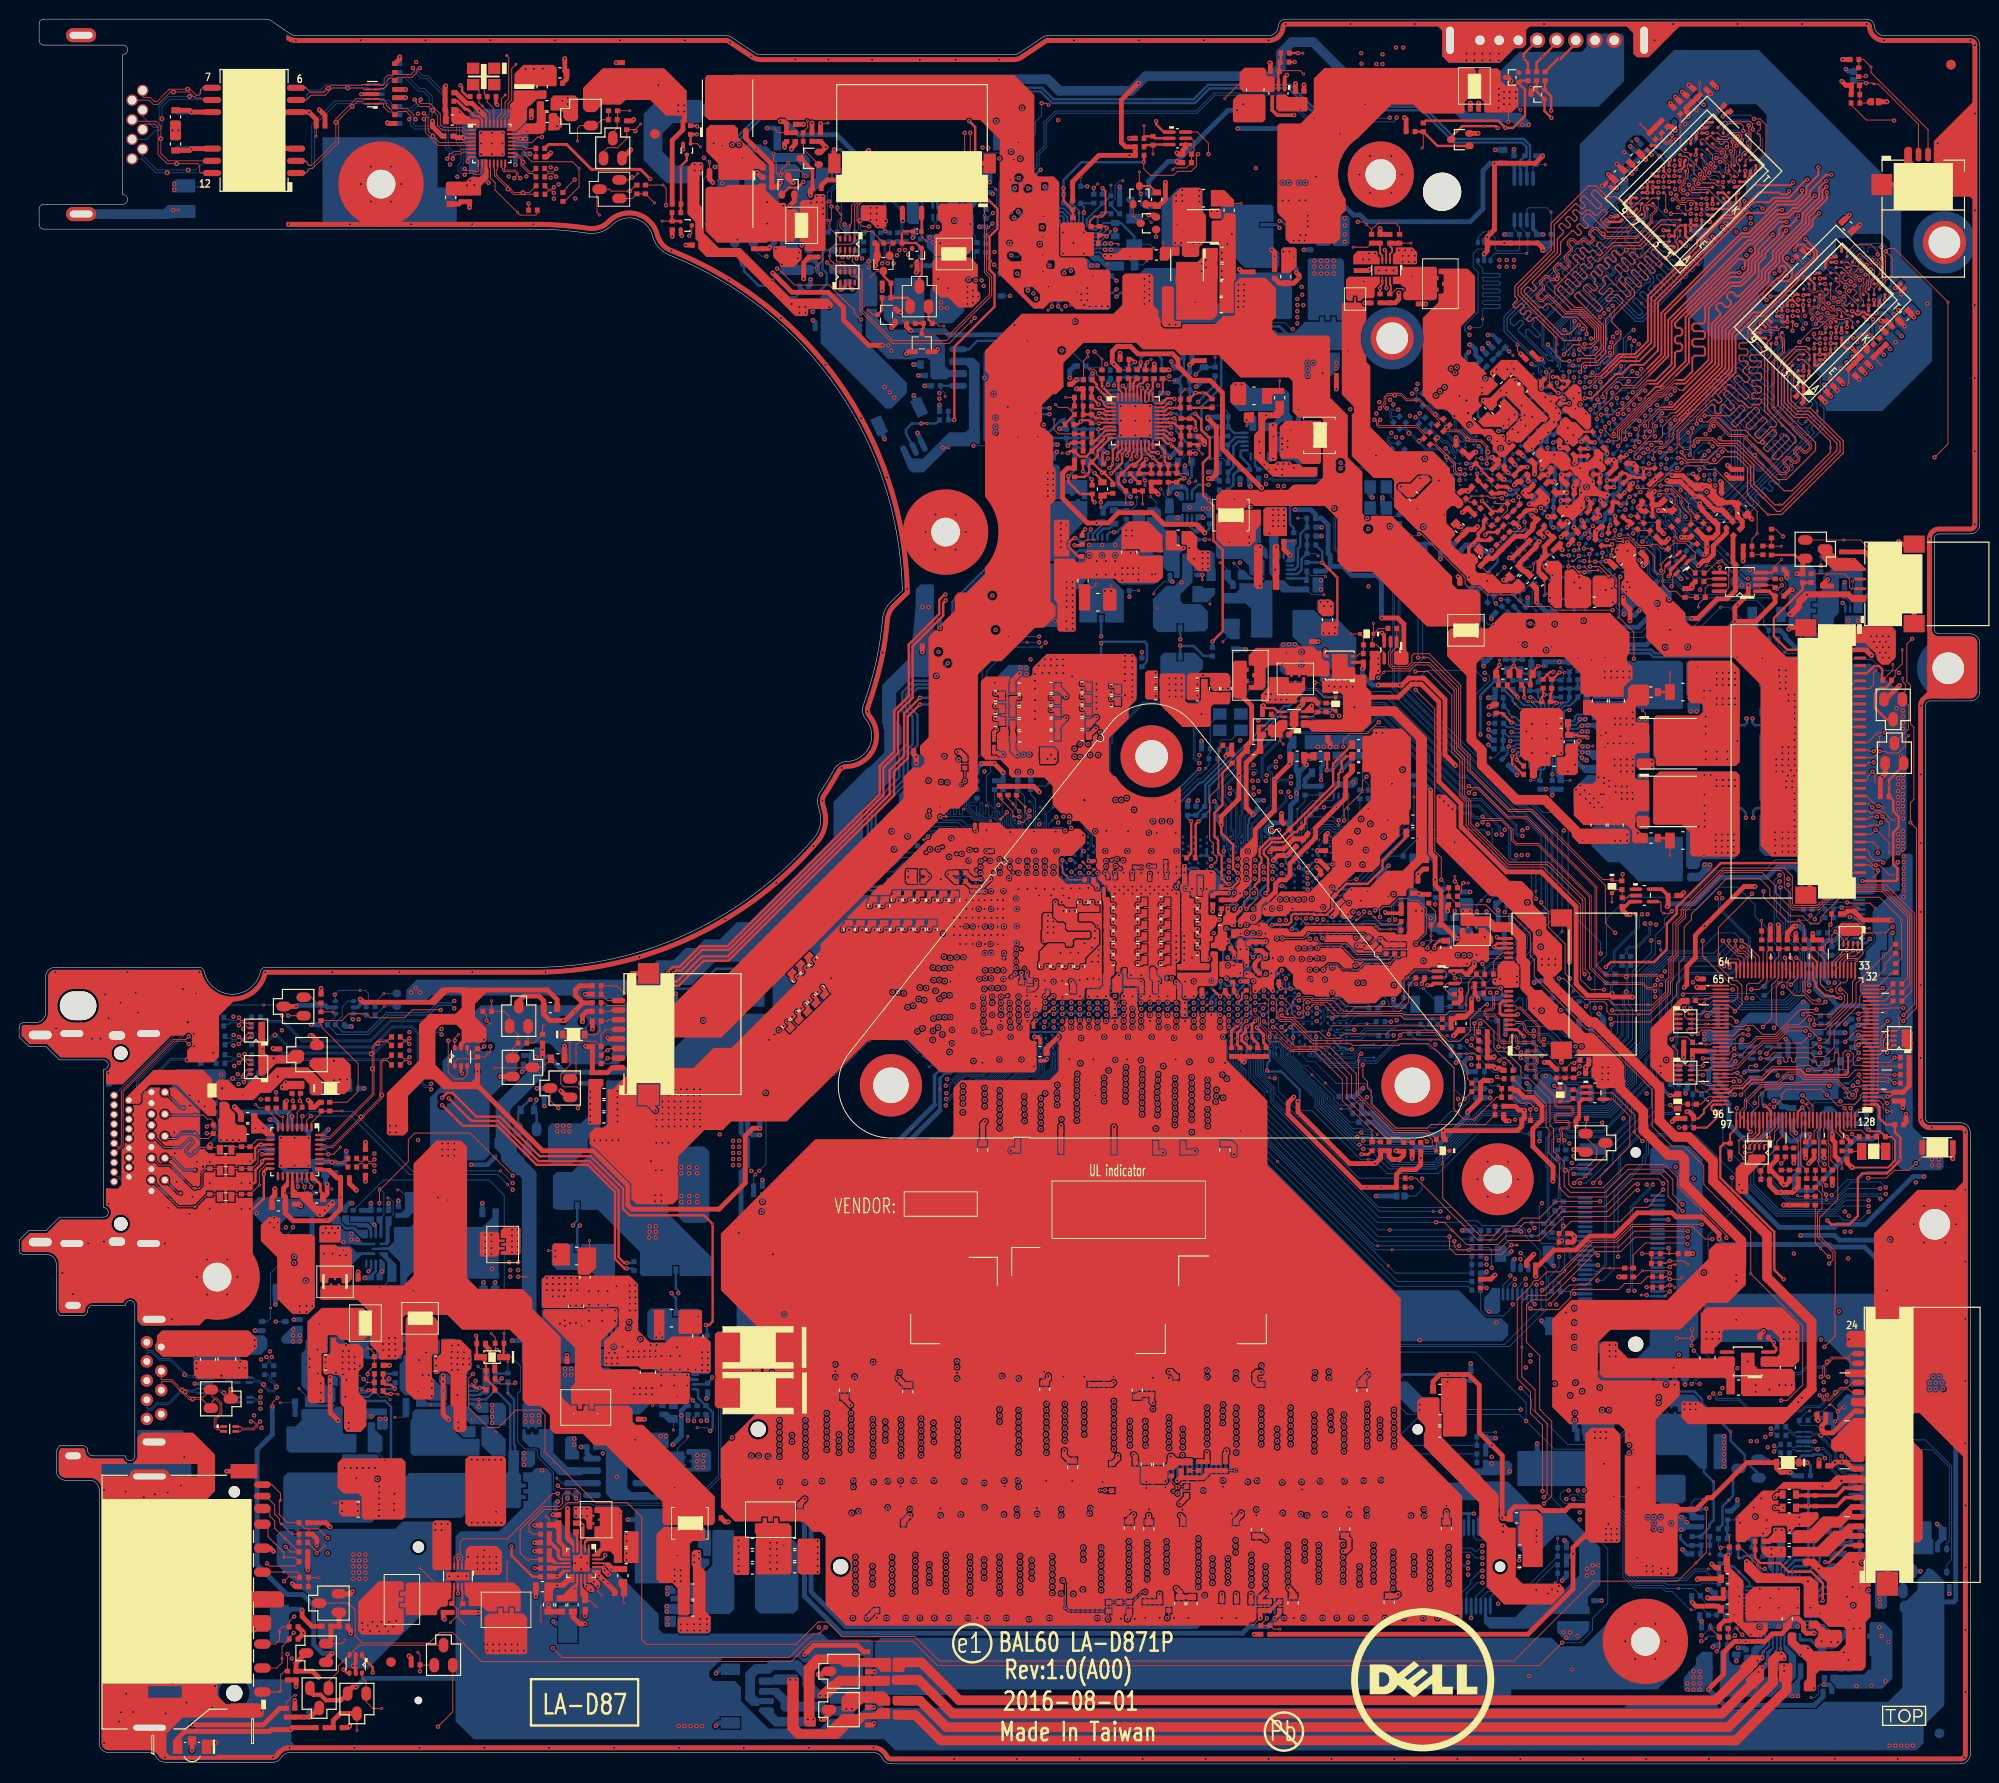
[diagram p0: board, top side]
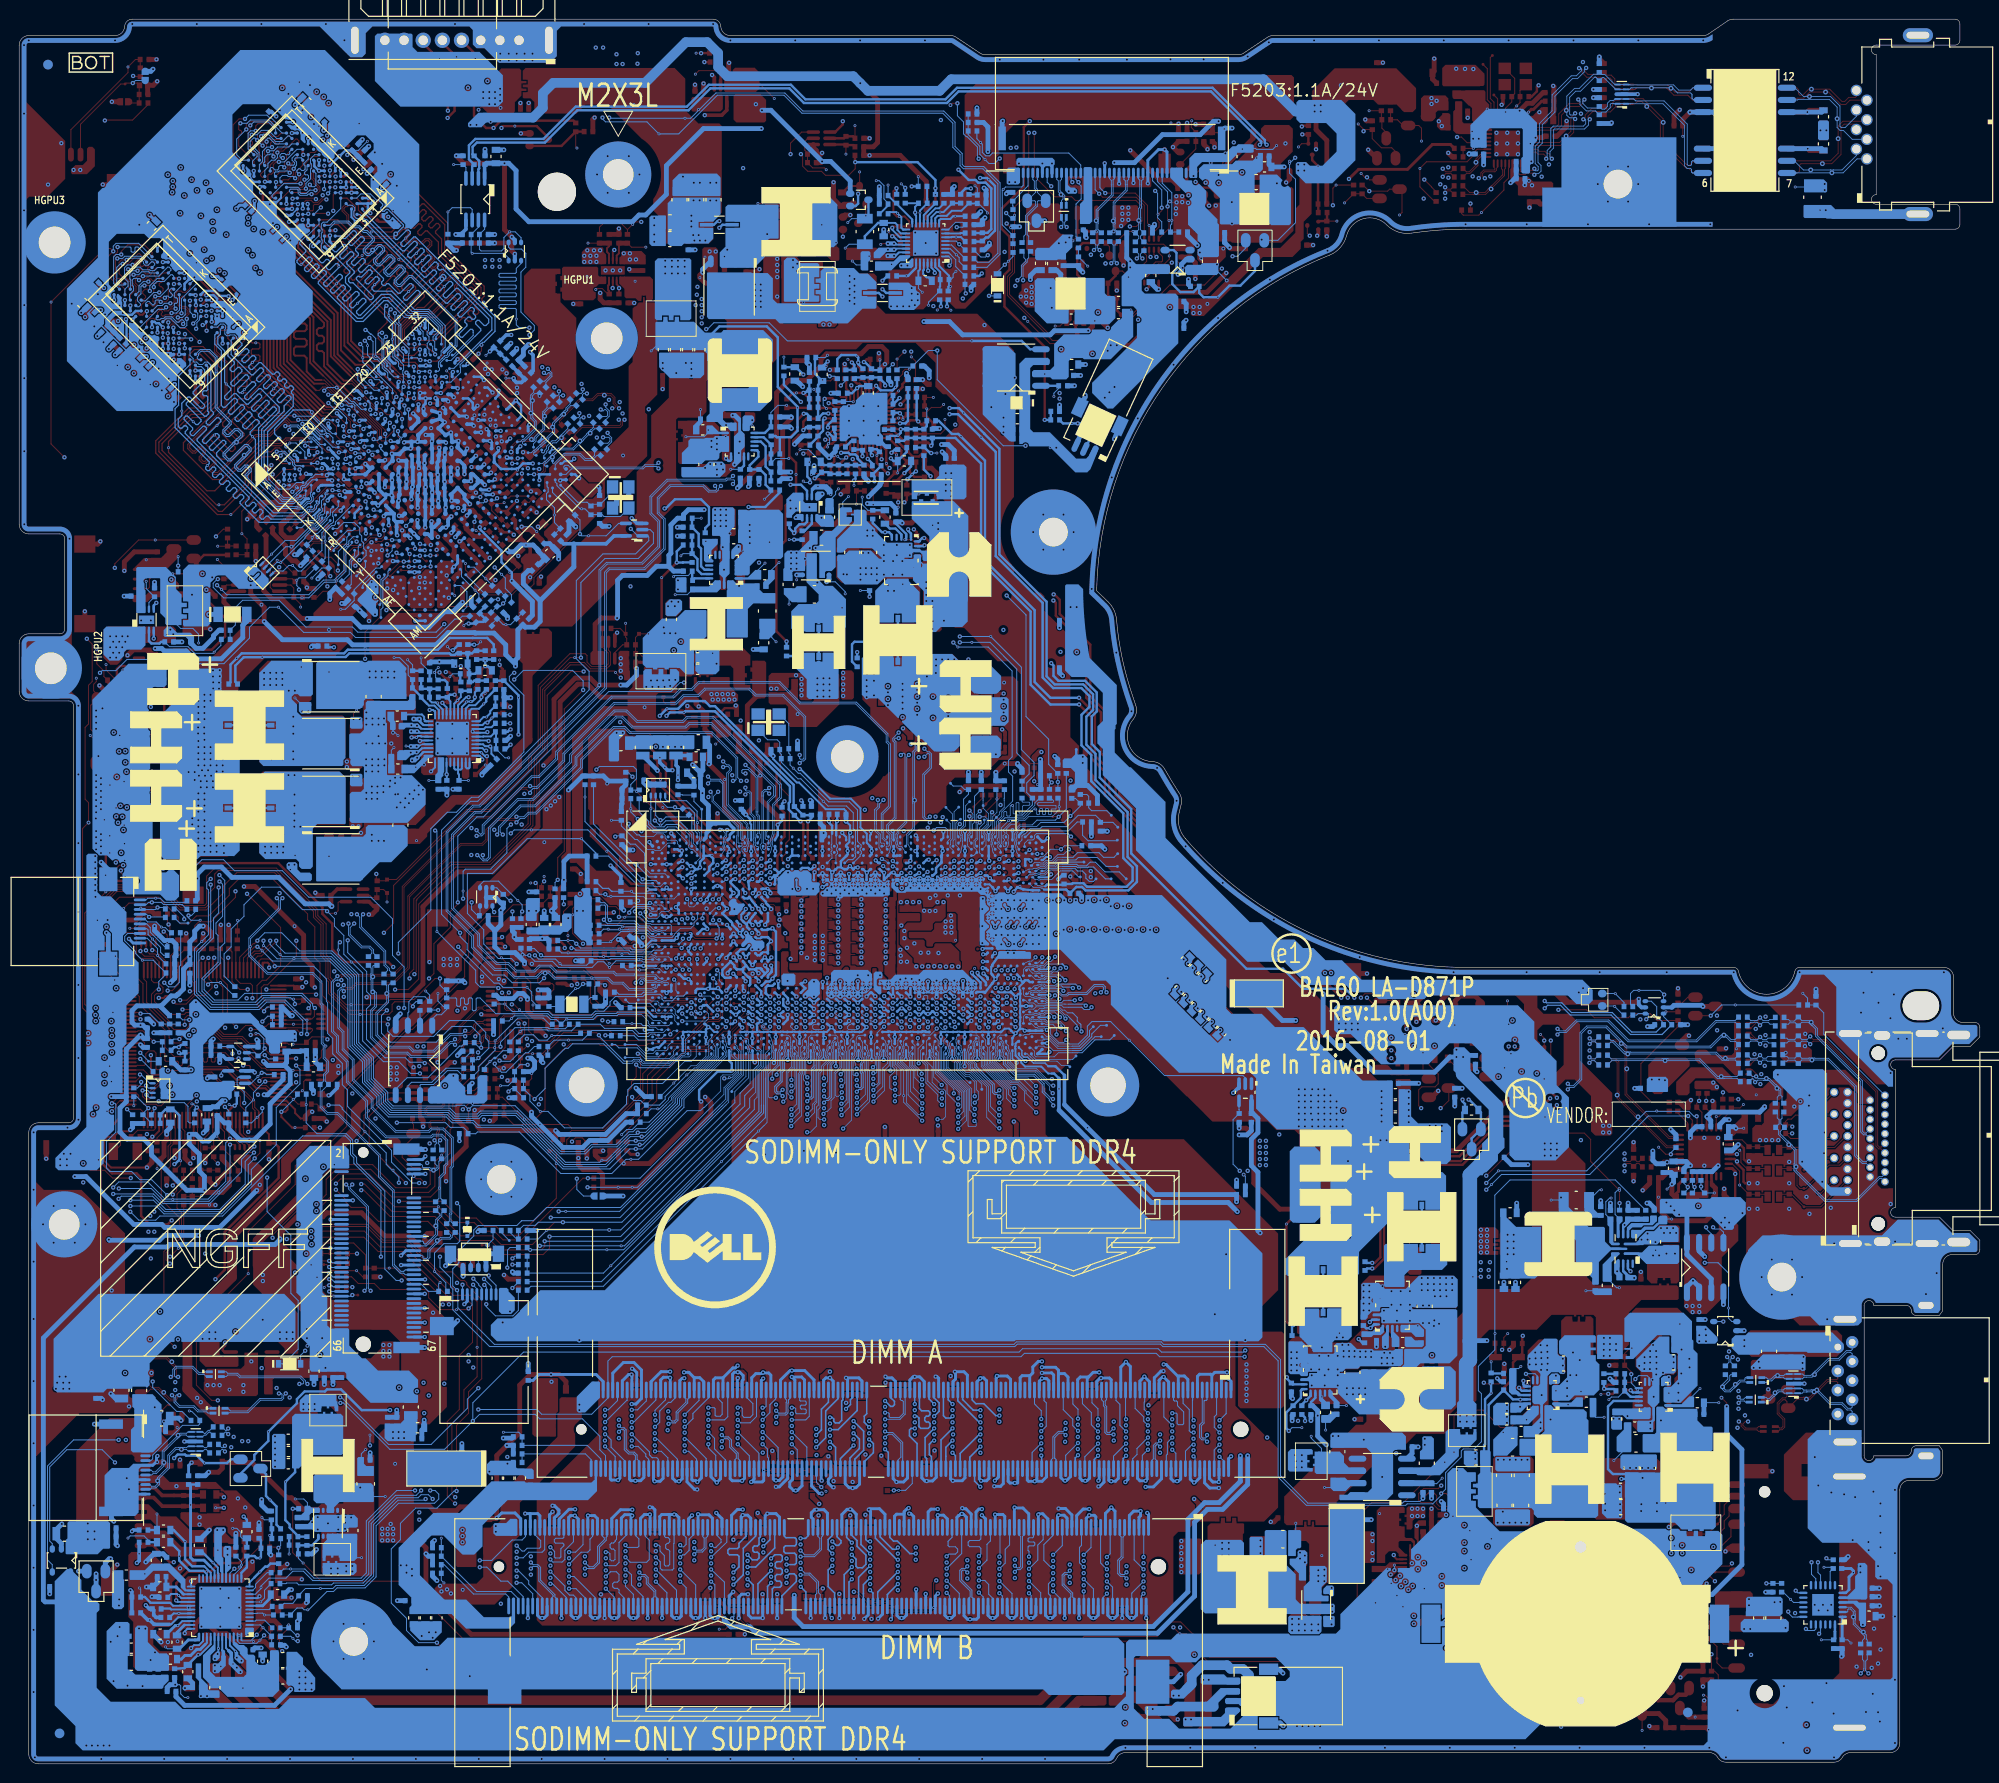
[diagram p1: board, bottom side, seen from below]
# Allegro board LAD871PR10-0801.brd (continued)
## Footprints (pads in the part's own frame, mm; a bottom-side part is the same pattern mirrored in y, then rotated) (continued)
SN74AHC1G08DCKR_SC70-5
  oval 0.381x1.295 smd: 1(0,0.15) 2(0.65,0.15) 3(1.3,0.15) 4(1.3,1.89) 5(0,1.89)
SN74LVC1G06DCKR_SC70-5
  oval 0.381x0.864 smd: 1(0,0) 2(0.65,0) 3(1.3,0) 4(1.3,1.74) 5(0,1.74)
SUYIN_200277GR008M270ZR_8P-T
  round 1.6 hole 0.991: 1(0,0) 2(2,0) 3(4,0) 4(6,0) 5(8,0) 6(10,0) 7(12,0) 8(14,0)
  oval 1.397x3.454 hole 0.787x2.845: 9(17.125,0) 10(-3.125,0)
SW_TST71-N-220-T170-S017_2P
  rect 0.61x1.499 smd: 1(0,0) 2(3.2,0)
SY6288D20AAC_SOT23-5
  oval 0.559x0.787 smd: 1(0,0) 2(0.95,0) 3(1.9,0) 4(1.9,2.4) 5(0,2.4)
SY8033BDBC_DFN10_3X3-S
  oval 0.305x0.559 smd: 1(0,0) 2(0.5,0) 3(1,0) 4(1.5,0) 5(2,0) 6(2,2.7) 7(1.5,2.7) 8(1,2.7) 9(0.5,2.7) 10(0,2.7)
  rect 2.591x1.753 smd: 11(1,1.35)
SY8286BRAC_QFN20_3X3-S
  oval 0.889x0.254 smd: 1(0,0) 2(0,-0.45) 3(0,-0.9) 4(0,-1.35) 5(0,-1.8) 11(3.1,-1.8) 12(3.1,-1.35) 13(3.1,-0.9) 14(3.1,-0.45) 15(3.1,0)
  oval 0.254x0.889 smd: 6(0.65,-2.45) 7(1.1,-2.45) 8(1.55,-2.45) 9(2,-2.45) 10(2.45,-2.45) 16(2.45,0.65) 17(2,0.65) 18(1.55,0.65) 19(1.1,0.65) 20(0.65,0.65)
  rect 0.991x0.991 smd: 21(1.55,-0.9)
SY8286CRAC_QFN20_3X3-S
  oval 0.889x0.254 smd: 1(0,0) 2(0,-0.45) 3(0,-0.9) 4(0,-1.35) 5(0,-1.8) 11(3.1,-1.8) 12(3.1,-1.35) 13(3.1,-0.9) 14(3.1,-0.45) 15(3.1,0)
  oval 0.254x0.889 smd: 6(0.65,-2.45) 7(1.1,-2.45) 8(1.55,-2.45) 9(2,-2.45) 10(2.45,-2.45) 16(2.45,0.65) 17(2,0.65) 18(1.55,0.65) 19(1.1,0.65) 20(0.65,0.65)
  rect 0.991x0.991 smd: 21(1.55,-0.9)
SY8286RAC_QFN20_3X3-S
  oval 0.889x0.254 smd: 1(0,0) 2(0,-0.45) 3(0,-0.9) 4(0,-1.35) 5(0,-1.8) 11(3.1,-1.8) 12(3.1,-1.35) 13(3.1,-0.9) 14(3.1,-0.45) 15(3.1,0)
  oval 0.254x0.889 smd: 6(0.65,-2.45) 7(1.1,-2.45) 8(1.55,-2.45) 9(2,-2.45) 10(2.45,-2.45) 16(2.45,0.65) 17(2,0.65) 18(1.55,0.65) 19(1.1,0.65) 20(0.65,0.65)
  rect 0.991x0.991 smd: 21(1.55,-0.9)
T-SOL_156-1001902605_11P
  round 1.194 hole 1.194 unplated: (-18.375,-2.925)
  round 1.702 hole 1.702 unplated: (2.625,-2.925)
  oval 0.991x1.753 smd: 1(0,0) 2(-2.5,0) 3(-5,0) 4(-7.5,0) 5(-10,0) 6(-12.5,0) 7(-15,0) 8(-16.63,0) 9(2.5,0)
  oval 0.711x1.753 smd: 10(-17.93,0) 11(-19.13,0)
  rect 1.499x2.794 smd: 12(-20.525,-1.925)
  oval 1.194x3.912 hole 0.61x3.404: 13(-19.975,-11.775) 14(6.225,-11.775)
  rect 1.473x2.794 smd: 15(4.425,-1.925)
TPC12
  round 0.305 smd: 1(0,0)
TPS2001C_MSOP8
  oval 0.381x1.575 smd: 1(0,0) 2(0.65,0) 3(1.3,0) 4(1.95,0) 5(1.95,4.33) 6(1.3,4.33) 7(0.65,4.33) 8(0,4.33)
  rect 1.803x1.397 smd: 9(0.975,2.165)
TPS22961DNYR_WSON8
  oval 0.305x0.508 smd: 1(0,0) 2(0.65,0) 3(1.3,0) 4(1.95,0) 5(1.95,2.7)
  oval 1.6x0.508 smd: 6(0.65,2.7)
  rect 2.388x1.6 smd: 7(0.975,1.35)
TPS22965DSGR_SON8_2X2
  oval 0.254x0.787 smd: 1(0,0) 2(0.5,0) 3(1,0) 4(1.5,0) 5(1.5,2.2) 6(1,2.2) 7(0.5,2.2) 8(0,2.2)
  rect 1.6x0.889 smd: 9(0.75,1.1)
TPS22966DPUR_SON14_2X3
  oval 0.203x0.762 smd: 1(0,0) 2(0.4,0) 3(0.8,0) 4(1.2,0) 5(1.6,0) 6(2,0) 7(2.4,0) 8(2.4,2.05) 9(2,2.05) 10(1.6,2.05) 11(1.2,2.05) 12(0.8,2.05) 13(0.4,2.05) 14(0,2.05)
  rect 2.489x0.889 smd: 15(1.2,1.025)
TVNST52302AB0_SOT523-3
  oval 0.508x0.559 smd: 1(0,0) 2(-0.5,-1.4) 3(0.5,-1.4)
TVWDF1004AD0_DFN9
  oval 0.203x0.686 smd: 1(0,0) 2(0.5,0) 4(1.5,0) 5(2,0) 6(2,0.875) 7(1.5,0.875) 8(0.5,0.875) 9(0,0.875)
  oval 0.406x1.549 smd: 3(1,0.437)
W25R128FVSIQ_SO8
  oval 0.635x1.676 smd: 1(0,0) 2(1.27,0) 3(2.54,0) 4(3.81,0) 5(3.81,7.25) 6(2.54,7.25) 7(1.27,7.25) 8(0,7.25)
Y_5YEA25000102IF50Q3_4P
  rect 1.295x1.194 smd: 1(0,0) 2(2.2,0) 3(2.2,1.7) 4(0,1.7)
Y_7V27000011_4P
  rect 1.397x1.194 smd: 1(0,0) 2(2.2,0) 3(2.2,1.7) 4(0,1.7)
Y_X1A000141000200_2P
  rect 0.991x1.803 smd: 1(0,0) 2(2.5,0)
Y_X3G024000DC1H_4P
  rect 1.397x1.194 smd: 1(0,0) 2(2.2,0) 3(2.2,1.7) 4(0,1.7)
ZEN_ZADH-252012MES-4R7M_2P
  rect 0.838x2.007 smd: 1(0,0) 2(1.65,0)

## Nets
0.6V_DDR_VTT_ON: PR202.1 RC124.2 UC14.4
1.2V_VTT_PWRGD: PR209.2 PU200.10 RC392.1
2.5V_VIN: PC802.1 PJP801.2 PU800.3
3V_FB: PC113.1 PR109.2 PR110.1 PU100.13
3V_SN: PC112.1 PR106.2
3V_VIN: PC100.1 PC103.1 PC104.1 PC105.1 PC130.1 PC131.1 PJP105.2 PL102.2 PU100.2 PU100.3 PU100.4 PU100.5
5V_FB: PC127.1 PR115.2 PR118.1 PU102.13
5V_HDD_S0: AFTP5601.1(TP-1) C5605.1 C5606.1 HDD1.1 HDD1.2 HDD1.3 R5601.2
5V_HDMI_CRT_S0_R: AFTP5504.1(TP-1) C5401.1 C5519.1 F5501.1 JCRT.9 JHDMI.18 RE45.2 RE46.2
5V_SN: PC125.1 PR112.2
5V_VIN: PC115.1 PC116.1 PC117.1 PC118.1 PC132.1 PC133.1 PJP106.2 PL103.2 PU102.2 PU102.3 PU102.4 PU102.5
+0.6V_DDR_VTT: CD12.1 CD13.1 CD14.1 CD15.1 CD32.1 CD88.1 CD89.1 CD90.1 JDIMM1.258 JDIMM2.258 PJP203.1
+0.6VSP: PC205.1 PC211.1 PJP203.2 PU200.2 PU200.20
+0.95VSDGPU: J11.2 LV8.1 RC364.1 RV1.2 RV3.2 RV30.2 RV31.1
+0.95VSDGPU_ON: C983.2 R6510.2 U15.3
+0.95VSDGPU_OUT: C6216.1 J11.1 U15.13 U15.14
+1.0V_AMPHYPLL: CC219.1 CC264.1 RC169.2 UC1.K15 UC1.L15
+1.0V_APLL: CC225.1 RC172.2 UC1.V15
+1.0V_APLLEBB: CC218.1 RC310.2 UC1.N18
+1.0V_CLK2: CC220.1 RC170.2 UC1.K19
+1.0V_CLK4: CC226.1 RC173.2 UC1.N20
+1.0V_CLK5: CC221.1 RC52.2 RC171.2 UC1.L19
+1.0V_MPHYGT: CC210.1 CC211.1 CC281.1 RC169.1 RC309.1 RC310.1 RC368.2 UC1.N15 UC1.N16 UC1.N17 UC1.P15 UC1.P16
+1.0V_PRIM: CC203.1 CC205.1 CC206.1 CC216.1 CC273.1 CC1801.1 CE77.1 CZ87.1 PJP302.2 RC170.1 RC171.1 RC172.1 RC173.1 RC352.1 RC368.1 U15.1 U15.2 UC1.A10 UC1.A14 UC1.AB17 UC1.AB19 UC1.AB20 UC1.AF18 UC1.AF19 UC1.AK20 UC1.K17 UC1.L1 UC1.L21 UC1.P18 UC1.T1 UC1.V20 UC1.V21 UC1.Y18 UE1.95 UZ19.1 UZ19.2 UZ19.7 UZ21.1 UZ21.2
+1.0V_SRAM: CC217.1 RC309.2 UC1.AF20 UC1.AF21 UC1.T19 UC1.T20
+1.0V_VCCST: CC195.1 CC202.1 PC602.1 PJP27.1 PR601.1 PR604.1 PR605.1 RC71.2 RC79.1 RC80.1 RC120.2 RC152.1 RC157.1 RC238.2 UC1.A18 UC1.K20 UC1.K21
+1.0V_VCCST_C: CZ78.1 PJP27.2 UZ21.7 UZ21.8
+1.0V_VCCSTG: CC199.1 PJP32.1 RC83.1 RC238.1 RC349.2 RC350.2 RC351.2 UC1.A22 UC1.G20
+1.0V_VCCSTG_C: CZ82.1 PJP15.1 PJP32.2 UZ19.6
+1.0V_XDP: RC115.2 RC352.2 RC353.1
+1.0VS_VCCIO: CC181.1 CC182.1 CC185.1 CC186.1 CC248.1 CC249.1 CC250.1 CC251.1 CC252.1 CC253.1 CZ1701.1 PJP15.2 RC2.1 UC1.AK28 UC1.AK30 UC1.AL30 UC1.AL42 UC1.AM28 UC1.AM30 UC1.AM42
+1.0VS_VCCOPC: CC180.1 CC183.1 CC184.1 CC187.1 CC288.1 CC289.1 CC290.1 CC291.1 CC292.1 PJP1202.2 UC1.AB62 UC1.AE62 UC1.AG62 UC1.P62 UC1.V62
+1.0VS_VCCOPCP: PC1206.1 PC1207.1 PC1208.1 PJP1202.1 PL1201.2 PU1200.12
+1.2V_DDR: CC58.1 CC174.1 CC175.1 CC176.1 CC177.1 CC178.1 CC179.1 CC194.1 CC255.1 CC256.1 CC257.1 CC293.1 CC294.1 CC295.1 CC296.1 CC297.1 CD1.1 CD2.1 CD5.1 CD6.1 CD7.1 CD8.1 CD11.1 CD19.1 CD20.1 CD21.1 CD22.1 CD23.1 CD24.1 CD25.1 CD26.1 CD33.1 CD70.1 CD71.1 CD72.1 CD73.1 CD74.1 CD75.1 CD76.1 CD77.1 CD78.1 CD79.1 CD80.1 CD81.1 CD82.1 CD83.1 CD84.1 CD85.1 CD86.1 CD87.1 JDIMM1.12 JDIMM1.33 JDIMM1.54 JDIMM1.75 JDIMM1.96 JDIMM1.111 JDIMM1.112 JDIMM1.117 JDIMM1.118 JDIMM1.123 JDIMM1.124 JDIMM1.129 JDIMM1.130 JDIMM1.135 JDIMM1.136 JDIMM1.141 JDIMM1.142 JDIMM1.147 JDIMM1.148 JDIMM1.153 JDIMM1.154 JDIMM1.159 JDIMM1.160 JDIMM1.163 JDIMM1.178 JDIMM1.199 JDIMM1.220 JDIMM1.241 JDIMM2.12 JDIMM2.33 JDIMM2.54 JDIMM2.75 JDIMM2.111 JDIMM2.112 JDIMM2.117 JDIMM2.118 JDIMM2.123 JDIMM2.124 JDIMM2.129 JDIMM2.130 JDIMM2.135 JDIMM2.136 JDIMM2.141 JDIMM2.142 JDIMM2.147 JDIMM2.148 JDIMM2.153 JDIMM2.154 JDIMM2.159 JDIMM2.160 JDIMM2.163 JDIMM2.178 JDIMM2.199 JDIMM2.220 JDIMM2.241 PJP200.2 RD7.2 RD8.2 RD35.1 RH206.1 RH207.1 UC1.AL23 UC1.AM40 UC1.AU23 UC1.AU28 UC1.AU35 UC1.AU42 UC1.BB23 UC1.BB32 UC1.BB41 UC1.BB47 UC1.BB51 UC14.5
+1.2VP: PC213.1 PC214.2 PC215.1 PC216.1 PC217.1 PC218.1 PC219.1 PC220.1 PJP200.1 PL200.1 PR207.2 PU200.5 PU200.19
+1.5V_MEM_GFX: CV16.1 CV40.1 CV41.1 CV42.1 CV43.1 CV44.1 CV45.1 CV47.1 CV48.1 CV49.1 CV50.1 CV51.1 CV52.1 CV53.1 CV131.1 CV133.1 CV143.1 CV151.1 CV170.1 CV171.1 CV174.1 CV175.1 CV176.1 CV177.1 CV178.1 CV182.1 CV183.1 CV184.1 CV185.1 CV186.1 CV187.1 CV188.1 CV196.1 CV198.1 CV208.1 CV210.1 CV211.1 CV212.1 CV394.1 CV395.1 CV396.1 CV397.1 CV398.1 CV400.1 CV401.1 CV402.1 PJP1402.2 RV32.1 RV33.1 RV139.1 RV144.1 RV149.1 RV150.1 UV1.H13 UV1.H16 UV1.H19 UV1.J9 UV1.J10 UV1.J23 UV1.J24 UV1.K9 UV1.K10 UV1.K23 UV1.K24 UV1.L11 UV1.L12 UV1.L13 UV1.L20 UV1.L21 UV1.L22 UV17.A1 UV17.A8 UV17.B2 UV17.C1 UV17.C9 UV17.D2 UV17.D9 UV17.E9 UV17.F1 UV17.G7 UV17.H2 UV17.H9 UV17.K2 UV17.K8 UV17.N1 UV17.N9 UV17.R1 UV17.R9 UV18.A1 UV18.A8 UV18.B2 UV18.C1 UV18.C9 UV18.D2 UV18.D9 UV18.E9 UV18.F1 UV18.G7 UV18.H2 UV18.H9 UV18.K2 UV18.K8 UV18.N1 UV18.N9 UV18.R1 UV18.R9 UV19.A1 UV19.A8 UV19.B2 UV19.C1 UV19.C9 UV19.D2 UV19.D9 UV19.E9 UV19.F1 UV19.G7 UV19.H2 UV19.H9 UV19.K2 UV19.K8 UV19.N1 UV19.N9 UV19.R1 UV19.R9 UV20.A1 UV20.A8 UV20.B2 UV20.C1 UV20.C9 UV20.D2 UV20.D9 UV20.E9 UV20.F1 UV20.G7 UV20.H2 UV20.H9 UV20.K2 UV20.K8 UV20.N1 UV20.N9 UV20.R1 UV20.R9
+1.5VGPUP: PC1409.1 PC1411.1 PC1412.1 PC1413.1 PC1414.1 PJP1402.1 PL1401.2 PR1410.2
+1.8V_AVDD: C2715.1 HDA27.40 R6511.2
+1.8V_PRIM: C24.2 CC212.1 CC272.1 PJP502.2 Q6205.1 RC361.1 U15.6 U15.7 UC1.AA1 UC1.AF16 UC1.G61 UC1.H63
+1.8VALWP: PC503.1 PC505.1 PC506.1 PC507.1 PJP502.1 PL501.2 PR503.2
+1.8VGS: CV38.1 CV39.1 CV46.1 CV179.1 J10.2 LV2.1 LV3.1 LV6.1 LV7.1 PR1113.1 RV8.1 RV11.1 RV15.1 RV27.2 RV28.1 RV71.1 RV81.2 RV82.2 RV152.2 UV1.AM30
+1.8VGS_GPU_ON: C987.2 R437.2 U15.5
+1.8VGS_OUT: C26.2 J10.1 U15.8 U15.9
+1VALWP: PC309.1 PC310.1 PC311.1 PC312.1 PC313.1 PJP302.1 PL301.2 PR309.2
+2.5V_MEM: CD3.1 CD4.1 CD9.1 CD10.1 CD27.1 CD28.1 CD30.1 CD31.1 JDIMM1.257 JDIMM1.259 JDIMM2.257 JDIMM2.259 PJP802.2
+2.5VP: PC803.1 PC804.1 PJP802.1 PR801.1 PU800.6
+3.3V_ALW_DSW: CC279.1 CC280.1 RC70.1 RC72.2 RC214.2 RC243.2 RC1102.1 UC1.AD17 UC1.AD18 UC1.AJ17
+3.3V_HDA: CC215.1 RC396.2 UC1.AJ19
+3.3V_LAN_UZ2: CZ50.1 PJP13.1 UZ2.8 UZ2.9
+3.3V_SPI: CC9.1 RC9.1 RC30.1 RC31.1 RC213.2 RC339.1 UC1.AJ16 UC5.8
+3.3V_WLAN: C5803.1 C5804.1 C5806.1 R5809.2 R5810.2 WLAN1.2 WLAN1.4 WLAN1.64 WLAN1.66
+3V_1.8V_CPVDD: C6213.1 C6215.1 HDA27.36 R2705.2
+3V_DVDD: C2701.1 C2716.1 C2717.1 C2719.1 C6214.1 HDA27.1 HDA27.9 R2701.2 R2722.1 R6512.1
+3VALW: C3013.1 C3015.1 CC271.1 CC298.1 CC299.1 CZ34.1 D2502.2 EC9759.1 EC9760.1 PC1205.1 PC1422.1 PJP23.1 PJP102.2 PJP501.1 PJP801.1 PR3.2 PR16.2 PR28.1 PR209.1 PR303.1 PR304.1 PR756.2 PR791.1 PR1405.1 PR1406.1 PU1200.10 PWR1.1 Q3004.3 QC4.2 QC4.5 R2608.1 R2713.2 R3021.1 R5810.1 R6215.1 RC68.2 RC73.2 RC214.1 RE25.1 RE71.1 RE72.1 RE73.1 RE74.1 RE75.1 RE343.2 RE385.2 RE388.2 RE389.2 RE396.1 RE404.1 RE408.2 RE409.2 RPE2.5 RPE2.6 RPE2.7 RPE2.8 RPE3.5 RPE3.6 RPE3.7 RPE3.8 RPE4.1 RPE4.2 RPE4.3 RPE4.4 RPE5.1 RPE5.2 RPE5.3 RPE5.4 RPE6.1 RPE6.2 RPE6.3 RPE6.4 RPE7.1 RPE7.2 RPE7.3 RPE7.4 UC15.5 UC16.5 UC17.5 UZ2.6 UZ2.7 UZ6.5
+3VALW_EC: CE62.1 CE63.2 CE64.2 CE65.1 CE66.1 CE67.1 CE68.1 CE69.1 CE79.1 CE81.1 CE89.1 R2446.1 RE343.1 RE345.1 RE348.2 RE354.1 RE424.2 RE425.2 RE426.2 RE427.2 RE440.2 UE1.5 UE1.19 UE1.22 UE1.43 UE1.65 UE1.82 UE1.103 UE1.115
+3VALW_PCH: CC207.1 CC208.1 CC209.1 CC223.1 CC224.1 CC265.1 PJP23.2 RC12.2 RC14.2 RC15.2 RC17.2 RC19.2 RC20.2 RC23.2 RC25.2 RC74.1 RC183.1 RC186.1 RC187.1 RC213.1 RC239.1 RC246.2 RC288.2 RC365.2 RC369.2 RC384.2 RC387.2 RC396.1 RPC3.5 RPC3.6 RPC3.7 RPC3.8 UC1.AD15 UC1.AG15 UC1.AJ21 UC1.AK15 UC1.AK17 UC1.T16 UC1.V19 UC1.Y15 UC1.Y16
+3VALWP: PC106.1 PC107.1 PC108.1 PC109.1 PC110.1 PJP102.1 PL100.2 PR107.1 PR108.2 PR109.1 PR113.1 PU100.14
+3VGS: CV10.1 J12.2 LV4.1 PR1115.1 QV1.2 QV1.5 RP34.1 RP34.3 RP34.4 RV5.1 RV6.1 RV58.2 RV72.2 RV91.2 RV146.1 RV154.1 RV162.1 RV260.2 UV2.5 UV11.1
+3VGS_GPU_ON: C6211.2 RZ79.2 U5602.3
+3VGS_OUT: C6217.1 J12.1 U5602.7 U5602.8
+3VLP: D2501.2 PC111.1 PU100.16 PU100.17 R2609.1 RE356.2
+3VS: C2601.1 C2602.1 C3203.1 C3205.1 C5204.1 C5520.1 C5522.1 C5801.1 C5802.1 C5805.1 CD16.1 CD17.1 CD34.1 CD35.1 CE85.1 DB1.9 DB1.10 EC9735.1 EC9736.1 JDIMM1.255 JDIMM2.255 PC1422.2 PC1423.1 PC1424.1 PJP13.2 PR612.1 PR1112.1 PR1119.1 PR1206.1 PR1401.1 Q2601.2 Q2601.5 Q5401.1 Q5402.2 Q5402.5 Q6205.2 Q6206.2 Q6501.2 Q6501.5 QC2.2 QC2.5 R2603.1 R2604.1 R2701.1 R5208.1 R5219.2 R5229.1 R5231.1 R5502.2 R5503.1 R5504.1 R5509.2 R5515.2 R5607.1 R5809.1 R6110.1 R6202.1 R6212.1 R6507.1 R6518.1 RC13.1 RC21.1 RC27.2 RC47.1 RC50.1 RC62.2 RC63.2 RC124.1 RC175.2 RC178.2 RC181.1 RC189.1 RC237.2 RC245.1 RC248.2 RC267.1 RC272.1 RC277.1 RC291.1 RC292.1 RC293.1 RC356.1 RC359.1 RC360.1 RC374.1 RC376.1 RC378.1 RC379.1 RC382.2 RC388.2 RD1.1 RD2.1 RD3.1 RD4.1 RD5.1 RD6.1 RE32.1 RE432.1 RE439.2 RE441.2 RN19.1 RN20.1 RZ20.1 RZ21.1 THM26.1 U3201.4 U5201.5 U5502.5 U5502.20 U5504.3 U5504.8 U5602.1 U5602.2 UC7.5 UE6.5
+5V_AVDD: C2710.1 C2711.1 HDA27.26 R2703.1
+5V_KB_BL: C6202.1 EC6208.1 F6201.1 KB_BL1.1
+5V_PVDD: C2706.1 C2707.1 C2708.1 C2709.1 HDA27.41 HDA27.46 R2702.2 R2704.2
+5V_RUN_UZ2: CZ44.1 PJP21.2 UZ2.13 UZ2.14
+5VALW: C3504.1 C3510.1 CZ86.1 EC9732.1 EC9733.1 JWDB1.4 PC661.1 PC669.1 PC677.1 PC685.1 PC801.1 PC1111.1 PD5.3 PD6.3 PJP103.2 PR8.1 PR206.1 PR210.2 PR602.2 PR615.1 PR634.1 PR1114.2 PU603.2 PU604.2 PU605.2 PU606.6 PU800.4 PU1100.26 PU1100.31 Q6101.3 Q6102.3 U15.4 U3504.5 U3505.5 U5602.4 UZ2.1 UZ2.2 UZ2.4 UZ19.3 UZ21.4
+5VALWP: PC120.1 PC121.1 PC122.1 PC123.1 PC124.1 PJP103.1 PL101.2 PR115.1 PR117.2 PU102.14
+5VS: C2605.1 C2611.1 C5601.1 C5604.1 C5609.1 D5401.1 D5501.2 EC9719.1 EC9720.1 F6201.2 FAN261.2 PJP21.1 Q5403.2 Q6201.3 R2702.1 R2703.2 R2704.1 R5230.1 R5413.1 R5601.1 R5603.1 U5601.2 U5601.3
+17.4V_BATT+: PC7.1 PC761.1 PC766.1 PC775.1 PC776.1 PC777.1 PC778.1 PJP3.2 PL3.1 PQ710.3 PR745.2 PR765.4 PR780.2
+17.4V_BATT++: PBATT1.7 PBATT1.8 PC8.1 PJP3.1 PL3.2
+19V_ADPIN: PC1.1 PC2.1 PJP1.2 PJPDC1.5 PJPDC1.6 PL1.1
+19V_VIN: PC3.1 PC4.1 PC742.2 PD704.2 PJP1.1 PL1.2 PQ740.5 PR5.1 PR7.2 PR31.2 PR729.1
+19VB: EC9701.1 EC9702.1 EC9703.1 EC9705.1 EC9706.1 EC9708.1 EC9709.1 EC9710.1 EC9712.1 EC9713.1 EC9714.1 EC9715.1 EC9716.1 EC9717.1 F5201.1 PJP105.1 PJP106.1 PJP206.2 PJP301.1 PJP601.2 PJP602.2 PJP701.1 PJP1101.1 PJP1201.1 PJP1401.1 PL102.1 PL103.1 PL201.1 PL302.1 PL602.2 PL606.2 PL704.1 PL1101.2 PL1202.1 PL1402.1 PQ717.5 PR102.2 PR703.4 R5214.1
+19VB_1.2V: PC201.1 PC206.1 PC208.1 PC212.1 PC230.1 PC231.1 PJP206.1 PL201.2 PQ201.2 PQ201.3 PQ201.4 PQ201.10 PR208.1
+19VB_+1.5VGPU: PC1401.1 PC1402.1 PC1403.1 PC1420.1 PC1421.1 PJP1401.2 PL1402.2 PU1400.2 PU1400.3 PU1400.4 PU1400.5
+19VB_+1VALW: PC301.1 PC302.1 PC303.1 PC320.1 PC321.1 PJP301.2 PL302.2 PU300.2 PU300.3 PU300.4 PU300.5
+19VB_GPU: PC1103.1 PC1104.1 PC1105.1 PC1106.1 PC1107.1 PC1112.1 PC1113.1 PC1114.1 PC1115.1 PC1116.1 PC1190.1 PC1191.1 PC1192.1 PC1193.1 PJP1101.2 PL1101.1 PQ1101.5 PQ1104.5
+VCC_CORE: PC1001.1 PC1002.1 PC1003.1 PC1004.1 PC1005.1 PC1006.1 PC1007.1 PC1008.1 PC1009.1 PC1010.1 PC1011.1 PC1012.1 PC1013.1 PC1030.1 PC1031.1 PC1032.1 PC1033.1 PC1034.1 PC1035.1 PC1036.1 PC1037.1 PC1038.1 PC1039.1 PC1050.1 PC1051.1 PC1052.1 PC1053.1 PC1054.1 PC1061.1 PC1062.1 PC1064.1 PC1065.1 PC1066.1 PC1067.1 PC1068.1 PC1069.1 PC1070.1 PC1071.1 PC1072.1 PC1073.1 PC1074.1 PC1075.1 PC1076.1 PC1077.1 PC1078.1 PC1079.1 PC1080.1 PC1081.1 PC1082.1 PC1083.1 PC1084.1 PC1085.1 PC1086.1 PC1087.1 PC1088.1 PC1089.1 PC1090.1 PC1091.1 PC1092.1 PC1093.1 PC1094.1 PC1095.1 PC1096.1 PC1097.1 PC1098.1 PC1099.1 PC1125.1 PC1126.1 PC1127.1 PC1164.1 PC1170.1 PC1171.1 PC1172.1 PC1173.1 PC1174.1 PL603.1 RC140.1 UC1.A30 UC1.A34 UC1.A39 UC1.A44 UC1.AK33 UC1.AK35 UC1.AK37 UC1.AK38 UC1.AK40 UC1.AL33 UC1.AL37 UC1.AL40 UC1.AM32 UC1.AM33 UC1.AM35 UC1.AM37 UC1.AM38 UC1.G30 UC1.G32 UC1.G33 UC1.G35 UC1.G37 UC1.G38 UC1.G40 UC1.G42 UC1.J30 UC1.J33 UC1.J37 UC1.J40 UC1.K33 UC1.K35 UC1.K37 UC1.K38 UC1.K40 UC1.K42 UC1.K43
+VCC_CORE_G0: T122.1(TP-1) UC1.K32
+VCC_CORE_G1: T123.1(TP-1) UC1.AK32
+VCC_GT: PC1014.1 PC1015.1 PC1016.1 PC1017.1 PC1018.1 PC1019.1 PC1020.1 PC1021.1 PC1022.1 PC1023.1 PC1024.1 PC1025.1 PC1026.1 PC1027.1 PC1028.1 PC1029.1 PC1040.1 PC1041.1 PC1042.1 PC1043.1 PC1044.1 PC1045.1 PC1046.1 PC1047.1 PC1048.1 PC1049.1 PC1055.1 PC1056.1 PC1063.1 PC1101.1 PC1128.1 PC1129.1 PC1130.1 PC1131.1 PC1132.1 PC1133.1 PC1134.1 PC1135.1 PC1136.1 PC1137.1 PC1138.1 PC1154.1 PC1155.1 PC1156.1 PC1158.1 PC1159.1 PC1161.1 PC1162.1 PC1163.1 PC1175.1 PC1176.1 PC1177.1 PC1178.1 PC1179.1 PC1180.1 PC1181.1 PC1182.1 PC1183.1 PC1184.1 PC1221.1 PC1222.1 PC1223.1 PC1224.1 PC1423.2 PL604.1 PL605.1 RC161.1 RC340.1 UC1.A48 UC1.A53 UC1.A58 UC1.A62 UC1.A66 UC1.AA63 UC1.AA64 UC1.AA66 UC1.AA67 UC1.AA69 UC1.AA70 UC1.AA71 UC1.AC64 UC1.AC65 UC1.AC66 UC1.AC67 UC1.AC68 UC1.AC69 UC1.AC70 UC1.AC71 UC1.AK42 UC1.AK43 UC1.AK45 UC1.AK46 UC1.AK48 UC1.AK50 UC1.AK52 UC1.AK53 UC1.AK55 UC1.AK56 UC1.AK58 UC1.AK60 UC1.AK70 UC1.AL43 UC1.AL46 UC1.AL50 UC1.AL53 UC1.AL56 UC1.AL60 UC1.AM48 UC1.AM50 UC1.AM52 UC1.AM53 UC1.AM56 UC1.AM58 UC1.AU58 UC1.AU63 UC1.BB57 UC1.BB66 UC1.J43 UC1.J45 UC1.J46 UC1.J48 UC1.J50 UC1.J52 UC1.J53 UC1.J55 UC1.J56 UC1.J58 UC1.J60 UC1.K48 UC1.K50 UC1.K52 UC1.K53 UC1.K55 UC1.K56 UC1.K58 UC1.K60 UC1.L62 UC1.L63 UC1.L64 UC1.L65 UC1.L66 UC1.L67 UC1.L68 UC1.L69 UC1.L70 UC1.L71 UC1.M62 UC1.N63 UC1.N64 UC1.N66 UC1.N67 UC1.N69 UC1.N70 UC1.N71 UC1.R63 UC1.R64 UC1.R65 UC1.R66 UC1.R67 UC1.R68 UC1.R69 UC1.R70 UC1.R71 UC1.T62 UC1.U65 UC1.U68 UC1.U71 UC1.W63 UC1.W64 UC1.W65 UC1.W66 UC1.W67 UC1.W68 UC1.W69 UC1.W70 UC1.W71 UC1.Y62
+VCC_SA: PC1057.1 PC1058.1 PC1059.1 PC1060.1 PC1139.1 PC1140.1 PC1141.1 PC1142.1 PC1143.1 PC1144.1 PC1145.1 PC1146.1 PC1147.1 PC1148.1 PC1149.1 PC1150.1 PC1151.1 PC1152.1 PC1153.1 PL601.1 RC168.1 UC1.AK23 UC1.AK25 UC1.G23 UC1.G25 UC1.G27 UC1.G28 UC1.J22 UC1.J23 UC1.J27 UC1.K23 UC1.K25 UC1.K27 UC1.K28 UC1.K30
+VDD_CT: CV61.1 CV62.1 CV63.1 LV3.2 UV1.AA20 UV1.AA21 UV1.AB20 UV1.AB21
+VDDR3: CV64.1 CV65.1 CV66.1 CV123.1 LV4.2 UV1.AA17 UV1.AA18 UV1.AB17 UV1.AB18
AVCC33: C5517.1 C5523.2 R5504.2 U5502.24
GND: AFTP6235.1(TP-1) C24.1 C26.1 C343.1 C349.1 C983.1 C987.1 C2503.2 C2601.2 C2602.2 C2603.2 C2604.2 C2605.2 C2608.2 C2609.2 C2611.2 C2701.2 C2704.1 C2706.2 C2707.2 C2708.2 C2709.2 C2716.2 C2717.2 C2718.2 C2719.2 C2723.1 C3001.2 C3002.2 C3003.2 C3004.2 C3005.2 C3007.2 C3008.2 C3009.2 C3010.2 C3011.2 C3012.2 C3013.2 C3017.2 C3018.2 C3019.2 C3021.2 C3022.2 C3023.2 C3024.2 C3025.2 C3106.2 C3201.1 C3202.2 C3203.2 C3204.2 C3205.2 C3206.2 C3301.2 C3302.2 C3303.2 C3504.2 C3507.2 C3508.2 C3510.2 C3512.2 C3513.2 C3515.2 C3517.2 C3518.2 C5201.2 C5202.2 C5204.2 C5205.1 C5206.1 C5207.2 C5208.2 C5214.2 C5224.2 C5225.2 C5226.2 C5401.2 C5501.2 C5502.2 C5503.2 C5504.2 C5506.2 C5507.2 C5509.2 C5510.2 C5511.2 C5512.2 C5513.2 C5514.2 C5516.2 C5517.2 C5518.2 C5519.2 C5520.2 C5521.1 C5522.2 C5523.1 C5524.2 C5601.2 C5604.2 C5605.2 C5606.2 C5609.2 C5610.2 C5801.2 C5802.2 C5803.2 C5804.2 C5805.2 C5806.2 C6201.2 C6202.2 C6209.1 C6211.1 C6213.2 C6214.2 C6215.2 C6216.2 C6217.2 CARD1.3 CARD1.6 CARD1.12 CARD1.13 CARD1.14 CARD1.15 CC4.1 CC5.1 CC8.1 CC9.2 CC10.2 CC21.2 CC22.2 CC23.2 CC24.2 CC25.2 CC26.2 CC27.2 CC58.2 CC174.2 CC175.2 CC176.2 CC177.2 CC178.2 CC179.2 CC180.2 CC181.2 CC182.2 CC183.2 CC184.2 CC185.2 CC186.2 CC187.2 CC194.2 CC195.2 CC199.2 CC202.2 CC203.2 CC204.2 CC205.2 CC206.2 CC207.2 CC208.2 CC209.2 CC210.2 CC211.2 CC212.2 CC213.2 CC214.2 CC215.2 CC216.2 CC217.2 CC218.2 CC219.2 CC220.2 CC221.2 CC223.2 CC224.2 CC225.2 CC226.2 CC248.2 CC249.2 CC250.2 CC251.2 CC252.2 CC253.2 CC255.2 CC256.2 CC257.2 CC264.2 CC265.2 CC266.2 CC270.2 CC271.2 CC272.2 CC273.2 CC279.2 CC280.2 CC281.2 CC288.2 CC289.2 CC290.2 CC291.2 CC292.2 CC293.2 CC294.2 CC295.2 CC296.2 CC297.2 CC298.2 CC299.2 CC1101.2 CC1103.2 CC1801.2 CD1.2 CD2.2 CD3.2 CD4.2 CD5.2 CD6.2 CD7.2 CD8.2 CD9.2 CD10.2 CD11.2 CD12.2 CD13.2 CD14.2 CD15.2 CD16.2 CD17.2 CD18.2 CD19.2 CD20.2 CD21.2 CD22.2 CD23.2 CD24.2 CD25.2 CD26.2 CD27.2 CD28.2 CD29.2 CD30.2 CD31.2 CD32.2 CD33.2 CD34.2 CD35.2 CD69.2 CD70.2 CD71.2 CD72.2 CD73.2 CD74.2 CD75.2 CD76.2 CD77.2 CD78.2 CD79.2 CD80.2 CD81.2 CD82.2 CD83.2 CD84.2 CD85.2 CD86.2 CD87.2 CD88.2 CD89.2 CD90.2 CE8.2 CE12.2 CE62.2 CE63.1 CE64.1 CE65.2 CE66.2 CE67.2 CE68.2 CE69.2 CE71.2 CE72.2 CE73.2 CE74.2 CE75.2 CE76.2 CE77.2 CE78.2 CE79.2 CE82.2 CE84.1 CE85.2 CE86.2 CE89.2 CE91.2 CMOS1.2 CN6301.17 CN6301.20 CN6301.23 CN6301.24 CN6301.25 CN6301.26 CV10.2 CV11.2 CV15.2 CV16.2 CV17.2 CV18.2 CV19.2 CV20.2 CV21.2 CV26.2 CV27.2 CV28.2 CV29.2 CV30.2 CV33.2 CV34.2 CV35.2 CV38.2 CV39.2 CV40.2 CV41.2 CV42.2 CV43.2 CV44.2 CV45.2 CV46.2 CV47.2 CV48.2 CV49.2 CV50.2 CV51.2 CV52.2 CV53.2 CV54.2 CV55.2 CV56.2 CV57.2 CV58.2 CV59.2 CV60.2 CV61.2 CV62.2 CV63.2 CV64.2 CV65.2 CV66.2 CV67.2 CV68.2 CV69.2 CV70.2 CV71.2 CV72.2 CV73.2 CV74.2 CV75.2 CV76.2 CV77.2 CV78.2 CV79.2 CV80.2 CV81.2 CV82.2 CV84.2 CV85.2 CV86.2 CV87.2 CV88.2 CV89.2 CV90.2 CV91.2 CV92.2 CV93.2 CV94.2 CV95.2 CV96.2 CV97.2 CV100.2 CV101.2 CV102.2 CV103.2 CV104.2 CV105.2 CV106.2 CV107.2 CV108.2 CV109.2 CV110.2 CV111.2 CV112.2 CV113.2 CV114.2 CV115.2 CV116.2 CV117.2 CV118.2 CV119.2 CV120.2 CV121.2 CV122.2 CV123.2 CV124.2 CV131.2 CV133.2 CV143.2 CV151.2 CV170.2 CV171.2 CV174.2 CV175.2 CV176.2 CV177.2 CV178.2 CV179.2 CV180.1 CV181.1 CV182.2 CV183.2 CV184.2 CV185.2 CV186.2 CV187.2 CV188.2 CV196.2 CV198.2 CV208.2 CV210.2 CV211.2 CV212.2 CV220.2 CV224.2 CV227.2 CV327.2 CV393.2 CV394.2 CV395.2 CV396.2 CV397.2 CV398.2 CV399.2 CV400.2 CV401.2 CV402.2 CV403.2 CVT90.1 CZ23.2 CZ30.2 CZ31.2 CZ34.2 CZ44.2 CZ45.2 CZ50.2 CZ70.2 CZ78.2 CZ82.2 CZ86.2 CZ87.2 CZ1701.2 CZ1702.2 CZ1703.2 D2601.2 DA6.1 DA13.1 DA14.1 DB1.2 DB1.11 DB1.12 DE8.2 EC2601.2 EC2602.2 EC2701.2 EC2703.2 EC2704.2 EC2705.2 EC2706.2 EC2707.2 EC2708.2 EC2709.2 EC2901.2 EC2902.2 EC2903.2 EC2904.2 EC3101.1 EC3102.1 EC3103.1 EC3104.1 EC3105.1 EC3106.1 EC3107.1 EC3108.1 EC3201.2 EC3301.2 EC3302.2 EC3303.2 EC3304.2 EC3305.2 EC3306.2 EC3307.2 EC5206.2 EC5210.2 EC5801.2 EC5802.2 EC6101.2 EC6102.2 EC6103.2 EC6105.2 EC6207.2 EC6208.2 EC9701.2 EC9702.2 EC9703.2 EC9705.2 EC9706.2 EC9708.2 EC9709.2 EC9710.2 EC9712.2 EC9713.2 EC9714.2 EC9715.2 EC9716.2 EC9717.2 EC9719.2 EC9720.2 EC9732.2 EC9733.2 EC9735.2 EC9736.2 EC9755.2 EC9756.2 EC9758.2 EC9759.2 EC9760.2 ED6101.2 EU3101.3 EU3102.3 EU3403.1 EU5602.3 FAN1.3 FAN1.4 FAN1.5 FAN261.5 FAN261.6 FAN261.7 FAN261.8 G6101.1 G6102.1 H1.1(TP-1) H2.1(TP-1) H3.1(TP-1) H4.1(TP-1) H5.1(TP-1) H6.1(TP-1) H7.1(TP-1) HCPU1.1(TP-1) HCPU2.1(TP-1) HCPU3.1(TP-1) HDA27.49 HDD1.6 HDD1.9 HDD1.12 HDD1.13 HDD1.14 HGPU1.1(TP-1) HGPU2.1(TP-1) HGPU3.1(TP-1) JCRT.5 JCRT.6 JCRT.7 JCRT.8 JCRT.10 JCRT.16 JCRT.17 JCRT.18 JCRT.19 JDEG1.10 JDEG1.11 JDEG1.12 JDIMM1.1 JDIMM1.2 JDIMM1.5 JDIMM1.6 JDIMM1.9 JDIMM1.10 JDIMM1.14 JDIMM1.15 JDIMM1.18 JDIMM1.19 JDIMM1.22 JDIMM1.23 JDIMM1.26 JDIMM1.27 JDIMM1.30 JDIMM1.31 JDIMM1.35 JDIMM1.36 JDIMM1.39 JDIMM1.40 JDIMM1.43 JDIMM1.44 JDIMM1.47 JDIMM1.48 JDIMM1.51 JDIMM1.52 JDIMM1.56 JDIMM1.57 JDIMM1.60 JDIMM1.61 JDIMM1.64 JDIMM1.65 JDIMM1.68 JDIMM1.69 JDIMM1.72 JDIMM1.73 JDIMM1.77 JDIMM1.78 JDIMM1.81 JDIMM1.82 JDIMM1.85 JDIMM1.86 JDIMM1.89 JDIMM1.90 JDIMM1.93 JDIMM1.94 JDIMM1.98 JDIMM1.99 JDIMM1.102 JDIMM1.103 JDIMM1.106 JDIMM1.107 JDIMM1.167 JDIMM1.168 JDIMM1.171 JDIMM1.172 JDIMM1.175 JDIMM1.176 JDIMM1.180 JDIMM1.181 JDIMM1.184 JDIMM1.185 JDIMM1.188 JDIMM1.189 JDIMM1.192 JDIMM1.193 JDIMM1.196 JDIMM1.197 JDIMM1.201 JDIMM1.202 JDIMM1.205 JDIMM1.206 JDIMM1.209 JDIMM1.210 JDIMM1.213 JDIMM1.214 JDIMM1.217 JDIMM1.218 JDIMM1.222 JDIMM1.223 JDIMM1.226 JDIMM1.227 JDIMM1.230 JDIMM1.231 JDIMM1.234 JDIMM1.235 JDIMM1.238 JDIMM1.239 JDIMM1.243 JDIMM1.244 JDIMM1.247 JDIMM1.248 JDIMM1.251 JDIMM1.252 JDIMM1.261 JDIMM1.262 JDIMM2.1 JDIMM2.2 JDIMM2.5 JDIMM2.6 JDIMM2.9 JDIMM2.10 JDIMM2.14 JDIMM2.15 JDIMM2.18 JDIMM2.19 JDIMM2.22 JDIMM2.23 JDIMM2.26 JDIMM2.27 JDIMM2.30 JDIMM2.31 JDIMM2.35 JDIMM2.36 JDIMM2.39 JDIMM2.40 JDIMM2.43 JDIMM2.44 JDIMM2.47 JDIMM2.48 JDIMM2.51 JDIMM2.52 JDIMM2.56 JDIMM2.57 JDIMM2.60 JDIMM2.61 JDIMM2.64 JDIMM2.65 JDIMM2.68 JDIMM2.69 JDIMM2.72 JDIMM2.73 JDIMM2.77 JDIMM2.78 JDIMM2.81 JDIMM2.82 JDIMM2.85 JDIMM2.86 JDIMM2.89 JDIMM2.90 JDIMM2.93 JDIMM2.94 JDIMM2.98 JDIMM2.99 JDIMM2.102 JDIMM2.103 JDIMM2.106 JDIMM2.107 JDIMM2.167 JDIMM2.168 JDIMM2.171 JDIMM2.172 JDIMM2.175 JDIMM2.176 JDIMM2.180 JDIMM2.181 JDIMM2.184 JDIMM2.185 JDIMM2.188 JDIMM2.189 JDIMM2.192 JDIMM2.193 JDIMM2.196 JDIMM2.197 JDIMM2.201 JDIMM2.202 JDIMM2.205 JDIMM2.206 JDIMM2.209 JDIMM2.210 JDIMM2.213 JDIMM2.214 JDIMM2.217 JDIMM2.218 JDIMM2.222 JDIMM2.223 JDIMM2.226 JDIMM2.227 JDIMM2.230 JDIMM2.231 JDIMM2.234 JDIMM2.235 JDIMM2.238 JDIMM2.239 JDIMM2.243 JDIMM2.244 JDIMM2.247 JDIMM2.248 JDIMM2.251 JDIMM2.252 JDIMM2.261 JDIMM2.262 JHDMI.2 JHDMI.5 JHDMI.8 JHDMI.11 JHDMI.17 JHDMI.20 JHDMI.21 JHDMI.22 JHDMI.23 JWDB1.1 JWDB1.5 JWDB1.6 KB1.1 KB1.31 KB1.32 KB_BL1.5 KB_BL1.6 LCD1.9 LCD1.13 LCD1.16 LCD1.19 LCD1.22 LCD1.33 LCD1.35 LCD1.41 LCD1.42 LED1.3 LOM30.33 ODD1.1 ODD1.4 ODD1.7 ODD1.18 ODD1.19 ODD1.20 ODD1.21 ODD1.22 PBATT1.1 PBATT1.2 PBATT1.3 PBATT1.9 PBATT1.10 PC1.2 PC2.2 PC3.2 PC4.2 PC7.2 PC8.2 PC100.2 PC103.2 PC104.2 PC105.2 PC106.2 PC107.2 PC108.2 PC109.2 PC110.2 PC111.2 PC112.2 PC115.2 PC116.2 PC117.2 PC118.2 PC119.2 PC120.2 PC121.2 PC122.2 PC123.2 PC124.2 PC125.2 PC126.2 PC128.2 PC130.2 PC131.2 PC132.2 PC133.2 PC201.2 PC202.2 PC203.2 PC204.1 PC205.2 PC206.2 PC207.2 PC208.2 PC209.2 PC210.2 PC211.2 PC212.2 PC213.2 PC215.2 PC216.2 PC217.2 PC218.2 PC219.2 PC220.2 PC230.2 PC231.2 PC301.2 PC302.2 PC303.2 PC304.2 PC305.2 PC306.2 PC308.2 PC310.2 PC311.2 PC312.2 PC313.2 PC320.2 PC321.2 PC501.2 PC502.2 PC504.2 PC505.2 PC506.2 PC507.2 PC601.2 PC602.2 PC603.2 PC604.2 PC605.1 PC606.2 PC608.2 PC612.2 PC613.1 PC614.1 PC616.1 PC618.1 PC619.1 PC621.1 PC622.2 PC625.1 PC628.2 PC629.1 PC631.2 PC636.1 PC641.2 PC643.2 PC644.2 PC645.2 PC647.1 PC649.2 PC651.1 PC652.2 PC654.1 PC656.2 PC657.2 PC658.2 PC659.2 PC660.2 PC661.2 PC662.2 PC664.2 PC665.2 PC666.2 PC667.2 PC668.2 PC669.2 PC670.2 PC672.2 PC673.2 PC674.2 PC677.2 PC678.2 PC679.2 PC680.2 PC681.2 PC682.2 PC683.2 PC684.2 PC685.2 PC686.2 PC687.2 PC688.2 PC690.2 PC691.2 PC692.2 PC693.2 PC694.2 PC695.1 PC705.2 PC711.1 PC748.2 PC749.1 PC751.1 PC752.1 PC753.1 PC757.1 PC760.2 PC761.2 PC762.2 PC763.2 PC764.2 PC765.2 PC766.2 PC767.2 PC768.1 PC769.1 PC775.2 PC776.2 PC777.2 PC778.2 PC780.2 PC781.2 PC790.2 PC801.2 PC802.2 PC804.2 PC805.2 PC836.2 PC837.2 PC838.2 PC839.2 PC1001.2 PC1002.2 PC1003.2 PC1004.2 PC1005.2 PC1006.2 PC1007.2 PC1008.2 PC1009.2 PC1010.2 PC1011.2 PC1012.2 PC1013.2 PC1014.2 PC1015.2 PC1016.2 PC1017.2 PC1018.2 PC1019.2 PC1020.2 PC1021.2 PC1022.2 PC1023.2 PC1024.2 PC1025.2 PC1026.2 PC1027.2 PC1028.2 PC1029.2 PC1030.2 PC1031.2 PC1032.2 PC1033.2 PC1034.2 PC1035.2 PC1036.2 PC1037.2 PC1038.2 PC1039.2 PC1040.2 PC1041.2 PC1042.2 PC1043.2 PC1044.2 PC1045.2 PC1046.2 PC1047.2 PC1048.2 PC1049.2 PC1050.2 PC1051.2 PC1052.2 PC1053.2 PC1054.2 PC1055.2 PC1056.2 PC1057.2 PC1058.2 PC1059.2 PC1060.2 PC1061.2 PC1062.2 PC1063.2 PC1064.2 PC1065.2 PC1066.2 PC1067.2 PC1068.2 PC1069.2 PC1070.2 PC1071.2 PC1072.2 PC1073.2 PC1074.2 PC1075.2 PC1076.2 PC1077.2 PC1078.2 PC1079.2 PC1080.2 PC1081.2 PC1082.2 PC1083.2 PC1084.2 PC1085.2 PC1086.2 PC1087.2 PC1088.2 PC1089.2 PC1090.2 PC1091.2 PC1092.2 PC1093.2 PC1094.2 PC1095.2 PC1096.2 PC1097.2 PC1098.2 PC1099.2 PC1101.2 PC1103.2 PC1104.2 PC1105.2 PC1106.2 PC1107.2 PC1109.2 PC1110.2 PC1111.2 PC1112.2 PC1113.2 PC1114.2 PC1115.2 PC1116.2 PC1117.1 PC1121.2 PC1124.2 PC1125.2 PC1126.2 PC1127.2 PC1128.2 PC1129.2 PC1130.2 PC1131.2 PC1132.2 PC1133.2 PC1134.2 PC1135.2 PC1136.2 PC1137.2 PC1138.2 PC1139.2 PC1140.2 PC1141.2 PC1142.2 PC1143.2 PC1144.2 PC1145.2 PC1146.2 PC1147.2 PC1148.2 PC1149.2 PC1150.2 PC1151.2 PC1152.2 PC1153.2 PC1154.2 PC1155.2 PC1156.2 PC1158.2 PC1159.2 PC1161.2 PC1162.2 PC1163.2 PC1164.2 PC1170.2 PC1171.2 PC1172.2 PC1173.2 PC1174.2 PC1175.2 PC1176.2 PC1177.2 PC1178.2 PC1179.2 PC1180.2 PC1181.2 PC1182.2 PC1183.2 PC1184.2 PC1190.2 PC1191.2 PC1192.2 PC1193.2 PC1202.2 PC1203.2 PC1204.2 PC1205.2 PC1206.2 PC1207.2 PC1208.2 PC1209.2 PC1210.2 PC1211.2 PC1212.2 PC1221.2 PC1222.2 PC1223.2 PC1224.2 PC1226.2 PC1229.2 PC1231.2 PC1233.2 PC1401.2 PC1402.2 PC1403.2 PC1404.2 PC1405.2 PC1406.2 PC1408.2 PC1411.2 PC1412.2 PC1413.2 PC1414.2 PC1420.2 PC1421.2 PC1424.2 PD2.1 PD3.1 PD4.1 PD5.2 PD6.2 PH601.1 PH603.1 PH1101.1 PJP2.1 PJPDC1.7 PJPDC1.8 PL4.2 PQ1.1 PQ1.4 PQ2.1 PQ2.4 PQ3.3 PQ5.3 PQ201.5 PQ201.6 PQ201.7 PQ601.5 PQ601.6 PQ601.7 PQ708.1 PQ708.2 PQ708.3 PQ711.3 PQ712.3 PQ720.3 PQ721.3 PQ1102.1 PQ1102.2 PQ1102.3 PQ1103.1 PQ1103.2 PQ1103.3 PQ1105.1 PQ1105.2 PQ1105.3 PQ1106.1 PQ1106.2 PQ1106.3 PR2.2 PR9.1 PR10.1 PR29.2 PR32.2 PR33.1 PR103.2 PR110.2 PR118.2 PR122.2 PR204.2 PR302.2 PR305.2 PR310.2 PR502.1 PR505.2 PR608.2 PR611.2 PR613.1 PR629.1 PR631.1 PR637.2 PR647.1 PR651.2 PR653.2 PR654.2 PR662.2 PR680.2 PR681.2 PR727.2 PR731.2 PR732.2 PR738.2 PR751.1 PR752.1 PR753.1 PR755.1 PR779.1 PR802.2 PR1101.1 PR1105.1 PR1106.1 PR1111.1 PR1117.1 PR1120.1 PR1130.2 PR1140.2 PR1202.1 PR1205.2 PR1207.2 PR1404.2 PR1407.2 PR1411.2 PU100.7 PU100.8 PU100.18 PU100.21 PU102.7 PU102.8 PU102.18 PU102.21 PU200.1 PU200.3 PU200.14 PU200.21 PU300.7 PU300.8 PU300.18 PU300.21 PU500.11 PU602.41 PU603.7 PU603.10 PU604.7 PU604.10 PU605.7 PU605.10 PU606.4 PU606.9 PU703.33 PU800.8 PU800.9 PU1100.41 PU1200.2 PU1200.11 PU1400.7 PU1400.8 PU1400.18 PU1400.21 PWR1.4 PWR1.5 PWR1.6 Q1901.3 Q2405.3 Q2505.3 Q3001.3 Q5403.3 Q6202.3 R1902.2 R2504.2 R2605.1 R2611.2 R2706.2 R2717.2 R3015.2 R3023.2 R3032.1 R3203.2 R5201.2 R5202.1 R5209.2 R5218.2 R5410.2 R5412.2 R5413.2 R5418.1 R5501.2 R5505.2 R5508.1 R5510.2 R5512.1 R5513.2 R5514.2 R5516.1 R5604.2 R6207.2 R6209.2 R6301.1 R6302.1 R6305.2 R6517.2 RC1.1 RC3.2 RC4.2 RC5.2 RC6.2 RC7.2 RC35.2 RC43.2 RC44.2 RC48.2 RC65.2 RC75.1 RC88.2 RC89.2 RC90.2 RC91.2 RC96.2 RC109.1 RC110.1 RC112.1 RC113.1 RC114.2 RC141.2 RC163.2 RC166.2 RC182.1 RC220.2 RC268.2 RC312.1 RC341.2 RC347.2 RC348.2 RC358.1 RC366.2 RC375.2 RC377.2 RC380.2 RC381.2 RC383.2 RC390.1 RC393.2 RD28.2 RD29.2 RD30.2 RD38.2 RD39.2 RD40.2 RE355.2 RE357.2 RE358.2 RE367.2 RE380.1 RE397.2 RE398.2 RH209.2 RH210.2 RH211.2 RH212.2 RN5203.1 RN5203.2 RN5203.3 RP34.2 RTC1.2 RV2.1 RV4.2 RV9.2 RV12.2 RV13.2 RV16.2 RV17.1 RV21.1 RV29.1 RV34.2 RV35.2 RV38.2 RV39.1 RV40.1 RV41.1 RV59.1 RV83.2 RV88.1 RV89.1 RV110.2 RV112.2 RV142.2 RV143.2 RV151.1 RV160.2 RV163.2 RV261.2 RV262.2 RV263.2 RV264.2 SPK1.5 SPK1.6 SPR1.1(TP-1) SPR2.1(TP-1) SPR3.1(TP-1) SW1.1 TC3501.2 THM26.5 TPAD1.4 TPAD1.9 TPAD1.10 U15.11 U15.15 U3201.25 U3402.3 U3504.2 U3505.2 U5201.2 U5502.11 U5502.13 U5502.14 U5502.16 U5502.33 U5504.1 U5504.2 U5504.4 U5504.7 U5601.1 U5601.9 U5602.5 U5602.9 UC1.A5 UC1.A67 UC1.A70 UC1.AA2 UC1.AA4 UC1.AA65 UC1.AA68 UC1.AB8 UC1.AB15 UC1.AB16 UC1.AB18 UC1.AB21 UC1.AD8 UC1.AD13 UC1.AD16 UC1.AD19 UC1.AD20 UC1.AD21 UC1.AD62 UC1.AE64 UC1.AE65 UC1.AE66 UC1.AE67 UC1.AE68 UC1.AE69 UC1.AF1 UC1.AF2 UC1.AF4 UC1.AF10 UC1.AF15 UC1.AF17 UC1.AF63 UC1.AG16 UC1.AG17 UC1.AG18 UC1.AG19 UC1.AG20 UC1.AG21 UC1.AG71 UC1.AH6 UC1.AH13 UC1.AH63 UC1.AH64 UC1.AH67 UC1.AJ4 UC1.AJ15 UC1.AJ18 UC1.AJ20 UC1.AK8 UC1.AK11 UC1.AK16 UC1.AK18 UC1.AK21 UC1.AK22 UC1.AK27 UC1.AK63 UC1.AK68 UC1.AK69 UC1.AL2 UC1.AL4 UC1.AL28 UC1.AL32 UC1.AL35 UC1.AL38 UC1.AL45 UC1.AL48 UC1.AL52 UC1.AL55 UC1.AL58 UC1.AL64 UC1.AL65 UC1.AL66 UC1.AM8 UC1.AM13 UC1.AM21 UC1.AM25 UC1.AM27 UC1.AM43 UC1.AM45 UC1.AM46 UC1.AM55 UC1.AM60 UC1.AM61 UC1.AM68 UC1.AM71 UC1.AN20 UC1.AN23 UC1.AN28 UC1.AN30 UC1.AN32 UC1.AN33 UC1.AN35 UC1.AN37 UC1.AN38 UC1.AN40 UC1.AN42 UC1.AN58 UC1.AN63 UC1.AP10 UC1.AP18 UC1.AP20 UC1.AP23 UC1.AP28 UC1.AP32 UC1.AP35 UC1.AP38 UC1.AP42 UC1.AP58 UC1.AP63 UC1.AP68 UC1.AP70 UC1.AR5 UC1.AR8 UC1.AR11 UC1.AR15 UC1.AR16 UC1.AR20 UC1.AR23 UC1.AR28 UC1.AR35 UC1.AR42 UC1.AR43 UC1.AR45 UC1.AR46 UC1.AR48 UC1.AR50 UC1.AR52 UC1.AR53 UC1.AR55 UC1.AR58 UC1.AR63 UC1.AT2 UC1.AT4 UC1.AT20 UC1.AT23 UC1.AT28 UC1.AT35 UC1.AT42 UC1.AT56 UC1.AT58 UC1.AT63 UC1.AT68 UC1.AT71 UC1.AU10 UC1.AU15 UC1.AU20 UC1.AU32 UC1.AU38 UC1.AV1 UC1.AV68 UC1.AV69 UC1.AV70 UC1.AV71 UC1.AW6 UC1.AW8 UC1.AW10 UC1.AW12 UC1.AW14 UC1.AW16 UC1.AW18 UC1.AW21 UC1.AW23 UC1.AW26 UC1.AW28 UC1.AW30 UC1.AW32 UC1.AW34 UC1.AW36 UC1.AW38 UC1.AW41 UC1.AW43 UC1.AW45 UC1.AW47 UC1.AW49 UC1.AW51 UC1.AW53 UC1.AW55 UC1.AW57 UC1.AW60 UC1.AW62 UC1.AW64 UC1.AW66 UC1.AY3 UC1.AY66 UC1.AY71 UC1.B10 UC1.B14 UC1.B18 UC1.B22 UC1.B30 UC1.B34 UC1.B39 UC1.B44 UC1.B48 UC1.B53 UC1.B58 UC1.B62 UC1.B66 UC1.B71 UC1.BA1 UC1.BA2 UC1.BA6 UC1.BA10 UC1.BA14 UC1.BA18 UC1.BA23 UC1.BA28 UC1.BA32 UC1.BA36 UC1.BA41 UC1.BA45 UC1.BA49 UC1.BA53 UC1.BA57 UC1.BA62 UC1.BA66 UC1.BA71 UC1.BB6 UC1.BB18 UC1.BB26 UC1.BB30 UC1.BB34 UC1.BB38 UC1.BB43 UC1.BB55 UC1.BB60 UC1.BB64 UC1.BB67 UC1.BB70 UC1.C1 UC1.C5 UC1.C25 UC1.D6 UC1.D10 UC1.D11 UC1.D14 UC1.D18 UC1.D22 UC1.D25 UC1.D26 UC1.D30 UC1.D34 UC1.D39 UC1.D44 UC1.D45 UC1.D47 UC1.D48 UC1.D53 UC1.D58 UC1.D62 UC1.D66 UC1.D69 UC1.E6 UC1.E11 UC1.E15 UC1.E18 UC1.E21 UC1.E46 UC1.E50 UC1.E53 UC1.E56 UC1.E65 UC1.E71 UC1.F1 UC1.F2 UC1.F4 UC1.F8 UC1.F13 UC1.F22 UC1.F23 UC1.F27 UC1.F28 UC1.F32 UC1.F33 UC1.F35 UC1.F37 UC1.F38 UC1.F40 UC1.F42 UC1.F68 UC1.G5 UC1.G6 UC1.G10 UC1.G22 UC1.G43 UC1.G45 UC1.G48 UC1.G52 UC1.G55 UC1.G58 UC1.G60 UC1.G63 UC1.G66 UC1.H15 UC1.H18 UC1.H71 UC1.J8 UC1.J11 UC1.J13 UC1.J25 UC1.J28 UC1.J32 UC1.J35 UC1.J38 UC1.J42 UC1.K16 UC1.K18 UC1.K22 UC1.K61 UC1.K63 UC1.K64 UC1.K65 UC1.K66 UC1.K67 UC1.K68 UC1.K70 UC1.K71 UC1.L2 UC1.L4 UC1.L8 UC1.L11 UC1.L16 UC1.L17 UC1.L18 UC1.L20 UC1.N6 UC1.N10 UC1.N13 UC1.N19 UC1.N21 UC1.N65 UC1.N68 UC1.P17 UC1.P19 UC1.P20 UC1.P21 UC1.R6 UC1.R13 UC1.T2 UC1.T4 UC1.T15 UC1.T17 UC1.T18 UC1.T21 UC1.U10 UC1.U63 UC1.U64 UC1.U66 UC1.U67 UC1.U69 UC1.U70 UC1.V16 UC1.V17 UC1.V18 UC1.W6 UC1.W9 UC1.W13 UC1.Y17 UC1.Y19 UC1.Y20 UC1.Y21 UC5.4 UC7.3 UC14.3 UC15.3 UC16.3 UC17.3 UE1.17 UE1.51 UE1.64 UE1.84 UE1.100 UE1.124 UE6.3 USB1.4 USB1.7 USB1.10 USB1.11 USB1.12 USB1.13 UV1.A3 UV1.A30 UV1.A32 UV1.AA11 UV1.AA13 UV1.AA16 UV1.AA27 UV1.AB6 UV1.AB10 UV1.AB15 UV1.AB24 UV1.AB32 UV1.AC9 UV1.AC17 UV1.AC24 UV1.AC26 UV1.AC27 UV1.AD6 UV1.AD8 UV1.AD25 UV1.AD32 UV1.AE7 UV1.AE14 UV1.AE27 UV1.AF32 UV1.AG12 UV1.AG27 UV1.AH10 UV1.AH28 UV1.AH32 UV1.AM1 UV1.AM32 UV1.B6 UV1.B8 UV1.B10 UV1.B12 UV1.B14 UV1.B16 UV1.B18 UV1.B20 UV1.B22 UV1.B24 UV1.B26 UV1.C1 UV1.C32 UV1.E28 UV1.F2 UV1.F6 UV1.F8 UV1.F10 UV1.F12 UV1.F14 UV1.F16 UV1.F18 UV1.F20 UV1.F22 UV1.F24 UV1.F26 UV1.G8 UV1.G10 UV1.G27 UV1.G31 UV1.H2 UV1.H6 UV1.H14 UV1.H17 UV1.H20 UV1.J7 UV1.J27 UV1.J31 UV1.K2 UV1.K6 UV1.K11 UV1.K22 UV1.K28 UV1.K32 UV1.L27 UV1.M6 UV1.M12 UV1.M32 UV1.N11 UV1.N13 UV1.N16 UV1.N18 UV1.N21 UV1.N25 UV1.N27 UV1.P6 UV1.P9 UV1.P25 UV1.P32 UV1.R11 UV1.R12 UV1.R15 UV1.R17 UV1.R20 UV1.R27 UV1.T6 UV1.T11 UV1.T13 UV1.T16 UV1.T18 UV1.T21 UV1.T25 UV1.T32 UV1.U9 UV1.U15 UV1.U17 UV1.U20 UV1.U25 UV1.U27 UV1.V11 UV1.V13 UV1.V16 UV1.V18 UV1.V32 UV1.W25 UV1.W26 UV1.W27 UV1.Y10 UV1.Y15 UV1.Y17 UV1.Y20 UV1.Y25 UV1.Y32 UV2.3 UV11.5 UV17.A9 UV17.B1 UV17.B3 UV17.B9 UV17.D1 UV17.D8 UV17.E1 UV17.E2 UV17.E8 UV17.F9 UV17.G1 UV17.G8 UV17.G9 UV17.J2 UV17.J8 UV17.M1 UV17.M9 UV17.P1 UV17.P9 UV17.T1 UV17.T9 UV18.A9 UV18.B1 UV18.B3 UV18.B9 UV18.D1 UV18.D8 UV18.E1 UV18.E2 UV18.E8 UV18.F9 UV18.G1 UV18.G8 UV18.G9 UV18.J2 UV18.J8 UV18.M1 UV18.M9 UV18.P1 UV18.P9 UV18.T1 UV18.T9 UV19.A9 UV19.B1 UV19.B3 UV19.B9 UV19.D1 UV19.D8 UV19.E1 UV19.E2 UV19.E8 UV19.F9 UV19.G1 UV19.G8 UV19.G9 UV19.J2 UV19.J8 UV19.M1 UV19.M9 UV19.P1 UV19.P9 UV19.T1 UV19.T9 UV20.A9 UV20.B1 UV20.B3 UV20.B9 UV20.D1 UV20.D8 UV20.E1 UV20.E2 UV20.E8 UV20.F9 UV20.G1 UV20.G8 UV20.G9 UV20.J2 UV20.J8 UV20.M1 UV20.M9 UV20.P1 UV20.P9 UV20.T1 UV20.T9 UZ2.11 UZ2.15 UZ6.3 UZ19.5 UZ21.5 UZ21.9 WLAN1.1 WLAN1.7 WLAN1.10 WLAN1.18 WLAN1.25 WLAN1.31 WLAN1.37 WLAN1.43 WLAN1.49 WLAN1.55 WLAN1.61 WLAN1.67 WLAN1.68 WLAN1.69 YV1.2 YV1.4
GND_R1: CN6301.16 R6301.2
GND_R2: CN6301.10 R6302.2
GNDA: AFTP6313.1(TP-1) C2702.1 C2705.1 C2710.2 C2711.2 C2712.1 C2713.2 C2715.2 C2901.2 CN6301.1 CN6301.9 EC2703.1 EC2704.1 EC2705.1 EC2706.1 EC2707.1 EC2905.2 EC2906.2 EC2907.2 EC2908.2 HDA27.25 HDA27.38 R2706.1 R2707.2 R2711.1 R2919.2 R2920.2 R6305.1
V3D3_STB: HDA27.20 R2712.1 R2713.1
V18: C3201.2 U3201.24
VCC_EDRAM_SENSE: T4951.1(TP-1) UC1.AC63
VCC_GT_SENSE: PC617.1 PC618.2 PC620.1 PR622.1 RC161.2 UC1.J70
VCCEOPIO_SENSE: T4954.1(TP-1) UC1.AL63
VCCIO_SENSE: T4947.1(TP-1) UC1.AM23
VCCK_12: C5501.1 C5503.1 C5504.1 U5502.19 U5502.25
VCCSA_B+: PC608.1 PC612.1 PJP603.1 PQ601.2 PQ601.3 PQ601.4 PQ601.10
VCCSENSE: PC639.1 PC651.2 PC653.1 PR648.1 RC140.2 UC1.E32
VCCSENSE_VCCGTUS: RC340.2 UC1.AK62
VCCSENSE_VGA: PR1138.2 RV159.2 RV161.1
VCCST_PWRGD: RC78.2 UC1.B65
VCCSTG_EN: DZ1701.1 RZ75.2 RZ1702.1 UC15.4
VCCSTG_EN_R: CZ1702.1 DZ1701.2 RZ1702.2 UZ19.4
VDD10: C3012.1 C3018.1 C3019.1 C3021.1 C3022.1 C3023.1 C3024.1 C3025.1 L3001.2 LOM30.3 LOM30.8 LOM30.22 LOM30.30 R3001.2
VDD_1.2V: PC209.1 PR205.1 PR206.2 PU200.11
VDD_CHG: PC768.2 PR741.1 PR749.2 PR750.2 PR760.1 PR781.1 PU703.19
VDD_DAC_33: C5502.1 C5521.2 C5524.1 R5503.2 U5502.9
VDDIO_VGA: PC1226.1 PR1113.2 PR1115.2 PU1100.6
VDDP_CHG: PC769.2 PR760.2 PU703.20
VDDREG: C3009.1 C3010.1 LOM30.23 R3006.2
VIN_+VCCEOPIO: PC1202.1 PC1203.1 PC1210.1 PC1211.1 PC1212.1 PJP1201.2 PL1202.2 PU1200.1
VSS_EDRAM_SENSE: T4952.1(TP-1) UC1.AE63
VSS_GT_SENSE: PC619.2 PC620.2 PU602.6 RC163.1 UC1.J69
VSSEOPIO_SENSE: T4953.1(TP-1) UC1.AJ62
VSSIO_SENSE: T4948.1(TP-1) UC1.AM22
VSSSENSE: PC653.2 PC654.2 PU602.18 RC141.1 UC1.E33
VSSSENSE_VCCGTUS: RC341.1 UC1.AL61
VSSSENSE_VGA: PR1139.2 RV158.2 RV160.1
3D3V_CAMERA_S0: C5207.1 EC5210.1 LCD1.30 R5229.2
3D3V_CARD_S0: AFTP3310.1(TP-1) C3202.1 C3204.1 C3301.1 C3302.1 C3303.1 CARD1.4 U3201.5
3D3V_LAN_S5: C3003.1 C3004.1 C3005.1 C3007.1 C3008.1 C3017.1 LOM30.11 LOM30.32 Q3004.1 R3006.1
+BIF_VDDC: CV122.1 CV180.2 CV181.2 RV31.2 UV1.R21 UV1.U21
+DP_VDDC: CV30.1 CV33.1 CV34.1 RV30.1 UV1.AD14
+DP_VDDR: CV26.1 CV27.1 CV35.1 RV27.1 UV1.AF14
+FBA_VREF_CA0: CV327.1 RV110.1 RV139.2 UV17.M8 UV18.M8
+FBA_VREF_CA1: CV220.1 RV142.1 RV149.2 UV19.M8 UV20.M8
+FBA_VREF_DQ0: CV399.1 RV112.1 RV144.2 UV17.H1 UV18.H1
+FBA_VREF_DQ1: CV227.1 RV143.1 RV150.2 UV19.H1 UV20.H1
+MPLL_PVDD: CV81.1 CV82.1 CV124.1 LV6.2 UV1.L8
+MVREFDA: CV94.1 RV33.2 RV34.1 UV1.K26
+MVREFSA: CV95.1 RV32.2 RV35.1 UV1.J26
+PCIE_VDDC: CV54.1 CV55.1 CV56.1 CV57.1 CV58.1 CV59.1 CV60.1 CV120.1 CV121.1 RC364.2 UV1.L23 UV1.L24 UV1.L25 UV1.L26 UV1.M22 UV1.N22 UV1.N23 UV1.N24 UV1.R22 UV1.T22 UV1.U22 UV1.V22
+RTC_CELL: C2503.1 CC213.1 CC270.1 D2501.1 D2502.1 R2712.2 RC56.2 RC57.2 RC69.2 RE31.1 RE349.2 RE437.2 UC1.AK19 UC1.BB14
+RTC_CELL_VBAT: CE73.1 RE349.1 UE1.122
+RTC_VCC: AFTP2502.1(TP-1) R2502.2 RTC1.1
+SPLL_PVDD: CV84.1 CV85.1 CV86.1 LV7.2 UV1.H7
+SPLL_VDDC: CV91.1 CV92.1 CV93.1 LV8.2 UV1.H8
+TSVDD: CV19.1 CV20.1 CV21.1 LV2.2 UV1.AD17
+V_DDR_REFA: CD18.1 JDIMM1.164 RH206.2 RH209.1 RH484.2
+V_DDR_REFA_R: CH101.1 RH484.1 UC1.AY67
+V_DDR_REFB: CD29.1 JDIMM2.164 RH207.2 RH210.1 RH485.2
+V_DDR_REFB_R: CH100.1 RH485.1 UC1.BA67
+VGA_CORE: CV67.1 CV68.1 CV69.1 CV70.1 CV71.1 CV72.1 CV73.1 CV74.1 CV75.1 CV76.1 CV77.1 CV78.1 CV79.1 CV80.1 CV87.1 CV88.1 CV89.1 CV90.1 CV100.1 CV101.1 CV102.1 CV103.1 CV104.1 CV105.1 CV106.1 CV107.1 CV108.1 CV109.1 CV110.1 CV111.1 CV112.1 CV113.1 CV114.1 CV115.1 CV116.1 CV117.1 CV118.1 CV119.1 CV403.1 EC9755.1 EC9756.1 PC836.1 PC837.1 PC838.1 PC839.1 PL1102.1 PL1103.1 RV161.2 UV1.AA12 UV1.AA15 UV1.AB11 UV1.AB12 UV1.AB13 UV1.AC11 UV1.AC13 UV1.AC14 UV1.M11 UV1.M13 UV1.M15 UV1.M16 UV1.M17 UV1.M18 UV1.M20 UV1.M21 UV1.N12 UV1.N15 UV1.N17 UV1.N20 UV1.R13 UV1.R16 UV1.R18 UV1.T10 UV1.T12 UV1.T15 UV1.T17 UV1.T20 UV1.U10 UV1.U11 UV1.U13 UV1.U16 UV1.U18 UV1.V15 UV1.V17 UV1.V20 UV1.V21 UV1.W9 UV1.W10 UV1.Y9 UV1.Y13 UV1.Y16 UV1.Y18 UV1.Y21
AC_DIS: PQ712.2 UE1.69
AC_PRESENT: DZ4.2 RC243.1 UC1.AY15
ACAV_IN: CE84.2 DZ4.1 PR12.1 PR731.1 PR741.2 PU703.2 UE1.128
ACIN_CHG: PC711.2 PQ712.1 PR729.2 PR732.1 PU703.1
ACLIM: PR749.1 PR751.2 PU703.16
ADJ_2.5V: PC803.2 PR801.2 PR802.1 PU800.7
ALERT#: R2603.2 THM26.6
ALL_SYS_PWRGD: DZ5.2 RC345.1 RC388.1 RC392.2 RC1106.1 RE438.2 UC17.4
ALL_SYS_PWRGD_R: RC1106.2 RC1107.2 UC16.2
ALWON: PR114.1 UE1.121
AMBER_LED_BAT: EC6102.1 Q6101.1 R6103.2
ASGATE: PR762.2 PU703.30
AUD_HP1_JACK_L: HDA27.32 R2908.1
AUD_HP1_JACK_L1: R2907.2 R2908.2 R2912.2 R2922.2
AUD_HP1_JACK_R: HDA27.33 R2910.1
AUD_HP1_JACK_R1: R2909.2 R2910.2 R2913.2 R2921.2
AUD_PC_BEEP: C2720.2 R6514.2 R6516.2
AUD_PC_BEEP_C: D2701.1 RE33.1
AUD_PC_BEEP_R: HDA27.12 R6514.1
AUD_PORTA_L_R_B: AFTP6306.1(TP-1) CN6301.8 EC2907.1 R2907.1 R2919.1
AUD_PORTA_R_R_B: AFTP6309.1(TP-1) CN6301.7 EC2908.1 R2909.1 R2920.1
AUD_SENSE: R2709.2 R2923.2
AUD_SENSE_A: C2901.1 HDA27.13 R2709.1 R2722.2
AUD_SPK_L+: HDA27.42 R2902.2
AUD_SPK_L+_C: AFTP2902.1(TP-1) DA13.3 EC2902.1 R2902.1 SPK1.3
AUD_SPK_L-: HDA27.43 R2901.2
AUD_SPK_L-_C: AFTP2901.1(TP-1) DA13.2 EC2901.1 R2901.1 SPK1.4
AUD_SPK_R+: HDA27.45 R2904.2
AUD_SPK_R+_C: AFTP2904.1(TP-1) DA14.3 EC2904.1 R2904.1 SPK1.1
AUD_SPK_R-: HDA27.44 R2903.2
AUD_SPK_R-_C: AFTP2903.1(TP-1) DA14.2 EC2903.1 R2903.1 SPK1.2
AUD_VREF: C2705.2 HDA27.28
BA: PD704.3 PQ710.1 PR780.1
BAT1_LED#: QC4.1 RE408.1 UE1.1
BAT2_LED#: QC4.4 RE409.1 UE1.106
BAT_AMBER: LED1.1 R6103.1
BAT_WHITE: LED1.2 R6107.1
BATT_WHITE_LED_R#: Q6102.2 Q6105.1 QC4.3
BEEP: D2701.2 UE1.45
BKLT_CTRL: D5202.1 R5222.1 RN5201.7 RN5203.8
BLON_OUT_C: LCD1.24 RN5201.1 RN5203.7
BLUETOOTH_EN: R5804.1 RC292.2 UC1.AB2
BLUETOOTH_EN_NGFF: R5804.2 WLAN1.46
BOARD_ID: CE70.1 RE345.2 RE347.2 UE1.111
BOARD_ID2: RC374.2 RC375.1 UC1.AB3
BOARD_ID3: RC376.2 RC377.1 UC1.BA7
BP_0: RV82.1 UV1.U1
BP_1: RV81.1 UV1.U3
BST1_VGA: PR1123.1 PU1100.21
BST2_VGA: PR1103.1 PU1100.30
BST_1.2V: PR200.2 PU200.18
BST_1.2V_R: PC200.1 PR200.1
BST_3V: PR100.1 PU100.1
BST_5V: PR111.1 PU102.1
BST_+1.5VGPU: PR1402.1 PU1400.1
BST_+1.5VGPU_R: PC1407.1 PR1402.2
BST_+1VALW: PR306.1 PU300.1
BST_+1VALW_R: PC307.1 PR306.2
BST_+VCCEOPIO: PR1203.1 PU1200.9
BST_R_+VCCEOPIO: PC1201.1 PR1203.2
C0_1.0VS_VCCOPCP: PR1207.1 PU1200.4
C1_1.0VS_VCCOPCP: PR1206.2 PU1200.3
CAM_DETECT: T53.1(TP-1) UC1.P2
CAP_LED: KB1.4 R6201.2
CAP_LED#: Q6206.3 R6202.2 UE1.93
CAP_LED_Q: Q6201.1 R6201.1
CAP_LED_R#: Q6201.2 Q6206.1
CASA0#: UV1.G19 UV17.K3 UV18.K3
CASA1#: UV1.G16 UV19.K3 UV20.K3
CBN: C2703.1 HDA27.35
CBP: C2703.2 HDA27.37
CCLIM: PR750.1 PR752.2 PU703.11
CFG0: RC113.2 T21.1(TP-1) UC1.E68
CFG1: RC112.2 T22.1(TP-1) UC1.B67
CFG2: T23.1(TP-1) UC1.D65
CFG3: RC110.2 RC1104.2 T24.1(TP-1) UC1.D67
CFG4: RC109.2 T25.1(TP-1) UC1.E70
CFG5: T26.1(TP-1) UC1.C68
CFG6: T27.1(TP-1) UC1.D68
CFG7: T28.1(TP-1) UC1.C67
CFG8: T31.1(TP-1) UC1.F71
CFG9: T32.1(TP-1) UC1.G69
CFG10: T33.1(TP-1) UC1.F70
CFG11: T34.1(TP-1) UC1.G68
CFG12: T35.1(TP-1) UC1.H70
CFG13: T36.1(TP-1) UC1.G71
CFG14: T37.1(TP-1) UC1.H69
CFG15: T38.1(TP-1) UC1.G70
CFG16: T30.1(TP-1) UC1.E63
CFG17: T29.1(TP-1) UC1.F63
CFG18: T40.1(TP-1) UC1.E66
CFG19: T39.1(TP-1) UC1.F66
CFG_RCOMP: RC114.1 UC1.E60
CHG_AMBER_LED_R#: Q6101.2 QC4.6
CKEA0: UV1.K20 UV17.K9 UV18.K9
CKEA1: UV1.J17 UV19.K9 UV20.K9
CLK_ITPXDP_N: T4943.1(TP-1) UC1.F43
CLK_ITPXDP_P: T4944.1(TP-1) UC1.E43
CLK_LAN_REQ2#_R: LOM30.12 R3005.2
CLK_PCI_LPC_MEC: CC4.2 R2455.2 RC18.2 UE1.57
CLK_PCI_LPDEBUG: CC5.2 DB1.1 RC22.2
CLK_PCIE_LAN_N2: LOM30.16 UC1.D41
CLK_PCIE_LAN_P2: LOM30.15 UC1.C41
CLK_PCIE_LAN_REQ#: R3005.1 RC50.2 UC1.AT8
CLK_PCIE_WLAN_N1: EC5801.1 UC1.B42 WLAN1.41
CLK_PCIE_WLAN_P1: EC5802.1 UC1.A42 WLAN1.39
CLK_PCIE_WLAN_REQ#: R5803.2 RC47.2 UC1.AT7
CLK_PCIE_WLAN_REQ#_R: R5803.1 WLAN1.45
CLK_PEG_VGA: UC1.D42 UV1.AK30
CLK_PEG_VGA#: UC1.C42 UV1.AK32
CLK_SMB: PBATT1.6 PR18.1
CLK_TP_SIO: CZ31.1 RZ19.2 TPAD1.8 UE1.78
CLKA0: RV43.1 UV1.H26 UV17.J7 UV18.J7
CLKA0#: RV44.1 UV1.H25 UV17.K7 UV18.K7
CLKA0_C: CV393.1 RV43.2 RV44.2
CLKA1: RV66.1 UV1.G9 UV19.J7 UV20.J7
CLKA1#: RV67.1 UV1.H9 UV19.K7 UV20.K7
CLKA1_C: CV224.1 RV66.2 RV67.2
CLKRUN#: RC27.1 UC1.AW11 UE1.63
CLKTESTA: CV98.2 UV1.K8
CLKTESTB: CV99.2 UV1.L7
CMP_STRAP0: RE385.1 UE1.118
CMP_VIN0: RE392.1 RE394.1 UE1.20
CMP_VOUT0: PR116.1 RE392.2 RE404.2 UE1.85
CMSRC: PR763.2 PU703.29
CODEC_BITCLK_R: HDA27.6 R2720.2
CODEC_SDOUT_R: HDA27.5 R2719.2
COMBO-GPI: HDA27.48 TP2702.1(TP-1)
COMP: PC751.2 PR754.2 PU703.10
COMP_IA: PC636.2 PR639.2 PU602.16
COMP_VSA: PC628.1 PR630.1 PU602.24
CORE_SNUB: PC662.1 PR663.2
CORE_SW: PL603.4 PR663.1 PU603.8
CORE_VID0: T4949.1(TP-1) UC1.AN11
CORE_VID1: T4950.1(TP-1) UC1.AN13
CPU_B+: PC606.1 PC656.1 PC657.1 PC658.1 PC659.1 PC660.1 PC680.1 PC686.1 PC691.1 PC694.1 PJP601.1 PJP603.2 PL602.1 PR603.2 PU603.6 PU603.11
CPU_CRT_HPD: RC386.1 UC1.N9
CPU_DP3_AUXN: T1.1(TP-1) UC1.G46
CPU_DP3_AUXP: T2.1(TP-1) UC1.F46
CPU_HDMI_HPD: RC385.1 UC1.L9
CPU_POPIRCOMP: RC88.1 UC1.AT16
CPU_XDP_TCK0: RC35.1 T42.1(TP-1) UC1.A59 UC1.B61
CPVEE: C2704.2 HDA27.34
CRT_B: AFTP5503.1(TP-1) C5518.1 JCRT.3 L5502.2
CRT_DDCCLK_CON: AFTP5506.1(TP-1) C5511.1 JCRT.15 RE46.1 U5502.4
CRT_DDCDATA_CON: AFTP5505.1(TP-1) C5516.1 JCRT.12 RE45.1 U5502.6
CRT_G: AFTP5502.1(TP-1) C5510.1 JCRT.2 L5501.2
CRT_HSYNC_CON: AFTP5508.1(TP-1) C5513.1 JCRT.13 R5511.2
CRT_NC: AFTP5509.1(TP-1) JCRT.11
CRT_PCH_HPD: R5510.1 R5517.1 U5502.1
CRT_R: AFTP5501.1(TP-1) C5514.1 JCRT.1 L5503.2
CRT_VSYNC_CON: AFTP5507.1(TP-1) C5507.1 JCRT.14 R5507.2
CS_1.2V: PR205.2 PU200.13
CSA0#_0: UV1.H22 UV17.L2 UV18.L2
CSA1#_0: UV1.G13 UV19.L2 UV20.L2
CSI2_COMP: RC3.1 UC1.E13
DAT_SMB: PBATT1.5 PR20.1
DAT_TP_SIO: CZ30.1 RZ18.2 TPAD1.7 UE1.79
DBC_EN: R5213.2 UC1.AM5
DBC_EN_R: LCD1.10 R5213.1 R6507.2
DCBAT_CAM: LCD1.3 LCD1.4 R6525.1
DCBATOUT_LCD: C5202.1 C5205.2 F5201.2 LCD1.1 LCD1.2 R5214.2 R6525.2
DDC_CLK_HDMI: JHDMI.15 Q5402.3 RE43.1
DDC_CLK_PH1: D5401.3 RE43.2
DDC_DATA_HDMI: JHDMI.16 Q5402.6 RE44.1
DDC_DATA_PH2: D5401.2 RE44.2
DDR4_DRAMRST#: JDIMM1.108 JDIMM2.108 RD31.1
DDR_A_ACT#: JDIMM1.114 UC1.BA55
DDR_A_ALERT#: JDIMM1.116 UC1.AW50
DDR_A_BG0: JDIMM1.115 UC1.AY55
DDR_A_BG1: JDIMM1.113 UC1.AY54
DDR_A_BS0: JDIMM1.150 UC1.AU52
DDR_A_BS1: JDIMM1.145 UC1.AT48
DDR_A_CAS#: JDIMM1.156 UC1.AU48
DDR_A_CKE0: JDIMM1.109 UC1.BA56
DDR_A_CKE1: JDIMM1.110 UC1.BB56
DDR_A_CKE2: T3.1(TP-1) UC1.AW56
DDR_A_CKE3: T4.1(TP-1) UC1.AY56
DDR_A_CLK0: JDIMM1.137 UC1.AT53
DDR_A_CLK1: JDIMM1.138 UC1.AT55
DDR_A_CLK#0: JDIMM1.139 UC1.AU53
DDR_A_CLK#1: JDIMM1.140 UC1.AU55
DDR_A_CS#0: JDIMM1.149 UC1.AU45
DDR_A_CS#1: JDIMM1.157 UC1.AU43
DDR_A_D0: JDIMM1.4 UC1.AL71
DDR_A_D1: JDIMM1.3 UC1.AL68
DDR_A_D2: JDIMM1.20 UC1.AN68
DDR_A_D3: JDIMM1.21 UC1.AN69
DDR_A_D4: JDIMM1.8 UC1.AL70
DDR_A_D5: JDIMM1.7 UC1.AL69
DDR_A_D6: JDIMM1.16 UC1.AN70
DDR_A_D7: JDIMM1.17 UC1.AN71
DDR_A_D8: JDIMM1.29 UC1.AR70
DDR_A_D9: JDIMM1.25 UC1.AR68
DDR_A_D10: JDIMM1.37 UC1.AU71
DDR_A_D11: JDIMM1.41 UC1.AU68
DDR_A_D12: JDIMM1.24 UC1.AR71
DDR_A_D13: JDIMM1.28 UC1.AR69
DDR_A_D14: JDIMM1.42 UC1.AU70
DDR_A_D15: JDIMM1.38 UC1.AU69
DDR_A_D16: JDIMM1.45 UC1.BB65
DDR_A_D17: JDIMM1.49 UC1.AW65
DDR_A_D18: JDIMM1.63 UC1.AW63
DDR_A_D19: JDIMM1.58 UC1.AY63
DDR_A_D20: JDIMM1.50 UC1.BA65
DDR_A_D21: JDIMM1.46 UC1.AY65
DDR_A_D22: JDIMM1.59 UC1.BA63
DDR_A_D23: JDIMM1.62 UC1.BB63
DDR_A_D24: JDIMM1.67 UC1.BA61
DDR_A_D25: JDIMM1.70 UC1.AW61
DDR_A_D26: JDIMM1.79 UC1.BB59
DDR_A_D27: JDIMM1.84 UC1.AW59
DDR_A_D28: JDIMM1.66 UC1.BB61
DDR_A_D29: JDIMM1.71 UC1.AY61
DDR_A_D30: JDIMM1.83 UC1.BA59
DDR_A_D31: JDIMM1.80 UC1.AY59
DDR_A_D32: JDIMM1.174 UC1.AY39
DDR_A_D33: JDIMM1.170 UC1.AW39
DDR_A_D34: JDIMM1.187 UC1.AY37
DDR_A_D35: JDIMM1.186 UC1.AW37
DDR_A_D36: JDIMM1.169 UC1.BB39
DDR_A_D37: JDIMM1.173 UC1.BA39
DDR_A_D38: JDIMM1.182 UC1.BA37
DDR_A_D39: JDIMM1.183 UC1.BB37
DDR_A_D40: JDIMM1.195 UC1.AY35
DDR_A_D41: JDIMM1.191 UC1.AW35
DDR_A_D42: JDIMM1.207 UC1.AY33
DDR_A_D43: JDIMM1.203 UC1.AW33
DDR_A_D44: JDIMM1.194 UC1.BB35
DDR_A_D45: JDIMM1.190 UC1.BA35
DDR_A_D46: JDIMM1.208 UC1.BA33
DDR_A_D47: JDIMM1.204 UC1.BB33
DDR_A_D48: JDIMM1.211 UC1.AY31
DDR_A_D49: JDIMM1.216 UC1.AW31
DDR_A_D50: JDIMM1.229 UC1.AY29
DDR_A_D51: JDIMM1.228 UC1.AW29
DDR_A_D52: JDIMM1.215 UC1.BB31
DDR_A_D53: JDIMM1.212 UC1.BA31
DDR_A_D54: JDIMM1.224 UC1.BA29
DDR_A_D55: JDIMM1.225 UC1.BB29
DDR_A_D56: JDIMM1.237 UC1.AY27
DDR_A_D57: JDIMM1.233 UC1.AW27
DDR_A_D58: JDIMM1.236 UC1.AY25
DDR_A_D59: JDIMM1.232 UC1.AW25
DDR_A_D60: JDIMM1.245 UC1.BB27
DDR_A_D61: JDIMM1.249 UC1.BA27
DDR_A_D62: JDIMM1.246 UC1.BA25
DDR_A_D63: JDIMM1.250 UC1.BB25
DDR_A_DQS0: JDIMM1.13 UC1.AM69
DDR_A_DQS1: JDIMM1.34 UC1.AT70
DDR_A_DQS2: JDIMM1.55 UC1.AY64
DDR_A_DQS3: JDIMM1.76 UC1.BA60
DDR_A_DQS4: JDIMM1.179 UC1.AY38
DDR_A_DQS5: JDIMM1.200 UC1.BA34
DDR_A_DQS6: JDIMM1.221 UC1.AY30
DDR_A_DQS7: JDIMM1.242 UC1.BA26
DDR_A_DQS#0: JDIMM1.11 UC1.AM70
DDR_A_DQS#1: JDIMM1.32 UC1.AT69
DDR_A_DQS#2: JDIMM1.53 UC1.BA64
DDR_A_DQS#3: JDIMM1.74 UC1.AY60
DDR_A_DQS#4: JDIMM1.177 UC1.BA38
DDR_A_DQS#5: JDIMM1.198 UC1.AY34
DDR_A_DQS#6: JDIMM1.219 UC1.BA30
DDR_A_DQS#7: JDIMM1.240 UC1.AY26
DDR_A_MA0: JDIMM1.144 UC1.AY50
DDR_A_MA1: JDIMM1.133 UC1.BB50
DDR_A_MA2: JDIMM1.132 UC1.AY51
DDR_A_MA3: JDIMM1.131 UC1.BA50
DDR_A_MA4: JDIMM1.128 UC1.BB52
DDR_A_MA5: JDIMM1.126 UC1.BA51
DDR_A_MA6: JDIMM1.127 UC1.BA52
DDR_A_MA7: JDIMM1.122 UC1.AW52
DDR_A_MA8: JDIMM1.125 UC1.AY52
DDR_A_MA9: JDIMM1.121 UC1.BB54
DDR_A_MA10: JDIMM1.146 UC1.AT50
DDR_A_MA11: JDIMM1.120 UC1.BA54
DDR_A_MA12: JDIMM1.119 UC1.AW54
DDR_A_MA13: JDIMM1.158 UC1.AU46
DDR_A_ODT0: JDIMM1.155 UC1.AT45
DDR_A_ODT1: JDIMM1.161 UC1.AT43
DDR_A_PAR: JDIMM1.143 UC1.AT52
DDR_A_RAS#: JDIMM1.152 UC1.AU50
DDR_A_WE#: JDIMM1.151 UC1.AT46
DDR_B_ACT#: JDIMM2.114 UC1.AN53
DDR_B_ALERT#: JDIMM2.116 UC1.AN43
DDR_B_BG0: JDIMM2.115 UC1.AP52
DDR_B_BG1: JDIMM2.113 UC1.AN52
DDR_B_BS0: JDIMM2.150 UC1.BB44
DDR_B_BS1: JDIMM2.145 UC1.BA44
DDR_B_CAS#: JDIMM2.156 UC1.AY43
DDR_B_CKE0: JDIMM2.109 UC1.AN56
DDR_B_CKE1: JDIMM2.110 UC1.AP55
DDR_B_CKE2: T5.1(TP-1) UC1.AN55
DDR_B_CKE3: T6.1(TP-1) UC1.AP53
DDR_B_CLK0: JDIMM2.137 UC1.AP45
DDR_B_CLK1: JDIMM2.138 UC1.AP46
DDR_B_CLK#0: JDIMM2.139 UC1.AN45
DDR_B_CLK#1: JDIMM2.140 UC1.AN46
DDR_B_CS#0: JDIMM2.149 UC1.BB42
DDR_B_CS#1: JDIMM2.157 UC1.AY42
DDR_B_D0: JDIMM2.28 UC1.AF65
DDR_B_D1: JDIMM2.25 UC1.AF64
DDR_B_D2: JDIMM2.42 UC1.AK65
DDR_B_D3: JDIMM2.38 UC1.AK64
DDR_B_D4: JDIMM2.24 UC1.AF66
DDR_B_D5: JDIMM2.29 UC1.AF67
DDR_B_D6: JDIMM2.41 UC1.AK67
DDR_B_D7: JDIMM2.37 UC1.AK66
DDR_B_D8: JDIMM2.8 UC1.AF70
DDR_B_D9: JDIMM2.4 UC1.AF68
DDR_B_D10: JDIMM2.21 UC1.AH71
DDR_B_D11: JDIMM2.20 UC1.AH68
DDR_B_D12: JDIMM2.7 UC1.AF71
DDR_B_D13: JDIMM2.3 UC1.AF69
DDR_B_D14: JDIMM2.16 UC1.AH70
DDR_B_D15: JDIMM2.17 UC1.AH69
DDR_B_D16: JDIMM2.45 UC1.AT66
DDR_B_D17: JDIMM2.49 UC1.AU66
DDR_B_D18: JDIMM2.62 UC1.AP65
DDR_B_D19: JDIMM2.59 UC1.AN65
DDR_B_D20: JDIMM2.50 UC1.AN66
DDR_B_D21: JDIMM2.46 UC1.AP66
DDR_B_D22: JDIMM2.63 UC1.AT65
DDR_B_D23: JDIMM2.58 UC1.AU65
DDR_B_D24: JDIMM2.71 UC1.AT61
DDR_B_D25: JDIMM2.66 UC1.AU61
DDR_B_D26: JDIMM2.79 UC1.AP60
DDR_B_D27: JDIMM2.84 UC1.AN60
DDR_B_D28: JDIMM2.70 UC1.AN61
DDR_B_D29: JDIMM2.67 UC1.AP61
DDR_B_D30: JDIMM2.83 UC1.AT60
DDR_B_D31: JDIMM2.80 UC1.AU60
DDR_B_D32: JDIMM2.169 UC1.AU40
DDR_B_D33: JDIMM2.173 UC1.AT40
DDR_B_D34: JDIMM2.183 UC1.AT37
DDR_B_D35: JDIMM2.187 UC1.AU37
DDR_B_D36: JDIMM2.170 UC1.AR40
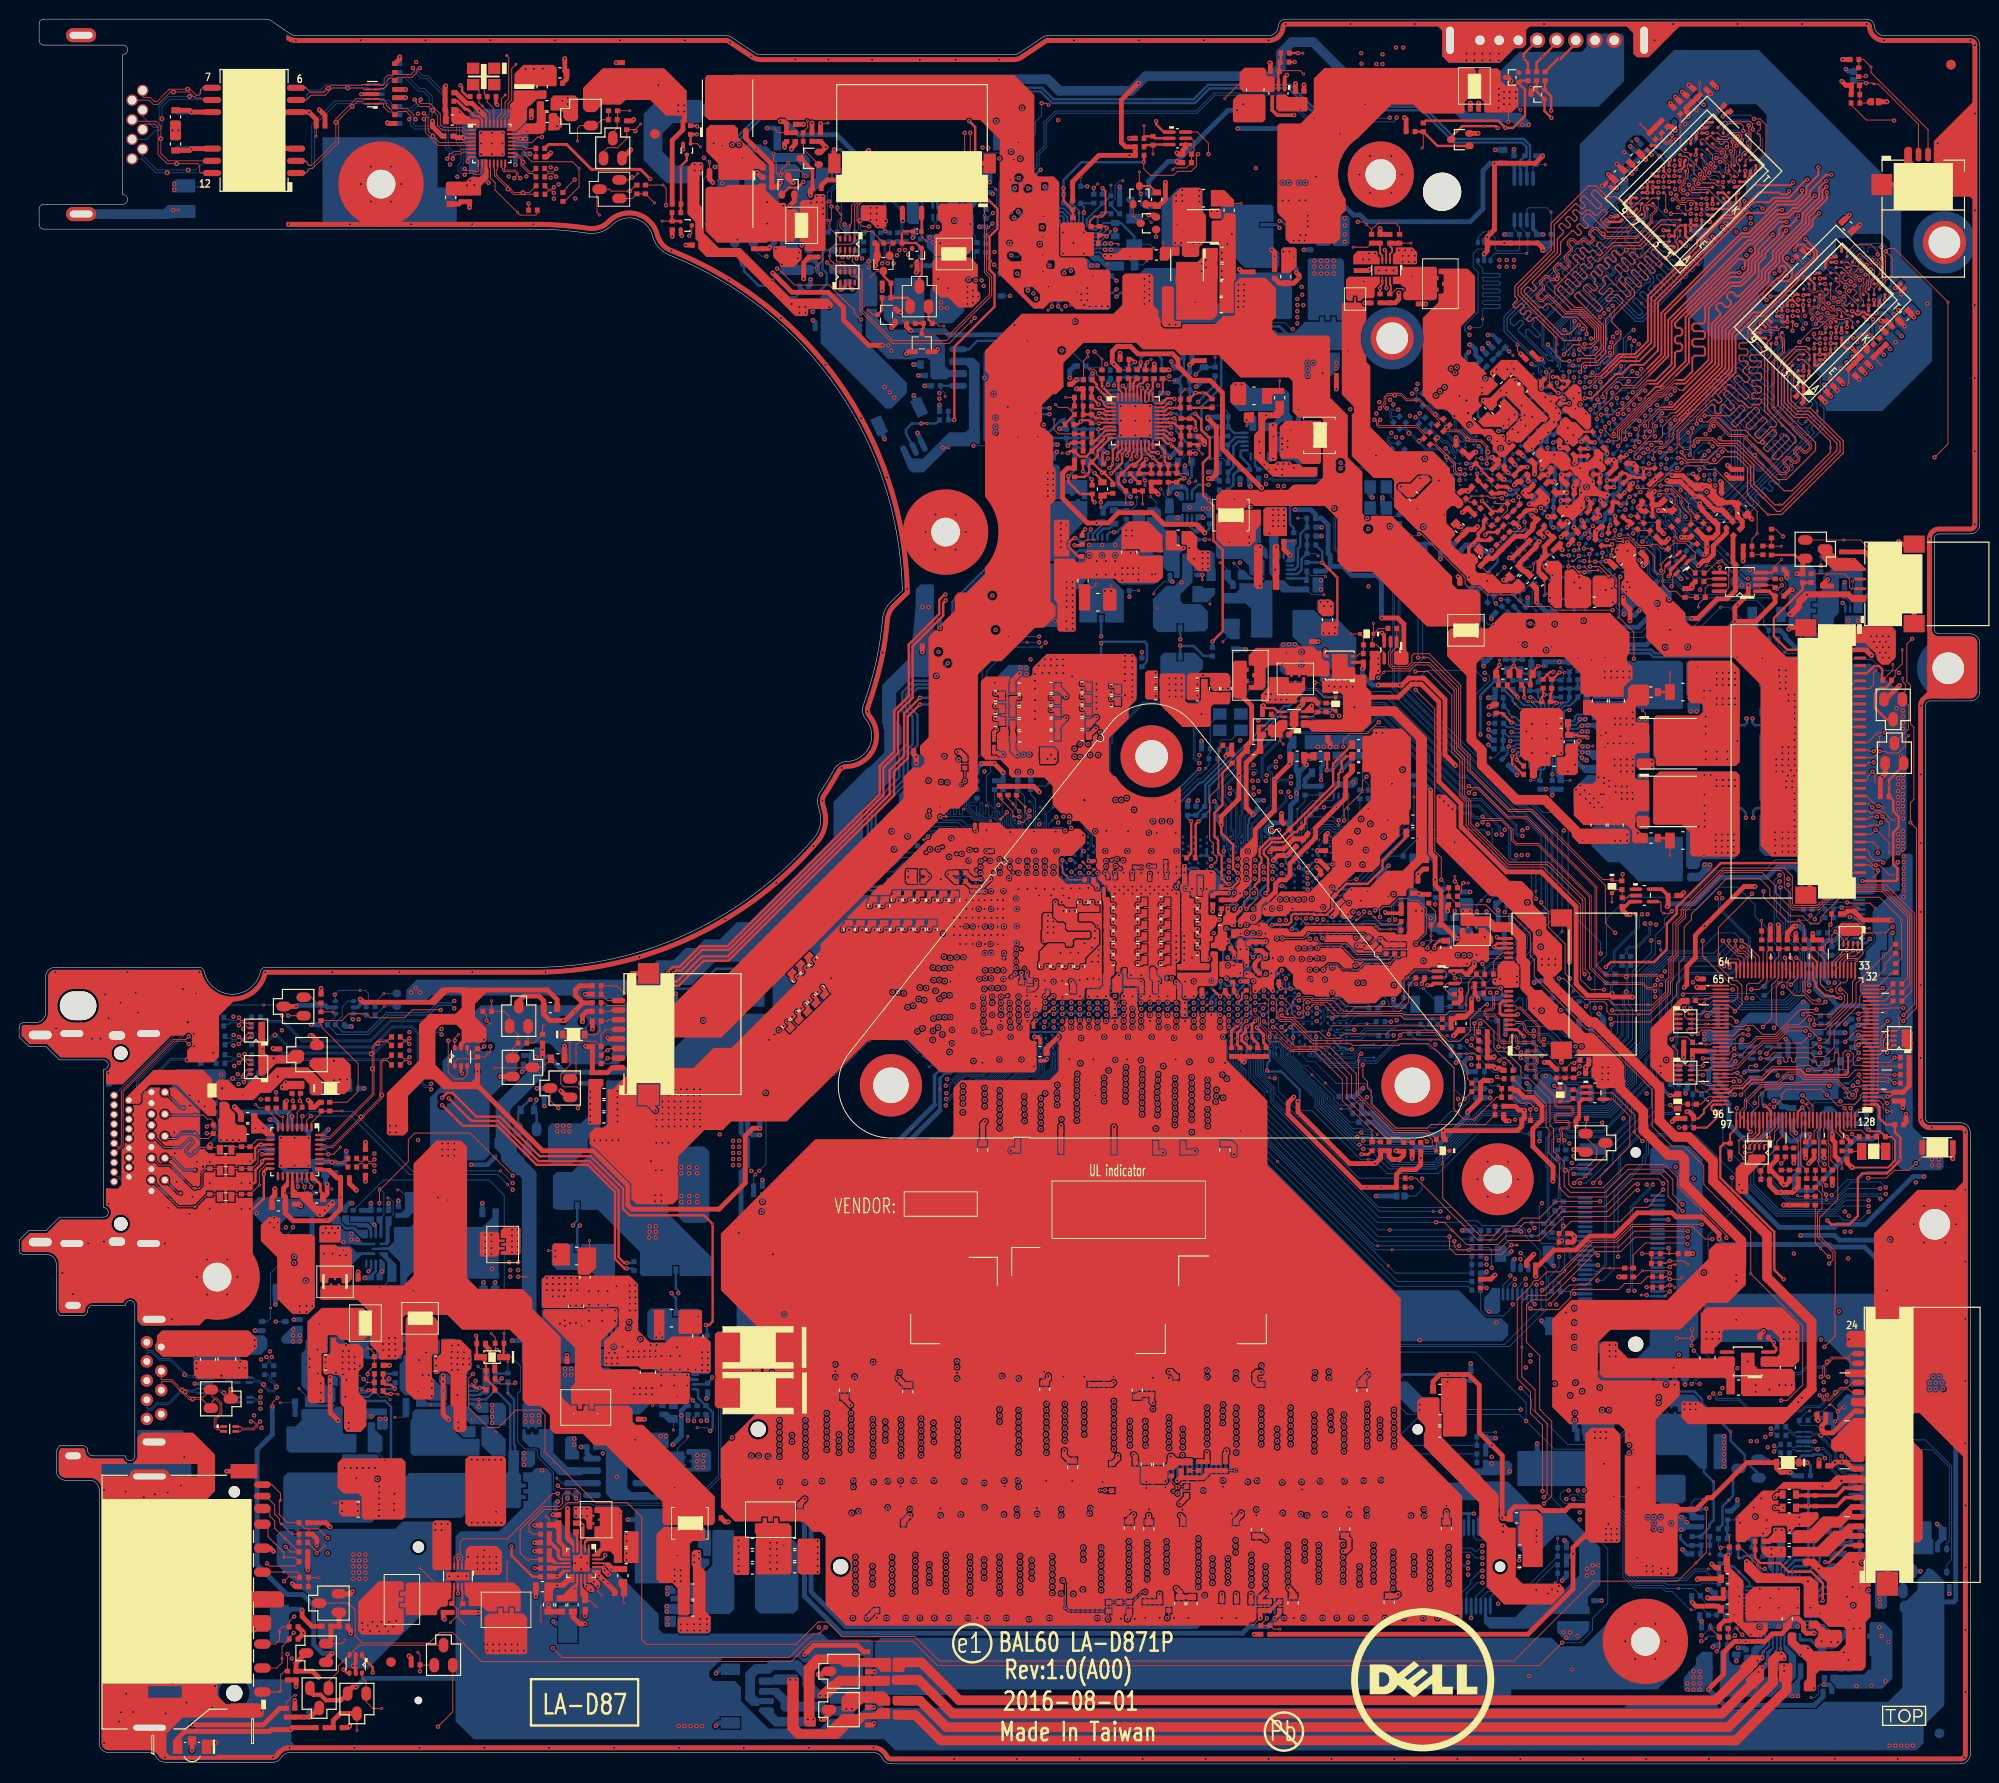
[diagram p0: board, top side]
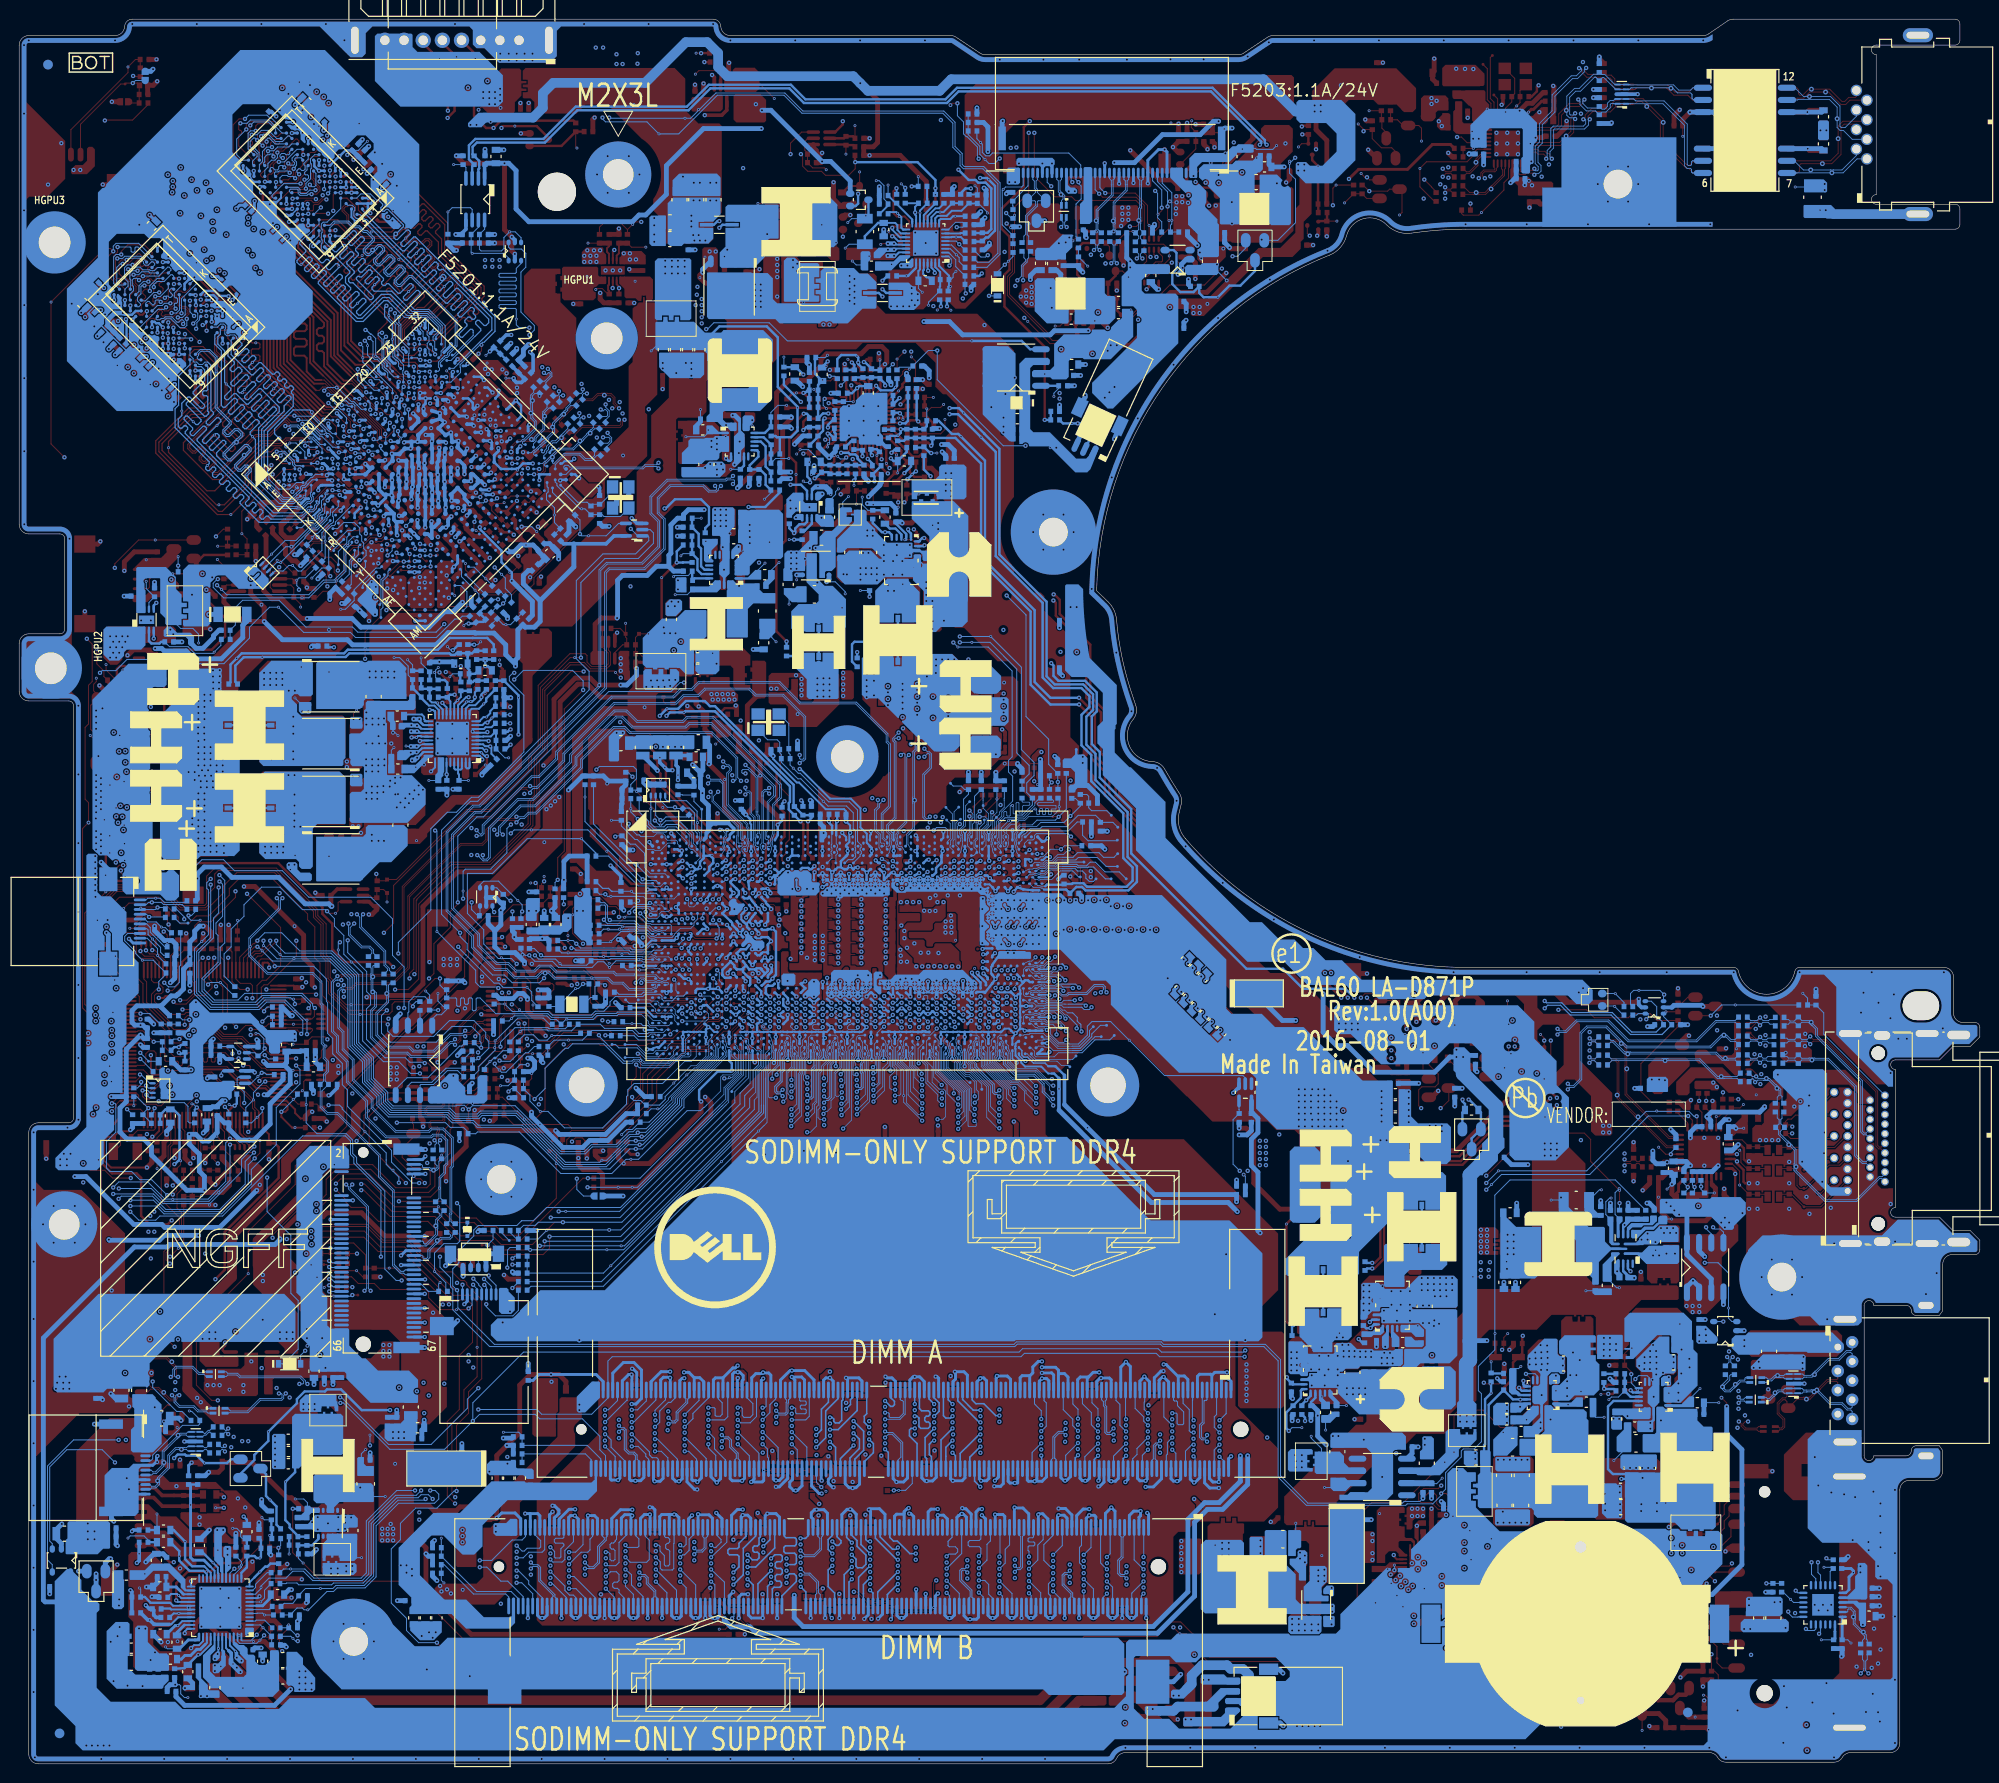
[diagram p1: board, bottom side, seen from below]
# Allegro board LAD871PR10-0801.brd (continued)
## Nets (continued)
DDR_B_D37: JDIMM2.174 UC1.AP40
DDR_B_D38: JDIMM2.186 UC1.AP37
DDR_B_D39: JDIMM2.182 UC1.AR37
DDR_B_D40: JDIMM2.190 UC1.AT33
DDR_B_D41: JDIMM2.194 UC1.AU33
DDR_B_D42: JDIMM2.207 UC1.AU30
DDR_B_D43: JDIMM2.203 UC1.AT30
DDR_B_D44: JDIMM2.191 UC1.AR33
DDR_B_D45: JDIMM2.195 UC1.AP33
DDR_B_D46: JDIMM2.204 UC1.AR30
DDR_B_D47: JDIMM2.208 UC1.AP30
DDR_B_D48: JDIMM2.216 UC1.AU27
DDR_B_D49: JDIMM2.212 UC1.AT27
DDR_B_D50: JDIMM2.225 UC1.AT25
DDR_B_D51: JDIMM2.229 UC1.AU25
DDR_B_D52: JDIMM2.211 UC1.AP27
DDR_B_D53: JDIMM2.215 UC1.AN27
DDR_B_D54: JDIMM2.228 UC1.AN25
DDR_B_D55: JDIMM2.224 UC1.AP25
DDR_B_D56: JDIMM2.232 UC1.AT22
DDR_B_D57: JDIMM2.236 UC1.AU22
DDR_B_D58: JDIMM2.249 UC1.AU21
DDR_B_D59: JDIMM2.245 UC1.AT21
DDR_B_D60: JDIMM2.237 UC1.AN22
DDR_B_D61: JDIMM2.233 UC1.AP22
DDR_B_D62: JDIMM2.250 UC1.AP21
DDR_B_D63: JDIMM2.246 UC1.AN21
DDR_B_DQS0: JDIMM2.34 UC1.AH65
DDR_B_DQS1: JDIMM2.13 UC1.AG70
DDR_B_DQS2: JDIMM2.55 UC1.AR65
DDR_B_DQS3: JDIMM2.76 UC1.AR60
DDR_B_DQS4: JDIMM2.179 UC1.AR38
DDR_B_DQS5: JDIMM2.200 UC1.AR32
DDR_B_DQS6: JDIMM2.221 UC1.AR27
DDR_B_DQS7: JDIMM2.242 UC1.AR21
DDR_B_DQS#0: JDIMM2.32 UC1.AH66
DDR_B_DQS#1: JDIMM2.11 UC1.AG69
DDR_B_DQS#2: JDIMM2.53 UC1.AR66
DDR_B_DQS#3: JDIMM2.74 UC1.AR61
DDR_B_DQS#4: JDIMM2.177 UC1.AT38
DDR_B_DQS#5: JDIMM2.198 UC1.AT32
DDR_B_DQS#6: JDIMM2.219 UC1.AR25
DDR_B_DQS#7: JDIMM2.240 UC1.AR22
DDR_B_MA0: JDIMM2.144 UC1.BA46
DDR_B_MA1: JDIMM2.133 UC1.AY46
DDR_B_MA2: JDIMM2.132 UC1.AY47
DDR_B_MA3: JDIMM2.131 UC1.BB46
DDR_B_MA4: JDIMM2.128 UC1.BA47
DDR_B_MA5: JDIMM2.126 UC1.AY48
DDR_B_MA6: JDIMM2.127 UC1.BA48
DDR_B_MA7: JDIMM2.122 UC1.AP48
DDR_B_MA8: JDIMM2.125 UC1.BB48
DDR_B_MA9: JDIMM2.121 UC1.AP50
DDR_B_MA10: JDIMM2.146 UC1.AW46
DDR_B_MA11: JDIMM2.120 UC1.AN48
DDR_B_MA12: JDIMM2.119 UC1.AN50
DDR_B_MA13: JDIMM2.158 UC1.BA43
DDR_B_ODT0: JDIMM2.155 UC1.BA42
DDR_B_ODT1: JDIMM2.161 UC1.AW42
DDR_B_PAR: JDIMM2.143 UC1.AP43
DDR_B_RAS#: JDIMM2.152 UC1.AW44
DDR_B_WE#: JDIMM2.151 UC1.AY44
DDR_VTT_CNTL: UC1.AW67 UC14.2
DGPU_HOLD_RST#: RC383.1 UC1.P3 UV2.2
DGPU_PWR_EN: PR1116.1 R437.1 R6510.1 RC358.2 RC359.2 RZ79.1 UC1.U1
DGPU_PWROK: PR1122.2 PR1403.1 RC360.2 UC1.C8
DIMM_CHA_SA0: JDIMM1.256 RD1.2 RD28.1
DIMM_CHA_SA1: JDIMM1.260 RD2.2 RD29.1
DIMM_CHA_SA2: JDIMM1.166 RD3.2 RD30.1
DIMM_CHB_SA0: JDIMM2.256 RD4.2 RD38.1
DIMM_CHB_SA1: JDIMM2.260 RD5.2 RD39.1
DIMM_CHB_SA2: JDIMM2.166 RD6.2 RD40.1
DMIC_CLK: C2723.2 LCD1.28 R2716.1 R5207.2
DMIC_CLK_R: HDA27.3 R2716.2
DMIC_DATA: LCD1.29 R2714.1
DMIC_DATA_R: EC2701.1 HDA27.2 R2714.2
DP_CRT_B: C5509.1 L5502.1 R5501.1 U5502.10
DP_CRT_G: C5512.1 L5501.1 R5513.1 U5502.12
DP_CRT_HSYNC_CON: R5511.1 U5502.8
DP_CRT_R: C5506.1 L5503.1 R5514.1 U5502.15
DP_CRT_VSYNC_CON: R5507.1 U5502.7
DQA0_0: UV1.K27 UV17.C2
DQA0_1: UV1.J29 UV17.A2
DQA0_2: UV1.H30 UV17.A3
DQA0_3: UV1.H32 UV17.C3
DQA0_4: UV1.G29 UV17.A7
DQA0_5: UV1.F28 UV17.D7
DQA0_6: UV1.F32 UV17.B8
DQA0_7: UV1.F30 UV17.C8
DQA0_8: UV1.C30 UV18.A7
DQA0_9: UV1.F27 UV18.C8
DQA0_10: UV1.A28 UV18.D7
DQA0_11: UV1.C28 UV18.B8
DQA0_12: UV1.E27 UV18.C3
DQA0_13: UV1.G26 UV18.A2
DQA0_14: UV1.D26 UV18.A3
DQA0_15: UV1.F25 UV18.C2
DQA0_16: UV1.A25 UV18.F8
DQA0_17: UV1.C25 UV18.H7
DQA0_18: UV1.E25 UV18.H8
DQA0_19: UV1.D24 UV18.H3
DQA0_20: UV1.E23 UV18.E3
DQA0_21: UV1.F23 UV18.F7
DQA0_22: UV1.D22 UV18.F2
DQA0_23: UV1.F21 UV18.G2
DQA0_24: UV1.E21 UV17.E3
DQA0_25: UV1.D20 UV17.F7
DQA0_26: UV1.F19 UV17.F2
DQA0_27: UV1.A19 UV17.H7
DQA0_28: UV1.D18 UV17.H3
DQA0_29: UV1.F17 UV17.G2
DQA0_30: UV1.A17 UV17.H8
DQA0_31: UV1.C17 UV17.F8
DQA1_0: UV1.E17 UV20.H8
DQA1_1: UV1.D16 UV20.H7
DQA1_2: UV1.F15 UV20.F2
DQA1_3: UV1.A15 UV20.F8
DQA1_4: UV1.D14 UV20.F7
DQA1_5: UV1.F13 UV20.G2
DQA1_6: UV1.A13 UV20.H3
DQA1_7: UV1.C13 UV20.E3
DQA1_8: UV1.E11 UV20.B8
DQA1_9: UV1.A11 UV20.A7
DQA1_10: UV1.C11 UV20.D7
DQA1_11: UV1.F11 UV20.C8
DQA1_12: UV1.A9 UV20.C3
DQA1_13: UV1.C9 UV20.C2
DQA1_14: UV1.F9 UV20.A2
DQA1_15: UV1.D8 UV20.A3
DQA1_16: UV1.E7 UV19.F2
DQA1_17: UV1.A7 UV19.E3
DQA1_18: UV1.C7 UV19.H3
DQA1_19: UV1.F7 UV19.G2
DQA1_20: UV1.A5 UV19.F7
DQA1_21: UV1.E5 UV19.H8
DQA1_22: UV1.C3 UV19.H7
DQA1_23: UV1.E1 UV19.F8
DQA1_24: UV1.G7 UV19.A2
DQA1_25: UV1.G6 UV19.A3
DQA1_26: UV1.G1 UV19.C2
DQA1_27: UV1.G3 UV19.C3
DQA1_28: UV1.J6 UV19.C8
DQA1_29: UV1.J1 UV19.D7
DQA1_30: UV1.J3 UV19.A7
DQA1_31: UV1.J5 UV19.B8
DQMA_0: UV1.E32 UV17.D3
DQMA_1: UV1.E30 UV18.D3
DQMA_2: UV1.A21 UV18.E7
DQMA_3: UV1.C21 UV17.E7
DQMA_4: UV1.E13 UV20.E7
DQMA_5: UV1.D12 UV20.D3
DQMA_6: UV1.E3 UV19.E7
DQMA_7: UV1.F4 UV19.D3
DRAM_RST: RV36.1 UV17.T2 UV18.T2 UV19.T2 UV20.T2
DRAM_RST_G: CV97.1 RV37.1 RV38.1 UV1.L10
DRAM_RST_R: CV96.1 RV36.2 RV37.2
DRMOS_EN: PC684.1 PR655.2 PU603.12 PU604.12 PU605.12
E51_RX1: TP5802.1(TP-1) WLAN1.38
E51_RX2: TP5803.1(TP-1) WLAN1.50
E51_TX1: R5806.2 WLAN1.36
E51_TX2: R5812.2 R6517.1 TP5804.1(TP-1) WLAN1.30
EC_AGND: C2403.2 CE70.2 CE81.2 CE87.2 CE88.2 R2407.1 RE347.1 RE398.1 UE1.112
EC_MUTE#: R2708.1 RE433.1
EC_MUTE#_R: RE433.2 UE1.119
EC_SPI_CLK: RE413.2 UE1.32
EC_SPI_CS0#: RE410.1 UE1.27
EC_SPI_MISO: RE416.2 UE1.29
EC_SPI_MOSI: RE414.2 UE1.28
EC_WAKE#: RC391.1 UE1.35
EDP_AUX: C5212.2 LCD1.14 R5218.1
EDP_AUX#: C5209.2 LCD1.15 R5219.1
EDP_AUX_DN: C5209.1 UC1.E45
EDP_AUX_DP: C5212.1 UC1.F45
EDP_BKLT_CTRL: D5202.2 R5206.2 R5222.2
EDP_COMP: RC2.2 UC1.E52
EDP_HPD: RC1.2 RN5201.5 RN5203.6 UC1.L10
EDP_HPD_CONN: LCD1.11 RN5201.4
EDP_TX0: C5210.2 LCD1.18
EDP_TX0#: C5203.2 LCD1.17
EDP_TX0_DN: C5203.1 UC1.C47
EDP_TX0_DP: C5210.1 UC1.C46
EDP_TX1: C5213.2 LCD1.21
EDP_TX1#: C5211.2 LCD1.20
EDP_TX1_DN: C5211.1 UC1.D46
EDP_TX1_DP: C5213.1 UC1.C45
EDP_VDD_EN: D5201.2 UC1.U13
EDRAM_OPIO_RCOMP: RC90.1 UC1.H66
EMMC_RCOMP: RC4.1 UC1.AT1
EN_0.6VSP: PC203.1 PR202.2 PU200.7
EN_1.0V_VCCST_ON: CZ1703.1 DZ1703.2 RZ1701.2 UZ21.3
EN_1.2V: PC202.1 PR201.2 PU200.8
EN_1.8VALW: PC502.1 PR501.2 PR502.2 PU500.5
EN_2.5V: PC805.1 PR803.2 PU800.2
EN_3V: PR121.1 PU100.12
EN_5V: PR120.1 PU102.12
EN_+1.5VGPU: PC1404.1 PR1403.2 PR1404.1 PU1400.11
EN_+1VALW: PC304.1 PR301.2 PR302.1 PU300.11
EN_+VCCEOPIO: PC1204.1 PR1204.1 PR1205.1 PU1200.5
ENABLE_VGA: PR1116.2 PU1100.8
ENLDO_3V5V: PR102.1 PR103.1 PU100.11 PU102.11
EOPIO_RCOMP: RC91.1 UC1.H65
FAN1_DAC_1: FAN261.4 UE1.24
FAN1_TACH: CE75.1 EC2602.1 R2606.1 RE441.1 UE1.40
FAN1_TACH_C: FAN1.2 R2606.2
FAN_VCC1: C2603.1 C2604.1 D2601.1 EC2601.1 FAN1.1 FAN261.3
FB_1.2V: PC214.1 PR204.1 PR207.1 PU200.6
FB_1.8VALW: PC503.2 PR504.1 PR505.1 PU500.6
FB_+1.5VGPU: PC1409.2 PR1410.1 PR1411.1 PU1400.14
FB_+1VALW: PC309.2 PR309.1 PR310.1 PU300.14
FB_GND: RV158.1 UV1.AD20
FB_IA: PR645.2 PR648.2 PR650.1 PU602.17
FB_VDDC: RV159.1 UV1.AC20
FB_VDDCI: T222.1(TP-1) UV1.W1
FB_VSA: PR646.1 PR649.1 PR652.1 PU602.25
FBA_ZQ0: RV261.1 UV17.L8
FBA_ZQ1: RV262.1 UV18.L8
FBA_ZQ2: RV263.1 UV19.L8
FBA_ZQ3: RV264.1 UV20.L8
FCCM_GT: PR664.2 PR671.2 PU602.11
FCCM_IA: PR659.2 PU602.21
FCCM_VSA: PR679.2 PU602.29
FON#: FAN261.1 R2605.2
GPIO19_CTF: RV151.2 RV152.1 UV1.M2
GPIO28: RV21.2 UV1.R5
GPP_B23: RC365.1 UC1.AM7
GPP_C5: RC25.1 UC1.W1
GPU_B+: PC664.1 PC665.1 PC666.1 PC667.1 PC668.1 PC672.1 PC673.1 PC674.1 PC679.1 PC681.1 PC682.1 PC683.1 PC687.1 PC688.1 PC690.1 PC692.1 PC693.1 PJP602.1 PL606.1 PU604.6 PU604.11 PU605.6 PU605.11
GPU_PWR_LEVEL: RV260.1 UE1.21 UV1.T9
GPU_THM_INT: RV146.2 UV11.6
GPU_VID1: RV78.2 UV1.P8
GPU_VID3: RV77.2 UV1.N1
GT1N: PL605.2 PR670.1 PR673.1
GT1P: PL605.3 PR674.2 PR675.1
GT2N: PL604.2 PR666.1 PR677.2
GT2P: PL604.3 PR667.2 PR668.1
GT_SNUB1: PC678.1 PR676.2
GT_SNUB2: PC670.1 PR669.2
GT_SW1: PL605.4 PR676.1 PU605.8
GT_SW2: PL604.4 PR669.1 PU604.8
H_CATERR#: RC79.2 UC1.D63
H_CPU_SVIDALRT#: RC153.1 UC1.B63
H_CPUPWRGD: CC1101.1 T9.1(TP-1) UC1.A68
H_DRAMRST#: CD69.1 RD31.2 RD35.2 UC1.AT13
H_PROCHOT#: CE86.1 PC605.2 PQ2.6 PQ3.1 PQ721.1 PR678.1 PR777.1 RC83.2 RC84.1 UE6.4
H_PROCHOT#_R: RC84.2 UC1.C65
H_PROCHOT_EC: RE380.2 UE1.83 UE6.2
H_THERMTRIP#: RC80.2 T4946.1(TP-1) UC1.C63
H_VCCST_PWRGD: RC71.1 RC78.1 UC16.4
HDA_BIT_CLK: RC93.2 UC1.AY22
HDA_CODEC_BITCLK: CC27.1 EC2709.1 R2720.1 RC93.1
HDA_CODEC_RST#: R6515.1 RC95.1
HDA_CODEC_RST#_R: HDA27.11 R6515.2
HDA_CODEC_SDIN0: HDA27.8 R2718.2
HDA_CODEC_SDOUT: EC2708.1 R2719.1 RC94.1
HDA_CODEC_SYNC: HDA27.10 RC92.1
HDA_RST#: RC95.2 UC1.AW22
HDA_SDIN0: R2718.1 UC1.BA21
HDA_SDOUT: RC94.2 RC187.2 RC223.2 UC1.BB22
HDA_SYNC: RC92.2 UC1.BA22
HDD_DEVSLP: R5605.1 UC1.J1
HDD_DEVSLP_R: HDD1.5 R5605.2
HDMI_CLK: C5403.1 UC1.G56
HDMI_CLK#: C5402.1 UC1.F56
HDMI_CLK#_R: C5402.2 R5401.1 RN5403.5
HDMI_CLK#_R_C: JHDMI.12 R5401.2 R5414.1
HDMI_CLK_R: C5403.2 R5402.1 RN5403.6
HDMI_CLK_R_C: JHDMI.10 R5402.2 R5414.2
HDMI_CRT_DET: R5419.1 R5517.2 RC312.2 RC385.2 RC386.2
HDMI_CRT_N0: C5526.1 RE41.2 UC1.E55
HDMI_CRT_N1: C5525.1 RE39.2 UC1.E58
HDMI_CRT_P0: C5529.1 RE42.2 UC1.F55
HDMI_CRT_P1: C5530.1 RE40.2 UC1.F58
HDMI_DATA0: C5405.1 UC1.G53
HDMI_DATA0#: C5404.1 UC1.F53
HDMI_DATA0#_R: C5404.2 R5403.1 RN5403.7
HDMI_DATA0#_R_C: JHDMI.9 R5403.2 R5416.1
HDMI_DATA0_R: C5405.2 R5404.1 RN5403.8
HDMI_DATA0_R_C: JHDMI.7 R5404.2 R5416.2
HDMI_DATA1: C5406.1 RE40.1
HDMI_DATA1#: C5409.1 RE39.1
HDMI_DATA1#_R: C5409.2 R5407.1 RN5402.5
HDMI_DATA1#_R_C: JHDMI.6 R5407.2 R5417.1
HDMI_DATA1_R: C5406.2 R5408.1 RN5402.6
HDMI_DATA1_R_C: JHDMI.4 R5408.2 R5417.2
HDMI_DATA2: C5408.1 RE42.1
HDMI_DATA2#: C5407.1 RE41.1
HDMI_DATA2#_R: C5407.2 R5405.1 RN5402.7
HDMI_DATA2#_R_C: JHDMI.3 R5405.2 R5415.1
HDMI_DATA2_R: C5408.2 R5406.1 RN5402.8
HDMI_DATA2_R_C: JHDMI.1 R5406.2 R5415.2
HDMI_HPD_B: Q5401.2 R5411.2
HDMI_HPD_E: Q5401.3 R5412.1 R5419.2
HDMI_PLL_GND: Q5403.1 R5418.2 RN5402.1 RN5402.2 RN5402.3 RN5402.4 RN5403.1 RN5403.2 RN5403.3 RN5403.4
HOST_DEBUG_TX: JDEG1.8 R5806.1 R5812.1 RE73.2 UE1.81
HPD_HDMI_CON: JHDMI.19 R5410.1 R5411.1
I2C_SCL_TP: Q6501.1 RZ21.2 UC1.U6
I2C_SCL_TP_Q: Q6501.6 R6506.2 TPAD1.3
I2C_SDA_TP: Q6501.4 RZ20.2 UC1.U7
I2C_SDA_TP_Q: Q6501.3 R6508.2 TPAD1.2
I_ADP: PC748.1 PR774.1 RE399.2
I_ADP_R: CE87.1 RE399.1 UE1.110
I_BATT: PC749.2 PR775.1 RE400.2
I_BATT_R_C: CE88.1 RE400.1 RE443.1
I_SYS: PR682.1 PR727.1 PU703.8 RE442.1
ICSP_CLK: RE420.1 UE1.101
ICSP_CLR: RE421.1 UE1.87
ICSP_DAT: RE423.1 UE1.102
ILMT_+1.5VGPU: PR1406.2 PR1407.1 PU1400.13
ILMT_+1VALW: PR304.2 PR305.1 PU300.13
IMON_IA: PC625.2 PR629.2 PU602.14
IMON_VGA: PC1117.2 PR1117.2 PU1100.10
IMON_VSA: PC643.1 PR651.1 PU602.23
IMVP_VR_ON: CC10.1 PR655.1 PR658.1 RC345.2
INT_TP#: Q6204.3 R6203.1 TPAD1.5
INTRUDER#: RC69.1 UC1.AP16
IR_CAM_DETECT#: LCD1.34 RC293.2 UC1.P4
IR_GND: LCD1.25 LCD1.26 R5201.1
ISEN1_GT: PC635.2 PR615.2 PR675.2 PR677.1 PU602.9
ISEN1_VGA: PC1120.2 PR1124.1 PU1100.13
ISEN2_GT: PC638.2 PR634.2 PR668.2 PR670.2 PU602.10
ISEN2_VGA: PC1119.2 PR1104.1 PU1100.12
ISOLATE#: LOM30.20 R3015.1 R6518.2
ISUMN_GT: PC624.2 PC626.2 PC635.1 PC638.1 PC641.1 PH602.2 PR632.1 PR633.2 PR638.1 PR666.2 PR673.2
ISUMN_IA: PC642.2 PC645.1 PC646.2 PH605.2 PL603.2 PR640.2 PR644.2 PR656.2
ISUMN_VSA: PC633.2 PC637.2 PC644.1 PH604.2 PL601.2 PR636.2 PR641.2 PR643.1
ISUMP_GT: PC624.1 PC626.1 PR628.1 PR633.1 PR637.1 PR667.1 PR674.1 PU602.7
ISUMP_IA: PC642.1 PC646.1 PR653.1 PR656.1 PR657.1 PR661.2 PU602.19
ISUMP_VSA: PC633.1 PC637.1 PR624.2 PR642.1 PR643.2 PR654.1 PU602.27
JACK_PLUG: AFTP6307.1(TP-1) CN6301.2 R2923.1
JDREF: HDA27.15 R2707.1
JTAG_CLK: JDEG1.4 RE422.2
JTAG_TCK: RP34.7 UV1.L3
JTAG_TDI: JDEG1.2 RE420.2
JTAG_TDI_GPU: RP34.6 UV1.L5
JTAG_TDO: JDEG1.5 RE423.2
JTAG_TDO_GPU: T86.1(TP-1) UV1.K4
JTAG_TMS: JDEG1.3 RE421.2
JTAG_TMS_GPU: RP34.8 UV1.L1
JTAG_TRSTB: RP34.5 UV1.L6
KB_BL_CTRL#: EC6207.1 KB_BL1.4 Q6202.1
KB_DET#: KB1.30 RC288.1 UC1.BB7
KB_LED_BL_DET: R6206.1 R6207.1 UC1.W8
KB_LED_DET_C: KB_BL1.2 R6206.2
KB_LED_PWM: Q6202.2 UE1.44
KBC_PWRBTN#_C: AFTP6101.1(TP-1) EC6101.1 ED6101.1 G6101.2 G6102.2 PWR1.2 R6102.2
KSI0: KB1.22 RPE2.4 UE1.98
KSI1: KB1.24 RPE2.3 UE1.99
KSI2: KB1.26 RPE2.2 UE1.6
KSI3: KB1.23 RPE2.1 UE1.7
KSI4: KB1.27 RPE3.4 UE1.104
KSI5: KB1.25 RPE3.3 UE1.105
KSI6: KB1.28 RPE3.2 UE1.107
KSI7: KB1.29 RPE3.1 UE1.108
KSO0: KB1.13 RPE4.8 UE1.2
KSO1: KB1.15 RPE4.7 UE1.14
KSO2: KB1.14 RPE4.6 UE1.15
KSO3: KB1.16 RPE4.5 UE1.16
KSO4: KB1.20 RPE5.8 UE1.37
KSO5: KB1.21 RPE5.7 UE1.38
KSO6: KB1.18 RPE5.6 UE1.39
KSO7: KB1.19 RPE5.5 UE1.50
KSO8: KB1.17 RPE7.8 UE1.46
KSO9: KB1.7 RE389.1 UE1.68
KSO10: KB1.5 RPE6.8 UE1.72
KSO11: KB1.6 RPE6.7 UE1.74
KSO12: KB1.12 RPE6.6 UE1.75
KSO13: KB1.9 RPE6.5 UE1.76
KSO14: KB1.8 RPE7.6 UE1.77
KSO15: KB1.10 RPE7.7 UE1.86
KSO16: KB1.11 RPE7.5 UE1.92
L_BKLT_CTRL: R5206.1 UC1.R11
L_BKLT_EN_EC: RC390.2 UC1.R12 UE1.91
LAN_EN: Q3001.2 R3023.1 UE1.3
LAN_ENABLE_R_C: Q3001.1 R3021.2 R3022.1
LAN_MDI0N: EC3102.2 EU3101.2 EU3101.8 LOM30.2 XF3101.5
LAN_MDI0P: EC3101.2 EU3101.1 EU3101.9 LOM30.1 XF3101.6
LAN_MDI1N: EC3104.2 EU3101.5 EU3101.6 LOM30.5 XF3101.1
LAN_MDI1P: EC3103.2 EU3101.4 EU3101.7 LOM30.4 XF3101.2
LAN_MDI2N: EC3106.2 EU3102.2 EU3102.8 LOM30.7 XF3102.2
LAN_MDI2P: EC3105.2 EU3102.1 EU3102.9 LOM30.6 XF3102.1
LAN_MDI3N: EC3108.2 EU3102.5 EU3102.6 LOM30.10 XF3102.6
LAN_MDI3P: EC3107.2 EU3102.4 EU3102.7 LOM30.9 XF3102.5
LAN_TXN_C_PCH_RXN6: C3016.1 LOM30.18
LAN_TXP_C_PCH_RXP6: C3014.1 LOM30.17
LAN_WAKE#: RC70.2 RC391.2 UC1.AM15
LANGND: C3101.2 RJ45.10
LANXIN: C3001.1 LOM30.28 X3001.1
LANXOUT: C3011.1 LOM30.29 X3001.3
LCD_BRIGHTNESS: LCD1.23 RN5201.2
LCD_TST: D5202.3 R6523.1 RN5201.6 UE1.26
LCD_TST_C: LCD1.12 RN5201.3
LCD_VCC_TEST_EN: R6524.1 RE443.2 UE1.114
LCDVDD: R5211.2 U5201.1
LCDVDD_EN: D5201.1 R5202.2 U5201.4
LCDVDD_LCD: C5201.1 C5206.2 LCD1.6 LCD1.7 LCD1.8 R5211.1
LDO1_CAP: C2702.2 HDA27.27 R2711.2
LDO2_CAP: C2712.2 HDA27.39
LDO3_CAP: C2718.1 HDA27.7
LDO_+1.5VGPU: PC1406.1 PU1400.16 PU1400.17
LDO_+1VALW: PC306.1 PU300.16 PU300.17
LDO_EN: R5502.1 R5512.2 U5502.21
LED0: LOM30.27 TP3003.1(TP-1)
LED1: LOM30.26 TP3002.1(TP-1)
LED2: LOM30.25 TP3001.1(TP-1)
LG1_VGA: PQ1105.4 PQ1106.4 PU1100.24
LG2_VGA: PQ1102.4 PQ1103.4 PU1100.27
LG_1.2V: PQ201.8 PU200.15
LGATE_CHG: PQ708.4 PU703.21
LID_CL_SIO#: CE8.1 RE25.2 RE26.2 UE1.41
LID_CLOSE#: D5203.1 R6109.1 RE26.1
LID_CLOSE#_C: EC6105.1 PWR1.3 R6109.2
LINE1-L_C: C2907.2 R2922.1
LINE1-L_R: C2908.2 R2921.1
LINE1_L: C2907.1 HDA27.22
LINE1_R: C2908.1 HDA27.21
LINE1_VREFO_L: HDA27.31 R2912.1
LINE1_VREFO_R: HDA27.30 R2913.1
LOM_TCT: C3106.1 XF3101.3 XF3101.4 XF3102.3 XF3102.4
LP#_+VCCEOPIO: PR1201.1 PU1200.6
LPC_LAD0: DB1.8 UC1.AY13 UE1.59
LPC_LAD1: DB1.7 UC1.BA13 UE1.60
LPC_LAD2: DB1.6 UC1.BB13 UE1.61
LPC_LAD3: DB1.5 UC1.AY12 UE1.62
LPC_LFRAME#: DB1.4 UC1.BA12 UE1.58
LPSS_UART2_CTS#: RC382.1 UC1.AD4
LX1_VGA: PC1118.2 PL1103.4 PQ1104.1 PQ1104.2 PQ1104.3 PQ1105.5 PQ1106.5 PR1125.1 PU1100.23
LX2_VGA: PC1108.2 PL1102.4 PQ1101.1 PQ1101.2 PQ1101.3 PQ1102.5 PQ1103.5 PR1107.1 PU1100.28
LX_1.2V: PC200.2 PL200.2 PQ201.9 PR203.1 PU200.16
LX_1.8VALW: PL501.1 PR506.1 PU500.2 PU500.3
LX_3V: PC102.2 PL100.1 PR106.1 PU100.6 PU100.19 PU100.20
LX_5V: PC114.2 PL101.1 PR112.1 PU102.6 PU102.19 PU102.20
LX_+1.5VGPU: PC1407.2 PL1401.1 PR1408.1 PU1400.6 PU1400.19 PU1400.20
LX_+1VALW: PC307.2 PL301.1 PR307.1 PU300.6 PU300.19 PU300.20
MAA_0: UV1.K17 UV17.N3 UV18.N3 UV19.N3 UV20.N3
MAA_1: UV1.J20 UV17.P7 UV18.P7 UV19.P7 UV20.P7
MAA_2: UV1.H23 UV17.P3 UV18.P3 UV19.P3 UV20.P3
MAA_3: UV1.G23 UV17.N2 UV18.N2 UV19.N2 UV20.N2
MAA_4: UV1.G24 UV17.P8 UV18.P8 UV19.P8 UV20.P8
MAA_5: UV1.H24 UV17.P2 UV18.P2 UV19.P2 UV20.P2
MAA_6: UV1.J19 UV17.R8 UV18.R8 UV19.R8 UV20.R8
MAA_7: UV1.K19 UV17.R2 UV18.R2 UV19.R2 UV20.R2
MAA_8: UV1.J14 UV17.T8 UV18.T8 UV19.T8 UV20.T8
MAA_9: UV1.K14 UV17.R3 UV18.R3 UV19.R3 UV20.R3
MAA_10: UV1.J11 UV17.L7 UV18.L7 UV19.L7 UV20.L7
MAA_11: UV1.J13 UV17.R7 UV18.R7 UV19.R7 UV20.R7
MAA_12: UV1.H11 UV17.N7 UV18.N7 UV19.N7 UV20.N7
MAA_13: UV1.G20 UV17.T3 UV18.T3 UV19.T3 UV20.T3
MAA_14: UV1.G14 UV17.T7 UV18.T7 UV19.T7 UV20.T7
MAA_15: UV1.L17 UV17.M7 UV18.M7 UV19.M7 UV20.M7
MAA_BA_0: UV1.J16 UV17.M2 UV18.M2 UV19.M2 UV20.M2
MAA_BA_1: UV1.L15 UV17.N8 UV18.N8 UV19.N8 UV20.N8
MAA_BA_2: UV1.G11 UV17.M3 UV18.M3 UV19.M3 UV20.M3
MCT: C3101.1 R3101.1 R3102.1 R3103.1 R3104.1
MCT0: R3104.2 XF3102.9
MCT1: R3101.2 XF3102.10
MCT2: R3103.2 XF3101.10
MCT3: R3102.2 XF3101.9
MDO0+: RJ45.1 XF3101.7
MDO0-: RJ45.2 XF3101.8
MDO1+: RJ45.3 XF3101.11
MDO1-: RJ45.6 XF3101.12
MDO2+: RJ45.4 XF3102.12
MDO2-: RJ45.5 XF3102.11
MDO3+: RJ45.7 XF3102.8
MDO3-: RJ45.8 XF3102.7
ME_FWP_EC: RC223.1 RE357.1 UE1.80
ME_SUS_PWR_ACK: RC74.2 UC1.AR13 UE1.42
MEC_XTAL1: C5225.1 RE366.2 Y1.1
MEC_XTAL1_R: RE366.1 UE1.123
MEC_XTAL2: C5226.1 R6520.2 UE1.125 Y1.2
MEM_CALRP0: RV39.2 UV1.K25
MIC2_VREFO: HDA27.29 RE35.1 RE36.1
MIC_CAP: C2713.1 HDA27.19
MODEL_ID: C2403.1 R2407.2 R2446.2 UE1.109
MONO_PC_BEEP_R: HDA27.16 R6516.1
MSCLK: JDEG1.6 RE72.2
MSDATA: JDEG1.7 RE75.2
NCT7718_DXN: C2606.2 C2607.2 Q2603.3 THM26.3
NCT7718_DXP: C2606.1 C2607.1 Q2603.1 Q2603.2 THM26.2
NRB_BIT: RC186.2 UC1.AR7
NTC_IA: PR635.2 PU602.15
OCP_L: PR1112.2 PU1100.4 RV90.2 RV91.1
ODD_PWR_5V: C5610.1 ODD1.10 ODD1.11 ODD1.12 ODD1.13 ODD1.14 ODD1.15 R5603.2 U5601.6 U5601.7 U5601.8
ODTA0: UV1.L18 UV17.K1 UV18.K1
ODTA1: UV1.K16 UV19.K1 UV20.K1
ONE_DIMM#: RC267.2 RC268.1 UC1.M2
PANEL_BKEN_EC: RN5201.8 UE1.117
PANEL_SIZE_ID: R5208.2 R5209.1 R5210.2 UC1.AP13
PANEL_SIZE_ID_CONN: LCD1.27 R5210.1
PBAT_CHG_SMBCLK: PD2.3 PR18.2 PR770.1 RE425.1 UE1.9
PBAT_CHG_SMBDAT: PD2.2 PR20.2 PR769.1 RE424.1 UE1.8
PBAT_PRES#: CE76.1 PC14.1 PC753.2 PD3.2 PR15.2 PR16.1 PR756.1 PR764.1 UE1.97
PCC_GPIO_6: CVT90.2 RV90.1 UV1.T8
PCH_BATLOW#: RC72.1 UC1.AU13
PCH_DPB_AUXN: C5528.1 RC181.2 UC1.G50
PCH_DPB_AUXP: C5527.1 RC182.2 UC1.F50
PCH_DPC_AUXN_U: C5528.2 U5502.27
PCH_DPC_AUXP_U: C5527.2 U5502.26
PCH_DPC_N0_U: C5526.2 U5502.30
PCH_DPC_N1_U: C5525.2 U5502.32
PCH_DPC_P0_U: C5529.2 U5502.29
PCH_DPC_P1_U: C5530.2 U5502.31
PCH_DPWROK: RC216.2 UC1.BB20
PCH_HDMI_CLK: Q5402.4 RC175.1 UC1.L13
PCH_HDMI_DATA: Q5402.1 RC178.1 UC1.L12
PCH_JTAG_TCK1: RC348.1 T43.1(TP-1) UC1.B56
PCH_PCIE_WAKE#: RC395.2 UC1.BB15
PCH_PLTRST#: UC1.AN10 UC7.1 UC7.2
PCH_PLTRST#_EC: CE72.1 DB1.3 R3016.1 R5212.2 R5807.1 RC65.1 UC7.4 UE1.56 UV2.1
PCH_POPIRCOMP: RC89.1 UC1.AU16
PCH_RSMRST#: RE355.1 UE1.88 UZ6.1
PCH_RSMRST#_Q: RC75.2 RC158.1 RC216.1 UC1.AY17 UZ6.4
PCH_RTCRST#: CC25.1 CMOS1.1 Q1901.1 RC57.1 UC1.AM16
PCH_RTCX1: CC23.1 RC54.2 UC1.AM18 YC2.1
PCH_RTCX2: CC26.1 RC54.1 UC1.AM20 YC2.2
PCH_SMB_ALERT#: RC23.1 UC1.R10
PCH_SMBCLK: JDIMM1.253 JDIMM2.253 QC2.1 RN20.2 U5502.2
PCH_SMBDATA: JDIMM1.254 JDIMM2.254 QC2.4 RN19.2 U5502.3
PCH_SPI_CLK_0_R: RC29.2 RC319.2 RC332.2 RE413.1
PCH_SPI_CLK_0_R3: RC332.1 UC5.6
PCH_SPI_CLK_R1: RC319.1 UC1.AV2
PCH_SPI_CS#0_R1: RC37.1 RC339.2 RE410.2 UC1.AU3
PCH_SPI_CS#0_R2: RC37.2 UC5.1
PCH_SPI_D0_0_R: RC318.2 RC333.2 RE414.1
PCH_SPI_D0_0_R3: RC333.1 UC5.5
PCH_SPI_D0_R1: RC318.1 RC355.2 UC1.AV3
PCH_SPI_D1_0_R: RC317.2 RC329.1 RE416.1
PCH_SPI_D1_0_R3: RC329.2 UC5.2
PCH_SPI_D1_R1: RC317.1 UC1.AW3
PCH_SPI_D2_0_R: RC327.2 RC330.1
PCH_SPI_D2_0_R3: RC330.2 UC5.3
PCH_SPI_D2_R1: RC30.2 RC327.1 RC354.2 UC1.AW2
PCH_SPI_D3_0_R: RC320.2 RC331.2
PCH_SPI_D3_0_R3: RC331.1 UC5.7
PCH_SPI_D3_R1: RC31.2 RC320.1 UC1.AU4
PCI_CLK_LPC1: RC18.1 RC22.1 UC1.AY9
PCIE_CALR_RX: RV3.1 UV1.AA22
PCIE_CALR_TX: RV1.1 UV1.Y22
PCIE_PRX_LANTX_N6: C3016.2 UC1.G18
PCIE_PRX_LANTX_P6: C3014.2 UC1.F18
PCIE_PRX_WLANTX_N5: R5808.2 UC1.F16
PCIE_PRX_WLANTX_N5_R: R5808.1 WLAN1.35
PCIE_PRX_WLANTX_P5: R5811.2 UC1.E16
PCIE_PRX_WLANTX_P5_R: R5811.1 WLAN1.33
PCIE_PTX_LANRX_N6: C6206.2 UC1.D20
PCIE_PTX_LANRX_N6_C: C6206.1 LOM30.14
PCIE_PTX_LANRX_P6: C6205.2 UC1.C20
PCIE_PTX_LANRX_P6_C: C6205.1 LOM30.13
PCIE_PTX_WLANRX_N5: CV310.2 WLAN1.29
PCIE_PTX_WLANRX_N5_C: CV310.1 UC1.C19
PCIE_PTX_WLANRX_P5: CV311.2 WLAN1.27
PCIE_PTX_WLANRX_P5_C: CV311.1 UC1.D19
PCIE_RCOMPN: RC45.1 UC1.F5
PCIE_RCOMPP: RC45.2 UC1.E5
PCIE_WAKE#: LOM30.21 RC395.1 RE354.2 UE1.4
PD#: HDA27.47 R2708.2 R6512.2
PECI_EC: DE8.1 RE353.2 UC1.A54
PECI_MEC1404: RE353.1 UE1.94
PEG_CLKREQ#: RC189.2 RV153.1 UC1.AR10
PEG_CLKREQ#_G: RV153.2 UV1.N7
PEG_GTX_C_HRX_N0: CV2.1 UC1.G13
PEG_GTX_C_HRX_N1: CV4.1 UC1.F11
PEG_GTX_C_HRX_N2: CV6.1 UC1.G16
PEG_GTX_C_HRX_N3: CV8.1 UC1.F15
PEG_GTX_C_HRX_P0: CV1.1 UC1.H13
PEG_GTX_C_HRX_P1: CV3.1 UC1.G11
PEG_GTX_C_HRX_P2: CV5.1 UC1.H16
PEG_GTX_C_HRX_P3: CV7.1 UC1.G15
PEG_GTX_HRX_N0: CV2.2 UV1.AG31
PEG_GTX_HRX_N1: CV4.2 UV1.AF28
PEG_GTX_HRX_N2: CV6.2 UV1.AF26
PEG_GTX_HRX_N3: CV8.2 UV1.AD26
PEG_GTX_HRX_P0: CV1.2 UV1.AH30
PEG_GTX_HRX_P1: CV3.2 UV1.AG29
PEG_GTX_HRX_P2: CV5.2 UV1.AF27
PEG_GTX_HRX_P3: CV7.2 UV1.AD27
PEG_HTX_C_GRX_N0: CV306.2 UC1.A17
PEG_HTX_C_GRX_N1: CV305.2 UC1.C16
PEG_HTX_C_GRX_N2: CV309.2 UC1.C17
PEG_HTX_C_GRX_N3: CV304.2 UC1.A19
PEG_HTX_C_GRX_P0: CV312.2 UC1.B17
PEG_HTX_C_GRX_P1: CV308.2 UC1.D16
PEG_HTX_C_GRX_P2: CV307.2 UC1.D17
PEG_HTX_C_GRX_P3: CV313.2 UC1.B19
PEG_HTX_GRX_N0: CV306.1 UV1.AE31
PEG_HTX_GRX_N1: CV305.1 UV1.AD28
PEG_HTX_GRX_N2: CV309.1 UV1.AC31
PEG_HTX_GRX_N3: CV304.1 UV1.AB28
PEG_HTX_GRX_P0: CV312.1 UV1.AF30
PEG_HTX_GRX_P1: CV308.1 UV1.AE29
PEG_HTX_GRX_P2: CV307.1 UV1.AD30
PEG_HTX_GRX_P3: CV313.1 UV1.AC29
PHASE_CHG: PC721.2 PL700.1 PQ704.1 PQ704.2 PQ704.3 PQ708.5 PR766.1 PU703.22
PIRQA#: RC245.2 UC1.BB11
PLL_ANALOG_IN: T221.1(TP-1) UV1.AA1
PLL_ANALOG_OUT: RV83.1 UV1.AA3
PLT_RST#_LAN: LOM30.19 R3016.2
PLT_RST_NGFF#: R5807.2 WLAN1.44
PLT_RST_VGA#: RV4.1 UE1.47 UV1.AL27 UV2.4
PM_LAN_ENABLE_R: C3015.2 Q3004.2 R3022.2
PM_ZVM#: PR1201.2 UC1.AR56
PME#: T115.1(TP-1) UC1.AU11
POK: CC266.1 PR13.1 PR107.2 PR113.2 PR301.1 PR501.1 PU100.9 PU102.9 RC220.1 UZ6.2
POL1_SDA: R5508.2 R5509.1 U5502.22 U5504.5
POL2_SCL: R5515.1 R5516.2 U5502.23 U5504.6
POWER_SW#_MB: R6102.1 RE428.2 SW1.2
POWER_SW_IN#: CE12.1 RE31.2 RE428.1 UE1.127
PROG: PR753.2 PU703.9
PROH: PQ720.2 PR777.2 PR781.2 PU703.5
PS_0: CV29.1 RV8.2 RV9.1 UV1.AC19
PS_1: CV28.1 RV11.2 RV12.1 UV1.AD19
PS_2: CV11.1 RV13.1 RV28.2 UV1.AE17
PS_3: CV15.1 RV15.2 RV16.1 UV1.AE20
PS_ID: PD5.1 PR3.1 PR4.2 UE1.36
PSID: PJPDC1.3 PL2.2
PSID-1: PQ5.2 PR6.1 PR9.2
PSID-2: PQ5.1 PQ6.2 PR8.2 PR11.1
PSID-3: PQ6.3 PR4.1
PTP_DIS#: D3801.1 RE434.1
PTP_DIS#_R: RE434.2 UE1.90
PWM1_GT: PR680.1 PU602.12 PU605.13
PWM2_GT: PR681.1 PU602.13 PU604.13
PWM_IA: PR662.1 PU602.22 PU603.13
PWM_VSA: PU602.30 PU606.3
PWRGD_VGA: PR1119.2 PR1122.1 PU1100.9 PU1100.20
PX_EN: T218.1(TP-1) UV1.AB16
QSA#_0: UV1.H27 UV17.B7
QSA#_1: UV1.A27 UV18.B7
QSA#_2: UV1.C23 UV18.G3
QSA#_3: UV1.C19 UV17.G3
QSA#_4: UV1.C15 UV20.G3
QSA#_5: UV1.E9 UV20.B7
QSA#_6: UV1.C5 UV19.G3
QSA#_7: UV1.H4 UV19.B7
QSA_0: UV1.H28 UV17.C7
QSA_1: UV1.C27 UV18.C7
QSA_2: UV1.A23 UV18.F3
QSA_3: UV1.E19 UV17.F3
QSA_4: UV1.E15 UV20.F3
QSA_5: UV1.D10 UV20.C7
QSA_6: UV1.D6 UV19.F3
QSA_7: UV1.G5 UV19.C7
RASA0#: UV1.G22 UV17.J3 UV18.J3
RASA1#: UV1.G17 UV19.J3 UV20.J3
REGOUT: C3002.1 L3001.1 LOM30.24 R3001.1
RESET_OUT#: CE82.1 RE367.1 UC1.BA20 UE1.73
RING2: HDA27.17 R2906.2 RE35.2
RING2_R: AFTP6305.1(TP-1) CN6301.3 CN6301.4 EC2905.1 R2906.1
RREF: R3203.1 U3201.1
RRX: R5505.1 U5502.28
RSET: LOM30.31 R3032.2
RTC_DET#: Q2505.1 RC384.1 UC1.P1
RTC_PWR: D2501.3 Q2505.2 R2502.1 R2504.1
RTCRST_ON: Q1901.2 R1902.1 UE1.31
RUNPWROK: RE438.1 UE1.48
SA_SNUB: PC622.1 PR627.2
SA_SW: PL601.4 PQ601.9 PR619.2 PR627.1 PU606.8
SATA3_PRX_HDDTX_N0: C5616.1 UC1.F20
SATA3_PRX_HDDTX_P0: C5615.1 UC1.E20
SATA3_PTX_HDDRX_N0: C5603.2 UC1.B21
SATA3_PTX_HDDRX_P0: C5602.2 UC1.A21
SATA_LED#: Q6105.3 R2405.1 RC248.1 UC1.H1
SATA_LED_EN: Q6105.2 R2405.2 R6110.2 UE1.30
SATA_ODD_DA#: R5602.2 RC356.2 UC1.J3
SATA_ODD_DA#_C: ODD1.17 R5602.1
SATA_ODD_PRSNT#: ODD1.8 R5604.1 RC246.1 UC1.H3
SATA_ODD_PWRGT: R5607.2 U5601.4 UC1.W4
SATA_PRX_ODDTX_N1: C5607.2 UC1.G21
SATA_PRX_ODDTX_P1: C5608.2 UC1.F21
SATA_PTX_ODDRX_N1: C5611.2 UC1.D21
SATA_PTX_ODDRX_P1: C5612.2 UC1.C21
SATA_RXN0_R: C5616.2 EU5602.4 EU5602.7 HDD1.8
SATA_RXN2_R: C5607.1 ODD1.5
SATA_RXP0_R: C5615.2 EU5602.5 EU5602.6 HDD1.7
SATA_RXP2_R: C5608.1 ODD1.6
SATA_TXN0_R: C5603.1 EU5602.2 EU5602.8 HDD1.10
SATA_TXN2_R: C5611.1 ODD1.3
SATA_TXP0_R: C5602.1 EU5602.1 EU5602.9 HDD1.11
SATA_TXP2_R: C5612.1 ODD1.2
SD_CD#: R3301.1 U3201.13
SD_CD_R#: AFTP3304.1(TP-1) CARD1.10 EC3305.1 R3301.2
SD_CLK: AFTP3303.1(TP-1) CARD1.5 EC3201.1 R3201.2 R6522.1
SD_CLK_5170: R3201.1 U3201.15
SD_CLK_CONN: EC9758.1 R6522.2
SD_CMD: AFTP3302.1(TP-1) CARD1.2 EC3304.1 U3201.18
SD_D0: AFTP3306.1(TP-1) CARD1.7 EC3306.1 U3201.11
SD_D1: AFTP3307.1(TP-1) CARD1.8 EC3301.1 U3201.10
SD_D2: AFTP3308.1(TP-1) CARD1.9 EC3302.1 U3201.21
SD_D3: AFTP3309.1(TP-1) CARD1.1 EC3303.1 U3201.20
SD_RCOMP: RC96.1 UC1.AB7
SD_WP: AFTP3305.1(TP-1) CARD1.11 EC3307.1 R3202.1
SD_WP_5170: R3202.2 U3201.8
SDREFG: C3206.1 U3201.6
SERIRQ: RC21.2 UC1.AY11 UE1.55
SIO_EXT_SCI#: RC237.1 UC1.J2 UE1.66
SIO_EXT_SMI#: RC239.2 UC1.L6 UE1.10
SIO_EXT_WAKE#: RC387.1 UC1.AD3 UE1.116
SIO_PWRBTN#: RC1102.2 UC1.BA15 UE1.52
SIO_RCIN#: RC13.2 UC1.AW13 UE1.53
SIO_SLP_A#: T4937.1(TP-1) UC1.AN16
SIO_SLP_LAN#: RC68.1 T4938.1(TP-1) UC1.AW15
SIO_SLP_S0#: UC1.AT11 UC15.2
SIO_SLP_S3#: CE74.1 DZ5.1 DZ1702.1 PR1204.2 RC1103.1 RZ75.1 UC1.AP15 UC15.1 UE1.70 UZ2.3 UZ2.5
SIO_SLP_S4#: DZ1703.1 PR201.1 PR803.1 RZ1701.1 UC1.BA16 UE1.67
SIO_SLP_S5#: PQ711.2 UC1.AY16
SIO_SLP_SUS#: RC76.2 RC1107.1 UE1.96
SIO_SLP_SUS#_R: RC76.1 UC1.AN15
SIO_SLP_WLAN#: T4945.1(TP-1) UC1.BB17
SLEEVE: HDA27.18 R2911.2 RE36.2
SLEEVE_R: AFTP6310.1(TP-1) CN6301.5 CN6301.6 EC2906.1 R2911.1
SM_RCOMP0: RC5.1 UC1.AR18
SM_RCOMP1: RC6.1 UC1.AT18
SM_RCOMP2: RC7.1 UC1.AU18
SMBCLK: QC2.6 RC12.1 UC1.R7
SMBDATA: QC2.3 RC14.1 UC1.R8
SML0_SMBCLK: RC19.1 UC1.R9
SML0_SMBDATA: RC20.1 UC1.W2
SML1CLK: Q2601.3 QV1.6 RC15.1 RE427.1 UC1.W3 UE1.12
SML1DATA: Q2601.6 QV1.3 RC17.1 RE426.1 UC1.V3 UE1.11
SNUB_+1.5VGPU: PC1408.1 PR1408.2
SNUB_+1VALW: PC308.1 PR307.2
SOC_XDP_TDI: RC351.1 T45.1(TP-1) UC1.D59 UC1.D60
SOC_XDP_TDO: RC349.1 T41.1(TP-1) UC1.A56 UC1.A61
SOC_XDP_TMS: RC350.1 T44.1(TP-1) UC1.C59 UC1.C60
SOC_XDP_TRST#: T46.1(TP-1) UC1.B59 UC1.C61
SPKR: D2701.3 RC183.2 UC1.AW5
SRTCRST#: CC24.1 RC56.1 UC1.AN18
SUS_STAT#/LPCPD#: RC369.1 UC1.BA11
SUSCLK: R5805.1 R6520.1 RC48.1 UC1.BA17
SUSCLK_R: R5805.2 WLAN1.42
SVI2_SVC: PU1100.3 RV78.1 RV84.1 RV89.2 RV157.2
SVI2_SVC_R: RV157.1 UV1.AJ11
SVI2_SVD: PU1100.5 RV77.1 RV87.1 RV88.2 RV155.2
SVI2_SVD_R: RV155.1 UV1.AK12
SVI2_SVT: PU1100.7 RV156.2
SVI2_SVT_R: RV156.1 UV1.AL11
SW_VCCEOPIO: PC1201.2 PL1201.1 PR1208.1 PU1200.8
SYS_PWROK: UC1.B6 UE1.89
SYS_RESET#: RC291.2 UC1.B5
T_CRIT#: R2604.2 THM26.4
TEST_PG: RV2.2 UV1.N10
TESTEN: RV17.2 RV154.2 UV1.K7
THM_SML1_CLK: C2608.1 Q2601.4 RE432.2 THM26.8
THM_SML1_DATA: C2609.1 Q2601.1 RE32.2 THM26.7
TON_1.2V: PR208.2 PU200.9
TOUCH_SCREEN_PD#: D5203.2 R5205.2 RC277.2 RC394.1
TOUCH_SCREEN_PD#_R: RC394.2 UC1.A7
TOUCHPAD_INTR#: DZ3.1 Q6204.1 RE440.1 UE1.33
TOUCHPAD_INTR#_D: DZ3.2 RC272.2 UC1.BA5
TP_LOCK#: D3801.2 R6505.2 TPAD1.6
TP_ON#_GATE: C6204.2 Q2405.2 Q6203.2 R6519.2
TP_PW_EN#: R6519.1 UE1.49
TP_RESET: C5214.1 LCD1.38 R5212.1
TP_RS: C5208.1 LCD1.39 R5205.1
TP_VDD: C6201.1 Q6203.1 Q6204.2 R6203.2 R6209.1 R6211.2 R6212.2 R6505.1 R6506.1 R6508.1 RZ18.1 RZ19.1 TPAD1.1
TPAN_VDD: F5203.2 LCD1.40 R5232.1
TPAN_VDD_F: F5203.1 R5230.2 R5231.2 R5232.2
UART_2_CRXD_DTXD: JWDB1.2 RC62.1 UC1.AD1
UART_2_CTXD_DRXD: JWDB1.3 RC63.1 UC1.AD2
UG1_VGA: PQ1104.4 PU1100.22
UG2_VGA: PQ1101.4 PU1100.29
UG_1.2V: PQ201.1 PU200.17
UGATE_CHG: PR761.1 PU703.23
USB2_ID: RC366.1 UC1.AG3
USB2_VBUSSENSE: RC393.1 UC1.AG4
USB3_PRX_CTX_N0: TR3403.2 UC1.H8
USB3_PRX_CTX_N0_C: TR3403.1 U3402.1 U3402.9 USB1.5
USB3_PRX_CTX_P0: TR3403.3 UC1.G8
USB3_PRX_CTX_P0_C: TR3403.4 U3402.2 U3402.8 USB1.6
USB3_PTX_CRX_N0: C3403.1 UC1.C13
USB3_PTX_CRX_N0_C: TR3402.1 U3402.4 U3402.7 USB1.8
USB3_PTX_CRX_N0_R: C3403.2 TR3402.2
USB3_PTX_CRX_P0: C3404.1 UC1.D13
USB3_PTX_CRX_P0_C: TR3402.4 U3402.5 U3402.6 USB1.9
USB3_PTX_CRX_P0_R: C3404.2 TR3402.3
USB20_VCCA: AFTP6311.1(TP-1) C3515.1 C3517.1 C3518.1 CN6301.11 CN6301.12 CN6301.13 CN6301.14 CN6301.15 U3505.1
USB30_VCCC: AFTP3401.1(TP-1) C3507.1 C3508.1 C3512.1 C3513.1 TC3501.1 U3504.1 USB1.1
USB_CAMERA_EDP: LCD1.32 TR5209.4
USB_CAMERA_EDP#: LCD1.31 TR5209.1
USB_EN#: RE388.1 U3504.4 U3505.4 UE1.13
USB_OC#0_1: R3501.2 RPC3.3 U3504.3 UC1.A9
USB_OC#2_3: R3501.1 RPC3.2 U3505.3 UC1.C9
USB_OC#4_5: RPC3.1 UC1.D9
USB_OC#6_7: RPC3.4 UC1.B9
USB_PN1: TR3404.2 UC1.AB9
USB_PN1_C: EU3403.2 TR3404.1 USB1.2
USB_PN2: TR3405.3 UC1.AD6
USB_PN2_C: CN6301.22 TR3405.4
USB_PN3: TR3406.2 UC1.AH3
USB_PN3_C: CN6301.18 TR3406.1
USB_PN5: TR5209.2 UC1.AJ1
USB_PN6: R3204.1 UC1.AF6
USB_PN6_R: R3204.2 U3201.2
USB_PN7: R5203.2 UC1.AH1
USB_PN7_TPNL: DA6.2 LCD1.36 R5203.1
USB_PN8: R5801.2 UC1.AF8
USB_PN8_R: R5801.1 WLAN1.5
USB_PP1: TR3404.3 UC1.AB10
USB_PP1_C: EU3403.3 TR3404.4 USB1.3
USB_PP2: TR3405.2 UC1.AD7
USB_PP2_C: CN6301.21 TR3405.1
USB_PP3: TR3406.3 UC1.AJ3
USB_PP3_C: CN6301.19 TR3406.4
USB_PP5: TR5209.3 UC1.AJ2
USB_PP6: R3205.1 UC1.AF7
USB_PP6_R: R3205.2 U3201.3
USB_PP7: R5204.2 UC1.AH2
USB_PP7_TPNL: DA6.3 LCD1.37 R5204.1
USB_PP8: R5802.2 UC1.AF9
USB_PP8_R: R5802.1 WLAN1.3
USBCOMP: RC44.1 UC1.AB6
VCI_IN1: RE437.1 UE1.126
VCIN0_PH: C2612.1 C2613.1 R2608.2 R2609.2 R2610.1 RE394.2
VCREF0: CE91.1 RE396.2 RE397.1 UE1.25
VD_IN1_C: C2612.2 C2613.2 R2610.2 R2611.1
VGA_DMINUS: CV9.2 UV1.T2 UV11.3
VGA_DPLUS: CV9.1 UV1.T4 UV11.2
VGA_SMB_CK3: QV1.1 RV6.2 RV164.2 UV1.U7
VGA_SMB_CK3_R: RV164.1 UV11.8
VGA_SMB_DA3: QV1.4 RV5.2 RV165.2 UV1.U8
VGA_SMB_DA3_R: RV165.1 UV11.7
VIDALERT_N: PR607.1 RC152.2 RC153.2
VIDSCLK: PR606.1 UC1.A63
VIDSOUT: PR609.1 RC157.2 UC1.D64
VL: PC126.1 PU102.15
VR_ALERT#: PR625.2 PU602.36
VR_CAP: C5224.1 T4931.1(TP-1) UE1.18
VR_SCLK: PR618.2 PU602.37
VR_SDA: PR626.2 PU602.35
VRALERT#: RC73.1 UC1.AM11
VRAM_ID1: RC378.2 RC380.1 UC1.AP8
VRAM_ID2: RC379.2 RC381.1 UC1.AW7
VSA_SEN+: PC640.2 PC650.1 PC652.1 PR649.2 RC168.2 UC1.H20
VSA_SEN-: PC649.1 PC650.2 PU602.26 RC166.1 UC1.H21
VSUM+_VGA: PC1230.1 PC1232.1 PR1108.1 PR1126.1 PR1131.1 PR1132.1 PU1100.14
VSUM-_VGA: PC1119.1 PC1120.1 PC1230.2 PC1231.1 PC1232.2 PH1102.2 PR1110.1 PR1128.1 PR1132.2 PR1136.1 PR1137.1
VTTREF_1.2V: PC210.1 PU200.4
WAKEB: RV162.2 RV163.1 UV1.AJ27
WEA0#: UV1.G25 UV17.L3 UV18.L3
WEA1#: UV1.H10 UV19.L3 UV20.L3
WHITE_LED_BAT: EC6103.1 Q6102.1 R6107.2
WLAN_DISABLE#1: D5503.2 WLAN1.48
WLAN_RADIO_DIS#: D5503.1 RE439.1 UC1.B7
XCLK_BIASREF: RC52.1 UC1.E42
XDP_HOOK0: RC158.2 T49.1(TP-1)
XDP_ITP_PMODE: RC115.1 RC353.2 T47.1(TP-1) UC1.E8
XDP_OBS0_R: T4942.1(TP-1) UC1.C55
XDP_OBS1_R: T4941.1(TP-1) UC1.D55
XDP_OBS2_R: T10.1(TP-1) UC1.B54
XDP_OBS3_R: T11.1(TP-1) UC1.C56
XDP_PRDY#: T51.1(TP-1) UC1.D56
XDP_PREQ#: T50.1(TP-1) UC1.D61
XDP_PRSENT_CPU: RC43.1 RC1104.1 T52.1(TP-1)
XDP_PRSENT_PCH: RC347.1 RC1105.1
XDP_SPI_IO2: RC354.1 RC1105.2
XDP_SPI_SI: RC9.2 RC355.1 T48.1(TP-1)
XTAL24_IN: CC21.1 RC46.2 UC1.E37 YC1.3
XTAL24_OUT: CC22.1 RC46.1 UC1.E35 YC1.1
XTALIN: CV17.1 RV20.1 UV1.AM28 YV1.1
XTALOUT: CV18.1 RV20.2 UV1.AK28 YV1.3
N16741477: T212.1(TP-1) UV1.AB8
N16741489: T208.1(TP-1) UV1.AD7
N16741505: T214.1(TP-1) UV1.AB4
N16741517: T206.1(TP-1) UV1.AD9
N16741525: T216.1(TP-1) UV1.Y8
N16741803: RV29.2 UV1.AC22
N16741825: RV59.2 UV1.AB22
N16751828: T209.1(TP-1) UV1.AC8
N16751830: T205.1(TP-1) UV1.AE8
N16751834: T203.1(TP-1) UV1.AE9
N16751836: T201.1(TP-1) UV1.N9
N16751838: T215.1(TP-1) UV1.AB2
N16751842: T211.1(TP-1) UV1.AB9
N16751844: T207.1(TP-1) UV1.AC10
N16751848: T202.1(TP-1) UV1.L9
N16751852: T213.1(TP-1) UV1.AB7
N16751854: T210.1(TP-1) UV1.AC7
N16751856: T204.1(TP-1) UV1.Y11
N16751858: T217.1(TP-1) UV1.Y7
N16813004: RV71.2 RV72.1 RV84.2 RV87.2
N17237617: PC705.1 PC760.1 PC762.1 PC763.1 PC764.1 PC765.1 PC780.1 PC781.1 PJP701.2 PL704.2 PQ704.5
N17242539: RV58.1 UV11.4
N17268429: PQ720.1 PR790.1 PR791.2
N17415515: PJP2.2 PJPDC1.1 PJPDC1.2 PL4.1
N17421985: PC695.2 PR601.2 PR606.2 PR618.1
N17847259: T4935.1(TP-1) UV1.AL9
N17877344: T223.1(TP-1) UV1.R1
N17877347: T224.1(TP-1) UV1.R3
N18941428: PC640.1 PR646.2
N18941436: PC601.1 PR652.2
N18941447: PC632.1 PR636.1 PU602.28
N18941448: PC632.2 PR641.1
N18941457: PH604.1 PR642.2
N18941471: PR604.2 PR607.2 PR625.1
N18941481: PR605.2 PR609.2 PR626.1
N18941485: PR658.2 PU602.40
N18941487: PR612.2 PU602.39
N18941496: PR678.2 PU602.38
N18941497: PC603.1 PR602.1 PU602.34
N18941498: PC604.1 PR603.1 PU602.33
N18941511: PR608.1 PU602.32
N18941513: PR611.1 PU602.31
N18941562: PC630.1 PR640.1 PU602.20
N18941580: PH605.1 PR657.2
N18941616: PC639.2 PR645.1
N18941625: PC647.2 PR650.2
N18941629: PC629.2 PR639.1
N18941656: PC627.1 PR632.2
N18941661: PH602.1 PR628.2
N18941667: PC627.2 PR638.2 PU602.8
N18941711: PC621.2 PR623.1
N18941712: PR621.2 PR622.2 PR623.2 PU602.5
N18941722: PC616.2 PR617.2 PU602.4
N18941723: PC614.2 PR617.1
N18941731: PR610.2 PU602.3
N18941735: PC613.2 PR613.2 PU602.2
N18941759: PC617.2 PR621.1
N18941760: PC631.1 PR630.2
N18941767: PC630.2 PR644.1
N18941770: PC611.2 PU606.2
N18941771: PC611.1 PR619.1
N18941791: PH601.2 PR610.1 PR631.2
N18941811: PH603.2 PR635.1 PR647.2
N18941826: PQ601.8 PU606.5
N18941830: PQ601.1 PU606.1
N18941848: PR679.1 PU606.7
N18941869: PL601.3 PR624.1
N18944084: PL603.3 PR661.1
N18944130: PC671.2 PU605.5
N18944131: PR672.2 PU605.3
N18944132: PC671.1 PR672.1
N18944141: PC655.2 PU603.5
N18944142: PR660.2 PU603.3
N18944143: PC655.1 PR660.1
N18944153: PR659.1 PU603.1
N18944154: PC663.2 PU604.5
N18944155: PR665.2 PU604.3
N18944156: PC663.1 PR665.1
N18944237: PR664.1 PU604.1
N18944256: PR671.1 PU605.1
N18987516: PC128.1 PD102.2 PR114.2 PR120.2 PR121.2 PR122.1
N19901660: CE78.1 R2455.1
N20173493: RE356.1 RE358.1 UE1.120
N20440449: CE71.1 RE348.1 UE1.54
N23700319: PD4.2 PL2.1 PQ6.1 PR6.2
N28424999: T113.1(TP-1) UC1.AW71
N28425002: T114.1(TP-1) UC1.AW70
N28483977: PQ1.2 PR2.1 PR12.2 PR13.2
N28483985: PQ1.3 PR5.2
N28484391: PC16.1 PQ2.3 PR28.2
N28484395: PC16.2 PQ2.2 PR29.1
N28484412: PQ2.5 PR31.1 PR33.2
N28484439: PC14.2 PQ3.2 PR32.1
N28484451: PQ1.5 PQ1.6 PR7.1 PR10.2
N28810503: CZ45.1 UZ2.12
N28810563: CZ23.1 UZ2.10
N28842863: CC204.1 UC1.AL1
N28843886: CC214.1 UC1.BB10
N28856399: T16.1(TP-1) UC1.BA70
N28856402: T17.1(TP-1) UC1.BA68
N28857231: T12.1(TP-1) UC1.BB68
N28857234: T13.1(TP-1) UC1.BB69
N28857237: T14.1(TP-1) UC1.AK13
N28857240: T15.1(TP-1) UC1.AK12
N28861827: RC120.1 UC1.C64
N29708559: T126.1(TP-1) UC1.AY4
N29708561: T127.1(TP-1) UC1.BB3
N29708599: T128.1(TP-1) UC1.AU5
N29708601: T129.1(TP-1) UC1.AT5
N29708639: T130.1(TP-1) UC1.BB5
N32287358: C349.2 U15.10
N32287370: C343.2 U15.12
N32646580: PBATT1.4 PR15.1
N32798407: C6204.1 Q6203.3 R6215.2
N32842463: RC361.2 UC1.U11 UC1.U12
N33124395: PC204.2 PR210.1 PU200.12
N33188643: C2720.1 R2717.1 RE33.2
N33688158: RE442.2 UE1.113
N34661441: JDEG1.9 RE74.2
N34661558: RE422.1 T4932.1(TP-1)
N34661623: JDEG1.1 RE71.2
N36085760: PD6.1 PR11.2
N36752215: CZ70.1 UZ21.6
N37641086: CC1103.1 DZ1702.2 RC1103.2 UC17.2
N38038995: CV98.1 RV40.2
N38038996: CV99.1 RV41.2
N39091501: C6209.2 U5602.6
N39189842: JDIMM1.134 RD7.1
N39190967: JDIMM2.134 RD8.1
N39282118: PC501.1 PJP501.2 PU500.8 PU500.9 PU500.10
N39282176: PC504.1 PR506.2
N39282188: PR503.1 PR504.2
N39302306: CC8.2 RC29.1
N39854666: D5501.1 F5501.2
N39880170: PR1202.2 PU1200.7
N39880453: PC1209.1 PR1208.2
N39995456: Q2405.1 R6211.1
N40185786: PR769.2 PU703.3
N40185790: PR770.2 PU703.4
N40185793: PC744.2 PQ709.3 PQ718.1 PQ718.2 PQ718.3 PQ740.1 PQ740.2 PQ740.3 PR737.1 PR763.1
N40185809: PC750.1 PU703.27
N40185819: PC752.2 PR754.1
N40185844: PR774.2 PU703.6
N40185847: PR775.2 PU703.7
N40185849: PC721.1 PR771.2
N40185857: PC757.2 PR743.1 PU703.18
N40185867: PR755.2 PU703.12
N40185868: PC708.1 PR776.1 PU703.14
N40185870: PC708.2 PR742.1 PU703.15
N40185883: PC747.1 PR740.2 PU703.31
N40185884: PC747.2 PR772.2 PU703.32
N40185886: PC750.2 PU703.28
N40185889: PR773.1 PU703.25
N40185891: PQ704.4 PR761.2
N40185893: PR745.1 PU703.26
N40185897: PR771.1 PU703.24
N40185899: PR757.2 PU703.17
N40185902: PQ718.5 PR703.1
N40185907: PR757.1 PR779.2
N40185909: PC742.1 PC744.1 PQ709.1 PQ718.4 PR762.1 PR778.2
N40185955: PC779.1 PL700.2 PQ717.1 PQ717.2 PQ717.3 PR765.1
N40185980: PR742.2 PR765.2
N40185983: PR765.3 PR776.2
N40185999: PQ709.2 PR737.2 PR738.1
N40186006: PR703.2 PR772.1
N40186007: PR703.3 PR740.1
N40186030: PC767.1 PR766.2
N40186037: PC779.2 PQ717.4 PR773.2
N40186056: PD704.1 PR743.2
N40186061: PR764.2 PU703.13
N40186070: PQ710.2 PQ711.1
N40197821: PC1227.2 PR1136.2 PU1100.15
N40197830: PC1227.1 PR1137.2
N40197832: PC1110.1 PR1114.1 PU1100.25
N40197841: PR1121.2 PU1100.11
N40197842: PC1122.1 PC1124.1 PR1133.1 PR1138.1 PU1100.16
N40197845: PC1229.1 PR1139.1 PU1100.17
N40197867: PC1121.1 PR1125.2
N40197882: PC1118.1 PR1123.2
N40197886: PL1103.3 PR1124.2 PR1126.2
N40197888: PL1103.2 PR1128.2
N40197914: PH1101.2 PR1120.2 PR1121.1
N40197922: PC1123.1 PR1129.2 PR1133.2 PR1134.1 PR1135.1 PU1100.18
N40197925: PC1122.2 PR1129.1
N40197927: PC1233.1 PR1135.2
N40197929: PC1123.2 PC1228.2 PR1130.1 PU1100.19
N40197932: PC1228.1 PR1134.2
N40197958: PH1102.1 PR1131.2
N40197966: PL1102.3 PR1104.2 PR1108.2
N40197968: PC1109.1 PR1107.2
N40197981: PC1108.1 PR1103.2
N40197987: PL1102.2 PR1110.2
N40198014: PU1100.39 PU1100.40
N40198017: PR1140.1 PU1100.36 PU1100.37 PU1100.38
N40198022: PR1101.2 PU1100.1
N40198023: PR1111.2 PU1100.2
N40198028: PR1105.2 PU1100.34
N40198029: PR1106.2 PU1100.32 PU1100.33
N40199716: PR1401.2 PU1400.9
N40199719: PC1405.1 PR1405.2 PU1400.15
N40311410: Q6205.3 R2705.1 R6511.1
N40553728: EC5206.1 R5207.1
N40598435: PC102.1 PR100.2
N40598492: PC119.1 PU102.16 PU102.17
N40598500: PC114.1 PR111.2
N40598503: PC113.2 PR108.1
N40598539: PC127.2 PR117.1
N40598619: PD102.1 PR116.2
N40605947: PC305.1 PR303.2 PU300.15
N40702769: D5201.3 R6523.2 R6524.2
N41321201: PC790.1 PQ721.2 PR790.2
N41455626: PC207.1 PR203.2
N41674880: PQ740.4 PR778.1
N124752685: CH101.2 RH211.1
N124753277: CH100.2 RH212.1
N427285901: PR682.2 PU602.1

Pads without a net: FD1 1; FD2 1; FD3 1; FD4 1; FD5 1; FD6 1; HDA27 4 14 23 24; HDD1 4; JCRT 4; JDIMM1 87 88 91 92 95 97 100 101 104 105 162 165; JDIMM2 87 88 91 92 95 96 97 100 101 104 105 162 165; JHDMI 13 14; KB1 2 3; KB_BL1 3; LCD1 5; ODD1 9 16; PD3 3; PD4 3; PJPDC1 4; PU100 10 15; PU102 10; PU300 9 10 12; PU500 1 4 7; PU603 4 9; PU604 4 9; PU605 4 9; PU800 1 5; PU1100 35; PU1200 13; PU1400 10 12; RJ45 9; RN5203 4 5; U3201 7 9 12 14 16 17 19 22 23; U5201 3; U5502 17 18; U5601 5; UC1 A3 A4 A6 A11 A13 A15 A23 A25 A26 A27 A29 A31 A33 A36 A38 A40 A45 A47 A50 A52 A65 A69 AB1 AB4 AB11 AB12 AB13 AC1 AC2 AC3 AD9 AD10 AD11 AD12 AF11 AF12 AF13 AG1 AG2 AH7 AH8 AH9 AH10 AH11 AH12 AK6 AK7 AK9 AK10 AL25 AL27 AM1 AM2 AM3 AM4 AM10 AN1 AN2 AN3 AN5 AN7 AN8 AP1 AP2 AP3 AP4 AP5 AP7 AP11 AP56 AT10 AT15 AU1 AU2 AU7 AU8 AU56 AW1 AW9 AW17 AW20 AW48 AW68 AW69 AY1 AY2 AY5 AY7 AY8 AY20 AY21 AY68 B2 B3 B11 B13 B15 B23 B25 B26 B27 B29 B31 B33 B36 B38 B40 B45 B47 B50 B52 B69 B70 BA3 BA4 BA8 BA9 BB2 BB4 BB9 C2 C4 C7 C11 C12 C15 C23 C24 C27 C28 C29 C31 C32 C33 C36 C37 C38 C40 C50 C51 C52 C54 C70 C71 D1 D3 D4 D5 D7 D8 D12 D15 D23 D24 D27 D28 D29 D31 D32 D33 D36 D37 D38 D40 D50 D51 D52 D54 D71 E1 E2 E3 E10 E22 E23 E25 E27 E28 E30 E38 E40 E48 E61 F6 F10 F25 F30 F48 F52 F60 F61 F65 G1 G2 G3 G4 G65 H2 H5 H6 H10 H11 J4 J5 J6 J10 J68 J71 K45 K46 L7 M1 M3 M4 N1 N2 N3 N7 N8 N11 N12 U2 U3 U4 U8 U9 V1 V2 W7 W10 W11 W12; UC14 1; UC16 1; UC17 1; UE1 23 34 71; UE6 1; UV1 AA5 AA6 AA29 AA31 AB23 AB25 AB26 AB27 AB30 AC1 AC3 AC5 AC6 AC16 AC23 AC25 AD2 AD4 AD10 AD11 AD13 AD16 AD22 AD23 AD24 AE1 AE3 AE5 AE6 AE10 AE11 AE13 AE16 AE19 AE22 AE23 AE24 AE25 AE26 AF2 AF4 AF6 AF7 AF8 AF9 AF10 AF11 AF13 AF16 AF17 AF19 AF20 AF22 AF23 AF24 AF25 AG1 AG3 AG5 AG6 AG7 AG8 AG9 AG10 AG11 AG13 AG14 AG15 AG16 AG17 AG18 AG19 AG20 AG21 AG22 AG23 AG24 AG25 AG26 AH1 AH3 AH5 AH6 AH8 AH12 AH14 AH16 AH18 AH20 AH22 AH24 AH26 AJ7 AJ9 AJ13 AJ15 AJ17 AJ19 AJ21 AJ23 AJ25 AK1 AK3 AK5 AK6 AK8 AK10 AK14 AK16 AK18 AK20 AK22 AK24 AK26 AL7 AL13 AL15 AL17 AL19 AL21 AL23 AL25 AM3 AM5 AM6 AM8 AM10 AM12 AM14 AM16 AM18 AM20 AM22 AM24 AM26 J8 J22 J25 K13 K30 L16 L29 L31 M4 M27 M28 M30 N3 N5 N6 N8 N26 N29 N31 P2 P4 P7 P10 P23 P24 P26 P27 P28 P30 R6 R29 R31 T7 T23 T24 T26 T27 T28 T30 U5 U6 U12 U23 U24 U26 U29 U31 V2 V4 V6 V12 V27 V28 V30 W3 W5 W6 W7 W8 W23 W24 W29 W31 Y2 Y4 Y6 Y12 Y23 Y24 Y26 Y27 Y28 Y30; UV17 J1 J9 L1 L9; UV18 J1 J9 L1 L9; UV19 J1 J9 L1 L9; UV20 J1 J9 L1 L9; WLAN1 6 8 9 11 12 13 14 15 16 17 19 20 21 22 23 24 26 28 32 34 40 47 51 52 53 54 56 57 58 59 60 62 63 65; X3001 2 4; YC1 2 4

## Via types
v1: diameter 0.305, hole 0.152, TOP to BOTTOM, 761 vias
v2: diameter 0.457, hole 0.203, TOP to BOTTOM, 5811 vias
v3: diameter 0.406, hole 0.203, TOP to BOTTOM, 112 vias
v4: diameter 0.508, hole 0.254, TOP to BOTTOM, 78 vias

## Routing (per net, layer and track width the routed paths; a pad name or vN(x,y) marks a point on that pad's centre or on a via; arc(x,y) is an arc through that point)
0.6V_DDR_VTT_ON: length 70.3
  TOP w0.102: PR202.1 53.56,23.96 v1(53.21,24.32) 53.21,24.96 54.79,26.54 56.51,26.54 57.21,27.24 58.29,27.24 58.54,27.5 58.54,28.19 58.03,28.7 56.51,28.7 v2(56.19,29.02)
  IN1 w0.127: v2(74.35,34.04) 74.35,35.69 74.77,36.11 74.77,54.47 76.26,55.96 76.26,58.29 76.96,58.99 76.96,61.59 v2(77.21,61.85) ; v2(60.89,32.38) 58.79,32.38 58.48,32.07 56.83,32.07 56.19,31.43 v2(56.19,29.02)
  IN2 w0.127: v2(60.89,32.38) 61.84,33.34 67.27,33.34 67.97,34.04 v2(74.35,34.04)
  BOTTOM w0.102: v2(77.21,61.85) 77.91,62.55 77.91,67.18 77.27,67.82 RC124.2 77.27,68.22 77.29,68.24 UC14.4
1.2V_VTT_PWRGD: length 182.9
  TOP w0.102: v2(162.81,72.77) 162.5,72.47 RC392.1
  IN1 w0.127: v2(83.43,14.22) 83.94,13.72 84.64,13.72 84.95,14.03 154.93,14.03 163.06,22.16 163.06,23.88 165.79,26.61 165.79,31.88 167.13,33.21 v2(167.95,33.21)
  IN2 w0.127: v2(56.13,19.56) 56.76,19.56 59.62,16.7 59.62,14.73 62.16,12.19 80.24,12.19 82.28,14.22 v2(83.43,14.22) ; v2(162.81,72.77) 162.81,72.64 164.46,70.99 164.46,69.53 167.76,66.23 167.76,63.44 168.41,62.79 168.41,59.45 171.51,56.35 171.51,46.62 172.82,45.31 172.82,43.96 176.09,40.69 176.09,39.29 175.66,38.86 169.94,38.86 168.27,37.19 168.27,33.53 v2(167.95,33.21)
  BOTTOM w0.102: v2(167.95,33.21) v1(167.95,34.29)
2.5V_VIN:
  vias: v1(55.82,31.46)
3V_FB: length 5.5
  BOTTOM w0.102: v1(38.7,37.99) 38.44,38.25 37.7,38.25 PR109.2
  BOTTOM w0.254: PC113.1 PR110.1 PR109.2 36.44,38.28 PU100.13
3V_SN: length 2.2
  BOTTOM w0.102: PR106.2 37.22,32.61 v1(38.18,31.65)
3V_VIN:
  vias: v1(31.3,45.87) v2(30.28,41.35) v2(30.31,42.24) v2(31.12,43.21) v2(31.15,40.72) v2(31.45,39.67) v2(31.45,38.71) v2(31.45,37.9)
5V_FB: length 0.8
  BOTTOM w0.102: 48.57,41.22 48.11,41.22 v1(47.89,41.45)
5V_HDD_S0: length 3.2
  TOP w0.102: v2(189.73,36.75) 189.73,35.99 v3(189.45,35.71) ; v2(189.73,36.75) 190.16,37.19 v3(190.4,37.19) ; v2(189.73,36.75) 189.73,36.79 189.07,37.45 AFTP5601.1
5V_HDMI_CRT_S0_R: length 6.4
  IN1 w0.762: JCRT.9 13.8,66.62 17.41,66.62 v2(19.36,68.56)
  vias: v2(18.73,69.09) v2(27.44,70.59) v2(27.81,71.06)
5V_SN:
  vias: v1(49.73,34.57)
5V_VIN:
  vias: v1(41.61,38.84) v2(41.74,42.11) v2(42.09,40.54) v2(42.45,42.9) v2(42.73,40.54) v2(43.06,39.9) v2(43.06,39.19) v2(43.06,38.35)
+0.6V_DDR_VTT: length 129.5
  TOP w0.102: v2(164.14,20.7) v3(164.74,20.7)
  IN1 w1.016: 163.44,18.1 155.82,10.48 55.62,10.48 54.1,12 54.1,15.18 52.97,16.31 52.97,18.14 54.72,19.89 54.72,23.16 57.14,25.59
  vias: v2(58.08,26.61) v2(58.1,25.84) v2(58.67,26.61) v2(58.67,25.84) v2(59.24,26.61) v2(59.24,25.84) v2(163.57,20.32) v2(163.57,19.62) v2(164.14,19.94)
+0.6VSP:
  vias: v1(62.63,26.1)
+0.95VSDGPU: length 31
  TOP w0.508: RV30.2 158.3,122.56 v2(158.3,121.16) ; LV8.1 178.8,128.07 178.8,125.33 179.04,125.08 179.04,122.37 178.19,121.51 177.15,121.51 175.1,119.46 v2(174.5,119.46)
  BOTTOM w0.508: v2(174.5,119.46) 169.81,119.46 168.9,118.55 161.79,118.55 160.18,120.17 159.29,120.17 v2(158.3,121.16)
  vias: v2(152.62,143.54) v2(152.6,142.98) v2(154.2,137.94) v2(154.82,138.43) v3(150.26,142.67)
+0.95VSDGPU_ON: length 4.2
  TOP w0.102: R6510.2 v1(145.21,158.61)
  TOP w0.203: U15.3 143.01,157.5 143.22,157.71 143.22,158.08 143,158.31 C983.2
  TOP w0.508: C983.2 R6510.2
+0.95VSDGPU_OUT:
  vias: v1(145.31,155.14)
+1.0V_AMPHYPLL: length 23
  TOP w0.254: v2(130.02,90.82) 130.3,91.1 130.3,94.42 129.84,94.88 129.84,95.3 130.68,96.14 131.95,96.14 132.99,97.19 133.25,97.19 133.73,97.67 CC264.1 134.17,98.06 134.17,98.55 137.65,102.03 v1(137.65,102.68) 137.65,103.28 v2(137.97,103.59) 137.97,104.57 138.49,105.09 RC169.2
  BOTTOM w0.254: UC1.L15 130.34,90.5 130.02,90.82 v2(130.02,90.82) 130.02,90.85 130.34,91.18 UC1.K15
  BOTTOM w0.457: CC219.1 137.97,103.64 v2(137.97,103.59)
+1.0V_APLL: length 20.4
  TOP w0.254: v2(130.7,87.49) 130.74,87.53 132.42,87.53 132.73,87.84 132.73,88.45 132.91,88.64 135.02,88.64 135.11,88.55 136.39,88.55 137.01,89.18 137.01,90.33 CC225.1 138.46,91.78 140.67,91.78 142.23,93.34 142.23,94.17 v1(143.24,95.18) 144.71,96.65 RC172.2
  BOTTOM w0.254: v2(130.7,87.49) 130.64,87.43 UC1.V15
+1.0V_APLLEBB: length 26.2
  TOP w0.127: 127.76,89.46 127.76,89.92 128.4,90.56 128.4,91.07 128.81,91.48 128.92,91.48 129.22,91.19 129.22,90.32 v2(128.06,89.16) 127.76,89.46
  TOP w0.254: 128.92,91.48 128.92,91.66 129.38,92.12 129.38,93.77 129.6,93.98 129.6,94.49 129.41,94.68 129.41,95.42 130.51,96.52 131.58,96.52 CC218.1 132.52,97.51 137.08,102.06 137.08,104.32 v1(137.71,104.95) RC310.2
  BOTTOM w0.254: v2(128.06,89.16) UC1.N18
+1.0V_CLK2: length 22.8
  TOP w0.102: v2(135.82,102.62) v1(135.82,103.12)
  IN1 w0.254: v2(135.82,102.62) 136.36,102.62 136.61,102.36 136.61,98.81 132.32,94.52 132.32,92.61 131.88,92.17 131.6,92.17 130.78,91.34 128.31,91.34 128.01,91.04 v2(128.01,90.81)
  BOTTOM w0.254: UC1.K19 127.74,91.08 v2(128.01,90.81)
  BOTTOM w0.381: v2(135.82,102.62) 135.82,103.95 136.01,104.14 CC220.1 134.75,105.17 RC170.2
+1.0V_CLK4: length 25.5
  TOP w0.254: RC173.2 136.45,103.7 v2(136.39,103.63)
  IN1 w0.254: v2(126.76,89.15) 126.76,89.28 127.36,89.88 129.77,89.88 130.91,91.02 131.87,91.02 132.84,91.99 132.84,94.34 136.65,98.15 136.65,98.31 136.99,98.65 136.99,103.22 136.58,103.63 v2(136.39,103.63)
  BOTTOM w0.254: v2(126.76,89.15) UC1.N20
  BOTTOM w0.381: CC226.1 137.72,104.46 v1(137.19,103.92) 136.9,103.63 v2(136.39,103.63)
+1.0V_CLK5: length 16.2
  TOP w0.508: RC171.2 132.64,104.36 v2(132.58,104.29) v1(130.95,102.66) 130.95,99.44 128.94,97.43 128.94,95.78 ; RC52.2 126.87,90.11 127,90.24 127.38,90.62 v2(127.38,90.79)
  BOTTOM w0.254: UC1.L19 127.41,90.74 127.41,90.76 v2(127.38,90.79)
  BOTTOM w0.508: CC221.1 132.52,106.22 132.52,104.36 v2(132.58,104.29)
+1.0V_MPHYGT: length 2.2
  BOTTOM w0.254: UC1.N17 129.38,89.23 129.38,89.04 UC1.P16 129.94,88.98 v2(129.94,89.14) 129.94,89.32 UC1.N16
  vias: v2(132.84,89.2) v2(141.58,107.53) v2(142.22,107.53) v3(143.21,102.23)
+1.0V_PRIM: length 124.7
  TOP w0.203: CE77.1 175.19,67.31 175.76,67.88 175.76,68.25 176.68,69.17 UE1.95
  TOP w0.508: 140.07,111.25 143.88,111.25 145.24,112.61 146.27,112.61 148.11,110.77 148.11,102.45 150.42,100.14 150.42,97.75 155.15,93.03 158.81,93.03 162.43,89.41 162.43,81.34 163.62,80.15 166.1,80.15 166.27,79.98 168.25,79.98 168.27,79.96 v2(168.3,79.96) ; v2(134.3,104.2) 134.04,104.46 RC171.1 RC173.1 ; CE77.1 174.69,67.55 174.24,68.01 v2(173.98,68.01)
  TOP w1.016: 146.3,99.76 146.3,106.93 143.43,109.8 140.57,109.8 140.52,109.85
  IN1 w0.254: 126.76,90.74 125.57,89.55 125.57,89.04 125.96,88.64 v2(125.96,87.15) ; 126.76,90.74 126.76,90.6 127.08,90.28 128.25,90.28 128.79,90.82 v2(128.79,90.82) ; 126.76,90.74 v2(126.76,90.83)
  IN1 w0.508: 134.41,103.34 134.41,102.01 133.64,101.24 v2(133.26,101.24)
  IN2 w0.508: v2(168.3,79.96) 169.04,79.22 169.04,71.88 170.87,70.06 170.87,69.12 171.98,68.01 v2(173.98,68.01)
  BOTTOM w0.254: v2(128.71,86.64) 128.39,86.31 UC1.Y18 ; UC1.AK20 127.04,81.19 126.63,81.6 126.25,81.6 v2(125.95,81.9) 125.95,81.94 125.6,82.3 125.6,86.78 v2(125.96,87.15) 126.06,87.06 UC1.V21 126.52,86.98 127.01,86.98 UC1.V20 ; UC1.AF18 128.1,83.33 v2(128.03,83.32) 128.03,83.32 UC1.AF19 ; UC1.T1 138.63,88.53 v2(138.66,88.56) ; v2(128.79,90.82) 129.05,91.15 UC1.K17 ; v2(138.99,91.18) UC1.L1 ; v2(128.71,88.26) 128.72,88.31 UC1.P18 ; v2(126.76,90.83) UC1.L21 ; v2(128.06,84.96) 128.06,85.05 UC1.AB19 127.74,85.28 v2(127.41,84.96) UC1.AB20
  BOTTOM w0.381: 130.59,98.15 129.99,97.55
  BOTTOM w0.508: RC352.1 133.22,103.63 RC170.1 ; RC352.1 133.47,101.81 133.26,101.6 v2(133.26,101.24) 133.26,100.57 132.64,99.95 132.64,98.87 ; RC352.1 v2(134.3,104.2) ; 130.59,98.15 132.59,98.15 132.63,98.11
  vias: v2(136.1,113.06) v2(136.63,112.42) v2(136.73,113.04) v2(137.22,112.33) v2(137.36,113) v2(137.85,112.33) v2(137.99,113) v2(138.49,112.33) v2(138.64,112.99) v2(139.12,112.33) v2(139.98,90.02) v2(143.95,157.86) v2(144.33,157.29) v2(144.33,156.65) v2(144.58,157.86) v2(144.96,157.29) v2(144.96,156.65) v2(145.28,157.86) v2(145.6,157.29) v2(145.6,156.65) v3(139.3,110.2)
+1.0V_SRAM: length 24.7
  TOP w0.381: v2(126.76,84.12) 126.76,84.71 CC217.1
  TOP w0.508: 129.34,88.75 129.34,89.6 129.91,90.17 130.26,90.17 131.06,90.97 131.06,91.76 131.5,92.2 132.14,92.2 132.58,92.65 132.58,93.92 135.25,96.58 135.25,97.6 v1(137.41,99.76) 138.39,100.74 138.39,102.83 139.06,103.5 RC309.2
  IN2 w0.381: v2(128.09,86.67) 127.39,87.36 v2(127.39,87.5)
  BOTTOM w0.254: UC1.T19 127.74,87.84 v2(127.39,87.5) 127.39,87.67 127.17,87.89 UC1.T20 ; v2(126.08,84.11) 126.08,84.06 UC1.AF21 126.44,83.8 v2(126.76,84.12) 127.09,83.79 UC1.AF20
+1.0V_VCCST: length 124.9
  TOP w0.457: v2(126.16,90.81) 124.81,90.81 CC202.1
  TOP w0.508: v2(100.39,104.33) v3(101.73,104.33) v2(102.66,103.41) ; RC238.2 129.34,105.73 128.01,104.39 128.01,99.73 v2(128.74,99)
  IN1 w0.254: v2(126.16,90.81) 126.16,90.97 126.95,91.76 129.09,91.76 129.38,92.05 129.38,93.77 129.51,93.89 129.51,95.31 128.74,96.08 v2(128.74,99)
  IN1 w0.508: v2(100.39,104.33) 99.95,104.77 v2(98.02,104.77) ; v2(126.16,90.81) 125.61,90.81 125.15,91.28 125.15,92.21 124.95,92.42 124.95,94.71 123.86,95.8 114.95,95.8 114.1,96.65 114.1,97.45 111.23,100.33 106.49,100.33 105.43,101.38 104.1,101.38 102.62,102.86 102.62,103.37 v2(102.66,103.41) ; v2(114.21,143.76) 114.21,143.49 113.8,143.08 111.94,143.08 111.51,142.64 111.51,139.37 110.75,138.61 107.86,138.61 103.71,134.46 103.71,123.04 100.37,119.7 99.62,119.7 v2(95.91,115.98)
  IN2 w0.508: v2(100.39,104.33) 100.39,105.23 96.51,109.1 96.51,113.85 95.91,114.46 v2(95.91,115.98)
  BOTTOM w0.203: UC1.A18 128.18,97.98 128.29,98.08 128.29,98.27
  BOTTOM w0.254: PR605.1 117.29,144.6 PR604.1 PR601.1 114.87,144.6 PC602.1 114.21,143.94 v2(114.21,143.76) ; UC1.K20 126.99,91.25 126.95,91.28 126.57,91.28 126.53,91.25 UC1.K21 126.16,90.97 v2(126.16,90.81) ; 128.29,98.27 128.29,98.54 v2(128.74,99)
  BOTTOM w0.508: v2(102.66,103.41) RC79.1 RC80.1 ; v2(128.74,99) 128.97,99.23 128.97,99.33 CC195.1 ; RC152.1 99.93,103.78 100.39,104.25 v2(100.39,104.33) ; v2(98.02,104.77) 97.99,104.73 RC71.2 97.99,101.67 RC120.2 RC157.1
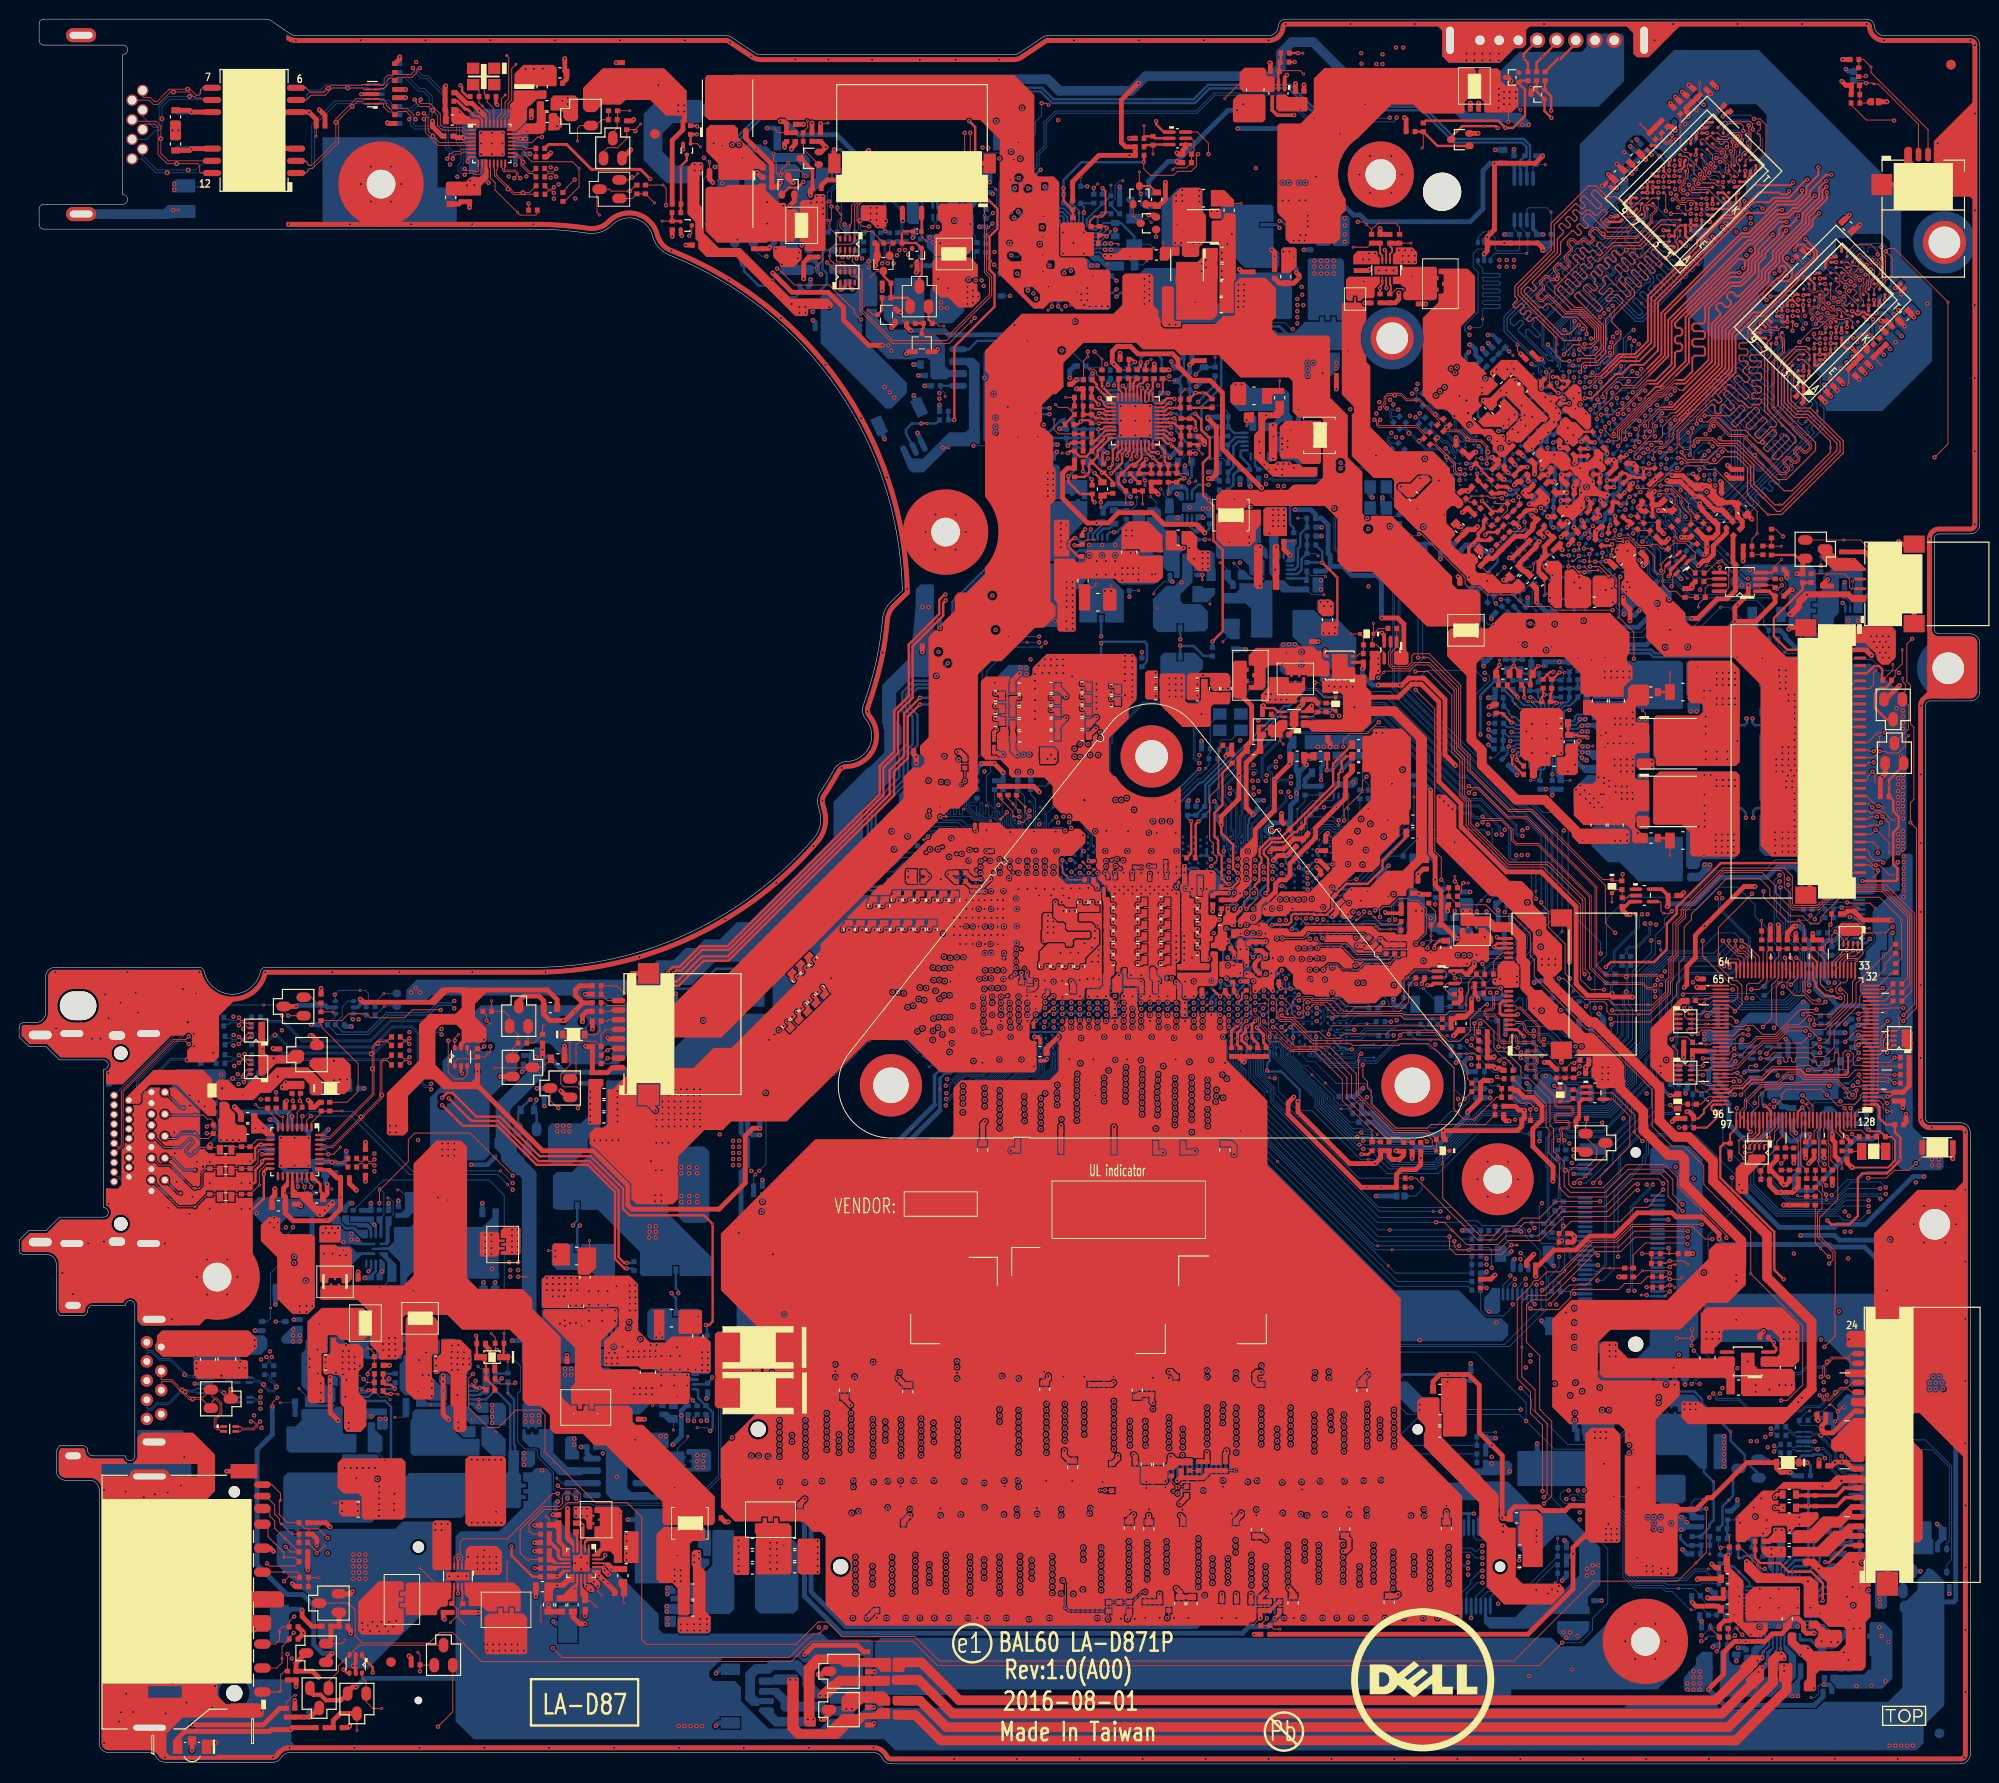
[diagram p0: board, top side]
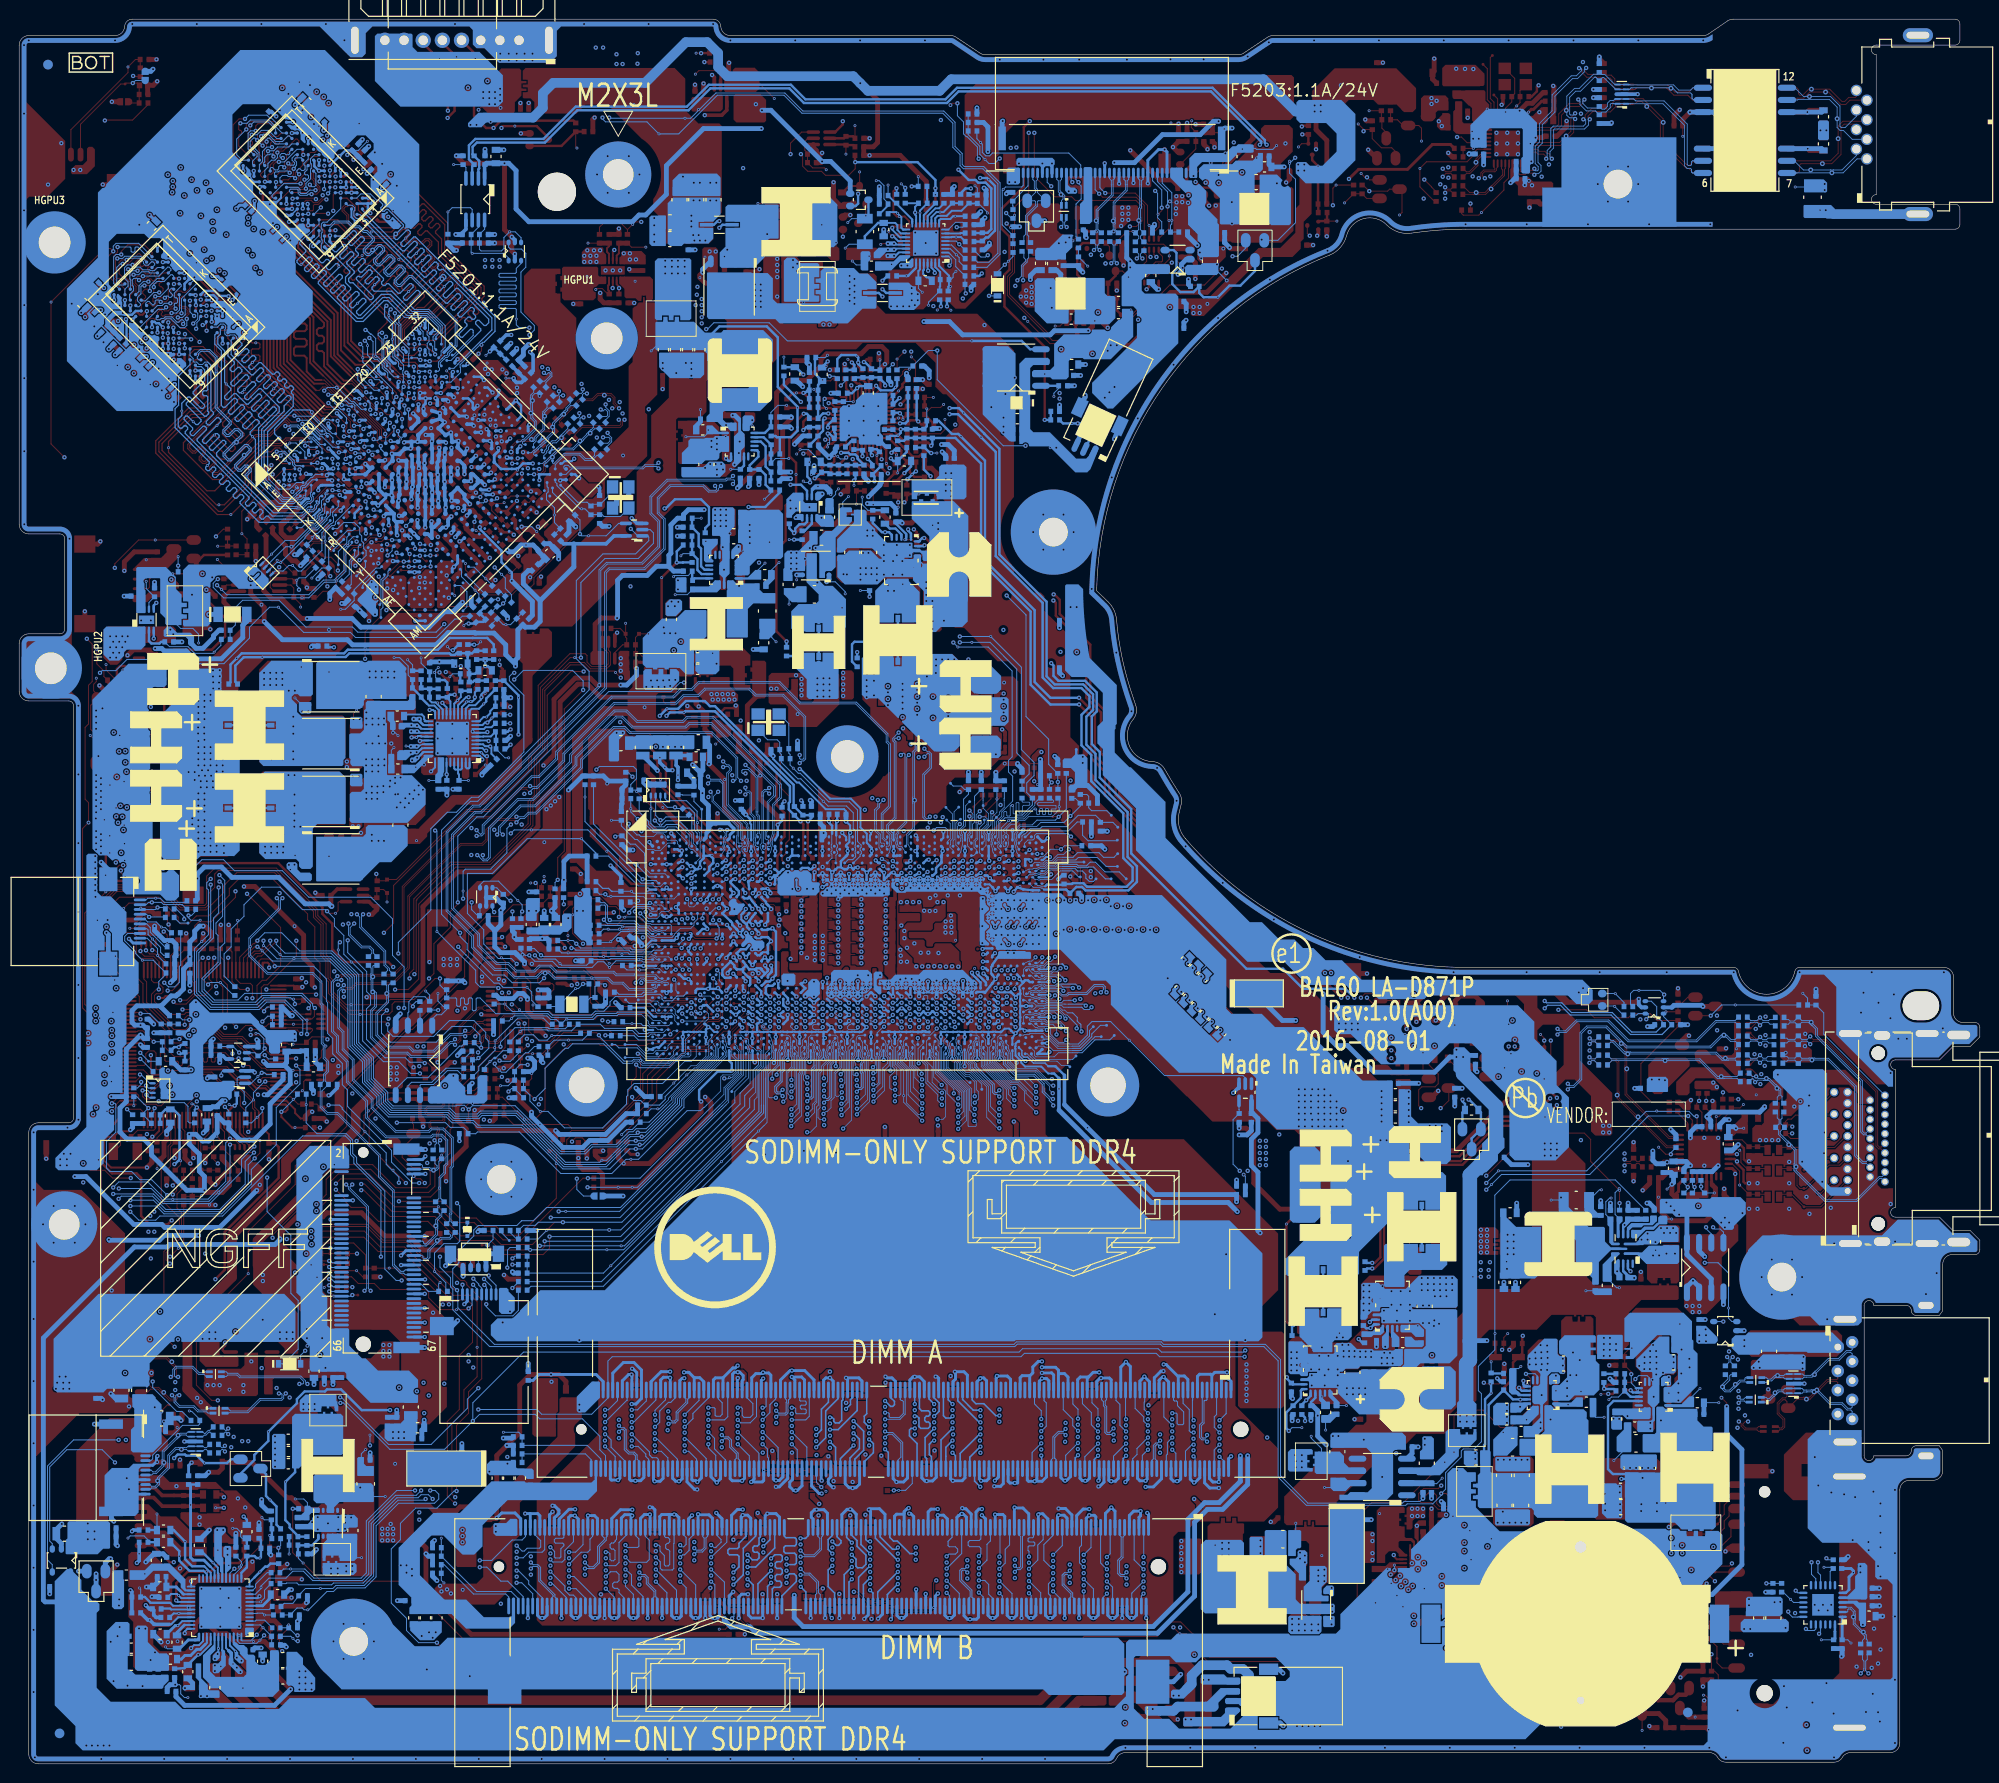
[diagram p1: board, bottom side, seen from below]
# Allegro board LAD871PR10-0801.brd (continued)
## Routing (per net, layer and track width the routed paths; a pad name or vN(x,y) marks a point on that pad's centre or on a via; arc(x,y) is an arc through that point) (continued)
+1.0V_VCCST_C: length 1.1
  TOP w0.102: v1(131.88,106.36) 131.54,106.71 CZ78.1
+1.0V_VCCSTG: length 64.8
  TOP w0.254: v2(127.12,92.91) 127.11,92.91 126.66,93.36 126.66,95.85 125.4,97.1 v2(125.4,97.94)
  TOP w0.508: 127.25,111.38 127.56,111.38 128.58,110.36 128.58,106.7 128.06,106.18 128.06,105.74 RC238.1 127.25,104.92 v3(127.25,103.07) 127.25,100.65 125.4,98.8 v2(125.4,97.94) ; RC349.2 RC351.2 RC350.2 105.84,101.96 v2(106.43,101.36)
  IN1 w0.508: v2(125.4,97.94) 123.96,96.5 115.44,96.5 114.93,97 114.93,97.6 111.13,101.4 106.46,101.4 v2(106.43,101.36) 105.75,102.04 104.45,102.04 103.31,103.19 103.31,103.7 102.96,104.04 102.01,104.04 99.82,106.24 97.53,106.24 96.51,105.22 v2(96.51,105.09)
  BOTTOM w0.254: v2(127.12,92.91) UC1.G20 ; UC1.A22 125.4,96.88 v2(125.4,97.94) 124.96,98.39 CC199.1
  BOTTOM w0.508: RC83.1 96.2,104.77 v2(96.51,105.09)
+1.0V_VCCSTG_C:
  vias: v1(132.2,115.84)
+1.0V_XDP: length 3.4
  BOTTOM w0.508: RC352.2 134.15,102.66 RC115.2 135.78,101.96 RC353.1
+1.0VS_VCCIO: length 4.8
  TOP w0.076: 114.76,80.7 v3(114.76,79.04)
  TOP w0.508: v2(112.47,91.34) 112.47,91.55 112.08,91.94 RC2.1
  BOTTOM w0.203: v2(121.63,80.03) UC1.AL30 121.17,80.44 UC1.AM30
  BOTTOM w0.254: UC1.AM28 v2(121.63,80.03)
  vias: v2(114.74,82.24) v2(121.63,81.59) v2(122.52,80.05) v2(129.91,111) v2(130.04,111.57) v2(130.49,111) v2(130.61,111.57) v2(131.06,111) v2(131.18,111.57) v2(131.63,111) v2(131.76,111.57) v2(132.2,111) v2(132.33,111.57)
+1.0VS_VCCOPC: length 2.9
  BOTTOM w0.254: v2(104.07,85.6) 103.98,85.51 UC1.AB62 ; UC1.V62 104.03,87.34 v2(104.07,87.38) ; v2(104.02,83.01) 103.75,83.01 UC1.AG62 ; UC1.P62 104.06,89.17 v2(104.07,89.15) ; UC1.AE62 v2(104.01,83.68)
  vias: v1(106.85,85.9) v2(51.42,55.7) v2(51.42,55.09) v2(51.42,54.51) v2(51.42,53.92) v2(51.42,53.34) v2(52.05,55.7) v2(52.05,55.09) v2(52.05,54.51) v2(52.05,53.92) v2(52.05,53.34) v2(74.48,64.98) v2(74.48,64.35) v2(74.48,63.71) v2(74.48,63.08) v2(74.48,62.44) v2(75.11,64.98) v2(75.11,64.35) v2(75.11,63.71) v2(75.11,63.08) v2(75.11,62.44) v2(92.75,93.12) v2(92.75,92.48) v2(104.01,90.24) v2(107.3,87.29) v2(107.3,86.69) v2(107.35,88.48) v2(107.31,87.9) v2(107.89,87.86) v2(107.92,87.27) v2(107.92,86.7)
+1.0VS_VCCOPCP: length 15.2
  IN2 w0.254: v2(36.44,51.37) 36.44,51.24 37.52,50.16 47.43,50.16 48.19,50.93 48.95,50.93 49.33,51.31 v2(49.33,51.63)
  BOTTOM w0.254: v2(36.44,51.37) 36.72,51.64 PU1200.12
  vias: v1(49.37,52.37) v2(48.63,55.18) v2(48.63,54.48) v2(48.63,53.78) v2(48.63,53.15) v2(49.27,55.18) v2(49.27,54.48) v2(49.27,53.78) v2(49.27,53.15)
+1.2V_DDR: length 143
  TOP w0.508: v2(85.17,40.96) 85.57,40.96 86.1,40.44 CD8.1
  IN1 w0.254: v2(125.35,81.64) 125.35,81.64 124.83,81.12 124.83,78.56 124.39,78.11 v2(124.37,78.11)
  BOTTOM w0.152: v2(125.81,73.11) 125.67,73.25 125.67,74.41 UC1.BB23 ; UC1.BB32 120.63,73.5 v2(120.64,73.49)
  BOTTOM w0.203: UC1.BB41 115.61,74.39 v2(115.61,73.47) ; v2(109.57,73.51) UC1.BB51 ; UC1.BB47 112.02,73.51 v2(112.06,73.47)
  BOTTOM w0.254: v2(124.37,78.11) 124.37,77.63 UC1.AU23 ; UC1.AL23 125.36,80.96 125.36,81.64 v2(125.35,81.64) ; v2(115.24,80.06) 115.61,80.42 UC1.AM40 115.75,80.42 v2(116.14,80.03) ; v2(117.97,77.47) 118.28,77.17 UC1.AU35 ; UC1.AU28 121.93,77.17 v2(121.63,77.47) ; v2(114.32,77.47) UC1.AU42
  BOTTOM w0.305: v2(85.17,40.96) 85.43,40.96 86.12,40.27 JDIMM1.33 ; JDIMM2.135 120.23,26.14 120.59,26.51 v2(121.36,26.51) 121.58,26.51 121.91,26.18 121.91,25.72 121.72,25.53 JDIMM2.141 ; JDIMM2.12 v2(89.47,15.21) ; v2(91.95,28.93) 91.82,28.93 91.37,29.38 JDIMM1.54 ; JDIMM1.160 119.87,29.98 119.88,29.97 119.88,29.91 120.14,29.65 120.14,29.27 119.7,28.84 v2(119.59,28.84) ; v2(129.58,40.24) 129.59,40.24 129.61,40.22 129.61,40.19 129.62,40.17 JDIMM1.199 ; JDIMM2.54 v2(99.97,15.21) ; v2(114.94,15.14) 114.48,15.61 JDIMM2.112 ; v2(108.94,40.39) 108.8,40.39 108.62,40.22 JDIMM1.123 ; v2(138.75,26.76) 138.5,26.76 138.23,26.49 JDIMM2.199 ; 109.87,29.51 v2(109.87,29.49) ; 109.87,29.51 109.25,29.51 108.87,29.89 JDIMM1.124 ; 109.87,29.51 110.07,29.51 110.37,29.81 JDIMM1.130 ; JDIMM2.178 v2(132.97,15.21) ; v2(79.39,28.77) 80.34,28.77 80.87,29.3 JDIMM1.12 ; v2(96.12,26.63) 95.39,26.63 94.72,25.96 JDIMM2.33 ; JDIMM1.141 113.12,39.89 113.49,40.26 114.04,40.26 v2(114.17,40.39) ; JDIMM2.148 v2(125.47,15.21) ; JDIMM2.220 v2(143.47,15.21) ; JDIMM1.148 116.87,29.18 117.25,28.8 117.56,28.8 v2(117.6,28.77) 117.63,28.8 117.96,28.8 118.37,29.21 JDIMM1.154 ; JDIMM1.118 107.37,29.72 107.18,29.52 v2(107.14,29.52) 106.18,29.52 105.87,29.83 JDIMM1.112 ; JDIMM2.154 v2(126.97,15.21) 128.15,15.21 128.47,15.53 JDIMM2.160 ; JDIMM1.178 124.37,29.76 125.24,28.89 v2(125.6,28.89) ; JDIMM2.136 v2(120.47,15.21) ; JDIMM1.241 140.12,40.82 140.51,41.21 v2(140.6,41.21) ; JDIMM2.163 129.23,25.64 129.22,25.64 129.22,25.78 v2(129.06,25.94) 128.55,25.94 128.23,25.62 JDIMM2.159 ; v2(116.39,15.11) 115.97,15.53 JDIMM2.118 ; JDIMM1.96 101.87,29.23 102.16,28.94 102.81,28.94 v2(102.82,28.95) ; JDIMM1.75 96.62,40.57 96.83,40.77 v2(97.85,40.77) ; JDIMM2.142 v2(121.97,15.21) ; JDIMM1.135 111.62,40.03 111.29,40.36 v2(111.12,40.36) 110.61,40.36 110.12,39.88 JDIMM1.129 ; JDIMM2.147 125.23,25.73 125.6,26.1 v2(126.49,26.1) 126.72,25.86 JDIMM2.153 ; JDIMM1.111 105.62,40.54 105.97,40.89 v2(106.93,40.89) 106.86,40.83 106.86,40.13 107.12,39.87 JDIMM1.117 ; JDIMM2.123 117.22,26.04 117.73,26.54 v2(117.85,26.54) 118.18,26.54 118.72,26 JDIMM2.129 ; JDIMM2.111 114.22,26.03 114.8,26.61 115.82,26.61 v2(115.91,26.51) 115.72,26.32 JDIMM2.117 ; v2(106.17,26.67) 106.1,26.61 105.78,26.61 105.22,26.05 JDIMM2.75 ; v2(133.82,28.62) 133.84,28.63 134.1,28.63 134.87,29.41 JDIMM1.220 ; JDIMM1.159 119.62,39.92 v2(119.96,40.26) 120.38,40.26 120.62,40.01 JDIMM1.163 ; JDIMM1.147 116.62,39.92 116.96,40.26 v2(118.29,40.26) 118.12,40.09 JDIMM1.153 ; JDIMM1.136 111.87,29.81 112.28,29.4 v2(113.03,29.4) 113.37,29.74 JDIMM1.142 ; JDIMM2.124 v2(117.47,15.21) ; JDIMM2.130 v2(118.97,15.21)
  BOTTOM w0.33: v2(148.9,26.92) 148.71,26.92 148.25,26.46 148.25,26.12 148.71,25.65 148.71,24.67 JDIMM2.241
  BOTTOM w0.508: v2(75.08,55.37) 75.31,55.61 75.31,61.71 76,62.39 76,65.15 75.31,65.83 75.31,67.31 75.83,67.83 CC58.1 75.99,67.85 UC14.5
  vias: v3(78.63,53.15)
+1.2VP: length 43.9
  TOP w0.203: PU200.19 60.83,21.33 61.14,21.65 v2(61.14,21.78)
  IN2 w0.254: v2(78.35,22.42) 77.46,22.42 75.94,23.94 65.53,23.94 64.22,22.63 62.13,22.63 61.28,21.78 v2(61.14,21.78)
  IN2 w0.508: v2(78.35,23.05) 76.84,24.56 59.73,24.56 59.18,24 58.41,24 57.21,25.21 v2(57.21,26.61)
  vias: v1(79.77,22.81) v2(78.35,21.72) v2(78.35,21.02) v2(78.35,20.32) v2(79.05,23.05) v2(79.05,22.42) v2(79.05,21.72) v2(79.05,21.02) v2(79.05,20.32)
+1.5V_MEM_GFX: length 128.3
  TOP w0.102: v2(156.63,147.07) 156.32,147.38 v3(156.32,147.99)
  TOP w0.203: UV18.D2 173.3,160.48 172.7,159.88 UV18.B2 ; v2(173.27,166.16) 173.69,166.59 173.69,167.12 UV18.K8 ; v2(186.27,155.04) 186.65,155.04 187.3,154.39 UV20.K8
  TOP w0.254: UV20.B2 v2(186.16,145.32) ; UV18.H2 176.1,162.2 v2(176.09,162.19) ; v2(165.62,160.96) 165.74,160.83 167.02,160.83 CV400.1 ; v2(181.29,148.76) 181.34,148.71 UV20.A8 ; v2(167.91,161.74) 167.92,161.74 167.93,161.75 168.32,161.75 UV18.A8 ; UV18.N9 174.96,170.12 v2(174.97,170.13) ; UV20.F1 v2(188.99,147.01) ; UV18.R9 v2(175.53,170.66) ; UV20.N1 v2(192.95,152.1) ; UV20.N9 188.43,156.63 v2(188.99,157.2) UV20.R9 ; UV20.G7 186.11,151.59 v2(186.11,152.14) ; UV20.A1 185.7,144.75 v2(185.6,144.65) 185.6,142.82 CV188.1 ; v2(178.41,162.66) 178.41,163.25 177.79,163.87 UV18.K2 ; UV18.R1 180.62,165.5 v2(180.54,165.42) 180.12,165 UV18.N1 ; UV20.D2 UV20.C1 187.83,145.88 v2(187.85,145.86) ; UV20.R1 v2(194.08,152.11) ; 169.87,165 v2(169.85,165.02) ; 169.87,165 UV18.D9 169.87,163.87 v2(169.87,163.87) UV18.C9 ; 169.87,165 UV18.E9 ; v2(177.35,172.47) 177.85,172.97 CV196.1 ; UV18.C1 174.12,159.06 v2(174.38,159.06) 175.07,159.75 v2(175.07,159.77) 175.53,160.23 UV18.F1 ; v2(170.81,168.66) 170.67,168.8 CV397.1 ; UV18.G7 v2(172.14,165) ; v2(190.69,149.84) UV20.K2 ; v2(171.7,158.31) 172.6,158.31 UV18.A1 ; UV20.C9 v2(182.36,150.82) ; v2(189.56,149.82) UV20.H2 ; v2(172.19,167.3) 172.14,167.24 UV18.H9 ; UV20.H9 185.1,153.24 v2(185.03,153.17) ; v2(183.9,152.11) UV20.E9 ; v2(183.9,150.97) UV20.D9
  TOP w0.305: v2(172.12,159.41) 172.19,159.34 UV18.B2 ; UV18.C1 UV18.D2
  TOP w0.381: v2(196.71,149.93) 196.16,150.48 CV398.1 ; CV44.1 168.64,166.41 v2(168.64,166.32) ; CV45.1 167.33,166.23 v2(166.68,166.88) ; v2(165.15,164.6) 165.29,164.6 CV401.1 ; CV395.1 196.34,153.54 v2(196.34,153.29)
  TOP w0.508: CV43.1 191.4,159.91 v2(192.02,160.53) ; CV52.1 168.71,135.31 v2(168.43,135.59) 168.38,135.64 CV178.1 ; v2(176.46,174.18) 176.02,174.62 CV182.1 ; v2(194.27,149.77) 194.74,149.29 CV183.1 ; CV177.1 171.18,134.49 v2(170.67,133.98) 170.17,133.48 CV176.1 ; CV51.1 CV40.1 166.55,135.81 v2(166.38,135.99) 165.89,135.99 CV175.1 ; v2(188.4,142.04) 188.39,142.04 CV184.1 ; CV185.1 189.22,143.71 v2(189.67,143.26) ; v2(178.24,135.45) 178.67,135.01 CV47.1 CV50.1 ; RV150.1 v2(191.95,144.41) ; v2(174.21,175.09) 174.61,174.69 RV139.1 ; CV171.1 v2(156.63,147.07)
  IN1 w0.203: v2(185.03,153.17) 185.03,152.67 185.56,152.14 v2(186.11,152.14) ; v2(173.27,166.16) 173.67,165.77 173.67,164.85 173.41,164.59 173.03,164.59 172.62,165 v2(172.14,165)
  IN1 w0.254: v2(173.27,166.16) 173.79,166.69 173.79,167.58 173.48,167.89 172.79,167.89 v2(172.19,167.3)
  IN1 w0.305: v2(176.09,162.19) 174.99,162.19 v2(174.96,162.22)
  IN2 w0.381: v2(192.95,152.1) 192.96,152.11 v2(194.08,152.11) ; v2(188.99,147.01) 190.12,147.01 190.68,147.57 v2(190.68,148.36) 190.69,148.36 v2(190.69,149.84) 190.67,149.82 v2(189.56,149.82) 189.53,149.8 v2(188.46,149.8)
  BOTTOM w0.203: UV18.K2 177.23,163.34 177.64,162.93 178.14,162.93 v2(178.41,162.66)
  BOTTOM w0.254: v2(189.56,149.82) 189.56,149.84 189.97,150.26 190.27,150.26 190.42,150.41 UV20.K2 v2(190.69,149.84) ; UV18.N9 174.96,170.12 v2(174.97,170.13) ; v2(167.64,162.94) 167.84,162.74 UV17.A1 ; UV17.H2 172.73,166.16 v2(173.27,166.16) 173.3,166.16 173.76,166.63 173.76,167.19 UV18.K8 ; v2(170.99,166.22) 171,166.21 UV17.F1 ; UV1.H13 169.86,137.18 v2(169.9,137.13) ; CV186.1 176.68,158.48 v2(176.27,158.89) ; UV17.D9 174.54,159.77 v2(175.07,159.77) 175.07,160.37 UV17.E9 ; UV19.F1 v2(183.9,152.11) 183.9,152.81 184.26,153.17 v2(185.03,153.17) ; UV18.N1 180.12,165 v2(180.54,165.42) 180.62,165.5 UV18.R1 ; v2(192.02,160.53) 191.86,160.53 CV43.1 ; UV17.D2 v2(169.87,163.87) UV18.C9 ; v2(190.68,148.36) 190.33,148.71 UV19.H9 ; UV19.H2 186.11,152.62 v2(186.11,152.14) ; UV20.K8 187.3,154.37 186.62,155.04 v2(186.27,155.04) ; UV17.G7 v2(174.96,162.22) ; v2(162.36,141.34) 162.36,141.69 UV1.K23 162.16,141.89 v2(162.16,142.42) ; v2(185.6,144.65) 185.6,144.66 UV19.A8 v2(186.16,145.32) ; UV20.N9 188.43,156.8 188.83,157.2 v2(188.99,157.2) UV20.R9 ; UV17.A1 168.18,162 v2(167.91,161.74) ; UV17.A1 UV17.B2 ; v2(188.99,147.01) UV19.E9 ; UV1.L11 UV1.K10 170.03,134.49 v2(170.07,134.53) 170.12,134.58 UV1.J10 ; v2(174.38,159.06) 174.12,159.06 UV18.C1 ; v2(175.53,170.66) UV18.R9 ; UV1.J24 162.71,142.98 v2(162.72,142.99) 162.77,142.94 UV1.J23 162.17,142.41 v2(162.16,142.42) ; v2(162.16,142.42) 162.15,142.41 UV1.K24 ; v2(182.36,150.82) UV20.C9 ; v2(183.9,150.97) UV19.D2 ; v2(172.12,159.41) 172.14,159.4 UV17.A8 172.14,158.74 v2(171.7,158.31) ; UV1.K9 170.62,133.93 v2(170.67,133.98) 170.69,134 UV1.J9 ; v2(168.06,138.64) 167.82,138.88 UV1.H16 ; UV19.G7 188.46,149.31 v2(188.46,149.8) ; UV19.D9 187.86,145.87 v2(187.85,145.86) 187.32,145.86 UV20.C1 ; UV20.N1 v2(192.95,152.1)
  BOTTOM w0.305: CV187.1 178.48,160.29 v2(178.07,160.7) ; UV17.H9 176.11,162.17 v2(176.09,162.19)
  BOTTOM w0.381: v2(162.36,141.34) 162.36,140.88 UV1.L22 ; v2(163.44,140.84) 162.91,140.31 UV1.L21 UV1.L20 ; UV1.L11 UV1.L12 168.05,135.2 v2(168.43,135.59) ; UV1.L13 166.46,135.91 v2(166.38,135.99) ; CV212.1 196.9,153.85 ; RV32.1 153.74,149.03 v2(153.22,149.03) ; v2(151.25,147.26) 150.93,146.94 150.93,145.31 RV33.1 ; v2(165.6,141.28) 165.6,140.71 UV1.H19 ; CV196.1 177.85,172.97 v2(177.35,172.47)
  BOTTOM w0.508: CV198.1 196.01,150.75 v2(195.59,151.18) ; CV133.1 173.35,171.47 v2(173.79,171.03) ; CV402.1 174.39,172.47 v2(175,172.47)
  vias: v2(135.12,156.78) v2(135.12,156.15) v2(135.12,155.45) v2(135.82,156.78) v2(135.82,156.15) v2(135.82,155.45) v2(136.45,156.78) v2(136.45,156.15) v2(136.45,155.45) v2(137.15,156.78) v2(137.15,156.15) v2(137.15,155.45) v2(154.43,156.84) v2(154.43,156.15) v2(155.19,156.84) v2(155.19,156.15) v2(155.95,156.84) v2(155.95,156.15) v2(167.45,168.08) v2(167.61,165.23) v2(188.95,144.48) v2(190,145.53) v2(192.02,147.55) v2(195.75,148.27) v2(199.07,152.3)
+1.5VGPUP: length 24.7
  BOTTOM w0.102: v1(138.61,147.37) 137.78,148.21 PC1412.1
  BOTTOM w0.254: 125.18,138.37 125.52,138.37 125.64,138.5 PC1409.1 ; 125.18,138.37 125.2,138.35 PR1410.2 ; 125.18,138.37 124.01,138.37 123.35,139.03 123.35,139.39 123.35,141.56 125.41,143.61 125.41,148.78 126.55,149.92 131.5,149.92 132.26,149.16
+1.8V_AVDD: length 5.6
  BOTTOM w0.203: HDA27.40 184.57,12.47 185.66,11.38 v3(185.87,11.38)
  BOTTOM w0.254: v3(185.87,11.38) 185.9,11.38 C2715.1 187.29,9.98 R6511.2
+1.8V_PRIM: length 121.9
  TOP w0.508: RC361.1 141.47,85.47 141.15,85.15 140.48,85.15 v2(140.33,85.3) 139.64,85.3 v2(139.61,85.33) ; CC212.1 129.61,84.82 130.03,84.41 v2(130.03,84.12)
  TOP w1.016: 159.54,82.43 159.54,81.62 163.8,77.37 164.34,77.37 171.13,70.58 171.13,67.06 172.81,65.38 174.2,65.38 176.71,62.86 176.71,60.79 182.34,55.16 182.34,50.76 187,46.1 187,39.12 v2(185.6,37.72)
  IN1 w0.254: 120.92,92.37 122.27,92.37 122.81,91.83 122.81,90.76 122.9,90.67 121.57,90.67 121.24,91 121.24,91.77 120.78,92.23 120.92,92.37
  IN1 w0.508: 120.78,92.23 115.21,92.23 115.06,92.07 112.9,92.07 112.64,92.33 103.32,92.33 v2(103.28,92.37) ; 122.9,90.67 123.33,90.67 123.66,90.34 123.66,87.6 v2(124.63,86.64)
  IN1 w1.016: 196.53,20.64 196.53,21.91 195.64,22.8 195.64,34.42 194.49,35.56 189.57,35.56 187.92,37.21 186.68,37.21
  BOTTOM w0.203: v2(139.61,85.33) 139.14,85.33 138.59,85.88 UC1.AA1
  BOTTOM w0.254: UC1.AF16 129.69,83.78 v2(130.03,84.12) ; UC1.H63 102.98,92.07 v2(103.28,92.37) 103.57,92.66 UC1.G61
  BOTTOM w0.508: v2(139.61,85.33) 139.61,85.5 140.25,86.13 140.66,86.13 CC272.1 ; Q6205.1 v2(196.53,19.18) v2(196.53,19.81)
  vias: v2(140.2,156.91) v2(140.84,157.54) v2(140.84,156.91) v2(141.47,157.54) v2(148.2,100.84) v2(148.65,100.39) v2(149.09,99.95) v2(149.54,99.57) v2(158.87,83.95) v2(158.87,83.31) v2(159.57,83.95) v2(159.57,83.31) v2(160.27,83.95) v2(160.27,83.31) v2(173.73,37.53) v2(173.73,36.96) v2(174.31,37.53) v2(174.31,36.96) v2(174.9,37.53) v2(174.9,36.96) v2(185.98,38.16) v3(149.76,96.13)
+1.8VALWP: length 9.5
  BOTTOM w0.254: PC507.1 175.76,31.3 175.76,30.42 v1(176.78,29.4) 176.78,25.41 176.33,24.97 176.33,24.64 175.47,23.77 PR503.2 PC503.1
+1.8VGS: length 84.2
  TOP w0.381: RV11.1 152.79,129.62 152.79,128.88 152.23,128.32 152.23,127.84 152.41,127.66 ; LV2.1 151.24,126.19 151.24,126.85 152.05,127.66 152.41,127.66 ; 152.41,127.66 152.45,127.62 153.33,127.62 RV28.1
  TOP w0.457: RV8.1 156.06,129.41 v2(156.5,128.98)
  TOP w0.508: LV7.1 178.11,128.39 176.76,127.04 176.76,126.15 176.09,125.48 175.7,125.48 v2(175.19,124.97) ; v2(171.58,128.3) 171,128.88 LV6.1 ; v2(167.38,121.68) 167.38,121.07 168.05,120.4 v2(168.05,119.2)
  IN1 w0.254: v2(151.25,123.76) 151.25,120.81 151.96,120.1 151.96,106.98 152.65,106.3 v2(153.28,106.3)
  IN2 w0.508: v2(168.05,119.2) 170.49,119.2 172.14,120.85 v2(172.14,121.44) 175.19,124.49 v2(175.19,124.97) 173.57,124.97 171.43,127.11 171.43,128.14 v2(171.58,128.3) ; v2(153.16,123.38) 153.85,124.08 158.67,124.08 161.07,121.68 v2(167.38,121.68)
  BOTTOM w0.254: v2(156.5,128.98) 156.5,128.8 154.23,126.54 154.23,125.32 153.16,124.24 v2(153.16,123.38) ; PR1113.1 153.72,105.86 v2(153.28,106.3) ; UV1.AM30 148.04,133.93 v2(148.11,133.86)
  BOTTOM w0.508: v2(172.14,121.44) 172.14,122.07 171.54,122.67 RV82.2 RV81.2 ; v2(175.19,124.97) 174.57,125.59 RV152.2 ; RV71.1 151.01,119.8 151.01,121.23 v2(153.16,123.38)
  vias: v3(141.55,136.46)
+1.8VGS_GPU_ON: length 4.9
  TOP w0.102: R437.2 140.67,158.19 v1(139.17,158.19)
  TOP w0.203: U15.5 142.21,157.31 141.98,157.54 C987.2
  TOP w0.508: C987.2 R437.2
+1.8VGS_OUT:
  vias: v1(140.29,154.64)
+1VALWP: length 11.2
  TOP w0.254: v2(137.31,118.53) 137.52,118.75 v1(137.52,123.73) v2(135.95,125.3)
  BOTTOM w0.254: PC309.1 135.29,125.31 135.3,125.3 v2(135.95,125.3) 135.95,126.45 PR309.2
  vias: v2(136.07,117.92) v2(136.65,117.92) v2(137.24,117.92)
+2.5V_MEM: length 127
  TOP w2.032: 148.11,32.92 151.72,29.31 151.72,29.26 153.33,27.65 153.33,25.27
  IN1 w2.032: 159.39,16.38 155.14,12.13 83.34,12.13 82.71,12.76 79.33,12.76 78.7,12.13 65.36,12.13 63.77,13.72 63.77,17.72 65.87,19.81 65.87,24.6 70.72,29.45 70.72,29.46
  vias: v2(70.73,32.19) v2(70.73,31.56) v2(70.73,30.92) v2(71.37,31.56) v2(71.37,30.92) v2(71.43,32.19) v2(146.11,37.47) v2(146.11,36.89) v2(154.82,24.8) v2(154.82,24.2) v2(159.51,17.77) v2(159.91,18.2) v2(160.5,17.98) v2(160.64,18.55) v3(158.27,18.15)
+2.5VP: length 2.4
  BOTTOM w0.102: 68.69,32.23 68.69,32.91 69.75,33.97 v1(69.75,34.16)
+3.3V_ALW_DSW: length 93.6
  TOP w0.508: v2(132.98,69.55) 132.39,68.96 132.39,67.75 140.01,60.13 v1(142.06,60.13) RC243.2 RC1102.1 143.68,61.47 144.19,61.98 145.71,61.98 146.22,62.48 v2(146.22,63.18) RC72.2 ; v2(160.01,60.77) 160.01,62.3 157.92,64.39 157.92,66.23 158.87,67.19 158.87,68.57 157.91,69.53 157.02,69.53 156.34,70.22 156.03,70.22 155.82,70.42 RC70.1
  IN1 w0.254: v2(132.98,69.55) 131.61,70.92 130.55,70.92 129.13,72.34 129.13,73.06 125.75,76.45 125.75,80.55 126.2,81.01 128.15,81.01 v2(128.76,81.62)
  IN1 w0.508: v2(147.27,88.2) 146.82,88.2 146.66,88.04 144.42,88.04 143.48,87.1 141.51,87.1 141.28,86.87 140.41,86.87 140.03,87.25 139.15,87.25 138.96,87.07 134.12,87.07 131.84,84.79 131.73,84.79 130.79,84.78 129.21,84.78 128.73,84.3 v2(128.73,84.12)
  IN2 w0.254: v2(128.73,84.12) 128.73,81.69 128.76,81.65 v2(128.76,81.62)
  IN2 w0.508: v2(146.22,63.18) 151.54,63.18 152.35,63.99 156.79,63.99 v2(160.01,60.77)
  BOTTOM w0.254: UC1.AJ17 129.02,82.03 128.76,81.69 128.77,81.63 v2(128.76,81.62) ; UC1.AD17 v2(128.73,84.12) 128.66,84.2 UC1.AD18
+3.3V_HDA: length 27.1
  TOP w0.076: CC215.1 128.48,81.15 v1(128.48,79.76)
  TOP w0.254: RC396.2 148.14,85.85 147.63,85.34 v2(147.63,85.09)
  TOP w0.381: CC215.1 v2(127.4,81.61)
  IN1 w0.254: v2(127.4,81.61) 127.53,81.74 128.21,81.74 128.71,82.23 129.09,82.23 129.79,82.93 131.12,82.93 131.57,83.38 136.26,83.38 136.71,83.82 140.07,83.82 140.65,83.25 144.99,83.25 146.32,84.58 147.12,84.58 v2(147.63,85.09)
  BOTTOM w0.254: v2(127.4,81.61) 127.4,81.74 127.69,82.03 UC1.AJ19
+3.3V_LAN_UZ2: length 2.8
  TOP w0.102: 43.52,18.36 43.52,18.72 v1(41.76,20.47)
+3.3V_SPI: length 62.4
  TOP w0.508: v2(149.64,75.93) 150.22,76.52 RC213.2
  IN1 w0.254: v2(130.05,82.41) 130.05,82.3 130.36,81.99 131.51,81.99 131.84,82.32 131.92,82.32 131.99,82.39 133.57,82.39 133.66,82.3 141.98,82.3 142.11,82.42 146.57,82.42 149.71,85.56 151.74,85.56 152.39,84.91 153.12,84.91 153.55,84.48 155.73,84.48 158.04,82.17 v2(158.04,81.47)
  IN1 w0.508: v2(149.64,75.93) 149.64,73.4 v2(149.91,73.13) ; v2(158.04,81.47) 158.04,79.88 158.83,79.1 v2(158.83,78.56) 160.27,77.12 160.27,72.8 159.25,71.78 v2(159.25,71.75)
  IN2 w0.508: v2(149.64,75.93) 150.2,76.49 154.63,76.49 v2(155.06,76.07) 155.47,76.07 157.41,78 158.28,78 v2(158.83,78.56)
  BOTTOM w0.254: v2(130.05,82.41) 129.69,82.05 UC1.AJ16
  BOTTOM w0.508: v2(155.06,76.07) 155.06,76.07 RC31.1 ; RC339.1 v1(158.72,81.66) 158.24,81.66 v2(158.04,81.47) ; RC30.1 150.07,73.67 150.07,73.3 v2(149.91,73.13)
+3.3V_WLAN: length 3.3
  TOP w0.102: v2(174.53,44.4) v3(172.94,44.4) ; v2(174.53,44.4) v3(174.53,45.34) ; v2(174.53,44.4) 174.53,43.65 v3(174.48,43.6)
+3V_1.8V_CPVDD: length 31.2
  TOP w0.508: v2(187.28,13.62) 186.46,13.62 186.16,13.92 C6215.1 186.16,14.6 185.63,15.14 185.06,15.14 184.46,14.54 C6213.1 184.46,14.17 183.85,13.56 182.91,13.56 182.11,12.76 v1(180.12,12.76) 178.96,12.76 177.83,11.63 177.83,9.37 v2(176.23,7.77)
  BOTTOM w0.203: v2(187.28,13.62) 187.28,13.81 187,14.09 HDA27.36
  BOTTOM w0.508: R2705.2 188.19,7.01 187.28,6.1 177.91,6.1 v2(176.23,7.77)
+3V_DVDD: length 4.8
  TOP w0.508: C2716.1 178.94,15.43 178.43,14.92 177.91,14.92 177.4,14.41 R6512.1
  BOTTOM w0.203: HDA27.9 179.67,17.29 v2(179.48,17.48)
  BOTTOM w0.508: v2(178.3,21.78) 178.3,21.81 178.42,21.92 R2722.1
  vias: v1(181.62,13.41) v2(180.65,13.46)
+3VALW: length 695.4
  TOP w0.254: RPE6.4 172.54,76.69 ; RPE6.2 172.49,77.69 ; RPE7.1 172.46,72.84 ; RPE7.2 172.47,72.34 ; RPE6.1 172.49,78.19 ; RPE7.4 172.48,71.34 ; RPE6.3 172.54,77.19 ; RPE7.3 172.48,71.84 ; PR209.1 53.56,19.52 51.36,21.72 v2(51.36,22.67)
  TOP w0.381: v2(146.33,81.34) 146.33,81.46 146.63,81.76 RC73.2 ; QC4.2 35.11,10.52 v2(34.83,10.24) 35.11,9.96 QC4.5 ; UC17.5 171.36,91.23 CC299.1
  TOP w0.508: v2(54.6,73.72) v2(54.6,74.49) R6215.1 ; PR756.2 109.91,165.04 112.64,167.77 v2(115.83,167.77) PR16.2 PR28.1 115.44,168.66 114.99,169.1 114.99,173.55 116.74,175.29 v2(116.8,175.29) ; 172.78,26.54 174.94,26.54 176.14,27.75 176.59,27.75 180.26,31.42 D2502.2 183.36,30.82 183.76,30.42 v2(184.78,30.42) ; CC299.1 172.03,89.48 171.98,89.44 v2(171.92,89.44) ; v2(93.02,149.48) 92.56,149.94 PR3.2 ; RE25.1 v2(185.35,86.61) ; v2(186.7,62.61) 187.25,63.17 RE385.2 ; v2(142.17,119.51) 143.82,119.51 144.46,118.87 144.46,115.82 ; v2(124.01,140.41) 124.01,140.32 124.9,139.43 124.9,134.56 124.39,134.05 v2(124.07,134.05) ; RE408.2 196.84,66.92 v2(196.84,67.75) ; PR791.1 68.13,169.33 69.25,170.45 69.25,171.28 69.4,171.44 v2(69.4,172.34)
  TOP w1.016: 166.94,71.32 167.05,71.21 167.05,70.43 169.44,68.05 169.44,66.1 172.03,63.5 173.28,63.5 173.73,63.06 173.73,61.48 173.69,61.44 173.69,60.54 179.68,54.55 179.68,51.98 ; 154.22,87.27 155.66,87.27 156.71,86.23 156.71,83.89 157.14,83.46 157.14,80.98 157.88,80.24 157.88,80.01
  IN1 w0.254: v2(146.33,81.34) 146.33,81.64 149.87,85.18 151.58,85.18 152.23,84.53 152.96,84.53 153.39,84.1 155.57,84.1 157.47,82.2 157.47,79.37 v2(158.04,78.8)
  IN1 w0.508: v2(133.79,154.05) 133.62,154.05 129.81,150.24 124.83,150.24 124.01,149.42 111.18,149.42 v2(110.17,150.43) 110.17,153.86 110.36,154.05 110.36,157.86 110.67,158.18 110.67,159 110.29,159.39 110.29,166.05 112.01,167.77 v2(115.83,167.77) ; v2(127.37,106.75) 127.37,104.69 124.6,101.92 123.44,101.92 v2(122.02,100.5) ; v2(37.84,51.37) 37.84,48.26 39.05,47.05 48.44,47.05 51.36,44.14 v2(51.43,44.14) ; v2(179.76,59.82) 182.05,57.53 185.35,57.53 186.39,58.57 186.39,62.31 v2(186.7,62.61) ; v2(197.35,76.2) v2(197.35,75.18) 197.35,68.26 v2(196.84,67.75) ; v2(93.02,149.48) 93.01,149.48 90.57,151.92 84.51,151.92 v2(84.5,151.93) ; v2(190.42,87.38) 190.42,86.75 189.84,86.17 188.91,86.17 187.85,87.22 186.28,87.22 185.67,86.61 v2(185.35,86.61) ; v2(188.78,81.47) 188.02,81.47 187.51,80.96 187.51,80.26 186.68,79.44 v2(186.11,79.44)
  IN2 w0.508: v2(161.37,47.05) 161.37,49.31 158.81,51.88 158.81,53.39 v2(156.69,55.5) ; v2(124.07,134.05) 124.9,134.05 127.23,131.71 132.16,131.71 132.94,130.94 132.96,130.94 v2(133.09,130.81) 133.09,142.36 133.09,142.5 133.09,146.94 134.17,148.02 134.17,151.32 134.87,152.02 134.87,153.1 133.91,154.05 v2(133.79,154.05) ; v2(142.17,119.51) 142.17,119.44 142.12,119.39 142.12,118.88 141.09,117.86 141.09,111.33 138.41,108.65 134.28,108.65 133.39,107.76 130.41,107.76 129.4,106.75 v2(127.37,106.75) ; v2(122.02,100.5) 121.85,100.33 116.07,100.33 115.56,99.82 114.04,99.82 111.89,101.97 105.57,101.97 105.5,102.03 101.31,102.03 98.93,104.42 98.93,105.43 97.71,106.64 93.68,106.64 90.73,103.7 90.73,101.66 75.32,86.25 73.54,86.25 68.51,81.22 v2(68.51,80.33) ; v2(196.84,67.75) 197.35,67.25 197.35,66.53 198.18,65.7 198.18,63.56 198.75,62.99 v2(198.75,61.25) ; v2(185.35,86.61) 185.6,86.61 185.97,86.98 v2(185.97,92.34)
  IN2 w1.016: 197.29,166.24 185.1,178.44 173.6,178.44 171.25,176.09 161.16,176.09 157.28,172.21
  BOTTOM w0.508: v2(188.78,81.47) 188.32,81.93 RE73.1 RE74.1 188.32,84.2 RE75.1 RE72.1 188.19,85.48 188.59,85.88 189.4,85.88 190.42,86.9 v2(190.42,87.38) ; PC1422.1 53.74,73.89 v2(53.9,73.72) ; RC68.2 156.57,55.63 v2(156.69,55.5) ; v2(142.17,119.51) 142.17,119.57 142.12,119.62 142.12,123.44 141.61,123.95 139.03,123.95 138.08,124.9 136.77,124.9 ; v2(54.6,73.72) 55.3,73.72 56.89,72.14 63.19,72.14 65.97,74.92 67.11,74.92 68.51,76.31 v2(68.51,80.33) ; 136.77,124.9 136.26,124.4 PR303.1 ; 136.77,124.9 136.77,126.05 136.56,126.26 136.56,129.22 135.86,129.92 PR304.1 135.25,130.3 134.74,130.81 v2(133.09,130.81) ; v2(171.92,89.44) 171.98,89.44 172.24,89.7 174.72,89.7 177.48,92.46 182.35,92.46 183.43,93.54 185.24,93.54 185.97,92.81 v2(185.97,92.34) 185.97,90.19 RE71.1 ; v2(110.17,150.43) 107.5,150.43 106.12,149.05 96.98,149.05 96.55,149.48 v2(93.02,149.48) ; v2(124.01,140.41) 124.01,140.47 124.01,140.48 PR1405.1 ; R5810.1 v2(172.71,39.56) ; v2(124.07,134.05) 124.97,134.05 PR1406.1 ; R2713.2 185.15,30.05 v2(184.78,30.42) ; R2608.1 121.9,100.37 v2(122.02,100.5) ; v2(179.76,59.82) 183.64,55.94 189.35,55.94 189.67,56.26 192.59,56.26 197.58,61.25 v2(198.75,61.25) ; v2(51.43,44.14) 53.2,44.14 53.21,44.13
  BOTTOM w1.016: 156.08,171.7 150.93,171.7 149.92,172.72 149.92,174.24 148.84,175.32 139.25,175.32 134.99,179.58 132.77,179.58 131.63,178.44 131.63,176.97 130.68,176.02 117.53,176.02 v2(116.8,175.29) 116.01,174.5 108.51,174.5 107.31,175.7 74.73,175.7 71.37,172.34 70.99,172.34
  BOTTOM w1.524: 53.59,37.47 53.59,41.72 53.21,42.1 53.21,61.4 51.85,62.76 ; 50.45,64.8 50.48,64.82 50.48,68.55 53.9,71.98 53.9,72.33
  vias: v2(34.85,21.84) v2(34.85,21.21) v2(34.85,20.57) v2(34.85,19.94) v2(34.85,19.3) v2(35.49,21.84) v2(35.49,21.21) v2(35.49,20.57) v2(35.47,19.96) v2(35.49,19.3) v2(36.12,21.84) v2(36.12,21.21) v2(36.12,20.57) v2(36.12,19.94) v2(36.12,19.3) v2(43.43,25.02) v2(43.43,24.38) v2(44.06,25.02) v2(44.06,24.38) v2(44.7,25.02) v2(52.83,36.32) v2(52.83,35.69) v2(53.52,36.32) v2(53.52,35.69) v2(54.22,36.32) v2(54.22,35.69) v2(68.76,173) v2(68.76,172.34) v2(69.4,172.97) v2(70.48,166.81) v2(70.48,166.18) v2(71.11,166.81) v2(71.11,166.18) v2(81.4,151.96) v2(81.4,151.32) v2(82.04,151.96) v2(82.04,151.32) v2(150.62,88.96) v2(151.38,88.96) v2(156.84,170.94) v2(157.47,170.94) v2(165.16,72.64) v2(165.16,72.01) v2(165.16,71.37) v2(165.79,72.64) v2(165.79,72.01) v2(165.79,71.37) v2(169.79,20.64) v2(169.79,20.07) v2(170.43,20.64) v2(170.43,20.07) v2(171.25,72.77) v2(171.25,72.07) v2(171.32,20.38) v2(171.32,19.81) v2(172.01,20.38) v2(172.01,19.81) v2(175.81,76.13) v2(175.81,75.55) v2(179.13,50.99) v2(179.13,50.36) v2(179.44,60.39) v2(198.18,166.24) v2(198.88,166.24) v3(66.68,175.08) v3(80.59,152.27) v3(168.97,28.82)
+3VALW_EC: length 121.6
  TOP w0.203: UE1.82 175.96,74.37 ; CE68.1 175.92,81.17 UE1.65 ; v2(180.55,65.06) 180.63,65.14 180.9,65.14 181.55,65.78 UE1.103 ; v2(186.81,65.66) 186.81,65.28 186.38,64.85 CE81.1 186.35,64.87 UE1.115 ; UE1.5 194.42,70.37 194.74,70.05 CE64.2 195.64,70.04 195.19,69.6 v2(194.94,69.6) ; v2(191.89,77.05) 192.01,77.17 UE1.22 ; v2(186.75,84.2) 186.98,84.2 187.55,83.64 UE1.43 ; v2(191.89,76.01) 191.95,76.01 191.99,75.97 UE1.19
  TOP w0.508: RE345.1 185.6,60.2 v2(185.22,59.82) 185.01,59.61 v1(183.72,59.61) 183.34,59.61 182.62,60.32 R2446.1 ; 175.96,74.37 174.58,74.37 CE69.1 v2(174.57,73.67) ; RE348.2 184.46,86.68 185.16,87.38 v2(185.35,87.38) ; CE68.1 175.09,80.95 v2(175.01,81.03) ; RE427.2 RE426.2 RE425.2 RE424.2 197.17,70.7 CE67.1 CE64.2
  IN2 w0.508: v2(175.01,81.03) 176.14,81.03 178.11,79.06 178.11,73.6 178.43,73.28 v2(179.06,73.28)
  BOTTOM w0.508: 193.38,69.6 193.38,74.52 v2(191.89,76.01) 191.52,75.64 CE66.1 CE79.1 191.37,76.76 191.66,77.05 v2(191.89,77.05) 192.48,77.05 192.78,77.34 192.78,78.55 192.27,79.06 189.73,79.06 ; 193.38,69.6 193.38,69.06 194.04,68.4 194.04,65.9 193.3,65.16 191.55,65.16 190.75,64.36 190.75,63.5 187.06,59.82 v2(185.22,59.82) 185.22,61.28 185.76,61.81 185.76,63.59 186.81,64.64 v2(186.81,65.66) 186.12,65.66 185.42,64.96 184.78,64.96 183.89,65.85 CE62.1 183.13,66.85 RE354.1 182.68,66.23 181.51,65.06 v2(180.55,65.06) 180.05,65.06 178.36,66.74 178.36,68.83 176.27,70.93 176.27,72.26 176.84,72.83 176.97,72.83 ; 193.38,69.6 v2(194.94,69.6) ; 189.73,79.06 188.7,80.09 188.19,80.09 188.18,80.09 188.01,80.26 187.96,80.26 187.41,80.81 187.41,82.89 186.9,83.39 CE65.1 v2(186.75,84.2) 186.75,85.72 186.24,86.23 186.24,86.87 185.73,87.38 v2(185.35,87.38) ; 189.73,79.06 189.73,78.92 RE440.2 ; 176.97,72.83 178.62,72.83 v2(179.06,73.28) ; 176.97,72.83 176.65,73.15 RE343.1 175.25,74.29 175.19,74.36 CE69.1 v2(174.57,73.67) 174.55,73.66 CE89.1
+3VALW_PCH: length 87.1
  TOP w0.508: v2(151.52,79.74) 151.52,78.57 150.87,77.91 RC213.1 149.99,77.91 149.76,77.68 RC186.1 RC183.1 ; v2(153.6,71.27) 152.75,71.27 RC74.1 RC288.2 152.47,69.34 v2(151.1,67.97)
  IN1 w0.508: v2(145.73,88.96) 144.01,88.96 141.82,91.15 141.82,93.5 140.52,94.81 v2(140.52,95.31) 140.52,97.28 139.88,97.92 139.5,97.92 139.19,98.23 v2(139.19,102.36) ; 151.52,79.74 151.52,79.3 153.15,77.66 153.15,76.93 153.07,76.84 153.07,71.81 v2(153.6,71.27) ; 151.52,79.74 151.52,82.38 151.06,82.84 v2(151.06,83.44) ; 151.52,79.74 v2(151.52,79.74) ; v2(151.1,67.97) 149.79,66.66 149.79,59.32 152.46,56.65 152.46,51.84 152.99,51.31 v2(153.08,51.31)
  BOTTOM w0.254: v2(130.78,84.05) 130.78,84.09 UC1.AD15 ; UC1.AJ21 126.44,82.22 126.09,82.57 126.09,82.58 126.04,82.63 126.04,83.2 v2(126.1,83.26) ; v2(129.35,87.44) UC1.T16 ; v2(127.41,86.58) 127.41,86.73 UC1.V19 ; UC1.AG15 130.64,82.57 v2(130.64,82.45) ; UC1.Y15 130.34,86.27 v2(130.01,86.59) 129.69,86.27 UC1.Y16 ; v2(130.77,80.65) UC1.AK15 ; v2(128.93,80.61) 129.04,80.71 UC1.AK17
  BOTTOM w0.508: RC187.1 152.96,51.18 153.09,51.31 v2(153.08,51.31) ; RC246.2 141.1,95.31 v2(140.52,95.31) ; RC365.2 154.79,80.16 154.45,79.82 153.02,79.82 152.49,80.35 151.98,80.35 151.52,79.89 v2(151.52,79.74) ; RC369.2 141.21,66.93 143.13,65.01 145.03,65.01 145.76,64.29 147.84,64.29 151.1,67.55 v2(151.1,67.97) ; RC387.2 152.66,85.99 v2(152.9,86.23) 152.9,86.68 153.09,86.87 RC12.2 RC14.2
  vias: v2(128.03,82.41) v2(146.36,88.96) v3(152.04,84.39)
+3VALWP: length 30
  TOP w0.102: v2(33.69,27.2) v1(32.77,27.2)
  TOP w0.254: PR107.1 PR113.1 38.22,39.54 38.78,39.54 v2(39.2,39.12)
  IN2 w0.254: v2(37.39,29.72) 37.97,29.72 38.79,30.54 38.79,37.4 39.43,38.04 39.43,38.89 v2(39.2,39.12)
  BOTTOM w0.254: v2(37.39,29.72) 36.61,29.72 PC107.1 36.56,30.23 38.28,30.23 38.79,30.73 38.79,37.27 38.22,37.85 35.59,37.85 PU100.14 ; PR108.2 39.22,39.14 v2(39.2,39.12) 39.2,39.19 39.1,39.09 38.16,39.09 PR109.1
  vias: v2(33.69,26.34) v2(35.31,27.08) v2(35.34,26.37)
+3VGS: length 99.5
  TOP w0.305: QV1.2 QV1.5 172.27,124.49 172.27,124.06 v2(172.09,123.88)
  TOP w0.381: CV10.1 183.1,121.79 182.59,122.3 UV11.1
  TOP w0.508: v2(172.09,127.79) 171.68,127.38 RV6.1 170.78,127.98 ; CV10.1 183.19,121.16 181.18,119.15 v2(178.99,119.15) 178.99,120.62 v3(179.27,120.9) 180.39,122.02 v2(180.39,122.92) ; RV154.1 174.34,127.93 173.43,127.93 v2(173.41,127.95) ; RV58.2 184.41,124.28 v2(184.41,123.75) ; RV5.1 174.42,122.58 v2(174.53,122.69) 174.53,122.99 RV146.1
  IN1 w0.254: v2(153.28,107.89) 153.12,107.89 152.35,108.66 152.35,114.19 152.65,114.49 v2(152.77,114.49)
  IN2 w0.508: v2(179.73,122.93) 179.27,123.39 175.23,123.39 v2(174.53,122.69) ; 172.78,128.79 172.07,129.51 171.2,129.51 170.66,128.97 170.66,126.88 172.09,125.46 v2(172.09,123.88)
  BOTTOM w0.254: v2(153.28,107.89) 153.35,107.89 153.59,107.64 PR1115.1
  BOTTOM w0.381: RV162.1 147.76,127.25 143.31,127.25 142.49,128.08 UV2.5
  BOTTOM w0.508: 150.2,121.32 146.68,124.84 146.68,127.25 ; 150.2,121.32 150.2,119.16 150.81,118.55 151.76,118.55 RV72.2 152.52,118.29 152.52,115.38 152.77,115.13 152.77,114.68 ; 150.2,121.32 151.95,123.07 151.95,123.95 151.44,124.46 LV4.1 ; 152.77,114.68 153.79,115.7 153.79,116.71 155.02,117.94 156.98,117.94 157.03,117.98 159.8,117.98 161.07,116.71 169.77,116.71 170.31,117.25 177.08,117.25 v2(178.99,119.15) ; 152.77,114.68 v2(152.77,114.49)
  vias: v2(180.56,124.53)
+3VGS_GPU_ON: length 10.3
  BOTTOM w0.102: C6211.2 188.87,116.52 186.94,116.52 186.24,115.82 184.33,115.82 v1(184.21,115.95) 183.51,116.65 183.51,117.23 RZ79.2
  BOTTOM w0.254: C6211.2 189.74,117.02 189.91,116.85 190.76,116.85 191.01,117.1 U5602.3
+3VGS_OUT: length 4.3
  BOTTOM w0.102: v1(185.83,116.9) 185.83,117.83 186.43,118.43 187.7,118.43 188.58,119.3
+3VLP: length 395.9
  TOP w0.102: v3(26.96,38.19) 26.41,37.64 v2(26.41,37.27)
  TOP w0.508: D2501.2 32.02,10.88 v2(32.67,11.53) ; v2(188.35,63.18) 188.27,63.26 RE356.2
  IN1 w0.508: v2(26.41,37.27) 26.41,41.01 27.37,41.96 27.37,45.6 27.81,46.04 27.81,48.07 28.95,49.21 31.72,49.21 36.19,53.68 36.19,55.88 35.68,56.39 35.68,58.61 41.62,64.55 v2(41.62,65.06) ; v2(187.98,44.26) 186.37,42.65 176.81,42.65 174.76,40.59 171.48,40.59 166.9,36 164.2,36 163,37.21 161.79,37.21 160.39,35.81 160.39,26.29 159.19,25.08 159.19,21.96 155.14,17.92 153.87,17.92 152.9,16.95 85.27,16.95 82.61,19.62 82.61,24.38 80.76,26.23 75.62,26.23 74.8,27.05 74.8,32.45 73.4,33.84 73.4,35.37 74.33,36.29 74.33,61.08 73.09,62.31 v2(73.09,65.64) 73.09,78.23 90.42,95.56 90.42,97.61 94.15,101.34 94.62,101.34 95.56,102.28 95.56,102.87 95.88,103.19 95.88,105.6 97.21,106.93 100.07,106.93 102.32,104.68 103.22,104.68 103.76,104.14 105.78,104.14 107.63,102.3 111.69,102.3 114.26,99.73 116.1,99.73 v2(116.33,99.5)
  IN2 w0.254: v2(116.33,99.5) 116.58,99.76 122.42,99.76 122.96,100.3 v2(122.96,100.49)
  IN2 w0.508: v2(73.09,65.64) 65.8,65.64 65.27,66.17 59.05,66.17 57.84,67.37 43.94,67.37 v2(41.62,65.06) ; v2(36.76,36.27) 36.01,37.02 31.17,37.02 30.54,37.66 28.7,37.66 28.31,37.27 v2(26.41,37.27) ; v2(187.98,44.26) 187.98,50.59 187.59,50.98 187.59,62.82 187.95,63.18 v2(188.35,63.18)
  BOTTOM w0.254: R2609.1 122.79,100.31 v2(122.96,100.49)
  BOTTOM w0.508: v2(26.41,37.27) 26.41,34.36 24.82,32.77 24.82,20.76 27.93,17.65 29.58,17.65 30.73,16.51 30.73,12.45 31.64,11.53 v2(32.67,11.53)
+3VS: length 801.4
  TOP w0.203: U5502.5 28.5,67.48 v2(28.47,67.51)
  TOP w0.305: v2(46.22,72.01) 46.09,72.14 Q6501.2 ; v2(65.82,165.3) 64.81,166.31 59.71,166.31 57.11,168.9 55.23,168.9 R6518.1
  TOP w0.381: UC7.5 150.54,82.69 150.87,82.36 RC378.1
  TOP w0.432: Q6501.5 46.09,75.07 46.54,75.51 47.8,75.51 ; RZ20.1 47.8,75.5
  TOP w0.508: v2(129.62,133.07) 125.53,137.15 125.53,143 124.24,144.29 122.38,144.29 120.9,145.78 120.9,146.49 120.33,147.07 116.71,147.07 115.94,147.83 114.55,147.83 114.04,147.32 114.04,146.18 v2(114.23,145.99) 114.23,145.99 114.74,145.48 PR612.1 ; v2(181.98,45.08) 181.59,44.69 R5607.1 ; Q6206.2 194.67,103.24 v2(194.37,102.93) 194.16,102.73 R6202.1 ; v2(195.32,88.01) 192.36,88.01 191.43,88.94 190.74,88.94 190.44,88.65 RE441.2 ; RC272.1 148.58,65.3 v2(148.58,66.04) 156.31,66.04 156.76,66.49 RC21.1 157.03,67.39 v2(157.03,68.19) 156.48,68.19 156.09,68.58 RC376.1 ; v2(40.67,11.25) 40.9,11.03 R6110.1 ; v2(77.27,66.29) 76.55,66.29 75.75,65.49 75.75,60.58 73.02,57.85 63.94,57.85 63.49,58.29 63.49,60.32 59.87,63.94 54.6,63.94 47.81,70.74 v2(47.81,72.21) RZ21.1 ; v2(48.51,75.51) RZ20.1 47.81,77.28 47.3,77.78 47.3,79.44 ; RC378.1 151.39,82.64 151.39,82.8 151.82,83.23 v2(151.82,83.44) ; v2(149.98,86.07) 148.55,87.5 RC374.1 148.34,87.63 148.34,91.05 147.72,91.67 v2(147.72,92.2) 147.72,94.55 147.25,95.02 v2(147.25,101.57) ; 153.16,158.43 v2(153.16,159.26) 153.92,160.02 v2(153.92,166.94) 158.17,166.94 v2(158.95,167.72) ; 153.16,158.43 153.35,158.62 v2(154.93,158.62) 158.43,158.62 158.93,158.11 v2(158.93,157.86) ; 153.16,158.43 153.16,157.8 v2(152.84,157.48) ; v2(22.46,68.53) 23.13,67.86 R5503.1 ; R2701.1 176.98,20.45 v2(176.59,20.84) ; 164.2,27.11 164.01,26.92 161.79,26.92 161.28,26.42 158.93,26.42 158.55,26.8 156.01,26.8 155.5,26.29 CD35.1 155.43,25.58 154.8,25.58 v2(154.73,25.65) 154.73,32.15 v2(153.66,33.21) 152.33,34.54 152.33,39.5 151.22,40.61 v2(149.06,40.61) 148.23,40.61 147.5,39.88 CD17.1 ; R6212.1 56.13,79.69 55.11,80.71 48.57,80.71 47.3,79.44 ; v2(153.33,110.24) 153.51,110.24 153.77,110.51 PR1119.1 ; v2(35.58,79.77) 35.91,79.44 43.3,79.44 43.3,79.44 44.58,80.72 46.72,80.72 46.93,80.51 46.93,79.8 47.3,79.44 ; v2(159.11,73.17) 159.61,73.17 160.31,72.47 RC388.2 ; 163.51,23.94 162.11,22.54 v2(162.11,21.91) 162.11,18.22 157.4,13.51 RD6.1 ; RC181.1 v2(36.12,64.83) ; v2(153.89,73.77) 153.78,73.66 RC379.1 RC189.1 RC50.1 RC47.1 ; Q5401.1 v2(28.89,78.99) ; RD3.1 121.79,27.81 v2(121.09,27.11)
  IN1 w0.508: v2(158.62,64.96) 157.03,66.54 v2(157.03,68.19) 157.03,68.6 158.3,69.87 158.3,72.36 v2(159.11,73.17) ; v2(127.12,170.56) 113.14,170.56 112.25,171.45 v2(108.39,171.45) ; v2(103.49,168.15) 103.49,165.79 103.14,165.44 103.14,160.8 100.39,158.05 100.39,156.49 99.05,155.15 v2(99.05,154.8) ; v2(153.89,73.77) 153.7,73.95 153.7,76.34 153.92,76.56 153.92,79.44 153.54,79.82 153.03,79.82 152.72,80.13 152.72,82.38 151.82,83.28 v2(151.82,83.44) ; v2(149.98,86.07) 149.5,86.07 147.19,83.76 v2(146.5,83.76) ; v2(121.09,27.11) 121.47,27.5 148.07,27.5 153.66,33.09 v2(153.66,33.21) 153.35,33.53 v2(153.35,47.18) 147,53.53 147,60.53 148.58,62.12 v2(148.58,66.04) ; v2(156.27,103.12) 155.79,103.12 153.94,104.97 153.94,109.73 153.43,110.24 v2(153.33,110.24) ; v2(154.3,89.03) 154.3,90.11 153.73,90.68 152.52,90.68 152.08,90.23 148.89,90.23 147.72,91.4 v2(147.72,92.2)
  IN1 w0.762: v2(28.89,78.99) 29.1,79.21 30.77,79.21 ; v2(30.47,77.09) 33.14,77.09 33.33,76.9 v2(34.66,76.9) ; v2(30.47,77.09) 30.18,77.09 28.81,75.72 28.81,74.89 v2(22.46,68.53) 22.46,67.55 20.25,65.34 20.25,63.88 21.65,62.48 21.65,60.13 22.73,59.05 24.31,59.05 24.95,58.42 24.95,57.62 v2(24.77,57.43) 22.45,55.12 19.77,55.12 17.33,52.68 17.33,47.75 19.41,45.67 19.41,22.9 23.11,19.2 23.11,12.13 v2(23.87,11.37) 25.27,11.37 26.47,12.57 36.91,12.57 ; v2(30.47,77.09) 30.77,77.38 30.77,79.21 ; 30.77,79.21 35.02,79.21 v2(35.58,79.77)
  IN2 w0.432: v2(156.27,103.12) 156.2,103.06 149.28,103.06 147.79,101.57 v2(147.25,101.57)
  IN2 w0.508: v2(114.23,145.99) 114.23,146.21 113.78,146.67 106.63,146.67 105.09,148.21 104.02,148.21 100.72,151.51 98.8,151.51 98.1,152.21 98.1,154.52 98.38,154.8 ; v2(81.64,158.38) 80.64,159.38 76.51,159.38 74.76,161.14 72.23,161.14 68.06,165.3 v2(65.82,165.3) ; v2(183.62,73.15) 183.62,72.57 184.27,71.92 184.27,70.59 184.38,70.47 184.38,63.51 184.52,63.37 184.52,62.16 185.83,60.85 v2(185.83,55.12) ; v2(108.39,171.45) 106.48,171.45 103.49,168.45 v2(103.49,168.15) ; v2(88.64,156.08) v2(88.64,156.72) 90.54,158.62 92.69,158.62 95.13,156.18 95.97,156.18 97.35,154.8 98.38,154.8 ; 98.38,154.8 v2(99.05,154.8) ; v2(153.89,73.77) 154.09,73.97 155.05,73.97 156.04,72.98 158.92,72.98 v2(159.11,73.17)
  IN2 w0.762: v2(23.87,11.37) 15.61,11.37 12.47,14.51 v2(12.21,14.51)
  BOTTOM w0.305: CD16.1 150.95,39.99 150.33,40.61 v2(149.06,40.61) 144.36,40.61 143.62,39.87 JDIMM1.255 ; v2(154.73,25.65) 154.22,26.16 152.82,26.16 152.22,25.57 JDIMM2.255
  BOTTOM w0.381: THM26.1 155.99,166.76 C2602.1 ; v2(158.62,64.96) 158.63,64.97 RC13.1 ; 183.62,73.84 183.28,73.84 182.96,73.52 UE6.5
  BOTTOM w0.406: v2(35.58,79.77) 35.58,79.77 35.58,79.19 35.29,78.9 Q5402.5 ; QC2.5 QC2.2 ; Q5402.2 32.12,78.9
  BOTTOM w0.432: Q2601.2 v2(152.84,157.48) ; Q2601.5 152.84,158.94 v2(153.16,159.26)
  BOTTOM w0.457: 147.72,94.12 v2(147.72,92.2)
  BOTTOM w0.508: RE32.1 158.32,158.61 R2603.1 159.82,158.5 159.19,157.86 v2(158.93,157.86) ; 154.93,86.87 154.93,85.22 154.32,84.61 152.81,84.61 152.64,84.44 152.63,84.44 151.82,83.63 v2(151.82,83.44) ; 154.93,86.87 154.3,87.5 v2(154.3,89.03) 154.04,89.28 RN20.1 154.29,89.78 154.87,90.36 155.82,90.36 ; 154.93,86.87 154.93,86.93 155.62,87.62 RN19.1 ; RC267.1 RC356.1 147.16,94.68 147.72,94.12 ; 30.56,57.37 U5504.8 30.56,53.12 28.02,50.58 U5504.3 ; R2604.1 v2(158.95,167.72) ; RC359.1 183.7,118.24 184.27,117.67 184.27,117.45 185.38,116.35 186.09,116.35 186.46,116.72 ; v2(129.62,133.07) 129.31,133.38 PR1401.1 ; v2(148.58,66.04) 148.19,65.65 143.39,65.65 141.22,67.82 RC245.1 RC27.2 ; RC293.1 147.76,92.01 147.72,92.05 v2(147.72,92.2) ; v2(88.64,156.72) 89,157.08 R5219.2 ; v2(147.25,101.57) 145.78,103.04 RC237.2 RC248.2 143.61,103.04 143.07,102.5 RC360.1 141.26,102.11 141.66,101.72 RC277.1 RE439.2 141.66,100.14 141.73,100.08 RC291.1 ; R5229.1 98.49,155.8 99.05,155.23 v2(99.05,154.8) ; RD2.1 RD1.1 153.66,33.21 v2(153.66,33.21) ; RC175.2 34.11,76.9 v2(34.66,76.9) ; Q6205.2 195.56,20.98 195.15,21.39 v2(195,21.39) ; RC124.1 v2(77.27,66.29) ; v2(22.46,68.53) 22.46,68.48 22.96,67.98 28,67.98 v2(28.47,67.51) 28.07,67.11 C5520.1 ; 32.12,78.9 31.91,79.11 29.01,79.11 v2(28.89,78.99) ; v2(127.12,170.56) 133.15,170.56 137.03,166.69 137.03,163.7 139.19,161.54 139.88,161.54 140.58,160.85 151.38,160.85 152.71,162.18 152.71,166.18 153.47,166.94 v2(153.92,166.94) C2601.1 155.81,166.94 C2602.1 ; RC178.2 v2(30.47,77.09) ; PC1423.1 60.65,70.98 v2(58.54,70.98) ; v2(183.62,73.15) CE85.1 ; v2(52.46,72.19) 52.62,72.35 PC1422.2 ; PC1424.1 v2(54.01,70.46) ; v2(185.83,55.12) 189.41,55.12 189.92,54.61 195.13,54.61 v2(195.19,54.67) ; RC382.2 RC292.1 149.47,86.07 v2(149.98,86.07) 151.21,86.07 RC63.2 ; R6507.1 82.66,159.4 v2(81.64,158.38) ; RD5.1 RD4.1 161.85,21.65 v2(162.11,21.91) ; v2(156.27,103.12) 156.27,103.24 PR1112.1 ; R5208.1 103.94,171.2 103.49,170.74 v2(103.49,168.15) ; RE432.1 v2(154.93,158.62) ; RC62.2 v2(146.5,83.76)
  vias: v2(26.16,56.45) v2(26.6,56.96) v2(26.6,55.94) v2(26.98,56.45) v2(29.27,47.75) v2(29.27,47.12) v2(29.97,47.75) v2(29.97,47.12) v2(30.6,47.75) v2(31.37,57.28) v2(31.87,57.72) v2(32.25,58.17) v2(32.7,58.55) v2(35.77,14.68) v2(35.85,14.02) v2(36.38,14.43) v2(36.61,13.84) v2(36.86,14.81) v2(37.37,14.38) v2(37.57,13.82) v2(37.8,14.81) v2(38.21,14.33) v2(38.59,14.78) v2(38.51,13.79) v2(38.66,66.55) v2(38.66,65.85) v2(39.02,14.3) v2(39.3,66.55) v2(39.3,65.85) v2(39.35,14.88) v2(90.28,143.61) v2(90.81,143.05) v2(91.29,142.49) v2(164.39,34.61) v2(164.39,33.97) v2(164.97,34.61) v2(164.97,33.97) v2(165.55,34.61) v2(165.55,33.97) v2(165.54,24.51) v2(165.54,23.94) v2(165.54,23.3) v2(165.79,25.02) v2(166.11,24.51) v2(166.11,23.94) v2(166.11,23.3) v2(166.68,24.51) v2(166.68,23.94) v2(166.68,23.3) v2(188.47,117.81) v2(188.78,118.3) v2(189.1,117.79) v2(193.22,117.6) v2(193.48,117.03) v2(193.8,117.6) v2(193.8,116.46) v2(194.11,117.03) v2(194.11,115.89) v2(194.43,117.6) v2(194.43,116.46) v2(194.43,115.38) v2(194.75,117.03) v2(194.75,115.89) v2(195.07,117.6) v2(195.07,116.46) v2(195.07,115.38) v2(196.59,90.42) v2(196.61,94.68) v2(196.61,94.04) v2(196.61,93.41) v2(196.61,92.84) v2(196.61,92.25) v2(196.61,91.67) v2(196.61,91.08) v2(199.19,63.63) v2(199.57,63.06) v2(199.57,62.42) v2(199.89,63.63) v2(200.27,63.06) v2(200.27,62.42) v3(165.33,31.29)
+5V_AVDD:
  vias: v1(191.45,19.81)
+5V_KB_BL: length 6.3
  TOP w0.508: C6202.1 EC6208.1 v3(186.52,121.94) 185.62,121.04 185.62,120.73 v2(184.78,119.89)
  BOTTOM w0.508: F6201.1 v2(184.78,119.89)
+5V_PVDD:
  vias: v1(181.21,7.9)
+5V_RUN_UZ2: length 2.2
  TOP w0.102: 50.86,18.8 50.88,18.82 v1(50.88,21.03)
+5VALW: length 465.1
  TOP w0.203: v2(142.46,157.9) 142.61,157.75 U15.4 ; UZ2.4 45.78,21.36 v2(45.83,21.41)
  TOP w0.305: CZ86.1 139.73,114.9 139.71,114.88 UZ19.3
  TOP w0.457: Q6101.3 33.58,6.63 32.01,6.63 31.43,7.21 30.7,7.21 30.33,7.57 Q6102.3
  TOP w0.508: v2(55.24,16.57) PR206.1 PR210.2 ; v2(162.74,106.68) 161.98,105.92 PR1114.2 ; PR615.1 PR634.1 109.37,135.14 108.86,134.63 108.86,132.01 111.45,129.42 v2(112.43,129.42) 113.6,129.42 114.67,130.49 118.23,130.49 119.44,129.29 122.79,129.29 v2(123.7,128.37) ; CZ86.1 140.24,114.33 v2(140.14,114.24) ; PD5.3 95.58,147.28 v2(95.84,147.54) ; v2(158.23,50.86) 158.18,50.91 EC9733.1 158.55,52.01 160.13,53.59 162.4,53.59 163.86,55.05 166.41,55.05 168.83,57.47 172.46,57.47 172.88,57.05 175.6,57.05 177.35,55.3 v2(177.35,54.76) ; v2(181.1,91.5) 179.95,91.5 v3(175.82,87.37) 174.87,86.42 174.87,84.07 173.98,83.18 173.98,81.25 v2(173.71,80.98) ; Q6101.3 34.27,7.51 34.77,8.01 v2(35.14,8.01) ; PR8.1 v2(90.04,153.67) ; v2(149.85,104.14) 149.12,104.87 149.12,104.87 148.75,105.24 148.75,111.03 146.53,113.24 144.98,113.24 144.26,112.52 v3(144.04,112.52) v2(141.79,112.52) ; PD6.3 91.67,151.51 91.88,151.51 v2(92,151.38)
  IN1 w0.508: v2(68.17,33.27) 67.95,33.05 v2(58.6,33.05) 58.21,32.66 55.96,32.66 54.54,31.24 v2(54.54,30.61) ; v2(181.1,91.5) 181.35,91.5 181.98,92.14 181.98,92.96 182.87,93.85 188.33,93.85 189.69,95.21 189.69,116.69 190.37,117.37 v2(190.51,117.37) ; v2(106.89,139.68) 106.1,140.46 106.1,145.16 104.27,146.99 96.4,146.99 v2(95.84,147.54) 95.84,147.55 92.01,151.38 v2(92,151.38) 90.04,153.35 v2(90.04,153.67) ; v2(62.03,43.51) 60.84,43.51 60.48,43.14 60.48,40.69 63.78,37.39 68.01,37.39 v2(69.08,36.31) ; v2(119.87,142.96) 120,143.09 120.87,143.09 122.54,141.43 123.03,141.43 123.36,141.1 123.36,138.9 126.23,136.03 126.23,132.41 127.36,131.28 v2(127.36,125.29)
  IN2 w0.508: v2(112.43,129.42) 108.66,133.18 108.66,134.84 106.89,136.62 v2(106.89,139.68) ; v2(127.36,125.29) 124.27,128.37 v2(123.7,128.37) ; v2(127.36,125.29) 127.36,111.86 129.64,109.58 134.09,109.58 v2(134.84,110.33) 138.1,110.33 140.14,112.37 v2(140.14,114.24) ; v2(127.36,125.29) 133.03,125.29 133.79,126.05 133.79,146.62 134.87,147.7 134.87,150.88 139.38,155.38 139.38,157.04 140.52,158.18 142.18,158.18 v2(142.46,157.9) ; v2(177.35,54.76) 177.48,54.89 177.48,65.57 178.57,66.66 178.57,69.35 177.18,70.74 177.18,78.18 176.73,78.63 175.49,78.63 174.98,79.14 174.98,79.7 v2(173.71,80.98) ; v2(149.85,104.14) 150.24,103.75 159.3,103.75 159.36,103.81 161.28,103.81 v2(161.58,103.51) ; v2(162.74,106.68) 162.11,107.31 162.11,109.44 162.34,109.67 162.34,114.38 164.08,116.12 170.51,116.12 170.94,115.7 188.84,115.7 v2(190.51,117.37)
  BOTTOM w0.203: PU1100.31 161.16,103.93 v2(161.58,103.51) ; v2(162.74,106.68) 162.68,106.74 PU1100.26
  BOTTOM w0.254: PU606.6 122.35,129.54 122.61,129.29 123.15,129.29 123.58,128.86 123.58,128.5 v2(123.7,128.37) 124.2,128.87 PC685.1 ; PU603.2 112.01,128.28 113.09,129.36 PC661.1 ; PU605.2 69.32,38.18 69.78,37.72 PC677.1 ; U5602.4 v2(190.51,117.37)
  BOTTOM w0.508: v2(68.17,33.27) 69.08,34.18 v2(69.08,36.31) 69.08,36.83 69.6,37.35 PC677.1 ; JWDB1.4 158.25,50.88 v2(158.23,50.86) ; v2(177.35,54.76) 177.35,54.67 177.86,54.17 188.84,54.17 189.1,53.91 192.53,53.91 202.03,44.41 202.03,17.08 201.84,16.89 200.53,16.89 ; v2(58.6,33.05) PC801.1 59.23,32.36 PU800.4 ; v2(35.14,8.01) 36.05,8.92 46.74,8.92 ; PR602.2 v2(119.87,142.96) ; v2(141.79,112.52) 141.15,112.52 140.14,113.54 v2(140.14,114.24) ; PC661.1 112.54,129.54 v2(112.43,129.42)
  vias: v2(28.57,44.7) v2(28.57,44.07) v2(28.61,45.31) v2(29.27,44.7) v2(29.27,44.07) v2(46.86,21.59) v2(47.81,21.59) v2(47.81,20.95) v2(47.81,20.32) v2(48.44,21.59) v2(48.44,20.95) v2(48.44,20.32) v2(49.08,21.59) v2(49.08,20.95) v2(49.08,20.32) v2(49.78,21.59) v2(49.78,20.95) v2(49.78,20.32) v2(68.83,3.94) v2(69.4,3.94) v2(70.03,3.94) v2(70.67,3.94) v2(71.24,3.94) v2(195.13,1.91) v2(195.74,1.91) v2(196.35,1.91) v2(196.96,1.91) v2(197.54,1.91) v3(48.52,22.28) v3(162.31,104.22)
+5VALWP: length 18.1
  BOTTOM w0.254: PR117.2 v1(50.98,38.66) 51.62,38.02 51.62,33.34 51.72,33.24 PC122.1 ; PU102.14 48.71,38.01 PR115.1 51.24,37.44 51.24,32.56
+5VS: length 290.5
  TOP w0.508: Q5403.2 32.78,71.3 v2(32.85,71.3) ; v2(90.04,147.95) 88.64,147.95 86,150.59 86,151.89 84.41,153.48 80.64,153.48 v2(78.62,155.5) ; v2(196.17,112.47) 194.72,111.02 Q6201.3
  IN1 w0.508: 195.23,118.34 192.79,118.34 190.79,116.33 v2(190.37,116.33) ; 195.23,118.34 196.93,116.64 196.93,113.23 v2(196.17,112.47) ; 195.23,118.34 195.23,121.58 197.29,123.63 197.29,138.43 201.42,142.56 201.42,153.54 196.72,158.24 196.72,160.72 193.99,163.45 193.99,176.53 191.89,178.63 171.52,178.63 165.92,173.03 158.42,173.03 157.47,172.08 154.68,172.08 150.36,176.4 148.08,176.4 144.33,180.15 133.34,180.15 131.64,178.45 128.87,178.45 124.73,174.31 96.39,174.31 94.09,172.01 83.86,172.01 81.44,174.43 63.25,174.43 57.31,168.5 57.31,163.97 v2(58.02,163.26)
  IN2 w0.508: v2(78.62,155.5) 78.47,155.5 74.71,159.26 73.21,159.26 67.8,164.67 64.57,164.67 64.56,164.68 61.69,164.68 60.27,163.26 v2(58.02,163.26)
  BOTTOM w0.508: v2(190.37,116.33) 189.67,116.33 189.41,116.08 187.13,116.08 186.3,115.25 183.44,115.25 181.22,117.47 181.22,118.76 180.8,119.18 F6201.2
  vias: v2(33.46,71.37) v2(34.22,71.37) v2(40.89,80.45) v2(41.4,80.9) v2(41.84,80.45) v2(48.82,12.45) v2(48.82,11.81) v2(49.46,12.45) v2(49.46,11.81) v2(50.09,12.45) v2(50.09,11.81) v2(50.73,12.45) v2(50.73,11.81) v2(51.36,12.45) v2(51.36,11.81) v2(52,12.45) v2(52,11.81) v2(52.63,11.81) v2(90.67,147.95) v2(90.99,147.38) v2(94.23,120.65) v2(94.86,120.65) v2(174.05,8.38) v2(174.05,7.75) v2(174.68,9.65) v2(174.68,9.02) v2(174.68,8.38) v2(174.68,7.75) v2(175.32,9.65) v2(175.32,9.02) v2(175.32,8.38) v2(175.32,7.75) v2(176.02,45.02) v2(176.02,44.32) v2(176.65,45.02) v2(176.65,44.32) v2(177.35,45.02) v2(177.35,44.32) v2(184.08,45.02) v2(184.08,44.32) v2(184.71,45.02) v2(184.71,44.32) v2(185.41,45.02) v2(185.41,44.32) v2(194.11,17.14) v2(194.14,16.51) v2(199.32,39.75) v2(199.32,39.12) v2(199.7,40.39) v2(199.95,39.75) v2(199.95,39.12) v2(200.34,40.39) v2(200.59,39.75) v2(200.72,39.12) v3(179.14,46.32)
+17.4V_BATT+: length 45.6
  TOP w0.508: PQ710.3 118.5,162.67 PR780.2 118.87,162.5 119.59,163.22 v2(119.59,164.96)
  IN1 w0.254: v2(114.48,154.69) 116.01,154.69 116.64,154.05 116.64,151.89 117.74,150.8 129.52,150.8 134.03,155.31 134.03,156.96 134.52,157.45 134.52,158.46 v2(134.11,158.88)
  IN2 w0.508: v2(114.48,154.69) 116.01,156.21 116.01,161.37 119.59,164.95 v2(119.59,164.96)
  BOTTOM w0.254: v2(114.48,154.69) 113.98,155.19 PR745.2
  vias: v1(140.42,173.06) v2(131.82,163.06) v2(132.45,163.06) v2(132.96,158.88) v2(133.56,163.07) v2(133.53,158.88) v2(133.66,159.45) v2(134.19,163.07) v2(134.23,159.45) v2(134.42,161.48) v2(134.42,160.91) v2(134.42,160.34)
+17.4V_BATT++: length 2
  TOP w0.102: 156.01,172.89 156.25,172.89 v3(156.62,172.52) ; 155.37,172.48 v3(155.37,171.26)
  vias: v2(154.37,174.71) v2(154.37,174.08) v2(154.37,173.44) v2(154.91,174.37) v2(154.91,173.74) v2(154.91,173.1) v2(155.5,174.37) v2(155.5,173.74) v2(155.5,173.1) v2(156.14,174.37) v2(156.14,173.74) v3(154.32,172.72)
+19V_ADPIN: length 3.8
  TOP w0.102: 83.83,158.08 83.83,156.81 83.17,156.15 v3(83.17,156.03) ; v3(84.51,162.97) 84.41,162.86 v2(83.8,162.86) ; v3(90.37,159.83) 90.37,159.89 90.11,160.15 90.11,160.48
  vias: v2(82.61,162.81) v2(83.22,163.5) v2(83.22,162.89) v2(83.83,163.5) v2(83.86,162.24) v2(83.88,161.65) v2(88.83,162.31) v2(88.83,161.67) v2(88.83,161.04) v2(89.46,162.31) v2(89.46,161.67) v2(89.46,161.04) v2(89.59,160.4)
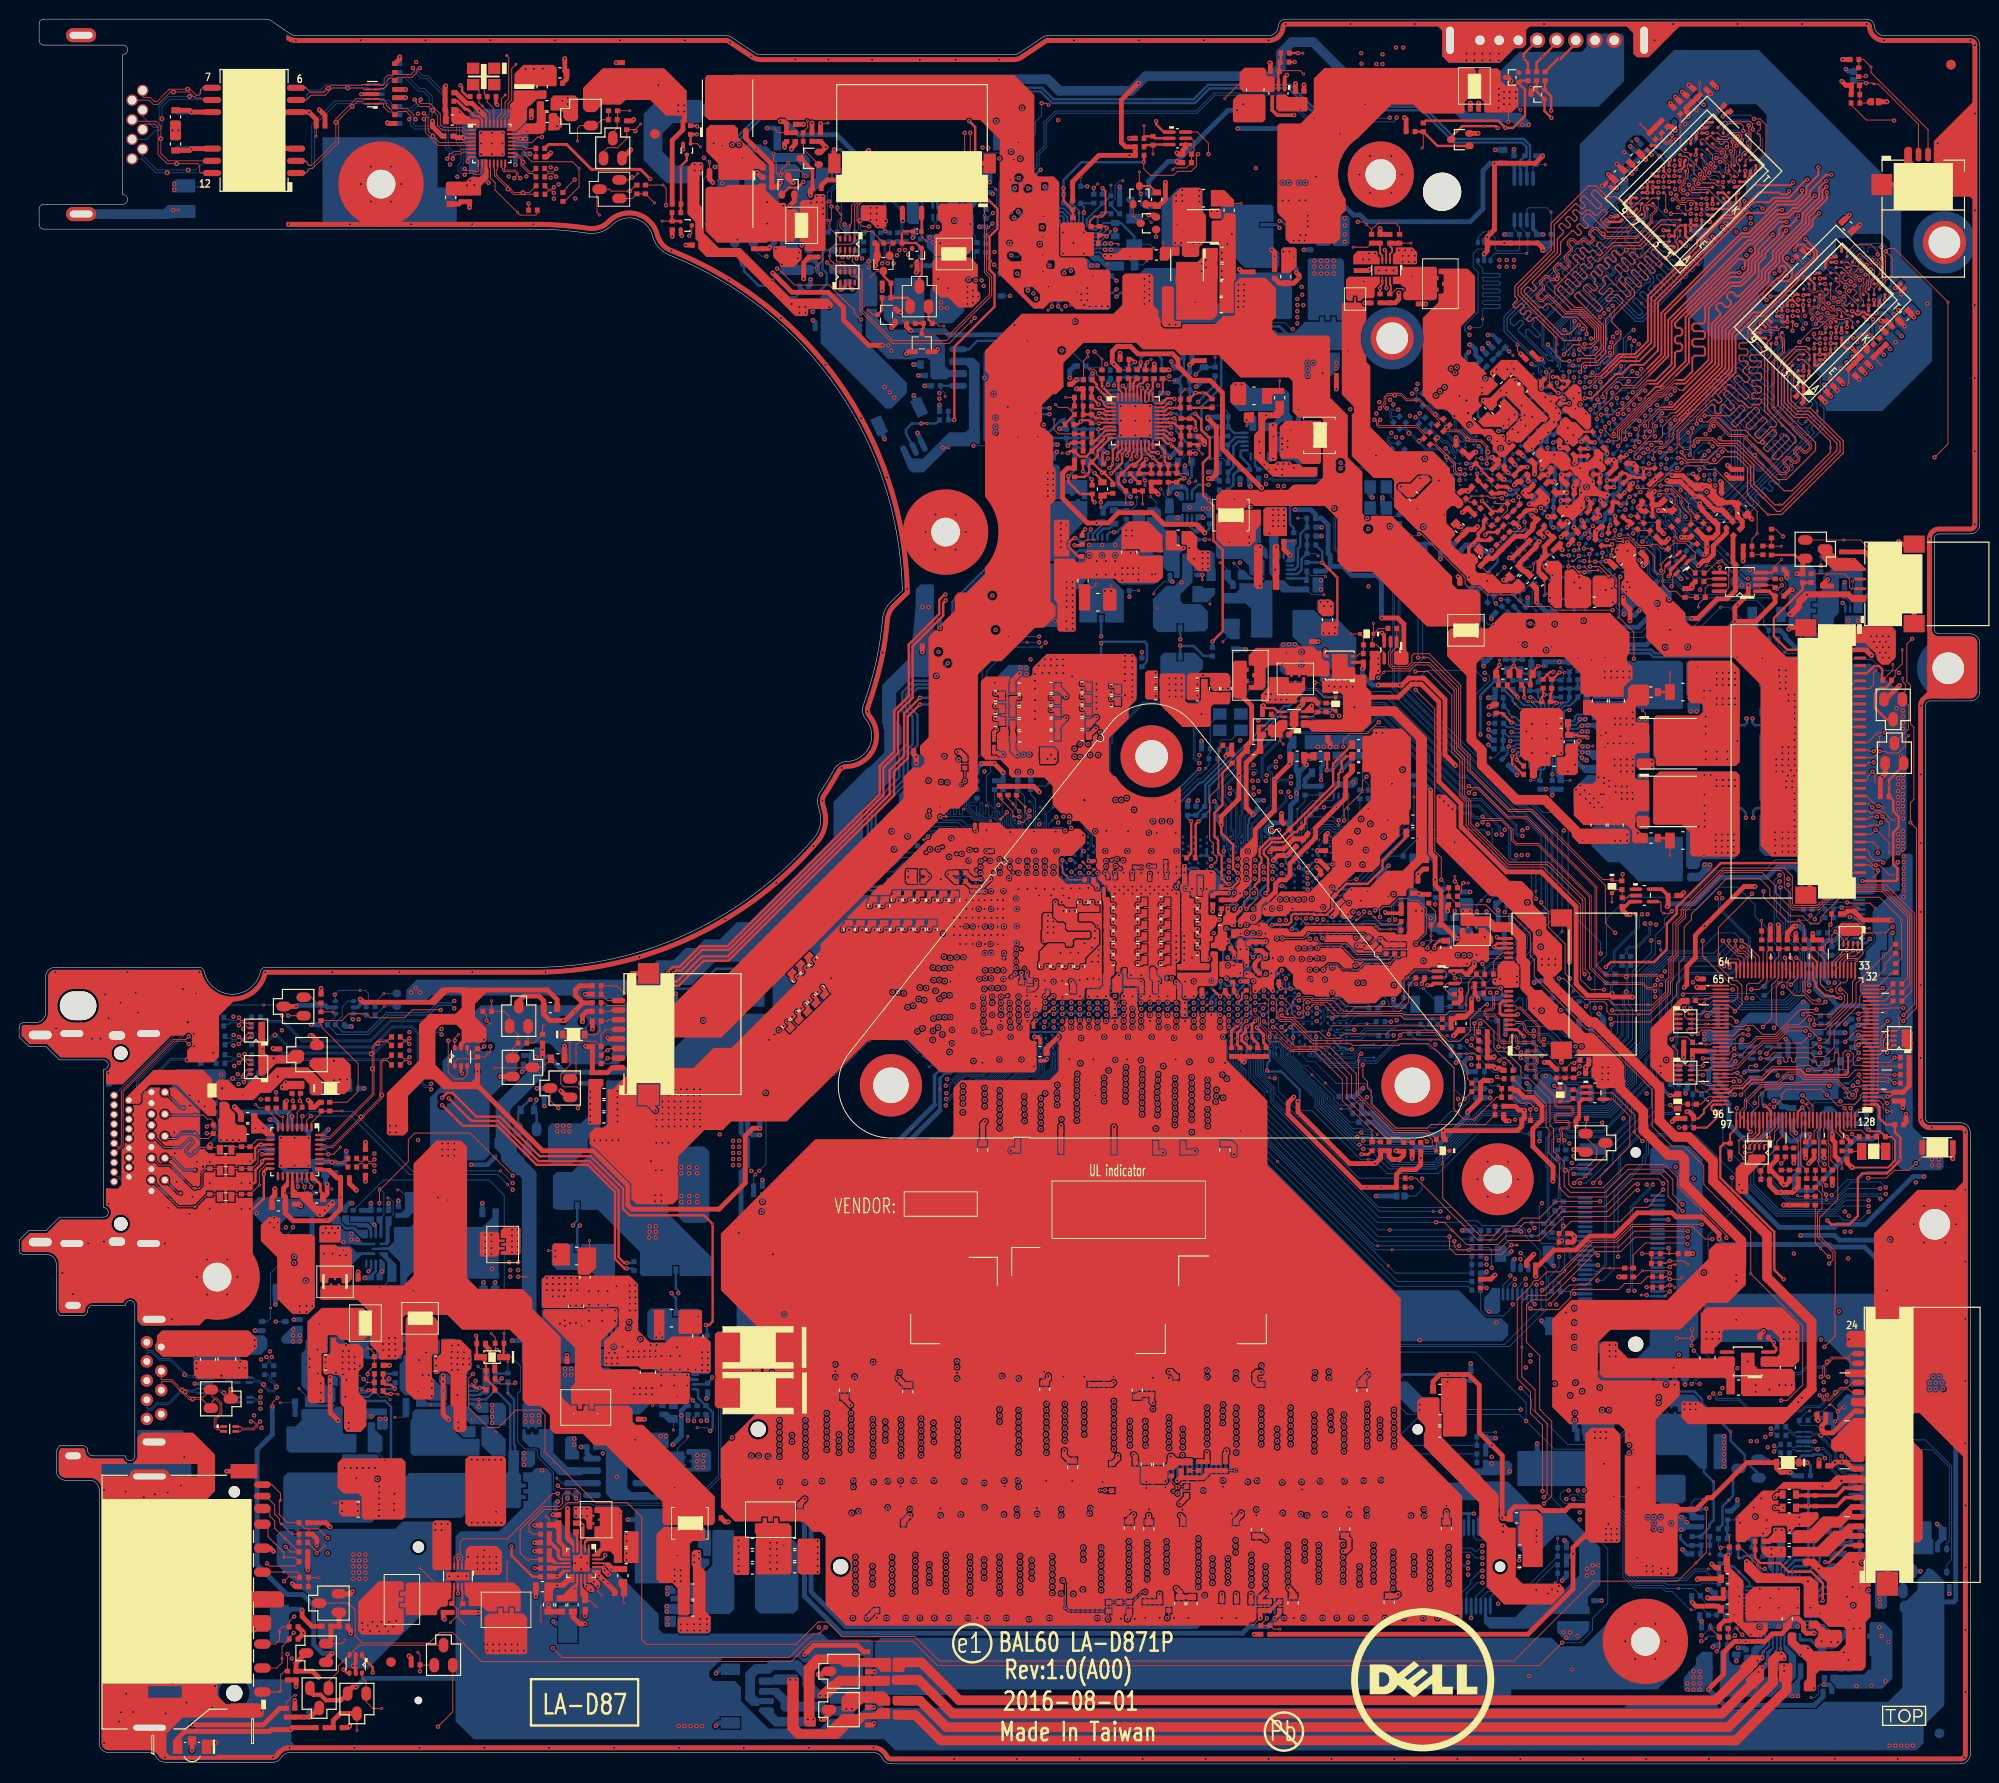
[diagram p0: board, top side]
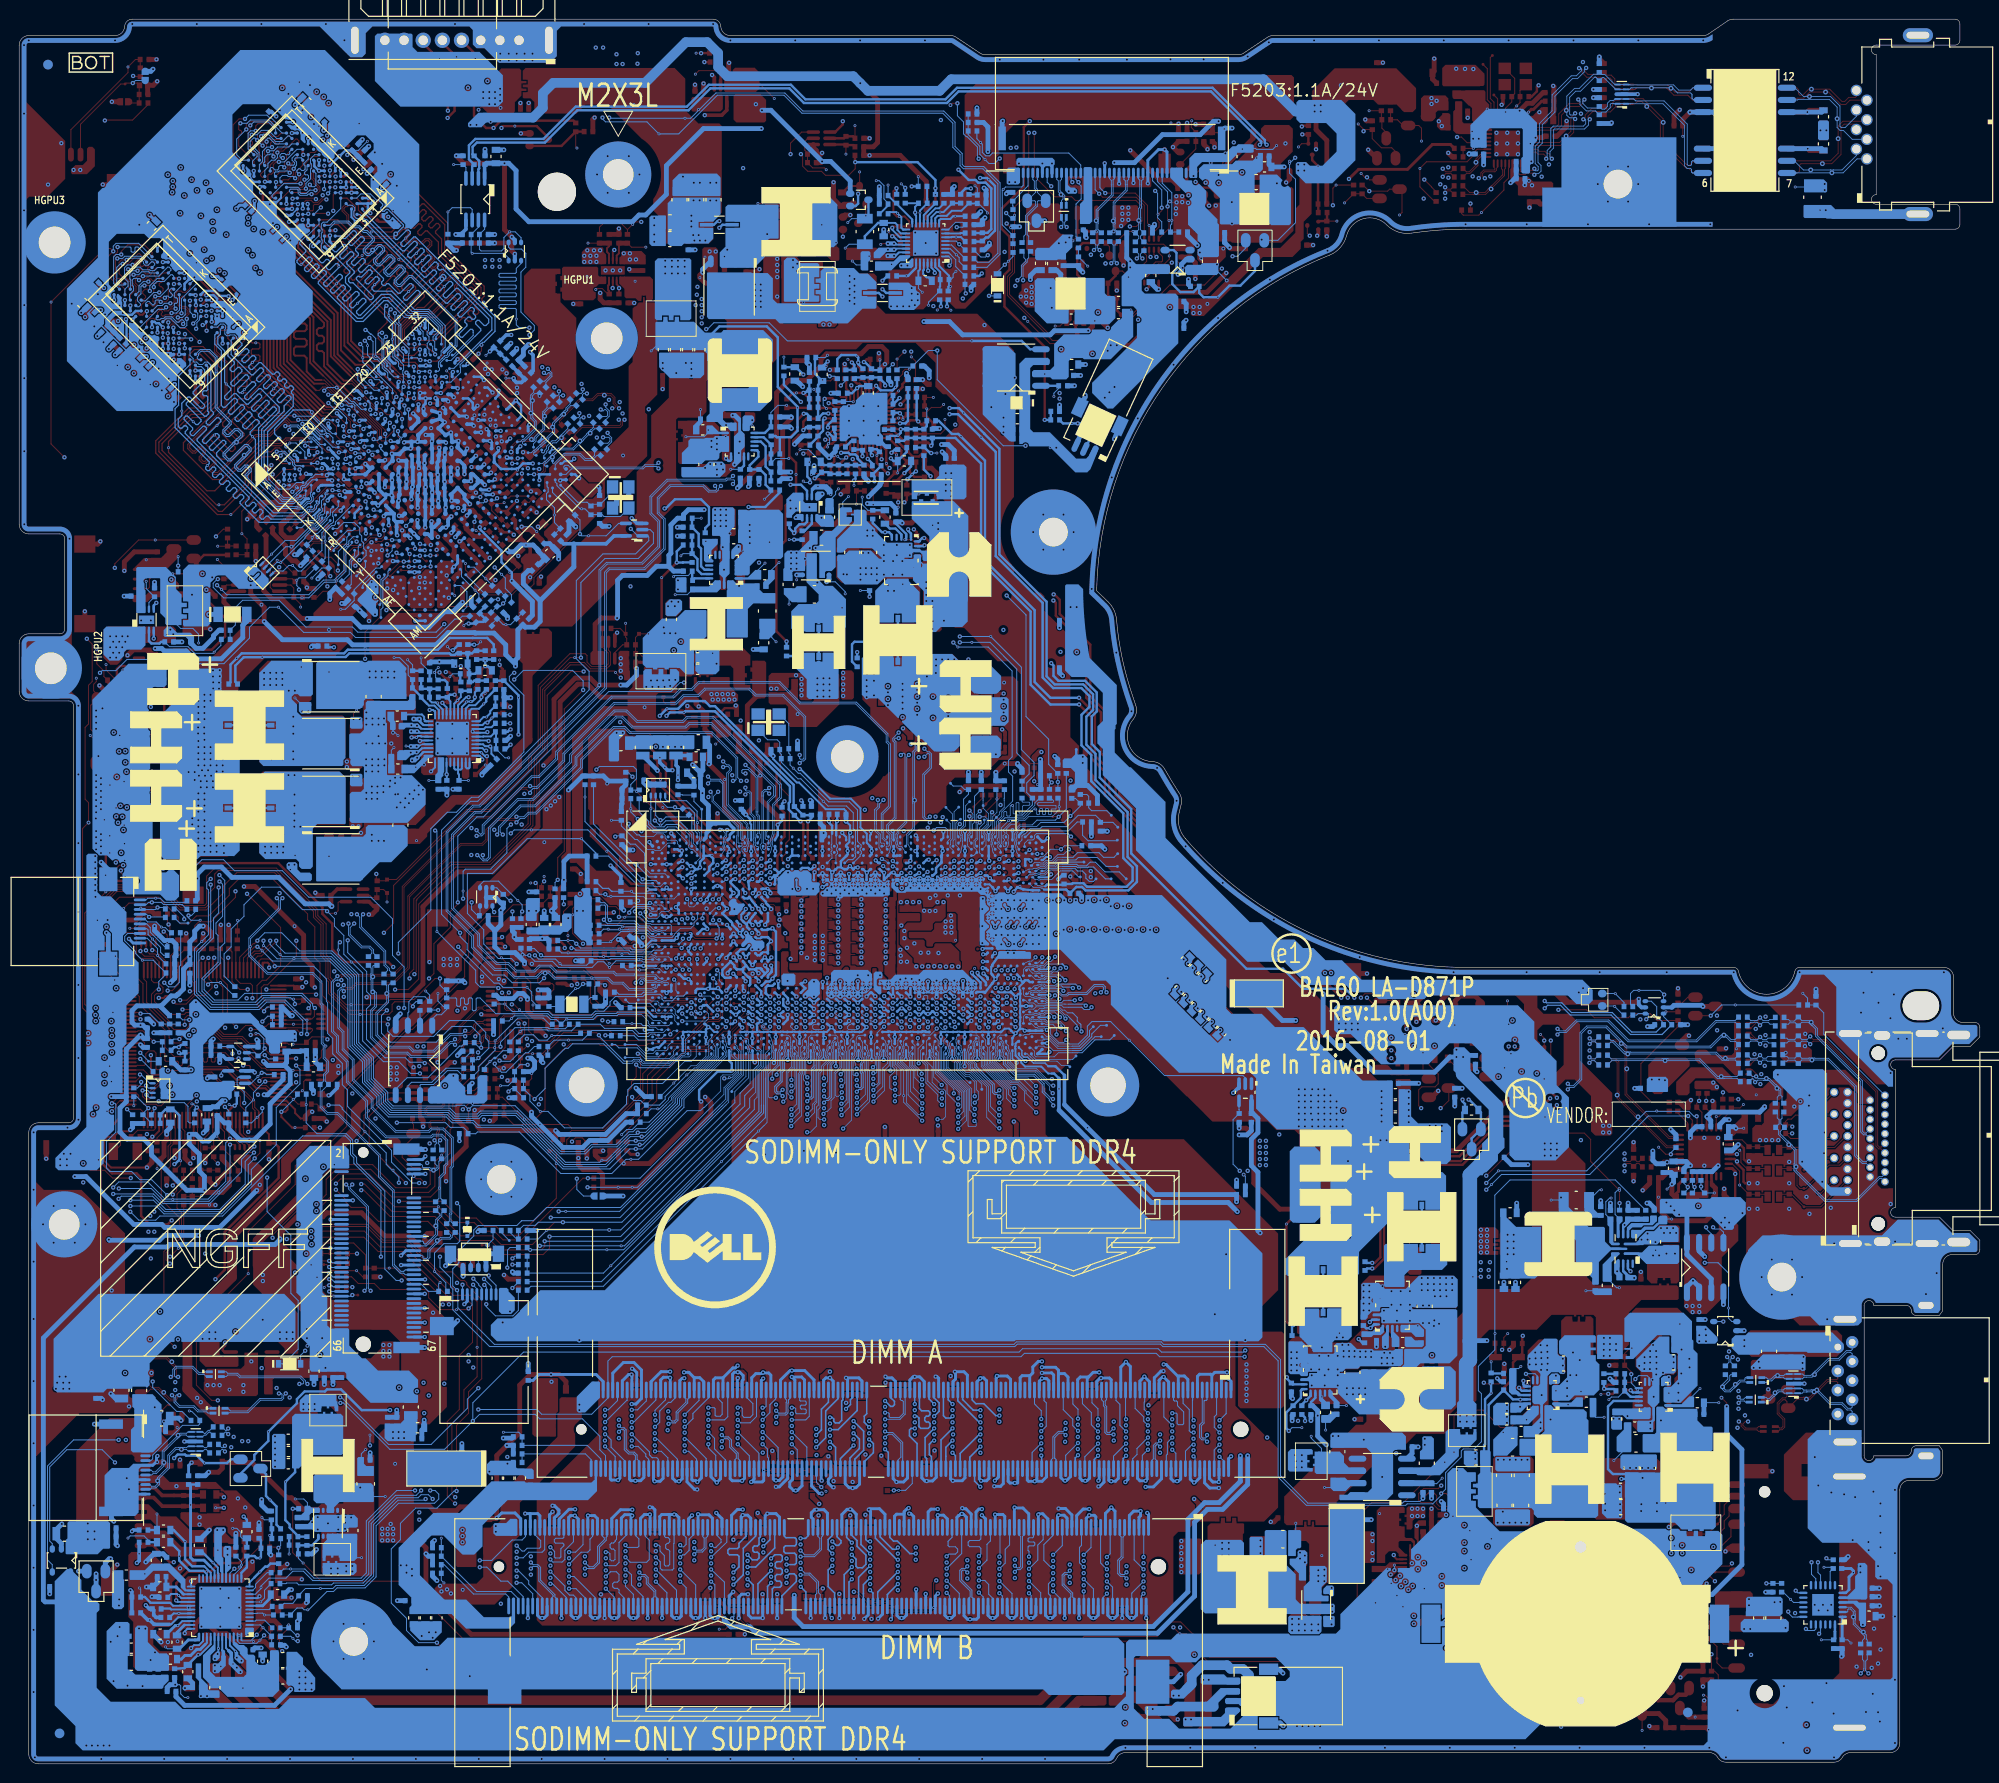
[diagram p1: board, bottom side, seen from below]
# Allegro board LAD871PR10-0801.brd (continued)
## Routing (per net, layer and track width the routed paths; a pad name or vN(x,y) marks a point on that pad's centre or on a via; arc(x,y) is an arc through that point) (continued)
+19V_VIN: length 74.4
  TOP w0.508: v2(120.78,167.13) 120.91,167 PR31.2 ; PR7.2 v2(134.04,175.13) ; PR729.1 80.96,168.91 80.57,168.53 v2(80.57,168.4)
  IN1 w0.508: v2(127.69,173.1) 128.64,174.05 133.53,174.05 134.04,174.56 v2(134.04,175.13) ; v2(80.57,168.4) 80.57,168.28 78.77,166.47 78.77,163.46 v2(79.71,162.52)
  IN2 w0.508: v2(120.78,167.13) 118.96,167.13 117.49,165.66 105.41,165.66 104.64,164.89 104.64,164.15 104.25,163.75 102.72,163.75 102.11,164.36 100.39,164.36 98.45,166.31 92.8,166.31 91.49,167.61 82.95,167.61 82.16,168.4 v2(80.57,168.4)
  BOTTOM w0.508: PD704.2 117.85,165.1 119.88,167.13 v2(120.78,167.13) 126.12,172.47 v2(127.06,172.47)
  vias: v3(74.92,158.98) v3(78.03,162.89) v3(78.02,160.66)
+19VB: length 47.2
  IN1 w0.508: v2(101.75,157.7) 102.55,156.9 102.55,151.36 v2(103.84,150.06) ; v2(77.83,169.11) 77.41,169.53 74.05,169.53 73.18,168.67 73.18,166.31 73.34,166.16 v2(73.34,164.85)
  IN2 w0.508: v2(101.75,157.7) 101.29,157.7 99.17,159.81 99.17,161.48 97.53,163.13 94.1,163.13 91.34,165.89 89.55,165.89 88.91,166.54 82.47,166.54 81.69,167.31 79.64,167.31 v2(77.83,169.11)
  vias: v2(37.95,43.79) v2(37.95,43.15) v2(38.59,44.42) v2(38.59,43.79) v2(38.6,43.18) v2(38.6,42.54) v2(39.22,44.42) v2(39.22,43.79) v2(39.24,43.18) v2(39.24,42.54) v2(44.13,64.71) v2(44.13,64.07) v2(44.13,63.44) v2(44.76,64.71) v2(44.76,64.07) v2(44.76,63.44) v2(45.4,64.71) v2(45.4,64.07) v2(45.4,63.44) v2(64.89,77.22) v2(64.89,76.58) v2(65.53,77.22) v2(65.53,76.58) v2(66.16,77.85) v2(66.16,77.22) v2(66.16,76.58) v2(66.86,77.85) v2(66.86,77.22) v2(66.86,76.58) v2(107.31,134.62) v2(107.31,133.98) v2(107.31,133.41) v2(107.31,132.78) v2(107.31,132.21) v2(107.88,134.62) v2(107.88,133.98) v2(107.88,133.41) v2(107.88,132.78) v2(117.4,154.88) v2(117.4,154.18) v2(117.4,153.54) v2(117.4,152.91) v2(117.4,152.27) v2(117.91,155.19) v2(117.91,154.56) v2(117.91,153.86) v2(117.91,153.23) v2(117.91,152.59) v2(127.18,154.29) v2(127.18,153.68) v2(127.18,153.11) v2(127.18,152.53) v2(127.17,151.96) v2(127.79,153.71) v2(127.79,153.14) v2(127.79,152.55) v2(127.73,151.98) v2(127.81,154.31) v3(43.69,59.07)
+19VB_1.2V: length 16.5
  TOP w0.254: PR208.1 v2(53.78,20.41)
  IN2 w0.508: v2(68.38,20.26) 63.49,20.26 62.6,21.15 60.64,21.15 59.18,19.69 57.33,19.69 56.61,20.41 v2(53.78,20.41)
  vias: v1(68.65,21.72) v2(68.38,19.62) v2(68.38,19.05) v2(69.02,20.19) v2(69.02,19.62) v2(69.02,19.05)
+19VB_+1.5VGPU:
  vias: v1(132.66,139.12) v2(131.76,138.24) v2(131.76,137.67) v2(131.76,137.1) v2(132.33,137.99) v2(132.33,137.35)
+19VB_+1VALW:
  vias: v1(126.27,127.42) v2(128.34,129.22) v2(128.34,128.59) v2(128.33,127.95) v2(128.33,127.32)
+19VB_GPU: length 23.9
  TOP w1.016: 162.39,97.35 159.18,100.55 156.18,100.55 152.59,104.14 152.59,105.72 151.5,106.81 151.5,115
  vias: v1(163.1,96.29) v2(165.41,113.92) v2(165.41,113.28) v2(166.08,113.94) v2(166.08,113.31) v2(166.49,96.27) v2(166.72,113.94) v2(166.72,113.31) v2(167.06,96.27) v2(167.35,113.94) v2(167.35,113.31) v2(167.76,96.9) v2(167.76,96.27) v2(167.99,113.94) v2(167.99,113.31)
+VCC_CORE: length 51
  TOP w0.305: PC1008.1 113.54,111.76 v2(113.91,111.76) ; v2(113.91,110.43) 113.61,110.43 PC1073.1
  TOP w0.381: v2(110.86,110.68) 110.56,110.68 PC1075.1 ; PC1080.1 107.38,109.28 v2(107.63,109.28) ; PC1068.1 107.38,110.55 v2(107.63,110.55) ; PC1061.1 104.66,110.55 v2(104.32,110.55) ; PC1076.1 110.56,109.41 v2(110.86,109.41) ; v2(110.86,112.01) 110.49,112.01 PC1006.1
  TOP w0.508: PC1070.1 107.36,106.77 107.64,106.77 ; PC1072.1 107.36,108.04 107.63,108.04 ; PC1171.1 110.53,108.17 110.88,108.17 ; v2(101.85,109.66) 101.53,109.66 PC1007.1
  BOTTOM w0.127: UC1.J33 118.55,92.2 ; UC1.J33 118.89,92.55 ; UC1.J33 118.89,91.78 ; UC1.J33 119.25,92.2 ; UC1.AL40 116.51,80.9 ; UC1.AL40 116.14,81.24 ; UC1.AL40 116.14,80.55 ; UC1.AL40 115.78,80.9 ; 118.43,81.72 UC1.AK35 ; UC1.AK35 118.07,81.36 ; UC1.AK35 118.43,80.99 ; UC1.J40 115.23,91.84 ; UC1.J40 114.92,92.2 ; UC1.J40 115.23,92.57 ; UC1.J40 115.57,92.2 ; 117.89,91.73 UC1.K37 ; UC1.K37 117.52,91.38 ; UC1.K37 117.19,91.73 ; UC1.K37 117.52,92.09 ; 113.86,91.26 UC1.K43 ; UC1.K43 114.23,91.73 ; UC1.K43 113.86,92.08 ; UC1.AK38 116.26,81.36 ; UC1.AK38 116.6,81.7 ; UC1.AK38 116.6,80.99 ; 119.9,80.42 UC1.AM32 ; UC1.AM32 120.26,80.76 ; UC1.AM32 120.26,80.17 120.17,80.09 ; 117.65,80.9 UC1.AL37 ; UC1.AL37 117.97,81.29 ; UC1.AL37 118.32,80.9 ; UC1.AL37 117.97,80.53 ; UC1.AM35 118.77,80.42 ; UC1.AM35 118.43,80.12 ; UC1.AM35 118.43,80.76 ; UC1.AM35 118.07,80.42 ; 117.52,81.72 UC1.AK37 ; UC1.AK37 117.88,81.36 ; UC1.AK37 117.52,80.99 ; 117.42,92.2 UC1.J37 ; UC1.J37 116.72,92.2 ; UC1.J37 117.06,91.84 ; UC1.J37 117.06,92.55 ; UC1.K42 115.14,91.73 ; UC1.K42 114.77,91.36 ; UC1.K42 114.4,91.73 ; UC1.K42 114.77,92.11 ; UC1.J30 120.36,92.2 ; UC1.J30 120.72,92.54 ; UC1.J30 120.72,91.93 120.68,91.9 ; UC1.K33 119.34,91.35 ; UC1.K33 119.68,91.73 ; UC1.K33 119.34,92.06 ; UC1.K33 119.02,91.73 ; 119.34,80.76 UC1.AM33 ; UC1.AM33 118.99,80.42 ; UC1.AM33 119.7,80.42 ; UC1.AM33 119.34,80.12 ; 117.19,80.42 UC1.AM37 ; UC1.AM37 117.52,80.76 ; UC1.AM37 117.52,80.12 ; UC1.AM37 117.88,80.42 ; UC1.K38 116.25,91.73 ; UC1.K38 116.6,92.09 ; UC1.K38 116.6,91.3 ; UC1.K38 116.96,91.73 ; UC1.AL33 120.17,80.9 ; UC1.AL33 119.46,80.9 ; UC1.AL33 119.8,81.22 ; UC1.AL33 119.8,80.53 ; UC1.AM38 116.33,80.42 116.29,80.47 ; UC1.AM38 116.6,80.76 ; UC1.AM38 117.04,80.42 ; UC1.AM38 116.6,80.1 ; 116.08,91.73 UC1.K40 ; UC1.K40 115.69,92.11 ; UC1.K40 115.32,91.73 ; UC1.K40 115.69,91.35 ; 119.34,81.01 UC1.AK33 ; UC1.AK33 119.71,81.36 ; UC1.AK33 119.34,81.74 ; 115.69,80.96 UC1.AK40 ; UC1.AK40 116.05,81.36 ; UC1.AK40 115.69,81.77 ; UC1.K35 118.43,91.3 ; UC1.K35 118.79,91.73 ; UC1.K35 118.06,91.73 ; UC1.K35 118.43,92.11
  BOTTOM w0.203: UC1.A34 118.27,96.66 118.68,97.07 v2(118.68,97.1) ; UC1.A44 113.33,96.37 113.33,97.22 v2(113.42,97.31) ; UC1.A39 115.79,96.84 115.69,96.94 v2(115.69,97.28) ; UC1.G42 v2(115.22,92.96) UC1.G40 ; UC1.G33 v2(118.84,92.97) UC1.G35 ; UC1.G32 v2(120.74,92.89) UC1.G30 ; UC1.G38 v2(117.05,92.91) UC1.G37
  BOTTOM w0.508: RC140.1 120.98,98.06 120.63,97.71 v2(120.63,97.09)
  vias: v2(101.85,111) v2(105.97,113.66) v2(105.97,112.97) v2(105.97,112.14) v2(105.97,110.93) v2(105.97,109.79) v2(105.97,108.97) v2(106.36,114.55) v2(106.76,113.77) v2(106.99,115.19) v2(106.99,114.55) v2(107.46,113.77) v2(107.63,115.19) v2(107.63,114.55) v2(108.26,115.19) v2(108.26,114.55) v2(108.22,113.77) v2(108.9,115.19) v2(108.9,114.55) v2(108.92,113.77) v2(109.85,113.41) v2(112.39,112.65) v2(112.39,112.01) v2(112.39,111.32) v2(112.39,110.68) v2(112.39,110.05) v2(114.15,90.18) v2(114.15,89) v2(114.15,87.8) v2(114.15,86.59) v2(114.15,85.34) v2(114.15,84.11) v2(114.32,91.49) v2(114.32,90.77) v2(114.77,91.13) v2(115.23,91.49) v2(115.23,90.77) v2(115.37,115.57) v2(115.37,115) v2(115.37,114.36) v2(115.37,113.66) v2(115.37,112.97) v2(115.37,111.44) v2(115.69,91.13) v2(115.98,82.25) v2(116.13,115.57) v2(116.13,115) v2(116.13,114.36) v2(116.13,113.66) v2(116.13,113.03) v2(116.13,112.39) v2(116.13,111.82) v2(116.13,111.25) v2(116.14,91.49) v2(116.14,90.77) v2(116.6,91.13) v2(116.69,90.18) v2(116.69,89) v2(116.69,87.8) v2(116.69,86.59) v2(116.69,85.34) v2(116.69,84.11) v2(117.06,91.49) v2(117.06,90.77) v2(117.07,82.25) v2(117.06,80.03) v2(117.52,91.13) v2(117.97,91.49) v2(117.97,90.77) v2(117.96,80.04) v2(118.43,91.13) v2(118.89,91.49) v2(118.89,90.77) v2(118.88,80.03) v2(119.1,90.18) v2(119.1,89) v2(119.1,87.8) v2(119.1,86.59) v2(119.1,85.34) v2(119.1,84.11) v2(119.34,91.13) v2(119.8,91.49) v2(119.8,90.77) v2(119.82,80.06) v2(120.26,91.13) v2(120.73,93.55) v2(120.72,90.77) v2(120.71,86.36) v2(120.71,85.72) v2(120.71,85.09) v2(120.71,84.45) v2(120.71,83.82) v3(101.8,112.78)
+VCC_CORE_G0: length 1.2
  TOP w0.203: T122.1 v2(120.75,91.45)
  BOTTOM w0.203: UC1.K32 v2(120.75,91.45)
+VCC_CORE_G1: length 1.1
  TOP w0.076: v2(120.26,81.97) 119.75,81.97 T123.1
  BOTTOM w0.102: UC1.AK32 v2(120.26,81.97)
+VCC_GT: length 85.1
  TOP w0.457: v2(95.52,90.07) 95.52,89.69 PC1134.1 ; PC1028.1 96.7,89.66 v2(96.7,90.07) ; v2(94.31,90.07) 94.31,89.69 PC1029.1
  TOP w0.508: PC1026.1 108.48,82.76 v2(108.48,83.17) ; PC1021.1 90.49,86.53 v2(90.49,86.99) ; PC1130.1 110.96,82.8 v2(110.96,83.17) ; v2(107.22,83.17) 107.22,82.71 PC1182.1 ; v2(91.77,87) 91.77,86.62 PC1175.1 ; PC1154.1 94.31,86.64 v2(94.31,87) ; v2(89.22,86.97) 89.22,86.52 PC1163.1 ; PC1025.1 91.76,89.59 v2(91.76,90.06) ; PC1014.1 95.58,86.64 v2(95.58,87) ; v2(86.57,86.98) PC1181.1 ; v2(93.04,87) 93.04,86.64 PC1024.1 ; v2(87.94,86.97) 87.94,86.46 PC1020.1 ; v2(93.03,90.07) 93.03,89.65 PC1159.1 ; PC1179.1 98.17,89.93 v2(98.17,90.03) ; v2(109.71,83.17) 109.71,82.77 PC1180.1
  BOTTOM w0.127: UC1.J48 110.96,92.2 ; UC1.J48 110.35,92.2 ; UC1.J48 110.66,92.5 ; UC1.J48 110.66,91.89 ; 107.46,91.43 UC1.K55 ; UC1.K55 107.76,91.73 ; UC1.K55 107.15,91.73 ; UC1.K55 107.46,92.04 ; 112.03,81.73 UC1.AK46 ; UC1.AK46 112.03,81.01 ; UC1.AK46 112.38,81.36 ; UC1.AK46 111.68,81.36 ; UC1.R63 103.34,88.71 ; UC1.R63 103.04,89.01 ; UC1.R63 102.73,88.71 ; UC1.R63 103.04,88.4 ; 110.75,81.36 UC1.AK48 ; UC1.AK48 111.12,80.99 ; UC1.AK48 111.12,81.7 ; UC1.AK48 111.51,81.36 ; UC1.J45 112.79,92.2 ; UC1.J45 112.49,91.89 ; UC1.J45 112.49,92.5 ; UC1.J45 112.18,92.2 ; 106.09,91.89 UC1.J56 ; UC1.J56 105.78,92.2 ; UC1.J56 106.09,92.5 ; UC1.J56 106.39,92.2 ; UC1.AL46 112.49,81.24 ; UC1.AL46 112.1,80.9 ; UC1.AL46 112.85,80.9 ; 105.63,91.43 UC1.K58 ; UC1.K58 105.63,92.04 ; UC1.K58 105.93,91.73 ; UC1.K58 105.32,91.73 ; UC1.K56 106.85,91.73 ; UC1.K56 106.24,91.73 ; UC1.K56 106.54,91.43 ; UC1.K56 106.54,92.04 ; UC1.J55 107,92.5 ; UC1.J55 106.69,92.2 ; UC1.J55 107,91.89 ; UC1.J55 107.31,92.2 ; 110.66,81.22 UC1.AL50 ; UC1.AL50 110.66,80.53 ; UC1.AL50 111.05,80.9 ; UC1.AL50 110.29,80.9 ; 109.44,92.2 UC1.J50 ; UC1.J50 109.74,92.5 ; UC1.J50 109.74,91.89 ; UC1.J50 110.05,92.2 ; 113.33,81.36 UC1.AK45 ; UC1.AK45 112.94,81.7 ; UC1.AK45 112.6,81.36 ; UC1.AK45 112.94,81.01 ; 103.51,89.78 UC1.M62 ; UC1.M62 103.2,90.08 ; UC1.M62 103.51,90.39 ; 107.46,81.01 UC1.AK55 ; UC1.AK55 107.46,81.72 ; UC1.AK55 107.12,81.36 ; UC1.AL53 109.15,80.9 ; UC1.AL53 108.49,80.9 ; UC1.AL53 108.83,81.24 ; UC1.AL53 108.83,80.58 ; UC1.AL60 105.17,80.53 ; UC1.AL60 105.17,81.22 ; UC1.AL60 104.83,80.9 ; UC1.AL60 105.59,80.9 ; 113.9,80.8 114.22,80.8 UC1.AL43 114.32,81.35 ; 104.41,91.73 UC1.K60 ; UC1.K60 104.71,92.04 ; UC1.K60 105.02,91.73 ; UC1.K60 104.71,91.43 ; UC1.J53 108.22,92.2 ; UC1.J53 107.91,91.89 ; UC1.J53 107.91,92.5 ; UC1.J53 107.53,92.2 ; 108.37,91.43 UC1.K53 ; UC1.K53 108.68,91.73 ; UC1.K53 108.07,91.73 ; UC1.K53 108.37,92.04 ; 109.29,80.76 UC1.AM52 ; UC1.AM52 109.62,80.42 ; UC1.AM52 108.93,80.42 ; 111.12,91.43 UC1.K48 ; UC1.K48 111.42,91.73 ; UC1.K48 110.81,91.73 ; UC1.K48 111.12,92.04 ; UC1.AA63 103.34,85.97 ; UC1.AA63 103.04,85.66 ; UC1.AA63 103.04,86.27 ; UC1.AA63 102.73,85.97 ; UC1.AK58 105.29,81.36 ; UC1.AK58 105.63,80.99 ; UC1.AK58 105.63,81.7 ; UC1.J46 111.88,92.2 ; UC1.J46 111.27,92.2 ; UC1.J46 111.57,92.5 ; UC1.J46 111.57,91.89 ; 113.86,81.73 UC1.AK43 ; UC1.AK43 113.52,81.36 ; UC1.AK43 113.86,80.99 ; UC1.AK43 114.22,81.36 ; 103.81,90.99 UC1.L62 ; UC1.L62 103.77,91.26 ; UC1.L62 103.51,91.3 ; UC1.L62 103.51,90.69 ; 103.04,86.57 UC1.W63 ; UC1.W63 102.73,86.88 ; UC1.W63 102.77,86.61 ; UC1.W63 103.34,86.88 ; UC1.AL56 107,81.24 ; UC1.AL56 106.66,80.9 ; UC1.AL56 107,80.58 ; UC1.AL56 107.37,80.9 ; 109.9,91.73 UC1.K50 ; UC1.K50 110.2,91.43 ; UC1.K50 110.51,91.73 ; UC1.K50 110.2,92.04 ; UC1.AM53 108.73,80.42 ; UC1.AM53 108.37,80.76 ; UC1.AM53 108.07,80.42 108.03,80.47 ; UC1.AM58 105.63,80.76 ; UC1.AM58 106.02,80.42 ; UC1.AM58 105.24,80.42 ; UC1.N63 103.04,89.93 ; UC1.N63 103.34,89.62 ; UC1.N63 103.04,89.32 ; UC1.N63 102.73,89.62 ; 113.1,92.2 UC1.J43 113.4,91.89 ; 108.98,91.73 UC1.K52 ; UC1.K52 109.59,91.73 ; UC1.K52 109.29,91.43 ; UC1.K52 109.29,92.04 ; 105.09,81.36 UC1.AK60 ; UC1.AK60 104.71,81.49 104.88,81.66 ; UC1.AK60 104.71,80.99 ; UC1.J60 104.26,92.5 ; UC1.J60 104.56,92.2 ; UC1.J60 103.95,92.2 ; UC1.J60 104.26,91.89 ; 103.51,86.12 UC1.Y62 ; UC1.Y62 103.51,86.73 ; UC1.Y62 103.2,86.42 ; UC1.AM50 110.2,80.76 ; UC1.AM50 109.87,80.42 ; UC1.AM50 110.56,80.42 ; UC1.AK50 110.2,81.73 ; UC1.AK50 110.2,81.01 ; UC1.AK50 110.57,81.36 ; UC1.T62 103.2,88.25 ; UC1.T62 103.51,87.95 ; UC1.T62 103.51,88.56 ; 106.18,80.42 UC1.AM56 106.54,80.79 ; 110.76,80.42 UC1.AM48 111.12,80.76 ; 114.77,81.7 UC1.AK42 114.39,81.36 ; 108.52,92.2 UC1.J52 ; UC1.J52 109.13,92.2 ; UC1.J52 108.83,92.5 ; UC1.J52 108.83,91.89 ; UC1.AK56 106.88,81.36 ; UC1.AK56 106.54,81.04 ; UC1.AK56 106.54,81.7 ; UC1.L63 102.77,90.27 ; UC1.L63 103.34,90.54 ; UC1.L63 102.73,90.54 ; UC1.L63 103.04,90.23 ; UC1.J58 105.48,92.2 ; UC1.J58 104.87,92.2 ; UC1.J58 105.17,91.89 ; UC1.J58 105.17,92.5 ; 108.37,81.7 UC1.AK53 ; UC1.AK53 108.7,81.36 ; UC1.AK53 108.37,81.01 ; UC1.AK52 109.29,80.99 ; UC1.AK52 108.92,81.36 ; UC1.AK52 109.29,81.7 ; UC1.L64 102.69,90.54
  BOTTOM w0.152: v2(97.16,81.58) 97.2,81.54 UC1.AK70 ; v2(100.49,73.13) 100.93,73.57 UC1.BB66 ; UC1.BB57 v2(105.91,72.76)
  BOTTOM w0.203: v2(111,96.83) 110.84,96.66 UC1.A48 ; UC1.A62 v2(103.4,97.18) ; UC1.A53 108.13,96.59 v2(108.13,97.23) ; v2(105.88,97.24) UC1.A58 ; v2(100.92,97.37) UC1.A66
  BOTTOM w0.254: UC1.AU63 102.71,77.17 v2(102.42,77.47) ; UC1.AU58 105.31,77.49 v2(105.21,77.49)
  BOTTOM w0.305: RC161.1 95.72,92.69 v2(96.15,92.26)
  vias: v2(60.01,65.02) v2(60.65,65.02) v2(61.26,65.04) v2(61.89,65.04) v2(62.41,70.17) v2(62.41,69.53) v2(62.41,68.9) v2(62.41,68.26) v2(62.41,67.63) v2(62.41,66.99) v2(62.53,65.04) v2(65.77,56.07) v2(65.77,55.47) v2(65.72,54.88) v2(66.35,59.31) v2(66.35,58.67) v2(66.48,67.18) v2(66.48,66.48) v2(66.48,64.77) v2(66.41,61.9) v2(66.43,56.08) v2(66.43,55.49) v2(66.43,54.88) v2(66.99,59.31) v2(66.99,58.67) v2(67.05,61.9) v2(67.11,69.09) v2(67.11,68.45) v2(67.11,67.82) v2(67.11,67.18) v2(67.11,66.48) v2(67.11,64.77) v2(67.75,69.72) v2(67.75,69.09) v2(67.75,68.45) v2(67.75,67.82) v2(67.75,67.18) v2(67.75,66.48) v2(67.75,64.77) v2(68.38,70.36) v2(68.38,69.72) v2(68.38,69.09) v2(68.38,68.45) v2(68.38,67.82) v2(68.38,67.18) v2(68.38,66.48) v2(69.02,70.36) v2(69.02,69.72) v2(69.02,69.09) v2(69.02,68.45) v2(69.02,67.82) v2(69.02,67.18) v2(69.02,66.48) v2(69.65,70.36) v2(69.65,67.18) v2(69.65,66.48) v2(69.78,69.72) v2(69.78,69.09) v2(69.78,68.45) v2(69.78,67.82) v2(70.41,70.36) v2(70.41,69.72) v2(70.41,69.09) v2(70.41,68.45) v2(70.41,67.82) v2(70.41,67.18) v2(70.41,66.48) v2(71.05,70.36) v2(71.05,69.72) v2(71.05,69.09) v2(71.05,68.45) v2(71.05,67.82) v2(71.05,67.18) v2(71.05,66.48) v2(78.23,75.5) v2(78.8,76.07) v2(79.73,76.95) v2(80.64,77.91) v2(81.23,82.12) v2(81.59,78.8) v2(82.12,83.01) v2(82.45,79.65) v2(83.06,83.9) v2(83.31,80.52) v2(84.73,81.94) v2(89.38,89.45) v2(90.67,89.45) v2(97.52,88.24) v2(97.52,87.32) v2(97.52,86.44) v2(98.15,88.24) v2(98.18,87.34) v2(98.16,86.44) v2(98.16,85.51) v2(98.79,85.51) v2(98.82,90.07) v2(98.82,89.17) v2(98.81,88.25) v2(98.81,86.42) v2(99.47,90.07) v2(99.46,89.17) v2(99.47,88.25) v2(99.49,86.43) v2(99.46,85.51) v2(100.11,90.07) v2(100.11,88.25) v2(100.11,87.34) v2(100.13,86.44) v2(100.74,90.07) v2(100.72,89.17) v2(100.74,88.24) v2(100.76,86.44) v2(100.76,85.51) v2(101.4,86.44) v2(101.4,90.09) v2(101.41,88.25) v2(102.06,90.09) v2(102.08,89.17) v2(102.04,88.24) v2(102.08,87.31) v2(102.06,86.46) v2(102.09,85.47) v2(102.65,90.07) v2(102.65,89.15) v2(102.65,88.24) v2(102.65,86.44) v2(104.24,91.24) v2(105.18,91.24) v2(105.16,80.14) v2(106.07,91.31) v2(106.08,80.03) v2(106.05,78.77) v2(106.4,90.58) v2(106.99,91.24) v2(106.99,81.69) v2(107.67,90.58) v2(107.93,91.24) v2(108.75,89.88) v2(108.84,91.31) v2(108.84,81.69) v2(108.84,79.99) v2(108.94,90.58) v2(109.53,90.31) v2(109.73,91.31) v2(110.64,91.31) v2(110.64,81.75) v2(110.67,80.06) v2(111.29,89.88) v2(111.43,81.86) v2(111.56,91.36) v2(111.93,83.66) v2(112.07,81.91) v2(112.56,89.88) v2(112.52,87.44) v2(112.58,84.29) v2(112.56,83.66) v2(112.62,84.91) v2(112.63,81.81) v3(65.92,62.86)
+VCC_SA:
  vias: v2(120.01,113.22) v2(120.01,112.59) v2(120.01,111.95) v2(120.01,111.32) v2(120.64,113.22) v2(120.64,112.59) v2(120.64,111.95) v2(120.64,111.32) v2(121.28,113.22) v2(121.28,112.59) v2(121.28,111.95) v2(121.28,111.32) v2(121.72,91.26) v2(122.36,91.26) v2(122.95,90.05) v2(122.94,88.91) v2(122.94,87.64) v2(122.94,86.39) v2(122.94,85.15) v2(123.88,91.25) v2(124.07,83.96) v2(124.33,92.96) v2(124.39,81.66) v2(125.22,88.04) v3(123.34,109.49)
+VDD_CT: length 10.5
  TOP w0.508: v2(155.98,133.39) 156.32,133.73 CV62.1 ; v2(157.42,133.79) 157.42,134.36 CV63.1 ; v2(152.13,129.03) 151.83,128.73 151.14,128.73 CV61.1 150.06,127.65 LV3.2
  BOTTOM w0.102: v1(150.55,128.52) 151.06,129.03 152.13,129.03 v2(152.13,129.03)
  BOTTOM w0.381: UV1.AB21 156.69,134 157.18,134.49 UV1.AA21 157.42,134.47 v2(157.42,133.79) 158.1,133.79 UV1.AA20 ; UV1.AB21 156.37,133.79 v2(155.98,133.39) ; UV1.AB21 156.69,133.62 157.22,133.08 UV1.AB20
+VDDR3: length 19.3
  TOP w0.508: v2(159.44,131.75) 158.55,132.64 CV66.1 ; v2(157.54,131.39) 158.25,131.39 CV65.1
  IN2 w0.508: v2(157.54,131.39) 154.51,128.37 154.51,127.48 v2(153.63,126.59)
  BOTTOM w0.381: v2(157.54,131.39) 157.54,131.42 158.1,131.98 UV1.AB18 UV1.AA18 UV1.AA17 159.42,132.27 159.42,131.78 v2(159.44,131.75) 158.89,131.75 UV1.AB17
  BOTTOM w0.508: v2(153.63,126.59) 153.45,126.42 152.91,126.42 152.2,127.13 v1(151.67,127.13) 150.93,127.13 CV64.1 150.42,126.49 CV123.1 150.29,125.11 LV4.2
AVCC33: length 6.9
  TOP w0.305: R5504.2 31.7,59.44 31.43,59.72 31.43,60.44 30.88,60.99
  TOP w0.508: v2(32.12,60.45) 32.12,59.45 R5504.2
  BOTTOM w0.102: v2(32.12,60.45) v1(32.63,59.94)
  BOTTOM w0.508: C5517.1 32.2,61.68 C5523.2 31.95,60.62 v2(32.12,60.45)
GND: length 2642.6
  TOP w0.14: UV20.B1 186.73,145.89 186.17,146.45 UV20.B3
  TOP w0.152: UV18.G8 UV18.G9
  TOP w0.203: UZ2.11 v2(45.78,17.78) ; UV20.G9 185.03,152.67 185.59,152.11 UV20.G8 ; CC215.2 127.56,80.24 127.56,79.83 v2(127.12,79.38) ; UE1.124 189.95,66.02 190.56,65.4 v2(190.66,65.4) ; UE1.84 v2(175.66,73.57) ; v2(192.94,66.13) 193.1,65.98 194.13,65.98 C5226.2 195.32,65.4 195.7,65.02 195.7,62.93 194.97,62.19 191.26,62.19 ; U15.11 142.61,153.92 v2(142.63,153.92) ; UE1.17 192.07,75.17 v2(191.89,74.99) ; v2(180.65,65.91) 180.35,66.22 UE1.100 ; PU200.1 59.43,21.72 ; v2(184.21,84.07) 184.35,83.94 UE1.51 ; v2(178.47,83.05) 178.47,83.41 178.62,83.57 179,83.57 179.15,83.42 UE1.64
  TOP w0.254: UZ21.5 131.32,109.72 130.93,110.11 130.06,110.11 v2(129.79,110.38) ; UV20.D8 v2(184.47,150.41) UV20.E8 ; UV20.J8 186.21,153.24 v2(186.15,153.17) ; RN5203.3 86.67,154.05 86.67,154.05 v2(86.92,153.8) ; 186.2,125.58 185.78,125.58 185.27,126.09 CV96.2 ; UV20.D1 v2(188.43,146.45) UV20.E1 v2(187.86,147.01) UV20.E2 ; UV18.M9 174.4,169.53 v2(174.4,169.53) ; v2(181.18,166.12) 181.19,166.12 UV18.T1 ; UV20.B1 v2(186.73,144.75) ; CV53.2 162.87,138.94 164.14,138.94 CV89.2 ; RN5203.2 86.17,154.05 85.91,153.8 v2(85.67,153.8) RN5203.1 ; v2(187.32,155.48) 187.34,155.5 UV20.M9 ; v2(152.95,128.19) 153.2,128.45 154.14,128.45 RV13.2 CV11.2 ; PQ2.1 119.42,170.19 118.62,170.99 v2(118.62,171.32) ; v2(194.65,152.67) 194.65,152.67 UV20.T1 ; v2(117.88,93.64) 117.89,93.62 PC1084.2 ; UV18.G9 171.57,166.61 v2(171.51,166.67) ; C3011.2 46.76,173.89 46.21,174.45 46.21,174.89 v2(46.03,175.07) ; v2(166.17,127.2) 166.03,127.06 CV104.2 ; v2(179.44,164.47) 178.95,164.47 UV18.M1 ; v2(170.32,167.81) 169.84,168.29 CV397.2 ; UV11.5 177.43,124.31 v2(177.43,124.82) ; v2(176,171.23) 176.01,171.23 UV18.T9 ; UV18.P1 180.06,166.12 v2(180.08,166.15) ; v2(188.99,148.15) UV20.G1 ; PC1126.2 113.59,92.69 v2(113.32,92.96) ; v2(152.62,131.72) 153.59,130.76 RV12.2 153.82,130.67 154.48,130.67 CV28.2 ; v2(24.08,62.84) 24.4,62.84 24.62,63.06 24.62,64.21 24.99,64.59 v2(25.21,64.59) U5502.11 ; v2(166.05,161.35) 166.71,161.35 CV400.2 ; CV177.2 170.57,135.1 v2(169.47,135.1) ; v2(173.27,167.26) UV18.J8 ; UV20.T9 v2(190.12,158.33) ; v2(190.12,149.28) 190.12,149.29 UV20.J2 ; U5502.13 v2(25.34,63.59) ; v2(189.56,156.63) UV20.P9 ; v2(166,129.18) 165.8,128.99 CV114.2 ; UV20.B9 181.84,150.2 v2(181.66,150.2) ; v2(176.1,170.09) UV18.P9 ; CV48.2 v2(161.68,141.9) ; UV18.E8 v2(170.44,164.44) UV18.D8 ; UV18.J2 176.66,162.71 v2(176.67,162.7) ; v2(117.07,93.5) 117.04,93.52 PC1087.2 ; v2(161.58,139.32) 161.46,139.43 CV42.2 ; UV20.G9 v2(184.47,152.67) UV20.F9 ; U5502.14 25.59,63.09 v2(25.34,62.83) 25.34,62.63 24.66,61.95 24.66,60.72 24.5,60.56 v2(24.08,60.56) ; v2(160.01,144.65) 160.51,144.65 160.89,144.27 161.47,144.27 CV41.2 161.59,143.88 161.23,143.52 CV174.2 ; v2(192.74,150.62) UV20.M1 ; UV20.A9 v2(181.07,149.28) ; v2(170.43,165.8) 170.66,165.57 UV18.F9 ; v2(176.67,161.49) 176.61,161.54 176.16,161.54 UV18.G1 ; v2(24.08,57.89) 24.44,57.89 25.52,58.98 v2(25.52,61.53) ; UV18.B9 168.68,163.36 v2(168.1,163.36) 168.1,162.82 UV18.A9 ; v2(193.52,152.67) UV20.P1
  TOP w0.305: v2(167.7,136.52) 167.45,136.28 CV178.2 ; CC24.2 140.75,63.57 v2(140.03,63.57) ; U5502.16 25.83,62.09 25.52,61.78 v2(25.52,61.53) ; 168.02,134.23 167.64,134.61 CV40.2 CV51.2 166.48,133.88 v2(165.65,133.88) ; 168.02,134.23 CV52.2 168.52,134.23 168.59,134.16 169.42,134.16 CV176.2 169.46,135.09 v2(169.47,135.1) ; 168.02,134.23 CV112.2 ; v2(186.75,157.54) 186.38,157.54 RV264.2 ; v2(154.17,86.23) 154.32,86.08 ODD1.20 ; PC1050.2 119.7,92.96 v2(119.71,92.97) 119.62,93.07 PC1035.2 PC1091.2 ; PC1094.2 v2(116.12,92.94) ; PC1073.2 114.37,111.06 v2(113.91,111.06) ; PC1008.2 114.3,112.39 v2(113.91,112.39) ; v2(171.56,159.96) 171.61,159.91 UV18.B3 ; ODD1.1 156.27,76.58 156.97,75.88 v2(156.97,75.88) ; v2(114.32,92.94) 114.37,92.89 PC1086.2 ; UV18.E2 174.4,160.48 ; 174.4,160.48 UV18.D1 ; 174.4,160.48 v2(174.4,160.48) ; 174.4,160.48 v2(174.4,160.48) ; UV18.B1 173.32,158.78 173.8,158.3 v2(173.86,158.3) ; v2(156.34,78.18) 156.28,78.18 156.18,78.08 ODD1.4 154.7,78.08 154.49,78.3 154.49,79.28 154.79,79.58 ODD1.7 ; v2(174.62,134.56) 175.05,134.12 CV93.2 ; ODD1.18 153.99,85.08 v2(153.85,85.22) 154.22,85.58 ODD1.19 ; v2(174.4,160.48) UV18.E1 ; PC1097.2 117.95,92.79 v2(117.97,92.82) ; v2(136.26,116.13) 136.19,116.05 136.19,115.66 136.31,115.53 UZ19.5
  TOP w0.356: v2(112.49,80.03) 112.47,80.04 PC1055.2 ; PC1045.2 111.61,80.07 v2(111.57,80.03) ; v2(106.05,77.51) 105.82,77.29 PC1040.2 ; v2(146.9,81.2) 147.41,81.2 147.6,81.39 UC7.3
  TOP w0.381: v2(161.44,131.09) 162.21,131.09 162.27,131.15 ; v2(107.22,73.5) 107.06,73.34 PC1042.2 ; v2(49.89,173.03) 49.75,173.17 C3001.2 ; PC1023.2 82.26,78.98 v2(82.02,79.22) ; v2(133.03,171.96) 131.25,171.96 130.72,172.48 PQ1.4 ; 164.23,133.01 164.14,133.1 v2(164.14,133.73) ; v2(159.05,127.94) 158.61,128.39 CV21.2 159.07,128.89 CV20.2 ; v2(82.89,80.09) 83.2,79.77 83.2,79.39 PC1224.2 ; PC1075.2 111.32,111.32 v2(110.86,111.32) ; PC1092.2 113.18,90.19 PC1174.2 ; v2(166.67,164.35) 166.16,164.35 CV401.2 ; v2(100.8,90.96) 100.76,91 PC1046.2 ; EU3102.3 v2(35.7,174.15) ; CV395.2 195.89,153.92 v2(195.7,153.92) ; v2(142.51,88.82) 142.61,88.72 CC207.2 ; PC1183.2 80.48,77.05 v2(80.13,77.41) ; CV118.2 166.22,130.84 166.22,131.5 RV2.1 166.78,131.57 v2(167.11,131.24) ; PC1007.2 102.29,110.3 v2(101.85,110.3) ; UC17.3 168.05,89.93 167.54,89.42 CC1103.2 ; PC1061.2 103.9,111.19 v2(104.32,111.19) ; PC1049.2 99.71,97.46 v2(99.8,97.37) ; CV188.2 186.16,142.09 v2(186.16,144.19) ; CV100.2 164.66,129.91 v2(164.93,130.17) 164.93,130.28 164.66,130.54 164.66,130.77 ; v2(142.17,117.98) 142.41,117.74 UC15.3 ; v2(167.75,128.96) CVT90.1 167.98,129.64 167.75,129.64 CV73.2 ; PC1098.2 111.59,94.17 v2(111.58,94.18) ; v2(81.15,78.42) 81.37,78.2 PC1221.2 ; v2(107.63,111.19) 108.15,111.19 PC1068.2 ; v2(177.73,171.83) 178.23,172.33 CV196.2 ; PC1039.2 PC1034.2 101.69,107.58 v2(102,107.89) ; v2(107,80.03) 107.29,80.32 PC1041.2 ; v2(102.65,105.29) 102.65,105.29 102.65,105.28 102.29,105.28 102.1,105.47 PC1036.2 PC1085.2 ; v2(132.26,176.15) 132.02,175.91 PQ1.1 ; PC1176.2 84.04,80.74 83.81,80.96 v2(83.81,81.03) ; CV75.2 165.16,132.31 v2(165.69,132.31) ; v2(107.63,109.92) 108.15,109.92 PC1080.2 ; PC1181.2 86.42,87.69 85.93,87.21 v2(85.93,86.98) ; R1902.2 162.74,67.45 162.74,68.95 163.12,69.33 UC16.3 ; v2(100.6,76.2) 100.72,76.33 PC1044.2 ; PC1056.2 106.52,75.59 106.29,75.82 105.91,75.82 v2(105.91,75.82) ; PC1076.2 111.32,110.05 v2(110.86,110.05) ; v2(158.25,130.69) 158.13,130.81 157.31,130.81 CV29.2 RV9.2 ; v2(100.92,95.19) 100.93,95.19 PC1043.2 ; PC1006.2 111.26,112.65 v2(110.86,112.65) ; RC380.2 R5604.2 151.87,80.24 152.23,79.88 v2(152.23,79.73) ; CV62.2 156,134.5 CV63.2 156.75,135.25 v2(157.36,135.25) ; v2(190.66,65.4) 190.66,65.33 191.06,64.92 C5225.2 ; v2(87.3,87.02) 87.3,87.34 87.65,87.69 PC1020.2 ; v2(163,129.72) 163.26,129.45 CV76.2 ; v2(101.85,111.63) 102.28,111.63 PC1005.2 ; v2(172.27,69.72) 172.9,69.72 DE8.2 ; RC341.2 105.82,80.79 106.09,81.05 v2(106.09,81.65)
  TOP w0.406: PQ720.3 v2(69.25,168.4) ; PQ721.3 69.01,159.51 v2(69.14,159.38)
  TOP w0.457: CC224.2 131.43,81.13 v2(131.64,80.92) ; PC1222.2 82.37,83.7 v2(82.61,83.46) ; PC1172.2 117.07,87.19 v2(116.69,87.19) ; PC1010.2 117.07,84.71 v2(116.69,84.71) ; PC1134.2 94.91,90.48 v2(94.91,90.07) ; PC1138.2 81.5,82.73 v2(81.67,82.56) ; CC291.2 94.44,92.99 v2(94.88,92.55) 94.44,92.1 CC290.2 ; PC1173.2 119.48,87.19 v2(119.1,87.19) ; PC1004.2 119.48,85.98 v2(119.1,85.98) ; PC1067.2 119.48,83.5 v2(119.1,83.5) ; v2(114.15,88.39) 113.77,88.39 PC1079.2 ; PC1001.2 117.07,88.39 v2(116.69,88.39) ; PC1028.2 96.12,90.48 v2(96.12,90.07) ; PC1069.2 113.77,85.98 v2(114.15,85.98) ; v2(119.1,84.71) 119.48,84.71 PC1012.2 ; v2(116.69,85.98) 117.07,85.98 PC1082.2 ; PC1066.2 113.77,83.5 v2(114.15,83.5) ; v2(80.78,81.67) 80.61,81.85 PC1161.2 ; v2(114.15,87.19) 113.77,87.19 PC1011.2 ; v2(114.15,84.71) 113.77,84.71 PC1081.2 ; v2(129.38,84.12) 129.38,83.96 128.93,83.52 CC265.2 128.93,82.92 CC223.2 ; RC91.2 97.64,92.04 v2(96.9,92.78) 97.05,92.93 RC90.2 ; v2(124.52,88.91) 124.53,88.92 CC202.2 ; PC1074.2 119.48,89.6 v2(119.1,89.6) ; v2(116.69,83.5) 117.07,83.5 PC1170.2 ; PC1179.2 97.28,90.44 v2(97.28,90.07) ; CC270.2 125.82,80.4 v2(126.2,80.01) ; v2(93.7,90.07) 93.7,90.48 PC1029.2 ; v2(114.15,89.6) 113.77,89.6 PC1174.2 ; PC1078.2 119.48,88.39 v2(119.1,88.39) ; v2(116.69,89.6) 117.07,89.6 PC1002.2
  TOP w0.508: CV82.2 169.28,130.67 v2(168.92,131.04) 169.34,131.46 CV124.2 ; RV41.1 176.06,127.53 176.06,126.34 v2(175.82,126.11) ; RV41.1 176.71,127.89 RV40.1 177.22,128.4 177.22,129.22 CV84.2 176.92,129.44 CV85.2 CV86.2 175.56,130.95 175.33,131.18 v2(175.33,131.46) ; RV41.1 175.7,128.02 RV17.1 ; CD71.2 140.07,40.01 v2(140.67,40.6) ; v2(81.82,171.02) 81.81,171.01 PR732.2 ; CE77.2 172.78,67.31 v2(172.46,66.99) ; v2(175.06,81.96) 175.16,81.86 CE68.2 ; RC220.2 162.05,54.42 162.24,54.61 162.24,55.01 v2(162.24,55.02) 161.96,55.31 CC266.2 ; CC211.2 136.32,96.85 v2(136.52,97.05) ; CV105.2 161.51,135.57 CV115.2 ; v2(94.95,87.05) 94.95,87.4 PC1014.2 ; CV58.2 157.22,142.23 CV54.2 ; CV58.2 CV121.2 CV60.2 ; CV58.2 156.74,141.7 v2(156.74,141.65) ; PBATT1.9 v2(170.62,179.77) ; CV227.2 v2(193.22,145.68) ; v2(150.57,130.54) 150.64,130.54 151.03,130.93 RV16.2 CV15.2 ; v2(31.05,22.8) 31.05,23.46 30.54,23.97 EC3305.2 ; EC9710.2 v2(137.42,143.39) ; v2(160.16,133.72) 159.51,133.72 CV106.2 ; CD21.2 92.26,25.27 v2(92.92,25.92) ; PJPDC1.8 v2(85.05,168.37) ; v2(130.47,95.13) 130.77,95.44 131.95,95.44 132.41,95.91 132.41,95.92 132.99,96.49 133.7,96.49 RC3.2 134.43,96.91 CC264.2 ; C5501.2 34.44,60.55 v2(35.17,59.82) ; v2(196.08,127.5) 196.36,127.22 KB_BL1.6 ; RC5.2 RC6.2 ; RC6.2 RC7.2 RC88.2 RC89.2 ; RC6.2 127.37,73.61 v2(127.8,73.18) ; CV113.2 161.24,128.34 v2(160.86,127.97) ; v2(30.11,20.22) EC3306.2 EC3301.2 ; EC3303.2 29.65,13.58 v2(29.65,13.65) 29.65,13.73 EC3304.2 ; v2(89.85,87) 89.85,87.3 PC1021.2 ; 53.9,18.48 v2(53.9,17.46) ; v2(39.7,178.03) 39.7,177.84 EC3108.1 ; CE64.1 CE67.2 v2(196.53,68.45) ; CD7.2 92.42,39.5 v2(91.68,40.23) ; CC293.2 138.74,23.37 138.74,22.48 138.44,22.18 v2(138.13,22.18) ; PC1013.2 v2(112.34,108) ; CV10.2 184.77,122.45 v2(185.02,122.45) ; CV70.2 169.75,125.78 169.75,125.25 v2(169.47,124.97) ; v2(126.75,63.56) 126.75,64.38 126.42,64.71 CC294.2 ; R3015.2 55.04,167.61 v2(55.45,168.02) ; C3013.2 v2(62.27,177.43) ; v2(120.71,18.29) 121.09,17.91 121.09,17.4 122.36,17.4 ; CE73.2 190.7,62.72 v2(191.22,62.19) 191.26,62.19 ; CC205.2 128.42,85.74 CC212.2 129.97,85.74 v2(130.03,85.8) ; v2(172.27,173.21) 172.27,173.1 RV262.2 ; v2(136.76,106.07) 136.76,106.44 136.52,106.68 CC216.2 ; CD78.2 81.46,27.11 v2(81.97,27.62) ; v2(44.51,175.01) 44.43,174.93 C3022.2 R3032.1 C3008.2 44.51,172.45 C3005.2 ; PR29.2 v2(115.83,169.54) ; v2(78.28,158.15) 78.15,158.03 PC4.2 PC3.2 ; CZ1703.2 135.11,111.01 134,111.01 CZ1701.2 133.93,110.55 v2(133.66,110.29) 133.01,109.64 UZ21.9 133.01,107.88 CZ78.2 ; CD84.2 143.69,17.53 143.85,17.68 v2(143.86,17.68) ; Q2405.3 v2(50.22,71.68) ; RC377.2 154.88,67.29 155.12,67.06 v2(155.45,67.06) ; CD19.2 126.93,25.4 127.5,25.97 v2(127.5,26.16) ; v2(29.36,58.2) 29.19,58.37 C5522.2 ; PC1171.2 111.75,108.52 v2(112.39,109.16) ; CV184.2 188.59,143.06 v2(189.01,142.65) ; v2(38.43,171.16) 38.5,171.09 EC3105.1 ; v2(109.05,32.67) 109.05,32.13 109.56,31.62 CD5.2 ; CV35.2 157.58,127.58 CV26.2 155.79,125.78 v2(155.45,125.78) ; Q2505.3 34.52,17.73 v2(34.78,17.98) ; PC1025.2 91.12,90.35 v2(91.12,90.11) ; v2(107.37,40.45) 107.37,40.13 CD6.2 ; v2(177.1,174.81) 177.1,174.82 CV182.2 ; R6302.1 v2(187.77,31.72) ; v2(122.68,63.94) 122.56,63.82 CC297.2 CC176.2 ; v2(114.23,66.42) 114.23,66.42 CC174.2 CC179.2 ; v2(34.58,13.61) 34.58,13.89 34.3,14.17 R2504.2 ; RH210.2 CD29.2 129.47,17.35 v2(130.05,17.94) ; v2(179.86,125.45) CV97.2 RV38.2 ; v2(190.15,175.49) 190.57,175.07 ED6101.2 191.15,174.15 191.12,174.12 ; EU3403.1 v2(22.07,39.06) ; v2(109.21,109.09) 108.57,108.45 PC1072.2 PC1070.2 ; R3023.2 63.98,171.37 v2(64.12,171.5) ; v2(144.52,171.7) 144.7,171.53 PR32.2 ; DA14.1 84,9.65 83.69,9.33 v2(83.37,9.33) ; v2(27.89,69.14) 27.75,69 C5516.2 ; C6215.2 187.51,14.48 188.32,13.67 189.01,13.67 189.01,12.73 v2(189.03,12.7) ; EC9759.2 v2(69.56,158.41) ; v2(109.21,111.32) 109.21,111.39 PC1003.2 ; EC9714.2 127.59,155.61 v2(127.31,155.89) ; v2(115.63,15.11) 115.63,15.3 115.82,15.49 CD69.2 ; EC9702.2 150.3,123.63 v2(150.11,123.82) ; v2(118.29,37.65) 118.17,37.77 CD76.2 116.88,38.53 CD73.2 ; v2(73.97,25.24) 73.64,25.24 EC9705.2 ; R1902.2 162.6,67.3 162.41,67.1 v2(162.41,66.47) ; PC1009.2 PC1061.2 ; v2(193.58,124.43) 193.58,125.37 192.55,126.41 EC6207.2 ; v2(109.74,81.59) 109.88,81.45 109.88,80.87 PC1027.2 ; RC182.1 v2(36.12,60.77) ; v2(185.43,124.13) 185.45,124.13 185.45,124.12 R6207.2 186.07,125.45 Q6202.3 ; EC9708.2 v2(57.16,42.61) ; PD6.2 91.41,150.2 v2(90.99,149.78) ; RE358.2 v2(189.16,60.32) ; v2(56.92,177.85) 56.92,176.55 C3012.2 57.1,175.72 C3019.2 ; PC654.1 PC651.1 118.1,132.78 PC647.1 118.49,132.77 v2(118.84,132.42) ; v2(116.26,25.97) 115.82,25.53 CD23.2 ; PC8.2 v2(152.25,173.23) ; PR103.2 v2(38.65,41.57) ; EC6103.2 v2(28.76,6.6) ; v2(108.39,75.82) 107.18,74.62 PC1133.2 ; CZ23.2 CZ50.2 44.25,15.21 v2(44.38,15.09) ; PC202.2 v2(53.78,22.19) ; v2(162.17,64.07) 162.74,64.07 163.01,63.8 Q1901.3 ; EC9706.2 v2(35.36,51.31) ; v2(31.31,172.52) 31.9,171.92 C3106.2 ; C2716.2 177.22,16.45 174.94,16.45 v2(174.59,16.8) ; v2(190.94,161.54) 190.29,160.89 CV43.2 ; v2(125.89,105.12) 126.07,105.3 RC166.2 126.5,105.35 RC1.1 ; CD81.2 v2(126.99,17.69) ; CN6301.20 v2(190.75,40.77) ; CV50.2 CV47.2 178.5,134.1 v2(178.11,134.49) ; v2(132.44,18.35) 132.9,17.83 CD85.2 ; v2(197.68,150.9) 197.51,151.06 197.51,151.13 CV398.2 ; v2(188.68,123.52) 188.16,123.01 EC6208.2 C6202.2 ; v2(173.65,73.71) CE69.2 173.67,74.37 RE357.2 ; v2(120.78,168.02) 120.91,167.89 PR33.1 121.39,168.27 121.7,168.58 PQ2.4 ; CV103.2 162.85,134.67 v2(162.85,135.13) ; RC381.2 153.79,72.77 v2(154,72.57) 154.45,72.57 154.67,72.34 RC347.2 ; v2(190.23,177.77) 190.23,177.77 EC6105.2 ; v2(28.89,8.06) C2503.2 EC3302.2 ; TPAD1.9 65.65,68.9 v2(66.41,68.14) ; PC204.1 57.78,15.3 58.47,14.61 v2(59.04,14.61) ; v2(110.28,143.41) PR631.1 111.01,143.38 PC621.1 ; CV66.2 157.91,133.26 157.49,132.84 157.16,132.84 v2(156.9,132.59) 157.27,132.22 CV65.2 ; PC1162.2 88.75,89.82 v2(88.75,89.47) ; C3002.2 v2(53.43,171.68) ; v2(116.26,32.26) 116.45,32.07 CD1.2 ; v2(130.49,177.42) 130.54,177.37 PR2.2 ; CC273.2 145.93,92.79 v2(145.96,92.82) 146.47,93.33 CC1801.2 ; CV92.2 177.6,133.6 v2(177.48,133.73) ; TPAD1.10 63.95,82.43 v2(63.94,82.42) ; v2(49.08,43.18) 48.65,43.6 PR122.2 ; v2(34.47,3.94) 34.31,3.78 EC6102.2 ; CE75.2 CE8.2 v2(187.13,86.61) ; C6214.2 C2719.2 176.21,17.27 v2(176.14,17.34) ; CV393.2 172.39,170.76 v2(172.78,170.37) ; v2(20.5,2.19) 19.95,2.19 LED1.3 ; PC1180.2 109.09,83.55 v2(109.09,83.2) ; v2(100.25,166.92) PJPDC1.7 ; R5412.2 v2(31.49,80.89) ; CV59.2 158.29,140.05 v2(157.85,140.49) 158.07,140.49 CV60.2 ; v2(190.28,143.92) 190.28,143.99 CV185.2 ; CC218.2 131.69,98.3 v2(131.69,99.12) ; EC9712.2 v2(65.23,35.94) ; PWR1.5 v2(195.83,164.72) ; PC1130.2 110.34,83.57 v2(110.34,83.17) ; v2(92.58,147.07) 92.79,147.28 PD5.2 ; EC3106.1 v2(40.31,173.78) ; RV143.2 v2(192.58,145.04) ; PC1064.2 102.23,109.03 v2(101.85,109.03) ; RC114.2 98.66,105.03 98.15,105.54 v2(97.91,105.54) ; PC203.2 v2(53.78,23.08) ; CV39.2 150.5,132.79 151.09,132.79 v2(151.16,132.71) 151.56,133.11 RV160.2 ; G6101.1 v2(194.87,173.35) ; v2(123.66,137.64) 123.66,137.96 123.15,138.46 PC601.2 ; v2(173.51,174.4) 173.91,174 RV110.2 ; v2(61.4,75.73) 61.52,75.61 TPAD1.4 ; PC7.2 v2(151.39,173.23) ; CD22.2 CD83.2 v2(118.99,17.72) ; v2(169.67,167.32) 169.67,167.35 CV44.2 ; v2(149.03,88.96) 149.03,89.48 RC312.1 ; RH209.2 125.85,32.32 125.98,32.45 125.98,32.64 v2(125.97,32.64) ; EC9717.2 122.56,146.35 v2(122.13,145.92) ; PC1159.2 92.39,90.41 v2(92.39,90.11) ; CV327.2 v2(172.78,173.86) ; C26.1 v2(140.39,152.37) ; v2(142.04,85.98) 142.6,85.42 RC44.2 RC96.2 RC393.2 ; CZ30.2 59.21,78.49 58.76,78.03 58.76,77.42 v2(58.78,77.39) ; C2701.2 175.13,19.3 v2(175.06,19.24) ; CV61.2 150.17,129.03 v2(150.42,129.03) ; v2(162.97,131.01) 163.1,131.14 163.1,131.57 162.88,131.79 ; KB1.32 186.45,90.6 186.82,90.97 v2(186.82,92.42) ; v2(108.69,66.57) 108.69,65.96 108.68,65.95 CC257.2 CC296.2 ; v2(141.79,114) 141.34,114 141.15,114.19 CZ86.2 ; SW1.1 201.72,63.13 v2(201.73,63.12) ; RV29.1 154.29,135.63 RV59.1 154.05,135.96 153.74,136.27 v2(153.66,136.27) ; v2(32.44,24.7) 32,25.15 EC3307.2 ; EC9703.2 109.82,143.89 v2(110.29,144.37) ; CV34.2 CV33.2 160.72,126.89 v2(160.99,126.62) ; v2(80.41,162.52) 80.87,162.98 PQ712.3 ; v2(89.33,156.28) 89.33,156.71 89.51,156.89 PQ5.3 89.51,158.38 PR9.1 ; CD2.2 CD77.2 113.99,39.57 v2(114.17,39.75) ; CZ82.2 v2(135.52,117.05) ; v2(140.9,155.89) 140.76,155.75 C24.1 ; v2(152.21,170.05) 151.3,170.05 PQ3.3 ; v2(92.41,87.05) 92.41,87.4 PC1024.2 ; CC281.2 135.44,95.25 v2(135.43,95.24) ; v2(158.81,143.46) 158.81,144.14 RV39.1 ; CV81.2 172.49,130.71 171.04,130.71 v2(171.02,130.69) ; RD40.2 v2(128.85,13.51) ; CV27.2 155.15,123.47 v2(154.87,123.47) ; PC1065.2 103.64,113 v2(104.38,113.73) ; CD74.2 129.27,39.57 128.91,39.93 128.91,40.65 129.11,40.85 v2(129.58,40.85) ; v2(91.13,87.03) 91.13,87.38 PC1175.2 ; PD3.1 155.31,175.89 v2(155.7,175.51) ; EC2901.2 89.01,4.05 v2(89.2,4.24) ; CC27.2 153.54,50.56 v2(153.97,50.99) ; CD24.2 v2(117.85,25.91) ; v2(152.48,125.98) 152.48,126.47 CV19.2 ; v2(90.03,89.49) 90.03,89.89 PC1158.2 ; CC178.2 CC177.2 103.54,64.03 v2(103.45,63.94) ; v2(119.97,145.39) PR611.2 ; v2(79.85,168.61) 79.85,169 PC711.1 ; v2(88.58,86.99) 88.58,87.27 PC1163.2 ; v2(194.32,20.78) 194.9,20.19 CN6301.25 ; v2(178.49,63.06) CE76.2 ; v2(81.84,154.88) 81.84,156.57 PC2.2 PC1.2 ; v2(194.23,150.49) 194.83,150.49 CV183.2 ; v2(118.42,146) PR608.2 ; CC299.2 173.36,90.56 v2(173.65,90.86) ; ODD1.22 v2(160.9,73.17) ; C3004.2 45.85,162.69 C3007.2 C3003.2 v2(46.98,162.32) ; v2(26.47,74.63) 26.54,74.56 R5418.1 ; v2(104.13,105.25) 103.68,105.69 PC1071.2 103.64,107.15 PC1077.2 ; PR204.2 v2(53.78,24.89) ; v2(93.68,87.03) 93.68,87.4 PC1154.2 ; EC9701.2 93.33,105.3 v2(93.59,105.03) v2(93.59,104.39) ; CARD1.6 26.2,22.49 v2(26.54,22.16) ; v2(86.73,37.4) 86.1,38.04 CD8.2 ; v2(161.46,132.6) 161.45,132.59 CV68.2 ; CC208.2 CC207.2 ; PD4.1 93.66,155.65 v2(93.58,155.57) ; v2(165.56,125.45) 165.87,125.45 CV67.2 ; v2(117.84,161.54) 118.4,161.54 PQ711.3 ; v2(158.81,146.51) 158.49,146.51 CV171.2 ; v2(187.66,35.81) 187.56,35.92 R6301.1 ; EC2904.2 88.09,11.7 87.43,12.36 82.91,12.36 v2(81.95,11.39) ; v2(114.61,32.13) 114.61,31.83 114.1,31.32 CD79.2 ; C3021.2 44.12,169.77 43.11,170.77 v2(43.11,171.35) ; v2(107.86,83.15) 107.86,83.54 PC1026.2 ; CC295.2 100.51,66.72 v2(100.78,66.99) ; v2(141.98,160.13) C987.1 C983.1 ; CC225.2 137.5,89.52 137.5,88.85 v2(137,88.35) ; v2(106.58,83.15) 106.58,83.46 PC1182.2 ; 110.8,160.32 PC753.1 ; Q3001.3 62.93,167.47 v2(63.81,168.35) ; v2(183.51,87.5) 183.57,87.44 CE71.2 ; v2(30.14,69.23) 30.44,68.93 C5511.2 30.81,68.48 31.33,69 R5510.2 ; v2(30.35,75.95) 30.56,75.95 31.07,75.44 Q5403.3 ; CARD1.12 v2(21.65,30.52) ; v2(119.97,40.9) 120.2,40.9 120.71,40.4 CD75.2 ; ODD1.21 161.75,87.38 v2(161.75,83.63) ; DA13.1 84.49,5.14 83.98,4.64 v2(83.69,4.64) ; CV120.2 156.71,138.26 ; CC298.2 163.43,72.63 v2(163.41,72.64) 163.76,72.99 CC10.2 ; CD82.2 v2(125.47,17.69) ; v2(157.13,139.57) 157.53,139.17 CV57.2 ; PC790.2 v2(68.13,159.32) ; PC695.1 v2(114.85,147.13) ; CC25.2 v2(145.33,63.14) ; EC2903.2 v2(89.21,9.6) ; PR10.1 v2(133.15,175.26) ; CE72.2 182.68,86.86 CE78.2 v2(182.7,87.5) ; CC253.2 123.39,80.09 v2(123.46,80.03) ; v2(26.68,59.97) 26.67,59.97 C5503.2 26.37,59.03 C5504.2 ; CV60.2 CV56.2 ; v2(158.03,53.15) 157.27,52.39 EC9733.2 ; C349.1 C343.1 143.55,152.39 143.94,152.77 v2(143.94,153.42) ; RC48.2 v2(166.87,50.79) ; 192.79,147.37 192.79,147.76 192.57,147.98 v2(192.57,148.01) ; v2(47.91,15.8) CZ44.2 CZ45.2 ; v2(88.49,15.21) 89.27,15.99 CD80.2 ; CD25.2 v2(148.9,26.29) ; RC375.2 146.09,90.69 v2(146.04,90.74) 145.98,90.8 CC203.2 ; PC128.2 v2(49.61,41.72) ; KB1.31 184.78,118.5 v2(184.61,118.34) ; CC1103.2 167.24,89.09 167.75,88.58 v2(168.07,88.58) ; CV80.2 v2(149.91,138.33) ; EC9716.2 v2(94.21,115.95) ; KB_BL1.5 v2(197.7,120.21) ; C6216.2 v2(146.74,152.27) ; CD17.2 148.9,39.74 v2(149.01,39.85) ; CC256.2 CC175.2 119.28,63.82 v2(119.34,63.75) ; CD26.2 129.66,23.75 130.04,23.37 v2(130.04,23.37) ; v2(129.79,110.38) 129.71,110.31 CZ70.2 ; RC65.2 150.16,79.36 150.41,79.61 v2(150.41,80.72) ; EC9758.2 28.82,18.48 v2(28.5,18.8) ; EC2902.2 v2(89.15,5.89) ; R6517.2 v2(174.61,53.21) ; CD20.2 121.41,25.65 v2(121.15,25.91) ; EC3107.1 v2(40.31,174.64) ; CZ31.2 v2(59.04,80.26) ; CV91.2 v2(180.76,129.81) ; PR738.2 v2(82.71,171.15) ; CV45.2 166.35,165.24 v2(165.8,165.79) ; PWR1.6 v2(201.54,164.72) ; PC213.2 v2(55.68,25.97) ; PD2.1 v2(157.73,174.82)
  VCC w0.203: 14.07,32.74 USB1.11 ; USB1.11 15.75,34.4 ; USB1.11 15.75,33.57 ; USB1.11 14.07,34.4 ; USB1.11 15.75,32.74 ; 148.4,179.77 PBATT1.10 ; PBATT1.10 150.15,177.86 ; PBATT1.10 148.4,177.86 ; PBATT1.10 150.15,179.77 ; PBATT1.10 149.27,177.86 ; 168.65,177.86 PBATT1.9 ; PBATT1.9 170.4,179.77 ; PBATT1.9 168.65,179.77 ; PBATT1.9 169.52,177.86 ; PBATT1.9 170.4,177.86 ; JHDMI.20 3.72,76.8 ; JHDMI.20 0.68,76.8 ; JHDMI.20 3.72,75.24 ; JHDMI.20 0.68,76.02 ; JHDMI.20 2.2,76.8 ; JHDMI.20 2.2,75.24 ; JHDMI.20 3.72,76.02 ; PBATT1.1 153.14,180.51 ; PBATT1.1 152.4,178.79 ; PBATT1.1 151.66,179.03 ; PBATT1.1 152.4,180.75 ; PBATT1.1 153.14,179.03 ; PBATT1.1 151.66,180.51 ; PBATT1.1 151.42,179.77 ; USB1.4 15.45,37.11 ; USB1.4 15.45,35.84 ; USB1.4 15.65,36.47 ; USB1.4 14.18,37.11 ; USB1.4 14.82,37.3 ; USB1.4 14.82,35.64 ; USB1.7 13.95,39.33 ; USB1.7 14.15,39.97 ; USB1.7 13.95,40.6 ; USB1.7 13.32,39.14 ; USB1.7 12.68,40.6 ; USB1.7 13.32,40.8 ; USB1.7 12.68,39.33 ; USB1.7 12.49,39.97 ; 13.6,29.19 CARD1.13 ; CARD1.13 11.47,30.74 ; CARD1.13 15.73,30.74 ; CARD1.13 11.47,29.97 ; CARD1.13 15.73,29.97 ; CARD1.13 15.73,29.19 ; CARD1.13 13.6,30.74 ; CARD1.13 11.47,29.19 ; JCRT.8 14.29,63.83 ; JCRT.8 14.29,64.82 ; JCRT.8 14.42,64.32 ; JCRT.8 13.18,64.32 ; JCRT.8 13.31,64.82 ; JCRT.8 13.31,63.83 ; HCPU1.1 147.02,72.44 ; HCPU1.1 143.06,70.77 ; HCPU1.1 143.68,72.44 ; HCPU1.1 147.64,70.77 ; HCPU1.1 145.35,68.48 ; HCPU1.1 145.35,73.06 ; HCPU1.1 143.68,69.1 ; HCPU1.1 147.02,69.1 ; PBATT1.3 157.14,179.03 ; PBATT1.3 155.66,179.03 ; PBATT1.3 156.4,178.79 ; PBATT1.3 156.4,180.75 ; PBATT1.3 155.66,180.51 ; PBATT1.3 157.14,180.51 ; 9.44,65.26 JHDMI.11 ; JHDMI.11 10.36,66.18 ; JHDMI.11 10.48,65.72 ; JHDMI.11 9.44,66.18 ; JHDMI.11 10.36,65.26 ; JHDMI.11 9.31,65.72 ; HGPU1.1 143.25,150.77 ; HGPU1.1 141.73,150.21 ; HGPU1.1 143.25,146.6 ; HGPU1.1 145.33,148.69 ; HGPU1.1 141.73,147.16 ; HGPU1.1 144.77,147.16 ; HGPU1.1 144.77,150.21 ; HGPU1.1 141.17,148.69 ; 88.66,70.77 HCPU2.1 ; HCPU2.1 89.28,69.1 ; HCPU2.1 93.24,70.77 ; HCPU2.1 90.95,73.06 ; HCPU2.1 92.62,69.1 ; HCPU2.1 89.28,72.44 ; HCPU2.1 92.62,72.44 ; HCPU2.1 90.95,68.48 ; 3.98,75.48 JCRT.16 ; JCRT.16 7.02,76.17 ; JCRT.16 3.98,76.17 ; JCRT.16 7.02,75.48 ; JCRT.16 3.98,76.86 ; JCRT.16 5.5,76.86 ; JCRT.16 5.5,75.48 ; JCRT.16 7.02,76.86 ; 20.65,48.84 H3.1 ; H3.1 20.65,52.7 ; H3.1 19.23,49.35 ; H3.1 18.72,50.77 ; H3.1 19.23,52.19 ; H3.1 22.07,49.35 ; H3.1 22.07,52.19 ; H3.1 22.58,50.77 ; 13.5,75.48 JCRT.17 ; JCRT.17 13.5,76.86 ; JCRT.17 11.98,75.48 ; JCRT.17 15.02,76.86 ; JCRT.17 15.02,76.17 ; JCRT.17 11.98,76.17 ; JCRT.17 11.98,76.86 ; JCRT.17 15.02,75.48 ; H7.1 155.67,59.55 ; H7.1 152.83,62.39 ; H7.1 152.32,60.97 ; H7.1 154.25,59.04 ; H7.1 154.25,62.9 ; H7.1 155.67,62.39 ; H7.1 152.83,59.55 ; H7.1 156.18,60.97 ; 11.45,60.64 JHDMI.2 ; JHDMI.2 11.91,60.76 ; JHDMI.2 12.03,61.22 ; JHDMI.2 11.91,61.68 ; JHDMI.2 10.99,61.68 ; JHDMI.2 10.99,60.76 ; JHDMI.2 10.86,61.22 ; HGPU3.1 202.38,157.16 ; HGPU3.1 198.77,158.69 ; HGPU3.1 200.85,156.6 ; HGPU3.1 200.85,160.77 ; HGPU3.1 202.38,160.21 ; HGPU3.1 199.33,160.21 ; HGPU3.1 199.33,157.16 ; HGPU3.1 202.94,158.69 ; 11.47,4.54 CARD1.14 ; CARD1.14 13.6,4.54 ; CARD1.14 15.73,4.54 ; CARD1.14 11.47,2.99 ; CARD1.14 13.6,2.99 ; CARD1.14 15.73,2.99 ; CARD1.14 11.47,3.77 ; CARD1.14 15.73,3.77 ; USB1.12 6.9,31.29 ; USB1.12 4.34,32.12 ; USB1.12 4.34,31.29 ; USB1.12 5.62,31.29 ; USB1.12 6.9,32.12 ; JCRT.5 14.29,70.54 ; JCRT.5 14.42,70.05 ; JCRT.5 13.18,70.05 ; JCRT.5 13.8,70.67 ; JCRT.5 13.31,70.54 ; JCRT.5 14.29,69.56 ; JCRT.5 13.31,69.56 ; JCRT.6 14.29,59.25 ; JCRT.6 13.8,59.12 ; JCRT.6 13.18,59.74 ; JCRT.6 14.42,59.74 ; JCRT.6 13.31,60.24 ; JCRT.6 13.31,59.25 ; JCRT.6 14.29,60.24 ; JHDMI.22 10.2,55.25 ; JHDMI.22 11.38,55.25 ; JHDMI.22 11.38,53.69 ; JHDMI.22 9.02,55.25 ; JHDMI.22 9.02,53.69 ; JHDMI.22 9.02,54.47 ; JHDMI.22 10.2,53.69 ; JHDMI.22 11.38,54.47 ; HGPU2.1 201.25,116.35 ; HGPU2.1 199.73,115.79 ; HGPU2.1 199.73,112.75 ; HGPU2.1 203.33,114.27 ; HGPU2.1 202.77,112.75 ; HGPU2.1 202.77,115.79 ; HGPU2.1 199.17,114.27 ; HGPU2.1 201.25,112.19 ; JCRT.18 13.5,54.96 ; JCRT.18 11.98,54.27 ; JCRT.18 15.02,54.96 ; JCRT.18 15.02,54.27 ; JCRT.18 11.98,53.58 ; JCRT.18 13.5,53.58 ; JCRT.18 11.98,54.96 ; JCRT.18 15.02,53.58 ; 3.98,53.58 JCRT.19 ; JCRT.19 7.02,54.27 ; JCRT.19 7.02,54.96 ; JCRT.19 5.5,54.96 ; JCRT.19 3.98,54.27 ; JCRT.19 5.5,53.58 ; JCRT.19 7.02,53.58 ; JCRT.19 3.98,54.96 ; 9.44,68.26 JHDMI.17 ; JHDMI.17 9.44,69.18 ; JHDMI.17 9.31,68.72 ; JHDMI.17 10.48,68.72 ; JHDMI.17 10.36,69.18 ; JHDMI.17 10.36,68.26 ; 37.75,162.84 H5.1 ; H5.1 39.68,164.77 ; H5.1 39.17,163.35 ; H5.1 35.82,164.77 ; H5.1 37.75,166.7 ; H5.1 36.33,166.19 ; H5.1 39.17,166.19 ; H5.1 36.33,163.35 ; 9.31,62.72 JHDMI.5 ; JHDMI.5 9.44,62.26 ; JHDMI.5 10.36,62.26 ; JHDMI.5 9.44,63.18 ; JHDMI.5 10.36,63.18 ; JHDMI.5 10.48,62.72 ; 4.34,48.65 USB1.13 ; USB1.13 6.9,48.65 ; USB1.13 6.9,47.82 ; USB1.13 4.34,47.82 ; USB1.13 5.62,48.65 ; 13.18,62.03 JCRT.7 ; JCRT.7 14.42,62.03 ; JCRT.7 14.29,61.54 ; JCRT.7 13.31,62.53 ; JCRT.7 14.29,62.53 ; JCRT.7 13.31,61.54 ; 9.02,75.97 JHDMI.21 ; JHDMI.21 10.2,75.19 ; JHDMI.21 11.38,75.97 ; JHDMI.21 10.2,76.75 ; JHDMI.21 11.38,76.75 ; JHDMI.21 9.02,76.75 ; JHDMI.21 11.38,75.19 ; JHDMI.21 9.02,75.19 ; PBATT1.2 155.14,180.51 ; PBATT1.2 155.14,179.03 ; PBATT1.2 153.66,179.03 ; PBATT1.2 154.4,178.79 ; PBATT1.2 154.4,180.75 ; PBATT1.2 153.66,180.51 ; USB1.10 15.75,47.2 ; USB1.10 14.07,45.54 ; USB1.10 14.07,47.2 ; USB1.10 15.75,46.37 ; USB1.10 15.75,45.54 ; JCRT.10 14.42,68.9 ; JCRT.10 13.31,68.41 ; JCRT.10 14.29,69.4 ; JCRT.10 14.29,68.41 ; JCRT.10 13.31,69.4 ; JCRT.10 13.18,68.9 ; H1.1 144.08,165.77 ; H1.1 140.02,165.77 ; H1.1 140.56,167.26 ; H1.1 142.05,163.74 ; H1.1 143.54,164.28 ; H1.1 142.05,167.8 ; H1.1 143.54,167.26 ; H1.1 140.56,164.28 ; JHDMI.8 11.91,63.76 ; JHDMI.8 10.99,64.68 ; JHDMI.8 12.03,64.22 ; JHDMI.8 11.91,64.68 ; JHDMI.8 10.99,63.76 ; JHDMI.8 10.86,64.22 ; 0.68,54.42 JHDMI.23 ; JHDMI.23 2.2,53.64 ; JHDMI.23 3.72,55.2 ; JHDMI.23 3.72,54.42 ; JHDMI.23 0.68,53.64 ; JHDMI.23 3.72,53.64 ; JHDMI.23 2.2,55.2
  GND w0.203: HGPU1.1 144.77,150.21 ; HGPU1.1 141.17,148.69 ; HGPU1.1 141.73,147.16 ; HGPU1.1 141.73,150.21 ; HGPU1.1 143.25,146.6 ; HGPU1.1 143.25,150.77 ; HGPU1.1 144.77,147.16 ; HGPU1.1 145.33,148.69 ; 145.35,68.48 HCPU1.1 ; HCPU1.1 143.06,70.77 ; HCPU1.1 147.02,72.44 ; HCPU1.1 147.64,70.77 ; HCPU1.1 147.02,69.1 ; HCPU1.1 145.35,73.06 ; HCPU1.1 143.68,72.44 ; HCPU1.1 143.68,69.1 ; 96.65,126.54 H4.1 ; H4.1 95.23,127.05 ; H4.1 94.72,128.47 ; H4.1 96.65,130.4 ; H4.1 98.58,128.47 ; H4.1 98.07,129.89 ; H4.1 98.07,127.05 ; H4.1 95.23,129.89 ; 18.72,50.77 H3.1 ; H3.1 20.65,48.84 ; H3.1 22.07,52.19 ; H3.1 20.65,52.7 ; H3.1 22.07,49.35 ; H3.1 19.23,52.19 ; H3.1 19.23,49.35 ; H3.1 22.58,50.77 ; 0.68,76.8 JHDMI.20 ; JHDMI.20 2.2,75.24 ; JHDMI.20 3.72,75.24 ; JHDMI.20 3.72,76.02 ; JHDMI.20 0.68,76.02 ; JHDMI.20 3.72,76.8 ; JHDMI.20 2.2,76.8 ; PBATT1.1 152.4,180.75 ; PBATT1.1 151.42,179.77 ; PBATT1.1 151.66,179.03 ; PBATT1.1 152.4,178.79 ; PBATT1.1 153.14,179.03 ; PBATT1.1 153.14,180.51 ; PBATT1.1 151.66,180.51 ; JCRT.18 13.5,54.96 ; JCRT.18 11.98,54.96 ; JCRT.18 15.02,54.96 ; JCRT.18 11.98,54.27 ; JCRT.18 11.98,53.58 ; JCRT.18 15.02,53.58 ; JCRT.18 13.5,53.58 ; JCRT.18 15.02,54.27 ; 198.36,54.78 H6.1 ; H6.1 198.36,57.76 ; H6.1 201.88,56.27 ; H6.1 199.85,58.3 ; H6.1 197.82,56.27 ; H6.1 201.34,54.78 ; H6.1 199.85,54.24 ; H6.1 201.34,57.76 ; 9.02,55.25 JHDMI.22 ; JHDMI.22 10.2,55.25 ; JHDMI.22 10.2,53.69 ; JHDMI.22 11.38,53.69 ; JHDMI.22 9.02,53.69 ; JHDMI.22 9.02,54.47 ; JHDMI.22 11.38,54.47 ; JHDMI.22 11.38,55.25 ; JHDMI.2 11.91,60.76 ; JHDMI.2 10.99,60.76 ; JHDMI.2 11.45,60.64 ; JHDMI.2 10.86,61.22 ; JHDMI.2 12.03,61.22 ; JHDMI.2 11.91,61.68 ; JHDMI.2 10.99,61.68 ; JHDMI.21 10.2,76.75 ; JHDMI.21 9.02,76.75 ; JHDMI.21 11.38,75.19 ; JHDMI.21 9.02,75.97 ; JHDMI.21 10.2,75.19 ; JHDMI.21 11.38,75.97 ; JHDMI.21 11.38,76.75 ; JHDMI.21 9.02,75.19 ; HCPU2.1 90.95,73.06 ; HCPU2.1 92.62,69.1 ; HCPU2.1 89.28,72.44 ; HCPU2.1 92.62,72.44 ; HCPU2.1 88.66,70.77 ; HCPU2.1 89.28,69.1 ; HCPU2.1 93.24,70.77 ; HCPU2.1 90.95,68.48 ; 153.66,180.51 PBATT1.2 ; PBATT1.2 153.66,179.03 ; PBATT1.2 155.14,180.51 ; PBATT1.2 155.14,179.03 ; PBATT1.2 154.4,180.75 ; PBATT1.2 154.4,178.79 ; JCRT.5 13.8,70.67 ; JCRT.5 14.29,70.54 ; JCRT.5 14.29,69.56 ; JCRT.5 13.31,69.56 ; JCRT.5 13.31,70.54 ; JCRT.5 13.18,70.05 ; JCRT.5 14.42,70.05 ; USB1.10 15.75,47.2 ; USB1.10 14.07,47.2 ; USB1.10 15.75,45.54 ; USB1.10 15.75,46.37 ; USB1.10 14.07,45.54 ; 36.33,166.19 H5.1 ; H5.1 37.75,166.7 ; H5.1 39.68,164.77 ; H5.1 35.82,164.77 ; H5.1 36.33,163.35 ; H5.1 39.17,163.35 ; H5.1 37.75,162.84 ; H5.1 39.17,166.19 ; 13.31,69.4 JCRT.10 ; JCRT.10 13.18,68.9 ; JCRT.10 14.29,68.41 ; JCRT.10 14.29,69.4 ; JCRT.10 14.42,68.9 ; JCRT.10 13.31,68.41 ; 116.02,105.07 HCPU3.1 ; HCPU3.1 119.71,106.63 ; HCPU3.1 116.59,106.63 ; HCPU3.1 120.28,105.07 ; HCPU3.1 118.15,107.2 ; HCPU3.1 118.15,102.94 ; HCPU3.1 119.71,103.51 ; HCPU3.1 116.59,103.51 ; 168.65,177.86 PBATT1.9 ; PBATT1.9 168.65,179.77 ; PBATT1.9 170.4,177.86 ; PBATT1.9 169.52,177.86 ; PBATT1.9 170.4,179.77 ; H2.1 171.58,12.77 ; H2.1 171.07,14.19 ; H2.1 169.65,14.7 ; H2.1 168.23,14.19 ; H2.1 167.72,12.77 ; H2.1 168.23,11.35 ; H2.1 171.07,11.35 ; H2.1 169.65,10.84 ; JCRT.8 14.29,63.83 ; JCRT.8 13.18,64.32 ; JCRT.8 14.29,64.82 ; JCRT.8 14.42,64.32 ; JCRT.8 13.31,64.82 ; JCRT.8 13.31,63.83 ; USB1.11 15.75,34.4 ; USB1.11 14.07,32.74 ; USB1.11 15.75,33.57 ; USB1.11 14.07,34.4 ; USB1.11 15.75,32.74 ; 9.44,66.18 JHDMI.11 ; JHDMI.11 10.36,65.26 ; JHDMI.11 9.44,65.26 ; JHDMI.11 9.31,65.72 ; JHDMI.11 10.48,65.72 ; JHDMI.11 10.36,66.18 ; JCRT.6 14.29,59.25 ; JCRT.6 14.29,60.24 ; JCRT.6 13.8,59.12 ; JCRT.6 13.18,59.74 ; JCRT.6 14.42,59.74 ; JCRT.6 13.31,60.24 ; JCRT.6 13.31,59.25 ; 11.47,3.77 CARD1.14 ; CARD1.14 11.47,2.99 ; CARD1.14 15.73,4.54 ; CARD1.14 15.73,2.99 ; CARD1.14 13.6,4.54 ; CARD1.14 15.73,3.77 ; CARD1.14 13.6,2.99 ; CARD1.14 11.47,4.54 ; JCRT.7 14.29,61.54 ; JCRT.7 13.31,61.54 ; JCRT.7 14.29,62.53 ; JCRT.7 13.18,62.03 ; JCRT.7 13.31,62.53 ; JCRT.7 14.42,62.03 ; 11.98,75.48 JCRT.17 ; JCRT.17 11.98,76.86 ; JCRT.17 13.5,75.48 ; JCRT.17 13.5,76.86 ; JCRT.17 11.98,76.17 ; JCRT.17 15.02,75.48 ; JCRT.17 15.02,76.86 ; JCRT.17 15.02,76.17 ; 4.34,47.82 USB1.13 ; USB1.13 5.62,48.65 ; USB1.13 6.9,47.82 ; USB1.13 4.34,48.65 ; USB1.13 6.9,48.65 ; HGPU2.1 202.77,115.79 ; HGPU2.1 202.77,112.75 ; HGPU2.1 199.73,112.75 ; HGPU2.1 201.25,112.19 ; HGPU2.1 201.25,116.35 ; HGPU2.1 199.73,115.79 ; HGPU2.1 199.17,114.27 ; HGPU2.1 203.33,114.27 ; 0.68,53.64 JHDMI.23 ; JHDMI.23 0.68,54.42 ; JHDMI.23 3.72,54.42 ; JHDMI.23 2.2,55.2 ; JHDMI.23 3.72,55.2 ; JHDMI.23 3.72,53.64 ; JHDMI.23 2.2,53.64 ; 3.98,53.58 JCRT.19 ; JCRT.19 7.02,53.58 ; JCRT.19 7.02,54.96 ; JCRT.19 5.5,54.96 ; JCRT.19 3.98,54.96 ; JCRT.19 3.98,54.27 ; JCRT.19 7.02,54.27 ; JCRT.19 5.5,53.58 ; JHDMI.17 10.48,68.72 ; JHDMI.17 9.44,69.18 ; JHDMI.17 9.44,68.26 ; JHDMI.17 9.31,68.72 ; JHDMI.17 10.36,68.26 ; JHDMI.17 10.36,69.18 ; USB1.7 13.95,40.6 ; USB1.7 13.32,40.8 ; USB1.7 12.49,39.97 ; USB1.7 13.95,39.33 ; USB1.7 13.32,39.14 ; USB1.7 12.68,40.6 ; USB1.7 12.68,39.33 ; USB1.7 14.15,39.97 ; 149.27,177.86 PBATT1.10 ; PBATT1.10 150.15,177.86 ; PBATT1.10 150.15,179.77 ; PBATT1.10 148.4,179.77 ; PBATT1.10 148.4,177.86 ; 3.98,75.48 JCRT.16 ; JCRT.16 5.5,75.48 ; JCRT.16 7.02,76.86 ; JCRT.16 5.5,76.86 ; JCRT.16 3.98,76.17 ; JCRT.16 7.02,75.48 ; JCRT.16 3.98,76.86 ; JCRT.16 7.02,76.17 ; 154.25,59.04 H7.1 ; H7.1 155.67,59.55 ; H7.1 156.18,60.97 ; H7.1 152.83,62.39 ; H7.1 155.67,62.39 ; H7.1 152.32,60.97 ; H7.1 152.83,59.55 ; H7.1 154.25,62.9 ; USB1.12 6.9,31.29 ; USB1.12 4.34,32.12 ; USB1.12 6.9,32.12 ; USB1.12 4.34,31.29 ; USB1.12 5.62,31.29 ; 14.18,37.11 USB1.4 ; USB1.4 15.45,37.11 ; USB1.4 15.65,36.47 ; USB1.4 14.82,35.64 ; USB1.4 14.82,37.3 ; USB1.4 15.45,35.84 ; 9.44,63.18 JHDMI.5 ; JHDMI.5 9.31,62.72 ; JHDMI.5 10.36,62.26 ; JHDMI.5 9.44,62.26 ; JHDMI.5 10.48,62.72 ; JHDMI.5 10.36,63.18 ; 10.99,63.76 JHDMI.8 ; JHDMI.8 10.86,64.22 ; JHDMI.8 11.91,64.68 ; JHDMI.8 12.03,64.22 ; JHDMI.8 10.99,64.68 ; JHDMI.8 11.91,63.76 ; 11.47,29.97 CARD1.13 ; CARD1.13 13.6,30.74 ; CARD1.13 15.73,29.97 ; CARD1.13 11.47,30.74 ; CARD1.13 15.73,29.19 ; CARD1.13 11.47,29.19 ; CARD1.13 15.73,30.74 ; CARD1.13 13.6,29.19 ; H1.1 143.54,164.28 ; H1.1 143.54,167.26 ; H1.1 140.02,165.77 ; H1.1 140.56,164.28 ; H1.1 140.56,167.26 ; H1.1 142.05,167.8 ; H1.1 142.05,163.74 ; H1.1 144.08,165.77 ; HGPU3.1 202.94,158.69 ; HGPU3.1 202.38,157.16 ; HGPU3.1 199.33,160.21 ; HGPU3.1 200.85,156.6 ; HGPU3.1 198.77,158.69 ; HGPU3.1 199.33,157.16 ; HGPU3.1 200.85,160.77 ; HGPU3.1 202.38,160.21 ; PBATT1.3 157.14,180.51 ; PBATT1.3 157.14,179.03 ; PBATT1.3 156.4,180.75 ; PBATT1.3 155.66,180.51 ; PBATT1.3 156.4,178.79 ; PBATT1.3 155.66,179.03
  BOTTOM w0.076: v2(110.79,75.69) UC1.BA49
  BOTTOM w0.102: UV1.F2 175.59,133.08 175.99,132.68 v2(176.05,132.68) ; UV1.B16 169.87,141.6 170.23,141.6 170.36,141.72 170.88,141.72 v2(170.89,141.72)
  BOTTOM w0.152: v2(99.57,73.3) 99.66,73.3 100.25,73.89 UC1.BB67 ; UV17.G8 175.53,162.17 UV18.G1
  BOTTOM w0.178: v2(104.57,73.47) 104.61,73.51 UC1.BB60 ; UC1.BB30 121.96,73.73 121.96,73.34 v2(122.09,73.21) ; v2(97.07,80.16) 97.13,80.21 97.88,80.21 UC1.AM71 ; v2(117.02,73.4) 116.99,73.42 116.99,74.37 UC1.BB38 ; UC1.BB26 124.31,73.98 124.31,73.47 v2(124.37,73.42) ; v2(97.14,77.89) 97.15,77.89 97.15,77.86 97.24,77.86 UC1.AT71 ; UC1.BB34 119.33,72.8 v2(119.36,72.77) ; v2(97.15,83.03) 97.31,82.87 97.67,82.87 UC1.AG71 ; UC1.BB43 114.38,73.45 v2(114.35,73.43) ; UC1.BB64 102.26,73.85 102.26,73.47 v2(102.26,73.47) ; v2(107.22,73.5) 107.21,73.5 107.21,73.99 UC1.BB55
  BOTTOM w0.203: UC1.D14 130.66,94.94 v2(130.47,95.13) 130.47,95.52 UC1.B14 ; UC1.J28 121.63,92.93 v2(121.57,92.99) ; UC1.H71 97.21,92.47 v2(96.9,92.78) ; v2(169.43,160.79) 169.43,160.86 169.89,161.32 169.89,162.16 UV17.B3 ; v2(139.28,76.56) 139.26,76.54 UC1.AV1 ; UC1.AM68 100.11,79.83 100.14,79.8 100.14,79.5 100.11,79.47 UC1.AP68 100.11,78.6 100.14,78.57 100.14,78.28 100.11,78.25 UC1.AT68 100.11,77.44 100.16,77.27 100.16,77.09 100.11,77.04 100.11,76.67 UC1.AV68 ; UC1.AM68 100.3,80.31 100.56,80.05 100.56,79.98 ; UC1.AM68 100.11,80.7 100.2,80.79 100.2,81.06 99.79,81.47 UC1.AK68 ; UC1.P17 129.07,88.73 129.22,88.58 129.22,88.07 UC1.T17 ; v2(100.6,76.2) 100.15,76.66 UC1.AV68 ; v2(100.6,76.2) UC1.AY66 UC1.BA66 ; v2(100.6,76.2) 100.79,76.2 UC1.AW66 101.27,76.68 101.73,76.68 102.08,76.33 UC1.AW64 102.64,76.33 102.67,76.36 102.97,76.36 103,76.33 UC1.AW62 103.87,76.33 103.9,76.36 104.19,76.36 104.22,76.33 UC1.AW60 105.09,76.33 105.13,76.36 105.42,76.36 105.45,76.33 UC1.AW57 106.37,76.33 106.4,76.36 106.69,76.36 106.73,76.33 UC1.AW55 107.6,76.33 107.63,76.36 107.92,76.36 107.95,76.33 UC1.AW53 ; v2(139.42,83.24) 138.83,83.24 138.82,83.23 UC1.AF1 ; UC1.AW10 133.39,76.33 133.42,76.36 133.71,76.36 133.74,76.33 UC1.AW8 134.54,76.33 134.57,76.36 134.86,76.36 134.89,76.33 UC1.AW6 ; 128.61,87.47 128.61,87.67 UC1.T18 ; UC1.AW12 132.04,76.33 132.54,76.84 132.66,76.84 v2(132.66,76.84) ; UV1.AH32 147.9,135.62 147.66,135.86 146.9,135.86 v2(146.65,136.12) ; UC1.E71 97.73,94.27 97.42,94.58 v2(97.02,94.58) ; UC1.Y20 127.2,86.11 127.63,86.11 UC1.Y19 ; UC1.AH63 103.14,82.41 103.14,83.12 UC1.AF63 ; UC1.BA1 138.38,74.66 137.97,74.77 UC1.BA2 ; UC1.AW43 114.48,76.33 113.99,76.33 113.96,76.36 113.93,76.36 113.92,76.37 113.92,76.36 113.86,76.36 113.84,76.38 113.69,76.38 113.64,76.33 UC1.AW45 112.77,76.33 112.74,76.36 112.44,76.36 112.41,76.33 UC1.AW47 111.6,76.33 111.57,76.36 111.28,76.36 111.25,76.33 UC1.AW49 ; UC1.AV68 99.83,76.66 v2(99.64,76.47) ; UV1.B10 173.3,138.17 173.99,138.86 v2(174.13,138.86) ; UC1.K61 103.32,91.73 UC1.K63 ; RC141.2 118.29,99.37 118.49,99.57 120.4,99.57 123.19,102.35 123.43,102.35 125.89,104.81 v2(125.89,105.12) ; UC1.AD20 126.98,84.65 126.55,84.65 UC1.AD21 ; v2(123.12,103.76) 123.04,103.76 119.95,100.67 117.78,100.67 116.78,99.67 116.78,97.68 116.12,97.02 116.12,96.06 115.79,95.73 UC1.B39 ; UC1.J25 123.46,91.46 v2(123.28,91.28) ; UC1.AL64 102.33,80.47 101.79,80.47 UC1.AL65 101.68,80.47 101.14,80.47 UC1.AL66 ; UC1.F33 119.16,93.5 118.77,93.5 118.68,93.41 118.64,93.41 118.54,93.31 UC1.F35 ; UC1.B34 118.27,95.83 118.14,95.96 118.12,95.96 117.94,96.14 117.94,97.02 v2(117.86,97.1) 117.86,97.88 v2(118.29,98.31) ; v2(117.97,92.82) UC1.J35 ; UV1.AF32 149.19,136.84 v2(148.82,137.21) ; v2(116.14,76.84) 116.65,76.33 UC1.AW38 117.37,76.33 117.4,76.36 117.69,76.36 117.72,76.33 UC1.AW36 118.59,76.33 118.62,76.36 118.92,76.36 118.95,76.33 UC1.AW34 119.43,76.46 v2(119.8,76.82) 120.29,76.33 UC1.AW32 121.12,76.33 121.15,76.36 121.44,76.36 121.48,76.33 UC1.AW30 122.35,76.33 122.38,76.36 122.67,76.36 122.7,76.33 UC1.AW28 123.57,76.33 123.6,76.36 123.9,76.36 123.93,76.33 UC1.AW26 124.8,76.33 124.83,76.36 125.13,76.36 125.16,76.33 UC1.AW23 126.13,76.33 126.16,76.36 126.45,76.36 126.48,76.33 UC1.AW21 127.27,76.33 127.3,76.36 127.6,76.36 127.63,76.33 UC1.AW18 128.55,76.33 128.58,76.36 128.87,76.36 128.9,76.33 UC1.AW16 ; v2(138.64,93.84) UC1.F1
  BOTTOM w0.229: v2(173.84,130.04) 173.84,130.15 173.81,130.19 173.81,130.21 173.23,130.78 UV1.K2
  BOTTOM w0.254: v2(168.1,163.36) 168.16,163.3 UV18.B9 ; UC1.L20 127.09,90.35 126.64,89.91 126.64,89.78 UC1.N21 126.1,89.24 v2(126.1,89.15) ; v2(107.91,81.59) UC1.AL55 ; UC1.D26 123.27,94.73 UC1.D25 ; v2(128.03,78.74) 128.46,79.1 UC1.AP18 ; UC1.D66 100.92,94.69 v2(100.92,95.19) 100.92,95.71 UC1.B66 ; UV17.E1 v2(170.44,164.44) UV18.E8 ; UV20.B9 181.84,150.2 v2(181.66,150.2) ; UC1.D58 v2(105.88,95.21) UC1.B58 ; UC1.AU38 v2(116.14,76.84) ; 128.71,83.28 UC1.AF17 ; 128.71,83.28 129.04,82.96 UC1.AG17 ; 128.71,83.28 UC1.AG18 128.39,82.86 UC1.AG19 ; UC1.AR63 102.8,78.56 102.61,78.56 v2(102.43,78.74) UC1.AP63 ; UC1.BA45 v2(113.2,75.82) UC1.AW45 ; UC1.J38 116.14,92.91 v2(116.12,92.94) ; v2(186.15,153.17) 186.21,153.24 UV20.J8 ; UC1.F27 122.87,93.45 122.22,93.45 UC1.F28 121.91,93.31 v2(121.59,93.62) ; UC1.AG19 127.63,82.98 127.2,82.98 UC1.AG20 127.09,82.8 126.76,82.47 126.76,82.39 ; UC1.AG19 127.74,82.79 v2(127.41,82.47) ; UC1.AF15 130.34,83.68 ; 130.34,83.68 129.95,83.29 129.95,83.12 UC1.AG16 UC1.AG17 ; 130.34,83.68 130.34,83.66 131.18,82.82 UC1.AH13 131.18,82.24 130.93,81.99 130.37,81.99 UC1.AJ15 ; UC1.BB18 128.04,74.36 128.04,73.41 v2(127.8,73.18) ; v2(99.04,94.2) 99.18,94.34 UC1.D69 UC1.F68 ; CC199.2 124.96,100.14 v2(124.71,100.39) ; UC1.F8 134.32,92.96 v2(134.42,92.96) 134.88,92.71 UC1.G6 ; UC1.F8 133.76,93.31 133.57,93.5 v2(133.52,93.5) 133.52,94.08 133.14,94.46 UC1.D10 ; UC1.F8 134.29,93.63 v2(134.48,93.63) 134.56,93.63 UC1.E6 ; v2(101.4,87.33) UC1.U66 ; v2(103.34,94.18) 103.4,94.24 UC1.D62 UC1.B62 ; UC1.N65 101.74,89.51 v2(101.4,89.17) ; v2(187.32,155.48) 187.34,155.5 UV20.M9 ; v2(132.67,80.83) 132.48,81.01 UC1.AK11 ; v2(132.67,80.83) 131.73,80.83 131.65,80.92 v2(131.64,80.92) 131.64,80.92 131.23,80.5 UC1.AM13 ; v2(132.67,80.83) 133.8,80.83 133.98,80.66 UC1.AM8 ; UC1.L2 137.2,91.18 v2(137,91.39) 136.8,91.18 UC1.L4 ; UC1.AR35 v2(117.97,78.11) UC1.AT35 ; UC1.AK22 125.95,81.15 126.4,81.15 UC1.AK21 126.66,80.96 UC1.AM21 126.66,80.36 126.27,80.01 v2(126.2,80.01) ; v2(112.49,80.03) UC1.AM45 ; v2(100.11,89.17) 100.11,89.23 99.79,89.55 UC1.N68 ; v2(186.16,144.19) UV19.A9 ; UC1.F40 115.75,93.31 v2(116.12,92.94) ; UC1.BA36 v2(118.16,75.82) UC1.AW36 ; UV18.E2 174.4,160.48 v2(174.4,160.48) UV17.D8 ; UV19.F9 v2(188.99,148.15) UV19.G8 ; UC1.BB6 UC1.BA6 v2(135.32,75.82) 135.28,75.87 UC1.AW6 ; v2(100.76,87.33) UC1.U67 ; UC1.F22 125.68,93.31 125.31,92.94 125.24,92.94 ; UV18.M9 174.4,169.53 v2(174.4,169.53) ; v2(100.29,92.91) UC1.G66 ; v2(109.74,81.59) UC1.AL52 ; UC1.W9 133.76,86.57 133.26,87.07 v2(132.77,87.07) 132.77,87.22 133.13,87.58 UC1.U10 ; UC1.AL2 137.18,80.58 v2(137,80.4) 136.82,80.58 UC1.AL4 UC1.AJ4 ; v2(129.36,86.64) UC1.V16 130.17,87.54 130.17,87.72 UC1.T15 UC1.R13 130.71,89.18 v2(130.71,89.2) 131.18,89.67 UC1.N13 ; v2(129.36,86.64) UC1.Y17 ; v2(129.36,86.64) 129.04,86.97 UC1.V17 ; UC1.B30 v2(120.75,95.21) UC1.D30 ; UC1.B39 115.61,95.53 v2(115.61,95.21) 115.61,94.87 UC1.D39 ; v2(105.17,78.74) UC1.AP58 ; UC1.BA71 UC1.BB70 97.26,74.06 v2(97.06,74.25) ; UC1.G5 135.61,92.66 v2(135.31,92.35) ; v2(119.8,79.38) UC1.AN32 ; UC1.T4 136.69,88.35 v2(137,88.35) 137.31,88.35 UC1.T2 ; UC1.AL45 113.37,80.06 v2(113.38,80.05) UC1.AM43 ; UC1.AD8 134.72,84.72 v2(134.72,85.05) UC1.AB8 ; UC1.P19 128.08,88.31 UC1.T18 128.39,87.84 v2(128.03,87.49) ; UC1.D10 UC1.D11 132.15,94.42 UC1.E11 132.55,93.55 132.55,93.17 UC1.G10 ; UC1.D10 UC1.B10 ; v2(180.37,123.61) 180.07,123.61 179.71,123.98 RP34.2 ; UC1.G22 125.68,92.6 125.68,91.79 UC1.K22 ; UC1.G22 125.52,92.66 125.24,92.94 ; UC1.G22 126.04,92.36 v2(126.2,92.36) ; UC1.F42 114.45,92.99 114.37,92.99 v2(114.32,92.94) 114.32,92.2 ; UC1.AU32 v2(119.8,76.82) ; UC1.C25 UC1.D25 ; UC1.D25 123.96,94.73 v2(124.33,94.36) ; v2(106.05,77.51) 106.14,77.51 UC1.AT56 ; UC1.AT58 v2(105.17,78.11) UC1.AR58 ; v2(157.77,146.02) 157.77,146 157.96,145.81 UV1.K32 ; UC1.AL66 101.09,80.5 100.56,79.98 v2(100.56,79.91) ; UC1.L11 132.48,90.69 132.82,90.22 v2(132.81,90.13) 132.81,90.13 132.81,90.08 133.12,89.77 UC1.N10 ; UC1.AN30 v2(121.63,79.38) UC1.AN28 ; UC1.AF63 103.04,83.32 102.46,84.14 UC1.AE64 ; RC366.2 139.45,83.26 v2(139.42,83.24) ; v2(116.12,92.94) 116.49,93.31 UC1.F38 ; UC1.B48 110.84,95.41 v2(111.05,95.2) 110.84,94.99 UC1.D48 ; UC1.AN37 v2(117.06,79.38) UC1.AN38 ; UC1.AH64 v2(102.69,81.85) ; v2(102.69,81.85) UC1.AH63 ; v2(102.69,81.85) UC1.AK63 UC1.AM61 103.89,80.51 104.62,80.51 UC1.AM60 ; v2(155.16,143.03) 155.68,143.54 UV1.P32 ; UV1.AM1 v2(163.22,119.22) ; UC1.AN20 127.57,79.74 127.16,79.38 v2(127.12,79.38) 127.37,79.12 UC1.AP20 ; UC1.J11 131.93,91.57 131.71,91.57 v2(131.71,91.57) 131.71,91.57 131.44,91.57 UC1.J13 ; UC1.K66 v2(101.39,91.02) UC1.K65 ; UC1.AW51 109.95,76.33 110.01,76.39 110.32,76.39 110.38,76.33 UC1.AW49 ; UC1.P20 v2(127.41,89.17) UC1.N19 128.07,89.99 UC1.L18 128.53,90.26 128.89,90.26 UC1.L17 ; 126.76,82.39 126.44,82.71 UC1.AG21 126.73,83.16 v2(126.73,83.28) ; 126.76,82.39 127.09,82.06 UC1.AJ20 ; UV19.E1 v2(183.33,151.54) UV19.D1 ; v2(181.18,166.12) 181.19,166.12 UV18.T1 ; v2(179.44,164.47) 179.38,164.53 179.02,164.53 UV18.M1 ; UC1.AT42 v2(114.32,78.11) UC1.AR42 ; v2(120.72,81.55) UC1.AL32 ; UC1.J32 119.8,92.89 v2(119.71,92.97) ; UV1.Y32 152.19,140.55 152.19,141.65 v2(152.74,142.21) ; 127.6,76.36 127.57,76.39 UC1.AU20 v2(127.12,77.47) UC1.AT20 ; v2(106.09,81.65) UC1.AL58 ; 118.77,93.5 118.83,93.55 118.83,94.13 118.27,94.69 UC1.D34 118.12,94.85 v2(118.12,95.21) 118.12,95.56 UC1.B34 ; v2(106.09,94.18) UC1.E56 ; v2(173.35,132.84) 173.35,133.1 173.08,133.36 UV1.H6 ; UC1.V18 128.61,87.28 128.61,87.47 UC1.T17 ; v2(117.97,79.38) UC1.AN35 ; UC1.U63 v2(102.73,87.33) UC1.U64 ; v2(160.01,144.65) 160.08,144.65 160.1,144.68 UV1.J27 ; UC1.AN63 102.77,79.68 102.63,79.53 102.61,79.53 v2(102.43,79.38) ; v2(102.33,92.91) UC1.G63 ; UC1.AR15 129.88,78.12 129.8,78.13 v2(129.78,78.12) 129.78,78.12 129.75,78.12 UC1.AR16 ; UV1.M6 170.69,131.1 171.02,130.76 v2(171.02,130.69) ; v2(126.2,94.24) 126.22,94.18 UC1.E21 ; v2(105.17,79.38) UC1.AN58 ; UV1.R27 157.23,141.4 157.23,141.96 157.68,142.41 UV1.N27 ; v2(128.74,89.16) 128.75,89.16 128.74,89.11 UC1.P17 ; v2(168.92,131.04) 168.92,131.06 169.56,130.42 UV1.P6 ; UC1.E18 128.02,94.19 v2(128.02,94.21) ; v2(186.73,144.75) UV20.B1 ; UC1.BA10 v2(132.9,75.76) UC1.AW10 132.9,76.6 v2(132.66,76.84) 132.99,77.17 UC1.AU10 ; UC1.BA57 v2(105.91,75.82) UC1.AW57 ; v2(124.37,78.74) UC1.AP23 UC1.AN23 ; UC1.B44 v2(113.31,95.21) UC1.D44 113.01,94.69 112.97,94.73 UC1.D45 ; UC1.AW62 v2(103.43,75.82) UC1.BA62 ; UC1.BA28 v2(123.14,75.82) UC1.AW28 ; UV1.C1 v2(176.91,134.49) UV1.A3 ; UC1.B18 v2(128.18,95.18) UC1.D18 ; v2(192.74,150.62) UV20.M1 ; v2(101.34,85.5) UC1.AA65 ; UC1.AT23 v2(125.29,78.11) UC1.AR23 ; v2(131.21,86.08) 131.18,86.1 UC1.W13 ; UC1.W6 135.74,86.51 v2(135.96,86.14) 136.21,85.88 UC1.AA4 UC1.AA2 ; v2(97.31,75.16) 97.83,75.16 UC1.AY71 ; v2(98.81,87.34) UC1.U70 ; v2(193.52,152.67) UV20.P1 ; 114.32,92.2 UC1.J42 ; 114.32,92.2 UC1.G43 113.56,92.96 v2(113.32,92.96) 113.02,92.66 UC1.G45 112.76,92.66 v2(112.5,92.92) ; UC1.F13 130.91,93.63 v2(130.8,93.63) 130.68,93.63 UC1.E15 ; UV17.A9 172.68,158.21 v2(172.29,157.82) ; UC1.E50 109.86,94.3 v2(109.66,94.3) ; UV20.T1 194.65,152.67 v2(194.65,152.67) ; UC1.C5 135.86,95.38 135.71,95.24 v2(135.43,95.24) 135.43,94.86 UC1.D6 ; U5602.5 190.51,120.82 v2(190.24,121.09) ; UV20.E8 v2(184.47,150.41) ; UV20.T9 v2(190.12,158.33) ; UC1.BA1 v2(139.04,74.52) ; UC1.G52 109.2,92.66 108.9,92.96 108.9,93.44 UC1.E53 108.37,94 108.32,94.04 108.32,94.55 108.36,94.59 UC1.D53 108.28,94.77 108.28,95.14 v2(108.2,95.21) 108.2,95.55 UC1.B53 ; v2(180.08,166.15) 180.06,166.12 UV18.P1 ; v2(129.86,80.65) UC1.AK16 ; v2(114.32,79.38) UC1.AN42 ; v2(129.86,77.44) 130.13,77.17 UC1.AU15 ; v2(129.84,92.28) 130.06,92.28 130.32,92.02 UC1.H15 130.32,91.88 UC1.K16 129.47,91.03 129.47,90.68 129.69,90.46 UC1.L16 ; UV1.AM32 146.55,134.49 v2(146.14,134.08) ; UV20.J2 190.12,149.29 v2(190.12,149.28) ; UC1.AH6 135.62,82.3 135.2,81.88 134.76,81.88 v2(134.72,81.84) 134.69,81.84 134.43,81.59 UC1.AK8 ; v2(133.5,78.27) 133.78,78.27 UC1.AR8 ; v2(97.26,96.55) 97.58,96.22 UC1.B71 UC1.A70 ; 149.19,134.49 UV1.AG27 150.3,134.47 150.3,133.91 v2(150.27,133.89) ; UC1.AF10 132.82,83.69 v2(132.82,83.98) ; UC1.E46 111.8,93.96 v2(111.58,94.18) 111.51,94.25 UC1.D47 ; v2(115.23,79.38) UC1.AN40 ; UC1.AR11 132.82,79.14 132.82,79.15 UC1.AP10 133.18,79.12 133.45,78.86 v2(133.46,78.86) ; UC1.F23 124.87,93.31 125.24,92.94 ; UC1.R6 135.74,89.06 v2(136.03,89.35) 135.74,89.65 UC1.N6 ; UC1.AT63 103.01,77.82 103.29,78.1 103.32,78.1 v2(103.34,78.13) ; v2(104.26,92.91) UC1.G60 ; v2(136.52,97.05) 136.52,97 UC1.A5 ; UC1.AD62 103.67,84.43 v2(103.98,84.43) ; UC1.AG17 129.04,82.61 128.5,82.07 128.43,82.07 UC1.AJ18 128.38,82.03 128.28,81.92 128.28,81.3 UC1.AK18 ; v2(100.8,90.96) 100.8,90.95 UC1.K67 UC1.K68 UC1.K70 UC1.K71 ; v2(169.28,164.45) 169.29,164.44 UV17.D1 ; UC1.BA18 v2(128.06,75.68) UC1.AW18 ; UC1.J8 134.27,91.36 v2(134.43,91.19) UC1.L8 ; UV18.G9 171.57,166.61 v2(171.51,166.67) ; UC1.F33 119.38,93.31 v2(119.71,92.97) ; UC1.AR53 107.96,78.14 107.92,78.15 107.92,78.21 107.93,78.21 v2(107.93,78.21) ; UC1.BA32 120.63,75.56 v2(120.49,75.71) 120.63,75.85 UC1.AW32 ; UC1.AD21 UC1.AB21 126.44,85.47 v2(126.11,85.8) 126.11,85.89 UC1.Y21 UC1.Y20 ; UC1.AR28 v2(121.63,78.11) UC1.AT28 ; v2(127.12,78.11) UC1.AR20 ; UC1.AL48 v2(111.57,80.03) UC1.AM46 ; UV18.B1 173.75,158.3 v2(173.86,158.3) ; UC1.AD19 127.53,84.33 127.29,84.33 UC1.AD20 ; UC1.AT2 137.18,77.93 v2(137.01,77.75) 137,77.75 136.82,77.93 UC1.AT4 ; v2(123.46,80.03) UC1.AM25 ; UV19.B3 183.32,148.7 v2(183.32,148.14) ; UC1.AR55 107.43,78.48 107.01,78.14 v2(107.01,78.14) ; UC1.AK69 99.12,81.54 99.3,81.72 99.61,81.72 UC1.AK68 99.87,81.54 v2(100.19,81.86) 100.19,82.06 UC1.AH67 ; UC1.AB16 v2(130.03,85.8) UC1.AB15 ; v2(176,171.23) 176.01,171.23 UV18.T9 ; UC1.P21 UC1.T21 126.76,87.57 126.76,87.54 v2(126.73,87.5) ; UC1.F4 136.98,93.84 v2(137,93.82) 137.01,93.84 UC1.F2 ; UC1.AP42 v2(114.32,78.74) UC1.AR43 ; v2(128.06,92.28) 128.49,92.03 UC1.H18 UC1.K18 ; UC1.AF2 137.18,83.23 v2(137,83.05) 136.82,83.23 UC1.AF4 ; UC1.F35 118.21,93.31 v2(117.88,93.64) 117.55,93.31 UC1.F37 117.33,93.5 v2(117.07,93.5) ; v2(156.06,144.32) 156.42,144.68 UV1.M32 ; UC1.AR46 112.35,78.8 v2(112.49,78.8) 112.62,78.8 UC1.AR45 ; UC1.F32 120.05,93.31 v2(119.71,92.97) ; v2(117.06,81.61) UC1.AL38 ; v2(118.89,79.38) UC1.AN33 ; v2(99.49,87.33) UC1.U69 ; UV1.AB24 UV1.AC24 UV1.AD25 152.69,135.06 152.65,135.1 152.52,135.1 152,135.62 UV1.AE27 ; UC1.AW23 v2(125.62,75.82) UC1.BA23 ; UC1.AV71 UC1.AV70 UC1.AV69 v2(99.64,76.47) ; v2(116.14,78.74) UC1.AP38 ; UC1.BA53 v2(108.39,75.82) UC1.AW53 ; v2(173.27,167.26) UV18.J8 ; v2(100.13,85.48) UC1.AA68 ; UC1.AD13 131.54,83.98 131.61,83.91 v2(131.61,83.94) ; v2(176.4,160.84) 175.74,160.84 UV17.F9 ; UC1.AY3 UC1.BA2 ; v2(138.8,96.14) 138.8,96.06 UC1.C1 ; 94.27,104.98 AFTP6235.1 ; v2(189.56,147.58) UV20.G1 ; v2(122.54,81.61) UC1.AK27 UC1.AL28 UC1.AM27 ; v2(108.83,78.2) 108.93,78.2 109.2,78.47 UC1.AR52 109.55,78.21 v2(109.74,78.21) 109.94,78.21 UC1.AR50 110.53,78.15 v2(110.66,78.15) 110.67,78.15 110.67,78.12 UC1.AR48 ; UV20.E2 v2(187.86,147.01) UV19.D8 ; v2(153.32,138.23) 153.67,137.89 UV1.AA27 ; UC1.B22 125.68,95.69 v2(125.68,95.2) 125.68,94.72 UC1.D22 ; UC1.AR5 135.41,78.87 v2(135.38,78.87) ; v2(118.89,81.61) UC1.AL35 ; UC1.AW41 v2(115.68,75.82) UC1.BA41 ; v2(117.97,78.74) UC1.AP35 ; UV1.T32 154.85,142.45 154.54,142.76 v2(154.54,143.23) ; v2(184.47,152.67) UV20.G9 ; UV18.G1 176.22,161.49 v2(176.67,161.49) ; v2(110.66,92.91) UC1.G48 ; v2(105.17,92.91) UC1.G58 ; v2(121.63,78.74) UC1.AP28 ; v2(189.56,156.63) UV20.P9 ; UC1.AB18 128.72,84.96 129.27,84.96 UC1.AD16 v2(129.38,84.12) ; v2(176.1,170.09) UV18.P9 ; UC1.AP70 v2(99.5,79.04) UC1.AP68 ; v2(119.8,78.74) UC1.AP32 ; v2(107,80.03) UC1.AM55 ; UC1.K64 v2(102.69,91.02) UC1.K63 ; v2(101.31,94.18) UC1.E65 ; v2(176.67,162.7) 176.66,162.71 UV18.J2 ; UC1.A67 100.25,96.86 99.8,97.31 v2(99.8,97.37) ; v2(107,92.91) UC1.G55
  BOTTOM w0.3: UV1.AH10 159.37,124.66 v2(159.19,124.84) 158.81,125.23 UV1.AG12 ; UV1.AD32 149.91,138.3 v2(149.91,138.33) ; v2(152.74,142.21) 153.67,141.28 UV1.V32
  BOTTOM w0.305: UV1.AC26 153.55,136.19 153.57,136.21 153.73,136.21 153.73,136.27 v2(153.66,136.27) ; CV187.2 178.06,159.88 v2(177.66,160.28) ; UV1.A30 162.77,149.3 v2(163.14,149.67) ; JDIMM1.176 123.87,29.65 124.16,29.36 124.16,28.9 123.76,28.51 v2(123.54,28.51) 123.37,28.51 122.87,29 JDIMM1.172 ; v2(108.72,26.57) 109.42,26.57 109.72,26.26 JDIMM2.93 ; v2(175.83,136.51) 175.5,136.17 UV1.B6 ; JDIMM1.72 95.87,29.85 95.55,29.53 v2(95.43,29.53) 95.37,29.59 95.24,29.59 94.87,29.95 JDIMM1.68 ; JDIMM1.197 129.12,39.96 129.02,40.06 129.02,40.5 129.38,40.85 v2(129.58,40.85) 129.92,40.85 130.12,40.65 JDIMM1.201 ; JDIMM2.40 96.48,15.51 96.78,15.21 v2(96.99,15.21) 97.19,15.21 97.48,15.49 JDIMM2.44 ; JDIMM1.218 134.37,29.65 134.25,29.53 133.94,29.53 v2(133.8,29.39) 133.37,29.82 JDIMM1.214 ; v2(164.66,142.31) 164.66,142.21 164.89,141.99 UV1.H20 ; v2(111.69,26.1) 111.53,26.1 111.22,25.79 JDIMM2.99 ; JDIMM1.1 78.12,39.9 v2(78.42,40.2) 78.99,40.2 79.12,40.06 JDIMM1.5 ; JDIMM1.210 132.37,29.94 v2(131.77,29.34) 131.37,29.74 131.37,30.79 ; v2(150.97,135.62) UV1.AE27 ; v2(172.37,131.77) 172.33,131.81 172.33,131.89 171.99,132.23 UV1.K6 ; UV1.F6 174.55,134.49 v2(174.62,134.56) ; UV1.AB32 151.45,139.53 v2(151.31,139.67) ; JDIMM2.51 99.22,26.08 99.83,26.68 100.65,26.68 ; v2(120.83,28.19) 121.09,28.19 121.87,28.98 JDIMM1.168 ; UV1.F24 163.9,144.86 v2(164.15,145.11) ; JDIMM2.189 135.72,25.7 136.03,26 v2(136.21,26) 136.79,26 ; JDIMM2.36 v2(95.48,15.21) ; 83.62,40.39 JDIMM1.23 ; 83.62,40.39 83.56,40.45 82.99,40.45 82.62,40.09 JDIMM1.19 ; 83.62,40.39 84.89,41.66 v2(85.15,41.66) ; JDIMM2.14 89.97,15.51 90.28,15.21 v2(90.49,15.21) 90.69,15.21 90.97,15.49 JDIMM2.18 ; JDIMM1.90 100.37,29.31 100.4,29.29 v2(100.68,29.29) 101.18,29.29 101.37,29.48 JDIMM1.94 ; UV1.AB6 165.48,125.44 165.49,125.45 v2(165.56,125.45) ; v2(135.18,40.83) 134.68,40.83 134.12,40.28 ; JDIMM1.243 140.62,40.52 140.67,40.56 v2(140.67,40.6) 140.97,40.6 141.62,39.94 JDIMM1.247 ; JDIMM1.35 86.62,39.85 v2(87.16,40.39) 87.62,39.92 JDIMM1.39 ; JDIMM1.65 94.12,40.07 93.84,40.35 92.98,40.35 ; v2(156.74,141.65) UV1.R27 ; v2(162.89,141.79) 162.91,141.78 UV1.K22 ; v2(102.76,29.53) 102.37,29.91 JDIMM1.98 ; JDIMM2.10 88.97,15.49 88.69,15.21 v2(88.49,15.21) 88.28,15.21 87.97,15.51 JDIMM2.6 ; JDIMM1.230 137.37,29.78 137.68,29.47 v2(138.25,29.47) 138.37,29.59 JDIMM1.234 ; JDIMM2.201 138.72,25.97 v2(138.75,26) 139.33,26 139.72,25.6 JDIMM2.205 ; JDIMM2.102 111.97,15.51 112.28,15.21 v2(112.49,15.21) 112.72,15.21 112.97,15.46 JDIMM2.106 ; JDIMM2.175 132.23,25.62 132.58,25.97 133.66,25.97 v2(133.72,26.03) 133.72,26.03 JDIMM2.181 ; v2(158.11,47.94) 157.8,48.25 DB1.2 ; v2(170.12,138.98) 170.08,139.02 UV1.F14 ; v2(172.3,139.78) 172.3,139.52 172.14,139.36 172.14,139.34 UV1.B12 ; CV151.2 181.87,153.11 v2(182.3,152.68) ; UV1.AD8 163.27,125.44 v2(163.28,125.45) ; UV1.C32 161.29,149.55 v2(161.21,149.55) ; UV1.AD6 163.33,124.31 v2(163.3,124.28) 163.26,124.31 UV1.AE7 ; JDIMM1.52 90.87,29.59 90.76,29.47 v2(90.62,29.47) 90.18,29.47 89.87,29.78 JDIMM1.48 ; JDIMM2.168 130.47,17.52 v2(130.05,17.94) ; JDIMM1.86 99.37,29.6 99.25,29.47 v2(98.61,29.47) ; v2(169.64,143.22) 169.25,143.22 168.72,142.7 UV1.B18 ; JDIMM2.5 87.72,25.71 87.56,25.87 v2(87.56,26.36) 88.27,26.36 88.72,25.9 JDIMM2.9 ; v2(155.43,137.97) 155.43,137.99 ; 155.43,137.99 155.25,137.81 155.25,137.21 UV1.Y25 ; 155.43,137.99 156.09,137.99 UV1.W25 ; JDIMM2.35 95.22,25.62 95.54,25.93 v2(96.12,25.93) 96.22,25.82 JDIMM2.39 ; 100.65,26.68 100.72,26.61 JDIMM2.57 ; 100.65,26.68 v2(100.7,26.73) ; 136.79,26 136.72,25.94 JDIMM2.193 ; 136.79,26 137.51,26 137.72,25.78 JDIMM2.197 ; UV1.H17 166.36,139.95 v2(166.36,140.27) ; 96.12,40.7 JDIMM1.73 ; 96.12,40.7 95.5,40.7 95.12,40.33 JDIMM1.69 ; 96.12,40.7 96.12,41.05 96.43,41.36 v2(97.85,41.36) ; HDD1.9 193.16,29.63 v2(193.33,29.79) ; JDIMM2.172 131.47,15.41 131.68,15.21 v2(131.97,15.21) 132.23,15.21 132.47,15.45 JDIMM2.176 ; v2(134.36,25.91) 134.72,25.54 JDIMM2.185 ; v2(147.97,15.21) JDIMM2.238 ; v2(162.17,63.37) 162.17,63.32 162.48,63.02 WLAN1.1 ; JDIMM1.102 103.37,29.77 103.63,29.52 v2(104.2,29.52) 104.37,29.7 JDIMM1.106 ; v2(171.29,137.8) 171.29,137.8 171.2,137.89 UV1.F12 ; v2(140.58,26.5) 141.81,26.5 142.72,25.59 JDIMM2.217 ; v2(109.97,17.72) JDIMM2.94 ; JDIMM1.192 127.87,29.71 v2(128.18,29.4) 127.02,29.4 126.87,29.55 JDIMM1.188 ; JDIMM1.6 79.37,29.41 v2(79.39,29.4) 80.02,29.4 80.37,29.75 JDIMM1.10 ; UV1.J7 UV1.H6 ; JDIMM2.23 92.22,25.76 92.38,25.92 v2(92.92,25.92) 92.92,25.92 93.22,25.61 JDIMM2.27 ; JDIMM2.230 145.97,15.51 146.28,15.21 v2(146.49,15.21) 146.69,15.21 146.97,15.49 JDIMM2.234 ; JDIMM1.18 82.37,29.69 82.02,29.34 v2(81.97,29.34) 81.88,29.34 81.37,29.84 JDIMM1.14 ; 105.97,16.46 105.97,15.45 105.61,15.08 v2(105.35,15.08) 104.68,15.08 104.48,15.28 JDIMM2.72 ; JDIMM1.30 85.37,29.73 86.22,28.88 v2(87.04,28.88) ; v2(98.61,29.47) 97.83,29.47 97.37,29.93 JDIMM1.78 ; v2(98.61,29.47) 98.37,29.7 JDIMM1.82 ; v2(135.16,40.22) 135.38,40.22 135.62,39.97 JDIMM1.223 ; JDIMM1.238 139.37,29.87 139.71,29.53 140.26,29.53 v2(140.26,29.53) 140.27,29.53 140.73,29.53 140.87,29.68 JDIMM1.244 ; WLAN1.31 164.22,53.52 v2(164.71,53.02) ; v2(104.11,25.93) 103.72,25.54 JDIMM2.69 ; v2(91.88,40.83) 92.5,40.83 92.98,40.35 ; v2(167.25,141.92) 167.29,141.88 UV1.F18 ; 131.12,40.26 131.91,40.26 132.12,40.04 JDIMM1.209 ; 131.12,40.26 130.09,41.29 129.83,41.29 v2(129.6,41.53) ; 131.12,40.26 JDIMM1.205 ; v2(165.69,132.31) 165.75,132.37 UV1.R11 166.3,132.05 v2(167.11,131.24) ; v2(181.89,162.23) 181.55,162.57 RV261.2 ; JDIMM1.202 130.37,29.74 130.16,29.52 v2(129.13,29.52) 128.87,29.78 JDIMM1.196 ; UV1.F26 162.17,145.81 v2(162.12,145.86) 162.07,145.81 UV1.G27 ; 80.12,40.52 79.81,40.83 v2(78.54,40.83) ; 80.12,40.52 80.24,40.63 81.41,40.63 81.62,40.42 JDIMM1.15 ; 80.12,40.52 JDIMM1.9 ; v2(151.47,15.21) JDIMM2.252 ; JDIMM2.206 139.97,15.41 140.18,15.21 v2(140.47,15.21) 140.73,15.21 140.97,15.45 JDIMM2.210 ; v2(169.74,58.77) WLAN1.10 ; UV1.A32 162.2,150.41 v2(162.28,150.49) ; WLAN1.55 v2(162.24,47.52) ; JDIMM2.68 103.48,15.49 103.19,15.21 v2(102.99,15.21) 102.78,15.21 102.48,15.51 JDIMM2.64 ; LCD1.16 v2(88.3,164.89) ; JDIMM2.52 99.48,15.49 99.19,15.21 v2(98.99,15.21) 98.78,15.21 98.48,15.51 JDIMM2.48 ; WLAN1.67 v2(162.24,44.52) ; WLAN1.61 v2(162.24,46.02) ; JDIMM1.44 88.87,29.66 v2(89.14,29.4) ; JDIMM1.31 85.62,40 85.28,40.35 v2(85.14,40.35) 84.62,39.83 JDIMM1.27 ; JDIMM1.57 92.12,39.89 91.81,40.2 91.72,40.2 91.68,40.23 v2(91.68,40.23) 90.81,40.23 90.62,40.05 JDIMM1.51 ; JDIMM1.189 127.12,39.99 v2(126.93,40.19) ; UV1.F8 172.77,135.62 172.38,135.24 UV1.G8 171.84,135.06 v2(171.79,135.11) ; v2(193.1,86.04) 192.66,85.61 JDEG1.10 ; v2(164.95,144.14) 165.03,144.05 UV1.F22 ; JDIMM2.227 145.23,25.87 v2(145.21,25.89) 144.53,25.89 144.23,25.59 JDIMM2.223 ; 190.61,31.13 190.23,31.51 190.23,32 v2(190.13,32.11) ; v2(166,129.18) 166,129.8 UV1.U9 ; JDIMM1.43 88.62,41.45 v2(89.08,41.91) 89.62,41.37 JDIMM1.47 ; v2(92.92,26.57) 93.54,26.57 94.22,25.89 JDIMM2.31 ; v2(156.37,138.88) 156.37,138.81 156.43,138.88 UV1.U25 ; JDIMM1.251 142.62,40.75 141.52,41.85 140.4,41.85 139.62,41.08 JDIMM1.239 139.62,38.11 140.2,37.53 v2(140.65,37.53) ; JDIMM1.217 134.12,40.28 ; 134.12,40.28 133.55,40.28 133.12,39.85 JDIMM1.213 ; v2(154.55,137.22) 154.55,136.92 154.99,136.48 UV1.AB24 ; JDIMM1.99 102.62,40.23 102.61,40.25 102.61,40.39 v2(102.55,40.45) 102.42,40.45 102.42,40.45 101.46,40.45 101.12,40.11 JDIMM1.93 ; JDIMM2.226 144.97,15.45 144.73,15.21 v2(144.47,15.21) 144.18,15.21 143.97,15.41 JDIMM2.222 ; JDIMM2.56 100.48,15.51 100.78,15.21 v2(100.99,15.21) 101.19,15.21 101.48,15.49 JDIMM2.60 ; v2(136.64,40.9) 137.58,40.9 138.62,39.86 JDIMM1.235 ; v2(162.17,61.53) 162.18,61.52 WLAN1.7 ; v2(169.47,135.1) 169.38,135.2 UV1.K11 ; WLAN1.37 v2(164.71,52.02) ; JDIMM2.235 147.23,25.7 147.03,25.89 146.58,25.89 v2(146.58,25.89) 146.23,25.53 JDIMM2.231 ; UV1.F16 168.97,140.15 v2(169.05,140.07) ; UC1.BA14 130.48,75.74 130.47,75.76 v2(130.47,75.82) 130.47,75.83 130.48,75.84 UC1.AW14 ; v2(162.24,55.02) 162.33,55.02 WLAN1.25 ; v2(108.71,17.76) 108.97,17.49 JDIMM2.90 ; JDIMM2.82 106.97,15.51 107.28,15.21 v2(107.49,15.21) 107.69,15.21 107.97,15.49 JDIMM2.86 ; v2(86.86,26.16) 86.72,26.03 JDIMM2.1 ; UV1.L27 158.89,143.54 v2(158.81,143.46) ; WLAN1.49 v2(162.24,49.02) ; v2(86.8,164.84) LCD1.13 86.8,167.26 85.69,168.37 v2(85.05,168.37) 84.8,168.12 LCD1.9 ; CV143.2 183.52,154.83 183.83,155.13 184.32,155.13 v2(184.39,155.2) ; v2(137.47,15.21) JDIMM2.196 ; v2(131.82,26.16) 131.23,25.57 JDIMM2.171 ; JDIMM2.180 133.47,15.41 133.68,15.21 v2(133.97,15.21) 134.23,15.21 134.47,15.45 JDIMM2.184 ; JDIMM2.30 v2(93.97,15.21) ; UV1.F20 166.16,142.99 v2(166.21,143.03) ; v2(164.49,147.63) 164.18,147.33 UV1.B26 ; 92.98,40.35 93.12,40.21 JDIMM1.61 ; v2(152.27,137.41) 152.59,137.09 UV1.AC27 ; v2(91.3,166.94) 91.3,166.74 LCD1.22 ; v2(175.33,131.46) 175.12,131.46 174.63,131.95 UV1.H2 ; UV1.K28 159.37,145.1 v2(159.3,145.17) ; JDIMM1.180 124.87,29.92 125.24,29.56 v2(125.6,29.56) 125.73,29.56 125.87,29.7 JDIMM1.184 ; WLAN1.43 v2(162.21,50.52) ; 151.25,26.1 150.45,26.1 150.22,25.87 JDIMM2.247 ; 151.25,26.1 151.22,26.07 JDIMM2.251 ; 151.25,26.1 v2(151.76,26.1) ; v2(110.97,18.18) JDIMM2.98 ; UV1.AC9 v2(162.24,126.57) ; UV1.E28 162.2,146.98 v2(162.19,146.97) ; JDIMM2.213 141.72,25.64 141.37,25.99 140.71,25.99 v2(140.6,25.88) 140.72,25.75 JDIMM2.209 ; JDIMM1.89 100.12,40.27 99.91,40.48 99.16,40.48 99.12,40.45 ; LCD1.35 v2(97.8,166.92) ; v2(154.32,139.03) 154.33,139.04 154.82,139.04 UV1.W27 ; v2(158.81,146.51) 159.09,146.22 159.09,146.09 ; v2(176.67,159.3) 176.67,159.3 177.08,158.89 CV186.2 ; 112.22,26.1 112.22,26.3 111.92,26.61 111.82,26.61 v2(111.75,26.67) ; 112.22,26.1 112.29,26.03 113.02,26.03 113.22,25.83 JDIMM2.107 ; 112.22,26.1 JDIMM2.103 ; JDIMM1.185 126.12,40.53 126.36,40.77 126.89,40.77 v2(126.94,40.82) 127.06,40.7 127.69,40.7 128.12,40.27 JDIMM1.193 ; WLAN1.18 v2(172.06,56.77) ; LCD1.33 v2(96.8,166.92) ; JDIMM2.43 97.22,25.54 97.77,26.08 98.15,26.08 v2(98.22,26) JDIMM2.47 ; JDIMM2.188 135.47,15.41 135.68,15.21 v2(135.97,15.21) 136.23,15.21 136.47,15.45 JDIMM2.192 ; v2(174.3,136.53) 174.36,136.6 UV1.B8 ; v2(155.79,139.21) 155.56,138.98 UV1.W26 ; 99.12,40.45 98.8,40.77 98.8,41.4 98.23,41.97 v2(97.85,41.97) ; 99.12,40.45 JDIMM1.85 ; v2(168.38,128.32) 168.38,128.79 UV1.T6 ; UV1.H14 168.85,138.03 v2(168.99,137.89) ; JDIMM1.56 91.87,29.62 v2(91.96,29.54) ; JDIMM1.231 137.62,40.03 137.34,40.32 136.7,40.32 v2(136.64,40.26) 136.62,40.24 JDIMM1.227 ; v2(193.1,28.64) 192.59,28.13 HDD1.12 ; v2(104.11,26.57) 104.42,26.57 104.72,26.27 JDIMM2.73 ; JDIMM2.85 107.72,25.55 108.11,25.93 v2(108.72,25.93) 108.72,25.92 JDIMM2.89 ; JDIMM1.171 122.62,40.05 122.92,40.35 v2(123.94,40.35) 123.62,40.04 JDIMM1.175 ; UV1.G31 160.22,147.22 159.51,147.94 159.51,148.05 v2(159.5,148.05) ; JDIMM2.2 v2(86.97,15.21) ; JDIMM2.77 105.72,25.72 106.07,26.06 v2(106.2,26.06) 106.33,26.06 106.49,25.9 106.54,25.9 106.72,25.71 JDIMM2.81 ; JDIMM1.64 93.87,29.78 93.61,29.52 v2(93.33,29.52) 93.14,29.52 92.87,29.79 JDIMM1.60 ; v2(148.9,26.29) 149.22,25.96 JDIMM2.243 ; JDIMM2.61 101.72,25.8 101.92,26 v2(102.74,26) 102.72,25.99 JDIMM2.65 ; JDIMM1.181 125.12,40.02 124.13,41.02 v2(123.94,41.02) 122.61,41.02 121.62,40.04 JDIMM1.167 ; v2(167.13,145.77) 167.08,145.72 167.08,145.32 166.71,144.96 UV1.B22 ; v2(78.12,32.07) 78.37,31.82 JDIMM1.2 ; JDIMM1.107 104.62,39.86 v2(104.29,40.2) 104.22,40.26 103.93,40.26 103.62,39.95 JDIMM1.103 ; v2(167.9,144.22) 167.9,144.15 UV1.B20 ; JDIMM1.26 84.37,29.73 84.13,29.49 v2(83.75,29.49) 83.59,29.49 83.37,29.7 JDIMM1.22 ; JDIMM2.244 149.47,15.51 149.78,15.21 v2(149.99,15.21) 150.19,15.21 150.47,15.49 JDIMM2.248 ; JDIMM2.239 148.23,25.5 147.19,26.54 v2(146.55,26.54) ; JDIMM2.167 130.23,25.91 129.62,26.52 v2(129.06,26.52) ; JDIMM1.81 98.12,39.91 v2(97.84,40.19) 97.37,40.19 97.12,39.95 JDIMM1.77 ; JDIMM2.15 90.22,26.35 v2(90.61,26.73) 91.22,26.12 JDIMM2.19 ; JDIMM1.226 136.37,29.78 136.07,29.48 v2(135.71,29.48) 135.64,29.48 135.37,29.74 JDIMM1.222 ; UV1.B14 v2(171.4,140.86) ; CV43.2 190.29,160.89 v2(190.94,161.54) ; JDIMM2.22 91.97,15.51 92.28,15.21 v2(92.49,15.21) 92.69,15.21 92.97,15.49 JDIMM2.26 ; JDIMM1.252 142.87,29.71 142.76,29.6 v2(142.07,29.6) 141.87,29.79 JDIMM1.248 ; v2(138.97,15.21) JDIMM2.202 ; LCD1.19 v2(89.8,164.81) ; UV1.N25 UV1.P25 157.93,140.57 v2(157.85,140.49) ; UV1.G10 171.27,136.19 171.82,136.74 UV1.F10 171.82,136.77 172.24,137.19 v2(172.28,137.19) ; v2(165.96,147.18) 165.98,147.15 165.98,146.56 165.51,146.09 UV1.B24 ; JDIMM2.214 141.97,15.41 142.18,15.21 v2(142.47,15.21) 142.73,15.21 142.97,15.45 JDIMM2.218 ; JDIMM1.40 87.87,29.77 87.62,29.52 v2(87.04,29.52) 86.87,29.68 JDIMM1.36 ; UV1.U27 v2(156.65,140.15)
  BOTTOM w0.356: UV2.3 140.1,129.38 140.65,129.92 v2(140.65,129.92)
  BOTTOM w0.381: v2(164.93,130.17) 164.54,130.17 UV1.V11 ; v2(144.13,133.22) 144,133.09 CV17.2 ; v2(50.35,40.21) 49.99,39.85 PR118.2 ; v2(162.97,131.01) 162.97,131.74 UV1.V13 163.01,131.91 163.01,132.54 v2(162.96,132.59) 162.92,132.63 162.92,133.21 UV1.U15 162.82,133.31 162.82,134.44 UV1.T16 ; PC1129.2 84.05,80.72 83.81,80.96 v2(83.81,81.03) ; v2(81.67,82.56) 81.48,82.75 PC1155.2 ; v2(157.13,139.57) 157.29,139.73 UV1.T25 ; UV1.T18 161.47,135.8 161.47,137.15 UV1.R20 v2(161.5,137.94) 161.45,137.99 161.45,138.55 UV1.N21 162.12,138.59 v2(162.13,138.61) ; CV212.2 196.27,154.49 v2(195.7,153.92) ; UZ6.3 180.15,72.28 v2(179.98,72.11) ; UV1.AE14 v2(159.05,127.94) ; UV1.AB15 160.08,131.02 v2(160.06,131.05) 160.06,131.78 UV1.AA16 160.15,131.88 160.15,133.01 UV1.Y17 160.16,133.14 v2(160.16,133.72) 160.22,133.79 160.22,134.49 160.2,134.51 160.2,135.18 160.22,135.2 UV1.U20 160.15,135.98 v2(160.15,136.54) 160.15,137.11 UV1.T21 ; v2(80.13,77.41) 80.48,77.05 PC1183.2 ; v2(172.27,69.72) 172.14,69.72 171.37,70.5 EC5802.2 ; v2(158.25,130.69) 158.1,130.84 UV1.AC17 ; U3402.3 v2(18.3,39.65) ; v2(80.78,81.67) 80.59,81.86 PC1178.2 ; UV1.AB10 162.91,127.86 v2(163.35,128.3) 163.75,128.69 UV1.Y10 ; UV1.T13 164.16,133.1 164.16,133.72 v2(164.14,133.73) 164.14,134.45 UV1.R15 164.18,135.15 164.14,135.19 164.14,135.87 UV1.N16 164.92,135.91 v2(164.98,135.97) ; THM26.5 157.94,160.06 158.31,159.69 C2609.2 ; UV1.R11 166.49,132.37 167.01,132.89 UV1.N11 UV1.M12 ; RE380.1 179.7,74.82 UE6.3 ; UV1.P9 167.39,131.52 v2(167.11,131.24) ; UV1.AA13 161.5,131.04 v2(161.44,131.09) 161.44,131.75 UV1.Y15 161.46,131.84 v2(161.46,132.6) 161.46,133.18 UV1.V16 161.55,133.28 161.55,134.41 UV1.U17 ; EU5602.3 v2(187.32,33.62) ; PC1221.2 81.37,78.2 v2(81.15,78.42) ; v2(82.61,83.46) 82.37,83.7 PC1222.2 ; PC1184.2 79.59,76.19 v2(79.25,76.53) ; UC14.3 77.29,70.58 v2(77.9,69.98) ; UV1.Y20 v2(158.81,135.13) ; EU3101.3 v2(35.7,174.15) ; v2(82.89,80.09) 82.89,80.05 83.16,79.77 PC1131.2 ; PC1132.2 82.28,78.97 v2(82.02,79.22) ; PR637.2 114.15,137.39 114.53,137.77 PR629.1 ; CV196.2 178.23,172.33 v2(177.73,171.83) ; RC268.2 141.77,92.61 v2(142.85,93.69) ; v2(162.85,135.13) 162.85,135.7 UV1.R17 UV1.N18 ; UV1.AA11 163,129.07 v2(163,129.72) ; UV1.T11 165.6,132.21 v2(165.69,132.31) 165.69,132.99 UV1.R12 165.65,133.13 v2(165.65,133.88) 165.7,133.94 165.7,134.39 UV1.N13
  BOTTOM w0.457: v2(129.85,100.48) CC195.2
  BOTTOM w0.508: WLAN1.68 162.61,64.12 162.57,64.07 v2(162.17,64.07) ; PC652.2 122.79,138.5 v2(123.66,137.64) ; v2(103.79,161.26) 104.07,160.99 PC749.1 104.14,160.53 PR727.2 ; PC757.1 v2(114.36,160.02) ; v2(155.67,53.46) 155.41,53.2 JWDB1.6 ; v2(157.54,9.14) 156.95,8.56 JDIMM2.262 ; v2(168.08,168.7) 168.09,168.7 RV112.2 ; PR505.2 174,21.89 v2(173.54,22.35) ; EC2709.2 174.48,16.9 v2(174.59,16.8) ; C2707.2 179.97,12.09 v2(179.3,12.09) ; 93.4,102.04 93.08,102.04 92.06,101.02 RC43.2 ; C2608.2 v2(154.93,159.51) ; v2(104.22,161.9) 104.7,161.42 PR753.1 ; CC272.2 141.8,85.98 v2(142.04,85.98) ; RD28.2 153.13,33.98 v2(154.04,33.98) ; C3510.2 v2(28.65,46.33) ; PR310.2 v2(135.88,128.05) ; v2(103.89,164.36) 103.68,164.15 PC752.1 PC751.1 ; v2(159.93,101.03) PR1105.1 159.94,101.65 PR1106.1 ; PC1226.2 153.72,106.75 v2(153.28,107.19) ; R5202.1 82.56,154.31 v2(82.56,154.84) ; CV396.2 166.24,164.78 v2(166.67,164.35) ; v2(93.7,90.07) 93.7,90.49 RC163.2 ; CV95.2 152.65,147.52 v2(152.65,147.64) ; PR680.2 71.74,36.34 v2(71.74,35.78) ; v2(158.83,73.88) 158.38,74.33 CC8.1 ; v2(30.2,65.28) 30.2,65.87 29.62,66.45 C5520.2 ; RV89.1 157.38,120.88 v2(157.38,121.64) ; v2(121.62,135.41) 121.62,134.86 PC645.2 ; v2(198.08,151.36) 197.53,151.91 CV394.2 ; LCD1.42 79.1,170.26 78.75,170.61 v2(78.01,170.61) ; EC9732.2 55.95,27.13 v2(56.19,27.37) ; v2(179,69.79) 178.62,69.79 177.02,71.39 RE355.2 ; CD16.2 v2(151.44,41.76) ; v2(83.65,155.35) 83.31,155.69 83.31,156.4 82.77,156.93 U5201.2 ; v2(179.25,27.56) 179.25,26.99 178.63,26.37 R2717.2 ; CV210.2 191.78,146.79 v2(191.28,146.79) ; DA6.1 v2(97.55,160.95) ; v2(195.45,86.68) 195.25,86.48 JDEG1.12 ; v2(151.38,90.94) CC271.2 ; CV18.2 143.69,129.08 v2(143,129.08) ; PC605.1 110.12,145.8 109.61,145.29 v2(109.61,144.55) ; CC21.2 v2(123.34,106.69) ; v2(150.41,80.72) 149.41,80.72 149.28,80.59 CC26.2 149.31,79.88 RC390.1 ; RC112.1 91.04,97.28 v2(91.03,97.27) ; v2(125.89,105.12) 126.12,105.35 CC22.2 ; v2(34.11,63.92) 34.11,62.95 33.75,62.59 C5517.2 ; C3206.2 14.08,21.29 v2(13.75,21.62) ; CV170.2 188.35,143.86 v2(188.33,143.86) ; v2(101.94,171.35) 102,171.28 LCD1.41 ; SPR1.1 66.05,25 65.59,25.46 v2(63.49,25.46) ; RC109.1 91.65,95.76 v2(91.28,95.39) ; PC669.2 v2(62.95,43.51) ; v2(118.29,98.31) RC141.2 ; PR305.2 v2(135.88,128.98) ; EC2708.2 175.33,15.05 v2(175.52,14.86) C2723.1 ; v2(168.74,169.42) 169.17,169 CV399.2 ; EC9735.2 82.8,152.29 v2(82.8,151.45) ; RH212.2 v2(77.54,60.9) ; U3505.2 200.15,22.99 200.68,23.52 C3515.2 200.68,24.44 v2(200.1,25.02) ; CE65.2 v2(186.75,81.22) ; PC629.1 119.41,137.2 119.41,136.88 v2(120.05,136.25) 121.14,137.34 PC649.2 ; CC214.2 139.31,69.6 v2(140.2,70.48) ; RD38.2 161.42,23.1 v2(161.22,23.3) ; v2(82.81,150.57) 83.04,150.34 EC9736.2 ; v2(187.57,117.02) C6211.1 ; v2(176.68,12.19) 176.85,12.36 177.24,12.36 EC2701.2 ; RC75.1 v2(150.55,55.63) ; C2601.2 v2(153.98,168.34) ; C2605.2 v2(93.81,144.81) ; v2(195.99,94.04) 195.99,94.02 195.25,93.28 JDEG1.11 ; v2(153.27,111.19) 153.27,111.19 PR1117.1 ; C5803.2 C5804.2 v2(171.81,39.56) ; PR1117.1 153.95,111.14 PC1117.1 ; PR1117.1 153.98,111.26 PR1120.1 ; JDIMM1.262 145.3,45 v2(146.11,44.2) ; PR1205.2 PC1204.2 v2(36.7,58.48) ; RC358.1 148.65,89.34 v2(149.03,88.96) 148.57,88.5 CC280.2 ; EC9715.2 107.88,136.46 v2(108.26,136.84) ; v2(103.33,158.62) 103.33,158.42 103.84,157.91 PC748.2 ; PC1206.2 v2(48.32,58.48) ; CV131.2 167.83,166.3 v2(168.26,165.88) ; CC58.2 76,66.04 76.45,65.6 v2(77.27,65.6) ; v2(95.69,113.47) 96.02,113.8 EC9719.2 ; PC805.2 v2(57.21,27.69) ; PC1209.2 v2(39.55,58.74) ; v2(25.21,64.59) 25.82,63.97 C5502.2 ; v2(190.51,77.15) 191.03,77.67 CE79.2 ; v2(48.95,164.91) 48.52,165.34 C3017.2 C3025.2 C3024.2 ; R5516.1 30.88,62.08 30.57,62.39 v2(30.2,62.39) 30.64,62.83 C5523.1 ; v2(85.67,153.8) 85.82,153.8 86.49,154.47 C5204.2 ; v2(114.81,164.49) PR751.1 PR779.1 ; RC348.2 v2(105.51,103.44) ; v2(92.69,96.74) CC1101.2 ; v2(28.7,52.9) 29.29,53.49 U5504.7 ; v2(175.82,126.11) 175.57,126.11 RV151.1 ; v2(72.7,9.45) 73.11,9.87 SPK1.5 ; RC4.2 141.8,78.87 v2(142.33,79.4) ; RV163.2 147.19,128.44 RV4.2 147.08,129.6 146.49,129.01 v2(146.49,129.03) ; R5209.2 v2(104.63,172.72) ; C5606.2 189.27,35.59 C5605.2 188.8,36.06 187.9,36.06 v2(187.66,35.81) ; EC3103.1 v2(40.31,174.64) ; PC644.2 122.1,145.9 v2(122.13,145.92) 122.36,146.15 PR654.2 ; C2718.2 176.4,18.16 v2(176.14,18.16) ; U5504.1 30.56,49.75 v2(29.92,50.39) 29.29,49.75 U5504.2 ; CE69.2 v2(173.65,73.71) 173.65,73.2 CE89.2 ; RV263.2 v2(194.53,146.96) ; C5524.2 27.14,66.67 26.63,67.18 v2(26.16,67.18) ; PH1101.1 173.97,116.59 v2(174.07,116.48) ; PC684.2 71.82,38.22 v2(71.7,38.09) ; CV220.2 v2(196.39,148.91) ; PC308.2 v2(127.97,116.24) ; WLAN1.69 v2(162.25,43.42) ; C5601.2 194.49,38.1 v2(194.99,38.61) ; RD39.2 161.42,19.57 v2(160.97,19.11) ; PC677.2 v2(69.78,35.8) ; v2(27.3,62.39) 27.92,61.76 R5512.1 R5508.1 ; PC641.2 109.21,139.27 v2(108.54,139.27) ; C3202.2 10.5,18.32 v2(10.5,18.31) ; v2(32.25,66.17) 31.7,65.62 R5505.2 ; v2(151.31,148.02) 151.44,148.02 151.95,147.51 151.95,146.93 CV94.2 151.8,145.75 RV34.2 ; JHDMI.22 v2(8.84,54.47) ; v2(115.96,133.78) 116.41,134.24 PR653.2 ; PC1424.2 v2(54.78,68.61) ; JWDB1.5 159.55,52.47 v2(160.08,51.94) ; PR1411.2 125.2,134.74 PR1407.2 v2(124.05,134.73) ; C2602.2 v2(155.95,168.4) ; v2(93.22,159.18) 93.3,159.26 93.3,159.77 R5201.2 ; v2(10.14,15.39) 10.15,15.4 C3203.2 ; v2(128.47,133.21) 128.37,133.31 128.37,134.06 PR1404.2 ; CV133.2 172.71,170.44 v2(172.78,170.37) ; CMOS1.2 v2(141.55,59.22) ; PC777.2 v2(134.03,157.91) ; v2(164.78,78.23) 165.27,77.74 UC5.4 ; YV1.2 142.47,131.14 142.47,131.14 142.23,131.38 v2(142.23,132.08) ; CE66.2 191.62,74.73 v2(191.89,74.99) ; SPR2.1 75.21,79.98 72.76,77.53 v2(71.37,77.53) ; CE12.2 CE84.1 192.72,66.36 v2(192.94,66.13) ; v2(153.6,119.44) 153.6,119.63 RV88.1 ; v2(186.62,72.38) R2611.2 187.69,72.38 C5224.2 ; PC604.2 123.18,144.02 v2(122.8,143.64) ; CZ34.2 184.79,71.64 v2(184.92,71.51) ; CV211.2 191.06,145.74 v2(190.63,146.16) ; v2(154.11,46.04) 153.73,45.66 DB1.12 ; C6209.1 v2(190.43,123.24) ; SPK1.6 72.98,4.27 v2(72.68,3.96) ; v2(170.9,121.03) 170.58,121.03 170.25,121.36 RV83.2 ; USB1.10 v2(15.92,46.37) ; v2(123.99,139.29) 124.14,139.45 PC1405.2 ; FAN1.3 v2(93.72,138.81) ; EC9760.2 48.86,62.5 v2(47.15,62.5) ; v2(78.28,158.15) 78.78,158.66 C5201.2 C5206.1 ; EC9713.2 106.99,136.97 107.63,137.6 v2(108.32,137.6) ; U3504.2 v2(24.59,45.18) ; v2(79.81,46.89) JDIMM1.261 ; v2(173.86,69.91) 173.86,70.23 174.06,70.43 EC5801.2 ; CC23.2 143.67,79.02 143.37,79.32 v2(143.37,79.76) CC204.2 ; JDIMM2.261 84.14,8.56 v2(83.37,9.33) ; CC5.1 151.14,72.2 150.78,72.56 150.78,73.25 151.13,73.6 v2(151.49,73.6) ; PC1208.2 v2(49.65,50.23) ; EC5210.2 EC5206.2 94.04,156.03 v2(93.58,155.57) ; CC9.2 157.57,70.71 v2(157.28,70.99) ; EC3102.1 v2(40.31,173.78) ; R5218.2 86.31,160.25 86.11,160.45 v2(86.11,160.58) ; CV198.2 196.42,151.63 v2(196.04,151.63) ; v2(55.75,14.86) 56,14.61 RTC1.2 ; v2(159,159.51) C2609.2 ; C5604.2 195.99,38.12 v2(195.85,37.98) ; PR110.2 38.21,39.79 v2(38.59,40.17) ; C3518.2 C3517.2 194.44,22.88 v2(194.3,22.74) ; PC618.1 v2(110.29,144.37) ; PR1202.1 v2(38.54,58.48) ; v2(72.57,166.56) C5205.1 74.15,166.8 C5202.2 ; CD32.2 v2(165.09,17.02) ; EC3101.1 38.5,171.09 v2(38.43,171.16) ; v2(53.29,167.92) 53.27,167.92 53.26,167.91 C3023.2 ; R5410.2 v2(17.1,80.8) ; v2(93.34,142.75) 93.34,142.55 FAN1.5 ; RV21.1 v2(173.39,123.6) ; v2(167.94,32.45) PC504.2 ; v2(116.06,131.45) 113.62,131.45 113.09,130.92 PC661.2 ; v2(101.56,163.75) 101.4,163.91 C5214.2 ; C2704.1 190.49,13.45 v2(189.74,12.7) ; HDD1.13 v2(196.7,35.43) ; v2(156.01,52.64) 155.85,52.48 JWDB1.1 ; FAN1.4 v2(90.29,138.18) ; C2611.2 v2(93.31,145.95) ; C3018.2 v2(51.77,166.77) ; v2(111.97,145.03) 111.97,144.8 111.82,144.65 PC619.1 ; v2(158.81,46.23) 159.37,45.66 DB1.11 ; v2(10.52,17.42) 10.53,17.43 C3204.2 ; PR731.2 105.24,154.03 v2(105.24,153.67) ; SPR3.1 158.36,32.64 v2(158.36,33.4) ; R2605.1 v2(94.45,143.73) ; PC1207.2 v2(48.44,50.23) ; CE85.2 CE86.2 184.54,75.36 v2(184.3,75.6) ; RC383.2 141.72,89.28 v2(141.47,89.03) ; CV402.2 175.05,173.74 175.56,173.23 175.57,173.23 v2(175.76,173.04) ; C2708.2 v2(179.15,10.72) ; PR755.1 108.07,163.7 PR752.1 107.19,164.32 v2(106.99,164.52) ; v2(194.68,25.3) 194.92,25.55 194.92,26.34 ; v2(193.6,121.79) C6217.2 ; PC1404.2 v2(127.37,133.41) ; v2(159.3,101.66) PR1140.2 ; v2(165.16,36.89) C5801.2 C5802.2 ; v2(179.76,75.53) 179.63,75.4 RE380.1 ; U5504.4 v2(26.75,47.9) ; PR647.1 114.61,133.65 114.74,133.53 114.74,133.36 v2(115.95,132.15) ; CV64.2 149.22,127.27 CV123.2 148.68,126.71 148.27,126.3 v2(148.27,125.67) ; C5208.2 v2(100.18,160.32) ; 153.71,147.72 153.71,147.72 v2(153.25,148.18) ; PC1233.2 161.61,114.93 v2(160.71,114.93) 159.34,114.93 PC1231.2 ; RE398.2 184.52,68.39 184.38,68.53 CE62.2 183.89,68.62 183.36,69.15 v2(183.06,69.15) ; C3205.2 10.48,16.48 v2(10.47,16.48) ; EC9756.2 169.43,120.71 v2(169.02,120.29) 168.54,119.82 EC9755.2 ; CC4.1 v2(153.46,69.47) ; C3504.2 v2(201.36,17.73) ; CC279.2 v2(149.77,88.96) ; YV1.4 140.94,132.32 v2(141.18,132.08) ; v2(14.43,11.21) 14.37,11.27 R3203.2 C3201.1 ; v2(113.6,143.83) 113.6,144.06 113.85,144.32 113.85,144.47 PC602.2 ; RE367.2 CE82.2 CE74.2 177.12,78.93 176.21,78.02 176.07,78.02 v2(176.06,78.02) ; RV142.2 v2(195.19,147.57) ; EC3201.2 v2(22.35,17.91) ; PR1207.2 33.97,57.98 34.47,58.48 v2(34.73,58.48) ; v2(162.3,35.85) C5805.2 162.54,34.81 CD34.2 ; G6102.1 190.81,176.53 v2(190.58,176.76) ; C5806.2 v2(173.79,39.56) ; EC3104.1 v2(39.7,178.03) ; R5413.2 v2(36.01,70.45) ; RE397.2 CE91.2 v2(190.51,76.25) ; RC35.2 v2(104.18,103.44) ; C5207.2 96.32,155.8 95.88,155.36 v2(95.88,154.86) ; v2(96.01,141.73) EC2602.2 ; EC9720.2 v2(96.02,118.49)
  vias: v2(3.75,82.56) v2(3.87,76.71) v2(4.5,51.18) v2(5.62,49) v2(7.2,54.27) v2(7.61,75.63) v2(8.5,75.63) v2(8.86,28.57) v2(8.86,21.97) v2(8.86,15.37) v2(8.86,8.77) v2(8.86,2.17) v2(8.97,80.25) v2(9.33,77.77) v2(9.31,72.05) v2(9.31,58.39) v2(10.37,27.16) v2(10.39,25.84) v2(10.37,24.11) v2(10.37,22.58) v2(10.37,19.54) v2(10.37,11.92) v2(10.43,4.41) v2(10.58,79.38) v2(10.62,20.62) v2(10.62,10.46) v2(10.62,5.38) v2(11.04,14.1) v2(11.1,28.39) v2(11.17,7.3) v2(11.28,82.56) v2(11.28,10.01) v2(11.62,23.13) v2(11.6,22.28) v2(11.88,5.41) v2(12.14,80.43) v2(12.39,78.35) v2(12.86,10.13) v2(13.01,27.82) v2(13.27,23.33) v2(14.16,28.11) v2(15.2,54.27) v2(15.25,5.24) v2(15.21,0.68) v2(15.49,28.3) v2(15.55,58) v2(15.5,16.58) v2(15.87,16) v2(16,8.41) v2(16.19,65.85) v2(16.25,63.69) v2(16.36,16.58) v2(16.44,60.71) v2(16.85,29.03) v2(16.82,16) v2(17.23,16.58) v2(17.46,6.39) v2(17.77,57.36) v2(17.84,68.64) v2(18.09,59.14) v2(18.22,76.14) v2(18.24,74.85) v2(18.49,41.81) v2(18.49,41.22) v2(18.54,62.8) v2(18.54,50.77) v2(18.81,82.56) v2(19.27,15.72) v2(19.6,52.6) v2(19.6,48.94) v2(19.89,62.78) v2(19.89,60.56) v2(19.89,57.89) v2(20.14,5.88) v2(20.27,14.18) v2(20.44,8.1) v2(21.08,71.88) v2(21.03,65.05) v2(21.67,65.05) v2(21.7,52.6) v2(21.7,48.94) v2(22.35,77.93) v2(22.37,76) v2(22.35,74.91) v2(22.3,65.05) v2(22.44,72.8) v2(22.76,50.77) v2(22.8,71.94) v2(22.9,70.9) v2(22.94,65.05) v2(22.96,41.31) v2(23.06,41.94) v2(23.19,60.56) v2(23.19,57.89) v2(23.38,76.65) v2(23.51,74.02) v2(23.6,41.31) v2(23.95,14.06) v2(24.5,36.34) v2(24.59,14.06) v2(25.18,38.89) v2(25.18,37.03) v2(25.24,42.17) v2(25.29,35.05) v2(25.27,5.57) v2(25.67,82.56) v2(26.17,43.02) v2(26.49,0.68) v2(27.3,65.28) v2(27.43,78.04) v2(27.41,76.51) v2(28.12,160.58) v2(28.22,1.68) v2(28.44,10.99) v2(28.75,65.28) v2(28.75,62.39) v2(28.86,179.75) v2(31.68,55.37) v2(32,55.88) v2(31.96,42.46) v2(31.93,41.87) v2(32,41.21) v2(32.31,55.37) v2(32.67,82.56) v2(32.63,55.88) v2(32.95,55.37) v2(33.05,40.79) v2(33.27,55.88) v2(33.78,43.05) v2(33.74,42.44) v2(33.74,41.83) v2(33.74,41.2) v2(33.76,40.61) v2(33.84,54.42) v2(33.97,30.86) v2(34.03,38.28) v2(34.4,43.05) v2(34.4,42.44) v2(34.4,41.85) v2(34.37,35.56) v2(34.37,34.95) v2(34.42,41.17) v2(34.5,160.58) v2(34.66,55.31) v2(34.66,54.67) v2(34.6,30.86) v2(34.98,42.42) v2(34.98,41.81) v2(34.99,1.68) v2(35.01,41.17) v2(35.3,54.67) v2(35.24,30.86) v2(35.41,77.65) v2(35.54,41.5) v2(35.63,179.75) v2(35.64,164.77) v2(35.86,30.86) v2(36.06,50.67) v2(36.49,30.86) v2(36.7,166.6) v2(36.7,162.94) v2(37.06,63.65) v2(37.06,61.81) v2(37.13,30.86) v2(37.56,28.92) v2(37.56,28.31) v2(37.53,27.69) v2(37.53,27.08) v2(37.53,26.45) v2(37.53,25.84) v2(37.62,35.98) v2(38.22,36) v2(38.8,166.6) v2(38.8,162.94) v2(39.1,27.13) v2(39.1,26.44) v2(39.15,28.17) v2(39.66,82.56) v2(39.86,164.77) v2(40.71,76.33) v2(40.71,74.4) v2(40.88,160.58) v2(41.41,177.5) v2(41.61,172.11) v2(41.76,1.68) v2(42.39,179.75) v2(43.48,40.88) v2(43.5,42.25) v2(43.5,41.54) v2(44.86,19.56) v2(44.95,166.81) v2(45.09,42.34) v2(45.09,41.73) v2(45.14,43.62) v2(45.12,42.98) v2(45.14,41.08) v2(45.71,165.54) v2(45.75,42.93) v2(45.75,42.32) v2(45.7,41.68) v2(45.78,41.08) v2(45.71,38.46) v2(45.78,19.56) v2(45.83,35.61) v2(45.83,35) v2(46.39,42.9) v2(46.35,42.29) v2(46.31,41.66) v2(46.67,19.58) v2(46.97,42.27) v2(46.97,41.66) v2(47.2,31.72) v2(47.27,160.58) v2(47.28,82.56) v2(47.23,25.16) v2(47.81,31.71) v2(47.84,25.15) v2(48.19,170.12) v2(48.19,169) v2(48.19,167.88) v2(48.42,31.72) v2(48.45,25.16) v2(48.53,1.68) v2(49.03,31.71) v2(49.06,25.15) v2(49.16,179.75) v2(49.31,170.12) v2(49.31,169) v2(49.31,167.88) v2(49.33,37.43) v2(49.33,36.82) v2(49.33,36.19) v2(49.33,35.56) v2(49.66,31.72) v2(49.7,25.16) v2(50.27,31.71) v2(50.31,25.15) v2(50.42,170.12) v2(50.42,169) v2(50.42,167.88) v2(51.07,165.57) v2(52.64,32.41) v2(52.64,31.8) v2(52.66,31.19) v2(52.91,165.57) v2(53.65,160.58) v2(54.9,82.56) v2(55.05,50.67) v2(55.05,50.04) v2(55.05,49.4) v2(55.3,1.68) v2(55.46,166.52) v2(55.44,165.43) v2(55.68,50.67) v2(55.68,50.04) v2(55.68,49.4) v2(55.64,48.77) v2(55.78,163.25) v2(55.92,179.75) v2(56.13,170.81) v2(56.13,66.55) v2(56.13,65.98) v2(56.29,164.75) v2(56.28,48.77) v2(56.32,50.67) v2(56.32,50.04) v2(56.32,49.4) v2(56.44,171.32) v2(56.76,66.55) v2(56.76,65.98) v2(56.85,48.77) v2(56.95,50.67) v2(56.95,50.04) v2(56.95,49.4) v2(56.95,41.21) v2(56.95,40.58) v2(57.4,66.55) v2(57.4,65.98) v2(57.46,47.8) v2(57.59,50.67) v2(57.59,50.04) v2(57.59,49.4) v2(57.59,41.21) v2(57.59,40.58) v2(57.91,33.91) v2(57.91,33.27) v2(58.1,47.8) v2(58.01,20.93) v2(58.22,50.67) v2(58.22,50.04) v2(58.22,49.4) v2(58.63,21.55) v2(58.63,20.31) v2(58.73,47.8) v2(58.73,24.83) v2(59.18,18.54) v2(59.25,20.93) v2(59.46,49.3) v2(59.46,47.88) v2(59.58,70.1) v2(59.58,69.47) v2(59.58,68.83) v2(59.58,68.2) v2(59.58,67.56) v2(59.58,66.93) v2(59.62,18.16) v2(60.42,49.3) v2(60.42,47.88) v2(61.26,42.34) v2(61.26,41.76) v2(61.38,49.3) v2(61.38,47.88) v2(61.54,42.86) v2(61.83,42.34) v2(61.83,41.76) v2(62.06,1.68) v2(62.13,42.88) v2(62.35,29.92) v2(62.4,42.34) v2(62.4,41.76) v2(62.69,179.75) v2(63.37,23.94) v2(63.37,23.24) v2(63.37,21.97) v2(63.37,21.27) v2(63.51,43.01) v2(63.51,42.43) v2(63.7,49.9) v2(63.7,49.26) v2(63.7,48.63) v2(63.7,47.99) v2(63.71,47.28) v2(64.08,43.01) v2(64.08,42.43) v2(64.29,49.91) v2(64.29,49.28) v2(64.29,48.64) v2(64.29,48.01) v2(64.29,47.29) v2(64.65,43.01) v2(64.65,42.43) v2(64.7,84.14) v2(65.23,43.05) v2(65.23,42.47) v2(65.87,43.69) v2(65.8,43.05) v2(65.8,42.47) v2(66.38,43.05) v2(66.38,42.47) v2(66.51,43.69) v2(67,42.55) v2(67,41.14) v2(66.92,34.19) v2(67.49,34.19) v2(67.96,42.55) v2(67.96,41.14) v2(68.05,157.82) v2(68.83,1.68) v2(68.92,42.55) v2(68.92,41.14) v2(69.06,62.22) v2(69.06,61.59) v2(69.08,59.24) v2(69.08,58.6) v2(69.02,14.54) v2(69.02,13.91) v2(69.46,179.75) v2(69.77,41.15) v2(69.72,14.54) v2(69.72,13.91) v2(69.89,62.22) v2(69.89,61.59) v2(69.9,59.24) v2(69.9,58.6) v2(70.41,21.72) v2(70.41,21.02) v2(70.41,14.54) v2(70.41,13.91) v2(70.54,41.1) v2(70.71,62.22) v2(70.71,61.59) v2(70.73,59.24) v2(70.73,58.6) v2(70.92,22.03) v2(70.92,21.4) v2(71.05,15.11) v2(71.05,14.54) v2(71.05,13.91) v2(71.25,42.94) v2(71.25,42.3) v2(71.25,41.6) v2(71.25,41.03) v2(71.75,15.11) v2(71.75,14.54) v2(71.75,13.91) v2(71.84,42.94) v2(71.84,42.3) v2(71.84,41.6) v2(71.84,41.03) v2(73.65,88.07) v2(74.07,154.81) v2(74.17,179.55) v2(75.05,23.3) v2(75.05,22.67) v2(75.05,21.97) v2(75.05,21.34) v2(75.05,20.64) v2(75.05,20.07) v2(75.6,1.68) v2(76.38,178.08) v2(76.51,41.66) v2(76.51,41.02) v2(76.51,40.39) v2(76.51,39.75) v2(76.51,39.12) v2(76.51,38.48) v2(76.51,37.85) v2(76.64,44.2) v2(78.99,91.88) v2(79.32,35.19) v2(79.32,33.92) v2(79.32,32.65) v2(79.47,150.8) v2(80.98,177.77) v2(82.04,35.18) v2(82.04,33.91) v2(82.04,32.7) v2(82.37,1.68) v2(82.86,95.69) v2(83.31,23.24) v2(83.31,22.61) v2(83.31,21.97) v2(83.31,21.34) v2(83.31,20.64) v2(83.31,20) v2(83.8,100.44) v2(84.11,145.93) v2(84.26,35.94) v2(84.26,34.67) v2(84.26,33.4) v2(84.44,177.77) v2(85.53,34.35) v2(85.53,32.45) v2(85.83,103.87) v2(86.8,35.94) v2(86.8,34.67) v2(86.8,33.4) v2(87.25,20.93) v2(87.25,19.66) v2(87.25,18.39) v2(87.85,140.33) v2(88.5,109.78) v2(88.98,177.75) v2(89.08,35.31) v2(89.08,34.04) v2(89.08,32.77) v2(89.03,20.61) v2(89.03,18.71) v2(89.14,1.68) v2(90.09,115.9) v2(90.35,35.69) v2(90.35,33.72) v2(90.56,134.18) v2(91.07,20.93) v2(91.07,19.66) v2(91.07,18.39) v2(91.22,156.49) v2(91.59,157.34) v2(92,35.31) v2(92,34.04) v2(92,32.77) v2(92.28,80.37) v2(92.65,122.54) v2(92.74,157.4) v2(93.49,21.16) v2(93.49,19.89) v2(93.49,18.62) v2(93.85,79.77) v2(93.96,177.75) v2(94.1,35.37) v2(94.1,34.1) v2(94.1,32.83) v2(94.54,128.47) v2(94.94,20.78) v2(94.94,18.88) v2(95.38,35.56) v2(95.43,33.59) v2(95.6,130.3) v2(95.6,126.64) v2(96.37,86.58) v2(96.68,21.16) v2(96.68,19.89) v2(96.68,18.62) v2(97.52,0.51) v2(97.69,177.75) v2(97.7,130.3) v2(97.7,126.64) v2(97.92,35.33) v2(97.92,34.06) v2(97.92,32.79) v2(98.76,128.47) v2(98.93,154.05) v2(98.93,153.48) v2(98.93,152.91) v2(98.93,152.27) v2(99.2,20.97) v2(99.2,19.7) v2(99.2,18.43) v2(99.5,153.67) v2(99.5,153.03) v2(99.5,152.4) v2(100.06,153.03) v2(100.63,154.15) v2(100.69,144.58) v2(100.67,21.29) v2(100.67,19.38) v2(100.77,84.57) v2(101.4,84.58) v2(101.66,142.88) v2(101.86,140.41) v2(101.86,139.47) v2(101.86,138.86) v2(102.24,177.75) v2(102.3,68.3) v2(102.29,36.95) v2(102.29,35.68) v2(102.28,20.97) v2(102.28,19.7) v2(102.28,18.43) v2(104.09,0.51) v2(104.27,36.25) v2(104.27,34.98) v2(104.27,32.44) v2(104.32,33.72) v2(104.46,114.34) v2(104.42,21.04) v2(104.42,19.77) v2(104.42,18.5) v2(104.76,105.26) v2(105.08,114.33) v2(105.09,113.66) v2(105.39,105.26) v2(105.64,21.23) v2(105.64,19.33) v2(106.1,152.83) v2(107.18,36.89) v2(107.18,35.62) v2(107.12,34.35) v2(107.18,33.08) v2(107.29,104.81) v2(107.67,105.24) v2(107.79,21) v2(107.79,19.73) v2(107.79,18.46) v2(108.05,104.81) v2(108.12,89.88) v2(108.29,69.39) v2(108.64,84.57) v2(108.88,159.72) v2(108.88,157.53) v2(108.95,98.79) v2(108.96,88.96) v2(109.09,36.89) v2(109.09,35.62) v2(109.09,34.35) v2(109.18,152.04) v2(109.28,123.25) v2(109.28,122.62) v2(109.28,121.92) v2(109.28,121.28) v2(109.28,120.65) v2(109.25,119.18) v2(109.28,118.36) v2(109.56,88.95) v2(109.7,84.61) v2(109.76,97.63) v2(109.98,158.62) v2(109.91,123.25) v2(109.91,122.62) v2(109.91,121.92) v2(109.91,121.28) v2(109.91,120.65) v2(109.91,120.08) v2(109.91,119.51) v2(109.91,118.94) v2(109.91,118.36) v2(110.05,179.75) v2(110.14,88.98) v2(110.36,70.22) v2(110.5,84.59) v2(110.7,104.99) v2(110.66,89.88) v2(110.65,0.51) v2(111.07,159.72) v2(111.07,157.53) v2(111.01,22.56) v2(111.01,21.29) v2(111.16,85.57) v2(111.11,36.89) v2(111.11,35.62) v2(111.11,34.35) v2(111.93,89.88) v2(111.93,85.12) v2(112.2,86.12) v2(112.21,86.87) v2(112.41,125.45) v2(112.41,124.03) v2(112.5,78.17) v2(112.88,21.92) v2(112.88,20.65) v2(112.88,19.38) v2(112.88,18.11) v2(113.18,70.94) v2(113.18,69.11) v2(113.37,125.45) v2(113.37,124.03) v2(114.21,37.23) v2(114.21,35.3) v2(114.21,33.42) v2(114.34,125.45) v2(114.34,124.03) v2(114.93,141.6) v2(114.93,140.08) v2(114.93,138.56) v2(115.07,124.71) v2(115.07,124.08) v2(115.07,123.44) v2(115.44,71.45) v2(115.55,100.73) v2(115.64,124.71) v2(115.64,124.08) v2(115.78,22.56) v2(115.78,21.29) v2(115.78,20.02) v2(115.78,18.75) v2(115.87,35.75) v2(115.87,34.48) v2(115.87,33.21) v2(115.94,126.3) v2(116.21,124.71) v2(116.21,124.08) v2(116.45,141.6) v2(116.45,140.08) v2(116.45,138.56) v2(116.52,126.3) v2(116.78,124.71) v2(116.78,124.08) v2(116.78,123.51) v2(116.82,179.75) v2(117.17,71.33) v2(117.16,69.52) v2(117.22,0.51) v2(117.5,35.11) v2(117.5,33.84) v2(117.6,29.4) v2(117.68,22.43) v2(117.68,21.16) v2(117.68,19.89) v2(117.98,141.6) v2(117.98,140.08) v2(117.98,138.56) v2(118.59,113.79) v2(118.59,113.22) v2(118.59,112.59) v2(118.59,112.01) v2(118.59,111.38) v2(118.71,69.45) v2(118.8,71.31) v2(119.59,29.49) v2(119.71,22.56) v2(119.71,21.29) v2(119.71,20.02) v2(119.96,35.49) v2(119.96,34.22) v2(119.96,32.95) v2(120.01,150.11) v2(120.14,32.07) v2(120.58,70.21) v2(120.59,68.38) v2(120.57,66.62) v2(120.64,150.11) v2(121.4,34.92) v2(121.4,33.65) v2(121.36,32.2) v2(121.55,86.36) v2(121.55,85.72) v2(121.55,85.09) v2(121.55,84.45) v2(121.55,83.82) v2(122.07,126.81) v2(122.1,131.06) v2(122.36,84.07) v2(122.33,70.38) v2(122.32,68.44) v2(122.93,113.16) v2(122.93,112.59) v2(122.93,112.01) v2(122.93,111.44) v2(122.94,89.49) v2(122.94,88.32) v2(122.94,87.05) v2(122.94,85.81) v2(122.94,84.56) v2(123.03,22.88) v2(123.03,20.97) v2(123.03,19.07) v2(123.45,126.31) v2(123.45,125.76) v2(123.45,125.2) v2(123.45,124.64) v2(123.59,179.75) v2(123.5,130.94) v2(123.5,113.54) v2(123.78,0.51) v2(123.99,70.73) v2(123.95,36.51) v2(123.94,35.24) v2(123.94,33.97) v2(124.07,130.94) v2(124.02,126.31) v2(124.02,125.76) v2(124.02,125.2) v2(124.03,124.64) v2(124.5,21.42) v2(124.5,20.15) v2(124.5,18.88) v2(124.64,158.75) v2(125.22,158.75) v2(125.3,87.43) v2(125.47,158.24) v2(125.47,157.61) v2(125.47,156.97) v2(125.47,156.34) v2(125.47,155.7) v2(125.47,155.07) v2(125.47,153.03) v2(125.53,112.14) v2(125.6,37.47) v2(125.58,35.56) v2(126.04,158.5) v2(126.1,112.14) v2(126.1,20.78) v2(126.1,19.51) v2(126.93,36.51) v2(126.99,35.24) v2(126.99,33.97) v2(126.97,32.46) v2(126.91,23.32) v2(126.91,22.05) v2(128.56,21.16) v2(128.56,19.89) v2(128.56,18.62) v2(128.66,102.53) v2(129.38,137.91) v2(129.34,101.41) v2(129.6,36.51) v2(129.6,35.24) v2(129.6,33.97) v2(129.91,135.51) v2(130.04,20.59) v2(130.04,19.32) v2(130.1,140.65) v2(130.16,103.12) v2(130.35,179.75) v2(130.34,0.51) v2(130.8,130.81) v2(130.8,130.24) v2(130.8,129.67) v2(130.8,129.1) v2(131.02,124.55) v2(131.12,135) v2(131.15,126.9) v2(131.25,34.92) v2(131.25,33.02) v2(131.31,135.57) v2(131.37,130.81) v2(131.37,130.24) v2(131.37,129.67) v2(131.37,129.1) v2(131.56,105.03) v2(131.76,135) v2(131.76,134.43) v2(131.82,164.91) v2(131.88,135.57) v2(131.86,116.76) v2(131.95,130.81) v2(131.95,130.24) v2(131.95,129.67) v2(131.95,129.1) v2(132.15,181.46) v2(132.36,22.18) v2(132.36,20.91) v2(132.36,19.64) v2(132.45,164.91) v2(132.45,135.57) v2(132.47,116.75) v2(132.65,100.84) v2(132.64,36.51) v2(132.64,35.24) v2(132.64,33.97) v2(133.1,116.78) v2(133.53,164.91) v2(133.77,115.99) v2(133.76,114.69) v2(133.98,152.15) v2(134.17,164.91) v2(134.12,23.13) v2(134.12,21.23) v2(134.42,146.11) v2(134.42,145.48) v2(134.42,144.78) v2(134.99,146.11) v2(135.12,35.75) v2(135.12,34.54) v2(135.12,33.21) v2(135.49,106.07) v2(135.59,22.18) v2(135.59,20.91) v2(135.59,19.64) v2(135.78,121.19) v2(135.82,123.44) v2(135.82,122.49) v2(136.15,120.75) v2(136.12,106.07) v2(136.49,121.22) v2(136.85,120.74) v2(136.84,36.77) v2(136.9,34.8) v2(136.91,0.51) v2(137.39,106.07) v2(137.41,146.11) v2(137.41,145.54) v2(138.17,35.81) v2(138.13,20.91) v2(138.13,19.64) v2(138.3,161.23) v2(138.3,160.46) v2(138.3,159.51) v2(138.3,158.75) v2(138.23,34.48) v2(138.23,33.21) v2(138.88,181.46) v2(139.48,86.19) v2(139.84,165.77) v2(139.84,20.59) v2(139.84,18.69) v2(140.64,36.28) v2(140.64,35.05) v2(140.64,33.72) v2(140.77,122.81) v2(140.95,167.68) v2(140.94,163.86) v2(141.3,22.18) v2(141.3,20.91) v2(141.3,19.64) v2(141.6,140.84) v2(141.79,115.32) v2(141.79,114.68) v2(141.85,155.77) v2(141.9,142.03) v2(141.98,35.88) v2(141.98,33.97) v2(142.61,155.77) v2(143.02,142.26) v2(143.16,167.68) v2(143.15,163.86) v2(143.38,155.77) v2(143.35,21.44) v2(143.35,20.17) v2(143.35,18.9) v2(143.44,36.32) v2(143.44,34.99) v2(143.44,33.72) v2(143.47,0.51) v2(143.7,77.55) v2(144.26,165.77) v2(144.28,138.33) v2(145.09,140.59) v2(145.53,21.64) v2(145.53,19.73) v2(145.62,181.46) v2(145.88,143.93) v2(147.18,21.44) v2(147.18,20.17) v2(147.18,18.9) v2(148.71,143.57) v2(149.13,21.94) v2(149.13,20.67) v2(149.13,19.4) v2(149.98,145.67) v2(150.04,0.51) v2(150.33,68.78) v2(151,178.37) v2(151,177.67) v2(151.05,75.39) v2(151.17,21.64) v2(151.17,19.73) v2(151.82,178.37) v2(151.82,177.67) v2(151.85,101.17) v2(152.13,97.97) v2(152.14,60.97) v2(152.65,178.37) v2(152.65,177.67) v2(152.65,22.12) v2(152.65,20.85) v2(152.65,19.52) v2(153.2,62.8) v2(153.2,59.14) v2(153.47,178.37) v2(153.47,177.67) v2(153.63,32) v2(153.61,31.31) v2(154.36,178.37) v2(154.36,177.67) v2(154.98,97.42) v2(155.3,62.8) v2(155.3,59.14) v2(155.49,30.48) v2(156.36,60.97) v2(156.68,74.2) v2(156.6,0.51) v2(157.37,97.6) v2(157.38,94.79) v2(157.84,108.46) v2(157.84,106.94) v2(157.84,105.42) v2(158.3,24.38) v2(158.3,23.75) v2(158.3,23.11) v2(158.87,50.16) v2(159.08,181.46) v2(159.36,108.46) v2(159.36,106.94) v2(159.36,105.42) v2(159.72,121.62) v2(159.95,123.95) v2(160.36,47.9) v2(160.89,108.46) v2(160.89,106.94) v2(160.89,105.42) v2(161.09,13.72) v2(161.41,13.14) v2(161.73,64.71) v2(161.79,13.72) v2(162.43,101.6) v2(162.87,102.04) v2(162.87,101.09) v2(163.17,0.51) v2(163.32,101.54) v2(163.44,100.65) v2(163.82,101.16) v2(163.89,100.2) v2(164.27,100.71) v2(164.33,99.76) v2(164.76,102.88) v2(164.78,100.27) v2(165.16,99.76) v2(165.33,102.86) v2(165.33,102.29) v2(165.54,122.43) v2(165.73,106.43) v2(165.84,102.54) v2(165.89,101.93) v2(166.02,77.72) v2(166.13,148.27) v2(166.15,122.61) v2(166.36,106.43) v2(166.49,109.03) v2(166.49,108.39) v2(166.45,104.77) v2(166.45,104.14) v2(166.55,101.98) v2(166.55,101.35) v2(167,106.43) v2(167.06,109.03) v2(167.06,108.39) v2(167.09,104.77) v2(167.09,104.14) v2(167.09,103.5) v2(167.17,101.94) v2(167.19,101.28) v2(167.19,100.65) v2(167.38,67.31) v2(167.54,12.77) v2(167.7,109.03) v2(167.7,108.39) v2(167.7,106.43) v2(167.72,104.77) v2(167.72,104.14) v2(167.72,103.5) v2(167.76,101.94) v2(167.76,101.28) v2(167.76,100.65) v2(168.33,109.66) v2(168.33,109.03) v2(168.33,108.39) v2(168.33,106.43) v2(168.36,104.77) v2(168.36,104.14) v2(168.36,103.5) v2(168.33,101.28) v2(168.33,100.65) v2(168.6,14.6) v2(168.6,10.94) v2(168.89,97.09) v2(169.73,0.51) v2(169.89,88.62) v2(169.92,25.69) v2(170.55,25.72) v2(170.55,25.15) v2(170.55,24.51) v2(170.68,80) v2(170.77,87.54) v2(170.7,14.6) v2(170.7,10.94) v2(171.28,81.26) v2(171.27,25.73) v2(171.27,24.43) v2(171.68,82.65) v2(171.76,12.77) v2(172.33,25.08) v2(172.55,181.46) v2(173.4,25.73) v2(173.4,24.43) v2(173.98,25.21) v2(175.93,138.71) v2(176.29,0.51) v2(176.33,38.21) v2(177.38,90.81) v2(177.7,39.2) v2(177.86,34.16) v2(177.86,33.53) v2(177.86,32.89) v2(177.86,32.26) v2(177.86,31.62) v2(177.86,30.99) v2(179.28,181.46) v2(180.33,41.97) v2(180.82,79.85) v2(181.16,39.5) v2(181.16,38.8) v2(181.6,18.25) v2(181.6,16.29) v2(181.6,14.32) v2(182.17,34.1) v2(182.43,33.02) v2(182.86,0.51) v2(183.57,18.25) v2(183.57,16.29) v2(183.57,14.32) v2(183.64,39.5) v2(184.27,39.5) v2(184.91,39.5) v2(184.95,7.07) v2(185.54,18.25) v2(185.54,16.29) v2(185.54,14.32) v2(185.59,7.07) v2(186.02,181.46) v2(188.27,39.81) v2(188.27,38.99) v2(189.42,0.51) v2(190.43,115.62) v2(190.43,114.49) v2(190.81,119.25) v2(190.87,57.15) v2(190.91,44.29) v2(191.06,55.5) v2(191.67,8.1) v2(191.83,119.25) v2(192.75,181.46) v2(193.09,37.28) v2(193.25,115.62) v2(194.07,14.27) v2(194.29,13.31) v2(194.55,179.75) v2(194.7,8.62) v2(194.9,49.37) v2(195.87,110.08) v2(195.99,0.51) v2(196.02,102.81) v2(196.02,102.17) v2(196.02,101.47) v2(196.02,100.84) v2(196.02,100.2) v2(196.02,99.57) v2(196.02,96.96) v2(196.02,96.33) v2(196.02,95.69) v2(196.02,95) v2(196.53,109.85) v2(196.53,109.22) v2(196.53,108.58) v2(196.53,107.95) v2(196.53,103.12) v2(196.53,102.49) v2(196.53,101.85) v2(196.53,101.16) v2(196.53,100.52) v2(196.53,99.89) v2(196.53,99.25) v2(196.55,98.6) v2(196.53,97.28) v2(196.53,96.65) v2(196.53,96.01) v2(196.53,95.38) v2(197.64,56.27) v2(198.37,110.36) v2(198.37,103.19) v2(198.37,96.03) v2(198.37,88.86) v2(198.37,81.24) v2(198.37,73.62) v2(198.37,67.18) v2(198.75,58.18) v2(198.74,54.36) v2(199.29,127.78) v2(199.51,66.36) v2(200.15,169.04) v2(200.96,58.18) v2(200.95,54.36) v2(202.06,56.27) v2(202.91,0.67) v2(203.04,65.86) v2(203.04,59.88) v2(203.04,52.38) v2(203.04,46.4) v2(203.04,39.92) v2(203.04,33.43) v2(203.04,26.94) v2(203.04,20.46) v2(203.04,13.97) v2(203.04,7.49) v2(203.55,179.75) v2(204.04,179.26) v2(204.04,172.12) v2(204.04,162.03) v2(204.02,152.15) v2(204.02,144.53) v2(204.02,136.91) v2(204.02,129.29) v3(17.21,31.99) v3(17.79,69.72) v3(18.4,42.44) v3(20.25,74.17) v3(34.09,43.69) v3(34.14,40.06) v3(35.19,29.82) v3(45.83,43.68) v3(49.76,26.3) v3(62.31,49.82) v3(64.27,33.81) v3(68.64,43.43) v3(96.93,153.92) v3(103.13,141.5) v3(108.07,119.23) v3(118.19,124.05) v3(118.55,124.08) v3(122.57,125.68) v3(124.1,131.78) v3(126.51,159.55) v3(129.47,136.72) v3(130.44,128.33) v3(131.79,114.74) v3(132.99,135.17) v3(135.3,165.54) v3(136,145.06) v3(157.05,140.65) v3(157.24,107.68) v3(162.02,9.84) v3(162.55,13.33) v3(165.03,101.14) v3(165.31,101.12) v3(165.55,107.54) v3(166.26,121.15) v3(167.06,107.19) v3(182.61,39.03) v3(182.7,17.3) v3(188.03,12.78) v3(193.25,8.15) v3(195,12.73) v3(196.28,105.11)
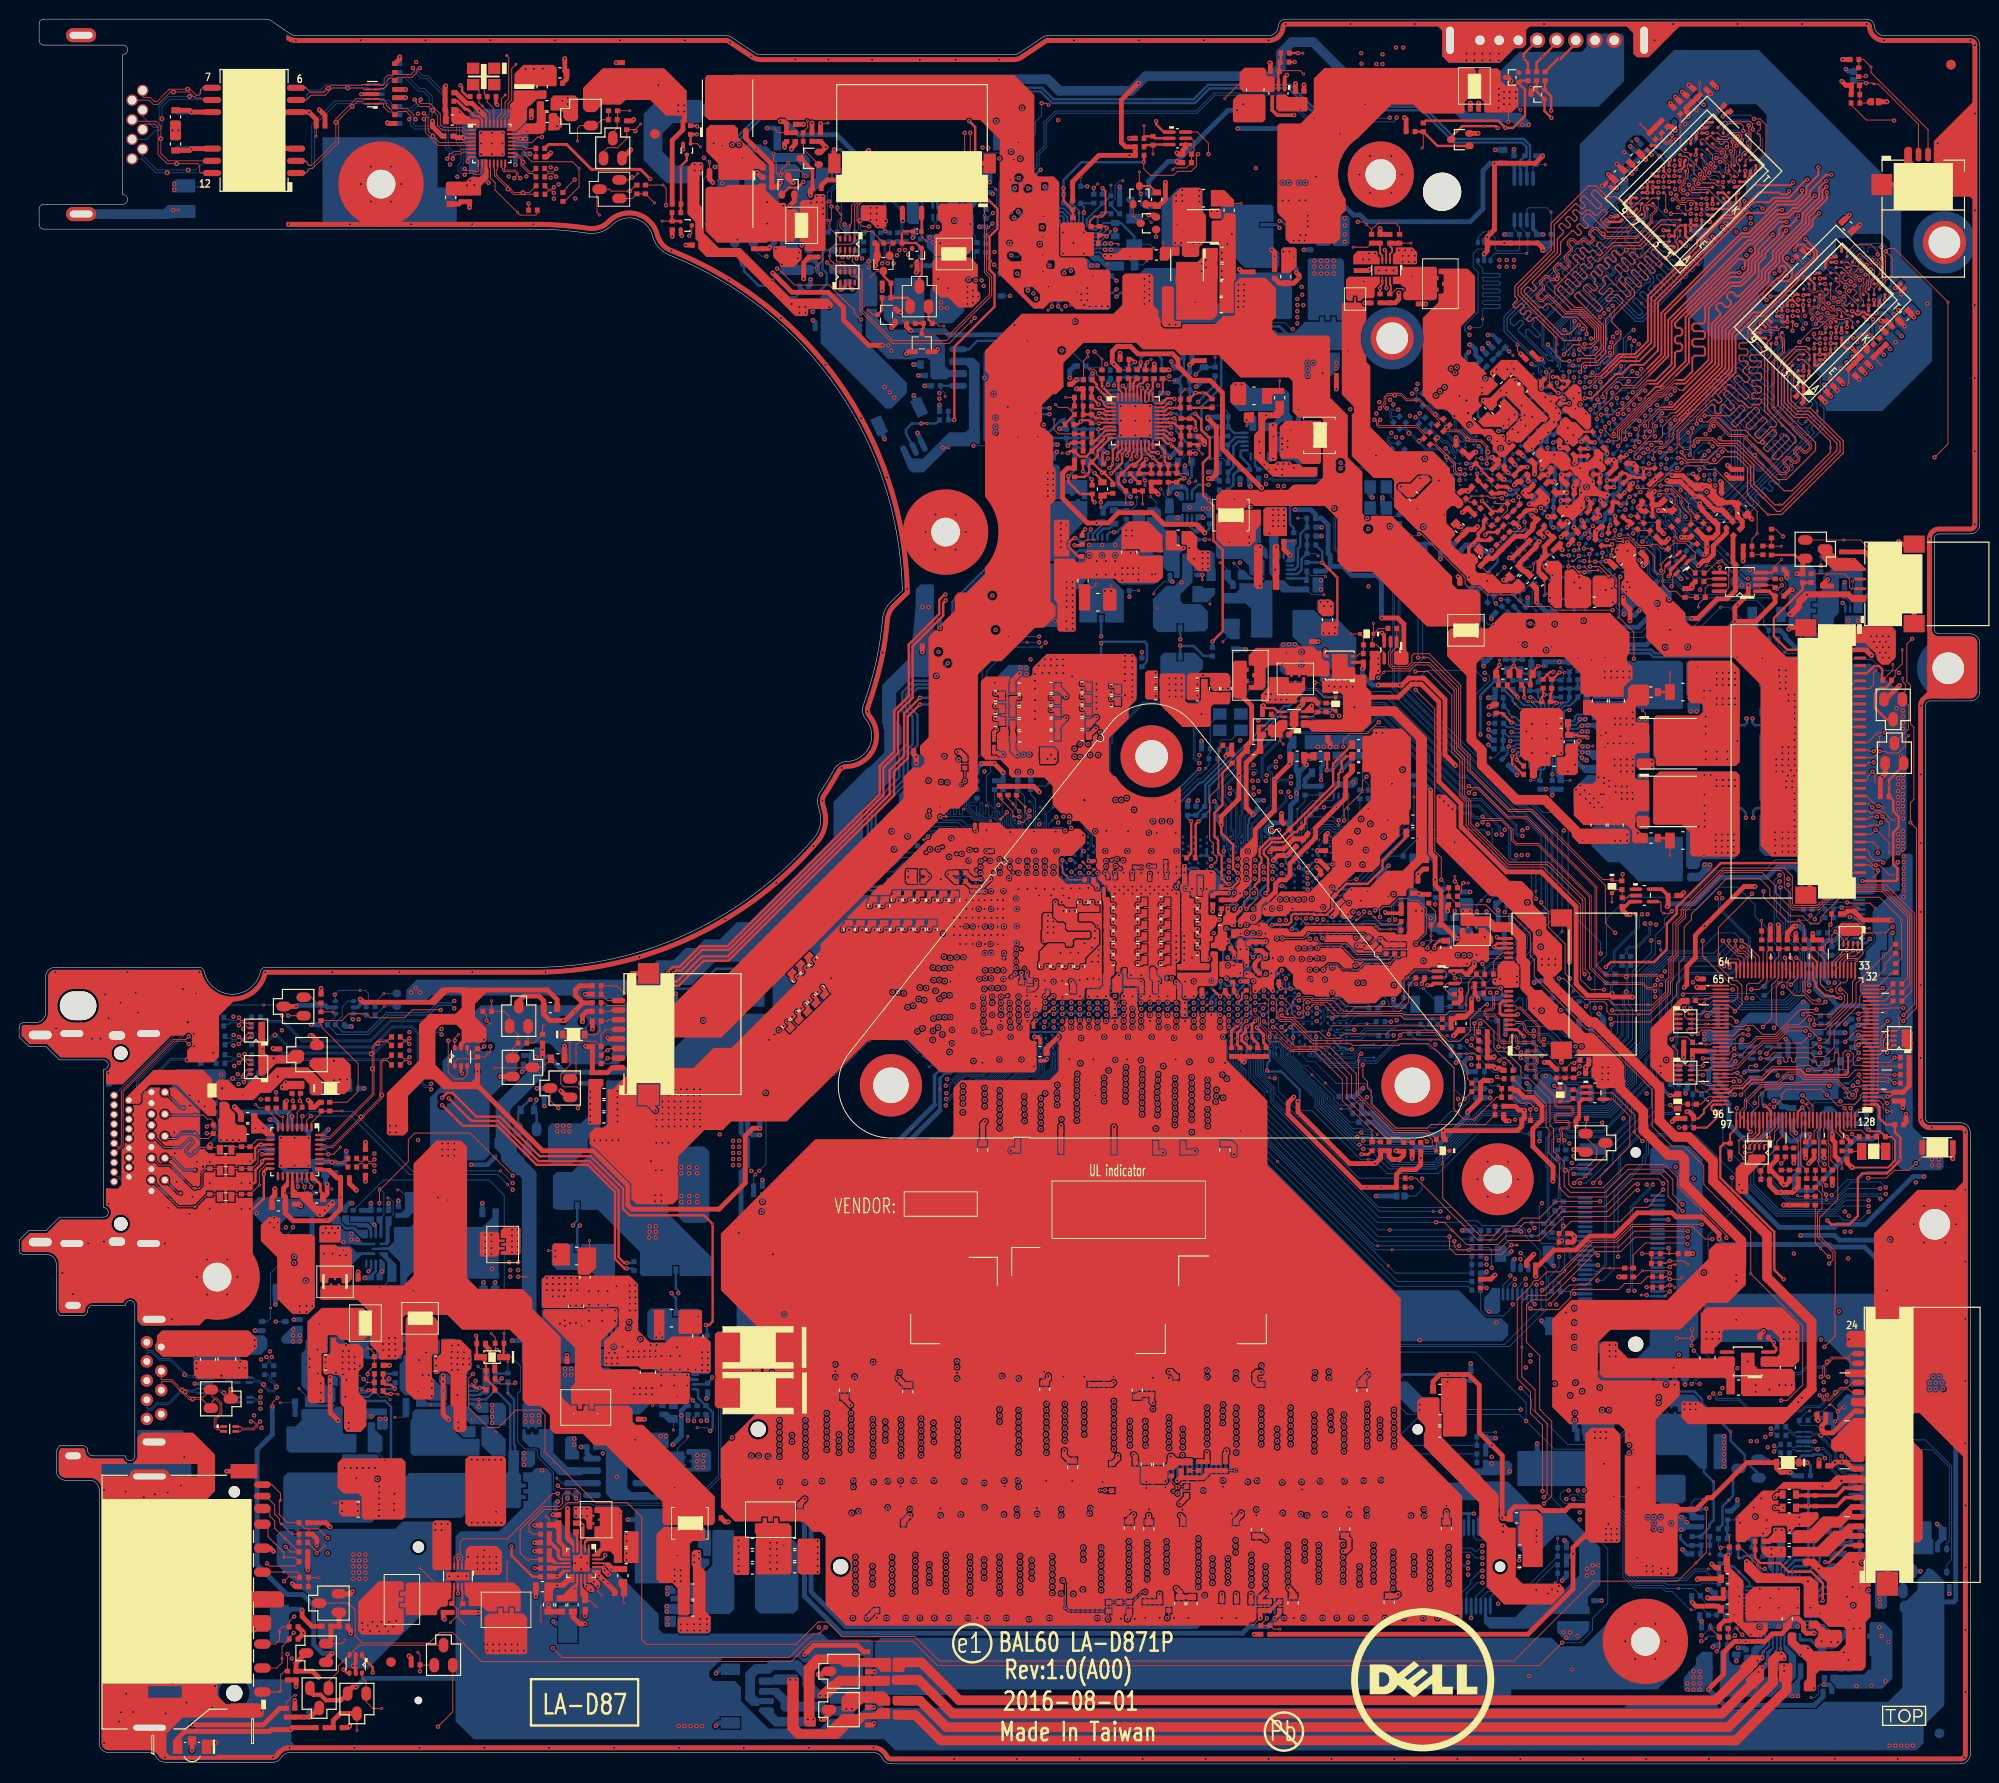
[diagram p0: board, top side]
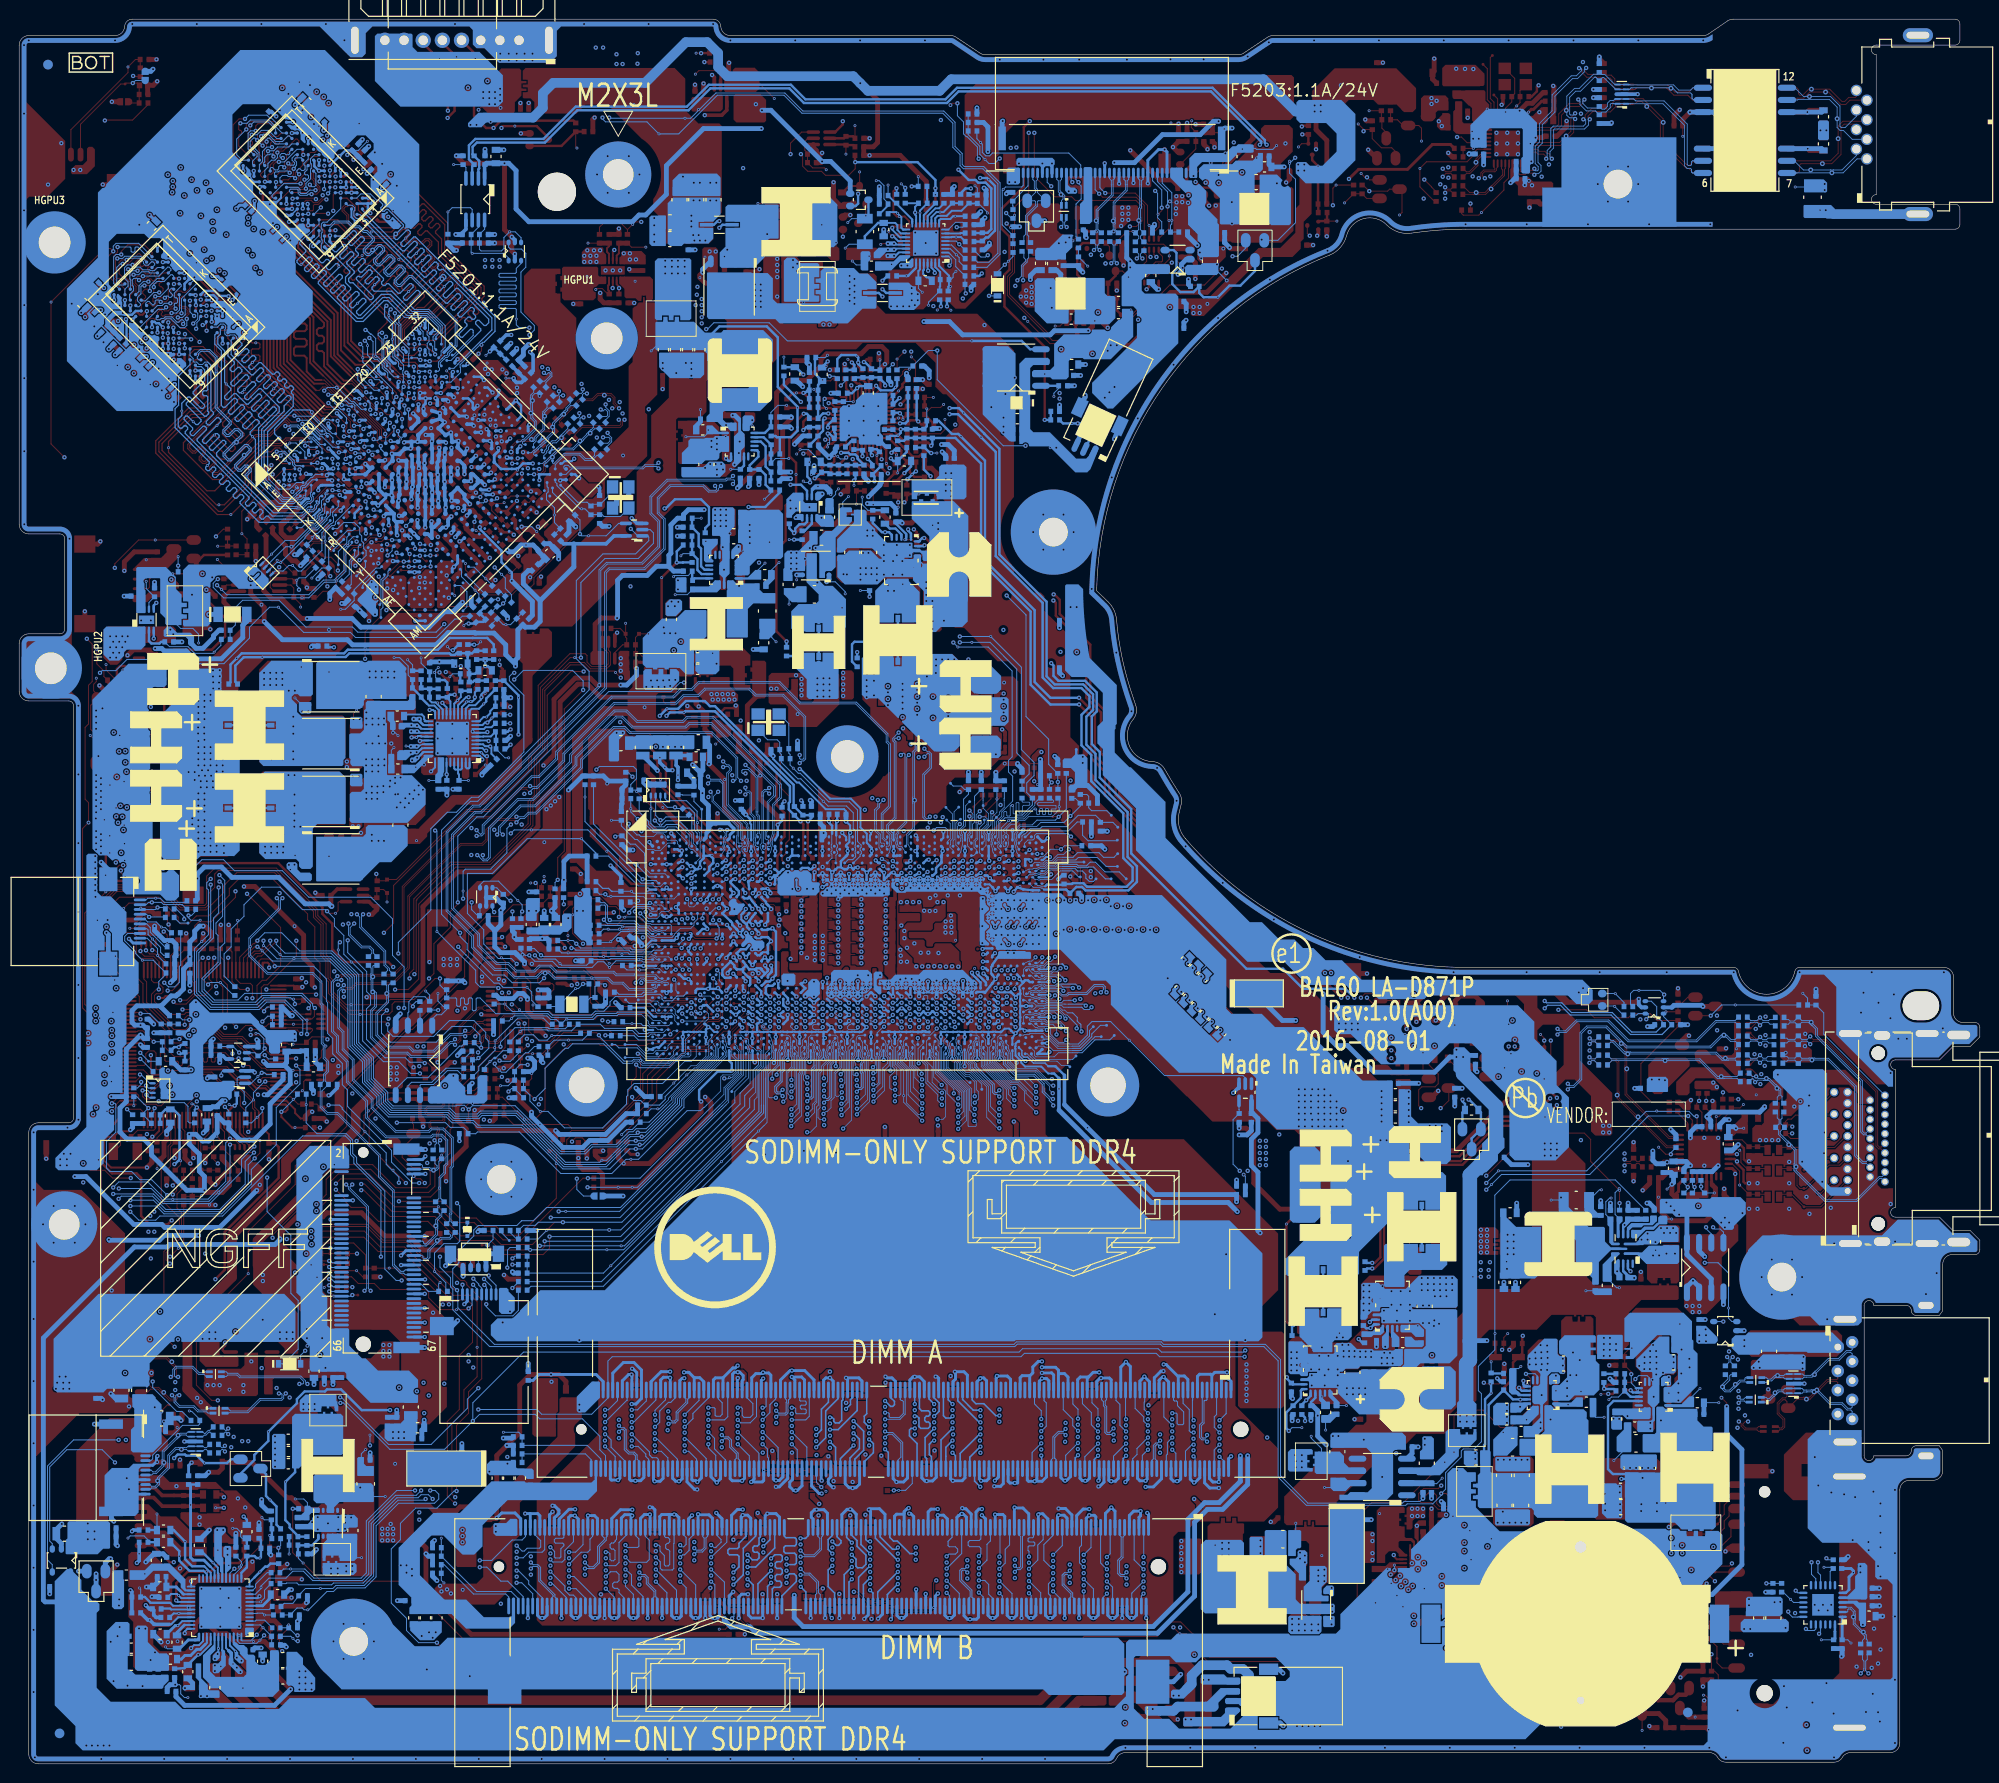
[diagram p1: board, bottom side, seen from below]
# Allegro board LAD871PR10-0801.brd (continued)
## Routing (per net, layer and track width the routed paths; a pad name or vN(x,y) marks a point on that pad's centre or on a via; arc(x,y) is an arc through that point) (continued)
GND_R1: length 6.6
  TOP w0.508: R6301.2 188.47,35.69 188.07,35.28 v1(188.07,35.08) 188.07,34.84 188.39,34.52 189.21,34.52 191.46,36.77 CN6301.16
GND_R2: length 3.6
  TOP w0.508: CN6301.10 191.33,30.77 190.63,31.47 v3(190.15,31.47) 189.49,31.47 189.1,31.08 R6302.2
GNDA: length 24.1
  TOP w0.508: CN6301.9 190.23,29.77 AFTP6313.1 ; v2(191.38,14.1) 190.76,14.55 189.03,14.55 ; v2(187.76,20.38) 187.01,21.13 EC2905.2 ; v2(186.62,12.06) 185.81,12.06 184.79,13.08 ; EC2907.2 R2919.2 ; v2(180.22,21.08) 180.22,20.45 ; EC2908.2 R2920.2
  BOTTOM w0.203: HDA27.38 185.37,12.8 185.79,12.38 186.3,12.38 v2(186.62,12.06) ; v2(186.62,19.05) HDA27.25
  BOTTOM w0.508: C2705.1 190.02,17.43 v2(190.7,17.43) ; v2(179.53,25.15) C2901.2 ; C2713.2 185.64,23.46 v2(184.71,24.38) ; v2(191.34,21.05) 190.48,21.91 C2711.2 189.53,21.91 C2710.2 ; R2711.1 190.15,18.88 C2702.1 v2(191.28,18.45) ; v2(187.25,7.9) 187.19,7.97 EC2703.1 186.46,8.42 C2715.2 ; R2707.2 v2(181.94,24.05)
  vias: v2(180.97,26.73) v2(181.73,27.69) v2(185.73,25.72) v2(185.73,24.96) v2(188.14,28.96) v2(190.38,11.63) v2(190.84,10.83) v2(192.04,14.12) v3(182.33,25.43) v3(186.87,16.28)
V3D3_STB: length 12.5
  BOTTOM w0.203: HDA27.20 184.17,20.14 184.59,20.56
  BOTTOM w0.254: R2713.1 R2712.1
  BOTTOM w0.305: 184.59,20.56 185.27,21.24 186.39,21.24 186.67,21.52 v1(186.67,27) 186.67,28.93 R2712.1
V18: length 2.9
  BOTTOM w0.102: v1(16.54,12.93) C3201.2
  BOTTOM w0.254: U3201.24 15.11,13.8 15.12,13.79
  BOTTOM w0.305: C3201.2 15.12,13.07 15.12,13.79
VCC_EDRAM_SENSE: length 1.5
  TOP w0.076: T4951.1 v2(104.04,84.99)
  BOTTOM w0.254: v2(104.04,84.99) 103.98,85.05 UC1.AC63
VCC_GT_SENSE: length 79.6
  TOP w0.254: PR622.1 111.59,140.13 110.87,140.13 v2(110.75,140.01) 110.44,139.7 PC617.1
  IN2 w0.254: v2(107.48,140.77) 110.26,140.77 110.75,140.27 v2(110.75,140.01)
  BOTTOM w0.076: 97.5,91.54 97.94,91.54 98.06,91.59 98.27,91.59 UC1.J70
  BOTTOM w0.254: PC618.2 110.93,142.59 PC620.1 110.92,140.18 v2(110.75,140.01) ; 97.5,91.54 97.34,91.69 95.62,91.69 RC161.2 94.72,91.77 94.65,91.84 93.51,91.84 93.15,91.48 89.02,91.48 88.39,92.11 88.39,93.5 89.36,94.47 89.36,99.15 92.7,102.49 92.7,105.22 93.72,106.24 93.72,109.41 92.89,110.24 92.89,111.37 93.73,112.2 96.67,112.2 97.77,113.3 97.77,121.08 102.67,125.98 102.67,136.84 v1(104.2,138.37) 106.6,140.77 v2(107.48,140.77)
VCCEOPIO_SENSE: length 1.6
  TOP w0.076: v2(102.43,80.01) 103.03,80.01 T4954.1
  BOTTOM w0.089: v2(102.43,80.01) UC1.AL63
VCCIO_SENSE: length 1.8
  TOP w0.076: v2(124.37,79.4) 124.19,79.4 T4947.1
  BOTTOM w0.254: UC1.AM23 124.83,80.34 124.34,79.85 124.34,79.45 124.37,79.41 v2(124.37,79.4)
VCCK_12: length 14.4
  TOP w0.508: 32.4,61.88 33.16,61.12 C5501.1 v1(33.53,59.11) 33.53,57.86 32.31,56.64 28.58,56.64 27.76,57.46 C5504.1 27.76,59.16 C5503.1 27.59,60.05 27.89,60.36
VCCSA_B+: length 1.7
  BOTTOM w0.102: v1(118.04,132.17) 118.62,131.58 118.62,130.75
  vias: v2(121.46,126.81)
VCCSENSE: length 51.3
  TOP w0.254: v2(117.59,136.08) 117.59,136.01 117.25,135.67 PR648.1 116.82,135.03 PC639.1 116.84,134.59 PC651.2 118.09,134.6 PC653.1
  IN1 w0.254: v2(120.07,98.31) 120.07,98.98 120.31,99.21 120.31,101.16 122.33,103.17 122.33,106.95 118.06,111.22 118.06,121 118.74,121.68 118.74,131.43 119.33,132.02 119.33,133.04 118.77,133.6 118.77,134.53 117.59,135.71 v2(117.59,136.08)
  BOTTOM w0.089: 119.74,97.01 119.77,96.99 119.77,95.93 119.83,95.87 119.83,95.59 119.76,95.52 119.76,95.26 119.84,95.17 119.84,94.95 119.76,94.86 119.76,94.46 UC1.E32
  BOTTOM w0.254: 119.74,97.01 119.74,97.84 120.02,98.12 120.02,98.25 v2(120.07,98.31) 120.11,98.34 120.11,99.01 RC140.2
VCCSENSE_VCCGTUS: length 2.6
  TOP w0.254: RC340.2 104.57,81.55 104.57,82.38 104.56,82.39 v2(104.56,82.5)
  BOTTOM w0.254: v2(104.56,82.5) 104.58,82.5 104.51,82.44 104.51,82.31 103.69,81.49 UC1.AK62
VCCSENSE_VGA: length 37.6
  TOP w0.254: v2(151.47,135.14) 151.95,135.61 RV161.1 152.57,135.01 v1(152.57,134.94) 152.57,134.89 RV159.2 ; v2(160.04,113.88) 159.7,113.88 158.98,113.16 PR1138.2
  IN1 w0.254: v2(160.04,113.88) 160.49,114.32 161.27,114.32 161.54,114.58 161.54,118.49 160.65,119.38 159.47,119.38 158.11,118.02 153.62,118.02 152.44,119.2 152.44,120.31 151.73,121.02 151.73,124.18 151.21,124.7 151.21,126.85 151.03,127.03 151.03,131.92 151.62,132.51 151.62,134.99 v2(151.47,135.14)
VCCST_PWRGD: length 17.1
  BOTTOM w0.076: UC1.B65 101.6,95.76 101.7,95.66 101.83,95.66 101.87,95.7 101.87,95.81 101.91,95.85 101.91,96.15 101.77,96.29 101.77,96.43 101.91,96.57 101.91,96.8 101.7,97 101.7,97.12 101.89,97.31 101.89,97.39 101.01,98.27 100.61,98.27 100.33,98.55 99.72,98.55 98.68,99.59 v1(98.55,99.59) 98.47,99.59 98.39,99.52 98.39,99.07 98.32,99 98.16,99 98.09,99.07 98.09,99.58 98.01,99.66 97.86,99.66 97.78,99.58 97.78,99.07 97.71,99 97.56,99 97.48,99.07 97.48,99.58 97.4,99.66 97.25,99.66 97.17,99.58 97.17,99.07 97.1,99 96.95,99 96.88,99.07 96.88,99.53 96.81,99.59 96.43,99.59 96.37,99.66 96.37,99.91 96.42,99.96 98.22,99.96 98.29,100.04 98.29,100.19 98.22,100.27 96.71,100.27 96.64,100.34 96.64,100.45
  BOTTOM w0.102: 96.64,100.45 96.91,100.72 RC78.2
VCCSTG_EN: length 6.2
  TOP w0.102: UC15.4 142.41,115.9 141.6,116.71 RZ1702.1 141.17,117.4 141.28,117.51 DZ1701.1 ; 142.8,118.43 141.85,118.43 DZ1701.1 ; v1(141.28,118.96) DZ1701.1
VCCSTG_EN_R: length 4.4
  TOP w0.102: UZ19.4 139.57,115.53 139.83,115.79 CZ1702.1 140.24,116.28 140.25,116.29 RZ1702.2 140.25,117.49 DZ1701.2 v1(138.91,117.86)
VDD10: length 8.9
  TOP w0.102: 46.52,169.6 46.35,169.6 v2(46.35,169.61)
  TOP w0.203: LOM30.3 46.52,169.6 ; LOM30.30 48.71,171.75 48.5,171.96 ; v2(46.79,167.13) 46.79,167.39 47.01,167.6 LOM30.8 ; v2(52.27,169.49) 52.16,169.6 LOM30.22
  TOP w0.508: C3021.1 45.48,169.77 45.62,169.62 46.34,169.62 v2(46.35,169.61) ; 48.5,171.96 48.04,172.42 v2(48.01,172.42) 47.24,173.19 46.68,173.19 45.57,174.31 C3022.1
  vias: v1(46.89,168.99) v2(52.84,176.77) v2(52.86,169.49) v2(53.71,176.78) v2(54.63,176.8)
VDD_1.2V: length 8.2
  TOP w0.102: v1(54.43,14.85) 54.43,16.46 PR206.2
  TOP w0.508: PR205.1 v2(59.05,15.43)
  IN2 w0.254: v2(59.05,15.43) 59.05,16.38 56.83,18.61 v2(56.13,18.61)
VDD_CHG: length 68.9
  TOP w0.203: v2(113.47,160.21) 113.33,160.35 PR760.1 PC768.2 111.69,160.35 111.69,160.91 112.17,161.39 v1(112.73,161.39) 113,161.39 113.34,161.73 113.34,164.02 v2(113.02,164.34)
  TOP w0.254: v2(70.73,170.78) 70.64,170.87 PR781.1
  IN1 w0.254: v2(104.12,155.45) 105.26,156.59 v2(105.26,164.31)
  IN2 w0.254: v2(70.73,170.78) 71.42,170.09 77.57,170.09 79.77,167.89 81.95,167.89 82.74,167.11 89.15,167.11 89.86,166.4 91.99,166.4 92.59,165.8 97.82,165.8 100.68,162.94 101.46,162.94 101.77,163.25 104.46,163.25 105.26,164.05 v2(105.26,164.31) 105.96,165.01 112.35,165.01 v2(113.02,164.34)
  BOTTOM w0.203: PU703.19 112.67,159.22 113.47,160.02 v2(113.47,160.21) ; PR749.2 113.01,164.32 v2(113.02,164.34)
  BOTTOM w0.254: PR750.2 106.32,163.81 105.82,164.31 v2(105.26,164.31) ; PR741.1 104.37,155.19 v2(104.12,155.45)
VDD_DAC_33: length 2.8
  BOTTOM w0.102: v1(24.63,66.29) 24.64,66.28 v2(25.45,66.28)
  BOTTOM w0.508: C5502.1 26.23,65.38 C5524.1 25.61,66.45 v2(25.45,66.28)
VDDIO_VGA: length 5.7
  BOTTOM w0.102: PR1113.2 153.87,104.93 v1(153.49,104.93)
  BOTTOM w0.203: PU1100.6 156.14,107.14 156.12,107.16 155.35,107.16 PR1115.2 154.8,107.57 PC1226.1 PR1113.2
VDDP_CHG: length 4.2
  TOP w0.102: v1(113.83,159.86) 113.83,159.69 v2(113.47,159.32)
  TOP w0.203: PC769.2 112.58,158.57 112.58,159.44 PR760.2 113.35,159.44 v2(113.47,159.32)
  BOTTOM w0.203: PU703.20 112.84,158.82 113.34,159.32 v2(113.47,159.32)
VDDREG:
  vias: v1(52.97,170.26)
VIN_+VCCEOPIO:
  vias: v1(33.83,53.57) v2(31.81,53.21) v2(32.7,53.21) v2(33.46,53.02) v2(34.09,53.02)
VSS_EDRAM_SENSE: length 1
  TOP w0.076: v2(102.75,84.56) 102.75,84.05 T4952.1
  BOTTOM w0.254: v2(102.75,84.56) 103.04,84.27 UC1.AE63
VSS_GT_SENSE: length 84.3
  TOP w0.203: v2(112.66,139.81) 112.76,139.81 112.83,139.88 PU602.6
  IN2 w0.254: v2(112.66,139.81) 112.11,139.81 110.52,141.4 v2(107.48,141.4)
  BOTTOM w0.076: UC1.J69 98.75,91.42 98.09,91.42 97.9,91.34 97.79,91.34 97.64,91.19
  BOTTOM w0.254: PC619.2 111.82,142.59 PC620.2 111.83,140.07 112.09,139.81 v2(112.66,139.81) ; 97.64,91.19 95.32,91.19 RC163.1 94.25,91.46 93.67,91.46 93.31,91.1 88.83,91.1 87.94,91.99 87.94,93.62 88.92,94.6 88.92,99.27 92.26,102.62 92.26,105.35 93.21,106.3 93.21,109.22 92.51,109.92 92.51,111.56 93.54,112.59 96.51,112.59 97.36,113.44 97.36,121.21 102.29,126.14 102.29,137.16 103.88,138.75 103.88,138.77 v1(106,140.89) 106.51,141.4 v2(107.48,141.4)
VSSEOPIO_SENSE: length 1.4
  TOP w0.102: T4953.1 103.85,82.44 v2(103.94,82.44)
  BOTTOM w0.254: v2(103.94,82.44) 103.51,82 UC1.AJ62
VSSIO_SENSE: length 1.6
  TOP w0.254: T4948.1 124.98,80.32 125.01,80.32 v2(125.29,80.04)
  BOTTOM w0.254: UC1.AM22 125.67,80.42 v2(125.29,80.04)
VSSSENSE: length 53.2
  TOP w0.203: PU602.18 117.45,136.93 117.96,136.42 118.1,136.42 v2(118.27,136.25)
  TOP w0.254: v2(118.27,136.25) 119.01,135.52 PC653.2 119.01,134.6 PC654.2
  IN1 w0.254: v2(119.23,98.32) 119.67,98.77 119.67,99.15 119.93,99.4 119.93,101.35 121.95,103.37 121.95,106.8 117.68,111.06 117.68,121.16 118.36,121.84 118.36,134.39 117.1,135.64 117.1,136.28 117.42,136.6 117.93,136.6 v2(118.27,136.25)
  BOTTOM w0.089: 119.31,96.82 119.31,95.96 119.18,95.83 119.18,95.6 119.26,95.52 119.26,95.26 119.19,95.19 119.19,95.18 119.18,95.17 119.18,94.95 119.19,94.94 119.19,94.93 119.34,94.77 UC1.E33
  BOTTOM w0.102: v2(118.27,136.25) 118.42,136.1 118.89,136.1 v1(119.16,136.37)
  BOTTOM w0.254: RC141.1 119.2,98.35 v2(119.23,98.32) 119.31,98.25 119.31,96.82
VSSSENSE_VCCGTUS: length 3.5
  TOP w0.076: v2(105.15,82.51) 105.15,82.69 v1(104.87,82.97)
  TOP w0.254: RC341.1 105.15,82.01 v2(105.15,82.51)
  BOTTOM w0.254: v2(105.15,82.51) 105.15,82.38 104.26,81.49 UC1.AL61
VSSSENSE_VGA: length 35.7
  TOP w0.102: v2(160.7,113.84) v1(161.23,113.84)
  TOP w0.254: v2(160.7,113.84) 159.97,113.11 PR1139.2 ; v2(152.1,134.58) 152.1,133.96 RV160.1 152.83,133.23 RV158.2
  IN1 w0.254: v2(160.7,113.84) 161.33,113.84 161.92,114.43 161.92,118.65 160.81,119.76 159.31,119.76 157.95,118.4 153.78,118.4 152.82,119.36 152.82,120.47 152.11,121.18 152.11,124.34 151.61,124.84 151.61,126.99 151.41,127.19 151.41,131.8 152.1,132.49 v2(152.1,134.58)
3D3V_CAMERA_S0:
  vias: v2(94.42,164.02) v2(94.99,159.19) v2(95.05,164.02) v2(95.37,158.69) v3(96.08,158.6)
3D3V_CARD_S0: length 8.6
  IN1 w1.016: 13.35,20.29 14.81,20.29 15.44,19.65 19,19.65 20.91,17.75
  vias: v2(12.46,20.6) v2(12.46,19.97) v2(20.82,16.89) v2(21.41,16.86) v2(24.08,17.18) v2(24.08,16.54)
3D3V_LAN_S5: length 0.7
  BOTTOM w0.457: C3017.1 47.46,164.69 v2(47.48,164.67)
  vias: v2(45.95,172.26) v2(46.72,164.64) v2(56.67,173.46) v2(57.21,173.74) v2(57.21,173.13) v3(47.05,165.1)
+BIF_VDDC: length 1.5
  BOTTOM w0.381: v2(159.45,137.27) 159.45,136.68 UV1.U21 ; v2(160.03,137.79) 160.13,137.9 160.77,137.9 UV1.R21
  vias: v1(155.35,139.65) v2(154.84,139.57) v2(155.4,140.21) v2(156.01,140.72)
+DP_VDDC: length 8.5
  TOP w0.102: v1(159.11,121.84) 159.18,121.91 159.18,123.2 159.03,123.34 RV30.1
  TOP w0.508: RV30.1 158.55,124.28 158.55,125.35 CV30.1 159.16,126.01 159.16,126.97 CV34.1 CV33.1 159.98,127.89 v2(159.47,128.4)
  BOTTOM w0.381: UV1.AD14 159.23,128.63 v2(159.47,128.4)
+DP_VDDR: length 6.9
  TOP w0.102: RV27.1 157.99,124.54 v1(157.99,125.2)
  TOP w0.508: v2(158.6,127.51) 158.24,127.15 CV35.1 158.23,126.93 CV26.1 156.52,125.22 CV27.1 156.95,124.41 157.15,124.41 RV27.1
  BOTTOM w0.254: UV1.AF14 158.12,127.87 158.48,127.51 v2(158.6,127.51)
+FBA_VREF_CA0: length 27.1
  TOP w0.102: RV139.2 v1(175.32,175.41)
  TOP w0.254: v2(174.91,167.82) 174.96,167.88 UV18.M8
  TOP w0.508: RV139.2 RV110.1 174.56,173.35 CV327.1 173.93,172.34 174.11,172.16 v2(174.11,171.77)
  IN1 w0.381: v2(174.91,167.82) 173.88,168.85 173.88,170.33 174.44,170.89 174.44,171.43 v2(174.11,171.77)
  IN2 w0.381: v2(178.91,165.02) 178.91,165.71 182.11,168.91 182.11,171.21 181.23,172.09 180.4,172.09 176.13,167.82 v2(174.91,167.82)
  BOTTOM w0.254: UV17.M8 178.9,165 v2(178.91,165.02)
+FBA_VREF_CA1: length 24.1
  TOP w0.254: v2(187.87,154.91) 187.9,154.93 UV20.M8
  IN2 w0.381: v2(187.87,154.91) 189.7,154.91 193.52,158.73 194.5,158.73 195.25,157.97 195.25,156.34 194.7,155.78 194.7,153.4 195.18,152.92 195.18,152.45 194.04,151.32 v2(193.73,151.32)
  BOTTOM w0.254: UV19.M8 192.39,151.54 192.79,151.14 193.55,151.14 v2(193.73,151.32)
  BOTTOM w0.508: v2(193.73,151.32) 194.58,151.32 195.31,150.59 CV220.1 RV149.2 RV142.1
+FBA_VREF_DQ0: length 37.4
  TOP w0.254: v2(179.32,163.89) 179.13,163.7 179.13,162.72 178.58,162.17 UV18.H1
  IN2 w0.381: v2(179.32,163.89) 179.83,163.89 182.59,166.66 182.59,171.41 181.41,172.59 180.22,172.59 176.35,168.72 174.47,168.72 173.6,169.59 173.6,170.37 173.03,170.94 172.4,170.94 171.47,170.02 171.47,167.99 v2(171.16,167.67)
  BOTTOM w0.102: 169.82,168.29 169.17,168.29 v1(168.22,169.23)
  BOTTOM w0.254: CV399.1 170.5,168.29 171.12,167.67 v2(171.16,167.67) 172.13,166.7 UV17.H1
  BOTTOM w0.508: CV399.1 169.82,168.29 RV112.1 RV144.2
+FBA_VREF_DQ1: length 40.8
  TOP w0.102: v1(190.87,143.86) RV150.2
  TOP w0.254: UV20.H1 190.12,148.07 190.56,147.64 v2(191.26,147.64)
  TOP w0.381: CV227.1 191.86,147.03 191.8,147.03 191.26,147.58 v2(191.26,147.64)
  TOP w0.508: CV227.1 RV143.1 RV150.2
  IN2 w0.381: v2(191.26,147.64) 191.26,147.58 191.8,147.03 192.32,147.03 194.94,149.64 194.94,151.32 195.66,152.04 195.66,153.2 195.18,153.68 195.18,155.56 195.76,156.15 195.76,158.18 194.71,159.24 193.2,159.24 189.97,156 185.93,156 184.61,154.68 184.1,154.68 184.04,154.74 183.61,154.74 182.71,153.83 v2(182.71,153.06)
  BOTTOM w0.254: v2(182.71,153.06) 182.75,153.1 183.65,153.1 184.17,153.63 185.22,153.63 185.6,153.25 UV19.H1
+MPLL_PVDD: length 5.7
  TOP w0.102: v2(170.59,132.73) 171.09,132.73 v1(171.18,132.82)
  TOP w0.381: CV82.1 170.4,131.28 LV6.2
  TOP w0.508: CV81.1 171.12,131.32 170.79,131.32 170.79,131.32 CV82.1 170.36,131.95 CV124.1 170.2,132.33 v2(170.59,132.73)
  BOTTOM w0.381: v2(170.59,132.73) 170.52,132.65 UV1.L8
+MVREFDA: length 14.5
  IN1 w0.381: v2(152.96,144.53) 152.96,145.22 154.24,146.5 156.53,146.5 158.44,144.59 159.19,144.59 159.73,144.04 v2(160.43,144.04)
  BOTTOM w0.102: v2(152.96,144.53) v1(153.78,144.53)
  BOTTOM w0.254: v2(160.43,144.04) 160.46,144.02 160.46,143.59 UV1.K26
  BOTTOM w0.381: v2(152.96,144.53) 152.96,144.37 152.68,144.08 152.14,144.08 151.8,144.42 RV33.2 152.45,145.08 RV34.1 153.12,145.76 CV94.1
+MVREFSA: length 10.7
  IN1 w0.381: v2(155.44,147.32) 155.8,147.68 156.86,147.68 158.62,145.92 159.93,145.92 v2(161.12,144.73)
  BOTTOM w0.102: v2(155.44,147.32) v1(155.85,146.91)
  BOTTOM w0.254: UV1.J26 161.12,144.16 v2(161.12,144.73) ; 155.02,147.74 155.02,147.74 RV35.1 CV95.1
  BOTTOM w0.381: RV32.2 155.02,147.74 v2(155.44,147.32)
+PCIE_VDDC: length 12.2
  BOTTOM w0.381: UV1.L23 v2(160.66,140.87) 160.65,140.85 UV1.N23 ; v2(160.31,141.42) 160.08,141.2 UV1.N24 ; UV1.N23 UV1.M22 ; UV1.N23 v2(160.15,139.94) UV1.N22 UV1.R22 v2(159.51,138.85) UV1.T22 v2(158.72,137.98) UV1.U22 UV1.V22 v2(157.82,137.19) ; UV1.L24 160.93,142.27 v2(161.11,142.45) ; v2(159.21,142.54) 159.51,142.84 UV1.L26 ; v2(159.8,142.11) 159.96,142.27 UV1.L25
  vias: v1(155.73,146.1) v2(153.7,145.03) v2(154.13,145.44) v2(155.25,145.44) v2(155.63,144.96) v2(155.94,145.49)
+RTC_CELL: length 345.9
  TOP w0.254: v2(127.13,80.04) 126.74,80.43 CC270.1 126.74,81.41 CC213.1
  TOP w0.508: v2(133.4,69.08) 133.41,69.07 133.41,68 138.8,62.61 v3(141.47,62.61) 142.03,63.17 RC56.2 RC69.2 142.91,63.39 143.27,63.03 143.99,63.03 144.44,63.48 RC57.2 143.88,63.89 143.83,63.94 v2(143.63,63.94) ; v2(31.24,9.02) 30.59,9.66 C2503.1 28.89,10.5 D2501.1 ; D2502.1 v2(186.56,31.42)
  IN1 w0.254: v2(130.21,72.32) 130.21,74.34 128.36,76.18 127.98,76.18 127.57,76.59 127.57,79.59 v2(127.13,80.04)
  IN1 w0.508: v2(31.24,9.02) 33.14,7.11 37.71,7.11 40.1,4.72 44.3,4.72 45.9,3.13 166.57,3.13 173.54,10.1 173.54,17.53 174.36,18.35 174.36,23.37 176.71,25.72 176.71,28.51 179.51,31.31 179.51,34.29 181.41,36.19 183.95,36.19 186.56,33.59 v2(186.56,31.42) ; v2(189.86,47.18) 185.96,43.28 176.55,43.28 174.49,41.22 171.22,41.22 168.6,38.61 163.32,38.61 v2(163.06,38.86)
  IN2 w0.508: v2(186.56,31.42) 188.02,32.88 188.02,33.97 188.79,34.75 188.79,37.23 189.6,38.04 189.6,38.65 189.86,38.91 v2(189.86,47.18) 189.86,53.56 189.25,54.17 189.25,58.32 189.86,58.93 189.86,60.49 188.36,61.99 v2(188.36,62.55) ; v2(143.63,63.94) 145.12,62.46 148.49,62.46 153.1,57.85 162.81,57.85 165.47,55.18 165.47,47.43 163.38,45.33 163.38,39.18 v2(163.06,38.86)
  BOTTOM w0.254: UC1.BB14 130.48,74.3 130.46,74.28 130.46,73.32 130.21,73.06 v2(130.21,72.32) 130.32,72.2 131.69,72.2 133.61,70.28 133.61,69.28 v2(133.4,69.08) ; v2(127.13,80.04) 127.13,80.58 UC1.AK19 ; v2(188.36,62.55) 188.3,62.55 187.83,63.02 187.83,67.63 188.46,68.26 RE349.2 189.27,68.26 RE437.2 RE31.1
  BOTTOM w0.305: R2712.2 186.87,31.11 186.57,31.42 v2(186.56,31.42)
+RTC_CELL_VBAT: length 6.9
  TOP w0.102: v1(190.16,62.08) 190.16,62.67 CE73.1
  TOP w0.203: UE1.122 189.15,65.67 v2(189.16,65.66)
  TOP w0.508: CE73.1 189.44,63.4 189.44,64.83 189.16,65.11 v2(189.16,65.66)
  BOTTOM w0.508: RE349.1 188.78,66.36 189.16,65.98 v2(189.16,65.66)
+RTC_VCC: length 6.4
  TOP w0.508: v2(29.52,16) 29.52,15.37 AFTP2502.1 R2502.2
  BOTTOM w0.508: v2(29.52,16) 29.39,16.13 28.38,16.13 27.15,14.9 RTC1.1
+SPLL_PVDD: length 9.2
  TOP w0.508: v2(171.91,133.86) 171.98,133.86 172.09,133.74 173.27,133.74 v1(174.81,132.21) 175.44,132.21 CV86.1 CV85.1 177.6,130.81 CV84.1 178.76,129.66 LV7.2
  BOTTOM w0.254: UV1.H7 171.98,133.93 v2(171.91,133.86)
+SPLL_VDDC: length 7.7
  TOP w0.508: CV93.1 173.55,134.35 172.5,134.35 v2(172.44,134.41) ; LV8.2 179.76,129.03 179.76,129.6 179.25,130.11 CV91.1 179,131.57 177.6,131.57
  BOTTOM w0.305: v2(172.44,134.41) 172.44,134.41 172.3,134.54 171.87,134.54 UV1.H8
  vias: v1(175.63,133.2)
+TSVDD: length 10.8
  TOP w0.102: LV2.2 153.14,124.28 v1(153.37,124.28)
  TOP w0.508: v2(157.84,130.2) 158.25,129.79 CV20.1 157.92,129.29 CV21.1 157.92,128.83 157.11,128.02 156.04,128.02 153.75,125.73 CV19.1 153.22,125.71 LV2.2
  BOTTOM w0.381: UV1.AD17 157.54,130.51 v2(157.84,130.2)
+V_DDR_REFA: length 8.7
  TOP w0.102: RH209.1 v1(126.88,30.59)
  TOP w0.508: v2(120.82,29.54) 121.21,29.93 ; 121.21,29.93 121.3,29.84 123.5,29.84 123.93,30.27 RH484.2 123.93,30.59 RH206.2 RH209.1 ; 121.21,29.93 CD18.1
  BOTTOM w0.305: v2(120.82,29.54) 120.87,29.59 JDIMM1.164
+V_DDR_REFA_R: length 144.5
  TOP w0.508: CH101.1 123.92,31.51 RH484.1 123.93,31.52 v2(123.93,32.46)
  IN1 w0.508: v2(123.93,32.46) 122.78,31.31 121.15,31.31 120.2,30.35 120.2,25.27 121.72,23.75 121.72,18.1 122.23,17.59 v2(123.69,17.59) ; v2(77.15,32.13) 77.15,32.51 75.75,33.91 75.75,35.56 75.85,35.66 75.85,54.02 77.46,55.64 v2(77.46,57.59)
  BOTTOM w0.203: UC1.AY67 100.37,75.36 100.6,75.12 100.6,74.85 100.63,74.82 100.63,74.59 100.6,74.56 100.6,73.87 100,73.27 100,73.13 99.6,72.73 97.92,72.73 97.2,72 96.81,72
  BOTTOM w0.254: 96.07,71.49 96.58,72 96.81,72
  BOTTOM w0.381: 96.07,68.18 v1(96.07,70.4) 96.07,71.49
  BOTTOM w0.508: v2(123.69,17.59) 123.69,15.24 122.77,14.32 86.24,14.32 82.62,17.94 82.62,25.49 80.87,27.24 79.37,27.24 77.15,29.46 v2(77.15,32.13) ; 96.07,68.18 86.44,58.55 78.42,58.55 v2(77.46,57.59)
+V_DDR_REFB: length 8.5
  TOP w0.102: v1(128.56,14.48) 128.75,14.48 v2(129.47,15.21)
  TOP w0.381: RH485.2 131.4,16.9 130.49,15.99 RH210.1
  TOP w0.508: v2(129.47,15.21) 129.47,15.21 CD29.1 RH210.1 ; RH207.2 v2(128.52,17.69)
  BOTTOM w0.305: v2(129.47,15.21) JDIMM2.164 129.47,17.39 129.18,17.69 v2(128.52,17.69)
+V_DDR_REFB_R: length 130.3
  TOP w0.381: v2(130.99,15.18) 131.5,15.68 RH485.1
  IN1 w0.508: v2(76.38,32.13) 75.05,33.46 75.05,35.76 75.22,35.92 75.22,54.29 76.7,55.77 76.7,57.78 v2(77.54,58.62)
  BOTTOM w0.152: 97.18,72.75 97.52,73.09 98.72,73.09 99.35,73.71 99.73,73.71 99.94,73.93 99.94,74.4 UC1.BA67
  BOTTOM w0.254: 97.18,72.75 96.43,72.75 95.5,71.82
  BOTTOM w0.381: 95.5,71.82 95.5,68.75
  BOTTOM w0.508: v2(76.38,32.13) 76.38,29.15 78.99,26.54 80.58,26.54 81.92,25.2 81.92,17.49 85.8,13.62 127.63,13.62 128.3,14.29 130.3,14.29 130.99,14.99 v2(130.99,15.18) ; 95.5,68.75 v1(93.09,66.35) 86.12,59.37 CH100.1 v2(77.54,58.62)
+VGA_CORE: length 83.4
  TOP w0.381: 162.32,136.4 CV79.1 ; CV117.1 160.92,131.8 v2(160.84,131.72) ; CV100.1 163.91,130.84 163.91,131.32 CV74.1 164.01,131.52 v2(163.63,131.9) ; v2(165.67,136.65) 165.67,136.9 CV87.1 ; CV101.1 164.88,134.28 v2(164.99,134.39) 164.89,134.49 CV72.1 ; v2(164.39,137.82) 163.92,137.82 163.51,138.24 CV89.1 163.4,138.3 v2(163,137.9) ; CV73.1 166.52,129.58 v2(166.52,130.14) ; CV118.1 165.39,131.32 v2(164.95,131.75) ; CV90.1 163.67,137.16 v2(163.71,137.2) ; CV75.1 v2(166.4,133.15) ; CV115.1 161.68,134.44 v2(160.88,134.44)
  TOP w0.508: CV88.1 161.19,129.26 v2(161.52,129.59) ; CV102.1 159.49,130.07 v2(159.47,130.1) ; CV116.1 159.82,134.8 v2(159.47,134.44) 158.94,134.44 CV106.1 ; CV71.1 162.24,133.09 v2(162.15,133.17) 162.49,133.51 CV103.1 ; v2(162.18,128.96) 162.62,128.53 CV76.1 ; CV105.1 162.36,136.35 162.36,135.77 v2(162.26,135.67) ; CV112.1 168.03,133.25 v2(168.33,133.55) ; v2(160.88,134.44) 160.88,133.99 CV68.1 ; CV78.1 161.43,137.28 v2(160.73,137.28) 160.69,137.32 CV111.1 ; CV113.1 162.05,127.58 v2(161.6,127.13) ; v2(151.97,136.8) 151.82,136.8 RV161.2 150.68,136.91 CV80.1 ; v2(158.1,134.52) 158.1,135.56 CV403.1 ; CV114.1 164.98,129.03 v2(164.6,128.65) 164.45,128.51 CV104.1
  IN2 w0.508: v2(158.1,134.52) 157.26,134.52 156.77,135 156.77,135.64 156.2,136.21 154.68,136.21 153.98,136.91 153.16,136.91 153.05,136.8 v2(151.97,136.8)
  BOTTOM w0.305: UV1.M13 166.3,135.25 165.65,135.91 UV1.M15 ; v2(164.39,137.82) 164.33,137.89 UV1.M18 163.61,137.9 v2(163,137.9)
  BOTTOM w0.381: UV1.Y18 159.52,134.39 v2(159.47,134.44) 159.52,134.49 UV1.V20 ; 165.45,130.39 166.26,130.39 v2(166.52,130.14) ; 165.45,130.39 UV1.T10 ; 165.45,130.39 165.45,129.76 165.24,129.54 ; UV1.Y9 164.03,128.13 v2(163.73,127.84) ; UV1.AB12 UV1.AC11 161.92,128.27 UV1.AB11 ; UV1.AB12 161.27,128.98 160.79,129.46 UV1.AB13 ; UV1.AB12 161.55,129.03 161.55,129.57 v2(161.52,129.59) ; UV1.N20 162.99,137.89 v2(163,137.9) 162.91,137.98 UV1.M20 UV1.M21 ; v2(158.1,134.52) UV1.Y21 158.1,135.41 158.6,135.91 UV1.V21 ; UV1.M18 163.62,137.29 v2(163.71,137.2) 163.73,137.18 UV1.M17 UV1.M16 165.63,136.61 ; 165.24,129.54 UV1.W10 ; 165.24,129.54 165.17,129.48 UV1.W9 165.17,128.21 v2(165.11,128.14) ; v2(159.47,130.1) 159.8,129.77 UV1.AC14 159.8,129.18 v2(160.03,128.96) 160.39,128.96 UV1.AC13 ; UV1.M15 165.6,136.58 165.63,136.61 ; UV1.N17 163.56,136.41 163.56,135.28 UV1.R16 UV1.T15 163.48,133.22 v2(163.52,133.17) 163.57,133.13 163.57,132.56 UV1.U13 163.63,132.5 v2(163.63,131.9) ; v2(162.18,128.96) 162.2,128.98 UV1.AA12 162.17,129.71 162.17,131.07 UV1.Y13 162.2,131.71 162.15,131.76 162.15,132.46 UV1.V15 162.2,133.12 v2(162.15,133.17) 162.15,133.88 UV1.U16 UV1.T17 162.28,135.14 162.28,135.65 v2(162.26,135.67) 162.26,136.41 UV1.R18 ; v2(160.73,137.28) 160.71,137.26 160.71,136.55 UV1.T20 160.79,135.88 160.93,135.74 UV1.U18 160.93,134.49 v2(160.88,134.44) 160.88,133.84 UV1.V17 160.93,132.65 UV1.Y16 160.81,132.49 160.81,131.75 v2(160.84,131.72) 160.81,131.7 160.81,131.12 UV1.AA15 ; UV1.N15 164.99,135.1 v2(164.99,134.39) 164.99,133.89 UV1.R13 164.89,133.78 164.89,133.12 164.85,133.09 164.85,132.41 UV1.T12 164.95,132.31 v2(164.95,131.75) 165.03,131.67 UV1.U11 ; UV1.N12 166.4,133.69 v2(166.4,133.15) ; v2(165.67,136.65) 165.63,136.61 ; UV1.M11 167.95,133.55 v2(168.33,133.55)
  vias: v2(162.24,123.22) v2(162.74,123.77) v2(162.82,122.63) v2(166.71,126.59) v2(167.09,125.22) v2(167.34,122.76) v2(167.43,119.89) v2(167.66,122.26) v2(167.8,127.41) v2(167.8,126.52) v2(167.77,123.27) v2(168,122.71) v2(183.19,97.15) v2(183.19,96.39) v2(183.19,95.76) v2(183.19,95) v2(183.32,104.77) v2(183.32,104.14) v2(183.32,103.5) v2(183.62,114.07) v2(183.62,113.44) v2(183.7,112.78) v2(183.7,112.14) v2(183.95,106.04) v2(183.95,105.41) v2(183.95,104.77) v2(183.95,104.14) v2(183.95,103.5) v2(183.95,97.15) v2(183.95,96.52) v2(183.95,95.76) v2(183.95,95.12) v2(184.33,114.05) v2(184.33,113.41) v2(184.31,112.8) v2(184.31,112.17) v2(184.33,102.49) v2(184.33,101.85) v2(184.59,111.51) v2(184.59,110.87) v2(184.59,106.04) v2(184.59,105.41) v2(184.59,104.77) v2(184.59,104.14) v2(184.52,103.06) v2(184.59,97.15) v2(184.59,96.52) v2(184.59,95.76) v2(184.59,95.12) v2(184.84,103.63) v2(184.97,102.49) v2(184.97,101.85) v2(185.16,103.06) v2(185.22,111.51) v2(185.22,110.87) v2(185.22,110.24) v2(185.22,109.6) v2(185.22,108.97) v2(185.25,108.1) v2(185.25,107.47) v2(185.22,106.81) v2(185.22,106.04) v2(185.22,105.41) v2(185.22,104.77) v2(185.22,104.14) v2(185.22,101.22) v2(185.22,100.58) v2(185.22,99.95) v2(185.22,99.31) v2(185.22,98.42) v2(185.22,97.79) v2(185.22,97.15) v2(185.22,96.52) v2(185.22,95.76) v2(185.22,95.12) v2(185.48,103.63) v2(185.6,102.49) v2(185.6,101.85) v2(185.79,103.06) v2(185.86,111.51) v2(185.86,110.87) v2(185.86,110.24) v2(185.86,109.6) v2(185.86,108.97) v2(185.88,108.1) v2(185.88,107.47) v2(185.86,106.68) v2(185.86,106.04) v2(185.86,105.41) v2(185.86,104.77) v2(185.86,104.14) v2(185.86,101.22) v2(185.86,100.58) v2(185.86,99.95) v2(185.86,99.31) v2(185.86,98.42) v2(185.86,97.79) v2(185.86,97.15) v2(185.86,96.52) v2(185.86,95.76) v2(185.86,95.12) v2(186.24,103.44) v2(186.24,102.62) v2(186.49,98.62) v2(186.49,97.98) v2(186.87,103.44) v3(172.23,118.28)
AC_DIS: length 165
  TOP w0.102: v2(175.63,85.85) 175.63,84.25 v1(175.89,84) 178.63,81.26 179,81.26 179.29,80.96 179.29,79.96 178.9,79.57 UE1.69
  TOP w0.254: v2(81.82,165) 81.22,164.4 80.3,164.4 PQ712.2
  IN1 w0.127: v2(175.63,85.85) 175.44,86.04 174.03,86.04 173.38,86.69 171.56,86.69 171.43,86.82 168.38,86.82 167.06,88.14 164.59,88.14 163.06,89.66 163.06,90.61 157.84,95.83 153.85,95.83 152.6,97.08 148.22,97.08 143.63,101.66 143.63,110.62 143.12,111.12 143.12,115.82 141.47,117.47 141.47,123.25 137.85,126.87 135.69,126.87 134.83,127.74 134.83,139.92 135.69,140.78 135.69,147.72 133.34,150.07 v2(133.34,150.24)
  IN2 w0.127: v2(133.34,150.24) 133.17,150.06 122.28,150.06 121.13,148.91 119.46,148.91 118.83,149.53 107.94,149.53 101.8,155.67 101.43,155.67 95.81,161.29 91.78,161.29 88.73,164.34 86.54,164.34 85.88,165 v2(81.82,165)
AC_PRESENT: length 40.6
  TOP w0.102: RC243.1 v2(145.26,60.13)
  IN2 w0.127: v2(145.26,60.13) 149.1,60.13 152.6,56.64 156.52,56.64 v2(157.53,55.63)
  BOTTOM w0.076: 131.46,68.71 130.85,69.32 130.85,70.45 129.32,71.98 129.32,74.34 129.65,74.67 129.65,74.86 129.86,75.07 UC1.AY15
  BOTTOM w0.102: 131.46,68.71 140.04,60.13 v1(140.6,60.13) v2(145.26,60.13) ; v2(157.53,55.63) 157.53,55.31 DZ4.2
ACAV_IN: length 305
  TOP w0.102: v2(193.29,68.28) 191.91,68.28 191.55,67.92 UE1.128 ; v2(133.41,178.42) v1(133.93,178.42)
  TOP w0.254: PR12.1 133.4,178.44 v2(133.41,178.42)
  IN1 w0.127: v2(105.8,153.37) 105.68,153.48 105.68,165.52 105.5,165.7 105.5,167.48 103.95,169.04 100.96,169.04 v2(100.51,168.59) ; v2(161.82,38.42) 163.29,39.89 168.49,39.89 174.7,46.1 174.7,51.18 175.96,52.44 180.96,52.44 182.17,53.66 191.89,53.66 194.3,56.07 194.3,57.53 195.79,59.02 195.79,61.37 196.46,62.04 196.46,65.35 194.76,67.06 194.41,67.06 193.29,68.17 v2(193.29,68.28) 193.69,68.68 193.69,75.17 194.2,75.68 194.2,76.81 194.52,77.13 194.52,78.47 195.77,79.71 195.77,84.68 191.7,88.75 190.81,88.75 190.49,88.42 188.58,88.42 187.84,89.16 185.95,89.16 185.18,88.39 182.81,88.39 181.98,87.57 174.66,87.57 174.02,88.21 172.2,88.21 170.55,89.85 166.17,89.85 159.68,96.34 159.68,97.38 156.86,100.2 154.85,100.2 149.29,105.76 149.29,119.09 147.45,120.92 147.45,141.34 146.61,142.18 146.61,145.73 148.27,147.38 148.27,157.99 145.41,160.85 145.41,172.34 140.84,176.91 140.84,177.6 v2(140.01,178.42)
  IN2 w0.127: v2(140.01,178.42) v2(133.41,178.42) 133.34,178.35 123.58,178.35 123.56,178.37 112.58,178.37 110.48,176.28 105.91,176.28 100.51,170.88 v2(100.51,168.59) ; v2(158.09,55.88) 159.31,54.66 159.31,52 161.82,49.5 v2(161.82,38.42)
  BOTTOM w0.102: v2(105.8,153.37) 105.87,153.44 PR731.1 PR741.2 106.84,156.16 106.84,156.88 107.41,157.45 107.41,157.45 107.58,157.62 PU703.2 ; v2(158.09,55.88) 157.79,56.18 DZ4.1 ; v2(193.29,68.28) CE84.2
ACIN_CHG: length 56.6
  TOP w0.102: v1(78.82,170.52) 79.22,170.13 PC711.2
  TOP w0.508: PQ712.1 80.22,165.38 80.68,164.92 v2(80.77,164.92) ; v2(79.42,171.32) 79.74,171.32 PR732.1 80.07,170.99 PC711.2 PR729.2
  IN1 w0.508: v2(79.42,171.32) 80.11,171.32 80.44,171 80.44,169.98 81.69,168.72 81.69,166.64 80.77,165.71 v2(80.77,164.92) ; v2(90.29,167) 92.06,168.77 99.83,168.77 100.54,169.48 104.13,169.48 105.95,167.67 105.95,165.88 106.13,165.7 106.13,163.15 107.5,161.78 v2(107.5,156.27)
  BOTTOM w0.102: PU703.1 107.58,157.22 107.31,156.95 107.31,156.46 v2(107.5,156.27)
  BOTTOM w0.508: v2(79.42,171.32) 79.94,171.32 81.34,169.93 85.27,169.93 88.19,167 v2(90.29,167)
ACLIM: length 5.1
  BOTTOM w0.102: v1(113.9,164.67) PR751.2
  BOTTOM w0.203: PR751.2 113.11,162.78 PR749.1 113.01,162.71 111.38,161.08 111.38,160.85 111.37,160.85 PU703.16
ADJ_2.5V: length 1.1
  BOTTOM w0.102: 67.32,28.82 v1(68.37,28.82)
ALERT#: length 6.2
  BOTTOM w0.102: R2603.2 v1(159.82,161.86) 159.38,162.31 157.47,162.31 157.29,162.12 THM26.6
ALL_SYS_PWRGD: length 53.1
  TOP w0.102: v2(172.43,88.93) 172.2,88.71 v1(171.54,88.71) 171.28,88.98 171.28,89.81 171.17,89.93 UC17.4 ; RC1106.1 161.8,69.09 DZ5.2 161.35,69.66 161.35,70.61 161.06,70.9 160.74,70.9 160.39,71.25 RC388.1 RC345.1 RC392.2 162.29,71.55 v2(162.74,72.01)
  BOTTOM w0.102: RE438.2 183.17,82.18 183.17,84.48 182.44,85.21 182.44,87.06 181.1,88.4 181.1,89.6 179.25,91.44 177.35,91.44 175,89.09 172.58,89.09 v2(172.43,88.93) 171.66,88.17 171.66,87.38 170.68,86.4 170.68,84.45 168.72,82.48 168.72,75.4 166.56,73.24 164.93,73.24 163.71,72.01 v2(162.74,72.01)
ALL_SYS_PWRGD_R: length 15.6
  TOP w0.102: RC1106.2 162.38,70.31 162.71,69.98 UC16.2 166.24,69.98 v1(168.12,68.1) 168.57,67.64 168.57,65.74 v2(169.35,64.96) ; RC1107.2 v2(173.17,66.36)
  IN1 w0.127: v2(173.17,66.36) 171.77,64.96 v2(169.35,64.96)
ALWON: length 198.2
  TOP w0.102: v2(188.33,43.5) 189.45,44.62 189.45,53.43 187.84,55.04 187.84,56.97 189.73,58.86 189.73,62.23 189.01,62.95 189.01,64.42 188.73,64.7 188.73,66.24 188.75,66.26 UE1.121 ; PR114.1 50.17,39.62 v1(51.09,39.62) 51.62,39.62 v2(51.75,39.75)
  IN1 w0.127: v2(51.75,39.75) 51.87,39.75 57.02,34.61 58.69,34.61 59.58,33.72 67.73,33.72 67.88,33.87 68.23,33.87 69.09,33.02 72.32,33.02 73.46,31.88 73.46,26.35 75.05,24.76 80.28,24.76 81.34,23.71 81.34,18.73 84.32,15.75 154.32,15.75 160.27,21.7 160.27,24.47 163.95,28.15 163.95,34.86 164.2,35.12 166.99,35.12 170.55,38.67 175.7,38.67 177.45,40.42 185.25,40.42 v2(188.33,43.5)
AMBER_LED_BAT: length 6.1
  TOP w0.102: v1(35.24,3.48) Q6101.1
  TOP w0.508: Q6101.1 33.5,5.25 32.77,4.52 EC6102.1 R6103.2
ASGATE: length 42.9
  TOP w0.508: v2(88.63,168.29) 85.55,165.2 84.26,165.2 83.67,164.62 PR762.2
  IN1 w0.508: v2(109.03,155.51) 108.13,156.4 108.13,162.04 107.64,162.54 107.64,169.15 106.05,170.74 100.9,170.74 99.57,169.41 89.76,169.41 v2(88.63,168.29)
  BOTTOM w0.203: v2(109.03,155.51) 109.03,155.7 109.38,156.04 PU703.30
AUD_HP1_JACK_L: length 2.4
  BOTTOM w0.203: HDA27.32 v1(187.89,15.69) 188.43,15.69 R2908.1
AUD_HP1_JACK_L1: length 23.1
  TOP w0.381: v2(183.19,27.81) 183.19,27.87 183.42,28.1 R2907.2
  IN1 w0.381: v2(192.27,20.95) 192.27,22.4 186.86,27.81 v2(183.19,27.81)
  IN2 w0.381: v2(191.34,16.54) 192.27,17.47 v2(192.27,20.95)
  BOTTOM w0.381: v2(191.34,16.54) 190.96,16.16 R2912.2 190.51,16.02 190.51,15.52 190.26,15.27 R2908.2 ; R2922.2 v1(192.03,21.91) 192.03,21.2 v2(192.27,20.95)
AUD_HP1_JACK_R: length 6.1
  BOTTOM w0.203: HDA27.33 187.96,15.29 188.69,14.55 188.91,14.55
  BOTTOM w0.381: 188.91,14.55 190.48,14.55 v1(190.93,15) 191.13,15 R2910.1
AUD_HP1_JACK_R1: length 22.2
  TOP w0.381: v2(183.19,26.7) R2909.2
  IN2 w0.381: v2(183.19,26.7) 183.6,26.29 191.7,26.29 192.78,25.21 v2(192.78,24.26) 192.94,24.1 v2(192.94,18.1)
  BOTTOM w0.102: v2(183.19,26.7) v1(184.05,26.7)
  BOTTOM w0.381: v2(192.94,18.1) 192.79,17.95 R2913.2 R2910.2 ; R2921.2 192.65,24.38 v2(192.78,24.26)
AUD_PC_BEEP: length 4
  TOP w0.102: v2(177.5,22.53) 177.58,22.61 R6516.2 v1(178.42,23.83)
  BOTTOM w0.102: C2720.2 177.27,22.76 v2(177.5,22.53) 177.48,22.5 R6514.2
AUD_PC_BEEP_C: length 7.2
  BOTTOM w0.254: D2701.1 178.8,30.21 178.8,27.94 v1(178.38,27.52) 177.7,26.85 177.7,24.94 RE33.1
AUD_PC_BEEP_R: length 4.3
  BOTTOM w0.203: 180.02,19.43 180.52,18.93 HDA27.12
  BOTTOM w0.254: R6514.1 178.34,20.88 178.64,20.57 178.87,20.57 v1(179.44,20.01) 180.02,19.43
AUD_PORTA_L_R_B: length 6.8
  TOP w0.381: R2907.1 185.48,27.99 R2919.1 EC2907.1 AFTP6306.1 189.63,27.99 190.41,28.77 CN6301.8
AUD_PORTA_R_R_B: length 6.9
  TOP w0.381: R2909.1 185.54,26.87 R2920.1 EC2908.1 189.62,26.87 AFTP6309.1 190.51,27.77 CN6301.7
AUD_SENSE: length 3.1
  BOTTOM w0.102: v1(182.28,24.56) 181.84,24.56 181.44,24.16 181.44,23.67 181.29,23.53 R2923.2
  BOTTOM w0.254: R2709.2 R2923.2
AUD_SENSE_A: length 6.2
  BOTTOM w0.203: HDA27.13 181.37,19.92
  BOTTOM w0.254: C2901.1 179.33,23.33 R2722.2 179.33,21.56 v1(179.43,21.46) 179.79,21.46 180,21.67 R2709.1 180.8,20.49 181.37,19.92
AUD_SPK_L+: length 98.1
  TOP w1.016: 92.26,6.58 93.99,6.58 96.74,3.84 178.32,3.84 182.96,8.48 182.96,10.77 183.14,10.95
  BOTTOM w0.203: HDA27.42 v1(183.77,12.04) 183.77,11.54 v2(183.85,11.46)
  vias: v2(184.13,10.95)
AUD_SPK_L+_C: length 5.8
  BOTTOM w1.016: 85.53,5.52 84.13,5.52 83.69,5.97 79.94,5.97
  vias: v2(86.29,5.72) v2(86.86,5.72)
AUD_SPK_L-: length 98.4
  TOP w1.016: 184.4,8.83 184.4,7.73 179.1,2.44 96.16,2.44 93.52,5.08 92.51,5.08
  BOTTOM w0.203: 183.25,11.71 183.37,11.82 183.37,11.87 183.37,11.87 HDA27.43
  BOTTOM w0.381: 183.25,11.71 183.25,11.11
  vias: v1(183.51,10.16) v2(184.13,10.26) v2(184.13,9.68)
AUD_SPK_L-_C:
  vias: v2(80.45,8.76) v2(81.02,8.76)
AUD_SPK_R+: length 92.2
  TOP w1.016: 180.24,10.19 180.24,9.88 176.99,6.63 98.08,6.63 94.13,10.57 92.26,10.57
  BOTTOM w0.203: HDA27.45 182.57,12.31
  vias: v1(182,11.73) v2(181.36,10.74) v2(181.84,11.07)
AUD_SPK_R+_C:
  vias: v2(82.29,4.64) v2(82.86,4.64)
AUD_SPK_R-: length 93.6
  TOP w1.016: 180.78,8.38 177.63,5.23 97.38,5.23 93.85,8.76 92.58,8.76
  BOTTOM w0.203: HDA27.44 182.97,12.65 182.97,12.65 182.97,12.08 182.68,11.79
  BOTTOM w0.381: 182.68,11.79 182.43,11.54 182.43,10.86
  vias: v1(182.24,10.41) v2(181.46,9.58) v2(181.84,10.03)
AUD_SPK_R-_C: length 11.3
  BOTTOM w1.016: 76.64,6.54 76.26,6.92 76.26,9.27 76.89,9.91 78.16,9.91 78.54,10.29 81.15,10.29 82.23,9.21 82.23,8.32 82.73,7.81
  vias: v2(83.56,7.11) v2(84.13,7.11)
AUD_VREF: length 2.7
  BOTTOM w0.203: HDA27.28 187.64,17.29 v1(187.92,17.56) 188.07,17.72 188.69,17.72 C2705.2
BA: length 6.4
  TOP w0.102: v1(116.87,166.04) PQ710.1 116.87,163.91 v2(117.02,163.76)
  TOP w0.203: PQ710.1 118,164.57 PR780.1
  BOTTOM w0.254: v2(117.02,163.76) 117.02,162.74 117.28,162.48 PD704.3
BAT1_LED#: length 216.9
  TOP w0.254: QC4.1 35.76,11.21 36.89,10.08 v2(36.89,9.52) ; UE1.1 193.8,68.77 194.05,68.51 194.05,67.37 194.75,66.67 RE408.1 195.69,65.86 196.27,65.28 v1(196.27,63) 194.86,61.58 192.3,61.58 191.83,61.11 191.83,57.15 190.94,56.26 189.06,56.26 v2(188.64,56.68)
  IN2 w0.254: v2(36.89,9.52) 38.62,7.79 171.42,7.79 173.86,10.22 173.86,20.64 177.79,24.57 177.79,28.07 181.48,31.75 184.59,31.75 188.27,35.43 188.27,37.43 189.09,38.25 189.09,38.86 189.35,39.12 189.35,53.35 188.64,54.06 v2(188.64,56.68)
BAT2_LED#: length 209
  TOP w0.254: v2(182.07,68.64) 182.17,68.64 182.75,68.07 UE1.106 ; QC4.4 34.2,9.46 v2(33.84,9.83)
  IN2 w0.254: v2(182.07,68.64) 182.07,61.55 182.48,61.14 182.48,46.24 183.6,45.12 183.6,44.12 183.6,44.12 183.6,41.31 182.58,40.29 182.58,37.9 180.02,35.33 180.02,31.54 177.29,28.81 177.29,24.64 173.28,20.64 173.28,10.48 171.04,8.23 39.32,8.23 37.38,10.17 36.12,10.17 35.71,9.75 33.92,9.75 v2(33.84,9.83)
  BOTTOM w0.102: v2(182.07,68.64) 182.52,68.64 v1(182.64,68.77)
  BOTTOM w0.254: RE409.1 181.84,68.87 v2(182.07,68.64)
BAT_AMBER: length 15.8
  TOP w0.508: LED1.1 16.54,2.64 17.29,3.39 26.13,3.39 26.3,3.56 v1(28.3,3.56) 28.52,3.78 R6103.1
BAT_WHITE: length 16.1
  TOP w0.102: R6107.1 27.87,6.38 28.65,7.16 v1(28.83,7.16)
  TOP w0.508: LED1.2 18.04,1.41 v2(18.03,1.4) ; R6107.1 27.18,5.79 25.46,4.06 v2(18.09,4.06)
  IN1 w0.508: v2(18.03,1.4) 18.09,1.46 v2(18.09,4.06)
BATT_WHITE_LED_R#: length 14.6
  TOP w0.102: Q6102.2 32.26,8.59 33.31,9.63 33.31,10.21 QC4.3 v1(35.44,12.34) 35.47,12.37 Q6105.1
BEEP: length 67.2
  TOP w0.102: v2(186.75,80.58) 186.44,80.58 186.34,80.68 186.34,81.45 186.75,81.85 UE1.45
  IN1 w0.254: v2(193.41,33.78) 190.68,33.78 188.79,31.89 v2(188.39,31.89)
  IN2 w0.127: v2(186.75,80.58) 186.75,80.33 186.58,80.16 186.58,78.04 186.3,77.77 186.3,77.48 187.26,76.52 187.78,76.52 188.59,75.71 188.59,73.24 188.08,72.73 188.08,69.59 188.82,68.86 188.82,68.4 189.96,67.26 189.96,65.05 191.03,63.98 191.03,62.98 191.85,62.16 191.85,57.82 193.92,55.76 193.92,34.29 v2(193.41,33.78)
  BOTTOM w0.254: v2(188.39,31.89) 188.02,32.26 187.25,32.26 187.13,32.14 186,32.14 v1(185.22,31.37) 182.86,31.37 182.47,31.76 D2701.2
BKLT_CTRL: length 37.6
  TOP w0.102: v1(60.54,161.54) 60.28,161.81 60.28,163.98 D5202.1 61.58,164.24 61.79,164.03 v2(63.7,164.03) 64.33,164.67 R5222.1 ; RN5203.8 85.23,155.64 v2(84.3,156.58) ; RN5201.7 86.67,157.31 v2(86.52,157.17)
  IN1 w0.127: v2(86.52,157.17) 85.77,156.41 84.46,156.41 v2(84.3,156.58) 84.09,156.78 84.09,157.33 82.54,158.88 79.86,158.88 78.72,157.73 76.68,157.73 70.02,164.39 64.05,164.39 v2(63.7,164.03)
BLON_OUT_C: length 17.5
  TOP w0.102: v2(91.88,163.77) 91.51,163.4 88.01,163.4 87.17,162.55 RN5201.1 87.17,158.86 86.8,158.5 85.15,158.5 84.56,157.91 v1(84.56,157.28) 84.56,156.93 85.07,156.43 85.7,156.43 86.17,155.96 RN5203.7
  BOTTOM w0.102: v2(91.88,163.77) 92.3,164.19 LCD1.24
BLUETOOTH_EN: length 64.8
  TOP w0.102: R5804.1 v2(169.79,49.72)
  IN1 w0.127: v2(146.42,85.53) 148.33,85.53 149.31,86.51 150.16,86.51 150.8,85.88 151.87,85.88 152.52,85.23 153.25,85.23 153.68,84.8 155.86,84.8 158.74,81.92 158.74,81.58 161.33,78.99 161.33,75.86 v2(162.36,74.83)
  IN2 w0.127: v2(162.36,74.83) 161.35,73.81 161.35,71.42 166.9,65.87 166.9,63.08 167.55,62.43 167.55,59.09 170.49,56.15 170.49,50.42 v2(169.79,49.72)
  BOTTOM w0.102: RC292.2 v1(147.29,85.88) 146.77,85.88 v2(146.42,85.53) 145.98,85.09 140.78,85.09 140.58,84.9 139.22,84.9 138.62,85.5 138.09,85.5 UC1.AB2
BLUETOOTH_EN_NGFF: length 2.9
  TOP w0.102: R5804.2 171.76,49.72 171.95,49.91 v2(172.21,49.91) 172.5,49.91 v1(172.73,49.68)
  BOTTOM w0.102: WLAN1.46 171.81,49.77 171.89,49.85 172.14,49.85 v2(172.21,49.91)
BOARD_ID: length 7.4
  TOP w0.102: UE1.111 184.75,65.74 v1(185.34,65.14) 185.6,64.88 RE345.2 RE347.2 CE70.1
BOARD_ID2: length 15.5
  TOP w0.102: v2(146.93,85.09) 146.93,85.33 147.3,85.7 v1(147.3,86.39) RC374.2 147.76,87.96 147.76,88.9 147.06,89.6 RC375.1
  BOTTOM w0.102: v2(146.93,85.09) 146.69,85.09 146.47,84.86 140.93,84.86 140.75,84.69 138.56,84.69 138.38,84.86 137.52,84.86 UC1.AB3
BOARD_ID3: length 27.2
  TOP w0.102: v2(140.18,72.92) 140.18,71.64 140.67,71.15 140.67,70.49 141.05,70.12 141.05,68.85 143.6,66.3 146.9,66.3 147.29,66.69 v1(150.22,66.69) 152.97,66.69 RC377.1 RC376.2
  BOTTOM w0.076: 137.81,72.61 136.71,72.61 136.04,73.28 135.81,73.28 135.35,73.74 134.66,73.74 134.47,73.92 134.47,74.4 134.76,74.68 UC1.BA7
  BOTTOM w0.102: v2(140.18,72.92) 139.86,72.61 137.81,72.61
BP_0: length 3.8
  BOTTOM w0.102: UV1.U1 169.56,126.03 170.11,125.48 170.11,124.08 RV82.1
BP_1: length 5
  BOTTOM w0.102: UV1.U3 169.17,126.96 169.17,126.13 169.91,125.39 169.91,123.01 RV81.1
BST1_VGA: length 3.1
  BOTTOM w0.203: PR1123.1 164.23,109.45 162.54,109.45 162.3,109.21 162.3,108.94 162.1,108.74 PU1100.21
BST2_VGA:
  vias: v1(163.18,103.95)
BST_1.2V:
  vias: v1(61.78,20.31)
BST_1.2V_R: length 1.1
  TOP w0.102: PC200.1 v1(63.05,16.79)
BST_3V: length 1.9
  BOTTOM w0.102: v1(29.19,39.14) 30.18,38.15 PR100.1
BST_5V:
  vias: v1(42.96,37.47)
BST_+1.5VGPU: length 2.9
  BOTTOM w0.102: v1(134.99,138.42) 133.09,138.42 132.52,138.99 PR1402.1
BST_+1.5VGPU_R: length 1
  BOTTOM w0.102: PC1407.1 v1(133.48,141.25)
BST_+1VALW: length 1.5
  BOTTOM w0.102: v1(126.74,125.23) 127.48,124.5 PR306.1
BST_+1VALW_R: length 1.6
  BOTTOM w0.102: PR306.2 126.08,124.5 v1(125.28,125.3)
BST_+VCCEOPIO: length 1.6
  BOTTOM w0.102: v1(37.61,49.66) 37.89,49.66 PR1203.1
BST_R_+VCCEOPIO: length 1
  BOTTOM w0.102: PC1201.1 v1(41.1,49.34)
C1_1.0VS_VCCOPCP: length 0.9
  BOTTOM w0.102: PR1206.2 v1(32.15,56.82)
CAM_DETECT: length 4.3
  TOP w0.102: T53.1 139.55,88.08 139.7,88.08 140.32,88.69 v2(140.32,88.9)
  BOTTOM w0.076: v2(140.32,88.9) 140.32,89.1 140.19,89.23 138.92,89.23 138.62,88.93 138.08,88.93 UC1.P2
CAP_LED: length 6
  TOP w0.102: R6201.2 195.48,114.1 v1(195.48,114.66)
  TOP w0.254: R6201.2 194.35,113.09 194.35,114.19 194.04,114.5 193.53,114.5 192.78,113.75 KB1.4
CAP_LED#: length 52.8
  TOP w0.203: UE1.93 178.36,69.97 178.43,70.04 178.43,70.04 178.48,70.09 178.49,70.09 178.86,70.46 179.8,70.46 180.69,71.35 181.91,71.35 182.99,72.43 185.79,72.43 186.35,71.87 190.61,71.87 190.81,72.07 v2(190.81,73.91)
  TOP w0.254: v2(192.3,92.09) 195.84,92.09 195.94,92.19 195.94,93.41 195.51,93.84 195.51,97.14 196.07,97.7 196.07,98.82 195.51,99.38 195.51,100.47 R6202.2 v1(195.08,102.08) 195.08,102.63 196.6,104.15 Q6206.3
  IN2 w0.254: v2(190.81,73.91) 191.19,74.29 191.19,80.77 192.61,82.19 192.61,91.77 v2(192.3,92.09)
CAP_LED_Q: length 10
  TOP w0.102: R6201.1 195.71,113.41 195.71,114 196.45,114.73 v1(196.45,116.2)
  TOP w0.254: R6201.1 195.33,112.83 194.72,112.22 194.16,112.22 193.6,111.66 193.6,110.13 194.8,108.94 Q6201.1
CAP_LED_R#: length 7.9
  TOP w0.102: v1(196.5,113.23) 196.5,112.88 196.78,112.6 196.78,111.91 196.48,111.61 Q6201.2 197.08,110.41 197.08,107.9 Q6206.1
CASA0#: length 44.8
  TOP w0.102: UV18.K3 175.04,164.44 174.78,164.69 v2(174.78,165.23)
  IN1 w0.102: 168.74,143.79 168.53,143.79 167.07,142.32 167.07,142.28 166.58,141.79 v2(166.1,141.79)
  IN1 w0.264: 168.74,143.79 171.6,143.79 174.2,146.4 174.58,146.4 175.76,145.21 176.13,145.21 176.51,145.59 176.51,145.96 175.33,147.14 175.33,147.52 178.09,150.28 178.09,156.32 179.63,157.86 v2(180.65,157.86)
  IN2 w0.102: v2(180.65,157.86) 180.65,160.11 178.87,161.89 178.87,162.74 176.61,165 175.6,165 175.37,165.23 v2(174.78,165.23)
  BOTTOM w0.102: UV1.G19 166.1,141.34 v2(166.1,141.79) ; v2(174.78,165.23) 174.53,165.23 174.36,165.4 174.36,165.63 174.46,165.73 174.69,165.73 174.79,165.83 174.79,165.98 174.52,166.25 174.52,166.58 UV17.K3
CASA1#: length 48.5
  TOP w0.102: v2(188.65,151.32) 188.84,151.13 189.32,151.13 189.46,151 189.6,151 189.72,151.12 189.72,151.27 189.61,151.38 189.61,151.49 189.73,151.61 189.88,151.61 190.12,151.36 UV20.K3
  IN1 w0.127: v2(188.65,151.32) 188.65,151.91 188.39,152.17 188.39,152.98 186.75,154.61 183.98,154.61 v2(183.13,155.46)
  IN2 w0.102: 171.32,143.87 171.32,143.44 168.14,140.26 168.14,139.72 v2(168.63,139.23)
  IN2 w0.264: v2(183.13,155.46) 183.13,155.69 182.39,156.44 182.02,156.44 181.54,155.96 181.54,155.57 182.28,154.83 182.28,153.33 181,152.04 180.63,152.04 180.05,152.62 180.05,153 180.95,153.9 180.95,154.28 180.58,154.65 180.21,154.65 179.3,153.74 178.92,153.74 178.08,154.59 176.85,154.59 172.28,150.02 172.28,146.73 171.32,145.76 171.32,143.87
  BOTTOM w0.102: v2(188.65,151.32) 188.14,151.32 187.83,151.64 187.83,153.2 UV19.K3 ; v2(168.63,139.23) 168.41,139.44 UV1.G16
CBN: length 2.1
  BOTTOM w0.203: HDA27.35 187.3,14.49
  BOTTOM w0.305: C2703.1 188.08,13.7 187.3,14.49
CBP: length 3.6
  BOTTOM w0.102: v1(189.29,12.19) 189.1,12 C2703.2
  BOTTOM w0.305: 186.14,12.92 186.91,12.92 187.83,12 C2703.2
CCLIM: length 4.3
  BOTTOM w0.203: PR750.1 PR752.2 108.12,161.85 v1(108.49,161.85) 108.85,161.85 109.38,161.32 PU703.11
CFG0: length 13.4
  TOP w0.102: T21.1 96.14,98.81 v2(96.1,98.77)
  BOTTOM w0.076: UC1.E68 100.47,95.06 100.54,95.33 100.58,95.59 100.63,95.77 100.68,95.92 100.68,95.96 100.68,95.97 100.68,96.08 100.68,96.14 100.66,96.22 100.65,96.31 100.65,96.45 100.68,96.55 100.68,96.91 100.68,96.91 100.68,97.06 100.53,97.21 100.53,97.56 100.16,97.93 98.86,97.93
  BOTTOM w0.102: RC113.2 95.31,99.57 v2(96.1,98.77) 96.45,98.42 98.37,98.42 98.86,97.93
CFG1: length 12.4
  BOTTOM w0.089: 98.05,97.54 99.07,97.54 99.62,96.98 99.72,96.98 99.94,96.77 99.94,96.35 UC1.B67
  BOTTOM w0.102: 98.05,97.54 97.84,97.75 95.24,97.75 94.06,98.93 92.26,98.93 91.75,98.43 RC112.2 90.44,98.2 T22.1
CFG2: length 1.5
  TOP w0.076: v2(102.29,94.36) 102.55,94.11 T23.1
  BOTTOM w0.076: v2(102.29,94.36) 101.92,94.73 UC1.D65
CFG3: length 11.8
  TOP w0.102: v2(94.88,98.86) 94.96,98.94 T24.1
  BOTTOM w0.076: UC1.D67 100.43,95.69 100.52,95.95 100.52,96.12 100.46,96.31 100.46,96.46 100.52,96.58 100.52,96.99 100.37,97.14 100.37,97.5 100.11,97.75 98.4,97.75 97.97,98.19
  BOTTOM w0.102: RC110.2 94.35,100.7 RC1104.2 93.85,99.89 v2(94.88,98.86) 95.54,98.19 97.97,98.19
CFG4: length 6
  TOP w0.102: v2(95.85,95.39) 96.11,95.65 T25.1
  BOTTOM w0.076: RC109.2 95.49,95.76 v2(95.85,95.39)
  BOTTOM w0.089: UC1.E70 98.21,94.38 97.98,94.61 97.72,94.61 96.94,95.39 v2(95.85,95.39)
CFG5: length 1.2
  TOP w0.076: v2(99.14,95.33) 99.17,95.31 T26.1
  BOTTOM w0.089: UC1.C68 99.19,95.33 v2(99.14,95.33)
CFG6: length 1.1
  TOP w0.076: T27.1 98.33,94.9 v2(98.34,94.91)
  BOTTOM w0.089: v2(98.34,94.91) UC1.D68
CFG7: length 6.5
  TOP w0.102: v2(94.82,96.72) 94.49,96.39 T28.1
  BOTTOM w0.089: 98.43,97.02 98.63,96.83 98.63,96.51 98.78,96.36 99.31,96.36 99.66,96.01 UC1.C67
  BOTTOM w0.102: 98.43,97.02 95.12,97.02 v2(94.82,96.72)
CFG8: length 9.2
  BOTTOM w0.076: UC1.F71 97.66,93.75 97.37,94.05 96.69,94.05 96.19,94.55 95.69,94.55
  BOTTOM w0.102: T31.1 90.33,94.55 91.42,94.55 91.9,95.03 94.13,95.03 94.61,94.55 95.69,94.55
CFG9: length 9.5
  BOTTOM w0.076: 95.72,93.59 96.13,93.59 96.34,93.39 97.06,93.39 97.59,92.86 97.94,92.86 98.02,92.89 98.03,92.9 98.06,92.92 98.2,92.92 98.43,92.85 98.56,92.85 98.78,92.93 99.03,92.93 UC1.G69
  BOTTOM w0.102: T32.1 91.22,92.31 92.45,93.54 93,93.54 93.07,93.47 94.13,93.47 94.26,93.59 95.72,93.59
CFG10: length 5.2
  TOP w0.102: v2(95.03,95.39) 94.69,95.05 T33.1
  BOTTOM w0.076: UC1.F70 98.61,94.02 98.1,94.02 98.03,93.96 97.7,93.96 97.45,94.21 96.81,94.21 96.19,94.84 95.58,94.84 v2(95.03,95.39)
CFG11: length 10.7
  BOTTOM w0.076: 95.72,94.28 96.23,94.28 96.62,93.88 97.29,93.88 97.61,93.56 98,93.56 98.38,93.4 98.72,93.4 98.8,93.32 99.18,93.32 99.25,93.3 UC1.G68
  BOTTOM w0.102: T34.1 91.15,93.6 92.08,94.54 94.05,94.54 94.31,94.28 95.72,94.28
CFG12: length 5.7
  BOTTOM w0.076: 95.72,93.14 95.92,93.14 96.82,92.23 97.97,92.23 98.11,92.18 98.21,92.18 98.34,92.23 98.58,92.23 UC1.H70
  BOTTOM w0.102: T35.1 94.02,92.5 94.65,93.14 95.72,93.14
CFG13: length 10
  BOTTOM w0.076: 95.72,93.82 96.17,93.82 96.44,93.55 97.14,93.55 97.56,93.13 UC1.G71
  BOTTOM w0.102: 95.72,93.82 94.22,93.82 94.05,93.66 93.2,93.66 92.81,94.04 92.27,94.04 91.26,93.03 89.78,93.03 T36.1
CFG14: length 8.6
  BOTTOM w0.076: 95.72,93.36 96.08,93.36 96.23,93.22 96.99,93.22 97.51,92.7 97.98,92.7 98.09,92.74 98.21,92.74 98.42,92.68 98.57,92.68 98.73,92.73 99.19,92.73 UC1.H69
  BOTTOM w0.102: T37.1 92.47,92.04 92.92,92.04 93.27,92.39 93.27,92.76 93.63,93.12 94.13,93.12 94.37,93.36 95.72,93.36
CFG15: length 5.4
  BOTTOM w0.076: UC1.G70 98.39,93.13 98.24,93.28 97.97,93.4 97.54,93.4 97.22,93.72 96.53,93.72 96.2,94.05 95.72,94.05
  BOTTOM w0.102: 95.72,94.05 93.47,94.05 T38.1
CFG16: length 1.4
  TOP w0.076: T30.1 103.35,93.31 v2(103.35,93.51)
  BOTTOM w0.089: v2(103.35,93.51) UC1.E63
CFG17: length 1.4
  TOP w0.076: T29.1 101.74,92.96 v2(102.33,93.55)
  BOTTOM w0.089: v2(102.33,93.55) UC1.F63
CFG18: length 1.1
  TOP w0.076: T40.1 100.53,94.15 v2(100.3,94.15)
  BOTTOM w0.089: UC1.E66 100.76,94 v2(100.3,94.15)
CFG19: length 1.1
  TOP w0.076: T39.1 100.21,93.55 v2(100.29,93.55)
  BOTTOM w0.089: v2(100.29,93.55) UC1.F66
CFG_RCOMP: length 13
  TOP w0.102: RC114.1 v2(98.66,102.49) 98.66,102.48 v1(98.3,102.13)
  IN1 w0.254: v2(104.26,94.18) 104.26,94.81 98.66,100.41 v2(98.66,102.49)
  BOTTOM w0.254: v2(104.26,94.18) 104.33,94.15 UC1.E60
CHG_AMBER_LED_R#: length 5.1
  TOP w0.102: QC4.6 35.76,9 36.2,8.56 Q6101.2 36.2,6.46 36.9,5.77 v1(37.83,5.77)
CKEA0: length 46.6
  TOP w0.102: v2(175.19,164.82) 175.17,164.84 175.17,165.43 174.73,165.88 174.73,166.9 173.98,167.64 173.46,167.64 UV18.K9
  IN1 w0.102: 168.52,144.21 167.44,143.13 166.84,143.13 164.62,140.91 164.28,140.91 v2(163.93,141.26)
  IN1 w0.264: 168.52,144.21 171.36,144.21 177.62,150.47 177.62,156.51 179.43,158.33 180.51,158.33 180.89,158.7 180.89,159.82 180.62,160.08 v2(180.08,160.08)
  IN2 w0.102: v2(180.08,160.08) 180.08,160.25 177.86,162.47 177.86,163.09 176.15,164.8 175.52,164.8 175.5,164.82 v2(175.19,164.82)
  BOTTOM w0.102: v2(175.19,164.82) 176.95,164.82 178.18,163.59 178.18,163.45 178.03,163.3 UV17.K9 ; v2(163.93,141.26) 163.93,140.47 UV1.K20
CKEA1: length 47
  TOP w0.102: v2(189.22,151.92) 189.19,151.95 188.62,151.95 188.18,152.39 188.18,153.46 188.04,153.61 187.64,153.61 187.51,153.48 187.16,153.48 186.73,153.91 UV20.K9
  IN1 w0.127: v2(189.22,151.92) 189.22,152.47 188.94,152.74 188.94,153.25 186.94,155.25 186.94,155.32 186.28,155.98 185.19,155.98 184.46,156.71 v2(184.46,157.04)
  IN2 w0.102: v2(165.88,139.87) 167.46,139.87 170.87,143.28 170.87,143.64
  IN2 w0.264: v2(184.46,157.04) 184.22,157.28 182.19,157.28 179.97,155.06 176.66,155.06 171.81,150.21 171.81,146.92 170.87,145.98 170.87,143.64
  BOTTOM w0.102: v2(189.22,151.92) 189.44,151.7 190.07,151.7 191.92,149.85 191.92,149.7 191.73,149.51 191.59,149.51 UV19.K9 ; v2(165.88,139.87) 166.02,139.73 UV1.J17
CLK_ITPXDP_N: length 1.3
  TOP w0.102: T4943.1 114.63,93.64 v2(114.41,93.64)
  BOTTOM w0.089: v2(114.41,93.64) 114.37,93.64 114.04,93.31 UC1.F43
CLK_ITPXDP_P: length 1.5
  TOP w0.076: 114.45,94.39 v2(114.55,94.39)
  TOP w0.102: T4944.1 114.12,94.39 114.45,94.39
  BOTTOM w0.089: v2(114.55,94.39) 114.41,94.25 114.24,94.25 113.95,93.96 UC1.E43
CLK_LAN_REQ2#_R: length 8.9
  TOP w0.102: LOM30.12 49.11,166.49 49.17,166.43 49.17,165.39 49.65,164.91 49.65,164.15 v1(52,161.8) 52.27,161.53 53.89,161.53 54.06,161.7 R3005.2
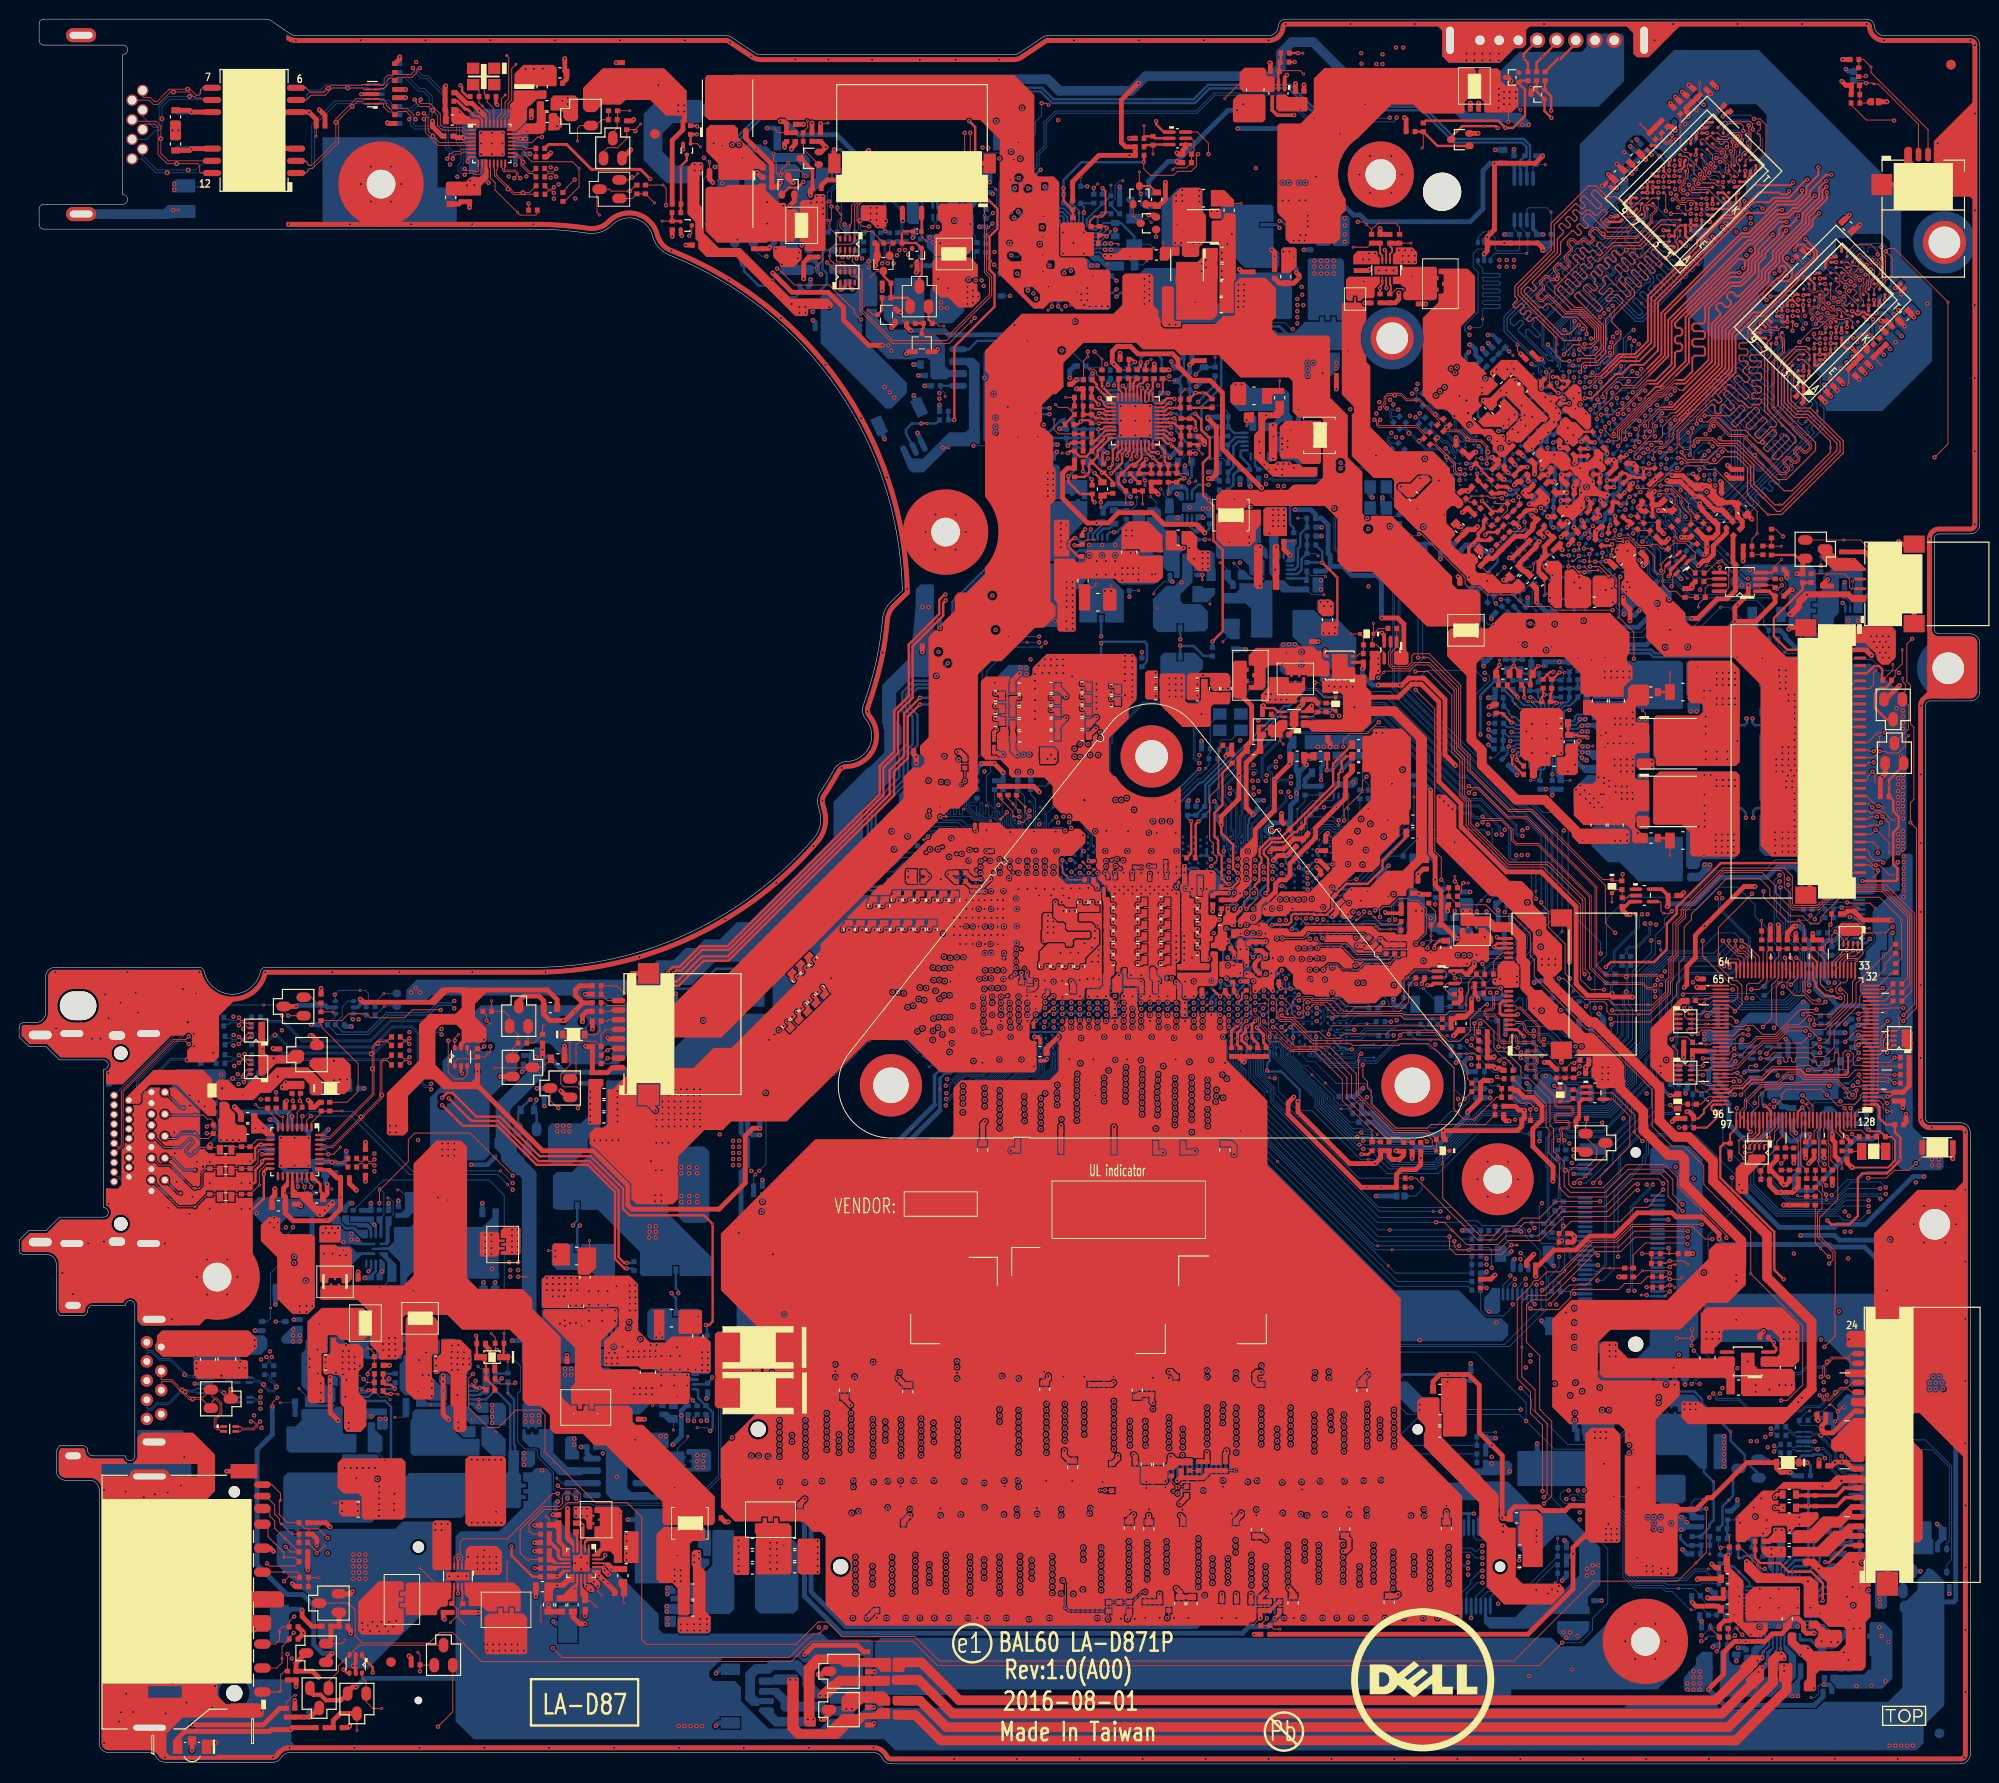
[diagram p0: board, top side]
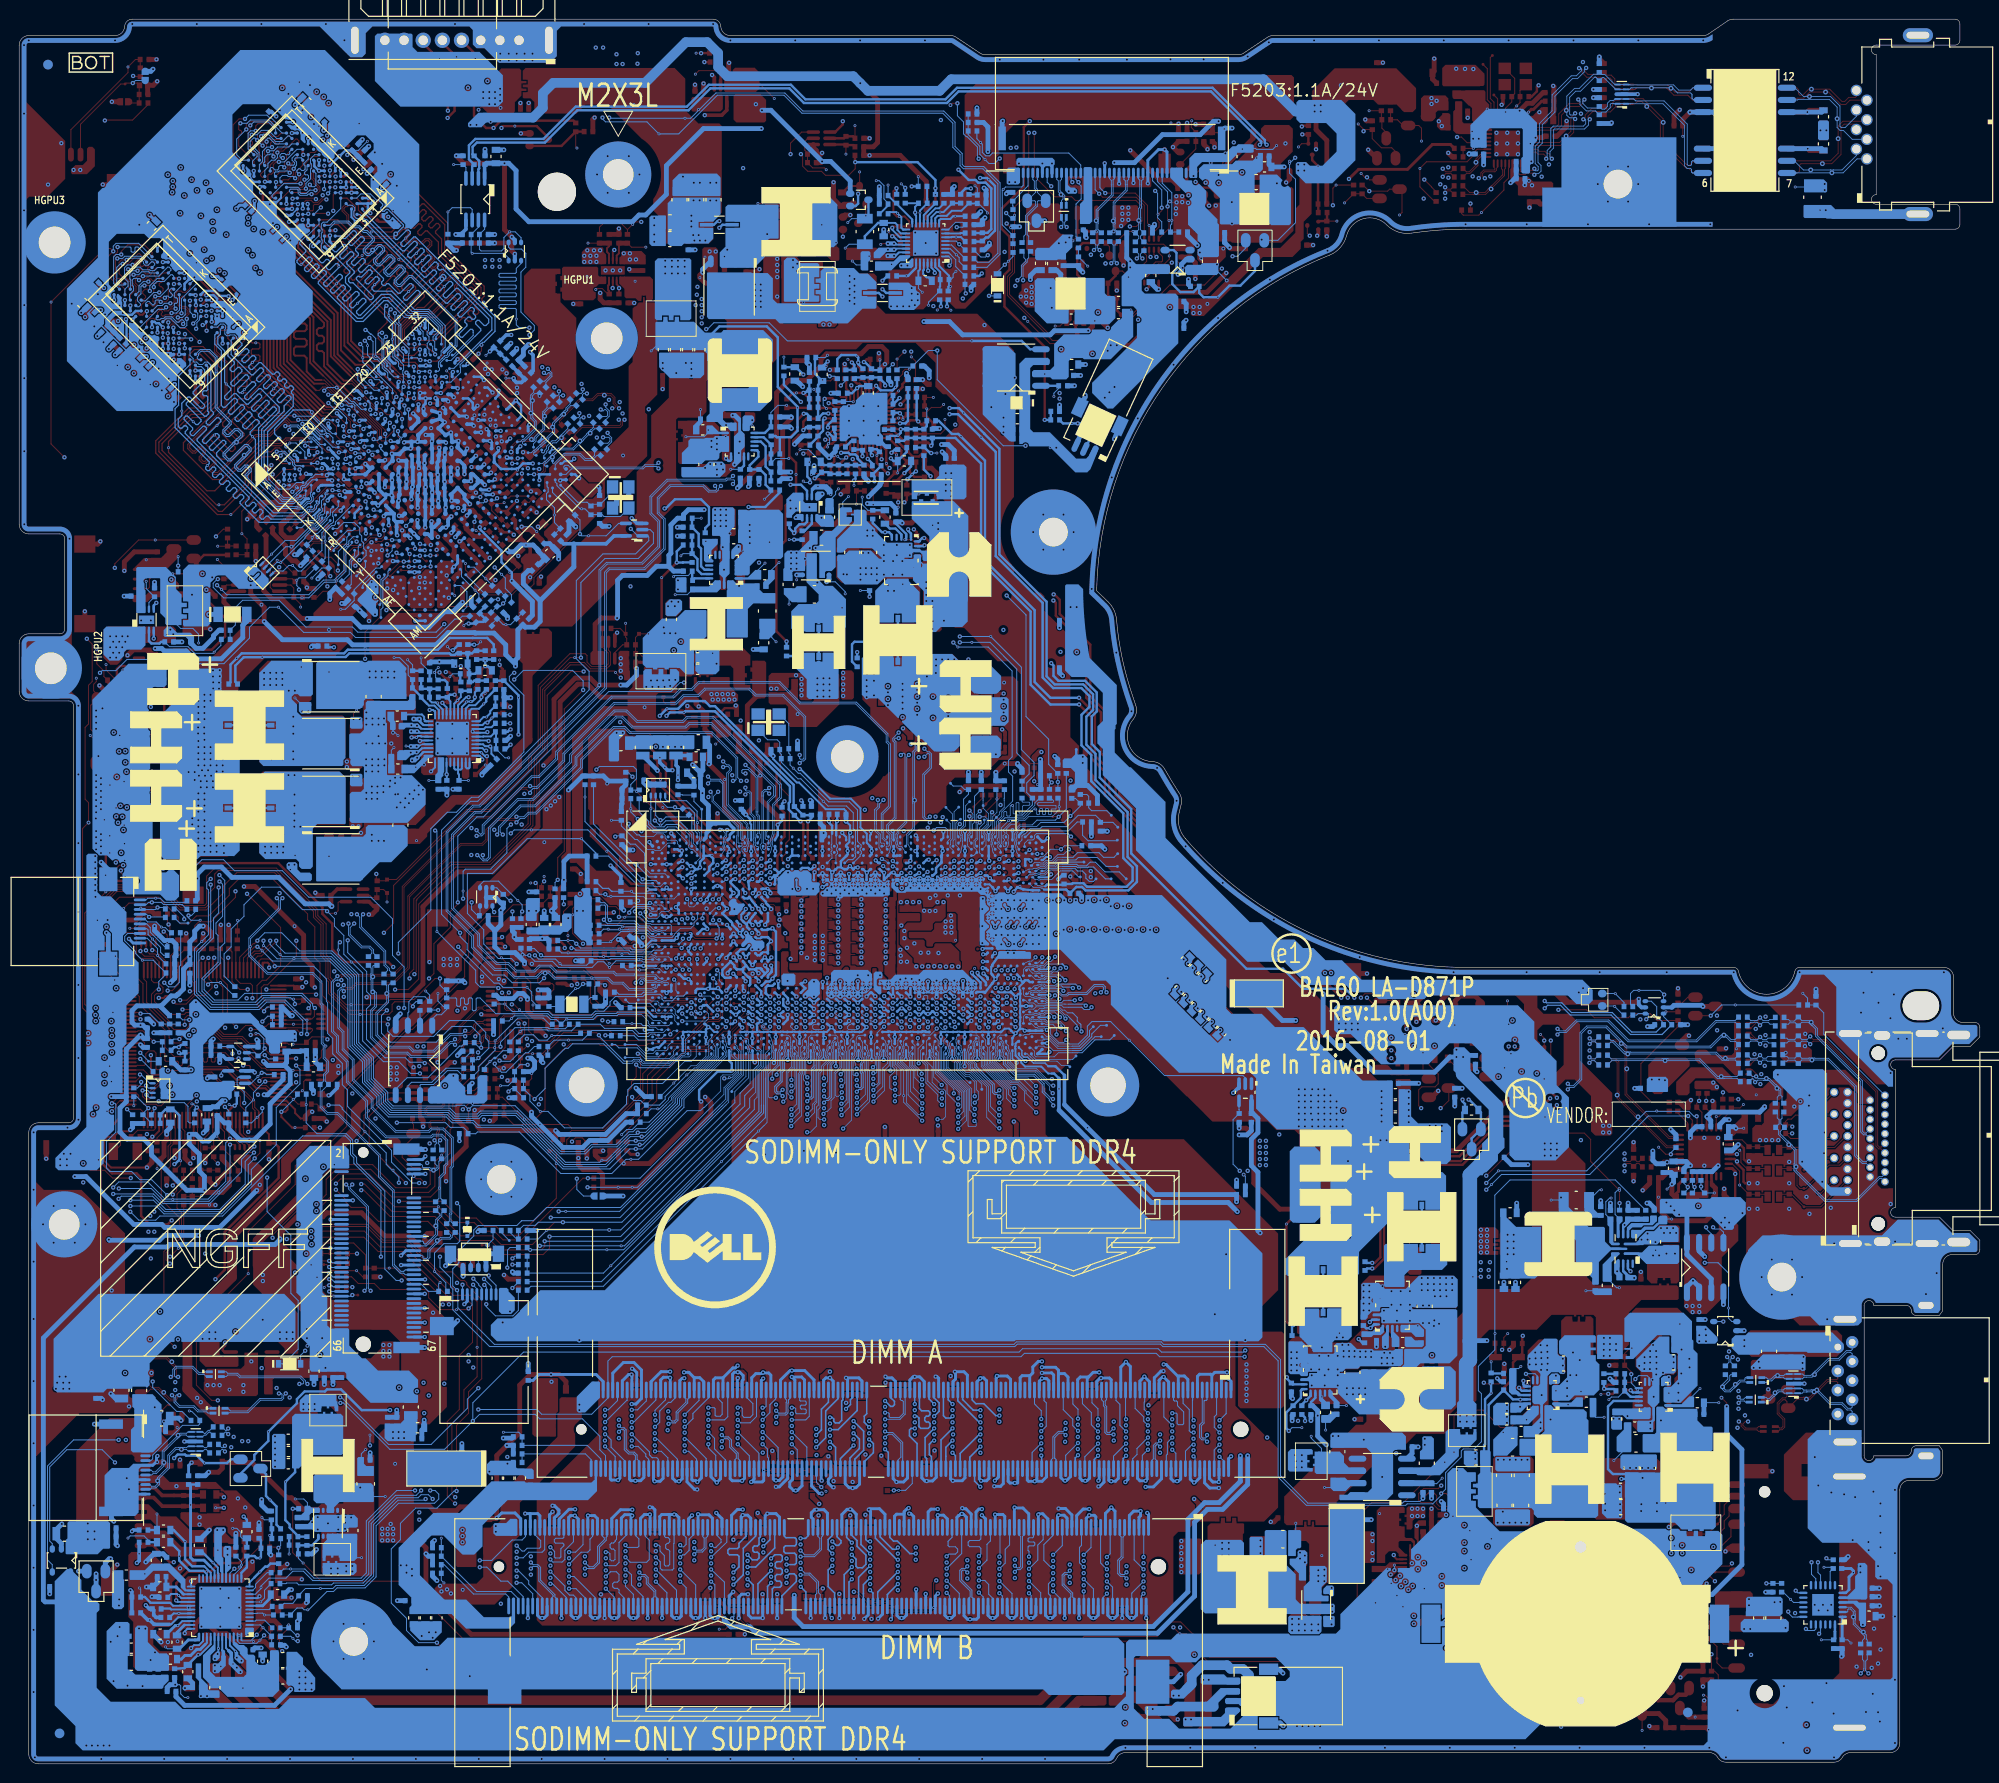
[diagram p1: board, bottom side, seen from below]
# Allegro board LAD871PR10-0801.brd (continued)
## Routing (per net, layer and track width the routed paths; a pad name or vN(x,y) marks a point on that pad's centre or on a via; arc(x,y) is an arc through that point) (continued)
CLK_PCI_LPC_MEC: length 48.7
  TOP w0.102: v2(180.22,79.85) 180.22,81.18 180.44,81.41 181.48,81.41 181.95,81.88 UE1.57 181.95,84.86 R2455.2
  IN1 w0.127: v2(180.22,79.85) 179.42,79.06 177.16,79.06 176.26,79.95 175.51,79.95 174.87,79.31 173.57,79.31 172.81,78.55 168.84,78.55 168.43,78.15 165.67,78.15 v2(164.97,78.85) ; v2(153.5,70.12) 153.09,70.12 151.94,71.28 151.94,75.27 v2(151.58,75.63)
  IN2 w0.127: v2(151.58,75.63) 151.71,75.76 154.58,75.76 154.98,75.36 155.75,75.36 157.7,77.31 158.77,77.31 159.57,78.1 159.57,78.9 160.62,79.95 164.05,79.95 164.97,79.03 v2(164.97,78.85)
  BOTTOM w0.102: CC4.2 152.85,70.4 RC18.2 153.2,70.42 v2(153.5,70.12)
CLK_PCI_LPDEBUG: length 32.3
  IN1 w0.127: v2(151.5,72.91) 151.5,71.1 152.66,69.94 152.66,65.21 153.97,63.9 155.32,63.9 157.58,61.65 157.58,57.64 158.78,56.44 158.78,50.71 158.3,50.23 v2(158.3,49.97)
  BOTTOM w0.102: DB1.1 158.3,49.97 v2(158.3,49.97) ; v2(151.5,72.91) 151.52,72.92 152.29,72.92 152.86,72.35 CC5.2 RC22.2 152.95,71.31 153.54,70.73 v1(154.34,70.73)
CLK_PCIE_LAN_N2: length 120.1
  TOP w0.091: LOM30.16 50.71,166.54 50.6,166.43 50.6,166.3 50.66,166.23 51.76,166.23 52.05,165.94 52.05,165.61 v2(52.27,165.38)
  IN2 w0.127: v2(52.27,165.38) 52.09,165.19 52.09,164.97 54.5,162.56 60.91,162.56 61.86,163.52 67.85,163.52 72.81,158.56 74.42,158.56 79.31,153.67 82.1,153.67 83.69,152.08 83.69,149.46 92.07,141.08 92.07,138.51 100.28,130.3 100.28,124.67 97.56,121.95 97.56,109.41 101.34,105.62 101.34,103.92 102.27,102.99 105.84,102.99 105.9,102.93 113.14,102.93 114.8,101.26 114.8,100.69 v2(114.96,100.53)
  BOTTOM w0.076: UC1.D41 114.85,95.59 114.85,96.88 115.3,97.34 115.3,98.02 115.31,98.02 115.31,98.04
  BOTTOM w0.091: 115.31,98.04 115.31,99.51 115.3,99.51 114.96,99.85 v2(114.96,100.53)
CLK_PCIE_LAN_P2: length 120.1
  TOP w0.091: LOM30.15 50.31,166.54 50.42,166.43 50.42,166.22 50.59,166.05 51.68,166.05 51.87,165.86 51.87,165.62 v2(51.64,165.38)
  IN2 w0.127: v2(114.38,100.53) 114.55,100.7 114.55,101.16 113.03,102.67 105.79,102.67 105.73,102.73 102.16,102.73 101.09,103.81 101.09,105.52 97.3,109.3 97.3,122.06 100.02,124.77 100.02,130.19 91.81,138.4 91.81,140.97 83.43,149.35 83.43,151.97 81.99,153.42 79.2,153.42 74.31,158.31 72.7,158.31 67.75,163.26 61.97,163.26 61.01,162.3 54.39,162.3 51.83,164.87 51.83,165.19 v2(51.64,165.38)
  BOTTOM w0.076: 115.13,98.04 115.13,98.02 115.13,98.02 115.13,97.4 114.68,96.95 114.68,96.09 114.62,96.03 114.36,96.03 114.29,95.96 114.29,95.77 114.35,95.71 UC1.C41
  BOTTOM w0.091: 115.13,98.04 115.13,99.43 114.78,99.77 114.78,100.13 v2(114.38,100.53)
CLK_PCIE_LAN_REQ#: length 295.6
  TOP w0.102: v2(173.54,58.36) 172.52,59.37 172.52,60.96 171.47,62.01 167.88,62.01 165.47,59.6 161.83,59.6 161.18,60.25 161.18,62.78 v1(160.47,63.49) 160.08,63.89 160.08,66.23 159.71,66.6 159.71,69.31 157.52,71.5 156.9,71.5 156.68,71.72 156.68,72.72 155.12,74.29 154.27,74.29 153.85,74.7 153.85,76.43 152.66,77.62 152.22,77.62 151.82,77.22 v2(151.82,77.22) 151.82,75.96 152.25,75.53 RC50.2 ; R3005.1 v2(53.14,162.74)
  IN1 w0.127: v2(53.14,162.74) 54.13,161.75 59.7,161.75 61.02,163.07 69.06,163.07 75.74,156.39 79.95,156.39 80.22,156.12 80.22,154.61 82.28,152.55 87.6,152.55 89.36,154.32 90.42,154.32 97.01,147.73 104.93,147.73 107.31,145.34 110.74,145.34 111.55,144.53 112.63,144.53 113.2,145.09 118.93,145.09 119.64,145.81 120.57,145.81 121.17,146.41 122.35,146.41 123.28,145.47 123.28,142.41 124.45,141.24 124.45,138.69 126.85,136.29 126.85,132.66 127.77,131.75 129,131.75 129.7,131.05 129.7,128.64 130.35,127.99 131.57,127.99 132.07,127.48 132.07,125.48 135.48,122.07 136.11,122.07 136.35,122.31 137.48,122.31 138.98,120.82 138.98,114.17 140.18,112.97 140.18,107.01 141.57,105.62 141.57,100.3 147.17,94.71 151.51,94.71 153.59,92.63 158.05,92.63 160.72,89.95 160.72,88.72 163.4,86.04 165.41,86.04 167.19,84.27 173.03,84.27 173.73,83.57 176.45,83.57 177.67,82.36 178.75,82.36 179.13,82.74 181.41,82.74 181.98,82.17 189.41,82.17 190.44,81.14 190.44,79.7 188.82,78.08 188.82,73.47 187.8,72.45 187.8,69.34 187.99,69.15 187.99,67.73 187.23,66.97 187.23,63.97 187.39,63.8 187.39,62.32 187.09,62.02 187.09,58.28 185.64,56.83 177.83,56.83 176.31,58.36 v2(173.54,58.36)
  IN2 w0.076: v2(134.41,78.26) 134.82,77.85 135.56,77.85 135.9,78.19 137.95,78.19
  IN2 w0.127: v2(151.82,77.22) 149.66,77.22 149.37,76.93 140.11,76.93 138.84,78.19 137.95,78.19
  BOTTOM w0.076: v2(134.41,78.26) 133.98,77.83 UC1.AT8
CLK_PCIE_WLAN_N1: length 141.8
  IN2 w0.127: v2(156.83,96.78) 159.56,96.78 162.24,94.1 162.87,94.1 165.6,91.37 170.18,91.37 170.87,90.68 172.48,90.68 174.02,89.13 176.91,89.13 177.5,89.73 177.5,90.13 v2(177.67,90.29)
  BOTTOM w0.076: 114.61,97.41 114.61,97.22 114.52,97.13 114.52,96.53 114.24,96.25 114.1,96.25 113.99,96.14 UC1.B42
  BOTTOM w0.091: v2(177.67,90.29) 177.47,90.09 177.47,89.26 180.59,86.13 180.59,84.26 178.69,82.36 173.97,82.36 173.15,81.55 173.15,79.25 173.03,79.13 173.03,75.12 172.83,74.92 172.83,73.58 172.45,73.2 172.45,72.27 172.8,71.92 172.8,71.21 EC5801.1 173.15,68.45 172.45,67.75 171.38,67.75 167.06,63.44 167.06,61.21 165.6,59.75 165.6,51.98 165.41,51.79 ; v2(156.83,96.78) 156.83,96.79 156.29,96.79 156.06,97.02 156.06,97.85 151.03,102.87 150.3,102.87 148.39,104.77 148.39,105.48 142.69,111.18 136.27,111.18 135.47,111.98 134.33,111.98 133.6,112.71 125.28,112.71 123.12,110.55 117.28,110.55 114.1,107.37 114.1,106.56 113.83,106.29 113.83,99.9 114.61,99.12 114.61,97.41
  BOTTOM w0.102: WLAN1.41 164.27,51.02 164.43,51.17 164.8,51.17 165.41,51.79
CLK_PCIE_WLAN_P1: length 141.7
  IN2 w0.127: v2(177.08,90.29) 177.25,90.13 177.25,89.84 176.8,89.39 174.13,89.39 172.59,90.93 170.98,90.93 170.28,91.63 165.71,91.63 162.98,94.36 162.34,94.36 159.67,97.04 157.17,97.04 v2(156.83,97.38)
  BOTTOM w0.076: 114.43,97.41 114.43,97.4 114.44,97.39 114.44,97.28 114.35,97.2 114.35,96.6 114.17,96.42 114.06,96.42 113.99,96.49 113.99,96.68 UC1.A42
  BOTTOM w0.091: v2(177.08,90.29) 177.29,90.09 177.29,89.18 180.41,86.06 180.41,84.34 178.61,82.54 173.89,82.54 172.97,81.63 172.97,79.32 172.85,79.2 172.85,75.2 172.65,75 172.65,73.66 172.27,73.28 172.27,72.2 172.62,71.85 172.62,71.21 EC5802.1 172.96,70.18 172.96,68.52 172.38,67.93 171.3,67.93 166.88,63.51 166.88,61.29 165.42,59.83 165.42,52.07 165.41,52.06 ; v2(156.83,97.38) 156.83,97.35 156.44,96.97 156.37,96.97 156.24,97.1 156.24,97.92 151.11,103.05 150.37,103.05 148.57,104.85 148.57,105.55 142.77,111.36 136.35,111.36 135.55,112.16 134.41,112.16 133.67,112.89 125.21,112.89 123.05,110.73 117.2,110.73 113.92,107.45 113.92,106.63 113.65,106.37 113.65,99.83 114.43,99.05 114.43,97.41
  BOTTOM w0.102: WLAN1.39 164.27,51.52 164.43,51.37 164.72,51.37 165.41,52.06
CLK_PCIE_WLAN_REQ#: length 54.4
  TOP w0.102: v2(152.46,77.22) 152.25,77.01 RC47.2
  IN1 w0.127: v2(152.46,77.22) 152.37,77.13 152.37,71.46 153.26,70.57 153.69,70.57 153.98,70.27 153.98,69.31 153.1,68.43 153.1,65.49 154.25,64.33 155.5,64.33 158.01,61.82 158.01,59.34 v2(158.87,58.48)
  IN2 w0.076: v2(135.38,78.25) 135.74,78.61 138.23,78.61
  IN2 w0.127: 138.23,78.61 139.03,78.61 139.67,77.98 150.46,77.98 150.79,77.65 152.02,77.65 v2(152.46,77.22)
  BOTTOM w0.076: UC1.AT7 134.95,77.82 v2(135.38,78.25)
  BOTTOM w0.102: v2(158.87,58.48) 158.58,58.2 158.58,54.52 158.84,54.26 160.24,54.26 161.22,53.28 v1(161.22,51.36) 160.04,50.18 160.04,49.44 R5803.2
CLK_PCIE_WLAN_REQ#_R: length 3.9
  BOTTOM w0.102: v1(160.64,50.2) 160.79,50.05 R5803.1 161.84,49.28 162.59,50.02 WLAN1.45
CLK_PEG_VGA: length 84.9
  IN2 w0.127: v2(112.8,106.98) 112.96,107.14 113.86,107.14 115.11,108.39 120.22,108.39 122.82,105.79 129.91,105.79 130.93,106.81 133.79,106.81 134.68,107.7 138.81,107.7 142.46,111.35 142.46,117.26 143.25,118.05 143.25,120.14 141.91,121.48 141.47,121.48 137.99,124.96 137.99,134.26 137.38,134.86 137.38,135.15 137.51,135.28 137.69,135.28 v2(137.85,135.12)
  BOTTOM w0.076: UC1.D42 113.77,95.06 113.7,95.33 113.7,95.44 113.65,95.62 113.61,95.74 113.56,95.92 113.56,96.14 113.59,96.25 113.59,96.47 113.56,96.54 113.56,96.93 113.87,97.24 113.87,97.39 113.86,97.4 113.86,97.41
  BOTTOM w0.091: v2(112.8,106.98) 113.13,106.98 113.22,106.89 113.22,106.76 113.07,106.61 113.07,98.63 113.86,97.84 113.86,97.41 ; v2(137.85,135.12) 138.05,135.32 139.2,135.32 139.45,135.07 146.92,135.07 147.5,134.49 UV1.AK30
CLK_PEG_VGA#: length 84.9
  IN2 w0.127: v2(137.85,135.7) 137.69,135.54 137.4,135.54 137.13,135.26 137.13,134.76 137.73,134.15 137.73,124.85 141.36,121.22 141.81,121.22 143,120.03 143,118.16 142.21,117.37 142.21,111.46 138.7,107.95 134.57,107.95 133.68,107.06 130.82,107.06 129.81,106.05 122.93,106.05 120.32,108.65 115,108.65 113.75,107.4 112.96,107.4 v2(112.8,107.56)
  BOTTOM w0.076: 114.04,97.41 114.03,97.4 114.03,97.17 113.72,96.86 113.72,96.58 113.76,96.51 113.76,96.22 113.72,96.12 113.72,95.95 113.78,95.79 113.85,95.72 114.04,95.72 114.09,95.67 114.09,95.49 UC1.C42
  BOTTOM w0.091: 114.04,97.41 114.04,97.92 113.25,98.7 113.25,106.54 113.4,106.69 113.4,106.96 v2(112.8,107.56) ; UV1.AK32 147.63,135.06 147.72,135.14 147.72,135.33 147.61,135.44 147.28,135.44 147.09,135.25 139.52,135.25 139.28,135.5 138.06,135.5 v2(137.85,135.7)
CLK_SMB: length 4.8
  TOP w0.254: PBATT1.6 162.4,179.44 160.79,177.83 v1(160.7,177.83) 160.53,177.83 PR18.1
CLK_TP_SIO: length 293.9
  TOP w0.102: UE1.78 178.83,75.97 179.47,76.61 v2(180.4,76.61) ; v2(64.57,79.91) 64.15,80.33 63.18,80.33 62.35,81.15 v1(62.07,81.15) RZ19.2 CZ31.1 61.37,79.61 TPAD1.8
  IN1 w0.127: v2(51.24,50.8) 49.97,52.07 49.97,58.36 49.46,58.86 49.46,64.52 46.86,67.12 43.3,67.12 41.84,68.58 41.84,77.22 43.74,79.12 44.25,79.12 45.27,78.1 50.54,78.1 52.19,79.76 62.86,79.76 63.43,79.18 63.85,79.18 v2(64.57,79.91) ; v2(157.66,42.64) 158.55,41.76 166.5,41.76 167.19,42.45 167.19,45.87 167.51,46.18 167.51,48.6 166.11,50 166.11,54.86 161.22,59.75 161.22,60.96 161.03,61.15 161.03,62.78 159.5,64.32 159.5,65.76 164.34,70.6 164.34,74.06 166.01,75.73 167.81,75.73 169.61,77.53 176.75,77.53 177.68,76.61 v2(180.4,76.61)
  IN2 w0.127: v2(51.24,50.8) 51.24,49.98 54.22,47 54.22,40.83 56.57,38.48 56.57,31.95 61.09,27.43 76.85,27.43 81.99,22.29 81.99,18.44 84.68,15.75 101.17,15.75 102.77,14.15 154.14,14.15 160.74,20.75 160.74,33.99 158.17,36.56 158.17,42.13 v2(157.66,42.64)
CLKA0: length 57.6
  TOP w0.102: v2(174.05,163.72) 173.51,163.72 173.18,164.05 173.18,164.48 173.61,164.91 173.61,165.18 173.83,165.4 UV18.J7 ; v2(172.84,169.42) 172.59,169.42 172.47,169.3 172.11,168.94 171.73,168.94 171.22,169.46 RV43.1
  IN1 w0.102: v2(174.05,163.72) 174.32,163.72 174.33,163.71 174.89,163.71 175.33,164.15 175.76,164.15 177.73,162.18 177.73,161.24 177.08,160.59 177.08,159.29 177.07,159.28 177.07,159.26 ; 169.74,147.31 169.72,147.29 169.72,147.28 169.19,146.75 163.59,146.75 162.17,145.33 162.17,145.1 161.8,144.72 161.59,144.72 161.49,144.83 161.49,144.97 v2(161.72,145.2)
  IN1 w0.109: 169.74,147.31 175.25,152.81 175.25,153.14 175.14,153.25 173.84,153.25 173.62,153.47 173.62,153.96 173.84,154.19 175.16,154.19 175.27,154.3 175.27,154.63 175.16,154.74 173.84,154.74 173.62,154.96 173.62,155.45 173.84,155.68 175.16,155.68 175.27,155.79 175.27,156.12 175.16,156.22 174.48,156.22 174.25,156.45 174.25,156.94 174.48,157.17 175.1,157.17 177.07,159.13 177.07,159.26
  IN2 w0.102: v2(172.84,169.42) 172.56,169.42 172.21,169.06 172.21,168.69 172.31,168.59 172.9,168.59 174.06,167.43 174.06,166.04 173.62,165.59 173.62,165.45 173.78,165.29 173.78,165.06 173.82,165.01 173.82,164.55 174.05,164.32 v2(174.05,163.72)
  BOTTOM w0.102: v2(174.05,163.72) 174.4,163.72 174.52,163.6 175.25,163.6 175.45,163.8 175.45,164.15 175.55,164.25 176.24,164.25 176.36,164.13 176.36,163.99 176.23,163.87 UV17.J7 ; UV1.H26 161.64,145.12 v2(161.72,145.2)
CLKA0#: length 57.6
  TOP w0.102: v2(172.43,169.83) 172.43,169.53 172.28,169.38 172.28,169.38 172.03,169.13 171.81,169.13 171.35,169.59 RV44.1 ; UV18.K7 174.26,166.84 174.12,166.84 174.02,166.74 174.02,166.41 174.16,166.27 174.16,165.97 174.02,165.84 174.02,165.32 173.8,165.1 173.8,164.83 173.37,164.4 173.37,164.23 173.47,164.13 v2(173.63,164.13)
  IN1 w0.102: v2(173.63,164.13) 173.66,164.1 174.2,164.1 174.41,163.9 174.81,163.9 175.25,164.34 175.84,164.34 177.92,162.26 177.92,161.16 177.27,160.51 177.27,159.29 177.27,159.28 177.27,159.26 ; 169.88,147.17 169.87,147.15 169.86,147.15 169.86,147.15 169.27,146.56 163.67,146.56 162.36,145.25 162.36,144.74 v2(162.23,144.61)
  IN1 w0.109: 169.88,147.17 175.44,152.73 175.44,153.22 175.22,153.45 173.93,153.45 173.82,153.55 173.82,153.88 173.93,153.99 175.24,153.99 175.47,154.22 175.47,154.71 175.24,154.93 173.93,154.93 173.82,155.04 173.82,155.37 173.93,155.48 175.24,155.48 175.47,155.71 175.47,156.2 175.24,156.42 174.56,156.42 174.45,156.53 174.45,156.86 174.56,156.97 175.19,156.97 177.27,159.05 177.27,159.26
  IN2 w0.102: v2(172.43,169.83) 172.43,169.55 172.01,169.14 172.01,168.62 172.23,168.4 172.82,168.4 173.87,167.36 173.87,166.12 173.43,165.67 173.43,165.37 173.59,165.21 173.59,164.98 173.63,164.93 v2(173.63,164.13)
  BOTTOM w0.102: v2(162.23,144.61) 162.2,144.58 UV1.H25 ; UV17.K7 175.47,164.44 175.26,164.23 175.26,163.88 175.17,163.79 174.6,163.79 174.26,164.13 v2(173.63,164.13)
CLKA0_C: length 3.2
  TOP w0.112: RV43.2 170.06,170.1 v1(169.08,171.08)
  TOP w0.508: RV43.2 RV44.2 171.32,171.35 CV393.1
CLKA1: length 59.4
  TOP w0.102: RV66.1 193.46,148.54 193,149 192.19,149 191.95,148.76 191.76,148.57 v2(191.76,148.27) ; UV20.J7 187.3,152.98 187.39,153.07 187.54,153.07 187.77,152.83 187.77,152.18 187.61,152.02 187.16,152.02 186.83,151.68 186.83,151.22 187.07,150.99 v2(187.07,150.72)
  IN1 w0.102: v2(187.07,150.72) 187.07,150.87 187.04,150.9 187.04,151.76 187.19,151.91 187.19,152.74 186.37,153.55 184.8,153.55 183.9,152.65 183.41,152.65 180.27,149.51 180.27,148.74 180.27,148.74 180.27,148.71 ; 177.27,141.41 177.25,141.41 177.25,141.41 177.19,141.41 177.19,141.41 175.9,141.41 171.76,137.27 171.76,136.56 171.37,136.17 171.37,136.02 171.82,135.58 172.07,135.58 172.26,135.77 172.26,135.96 172.11,136.11 v2(171.88,136.11)
  IN1 w0.109: 180.27,148.71 180.27,148.22 179.81,147.76 178.74,147.76 178.61,147.63 178.61,147.14 178.72,147.03 180.03,147.03 180.26,146.81 180.26,146.32 180.03,146.09 178.72,146.09 178.61,145.98 178.61,145.65 178.72,145.55 180.03,145.55 180.26,145.32 180.26,144.83 180.03,144.6 178.72,144.6 178.61,144.49 178.61,144.17 178.72,144.06 180.03,144.06 180.26,143.83 180.26,143.34 180.03,143.11 178.72,143.11 178.61,143.01 178.61,141.66 178.36,141.41 177.27,141.41
  IN2 w0.102: v2(187.07,150.72) 187.44,150.72 187.67,150.48 188.32,150.48 188.76,150.92 191.21,150.92 192.14,149.99 192.14,148.97 191.76,148.59 v2(191.76,148.27)
  BOTTOM w0.102: UV19.J7 189.24,150.73 188.71,150.73 187.78,149.8 187.28,149.8 187.06,150.02 187.06,150.64 187.07,150.65 v2(187.07,150.72) ; v2(171.88,136.11) 171.88,135.68 UV1.G9
CLKA1#: length 59.4
  TOP w0.102: v2(187.44,150.18) 187.66,150.4 187.66,150.66 187.02,151.3 187.02,151.6 187.24,151.83 187.68,151.83 187.96,152.11 187.96,152.91 187.86,153.02 187.86,153.16 UV20.K7 ; v2(191.35,148.69) 191.61,148.69 191.76,148.84 192.11,149.19 193.08,149.19 193.6,148.68 RV67.1
  IN1 w0.102: 177.27,141.6 175.82,141.6 171.57,137.35 171.57,136.63 171.18,136.25 171.18,135.94 171.3,135.82 v2(171.3,135.54) ; v2(187.44,150.18) 187.44,150.56 187.45,150.56 187.45,150.88 187.23,151.1 187.23,151.68 187.38,151.83 187.38,152.81 186.45,153.74 184.73,153.74 183.82,152.84 183.33,152.84 181.54,151.05 180.41,149.91 180.08,149.59 180.08,148.74 180.08,148.74 180.08,148.71
  IN1 w0.109: 180.08,148.71 180.08,148.3 179.73,147.95 178.66,147.95 178.41,147.71 178.41,147.06 178.64,146.84 179.95,146.84 180.06,146.73 180.06,146.4 179.95,146.29 178.64,146.29 178.41,146.06 178.41,145.57 178.64,145.35 179.95,145.35 180.06,145.24 180.06,144.91 179.95,144.8 178.64,144.8 178.41,144.58 178.41,144.08 178.64,143.86 179.95,143.86 180.06,143.75 180.06,143.42 179.95,143.31 178.64,143.31 178.41,143.09 178.41,141.74 178.27,141.6 177.27,141.6
  IN2 w0.102: v2(191.35,148.69) 191.59,148.69 191.95,149.05 191.95,149.91 191.14,150.73 188.84,150.73 188.4,150.29 187.84,150.29 187.73,150.18 v2(187.44,150.18)
  BOTTOM w0.102: UV1.H9 171.25,135.49 v2(171.3,135.54) ; UV19.K7 190.26,150.83 190.26,150.71 190.16,150.61 189.88,150.61 189.74,150.76 189.48,150.76 189.32,150.92 188.63,150.92 188.08,150.37 187.89,150.37 187.64,150.61 187.5,150.61 187.33,150.45 187.33,150.29 v2(187.44,150.18)
CLKA1_C: length 3.1
  TOP w0.112: CV224.1 v1(194.31,145.85)
  TOP w0.508: CV224.1 RV66.2 RV67.2
CLKRUN#: length 74.2
  TOP w0.102: v2(177.89,83.18) 177.89,83.4 178.44,83.95 179.32,83.95 179.55,83.72 UE1.63
  IN2 w0.127: v2(162.82,60.58) 162.82,60.95 162.68,61.09 161.4,61.09 157.29,65.2 147.3,65.2 146.25,66.24 143.48,66.24 140.61,69.11 v2(140.61,69.55)
  BOTTOM w0.076: 134.84,71.86 134.12,72.58 133.89,72.58 132.61,73.87 132.61,75.45 132.29,75.77 UC1.AW11
  BOTTOM w0.102: v2(140.61,69.55) 140.61,69.37 140.42,69.18 139.7,69.18 139.23,68.71 RC27.1 137.74,68.71 137.15,69.29 137.15,69.6 v1(134.89,71.86) 134.84,71.86 ; v2(177.89,83.18) 173.82,83.18 172.5,81.86 172.5,79.52 172.37,79.4 172.37,76.19 171.84,75.66 171.84,74.06 170.84,73.06 170.84,70.83 170.29,70.28 170.29,68.57 165.7,63.98 165.7,62.75 163.52,60.58 v2(162.82,60.58)
CLKTESTA: length 6.1
  TOP w0.102: CV98.2 v1(174.36,130.75) 174.15,130.96 174.15,131.5 172.31,133.34 171.27,133.34 v2(171.26,133.33)
  BOTTOM w0.102: v2(171.26,133.33) 171.2,133.33 171.19,133.34 170.71,133.34 UV1.K8
CLKTESTB: length 5.3
  TOP w0.102: CV99.2 173.28,129.92 173.28,130.86 172.76,131.38 172.76,132.13 v1(172.43,132.46) 171.23,132.46 v2(171.1,132.34)
  BOTTOM w0.102: v2(171.1,132.34) 170.86,132.09 UV1.L7
CMP_STRAP0: length 2.4
  TOP w0.102: UE1.118 187.55,66.27 187.25,65.98 RE385.1
CMP_VIN0: length 5
  TOP w0.102: UE1.20 192.23,76.37 192.14,76.45 191.66,76.45 v2(190.51,75.31)
  BOTTOM w0.102: RE394.1 RE392.1 v2(190.51,75.31)
CMP_VOUT0: length 233.4
  TOP w0.102: UE1.85 178.38,73.17 178.68,73.47 178.68,73.66 v2(178.94,73.91) 179.64,73.91 181.36,75.63 181.41,75.63 183.39,75.63 184.62,76.86 186.56,76.86 v2(187.83,75.59) ; v1(49.26,44.87) 49.66,44.46 PR116.1 49.66,43.36 v2(49.84,43.18)
  IN1 w0.127: v2(178.94,73.91) 177.35,72.33 173.51,72.33 171.52,70.33 164.91,70.33 160.05,65.47 160.05,64.61 161.54,63.12 161.54,61.47 161.75,61.25 161.75,60.17 166.87,55.05 169.54,55.05 170.49,54.1 170.49,43.68 167.97,41.16 157.36,41.16 v2(157.18,41.34) ; v2(49.84,43.18) 50.29,43.18 52.63,40.83 52.63,39.43 57.21,34.86 58.79,34.86 59.62,34.04 65.72,34.04 66.3,34.62 67.84,34.62 69.19,33.27 72.45,33.27 73.72,32 73.72,26.54 75.18,25.08 80.32,25.08 81.59,23.81 81.59,19.05 84.64,16 153.6,16 v2(154.3,16.7)
  IN2 w0.127: v2(154.3,16.7) 155.31,16.7 160.14,21.53 160.14,33.67 157.52,36.29 157.52,41 v2(157.18,41.34)
  BOTTOM w0.102: v2(178.94,73.91) 178.54,73.52 RE404.2 ; RE392.2 188.42,75.59 v2(187.83,75.59)
CMSRC: length 43.6
  TOP w0.102: v1(84.38,171.15) 84.31,171.07 v2(83.6,171.07)
  TOP w0.508: PR763.2 v2(83.6,171.07)
  IN1 w0.508: v2(109.72,155.73) 109.72,157.8 109.26,158.26 109.26,158.98 109.59,159.32 109.59,161.48 108.27,162.8 108.27,169.41 105.73,171.96 100.7,171.96 99.47,170.73 83.94,170.73 v2(83.6,171.07)
  BOTTOM w0.203: v2(109.72,155.73) 109.78,155.79 PU703.29
CODEC_BITCLK_R: length 2.5
  BOTTOM w0.102: R2720.2 178.47,16.09 HDA27.6
CODEC_SDOUT_R: length 2.6
  BOTTOM w0.102: HDA27.5 179.73,15.69 179.7,15.71 179.15,15.71 v1(178.96,15.52) R2719.2
COMBO-GPI: length 3.1
  TOP w0.102: v2(179.76,13.46) 179.25,13.97 TP2702.1
  BOTTOM w0.102: HDA27.48 181.37,12.91 181.29,12.83 180.4,12.83 v2(179.76,13.46)
COMP: length 7.1
  BOTTOM w0.102: PC751.2 104.46,162.75 103.97,162.26 103.54,161.82 v1(103.54,161.76)
  BOTTOM w0.203: PU703.10 108.98,161.21 108.73,161.46 107.78,161.46 107.24,161.99 106.24,161.99 PR754.2 105.43,162.75 PC751.2
COMP_IA: length 2.8
  TOP w0.203: PU602.16 116.65,136.47 v2(116.57,136.39)
  BOTTOM w0.254: v2(116.57,136.39) 116.57,137 PC636.2 116.65,137.08 PR639.2
COMP_VSA: length 3.5
  TOP w0.203: PU602.24 120.07,139.48 v2(120.18,139.38)
  BOTTOM w0.254: v2(120.18,139.38) 120.18,139.65 119.63,140.2 PC628.1 119.45,140.24 PR630.1
CORE_SNUB: length 1.5
  TOP w0.102: PC662.1 112.02,122.68 v1(112.38,123.04)
CORE_SW: length 0.6
  TOP w0.102: v2(113.91,122.34) v1(113.91,122.94)
  vias: v2(113.28,122.34)
CORE_VID0: length 2.6
  TOP w0.076: v2(133.5,80.22) 132.89,79.61 T4949.1
  BOTTOM w0.076: UC1.AN11 132.45,80.07 133.35,80.07 v2(133.5,80.22)
CORE_VID1: length 2
  TOP w0.076: T4950.1 132.33,78.68 v2(131.69,79.31)
  BOTTOM w0.076: UC1.AN13 v2(131.69,79.31)
CPU_B+: length 21.7
  IN2 w0.508: v2(123,142.06) 121.91,140.97 121.91,138.94 122.48,138.37 123.88,138.37 124.27,137.98 124.27,136.91 122.15,134.8 120.72,134.8 120.15,134.23 120.15,131.64 117.98,129.47
  BOTTOM w0.254: v2(123,142.06) 124.77,143.83 PR603.2
  vias: v1(109.25,129.18) v2(108.67,129.42) v2(108.67,128.78) v2(108.67,128.15) v2(108.67,127.51) v2(108.67,126.88) v2(111.63,127.13) v2(111.63,126.06) v2(112.99,127.13) v2(112.99,126.06) v2(114.34,127.13) v2(114.34,126.06) v2(115.5,128.65) v2(115.5,128.08) v2(116.07,128.65) v2(116.07,128.08)
CPU_CRT_HPD: length 22
  TOP w0.102: RC386.1 150.49,90.92 150.49,91.69 v2(150.67,91.88) v1(151.19,91.88)
  IN2 w0.127: v2(150.67,91.88) 149.87,92.68 147.2,92.68 145.98,91.47 139.67,91.47 138.99,92.14 136.49,92.14 134.87,90.52 v2(134.87,90.2)
  BOTTOM w0.076: UC1.N9 134.17,89.39 134.59,89.39 134.74,89.53 134.74,90.07 v2(134.87,90.2)
CPU_DP3_AUXN: length 1.3
  TOP w0.102: v2(111.58,92.92) 111.81,92.92 T1.1
  BOTTOM w0.089: v2(111.58,92.92) 112.03,92.66 UC1.G46
CPU_DP3_AUXP: length 1.3
  TOP w0.102: T2.1 111.47,93.55 v2(111.58,93.55)
  BOTTOM w0.089: UC1.F46 v2(111.58,93.55)
CPU_HDMI_HPD: length 19.6
  TOP w0.102: v1(149.78,92.56) v2(149.78,92.05) 150.06,91.78 RC385.1
  IN2 w0.127: v2(134.06,90.16) 134.44,89.79 135.06,89.79 135.5,90.23 135.5,90.74 136.65,91.88 138.87,91.88 139.57,91.19 148.92,91.19 v2(149.78,92.05)
  BOTTOM w0.089: UC1.L9 133.78,90.56 134.06,90.28 v2(134.06,90.16)
CPU_POPIRCOMP: length 3.8
  TOP w0.305: v2(128.95,77.47) 128.6,77.13 v1(128.6,76.19) 128.6,75.73 129.22,75.12 RC88.1
  BOTTOM w0.254: v2(128.95,77.47) UC1.AT16
CPU_XDP_TCK0: length 11.7
  BOTTOM w0.076: UC1.A59 105.09,96.8 105.09,98.01 104.88,98.22 104.88,100.46 ; 103.99,100.46 103.99,99.96 T42.1 103.98,99.68 103.41,99.1 103.41,97.94 103.99,97.36 103.99,97.01 103.81,96.84 103.81,96.58 103.87,96.46 103.87,96.24 UC1.B61
  BOTTOM w0.102: 103.99,100.46 103.99,101.42 RC35.1 104.88,100.91 104.88,100.46
CPVEE: length 3.1
  BOTTOM w0.203: HDA27.34 187.53,14.89 v1(188,14.41)
  BOTTOM w0.305: C2704.2 188.27,14.41 v1(188,14.41)
CRT_B: length 10.9
  TOP w0.102: L5502.2 20.67,64.3 C5518.1 18.83,64.3 AFTP5503.1 17.96,63.43 17.81,63.43 17.38,63.87 17.38,64.01 18.15,64.78 18.15,64.92 17.9,65.17 17.75,65.17 16.86,64.28 15.15,64.28 13.96,65.47 JCRT.3
CRT_DDCCLK_CON: length 28.4
  TOP w0.102: JCRT.15 16.83,68.42 AFTP5506.1 ; U5502.4 29,67.95 C5511.1 29.53,68.9 v2(29.29,69.14) 29.29,69.87 RE46.1
  IN2 w0.127: JCRT.15 15.8,70.05 17.07,68.78 17.07,66.7 17.41,66.36 18.35,66.36 20.3,64.41 23.54,64.41 24.51,65.38 24.51,67.07 27.68,70.24 28.89,70.24 29.25,69.88 29.25,69.18 v2(29.29,69.14)
CRT_DDCDATA_CON: length 29.5
  TOP w0.102: U5502.6 28,67.82 C5516.1 28.67,69.03 v2(28.55,69.14) 28.55,69.84 RE45.1 ; AFTP5505.1 17.22,61.93 15.97,63.18 JCRT.12
  IN2 w0.127: v2(28.55,69.14) 28.7,69.14 28.87,69.31 28.87,69.72 28.73,69.86 27.84,69.86 24.89,66.91 24.89,65.22 23.7,64.03 20.14,64.03 18.19,65.98 17.39,65.98 17.07,65.66 17.07,65.22 17.2,65.09 17.46,65.09 17.58,64.96 17.58,64.71 17.46,64.58 17.2,64.58 17.07,64.45 17.07,63.41 16.85,63.18 JCRT.12
CRT_G: length 10.2
  TOP w0.102: L5501.2 20.74,62.08 C5510.1 19.5,62.08 19.5,62.09 19.07,61.66 19.07,60.32 18.76,60.02 AFTP5502.1 18.15,60.02 15.72,62.44 14.63,62.44 13.89,63.18 JCRT.2
CRT_HSYNC_CON: length 16.2
  TOP w0.102: R5511.2 25.2,69.32 v2(25.2,69.32) ; v2(19.58,65.76) 19.59,65.75 C5513.1 19.73,65.22 18.86,65.22 AFTP5508.1 16.88,65.75 16.36,65.22 15.45,65.22 JCRT.13
  IN2 w0.127: v2(25.2,69.32) 25.76,69.32 25.85,69.41 25.85,69.67 25.74,69.78 24.87,69.78 21.04,65.94 19.77,65.94 v2(19.58,65.76)
CRT_NC: length 2.2
  TOP w0.102: AFTP5509.1 16.58,59.51 JCRT.11
CRT_PCH_HPD: length 4.3
  TOP w0.102: v1(33.7,68.09) R5517.1 R5510.1 31.51,67.89 30.5,66.87 U5502.1
CRT_R: length 8.9
  TOP w0.102: L5503.2 20.67,59.42 C5514.1 19.66,59.42 AFTP5501.1 16.59,58.1 JCRT.1
CRT_VSYNC_CON: length 16.2
  TOP w0.102: v2(19.56,66.46) 19.75,66.64 C5507.1 20.26,67 20.01,67.25 19.65,67.25 19.24,67.66 AFTP5507.1 15.3,67.66 JCRT.14 ; v2(26.8,70.04) 26.81,70.02 R5507.2
  IN2 w0.127: v2(26.8,70.04) 24.77,70.04 20.93,66.2 19.83,66.2 v2(19.56,66.46)
CS_1.2V: length 1.4
  TOP w0.102: PR205.2 59.54,17.03 v1(60.19,16.39)
CSA0#_0: length 44.8
  TOP w0.102: v2(175.35,165.8) 175.38,165.76 175.38,165.23 175.7,164.91 176.83,164.91 177.09,164.64 177.59,164.64 UV18.L2
  IN1 w0.165: v2(163.9,142.98) 165.09,142.98 166.83,144.72 168.2,144.72 168.33,144.59 171.15,144.59 177.2,150.65 177.2,156.69 179.63,159.12 179.63,160.02 179.25,160.4 179.25,160.68 179.7,161.12 179.93,161.12 180.38,160.67 v2(180.66,160.67)
  IN2 w0.102: v2(180.66,160.67) 180.59,160.67 179.19,162.07 179.19,162.81 176.44,165.57 176.17,165.57 175.94,165.8 v2(175.35,165.8)
  BOTTOM w0.102: UV1.H22 164.04,142.84 v2(163.9,142.98) ; v2(175.35,165.8) 175.57,166.02 175.57,166.19 175.4,166.37 175.25,166.37 175.07,166.19 174.87,166.19 174.72,166.33 174.72,166.66 174.84,166.78 174.84,166.93 174.4,167.37 UV17.L2
CSA1#_0: length 46.3
  TOP w0.102: UV20.L2 191.25,150.97 191.07,150.97 190.88,151.16 190.61,151.16 189.94,151.83 189.67,151.83 189.38,151.54 189.01,151.54 188.8,151.75 188.35,151.75 188.33,151.77 188.33,151.77 v2(188.23,151.77)
  IN1 w0.102: v2(188.23,151.77) 188.14,151.86 188.14,152.92 186.67,154.39 184.04,154.39 183.86,154.22 183.83,154.22
  IN1 w0.165: 183.83,154.22 183.47,154.22 181.16,156.53 179.55,156.53 179.01,155.99 179.01,154.88 179.17,154.72 180.04,154.72 180.21,154.55 180.21,154.22 180.04,154.06 179.17,154.06 179.01,153.89 179.01,153.56 179.17,153.39 180.04,153.39 180.21,153.23 180.21,152.9 180.04,152.73 179.17,152.73 179.01,152.57 179.01,149.94 177.77,148.7 177.77,144.59 172.49,139.32 172.21,139.32 170.44,137.56 v2(170.29,137.56)
  BOTTOM w0.102: v2(188.23,151.77) 188.36,151.91 188.36,152.27 188.3,152.34 188.14,152.34 188.03,152.45 188.03,152.81 188.13,152.91 188.26,152.91 188.36,153.01 188.36,153.41 187.65,154.12 187.65,154.27 187.75,154.37 UV19.L2 ; v2(170.29,137.56) 170.1,137.75 UV1.G13
CSI2_COMP: length 3.5
  TOP w0.508: RC3.1 v1(132.26,94.74) 131.34,94.74 v2(130.83,94.23)
  BOTTOM w0.254: UC1.E13 131.2,94.05 v2(130.83,94.23)
DAT_SMB: length 4.2
  TOP w0.254: PBATT1.5 160.4,179.52 v1(158.92,178.04) 158.3,177.41 PR20.1
DAT_TP_SIO: length 293.1
  TOP w0.102: TPAD1.7 61.78,78.61 61.65,78.49 CZ30.1 RZ18.2 61.07,79.37 61.35,79.1 63.13,79.1 v2(63.94,79.91) ; v2(52.06,50.8) v1(52.89,50.8) ; v2(180.4,76.02) 179.39,76.02 178.94,75.57 UE1.79
  IN1 w0.127: v2(157.66,41.97) 158.22,41.41 166.64,41.41 167.53,42.31 167.53,45.72 167.85,46.04 167.85,48.62 166.36,50.1 166.36,55.05 161.5,59.92 161.5,61.13 161.28,61.34 161.28,63.01 159.77,64.53 159.77,65.55 164.68,70.46 164.68,73.91 166.15,75.39 167.95,75.39 169.82,77.25 176.55,77.25 177.54,76.26 180.15,76.26 v2(180.4,76.02) ; v2(63.94,79.91) 63.07,80.77 44.32,80.77 41.59,78.04 41.59,68.47 43.19,66.87 46.75,66.87 49.21,64.41 49.21,58.76 49.71,58.25 49.71,51.94 50.36,51.3 50.36,51.04 51.05,50.36 51.62,50.36 v2(52.06,50.8)
  IN2 w0.127: v2(52.06,50.8) 52.06,49.6 54.48,47.19 54.48,41.02 56.83,38.67 56.83,32.05 61.19,27.69 76.96,27.69 82.25,22.4 82.25,18.55 84.79,16 101.28,16 102.87,14.41 154.04,14.41 160.45,20.82 160.45,33.8 157.83,36.42 157.83,41.81 v2(157.66,41.97)
DBC_EN: length 176.6
  TOP w0.102: v2(141.79,113.28) v1(142.33,113.83) 142.48,113.98 145.03,113.98 145.14,114.1 145.66,114.62 147.05,114.62 149.72,111.96 149.72,105.68 150.55,104.84 150.55,100.97 151.21,100.31 151.21,97.97 155.39,93.79 159.44,93.79 163.06,90.17 163.06,90.11 163.12,90.04 163.12,82.61 163.32,82.42 v2(163.32,82.36)
  IN1 w0.127: v2(141.79,113.28) 141.79,113.41 141.37,113.83 141.37,115.8 140.43,116.74 140.43,121.68 136.25,125.86 135.19,125.86 133.66,127.38 133.66,132.49 132.23,133.92 131.5,133.92 130.43,135 129.83,135 129.41,135.42 129.41,136.38 126.45,139.34 126.45,141.36 124.73,143.07 124.73,146.95 123.37,148.31 113.8,148.31 112.36,146.88 108.19,146.88 105.75,149.31 97.85,149.31 95.31,151.86 95.31,156.46 91.5,160.27 91.5,162.98 90.82,163.66 90.82,163.68 90.44,164.06 v2(86.04,164.06)
  IN2 w0.127: v2(163.32,82.36) 162.87,82.36 162.55,82.68 158.3,82.68 156.33,80.71 155.62,80.71 154.86,79.95 152.72,79.95 152.4,80.26 151.71,80.26 150.65,81.32 150.65,81.68 149.88,82.45 139.59,82.45 138.94,81.8 v2(136.22,81.8)
  BOTTOM w0.076: v2(136.22,81.8) 136.03,81.61 136.03,80.65 UC1.AM5
  BOTTOM w0.102: v2(86.04,164.06) 85.78,163.8 85.78,161.26 85.35,160.83 R5213.2
DBC_EN_R: length 7.5
  BOTTOM w0.102: LCD1.10 85.3,164.87 84.3,163.87 v1(84.3,161) 84.3,160.61 84.44,160.48 R5213.1 R6507.2
DCBAT_CAM: length 3.5
  BOTTOM w0.102: R6525.1 75.57,168.49 75.47,168.39 73.77,168.39 v1(73.37,168.78)
DCBATOUT_LCD: length 7.8
  TOP w0.102: v2(79.42,165.72) 79.51,165.72 80.02,166.23 81.41,166.23 v3(82.04,165.61) ; v2(79.42,165.72) 79.24,165.72 78.97,165.99 78.97,167 78.71,167.27 v3(78.71,167.97) ; v2(79.42,165.72) 79.42,166.15 v3(80.24,166.98)
  BOTTOM w0.102: 76.64,162.18 76.16,162.18
DDC_CLK_HDMI: length 36.4
  IN2 w0.127: JHDMI.15 10.67,68.49 10.67,69.52 15.73,74.57 15.73,76.99 17.68,78.94 24.74,78.94 26.26,80.45 31.43,80.45 31.65,80.23 v2(32.93,80.23)
  BOTTOM w0.102: Q5402.3 33,80.17 v2(32.93,80.23) 33.37,80.67 v1(35.57,80.67) 36.12,80.67 36.45,80.35 36.45,79.22 RE43.1
DDC_CLK_PH1: length 3.1
  BOTTOM w0.102: RE43.2 37.12,79.42 v1(38.03,80.33) 38.05,80.34 D5401.3
DDC_DATA_HDMI: length 33.6
  IN2 w0.127: JHDMI.16 12.12,68.89 12.12,70.25 16.24,74.36 16.24,76.78 17.89,78.43 24.95,78.43 26.35,79.83 31.16,79.83 33.33,77.66 v2(34.8,77.66)
  BOTTOM w0.102: RE44.1 35.79,78.1 35.64,78.25 Q5402.6 34.6,78.25 34.6,77.87 v2(34.8,77.66)
DDC_DATA_PH2: length 2.7
  BOTTOM w0.102: RE44.2 37.2,78.1 v1(38.09,78.99) 38.14,79.04 D5401.2
DDR4_DRAMRST#: length 24.1
  TOP w0.102: v2(108.87,19.13) 109.15,18.85 v1(109.15,16.29) 109.52,15.93 RD31.1 113.66,15.13 v2(113.61,15.08)
  IN1 w0.127: v2(104.28,28.9) 105.01,28.9 108.87,25.03 v2(108.87,19.13)
  BOTTOM w0.163: v2(104.28,28.9) 104.87,29.49 JDIMM1.108 ; JDIMM2.108 113.48,15.21 v2(113.61,15.08)
DDR_A_ACT#: length 50.4
  IN1 w0.076: 101.33,63.44 101.34,63.45 101.34,63.75 103.94,66.36 103.94,67.39 v2(104.85,68.3)
  IN1 w0.216: 101.33,63.44 99.62,61.74 99.62,48.14 100.06,47.7 100.06,39.94 103.12,36.88 103.12,35.48 104.25,34.35 v2(104.27,34.35)
  BOTTOM w0.076: v2(104.85,68.3) 105.22,68.67 105.22,70.44 106.99,72.21 106.99,73.17 106.84,73.32 106.84,73.64 106.98,73.78 106.98,74.19 106.93,74.33 106.93,74.44 106.98,74.57 106.98,74.8 UC1.BA55
  BOTTOM w0.163: JDIMM1.114 106.37,32.38 104.39,34.35 v2(104.27,34.35)
DDR_A_ALERT#: length 57.4
  IN1 w0.076: v2(108.83,76.69) 108.83,76.92 109.18,77.27 109.18,77.71 109.07,77.82 107.21,77.82 107.16,77.77 106.71,77.77 106.52,77.58 106.52,71.07 105.7,70.26 105.7,66.01 104.46,64.77 103.65,64.77 102.84,63.96 102.84,63.15 102.59,62.91 102.59,62.72 102.56,62.69 102.56,62.61
  IN1 w0.216: v2(107.18,32.44) 107.16,32.44 104.97,34.63 104.97,37.77 103.12,39.62 103.12,40.58 102.45,41.25 102.45,44.32 101.54,45.23 101.54,61.55 102.56,62.57 102.56,62.61
  BOTTOM w0.076: UC1.AW50 109.49,76.01 108.83,76.66 v2(108.83,76.69)
  BOTTOM w0.163: v2(107.18,32.44) 106.87,32.14 JDIMM1.116
DDR_A_BG0: length 50.6
  IN1 w0.076: v2(104.9,67.69) 104.32,67.12 104.32,66.48 101.91,64.07 101.91,63.39 101.72,63.19 101.72,63.13 101.68,63.09
  IN1 w0.216: v2(104.27,35.62) 104.2,35.69 104.18,35.69 103.75,36.11 103.75,36.94 100.55,40.14 100.55,40.6 100.77,40.81 101.24,40.81 101.45,41.03 101.45,41.46 101.24,41.68 100.77,41.68 100.55,41.89 100.55,47.91 100.39,48.07 100.39,61.8 101.68,63.09
  BOTTOM w0.076: UC1.AY55 107.11,75.58 107.4,75.29 107.48,75.13 107.48,74.95 107.42,74.79 107.42,74.65 107.49,74.43 107.49,74.31 107.45,74.23 107.44,74.2 107.44,73.83 107.64,73.63 107.64,72.63 105.39,70.37 105.39,68.18 v2(104.9,67.69)
  BOTTOM w0.163: v2(104.27,35.62) 104.38,35.62 106.62,37.87 JDIMM1.115
DDR_A_BG1: length 49.5
  IN1 w0.076: 102.1,62.81 102.1,62.81 102.1,63.88 104.9,66.67 v2(104.9,67.06)
  IN1 w0.216: v2(104.27,36.89) 104.27,37.33 101.95,39.65 101.95,42.29 101.73,42.51 101.26,42.51 101.05,42.72 101.05,43.15 101.26,43.37 101.73,43.37 101.95,43.59 101.95,44.07 101.73,44.29 101.26,44.29 101.05,44.5 101.05,48.1 100.96,48.19 100.96,61.67 102.1,62.81
  BOTTOM w0.076: UC1.AY54 107.67,75.25 107.67,75 107.6,74.78 107.6,74.65 107.66,74.42 107.66,74.28 107.61,74.16 107.61,73.9 107.81,73.7 107.81,72.56 105.55,70.31 105.55,66.55 105.48,66.47 104.78,66.47 104.7,66.55 104.7,66.92 104.84,67.06 v2(104.9,67.06)
  BOTTOM w0.163: JDIMM1.113 106.12,38 105.02,36.89 v2(104.27,36.89)
DDR_A_BS0: length 50.7
  IN1 w0.076: v2(109.75,76.82) 109.75,75.07 112.3,72.52 112.3,64.74 112.4,64.64 112.4,62.23
  IN1 w0.216: v2(117.5,35.75) 116.64,36.61 116.64,45.15 112.4,49.39 112.4,62.23
  BOTTOM w0.089: v2(109.75,76.82) 109.4,77.17 UC1.AU52
  BOTTOM w0.163: JDIMM1.150 117.37,31.77 116.45,32.7 116.45,34.69 v2(117.5,35.75)
DDR_A_BS1: length 51.9
  IN1 w0.076: 111.41,62.23 111.41,72.95 109.21,75.14 109.21,77.07 109.35,77.2 109.35,77.23 109.35,77.23 109.35,77.68 109.51,77.84 110.37,77.84 v2(110.66,77.55)
  IN1 w0.216: v2(115.87,35.11) 115.84,35.11 115.63,35.33 115.63,35.34 115.37,35.59 115.37,35.9 115.63,36.16 115.63,44.76 111.41,48.98 111.41,62.23
  BOTTOM w0.089: v2(110.66,77.55) 111.01,77.82 UC1.AT48
  BOTTOM w0.163: JDIMM1.145 116.12,36.51 116.38,36.25 116.38,35.62 v2(115.87,35.11)
DDR_A_CAS#: length 51.9
  IN1 w0.076: 113.88,62.23 113.88,64.78 113.45,65.22 113.45,68.3 113.57,68.42 113.57,71.73 112.94,72.35 112.94,73.95 111.72,75.18 111.72,76.21 111.23,76.71 111.23,77.13 111.59,77.49 v2(111.59,77.57)
  IN1 w0.216: v2(117.5,33.21) 117.51,33.2 118.75,34.43 118.75,41.5 118.19,42.06 118.19,45.7 113.88,50 113.88,62.23
  BOTTOM w0.089: UC1.AU48 111.51,77.57 v2(111.59,77.57)
  BOTTOM w0.163: v2(117.5,33.21) 118.87,31.83 JDIMM1.156
DDR_A_CKE0: length 51.2
  IN1 w0.076: 100.98,63.79 103.43,66.25 103.43,67.54 v2(104.86,68.96)
  IN1 w0.216: 100.98,63.79 98.99,61.8 98.99,48.07 99.56,47.5 99.56,39.04 99.78,38.82 100.47,38.82 100.69,38.61 100.69,38.17 100.47,37.96 99.71,37.96 99.51,37.76 99.51,37.28 100.16,36.64 100.77,36.64 101.32,36.08 102.05,36.08 v2(102.29,36.32)
  BOTTOM w0.076: v2(104.86,68.96) 104.49,69.33 104.49,70.12 104.68,70.31 104.68,71.17 105.38,71.87 105.78,71.87 106.47,72.56 106.47,72.99 106.34,73.11 106.34,73.79 106.28,73.86 106.28,74.16 106.28,74.16 106.4,74.41 106.4,74.41 106.41,74.42 106.55,74.56 UC1.BA56
  BOTTOM w0.163: v2(102.29,36.32) 102.67,36.32 103.91,37.56 104.74,37.56 105.12,37.95 JDIMM1.109
DDR_A_CKE1: length 51
  IN1 w0.076: 100.62,64.13 100.69,64.2 100.72,64.2 102.99,66.47 102.99,67.76 v2(104.86,69.62)
  IN1 w0.216: v2(104.27,33.08) 103.02,33.08 99.02,37.08 99.02,47.34 98.46,47.9 98.46,52.33 97.91,52.88 97.91,61.42 100.62,64.13
  BOTTOM w0.076: v2(104.86,69.62) 104.86,71.11 105.41,71.67 105.81,71.67 106.63,72.49 106.63,73.06 106.51,73.18 106.51,74.02 UC1.BB56
  BOTTOM w0.163: v2(104.27,33.08) 105.37,31.99 JDIMM1.110
DDR_A_CKE2: length 5.9
  BOTTOM w0.076: T3.1 105.47,71.06 106.8,72.39 106.8,73.13 106.67,73.25 106.67,73.72 106.81,73.86 106.81,74.16 106.76,74.27 106.76,74.49 106.81,74.6 106.81,74.81 106.78,74.89 106.78,75.17 106.79,75.17 106.81,75.23 106.81,75.54 106.76,75.59 106.76,75.79 UC1.AW56
DDR_A_CKE3: length 6.4
  BOTTOM w0.076: T4.1 104.12,70.88 105.35,72.12 105.79,72.12 106.3,72.63 106.3,72.92 106.12,73.11 106.12,74.19 106.14,74.24 106.14,74.24 106.28,74.6 106.28,74.89 106.55,75.15 UC1.AY56
DDR_A_CLK0: length 52.1
  IN1 w0.127: v2(114.21,35.94) 113.43,35.94 113.05,36.32 113.05,38.52 113.33,38.8 113.53,38.8 113.66,38.93 113.66,39.31 113.53,39.43 113.33,39.43 113.05,39.71 113.05,40.51 113.33,40.79 113.57,40.79 113.7,40.92 113.7,41.3 113.57,41.42 113.33,41.42 113.05,41.7 113.05,44.61 109.48,48.18 109.48,65.55 109.68,65.74 109.68,71.98 108.2,73.45 108.2,74.93 107.53,75.59 107.53,77.07 v2(107.91,77.45)
  BOTTOM w0.076: v2(107.91,77.45) 107.98,77.45 108.35,77.82 UC1.AT53
  BOTTOM w0.097: v2(114.21,35.94) 112.65,35.94 112.12,36.46 JDIMM1.137
DDR_A_CLK1: length 52.9
  IN1 w0.127: v2(114.21,34.67) 114.03,34.48 112.89,34.48 112.51,34.86 112.51,44.39 108.95,47.96 108.95,65.91 109.46,66.43 109.46,71.5 107.88,73.08 107.88,74.8 107.31,75.37 107.31,77.09 v2(107,77.4)
  BOTTOM w0.089: UC1.AT55 107.41,77.82 v2(107,77.4)
  BOTTOM w0.097: v2(114.21,34.67) 114.11,34.56 113.41,34.56 112.37,33.52 JDIMM1.138
DDR_A_CLK#0: length 52.1
  IN1 w0.127: v2(107.93,76.81) 107.79,76.68 107.79,75.7 108.45,75.04 108.45,73.56 109.93,72.08 109.93,65.63 109.74,65.44 109.74,48.28 113.3,44.72 113.3,41.81 113.43,41.68 113.68,41.68 113.96,41.4 113.96,40.81 113.68,40.53 113.43,40.53 113.3,40.4 113.3,39.82 113.43,39.69 113.64,39.69 113.91,39.41 113.91,38.82 113.64,38.54 113.43,38.54 113.3,38.41 113.3,36.42 113.53,36.19 113.78,36.19 v2(114.21,36.62)
  BOTTOM w0.076: UC1.AU53 108.45,77.17 108.52,77.1 108.52,76.89 108.19,76.56 108.04,76.56 107.93,76.67 v2(107.93,76.81)
  BOTTOM w0.097: JDIMM1.139 112.62,38.04 112.62,37.99 112.53,37.89 112.41,37.89 112.31,37.8 112.31,36.54 112.72,36.12 113.69,36.12 113.79,36.22 113.79,36.53 113.88,36.62 v2(114.21,36.62)
DDR_A_CLK#1: length 52.8
  IN1 w0.127: v2(114.21,34.03) 114.02,34.23 112.79,34.23 112.26,34.76 112.26,44.28 108.69,47.85 108.69,66.02 109.2,66.53 109.2,71.4 107.62,72.98 107.62,74.7 107.05,75.27 107.05,76.7 v2(106.92,76.83)
  BOTTOM w0.076: UC1.AU55 107.46,76.91 107.38,76.83 v2(106.92,76.83)
  BOTTOM w0.097: v2(114.21,34.03) 113.87,34.38 113.49,34.38 112.56,33.45 112.56,31.98 112.87,31.67 JDIMM1.140
DDR_A_CS#0: length 55.2
  IN1 w0.076: v2(112.48,76.79) 112.48,75.84 114.74,73.59 114.74,68.78 115.02,68.49 115.02,64.99 115.37,64.65 115.37,62.23
  IN1 w0.216: 115.37,62.23 115.37,52.19 115.6,51.96 115.6,51.65 115.37,51.43 115.37,51.12 115.66,50.83 115.99,50.83 116.21,51.04 116.51,51.04 116.82,50.74 116.82,50.43 116.59,50.2 116.59,49.9 116.9,49.59 117.2,49.59 117.43,49.82 117.74,49.82 121.26,46.3 121.26,43.98 120.93,43.65 120.93,43.12 121.26,42.78 121.26,42.25 120.93,41.92 120.93,41.39 121.26,41.05 121.26,40.52 120.93,40.19 120.93,36.14 120.44,35.65 120.44,35.1 120.2,34.86 v2(119.96,34.86)
  BOTTOM w0.089: v2(112.48,76.79) 112.94,77.12 UC1.AU45
  BOTTOM w0.163: JDIMM1.149 117.12,36.85 119.11,34.86 v2(119.96,34.86)
DDR_A_CS#1: length 58.1
  IN1 w0.076: v2(113.41,77.47) 113.41,76.16 115.04,74.53 115.04,68.92 115.41,68.55 115.41,64.87 115.87,64.41 115.87,62.23
  IN1 w0.216: v2(121.4,33.02) 121.4,32.88 121.08,32.57 120.64,32.57 120.43,32.78 120.43,34.2 120.93,34.71 120.93,35.45 121.42,35.93 121.42,36.63 121.75,36.97 121.75,37.5 121.42,37.83 121.42,38.36 121.75,38.7 121.75,39.22 121.42,39.56 121.42,39.99 121.75,40.32 121.75,46.5 115.87,52.39 115.87,62.23
  BOTTOM w0.089: UC1.AU43 113.71,77.17 v2(113.41,77.47)
  BOTTOM w0.163: JDIMM1.157 119.12,38.08 120.41,36.8 120.41,34.01 v2(121.4,33.02)
DDR_A_D0: length 69.4
  IN1 w0.127: v2(79.32,32.02) 78.77,32.02 78.22,32.57 78.22,35.41 76.94,36.69 76.94,41.3 77.32,41.68 77.32,54.32 78.48,55.49 78.48,75.06 85.56,82.14 93.99,82.14 95.5,80.63 v2(95.61,80.63)
  BOTTOM w0.076: v2(95.61,80.63) 95.84,80.86 97.67,80.86 97.81,80.86 UC1.AL71
  BOTTOM w0.102: v2(79.32,32.02) 78.87,31.6 JDIMM1.4
DDR_A_D1: length 70.4
  IN1 w0.127: v2(79.32,35.83) 77.97,37.18 77.97,40.87 78.34,41.25 78.34,51.03 78.47,51.15 78.77,51.15 78.9,51.28 78.9,51.53 78.77,51.66 78.47,51.66 78.34,51.79 78.34,52.11 78.47,52.23 79.6,52.23 79.72,52.36 79.72,52.61 79.6,52.74 79.11,52.74 78.99,52.87 78.99,53.12 79.11,53.25 79.6,53.25 79.72,53.38 79.72,74.67 86.14,81.09 93.25,81.09 94.17,80.17 96.47,80.17 v2(96.48,80.15)
  BOTTOM w0.076: v2(96.48,80.15) 96.86,79.78 97.27,79.78 97.47,79.98 97.98,79.98 98.01,79.97 98.09,79.94 98.21,79.94 98.42,80 98.57,80 98.73,79.95 98.91,79.95 99.07,80.02 99.58,80.02 99.79,80.23 UC1.AL68
  BOTTOM w0.102: v2(79.32,35.83) 78.62,36.53 JDIMM1.3
DDR_A_D2: length 71.8
  IN1 w0.127: v2(92.68,78.91) 92.67,78.92 86.48,78.92 82.07,74.51 82.07,64.3 81.5,63.73 81.5,60.6 81.63,60.47 82.33,60.47 82.45,60.34 82.45,60.09 82.33,59.96 81.63,59.96 81.5,59.84 81.5,59.58 81.63,59.45 82.33,59.45 82.45,59.33 82.45,59.07 82.33,58.95 81.63,58.95 81.5,58.82 81.5,58.57 81.63,58.44 82.33,58.44 82.45,58.31 82.45,58.06 82.33,57.93 81.63,57.93 81.5,57.8 81.5,57.55 81.63,57.42 82.33,57.42 82.45,57.3 82.45,52.32 80.79,50.65 80.79,42.29 80.14,41.65 80.14,37.55 81.59,36.1 81.59,33.72 v2(82.02,33.29)
  BOTTOM w0.076: UC1.AN68 99.57,79.65 99.28,79.36 98.71,79.36 98.48,79.12 97.54,79.12 97.5,79.08 95.77,79.08 95.61,78.91 95.05,78.91
  BOTTOM w0.102: v2(92.68,78.91) 92.91,78.67 93.44,78.67 93.68,78.91 95.05,78.91 ; JDIMM1.20 82.87,32.61 82.2,33.29 v2(82.02,33.29)
DDR_A_D3: length 70.5
  IN1 w0.127: v2(96.02,79.78) 95.16,79.78 93.58,78.2 93.03,78.2 92.98,78.15 86.69,78.15 82.8,74.26 82.8,65.34 83.18,64.96 83.18,52.07 82.1,50.99 82.1,50.7 81.97,50.57 81.68,50.57 81.49,50.39 81.49,50.14 81.62,50.01 82.04,50.01 82.16,49.88 82.16,49.63 82.04,49.5 81.62,49.5 81.49,49.37 81.49,39.39 81.62,39.26 81.97,39.26 82.1,39.13 82.1,38.88 81.97,38.75 81.62,38.75 81.49,38.63 81.49,38.34 81.62,38.22 82.33,38.22 82.45,38.09 82.45,37.82 82.33,37.69 81.62,37.69 81.49,37.56 81.49,37.31 81.62,37.18 82.33,37.18 82.45,37.06 82.45,35.21 82.86,34.81 82.86,34.35 82.63,34.13 82.45,34.13 v2(82.02,34.56)
  BOTTOM w0.076: v2(96.02,79.78) 96.13,79.78 96.33,79.57 97.3,79.57 97.54,79.82 97.94,79.82 98.06,79.76 98.08,79.76 98.09,79.76 98.1,79.76 98.2,79.76 98.43,79.83 98.56,79.83 98.78,79.75 99.03,79.75 UC1.AN69
  BOTTOM w0.102: v2(82.02,34.56) 82.3,34.56 82.48,34.73 82.48,36.96 83.12,37.6 JDIMM1.21
DDR_A_D4: length 70.2
  IN1 w0.127: v2(94.61,80.92) 93.74,81.79 85.7,81.79 79.04,75.13 79.04,55.32 78.91,55.19 78.67,55.19 78.54,55.06 78.54,54.81 78.67,54.68 78.91,54.68 79.04,54.56 79.04,54.3 78.91,54.17 77.99,54.17 77.66,53.85 77.66,41.53 77.28,41.16 77.28,36.83 78.56,35.56 78.56,34.05 v2(79.32,33.29)
  BOTTOM w0.076: 95.75,81.09 95.81,81.15 96.29,81.15 96.41,81.02 97.56,81.02 97.68,81.14 97.92,81.14 98.03,81.11 98.17,81.05 98.34,80.88 UC1.AL70
  BOTTOM w0.102: v2(79.32,33.29) 79.87,32.74 JDIMM1.8 ; v2(94.61,80.92) 94.71,81.01 95.67,81.01 95.75,81.09
DDR_A_D5: length 71.2
  IN1 w0.127: v2(79.32,34.56) 78.9,34.98 78.9,35.72 77.62,37 77.62,41.01 78,41.39 78,52.69 78.13,52.82 78.52,52.82 78.64,52.94 78.64,53.2 78.52,53.32 78.13,53.32 78,53.45 78,53.7 78.13,53.83 79.25,53.83 79.38,53.96 79.38,74.82 86,81.44 93.5,81.44 v2(93.97,80.96)
  BOTTOM w0.076: UC1.AL69 98.93,80.88 98.67,81.14 98.5,81.14 98.31,81.22 98.31,81.22 98.18,81.24 97.9,81.32 97.6,81.32 97.46,81.19 96.49,81.19 96.35,81.32
  BOTTOM w0.102: v2(93.97,80.96) 94.33,81.32 96.35,81.32 ; JDIMM1.7 79.62,36.44 79.87,36.19 79.87,35.11 v2(79.32,34.56)
DDR_A_D6: length 69.1
  IN1 w0.127: v2(82.04,32.07) 81.92,32.07 81.25,32.74 81.25,35.96 79.8,37.41 79.8,41.79 80.44,42.43 80.44,50.8 81.16,51.51 81.16,54.41 81.29,54.54 81.65,54.54 81.78,54.67 81.78,54.92 81.65,55.05 81.29,55.05 81.16,55.17 81.16,55.43 81.29,55.56 81.98,55.56 82.11,55.68 82.11,55.94 81.98,56.06 81.29,56.06 81.16,56.19 81.16,56.44 81.29,56.57 81.98,56.57 82.11,56.7 82.11,56.95 81.98,57.08 81.29,57.08 81.16,57.21 81.16,63.89 81.59,64.33 81.59,74.51 86.34,79.26 91.54,79.26 91.85,79.57 92.79,79.57 v2(93.27,79.08)
  BOTTOM w0.076: UC1.AN70 98.22,79.29 97.48,79.29 97.44,79.24 95.45,79.24 95.44,79.23 95.05,79.23
  BOTTOM w0.102: 95.05,79.23 93.43,79.23 v2(93.27,79.08) ; JDIMM1.16 81.87,31.92 82.02,32.07 v2(82.04,32.07)
DDR_A_D7: length 68.3
  IN1 w0.127: v2(82.02,35.83) 82.02,36.15 81.15,37.02 81.15,37.36 81.02,37.49 80.69,37.49 80.56,37.62 80.56,37.87 80.68,38 81.02,38 81.15,38.13 81.15,38.38 81.02,38.51 80.61,38.51 80.49,38.63 80.49,38.89 80.61,39.01 81.02,39.01 81.15,39.14 81.15,39.4 81.02,39.52 80.61,39.52 80.49,39.65 80.49,39.9 80.61,40.03 81.02,40.03 81.15,40.16 81.15,40.78 81.02,40.91 80.62,40.91 80.49,41.05 80.49,41.3 80.61,41.43 81.02,41.43 81.15,41.56 81.15,50.53 82.8,52.18 82.8,61.11 82.67,61.24 82.42,61.24 82.29,61.36 82.29,61.62 82.42,61.75 82.67,61.75 82.8,61.87 82.8,62.25 82.67,62.38 81.97,62.38 81.84,62.51 81.84,62.76 81.97,62.89 82.67,62.89 82.8,63.01 82.8,63.27 82.67,63.4 82.16,63.4 82.04,63.52 82.04,63.78 82.16,63.9 82.67,63.9 82.8,64.03 82.8,64.71 82.42,65.09 82.42,74.37 86.63,78.57 92.31,78.57 92.39,78.49 92.84,78.49 92.89,78.54 93.33,78.54 v2(94.43,79.64)
  BOTTOM w0.076: 95.05,79.64 95.55,79.64 95.78,79.41 97.37,79.41 97.41,79.45 97.51,79.55 UC1.AN71
  BOTTOM w0.102: 95.05,79.64 v2(94.43,79.64) ; JDIMM1.17 82.12,37.93 82.15,37.91 82.15,35.93 82.05,35.83 v2(82.02,35.83)
DDR_A_D8: length 62.6
  IN1 w0.127: v2(94.23,76.71) 94.11,76.83 87.23,76.83 84.42,74.02 84.42,65.58 84.5,65.51 84.5,51.53 83.5,50.52 83.5,48.72 83.37,48.6 83.11,48.6 82.99,48.47 82.99,48.22 83.11,48.09 83.37,48.09 83.5,47.96 83.5,47.71 83.37,47.58 83.11,47.58 82.99,47.45 82.99,47.2 83.11,47.07 83.37,47.07 83.5,46.95 83.5,46.69 83.37,46.56 83.11,46.56 82.99,46.44 82.99,46.2 83.11,46.08 83.37,46.08 83.5,45.95 83.5,45.7 83.37,45.57 83.22,45.57 83.09,45.44 83.09,40.01 83.5,39.6 83.5,39.19 83.83,38.86 83.83,35.72 v2(84.25,35.3)
  BOTTOM w0.076: UC1.AR70 98.34,78.52 98.07,78.79 97.68,78.79 97.64,78.75 96.08,78.75 95.43,78.1 95.24,78.1 95.05,77.92 95.05,77.91
  BOTTOM w0.102: v2(84.25,35.3) 85.12,36.18 JDIMM1.29 ; v2(94.23,76.71) 94.23,76.83 94.17,76.89 94.17,77.03 95.05,77.91
DDR_A_D9: length 64.4
  IN1 w0.127: v2(93.72,76.39) 93.66,76.39 93.56,76.49 87.37,76.49 84.77,73.88 84.77,65.72 84.84,65.65 84.84,51.38 83.84,50.38 83.84,43.84 83.71,43.72 83.56,43.72 83.43,43.59 83.43,43.33 83.56,43.21 83.71,43.21 83.84,43.08 83.84,42.83 83.71,42.7 83.56,42.7 83.43,42.57 83.43,42.32 83.56,42.19 83.71,42.19 83.84,42.06 83.84,41.81 83.71,41.68 83.56,41.68 83.43,41.56 83.43,41.3 83.56,41.18 83.71,41.18 83.84,41.05 83.84,40.79 83.71,40.67 83.56,40.67 83.43,40.54 83.43,40.29 83.56,40.16 83.71,40.16 83.89,39.98 83.89,39.28 84.25,38.92 v2(84.25,36.57)
  BOTTOM w0.076: UC1.AR68 99.26,78.72 98.71,78.72 98.48,78.96 97.61,78.96 97.57,78.91 96.01,78.91 95.71,78.61 95.46,78.61 95.18,78.33 95.05,78.33
  BOTTOM w0.102: v2(93.72,76.39) 93.78,76.45 93.78,77.11 93.88,77.21 93.91,77.21 94.16,77.47 94.16,77.85 94.64,78.33 95.05,78.33 ; v2(84.25,36.57) 84.24,36.58 83.85,36.58 83.75,36.48 83.75,35.49 83.63,35.37 83.17,35.37 83.06,35.47 83.06,36.71 83.71,37.36 83.71,37.75 83.81,37.85 84.02,37.85 84.12,37.95 JDIMM1.25
DDR_A_D10: length 60.7
  IN1 w0.127: v2(96.32,76.07) 96.32,75.25 95.33,74.26 93.34,74.26 93.23,74.36 88.25,74.36 87.22,73.33 87.22,49.75 87.09,49.62 86.35,49.62 86.23,49.49 86.23,49.24 86.35,49.11 87.29,49.11 87.42,48.98 87.42,48.74 87.29,48.61 86.14,48.61 86.01,48.48 86.01,48.23 86.14,48.1 87.29,48.1 87.42,47.97 87.42,47.72 87.29,47.59 86.14,47.59 86.01,47.47 86.01,47.21 86.14,47.09 87.29,47.09 87.42,46.96 87.42,44.43 86.89,43.91 86.89,41.22 86.37,40.71 86.37,40.07 86.6,39.85 86.6,38.63 87.28,37.95 87.28,36.7 87.16,36.57 v2(86.79,36.57)
  BOTTOM w0.076: UC1.AU71 97.55,77.2 97.44,77.09 96.68,77.09 96.32,76.73 v2(96.32,76.07)
  BOTTOM w0.102: v2(86.79,36.57) 87.18,36.96 87.18,37.72 87.12,37.77 JDIMM1.37
DDR_A_D11: length 63
  IN1 w0.127: v2(96.56,77.88) 96.56,76.93 95.88,76.25 95.88,75.5 95.36,74.98 94.89,74.98 94.5,74.6 93.48,74.6 93.37,74.71 88.11,74.71 86.87,73.47 86.87,50.9 85.67,49.69 85.67,46.87 85.79,46.74 86.95,46.74 87.08,46.62 87.08,46.36 86.95,46.23 86.48,46.23 86.35,46.11 86.35,45.85 86.48,45.73 86.95,45.73 87.08,45.6 87.08,44.57 86.55,44.05 86.55,41.37 86.03,40.85 86.03,39.93 86.26,39.71 86.26,35.83 v2(86.79,35.3)
  BOTTOM w0.076: UC1.AU68 99.79,77.95 99.58,78.15 99.34,78.15 99.32,78.13 98.73,78.13 98.57,78.07 98.42,78.07 98.21,78.14 98.09,78.14 98.01,78.1 97.98,78.09 97.61,78.09 97.45,78.25 96.94,78.25 v2(96.56,77.88)
  BOTTOM w0.102: v2(86.79,35.3) 87.23,35.74 87.23,36.18 88.12,37.08 JDIMM1.41
DDR_A_D12: length 61.3
  IN1 w0.127: v2(84.25,32.76) 83.84,33.17 83.84,33.94 83.5,34.29 83.5,35.07 83.09,35.48 83.09,38.63 82.81,38.9 82.81,39.32 82.3,39.83 82.3,48.87 82.8,49.36 82.8,50.79 83.81,51.81 83.81,65.23 83.5,65.54 83.5,74.06 86.95,77.51 93.21,77.51 93.25,77.56 95.22,77.56 v2(95.39,77.73)
  BOTTOM w0.076: v2(95.39,77.73) 95.61,77.96 95.61,78.04 96.16,78.58 97.78,78.58 UC1.AR71
  BOTTOM w0.102: v2(84.25,32.76) 83.87,32.39 JDIMM1.24
DDR_A_D13: length 62
  IN1 w0.127: v2(84.25,34.03) 83.84,34.44 83.84,35.21 83.49,35.57 83.49,38.72 83.16,39.05 83.16,39.46 82.64,39.97 82.64,48.73 83.14,49.22 83.14,50.65 84.16,51.67 84.16,65.37 84.08,65.44 84.08,74.16 87.09,77.17 93.35,77.17 93.4,77.22 94.31,77.22 94.37,77.28 95.5,77.28 95.97,77.76 v2(95.97,77.88)
  BOTTOM w0.076: v2(95.97,77.88) 96.52,78.42 97.52,78.42 97.68,78.26 97.94,78.26 98.06,78.31 98.08,78.31 98.09,78.32 98.1,78.31 98.2,78.31 98.43,78.25 98.56,78.25 98.78,78.32 99.03,78.32 UC1.AR69
  BOTTOM w0.102: JDIMM1.28 84.87,32.19 84.76,32.3 84.76,33.52 v2(84.25,34.03)
DDR_A_D14: length 61.4
  IN1 w0.127: v2(95.31,75.5) 95.24,75.44 94.29,75.44 93.9,75.05 87.97,75.05 86.28,73.36 86.28,50.79 85.32,49.84 85.32,46.24 85.45,46.11 85.88,46.11 86.01,45.99 86.01,45.73 85.88,45.61 85.45,45.61 85.32,45.48 85.32,45.22 85.45,45.1 86.48,45.1 86.61,44.97 86.61,44.72 86.48,44.59 85.82,44.59 85.69,44.46 85.69,39.79 85.92,39.56 85.92,34.91 v2(86.79,34.03)
  BOTTOM w0.076: v2(95.31,75.5) 95.56,75.25 96.09,75.25 96.97,76.13 96.97,76.7 97.19,76.92 98.21,76.92 UC1.AU70
  BOTTOM w0.102: JDIMM1.42 88.37,31.82 87.94,32.26 87.94,32.89 v2(86.79,34.03)
DDR_A_D15: length 61.6
  IN1 w0.127: v2(86.79,32.76) 87.63,33.6 87.63,38.09 86.94,38.77 86.94,39.99 86.72,40.22 86.72,40.56 87.24,41.08 87.24,43.76 87.76,44.29 87.76,48.08 87.89,48.21 88.78,48.21 88.91,48.34 88.91,48.59 88.78,48.72 87.89,48.72 87.76,48.85 87.76,49.1 87.89,49.23 88.78,49.23 88.91,49.35 88.91,49.64 88.77,49.78 87.89,49.78 87.59,50.09 87.59,73.21 88.4,74.02 93.09,74.02 93.19,73.91 95.5,73.91 97.34,75.76 v2(97.34,76.55)
  BOTTOM w0.076: UC1.AU69 98.93,77.2 98.55,76.82 98.37,76.82 98.29,76.74 97.55,76.74 97.36,76.55 v2(97.34,76.55)
  BOTTOM w0.102: JDIMM1.38 87.37,32.18 v2(86.79,32.76)
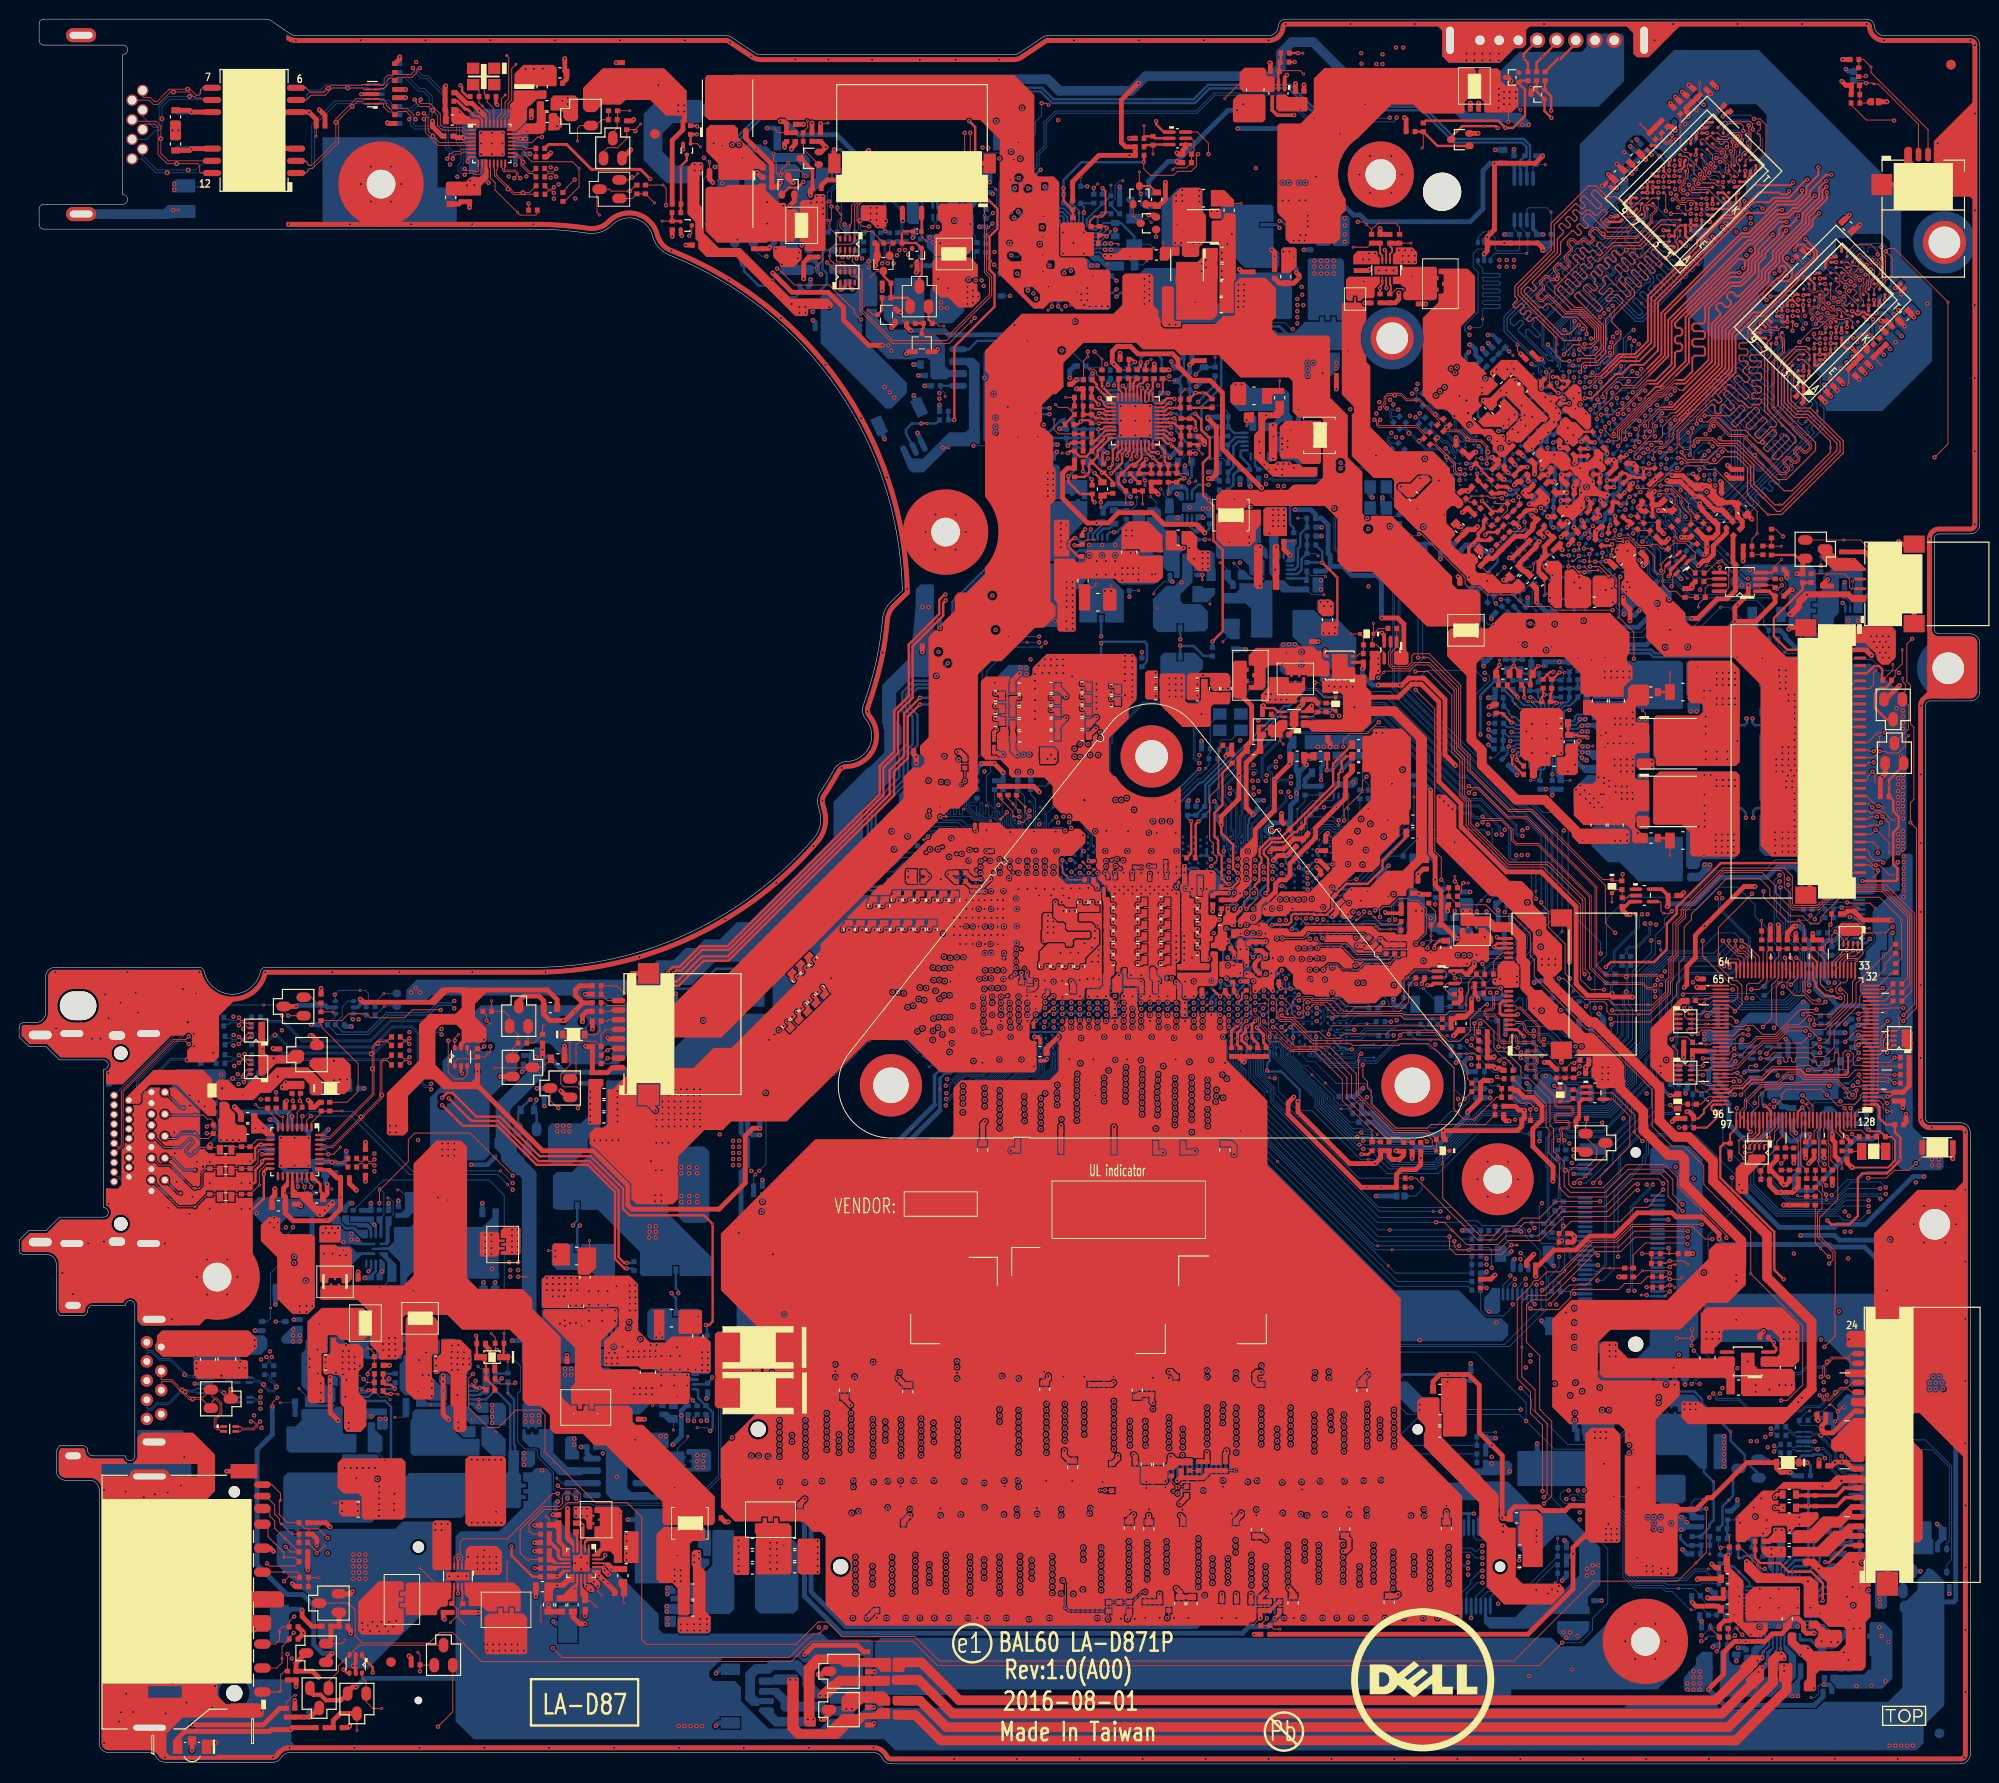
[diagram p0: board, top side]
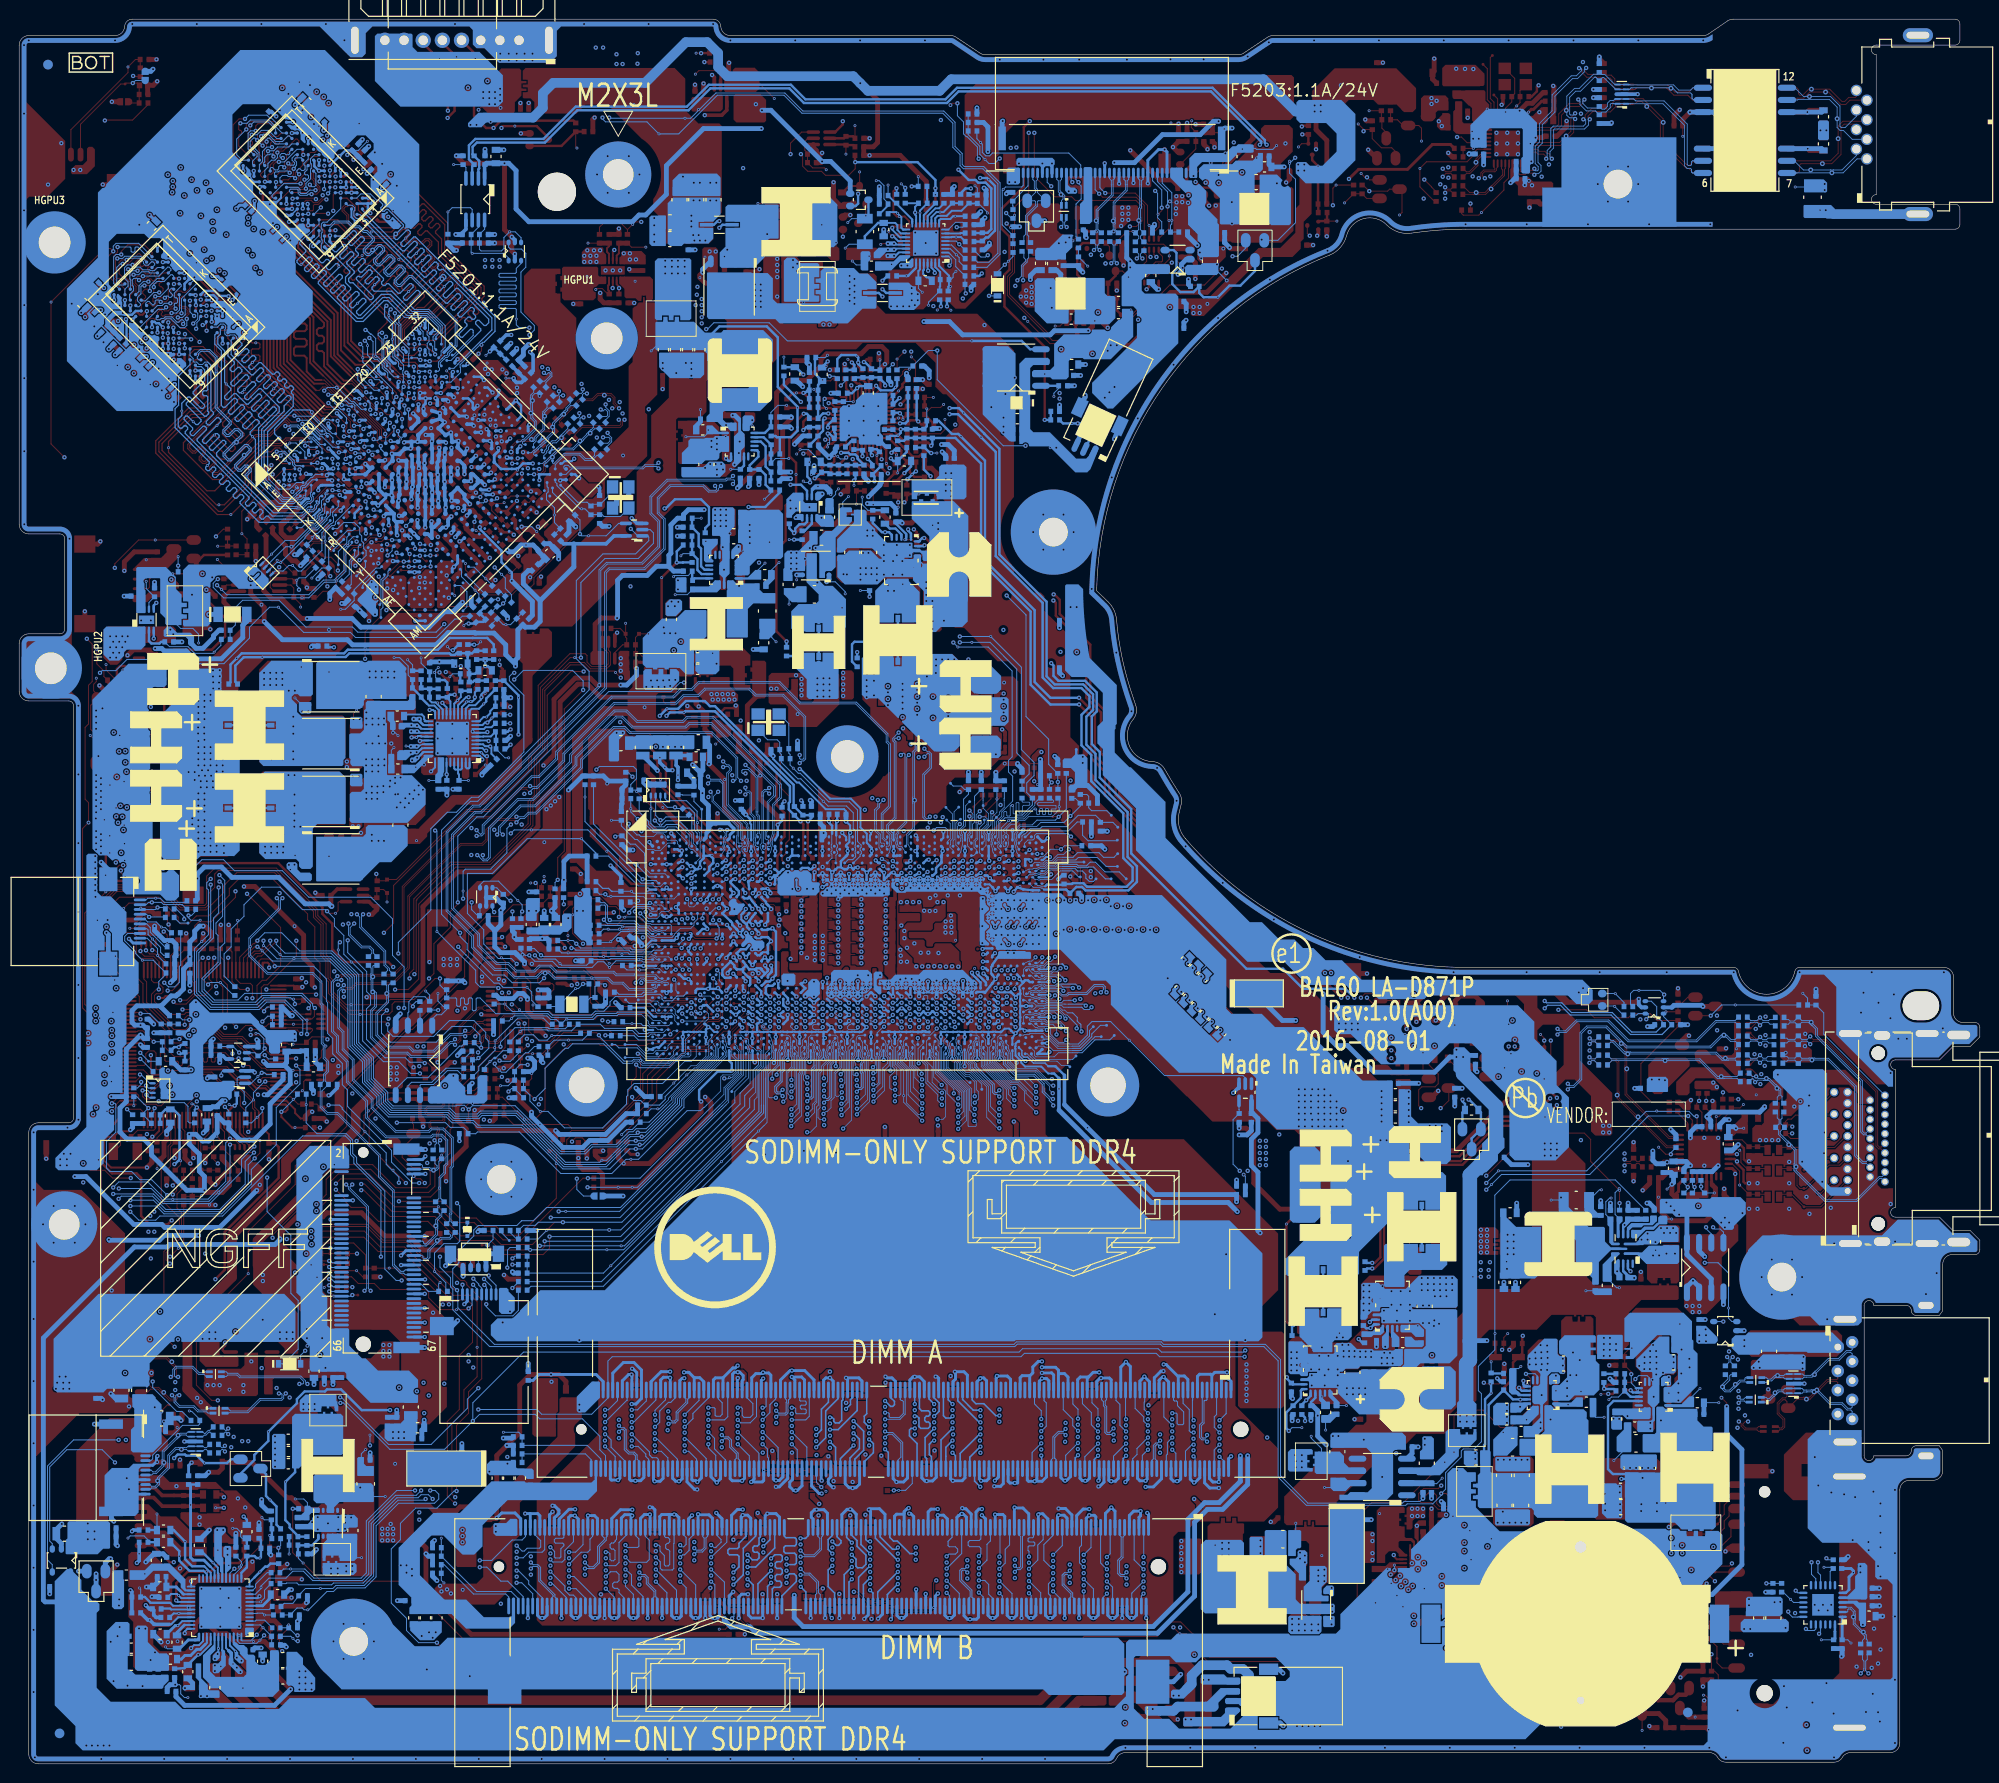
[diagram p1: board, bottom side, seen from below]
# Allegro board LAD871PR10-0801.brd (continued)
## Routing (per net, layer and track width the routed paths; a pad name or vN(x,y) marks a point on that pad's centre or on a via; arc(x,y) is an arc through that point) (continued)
DDR_A_D16: length 52.8
  IN1 w0.127: v2(96.72,69.95) 96.57,70.1 96.25,70.1 96.09,69.94 96.09,69.63 95.88,69.43 95.57,69.43 89.79,63.64 89.79,56.55 89.99,56.36 89.99,56.05 89.79,55.85 89.79,55.54 89.99,55.34 89.99,55.03 89.79,54.83 89.79,54.52 89.99,54.33 89.99,54.01 89.79,53.82 89.79,50.7 90.3,50.19 90.3,44.46 90.18,44.33 89.52,44.33 89.39,44.21 89.39,43.95 89.52,43.82 90.18,43.82 90.3,43.7 90.3,43.43 90.18,43.3 89.19,43.3 89.06,43.17 89.06,42.88 89.19,42.76 90.1,42.76 90.23,42.63 90.23,42.37 89.03,41.18 89.03,35.98 v2(89.07,35.94)
  BOTTOM w0.076: v2(96.72,69.95) 97.07,70.29 97.07,70.68 98.55,72.17 100.55,72.17 101.46,73.09 101.46,73.93 UC1.BB65
  BOTTOM w0.102: v2(89.07,35.94) 89.12,35.99 JDIMM1.45
DDR_A_D17: length 55.6
  IN1 w0.127: v2(89.07,34.67) 88.66,35.09 88.66,43.73 89.05,44.12 89.05,44.35 89.38,44.68 89.61,44.68 89.96,45.03 89.96,50.05 89.45,50.56 89.45,63.79 96,70.34 98.12,70.34 v2(98.48,70.7)
  BOTTOM w0.076: UC1.AW65 102.24,76.01 102.45,75.8 102.45,75.29 102.52,75.13 102.52,74.95 102.47,74.79 102.47,74.65 102.53,74.43 102.53,74.31 102.49,74.2 102.49,73.78 102.64,73.63 102.64,73.3 100.87,71.53 99.31,71.53 v2(98.48,70.7)
  BOTTOM w0.102: v2(89.07,34.67) 89.71,35.31 89.71,37.5 90.12,37.91 JDIMM1.49
DDR_A_D18: length 56.6
  IN1 w0.127: v2(98.45,67.95) 98.19,67.69 96.84,67.69 92.35,63.2 92.35,51.16 92.96,50.54 92.96,40.67 92.1,39.82 91.54,39.82 91.43,39.71 91.43,39.46 91.56,39.33 92.08,39.33 92.23,39.18 92.23,38.93 92.13,38.82 91.56,38.82 91.43,38.7 91.43,38.44 91.56,38.32 92.08,38.32 92.23,38.16 92.23,37.91 92.13,37.81 91.96,37.81 91.84,37.68 91.84,37.43 91.99,37.28 92.1,37.28 92.23,37.15 92.23,36.3 92.42,36.11 92.42,35.8 92.57,35.65 92.57,34.8 92.44,34.67 v2(92,34.67)
  BOTTOM w0.076: v2(98.45,67.95) 99.67,69.17 99.67,70.16 100.38,70.87 101.16,70.87 103.35,73.07 103.35,74.71 103.13,74.93 103.13,75.48 102.82,75.79 UC1.AW63
  BOTTOM w0.102: v2(92,34.67) 92.7,35.37 92.7,36.64 93.62,37.56 JDIMM1.63
DDR_A_D19: length 55.2
  IN1 w0.127: v2(92,32.13) 92.23,31.9 92.41,31.9 92.53,32.03 92.53,32.66 92.66,32.79 92.91,32.79 93.04,32.66 93.04,32.03 93.17,31.9 93.45,31.9 93.57,32.03 93.57,33.08 93.03,33.62 93.03,35.67 92.76,35.94 92.76,36.25 92.57,36.44 92.57,39.69 93.3,40.42 93.3,50.69 92.69,51.3 92.69,63.06 94.99,65.36 97,67.37 98.43,67.37 98.85,67.79 98.85,69.71 v2(98.46,70.09)
  BOTTOM w0.076: UC1.AY63 102.72,75.25 102.72,75 102.64,74.78 102.64,74.65 102.71,74.42 102.71,74.28 102.65,74.16 102.65,73.9 102.83,73.72 102.83,73.25 101.15,71.57 101.14,71.57 100.94,71.37 99.74,71.37 v2(98.46,70.09)
  BOTTOM w0.163: v2(92,32.13) 92.37,31.75 JDIMM1.58
DDR_A_D20: length 54.2
  IN1 w0.127: v2(89.07,33.4) 88.31,34.16 88.31,39.01 87.92,39.4 87.92,43.48 88.7,44.26 88.7,44.9 88.83,45.03 89.47,45.03 89.6,45.15 89.6,45.44 89.47,45.57 88.96,45.57 88.83,45.7 88.83,45.95 88.96,46.08 89.21,46.08 89.34,46.2 89.34,47.35 89.62,47.63 89.62,49.9 89.05,50.47 89.05,63.87 95.91,70.74 v2(96.67,70.74)
  BOTTOM w0.076: v2(96.67,70.74) 96.88,70.74 98.48,72.33 100.48,72.33 101.3,73.15 101.3,74.1 101.44,74.41 101.45,74.41 101.45,74.42 101.59,74.56 UC1.BA65
  BOTTOM w0.102: JDIMM1.50 90.37,32.1 v2(89.07,33.4)
DDR_A_D21: length 54.6
  IN1 w0.127: v2(96.8,71.42) 96.11,71.42 88.7,64.01 88.7,50.33 89.27,49.76 89.27,47.77 89.13,47.62 88.49,47.62 88.36,47.5 88.36,47.17 88.49,47.04 88.77,47.04 88.89,46.92 88.89,46.66 88.77,46.53 88.49,46.53 88.36,46.41 88.36,44.4 87.58,43.62 87.58,39.25 87.97,38.86 87.97,33.23 v2(89.07,32.13)
  BOTTOM w0.076: UC1.AY65 101.59,75.15 101.33,74.89 101.33,74.6 101.27,74.47 101.27,74.43 101.13,74.14 101.13,73.22 100.41,72.5 98.41,72.5 97.33,71.42 v2(96.8,71.42)
  BOTTOM w0.163: v2(89.07,32.13) 89.37,31.83 JDIMM1.46
DDR_A_D22: length 54.8
  IN1 w0.127: v2(98.45,68.88) 97.74,68.88 96.81,67.94 96.6,67.94 92,63.35 92,51 92.62,50.39 92.62,46.52 92.49,46.39 92.21,46.39 92.08,46.26 92.08,46.01 92.21,45.88 92.49,45.88 92.62,45.75 92.62,45.5 92.49,45.37 92.21,45.37 92.08,45.25 92.08,44.99 92.21,44.87 92.49,44.87 92.62,44.74 92.62,44.48 92.49,44.36 92.21,44.36 92.08,44.23 92.08,43.98 92.21,43.85 92.49,43.85 92.62,43.72 92.62,43.47 92.49,43.34 92.21,43.34 92.08,43.21 92.08,42.96 92.21,42.83 92.49,42.83 92.62,42.71 92.62,42.45 92.49,42.33 92.21,42.33 92.08,42.2 92.08,41.94 92.21,41.82 92.49,41.82 92.62,41.69 92.62,41.43 92.46,41.27 91.64,41.27 91.09,40.72 91.09,37.29 91.24,37.14 91.64,37.14 91.77,37 91.77,36.75 91.65,36.63 91.24,36.63 91.09,36.47 91.09,36.16 91.31,35.94 v2(92,35.94)
  BOTTOM w0.076: UC1.BA63 102.92,74.49 103.18,74.23 103.18,73.13 101.09,71.04 100.32,71.04 99.51,70.23 99.51,69.93 v2(98.45,68.88)
  BOTTOM w0.102: v2(92,35.94) 92,37.02 92.62,37.65 JDIMM1.59
DDR_A_D23: length 53.8
  IN1 w0.127: v2(98.44,69.46) 98.02,69.46 96.82,68.26 96.44,68.26 91.5,63.32 91.5,51.02 92.27,50.25 92.27,49.11 92.15,48.99 91.87,48.99 91.74,48.86 91.74,48.61 91.87,48.48 92.15,48.48 92.27,48.35 92.27,48.1 92.15,47.97 91.87,47.97 91.74,47.84 91.74,47.59 91.87,47.46 92.15,47.46 92.27,47.34 92.27,47.08 92.15,46.96 91.87,46.96 91.74,46.83 91.74,41.86 90.75,40.87 90.75,35.99 91.02,35.72 91.02,33.16 91.15,33.03 91.63,33.03 v2(92,33.4)
  BOTTOM w0.076: UC1.BB63 103,73.98 103,73.18 101.02,71.2 100.18,71.2 v2(98.44,69.46)
  BOTTOM w0.102: JDIMM1.62 93.37,32.02 v2(92,33.4)
DDR_A_D24: length 50.6
  IN1 w0.127: v2(100.72,69.85) 99.86,68.99 99.86,68.05 98.55,66.74 97.75,66.74 93.74,62.73 93.74,51.63 94.28,51.09 94.28,39.8 94.36,39.73 94.36,39.4 94.24,39.28 93.68,39.28 93.55,39.16 93.55,38.9 93.68,38.78 94.36,38.78 94.48,38.65 94.48,38.37 94.36,38.24 93.68,38.24 93.55,38.12 93.55,37.86 93.68,37.74 94.36,37.74 94.48,37.61 94.48,37.36 94.36,37.24 93.93,37.24 93.74,37.05 93.74,36.35 v2(94.09,36)
  BOTTOM w0.076: UC1.BA61 103.95,74.48 103.68,74.22 103.68,72.93 101.02,70.27 101.02,70.15 v2(100.72,69.85)
  BOTTOM w0.102: JDIMM1.67 94.62,37.53 94.09,36.99 v2(94.09,36)
DDR_A_D25: length 51.9
  IN1 w0.127: v2(100.72,70.49) 99.48,69.25 99.48,68.05 98.48,67.06 97.58,67.06 93.4,62.87 93.4,51.48 93.94,50.95 93.94,39.79 93.77,39.63 93.41,39.63 93.21,39.42 93.21,36.71 93.4,36.52 93.4,36.21 93.67,35.93 93.67,33.88 v2(94.09,33.46)
  BOTTOM w0.076: v2(100.72,70.49) 100.82,70.59 101.1,70.59 103.51,73 103.51,74.74 103.72,74.95 103.72,75.49 104.05,75.82 UC1.AW61
  BOTTOM w0.102: JDIMM1.70 95.37,32.17 v2(94.09,33.46)
DDR_A_D26: length 50.8
  IN1 w0.127: v2(97.92,34.7) 97.5,34.28 97.5,33.94 97.32,33.77 97.07,33.77 96.95,33.89 96.95,51.91 96.32,52.53 96.32,61.77 100.02,65.47 100.64,65.47 101.53,66.36 101.53,66.88 v2(102.3,67.65)
  BOTTOM w0.076: v2(102.3,67.65) 103.22,68.57 103.22,70.71 105.02,72.51 105.02,72.51 105.13,72.63 105.13,73.03 105.37,73.27 105.37,73.95 UC1.BB59
  BOTTOM w0.102: v2(97.92,34.7) 97.4,35.22 97.4,37.65 97.62,37.88 JDIMM1.79
DDR_A_D27: length 52.8
  IN1 w0.127: v2(102.3,68.95) 101.91,68.56 101.91,68.13 101.72,67.94 101.72,67.44 101.21,66.93 101.21,66.55 100.43,65.77 99.84,65.77 95.87,61.8 95.87,52.51 96.6,51.77 96.6,33.08 96.76,32.92 97.42,32.92 v2(97.92,33.43)
  BOTTOM w0.076: UC1.AW59 104.62,76.01 104.42,75.8 104.42,75.29 104.34,75.19 104.34,74.94 104.39,74.81 104.39,74.58 104.38,74.57 104.38,74.57 104.38,74.57 104.34,74.48 104.34,74.28 104.38,74.19 104.38,73.83 104.18,73.63 104.18,72.72 101.91,70.45 101.91,69.34 v2(102.3,68.95)
  BOTTOM w0.102: JDIMM1.84 98.87,32.47 v2(97.92,33.43)
DDR_A_D28: length 49.7
  IN1 w0.127: v2(94.09,32.19) 95.07,32.19 95.29,32.41 95.29,32.87 94.9,33.26 94.9,35.67 95.17,35.94 95.17,39.89 94.97,40.09 94.97,51.38 94.43,51.91 94.43,62.45 98.09,66.1 98.8,66.1 101.13,68.43 101.13,68.81 v2(100.72,69.22)
  BOTTOM w0.076: v2(100.72,69.22) 101.32,69.82 101.32,70.34 103.85,72.86 103.85,73.95 UC1.BB61
  BOTTOM w0.163: JDIMM1.66 94.37,31.9 v2(94.09,32.19)
DDR_A_D29: length 52
  IN1 w0.127: v2(100.72,68.58) 100.72,68.47 98.67,66.42 97.92,66.42 94.09,62.59 94.09,51.77 94.62,51.23 94.62,39.95 94.83,39.74 94.83,37.02 94.7,36.9 94.25,36.9 94.12,36.77 94.12,36.52 94.25,36.39 94.64,36.39 94.76,36.28 94.76,36.01 94.56,35.82 94.56,34.88 94.41,34.73 v2(94.09,34.73)
  BOTTOM w0.076: UC1.AY61 104.15,75.25 104.15,74.99 104.21,74.81 104.21,74.6 104.18,74.51 104.18,74.25 104.21,74.16 104.21,73.9 104.01,73.7 104.01,72.79 101.56,70.34 101.56,69.42 v2(100.72,68.58)
  BOTTOM w0.102: v2(94.09,34.73) 94.63,35.27 94.63,35.95 95.62,36.94 JDIMM1.71
DDR_A_D30: length 51.7
  IN1 w0.127: v2(102.3,67) 101.78,66.48 101.78,66.23 100.77,65.21 100.26,65.21 96.67,61.62 96.67,52.68 97.37,51.97 97.37,47.17 97.5,47.04 97.87,47.04 98,46.92 98,46.66 97.87,46.54 97.5,46.54 97.37,46.41 97.37,46.16 97.5,46.03 97.87,46.03 98,45.9 98,45.65 97.87,45.52 97.5,45.52 97.29,45.31 97.29,39.93 97.5,39.72 97.87,39.72 97.99,39.59 97.99,39.34 97.87,39.21 97.5,39.21 97.37,39.09 97.37,38.83 97.5,38.7 97.87,38.7 97.99,38.58 97.99,38.32 97.87,38.2 97.5,38.2 97.37,38.07 97.37,37.82 97.5,37.69 97.87,37.69 97.99,37.56 97.99,37.31 97.87,37.18 97.5,37.18 97.37,37.05 97.37,36.09 97.5,35.97 v2(97.92,35.97)
  BOTTOM w0.076: v2(102.3,67) 103.41,68.11 103.41,70.66 105.3,72.54 105.3,72.96 105.54,73.2 105.54,74.15 105.48,74.3 UC1.BA59
  BOTTOM w0.102: v2(97.92,35.97) 97.92,36.84 98.62,37.55 JDIMM1.83
DDR_A_D31: length 52.3
  IN1 w0.127: v2(102.29,66.29) 102.29,66.22 100.97,64.9 100.42,64.9 98.34,62.81 97.01,61.48 97.01,52.82 97.78,52.04 97.78,47.61 98.34,47.06 98.34,45.13 98.21,45 97.84,45 97.72,44.87 97.72,44.62 97.84,44.49 98.21,44.49 98.34,44.37 98.34,44.11 98.21,43.98 97.84,43.98 97.72,43.86 97.72,43.6 97.84,43.48 98.21,43.48 98.34,43.35 98.34,43.1 98.21,42.97 97.84,42.97 97.72,42.84 97.72,42.59 97.84,42.46 98.21,42.46 98.34,42.33 98.34,32.57 v2(97.92,32.16)
  BOTTOM w0.076: UC1.AY59 105.27,75.15 105.54,74.89 105.54,74.69 105.67,74.26 105.7,74.19 105.7,73.13 105.46,72.89 105.46,72.46 103.61,70.6 103.61,67.43 102.44,66.26 102.33,66.26 v2(102.29,66.29)
  BOTTOM w0.163: v2(97.92,32.16) 97.87,32.11 JDIMM1.80
DDR_A_D32: length 51.9
  IN1 w0.102: 118.08,64.5 117.15,65.42 v2(117.15,67.74)
  IN1 w0.127: 118.08,64.5 118.08,60.64 118.19,60.53 118.19,53.82 124.7,47.31 124.7,36.93 124.54,36.77 124.49,36.77 124.36,36.64 124.36,36.34 124.49,36.21 124.82,36.21 124.95,36.09 124.95,35.83 124.82,35.71 124.49,35.71 124.36,35.58 124.36,35.33 124.49,35.2 124.82,35.2 124.95,35.07 124.95,34.82 124.82,34.69 124.49,34.69 124.36,34.56 124.36,34.31 124.49,34.18 124.82,34.18 124.95,34.06 124.95,33.8 124.82,33.67 124.49,33.67 124.36,33.55 124.36,33.4 124.3,33.33 v2(123.94,33.33)
  BOTTOM w0.076: UC1.AY39 116.32,75.15 116.05,74.89 116.05,74.6 115.95,74.35 115.95,74.33 115.88,74.2 115.88,73.88 115.88,73.88 115.88,73.84 115.88,73.84 115.88,73.79 115.98,73.7 115.98,72.44 115.82,72.28 115.82,69.08 v2(117.15,67.74)
  BOTTOM w0.102: JDIMM1.174 123.37,32.77 v2(123.94,33.33)
DDR_A_D33: length 50.3
  IN1 w0.102: 117.04,62.26 116.9,62.4 116.9,64.83 116.18,65.55 116.18,71.5 v2(117.18,72.5)
  IN1 w0.127: v2(123.94,34.6) 122.93,35.61 122.93,46.99 117.04,52.88 117.04,62.26
  BOTTOM w0.076: UC1.AW39 116.96,75.97 117.03,75.95 117.14,75.83 117.23,75.59 117.23,75.17 117.25,75.13 117.25,74.95 117.19,74.79 117.19,74.65 117.26,74.43 117.26,74.31 117.21,74.2 117.21,73.81 117.27,73.72 117.36,73.58 117.39,73.5 117.39,73.25 v2(117.18,72.5)
  BOTTOM w0.102: JDIMM1.170 122.37,33.04 v2(123.94,34.6)
DDR_A_D34: length 51.8
  IN1 w0.076: v2(117.18,71.91) 118.03,71.06 118.03,65.33 118.97,64.39 118.97,62.95 119.51,62.41 119.51,62.23
  IN1 w0.127: 119.51,62.23 119.51,61.21 119.63,61.1 119.63,55.12 122.29,52.45 122.47,52.45 122.78,52.76 122.96,52.76 123.14,52.58 123.14,52.4 122.83,52.09 122.83,51.91 123.01,51.73 123.19,51.73 123.5,52.04 123.68,52.04 123.86,51.86 123.86,51.68 123.55,51.37 123.55,51.19 123.73,51.01 123.91,51.01 124.22,51.32 124.4,51.32 124.58,51.14 124.58,50.96 124.27,50.65 124.27,50.47 124.45,50.29 124.63,50.29 124.94,50.6 125.12,50.6 125.3,50.42 125.3,50.24 124.99,49.93 124.99,49.76 125.17,49.57 125.35,49.57 125.66,49.88 125.84,49.88 126.25,49.47 126.25,39.89 126.38,39.76 126.94,39.76 127.06,39.64 127.06,39.38 126.94,39.26 126.45,39.26 126.3,39.11 126.3,38.85 126.42,38.73 126.87,38.73 126.99,38.61 v2(126.99,37.14)
  BOTTOM w0.076: v2(117.18,71.91) 117.18,71.86 117.26,71.78 117.45,71.78 117.56,71.88 117.56,73.71 117.38,73.89 117.38,74.16 117.43,74.28 117.43,74.42 117.37,74.65 117.37,74.78 117.41,74.92 117.41,75.3 117.47,75.36 UC1.AY37
  BOTTOM w0.102: JDIMM1.187 126.62,37.29 126.77,37.14 v2(126.99,37.14)
DDR_A_D35: length 53.5
  IN1 w0.076: 120.54,62.23 120.54,63.62 119.15,65.01 119.15,67.93 118.82,68.25 v2(118.8,68.25)
  IN1 w0.127: 120.54,62.23 120.54,61.64 120.88,61.3 120.88,56.4 128.02,49.26 128.02,45.25 127.89,45.12 127.41,45.12 127.28,44.99 127.28,44.74 127.41,44.61 127.95,44.61 128.09,44.47 128.09,44.24 127.97,44.12 127.41,44.12 127.28,43.99 127.28,43.76 127.41,43.64 127.97,43.64 128.09,43.51 128.09,43.25 127.97,43.12 127.76,43.12 127.63,42.99 127.63,42.74 127.76,42.61 127.97,42.61 128.09,42.49 128.09,34.48 126.99,33.38 v2(126.99,33.33)
  BOTTOM w0.076: UC1.AW37 117.54,75.79 117.85,75.48 117.85,74.93 118.07,74.71 118.07,69 118.8,68.27 v2(118.8,68.25)
  BOTTOM w0.102: v2(126.99,33.33) 126.49,32.83 126.49,32 126.37,31.89 JDIMM1.186
DDR_A_D36: length 50.8
  IN1 w0.102: 117.38,62.48 117.09,62.78 117.09,64.91 116.37,65.62 116.37,68.14 v2(117.15,68.92)
  IN1 w0.127: 117.38,62.48 117.38,53.23 123.27,47.35 123.27,43.2 123.4,43.07 123.89,43.07 124.02,42.94 124.02,42.69 123.89,42.56 123.48,42.56 123.36,42.44 123.36,42.19 123.48,42.06 123.89,42.06 124.02,41.93 124.02,41.68 123.89,41.55 123.4,41.55 123.27,41.42 123.27,40.06 123.4,39.93 123.89,39.93 124.02,39.81 124.02,39.55 123.89,39.43 123.4,39.43 123.27,39.3 123.27,35.76 123.41,35.62 123.69,35.62 v2(123.94,35.87)
  BOTTOM w0.076: UC1.BB39 116.32,74.05 116.32,72.2 116.28,72.16 116.28,69.8 117.15,68.93 v2(117.15,68.92)
  BOTTOM w0.102: JDIMM1.169 122.12,36.24 122.49,35.87 v2(123.94,35.87)
DDR_A_D37: length 51.4
  IN1 w0.102: 117.73,62.23 117.73,62.42 117.61,62.53 117.61,64.67 116.77,65.51 116.77,67.95 v2(117.15,68.33)
  IN1 w0.127: v2(123.94,37.14) 124.23,37.14 124.36,37.27 124.36,38.38 124.23,38.51 123.74,38.51 123.62,38.63 123.62,38.89 123.74,39.01 124.23,39.01 124.36,39.14 124.36,43.29 124.23,43.41 123.83,43.41 123.7,43.54 123.7,43.8 123.83,43.92 124.23,43.92 124.36,44.05 124.36,44.3 124.23,44.43 123.83,44.43 123.7,44.56 123.7,44.81 123.83,44.94 124.23,44.94 124.36,45.07 124.36,45.32 124.23,45.45 123.83,45.45 123.71,45.57 123.71,47.61 117.73,53.58 117.73,62.22 117.73,62.23
  BOTTOM w0.076: UC1.BA39 116.32,74.56 116.18,74.42 116.17,74.41 116.17,74.41 116.05,74.16 116.05,73.86 116.16,73.76 116.16,72.36 116.04,72.25 116.04,69.27 116.98,68.33 v2(117.15,68.33)
  BOTTOM w0.102: JDIMM1.173 123.12,37.91 123.05,37.84 122.54,37.84 122.44,37.74 122.44,37.51 122.54,37.41 122.95,37.41 123.06,37.31 123.06,37.11 122.95,37 122.54,37 122.44,36.9 122.44,36.61 122.54,36.51 123.44,36.51 123.54,36.61 123.54,37.04 123.64,37.14 v2(123.94,37.14)
DDR_A_D38: length 51.7
  IN1 w0.076: v2(118.75,67.66) 118.39,67.3 118.39,66.78 118.53,66.64 118.73,66.64 118.97,66.4 118.97,64.9 120.2,63.67 120.2,62.23
  IN1 w0.127: 120.2,62.23 120.2,61.5 120.54,61.15 120.54,56.25 127.52,49.27 127.52,46.83 127.4,46.71 127.07,46.71 126.94,46.58 126.94,46.35 127.07,46.22 127.55,46.22 127.67,46.1 127.67,45.84 127.55,45.72 127.07,45.72 126.94,45.59 126.94,42.42 127.07,42.3 127.62,42.3 127.75,42.17 127.75,35.37 v2(126.99,34.6)
  BOTTOM w0.076: v2(118.75,67.66) 117.91,68.51 117.91,74.44 UC1.BA37
  BOTTOM w0.102: v2(126.99,34.6) 125.38,32.99 125.38,31.68 125.37,31.68 JDIMM1.182
DDR_A_D39: length 51.4
  IN1 w0.076: v2(118.59,66.26) 118.59,65.05 119.85,63.78 119.85,62.23
  IN1 w0.127: v2(126.99,35.87) 127.41,36.29 127.41,41.79 127.24,41.95 126.71,41.95 126.6,42.07 126.6,46.92 126.72,47.05 127.05,47.05 127.18,47.18 127.18,47.43 127.05,47.56 126.72,47.56 126.6,47.68 126.6,48.16 126.72,48.28 127.05,48.28 127.18,48.41 127.18,48.66 127.05,48.79 126.72,48.79 126.6,48.92 126.6,49.61 122.87,53.33 122.69,53.33 122.38,53.03 122.2,53.03 122.02,53.21 122.02,53.39 122.33,53.69 122.33,53.87 122.15,54.05 121.97,54.05 121.67,53.74 121.49,53.74 121.31,53.92 121.31,54.1 121.61,54.41 121.61,54.59 121.43,54.77 121.25,54.77 120.94,54.47 120.76,54.47 120.58,54.65 120.58,54.83 120.89,55.13 120.89,55.31 120.14,56.07 120.14,61.07 119.85,61.36 119.85,62.23
  BOTTOM w0.076: UC1.BB37 117.64,73.86 117.72,73.78 117.72,67.13 v2(118.59,66.26)
  BOTTOM w0.102: v2(126.99,35.87) 126.23,36.64 126.23,37.46 125.62,38.06 JDIMM1.183
DDR_A_D40: length 53.6
  IN1 w0.076: 121.52,62.23 121.52,63.11 119.48,65.15 119.48,69.65 119.09,70.04 v2(118.73,70.04)
  IN1 w0.127: 121.52,62.23 121.52,62.05 121.86,61.7 121.86,56.8 129.07,49.59 129.07,46.32 129.2,46.19 129.53,46.19 129.66,46.06 129.66,45.81 129.53,45.68 129.2,45.68 129.07,45.55 129.07,45.3 129.2,45.17 129.53,45.17 129.66,45.05 129.66,44.79 129.53,44.66 129.2,44.66 129.07,44.54 129.07,44.28 129.2,44.15 129.53,44.15 129.66,44.03 129.66,43.77 129.53,43.64 129.2,43.64 129.07,43.52 129.07,43.26 129.2,43.14 129.53,43.14 129.66,43.01 129.66,42.76 129.53,42.63 129.2,42.63 129.07,42.5 129.07,40.15 129.66,39.57 129.66,37.22 v2(129.58,37.14)
  BOTTOM w0.076: UC1.AY35 118.83,75.36 118.9,75.28 118.9,74.91 118.94,74.81 118.94,74.6 118.9,74.51 118.9,74.25 118.94,74.16 118.94,73.89 118.75,73.71 118.75,72.63 119.36,72.02 119.36,69.69 119.29,69.62 119.07,69.62 118.73,69.96 v2(118.73,70.04)
  BOTTOM w0.102: v2(129.58,37.14) 129.51,37.22 129.25,37.22 129.11,37.08 129.11,36.33 128.92,36.14 128.28,36.14 128,36.42 128,37.57 128.62,38.19 JDIMM1.195
DDR_A_D41: length 54.4
  IN1 w0.076: 121.18,62.23 121.18,63.21 119.31,65.08 119.31,69.03 119.19,69.15 118.95,69.15 118.77,68.98 v2(118.77,68.85)
  IN1 w0.127: v2(129.58,35.87) 129.29,35.59 128.84,35.59 128.73,35.7 128.73,35.99 128.86,36.11 129.03,36.11 129.16,36.24 129.16,36.5 129.03,36.62 128.86,36.62 128.73,36.75 128.73,37.05 128.86,37.18 129.08,37.18 129.18,37.28 129.18,37.56 129.07,37.68 128.84,37.68 128.73,37.79 128.73,38.06 128.86,38.18 129.11,38.18 129.24,38.31 129.24,38.56 129.11,38.69 128.86,38.69 128.73,38.82 128.73,39.05 128.86,39.18 129.05,39.18 129.18,39.3 129.18,39.56 129.05,39.68 128.86,39.68 128.73,39.81 128.73,49.45 121.52,56.66 121.52,61.56 121.18,61.9 121.18,62.23
  BOTTOM w0.076: v2(118.77,68.85) 118.64,68.85 118.24,69.25 118.24,74.29 118.34,74.39 118.34,74.84 118.45,74.95 118.45,75.49 118.77,75.82 UC1.AW35
  BOTTOM w0.102: JDIMM1.191 127.62,36.22 128.28,35.56 129.27,35.56 v2(129.58,35.87)
DDR_A_D42: length 53.5
  IN1 w0.076: v2(120.57,67.21) 120.95,66.83 120.95,65.14 122.58,63.5 123.06,63.5 123.22,63.35
  IN1 w0.127: 123.22,63.35 123.98,62.58 123.98,57.68 131.86,49.8 131.86,40.38 131.99,40.25 132.2,40.25 132.33,40.13 132.33,39.87 132.2,39.75 131.99,39.75 131.86,39.62 131.86,39.28 131.99,39.15 132.6,39.15 132.73,39.03 132.73,38.77 132.6,38.64 131.99,38.64 131.86,38.52 131.86,38.26 131.99,38.14 132.6,38.14 132.73,38.01 132.73,37.76 132.6,37.63 131.99,37.63 131.86,37.5 131.86,37.3 132.01,37.14 v2(132.65,37.14)
  BOTTOM w0.076: UC1.AY33 120,75.15 120.27,74.88 120.27,74.56 120.43,74.22 120.43,73.83 120.3,73.71 120.3,73.71 120.28,73.68 120.28,73.34 120.85,72.77 120.85,72.19 121,72.03 121,68.43 121.21,68.22 121.21,67.41 121.01,67.21 v2(120.57,67.21)
  BOTTOM w0.102: JDIMM1.207 131.62,38.08 131.21,37.66 131.21,36.45 131.41,36.25 131.84,36.25 131.95,36.35 131.95,37.04 132.05,37.14 v2(132.65,37.14)
DDR_A_D43: length 52.6
  IN1 w0.076: v2(120.64,67.79) 121.19,67.24 121.19,65.18 122.04,64.33 122.98,64.33 123.31,63.99 123.31,63.74 123.46,63.59
  IN1 w0.127: 123.46,63.59 124.33,62.72 124.33,57.82 132.35,49.8 132.35,41.27 133.07,40.55 133.07,36.29 v2(132.65,35.87)
  BOTTOM w0.076: UC1.AW33 119.34,76.01 119.14,75.8 119.14,75.29 119.07,75.19 119.07,74.94 119.11,74.81 119.11,74.58 119.11,74.57 119.1,74.57 119.1,74.57 119.07,74.48 119.07,74.28 119.1,74.19 119.1,73.82 119.1,73.52 118.92,73.34 118.92,72.69 119.53,72.08 119.53,69.5 119.85,69.17 119.85,68.43 120.25,68.04 120.38,68.04 v2(120.64,67.79)
  BOTTOM w0.102: JDIMM1.203 130.62,36.21 130.96,35.87 v2(132.65,35.87)
DDR_A_D44: length 51.1
  IN1 w0.076: v2(118.84,71.93) 119.86,70.9 119.86,65.31 122.17,63 122.17,62.37 122.2,62.33
  IN1 w0.127: 122.2,62.33 122.55,61.99 122.55,57.09 130.16,49.48 130.16,48.74 129.76,48.34 129.76,48.08 129.88,47.95 130.29,47.95 130.41,47.82 130.41,35.26 130.42,35.25 130.42,34.42 130.26,34.26 130.17,34.26 130.04,34.13 130.04,33.88 130.17,33.75 130.55,33.75 130.67,33.62 130.67,33.38 130.52,33.23 129.69,33.23 v2(129.58,33.33)
  BOTTOM w0.076: UC1.BB35 118.59,73.97 118.59,72.18 v2(118.84,71.93)
  BOTTOM w0.102: v2(129.58,33.33) 128.37,32.13 JDIMM1.194
DDR_A_D45: length 51.7
  IN1 w0.076: 121.86,62.23 121.86,63.01 119.64,65.23 119.64,70.47 119.44,70.67 v2(118.75,70.67)
  IN1 w0.127: v2(129.58,34.6) 129.89,34.6 130.04,34.76 130.04,46.33 129.84,46.53 129.54,46.53 129.41,46.65 129.41,46.97 129.54,47.1 129.94,47.1 130.07,47.23 130.07,47.48 129.94,47.61 129.54,47.61 129.41,47.74 129.41,49.73 122.2,56.94 122.2,61.84 121.88,62.16 121.88,62.21 121.86,62.23
  BOTTOM w0.076: UC1.BA35 118.67,74.48 118.4,74.22 118.4,71.02 v2(118.75,70.67)
  BOTTOM w0.102: JDIMM1.190 127.37,32.4 v2(129.58,34.6)
DDR_A_D46: length 51.6
  IN1 w0.076: v2(120.6,71.5) 121.57,70.52 121.57,65.43 122.23,64.77 123.25,64.77 123.95,64.07
  IN1 w0.127: 123.95,64.07 125.01,63.01 125.01,58.11 133.03,50.08 133.03,41.56 133.75,40.84 133.75,33.59 133.5,33.33 v2(132.65,33.33)
  BOTTOM w0.076: UC1.BA33 120,74.68 120.18,74.37 120.26,74.18 120.26,73.9 120.12,73.76 120.12,73.76 120.11,73.75 120.11,73.27 120.62,72.76 120.62,71.53 v2(120.6,71.5)
  BOTTOM w0.102: v2(132.65,33.33) 132.65,32.95 131.87,32.18 JDIMM1.208
DDR_A_D47: length 50.7
  IN1 w0.076: 123.7,63.83 122.96,64.58 122.1,64.58 121.38,65.3 121.38,70.02 v2(120.59,70.81)
  IN1 w0.127: v2(132.65,34.6) 133.14,34.6 133.41,34.87 133.41,40.69 132.69,41.41 132.69,49.94 124.67,57.97 124.67,62.87 123.7,63.83
  BOTTOM w0.076: UC1.BB33 119.95,74 119.95,73.2 120.21,72.93 120.21,71.18 v2(120.59,70.81)
  BOTTOM w0.102: JDIMM1.204 130.87,31.72 132,32.85 132,33.96 v2(132.65,34.6)
DDR_A_D48: length 55.1
  IN1 w0.076: 124.88,65.01 124.62,65.27 122.95,65.27 v2(122.34,65.88)
  IN1 w0.127: 124.88,65.01 124.92,65.01 126.33,63.59 126.33,58.66 134.36,50.63 134.36,44.5 134.48,44.38 135.18,44.38 135.31,44.25 135.31,44 135.18,43.87 134.48,43.87 134.36,43.74 134.36,43.49 134.46,43.38 135.38,43.38 135.88,42.88 135.88,35.9 v2(135.12,35.14)
  BOTTOM w0.076: v2(122.34,65.88) 122.01,65.88 121.38,66.5 121.38,68.5 121.18,68.7 121.18,72.14 121.01,72.3 121.01,73.68 120.87,73.83 120.87,74.19 121.03,74.6 121.03,74.89 121.3,75.15 UC1.AY31
  BOTTOM w0.102: JDIMM1.211 132.62,38.17 134.26,36.54 134.26,36 v2(135.12,35.14)
DDR_A_D49: length 54.8
  IN1 w0.076: v2(122.32,71.6) 122.32,71.57 121.76,71.01 121.76,65.62 122.45,64.94 123.98,64.94 124.4,64.52
  IN1 w0.127: 124.4,64.52 125.65,63.27 125.65,58.37 133.67,50.35 133.67,42.82 133.8,42.7 134.36,42.7 134.49,42.57 134.49,42.16 134.36,42.04 134.02,42.04 133.9,41.91 133.9,41.59 134.02,41.47 134.26,41.47 134.39,41.34 134.39,36.88 134.7,36.57 134.7,32.94 135.03,32.6 v2(135.12,32.6)
  BOTTOM w0.076: v2(122.32,71.6) 122.49,71.77 122.49,73.38 122.19,73.67 122.19,74.2 122.2,74.23 122.24,74.31 122.24,74.43 122.17,74.65 122.17,74.79 122.23,74.95 122.23,75.13 122.21,75.18 122.21,75.75 121.95,76.01 UC1.AW31
  BOTTOM w0.102: JDIMM1.216 133.87,31.77 134.7,32.6 v2(135.12,32.6)
DDR_A_D50: length 53.7
  IN1 w0.076: v2(122.34,70.97) 123.56,69.74 123.56,66.44 123.86,66.14 124.24,66.14 124.66,66.56 125.53,66.56
  IN1 w0.127: 125.53,66.56 126.42,66.56 128.63,64.35 128.63,58.87 136.19,51.32 136.19,48.9 136.31,48.78 136.84,48.78 136.96,48.65 136.96,48.4 136.84,48.27 136.31,48.27 136.19,48.14 136.19,47.89 136.31,47.76 136.77,47.76 136.9,47.63 136.9,47.38 136.77,47.25 136.31,47.25 136.19,47.13 136.19,46.86 136.31,46.74 136.65,46.74 136.77,46.61 136.77,45.65 138.29,44.13 138.29,36.49 v2(138.22,36.41)
  BOTTOM w0.076: UC1.AY29 122.42,75.25 122.42,75 122.35,74.78 122.35,74.65 122.41,74.42 122.41,74.28 122.36,74.16 122.36,73.74 122.65,73.45 122.65,71.88 122.71,71.82 122.71,71.35 v2(122.34,70.97)
  BOTTOM w0.102: v2(138.22,36.41) 138.22,36.87 137.12,37.96 JDIMM1.229
DDR_A_D51: length 55.2
  IN1 w0.076: 125.53,67.59 124.06,67.59 v2(123.98,67.68)
  IN1 w0.127: v2(138.22,32.6) 139.32,33.7 139.32,44.56 137.99,45.88 137.99,50.97 129.66,59.3 129.66,64.78 126.85,67.59 125.53,67.59
  BOTTOM w0.076: UC1.AW29 122.52,75.79 122.83,75.48 122.83,74.93 123.06,74.71 123.06,73.76 123.15,73.67 123.15,72.1 123.27,71.97 123.27,68.38 v2(123.98,67.68)
  BOTTOM w0.102: v2(138.22,32.6) 137.56,32.6 136.87,31.92 JDIMM1.228
DDR_A_D52: length 53.6
  IN1 w0.076: 124.64,64.76 124.3,65.1 122.59,65.1 121.95,65.74 121.95,67.37 v2(122.33,67.75)
  IN1 w0.127: v2(135.12,36.41) 135.04,36.49 135.04,37.06 135.19,37.22 135.45,37.22 135.54,37.3 135.54,37.54 135.41,37.67 134.86,37.67 134.73,37.8 134.73,38.05 134.86,38.18 135.41,38.18 135.54,38.3 135.54,38.56 135.41,38.68 134.99,38.68 134.86,38.81 134.86,39.07 134.99,39.19 135.41,39.19 135.54,39.32 135.54,39.57 135.41,39.7 134.79,39.7 134.73,39.76 134.73,41.12 134.86,41.25 135.41,41.25 135.54,41.38 135.54,41.72 135.41,41.85 135.09,41.85 134.99,41.94 134.99,42.23 135.12,42.35 135.43,42.35 135.54,42.46 135.54,42.74 135.23,43.04 134.21,43.04 134.01,43.23 134.01,50.49 125.99,58.51 125.99,63.41 124.64,64.76
  BOTTOM w0.076: UC1.BB31 121.3,73.88 121.34,73.83 121.34,72.52 121.51,72.35 121.51,69.07 121.76,68.81 121.76,68.33 v2(122.33,67.75)
  BOTTOM w0.102: JDIMM1.215 133.62,37.9 v2(135.12,36.41)
DDR_A_D53: length 53.8
  IN1 w0.076: v2(122.33,67.16) 122.33,66.76 123.67,65.43 124.98,65.43 125.14,65.27
  IN1 w0.127: 125.14,65.27 125.28,65.13 125.82,65.13 127.2,63.76 127.2,58.28 134.7,50.77 134.7,45.66 136.22,44.14 136.22,34.99 136.09,34.87 135.69,34.87 135.57,34.74 135.57,34.48 135.69,34.36 135.76,34.36 135.88,34.23 135.88,33.98 135.78,33.87 v2(135.12,33.87)
  BOTTOM w0.076: UC1.BA31 121.3,74.56 121.16,74.42 121.15,74.41 121.15,74.41 121.03,74.16 121.03,73.9 121.18,73.75 121.18,72.42 121.34,72.25 121.34,68.98 121.57,68.75 121.57,67.93 v2(122.33,67.16)
  BOTTOM w0.102: v2(135.12,33.87) 134.89,33.87 132.87,31.85 JDIMM1.212
DDR_A_D54: length 53.9
  IN1 w0.076: 125.53,67.25 124.16,67.25 v2(124.01,67.1)
  IN1 w0.127: 125.53,67.25 126.7,67.25 129.32,64.64 129.32,59.16 137.65,50.82 137.65,45.74 138.98,44.41 138.98,34.63 v2(138.22,33.87)
  BOTTOM w0.076: v2(124.01,67.1) 123.11,68 123.11,71.9 122.98,72.03 122.98,73.58 122.89,73.67 122.89,74.21 122.62,74.48 UC1.BA29
  BOTTOM w0.102: JDIMM1.224 135.87,31.77 137.97,33.87 v2(138.22,33.87)
DDR_A_D55: length 52.8
  IN1 w0.076: 125.53,66.91 124.4,66.91 v2(124.01,66.51)
  IN1 w0.127: 125.53,66.91 126.56,66.91 128.97,64.49 128.97,59.01 137.31,50.68 137.31,45.6 138.63,44.27 138.63,35.27 138.5,35.14 v2(138.22,35.14)
  BOTTOM w0.076: v2(124.01,66.51) 122.94,67.58 122.94,71.84 122.82,71.96 122.82,73.51 122.62,73.71 UC1.BB29
  BOTTOM w0.102: v2(138.22,35.14) 137.72,35.64 137.72,36.8 136.82,37.7 136.56,37.7 136.12,38.14 JDIMM1.225
DDR_A_D56: length 57.5
  IN1 w0.076: v2(123.98,69.51) 123.98,68.8 124.21,68.57 125.53,68.57
  IN1 w0.127: 125.53,68.57 127.25,68.57 131.57,64.26 131.57,58.78 138.97,51.37 138.97,49.14 139.1,49.01 139.63,49.01 139.76,48.89 139.76,48.63 139.63,48.51 139.1,48.51 138.97,48.38 138.97,48.12 139.1,48 140.17,48 140.3,47.87 140.3,47.62 140.17,47.49 139.1,47.49 138.97,47.36 138.97,47.05 139.1,46.93 140.1,46.93 140.23,46.8 140.23,46.48 140.1,46.35 139.5,46.35 139.38,46.23 139.38,45.88 139.49,45.77 140.15,45.77 140.3,45.62 140.3,41.75 140.42,41.63 141.09,41.63 141.22,41.5 141.22,37.04 141.09,36.92 v2(140.64,36.92)
  BOTTOM w0.076: v2(123.98,69.51) 123.98,69.53 124.35,69.91 124.35,72.09 123.81,72.64 123.81,73.79 123.92,73.9 123.92,74.16 123.88,74.25 123.88,74.26 123.88,74.51 123.92,74.6 123.92,74.81 123.89,74.89 123.89,74.89 123.85,74.99 123.85,75.25 UC1.AY27
  BOTTOM w0.102: v2(140.64,36.92) 140.04,36.92 139.12,37.83 JDIMM1.237
DDR_A_D57: length 58.4
  IN1 w0.076: 125.53,68.23 124.03,68.23 v2(123.98,68.27)
  IN1 w0.127: v2(140.64,35.65) 140.14,35.65 139.96,35.83 139.96,38.5 140.08,38.62 140.6,38.62 140.73,38.75 140.73,39 140.6,39.13 140.08,39.13 139.96,39.26 139.96,39.54 140.08,39.67 140.65,39.67 140.77,39.8 140.77,40.05 140.65,40.18 140.08,40.18 139.96,40.31 139.96,44.82 138.63,46.15 138.63,51.23 130.3,59.56 130.3,61.33 130.42,61.45 130.99,61.45 131.12,61.58 131.12,61.83 130.99,61.96 130.42,61.96 130.3,62.09 130.3,65.04 127.11,68.23 125.53,68.23
  BOTTOM w0.076: v2(123.98,68.27) 123.45,68.81 123.45,72.28 123.31,72.42 123.31,73.74 123.22,73.83 123.22,74.74 123.43,74.95 123.43,75.49 123.75,75.82 UC1.AW27
  BOTTOM w0.102: JDIMM1.233 138.12,37.95 140.42,35.65 v2(140.64,35.65)
DDR_A_D58: length 57.2
  IN1 w0.127: v2(125.6,69.47) 125.82,69.26 127.54,69.26 132.28,64.52 132.28,59.04 140.98,50.33 140.98,44.54 141.11,44.41 141.8,44.41 141.93,44.28 141.93,44.03 141.8,43.9 141.11,43.9 140.98,43.77 140.98,43.52 141.11,43.39 141.8,43.39 141.93,43.27 141.93,36.66 141.4,36.13 141.4,33.87 v2(140.64,33.11)
  BOTTOM w0.076: v2(125.6,69.47) 126.28,69.47 126.36,69.55 126.36,71.99 125.42,72.93 125.42,74.18 125.3,74.43 125.25,74.54 125.25,74.88 UC1.AY25
  BOTTOM w0.102: v2(140.64,33.11) 139.97,33.11 139.18,32.31 139.18,32.06 138.87,31.76 JDIMM1.236
DDR_A_D59: length 58.5
  IN1 w0.127: v2(140.64,34.38) 141.06,34.8 141.06,36.28 141.56,36.78 141.56,41.84 141.43,41.97 140.77,41.97 140.64,42.1 140.64,42.41 140.77,42.54 141.46,42.54 141.59,42.67 141.59,42.92 141.46,43.05 140.77,43.05 140.64,43.18 140.64,50.19 131.93,58.89 131.93,64.37 127.39,68.91 124.99,68.91 v2(124.83,69.07)
  BOTTOM w0.076: UC1.AW25 124.49,76.01 124.28,75.96 124.09,75.77 124.09,75.24 124.05,75.19 124.05,74.94 124.09,74.81 124.09,74.58 124.09,74.57 124.08,74.57 124.08,74.57 124.05,74.48 124.05,74.28 124.08,74.19 124.08,73.83 123.98,73.73 123.98,72.7 124.52,72.16 124.52,69.38 v2(124.83,69.07)
  BOTTOM w0.102: JDIMM1.232 137.87,31.77 138.03,31.93 138.49,31.93 138.5,31.94 138.51,31.94 138.7,32.13 138.73,32.16 138.8,32.23 138.8,32.54 v2(140.64,34.38)
DDR_A_D60: length 55.9
  IN1 w0.127: v2(123.99,71.33) 125.52,71.33 125.6,71.25 125.82,71.03 128.48,71.03 134.12,65.39 134.12,59.79 143.86,50.05 143.86,38.6 143.99,38.47 144.13,38.47 144.26,38.35 144.26,38.09 144.13,37.97 143.99,37.97 143.86,37.84 143.86,37.58 143.99,37.46 144.12,37.46 144.25,37.33 144.25,37.02 144.12,36.89 143.94,36.89 143.82,36.76 143.82,36.51 143.94,36.38 144.13,36.38 144.26,36.25 144.26,35.61 144.08,35.43 143.58,35.43 143.42,35.59 v2(143.42,35.65)
  BOTTOM w0.076: v2(123.99,71.33) 123.99,72.22 123.64,72.57 123.64,74.05 UC1.BB27
  BOTTOM w0.102: JDIMM1.245 141.12,37.91 141.16,37.91 v2(143.42,35.65)
DDR_A_D61: length 56.4
  IN1 w0.127: v2(123.98,70.12) 124.56,70.69 125.67,70.69 125.67,70.69 128.13,70.69 133.78,65.05 133.78,59.64 142.42,51 142.42,48.7 142.55,48.57 143.07,48.57 143.2,48.45 143.2,48.2 143.07,48.07 142.55,48.07 142.42,47.94 142.42,47.62 142.55,47.49 143.19,47.49 143.31,47.37 143.31,47.11 143.19,46.99 142.55,46.99 142.42,46.86 142.42,46.55 142.55,46.42 143.24,46.42 143.36,46.29 143.36,46.04 143.24,45.91 142.84,45.91 142.71,45.78 142.71,45.53 142.84,45.4 143.24,45.4 143.36,45.28 143.36,36.98 v2(143.42,36.92)
  BOTTOM w0.076: v2(123.98,70.12) 123.61,70.49 123.61,72.35 123.48,72.49 123.48,73.81 123.39,73.9 123.39,74.22 123.65,74.48 UC1.BA27
  BOTTOM w0.102: JDIMM1.249 142.12,37.88 143.09,36.92 v2(143.42,36.92)
DDR_A_D62: length 56.7
  IN1 w0.127: v2(143.42,34.38) 143.51,34.29 144.39,34.29 144.6,34.51 144.6,38.85 144.48,38.98 144.33,38.98 144.2,39.11 144.2,39.36 144.33,39.49 144.48,39.49 144.6,39.61 144.6,39.87 144.48,40 144.33,40 144.2,40.12 144.2,40.38 144.33,40.5 144.48,40.5 144.6,40.63 144.6,40.88 144.48,41.01 144.33,41.01 144.2,41.14 144.2,50.19 134.46,59.93 134.46,65.54 128.54,71.45 v2(125.99,71.45)
  BOTTOM w0.076: v2(125.99,71.45) 125.99,72.13 125.25,72.86 125.25,74.14 125.13,74.41 124.98,74.56 UC1.BA25
  BOTTOM w0.102: v2(143.42,34.38) 143.39,34.38 142.8,33.79 142.8,33.02 141.37,31.6 JDIMM1.246
DDR_A_D63: length 55.6
  IN1 w0.076: 125.53,71.87 v2(125.53,71.88)
  IN1 w0.127: 125.53,71.87 128.61,71.87 134.8,65.68 134.8,60.07 144.54,50.33 144.54,41.43 145.04,40.94 145.04,33.24 144.63,32.83 143.7,32.83 v2(143.42,33.11)
  BOTTOM w0.076: v2(125.53,71.88) 125.53,72.07 125.09,72.51 125.09,73.94 UC1.BB25
  BOTTOM w0.102: v2(143.42,33.11) 142.37,32.06 JDIMM1.250
DDR_A_DQS0: length 71.4
  IN1 w0.102: v2(80.63,33.61) 80.5,33.73 80.44,33.73 80.44,33.73 80.12,33.73 79.81,34.04 79.81,36.22 78.99,37.04 78.99,50.49 80.35,51.85 80.35,74.42 86.4,80.47 v2(91.11,80.47)
  BOTTOM w0.076: 95.15,80.37 95.17,80.37 95.28,80.26 95.76,80.26 96.2,80.69 97.44,80.69 97.52,80.61 97.94,80.61 98.05,80.67 98.27,80.67 98.38,80.61 98.59,80.61 98.67,80.65 98.96,80.65 99.23,80.52 99.23,80.35 99.27,80.31 UC1.AM69
  BOTTOM w0.099: v2(91.11,80.47) 91.11,80.49 91.24,80.62 91.24,81.07 91.46,81.28 92.39,81.28 93.24,80.42 95.1,80.42 95.15,80.37 ; JDIMM1.13 81.12,35.62 81.4,35.35 81.4,34.03 81.16,33.79 80.81,33.79 v2(80.63,33.61)
DDR_A_DQS1: length 62.1
  IN1 w0.076: 93.42,75.67 93.46,75.67 93.48,75.69 94.07,75.69 95.23,76.85 95.34,76.85 95.41,76.78 v2(95.34,76.43)
  IN1 w0.102: v2(85.52,33.71) 85.52,33.59 85.39,33.47 84.96,33.47 84.85,33.57 84.85,34.42 85.29,34.86 85.29,35.48 85.06,35.71 85.06,37.63 85.29,37.87 85.29,39.31 85.08,39.52 84.8,39.52 84.7,39.62 84.7,41.91 84.8,42.01 84.85,42.01 85.07,42.22 85.07,42.69 84.85,42.9 84.8,42.9 84.7,43 84.7,50.09 85.65,51.05 85.65,73.62 87.71,75.67 93.42,75.67
  BOTTOM w0.076: UC1.AT70 98.9,77.86 99,77.76 99,77.67 98.94,77.6 98.92,77.59 98.7,77.59 98.62,77.63 98.34,77.63 98.23,77.58 98.09,77.58 97.97,77.63 97.94,77.63 97.94,77.63 97.48,77.63 97.31,77.46 95.97,77.46 95.48,76.97 95.48,76.58 v2(95.34,76.43)
  BOTTOM w0.099: JDIMM1.34 86.37,31.66 86.22,31.81 86.22,33.21 85.97,33.46 85.77,33.46 v2(85.52,33.71)
DDR_A_DQS2: length 54.6
  IN1 w0.076: 94.44,67.42 94.45,67.43 94.47,67.43 94.82,67.78 94.82,68.1 95.94,69.21 96.56,69.21 v2(96.7,69.34)
  IN1 w0.102: 94.44,67.42 90.61,63.58 90.61,50.76 90.93,50.45 90.93,42.19 89.69,40.96 89.69,37.02 89.94,36.77 89.94,36.4 89.69,36.15 89.69,34.76 89.91,34.54 90.18,34.54 v2(90.38,34.35)
  BOTTOM w0.076: 101.68,73.46 101.68,73.47 101.69,73.48 101.69,73.69 101.86,73.86 101.86,74.16 101.81,74.27 101.81,74.49 101.86,74.6 101.86,74.81 101.82,74.89 101.82,75.18 101.91,75.36 102,75.45 UC1.AY64
  BOTTOM w0.099: JDIMM1.55 91.62,37.97 91.43,37.77 91.43,37.34 91.28,37.19 91.28,34.56 91.07,34.35 v2(90.38,34.35)
  BOTTOM w0.102: 101.68,73.46 101.68,73.04 100.57,71.92 98.61,71.92 97.63,70.94 97.63,70.14 96.83,69.34 v2(96.7,69.34)
DDR_A_DQS3: length 51.9
  IN1 w0.076: 97.77,64.9 97.78,64.92 97.8,64.92 98.45,65.57 98.56,65.57 101.51,68.53 101.51,69.75 101.77,70.01 102.06,70.01 v2(102.3,70.25)
  IN1 w0.102: 97.77,64.9 95.05,62.19 95.05,52.17 95.62,51.6 95.62,40.32 95.79,40.14 95.79,34.82 95.69,34.71 95.6,34.71 v2(95.38,34.93)
  BOTTOM w0.076: 104.65,72.89 104.65,72.9 104.66,72.91 104.66,72.96 104.68,72.97 104.68,73.04 105,73.37 105,73.62 104.89,73.73 104.89,73.74 104.84,73.78 104.84,74.2 104.85,74.23 104.89,74.31 104.89,74.43 104.86,74.51 104.84,74.57 104.84,74.84 104.88,74.92 104.88,75.14 104.82,75.27 104.71,75.38 104.64,75.38 104.61,75.34 104.61,75.24 UC1.BA60
  BOTTOM w0.099: v2(95.38,34.93) 95.64,34.67 96.13,34.67 96.7,34.1 96.7,31.89 96.87,31.72 JDIMM1.76
  BOTTOM w0.102: 104.65,72.89 104.65,72.72 102.82,70.89 102.82,70.12 102.72,70.02 102.53,70.02 v2(102.3,70.25)
DDR_A_DQS4: length 51.7
  IN1 w0.076: v2(117.16,70.1) 117.4,70.34 117.51,70.34 117.6,70.25 117.6,65.24 118.45,64.4 118.45,62.71 118.71,62.45 118.71,62.26 118.7,62.25 118.7,62.23
  IN1 w0.102: 118.7,62.23 118.7,60.89 118.81,60.77 118.81,54.78 119.01,54.59 119.01,54.45 118.88,54.32 118.88,54.02 119.21,53.69 119.51,53.69 119.64,53.82 119.78,53.82 119.99,53.6 119.99,53.46 119.87,53.33 119.87,53.03 120.2,52.7 120.5,52.7 120.62,52.83 120.77,52.83 120.98,52.61 120.98,52.47 120.86,52.34 120.86,52.04 121.18,51.71 121.49,51.71 121.61,51.84 121.76,51.84 122,51.59 122,51.45 121.88,51.33 121.88,51.02 122.21,50.7 122.51,50.7 122.63,50.82 122.78,50.82 122.99,50.6 122.99,50.46 122.96,50.43 122.96,50.13 123.29,49.8 123.59,49.8 123.62,49.83 123.77,49.83 123.98,49.61 123.98,49.47 123.95,49.44 123.95,49.14 124.28,48.81 124.58,48.81 124.61,48.84 124.75,48.84 125.44,48.16 125.44,38.19 125.65,37.97 126.09,37.97 126.18,37.89 126.18,36.68 126.07,36.58 125.83,36.58 v2(125.58,36.83)
  BOTTOM w0.076: 116.6,72.82 116.63,72.84 116.63,72.95 116.63,72.95 116.63,73 116.49,73.14 116.49,73.65 116.58,73.75 116.58,74.16 116.53,74.27 116.53,74.49 116.58,74.6 116.58,75.26 116.59,75.28 116.68,75.42 UC1.AY38
  BOTTOM w0.099: v2(125.58,36.83) 125.32,36.57 124.63,36.57 124.53,36.67 124.53,37.7 124.48,37.76 124.48,37.93 124.62,38.08 JDIMM1.179
  BOTTOM w0.102: v2(117.16,70.1) 116.93,70.33 116.71,70.33 116.5,70.54 116.5,72.07 116.6,72.17 116.6,72.82
DDR_A_DQS5: length 52.9
  IN1 w0.076: v2(120.58,68.96) 120.58,69.03 120.38,69.22 120.27,69.22 120.19,69.14 120.19,65.63 122.55,63.28 122.55,63.14 122.78,62.91
  IN1 w0.102: v2(131.24,33.65) 131.52,33.93 131.63,33.93 131.84,34.14 131.84,35.17 131.23,35.79 131.23,49.56 123.36,57.42 123.36,62.32 122.78,62.91
  BOTTOM w0.076: 119.78,72.41 119.78,72.62 119.79,72.62 119.79,72.89 119.57,73.11 119.57,74.2 119.62,74.31 119.62,74.44 119.57,74.57 119.57,74.84 119.6,74.92 119.6,75.14 119.57,75.2 119.52,75.28 119.48,75.3 119.38,75.3 119.31,75.23 119.31,75.06 UC1.BA34
  BOTTOM w0.099: v2(131.24,33.65) 130.98,33.91 130.63,33.91 130.42,33.71 130.42,33.02 129.73,32.33 129.73,31.87 129.87,31.73 JDIMM1.200
  BOTTOM w0.102: v2(120.58,68.96) 120.35,69.19 120.13,69.19 119.78,69.53 119.78,72.41
DDR_A_DQS6: length 54.3
  IN1 w0.076: 125.53,65.75 125.52,65.75 125.51,65.76 125.46,65.76 125.45,65.78 123.76,65.78 123.15,66.39 123.15,69.42 122.96,69.6 122.72,69.6 122.33,69.21 v2(122.33,69.12)
  IN1 w0.102: v2(136.81,36.09) 137.03,35.87 137.31,35.87 137.41,35.97 137.41,43.86 135.37,45.9 135.37,50.98 127.82,58.53 127.82,64.01 126.08,65.75 125.53,65.75
  BOTTOM w0.076: UC1.AY30 121.66,75.42 121.57,75.28 121.53,75.17 121.53,74.89 121.56,74.81 121.56,74.6 121.51,74.49 121.51,74.27 121.56,74.16 121.56,73.55 121.53,73.52 121.53,72.87 121.53,72.87 121.53,72.6 121.59,72.54
  BOTTOM w0.099: JDIMM1.221 135.12,38.24 134.99,38.11 134.99,37.72 136.01,36.7 136.01,35.92 136.18,35.75 136.46,35.75 v2(136.81,36.09)
  BOTTOM w0.102: 121.59,72.54 121.7,72.43 121.7,69.52 121.88,69.34 122.11,69.34 v2(122.33,69.12)
DDR_A_DQS7: length 57.5
  IN1 w0.102: v2(141.97,34.63) 142.2,34.86 142.49,34.86 142.74,35.12 142.74,44.62 141.8,45.56 141.8,50.67 133.09,59.37 133.09,64.85 127.87,70.07 125.13,70.07 v2(124.9,70.3)
  BOTTOM w0.076: UC1.BA26 124.29,75.06 124.29,75.23 124.36,75.3 124.46,75.3 124.5,75.28 124.56,75.2 124.58,75.14 124.58,74.92 124.55,74.84 124.55,74.57 124.6,74.44 124.6,74.31 124.55,74.2 124.55,73.76 124.76,73.55 124.76,73.2 124.71,73.15 124.71,73.1 124.69,73.08 124.69,73.07
  BOTTOM w0.099: JDIMM1.242 140.37,31.58 140.26,31.69 140.26,32.13 140.46,32.32 140.98,32.32 141.42,32.76 141.42,34.76 141.52,34.86 141.74,34.86 v2(141.97,34.63)
  BOTTOM w0.102: 124.69,73.07 124.69,72.35 124.96,72.08 124.96,71.15 125.53,70.57 125.53,70.17 125.43,70.07 125.13,70.07 v2(124.9,70.3)
DDR_A_DQS#0: length 71.4
  IN1 w0.102: v2(80.63,34.29) 80.63,34.18 80.36,33.92 80.2,33.92 80,34.11 80,36.32 79.18,37.15 79.18,50.41 80.54,51.77 80.54,74.34 86.48,80.28 90.73,80.28 90.94,80.06 91.29,80.06 v2(91.7,80.47)
  BOTTOM w0.076: UC1.AM70 98.98,80.21 99.06,80.3 99.06,80.41 98.92,80.48 98.7,80.48 98.62,80.45 98.34,80.45 98.23,80.5 98.09,80.5 97.98,80.45 97.45,80.45 97.37,80.53 96.27,80.53 95.83,80.09 95.21,80.09 95.11,80.19 95.08,80.19 95.04,80.23 95.03,80.23 95.02,80.24
  BOTTOM w0.099: v2(80.63,34.29) 80.63,34.14 80.78,33.98 81.08,33.98 81.21,34.11 81.21,35.27 80.94,35.54 80.94,37.85 80.88,37.91 80.7,37.91 80.62,37.99 JDIMM1.11 ; 95.02,80.24 93.16,80.24 92.31,81.09 91.53,81.09 91.43,80.99 91.43,80.75 91.7,80.49 v2(91.7,80.47)
DDR_A_DQS#1: length 62.1
  IN1 w0.076: v2(95.86,76.8) 95.57,76.85 95.41,77.01 95.17,77.01 94,75.85 93.42,75.85 93.41,75.86 93.27,75.86
  IN1 w0.102: v2(85.52,33.08) 85.32,33.28 84.88,33.28 84.66,33.49 84.66,34.5 85.1,34.94 85.1,35.4 84.87,35.63 84.87,37.71 85.1,37.94 85.1,39.23 85,39.33 84.73,39.33 84.51,39.54 84.51,41.99 84.73,42.2 84.77,42.2 84.88,42.3 84.88,42.61 84.77,42.71 84.73,42.71 84.51,42.92 84.51,50.17 85.46,51.13 85.46,73.7 87.63,75.86 93.27,75.86
  BOTTOM w0.076: UC1.AT69 99.25,77.86 99.17,77.77 99.17,77.6 99.03,77.47 98.96,77.43 98.67,77.43 98.59,77.46 98.38,77.46 98.27,77.41 98.05,77.41 97.94,77.47 97.87,77.47 97.87,77.47 97.55,77.47 97.38,77.29 96.04,77.29 95.8,77.05 95.8,76.86 v2(95.86,76.8)
  BOTTOM w0.099: v2(85.52,33.08) 85.72,33.28 85.89,33.28 86.04,33.14 86.04,31.8 85.87,31.64 JDIMM1.32
DDR_A_DQS#2: length 54.6
  IN1 w0.076: 94.57,67.28 94.59,67.29 94.59,67.31 94.99,67.71 94.99,68.03 96.01,69.05 96.32,69.05 v2(96.67,68.67)
  IN1 w0.102: v2(90.38,34.98) 90.13,34.73 89.99,34.73 89.88,34.84 89.88,36.07 90.13,36.32 90.13,36.85 89.88,37.1 89.88,40.88 91.12,42.11 91.12,50.52 90.8,50.84 90.8,63.5 94.57,67.28
  BOTTOM w0.076: UC1.BA64 102.26,75.24 102.19,75.31 102.09,75.31 102.05,75.27 101.99,75.14 101.99,74.92 102.02,74.84 102.02,74.57 101.97,74.44 101.97,74.33 102.02,74.19 102.02,73.78 101.87,73.63 101.87,73.46
  BOTTOM w0.099: JDIMM1.53 91.12,37.97 91.25,37.84 91.25,37.42 91.09,37.26 91.09,34.64 91,34.54 90.82,34.54 v2(90.38,34.98)
  BOTTOM w0.102: 101.87,73.46 101.87,72.96 101.87,72.96 100.65,71.73 98.69,71.73 97.82,70.86 97.82,70.06 97.08,69.32 97.08,69.19 96.67,68.78 v2(96.67,68.67)
DDR_A_DQS#3: length 51.9
  IN1 w0.076: 97.9,64.77 97.92,64.78 97.92,64.8 98.52,65.4 98.62,65.4 101.68,68.46 101.68,69.68 101.84,69.84 102.06,69.84 v2(102.3,69.6)
  IN1 w0.102: v2(95.38,34.29) 95.62,34.52 95.68,34.52 95.68,34.52 95.77,34.52 95.98,34.74 95.98,40.22 95.81,40.4 95.81,51.68 95.24,52.25 95.24,62.11 97.9,64.77
  BOTTOM w0.076: UC1.AY60 104.82,75.49 104.95,75.36 105.04,75.18 105.04,74.89 105.01,74.81 105.01,74.6 105.03,74.56 105.04,74.5 105.06,74.42 105.06,74.28 105.01,74.16 105.01,73.85 105.17,73.69 105.17,73.3 104.84,72.97 104.84,72.89
  BOTTOM w0.099: JDIMM1.74 96.37,31.75 96.51,31.89 96.52,31.89 96.52,34.02 96.05,34.48 95.57,34.48 v2(95.38,34.29)
  BOTTOM w0.102: v2(102.3,69.6) 102.53,69.83 102.8,69.83 103.01,70.04 103.01,70.81 104.84,72.64 104.84,72.89
DDR_A_DQS#4: length 51.6
  IN1 w0.076: v2(117.16,70.74) 117.39,70.51 117.58,70.51 117.77,70.32 117.77,65.31 118.61,64.47 118.61,62.78 118.88,62.52 118.88,62.26 118.89,62.25 118.89,62.23
  IN1 w0.102: v2(125.58,36.19) 125.77,36.39 126.15,36.39 126.37,36.6 126.37,37.97 126.17,38.16 125.73,38.16 125.63,38.27 125.63,48.23 124.83,49.03 124.53,49.03 124.5,49 124.36,49 124.14,49.22 124.14,49.36 124.17,49.39 124.17,49.69 123.84,50.02 123.54,50.02 123.52,49.99 123.37,49.99 123.15,50.21 123.15,50.35 123.18,50.38 123.18,50.68 122.86,51.01 122.55,51.01 122.43,50.89 122.29,50.89 122.07,51.1 122.07,51.25 122.19,51.37 122.19,51.67 121.84,52.03 121.53,52.03 121.41,51.9 121.26,51.9 121.05,52.12 121.05,52.26 121.17,52.39 121.17,52.69 120.85,53.02 120.55,53.02 120.42,52.89 120.27,52.89 120.06,53.11 120.06,53.25 120.19,53.38 120.19,53.68 119.86,54.01 119.56,54.01 119.43,53.88 119.29,53.88 119.07,54.1 119.07,54.24 119.2,54.37 119.2,54.67 119.01,54.86 119.01,60.85 118.89,60.97 118.89,62.23
  BOTTOM w0.076: 116.79,72.77 116.8,72.77 116.8,72.95 116.79,72.95 116.79,73.06 116.65,73.21 116.65,73.58 116.75,73.68 116.75,74.19 116.69,74.33 116.69,74.44 116.75,74.57 116.75,74.8 UC1.BA38
  BOTTOM w0.099: v2(125.58,36.19) 125.38,36.39 124.55,36.39 124.35,36.59 124.35,37.62 124.29,37.68 124.29,37.96 124.12,38.12 JDIMM1.177
  BOTTOM w0.102: v2(117.16,70.74) 116.93,70.52 116.79,70.52 116.69,70.62 116.69,71.98 116.79,72.09 116.79,72.77 116.79,72.77
DDR_A_DQS#5: length 52.8
  IN1 w0.076: v2(120.58,69.61) 120.58,69.56 120.41,69.39 120.2,69.39 120.03,69.21 120.03,65.56 122.38,63.21 122.38,63.07 122.6,62.85 122.6,62.83 122.64,62.79 122.64,62.79 122.64,62.78 122.64,62.77
  IN1 w0.102: 122.64,62.77 123.17,62.25 123.17,57.34 131.03,49.48 131.03,35.71 131.65,35.09 131.65,34.22 131.55,34.12 131.41,34.12 v2(131.24,34.29)
  BOTTOM w0.076: 119.98,72.41 119.98,72.46 119.95,72.48 119.95,72.62 119.95,72.62 119.95,72.96 119.73,73.18 119.73,74.16 119.78,74.27 119.78,74.49 119.73,74.6 119.73,74.81 119.77,74.89 119.77,75.17 119.72,75.28 119.64,75.42 119.64,75.42 119.43,75.62 UC1.AY34
  BOTTOM w0.099: v2(131.24,34.29) 131.06,34.1 130.55,34.1 130.23,33.78 130.23,33.1 129.54,32.41 129.54,31.82 129.37,31.65 JDIMM1.198
  BOTTOM w0.102: 119.98,72.41 119.98,69.61 120.21,69.38 120.35,69.38 v2(120.58,69.61)
DDR_A_DQS#6: length 54.2
  IN1 w0.076: v2(122.33,69.77) 123.03,69.77 123.31,69.49 123.31,66.46 123.83,65.94 125.53,65.94
  IN1 w0.102: v2(136.81,35.46) 137.03,35.68 137.38,35.68 137.6,35.89 137.6,43.94 135.57,45.97 135.57,51.06 128.01,58.61 128.01,64.09 126.16,65.94 125.53,65.94
  BOTTOM w0.076: 121.73,72.68 121.7,72.71 121.7,73.45 121.73,73.48 121.73,74.2 121.68,74.31 121.68,74.45 121.73,74.56 121.73,74.84 121.69,74.92 121.69,75.04 121.76,75.1 121.89,75.1 UC1.BA30
  BOTTOM w0.099: v2(136.81,35.46) 136.7,35.56 136.1,35.56 135.82,35.84 135.82,36.63 134.8,37.64 134.8,38.04 134.62,38.22 JDIMM1.219
  BOTTOM w0.102: v2(122.33,69.77) 122.11,69.54 121.96,69.54 121.9,69.6 121.9,72.51 121.73,72.68
DDR_A_DQS#7: length 57.5
  IN1 w0.102: v2(124.9,69.65) 124.98,69.73 124.98,69.73 125.13,69.88 127.79,69.88 132.9,64.77 132.9,59.29 141.61,50.59 141.61,45.48 142.55,44.54 142.55,35.19 142.41,35.05 142.19,35.05 v2(141.97,35.27)
  BOTTOM w0.076: UC1.AY26 124.41,75.62 124.62,75.42 124.7,75.28 124.75,75.17 124.75,74.89 124.71,74.81 124.71,74.6 124.76,74.49 124.76,74.27 124.71,74.16 124.71,73.83 124.92,73.62 124.92,73.11 124.88,73.07
  BOTTOM w0.099: JDIMM1.240 139.87,31.56 140.07,31.76 140.07,32.21 140.38,32.51 140.9,32.51 141.23,32.84 141.23,34.84 141.45,35.05 141.76,35.05 v2(141.97,35.27)
  BOTTOM w0.102: 124.88,73.07 124.88,72.43 125.15,72.16 125.15,71.23 125.72,70.65 125.72,70.09 125.51,69.88 125.14,69.88 v2(124.9,69.65)
DDR_A_MA0: length 47.4
  IN1 w0.076: 110.91,62.23 110.91,65.33 111.15,65.57 111.15,72.3 110.71,72.74 v2(110.71,73.07)
  IN1 w0.216: 110.91,62.23 110.91,48.77 115.13,44.55 115.13,37.85 114.71,37.43 114.71,33.19 114.33,32.81 v2(114.21,32.81)
  BOTTOM w0.076: UC1.AY50 110.23,75.14 110.77,74.59 110.77,73.13 v2(110.71,73.07)
  BOTTOM w0.163: v2(114.21,32.81) 113.87,32.48 JDIMM1.144
DDR_A_MA1: length 47.7
  IN1 w0.076: v2(108.28,70) 108.77,69.5 108.77,67.78 108.15,67.16 108.15,63.71 107.52,63.07 107.52,62.23
  IN1 w0.216: v2(111.11,37.52) 111.08,37.55 111.08,39.74 110.65,40.17 110.65,40.56 111.08,40.99 111.08,41.57 110.87,41.79 110.45,41.79 110.23,42 110.23,42.44 110.45,42.65 110.87,42.65 111.08,42.87 111.08,43.27 110.2,44.15 109.9,44.15 108.94,43.19 108.57,43.19 108.3,43.46 108.3,43.77 109.29,44.76 109.29,45.06 108.95,45.4 108.64,45.4 108.27,45.03 107.83,45.03 107.52,45.34 107.52,45.65 108.15,46.28 108.15,46.59 107.52,47.22 107.52,62.23
  BOTTOM w0.076: v2(108.28,70) 108.56,70 109.76,71.2 109.76,72.89 110.31,73.44 110.31,73.98 UC1.BB50
  BOTTOM w0.163: v2(111.11,37.52) 111.12,37.54 JDIMM1.133
DDR_A_MA2: length 49.8
  IN1 w0.076: v2(108.74,67.23) 108.56,67.23 108.32,66.99 108.32,63.5 108.01,63.19 108.01,62.23
  IN1 w0.216: v2(111.11,34.98) 111.36,34.98 111.58,35.2 111.58,43.86 108.01,47.43 108.01,62.23
  BOTTOM w0.076: v2(108.74,67.23) 108.17,67.23 107.91,67.49 107.91,70.17 108.11,70.36 108.57,70.36 109.3,71.09 109.3,72.7 109.95,73.34 109.95,73.93 109.9,73.98 109.9,75.38 UC1.AY51
  BOTTOM w0.163: v2(111.11,34.98) 111.5,34.98 111.67,34.82 111.67,34.2 110.87,33.41 JDIMM1.132
DDR_A_MA3: length 50
  IN1 w0.076: 107.02,62.23 107.02,63.15 107.99,64.12 107.99,67.42 108.28,67.71 v2(108.28,68.73)
  IN1 w0.216: v2(111.11,36.25) 110.8,36.25 110.59,36.47 110.59,39.54 110.16,39.97 110.16,40.9 107.02,44.04 107.02,62.23
  BOTTOM w0.076: UC1.BA50 110.53,74.4 110.53,73.41 109.96,72.84 109.96,71.03 108.71,69.78 108.71,69.16 v2(108.28,68.73)
  BOTTOM w0.163: v2(111.11,36.25) 110.86,36.25 110.68,36.07 110.68,35.18 110.49,34.99 109.72,34.99 109.52,35.19 109.52,35.49 109.69,35.65 109.91,35.65 110.07,35.81 110.07,36.1 109.91,36.26 109.69,36.26 109.53,36.42 109.53,36.66 109.69,36.82 110.4,36.82 110.62,37.05 110.62,38.12 JDIMM1.131
DDR_A_MA4: length 48.7
  IN1 w0.076: v2(107.04,69.93) 107.48,69.49 107.48,68.1 107.63,67.95 107.63,64.77 106.03,63.18 106.03,62.23
  IN1 w0.216: 106.03,62.23 106.03,43.63 108.47,41.19 108.47,40.2 109.59,39.08 109.59,35.95 110.14,35.39 110.14,34.69 109.93,34.47 109.62,34.47 109.11,34.98 v2(109.09,34.98)
  BOTTOM w0.076: v2(107.04,69.93) 107.04,70.39 108.8,72.15 108.8,73.96 UC1.BB52
  BOTTOM w0.163: JDIMM1.128 109.87,31.84 110.04,32 110.04,34.02 v2(109.09,34.98)
DDR_A_MA5: length 50.1
  IN1 w0.076: v2(108.31,70.8) 108.28,70.8 107.9,70.42 107.9,67.95 107.82,67.87 107.82,64.45 106.53,63.16 106.53,62.23
  IN1 w0.216: 106.53,62.23 106.53,43.83 109.66,40.7 109.66,39.76 110.08,39.34 110.08,36.27 110.64,35.72 110.64,33.17 110.42,32.96 109.81,32.96 109.09,33.67 v2(109.09,33.71)
  BOTTOM w0.076: UC1.BA51 109.34,74.81 109.34,74.58 109.34,74.57 109.33,74.57 109.33,74.57 109.3,74.48 109.3,74.28 109.33,74.19 109.33,73.83 109.14,73.63 109.14,71.63 v2(108.31,70.8)
  BOTTOM w0.163: JDIMM1.126 109.37,32.04 109.59,32.26 109.59,33.34 109.53,33.4 109.23,33.71 v2(109.09,33.71)
DDR_A_MA6: length 48.6
  IN1 w0.076: 105.54,62.23 105.54,63.12 107.46,65.05 107.46,67.85 107.29,68.02 107.29,68.7 v2(106.58,69.41)
  IN1 w0.216: 105.54,62.23 105.54,60.78 105.32,60.56 104.76,60.56 104.54,60.35 104.54,59.92 104.76,59.7 105.32,59.7 105.54,59.48 105.54,59.05 105.32,58.84 104.73,58.84 104.51,58.62 104.51,58.25 104.79,57.97 105.32,57.97 105.54,57.76 105.54,57.32 105.32,57.11 104.73,57.11 104.51,56.89 104.51,56.46 104.73,56.24 105.32,56.24 105.54,56.03 105.54,55.62 105.32,55.4 104.73,55.4 104.51,55.19 104.51,54.75 104.73,54.54 105.32,54.54 105.54,54.32 105.54,43.42 107.98,40.98 107.98,39.99 109.09,38.87 v2(109.09,37.52)
  BOTTOM w0.076: UC1.BA52 108.9,74.48 108.64,74.22 108.64,72.4 108.64,72.22 106.49,70.07 106.49,69.51 v2(106.58,69.41)
  BOTTOM w0.163: v2(109.09,37.52) 109.62,38.07 JDIMM1.127
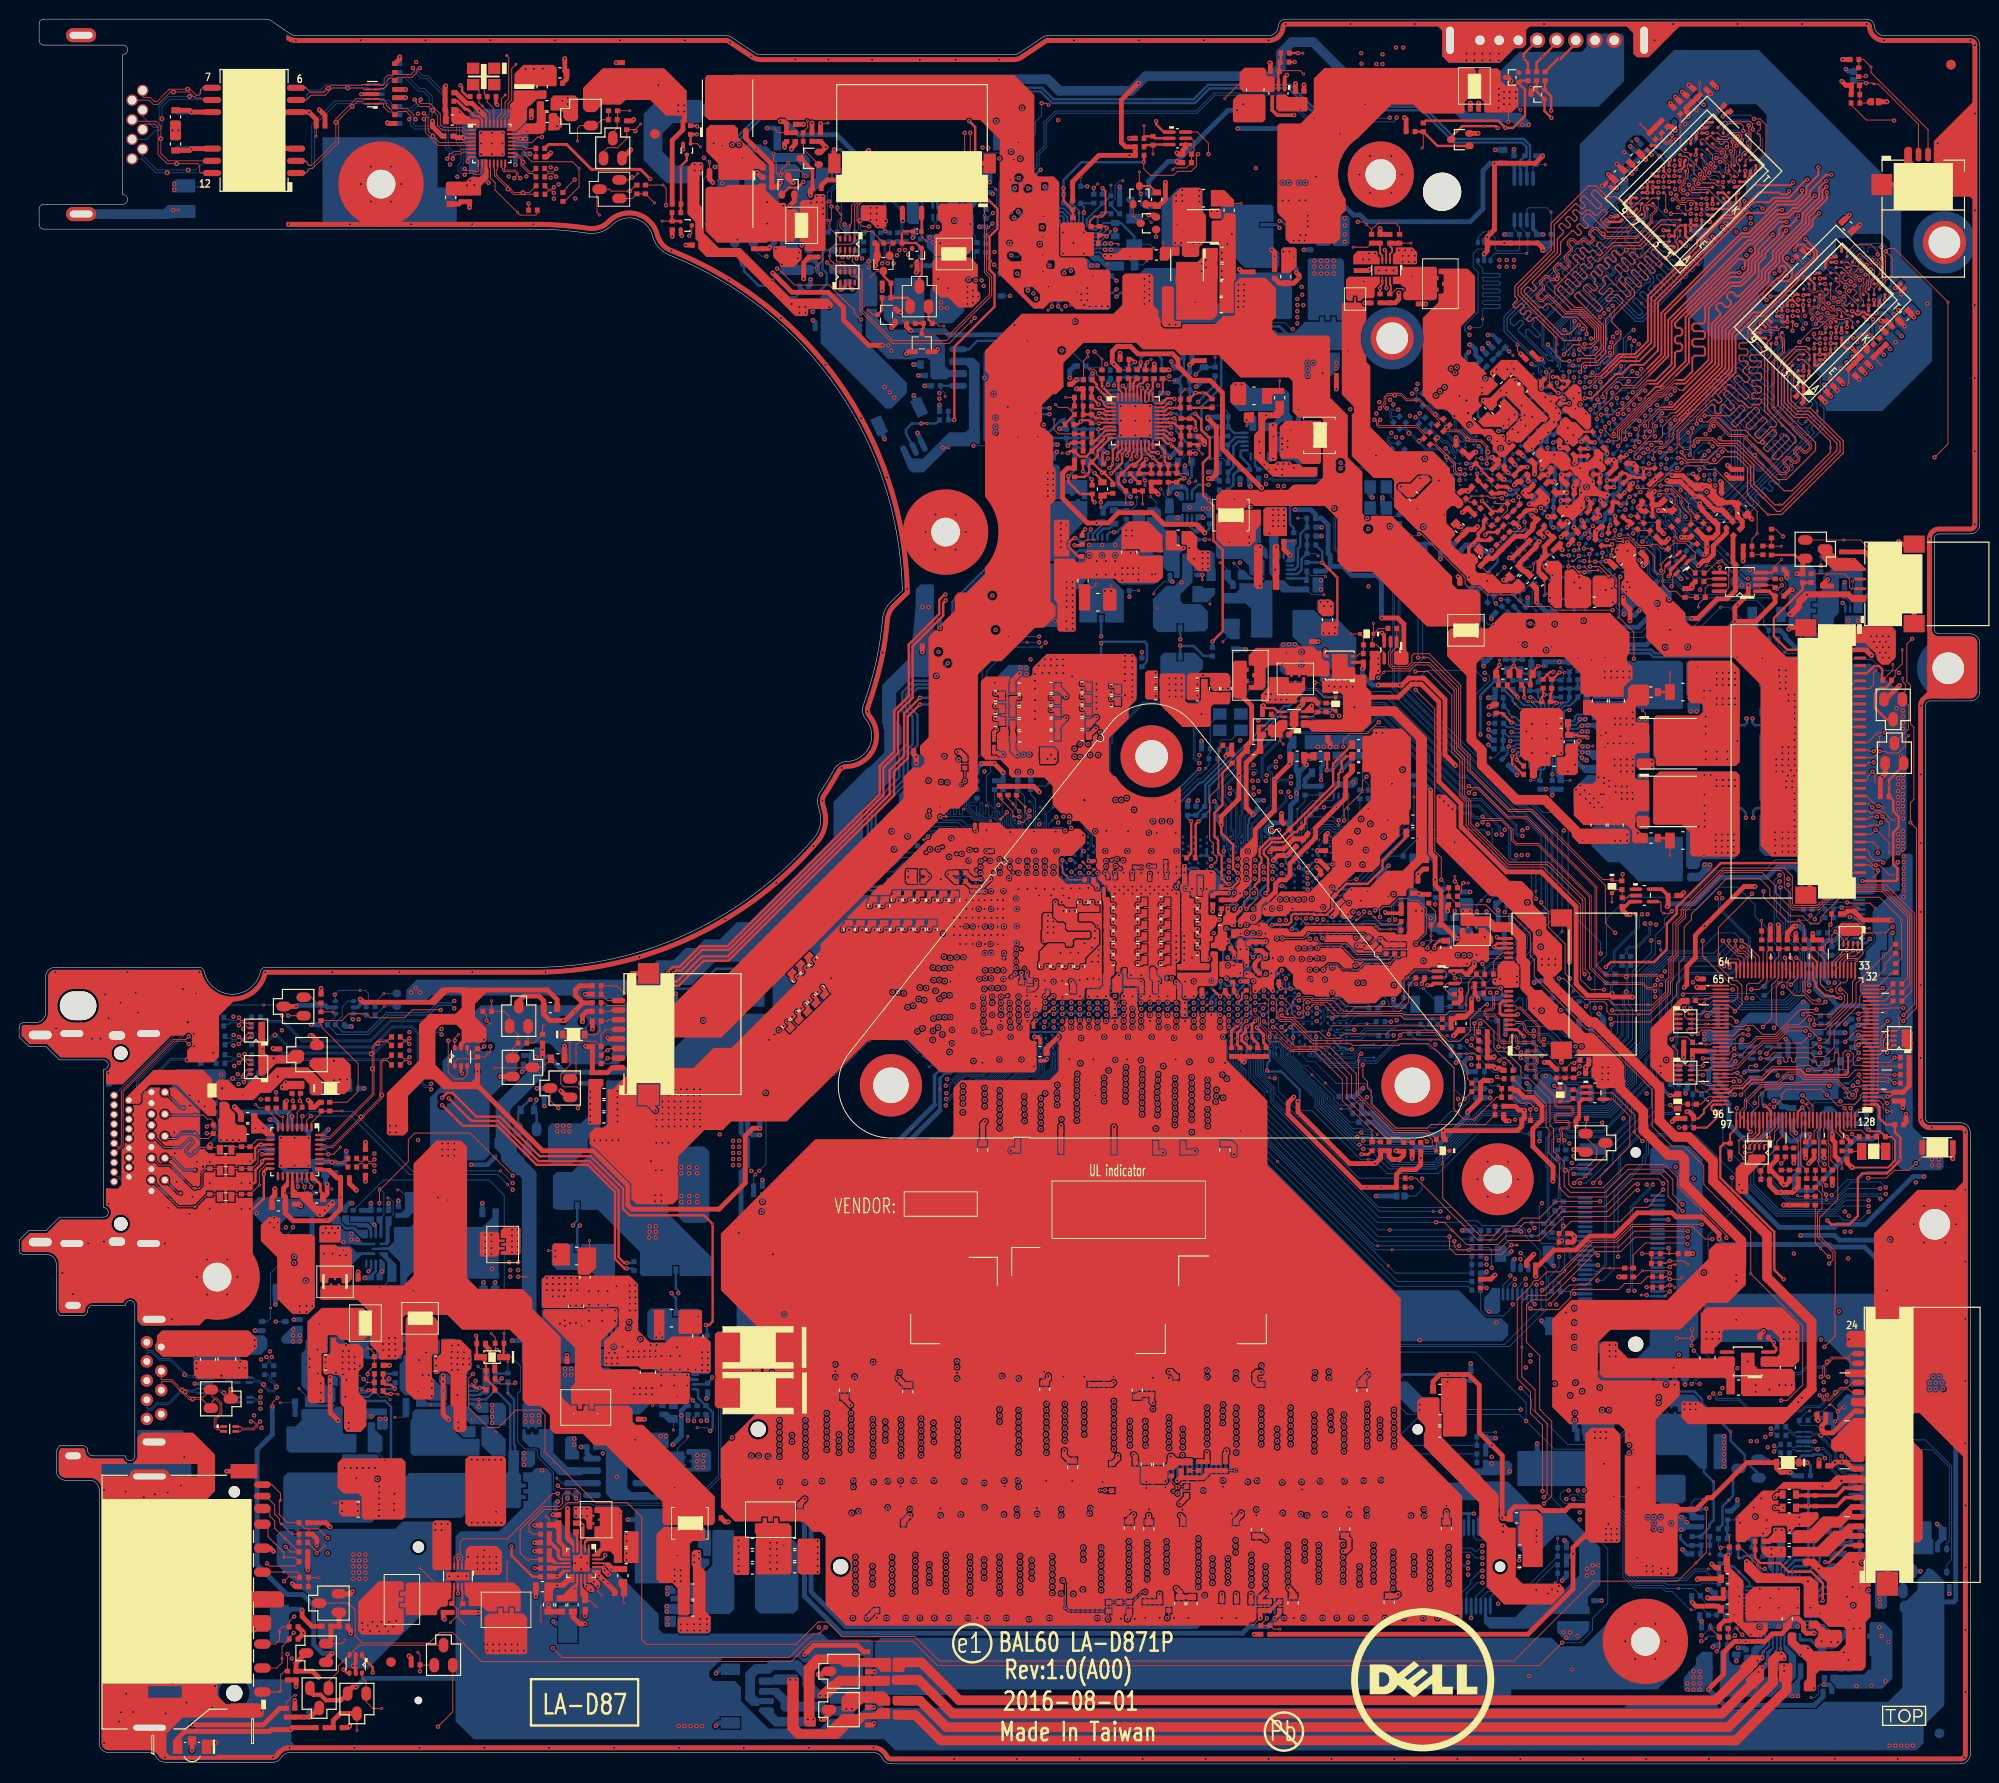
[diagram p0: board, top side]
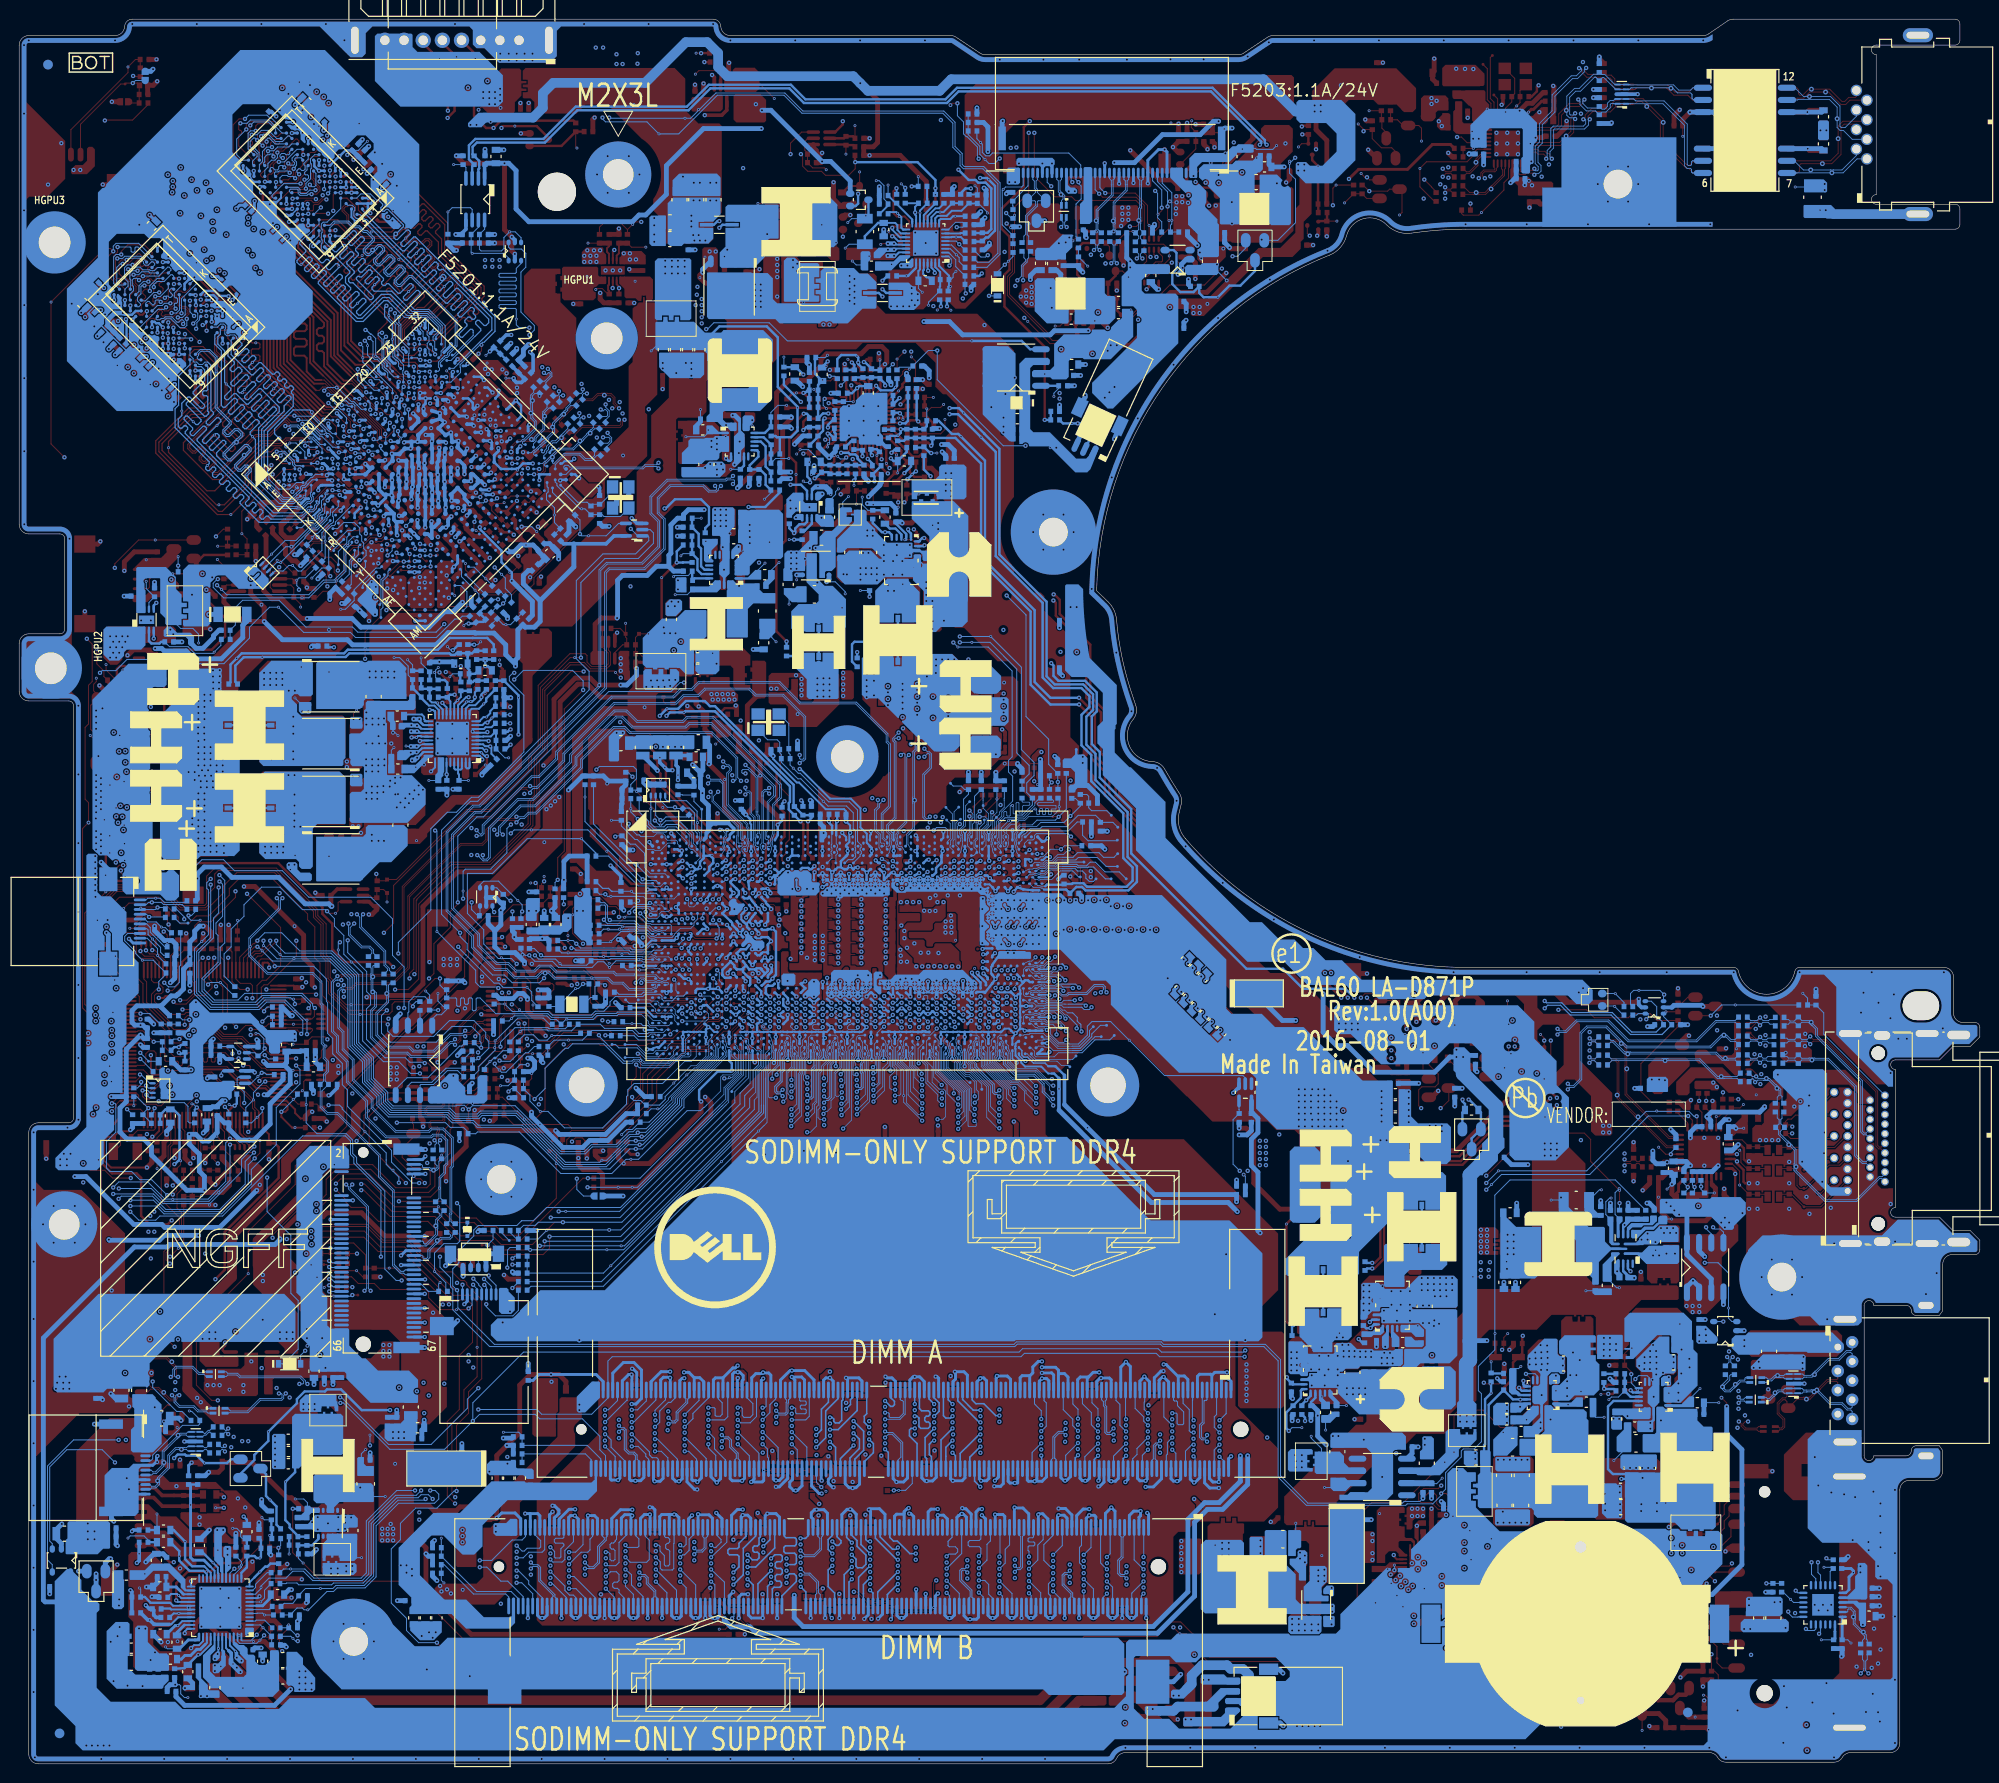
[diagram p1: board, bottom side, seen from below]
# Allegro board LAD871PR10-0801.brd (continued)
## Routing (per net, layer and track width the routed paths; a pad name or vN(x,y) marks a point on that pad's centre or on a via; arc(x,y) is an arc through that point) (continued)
DDR_A_MA7: length 52.5
  IN1 w0.076: v2(106.58,68.12) 107.12,67.59 107.12,65.6 104.55,63.02 104.55,62.23
  IN1 w0.216: 104.55,62.23 104.55,61.75 103.52,60.73 103.52,52.1 103.8,51.82 104.33,51.82 104.55,51.6 104.55,43.01 105.9,41.66 105.9,40.3 108.1,38.1 108.1,36.52 108.63,36 108.63,35.23 108.38,34.98 v2(107.18,34.98)
  BOTTOM w0.076: v2(106.58,68.12) 106.21,68.49 106.21,70.03 108.47,72.29 108.47,74.74 108.68,74.95 108.68,75.49 109,75.82 UC1.AW52
  BOTTOM w0.163: v2(107.18,34.98) 108.37,33.79 JDIMM1.122
DDR_A_MA8: length 49.1
  IN1 w0.076: 105.04,62.23 105.04,63.14 107.3,65.39 107.3,67.74 107.1,67.94 107.1,68.24 v2(106.58,68.76)
  IN1 w0.216: 105.04,62.23 105.04,61.55 104.02,60.53 104.02,54.26 104.23,54.04 104.82,54.04 105.04,53.83 105.04,53.39 104.82,53.18 104.23,53.18 104.02,52.96 104.02,52.53 104.23,52.32 104.82,52.32 105.04,52.1 105.04,43.22 106.4,41.86 106.4,40.5 108.6,38.3 108.6,36.73 109.07,36.25 v2(109.09,36.25)
  BOTTOM w0.076: v2(106.58,68.76) 107.74,69.92 107.74,70.8 108.97,72.03 108.97,73.7 109.17,73.9 109.17,74.16 109.13,74.25 109.13,74.26 109.13,74.51 109.17,74.6 109.17,74.81 109.1,74.99 109.1,75.25 UC1.AY52
  BOTTOM w0.163: JDIMM1.125 109.12,38.2 108.57,37.65 108.57,36.76 v2(109.09,36.25)
DDR_A_MA9: length 48.4
  IN1 w0.076: 103.55,62.23 103.55,62.92 106.58,65.95 v2(106.58,66.22)
  IN1 w0.216: v2(107.18,36.25) 106.94,36.02 106.18,36.02 105.96,36.23 105.96,36.99 106.18,37.21 106.3,37.21 106.51,37.42 106.51,37.85 106.3,38.07 106.18,38.07 105.96,38.29 105.96,38.84 104.91,39.89 104.91,40.94 103.55,42.3 103.55,45.43 103.34,45.65 102.76,45.65 102.53,45.88 102.53,61.14 103.55,62.16 103.55,62.23
  BOTTOM w0.076: v2(106.58,66.22) 105.72,67.08 105.72,70.24 107.98,72.49 107.98,73.95 UC1.BB54
  BOTTOM w0.163: v2(107.18,36.25) 107.36,36.07 107.88,36.07 108.12,36.31 JDIMM1.121
DDR_A_MA10: length 51.1
  IN1 w0.076: v2(109.75,77.42) 109.51,77.17 109.51,77.13 109.38,77 109.38,75.21 111.92,72.67 111.92,64.81 111.9,64.79 111.9,62.23
  IN1 w0.216: 111.9,62.23 111.9,49.18 116.12,44.96 116.12,36.15 116.34,35.94 116.34,34.29 115.89,33.84 v2(115.87,33.84)
  BOTTOM w0.089: v2(109.75,77.42) 110.16,77.82 UC1.AT50
  BOTTOM w0.163: JDIMM1.146 116.37,31.51 115.43,32.45 115.43,33.4 v2(115.87,33.84)
DDR_A_MA11: length 50.3
  IN1 w0.076: v2(106.58,66.85) 106.2,66.47 106.2,66.1 103.31,63.21 103.31,62.99 103.05,62.74 103.05,62.48
  IN1 w0.216: v2(107.18,33.71) 107.1,33.71 106.65,34.16 106.65,35.28 106.41,35.52 105.68,35.52 105.47,35.74 105.47,38.35 103.69,40.13 103.69,40.71 103.06,41.34 103.06,44.94 102.84,45.15 102.32,45.15 102.04,45.43 102.04,61.35 103.05,62.36 103.05,62.48
  BOTTOM w0.076: v2(106.58,66.85) 105.88,67.55 105.88,70.17 108.14,72.42 108.14,74.23 107.87,74.49 UC1.BA54
  BOTTOM w0.163: JDIMM1.120 107.87,32.07 107.88,32.07 107.88,33.02 v2(107.18,33.71)
DDR_A_MA12: length 50.2
  IN1 w0.076: v2(106.58,67.49) 106.95,67.12 106.95,65.87 104.05,62.97 104.05,62.23
  IN1 w0.216: 104.05,62.23 104.05,61.96 103.03,60.94 103.03,51.54 103.24,51.32 103.83,51.32 104.05,51.11 104.05,50.68 103.83,50.46 103.24,50.46 103.03,50.25 103.03,49.81 103.24,49.6 103.83,49.6 104.05,49.38 104.05,48.95 103.83,48.73 103.24,48.73 103.03,48.52 103.03,48.09 103.24,47.87 103.83,47.87 104.05,47.65 104.05,47.22 103.83,47.01 103.24,47.01 103.03,46.79 103.03,46.36 103.24,46.14 103.83,46.14 104.05,45.93 104.05,42.5 105.4,41.15 105.4,40.09 107.42,38.08 107.42,37.74 107.21,37.52 v2(107.18,37.52)
  BOTTOM w0.076: UC1.AW54 107.77,75.79 108.08,75.48 108.08,74.93 108.31,74.71 108.31,72.36 106.05,70.1 106.05,68.02 v2(106.58,67.49)
  BOTTOM w0.163: JDIMM1.119 107.62,37.97 v2(107.18,37.52)
DDR_A_MA13: length 52.5
  IN1 w0.076: 114.38,62.23 114.38,64.83 113.83,65.38 113.83,67.91 114.04,68.11 114.04,72.47 113.13,73.37 113.13,74.03 111.91,75.26 111.91,76.56 v2(111.61,76.87)
  IN1 w0.216: v2(119.96,33.59) 119.69,33.59 119.25,34.04 119.25,41.15 119.87,41.78 119.87,42.65 119.6,42.93 118.93,42.93 118.68,43.17 118.68,43.76 118.9,43.97 119.22,43.97 119.44,44.19 119.44,44.62 119.22,44.84 118.9,44.84 118.68,45.05 118.68,46.22 114.38,50.52 114.38,62.23
  BOTTOM w0.089: v2(111.61,76.87) UC1.AU46
  BOTTOM w0.163: v2(119.96,33.59) 119.37,33 JDIMM1.158
DDR_A_ODT0: length 55.6
  IN1 w0.076: v2(112.5,77.42) 112.27,77.42 112.1,77.25 112.1,75.3 113.32,74.08 113.32,73.41 114.23,72.51 114.23,68.8 114.64,68.39 114.64,65.15 114.88,64.92 114.88,62.23
  IN1 w0.216: v2(119.96,36.13) 120.21,36.13 120.43,36.34 120.43,36.76 120.21,36.97 119.96,36.97 119.74,37.19 119.74,37.62 119.96,37.84 120.21,37.84 120.43,38.05 120.43,38.46 120.21,38.67 119.96,38.67 119.74,38.89 119.74,39.32 119.96,39.54 120.21,39.54 120.43,39.75 120.43,45.36 120.23,45.56 120.23,45.86 120.46,46.09 120.46,46.4 120.15,46.7 119.85,46.7 119.62,46.48 119.32,46.48 119.01,46.78 119.01,47.09 119.24,47.31 119.24,47.62 118.93,47.92 118.63,47.92 118.4,47.7 118.09,47.7 117.78,48.01 117.78,48.31 117.99,48.52 117.99,48.86 117.72,49.13 117.38,49.13 117.17,48.92 116.87,48.92 114.88,50.92 114.88,62.23
  BOTTOM w0.089: UC1.AT45 112.54,77.42 v2(112.5,77.42)
  BOTTOM w0.163: JDIMM1.155 118.62,37.95 118.74,37.84 118.74,35.82 119.01,35.56 119.4,35.56 119.56,35.72 119.56,35.97 119.73,36.13 v2(119.96,36.13)
DDR_A_ODT1: length 57.8
  IN1 w0.076: 116.36,62.23 116.45,62.32 116.45,65.02 115.99,65.48 115.99,73.84 113.82,76.01 113.82,77.7 v2(113.41,78.11)
  IN1 w0.216: v2(121.4,34.29) 121.6,34.29 121.89,33.99 121.89,33.05 122.11,32.83 122.78,32.83 122.99,33.05 122.99,34.32 122.25,35.06 122.25,46.71 116.36,52.6 116.36,62.23
  BOTTOM w0.089: v2(113.41,78.11) 113.69,77.82 UC1.AT43
  BOTTOM w0.163: v2(121.4,34.29) 120.85,34.83 120.85,36.98 120.12,37.71 JDIMM1.161
DDR_A_PAR: length 47.7
  IN1 w0.076: v2(108.81,77.45) 108.39,77.02 108.39,76.48 108.82,76.05 108.82,74.8 109.95,73.67 109.95,72.96 110.77,72.13 110.77,66.97 110.42,66.61 110.42,62.23
  IN1 w0.216: 110.42,62.23 110.42,48.57 113.98,45 113.98,44.13 114.2,43.91 114.42,43.91 114.64,43.7 114.64,43.26 114.42,43.05 114.2,43.05 113.98,42.83 113.98,42.34 114.64,41.68 114.64,38.06 114.42,37.84 v2(114.21,37.84)
  BOTTOM w0.076: UC1.AT52 109.19,77.91 109.09,77.91 108.96,77.79 108.9,77.79 108.74,77.63 108.74,77.52 v2(108.81,77.45)
  BOTTOM w0.163: v2(114.21,37.84) 114.12,37.75 114.11,37.75 113.64,37.28 113.41,37.28 113.23,37.46 113.23,37.8 113.62,38.19 JDIMM1.143
DDR_A_RAS#: length 50.6
  IN1 w0.076: 112.89,62.23 112.89,64.7 112.69,64.9 112.69,68.73 112.49,68.93 112.49,73.59 111.18,74.9 111.18,75.85 110.66,76.36 v2(110.66,76.83)
  IN1 w0.216: 112.89,62.23 112.89,49.59 117.13,45.35 117.13,36.82 118,35.95 118,34.95 117.52,34.48 v2(117.5,34.48)
  BOTTOM w0.089: UC1.AU50 110.33,77.17 v2(110.66,76.83)
  BOTTOM w0.163: v2(117.5,34.48) 116.89,33.87 116.89,32.88 117.87,31.9 JDIMM1.152
DDR_A_WE#: length 49.3
  IN1 w0.076: v2(111.58,78.2) 111.48,78.3 111.21,78.3 111.04,78.13 111.04,76.65 111.54,76.14 111.54,74.97 112.75,73.76 112.75,68.94 113.07,68.62 113.07,65.06 113.39,64.74 113.39,62.23
  IN1 w0.216: v2(118.29,37.02) 117.94,37.02 117.63,37.33 117.63,38.21 117.85,38.43 118.04,38.43 118.25,38.64 118.25,39.07 118.04,39.29 117.85,39.29 117.63,39.51 117.63,40.43 117.85,40.65 118.04,40.65 118.25,40.86 118.25,41.3 118.04,41.51 117.85,41.51 117.63,41.73 117.63,45.56 113.39,49.8 113.39,62.23
  BOTTOM w0.089: v2(111.58,78.2) 111.65,78.2 UC1.AT46
  BOTTOM w0.163: v2(118.29,37.02) 117.82,37.48 117.82,37.99 117.62,38.19 JDIMM1.151
DDR_B_ACT#: length 72
  IN2 w0.076: v2(107.91,79.38) 107.54,79.01 107.54,74.35 106.85,73.65 106.85,72.82 104.25,70.22 104.25,70.14
  IN2 w0.216: 104.25,70.14 103.69,69.58 103.69,65.01 102.99,64.31 102.99,62.67 101.2,60.88 101.2,53.23 102.37,52.06 102.37,52.04 106.27,48.14 106.27,43.03 108.36,40.93 108.36,31.77 110.69,29.45 110.69,27.86 111.06,27.49 111.06,24.5 112.39,23.17 112.39,20.49 112.86,20.02 v2(112.88,20.02)
  BOTTOM w0.076: v2(107.91,79.38) UC1.AN53
  BOTTOM w0.163: JDIMM2.114 114.97,17.93 v2(112.88,20.02)
DDR_B_ALERT#: length 85.2
  IN2 w0.076: v2(114.31,80.07) 113.93,80.45 106.85,80.45 106.63,80.23 106.63,79.33 106.42,79.11 106.42,77.06 106.38,77.02 106.38,74.05 103.04,70.71 102.21,70.71 101.87,70.37 101.87,67.66 101.85,67.65
  IN2 w0.216: v2(115.78,18.11) 115.31,17.65 112.57,17.65 109.34,20.88 109.34,26.63 108.19,27.78 108.19,29.51 105.79,31.91 105.79,41.08 104.34,42.53 104.34,47.64 100.65,51.33 100.65,51.35 99.35,52.65 99.35,62.53 100.65,63.83 100.65,64.78 101.85,65.98 101.85,67.65
  BOTTOM w0.089: v2(114.31,80.07) 114.01,79.77 UC1.AN43
  BOTTOM w0.163: JDIMM2.116 115.48,17.81 v2(115.78,18.11)
DDR_B_BG0: length 73.1
  IN2 w0.076: v2(108.81,78.78) 108.46,78.44 108.46,77.62 108.45,77.6 108.45,77.22 108.46,77.2 108.46,76.46 108.76,76.17 108.76,73.8 105.39,70.44 105.39,65.95 104.46,65.02
  IN2 w0.216: 104.46,65.02 104.46,62.69 102.28,60.5 102.28,53.55 103.3,52.53 103.3,52.51 103.42,52.39 103.42,52.38 107.26,48.55 107.26,43.44 110.1,40.6 110.1,34 110.74,33.37 110.74,31.04 111.72,30.06 111.72,28.65 112.95,27.42 112.95,24.01 113.77,23.18 113.77,21.52 114.23,21.07 114.23,20.6 114.01,20.38 113.56,20.38 113.34,20.6 113.34,20.85 112.9,21.29 v2(112.88,21.29)
  BOTTOM w0.076: UC1.AP52 109.15,79.12 v2(108.81,78.78)
  BOTTOM w0.163: JDIMM2.115 115.22,23.54 112.98,21.29 v2(112.88,21.29)
DDR_B_BG1: length 71.7
  IN2 w0.076: v2(108.83,79.38) 108.48,79.38 108.33,79.23 108.33,78.54 108.29,78.51 108.29,77.69 108.28,77.67 108.28,77.15 108.3,77.13 108.3,76.47 107.71,75.89 107.71,73.07 104.2,69.55 104.2,65.02 103.94,64.77
  IN2 w0.216: v2(112.88,22.56) 113.14,22.82 113.14,23.12 112.45,23.81 112.45,24.44 112.24,24.66 111.77,24.66 111.55,24.87 111.55,25.3 111.77,25.52 112.24,25.52 112.45,25.74 112.45,27.09 112.24,27.3 111.77,27.3 111.55,27.52 111.55,28.11 111.22,28.45 111.22,29.62 109.56,31.28 109.56,31.91 109.77,32.12 110.03,32.12 110.24,32.34 110.24,32.77 110.03,32.99 109.77,32.99 109.56,33.2 109.56,37.72 108.86,38.42 108.86,39.27 109.4,39.81 109.4,40.6 106.76,43.24 106.76,48.34 102.86,52.24 102.86,52.27 101.78,53.35 101.78,60.77 103.63,62.61 103.63,62.61 103.94,62.93 103.94,64.74 103.94,64.77
  BOTTOM w0.076: v2(108.83,79.38) 109.22,79.77 UC1.AN52
  BOTTOM w0.163: v2(112.88,22.56) 113.06,22.38 113.44,22.38 114.72,23.67 JDIMM2.113
DDR_B_BS0: length 70.3
  IN2 w0.076: 115.12,64.77 115.12,66.42 114.75,66.79 114.75,72.23 114.67,72.31 v2(113.66,72.31)
  IN2 w0.216: 115.12,64.77 115.11,64.76 115.11,60.05 115.32,59.83 115.42,59.83 115.64,59.62 115.64,59.18 115.42,58.97 115.32,58.97 115.11,58.75 115.11,58.32 115.32,58.1 115.42,58.1 115.64,57.89 115.64,57.46 115.42,57.24 115.32,57.24 115.11,57.02 115.11,56.5 125.48,46.14 125.48,38.7 124.41,37.63 124.41,31.99 126.06,30.33 126.06,28.6 125.49,28.03 125.49,22.48 125.95,22.02 125.95,21.66 126.1,21.51 v2(126.1,21.42)
  BOTTOM w0.076: UC1.BB44 113.61,73.95 113.61,72.35 v2(113.66,72.31)
  BOTTOM w0.163: JDIMM2.150 125.97,18.25 125.8,18.41 125.19,18.41 125.02,18.58 125.02,18.89 125.19,19.05 125.5,19.05 125.67,19.21 125.67,19.59 125.5,19.75 125.1,19.75 124.93,19.91 124.93,20.22 125.1,20.38 125.5,20.38 125.67,20.55 125.67,20.92 125.5,21.08 125.1,21.08 124.93,21.24 124.93,21.64 125.1,21.8 125.71,21.8 v2(126.1,21.42)
DDR_B_BS1: length 70.5
  IN2 w0.076: v2(113.17,70.31) 113.22,70.36 113.62,70.36 113.7,70.28 113.7,66.2 114.12,65.78 114.12,64.77
  IN2 w0.216: 114.12,64.77 114.12,56.09 122.49,47.72 122.49,46.35 122.85,45.99 123.99,45.99 124.49,45.5 124.49,39.36 122.91,37.79 122.91,32.08 124.5,30.49 124.5,23.32 124.2,23.02 124.2,22.37 124.96,21.61 124.96,21.22 124.69,20.95 124.52,20.78 v2(124.5,20.78)
  BOTTOM w0.076: v2(113.17,70.31) 113.54,70.31 113.72,70.48 113.72,71.72 113.25,72.19 113.25,72.5 113.45,72.7 113.45,74.44 UC1.BA44
  BOTTOM w0.163: JDIMM2.145 124.72,23.75 124.56,23.59 123.63,23.59 123.47,23.42 123.47,22.9 123.63,22.73 124.61,22.73 124.77,22.57 124.77,22.13 124.61,21.97 123.66,21.97 123.47,21.78 123.47,20.94 123.63,20.78 v2(124.5,20.78)
DDR_B_CAS#: length 73.3
  IN2 w0.076: 115.63,64.77 115.63,66.61 114.92,67.32 114.92,69.58 115,69.67 v2(115.42,69.67)
  IN2 w0.216: 115.63,64.77 115.63,62.03 116.13,61.53 116.13,56.18 125.97,46.34 125.97,38.5 124.9,37.43 124.9,32.19 126.56,30.54 126.56,28.2 125.99,27.63 125.99,22.87 126.45,22.41 126.45,21.86 126.72,21.59 127.32,21.59 127.54,21.37 127.54,19.36 127.88,19.01 127.88,18.44 127.67,18.22 126.8,18.22 126.57,18.46 126.57,19.7 126.12,20.15 v2(126.1,20.15)
  BOTTOM w0.076: v2(115.42,69.67) 114.45,70.64 114.45,72.58 113.96,73.06 113.96,73.64 114.15,73.82 114.15,74.2 114.1,74.31 114.1,74.43 114.16,74.65 114.16,74.79 114.11,74.95 114.11,75.13 114.19,75.29 114.19,75.39 UC1.AY43
  BOTTOM w0.163: JDIMM2.156 127.47,18.77 v2(126.1,20.15)
DDR_B_CKE0: length 71.4
  IN2 w0.076: 102.76,70.1 102.76,70.13 106.54,73.91 106.54,76.95 106.58,76.99 106.58,79.04 106.98,79.44 v2(107.05,79.44)
  IN2 w0.216: 102.76,70.1 102.74,70.08 102.74,65.91 101.38,64.55 101.38,63.16 100.08,61.86 100.08,52.95 101.38,51.65 101.38,51.63 105.28,47.73 105.28,42.62 106.29,41.6 106.29,32.43 108.91,29.81 108.91,28.08 110.07,26.93 110.07,24.09 110.74,23.42 110.74,23.11 110.08,22.46 110.08,21.9 110.3,21.69 110.78,21.69 v2(111.01,21.92)
  BOTTOM w0.076: UC1.AN56 106.72,79.77 v2(107.05,79.44)
  BOTTOM w0.163: JDIMM2.109 113.72,23.62 113.34,23.23 112.93,23.23 111.63,21.92 v2(111.01,21.92)
DDR_B_CKE1: length 71.4
  IN2 w0.076: 103.18,69.41 106.69,72.91 106.69,73.72 107.37,74.41 107.37,78.47 v2(107.01,78.84)
  IN2 w0.216: v2(112.88,18.75) 112.86,18.75 111.89,19.72 111.89,22.97 110.56,24.29 110.56,27.28 109.41,28.44 109.41,30.03 107.87,31.57 107.87,40.73 105.77,42.83 105.77,47.93 101.87,51.83 101.87,51.86 100.7,53.02 100.7,61.66 101.87,62.82 101.87,64.22 103.18,65.53 103.18,69.41
  BOTTOM w0.089: v2(107.01,78.84) 107.03,78.84 107.03,78.85 107.37,79.13 UC1.AP55
  BOTTOM w0.163: JDIMM2.110 113.97,17.66 v2(112.88,18.75)
DDR_B_CKE2: length 1.1
  TOP w0.163: v2(107.89,80.07) 107.72,80.07 T5.1
  BOTTOM w0.165: UC1.AN55 107.6,79.77 v2(107.89,80.07)
DDR_B_CKE3: length 1.2
  TOP w0.163: T6.1 107.81,78.79 v2(107.96,78.79)
  BOTTOM w0.165: v2(107.96,78.79) 107.97,78.79 107.97,78.8 108.29,79.12 UC1.AP53
DDR_B_CLK0: length 76.1
  IN2 w0.076: 112,66.09 112,66.09 112.06,66.15 112.06,72.37 112.67,72.98 112.67,76.35 112.87,76.55 112.87,79 v2(112.49,79.38)
  IN2 w0.127: v2(123.03,21.61) 122.34,21.61 122,21.94 122,23.9 122.57,24.47 122.57,27.5 122.17,27.9 122.09,27.98 122.09,30.18 120.64,31.63 120.64,32.32 120.39,32.58 120.39,35.39 120.98,35.98 120.98,37.31 120.48,37.81 120.48,38.11 120.05,38.54 120.05,39.13 120.48,39.56 120.48,41.49 120.08,41.9 120.08,42.49 120.48,42.89 120.48,43.28 120.08,43.68 120.08,44.27 120.48,44.68 120.48,44.94 120.56,45.02 120.56,45.73 120.07,46.22 120.07,46.61 120.27,46.81 120.27,46.99 120,47.26 119.82,47.26 119.62,47.06 119.23,47.06 118.81,47.48 118.81,47.87 119.01,48.07 119.01,48.25 118.74,48.52 118.56,48.52 118.36,48.32 117.97,48.32 117.55,48.74 117.55,49.13 117.75,49.33 117.75,49.51 117.48,49.78 117.3,49.78 117.1,49.58 116.71,49.58 116.29,50 116.29,50.4 116.49,50.59 116.49,50.77 116.22,51.04 116.04,51.04 115.84,50.84 115.45,50.84 115.03,51.26 115.03,51.66 115.23,51.86 115.23,52.03 114.96,52.31 114.78,52.31 114.58,52.11 114.19,52.11 113.77,52.53 113.77,52.92 113.97,53.12 113.97,53.3 113.69,53.57 113.52,53.57 113.32,53.37 112.92,53.37 112,54.29 112,66.09
  BOTTOM w0.089: v2(112.49,79.38) 112.69,79.38 UC1.AP45
  BOTTOM w0.097: v2(123.03,21.61) 121.57,21.61 120.84,22.34 120.84,23.66 120.72,23.77 JDIMM2.137
DDR_B_CLK1: length 74.6
  IN2 w0.076: 111.34,65.63 111.34,76.42 111.21,76.55 111.21,78.97 111.29,79.04 111.42,79.04 v2(111.67,78.79)
  IN2 w0.127: v2(123.03,20.34) 123.03,20.27 122.82,20.07 122.61,20.07 122.35,19.81 122.35,19.05 122.23,18.93 121.6,18.93 121.47,19.05 121.47,25.02 122.04,25.59 122.04,27.24 121.55,27.73 121.55,29.96 119.54,31.97 119.54,38.11 119.27,38.39 118.89,38.39 118.76,38.51 118.76,38.9 118.89,39.02 119.27,39.02 119.54,39.3 119.54,45.99 111.34,54.19 111.34,65.63
  BOTTOM w0.076: UC1.AP46 111.84,79.12 111.67,78.95 v2(111.67,78.79)
  BOTTOM w0.097: v2(123.03,20.34) 122.58,19.89 122.04,19.89 121.16,19 121.16,17.84 120.97,17.66 JDIMM2.138
DDR_B_CLK#0: length 76.2
  IN2 w0.076: 112.26,66.09 112.26,66.19 112.23,66.23 112.23,72.31 112.83,72.91 112.83,76.28 113.03,76.49 113.03,79.32 113.15,79.44 113.34,79.44 v2(113.4,79.38)
  IN2 w0.127: 112.26,66.09 112.26,54.39 113.03,53.62 113.21,53.62 113.41,53.82 113.8,53.82 114.22,53.4 114.22,53.01 114.02,52.81 114.02,52.63 114.29,52.36 114.47,52.36 114.67,52.56 115.06,52.56 115.48,52.14 115.48,51.75 115.28,51.55 115.28,51.37 115.55,51.1 115.73,51.1 115.93,51.3 116.32,51.3 116.75,50.88 116.75,50.49 116.55,50.29 116.55,50.11 116.82,49.84 117,49.84 117.19,50.04 117.59,50.04 118.01,49.62 118.01,49.23 117.81,49.03 117.81,48.85 118.08,48.58 118.26,48.58 118.46,48.78 118.85,48.78 119.27,48.36 119.27,47.96 119.07,47.77 119.07,47.59 119.34,47.32 119.52,47.32 119.72,47.52 120.11,47.52 120.53,47.09 120.53,46.7 120.33,46.5 120.33,46.32 120.82,45.84 120.82,44.92 120.74,44.84 120.74,44.57 120.33,44.17 120.33,43.79 120.74,43.38 120.74,42.79 120.33,42.38 120.33,42 120.74,41.6 120.74,39.46 120.31,39.02 120.31,38.64 120.74,38.21 120.74,37.92 121.24,37.42 121.24,35.88 120.64,35.28 120.64,32.69 120.9,32.43 120.9,31.73 122.35,30.28 122.35,28.08 122.42,28.01 122.83,27.6 122.83,24.37 122.26,23.8 122.26,22.05 122.45,21.86 122.69,21.86 123.03,22.2 v2(123.03,22.24)
  BOTTOM w0.089: UC1.AN45 112.94,79.59 113.15,79.38 v2(113.4,79.38)
  BOTTOM w0.097: v2(123.03,22.24) 122.58,21.79 121.65,21.79 121.02,22.42 121.02,23.53 121.23,23.73 JDIMM2.139
DDR_B_CLK#1: length 74.6
  IN2 w0.076: 111.09,65.63 111.09,65.64 111.18,65.73 111.18,76.35 111.04,76.48 111.04,79.04 111.22,79.21 111.4,79.21 v2(111.57,79.38)
  IN2 w0.127: v2(123.03,19.7) 122.92,19.81 122.72,19.81 122.61,19.7 122.61,18.95 122.33,18.67 121.49,18.67 121.21,18.95 121.21,25.12 121.78,25.69 121.78,27.14 121.29,27.63 121.29,29.86 119.29,31.87 119.29,38 119.16,38.13 118.78,38.13 118.5,38.41 118.5,39 118.78,39.28 119.16,39.28 119.29,39.41 119.29,45.89 111.09,54.09 111.09,65.63
  BOTTOM w0.089: v2(111.57,79.38) UC1.AN46
  BOTTOM w0.097: JDIMM2.140 121.47,17.64 121.34,17.77 121.34,18.92 122.12,19.7 v2(123.03,19.7)
DDR_B_CS#0: length 72.5
  IN2 w0.076: v2(115.44,72.03) 115.93,72.03 116.12,71.84 116.12,67.13 117.8,65.46 117.8,64.77
  IN2 w0.216: 117.8,64.77 117.8,62.67 119.37,61.1 119.37,60.76 119.11,60.49 119.11,59.89 119.37,59.63 119.37,59.03 119.11,58.77 119.11,58.16 119.37,57.9 119.37,56.95 119.11,56.69 119.11,56.01 129.12,46 129.12,45.41 129.12,44.87 129.41,44.58 130.37,44.58 130.71,44.24 130.71,42.6 130.5,42.38 129.33,42.38 129.12,42.17 129.12,32.5 129.33,32.28 129.93,32.28 130.21,32 130.21,31.63 129.99,31.42 129.33,31.42 129.12,31.2 129.12,30.7 129.33,30.48 129.97,30.48 130.31,30.14 130.31,25.46 129.83,24.98 129.32,24.98 129.08,24.74 129.08,20.74 128.86,20.53 v2(128.56,20.53)
  BOTTOM w0.076: v2(115.44,72.03) 115.17,72.03 115.08,72.12 115.08,73.8 115.04,73.84 UC1.BB42
  BOTTOM w0.163: v2(128.56,20.53) 127.71,20.53 125.72,22.52 JDIMM2.149
DDR_B_CS#1: length 74.2
  IN2 w0.076: 118.29,64.77 118.29,65.3 116.35,67.24 116.35,71.84 115.54,72.65 v2(115.47,72.65)
  IN2 w0.216: 118.29,64.77 118.29,62.87 119.86,61.3 119.86,55.95 131.21,44.61 131.21,42.1 130.99,41.89 130.28,41.89 130.06,41.67 130.06,32.85 130.81,32.1 130.81,25.03 129.57,23.79 129.57,22.81 129.79,22.6 129.85,22.6 130.06,22.38 130.06,21.95 129.85,21.73 129.79,21.73 129.57,21.52 129.57,20.54 129.04,20 129.04,18.66 129.36,18.34 129.82,18.34 130.04,18.55 v2(130.04,18.69)
  BOTTOM w0.076: UC1.AY42 115.34,75.06 115.34,73.86 115.24,73.77 115.24,72.89 v2(115.47,72.65)
  BOTTOM w0.163: JDIMM2.157 127.72,23.75 129.01,22.47 129.01,19.71 v2(130.04,18.69)
DDR_B_D0: length 84.4
  IN2 w0.076: v2(102.05,82.77) 101.45,83.36 99.63,83.36
  IN2 w0.127: v2(93.49,17.99) 92.62,17.99 91.8,18.81 91.8,22.1 89.84,24.06 89.84,29.29 88.07,31.06 88.07,42.05 84.65,45.46 84.65,64.62 84.27,65 84.27,74.16 89.95,79.84 92.75,79.84 93.1,80.19 95.84,80.19 96.23,80.58 96.85,80.58 99.63,83.36
  BOTTOM w0.076: v2(102.05,82.77) UC1.AF65
  BOTTOM w0.102: JDIMM2.28 93.48,17.97 v2(93.49,17.99)
DDR_B_D1: length 83.1
  IN2 w0.076: v2(102.69,82.77) 102.32,82.4 100.31,82.4
  IN2 w0.127: 100.31,82.4 100.04,82.4 99.15,81.5 99.15,80.57 96.87,78.3 94.27,78.3 94,78.03 89.6,78.03 85.3,73.73 85.3,65.45 85.78,64.97 85.78,49.41 87.71,47.49 87.71,47.31 87.5,47.09 87.5,46.84 87.62,46.71 88.08,46.71 88.21,46.58 88.21,46.33 88.08,46.2 87.33,46.2 87.2,46.08 87.2,45.82 87.33,45.69 88.08,45.69 88.21,45.57 88.21,45.14 90.16,43.19 90.16,36.26 89.93,36.03 89.93,31.61 91.53,30.01 91.53,24.15 93.49,22.19 v2(93.49,21.8)
  BOTTOM w0.076: v2(102.69,82.77) UC1.AF64
  BOTTOM w0.102: JDIMM2.25 92.72,22.56 v2(93.49,21.8)
DDR_B_D2: length 83.4
  IN2 w0.076: v2(102.08,80.9) 101.56,80.38 101.35,80.38 101.25,80.28 100.34,80.28 99.87,79.81 99.87,78.51 98.31,76.96 98.31,76.51 97.33,75.53 97.16,75.53 96.28,74.65
  IN2 w0.127: v2(96.68,19.26) 97.21,18.73 97.52,18.73 97.71,18.92 97.71,19.46 97.59,19.58 97.26,19.58 97.14,19.71 97.14,19.97 97.26,20.09 97.59,20.09 97.71,20.22 97.71,20.47 97.59,20.6 97.26,20.6 97.14,20.73 97.14,20.98 97.26,21.11 97.59,21.11 97.71,21.24 97.71,22.39 94.97,25.14 94.97,38.1 93.59,39.47 93.59,45.65 88.46,50.78 88.46,66.85 87.76,67.55 87.76,72.71 89.33,74.28 95.91,74.28 96.28,74.65
  BOTTOM w0.076: UC1.AK65 v2(102.08,80.9)
  BOTTOM w0.102: v2(96.68,19.26) 97.17,18.77 97.17,17.74 96.97,17.54 JDIMM2.42
DDR_B_D3: length 84.7
  IN2 w0.076: 97.65,77.02 98.78,78.15 98.78,79.42 100.54,81.18 101.2,81.18 101.29,81.27 102.45,81.27 102.69,81.04 v2(102.69,80.94)
  IN2 w0.127: v2(96.68,17.99) 96.68,17.86 96.56,17.73 95.46,17.73 95.33,17.86 95.33,18.72 95.49,18.88 96.14,18.88 96.26,19 96.26,19.26 96.14,19.39 95.8,19.39 95.56,19.63 95.56,21.2 95.88,21.53 95.88,22.13 93.75,24.27 93.75,29.95 92.42,31.27 92.42,43.61 89.93,46.1 89.93,47.3 87.43,49.79 87.43,65.35 86.73,66.05 86.73,73.14 89.49,75.89 93.79,75.89 93.93,76.03 95.16,76.03 95.18,76.01 95.69,76.01 96.7,77.02 97.65,77.02
  BOTTOM w0.076: v2(102.69,80.94) UC1.AK64
  BOTTOM w0.102: v2(96.68,17.99) 95.97,17.28 JDIMM2.38
DDR_B_D4: length 84.2
  IN2 w0.076: 100.24,83.13 101.05,83.13 v2(101.42,82.77)
  IN2 w0.127: v2(93.49,19.26) 92.5,19.26 92.26,19.49 92.26,22.29 90.19,24.36 90.19,29.43 88.51,31.1 88.51,39.79 88.41,39.89 88.41,42.19 84.99,45.6 84.99,64.76 84.61,65.14 84.61,74.02 90.1,79.5 93.48,79.5 93.76,79.22 96.69,79.22 98.64,81.17 98.64,81.96 99.82,83.13 100.24,83.13
  BOTTOM w0.076: v2(101.42,82.77) UC1.AF66
  BOTTOM w0.102: v2(93.49,19.26) 92.48,18.24 JDIMM2.24
DDR_B_D5: length 83.9
  IN2 w0.127: v2(93.49,20.53) 92.6,21.42 92.6,22.59 91.19,24 91.19,24.54 91.06,24.66 90.66,24.66 90.53,24.79 90.53,25.04 90.66,25.17 91.06,25.17 91.19,25.3 91.19,25.55 91.06,25.68 90.66,25.68 90.53,25.81 90.53,26.06 90.66,26.19 91.06,26.19 91.19,26.31 91.19,29.86 89.53,31.52 89.53,43.01 85.34,47.2 85.34,64.93 84.96,65.31 84.96,73.87 89.57,78.49 93.98,78.49 94.13,78.64 96.62,78.64 98.93,80.95 98.93,81.84 99.86,82.77 v2(100.78,82.77)
  BOTTOM w0.076: v2(100.78,82.77) UC1.AF67
  BOTTOM w0.102: v2(93.49,20.53) 93.93,20.97 93.93,22.57 93.72,22.77 JDIMM2.29
DDR_B_D6: length 82.4
  IN2 w0.076: 96.07,75.44 96.6,75.44 97.02,75.86 97.19,75.86 97.98,76.65 97.98,77.09 98.94,78.05 98.94,79.35 100.21,80.61 100.63,80.61 100.7,80.68 v2(100.7,80.81)
  IN2 w0.127: 96.07,75.44 96.01,75.44 95.57,75 95.1,75 94.74,75.37 94.74,75.56 94.61,75.68 94.07,75.68 93.93,75.55 89.63,75.55 87.08,72.99 87.08,66.19 87.78,65.49 87.78,49.93 92.05,45.66 92.05,45.48 91.63,45.07 91.63,44.89 91.81,44.71 91.99,44.71 92.41,45.12 92.59,45.12 92.77,44.94 92.77,32.43 94.28,30.92 94.28,24.86 96.23,22.91 96.23,20.65 96.35,20.53 v2(96.68,20.53)
  BOTTOM w0.076: v2(100.7,80.81) 100.7,81.05 UC1.AK67
  BOTTOM w0.102: v2(96.68,20.53) 96.96,20.53 97.64,21.21 97.64,22.87 96.72,23.79 JDIMM2.41
DDR_B_D7: length 83.1
  IN2 w0.076: v2(101.44,80.9) 101.44,80.7 101.18,80.44 100.27,80.44 99.11,79.28 99.11,77.98 98.15,77.02 98.15,76.58 97.26,75.7 97.09,75.7 96.34,74.94 96.02,74.94
  IN2 w0.127: v2(96.68,21.8) 96.68,22.94 94.62,25 94.62,31.06 93.67,32.02 93.67,36.42 93.8,36.55 94.29,36.55 94.42,36.67 94.42,36.93 94.29,37.06 93.8,37.06 93.67,37.18 93.67,37.44 93.8,37.56 94.29,37.56 94.42,37.69 94.42,37.94 94.29,38.07 93.8,38.07 93.15,38.72 93.15,45.61 88.12,50.64 88.12,65.63 87.42,66.33 87.42,72.85 89.19,74.62 89.77,74.62 89.9,74.75 89.9,75.08 90.02,75.2 90.28,75.2 90.41,75.08 90.41,74.75 90.53,74.62 90.79,74.62 90.91,74.75 90.91,75.08 91.04,75.2 91.29,75.2 91.42,75.08 91.42,74.75 91.55,74.62 91.8,74.62 91.93,74.75 91.93,75.08 92.06,75.2 92.31,75.2 92.44,75.08 92.44,74.75 92.56,74.62 92.82,74.62 92.95,74.75 92.95,75.08 93.07,75.2 93.33,75.2 93.45,75.08 93.45,74.75 93.58,74.62 95.69,74.62 96.02,74.94
  BOTTOM w0.076: UC1.AK66 101.44,80.91 v2(101.44,80.9)
  BOTTOM w0.102: JDIMM2.37 95.72,22.76 v2(96.68,21.8)
DDR_B_D8: length 87.2
  IN2 w0.127: v2(97.82,84.12) 97.82,84.33 96.76,85.39 90.15,85.39 80.22,75.46 80.22,51.28 80.61,50.89 80.61,43.4 80.96,43.05 80.96,35.03 81.55,34.44 81.55,26.29 84.24,23.6 84.24,19.79 85.09,18.95 87.17,18.95 v2(87.25,19.03)
  BOTTOM w0.076: v2(97.82,84.12) 97.82,83.98 98.27,83.53 UC1.AF70
  BOTTOM w0.102: v2(87.25,19.03) 88.47,17.8 JDIMM2.8
DDR_B_D9: length 88.6
  IN2 w0.127: v2(98.52,84.12) 96.9,85.73 90,85.73 79.88,75.6 79.88,51.14 80.27,50.75 80.27,43.26 80.62,42.91 80.62,34.89 81.04,34.47 81.04,26.31 83.9,23.46 83.9,19.23 84.71,18.41 85.15,18.41 85.4,18.16 85.91,18.16 86.16,18.41 86.59,18.41 v2(87.25,17.76)
  BOTTOM w0.076: v2(98.52,84.12) 98.91,83.72 99.18,83.72 99.25,83.7 UC1.AF68
  BOTTOM w0.102: JDIMM2.4 87.47,17.53 v2(87.25,17.76)
DDR_B_D10: length 86.4
  IN2 w0.127: v2(95.41,81.73) 94.78,82.35 91.08,82.35 83.29,74.56 83.29,64.6 83.67,64.22 83.67,45.06 86.02,42.71 86.02,31.43 87.98,29.47 87.98,28.55 87.85,28.43 86.99,28.43 86.86,28.3 86.86,28.05 86.99,27.92 87.85,27.92 87.98,27.79 87.98,27.54 87.85,27.41 87.05,27.41 86.92,27.28 86.92,27.03 87.05,26.9 87.88,26.9 88.01,26.78 88.01,25.73 87.88,25.61 87.05,25.61 86.92,25.48 86.92,25.23 87.05,25.1 87.88,25.1 88.01,24.97 88.01,24.08 90.44,21.65 90.44,20.49 90.75,20.18 90.96,20.18 v2(91.07,20.29)
  BOTTOM w0.076: 95.72,82.05 95.95,82.28 97.54,82.28 97.62,82.2 UC1.AH71
  BOTTOM w0.102: JDIMM2.21 91.72,20.95 v2(91.07,20.29)
  BOTTOM w0.163: 95.72,82.05 v2(95.41,81.73)
DDR_B_D11: length 89
  IN2 w0.127: v2(91.07,17.75) 89.89,17.75 89.7,17.95 89.7,21.28 85.21,25.77 85.21,28.8 85.34,28.92 86.04,28.92 86.16,29.05 86.16,29.3 86.04,29.43 85.34,29.43 85.21,29.56 85.21,29.81 85.34,29.94 85.93,29.94 86.05,30.07 86.05,30.35 85.93,30.48 85.34,30.48 85.21,30.61 85.21,31.2 84.76,31.65 84.76,36.84 84.38,37.21 84.38,39.3 84.51,39.42 85.2,39.42 85.33,39.55 85.33,39.8 85.2,39.93 84.51,39.93 84.38,40.06 84.38,43.31 82.99,44.7 82.99,63.93 82.61,64.31 82.61,74.85 90.8,83.04 v2(95.33,83.04)
  BOTTOM w0.076: 95.72,83.42 97.29,83.42 97.61,83.1 97.97,83.1 97.97,83.1 98.06,83.13 98.26,83.13 98.35,83.1 98.35,83.1 98.35,83.1 98.36,83.09 98.59,83.09 98.71,83.13 99.51,83.13 99.79,82.86 UC1.AH68
  BOTTOM w0.102: JDIMM2.20 91.48,17.35 v2(91.07,17.75)
  BOTTOM w0.163: v2(95.33,83.04) 95.71,83.42 95.72,83.42
DDR_B_D12: length 86.4
  IN2 w0.127: v2(97.12,84.05) 97.12,84.42 96.49,85.05 90.29,85.05 80.7,75.46 80.7,51.37 80.96,51.12 80.96,43.54 81.31,43.19 81.31,37.14 82.45,35.99 82.45,25.88 85.34,22.99 85.34,22.81 84.79,22.26 84.79,22.08 84.97,21.9 85.15,21.9 85.7,22.45 85.88,22.45 86.83,21.5 86.83,20.72 87.25,20.3 v2(87.25,20.3)
  BOTTOM w0.076: v2(97.12,84.05) 97.31,84.05 UC1.AF71
  BOTTOM w0.102: JDIMM2.7 88.22,21.27 v2(87.25,20.3)
DDR_B_D13: length 88.9
  IN2 w0.127: v2(96.49,84.18) 96.49,84.42 96.2,84.7 90.43,84.7 81.1,75.37 81.1,63.79 81.34,63.55 81.34,43.65 82.74,42.24 82.74,42.06 82.62,41.94 82.1,41.94 81.97,41.81 81.97,41.56 82.1,41.43 82.82,41.43 82.95,41.3 82.95,41.05 82.82,40.92 82.16,40.92 82.04,40.79 82.04,39.8 82.21,39.62 82.82,39.62 82.95,39.5 82.95,39.23 82.82,39.1 82.16,39.1 82.04,38.98 82.04,38.72 82.16,38.6 82.82,38.6 82.95,38.47 82.95,38.22 82.82,38.09 82.23,38.09 82.1,37.96 82.1,37.71 82.23,37.58 82.82,37.58 82.95,37.45 82.95,37.2 82.82,37.07 82.37,37.07 82.24,36.95 82.24,36.69 82.8,36.13 82.8,26.02 v2(87.25,21.57)
  BOTTOM w0.076: v2(96.49,84.18) 96.49,84.11 96.92,83.67 97.27,83.67 97.68,83.26 97.94,83.26 98.03,83.3 98.04,83.3 98.29,83.3 98.38,83.26 98.59,83.26 98.77,83.33 99.03,83.33 UC1.AF69
  BOTTOM w0.102: JDIMM2.3 87.22,21.59 v2(87.25,21.57)
DDR_B_D14: length 87.4
  IN2 w0.127: v2(96,81.74) 96,81.75 95.05,82.7 90.94,82.7 82.95,74.71 82.95,64.46 83.33,64.07 83.33,44.91 85.67,42.57 85.67,35.09 85.1,34.52 85.1,31.79 86.52,30.37 86.52,28.71 86.39,28.58 85.68,28.58 85.55,28.45 85.55,28.2 85.68,28.07 86.41,28.07 86.53,27.95 86.53,27.69 86.41,27.56 85.68,27.56 85.55,27.44 85.55,27.18 85.68,27.06 86.47,27.06 86.6,26.93 86.6,26.68 86.47,26.55 85.68,26.55 85.55,26.42 85.55,26.17 85.68,26.04 86.39,26.04 86.52,25.91 86.52,25.08 90.04,21.56 90.04,19.35 90.37,19.02 v2(91.07,19.02)
  BOTTOM w0.076: v2(96,81.74) 96.38,82.11 97.47,82.11 97.6,81.99 97.65,81.94 97.94,81.94 98.19,82.06 98.19,82.06 98.2,82.06 98.34,82.2 UC1.AH70
  BOTTOM w0.102: JDIMM2.16 90.48,18.43 v2(91.07,19.02)
DDR_B_D15: length 88.2
  IN2 w0.127: v2(91.07,21.56) 88.35,24.28 88.35,24.54 88.48,24.66 89.08,24.66 89.21,24.79 89.21,25.04 89.08,25.17 88.48,25.17 88.35,25.3 88.35,25.55 88.48,25.68 89.08,25.68 89.21,25.81 89.21,26.06 89.08,26.19 88.48,26.19 88.35,26.31 88.35,26.57 88.48,26.69 89.08,26.69 89.21,26.82 89.21,27.08 89.08,27.2 88.48,27.2 88.35,27.33 88.35,27.58 88.48,27.71 89.08,27.71 89.21,27.84 89.21,28.09 89.08,28.22 88.48,28.22 88.35,28.35 88.35,29.75 87.43,30.67 87.43,31.57 87.31,31.7 86.92,31.7 86.8,31.83 86.8,32.08 86.92,32.21 87.18,32.21 87.43,32.46 87.43,38.34 87.23,38.54 86.8,38.54 86.67,38.67 86.67,38.92 86.8,39.04 87.24,39.04 87.37,39.17 87.37,39.53 87.24,39.66 86.54,39.66 86.42,39.78 86.42,41.05 86.54,41.18 87.24,41.18 87.37,41.31 87.37,41.85 87.15,42.07 86.58,42.07 86.36,42.29 86.36,42.86 84.02,45.2 84.02,64.36 83.63,64.74 83.63,74.42 91.19,81.98 94.56,81.98 95.23,81.31 96.26,81.31 v2(96.58,81.63)
  BOTTOM w0.076: UC1.AH69 98.93,82.2 98.54,81.81 98.05,81.81 97.98,81.77 97.58,81.77 97.53,81.83 97.4,81.95 96.9,81.95 v2(96.58,81.63)
  BOTTOM w0.102: v2(91.07,21.56) 90.72,21.91 JDIMM2.17
DDR_B_D16: length 71.3
  IN2 w0.076: v2(100.6,77.47) 100.32,77.2 99.85,77.2 99.28,76.62 99.28,75.6 96.93,73.25 96.35,73.25 95.94,72.83
  IN2 w0.127: 95.94,72.83 94.96,71.86 94.96,69.1 90.34,64.48 90.34,50.36 95.14,45.55 95.14,39.38 96.77,37.75 96.77,32.09 96.88,31.98 96.88,25.46 98.74,23.6 98.74,20.55 98.95,20.34 v2(99.2,20.34)
  BOTTOM w0.089: v2(100.6,77.47) 100.95,77.82 UC1.AT66
  BOTTOM w0.102: JDIMM2.45 97.72,23.38 98.28,22.82 98.28,21.26 v2(99.2,20.34)
DDR_B_D17: length 70.7
  IN2 w0.076: 95.4,70.39 95.43,70.42 95.43,71.66 96.36,72.59 96.74,72.59 100.07,75.93 100.07,76.76 100.15,76.84 v2(100.6,76.84)
  IN2 w0.127: 95.4,70.39 95.4,69.06 90.93,64.58 90.93,50.26 95.48,45.7 95.48,39.52 97.22,37.78 97.22,37.39 97.35,37.26 97.49,37.26 97.61,37.14 97.61,36.88 97.49,36.76 97.35,36.76 97.22,36.63 97.22,31.82 97.35,31.69 97.58,31.69 97.7,31.56 97.7,31.31 97.58,31.18 97.35,31.18 97.22,31.05 97.22,27.33 97.51,27.04 97.98,27.04 98.11,26.91 98.11,26.66 97.98,26.53 97.51,26.53 97.39,26.4 97.39,25.73 99.2,23.91 v2(99.2,21.61)
  BOTTOM w0.089: v2(100.6,76.84) UC1.AU66
  BOTTOM w0.102: JDIMM2.49 98.72,23.68 98.83,23.57 99.2,23.57 99.3,23.47 99.3,23.24 99.2,23.14 98.7,23.14 98.6,23.04 98.6,22.84 98.7,22.74 99.2,22.74 99.3,22.63 99.3,22.26 99.2,22.16 v2(99.2,21.61)
DDR_B_D18: length 73.5
  IN2 w0.076: v2(101.51,79.38) 101.89,79 101.89,77.97 101.39,77.46 101.39,74.67 100.87,74.15 99.1,74.15 96.96,72.01 96.51,72.01 96.08,71.58
  IN2 w0.127: 96.08,71.58 96.08,67.67 92.51,64.09 92.51,50.7 97.08,46.13 97.08,40.13 99.14,38.07 99.14,28.11 99.74,27.51 99.74,25.4 100.63,24.51 100.63,21.92 101.32,21.23 101.32,17.9 101.42,17.8 v2(102.28,17.8)
  BOTTOM w0.089: UC1.AP65 101.77,79.12 v2(101.51,79.38)
  BOTTOM w0.102: v2(102.28,17.8) 101.97,17.5 JDIMM2.62
DDR_B_D19: length 74.7
  IN2 w0.076: 96.3,68.48 96.3,71.56 96.56,71.82 97.08,71.82 99.1,73.84 100.79,73.84 101.55,74.6 101.55,77.39 102.06,77.9 102.06,80.06 101.93,80.19 101.64,80.19 101.51,80.06 v2(101.51,80.01)
  IN2 w0.127: 96.3,68.48 96.3,67.4 92.86,63.95 92.86,50.84 98.48,45.22 98.48,39.21 99.48,38.21 99.48,28.25 100.2,27.54 100.2,25.43 100.98,24.65 100.98,22.06 101.81,21.23 101.81,20.81 v2(102.28,20.34)
  BOTTOM w0.089: UC1.AN65 101.76,79.77 v2(101.51,80.01)
  BOTTOM w0.102: JDIMM2.59 101.22,22.83 101.68,22.37 101.68,20.93 v2(102.28,20.34)
DDR_B_D20: length 73.2
  IN2 w0.076: 97.7,74.66 98.58,75.54 98.58,76.53 100.03,77.98 100.03,78.38 100.15,78.51 100.15,78.86 v2(100.62,79.33)
  IN2 w0.127: v2(99.2,17.8) 98.43,17.8 98.06,18.17 98.06,23.32 95.7,25.68 95.7,27.21 95.88,27.4 95.88,37.67 94.1,39.45 94.1,45.63 89.66,50.07 89.66,64.77 94.28,69.39 94.28,72.14 95.8,73.66 95.92,73.66 96.91,74.66 97.7,74.66
  BOTTOM w0.089: UC1.AN66 100.62,79.34 v2(100.62,79.33)
  BOTTOM w0.102: JDIMM2.50 98.97,17.57 v2(99.2,17.8)
DDR_B_D21: length 73.1
  IN2 w0.076: 97.15,73.82 97.36,74.03 97.36,74.03 98.74,75.41 98.74,76.46 100.23,77.95 100.23,78.35 100.6,78.71 v2(100.6,78.73)
  IN2 w0.127: 97.15,73.82 96.92,73.59 96.21,73.59 94.62,72 94.62,69.25 90,64.62 90,50.21 94.8,45.41 94.8,39.23 96.26,37.77 96.26,31.33 96.53,31.06 96.53,25.32 98.4,23.46 98.4,18.7 98.53,18.58 98.75,18.58 99.2,19.03 v2(99.2,19.07)
  BOTTOM w0.089: UC1.AP66 101.06,79.11 v2(100.6,78.73)
  BOTTOM w0.102: JDIMM2.46 97.97,17.84 v2(99.2,19.07)
DDR_B_D22: length 72.3
  IN2 w0.076: 96.82,68.3 97.09,68.57 97.09,71.19 97.17,71.27 97.17,71.67 99.17,73.67 101.35,73.67 101.72,74.04 101.72,77.32 102.43,78.04 v2(102.43,78.11)
  IN2 w0.127: v2(102.28,21.61) 102.07,21.61 101.95,21.73 101.95,22.2 101.82,22.33 101.45,22.33 101.32,22.46 101.32,22.71 101.45,22.84 101.82,22.84 101.95,22.97 101.95,23.22 101.82,23.35 101.45,23.35 101.32,23.47 101.32,23.73 101.45,23.85 101.82,23.85 101.95,23.98 101.95,24.76 101.29,25.41 101.29,25.67 101.17,25.79 100.67,25.79 100.54,25.92 100.54,26.17 100.67,26.3 101.17,26.3 101.29,26.43 101.29,26.93 99.82,28.39 99.82,38.36 98.82,39.36 98.82,45.36 93.2,50.98 93.2,63.81 96.82,67.43 96.82,68.3
  BOTTOM w0.089: UC1.AT65 102.26,78.11 v2(102.43,78.11)
  BOTTOM w0.102: v2(102.28,21.61) 102.22,21.66 JDIMM2.63
DDR_B_D23: length 71.3
  IN2 w0.076: v2(102.34,76.83) 102.34,76.71 102.21,76.58 102.21,73.94 101.77,73.5 100.28,73.5 99.72,72.94 99.07,72.94 97.26,71.12 97.26,68.35 97.04,68.13
  IN2 w0.127: 97.04,68.13 97.04,67.16 93.54,63.67 93.54,51.13 99.18,45.49 99.18,39.49 100.17,38.5 100.17,28.54 101.68,27.02 101.68,25.51 102.29,24.9 102.29,22.92 102.99,22.22 102.99,20.13 103.31,19.81 103.31,19.18 103.19,19.07 v2(102.28,19.07)
  BOTTOM w0.089: UC1.AU65 102.01,77.17 102.34,76.84 v2(102.34,76.83)
  BOTTOM w0.102: JDIMM2.58 100.97,17.77 v2(102.28,19.07)
DDR_B_D24: length 73.6
  IN2 w0.076: v2(103.36,77.41) 103.07,77.13 103.07,76.39 102.79,76.11 102.79,74.61 103.15,74.25 103.15,73.37 102.14,72.36 99.2,72.36 97.91,71.07 97.91,68.52
  IN2 w0.127: 97.91,68.52 98.06,68.37 98.06,66.31 94.91,63.17 94.91,51.62 100.85,45.68 100.85,39.93 101.52,39.26 101.52,31.59 102,31.12 102,28.7 102.65,28.04 102.93,28.04 103.69,27.28 103.69,25.63 103.82,25.51 104.31,25.51 104.44,25.38 104.44,23.96 104.31,23.83 103.74,23.83 103.61,23.71 103.61,23.53 103.74,23.4 104.24,23.4 104.44,23.2 104.44,22.76 104.87,22.33 104.87,21.8 104.75,21.67 v2(104.42,21.67)
  BOTTOM w0.089: UC1.AT61 103.77,77.82 v2(103.36,77.41)
  BOTTOM w0.102: v2(104.42,21.67) 104.22,21.87 104.22,22.48 104.39,22.65 105.38,22.65 105.54,22.81 105.54,23.13 105.38,23.3 104.39,23.3 104.22,23.46 JDIMM2.71
DDR_B_D25: length 72.4
  IN2 w0.076: 98.82,67.46 98.82,68.1 98.53,68.39 98.42,68.39 98.07,68.74 98.07,71 99.27,72.2 102.21,72.2 103.31,73.3 103.31,74.46 103.02,74.75 103.02,75.94 103.44,76.36 v2(103.44,76.82)
  IN2 w0.127: v2(104.42,19.13) 104.95,19.66 104.95,21.39 105.22,21.66 105.22,22.47 104.78,22.9 104.78,26.67 103.07,28.38 102.79,28.38 102.34,28.84 102.34,31.27 101.87,31.74 101.87,39.4 101.19,40.08 101.19,45.83 95.37,51.65 95.37,63.14 98.35,66.12 98.35,66.58 98.82,67.05 98.82,67.46
  BOTTOM w0.089: UC1.AU61 103.8,77.06 103.56,76.82 v2(103.44,76.82)
  BOTTOM w0.102: v2(104.42,19.13) 103.82,19.13 103.4,18.72 103.4,17.69 102.97,17.26 JDIMM2.66
DDR_B_D26: length 75.7
  IN2 w0.076: v2(104.26,79.38) 104.64,79 104.64,77.81 104.67,77.77 104.67,77.27 105.26,76.68 105.26,73.4 104.65,72.79 104.36,72.79 102.66,71.08 102.07,71.08 101.34,70.36 101.34,70.18
  IN2 w0.127: 101.34,70.18 101.34,66.99 99.63,65.28 99.63,64.33 98.1,62.8 98.1,57.54 97.97,57.41 97.64,57.41 97.51,57.29 97.51,57.03 97.64,56.9 97.97,56.9 98.1,56.78 98.1,56.52 97.97,56.4 97.64,56.4 97.51,56.27 97.51,56.02 97.64,55.89 97.97,55.89 98.1,55.76 98.1,55.51 97.97,55.38 97.64,55.38 97.51,55.25 97.51,55 97.64,54.87 97.97,54.87 98.1,54.75 98.1,51.92 103.32,46.71 103.32,41.78 104.77,40.32 104.77,30.82 106.38,29.21 107.16,28.42 107.16,27.36 107.95,26.57 107.95,25.05 108.32,24.68 108.32,20.6 108.09,20.37 v2(107.79,20.37)
  BOTTOM w0.089: UC1.AP60 104.51,79.12 v2(104.26,79.38)
  BOTTOM w0.102: v2(107.79,20.37) 106.22,21.93 JDIMM2.79
DDR_B_D27: length 75.7
  IN2 w0.076: v2(104.26,80.03) 104.8,79.49 104.8,77.88 104.84,77.84 104.84,77.33 105.42,76.75 105.42,73.33 104.72,72.62 104.59,72.62 102.88,70.92 102.14,70.92 101.59,70.37 101.59,69.03
  IN2 w0.127: v2(107.79,17.83) 108.17,17.83 108.98,18.63 109.34,18.63 109.81,18.16 110.23,18.16 110.55,18.48 110.55,18.72 108.67,20.6 108.67,24.83 108.3,25.19 108.3,26.71 107.51,27.5 107.51,28.56 106.72,29.35 105.11,30.96 105.11,40.49 103.66,41.94 103.66,46.85 98.67,51.83 98.67,62.81 99.97,64.11 99.97,65.06 101.59,66.67 101.59,69.02 101.59,69.03
  BOTTOM w0.089: v2(104.26,80.03) 104.51,79.77 UC1.AN60
  BOTTOM w0.102: JDIMM2.84 107.48,17.51 v2(107.79,17.83)
DDR_B_D28: length 75
  IN2 w0.076: v2(103.34,79.38) 102.87,79.38 102.8,79.3 102.8,77.33 102.74,77.27 102.74,76.53 102.38,76.16 102.38,74.22 102.63,73.97 102.63,73.31 102.07,72.76 99.13,72.76 97.42,71.05 97.42,68.24 97.25,68.07
  IN2 w0.127: v2(104.42,17.86) 104.07,17.86 103.94,17.99 103.94,20.07 103.62,20.39 103.62,22.49 102.92,23.18 102.92,25.16 102.32,25.77 102.32,27.28 101.31,28.29 101.31,29.7 101.18,29.83 100.93,29.83 100.8,29.96 100.8,30.21 100.93,30.34 101.18,30.34 101.31,30.47 101.31,30.84 100.8,31.35 100.8,38.76 99.82,39.75 99.82,45.75 94.23,51.34 94.23,63.45 97.47,66.69 97.47,67.27 97.25,67.48 97.25,68.07
  BOTTOM w0.089: v2(103.34,79.38) 103.74,79.77 UC1.AN61
  BOTTOM w0.102: JDIMM2.70 103.97,17.41 v2(104.42,17.86)
DDR_B_D29: length 75.1
  IN2 w0.076: v2(103.34,78.74) 102.97,78.37 102.97,77.27 102.9,77.2 102.9,76.46 102.62,76.17 102.62,74.45 102.85,74.22 102.85,73.3 102.13,72.58 99.18,72.58 97.6,70.99 97.6,68.07
  IN2 w0.127: v2(104.42,20.4) 104.1,20.4 103.97,20.53 103.97,22.63 103.27,23.33 103.27,24.18 103.41,24.32 103.97,24.32 104.1,24.45 104.1,24.69 103.97,24.81 103.39,24.81 103.27,24.94 103.27,26.82 101.65,28.43 101.65,30.98 101.15,31.49 101.15,39.16 100.32,39.98 100.32,45.73 94.57,51.48 94.57,63.31 97.84,66.58 97.84,67.83 97.6,68.07
  BOTTOM w0.089: v2(103.34,78.74) 103.72,79.12 UC1.AP61
  BOTTOM w0.102: v2(104.42,20.4) 103.58,21.24 103.58,22.88 103.22,23.24 JDIMM2.67
DDR_B_D30: length 74.9
  IN2 w0.076: v2(104.31,77.52) 104.31,77.4 104.94,76.77 104.94,73.31 104.58,72.96 104.25,72.96 102.54,71.25 100.96,71.25 100.32,70.61 100.32,68.2
  IN2 w0.127: 100.32,68.2 100.32,66.78 99.29,65.74 99.29,64.47 97.68,62.87 97.68,58.2 97.15,57.66 97.15,54.53 97.28,54.4 97.63,54.4 97.76,54.28 97.76,54.02 97.63,53.89 97.28,53.89 97.15,53.77 97.15,53.51 97.28,53.39 97.63,53.39 97.76,53.26 97.76,53.01 97.63,52.88 97.28,52.88 97.15,52.75 97.15,52.39 102.97,46.56 102.97,41.1 103.85,40.22 103.85,39.09 103.98,38.96 104.3,38.96 104.42,38.83 104.42,38.58 104.3,38.45 103.98,38.45 103.85,38.33 103.85,38.07 103.98,37.94 104.3,37.94 104.42,37.82 104.42,37.56 104.3,37.44 103.98,37.44 103.85,37.31 103.85,32.27 104.42,31.7 104.42,30.68 106.82,28.28 106.82,27.22 107.61,26.43 107.61,24.91 107.79,24.73 107.79,23.88 107.66,23.76 107.22,23.76 107.09,23.63 107.09,23.25 107.22,23.12 107.66,23.12 107.79,22.99 v2(107.79,21.64)
  BOTTOM w0.089: UC1.AT60 104.61,77.82 104.31,77.52 v2(104.31,77.52)
  BOTTOM w0.102: v2(107.79,21.64) 107.55,21.87 106.87,21.87 106.64,22.1 106.64,22.4 106.88,22.64 107.51,22.64 107.64,22.76 107.64,23.21 107.22,23.62 JDIMM2.83
DDR_B_D31: length 74.3
  IN2 w0.076: 99.92,68.2 99.92,71.16 100.17,71.41 102.38,71.41 104.16,73.2 104.16,74.14 104.49,74.46 104.49,76.68 104.37,76.8 v2(104.37,76.8)
  IN2 w0.127: 99.92,68.2 99.92,66.98 98.95,66 98.95,64.62 97.34,63.01 97.34,62.4 97.21,62.28 96.93,62.28 96.81,62.15 96.81,61.89 96.93,61.77 97.21,61.77 97.34,61.64 97.34,61.39 97.21,61.26 96.93,61.26 96.81,61.13 96.81,60.88 96.93,60.75 97.21,60.75 97.34,60.62 97.34,60.37 97.21,60.24 96.93,60.24 96.81,60.12 96.81,59.86 96.93,59.74 97.21,59.74 97.34,59.61 97.34,59.35 97.21,59.23 96.93,59.23 96.81,59.1 96.81,58.85 96.93,58.72 97.21,58.72 97.34,58.59 97.34,58.34 96.81,57.8 96.81,52.25 102.63,46.42 102.63,40.96 103.51,40.08 103.51,32.13 104.08,31.55 104.08,30.53 106.48,28.14 106.48,26.99 106.75,26.72 106.75,25.77 106.62,25.64 106.34,25.64 106.22,25.52 106.22,25.26 106.34,25.14 106.62,25.14 106.75,25.01 106.75,23.11 107.1,22.75 107.1,20 107.1,20 107.1,19.78 v2(107.79,19.1)
  BOTTOM w0.089: v2(104.37,76.8) 104.71,77.14 UC1.AU60
  BOTTOM w0.102: v2(107.79,19.1) 106.48,17.78 JDIMM2.80
DDR_B_D32: length 71.4
  IN2 w0.076: 120.63,65.04 118.61,67.06 118.42,67.06 118.14,67.33 118.14,73.62 116.05,75.71 116.05,75.97 115.23,76.79 v2(115.23,76.84)
  IN2 w0.127: v2(132.36,21.54) 132.29,21.54 131.92,21.91 131.92,23.37 132.92,24.37 132.92,31.88 133.07,32.02 133.07,37.56 132.94,37.69 132.26,37.69 132.14,37.82 132.14,38.07 132.26,38.2 132.94,38.2 133.07,38.33 133.07,38.58 132.94,38.71 132.05,38.71 131.92,38.83 131.92,39.9 132.05,40.03 132.94,40.03 133.07,40.15 133.07,45.38 121.72,56.72 121.72,62.62 120.63,63.71 120.63,65.04
  BOTTOM w0.089: v2(115.23,76.84) UC1.AU40
  BOTTOM w0.102: v2(132.36,21.54) 130.72,23.12 JDIMM2.169
DDR_B_D33: length 71.8
  IN2 w0.076: 120.17,65.89 118.77,67.3 118.5,67.3 118.31,67.49 118.31,73.69 116.31,75.69 116.31,76.15 115.78,76.68 115.78,77.34 115.57,77.55 115.3,77.55 v2(115.23,77.47)
  IN2 w0.127: 120.17,65.89 120.97,65.09 120.97,63.86 122.07,62.76 122.07,56.87 133.41,45.52 133.41,39.81 133.28,39.68 132.52,39.68 132.39,39.56 132.39,39.3 132.52,39.18 133.28,39.18 133.41,39.05 133.41,31.88 133.27,31.74 133.27,27.24 133.41,27.11 134.06,27.11 134.19,26.98 134.19,26.56 134.08,26.45 133.39,26.45 133.27,26.33 133.27,25.67 133.39,25.54 133.98,25.54 134.11,25.41 134.11,25.04 133.98,24.91 133.39,24.91 133.27,24.78 133.27,24.23 132.36,23.32 v2(132.36,22.81)
  BOTTOM w0.076: UC1.AT40 115.7,77.82 115.78,77.74 115.78,77.54 115.71,77.46 115.57,77.46 115.49,77.39 115.27,77.39 115.23,77.43 v2(115.23,77.47)
  BOTTOM w0.102: v2(132.36,22.81) 132.06,22.57 131.86,22.57 131.32,23.11 131.32,23.4 131.72,23.8 JDIMM2.173
DDR_B_D34: length 72.6
  IN2 w0.076: 121.49,71.11 121.49,71.4 119.85,73.04 119.85,73.26 117.43,75.68 117.43,76.98 117.06,77.35 v2(117.06,77.47)
  IN2 w0.127: 121.49,71.11 121.49,66.17 122.59,65.07 122.67,65.07 123.42,64.32 123.42,64.22 123.85,63.8 123.85,57.6 135.19,46.26 135.19,42.16 135.97,41.38 135.97,30.3 136.48,29.79 136.48,27.43 136.98,26.93 136.98,25.8 136.97,25.79 136.97,24.56 136.85,24.43 136.09,24.43 135.97,24.3 135.97,24.05 136.09,23.92 136.85,23.92 136.97,23.79 136.97,23.54 136.85,23.41 136.25,23.41 136.13,23.29 136.13,23.03 136.25,22.9 136.85,22.9 136.97,22.78 136.97,22.48 136.03,21.54 v2(135.59,21.54)
  BOTTOM w0.089: v2(117.06,77.47) UC1.AT37
  BOTTOM w0.102: JDIMM2.183 134.23,23.87 134.66,23.43 134.66,22.26 135.12,21.8 135.33,21.8 v2(135.59,21.54)
DDR_B_D35: length 72.4
  IN2 w0.076: 121.13,70.95 121.13,71.52 119.69,72.97 119.69,73.19 116.86,76.02 116.86,76.75 116.93,76.82 v2(117.06,76.82)
  IN2 w0.127: 121.13,70.95 121.13,66.04 122.66,64.52 122.74,64.52 123.08,64.17 123.08,64.08 123.5,63.66 123.5,57.46 134.85,46.11 134.85,42.02 135.63,41.24 135.63,37.67 135.5,37.55 135.25,37.55 135.12,37.42 135.12,37.17 135.25,37.04 135.5,37.04 135.63,36.91 135.63,30.16 136.13,29.65 136.13,28.7 135.62,28.19 135.62,27.09 135.81,26.9 136.52,26.9 136.63,26.79 136.63,26.51 136.54,26.42 135.83,26.42 135.62,26.21 135.62,25.66 135.83,25.45 136.5,25.45 136.63,25.33 136.63,25.07 136.5,24.94 135.75,24.94 135.62,24.82 135.62,24.02 134.91,23.31 134.91,22.94 135.03,22.81 v2(135.59,22.81)
  BOTTOM w0.076: v2(117.06,76.82) 117.04,76.71 117.13,76.59 118.02,76.59 118.15,76.72 118.15,76.86 117.9,77.11 117.78,77.11 117.69,77.24 117.59,77.24 UC1.AU37
  BOTTOM w0.102: v2(135.59,22.81) 135.59,22.77 135.45,22.64 135.22,22.64 134.98,22.88 134.98,23.62 135.23,23.87 JDIMM2.187
DDR_B_D36: length 72.9
  IN2 w0.076: v2(115.23,78.11) 114.85,77.73 114.85,76.13 115.67,75.31 116.01,75.31 117.91,73.4 117.91,67.18 118.36,66.74 118.63,66.74 119.11,66.26 119.11,66.11 120.28,64.94 120.28,64.77
  IN2 w0.127: 120.28,64.77 120.28,63.57 121.38,62.48 121.38,56.58 132.73,45.24 132.73,40.5 132.6,40.37 131.71,40.37 131.58,40.24 131.58,35.67 132.22,35.03 132.22,33.17 132.58,32.81 132.58,24.51 131.58,23.51 131.58,21.73 131.84,21.47 131.84,20.72 132.29,20.27 v2(132.36,20.27)
  BOTTOM w0.089: v2(115.23,78.11) UC1.AR40
  BOTTOM w0.102: v2(132.36,20.27) 130.98,18.95 130.98,16.46 JDIMM2.170
DDR_B_D37: length 73.4
  IN2 w0.076: v2(115.23,78.74) 114.69,78.2 114.69,75.94 115.63,75.01 116,75.01 117.62,73.39 117.62,66.7 118.73,65.6 119.25,65.6 119.94,64.9 119.94,64.77
  IN2 w0.127: v2(132.36,19) 132.3,19.05 131.88,19.47 131.88,20.2 131.5,20.58 131.5,21.33 131.24,21.59 131.24,23.65 132.24,24.66 132.24,32.67 131.88,33.03 131.88,34.89 131.24,35.53 131.24,40.59 131.36,40.71 132.26,40.71 132.38,40.84 132.38,45.09 121.04,56.44 121.04,62.33 119.94,63.43 119.94,64.77
  BOTTOM w0.089: v2(115.23,78.74) UC1.AP40
  BOTTOM w0.102: JDIMM2.174 131.97,18.68 v2(132.36,19)
DDR_B_D38: length 74.2
  IN2 w0.076: v2(117.06,78.74) 117.39,78.3 117.6,77.9 117.6,77.39 117.7,77.17 117.78,77.09 117.98,76.53 118.53,75.98 118.53,75.17 120.21,73.48 120.21,73.29 121.31,72.19 122.26,72.19 122.79,71.66 122.79,66.5 124.11,65.18 124.11,64.77
  IN2 w0.127: v2(135.59,19) 137.04,19 137.66,19.62 137.66,25.13 137.66,25.13 137.66,27.22 137.16,27.72 137.16,33.98 137.69,34.51 137.69,40.93 135.88,42.74 135.88,46.54 124.53,57.89 124.53,64.08 124.11,64.51 124.11,64.77
  BOTTOM w0.089: v2(117.06,78.74) UC1.AP37
  BOTTOM w0.102: v2(135.59,19) 134.98,18.39 134.98,16.46 JDIMM2.186
DDR_B_D39: length 73.9
  IN2 w0.076: v2(117.06,78.11) 117.43,77.74 117.43,77.21 117.61,77.02 117.61,75.84 120.04,73.42 120.04,73.41 120.04,73.15 121.87,71.32
  IN2 w0.127: v2(135.59,20.27) 137.32,22 137.32,25.65 137.32,25.65 137.32,27.07 136.82,27.57 136.82,34.13 137.34,34.65 137.34,37.44 137.22,37.57 136.58,37.57 136.45,37.7 136.45,37.95 136.58,38.08 137.22,38.08 137.34,38.21 137.34,40.79 135.53,42.6 135.53,46.4 124.19,57.74 124.19,63.94 123.77,64.36 123.77,65.08 121.87,66.97 121.87,71.32
  BOTTOM w0.089: v2(117.06,78.11) UC1.AR37
  BOTTOM w0.102: JDIMM2.182 133.98,16.46 133.98,18.66 v2(135.59,20.27)
DDR_B_D40: length 75.7
  IN2 w0.076: v2(118.89,77.47) 118.89,77.36 118.52,76.99 118.52,76.68 121.56,73.65 121.56,72.99 121.87,72.68 122.6,72.68 123.61,71.67 123.61,69.36 124.52,68.45 124.52,66.36 125.85,65.02 125.85,64.77
  IN2 w0.127: v2(138.13,20.27) 139.22,21.37 139.22,24.61 139.52,24.91 139.52,27.4 139.5,27.41 139.5,40.99 138.13,42.36 138.13,43.29 138.26,43.42 138.93,43.42 139.06,43.54 139.06,43.8 138.93,43.92 138.26,43.92 138.13,44.05 138.13,44.31 138.26,44.43 138.87,44.43 138.99,44.56 138.99,44.81 138.87,44.94 138.26,44.94 138.13,45.07 138.13,45.9 138,46.03 137.32,46.03 137.2,46.16 137.2,47.09 125.85,58.43 125.85,64.77
  BOTTOM w0.089: UC1.AT33 119.07,77.61 v2(118.89,77.47)
  BOTTOM w0.102: JDIMM2.190 135.97,18.12 v2(138.13,20.27)
DDR_B_D41: length 75
  IN2 w0.076: 125.48,65.97 125.48,66.03 124.96,66.55 124.96,68.42 124.38,69 124.38,71.46 124.14,71.7 123.82,71.7 122.67,72.85 121.94,72.85 121.72,73.06 121.72,73.71 118.89,76.55 v2(118.89,76.84)
  IN2 w0.127: v2(138.13,19) 138.13,18.48 138.26,18.35 139.06,18.35 139.19,18.48 139.19,20.53 139.57,20.91 139.57,24.31 139.86,24.6 139.86,29.42 139.85,29.44 139.85,42.42 139.72,42.55 138.93,42.55 138.8,42.68 138.8,42.93 138.93,43.06 139.72,43.06 139.85,43.19 139.85,44.93 126.2,58.58 126.2,65.26 125.48,65.97
  BOTTOM w0.089: v2(118.89,76.84) 119.07,76.97 UC1.AU33
  BOTTOM w0.102: JDIMM2.194 136.97,17.85 v2(138.13,19)
DDR_B_D42: length 74.1
  IN2 w0.076: 126.36,66.74 126.36,70.29 124.46,72.19 124.1,72.19 121.33,74.96 121.33,75.85 120.72,76.47 v2(120.72,76.84)
  IN2 w0.127: 126.36,66.74 128.44,64.66 128.44,58.36 141.89,44.91 141.89,37.86 142.01,37.73 142.49,37.73 142.61,37.61 142.61,37.35 142.49,37.23 142.01,37.23 141.89,37.1 141.89,36.56 142.49,35.96 142.49,33.15 142.36,33.02 142.01,33.02 141.89,32.89 141.89,32.64 142.01,32.51 142.49,32.51 142.61,32.38 142.61,32.13 142.49,32 142.01,32 141.89,31.88 141.89,31.62 142.01,31.5 142.49,31.5 142.61,31.37 142.61,31.11 142.49,30.99 141.98,30.99 141.86,30.86 141.86,30.61 141.98,30.48 142.36,30.48 142.49,30.35 142.49,29.42 141.99,28.92 141.99,24.4 141.29,23.71 141.29,22.82 v2(141.3,22.81)
  BOTTOM w0.076: UC1.AU30 121.17,77.17 121.65,77.1 121.78,76.96 121.75,76.71 121.63,76.59 120.81,76.59 120.7,76.74 v2(120.72,76.84)
  BOTTOM w0.102: v2(141.3,22.81) 141.3,22.79 141.11,22.57 140.02,22.57 139.9,22.7 139.9,23.46 140.23,23.79 JDIMM2.207
DDR_B_D43: length 75.3
  IN2 w0.076: v2(120.72,77.47) 120.72,77.36 121.2,76.88 121.2,76.22 121.5,75.92 121.5,75.03 124.17,72.36 124.53,72.36 126.57,70.31 126.57,67.34 127.22,66.69
  IN2 w0.127: 127.22,66.69 128.78,65.13 128.78,58.5 142.96,44.33 142.96,39.85 142.83,39.73 142.36,39.73 142.23,39.6 142.23,39.35 142.36,39.22 142.83,39.22 142.96,39.09 142.96,38.84 142.83,38.71 142.36,38.71 142.23,38.58 142.23,38.33 142.36,38.2 142.83,38.2 142.96,38.08 142.96,29.41 142.33,28.78 142.33,24.1 141.75,23.53 141.75,22 v2(141.3,21.54)
  BOTTOM w0.089: v2(120.72,77.47) UC1.AT30
  BOTTOM w0.102: JDIMM2.203 139.23,23.74 138.82,23.33 138.82,21.3 139.09,21.03 140.8,21.03 141.3,21.53 v2(141.3,21.54)
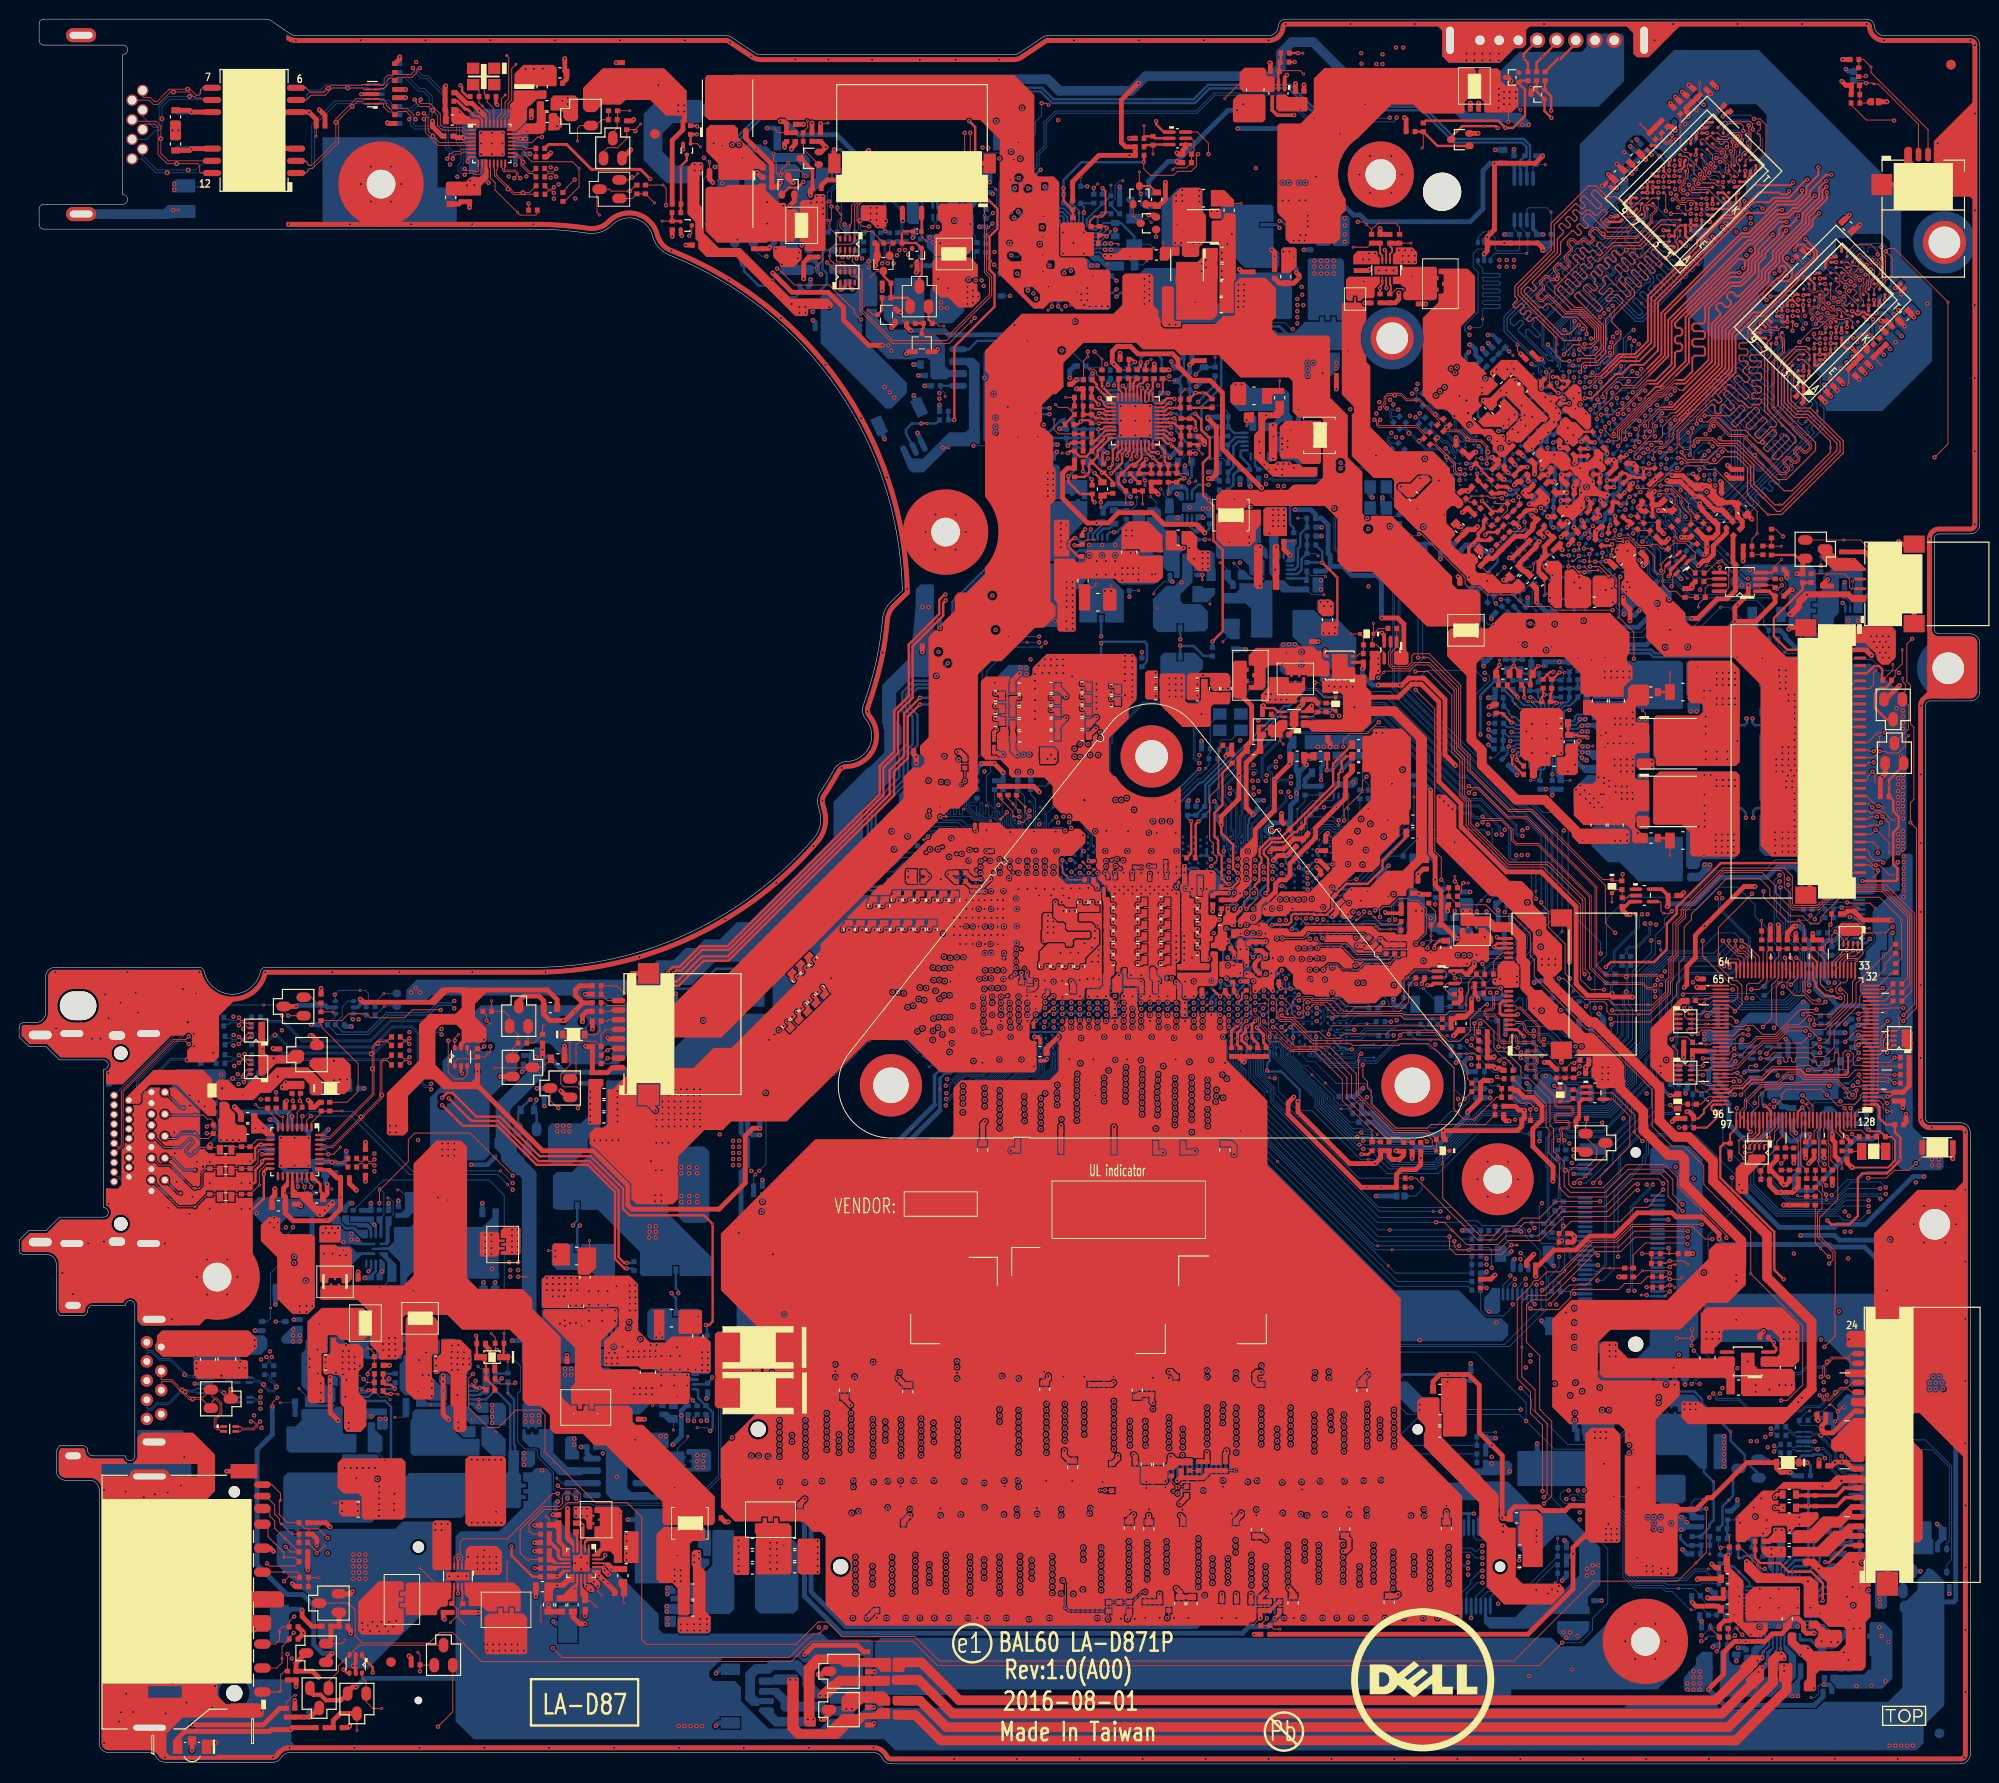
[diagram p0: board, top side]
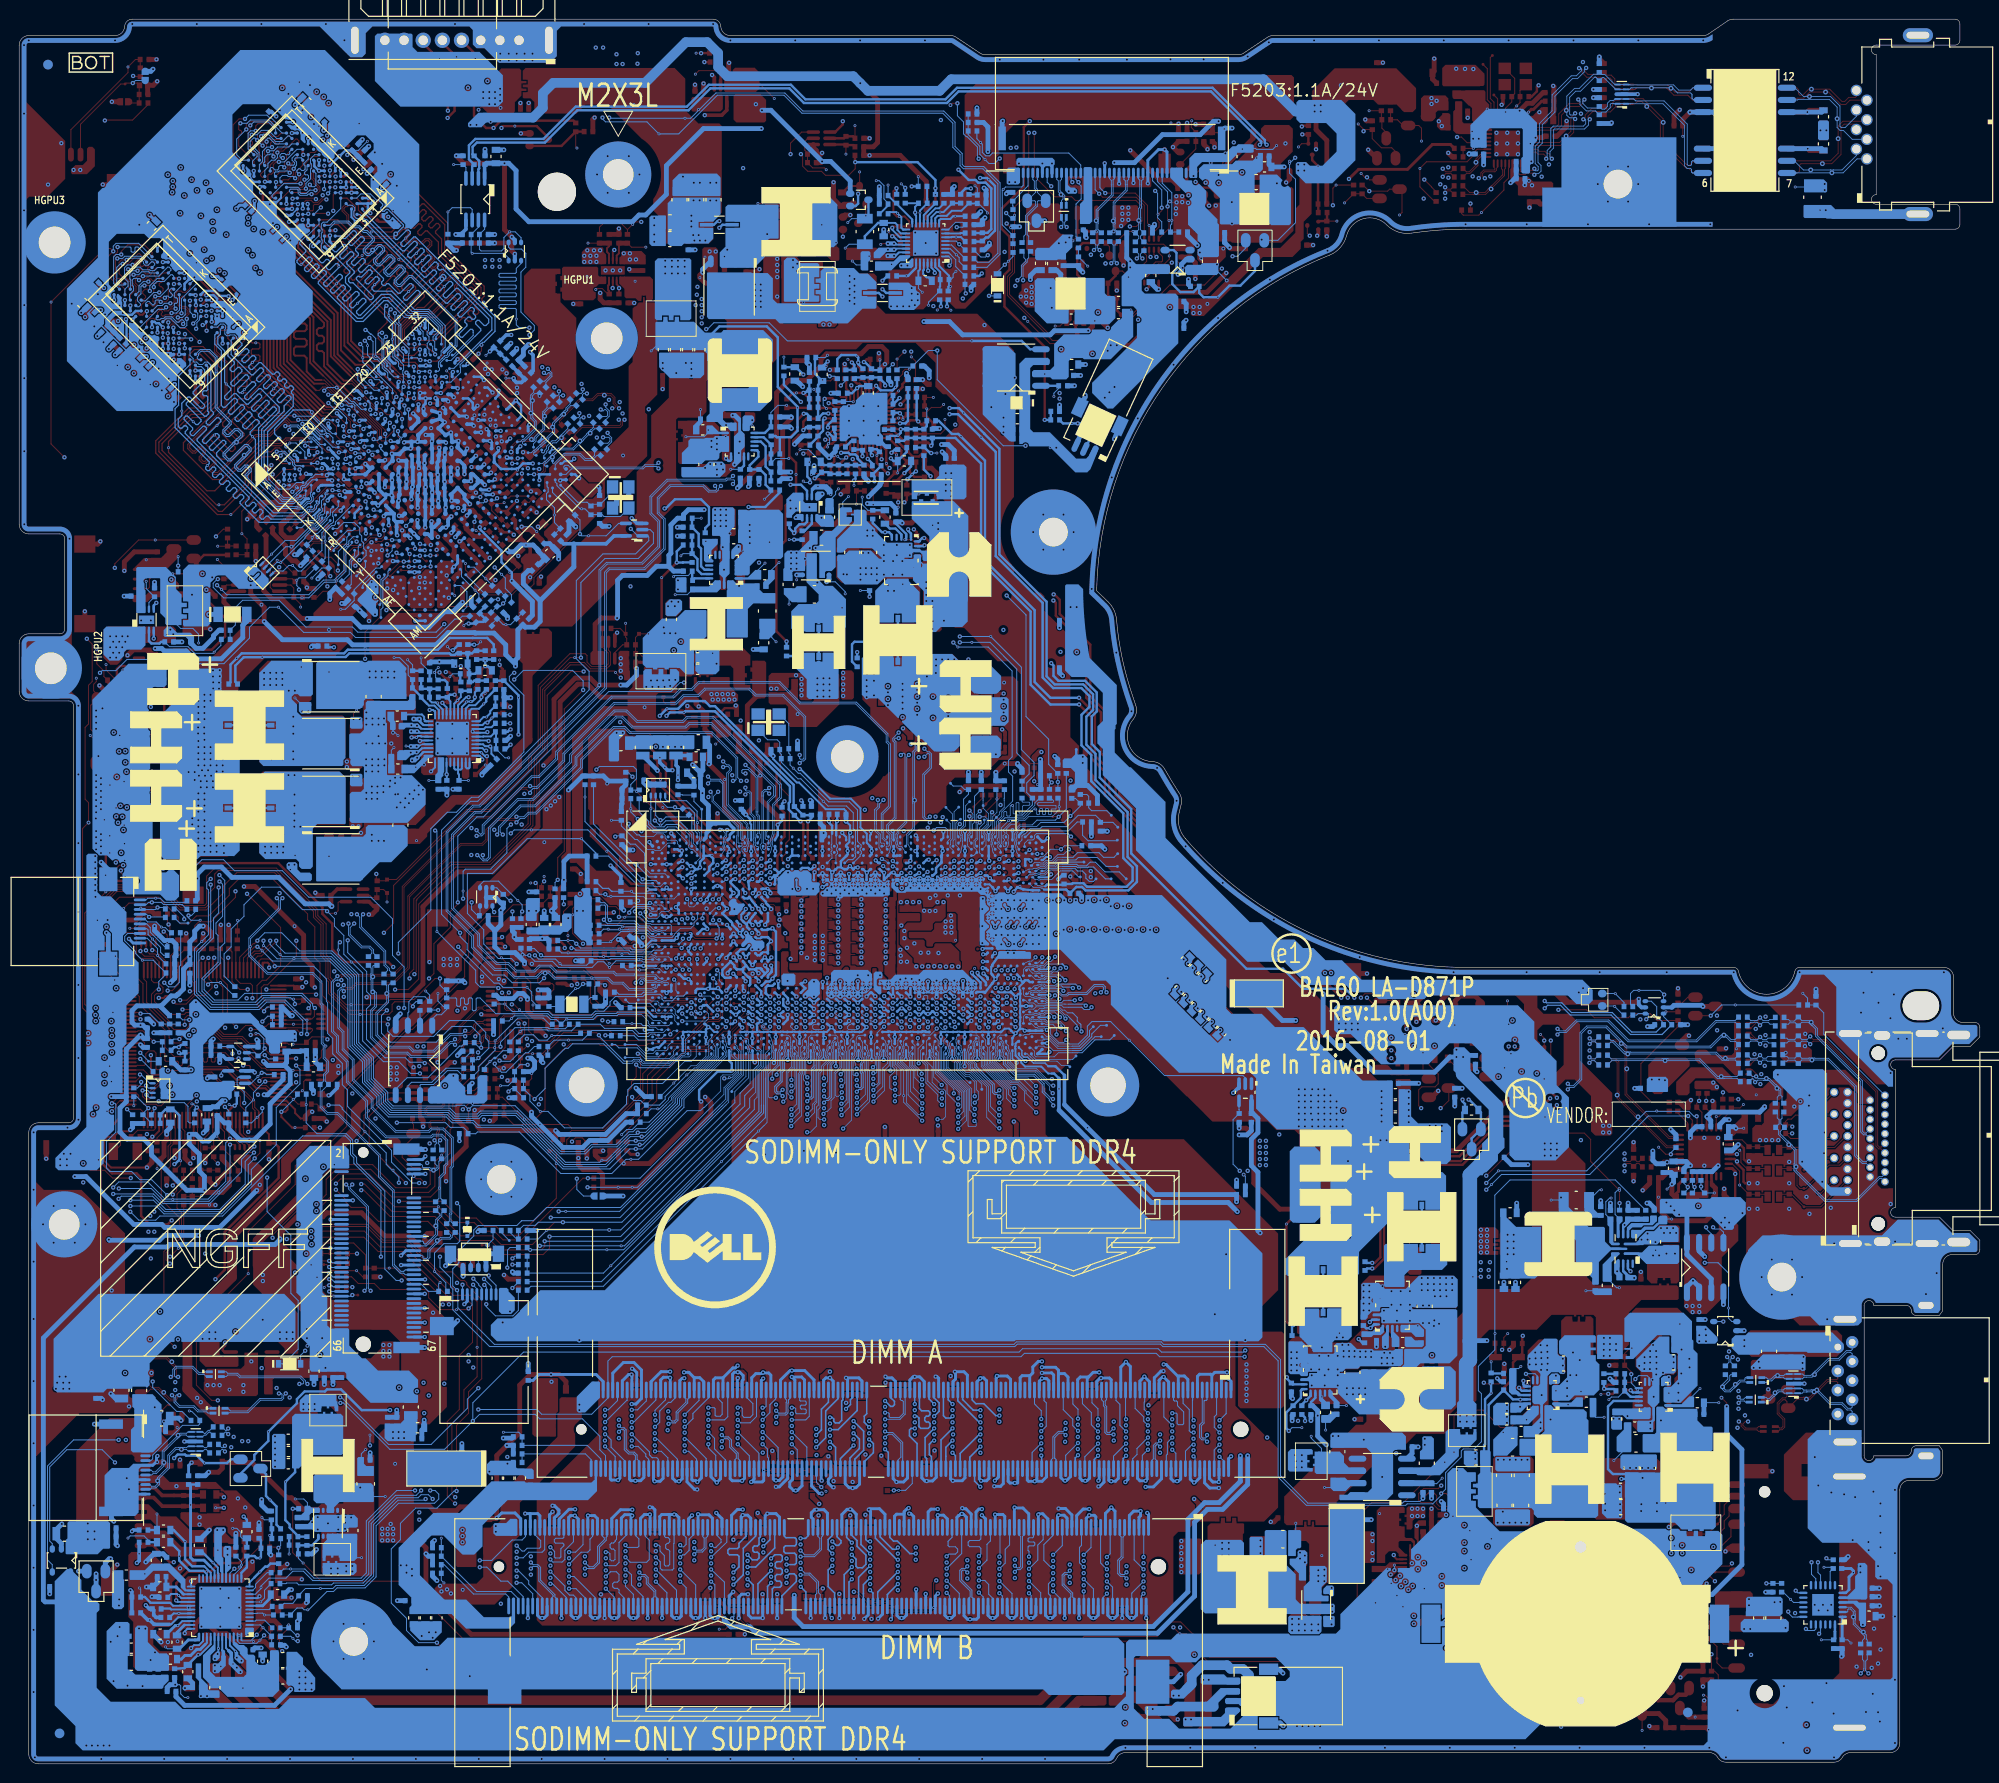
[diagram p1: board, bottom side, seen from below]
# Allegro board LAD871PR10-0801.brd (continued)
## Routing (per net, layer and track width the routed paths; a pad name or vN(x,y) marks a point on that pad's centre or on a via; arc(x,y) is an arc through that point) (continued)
DDR_B_D44: length 76.1
  IN2 w0.076: v2(118.89,78.11) 118.51,77.73 118.51,77.21 118.35,77.06 118.35,76.62 121.39,73.58 121.39,72.92 121.8,72.52 122.4,72.52 123.37,71.54 123.37,66.63 124.78,65.22
  IN2 w0.127: 124.78,65.22 125.51,64.49 125.51,58.29 136.85,46.95 136.85,44.17 136.98,44.04 137.66,44.04 137.79,43.91 137.79,43.66 137.66,43.53 136.98,43.53 136.85,43.4 136.85,43.15 139.16,40.84 139.16,27.27 139.17,27.25 139.17,25.21 138.72,24.75 138.72,21.91 138.35,21.54 v2(138.13,21.54)
  BOTTOM w0.076: UC1.AR33 119.41,78.47 119.48,78.38 119.47,78.29 119.09,77.99 118.96,78.01 v2(118.89,78.11)
  BOTTOM w0.102: v2(138.13,21.54) 138.13,21.53 137.66,21.06 137.66,20.4 137.48,20.22 136.4,20.22 136.26,20.36 136.26,22.99 136.23,23.03 JDIMM2.191
DDR_B_D45: length 77.5
  IN2 w0.076: 124.74,64.77 124.44,65.07 124.44,65.16 123.12,66.49 123.12,71.56 122.33,72.35 121.38,72.35 121.01,72.71 121.01,73.72 118.19,76.55 118.19,77.13 118.34,77.28 118.34,78.2 v2(118.89,78.74)
  IN2 w0.127: 124.74,64.77 125.17,64.35 125.17,58.15 136.51,46.8 136.51,43.01 138.82,40.7 138.82,30.79 138.55,30.52 137.92,30.52 137.8,30.4 137.8,30.14 137.92,30.01 138.55,30.01 138.67,29.89 138.67,28.74 138.55,28.61 137.92,28.61 137.8,28.49 137.8,28.23 137.92,28.11 138.55,28.11 138.67,27.98 138.67,27.27 138.3,26.9 138.3,22.98 v2(138.13,22.81)
  BOTTOM w0.076: v2(118.89,78.74) 118.89,78.74 119.18,78.71 119.23,78.76 119.36,78.76 119.45,78.86 119.45,79.05 119.38,79.12 UC1.AP33
  BOTTOM w0.102: JDIMM2.195 137.23,23.72 137.1,23.6 136.85,23.6 136.68,23.43 136.68,23.16 136.84,23 136.94,23 137.1,22.84 137.1,22.51 136.94,22.35 136.84,22.35 136.68,22.19 136.68,20.81 136.85,20.64 137.12,20.64 137.25,20.76 137.25,21.74 137.69,22.19 137.69,22.69 137.82,22.81 v2(138.13,22.81)
DDR_B_D46: length 75
  IN2 w0.076: 128.07,66.57 126.74,67.9 126.74,71.35 125.84,72.24 125.36,72.24 125.08,72.52 124.28,72.52 121.66,75.14 121.66,75.99 121.36,76.29 121.36,76.95 121.08,77.23 121.08,78.38 v2(120.72,78.74)
  IN2 w0.127: 128.07,66.57 129.13,65.51 129.13,58.64 143.3,44.47 143.3,37.63 143.86,37.07 143.86,29.82 142.67,28.63 142.67,23.8 142.1,23.22 142.1,21.07 v2(141.3,20.27)
  BOTTOM w0.089: v2(120.72,78.74) UC1.AR30
  BOTTOM w0.102: JDIMM2.204 139.47,17.46 140.67,18.66 140.67,19.73 v2(141.3,20.27)
DDR_B_D47: length 76
  IN2 w0.076: v2(120.72,79.38) 121.25,78.85 121.25,77.29 121.53,77.02 121.53,76.36 121.83,76.06 121.83,75.2 124.34,72.69 125.15,72.69 125.43,72.41 125.91,72.41 126.93,71.39 126.93,68.2 128.07,67.05
  IN2 w0.127: 128.07,67.05 129.47,65.66 129.47,58.79 143.64,44.61 143.64,37.77 144.2,37.22 144.2,29.68 143.01,28.49 143.01,23.49 142.67,23.15 142.67,19.42 142.25,19 v2(141.3,19)
  BOTTOM w0.089: v2(120.72,79.38) UC1.AP30
  BOTTOM w0.102: v2(141.3,19) 141.3,18.5 140.47,17.68 JDIMM2.208
DDR_B_D48: length 77.2
  IN2 w0.076: v2(122.55,76.82) 122.55,75.9 124.32,74.12 124.66,74.12 124.89,73.89 125.79,73.89 126.37,73.31 126.37,72.89 127.97,71.29 127.97,69.83 128.01,69.79
  IN2 w0.127: 128.01,69.79 131.76,66.04 131.76,58.85 145.6,45.01 145.6,40.38 145.73,40.25 146.81,40.25 146.93,40.12 146.93,39.87 146.81,39.74 145.73,39.74 145.6,39.62 145.6,39.18 145.73,39.05 147.06,39.05 147.45,38.66 147.45,33.22 146.01,31.78 146.01,25.4 145.44,24.83 145.44,22.97 145.01,22.54 145.01,19.97 143.35,18.31 v2(143.35,18.27)
  BOTTOM w0.089: v2(122.55,76.82) UC1.AU27
  BOTTOM w0.102: v2(143.35,18.27) 142.47,17.4 JDIMM2.216
DDR_B_D49: length 78.4
  IN2 w0.076: 127.71,69.49 127.71,71.31 126.2,72.82 126.2,73.24 125.72,73.72 124.82,73.72 124.59,73.95 124.24,73.95 122.38,75.81 122.38,76.47 122.18,76.67 122.18,76.98 122.55,77.35 v2(122.55,77.47)
  IN2 w0.127: 127.71,69.49 127.71,69.47 131.37,65.81 131.37,58.75 145.22,44.91 145.22,38.66 145.34,38.53 146.98,38.53 147.11,38.41 147.11,33.37 145.66,31.92 145.66,25.7 144.98,25.02 144.98,23.16 144.55,22.73 144.55,20.74 v2(143.35,19.54)
  BOTTOM w0.089: v2(122.55,77.47) UC1.AT27
  BOTTOM w0.102: JDIMM2.212 141.47,17.36 141.97,17.85 141.97,18.14 142.13,18.3 142.47,18.3 142.63,18.46 142.63,18.79 142.47,18.95 142.13,18.95 141.97,19.11 141.97,19.75 142.25,20.03 142.85,20.03 v2(143.35,19.54)
DDR_B_D50: length 76.5
  IN2 w0.076: v2(123.46,77.47) 124.06,76.88 124.06,75.67 125.14,74.59 126.31,74.59 127.28,73.62 127.88,73.62 128.17,73.33 128.17,72.63
  IN2 w0.127: v2(147.18,20.81) 147.6,21.23 147.6,23.02 149.37,24.79 149.37,29.06 149.24,29.19 148.77,29.19 148.65,29.32 148.65,29.57 148.77,29.7 149.24,29.7 149.37,29.83 149.37,32.63 149.57,32.83 149.57,43.56 133.58,59.54 133.58,67.22 128.17,72.63
  BOTTOM w0.089: UC1.AT25 123.57,77.47 v2(123.46,77.47)
  BOTTOM w0.102: JDIMM2.225 144.72,24.52 144.72,24.52 144.72,23.72 145,23.44 145,22.3 145.22,22.07 145.92,22.07 v2(147.18,20.81)
DDR_B_D51: length 76.1
  IN2 w0.076: 128.22,72.1 127.25,73.07 127.25,73.41 126.24,74.42 125.07,74.42 123.87,75.62 123.87,76.43 v2(123.46,76.84)
  IN2 w0.127: 128.22,72.1 133.24,67.08 133.24,59.4 148.57,44.07 148.57,39.58 149.23,38.92 149.23,32.97 147.8,31.54 147.8,28.57 147.92,28.44 148.9,28.44 149.03,28.32 149.03,28.06 148.9,27.93 147.92,27.93 147.8,27.81 147.8,25.44 147.92,25.31 148.9,25.31 149.03,25.18 149.03,24.93 148.9,24.8 147.92,24.8 147.8,24.67 147.8,23.7 147.17,23.07 147.17,22.09 v2(147.18,22.08)
  BOTTOM w0.076: v2(123.46,76.84) 123.63,76.61 123.8,76.61 124.06,76.86 124.07,76.96 UC1.AU25
  BOTTOM w0.102: v2(147.18,22.08) 146.5,22.08 145.72,22.86 JDIMM2.229
DDR_B_D52: length 78.8
  IN2 w0.076: v2(122.55,78.74) 122.18,78.38 122.18,77.27 122.01,77.1 122.01,76.6 122.21,76.4 122.21,75.74 124.17,73.79 124.52,73.79 125.57,72.74 126.05,72.74 127.46,71.33 127.46,69.24
  IN2 w0.127: v2(143.35,20.81) 143.96,21.42 143.96,22.79 143.99,22.82 143.99,26.28 144.12,26.41 144.71,26.41 144.84,26.53 144.84,26.79 144.71,26.92 144.12,26.92 143.99,27.04 143.99,28.09 145.32,29.42 145.32,32.07 146.76,33.51 146.76,37.94 146.64,38.06 144.9,38.06 144.77,38.19 144.77,44.87 130.45,59.19 130.45,66.06 127.46,69.05 127.46,69.24
  BOTTOM w0.089: v2(122.55,78.74) UC1.AP27
  BOTTOM w0.102: v2(143.35,20.81) 143.21,20.67 142.31,20.67 141.97,21.01 141.97,23.09 141.23,23.83 JDIMM2.211
DDR_B_D53: length 79.6
  IN2 w0.076: v2(122.55,79.38) 122.43,79.38 122,78.94 122,77.32 121.85,77.17 121.85,76.53 122.05,76.33 122.05,75.22 124.41,72.85 125.22,72.85 125.5,72.57 125.98,72.57 127.12,71.43 127.12,68.9 127.44,68.59
  IN2 w0.127: 127.44,68.59 130.1,65.92 130.1,59.05 144.28,44.88 144.28,38.04 144.84,37.48 144.84,36.42 144.96,36.29 146.04,36.29 146.17,36.16 146.17,35.91 146.04,35.78 144.96,35.78 144.84,35.66 144.84,33.66 144.96,33.53 145.79,33.53 145.92,33.4 145.92,33.15 145.79,33.02 144.96,33.02 144.84,32.89 144.84,29.42 143.65,28.23 143.65,23.23 143.3,22.88 143.3,22.12 v2(143.35,22.08)
  BOTTOM w0.076: UC1.AN27 123.09,79.77 123.14,79.71 123.13,79.62 122.83,79.36 122.57,79.36 v2(122.55,79.38)
  BOTTOM w0.102: v2(143.35,22.08) 143.09,22.08 142.91,21.9 142.91,21.33 142.75,21.18 142.54,21.18 142.39,21.33 142.39,22.24 142.55,22.4 142.74,22.4 142.9,22.56 142.9,22.89 142.75,23.04 142.53,23.04 142.37,23.2 142.37,23.28 142.23,23.42 JDIMM2.215
DDR_B_D54: length 78.3
  IN2 w0.076: 128.91,73.47 128.37,74 127.36,74 126.45,74.92 125.28,74.92 124.39,75.81 124.39,77.51 123.99,77.91 123.99,78.85 v2(123.46,79.38)
  IN2 w0.127: 128.91,73.47 128.91,73.02 134.27,67.65 134.27,59.83 150.26,43.84 150.26,24.7 148.56,23 148.56,19.63 147.2,18.27 v2(147.18,18.27)
  BOTTOM w0.089: v2(123.46,79.38) UC1.AN25
  BOTTOM w0.102: JDIMM2.228 145.47,17.29 146.46,18.27 v2(147.18,18.27)
DDR_B_D55: length 77.7
  IN2 w0.076: v2(123.46,78.74) 123.83,78.38 123.83,77.84 124.22,77.45 124.22,75.74 125.21,74.75 126.38,74.75 127.3,73.84 128.3,73.84 128.61,73.52 128.61,72.68
  IN2 w0.127: v2(147.18,19.54) 147.2,19.54 148.1,20.44 148.1,23.03 149.91,24.84 149.91,43.7 133.93,59.68 133.93,67.36 128.61,72.68
  BOTTOM w0.089: v2(123.46,78.74) UC1.AP25
  BOTTOM w0.102: JDIMM2.224 144.47,17.36 146.66,19.54 v2(147.18,19.54)
DDR_B_D56: length 79.6
  IN2 w0.076: v2(125.29,77.47) 125.29,77.35 124.92,76.98 124.92,75.98 125.49,75.41 126.66,75.41 127.57,74.5 128.98,74.5 129.26,74.23 129.61,74.23 131.84,72 132.02,72
  IN2 w0.127: 132.02,72 135.38,68.64 135.38,60.18 152.43,43.12 152.43,38.66 152.3,38.53 151.41,38.53 151.28,38.41 151.28,37.95 151.41,37.82 152.01,37.82 152.14,37.69 152.14,37.44 152.01,37.31 151.41,37.31 151.28,37.19 151.28,23.89 150.18,22.79 150.18,21.1 v2(149.13,20.05)
  BOTTOM w0.089: v2(125.29,77.47) UC1.AT22
  BOTTOM w0.102: JDIMM2.232 146.47,17.34 146.73,17.6 147.13,17.6 147.62,18.09 147.62,18.54 v2(149.13,20.05)
DDR_B_D57: length 78.6
  IN2 w0.076: 132.46,71.96 130.03,74.39 129.32,74.39 129.05,74.66 127.64,74.66 126.31,75.99 126.08,75.99 125.29,76.78 v2(125.29,76.82)
  IN2 w0.127: 132.46,71.96 135.76,68.66 135.76,60.28 152.77,43.26 152.77,34.61 152.22,34.06 152.22,24.35 150.52,22.65 150.52,18.09 150.18,17.75 149.36,17.75 149.13,17.98 v2(149.13,18.78)
  BOTTOM w0.089: v2(125.29,76.82) UC1.AU22
  BOTTOM w0.102: JDIMM2.236 147.47,17.35 148.9,18.78 v2(149.13,18.78)
DDR_B_D58: length 77.8
  IN2 w0.076: v2(126.21,76.88) 126.33,76.88 127.96,75.25 129.28,75.25 129.61,74.92 131,74.92 131.63,74.29
  IN2 w0.127: 131.63,74.29 137.2,68.72 137.2,60.86 154.21,43.86 154.21,34.63 154.72,34.12 154.72,31.7 153.66,30.64 153.66,26.8 153.78,26.68 154.77,26.68 154.9,26.55 154.9,26.29 154.77,26.17 153.78,26.17 153.66,26.04 153.66,23.72 152.7,22.76 v2(152.65,22.76)
  BOTTOM w0.076: UC1.AU21 126.91,77.17 127.1,76.98 127.1,76.73 126.99,76.62 126.26,76.62 126.15,76.73 126.15,76.83 v2(126.21,76.88)
  BOTTOM w0.102: JDIMM2.249 150.72,23.88 150.14,23.29 150.14,22.62 150.27,22.49 151.56,22.49 151.85,22.19 152.08,22.19 v2(152.65,22.76)
DDR_B_D59: length 78.6
  IN2 w0.076: v2(126.2,77.47) 126.36,77.47 127.79,76.05 128.72,76.05 129.68,75.09 131.28,75.09 131.83,74.54
  IN2 w0.127: 131.83,74.54 137.55,68.82 137.55,61.01 154.55,44 154.55,34.92 155.24,34.24 155.24,31.74 154,30.5 154,27.27 154.13,27.14 155.11,27.14 155.24,27.02 155.24,23.94 152.79,21.49 v2(152.65,21.49)
  BOTTOM w0.076: v2(126.2,77.47) 126.23,77.67 126.47,77.85 UC1.AT21
  BOTTOM w0.102: v2(152.65,21.49) 151.97,21.49 151.38,22.07 149.99,22.07 149.72,22.33 JDIMM2.245
DDR_B_D60: length 81.6
  IN2 w0.076: v2(125.29,79.38) 124.74,78.83 124.74,77.32 124.59,77.17 124.59,75.84 125.35,75.08 126.52,75.08 127.43,74.17 128.72,74.17 129.04,73.85 129.23,73.85 131.07,72.02
  IN2 w0.127: v2(149.13,22.59) 149.13,23.09 150.6,24.56 150.6,39.35 150.73,39.47 151.62,39.47 151.75,39.6 151.75,39.85 151.62,39.98 150.73,39.98 150.6,40.11 150.6,40.36 150.73,40.49 151.53,40.49 151.66,40.62 151.66,40.87 151.53,41 150.73,41 150.6,41.12 150.6,43.98 134.61,59.97 134.61,68.47 131.07,72.02
  BOTTOM w0.076: v2(125.29,79.38) 125.61,79.38 125.83,79.61 125.83,79.72 125.78,79.77 UC1.AN22
  BOTTOM w0.102: JDIMM2.237 147.72,23.64 147.83,23.53 148.57,23.53 148.72,23.37 148.72,23.14 148.6,23.02 147.84,23.02 147.72,22.91 147.72,22.75 148.04,22.43 148.04,21.58 148.15,21.47 148.6,21.47 148.69,21.56 148.69,22.15 v2(149.13,22.59)
DDR_B_D61: length 81.2
  IN2 w0.076: 130.16,73.41 129.91,73.41 129.26,74.06 129.15,74.06 128.88,74.33 127.5,74.33 126.59,75.25 125.42,75.25 124.75,75.91 124.75,77.08 124.91,77.23 124.91,78.36 v2(125.29,78.74)
  IN2 w0.127: v2(149.13,21.32) 149.44,21.32 149.72,21.6 149.72,22.82 150.94,24.04 150.94,38.88 151.07,39 151.96,39 152.09,39.13 152.09,40.92 151.67,41.34 151.07,41.34 150.94,41.47 150.94,42.08 151.07,42.2 151.96,42.2 152.09,42.33 152.09,42.58 151.96,42.71 151.07,42.71 150.94,42.84 150.94,44.13 134.99,60.07 134.99,68.58 130.16,73.41
  BOTTOM w0.076: UC1.AP22 125.72,78.83 125.58,78.72 v2(125.29,78.74)
  BOTTOM w0.102: v2(149.13,21.32) 149.13,21.29 148.89,21.05 147.89,21.05 147.62,21.32 147.62,22.26 146.72,23.16 JDIMM2.233
DDR_B_D62: length 79.5
  IN2 w0.076: 131.84,75.42 129.82,75.42 128.86,76.38 128.08,76.38 127.6,76.85 127.6,78.26 v2(127.12,78.74)
  IN2 w0.127: 131.84,75.42 138.23,69.02 138.23,61.29 155.38,44.14 155.38,35.07 155.92,34.52 155.92,30.15 155.8,30.02 155.57,30.02 155.44,29.89 155.44,29.64 155.57,29.51 155.8,29.51 155.92,29.39 155.92,23.21 153.56,20.84 153.56,19.79 v2(152.66,18.88)
  BOTTOM w0.089: v2(127.12,78.74) 126.74,79.12 UC1.AP21
  BOTTOM w0.102: v2(152.66,18.88) 152.12,18.88 150.97,17.74 JDIMM2.250
DDR_B_D63: length 80.9
  IN2 w0.076: 132.26,74.55 131.56,75.25 129.75,75.25 128.79,76.21 127.86,76.21 126.75,77.32 126.75,78.83 v2(126.2,79.38)
  IN2 w0.127: v2(152.65,20.15) 153.11,20.61 153.11,20.87 155.58,23.35 155.58,27.49 155.45,27.61 155,27.61 154.87,27.74 154.87,30.89 155,31.01 155.45,31.01 155.58,31.14 155.58,34.38 154.9,35.07 154.9,44.14 137.89,61.15 137.89,68.92 132.26,74.55
  BOTTOM w0.089: v2(126.2,79.38) UC1.AN21
  BOTTOM w0.102: JDIMM2.246 149.97,17.33 151.39,18.75 151.39,19.08 152.46,20.15 v2(152.65,20.15)
DDR_B_DQS0: length 83.6
  IN2 w0.076: v2(101.38,81.92) 101.14,81.68 101.14,81.52 100.96,81.35 100.43,81.35 98.45,79.37 98.45,78.56 98.45,78.55 98.45,78.44 97.23,77.22 96.83,77.22 96.83,77.21 96.63,77.21 96.63,77.22 96.23,77.22 96.21,77.2 96.2,77.2
  IN2 w0.102: 96.2,77.2 95.7,77.2 95.39,76.9 94.72,76.9 94.4,77.22 91.69,77.22 91.59,77.11 91.59,76.72 91.38,76.51 90.91,76.51 90.7,76.72 90.7,77.11 90.6,77.22 89.93,77.22 86.11,73.39 86.11,65.79 86.59,65.31 86.59,49.75 89.02,47.32 89.02,45.48 90.97,43.53 90.97,31.72 92.77,29.92 92.77,28.5 92.51,28.24 92.51,24.58 94.35,22.73 94.35,20.08 94.51,19.92 94.72,19.92 v2(94.94,20.15)
  BOTTOM w0.076: UC1.AH65 101.74,82.28 v2(101.38,81.92)
  BOTTOM w0.099: v2(94.94,20.15) 95.15,19.94 95.49,19.94 95.63,19.8 95.63,19.79 95.74,19.68 95.74,18.64 94.83,17.73 94.83,17.41 94.97,17.27 JDIMM2.34
DDR_B_DQS1: length 87.8
  IN2 w0.102: v2(96.55,82.98) 96.33,83.19 96.33,83.62 95.87,84.08 90.69,84.08 81.72,75.11 81.72,64.05 81.96,63.81 81.96,44.38 83.57,42.77 83.57,31.69 84.4,30.86 84.4,27.53 84.3,27.43 83.96,27.43 83.75,27.21 83.75,26.75 83.96,26.54 84.3,26.54 84.4,26.44 84.4,25.43 88.07,21.76 88.07,20.07 88.35,19.79 88.58,19.79 v2(89.03,19.34)
  BOTTOM w0.076: UC1.AG70 98.58,82.64 98.35,82.64 98.21,82.58 98.11,82.58 97.97,82.64 96.89,82.64 v2(96.55,82.98)
  BOTTOM w0.099: v2(89.03,19.34) 89.24,19.56 89.66,19.56 89.94,19.84 89.94,21.24 89.58,21.6 89.58,23.68 89.72,23.82 JDIMM2.13
DDR_B_DQS2: length 72.7
  IN2 w0.076: 95.69,68.2 95.71,68.21 95.71,68.23 95.78,68.31 95.78,71.56 96.49,72.26 96.87,72.26 99.63,75.02 100.22,75.02 101.14,75.93 101.14,77.69 100.96,77.87 100.96,78.02 101.05,78.11 v2(101.51,78.11)
  IN2 w0.102: 95.69,68.2 91.81,64.32 91.81,50.52 96.39,45.95 96.39,39.77 98.52,37.64 98.52,30.9 98.2,30.58 98.2,27.97 98.93,27.24 98.93,25.34 100.01,24.25 100.01,20.44 100.13,20.32 100.33,20.32 v2(100.67,20.65)
  BOTTOM w0.089: v2(101.51,78.11) 101.88,78.47 UC1.AR65
  BOTTOM w0.099: v2(100.67,20.65) 100.46,20.44 100.2,20.44 100.07,20.57 100.07,23.7 100.22,23.86 JDIMM2.55
DDR_B_DQS3: length 74.4
  IN2 w0.076: v2(104.26,78.74) 104.03,78.51 103.94,78.51 103.71,78.28 103.71,77.58 103.77,77.52 103.77,77.3 103.84,77.23 103.84,74.55 103.61,74.32 103.61,73.3 102.31,72.01 99.84,72.01 99.12,71.3 99.12,68.36 99.11,68.35 99.11,67.96
  IN2 w0.102: v2(105.64,20.6) 105.85,20.38 106.05,20.38 106.17,20.5 106.17,22.4 105.4,23.16 105.4,27.75 104.85,28.3 104.03,28.3 103.27,29.06 103.27,31.22 102.69,31.79 102.69,39.46 101.82,40.33 101.82,46.08 95.99,51.91 95.99,62.88 98.55,65.44 98.55,66.49 99.11,67.05 99.11,67.96
  BOTTOM w0.089: v2(104.26,78.74) 104.53,78.47 UC1.AR60
  BOTTOM w0.099: JDIMM2.76 105.48,17.28 105.34,17.42 105.34,18.03 106.42,19.11 106.42,20.17 106.21,20.38 105.85,20.38 v2(105.64,20.6)
DDR_B_DQS4: length 72.6
  IN2 w0.076: v2(116.14,78.11) 116.69,77.56 116.69,75.95 118.95,73.69 118.95,72.63 119.22,72.36 119.77,72.36 120.07,72.06 120.07,66.61 121.77,64.91 121.77,64.8 121.78,64.79 121.78,64.77
  IN2 w0.102: 121.78,64.77 121.78,64.19 122.88,63.1 122.88,57.2 134.22,45.86 134.22,32.14 134.33,32.04 134.79,32.04 135,31.82 135,31.36 134.79,31.15 134.18,31.15 134.08,31.05 134.08,30.12 134.99,29.21 134.99,28.58 134.78,28.36 134.41,28.36 134.31,28.26 134.31,27.96 134.41,27.86 134.79,27.86 135,27.64 135,24.28 134.6,23.88 134.06,23.88 133.22,23.03 133.22,22.39 133.32,22.29 133.91,22.29 v2(134.12,22.5)
  BOTTOM w0.076: v2(116.14,78.11) 116.23,78.02 116.39,78.02 116.68,78.31 116.68,78.4 UC1.AR38
  BOTTOM w0.099: v2(134.12,22.5) 133.91,22.29 133.35,22.29 133.09,22.54 133.09,23.56 133.23,23.69 JDIMM2.179
DDR_B_DQS5: length 75.2
  IN2 w0.076: v2(120.72,78.11) 120.69,78.13 120.44,78.13 120.35,78.04 120.35,76.6 121.17,75.78 121.17,74.89 124.03,72.03 124.39,72.03 126.17,70.25 126.17,66.48 126.33,66.32 126.33,65.65 126.91,65.07 126.93,65.07
  IN2 w0.102: 126.93,65.07 126.93,65.07 127.69,64.31 127.69,58.23 141.26,44.66 141.26,31.35 141.05,31.13 140.76,31.13 140.66,31.03 140.66,30.73 140.76,30.63 141.05,30.63 141.26,30.41 141.26,28.21 141.05,28 140.77,28 140.67,27.9 140.67,27.59 140.77,27.49 141.05,27.49 141.26,27.28 141.26,24.56 140.58,23.88 140.58,19.8 140.34,19.56 140.08,19.56 v2(139.84,19.32)
  BOTTOM w0.076: UC1.AR32 120.62,78.11 v2(120.72,78.11)
  BOTTOM w0.099: v2(139.84,19.32) 139.6,19.56 139.33,19.56 139.12,19.36 139.12,18.78 138.32,17.98 138.32,17.4 138.47,17.25 JDIMM2.200
DDR_B_DQS6: length 77.4
  IN2 w0.076: 128.72,70.04 128.25,70.52 128.25,71.38 126.8,72.82 126.8,73.38 126.71,73.47 126.5,73.47 126.24,73.73 126.24,73.96 126.15,74.05 124.98,74.05 124.74,74.28 124.48,74.28 124.26,74.51 124.26,74.72 124.08,74.89 123.89,74.89 123.54,75.24 123.54,76 122.92,76.62 122.92,77.8 123.04,77.93 123.04,78.03 122.97,78.11 v2(122.55,78.11)
  IN2 w0.102: 128.72,70.04 128.78,70.04 132.43,66.39 132.43,59.06 147.76,43.73 147.76,39.24 148.33,38.67 148.33,33.22 146.98,31.88 146.98,25.21 146.36,24.59 146.36,21.01 146.13,20.78 145.74,20.78 v2(145.53,21)
  BOTTOM w0.089: v2(122.55,78.11) UC1.AR27
  BOTTOM w0.099: v2(145.53,21) 145.08,20.55 144.68,20.55 144.2,21.03 144.2,22.68 143.5,23.38 143.5,23.56 143.72,23.78 JDIMM2.221
DDR_B_DQS7: length 79.2
  IN2 w0.076: v2(126.2,78.11) 126.2,78.23 125.98,78.45 125.9,78.45 125.83,78.38 125.83,76.73 126.15,76.42 126.46,76.42 127.81,75.06 129.2,75.06 129.41,74.85 129.41,74.85 129.52,74.74 130.58,74.74 136.43,68.89 136.45,68.89 136.49,68.85 136.49,68.85 136.5,68.85 136.51,68.84
  IN2 w0.102: v2(151.17,20.37) 151.37,20.57 151.71,20.57 152.08,20.94 152.08,23.05 153.04,24.01 153.04,33.73 153.59,34.28 153.59,43.6 136.57,60.62 136.57,68.78 136.51,68.84
  BOTTOM w0.089: UC1.AR21 126.57,78.47 v2(126.2,78.11)
  BOTTOM w0.099: JDIMM2.242 148.97,17.33 148.84,17.46 148.84,17.58 150.34,19.07 150.34,20.41 150.5,20.58 150.95,20.58 v2(151.17,20.37)
DDR_B_DQS#0: length 83.6
  IN2 w0.076: v2(100.76,81.94) 100.97,81.74 100.97,81.59 100.89,81.51 100.36,81.51 98.29,79.44 98.29,78.94 98.28,78.94 98.28,78.51 97.16,77.38 96.63,77.38 96.63,77.38 96.23,77.38 96.21,77.39 96.2,77.39
  IN2 w0.102: v2(94.94,19.51) 94.73,19.73 94.44,19.73 94.16,20 94.16,22.65 92.32,24.5 92.32,28.32 92.58,28.57 92.58,29.84 90.78,31.64 90.78,43.45 88.83,45.4 88.83,47.25 86.4,49.67 86.4,65.23 85.92,65.71 85.92,73.47 89.85,77.41 90.68,77.41 90.89,77.19 90.89,76.8 90.99,76.7 91.3,76.7 91.4,76.8 91.4,77.19 91.61,77.41 94.48,77.41 94.8,77.09 95.31,77.09 95.62,77.39 96.2,77.39
  BOTTOM w0.076: v2(100.76,81.94) 101.09,82.27 UC1.AH66
  BOTTOM w0.099: JDIMM2.32 94.48,17.22 94.64,17.38 94.64,17.81 95.55,18.72 95.55,19.6 95.41,19.75 95.18,19.75 v2(94.94,19.51)
DDR_B_DQS#1: length 87.9
  IN2 w0.102: v2(95.91,82.98) 96.14,83.2 96.14,83.54 95.79,83.89 90.77,83.89 81.91,75.03 81.91,64.13 82.15,63.89 82.15,44.46 83.76,42.85 83.76,31.77 84.59,30.94 84.59,27.45 84.38,27.24 84.04,27.24 83.94,27.13 83.94,26.83 84.04,26.73 84.38,26.73 84.59,26.51 84.59,25.51 88.26,21.84 88.26,20.15 88.43,19.98 88.74,19.98 v2(89.03,19.98)
  BOTTOM w0.076: UC1.AG69 99.32,82.91 99.19,82.91 99.12,82.84 99.12,82.76 98.84,82.47 98.38,82.47 98.25,82.42 98.07,82.42 97.94,82.47 96.82,82.47 96.68,82.61 96.29,82.61 95.92,82.98 v2(95.91,82.98)
  BOTTOM w0.099: v2(89.03,19.98) 89.25,19.75 89.58,19.75 89.75,19.92 89.75,21.16 89.39,21.52 89.39,23.66 89.22,23.83 JDIMM2.11
DDR_B_DQS#2: length 72.8
  IN2 w0.076: v2(100.61,78.15) 100.79,77.97 100.79,77.8 100.97,77.62 100.97,76 100.15,75.18 99.56,75.18 96.81,72.43 96.42,72.43 95.62,71.62 95.62,68.39 95.56,68.33
  IN2 w0.102: v2(100.67,20.02) 100.56,20.13 100.05,20.13 99.82,20.36 99.82,24.17 98.74,25.26 98.74,27.16 98.01,27.89 98.01,30.66 98.33,30.97 98.33,37.56 96.2,39.69 96.2,45.87 91.62,50.44 91.62,64.4 95.56,68.33
  BOTTOM w0.089: UC1.AR66 100.94,78.47 v2(100.61,78.15)
  BOTTOM w0.099: v2(100.67,20.02) 100.43,20.26 100.12,20.26 99.88,20.5 99.88,23.71 99.72,23.87 JDIMM2.53
DDR_B_DQS#3: length 74.3
  IN2 w0.076: v2(104.26,78.11) 104.26,78.24 104.15,78.35 104.01,78.35 103.88,78.21 103.88,77.65 103.94,77.59 103.94,77.37 104,77.3 104,74.48 103.96,74.43 103.95,74.43 103.77,74.25 103.77,73.23 102.38,71.84 99.9,71.84 99.29,71.23 99.29,68.36 99.3,68.35 99.3,68
  IN2 w0.102: v2(105.64,19.96) 105.87,20.19 106.13,20.19 106.36,20.42 106.36,22.48 105.59,23.24 105.59,27.83 104.93,28.49 104.11,28.49 103.46,29.14 103.46,31.29 102.88,31.87 102.88,39.54 102.01,40.41 102.01,46.16 96.18,51.99 96.18,62.8 98.74,65.36 98.74,66.41 99.3,66.97 99.3,68
  BOTTOM w0.089: v2(104.26,78.11) 103.89,78.47 UC1.AR61
  BOTTOM w0.099: JDIMM2.74 104.97,17.2 105.15,17.38 105.15,18.11 106.23,19.19 106.23,20.09 106.13,20.19 105.87,20.19 v2(105.64,19.96)
DDR_B_DQS#4: length 72.6
  IN2 w0.076: v2(116.14,77.47) 116.3,77.63 116.39,77.63 116.53,77.49 116.53,75.88 118.78,73.62 118.78,72.56 119.16,72.19 119.22,72.19 119.22,72.19 119.7,72.19 119.9,71.99 119.9,66.54 121.59,64.85 121.59,64.77
  IN2 w0.102: 121.59,64.77 121.59,64.11 122.69,63.02 122.69,57.12 134.03,45.78 134.03,32.06 134.25,31.85 134.71,31.85 134.81,31.75 134.81,31.44 134.71,31.34 134.1,31.34 133.89,31.13 133.89,30.04 134.8,29.13 134.8,28.66 134.7,28.55 134.33,28.55 134.12,28.34 134.12,27.88 134.33,27.67 134.71,27.67 134.81,27.56 134.81,24.36 134.52,24.07 133.99,24.07 133.03,23.11 133.03,22.31 133.24,22.1 133.88,22.1 v2(134.12,21.86)
  BOTTOM w0.089: v2(116.14,77.47) UC1.AT38
  BOTTOM w0.099: JDIMM2.177 132.72,23.74 132.9,23.56 132.9,22.47 133.27,22.1 133.88,22.1 v2(134.12,21.86)
DDR_B_DQS#5: length 75.3
  IN2 w0.076: v2(119.8,78.11) 119.92,78.23 120.04,78.23 120.18,78.09 120.18,76.53 121,75.71 121,74.82 123.96,71.86 124.32,71.86 126,70.18 126,66.42 126.17,66.25 126.17,65.58 126.8,64.95 126.8,64.94 126.81,64.92
  IN2 w0.102: 126.81,64.92 127.5,64.23 127.5,58.15 141.07,44.58 141.07,31.43 140.97,31.32 140.68,31.32 140.47,31.11 140.47,30.65 140.68,30.43 140.97,30.43 141.07,30.33 141.07,28.29 140.97,28.19 140.69,28.19 140.48,27.98 140.48,27.51 140.69,27.3 140.97,27.3 141.07,27.2 141.07,24.64 140.39,23.96 140.39,19.88 140.26,19.75 140.05,19.75 v2(139.84,19.96)
  BOTTOM w0.076: v2(119.8,78.11) 119.97,78.11 UC1.AT32
  BOTTOM w0.099: v2(139.84,19.96) 139.64,19.75 139.25,19.75 138.93,19.43 138.93,18.86 138.13,18.06 138.13,17.42 137.97,17.26 JDIMM2.198
DDR_B_DQS#6: length 77.4
  IN2 w0.076: 128.79,70.23 128.77,70.23 128.41,70.59 128.41,71.45 126.97,72.89 126.97,73.45 126.78,73.64 126.57,73.64 126.4,73.8 126.4,74.03 126.21,74.22 125.04,74.22 124.81,74.45 124.55,74.45 124.42,74.57 124.42,74.79 124.15,75.06 123.96,75.06 123.71,75.31 123.71,76.07 123.08,76.69 123.08,77.73 v2(123.46,78.11)
  IN2 w0.102: v2(145.53,20.37) 145.75,20.59 146.2,20.59 146.55,20.94 146.55,24.51 147.18,25.14 147.18,31.8 148.52,33.15 148.52,38.75 147.95,39.32 147.95,43.81 132.62,59.14 132.62,66.47 128.85,70.23 128.79,70.23
  BOTTOM w0.089: v2(123.46,78.11) UC1.AR25
  BOTTOM w0.099: v2(145.53,20.37) 144.6,20.37 144.01,20.95 144.01,22.6 143.32,23.3 143.32,23.62 143.23,23.71 JDIMM2.219
DDR_B_DQS#7: length 79.3
  IN2 w0.076: v2(126.2,78.74) 126.07,78.61 125.81,78.61 125.67,78.47 125.67,76.67 125.71,76.62 125.71,76.62 126.08,76.25 126.39,76.25 127.74,74.89 129.13,74.89 129.45,74.57 130.51,74.57 136.38,68.71
  IN2 w0.102: v2(151.17,21) 151.4,20.76 151.63,20.76 151.89,21.02 151.89,23.13 152.84,24.09 152.84,33.8 153.4,34.36 153.4,43.52 136.38,60.54 136.38,68.71 136.38,68.71
  BOTTOM w0.076: UC1.AR22 125.93,78.47 v2(126.2,78.74)
  BOTTOM w0.099: JDIMM2.240 148.47,17.23 148.66,17.41 148.66,17.66 150.15,19.15 150.15,20.49 150.43,20.76 150.93,20.76 v2(151.17,21)
DDR_B_MA0: length 69.8
  IN2 w0.076: v2(110.35,67.08) 110.41,67.02 110.41,64.77
  IN2 w0.216: v2(123.01,18.46) 123.01,18.01 122.79,17.79 119.81,17.79 119.56,18.03 119.56,19.21 120.52,20.17 120.52,27.82 120.33,28.01 120.33,29.87 118.61,31.58 118.61,36.04 117.82,36.82 117.82,40.04 117.83,40.05 117.82,40.06 117.82,40.45 118.61,41.23 118.61,45.61 109.98,54.24 109.98,59.79 110.41,60.22 110.41,64.77
  BOTTOM w0.076: v2(110.35,67.08) 110.34,67.08 110.34,67.07 112.27,69 v1(112.27,69.68) 112.27,72.37 112.95,73.05 112.95,74.26 112.69,74.53 UC1.BA46
  BOTTOM w0.163: v2(123.01,18.46) 123,18.46 122.47,17.93 JDIMM2.144
DDR_B_MA1: length 72
  IN2 w0.076: v2(110.35,68.31) 109.71,68.31 109.42,68.02 109.42,64.77
  IN2 w0.216: v2(119.71,21.92) 119.46,21.92 119.25,22.14 119.25,24.17 119.53,24.45 119.53,27.41 118.61,28.32 118.61,30.17 117.6,31.18 117.6,32.45 116.98,33.06 116.98,36.26 116.83,36.41 116.83,40.86 117.62,41.64 117.62,45.2 117.46,45.36 117.2,45.62 116.89,45.62 116.3,45.03 116,45.03 115.65,45.38 115.65,45.69 116.24,46.27 116.24,46.58 115.93,46.88 115.62,46.88 113.46,44.72 113.16,44.72 112.53,45.35 112.53,46.75 112.69,46.91 112.69,47.22 112.34,47.57 112.34,48.97 112.94,49.57 112.94,49.87 108.25,54.56 108.25,59.47 109.42,60.64 109.42,64.77
  BOTTOM w0.076: v2(110.35,68.31) 111.81,69.77 111.81,72.4 112.62,73.21 112.62,73.7 112.42,73.9 112.42,74.16 112.48,74.28 112.48,74.42 112.41,74.65 112.41,74.78 112.49,75 112.59,75.1 UC1.AY46
  BOTTOM w0.163: v2(119.71,21.92) 120.15,22.36 120.15,23.39 119.72,23.81 JDIMM2.133
DDR_B_MA2: length 71.4
  IN2 w0.076: 108.92,64.77 108.92,66.26 109.25,66.59 109.25,68.68 109.47,68.9 v2(110.33,68.9)
  IN2 w0.216: 108.92,64.77 108.92,60.84 107.75,59.67 107.75,54.36 112.24,49.87 112.24,49.57 111.84,49.17 111.84,45.33 113.31,43.87 113.62,43.87 114.89,45.14 115.19,45.14 117.12,43.21 117.12,41.85 117.12,41.85 116.34,41.06 116.34,36.21 116.45,36.09 116.45,32.83 116.96,32.32 116.96,31.12 118.12,29.96 118.12,28.05 118.99,27.18 118.99,25.08 118.74,24.83 118.74,21.61 119.69,20.65 v2(119.71,20.65)
  BOTTOM w0.076: UC1.AY47 112.29,75.38 112.29,74.95 112.24,74.79 112.24,74.65 112.3,74.43 112.3,74.31 112.27,74.23 112.26,74.2 112.26,73.83 112.46,73.63 112.46,73.29 111.55,72.38 111.55,70.12 v2(110.33,68.9)
  BOTTOM w0.163: JDIMM2.132 119.47,17.81 120.15,18.49 120.15,20.22 v2(119.71,20.65)
DDR_B_MA3: length 69.6
  IN2 w0.076: 109.91,64.77 109.91,67.56 110.08,67.73 v2(110.36,67.73)
  IN2 w0.216: 109.91,64.77 109.91,60.43 109.21,59.73 109.21,54.3 113.64,49.87 113.64,49.57 112.83,48.76 112.83,48.28 113.05,48.06 113.35,48.06 114.25,48.96 114.56,48.96 114.86,48.65 114.86,48.35 113.02,46.51 113.02,46.03 113.24,45.81 113.54,45.81 115.47,47.74 115.78,47.74 118.11,45.4 118.11,41.44 117.33,40.65 117.33,36.62 118.11,35.83 118.11,31.38 119.12,30.37 119.12,28.51 120.02,27.61 120.02,23.5 v2(119.71,23.19)
  BOTTOM w0.076: v2(110.36,67.73) 110.77,67.73 111.97,68.94 111.97,72.32 112.79,73.13 112.79,73.95 UC1.BB46
  BOTTOM w0.163: v2(119.71,23.19) 119.71,23.18 119.32,22.78 119.07,22.78 118.81,23.04 118.81,23.27 119.22,23.69 JDIMM2.131
DDR_B_MA4: length 72.1
  IN2 w0.076: v2(110.34,69.63) 109.7,69.63 108.32,68.25 108.32,66.26 108.43,66.15 108.43,64.77
  IN2 w0.216: 108.43,64.77 108.43,61.05 107.26,59.88 107.26,54.15 108.43,52.99 111.35,50.06 111.35,45.13 113.17,43.31 113.76,43.31 114.89,44.44 115.19,44.44 116.63,43 116.63,42.05 115.84,41.27 115.84,36.37 115.31,35.84 115.31,33.08 115.63,32.77 115.63,31.75 116.96,30.42 116.96,27.94 117.09,27.81 117.6,27.81 118.48,26.92 118.48,25.4 118.23,25.15 118.23,21.34 118.83,20.74 118.83,20.47 118.45,20.09 118.14,20.09 117.7,20.53 v2(117.68,20.53)
  BOTTOM w0.076: v2(110.34,69.63) 111.27,70.57 111.27,72.34 111.67,72.73 111.67,73.67 111.79,73.79 111.79,74.19 111.76,74.28 111.76,74.76 UC1.BA47
  BOTTOM w0.163: v2(117.68,20.53) 118.47,19.73 JDIMM2.128
DDR_B_MA5: length 70.9
  IN2 w0.076: v2(110.39,71.97) 109.01,71.97 108.63,71.59 108.25,71.59 107.41,70.75 107.41,69.77 106.95,69.32 106.95,65.66 106.94,65.65 106.94,64.77
  IN2 w0.216: v2(117.68,19.26) 117.68,18.66 117.47,18.45 116.47,18.45 116.25,18.66 116.25,19.6 116.47,19.81 116.99,19.81 117.21,20.03 117.21,20.58 116.99,20.8 116.47,20.8 116.25,21.01 116.25,24.21 115.42,25.04 115.42,29.85 113.21,32.06 113.21,41.02 109.86,44.38 109.86,49.45 106.94,52.37 105.77,53.54 105.77,60.49 106.94,61.66 106.94,64.77
  BOTTOM w0.076: UC1.AY48 111.36,75.18 111.09,74.91 111.09,72.86 110.39,72.16 v2(110.39,71.97)
  BOTTOM w0.163: JDIMM2.126 117.97,18.96 v2(117.68,19.26)
DDR_B_MA6: length 69.5
  IN2 w0.076: v2(110.35,70.8) 110.02,71.13 108.85,71.13 108.71,70.99 108.71,70.55 108.59,70.43 108.19,70.43 107.91,70.15 107.91,65.53
  IN2 w0.216: v2(117.68,23.07) 117.61,23 117.43,23 117.28,23.15 117.28,26.86 116.45,27.69 116.45,30.23 115.07,31.6 115.07,32.55 114.81,32.81 114.81,32.82 114.8,32.83 114.8,36.07 115.12,36.39 115.15,36.39 115.35,36.58 115.35,38.22 115.13,38.43 114.42,38.43 114.2,38.65 114.2,39.08 114.42,39.3 115.13,39.3 115.35,39.51 115.35,40.67 115.13,40.89 114.42,40.89 114.2,41.11 114.2,41.54 114.42,41.75 115.63,41.75 116.13,42.26 116.13,42.8 115.19,43.74 114.89,43.74 113.96,42.81 112.95,42.81 110.85,44.91 110.85,49.86 107.93,52.78 106.76,53.95 106.76,60.08 107.93,61.25 107.93,65.51 107.91,65.53
  BOTTOM w0.076: v2(110.35,70.8) 111.11,71.56 111.11,72.4 111.51,72.8 111.51,73.78 111.63,73.9 111.63,74.16 111.59,74.25 111.36,74.48 UC1.BA48
  BOTTOM w0.163: JDIMM2.127 118.22,23.61 v2(117.68,23.07)
DDR_B_MA7: length 73.9
  IN2 w0.076: 105.45,64.77 105.78,65.1 105.78,70.19 108.92,73.32 108.92,73.49 109.37,73.94 109.37,78.36 109.38,79.61 109.57,79.8 109.89,79.8 110.14,79.56 110.14,79.36 110.33,79.17 110.33,79.07 v2(110.66,78.74)
  IN2 w0.216: 105.45,64.77 105.45,62.28 103.27,60.09 103.27,53.96 104.29,52.95 104.29,52.92 104.45,52.76 108.25,48.96 108.25,48.91 108.26,48.89 108.26,43.87 111.73,40.41 111.73,31.45 113.94,29.24 113.94,24.42 114.77,23.59 114.77,21.94 115.31,21.39 115.31,21.1 115.76,20.65 v2(115.78,20.65)
  BOTTOM w0.089: v2(110.66,78.74) UC1.AP48
  BOTTOM w0.163: v2(115.78,20.65) 116.97,19.46 JDIMM2.122
DDR_B_MA8: length 69.1
  IN2 w0.076: v2(110.35,71.39) 108.28,71.39 107.57,70.68 107.57,69.71 107.44,69.57 107.44,64.77
  IN2 w0.216: v2(117.68,21.8) 117.63,21.74 117.61,21.74 117.16,21.29 116.86,21.29 116.76,21.4 116.76,26.61 115.92,27.45 115.92,30.06 113.71,32.27 113.71,42.1 113.49,42.32 112.62,42.32 110.36,44.58 110.36,49.65 107.44,52.57 106.27,53.74 106.27,60.29 107.44,61.46 107.44,64.77
  BOTTOM w0.076: v2(110.35,71.39) 110.84,71.87 110.84,72.37 111.34,72.87 111.34,73.85 111.36,73.87 UC1.BB48
  BOTTOM w0.163: v2(117.68,21.8) 117.68,21.78 117.24,21.34 117.24,20.61 117.08,20.45 116.57,20.45 116.21,20.81 116.21,21.77 117.14,22.7 117.14,23.29 117.72,23.87 JDIMM2.125
DDR_B_MA9: length 68.7
  IN2 w0.076: 105.95,64.77 105.95,69.76 108.11,71.92 108.49,71.92 110.12,73.55 110.12,78.43 v2(109.76,78.8)
  IN2 w0.216: 105.95,64.77 105.95,62.07 103.77,59.89 103.77,54.17 104.78,53.15 104.78,53.13 104.91,53 104.95,52.96 108.74,49.17 108.74,49.11 108.76,49.1 108.76,49.03 108.83,48.96 108.83,44 112.22,40.61 112.22,31.65 114.43,29.44 114.43,24.63 115.26,23.8 115.26,22.14 115.48,21.92 v2(115.78,21.92)
  BOTTOM w0.076: UC1.AP50 110.09,79.12 v2(109.76,78.8)
  BOTTOM w0.163: v2(115.78,21.92) 116.72,22.87 JDIMM2.121
DDR_B_MA10: length 70.9
  IN2 w0.076: 113.62,64.77 113.62,66.04 112.79,66.88 112.79,69.31 v2(113.17,69.7)
  IN2 w0.216: 113.62,64.77 113.62,55.89 121.99,47.52 121.99,45.71 122.21,45.5 123.22,45.5 123.48,45.24 123.48,44.67 123.69,44.45 123.77,44.45 123.99,44.24 123.99,43.81 123.77,43.59 123.69,43.59 123.48,43.37 123.48,42.94 123.69,42.73 123.77,42.73 123.99,42.51 123.99,42.08 123.77,41.86 123.69,41.86 123.48,41.65 123.48,39.06 122.42,37.99 122.42,31.88 124.01,30.29 124.01,23.52 123.71,23.23 123.71,19.49 123.92,19.28 124.26,19.28 v2(124.5,19.51)
  BOTTOM w0.076: UC1.AW46 112.59,75.82 112.78,75.63 112.88,75.43 112.88,74.93 113.12,74.7 113.12,72.97 112.57,72.42 112.57,69.86 112.73,69.7 v2(113.17,69.7)
  BOTTOM w0.163: v2(124.5,19.51) 124.2,19.81 123.69,19.81 123.47,19.59 123.47,19.02 124.97,17.51 JDIMM2.146
DDR_B_MA11: length 74.2
  IN2 w0.076: 104.96,64.77 104.96,64.9 105.62,65.56 105.62,70.43 109.21,74.02 109.21,79.7 109.48,79.97 109.96,79.97 110.3,79.63 110.3,79.42 110.38,79.34 v2(110.66,79.34)
  IN2 w0.216: v2(115.78,19.38) 115.73,19.43 115.71,19.43 115.16,19.98 115.16,20.55 114.82,20.89 114.82,21.18 114.27,21.73 114.27,23.39 113.44,24.22 113.44,27.63 112.21,28.86 112.21,30.26 111.23,31.24 111.23,33.57 110.6,34.21 110.6,40.8 107.75,43.65 107.75,48.75 103.92,52.59 103.79,52.72 103.79,52.74 102.77,53.76 102.77,60.3 104.96,62.48 104.96,64.77
  BOTTOM w0.089: v2(110.66,79.34) 111.09,79.77 UC1.AN48
  BOTTOM w0.163: JDIMM2.120 116.48,17.74 116.48,18.69 v2(115.78,19.38)
DDR_B_MA12: length 71.7
  IN2 w0.076: 106.45,64.77 106.45,65.41 106.21,65.64 106.21,69.79 108.18,71.75 108.56,71.75 108.94,72.14 109.85,72.14 110.29,72.58 110.29,78.5 110.16,78.62 110.16,79.1 109.86,79.4 v2(109.77,79.4)
  IN2 w0.216: 106.45,64.77 106.45,61.87 105.28,60.7 105.28,59.68 105.06,59.47 104.48,59.47 104.26,59.25 104.26,58.82 104.48,58.6 105.06,58.6 105.28,58.39 105.28,57.95 105.06,57.74 104.48,57.74 104.26,57.52 104.26,57.09 104.48,56.88 105.06,56.88 105.28,56.66 105.28,56.23 105.06,56.01 104.48,56.01 104.26,55.8 104.26,55.36 104.48,55.15 105.06,55.15 105.28,54.93 105.28,53.91 105.28,53.33 106.35,52.26 106.35,52.26 109.37,49.24 109.37,44.17 112.72,40.82 112.72,31.86 114.93,29.65 114.93,24.83 115.76,24 115.76,23.22 v2(115.78,23.19)
  BOTTOM w0.076: v2(109.77,79.4) 109.76,79.42 109.76,80.05 109.85,80.15 110.11,80.15 110.2,80.05 UC1.AN50
  BOTTOM w0.163: JDIMM2.119 116.22,23.4 116.02,23.19 v2(115.78,23.19)
DDR_B_MA13: length 67.8
  IN2 w0.076: v2(115.43,70.27) 115.79,69.91 115.79,67 116.64,66.14 116.64,64.77
  IN2 w0.216: v2(128.56,19.26) 128.34,19.26 128.04,19.56 128.04,26.84 127.55,27.32 127.55,30.49 127.76,30.71 127.91,30.71 128.12,30.92 128.12,31.35 127.91,31.57 127.76,31.57 127.55,31.79 127.55,36.37 128.12,36.95 128.12,38.58 127.91,38.79 127.18,38.79 126.96,39.01 126.96,39.44 127.18,39.66 127.91,39.66 128.12,39.87 128.12,45.59 117.98,55.74 117.98,61.09 116.64,62.42 116.64,64.77
  BOTTOM w0.076: UC1.BA43 114.61,74.8 114.61,74.56 114.62,74.53 114.66,74.44 114.66,74.33 114.61,74.19 114.61,73.94 114.61,73.93 114.61,73.81 114.75,73.67 114.75,70.96 v2(115.43,70.27)
  BOTTOM w0.163: v2(128.56,19.26) 127.98,18.67 127.98,16.46 JDIMM2.158
DDR_B_ODT0: length 73.7
  IN2 w0.076: 117.3,64.77 117.3,65.72 115.96,67.06 115.96,70.73 115.82,70.86 v2(115.45,70.86)
  IN2 w0.216: v2(128.56,21.8) 128.53,21.83 128.53,25.16 128.85,25.47 129.6,25.47 129.82,25.69 129.82,26.98 129.56,27.24 128.33,27.24 128.12,27.46 128.12,27.89 128.33,28.11 129.6,28.11 129.82,28.32 129.82,29.77 129.6,29.99 128.84,29.99 128.62,30.2 128.62,32.16 128.4,32.37 128.26,32.37 128.04,32.59 128.04,33.02 128.26,33.23 128.4,33.23 128.62,33.45 128.62,33.88 128.4,34.1 128.26,34.1 128.04,34.31 128.04,34.75 128.26,34.96 128.4,34.96 128.62,35.18 128.62,42.66 128.84,42.88 130,42.88 130.22,43.09 130.22,43.74 130,43.96 128.84,43.96 128.62,44.17 128.62,45.79 118.61,55.8 118.61,61.15 117.3,62.46 117.3,64.77
  BOTTOM w0.076: v2(115.45,70.86) 115.08,70.86 114.91,71.03 114.91,73.74 114.78,73.87 114.78,73.95 114.77,73.96 114.77,74.16 114.83,74.29 114.83,74.63 114.9,74.71 UC1.BA42
  BOTTOM w0.163: v2(128.56,21.8) 128.56,21.78 128.06,21.28 127.55,21.28 127.36,21.47 127.36,21.91 127.53,22.07 127.85,22.07 128.01,22.23 128.01,22.56 127.85,22.72 127.53,22.72 127.36,22.88 127.36,23.54 127.23,23.68 JDIMM2.155
DDR_B_ODT1: length 74.8
  IN2 w0.076: 118.79,64.77 118.79,65.04 116.52,67.31 116.52,73.08 114.32,75.28 v2(114.32,76.88)
  IN2 w0.216: v2(130.04,19.96) 130.6,19.96 130.82,20.17 130.82,21.05 130.56,21.31 130.56,23.93 131.31,24.68 131.31,32.31 130.56,33.06 130.56,41.18 130.77,41.39 131.49,41.39 131.7,41.61 131.7,44.81 120.36,56.16 120.36,61.51 118.79,63.08 118.79,64.77
  BOTTOM w0.089: v2(114.32,76.88) 114.4,76.88 115.04,76.24 UC1.AW42
  BOTTOM w0.163: v2(130.04,19.96) 129.45,20.54 129.45,21.64 129.61,21.8 130.45,21.8 130.61,21.96 130.61,22.29 130.45,22.45 129.61,22.45 129.45,22.61 129.45,23.01 128.72,23.73 JDIMM2.161
DDR_B_PAR: length 73.5
  IN2 w0.076: 113.12,64.77 113.12,66.3 112.61,66.81 112.61,71.79 113.95,73.12 113.95,78.69 113.87,78.76 v2(113.43,78.76)
  IN2 w0.216: v2(123.03,23.51) 123.29,23.51 123.51,23.73 123.51,27.88 123.03,28.37 123.03,30.57 121.92,31.67 121.92,37.7 121.5,38.12 121.5,38.83 121.71,39.05 122.77,39.05 122.98,39.26 122.98,39.69 122.69,39.98 121.63,39.98 121.42,40.2 121.42,40.59 121.63,40.8 122.77,40.8 122.98,41.02 122.98,41.42 122.77,41.64 121.71,41.64 121.5,41.85 121.5,42.19 121.71,42.41 122.77,42.41 122.98,42.63 122.98,43.06 122.77,43.27 121.71,43.27 121.49,43.49 121.49,43.92 121.71,44.14 122.77,44.14 122.98,44.35 122.98,44.79 122.77,45 121.71,45 121.5,45.22 121.5,47.09 113.12,55.46 113.12,64.77
  BOTTOM w0.089: UC1.AP43 113.79,79.12 v2(113.43,78.76)
  BOTTOM w0.163: v2(123.03,23.51) 122.51,23.51 122.23,23.8 JDIMM2.143
DDR_B_RAS#: length 70
  IN2 w0.076: v2(113.19,71.55) 113.79,71.55 113.86,71.47 113.86,66.27 114.61,65.52 114.61,64.77
  IN2 w0.216: v2(126.1,18.88) 126.07,18.85 126.07,18.4 125.83,18.16 125.18,18.16 124.96,18.38 124.96,20.52 125.46,21.02 125.46,21.81 125,22.27 125,30.7 123.41,32.29 123.41,37.33 124.98,38.91 124.98,45.93 124.42,46.49 123.32,46.49 122.98,46.83 122.98,47.93 114.61,56.3 114.61,64.77
  BOTTOM w0.076: v2(113.19,71.55) 113,71.74 113,72.55 113.28,72.84 113.28,74.7 113.52,74.93 113.52,75.4 113.54,75.47 113.65,75.68 113.81,75.85 UC1.AW44
  BOTTOM w0.163: JDIMM2.152 126.47,18.5 v2(126.1,18.88)
DDR_B_WE#: length 72.1
  IN2 w0.076: 116.13,64.77 116.13,66.42 115.42,67.13 v2(115.42,69.07)
  IN2 w0.216: 116.13,64.77 116.13,62.23 116.83,61.53 116.83,56.18 126.47,46.55 126.47,45.81 126.68,45.6 127.41,45.6 127.63,45.38 127.63,44.95 127.41,44.73 126.68,44.73 126.47,44.52 126.47,44.09 126.68,43.87 127.41,43.87 127.63,43.66 127.63,43.22 127.41,43.01 126.68,43.01 126.47,42.79 126.47,42.36 126.68,42.14 127.41,42.14 127.63,41.93 127.63,41.5 127.41,41.28 126.68,41.28 126.47,41.06 126.47,35.2 126.25,34.98 125.62,34.98 125.4,34.76 125.4,34.33 125.62,34.12 126.31,34.12 126.52,33.9 126.52,33.47 126.31,33.25 125.73,33.25 125.51,33.04 125.51,32.29 125.73,32.07 126.25,32.07 126.47,31.86 126.47,31.33 127.05,30.74 127.05,28 126.49,27.43 126.49,26.86 126.99,26.35 126.99,25.85 127.19,25.65 127.35,25.65 127.54,25.46 127.54,25.08 127.32,24.86 126.7,24.86 126.49,24.65 126.49,24.21 126.7,24 127.32,24 127.54,23.79 127.54,22.9 127.32,22.69 v2(126.91,22.69)
  BOTTOM w0.076: UC1.AY44 113.81,75.11 113.92,75.01 113.92,75 113.99,74.78 113.99,74.65 113.93,74.42 113.93,74.28 113.98,74.16 113.98,73.89 113.78,73.69 113.78,72.84 114.27,72.35 114.27,70.23 v2(115.42,69.07)
  BOTTOM w0.163: JDIMM2.151 126.23,23.37 v2(126.91,22.69)
DDR_VTT_CNTL: length 28.6
  BOTTOM w0.076: UC1.AW67 99.75,76 99.66,76.09 99.18,76.09 99.1,76.16 97.68,76.16 97.4,75.88 96.96,75.88 96.16,75.08 94.95,75.08
  BOTTOM w0.102: 94.95,75.08 94.04,75.08 93.11,76.01 93.11,76.94 92.63,77.42 90.68,77.42 v1(88.74,75.48) 85.05,71.79 76.89,71.79 76.64,71.54 UC14.2
DGPU_HOLD_RST#: length 93
  TOP w0.102: v2(166.5,86.67) 165.49,87.68 165.49,91.61 157.77,99.33 155.41,99.33 151.12,103.61 151.12,105.09 150.17,106.04 150.17,112.27 147.06,115.38 v1(146.59,115.38) v2(145.94,115.38)
  IN2 w0.127: v2(138.74,89.79) 138.76,89.79 138.96,89.59 140.21,89.59 140.9,90.28 145.54,90.28 145.75,90.07 152.05,90.07 152.77,90.78 158.64,90.78 160.2,89.22 161.03,89.22 163.44,86.8 166.37,86.8 v2(166.5,86.67)
  BOTTOM w0.076: v2(138.74,89.79) 138.55,89.79 138.34,89.58 137.54,89.58 UC1.P3
  BOTTOM w0.102: UV2.2 138.72,128.73 138.39,128.4 138.39,127.29 139.96,125.71 143.44,125.71 145.94,123.21 v2(145.94,115.38) ; v2(138.74,89.79) 138.89,89.64 140.14,89.64 140.29,89.79 140.72,89.79 RC383.1
DGPU_PWR_EN: length 150.8
  TOP w0.102: v2(145.71,112) 147.68,110.03 147.68,95.2 148.37,94.52 v2(148.37,92.2) ; R6510.1 144.01,160.27 143.59,160.69 141.76,160.69 141.09,160.02 ; 141.09,160.02 v1(140.54,160.57) 140.29,160.82 v2(139.65,160.82) ; 141.09,160.02 R437.1
  IN1 w0.127: v2(153.33,108.53) 152.66,109.19 152.66,112.97 152.79,113.09 v2(152.9,113.09) 152.96,113.09 153.54,113.66 153.54,115.32 155.65,117.43 158.76,117.43 v2(160.2,118.87) ; v2(139.65,160.82) 139.65,158.58 138.3,157.23 138.3,142.94 139.44,141.8 139.44,135.64 137.22,133.41 137.22,131.7 136.77,131.25 136.77,130.75 143.86,123.66 143.86,117.79 145.02,116.64 145.02,112.7 v2(145.71,112) ; v2(139.76,88.71) 139.76,89.07 140.16,89.47 142.81,89.47 143.8,88.48 146.47,88.48 146.87,88.88 146.87,92.28 147.28,92.68 147.88,92.68 v2(148.37,92.2)
  BOTTOM w0.102: v2(145.71,112) 145.71,112.95 146.81,114.05 151.95,114.05 v2(152.9,113.09) ; UC1.U1 138.92,87.87 v2(139.76,88.71) ; v2(148.37,92.2) 148.65,91.92 RC358.2 ; RZ79.1 RC359.2 182,118.78 182,120.6 181.24,121.36 177.43,121.36 174.64,118.57 169.76,118.57 169.22,118.03 161.06,118.03 160.22,118.87 v2(160.2,118.87) ; PR1116.1 v2(153.33,108.53)
DGPU_PWROK: length 75.5
  TOP w0.102: v2(138.23,98.39) 138.23,99.51 v1(140.14,101.41) 140.14,102.53 v2(140.57,102.96)
  IN1 w0.127: v2(140.57,102.96) 140.73,103.12 140.73,105.15 139.74,106.14 139.74,112.79 138.55,113.99 138.55,120.64 137.3,121.88 136.53,121.88 136.29,121.64 135.3,121.64 131.64,125.3 131.64,127.3 131.39,127.56 130.17,127.56 129.27,128.46 129.27,130.28 v2(128.45,131.09)
  IN2 w0.127: v2(153.33,109.42) 152.01,108.1 152.01,107.15 148.79,103.93 148.79,103.84 146.61,101.66 146.61,100.65 143.61,97.64 141.93,97.64 141.12,96.83 138.73,96.83 138.23,97.32 v2(138.23,98.39)
  BOTTOM w0.076: UC1.C8 134.38,96.92 134.87,97.41
  BOTTOM w0.102: v2(140.57,102.96) 141.02,103.42 RC360.2 ; v2(138.23,98.39) 137.82,97.98 137.47,97.98 137.09,98.36 135.69,98.36 134.87,97.54 134.87,97.41 ; PR1122.2 v2(153.33,109.42)
  BOTTOM w0.254: PR1403.1 125.21,132.59 126.71,131.09 v2(128.45,131.09)
DIMM_CHA_SA0: length 12.9
  BOTTOM w0.102: v1(154.03,34.58) 152.43,34.58 152.08,34.24 RD28.1 RD1.2 145.29,33.21 143.87,31.8 JDIMM1.256
DIMM_CHA_SA1: length 9.3
  BOTTOM w0.102: RD29.1 RD2.2 145.48,32.33 144.87,31.72 JDIMM1.260
DIMM_CHA_SA2: length 5.2
  TOP w0.102: v2(120.87,28.86) 120.2,29.53 RD30.1 ; v2(120.87,28.86) 120.43,28.42 v1(120.38,28.42) ; v2(120.87,28.86) 120.91,28.91 RD3.2
  BOTTOM w0.102: JDIMM1.166 121.37,29.37 v2(120.87,28.86)
DIMM_CHB_SA0: length 12.5
  BOTTOM w0.102: JDIMM2.256 152.47,17.22 153.22,17.97 156.83,17.97 RD4.2 RD38.1 v1(160.51,23.53)
DIMM_CHB_SA1: length 11.4
  BOTTOM w0.102: JDIMM2.260 153.47,17.4 153.79,17.72 157.16,17.72 160.2,20.76 RD5.2 RD39.1 160.51,19.14 v1(160.23,18.87)
DIMM_CHB_SA2: length 4.5
  TOP w0.102: v1(131.51,14.05) 130.87,14.05 RD6.2 RD40.1 129.53,14.54 v2(130.17,15.18)
  BOTTOM w0.102: JDIMM2.166 129.97,15.37 v2(130.17,15.18)
DMIC_CLK: length 262.9
  IN1 w0.127: v2(133.34,152.15) 134.42,151.07 134.42,150.37 136.45,148.34 136.45,139.95 136.01,139.51 136.01,130.3 142.93,123.38 142.93,117.6 144.14,116.4 144.14,111.63 145.03,110.74 145.03,101.16 148.14,98.04 151,98.04 152.2,99.25 152.96,99.25 153.57,98.64 153.68,98.64 153.68,96.36 153.95,96.09 158.03,96.09 165.66,88.46 167.11,88.46 168.44,87.12 171.49,87.12 171.67,86.94 173.49,86.94 174.13,86.3 179.95,86.3 180.87,85.38 186.88,85.38 187.8,84.45 190.11,84.45 192.72,81.85 192.72,77.76 192.59,77.64 192.59,76.14 192.33,75.88 192.33,73.34 190.51,71.51 190.51,69.58 191.51,68.58 191.51,67.44 189.92,65.85 189.92,58.13 v2(190.46,57.59)
  IN2 w0.127: v2(190.46,57.59) 190.46,56.81 192.09,55.18 192.09,36.01 189.41,33.34 189.41,31.56 188.4,30.54 185.73,30.54 185.22,31.05 181.98,31.05 178.43,27.5 178.43,24.19 174.55,20.32 174.55,18.16 175.38,17.34 175.38,15.56 174.87,15.05 174.87,14.03 v2(175.51,13.4) ; v2(133.34,152.15) 133.09,152.15 131.77,150.83 121.86,150.83 121.78,150.75 111.12,150.75 110.74,151.13 107.56,151.13 106.8,151.89 106.8,156.89 107.31,157.4 107.31,158.81 106.8,159.32 106.1,159.32 105.4,158.62 105.4,158.28 103.78,156.65 103.18,156.65 102.67,157.16 102.67,158.05 101.72,159 101.72,159.44 100.39,160.78 100.39,162.4 97.62,165.16 95.5,165.16 94.86,164.53 94.48,164.53 v2(94.04,164.97)
  BOTTOM w0.102: v2(175.51,13.4) 175.64,13.4 C2723.2 R2716.1 ; LCD1.28 94.3,165.24 v2(94.04,164.97) 94.04,164.85 93.76,164.57 93.76,163.22 94.29,162.69 94.29,159.28 R5207.2
DMIC_CLK_R: length 2.7
  BOTTOM w0.102: HDA27.3 179.92,14.89 179.83,14.99 178.94,14.99 R2716.2
DMIC_DATA: length 257.1
  IN1 w0.127: v2(133.34,152.78) 133.98,152.78 134.68,152.08 134.68,150.5 136.71,148.46 136.71,139.76 136.26,139.32 136.26,130.43 143.22,123.47 143.22,117.71 144.39,116.54 144.39,111.78 145.32,110.86 145.32,101.25 148.27,98.3 150.87,98.3 152.08,99.5 153.07,99.5 153.68,98.9 156.73,98.9 158.54,97.09 158.54,95.96 165.79,88.71 167.21,88.71 167.78,88.14 170.83,88.14 171.78,87.19 173.6,87.19 174.24,86.55 180.08,86.55 180.95,85.68 186.98,85.68 187.89,84.77 190.18,84.77 192.97,81.98 192.97,77.6 192.84,77.47 192.84,76.01 192.59,75.76 192.59,73.22 190.81,71.44 190.81,69.64 191.76,68.69 191.76,67.31 190.24,65.79 190.24,58.67 191.32,57.59 191.32,56.96 190.46,56.1 v2(190.46,55.5)
  IN2 w0.127: v2(94.67,164.97) 94.8,164.97 95.24,165.42 97.75,165.42 100.64,162.53 100.64,160.91 101.98,159.57 101.98,159.13 102.93,158.18 102.93,157.29 103.31,156.91 103.67,156.91 105.15,158.38 105.15,158.75 105.97,159.58 106.91,159.58 107.56,158.92 107.56,157.27 107.05,156.76 107.05,152.02 107.69,151.38 110.86,151.38 111.21,151.04 121.69,151.04 121.73,151.08 131.64,151.08 v2(133.34,152.78) ; v2(175.48,12.8) 174.61,13.67 174.61,15.16 175.12,15.67 175.12,17.23 174.29,18.05 174.29,20.43 178.17,24.3 178.17,27.6 181.88,31.31 185.33,31.31 185.84,30.8 188.28,30.8 189.16,31.69 189.16,33.46 191.83,36.13 191.83,53.85 190.46,55.22 v2(190.46,55.5)
  BOTTOM w0.102: LCD1.29 94.8,165.1 v2(94.67,164.97) ; R2714.1 176.21,13.3 v1(175.99,13.08) 175.71,12.8 v2(175.48,12.8)
DMIC_DATA_R: length 3.7
  BOTTOM w0.102: EC2701.1 R2714.2 v1(179.1,14.2) 179.39,14.49 HDA27.2
DP_CRT_B: length 4.5
  TOP w0.102: U5502.10 24.8,65.09 R5501.1 C5509.1 22.47,64.37 L5502.1
DP_CRT_G: length 5.7
  TOP w0.102: U5502.12 25.2,64.09 25.11,64 v1(25.05,64) 24.92,63.87 24.92,62.71 24.29,62.08 R5513.1 C5512.1 22.34,62.08 L5501.1
DP_CRT_HSYNC_CON: length 3.9
  TOP w0.102: U5502.8 27,67.08 25.92,68.15 R5511.1 25.02,68.41 v1(24.67,68.76)
DP_CRT_R: length 6.3
  TOP w0.102: L5503.1 22.41,59.42 C5506.1 R5514.1 24.11,59.42 v1(25.06,60.37) 25.06,61.81 25.83,62.59 U5502.15
DP_CRT_VSYNC_CON: length 2.5
  TOP w0.102: U5502.7 v1(27.5,67.5) 27.23,67.5 26.81,67.92 R5507.1
DQA0_0: length 36.5
  BOTTOM w0.102: UV1.K27 159.51,144.11 158.5,145.11 158.5,145.62 158.55,145.66 158.55,145.93 157.79,146.69 156.21,148.27 156.05,148.27 156,148.32 ; UV17.C2 169.34,163.3 168.9,163.74 167.91,163.74 167.26,163.1 167.05,163.1 166.93,162.98
  BOTTOM w0.127: 156,148.32 154.91,149.41 154.91,150.96 163.2,159.26 163.38,159.26 164.37,158.27 164.55,158.27 164.73,158.45 164.73,158.63 v1(164.22,159.14) 163.74,159.61 163.74,159.79 163.92,159.97 164.1,159.97 165.09,158.99 165.27,158.99 165.45,159.17 165.45,159.35 164.46,160.33 164.46,160.51 166.09,162.14 166.27,162.14 166.46,161.95 166.64,161.95 166.82,162.12 166.82,162.3 166.63,162.5 166.63,162.68 166.93,162.98
DQA0_1: length 35.9
  BOTTOM w0.102: UV17.A2 168.74,162.03 168.52,161.81 ; UV1.J29 159.63,145.55 159.2,145.55 158.79,145.96 158.79,145.98 158.15,146.62 158.15,146.63
  BOTTOM w0.117: 168.52,161.81 168.52,161.78
  BOTTOM w0.127: 168.52,161.78 167,160.26 164.73,157.98 164.73,157.98 164.55,157.8 164.37,157.8 163.38,158.79 163.2,158.79 163.02,158.61 163.02,158.43 164.01,157.44 164.01,157.26 163.83,157.08 163.65,157.08 162.66,158.07 162.49,158.07 162.31,157.89 162.31,157.71 163.29,156.72 163.29,156.54 163.11,156.36 162.93,156.36 v1(162.49,156.81) 161.95,157.35 161.77,157.35 161.59,157.17 161.59,156.99 162.57,156.01 162.57,155.83 162.39,155.65 162.21,155.65 161.23,156.63 161.05,156.63 160.83,156.42 160.83,156.24 160.91,156.17 160.91,155.99 160.73,155.81 160.55,155.81 160.48,155.88 160.3,155.88 155.24,150.82 155.24,149.55 158.15,146.63
DQA0_2: length 35.5
  BOTTOM w0.102: 157,148.88 159.5,146.37 UV1.H30 ; 168.05,160.83 168.3,161.08 168.48,161.08 169,161.61 UV17.A3
  BOTTOM w0.127: 168.05,160.83 162.28,155.07 162.1,155.07 161.37,155.8 161.19,155.8 161.01,155.62 161.01,155.44 161.74,154.71 161.74,154.53 161.56,154.35 161.38,154.35 160.4,155.33 160.22,155.33 160.04,155.15 160.04,154.97 161.02,153.99 161.02,153.81 160.84,153.63 160.66,153.63 v1(160.2,154.09) 159.68,154.62 159.5,154.62 159.32,154.44 159.32,154.26 160.3,153.27 160.3,153.09 160.12,152.91 159.94,152.91 158.96,153.9 158.78,153.9 155.57,150.69 155.57,150.31 155.85,150.02 156.03,150.02 156.57,150.56 156.75,150.56 156.93,150.38 156.93,150.2 156.39,149.66 156.39,149.48 157,148.88
DQA0_3: length 35.3
  BOTTOM w0.102: 157.19,149.29 157.19,148.98 159.23,146.94 UV1.H32 ; 168.28,160.6 168.85,161.17 169.33,161.17 169.63,161.47 169.63,161.96 169.55,162.04 169.55,162.31 169.8,162.56 170.26,162.56 UV17.C3
  BOTTOM w0.127: 157.19,149.29 157.19,149.51 157.3,149.62 157.48,149.62 158.3,148.8 158.47,148.8 158.65,148.98 158.65,149.16 157.84,149.98 157.84,150.16 158.06,150.38 158.06,150.56 157.71,150.9 157.53,150.9 157.29,150.66 157.11,150.66 156.94,150.84 156.94,151.02 157.17,151.26 157.17,151.44 157.07,151.54 157.07,151.72 157.25,151.9 157.43,151.9 158.42,150.92 158.6,150.92 158.78,151.09 158.78,151.27 v1(158.33,151.72) 157.79,152.26 157.79,152.44 157.97,152.62 158.15,152.62 159.14,151.63 159.32,151.63 159.49,151.81 159.49,151.99 158.51,152.98 158.51,153.16 158.69,153.34 158.87,153.34 159.85,152.35 160.03,152.35 168.28,160.6
DQA0_4: length 35.6
  BOTTOM w0.102: 163.31,151.69 161.8,151.69 160.1,150 160.1,147.77 160.53,147.35 160.53,146.92 UV1.G29
  BOTTOM w0.127: 163.31,151.69 163.74,152.12 163.74,152.3 162.73,153.31 162.73,153.49 162.91,153.67 163.09,153.67 164.1,152.66 164.28,152.66 164.46,152.84 164.46,153.02 v1(163.91,153.57) 163.45,154.03 163.45,154.21 163.63,154.39 163.81,154.39 164.82,153.38 165,153.38 166,154.38 166.18,154.38 166.38,154.19 166.56,154.19 166.74,154.37 166.74,154.55 166.54,154.74 166.54,154.92 167.91,156.29 168.09,156.29 168.79,155.58 168.97,155.58 169.15,155.76 169.15,155.94 168.45,156.65 168.45,156.83 168.63,157.01 168.8,157.01 169.51,156.3 169.69,156.3 169.87,156.48 169.87,156.66 169.16,157.37 169.16,157.55 169.45,157.83 169.45,158.01 168.54,158.92 168.54,159.1 168.72,159.28 168.9,159.28 169.81,158.37 169.99,158.37 170.17,158.55 170.17,158.73 169.36,159.54 169.36,159.72 169.54,159.9 169.72,159.9 170.53,159.09 170.71,159.09 170.96,159.34 UV17.A7
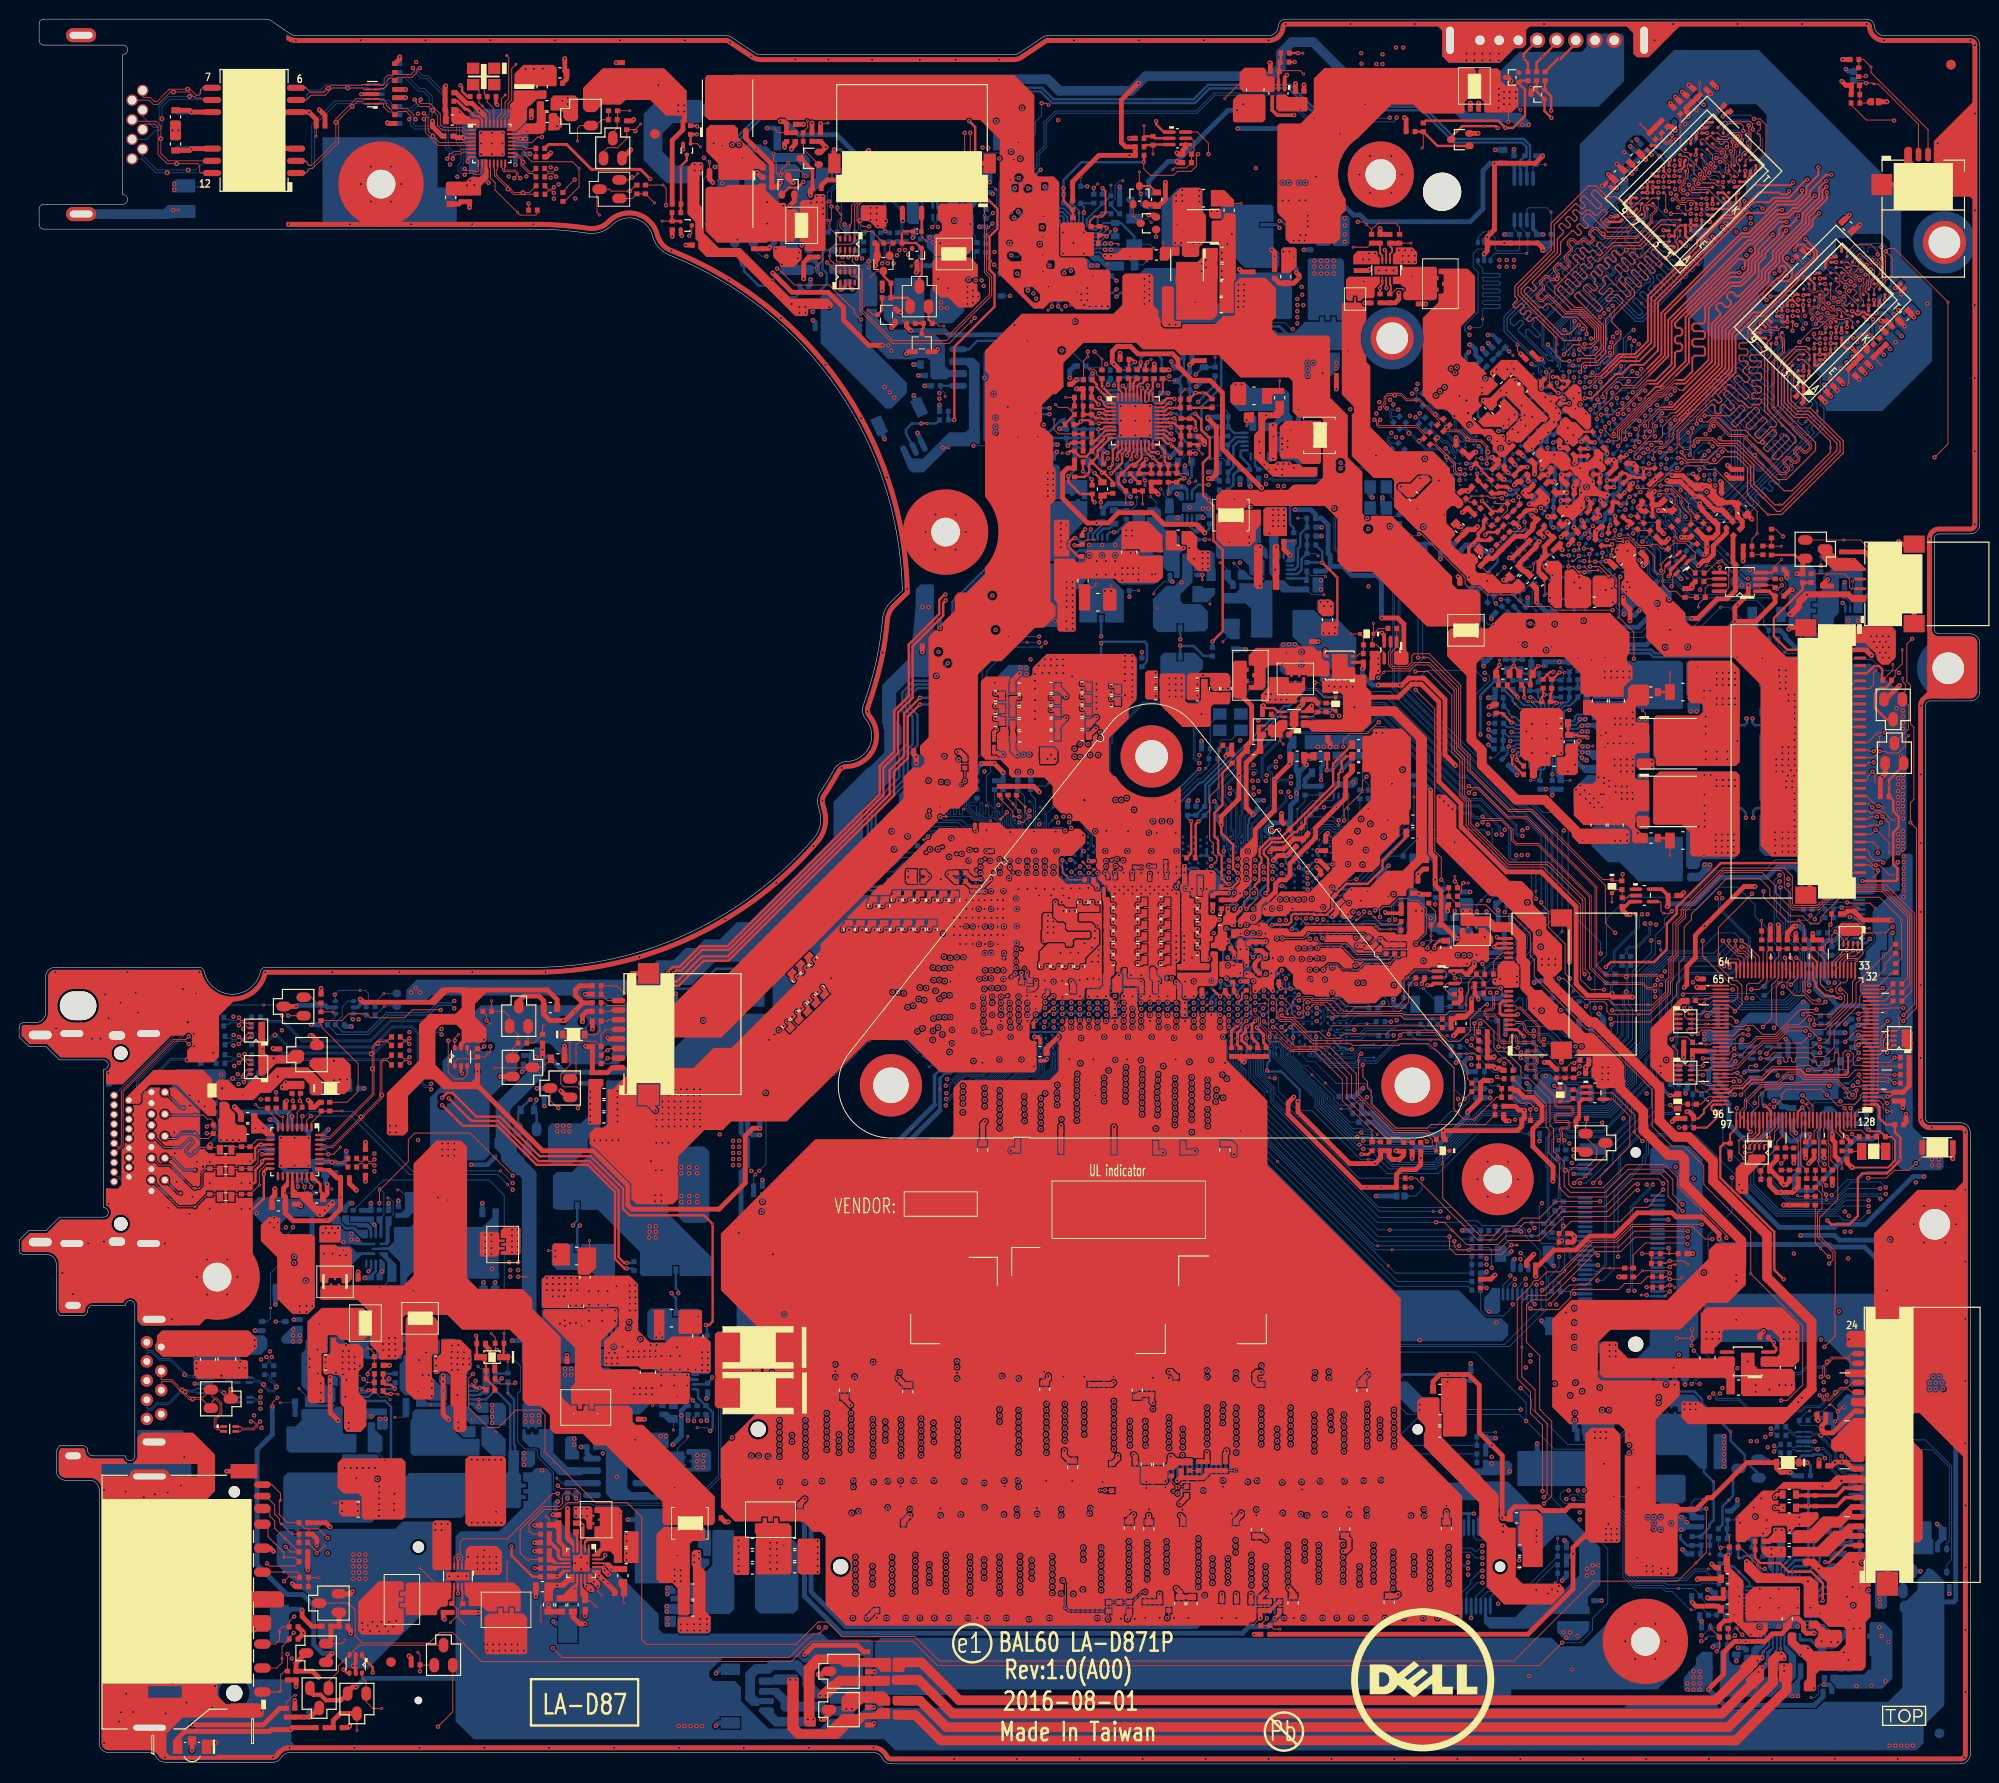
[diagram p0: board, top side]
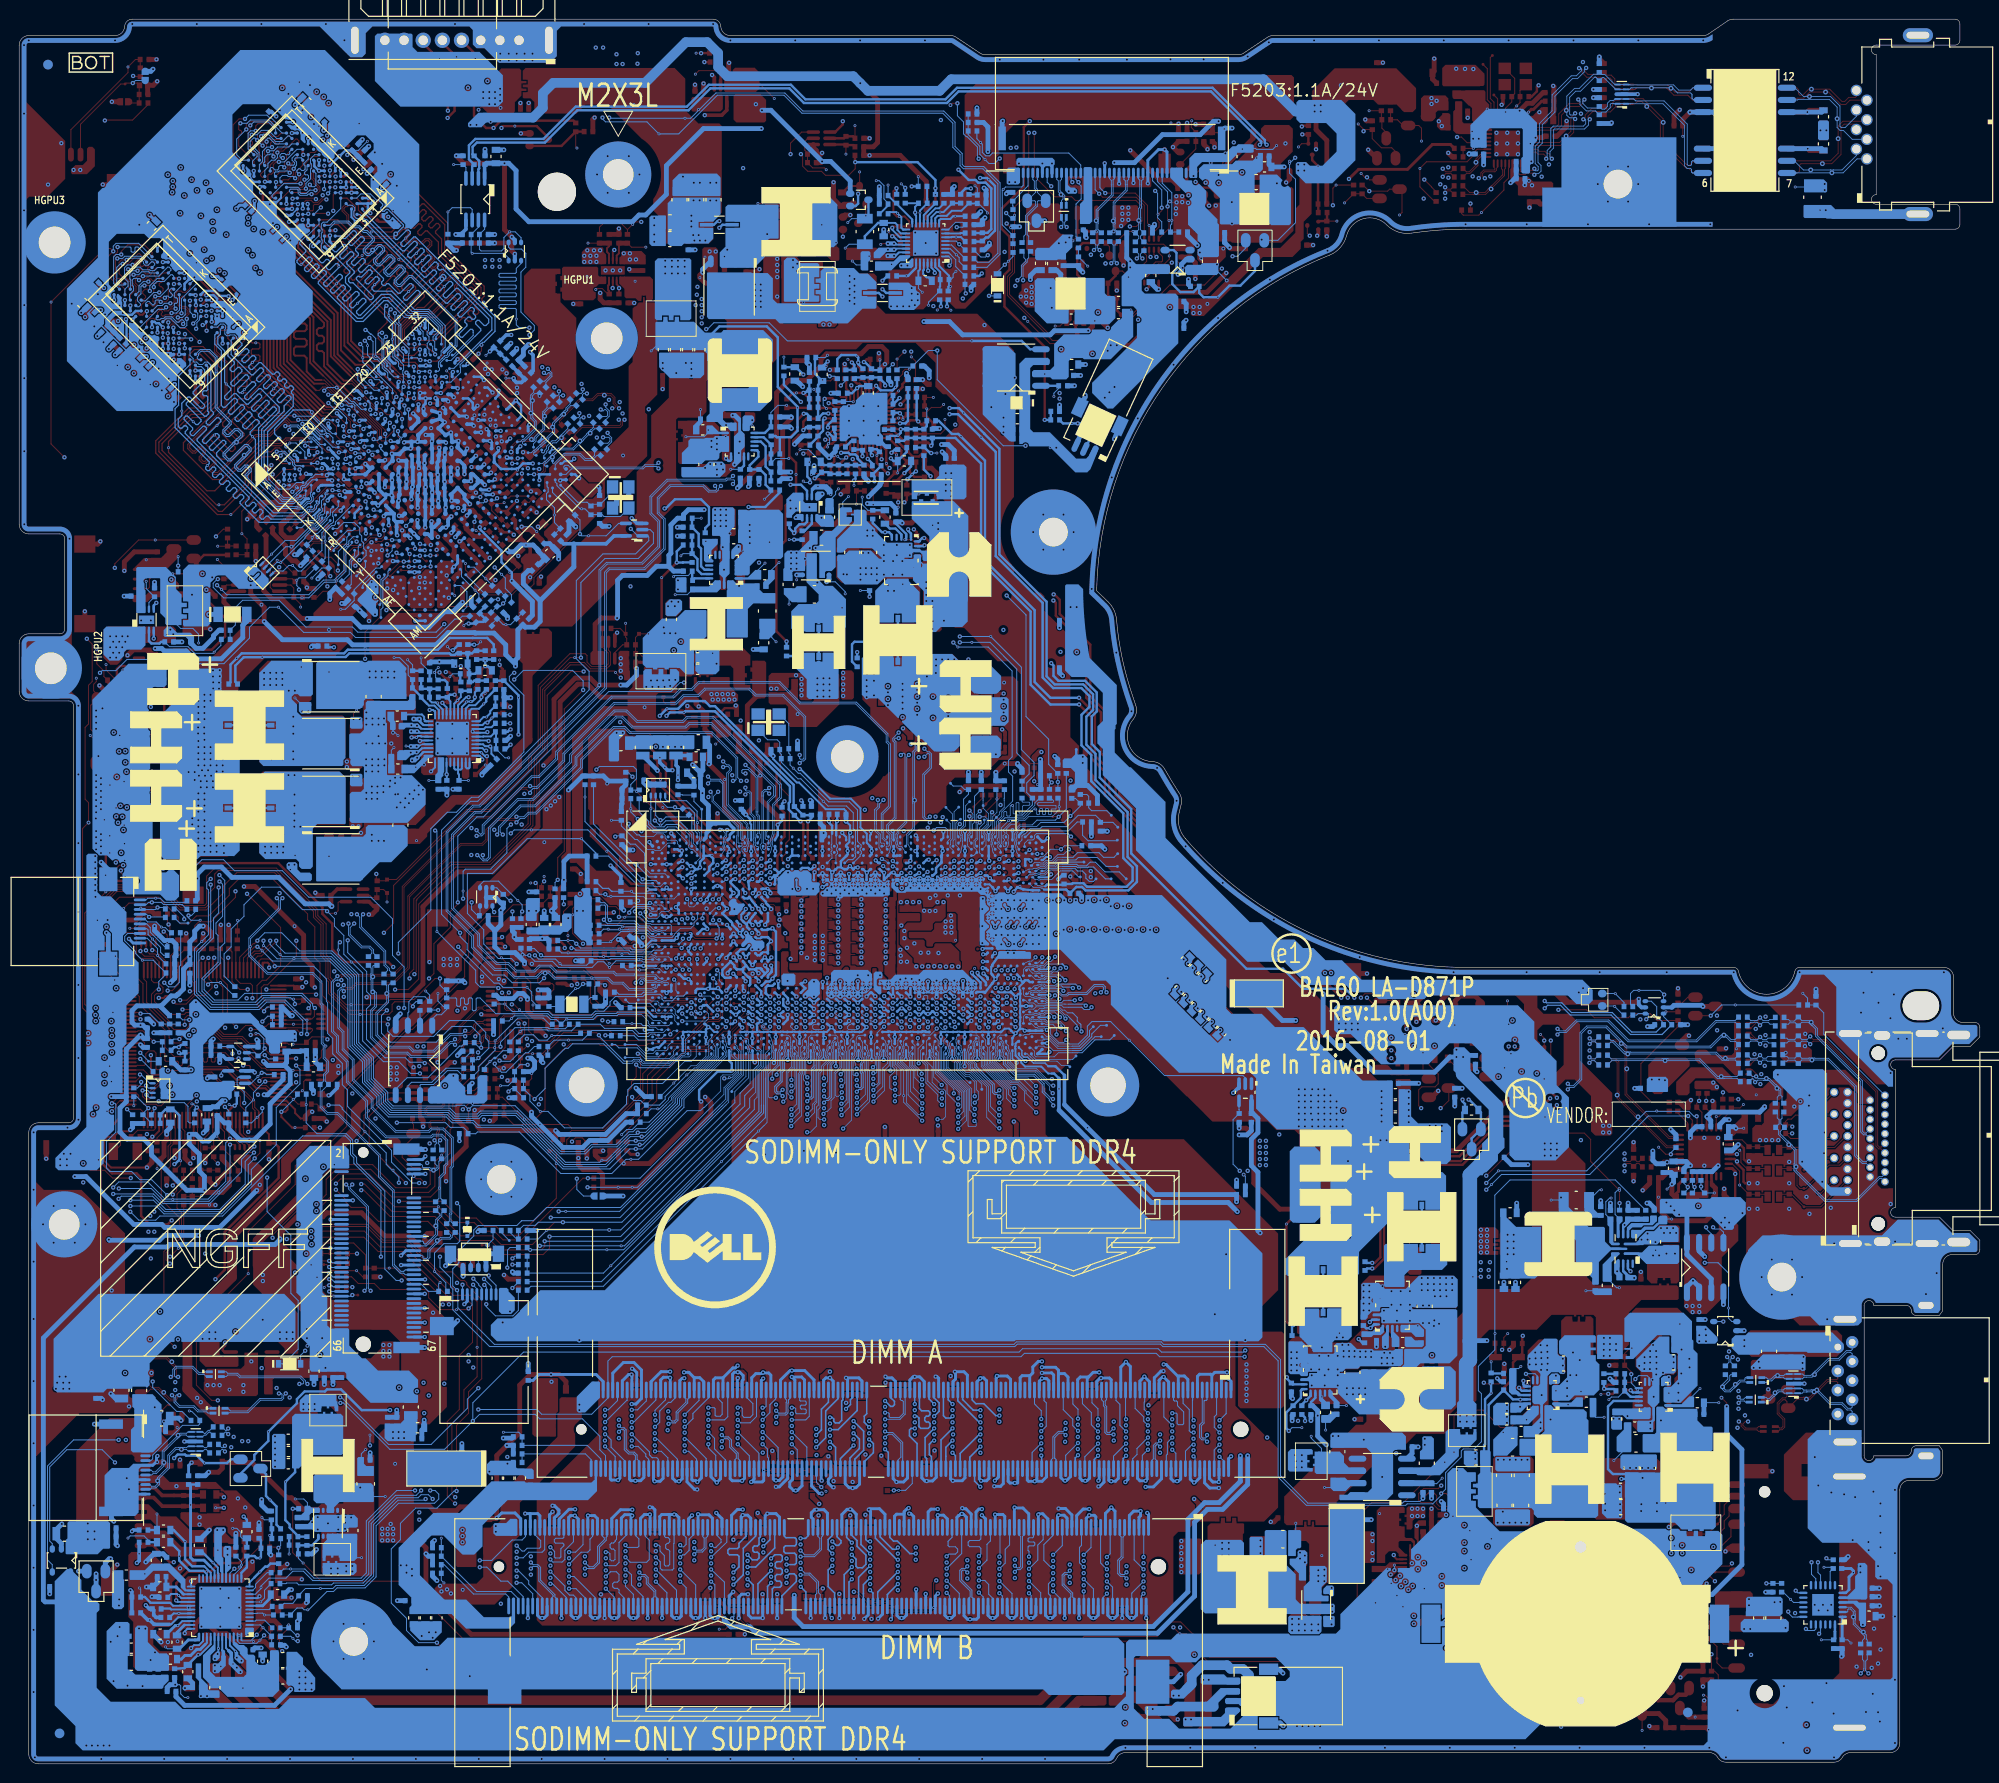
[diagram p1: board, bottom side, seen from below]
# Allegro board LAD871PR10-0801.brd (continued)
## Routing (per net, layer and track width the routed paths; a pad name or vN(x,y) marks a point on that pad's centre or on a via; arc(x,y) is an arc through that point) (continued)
DQA0_5: length 35.5
  BOTTOM w0.102: UV17.D7 173.27,160.58 174.41,159.44 174.54,159.44 175.28,158.7 175.28,158.52 ; 165.27,151.78 164.36,150.87 162.13,150.87 161.85,150.59 161.85,149.49 161.99,149.35 161.99,149.05 161.79,148.85 161.79,148.35 161.98,148.16 161.98,147.71 161.79,147.52 161.79,147.1 161.64,146.95 UV1.F28
  BOTTOM w0.127: 165.27,151.78 166.1,152.61 166.49,152.61 168.66,150.44 169.39,150.44 173.34,154.39 173.34,154.57 172.51,155.4 172.51,155.58 172.69,155.76 172.87,155.76 173.7,154.93 173.88,154.93 174.06,155.11 174.06,155.29 173.27,156.08 173.27,156.26 173.45,156.44 173.63,156.44 174.42,155.65 174.6,155.65 174.78,155.83 174.78,156.01 173.99,156.8 173.99,156.98 174.17,157.16 174.35,157.16 v1(175.14,156.37) 175.32,156.37 175.57,156.62 175.57,156.8 174.65,157.71 174.65,157.89 175.28,158.52
DQA0_6: length 34.7
  BOTTOM w0.102: 164.57,152.48 163.56,151.48 161.87,151.48 160.42,150.03 160.42,149.22 160.51,149.14 UV1.F32 ; 171.81,157.88 172.7,158.77 UV17.B8
  BOTTOM w0.127: 171.81,157.88 171.62,157.71 171.44,157.71 170.71,158.44 170.53,158.44 170.35,158.26 170.35,158.09 171.08,157.35 171.08,157.17 170.9,156.99 170.72,156.99 170.01,157.71 169.83,157.71 169.65,157.53 169.65,157.35 170.37,156.63 170.37,156.45 169.59,155.68 169.59,155.5 170.17,154.92 170.17,154.62 170.03,154.48 169.72,154.48 167.97,152.72 167.79,152.72 167.61,152.9 167.61,153.08 169.36,154.84 169.36,155.01 169.23,155.14 169.05,155.14 169,155.09 168.82,155.09 168.09,155.82 167.91,155.82 167.73,155.64 167.73,155.46 168.46,154.73 168.46,154.55 168.28,154.37 168.1,154.37 167.37,155.1 167.19,155.1 167.01,154.92 167.01,154.74 v1(167.46,154.29) 167.74,154.01 167.74,153.83 167.51,153.6 165.69,153.6 164.57,152.48
DQA0_7: length 35.2
  BOTTOM w0.102: 165.03,152.01 165.03,152.01 164.1,151.07 162.04,151.07 160.83,149.86 160.83,149.39 161.38,148.84 161.38,148.51 161.2,148.33 161.2,147.63 UV1.F30 ; UV17.C8 173.27,159.4 173.99,158.68 174.02,158.68 174.26,158.44
  BOTTOM w0.127: 165.03,152.01 165.96,152.94 166.63,152.94 168.8,150.77 169.25,150.77 171.35,152.86 171.35,153.04 170.53,153.86 170.53,154.04 170.71,154.22 170.88,154.22 171.7,153.4 171.88,153.4 172.06,153.58 172.06,153.76 v1(171.45,154.37) 170.83,154.99 170.83,155.17 171.01,155.35 171.19,155.35 172.42,154.12 172.6,154.12 172.78,154.3 172.78,154.48 171.14,156.12 171.14,156.3 171.32,156.48 171.5,156.48 172.13,155.85 172.31,155.85 172.49,156.03 172.49,156.21 172.15,156.55 172.15,156.73 172.33,156.91 172.51,156.91 172.85,156.57 173.03,156.57 174.26,157.8 174.26,158.44
DQA0_8: length 34.9
  TOP w0.127: UV18.A7 169.19,161.61 167.79,160.21 165.73,160.21 165.02,160.93 165.02,161.11 165.63,161.72 165.63,161.9 v1(165.53,161.99) 165.41,162.12 165.23,162.12 164.61,161.51 164.44,161.51 163.89,162.05 163.49,162.05 163.09,161.65 162.91,161.65 162.46,162.1 162.28,162.1 162.1,161.92 162.1,161.74 162.55,161.29 162.55,161.11 162.37,160.93 162.19,160.93 161.74,161.38 161.56,161.38 161.38,161.2 161.38,161.02 161.83,160.57 161.83,160.39 161.65,160.21 161.47,160.21 161.02,160.66 160.84,160.66 160.66,160.48 160.66,160.3 161.11,159.85 161.11,159.67 160.48,159.05 160.48,157.63 156.7,153.84 156.7,153.34 160.94,149.1 161.72,149.1 v2(162.71,150.08)
  BOTTOM w0.102: v2(162.71,150.08) 162.71,149.67 162.41,149.38 162.41,148.85 UV1.C30
DQA0_9: length 36.3
  TOP w0.127: v2(161.73,146.3) 160.97,146.3 160.33,146.94 160.33,148.77 158.25,150.85 158.07,150.85 157.68,150.47 157.44,150.47 157.29,150.61 157.29,150.79 157.71,151.21 157.71,151.39 157.53,151.57 157.35,151.57 156.96,151.18 156.78,151.18 156.6,151.36 156.6,151.54 156.99,151.93 156.99,152.11 156.81,152.29 156.63,152.29 156.21,151.87 156.03,151.87 155.85,152.05 155.85,152.23 v1(156.08,152.46) 156.27,152.65 156.27,152.83 156.04,153.07 156.04,154.12 159.82,157.9 159.82,160.68 163.74,164.59 164.49,164.59 165.63,163.45 166.55,163.45 167.6,162.4 168.43,162.4 169.33,163.3 UV18.C8
  BOTTOM w0.102: UV1.F27 162.18,146.35 161.78,146.35 v2(161.73,146.3)
DQA0_10: length 35.2
  TOP w0.127: UV18.D7 170.35,163.3 169.47,162.43 169.47,162.02 169.64,161.86 169.64,161.75 169.64,161.75 169.64,161.47 169.64,161.46 169.64,161.39 169.43,161.18 169.23,161.18 v1(167.82,159.77) 165.71,159.77 163.87,161.61 163.51,161.61 163.19,161.28 163.19,161.04 163.69,160.55 163.69,160.37 163.51,160.19 163.33,160.19 162.89,160.62 162.71,160.62 162.53,160.44 162.53,160.26 162.96,159.83 162.96,159.63 162.78,159.45 162.6,159.45 162.16,159.89 161.98,159.89 160.81,158.72 160.81,157.49 157.89,154.57 157.89,154.39 158.24,154.05 158.24,153.8 158.06,153.63 157.88,153.63 157.5,154 157.32,154 157.03,153.71 157.03,153.48 158.62,151.89 158.96,151.89 159.34,152.27 159.66,152.27 161.06,150.88 162.48,150.88 163.54,149.82 v2(163.54,149.14)
  BOTTOM w0.102: UV1.A28 163.33,148.93 v2(163.54,149.14)
DQA0_11: length 35.5
  TOP w0.127: UV18.B8 169.16,162.59 169.16,162.05 168.45,161.34 167.47,161.34 165.94,162.88 165.72,162.88 164.47,164.12 164.3,164.12 164.08,163.89 164.08,163.64 165.09,162.63 165.09,162.45 164.88,162.24 164.59,162.24 v1(163.91,162.92) 163.31,163.52 163.13,163.52 162.86,163.25 162.86,163.07 163.35,162.58 163.35,162.4 163.17,162.22 162.99,162.22 162.5,162.71 162.32,162.71 160.15,160.54 160.15,157.77 156.37,153.98 156.37,153.2 161.11,148.46 162.65,148.46 v2(162.8,148.61)
  BOTTOM w0.102: UV1.C28 162.77,148.58 v2(162.8,148.61)
DQA0_12: length 35.9
  TOP w0.127: v2(162.74,147.52) 163.36,146.9 164.32,146.9 165.03,147.61 165.03,149.86 162.99,151.9 162.29,151.9 160.55,153.64 160.55,153.89 160.77,154.11 160.95,154.11 161.75,153.31 161.93,153.31 162.11,153.49 162.11,153.67 161.32,154.46 161.32,154.66 161.51,154.85 161.69,154.85 162.45,154.09 162.7,154.09 162.86,154.25 162.86,154.43 162.06,155.22 162.06,155.4 162.27,155.61 162.45,155.61 163.16,154.9 163.41,154.9 163.57,155.07 163.57,155.32 162.87,156.02 162.87,156.2 163.1,156.44 163.28,156.44 163.73,155.98 163.91,155.98 164.11,156.18 164.11,156.36 163.66,156.82 163.66,157 163.82,157.16 164.08,157.16 164.55,156.69 164.73,156.69 v1(164.95,156.91) 166.38,158.34 169.08,158.34 171.29,160.54 172.63,160.54 UV18.C3
  BOTTOM w0.102: UV1.E27 162.74,146.96 v2(162.74,147.52)
DQA0_13: length 37.1
  TOP w0.127: UV18.A2 170.81,158.78 169.15,157.11 168.97,157.11 v1(168.78,157.31) 168.4,157.68 168.23,157.68 168.05,157.5 168.05,157.32 168.59,156.78 168.59,156.6 168.41,156.42 168.16,156.42 167.5,157.09 167.32,157.09 167.17,156.94 167.17,156.76 167.89,156.04 167.89,155.85 167.71,155.67 167.53,155.67 166.86,156.34 166.68,156.34 166.5,156.16 166.5,155.98 167.17,155.31 167.17,155.13 166.89,154.85 166.89,154.67 168.14,153.42 168.14,153.24 167.93,153.03 167.75,153.03 165.59,155.19 165.41,155.19 165.22,154.99 165.22,154.75 165.49,154.48 165.49,154.3 164.85,153.65 164.85,153.47 165.03,153.29 165.27,153.29 165.89,153.9 166.07,153.9 166.24,153.73 166.24,153.54 165.57,152.87 165.57,152.69 165.72,152.54 165.9,152.54 166.57,153.22 166.75,153.22 167.29,152.68 167.29,152.44 165.51,150.66 165.51,147.17 164.52,146.18 163.25,146.18 162.98,145.91 162.98,145.56 162.99,145.55 162.99,145.31 v2(162.86,145.17)
  BOTTOM w0.102: v2(162.86,145.17) 162.81,145.22 162.74,145.22 162.73,145.24 162.2,145.24
DQA0_14: length 35.8
  TOP w0.127: UV18.A3 170.55,159.34 169.22,158.01 167.77,158.01 167.14,157.38 166.96,157.38 v1(166.77,157.57) 166.51,157.83 166.33,157.83 166.15,157.65 166.15,157.47 166.6,157.02 166.6,156.84 166.42,156.66 166.24,156.66 165.79,157.11 165.61,157.11 165.43,156.93 165.43,156.75 165.88,156.3 165.88,156.12 165.7,155.94 165.52,155.94 165.07,156.39 164.9,156.39 164.72,156.21 164.72,156.03 165.17,155.58 165.17,155.4 164.98,155.22 164.81,155.22 164.36,155.67 164.18,155.67 164,155.49 164,155.31 164.45,154.87 164.45,154.69 164.33,154.57 164.33,154.39 164.63,154.08 164.63,153.9 164.4,153.67 164.2,153.67 163.61,154.27 163.43,154.27 163.19,154.03 163.19,153.85 165.13,151.92 165.13,151.74 164.93,151.54 164.69,151.54 162.74,153.48 162.56,153.48 162.28,153.2 162.28,153.02 165.28,150.01 165.28,147.45 164.4,146.56 162.83,146.56 v2(162.69,146.42)
  BOTTOM w0.102: UV1.D26 163,146.66 162.77,146.42 v2(162.69,146.42)
DQA0_15: length 36.6
  TOP w0.127: v2(163.38,145.72) 163.51,145.86 164.71,145.86 165.65,146.79 165.78,146.79 165.79,146.78 166.12,146.78 166.35,147.01 166.35,147.93 167.09,148.67 167.09,149.42 166.17,150.34 166.17,150.81 168.52,153.16 168.52,153.63 167.54,154.61 167.54,154.85 167.72,155.03 167.9,155.03 168.89,154.04 169.07,154.04 169.22,154.19 169.22,154.43 168.2,155.45 168.2,155.63 168.38,155.81 168.56,155.81 169.61,154.76 169.79,154.76 169.94,154.91 169.94,155.15 168.92,156.17 168.92,156.35 169.1,156.53 169.28,156.53 170.33,155.48 170.51,155.48 170.65,155.63 170.65,155.81 169.57,156.89 169.57,157.07 169.75,157.25 169.93,157.25 171.01,156.17 v1(171.19,156.17) 171.37,156.35 171.37,156.52 170.29,157.61 170.29,157.79 170.47,157.97 170.65,157.97 171.73,156.88 171.91,156.88 173.09,158.07 173.09,158.37 172.84,158.62 172.84,158.94 173.27,159.37 UV18.C2
  BOTTOM w0.102: v2(163.38,145.72) 163.38,145.28 UV1.F25
DQA0_16: length 33.1
  TOP w0.102: v2(171.54,165.56) 171.57,165.53 UV18.F8
  IN1 w0.102: v2(171.54,165.56) 171.4,165.42 171.4,164.84 169.93,163.37
  IN1 w0.165: 169.93,163.37 168.82,162.26 166.45,162.26 166.28,162.43 166.28,163.41 166.12,163.58 165.79,163.58 165.62,163.41 165.62,162.43 165.46,162.26 165.12,162.26 164.96,162.43 164.96,163.41 164.79,163.58 164.46,163.58 164.3,163.41 164.3,161.26 164.06,161.02 164.06,160.35 163.9,160.18 163.54,160.18 163.38,160.02 163.38,159.69 163.54,159.52 163.9,159.52 164.06,159.36 164.06,159.03 163.9,158.86 163.54,158.86 163.38,158.7 163.38,153.03 164.46,151.96 165.54,151.96 v2(165.79,151.7)
  BOTTOM w0.102: v1(165.99,151.06) 165.99,150.81 165.32,150.14 165.32,148.05 165.13,147.87 165.13,147.39 165.03,147.28 UV1.A25
  BOTTOM w0.127: v1(165.99,151.06) 165.99,151.5 v2(165.79,151.7)
DQA0_17: length 33.2
  TOP w0.102: v2(172.68,165.63) 173.21,165.63 UV18.H7
  IN1 w0.102: v2(172.68,165.63) 172.16,165.63 171.73,166.05 171.38,166.05 170.74,165.42 170.24,165.42 170.08,165.57
  IN1 w0.165: v2(165.35,151.3) 165.2,151.45 164.3,151.45 162.91,152.84 162.91,160.98 163.07,161.15 163.53,161.15 163.7,161.31 163.7,161.64 163.53,161.81 163.16,161.81 163,161.98 163,162.31 163.16,162.47 163.66,162.47 163.83,162.64 163.83,162.97 163.66,163.13 163.23,163.13 163.06,163.3 163.06,163.88 163.23,164.05 166.21,164.05 166.32,163.94 167.87,163.94 169.5,165.57 170.08,165.57
  BOTTOM w0.102: UV1.C25 164.46,147.07 164.93,147.53 164.93,150.04 165.35,150.46 v2(165.35,151.3)
DQA0_18: length 32.9
  TOP w0.102: UV18.H8 172.7,166.68 v2(172.71,166.69)
  IN1 w0.165: v2(172.71,166.69) 172.21,166.69 171.82,167.08 170.02,167.08 169.67,166.73 168.12,166.73 166.43,165.03 162.74,165.03 162.44,164.73 162.44,152.64 164.17,150.91 v2(164.94,150.91)
  BOTTOM w0.102: UV1.E25 163.9,146.51 163.92,146.53 163.92,147.05 163.88,147.09 163.88,147.62 164.73,148.47 164.73,150.12 164.94,150.34 v2(164.94,150.91)
DQA0_19: length 33.7
  TOP w0.102: v2(173.59,163.21) 173.69,163.3 UV18.H3
  IN1 w0.102: v2(173.59,163.21) 175.53,163.21 175.87,162.86 175.96,162.86 177.05,161.78 177.05,160.95 176.59,160.49 176.59,159.83 172.97,156.22 172.97,155.96
  IN1 w0.165: v2(165.96,147.73) 165.98,147.73 166.65,147.07 168.59,147.07 172.71,151.19 172.71,151.77 172.97,152.03 173.44,152.03 173.6,152.19 173.6,152.52 173.44,152.69 173.14,152.69 172.97,152.85 172.97,153.14 172.81,153.31 172.19,153.31 172.03,153.47 172.03,153.8 172.19,153.97 172.83,153.97 173,154.13 173,154.46 172.83,154.63 172.29,154.63 172.13,154.79 172.13,155.13 172.29,155.29 172.81,155.29 172.97,155.46 172.97,155.96 172.97,155.96
  BOTTOM w0.102: v2(165.96,147.73) 165.57,147.35 165.57,146.74 165.24,146.41 165.16,146.41 164.97,146.22 164.97,145.74 UV1.D24
DQA0_20: length 34.3
  TOP w0.102: UV18.E3 173.73,161.72 172.35,161.72 v2(172.32,161.68)
  IN1 w0.165: v2(172.32,161.68) 172.99,161.68 173.16,161.52 173.16,159.16 172.99,159 170.62,159 170.46,158.83 170.46,157.44 170.29,157.28 169.96,157.28 169.8,157.44 169.8,158.73 169.63,158.9 169.26,158.9 169.09,158.73 169.09,158.44 168.93,158.28 167.73,158.28 167.57,158.11 167.57,157.78 167.73,157.61 168.99,157.61 169.16,157.45 169.16,157.07 168.99,156.9 167.69,156.9 167.51,156.72 167.51,156.35 167.67,156.19 168.26,156.19 168.42,156.02 168.42,155.69 168.26,155.53 167.67,155.53 167.51,155.36 167.51,154.97 167.67,154.8 168.26,154.8 168.42,154.64 v2(168.42,149.55)
  BOTTOM w0.102: 167.91,149.14 167.89,149.12 167.81,149.12 167.36,148.67 v1(167.36,146.8) 167.21,146.8 166.47,146.06 166.47,145.68 166.29,145.5 166.23,145.5 165.9,145.17 165.9,145.11 165.46,144.68 UV1.E23
  BOTTOM w0.127: 167.91,149.14 168.33,149.55 v2(168.42,149.55)
DQA0_21: length 34.5
  TOP w0.102: UV18.F7 171.58,164.44 v2(171.58,164.44)
  IN1 w0.165: v2(166.24,152.08) 165.89,152.43 165.13,152.43 164.81,152.75 164.81,153.22 164.65,153.38 164.05,153.38 163.89,153.55 163.89,153.88 164.05,154.04 164.65,154.04 164.81,154.21 164.81,154.54 164.65,154.7 164.05,154.7 163.89,154.87 163.89,155.2 164.05,155.36 164.65,155.36 164.81,155.53 164.81,155.86 164.65,156.02 164.05,156.02 163.89,156.19 163.89,156.52 164.05,156.68 164.65,156.68 164.81,156.85 164.81,157.24 164.57,157.48 164.05,157.48 163.89,157.65 163.89,158.14 164.05,158.31 164.37,158.31 164.53,158.47 164.53,160.83 165.5,161.79 166.42,161.79 167.15,161.06 169.11,161.06 171.58,163.52 v2(171.58,164.44)
  BOTTOM w0.102: UV1.F23 164.46,144.88 164.53,144.95 164.53,145.31 164.44,145.4 164.44,145.91 164.76,146.23 164.76,146.3 165.1,146.63 165.16,146.63 165.36,146.84 165.36,147.81 165.62,148.07 v1(165.62,148.59)
  BOTTOM w0.127: 166.27,150.78 166.43,150.94 166.43,151.89 v2(166.24,152.08)
  BOTTOM w0.13: v1(165.62,148.59) 165.62,150.13 166.27,150.78
DQA0_22: length 34
  TOP w0.102: UV18.F2 v2(174.96,161.05)
  IN1 w0.165: v2(168.01,148.72) 168.39,149.1 169.29,149.1 169.47,149.28 169.47,149.89 169.31,150.05 169.06,150.05 168.89,150.22 168.89,150.62 169.02,150.75 169.88,150.75 170.05,150.91 170.05,151.22 169.88,151.38 169.06,151.38 168.89,151.55 168.89,151.88 169.06,152.04 169.9,152.04 170.06,152.21 170.06,152.54 169.9,152.7 169.06,152.7 168.89,152.87 168.89,153.2 169.06,153.36 169.84,153.36 170.01,153.53 170.01,153.86 169.84,154.02 169.06,154.02 168.89,154.19 168.89,154.52 169.06,154.68 169.84,154.68 170.01,154.85 170.01,155.18 169.84,155.34 169.06,155.34 168.89,155.51 168.89,155.84 169.06,156 169.82,156 169.98,156.17 169.98,156.53 170.26,156.81 170.76,156.81 170.93,156.97 170.93,157.76 171.09,157.92 171.54,157.92 171.71,157.76 171.71,157.07 171.87,156.91 172.46,156.91 173.45,157.9 173.45,160.69 173.81,161.05 v2(174.96,161.05)
  BOTTOM w0.102: UV1.D22 166.1,144.61 166.1,145.08 166.31,145.3 166.37,145.3 166.67,145.6 166.67,145.97 167.19,146.49 167.48,146.49 167.66,146.67 167.66,146.93 167.63,146.96 167.63,148.34 v2(168.01,148.72)
DQA0_23: length 34.8
  TOP w0.102: v2(175.47,161.6) 175.53,161.66 UV18.G2
  IN1 w0.165: v2(168.49,148.43) 168.65,148.59 169.45,148.59 170.47,149.62 170.47,150.66 170.64,150.82 171.68,150.82 171.84,150.99 171.84,151.32 171.68,151.48 170.64,151.48 170.47,151.65 170.47,151.98 170.64,152.15 172.17,152.15 172.33,152.31 172.33,152.64 172.17,152.81 170.64,152.81 170.47,152.97 170.47,153.46 170.64,153.63 171.39,153.63 171.56,153.79 171.56,154.12 171.39,154.29 170.64,154.29 170.47,154.45 170.47,154.78 170.64,154.95 171.49,154.95 171.66,155.11 171.66,155.44 171.49,155.61 170.64,155.61 170.47,155.77 170.47,156.17 170.64,156.34 172.52,156.34 175.98,159.8 175.98,161.08 v2(175.47,161.6)
  BOTTOM w0.102: UV1.F21 165.6,143.41 167.51,145.32 167.51,145.93 167.95,146.37 167.95,146.68 168.2,146.94 v1(168.2,147.92) 168.2,148.15 v2(168.49,148.43)
DQA0_24: length 33.9
  IN2 w0.102: v2(171.01,163.87) 170.91,163.87 169.22,162.18 169.22,161.41 168.81,161
  IN2 w0.165: 168.81,161 168.81,160.33 165.98,157.5 165.75,157.5 165.45,157.79 165.22,157.79 164.98,157.56 164.98,157.33 165.28,157.03 165.28,156.8 165.05,156.56 164.81,156.56 164.21,157.16 163.98,157.16 163.75,156.93 163.75,156.7 164.35,156.1 164.35,155.86 164.11,155.63 163.88,155.63 163.28,156.23 163.05,156.23 162.81,156 162.81,155.76 163.41,155.16 163.41,154.93 163.18,154.69 162.95,154.69 162.35,155.29 162.11,155.29 161.88,155.06 161.88,154.83 162.48,154.23 162.48,153.99 162.21,153.72 162.21,152.43 165.22,149.42 165.22,146.95 166.11,146.06 166.11,144.11 v2(166.65,143.58)
  BOTTOM w0.102: UV1.E21 166.58,143.54 166.62,143.58 v2(166.65,143.58) ; UV17.E3 v2(171.01,163.87)
DQA0_25: length 34.5
  IN2 w0.102: v2(174.46,162.7) 173.16,161.4 173.16,159.7 173.48,159.38 173.48,158.14 173.58,158.04 173.58,157.81
  IN2 w0.165: v2(168.8,145.04) 169.56,145.04 169.73,145.2 169.73,146.89 170.36,147.52 170.36,149.74 168.51,151.58 168.51,152.74 168.68,152.91 168.91,152.91 170.56,151.26 170.8,151.26 171.03,151.49 171.03,151.72 169.38,153.37 169.38,153.61 169.71,153.94 169.95,153.94 170.62,153.27 170.85,153.27 171.09,153.5 171.09,153.74 170.41,154.41 170.41,154.64 171.66,155.89 171.66,156.12 171.42,156.36 171.42,156.6 171.65,156.83 171.88,156.83 172.13,156.59 172.36,156.59 172.59,156.82 172.59,157.06 172.47,157.18 172.47,157.41 172.7,157.65 172.94,157.65 173.06,157.52 173.29,157.52 173.58,157.81
  BOTTOM w0.102: UV1.D20 167.52,143.26 168.9,144.64 168.9,144.94 v2(168.8,145.04) ; v2(174.46,162.7) 174.4,162.64 UV17.F7
DQA0_26: length 34.6
  IN2 w0.102: v2(166.69,142.44) 166.26,142.44 165.73,142.97 165.73,143.47 ; 167.92,161.21 168.9,162.19 168.9,162.37 170.02,163.49 170.03,163.49 170.82,164.28 170.82,164.8 v2(171.02,165)
  IN2 w0.165: 165.73,143.47 165.73,146.05 164.9,146.88 164.9,149.1 161.17,152.83 161.17,155.02 165.03,158.88 165.27,158.88 165.87,158.28 166.1,158.28 166.33,158.51 166.33,158.75 165.73,159.35 165.73,159.58 165.97,159.81 166.2,159.81 166.8,159.21 167.03,159.21 167.27,159.45 167.27,159.68 166.67,160.28 166.67,160.51 167.36,161.21 167.92,161.21
  BOTTOM w0.102: v2(166.69,142.44) 166.69,142.43 166.73,142.39 UV1.F19 ; UV17.F2 v2(171.02,165)
DQA0_27: length 33.4
  IN2 w0.102: 171.45,157.53 171.45,157.91 171,158.37 171,158.86 172.95,160.82 172.95,161.48 174.05,162.58 174.05,162.83 174.35,163.13 175.91,163.13 v2(176.03,163.25)
  IN2 w0.165: v2(169.22,145.48) 169.22,147.05 169.89,147.72 169.89,149.38 168.04,151.22 168.04,153.03 169.95,154.94 169.95,155.18 168.64,156.49 168.64,156.72 168.88,156.95 169.11,156.95 170.47,155.6 170.7,155.6 170.94,155.83 170.94,156.06 169.58,157.42 169.58,157.66 169.81,157.89 170.04,157.89 170.93,157.01 171.16,157.01 171.45,157.3 171.45,157.53
  BOTTOM w0.102: UV17.H7 175.97,163.3 v2(176.03,163.25) ; v2(169.22,145.48) 169.22,144.34 UV1.A19
DQA0_28: length 34.5
  IN2 w0.102: v2(167.92,141.23) 167.92,141.79 167.19,142.52 ; v2(173.21,165.05) 172.72,165.05 172.3,165.47 172.03,165.47 171.2,164.64 171.2,164.22 171.39,164.03 171.39,163.71 171.17,163.49 170.92,163.49 169.54,162.11 169.54,161.44 169.05,160.95 169.05,159.9
  IN2 w0.165: 169.05,159.9 163.87,154.71 163.87,153.81 163.7,153.65 162.85,153.65 162.68,153.48 162.68,153.15 162.85,152.99 163.7,152.99 163.87,152.82 163.87,151.41 165.54,149.73 165.54,147.01 166.49,146.06 166.49,144.53 167.19,143.83 167.19,142.52
  BOTTOM w0.102: v2(173.21,165.05) 173.21,165.51 UV17.H3
  BOTTOM w0.13: v2(167.92,141.23) 167.94,141.24 167.94,141.92 UV1.D18
DQA0_29: length 34.9
  IN2 w0.102: 167.21,161.78 167.21,161.82 171.58,166.19 v2(172.13,166.19) ; v2(167.37,140.79) 167.37,141.06 166.26,142.17 166.24,142.17 165.46,142.96 165.46,143.13
  IN2 w0.165: 165.46,143.13 165.46,145.75 164.08,147.13 164.08,148.02 164.39,148.33 164.39,149 160.33,153.06 160.33,154.89 167.21,161.78
  BOTTOM w0.102: UV1.F17 167.45,140.72 v2(167.37,140.79) ; UV17.G2 172.14,166.19 v2(172.13,166.19)
DQA0_30: length 33.5
  IN2 w0.102: 170.2,143.38 170.2,143.24 169.32,142.37 v2(169.07,142.37) ; v2(175.46,162.68) 175.46,162.18 175.12,161.84 174.81,161.84 174.58,162.06 174.18,162.06 174.01,161.89 174.01,161.54 173.92,161.45 173.92,158.88 174.25,158.55 174.25,158.14 174.29,158.09 174.29,157.86 172.71,156.28
  IN2 w0.165: 172.71,156.28 172.07,155.63 172.07,155.4 173.49,153.98 173.49,153.74 173.24,153.5 173.01,153.5 171.59,154.92 171.35,154.92 171.08,154.64 171.08,154.41 172.73,152.76 172.73,152.53 172.4,152.19 172.16,152.19 171.42,152.94 171.18,152.94 170.95,152.7 170.95,152.47 171.69,151.72 171.69,151.49 170.82,150.62 170.82,147.33 170.2,146.7 170.2,143.38
  BOTTOM w0.102: v2(175.46,162.68) 175.51,162.73 175.54,162.73 175.59,162.78 176.06,162.78 UV17.H8 ; UV1.A17 169.12,142.41 v2(169.07,142.37)
DQA0_31: length 33.8
  IN2 w0.102: 170.55,143.51 170.55,143.31 169.02,141.78 v2(168.47,141.78) ; v2(174.39,161.67) 174.39,161.02 175.45,159.96 175.45,159.39 175.13,159.07 175.13,158.19 175.09,158.16
  IN2 w0.165: 170.55,143.51 170.55,146.39 171.29,147.13 171.29,150.43 171.72,150.85 174.38,153.51 174.38,153.75 172.75,155.38 172.75,155.65 172.96,155.86 173.19,155.86 174.84,154.2 175.07,154.2 175.31,154.44 175.31,154.67 173.66,156.32 173.66,156.56 173.89,156.79 174.12,156.79 175.02,155.89 175.25,155.89 175.49,156.13 175.49,156.36 174.59,157.26 174.59,157.49 175.09,157.99 175.09,158.16
  BOTTOM w0.102: UV17.F8 174.45,161.61 v2(174.39,161.67) ; v2(168.47,141.78) 168.49,141.78 168.56,141.85 UV1.C17
DQA1_0: length 34.5
  TOP w0.102: v2(185.6,152.72) 186.12,152.72 UV20.H8
  IN2 w0.102: v2(185.6,152.72) 185.05,152.72 182.69,150.36 182.42,150.36
  IN2 w0.165: v2(172.72,143.22) 172.72,145.09 173.74,146.1 173.74,149.41 175.39,151.06 175.62,151.06 177.05,149.64 177.28,149.64 177.51,149.88 177.51,150.11 176.09,151.53 176.09,151.77 177.25,152.92 177.48,152.92 177.71,152.69 177.71,152.45 177.08,151.82 177.08,151.59 178.97,149.7 179.42,149.7 179.89,150.18 181.06,150.18 181.49,150.61 181.93,150.61 182.19,150.36 182.42,150.36
  BOTTOM w0.102: UV1.E17 168.86,141.28 169.3,141.72 169.3,141.74 169.62,142.07 169.88,142.07 171.36,143.56 v3(171.43,143.56) 172.39,143.56 v2(172.72,143.22)
DQA1_1: length 34.3
  TOP w0.102: UV20.H7 186.73,152.11 v2(186.73,152.61)
  IN2 w0.102: v2(186.73,152.61) 186.73,153.12 186,153.86 184.78,153.86 181.86,150.94 180.83,150.94
  IN2 w0.165: 180.83,150.94 179.84,150.94 179.23,150.33 179,150.33 178.77,150.57 178.77,150.8 179.5,151.54 179.5,151.77 179.27,152 179.03,152 178.3,151.27 178.07,151.27 177.83,151.5 177.83,151.74 178.46,152.37 178.46,152.6 177.68,153.39 177.05,153.39 173.27,149.61 173.27,146.3 172.17,145.2 172.17,142.93 v2(172.3,142.8)
  BOTTOM w0.102: UV1.D16 169.53,141.26 169.53,141.69 169.71,141.87 170.13,141.87 170.43,142.16 170.98,142.16 171.62,142.8 v2(172.3,142.8)
DQA1_2: length 34.3
  TOP w0.102: UV20.F2 v2(188.43,147.58)
  IN2 w0.102: 170.66,139.06 170.17,139.56 v2(169.62,139.56) ; 183.8,145.18 185.88,147.26 187.43,147.26 187.75,147.58 v2(188.43,147.58)
  IN2 w0.165: 183.8,145.18 182.93,144.31 182.93,144.07 184.11,142.89 184.11,142.66 183.88,142.42 183.65,142.42 182.49,143.57 182.19,143.57 181.89,143.27 181.89,143.03 183.22,141.7 183.22,141.47 182.95,141.19 182.71,141.19 182.4,141.5 182.17,141.5 181.93,141.27 181.93,141.04 182.25,140.72 182.25,140.49 180.13,138.38 179.13,138.38 177.18,140.33 176.59,140.33 173.79,137.54 173.28,137.54 172.27,138.56 171.17,138.56 170.66,139.06
  BOTTOM w0.102: v2(169.62,139.56) 169.62,139.56 169.6,139.58 UV1.F15
DQA1_3: length 33.2
  TOP w0.102: UV20.F8 185.04,151.54 v2(185.57,151.54)
  IN2 w0.102: 181.71,149.22 182.05,149.22 183.41,150.59 184.06,150.59 185.18,151.7 185.4,151.7 v2(185.57,151.54) ; v2(171.88,142.38) 172.6,142.38 173.14,142.92
  IN2 w0.165: 173.14,142.92 173.14,144.83 174.71,146.41 174.71,146.64 174.21,147.14 174.21,147.38 174.44,147.61 174.68,147.61 175.18,147.11 175.41,147.11 175.65,147.34 175.65,147.58 174.22,149 174.22,149.23 174.46,149.47 174.69,149.47 176.11,148.04 176.35,148.04 176.58,148.28 176.58,148.51 175.16,149.93 175.16,150.17 175.39,150.4 175.62,150.4 177.05,148.98 177.28,148.98 177.63,149.33 177.86,149.33 178.87,148.32 179.36,148.32 179.53,148.49 179.53,148.79 179.4,148.92 179.4,149.15 180.05,149.81 181.12,149.81 181.71,149.22
  BOTTOM w0.102: v2(171.88,142.38) 171.63,142.13 171.63,141.92 170.99,141.28 UV1.A15
DQA1_4: length 34
  TOP w0.102: v2(185.03,151.01) 185.07,150.97 UV20.F7
  IN2 w0.102: 181.11,147.92 181.32,147.92 183.42,150.03 184.62,150.03 185.03,150.43 v2(185.03,151.01)
  IN2 w0.165: 181.11,147.92 180.82,147.92 180.66,148.09 180.66,149.38 180.49,149.54 180.16,149.54 180,149.38 180,148.09 179.76,147.85 178.41,147.85 177.73,148.53 177.5,148.53 177.27,148.3 177.27,148.07 177.88,147.46 177.88,147.17 177.61,146.9 177.37,146.9 176.74,147.54 176.5,147.54 176.27,147.3 176.27,147.07 176.91,146.43 176.91,146.2 176.7,145.99 176.46,145.99 175.83,146.63 175.6,146.63 175.36,146.39 175.36,146.16 176,145.53 176,145.29 175.79,145.09 175.56,145.09 174.92,145.72 174.69,145.72 174.45,145.49 174.45,145.25 175.09,144.62 175.09,144.38 174.86,144.15 174.62,144.15 173.87,144.9 173.64,144.9 173.4,144.67 173.4,144.44 174.16,143.68 174.16,143.45 172.64,141.93 v2(172.29,141.93)
  BOTTOM w0.102: UV1.D14 170.4,140.41 171.24,141.25 171.6,141.25 v2(172.29,141.93)
DQA1_5: length 34
  TOP w0.102: UV20.G2 189.06,148.77 v2(189.06,149.21)
  IN2 w0.102: v2(189.06,149.21) 189.06,148.62 189.37,148.3 189.37,147.99 188.02,146.63 187.7,146.63 187.7,146.63
  IN2 w0.165: 187.7,146.63 185.61,146.63 184.97,145.99 184.97,144.69 184.8,144.53 183.81,144.53 183.65,144.36 183.65,144.03 183.81,143.87 184.8,143.87 184.97,143.7 184.97,142.55 182.14,139.72 182.14,139.49 182.38,139.25 182.38,139.02 182.15,138.78 181.91,138.78 181.68,139.02 181.44,139.02 181.21,138.79 181.21,138.55 181.45,138.32 181.45,138.08 181.21,137.85 180.98,137.85 180.74,138.09 180.51,138.09 180.24,137.82 179.15,137.82 177.02,139.95 176.59,139.95 173.91,137.27 172.98,137.27 172.04,138.22 170.9,138.22 v2(170.67,138.45)
  BOTTOM w0.102: UV1.F13 170.64,138.45 170.64,138.45 v2(170.67,138.45)
DQA1_6: length 33.3
  TOP w0.102: v2(185.73,148.3) 187.14,149.71 187.68,149.71 188.14,150.18 188.62,150.18 188.95,149.84 UV20.H3
  IN2 w0.102: v2(185.73,148.3) 185.92,148.11 185.92,147.7 183.74,145.52 183.47,145.52
  IN2 w0.165: v2(172.79,140.2) 172.79,138.99 173.6,138.18 174.05,138.18 176.54,140.67 177.51,140.67 179.33,138.85 179.94,138.85 180.64,139.55 180.64,139.79 180.06,140.37 180.06,140.6 180.29,140.84 180.53,140.84 181.11,140.25 181.34,140.25 181.58,140.49 181.58,140.73 180.25,142.06 180.25,142.29 180.48,142.53 180.72,142.53 181.5,141.74 181.74,141.74 181.94,141.94 181.94,142.18 181.16,142.97 181.16,143.2 183.47,145.52
  BOTTOM w0.102: v2(172.79,140.2) 172.18,140.2 172.13,140.15 UV1.A13
DQA1_7: length 33.7
  TOP w0.102: UV20.E3 v2(187.86,148.15)
  IN2 w0.102: v2(171.33,140.07) 172.05,140.07 172.56,140.58 172.98,140.58 173.98,139.58 174.23,139.58 174.41,139.76 ; 184.76,147.47 185.35,148.06 185.35,148.53 185.51,148.69 185.96,148.69 186.62,148.03 187.74,148.03 v2(187.86,148.15)
  IN2 w0.165: 184.76,147.47 184.1,146.81 183.87,146.81 183.42,147.26 183.19,147.26 182.96,147.02 182.96,146.79 183.4,146.34 183.4,146.11 183.17,145.88 182.93,145.88 182.48,146.33 182.25,146.33 182.01,146.1 182.01,145.86 182.47,145.41 182.47,145.18 182.23,144.94 182,144.94 181.61,145.34 181.37,145.34 181.14,145.1 181.14,144.87 181.53,144.48 181.53,144.24 179.58,142.29 179.58,142.05 180.09,141.54 180.09,141.3 179.86,141.07 179.56,141.07 179.14,141.49 178.9,141.49 178.71,141.29 178.71,141.06 179.98,139.79 179.98,139.55 179.74,139.32 179.51,139.32 176.91,141.92 176.57,141.92 174.41,139.76
  BOTTOM w0.102: UV1.C13 171.25,139.99 v2(171.33,140.07)
DQA1_8: length 37.2
  TOP w0.117: 177.95,140.6 177.94,140.61 v2(175.84,140.61)
  TOP w0.127: UV20.B8 182.77,148.68 182.33,148.24 182.33,147.54 182.09,147.3 182.09,141.1 183.32,139.87 183.32,139.57 183.19,139.45 182.76,139.45 181.57,138.25 181.39,138.25 181.08,138.56 181.08,138.74 182.33,140 182.33,140.18 182.07,140.44 181.89,140.44 180.63,139.19 180.45,139.19 180.18,139.46 180.18,139.64 181.56,141.02 181.56,141.2 181.29,141.47 181.11,141.47 179.12,139.48 178.9,139.48 178.66,139.72 178.66,139.9 180.01,141.24 180.01,141.42 179.74,141.69 179.56,141.69 178.47,140.6 177.95,140.6
  BOTTOM w0.102: v2(175.84,140.61) 175.79,140.56 174.06,140.56 172.65,139.15 172.65,139 172.4,138.76 172.26,138.76 171.82,138.32 UV1.E11
DQA1_9: length 36.2
  TOP w0.117: 176.58,140.38 176.16,139.95 175.66,139.95 v2(175.43,140.18)
  TOP w0.127: UV20.A7 182.77,146.83 182.42,146.48 182.42,141.24 185.29,138.37 185.29,137.86 183.51,136.08 183.09,136.08 182.91,136.26 182.91,136.44 184.62,138.15 184.62,138.33 184.36,138.6 v1(184.18,138.6) 182.47,136.89 182.29,136.89 182.02,137.16 182.02,137.34 183.35,138.67 183.35,138.85 183.08,139.12 182.9,139.12 181.57,137.79 181.39,137.79 180.08,139.09 178.65,139.09 177.37,140.38 176.58,140.38
  BOTTOM w0.102: UV1.A11 173.17,139.02 174.3,140.14 175.39,140.14 v2(175.43,140.18)
DQA1_10: length 36.7
  TOP w0.102: 175.68,140.99 175,140.31 v2(175,139.76) ; UV20.D7 183.79,149.84 183.47,149.52 182.99,149.52 182.9,149.6 182.63,149.6 182.55,149.52 181.85,149.52 181.71,149.66 180.89,149.66 180.69,149.46 180.69,148.82 181.76,147.75
  TOP w0.127: 181.76,147.75 181.76,147.08 181.63,146.96 180.69,146.96 180.56,146.83 180.56,146.45 180.69,146.32 181.63,146.32 181.76,146.2 181.76,145.81 181.63,145.69 180.59,145.69 180.46,145.56 180.46,145.18 180.59,145.05 181.63,145.05 181.76,144.93 181.76,144.43 181.63,144.31 180.9,144.31 180.78,144.18 180.78,143.8 180.9,143.67 181.63,143.67 181.76,143.55 181.76,143.13 181.63,143.01 v1(181.26,143.01) 180.9,143.01 180.78,142.88 180.78,142.5 180.9,142.37 181.63,142.37 181.76,142.25 181.76,141.99 181.57,141.8 180.98,141.8 180.63,141.45 180.45,141.45 179.96,141.94 179.95,141.94 179.76,142.14 179.36,142.14 178.29,143.21 178.11,143.21 177.84,142.94 177.84,142.76 178.91,141.69 178.91,141.51 178.63,141.23 178.45,141.23 177.93,141.74 177.68,141.74 177.55,141.62 177.55,140.96 177.42,140.83 177.04,140.83 176.91,140.96 176.91,141.62 176.79,141.74 176.49,141.74 175.73,140.99 175.68,140.99
  BOTTOM w0.102: v2(175,139.76) 174.2,139.76 173.12,138.68 172.61,138.68 UV1.C11
DQA1_11: length 37.2
  TOP w0.102: 176.63,142.2 176.54,142.2 173.17,138.82 173.17,137.59 173.67,137.1 174.2,137.1 174.33,137.23 174.33,138.52 174.57,138.76 v2(174.57,139.32) ; UV20.C8 182.66,149.84 181.92,150.58 181.51,150.58 180.36,149.44 180.36,149.42
  TOP w0.127: 176.63,142.2 176.71,142.27 176.89,142.27 177.22,141.94 177.4,141.94 177.6,142.14 177.6,142.32 177.27,142.65 177.27,142.83 178.29,143.85 178.55,143.85 180.04,142.36 180.22,142.36 180.45,142.59 180.45,142.77 178.92,144.3 178.92,144.48 179.21,144.77 179.39,144.77 180.06,144.1 180.24,144.1 180.51,144.37 180.51,144.55 179.84,145.22 179.84,145.4 180.36,145.92 180.36,146.18 180.23,146.31 179.56,146.31 179.43,146.43 179.43,146.81 179.56,146.94 180.21,146.94 180.33,147.07 180.33,147.45 180.21,147.58 179.56,147.58 179.43,147.7 179.43,148.08 179.56,148.21 v1(179.86,148.21) 180.23,148.21 180.36,148.34 180.36,149.42
  BOTTOM w0.102: v2(174.57,139.32) 174.49,139.24 173.97,139.24 173.21,138.47 172.98,138.47 171.83,137.32 UV1.F11
DQA1_12: length 36.1
  TOP w0.127: UV20.C3 185.63,147.01 184.43,145.81 184.43,145.21 184.18,144.96 184.18,141.97 185.4,140.75 186.6,140.75 189.64,137.71 189.64,136.99 183.97,131.32 v1(183.71,131.32) 183.15,131.32 180.97,133.5 180.97,135.48 178.96,137.49 177.21,137.49 176.64,138.06 175.29,138.06 v2(175.12,137.9)
  BOTTOM w0.102: v2(175.12,137.9) 175.09,137.87 174.48,137.87 174.46,137.89 UV1.A9
DQA1_13: length 36.4
  TOP w0.127: v2(174.71,137.49) 174.71,138.03 174.73,138.05 174.73,138.06 174.96,138.29 176.73,138.29 177.31,137.71 179.2,137.71 184.14,132.78 184.96,132.78 188.97,136.79 v1(188.97,137.27) 188.97,137.92 186.47,140.42 185.26,140.42 183.85,141.83 183.85,145.25 184.13,145.52 184.13,146.1 185.54,147.51 186.26,147.51 186.83,146.95 186.83,146.54 UV20.C2
  BOTTOM w0.102: UV1.C9 174.22,137.32 174.38,137.49 v2(174.71,137.49)
DQA1_14: length 37.1
  TOP w0.127: v2(173.08,136.19) 173.51,136.19 173.94,135.76 176.21,135.76 176.35,135.62 177.09,135.62 177.8,136.33 179.18,136.33 180.31,135.21 180.31,132.42 182.43,130.3 v1(182.47,130.3) 183.88,130.3 190.3,136.72 190.3,137.99 186.88,141.41 185.67,141.41 184.84,142.24 184.84,143.38 185.1,143.63 185.1,144.81 UV20.A2
  BOTTOM w0.102: UV1.F9 v2(173.08,136.19)
DQA1_15: length 36.7
  TOP w0.127: v2(173.43,136.8) 173.43,136.63 174.05,136.02 176.14,136.02 177.38,137.26 177.85,137.26 178.26,136.84 v1(178.87,136.84) 179.14,136.84 180.09,135.9 180.64,135.34 180.64,133.36 183.37,130.63 183.75,130.63 189.97,136.86 189.97,137.85 186.74,141.08 185.53,141.08 184.51,142.11 184.51,144.67 184.74,144.9 184.74,145.59 UV20.A3
  BOTTOM w0.102: UV1.D8 173.76,136.47 v2(173.43,136.8)
DQA1_16: length 33
  IN1 w0.102: 180.9,148.21 181.07,148.37 181.44,148.37 182.37,149.3 182.37,149.98 183.95,151.56 v2(184.48,151.56)
  IN1 w0.165: v2(173.44,135.7) 173.88,136.15 173.88,136.93 173.54,137.27 173.54,137.68 176.62,140.76 180.74,140.76 180.9,140.93 180.9,141.44 180.74,141.6 179.44,141.6 179.25,141.8 179.25,142.3 179.42,142.47 180.74,142.47 180.9,142.63 180.9,144.19 181.07,144.36 181.81,144.36 181.97,144.52 181.97,144.85 181.81,145.02 181.07,145.02 180.9,145.18 180.9,145.51 181.07,145.68 181.81,145.68 181.97,145.84 181.97,146.17 181.81,146.34 181.07,146.34 180.9,146.5 180.9,146.83 181.07,147 181.81,147 181.97,147.16 181.97,147.49 181.81,147.66 181.07,147.66 180.9,147.82 180.9,148.21
  BOTTOM w0.102: v2(184.48,151.56) 185.01,151.56 UV19.F2 ; UV1.E7 173.52,135.62 v2(173.44,135.7)
DQA1_17: length 32.5
  IN1 w0.102: v2(185.4,150.07) 185.21,149.88 184.76,149.88 184.14,149.26 ; 177.86,138.05 176.84,137.02 176.33,137.02 v2(176.25,136.95)
  IN1 w0.165: 184.14,149.26 184.14,145.5 183.98,145.34 183.55,145.34 183.38,145.17 183.38,144.84 183.55,144.67 183.98,144.67 184.14,144.51 184.14,144.18 183.98,144.01 183.55,144.01 183.38,143.85 183.38,143.52 183.55,143.35 183.98,143.35 184.14,143.19 184.14,140.33 183.98,140.17 182.48,140.17 182.31,140 182.31,139.67 182.48,139.51 183.98,139.51 184.14,139.34 184.14,138.96 183.98,138.8 182.48,138.8 182.31,138.63 182.31,138.3 182.48,138.14 183.98,138.14 184.14,137.97 184.14,137.61 183.89,137.35 181.86,137.35 181.16,138.05 177.86,138.05
  BOTTOM w0.102: v2(185.4,150.07) 185.4,150.07 185.23,150.07 185.03,150.26 UV19.E3 ; UV1.A7 175.36,136.76 175.55,136.95 v2(176.25,136.95)
DQA1_18: length 33
  IN1 w0.102: 182.91,148.93 183.84,149.86 184.46,149.86 185.61,151.01 v2(186.3,151.01)
  IN1 w0.165: v2(176.68,137.41) 176.33,137.75 176.33,137.98 177.1,138.75 177.67,138.75 177.83,138.58 181.68,138.58 181.84,138.75 181.84,140.57 182.01,140.74 183.51,140.74 183.67,140.9 183.67,141.23 183.51,141.4 182.01,141.4 181.84,141.56 181.84,141.89 182.01,142.06 183.51,142.06 183.67,142.22 183.67,142.55 183.51,142.72 182.01,142.72 181.84,142.88 181.84,143.21 182.01,143.38 182.75,143.38 182.91,143.54 182.91,148.93
  BOTTOM w0.102: v2(176.68,137.41) v1(176.32,137.77) 175.67,137.77 174.75,136.84 174.75,136.29 UV1.C7 ; UV19.H3 186.73,151.44 v2(186.3,151.01)
DQA1_19: length 33.1
  IN1 w0.102: v2(184.99,152.09) 184.99,151.53 182.44,148.97
  IN1 w0.165: v2(172.97,135.14) 173.36,134.75 173.92,134.75 175.25,136.08 175.25,137.42 177.19,139.36 177.19,140.13 177.36,140.29 177.69,140.29 177.85,140.13 177.85,139.22 178.02,139.05 178.28,139.05 178.51,139.28 178.51,140.13 178.68,140.29 179.01,140.29 179.17,140.13 179.17,139.22 179.34,139.05 179.65,139.05 179.88,139.28 179.88,140.13 180.04,140.29 180.37,140.29 180.54,140.13 180.54,139.22 180.7,139.05 181.15,139.05 181.37,139.28 181.37,143.72 181.54,143.89 182,143.89 182.44,144.33 182.44,148.97
  BOTTOM w0.102: UV19.G2 185,152.11 v2(184.99,152.09) ; v2(172.97,135.14) 173.05,135.06 UV1.F7
DQA1_20: length 32.3
  IN1 w0.165: v2(176.84,136.02) 176.84,136.02 177.83,135.03 178.41,135.03 178.73,135.35 179.66,135.35 179.82,135.19 179.82,134.09 179.99,133.92 180.32,133.92 180.48,134.09 180.48,135.19 180.65,135.35 180.98,135.35 181.14,135.19 181.14,134.09 181.31,133.92 181.64,133.92 181.8,134.09 181.8,135.19 181.97,135.35 182.3,135.35 182.46,135.19 182.46,134.09 182.63,133.92 182.96,133.92 183.12,134.09 183.12,135.19 183.29,135.35 184.66,135.35 187.19,137.88 187.19,145.16 187,145.35 187,146.05 186.61,146.44 v2(186.61,148.58)
  BOTTOM w0.102: UV1.A5 176.38,135.62 176.78,136.02 v2(176.84,136.02) ; v2(186.61,148.58) 186.74,148.71 UV19.F7
DQA1_21: length 33.1
  IN1 w0.102: v2(189.56,148.75) 188.98,148.75 188.7,149.03 188.29,149.03 188.07,148.81 188.07,148.49 188.24,148.32 188.24,147.93 187.45,147.14 187.45,145.67 187.57,145.54
  IN1 w0.165: v2(175.3,135) 175.39,134.91 177.11,134.91 178.57,133.45 183.42,133.45 187.66,137.69 187.66,139.29 187.83,139.46 188.68,139.46 188.84,139.62 188.84,139.95 188.68,140.12 187.83,140.12 187.66,140.28 187.66,140.61 187.83,140.78 188.68,140.78 188.84,140.94 188.84,141.27 188.68,141.44 187.83,141.44 187.66,141.6 187.66,145.45 187.57,145.54
  BOTTOM w0.102: v2(189.56,148.75) UV19.H8 ; v2(175.3,135) 175.3,134.92 175.21,134.83 UV1.E5
DQA1_22: length 32.3
  IN1 w0.102: v2(189,150.35) 189.57,150.35 189.94,149.98 189.94,149.64 189.74,149.44 189.74,149.12 189.99,148.88 189.99,147.45 189.62,147.08
  IN1 w0.165: 189.62,147.08 189.62,147.06 189.36,146.8 189.36,144.21 190.11,143.47 190.11,137.6 185.02,132.51 176.85,132.51 176.34,133.02 v2(176.34,133.88)
  BOTTOM w0.102: UV19.H7 189,149.85 v2(189,150.35) ; UV1.C3 v2(176.34,133.88)
DQA1_23: length 32.5
  IN1 w0.102: 188.27,145.99 188.05,146.21 188.05,146.65 188.81,147.41 188.81,147.79 188.45,148.15 v2(188.45,148.65)
  IN1 w0.165: 188.27,145.99 188.27,144.58 189.03,143.82 189.03,143.24 189.44,142.83 189.44,138.99 189.28,138.82 188.3,138.82 188.13,138.66 188.13,138.33 188.3,138.16 188.99,138.16 189.16,138 189.16,137.41 188.79,137.04 188.56,137.04 188.23,137.36 188,137.36 187.77,137.13 187.77,136.9 188.14,136.53 188.14,136.29 187.9,136.06 187.67,136.06 187.3,136.43 187.07,136.43 186.83,136.2 186.83,135.96 187.2,135.59 187.2,135.36 186.97,135.13 186.74,135.13 186.37,135.5 186.13,135.5 185.9,135.26 185.9,135.26 183.62,132.98 177.3,132.98 v2(176.94,133.34)
  BOTTOM w0.102: v2(176.94,133.34) 176.92,133.36 UV1.E1 ; v2(188.45,148.65) 188.43,148.63 UV19.F8
DQA1_24: length 37.2
  BOTTOM w0.102: 179,134.3 178.82,134.12 178.82,133.93 176.94,132.05 176.14,132.05 175.66,132.53 175.63,132.53 175.39,132.77 175.37,132.77 175.19,132.95 175.19,133.16 175.01,133.34 174.8,133.34 174.63,133.52 174.63,133.66 174.1,134.19 173.96,134.19 173.65,134.49 UV1.G7
  BOTTOM w0.127: UV19.A2 182.43,148.48 182.43,146.99 180.32,144.87 180.14,144.87 179.42,145.59 179.24,145.59 179.06,145.41 179.06,145.23 179.78,144.52 179.78,144.34 179.6,144.16 179.42,144.16 178.7,144.87 178.52,144.87 178.34,144.69 178.34,144.51 179.06,143.8 179.06,143.62 178.88,143.44 178.7,143.44 177.98,144.16 177.8,144.16 177.62,143.98 177.62,143.8 v1(178,143.42) 178.34,143.08 178.34,142.9 178.16,142.72 177.98,142.72 177.26,143.44 177.08,143.44 176.9,143.26 176.9,143.08 177.62,142.36 177.62,142.18 177.44,142 177.26,142 176.55,142.72 176.37,142.72 176.19,142.54 176.19,142.36 176.9,141.64 176.9,141.1 179,139 179,134.3
DQA1_25: length 36.5
  BOTTOM w0.102: UV1.G6 173.98,133.93 174.42,133.48 174.42,133.43 174.72,133.14 174.93,133.14 174.99,133.08 174.99,132.87 175.29,132.57 175.3,132.57 175.54,132.33 175.57,132.33 176.05,131.85 177.03,131.85 179.25,134.08
  BOTTOM w0.127: UV19.A3 182.77,146.86 182.1,146.19 182.1,146.01 182.54,145.58 182.54,145.4 182.36,145.22 182.18,145.22 181.74,145.65 181.56,145.65 181.32,145.41 181.32,145.23 182.46,144.09 182.46,143.91 182.28,143.73 182.1,143.73 180.96,144.87 180.78,144.87 180.6,144.69 180.6,144.51 181.74,143.37 181.74,143.19 181.56,143.01 181.38,143.01 v1(181.06,143.33) 180.24,144.15 180.06,144.15 179.88,143.97 179.88,143.79 181.02,142.65 181.02,142.47 180.84,142.29 180.66,142.29 179.52,143.43 179.34,143.43 177.42,141.5 177.42,141.03 179.25,139.19 179.25,134.08
DQA1_26: length 35.9
  BOTTOM w0.102: 178.91,133.41 178.88,133.41 177.11,131.65 175.97,131.65 175.57,132.04 175.4,132.04 UV1.G1
  BOTTOM w0.127: 178.91,133.41 179.57,134.07 179.57,139.32 177.72,141.17 177.72,141.35 177.9,141.53 178.08,141.53 179.23,140.38 179.41,140.38 179.59,140.56 179.59,140.74 178.48,141.85 178.48,142.03 178.65,142.21 178.83,142.21 179.95,141.1 180.12,141.1 180.31,141.28 180.31,141.46 179.26,142.51 179.26,142.69 179.44,142.87 179.62,142.87 180.66,141.82 180.84,141.82 181.94,142.92 182.12,142.92 182.76,142.28 182.94,142.28 183.12,142.46 183.12,142.64 182.48,143.28 182.48,143.46 v1(182.94,143.92) 183.12,144.1 183.12,147.38 183.83,148.09 183.83,148.84 183.56,149.11 183.56,149.61 UV19.C2
DQA1_27: length 36
  BOTTOM w0.102: 179.11,133.14 177.41,131.44 175.88,131.44 175.49,131.84 175.17,131.84 174.65,132.36 UV1.G3
  BOTTOM w0.127: 179.11,133.14 179.9,133.94 179.9,138.13 v1(180.2,138.42) 180.45,138.67 180.45,138.91 179.51,139.84 179.51,140.02 179.7,140.21 179.88,140.21 180.85,139.25 181.03,139.25 181.23,139.45 181.23,139.63 180.26,140.59 180.26,140.77 180.5,141.01 180.68,141.01 181.67,140.03 181.85,140.03 182.03,140.21 182.03,140.39 181.04,141.37 181.04,141.55 181.22,141.73 181.4,141.73 182.36,140.77 182.54,140.77 182.72,140.95 182.72,141.13 181.79,142.06 181.79,142.24 181.97,142.42 182.15,142.42 183.08,141.49 183.26,141.49 183.45,141.67 183.45,147.39 184.14,148.08 184.14,149.04 UV19.C3
DQA1_28: length 37.6
  BOTTOM w0.102: 176.44,129.49 175.14,129.49 174.97,129.66 173.68,129.66 173.46,129.88 173.46,130.18 173.16,130.48 173.11,130.48 172.93,130.66 172.93,130.94 173.01,131.02 173.01,131.74 172.86,131.89 172.84,131.89 172.59,132.14 172.59,132.33 172.65,132.4 172.65,132.53 UV1.J6
  BOTTOM w0.127: 176.44,129.49 179.52,129.49 181.5,131.47 181.5,131.65 181.13,132.02 181.13,132.2 181.31,132.38 181.49,132.38 181.86,132.01 182.04,132.01 182.22,132.19 182.22,132.37 181.84,132.74 181.84,132.92 182.02,133.1 182.2,133.1 182.58,132.73 182.76,132.73 182.94,132.91 182.94,133.09 182.56,133.46 182.56,133.64 182.74,133.81 182.92,133.81 183.29,133.44 183.48,133.44 183.66,133.63 183.66,133.8 183.28,134.18 183.28,134.36 183.46,134.54 183.64,134.54 184.02,134.16 184.2,134.16 184.38,134.34 184.38,134.62 184.05,134.95 184.05,135.12 184.18,135.26 184.36,135.26 184.73,134.88 184.91,134.88 185.09,135.06 185.09,135.24 v1(184.92,135.41) 184.72,135.62 184.72,135.8 188.28,139.36 188.28,141.34 187.92,141.71 187.92,144.75 186.73,145.94 UV19.C8
DQA1_29: length 36
  BOTTOM w0.102: UV1.J1 174.39,131.1 175.01,130.48 177.43,130.48 ; UV19.D7 186.73,146.91 186.41,146.58 186.41,146.31 186.3,146.21 186.03,146.21 185.77,145.95 185.42,145.95 185.17,146.21 184.88,146.21
  BOTTOM w0.127: 177.43,130.48 178,130.48 183.95,136.43 183.95,136.75 182.99,137.71 182.99,137.89 183.14,138.03 183.32,138.03 184.35,137.01 184.53,137.01 184.71,137.19 184.71,137.36 183.69,138.39 183.69,138.57 183.87,138.75 184.05,138.75 185.07,137.72 185.25,137.72 185.43,137.9 185.43,138.08 v1(183.91,139.6) 183.51,140 183.51,140.18 183.74,140.41 183.92,140.41 184.67,139.65 184.85,139.65 185.03,139.83 185.03,140.01 184.28,140.77 184.28,140.95 184.55,141.22 184.55,145.88 184.88,146.21
DQA1_30: length 36.7
  BOTTOM w0.102: 177.1,130.15 175.05,130.15 174.41,130.79 173.96,130.79 173.73,131.02 173.73,131.25 173.52,131.47 UV1.J3
  BOTTOM w0.127: UV19.A7 184.88,145.73 184.88,143.33 185.01,143.21 185.29,143.21 185.41,143.08 185.41,142.83 185.29,142.7 185.01,142.7 184.88,142.57 184.88,141.08 184.79,140.99 184.79,140.81 185.04,140.56 185.22,140.56 186.76,142.1 186.94,142.1 187.12,141.92 187.12,141.74 185.58,140.2 185.58,140.02 185.91,139.69 186.09,139.69 v1(186.39,139.98) 186.98,140.57 187.16,140.57 187.34,140.4 187.34,140.22 186.45,139.33 186.45,139.15 186.71,138.9 186.71,138.72 186.53,138.54 186.35,138.54 185.37,139.51 185.19,139.51 185.01,139.34 185.01,139.16 185.99,138.18 185.99,138 178.14,130.15 177.1,130.15
DQA1_31: length 36.8
  BOTTOM w0.102: 176.77,129.82 175.09,129.82 174.33,130.59 173.87,130.59 173.53,130.93 173.53,131.17 173.21,131.49 173.21,132.13 173.11,132.23 UV1.J5
  BOTTOM w0.127: 176.77,129.82 178.28,129.82 178.59,130.13 178.77,130.13 179.08,129.82 179.26,129.82 179.44,130 179.44,130.18 179.13,130.49 179.13,130.67 179.31,130.85 179.49,130.85 179.86,130.48 180.04,130.48 180.22,130.66 180.22,130.84 179.85,131.21 179.85,131.39 180.03,131.57 180.21,131.57 180.58,131.2 180.76,131.2 180.94,131.38 180.94,131.56 180.57,131.93 180.57,132.11 187.23,138.77 187.23,138.95 186.97,139.2 186.97,139.38 187.15,139.56 187.33,139.56 187.59,139.31 187.77,139.31 187.95,139.5 187.95,140.25 187.59,140.62 v1(187.59,141.1) 187.59,141.91 186.93,142.56 186.75,142.56 185.57,141.38 185.39,141.38 185.21,141.55 185.21,141.73 186.4,142.92 186.4,143.1 185.2,144.29 185.2,145.4 185.54,145.73 186.01,145.73 UV19.B8
DQMA_0: length 34.6
  BOTTOM w0.102: UV1.E32 161.07,148.86 160.63,149.3 160.63,149.94 161.96,151.28 163.83,151.28 164.8,152.25 ; UV17.D3 171,162.22 172.42,160.8 172.84,160.8 173.03,160.61 173.03,160.13 172.94,160.04 172.94,159.73 173.03,159.64 173.03,158.99 172.94,158.91 172.94,158.64 173.03,158.56 173.03,158.02 172.24,157.23 171.76,157.23
  BOTTOM w0.127: 164.8,152.25 165.82,153.27 166.77,153.27 168.94,151.1 169.12,151.1 169.35,151.33 169.35,151.51 168.38,152.48 168.38,152.66 168.56,152.84 168.74,152.84 v1(169.24,152.34) 169.71,151.87 169.89,151.87 170.07,152.05 170.07,152.23 169.1,153.2 169.1,153.38 169.28,153.56 169.46,153.56 170.43,152.59 170.61,152.59 170.79,152.77 170.79,152.95 169.97,153.77 169.97,153.95 170.5,154.49 170.5,155.06 170.06,155.5 170.06,155.68 171.61,157.23 171.76,157.23
DQMA_1: length 35.1
  TOP w0.127: v2(161.16,147) 162.17,148.02 162.8,148.02 163.11,147.7 163.13,147.7 163.14,147.69 163.99,147.69 164.78,148.48 164.78,149.79 162.9,151.67 161.95,151.67 160.2,153.42 160.2,154.01 162.61,156.41 162.61,156.59 162.13,157.07 162.13,157.25 162.31,157.43 162.49,157.43 162.96,156.95 163.14,156.95 163.32,157.13 163.32,157.31 v1(163.1,157.53) 162.85,157.79 162.85,157.97 163.03,158.15 163.21,158.15 163.68,157.67 163.86,157.67 164.06,157.86 164.24,157.86 164.74,157.36 164.92,157.36 165.14,157.57 165.14,157.75 164.57,158.32 164.57,158.5 164.77,158.7 164.95,158.7 165.52,158.13 165.7,158.13 166.24,158.67 168.95,158.67 171.32,161.04 UV18.D3
  BOTTOM w0.102: v2(161.16,147) 161.16,147.13 161.41,147.38 161.41,147.84 UV1.E30
DQMA_2: length 33.8
  TOP w0.102: UV18.E7 171.78,163.66 v2(171.78,161.98)
  IN1 w0.102: 167.73,149.32 167.63,149.23 167.63,148.46 167.32,148.15 167.32,147.83 167.76,147.38 168.27,147.38 v2(168.97,148.08) ; 169.42,159.57 170.1,159.57 170.11,159.58 171.76,159.58 172.01,159.83 172.65,159.83 172.78,159.96 172.78,160.4 172.68,160.5 172.05,160.5 171.78,160.76 v2(171.78,161.98)
  IN1 w0.165: 169.42,159.57 167.61,159.57 167.04,158.99 167.04,156.35 166.87,156.18 166.46,156.18 166.3,156.02 166.3,155.69 166.46,155.52 166.87,155.52 167.04,155.36 167.04,155.03 166.87,154.86 166.46,154.86 166.3,154.7 166.3,154.37 166.46,154.2 167.79,154.2 167.95,154.04 167.95,153.63 167.79,153.47 167.58,153.47 167.41,153.3 167.41,152.97 167.58,152.81 167.79,152.81 167.95,152.64 167.95,152.31 167.79,152.15 167.65,152.15 167.49,151.98 167.49,151.65 167.65,151.49 167.79,151.49 167.95,151.32 167.95,150.98 167.79,150.81 167.49,150.81 167.25,150.57 167.25,150.3 167.51,150.05 167.82,150.05 167.95,149.92 167.95,149.55 167.73,149.32
  BOTTOM w0.102: UV1.A21 167.29,144.8 168.7,146.2 v1(168.7,146.65) 168.7,147.82 v2(168.97,148.08)
DQMA_3: length 33.5
  IN2 w0.102: 170.12,158.87 171.06,159.81 171.06,161.79 171.63,162.36 173.05,162.36 v2(173.07,162.34)
  IN2 w0.165: v2(168.29,145.24) 168.29,146.78 169.38,147.87 169.38,149.22 167.57,151.02 167.57,152.71 165.89,154.4 165.89,154.63 166.19,154.93 166.42,154.93 167.73,153.62 167.97,153.62 168.2,153.86 168.2,154.09 166.89,155.4 166.89,155.63 167.15,155.89 167.38,155.89 168.55,154.72 168.81,154.72 169.04,154.95 169.04,155.19 167.86,156.37 167.86,156.6 170.12,158.87
  BOTTOM w0.102: v2(168.29,145.24) 168.02,144.98 168.02,144.97 167.42,144.37 166.99,144.37 UV1.C21 ; v2(173.07,162.34) 173.8,161.61 UV17.E7
DQMA_4: length 33.5
  TOP w0.102: v2(185,149.47) 185,150.37 UV20.E7
  IN2 w0.102: v2(170.75,139.52) 170.19,140.08 169.65,140.08 169.27,140.47 169.27,140.81 170.55,142.1 171.58,142.1 172.13,141.55 172.92,141.55 173.07,141.7
  IN2 w0.165: 173.07,141.7 173.65,142.28 173.88,142.28 174.44,141.72 174.67,141.72 174.91,141.96 174.91,142.19 174.35,142.75 174.35,142.98 174.59,143.22 174.82,143.22 175.43,142.6 175.67,142.6 175.9,142.83 175.9,143.07 175.29,143.68 175.29,143.92 175.56,144.19 175.79,144.19 175.91,144.07 176.14,144.07 176.38,144.3 176.38,144.53 176.26,144.65 176.26,144.89 176.49,145.12 176.72,145.12 176.88,144.97 177.11,144.97 177.35,145.2 177.35,145.43 177.19,145.59 177.19,145.82 177.43,146.06 177.66,146.06 177.77,145.94 178,145.94 178.24,146.18 178.24,146.41 178.13,146.52 178.13,146.76 178.75,147.38 178.99,147.38 179.15,147.22 179.15,146.01 179.32,145.84 179.65,145.84 179.81,146.01 179.81,147.22 179.98,147.38 181.19,147.38 182.73,148.93 182.97,148.93 183.34,148.56 183.57,148.56 183.81,148.79 183.81,149.02 183.43,149.39 183.43,149.63 183.6,149.79 184.68,149.79 v2(185,149.47)
  BOTTOM w0.102: UV1.E13 170.69,139.46 v2(170.75,139.52)
DQMA_5: length 37.3
  TOP w0.127: v2(177.41,138.24) 177.66,137.99 179.39,137.99 183.43,133.95 184.37,133.95 187.41,137 187.41,137.8 183.52,141.69 183.52,145.55 183.76,145.8 183.76,146.22 185.37,147.83 186.48,147.83 UV20.D3
  BOTTOM w0.102: v3(174.02,140.99) 174.02,140.8 172.41,139.19 172.41,139.17 172.23,139 172.14,139 171.88,138.74 UV1.D12
  BOTTOM w0.13: v3(174.02,140.99) 174.23,141.21 175.96,141.21 177.91,139.26 177.91,138.73 v2(177.41,138.24)
DQMA_6: length 32.6
  IN1 w0.102: 184.61,148.55 185.48,149.42 185.48,149.61 185.78,149.91 185.78,150.15 186.27,150.63 186.52,150.63 186.87,150.28 186.87,148.85 187.27,148.46 v2(187.27,147.64) ; 177.77,137.58 175.76,135.57 175.19,135.57 174.81,135.19 174.81,134.91 175.3,134.41 v2(175.79,134.41)
  IN1 w0.165: 177.77,137.58 179.54,137.58 179.71,137.41 179.71,137.01 179.87,136.84 180.2,136.84 180.37,137.01 180.37,137.41 180.53,137.58 180.86,137.58 181.03,137.41 181.03,137.01 181.19,136.84 184.04,136.84 184.61,137.41 184.61,148.55
  BOTTOM w0.102: v2(187.27,147.64) 187.3,147.67 UV19.E7 ; UV1.E3 175.78,134.4 v2(175.79,134.41)
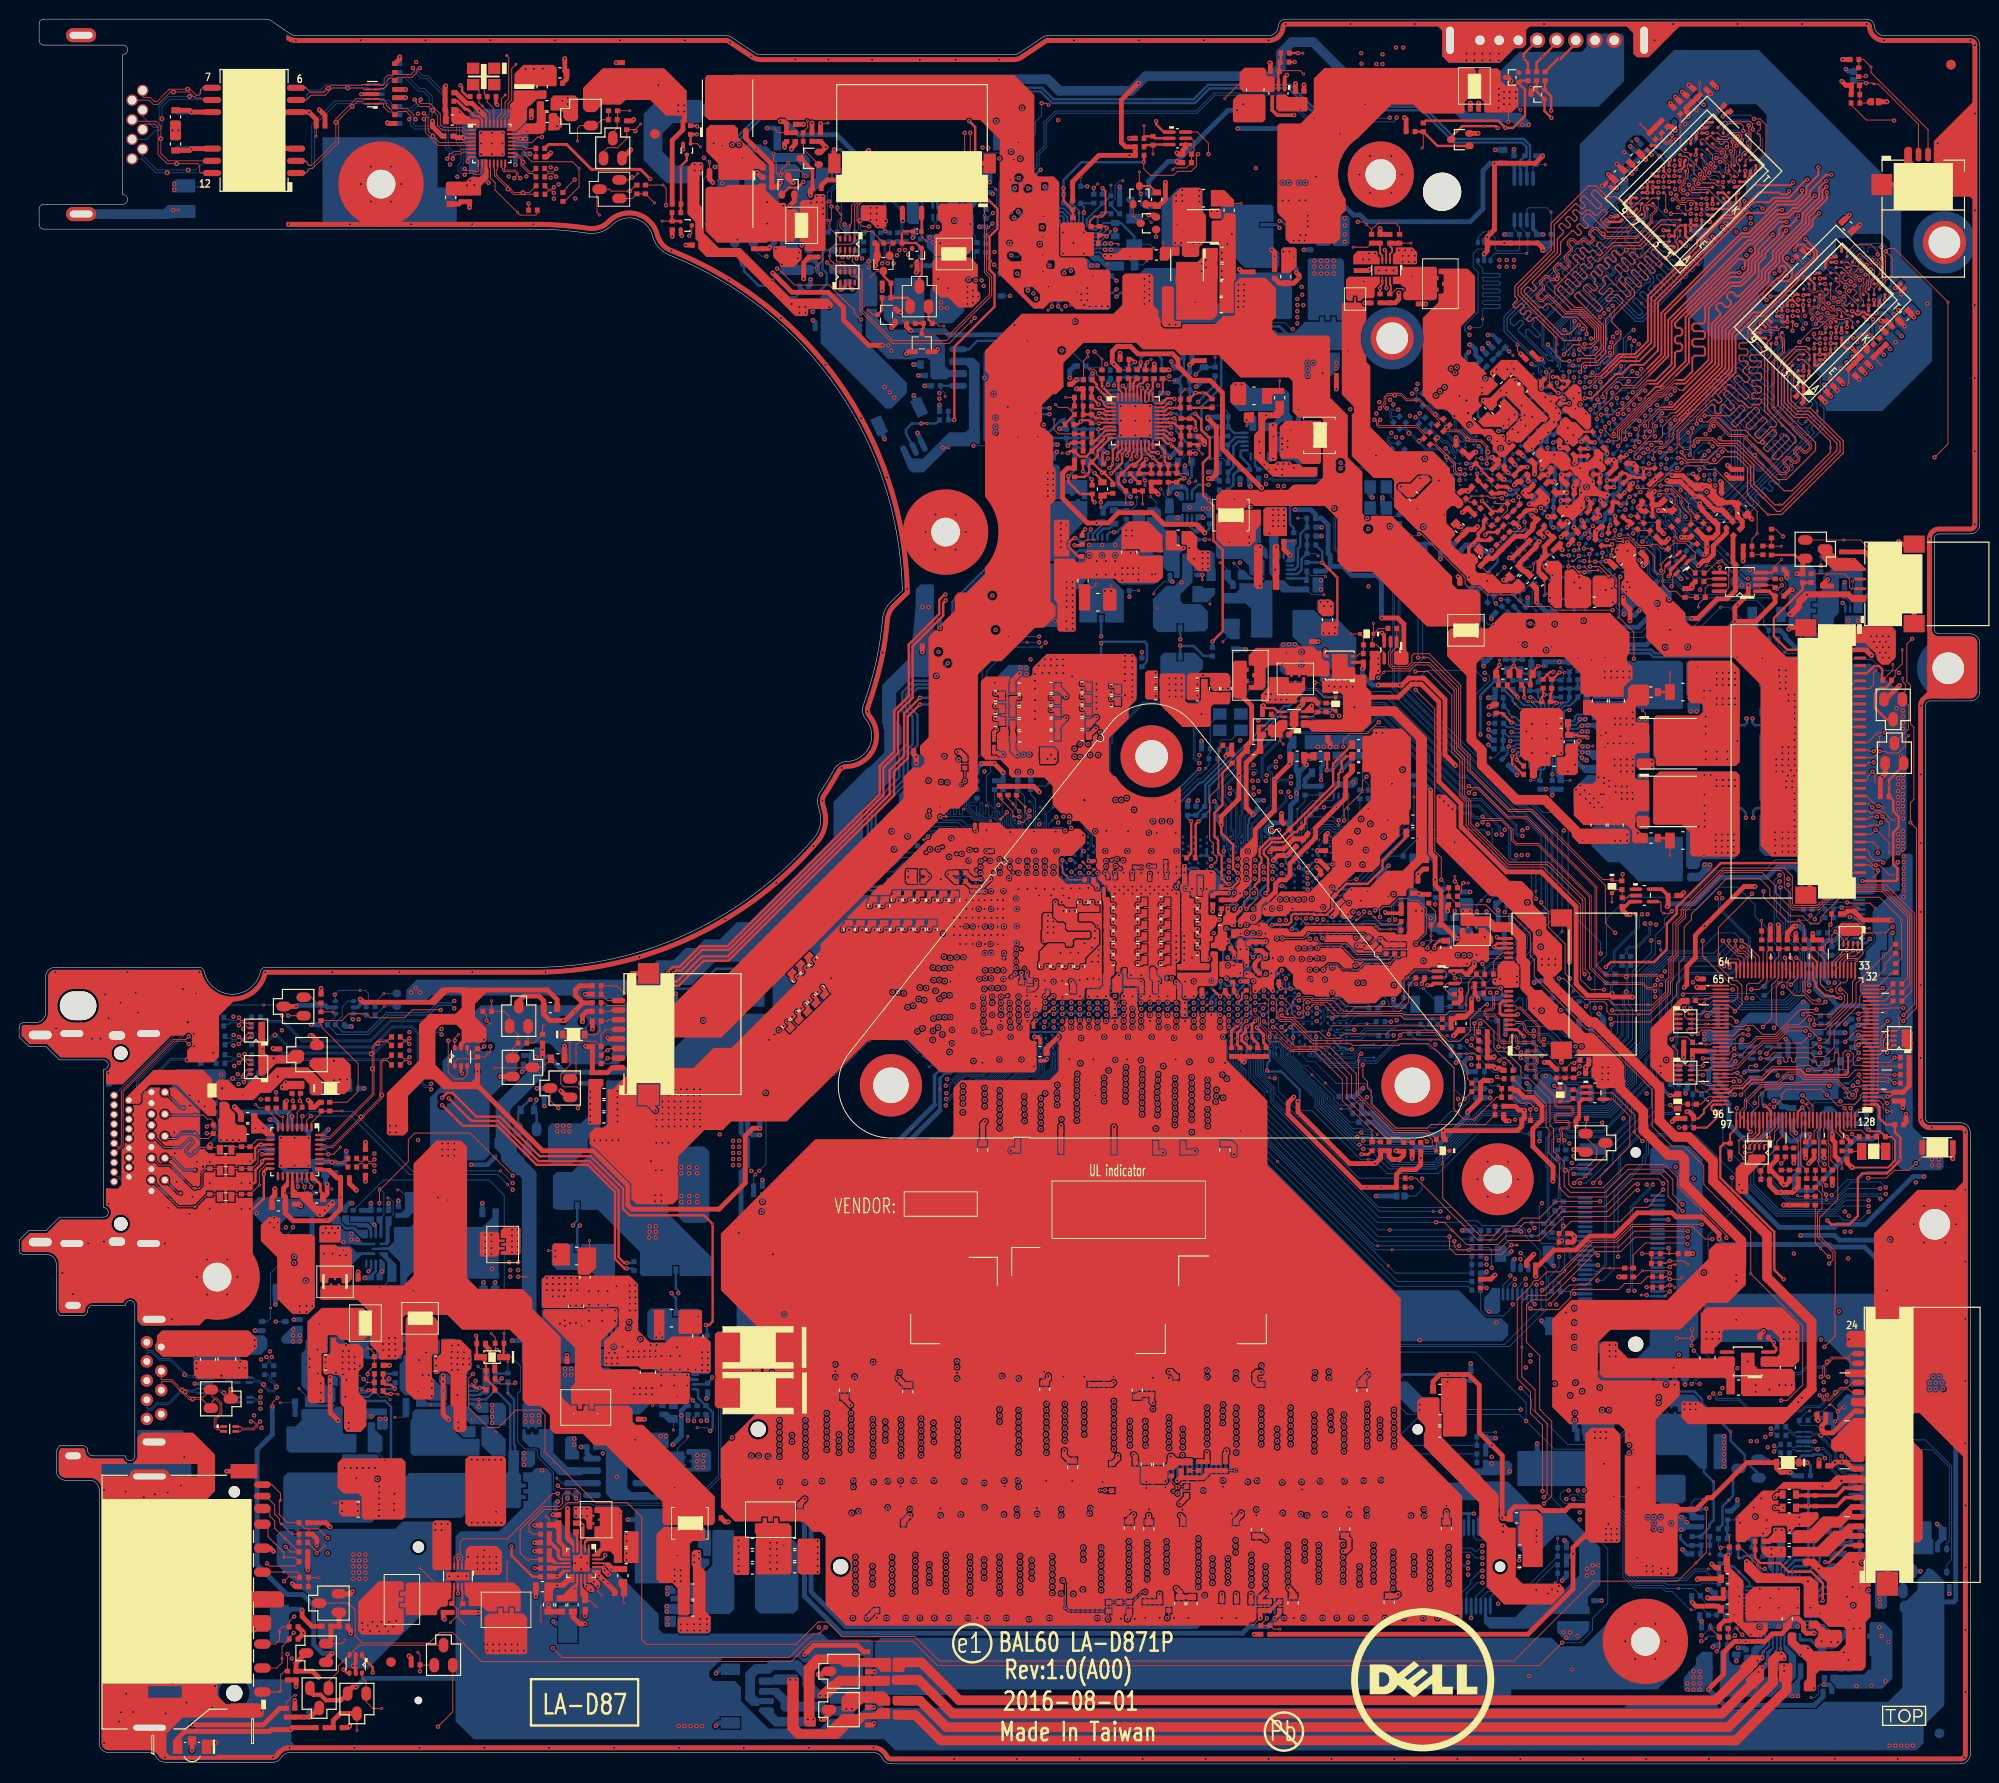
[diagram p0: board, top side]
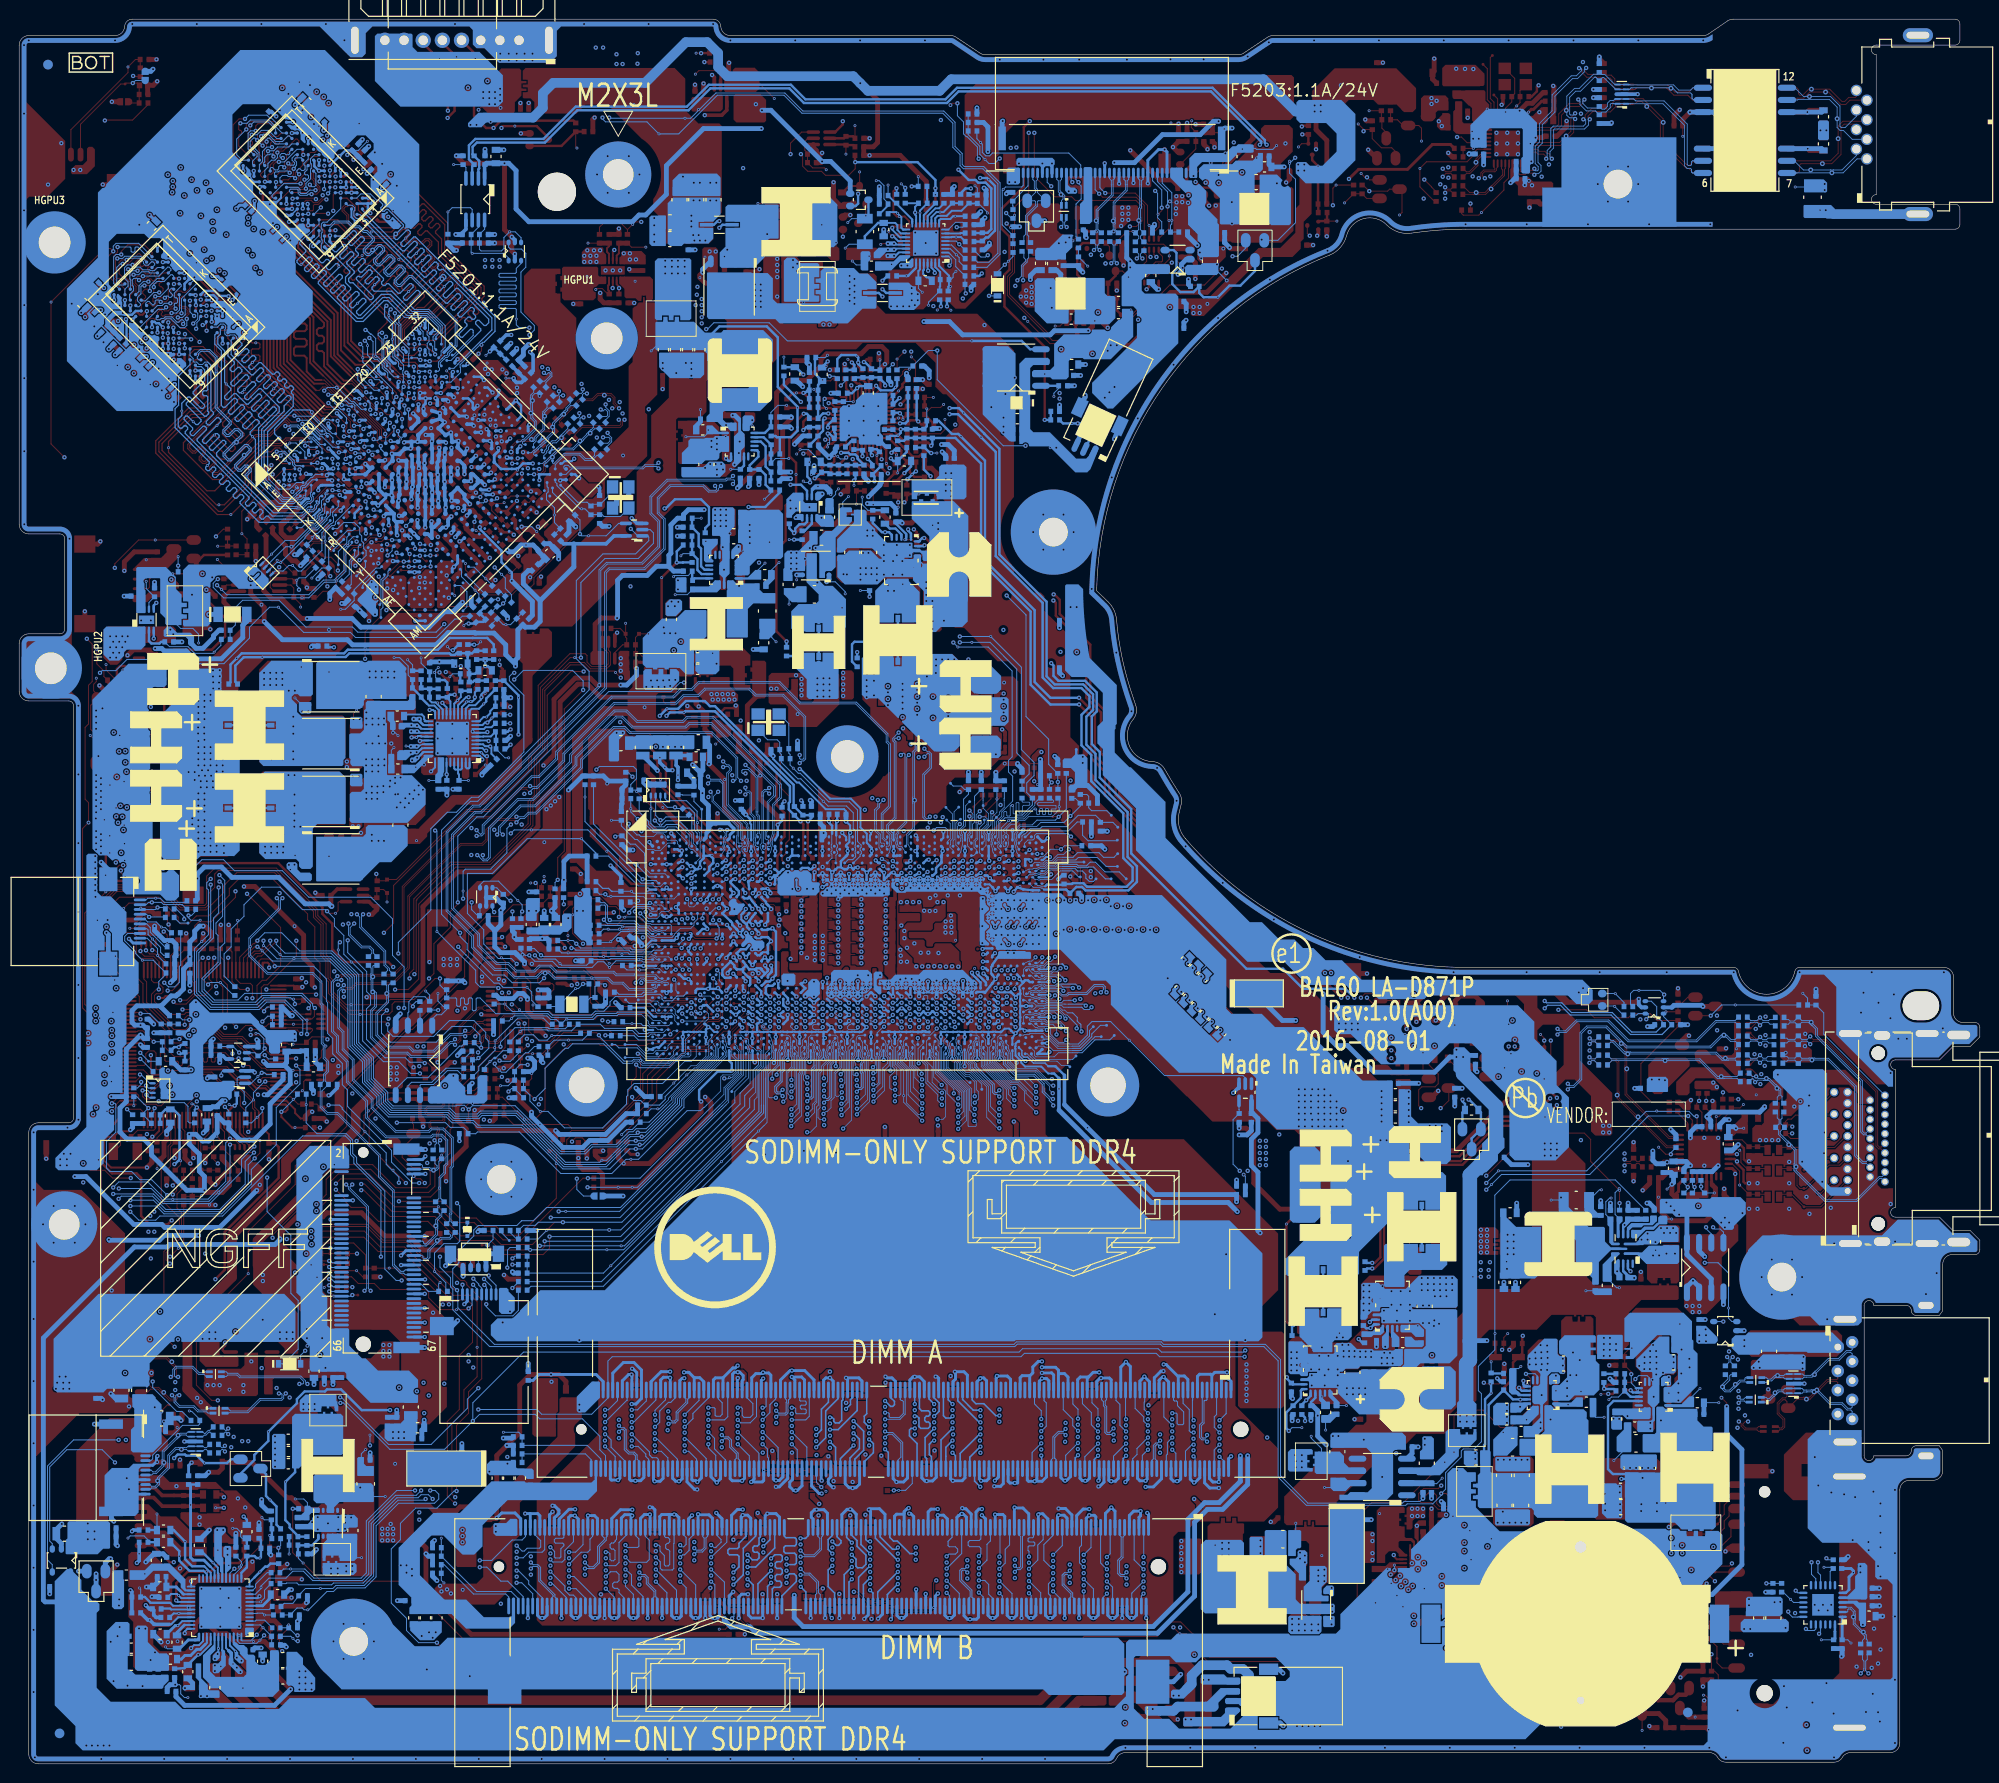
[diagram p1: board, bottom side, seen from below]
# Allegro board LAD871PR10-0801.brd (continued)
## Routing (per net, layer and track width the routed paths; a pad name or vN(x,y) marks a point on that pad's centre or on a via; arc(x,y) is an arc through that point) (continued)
DQMA_7: length 35.9
  BOTTOM w0.102: 178.63,134.68 178.49,134.54 178.49,133.98 177.46,132.96 176.32,132.96 175.63,133.64 UV1.F4 ; 181.71,148.55 181.88,148.72 181.88,148.85 182.07,149.04 182.55,149.04 182.63,148.95 182.9,148.95 183.09,149.14 183.09,149.63 183.01,149.71 183.01,149.98 183.2,150.17 183.55,150.17 183.87,149.84 UV19.D3
  BOTTOM w0.127: 178.63,134.68 178.63,138.93 175.96,141.6 175.96,142.78 176.15,142.97 176.15,143.15 175.93,143.37 175.93,143.55 176.11,143.73 176.29,143.73 176.51,143.51 176.69,143.51 176.87,143.69 176.87,143.87 176.65,144.09 176.65,144.27 176.83,144.45 177.01,144.45 177.23,144.23 177.41,144.23 177.59,144.41 177.59,144.59 177.37,144.81 177.37,144.99 177.55,145.17 177.73,145.17 177.95,144.95 178.13,144.95 179.33,146.15 179.51,146.15 180.23,145.43 180.41,145.43 180.59,145.61 180.59,145.79 v1(180.22,146.16) 179.87,146.51 179.87,146.69 180.05,146.87 180.23,146.87 180.95,146.15 181.13,146.15 181.31,146.33 181.31,146.51 180.59,147.23 180.59,147.41 180.77,147.59 180.95,147.59 181.67,146.87 181.85,146.87 182.03,147.05 182.03,147.23 181.31,147.95 181.31,148.13 181.71,148.53 181.71,148.55
DRAM_RST: length 88.5
  TOP w0.102: RV36.1 183.25,128.78 v2(184.02,128.02) ; v2(199.83,136.27) 201.22,137.67 v1(201.22,152.46) 195.64,158.05 195.03,158.05 v2(194.73,157.76) 195.4,157.09 195.4,155.34 194.08,154.02 UV20.T2 ; UV18.T2 181.55,167.26 182.24,167.96 182.24,170.94 181.61,171.57 v2(180.99,171.57)
  IN1 w0.127: v2(180.99,171.57) 183.71,171.57 183.74,171.54 183.86,171.54 194.72,160.69 194.72,160.56 194.73,160.54 v2(194.73,157.76)
  IN2 w0.127: v2(199.83,136.27) 191.57,128.02 v2(184.02,128.02)
  BOTTOM w0.102: UV17.T2 178.22,171.65 178.39,171.65 178.7,171.96 180.6,171.96 v2(180.99,171.57) ; UV19.T2 192.08,158.59 194.44,158.59 194.73,158.3 v2(194.73,157.76)
DRAM_RST_G: length 22.2
  TOP w0.102: v2(168.84,133.17) 168.98,133.03 169.92,133.03 170,132.95 170.23,132.95 171.02,133.73 171.19,133.73 172.37,134.91 172.66,134.91 172.81,134.76 173.24,134.76 173.86,135.38 175.7,135.38 176.08,135 176.97,135 181.32,130.65 v1(181.32,128.3) 180.78,127.76 RV38.1 CV97.1 RV37.1
  BOTTOM w0.102: v2(168.84,133.17) 168.85,133.18 UV1.L10
DRAM_RST_R: length 2.8
  TOP w0.102: RV37.2 182.78,127.03 CV96.1 ; CV96.1 RV36.2 ; CV96.1 v1(183.84,127)
DRMOS_EN: length 139.7
  TOP w0.102: PR655.2 111.37,127.67 v1(112.16,127.67)
  TOP w0.254: PR655.2 110.8,127.1 v2(110.1,127.1)
  IN1 w0.203: v2(72.29,40.32) 72.52,40.55 72.52,52.58 69.25,55.85 67.41,55.85 65.83,57.43 65.83,69.09 70.58,73.84 70.58,78.61 88.33,96.36 88.33,99.24 93.05,103.96 93.05,105.9 104.57,117.42 104.57,118.49 107.37,121.3 107.37,124.31 110.1,127.04 v2(110.1,127.1)
  IN2 w0.254: v2(72.29,40.32) 71.03,39.05 71.03,37.95 70.33,37.25 63.01,37.25 60.16,40.1 60.16,43.61 61.21,44.65 63.77,44.65 64.12,45 64.12,45.61 v2(63.65,46.08)
  BOTTOM w0.254: v2(110.1,127.1) 110.2,127 PU603.12 ; v2(63.65,46.08) 63.39,46.33 PU604.12 ; v2(72.29,40.32) 72.29,40.18 PC684.1 71.69,39.58 PU605.12
E51_RX1: length 2
  TOP w0.102: TP5802.1 172.46,52.07 v2(172.21,51.82)
  BOTTOM w0.102: WLAN1.38 172.16,51.77 v2(172.21,51.82)
E51_RX2: length 1.8
  TOP w0.102: TP5803.1 v2(169.79,48.89)
  BOTTOM w0.102: WLAN1.50 169.92,48.77 v2(169.79,48.89)
E51_TX1: length 4.5
  TOP w0.102: R5806.2 171.82,52.2 172.08,52.45 v2(172.21,52.45) 173.68,52.45 v1(174.08,52.04)
  BOTTOM w0.102: WLAN1.36 171.9,52.27 172.08,52.45 v2(172.21,52.45)
E51_TX2: length 3.6
  TOP w0.102: R6517.1 TP5804.1 ; TP5804.1 172.14,53.72 v2(172.08,53.78) ; TP5804.1 R5812.2
  BOTTOM w0.102: v2(172.08,53.78) 172.06,53.77 WLAN1.30
EC_AGND: length 11.7
  TOP w0.203: UE1.112 185.15,66.05 185.35,65.85 v2(185.35,65.79)
  TOP w0.508: CE81.2 v2(186.37,63.18) ; C2403.2 183.37,63.04 182.62,62.29 R2407.1 182.81,61.85 183.65,61.01 CE70.2 183.83,60.66 184.08,60.4 v2(184.08,60.4) 184.33,60.4 184.71,60.78 RE347.1 ; v2(184.08,58.28) v1(184.69,58.28) CE88.2 ; CE87.2 v2(185.15,62.66)
  BOTTOM w0.508: RE398.1 184.97,66.17 v2(185.35,65.79)
EC_MUTE#: length 63.4
  TOP w0.102: RE433.1 188.27,60.58 v2(188.52,60.32) ; v2(177.11,11.75) 177.4,12.04 R2708.1 176.43,14.17 v1(176.43,14.49)
  IN1 w0.127: v2(181.29,33.66) 181.29,30.63 178.61,27.95 178.61,24.52 176.4,22.31 176.4,21.65 177.72,20.33 177.72,17.1 177.11,16.5 v2(177.11,11.75)
  IN2 w0.127: v2(181.29,33.66) 181.29,33.02 182.17,32.13 184.14,32.13 187.14,35.13 187.14,40.4 188.97,42.23 188.97,50.67 188.11,51.54 188.11,59.91 v2(188.52,60.32)
EC_MUTE#_R: length 5.6
  TOP w0.102: RE433.2 187.71,62.48 v1(187.71,62.89) 187.71,65.17 187.6,65.29 187.6,65.94 187.95,66.29 UE1.119
EC_SPI_CLK: length 3.2
  TOP w0.102: RE413.2 195.37,82.54 v1(194.59,81.76) 194,81.17 UE1.32
EC_SPI_CS0#: length 2.5
  TOP w0.102: UE1.27 195.1,79.17 RE410.1
EC_SPI_MISO: length 2.9
  TOP w0.102: UE1.29 194.2,79.97 195.5,81.27 RE416.2
EC_SPI_MOSI: length 2.7
  TOP w0.102: UE1.28 194.61,79.57 RE414.2
EC_WAKE#: length 46.3
  TOP w0.102: v2(186.11,78.17) 186.3,78.36 187.13,78.36 187.32,78.17 189.1,78.17 190.43,79.5 190.43,80.14 190.24,80.33 189.73,80.33 189.54,80.52 189.54,80.96 190.05,81.47 190.49,81.47 190.75,81.72 UE1.35 ; RC391.1 156.05,69.53 156.7,68.88 v1(157.26,68.88) 157.64,68.88 v2(158.26,68.26)
  IN1 w0.127: v2(158.26,68.26) 159.62,68.26 163.83,72.47 163.83,74.27 165.8,76.24 167.6,76.24 169.15,77.79 174.94,77.79 175.59,78.44 176.51,78.44 176.9,78.04 185.98,78.04 v2(186.11,78.17)
EDP_AUX: length 7.8
  BOTTOM w0.091: 87.45,164.72 87.45,164.7 87.45,164.7 87.45,164.64 87.46,164.64 87.46,162.28 87.57,162.17 87.57,161.3 87.54,161.27 87.54,160.68 87.57,160.64 87.57,160.03 R5218.1 87.57,159.34 87.57,159.1 C5212.2
  BOTTOM w0.102: LCD1.14 87.3,165.27 87.45,165.12 87.45,164.72
EDP_AUX#: length 7.7
  BOTTOM w0.091: C5209.2 87.75,159.1 87.75,159.34 R5219.1 87.75,160.02 v4(87.75,160.97) 87.75,162.24 87.64,162.35 87.64,164.72
  BOTTOM w0.102: 87.64,164.72 87.64,165.18 87.8,165.34 LCD1.15
EDP_AUX_DN: length 85
  IN2 w0.127: v2(87.95,157.01) 87.71,156.77 87.71,156 88.58,155.13 89.95,155.13 98.29,146.79 98.29,141.57 102.57,137.29 102.57,123.66 99.92,121 99.92,110.33 101.63,108.61 102.84,108.61 105.28,106.17 107.98,106.17 108.68,105.46 110.09,105.46 110.19,105.57 110.19,105.8 v2(110.11,105.88) ; v2(109.54,98.78) 109.71,98.62 110.08,98.62 110.5,98.2 110.5,96.64 110.71,96.43 111.57,96.43 112.9,95.1 112.9,94.17 113.06,94.01 113.25,94.01 v2(113.4,94.17)
  BOTTOM w0.089: UC1.E45 113.2,93.96 v2(113.4,94.17)
  BOTTOM w0.091: v2(110.11,105.88) 109.78,105.55 109.58,105.55 109.36,105.33 109.36,103.88 110.09,103.15 110.09,98.8 109.87,98.58 109.75,98.58 v2(109.54,98.78) ; C5209.1 87.75,157.47 87.75,157.21 v2(87.95,157.01)
EDP_AUX_DP: length 85
  IN2 w0.127: v2(110.11,105.04) 109.95,105.21 108.57,105.21 107.87,105.91 105.17,105.91 102.73,108.35 101.53,108.35 99.66,110.22 99.66,121.11 102.31,123.77 102.31,137.19 98.03,141.47 98.03,146.69 89.85,154.87 88.47,154.87 87.45,155.89 87.45,156.92 v2(87.36,157.01) ; v2(109.54,98.2) 109.71,98.36 109.97,98.36 110.24,98.09 110.24,96.53 110.6,96.17 111.47,96.17 112.64,95 112.64,94.07 112.95,93.76 113.25,93.76 v2(113.4,93.6)
  BOTTOM w0.089: UC1.F45 113.23,93.6 v2(113.4,93.6)
  BOTTOM w0.091: v2(109.54,98.2) 109.75,98.4 109.95,98.4 110.27,98.72 110.27,103.22 109.54,103.95 109.54,105.26 109.65,105.37 109.78,105.37 v2(110.11,105.04) ; C5212.1 87.57,157.47 87.57,157.21 v2(87.36,157.01)
EDP_BKLT_CTRL: length 4.2
  TOP w0.102: v1(66.28,162.81) R5206.2 R5222.2 63.97,163.28 D5202.2
EDP_COMP: length 4.5
  TOP w0.127: v2(108.83,94.25) 108.83,92.97 109.59,92.2 RC2.2
  BOTTOM w0.127: UC1.E52 109.16,94.09 v2(108.83,94.25)
EDP_HPD: length 140.4
  TOP w0.102: RC1.2 125.15,105.8 125.15,101.85 124.2,100.9 ; RN5201.5 85.67,157.62 85.27,157.23 85.27,156.76 85.38,156.65 85.97,156.65 86.67,155.96 RN5203.6 86.67,155.33 86.87,155.12 87.41,155.12 87.71,154.81 87.71,151.57 91.15,148.13 97.01,148.13 v1(99.33,150.45) v2(99.69,150.81)
  TOP w0.127: v2(124.36,93.62) 124.96,94.23 124.96,94.55 124.58,94.93 124.58,96.01 124.2,96.39 124.2,100.9
  IN1 w0.127: v2(112.26,97.28) 112.01,97.28 109.78,99.5 106.1,99.5 105.28,100.33 102.48,100.33 v2(102.16,100.01) ; v2(94.86,102.55) 94.86,102.8 95.43,103.37 95.43,105.94 104.71,115.22 105.49,115.22 v2(105.52,115.19)
  IN2 w0.076: v2(133.46,90.13) 132.99,89.66 132.77,89.66 132.68,89.57 132.68,89.57 131.93,88.82 130.62,88.82 130.5,88.7 125.76,88.7 124.9,89.56 124.9,93.09 v2(124.36,93.62)
  IN2 w0.127: v2(99.69,150.81) 99.69,148.38 104.51,143.56 104.51,116.2 v2(105.52,115.19) ; v2(102.16,100.01) 97.15,100.01 94.86,102.3 v2(94.86,102.55) ; v2(112.26,97.28) 112.26,96.9 114.36,94.81 115.31,94.81 115.63,94.49 122.17,94.49 123.03,93.62 v2(124.36,93.62)
  BOTTOM w0.089: UC1.L10 133.13,90.66 133.47,90.16 v2(133.46,90.13)
EDP_HPD_CONN: length 7.8
  TOP w0.102: v2(84.74,162.43) 84.74,161.11 v1(84.59,160.96) 84.59,160.15 RN5201.4
  BOTTOM w0.102: v2(84.74,162.43) 84.74,163.97 85.8,165.03 LCD1.11
EDP_TX0: length 7
  BOTTOM w0.091: 89.15,164.72 89.15,164.7 89.14,164.69 89.14,164.16 90.41,162.88 v4(90.41,160.92) 90.41,160.05 C5210.2
  BOTTOM w0.102: 89.15,164.72 89.15,165.11 89.3,165.27 LCD1.18
EDP_TX0#: length 7
  BOTTOM w0.091: C5203.2 90.23,160.05 90.23,160.59 90.2,160.63 90.2,161.22 90.23,161.25 90.23,162.81 88.96,164.08 88.96,164.69 88.95,164.7 88.95,164.72
  BOTTOM w0.102: 88.95,164.72 88.95,165.11 88.8,165.27 LCD1.17
EDP_TX0_DN: length 78.4
  IN2 w0.127: v2(90.03,156.51) 90.2,156.35 90.2,155.54 99.93,145.81 99.93,143.29 103,140.22 103,122.67 100.41,120.08 100.41,114.74 102.29,112.86 102.29,109.94 105.26,106.97 110.81,106.97 110.97,106.81 110.97,106.65 v2(110.68,106.36)
  BOTTOM w0.076: 111.68,96.97 111.69,96.97 111.7,96.97 111.82,96.84 111.82,95.91 UC1.C47
  BOTTOM w0.091: v2(90.03,156.51) 90.23,156.72 90.23,158.43 C5203.1 ; v2(110.68,106.36) 110.89,106.15 110.89,105.75 111.14,105.51 v4(111.14,100.51) 111.14,97.52 111.68,96.97
EDP_TX0_DP: length 78.4
  IN2 w0.127: v2(90.62,156.51) 90.45,156.35 90.45,155.65 100.18,145.92 100.18,143.4 103.26,140.32 103.26,122.56 100.67,119.97 100.67,114.84 102.55,112.97 102.55,110.05 105.36,107.23 110.91,107.23 111.23,106.91 111.23,106.65 v2(111.52,106.36)
  BOTTOM w0.076: 111.81,97.1 111.99,96.92 111.99,95.8 UC1.C46
  BOTTOM w0.091: v2(111.52,106.36) 111.42,106.46 111.24,106.46 111.07,106.29 111.07,105.83 111.32,105.58 111.32,100.84 111.35,100.8 111.35,100.21 111.32,100.18 111.32,97.59 111.81,97.1 ; C5210.1 90.41,158.43 90.41,156.72 v2(90.62,156.51)
EDP_TX1: length 7.1
  BOTTOM w0.091: LCD1.21 90.8,165.34 90.61,165.15 90.61,164.68 90.6,164.68 90.6,163.65 92.19,162.06 v4(92.19,160.95) 92.19,160.05 C5213.2
EDP_TX1#: length 7.1
  BOTTOM w0.091: C5211.2 92.01,160.05 92.01,160.62 91.98,160.65 91.98,161.24 92.01,161.28 92.01,161.99 90.42,163.58 90.42,164.72
  BOTTOM w0.102: 90.42,164.72 90.42,165.21 90.3,165.33 LCD1.20
EDP_TX1_DN: length 78.9
  IN2 w0.127: v2(111.73,105.22) 112.03,105.52 112.03,106.75 110.99,107.78 105.42,107.78 102.98,110.23 102.98,113.68 101.1,115.55 101.1,119.51 103.74,122.15 103.74,143.25 92,154.98 92,157.72 v2(91.83,157.89)
  BOTTOM w0.076: 112.77,97.35 112.78,97.34 112.78,97.05 112.92,96.91 112.92,96.62 112.88,96.51 112.88,96.22 112.93,96.06 112.93,96.01 112.91,95.94 112.91,95.93 112.85,95.76 112.77,95.68 112.52,95.68 112.39,95.54 UC1.D46
  BOTTOM w0.091: v2(91.83,157.89) 92.04,158.1 92.04,158.4 C5211.1 ; 112.77,97.35 111.95,98.17 111.95,105 v2(111.73,105.22)
EDP_TX1_DP: length 78.8
  IN2 w0.127: v2(92.42,157.89) 92.26,157.74 92.26,155.09 104,143.35 104,122.04 101.36,119.4 101.36,115.66 103.23,113.78 103.23,110.33 105.53,108.04 111.1,108.04 112.28,106.86 112.28,105.5 v2(112.57,105.22)
  BOTTOM w0.076: UC1.C45 112.7,95.44 112.83,95.44 112.96,95.57 113.07,95.91 113.07,95.92 113.1,95.99 113.1,96.09 113.05,96.25 113.05,96.49 113.09,96.59 113.09,96.98 112.95,97.12 112.95,97.41
  BOTTOM w0.091: v2(112.57,105.22) 112.39,105.4 112.24,105.4 112.13,105.29 112.13,98.25 112.95,97.43 112.95,97.41 ; C5213.1 92.22,158.45 92.22,158.09 v2(92.42,157.89)
EDP_VDD_EN: length 154.4
  TOP w0.102: v2(138.14,106.08) 138.14,106.78 138.8,107.44 140.58,107.44 141.79,108.65 v2(141.85,108.65)
  IN1 w0.127: v2(141.85,108.65) 141.37,109.13 141.37,113.47 141.12,113.72 141.12,115.7 140.18,116.64 140.18,121.57 136.91,124.84 135.76,124.84 133.34,127.25 133.34,129.79 132.64,130.49 132.64,131.14 130.55,133.24 130.55,134.49 130.3,134.74 129.73,134.74 129.15,135.32 129.15,136.28 126.19,139.24 126.19,141.25 124.48,142.97 124.48,146.85 123.27,148.06 113.9,148.06 112.47,146.62 108.08,146.62 105.64,149.06 97.75,149.06 95.05,151.75 95.05,156.31 92.49,158.88 84.15,158.88 83.07,159.96 76.36,159.96 71.68,164.63 71.68,167.26 v2(71.43,167.51) ; v2(131.51,88) 132.28,88.77 136.45,88.77 136.77,89.09 136.77,90.3 136.45,90.61 136.45,96.02 138.68,98.24 138.68,99.44 138.49,99.63 138.49,105.73 v2(138.14,106.08)
  BOTTOM w0.102: v2(71.43,167.51) v1(72.02,166.93) 72.02,165.9 71.39,165.28 71.39,160.74 73.23,158.9 D5201.2 ; UC1.U13 v2(131.51,88)
EDRAM_OPIO_RCOMP: length 2.4
  TOP w0.381: v2(100.29,92.26) 99.45,92.26 98.79,92.93 RC90.1
  BOTTOM w0.254: v2(100.29,92.26) 100.49,92.07 UC1.H66
EMMC_RCOMP: length 3.1
  BOTTOM w0.203: UC1.AT1 138.37,77.93 139.31,78.87 RC4.1
EN_1.0V_VCCST_ON: length 3.5
  TOP w0.102: DZ1703.2 136.96,109.85 136.82,109.72 RZ1701.2 CZ1703.1 134.99,109.22 UZ21.3
EN_1.8VALW: length 2.1
  BOTTOM w0.102: PR501.2 174.48,27.24 174.86,27.62 v1(175.75,27.62)
EN_2.5V: length 1.4
  BOTTOM w0.102: PC805.1 56.66,29.22 v1(56.09,29.79)
EN_3V: length 2.4
  TOP w0.102: v1(35.69,39.01) 35.74,38.96 v2(36.43,38.96)
  TOP w0.254: PR121.1 36.99,38.96 v2(36.43,38.96)
  BOTTOM w0.254: v2(36.43,38.96) 36.2,38.73 PU100.12
EN_5V: length 2.7
  TOP w0.254: PR120.1 48.47,39.22 v2(48.06,39.22) 47.58,39.22 v1(47.23,39.57)
  BOTTOM w0.254: v2(48.06,39.22) 48.06,39.22 48.06,39.18 47.8,38.91 PU102.12
EN_+1.5VGPU: length 7.6
  BOTTOM w0.102: v1(126.79,131.9) 126.13,132.56 PR1403.2
  BOTTOM w0.254: PU1400.11 127.61,137.01 127.43,136.83 127.43,136.34 128.34,135.43 PR1404.1 PC1404.1 127.25,135 126.68,134.43 126.68,133.4 PR1403.2
EN_+1VALW: length 2.7
  TOP w0.102: PC304.1 v1(132.91,127.51)
  TOP w0.508: v2(132.58,126.05) 131.95,126.68 PC304.1
EN_+VCCEOPIO:
  vias: v2(37.06,56.21)
ENABLE_VGA: length 2.3
  BOTTOM w0.203: PU1100.8 156.06,107.94 155.88,108.12 155.27,108.12 PR1116.2
ENLDO_3V5V: length 25.8
  TOP w0.102: v2(36.37,40.64) 36.37,40.88 PR103.1 PR102.1 37.05,42.81 36.51,43.36 v1(36.3,43.36)
  IN1 w0.127: v2(36.37,40.64) 36.76,41.03 36.76,44.01 37.84,45.08 45.78,45.08 47.55,43.31 47.55,41.53 46.89,40.87 46.89,40.41 47.36,39.94 v2(47.62,39.94)
  BOTTOM w0.102: PU100.11 35.83,39.18 36.37,39.73 v2(36.37,40.64)
  BOTTOM w0.254: PU102.11 47.42,39.36 47.62,39.56 v2(47.62,39.94)
EOPIO_RCOMP: length 3.7
  TOP w0.381: RC91.1 99.25,91.52 v1(100.15,91.52) 100.56,91.52 v2(101.31,92.26)
  BOTTOM w0.254: v2(101.31,92.26) 101.5,92.07 UC1.H65
FAN1_DAC_1: length 154.3
  TOP w0.102: v2(191.89,77.66) 192.2,77.97 UE1.24
  IN1 w0.127: v2(191.89,77.66) 192.31,78.08 192.31,81.43 189.8,83.95 187.7,83.95 186.87,84.77 179.51,84.77 178.87,85.41 174.3,85.41 173.28,86.43 171.46,86.43 171.33,86.56 168.28,86.56 166.99,87.86 164.46,87.86 162.76,89.56 162.76,90.54 157.74,95.55 153.77,95.55 152.58,96.74 151.65,96.74 151.65,96.74 148.01,96.74 143.27,101.48 143.27,110.39 142.73,110.93 142.73,115.69 141.19,117.22 141.19,122.98 137.56,126.62 135.57,126.62 134.51,127.67 134.51,140.11 135.44,141.03 135.44,147.57 133.37,149.64 v2(132.87,149.64)
  BOTTOM w0.102: v1(105.16,148.41) 124.4,148.41 126.29,150.3 132.07,150.3 132.73,149.64 v2(132.87,149.64)
  BOTTOM w0.254: v1(105.16,148.41) 99.96,148.41 99.08,147.54 FAN261.4
FAN1_TACH: length 216.8
  TOP w0.102: RE441.1 189.08,87.66 v2(188.97,87.55) 188.83,87.41 188.83,85.83 CE75.1 188.75,84.29 UE1.40
  TOP w0.254: v2(97.56,140.17) v1(97.56,144.96) 97.56,147.79 101.76,151.99 101.76,155.32 101.24,155.84 101.24,159.3 102.06,160.12 102.06,162.18 99.74,164.5 99.74,170.71 v2(99.12,171.34)
  IN1 w0.127: v2(99.12,171.34) 101.64,173.86 124.92,173.86 129.06,178 134.15,178 135.38,176.78 135.38,166.77 140.71,161.44 140.71,158.88 138.87,157.04 138.87,143.7 140.46,142.11 140.46,134.37 138.87,132.78 138.87,130 144.87,124 144.87,118.21 146.36,116.73 146.36,111.63 145.89,111.16 145.89,101.74 148.69,98.93 150.68,98.93 151.82,100.08 153.35,100.08 153.89,99.53 156.81,99.53 159.18,97.17 159.18,96.09 165.92,89.34 170.34,89.34 171.99,87.7 173.81,87.7 174.45,87.06 180.78,87.06 181.48,86.36 183.51,86.36 185.03,87.88 186.06,87.88 186.28,87.67 188.84,87.67 v2(188.97,87.55)
  BOTTOM w0.254: EC2602.1 R2606.1 v2(97.56,140.17)
FAN1_TACH_C: length 6.8
  TOP w0.102: v2(94.11,139.81) v1(94.72,139.81)
  BOTTOM w0.254: R2606.2 95.65,139.81 v2(94.11,139.81) 93.14,139.81 92.51,139.18 92.51,138.78 FAN1.2
FAN_VCC1: length 0.6
  TOP w0.102: v2(96.35,137.27) v1(96.98,137.27)
FB_1.2V: length 1.1
  TOP w0.102: v1(54.97,25.82) 55.31,25.48 PR204.1
FB_1.8VALW: length 4.8
  BOTTOM w0.102: PR505.1 175.42,21.44 v1(174.92,20.94)
  BOTTOM w0.254: PU500.6 173.33,23.45 174,22.78 PC503.2 175.44,22.78 PR504.1 175.47,21.95 PR505.1
FB_+1.5VGPU: length 6
  BOTTOM w0.102: v1(124.26,136.14) 125.63,136.14 126.11,135.67
  BOTTOM w0.254: PU1400.14 126.88,138.36 PC1409.2 126.1,136.63 PR1410.1 PR1411.1
FB_+1VALW: length 6.4
  BOTTOM w0.102: v1(135.52,126) 135.29,126.23 PC309.2
  BOTTOM w0.254: PR310.1 134.36,128.05 PR309.1 134.35,127.11 PC309.2 133.79,125.67 133.79,124.52 133.36,124.1 PU300.14
FB_GND: length 2.4
  TOP w0.381: v2(155.14,132.4) 154.97,132.56 154.36,132.56 154.29,132.49 153.7,132.49 RV158.1
  BOTTOM w0.305: v2(155.14,132.4) 155.16,132.37 UV1.AD20
FB_IA: length 7.9
  TOP w0.102: v1(115.45,131.33) PR650.1
  TOP w0.203: 117.1,136.75 117.05,136.8 PU602.17
  TOP w0.254: 117.1,136.75 117.1,136.22 PR648.2 116.29,135.51 116.01,135.51 PR645.2 114.69,134.19 114.69,133.53 PR650.1
FB_VDDC: length 2.3
  TOP w0.381: v2(155.53,132.89) 155.2,133.22 RV159.1
  BOTTOM w0.305: v2(155.53,132.89) 155.56,132.87 156.33,132.87 UV1.AC20
FB_VDDCI: length 1.9
  BOTTOM w0.102: UV1.W1 168.42,124.82 T222.1
FB_VSA: length 4.3
  TOP w0.203: PU602.25 119.95,139.88
  TOP w0.254: PR652.1 PR646.1 121.22,138.53 PR649.1 120.95,139.39 120.49,139.85 120.32,139.85 120.29,139.88 119.95,139.88
FBA_ZQ0: length 4.9
  IN1 w0.127: v2(177.76,164.98) 177.76,164.83 179.59,163 v2(179.98,163)
  BOTTOM w0.102: UV17.L8 177.79,164.95 v2(177.76,164.98)
  BOTTOM w0.305: v2(179.98,163) 180.02,162.97 180.02,162.23 RV261.1
FBA_ZQ1: length 5
  TOP w0.102: RV262.1 173.28,172.07 v1(173.28,170.81) 173.28,168.49 173.7,168.07 174.16,168.07 UV18.L8
FBA_ZQ2: length 5.9
  TOP w0.203: v2(191.22,151.52) 191.31,151.52 191.68,151.15 191.97,151.15 192.21,151.38 192.53,151.38 192.78,151.13 192.97,151.13 v2(193.41,150.68)
  BOTTOM w0.102: UV19.L8 191.26,151.49 v2(191.22,151.52)
  BOTTOM w0.254: v2(193.41,150.68) 193.35,150.62 193.35,148.15 RV263.1
FBA_ZQ3: length 6.9
  TOP w0.102: v2(188.4,154.35) 188.38,154.37 UV20.L8 ; v1(186.06,156.57) RV264.1 185.02,156.83 185.02,156.76 v2(185,156.76)
  IN1 w0.127: v2(185,156.76) 185.02,156.76 185.02,156.78 185.59,156.21 186.4,156.21 186.72,155.89 187.51,155.89 188.4,155 v2(188.4,154.35)
FCCM_GT: length 151.5
  TOP w0.203: PU602.11 114.65,137.59 114.19,137.13
  TOP w0.254: v2(113.75,135.15) 114.08,135.48 v1(114.08,135.64) 114.09,135.65 114.09,137.03 114.19,137.13
  IN1 w0.203: v2(64.81,44.3) 64.26,44.84 60.24,44.84 58.95,43.55 58.95,39.89 63.39,35.45 68.23,35.45 68.45,35.23 69.89,35.23 70.4,35.74 v2(70.4,35.75) 71,35.15 71.87,35.15 73.51,36.79 73.51,60.74 72.25,62 72.25,78.54 89.56,95.85 89.56,98.37 94.81,103.63 94.81,106.2 105.63,117.01 105.63,117.98 108.49,120.84 108.49,123.58 109.31,124.4 110.31,124.4 111,125.09 111,128.32 110.71,128.62 110.71,129.07 111.55,129.92 113.88,129.92 114.61,130.65 114.61,132.59 114.42,132.78 114.42,134.78 114.05,135.15 v2(113.75,135.15)
  BOTTOM w0.254: PR671.2 70.4,36.1 v2(70.4,35.75) ; v2(64.81,44.3) 64.42,43.92 PR664.2
FCCM_IA: length 2.9
  TOP w0.203: 119.37,138.08 119.17,138.28 PU602.21
  TOP w0.254: 119.37,138.08 119.37,138.05 119.73,137.69 v1(120.12,137.69) 121.09,136.73 PR659.2
FCCM_VSA: length 19.3
  TOP w0.203: PU602.29 119.44,141.48 119.88,141.92 v2(120.1,141.92)
  IN1 w0.254: v2(120.1,141.92) 119.82,141.92 119.25,141.35 119.25,140.14 119.63,139.76 119.63,138.18 122.74,135.06 122.74,128.65 v2(123.7,127.69)
  BOTTOM w0.102: v2(123.7,127.69) v1(124.21,127.69)
  BOTTOM w0.254: PR679.2 v2(123.7,127.69)
FON#: length 3.2
  BOTTOM w0.102: R2605.2 96.1,143.45 96.6,142.95 v1(96.6,142.62)
  BOTTOM w0.254: FAN261.1 R2605.2
GPIO19_CTF: length 4.6
  BOTTOM w0.102: RV152.1 173.92,126.52 RV151.2 173.98,127.7 v1(173.98,127.92) 173.57,128.33 173.41,128.33 172.1,129.64 UV1.M2
GPIO28: length 7.8
  BOTTOM w0.102: UV1.R5 169.74,128.65 170.29,128.65 172.26,126.68 RV21.2 172.97,124.73 v1(174.02,123.67)
GPP_B23: length 22.5
  BOTTOM w0.102: RC365.1 v1(153.88,79.25) 153.1,78.47 149.3,78.47 148.92,78.09 144.86,78.09 144.45,78.5 143.54,78.5 142.91,79.13 142.91,79.48 142.36,80.02 139.49,80.02 139.25,80.26 137.7,80.26 137.49,80.05 137.49,79.75 137.32,79.58 136.42,79.58 136.14,79.86 136.14,79.87 135.92,80.09 135.23,80.09 UC1.AM7
GPP_C5: length 6
  BOTTOM w0.102: RC25.1 143.4,87.47 143.38,87.44 141.77,87.44 v1(141.63,87.3) 140.25,87.3 139.91,86.96 139,86.96 138.58,86.54 UC1.W1
GPU_B+:
  vias: v1(68.64,38.28) v2(56.42,45.9) v2(56.91,46.25) v2(56.95,45.67) v2(57.46,45.97) v2(58.1,45.97) v2(59.45,47.27) v2(59.45,46.2) v2(60.81,47.27) v2(60.81,46.2) v2(62.17,47.27) v2(62.17,46.2) v2(64.13,39.18) v2(64.13,38.54) v2(64.76,39.18) v2(64.76,38.54) v2(65.4,39.18) v2(65.4,38.54) v2(66.03,39.18) v2(66.03,38.54) v2(66.99,40.53) v2(66.99,39.46) v2(68.35,40.53) v2(68.35,39.46) v2(69.71,40.53) v2(69.71,39.46)
GPU_PWR_LEVEL: length 87.8
  TOP w0.102: UE1.21 194.24,76.77 v2(194.94,77.47)
  IN2 w0.127: v2(167.57,130.81) 168.41,130.81 168.61,130.61 169.55,130.61 170.26,131.32 171.63,131.32 171.89,131.06 172.84,131.06 173.09,131.32 173.89,131.32 174.91,130.3 175.84,130.3 180.26,125.88 187.05,125.88 v2(187.97,124.97) 192.11,124.97 192.42,125.29 195.26,125.29 196.02,124.52 196.02,114.74 195.5,114.22 195.5,110.85 192.72,108.07 192.72,104.27 193.03,103.95 194.37,103.95 195.07,103.25 195.07,92.88 195.66,92.28 195.66,89.59 196.4,88.86 196.4,81.03 194.94,79.57 v2(194.94,77.47)
  BOTTOM w0.102: RV260.1 v2(187.97,124.97) v1(187.97,125.91) ; UV1.T9 167.43,130.67 v2(167.57,130.81)
GPU_THM_INT: length 1.7
  TOP w0.102: RV146.2 176.06,123.6 UV11.6
GPU_VID1: length 89.3
  IN2 w0.127: v2(196.12,113.79) 196.78,114.45 196.78,126.24 195.89,127.13 179.92,127.13 176.44,130.61 174.96,130.61 174,131.57 172.97,131.57 172.71,131.32 172.01,131.32 171.76,131.57 170.69,131.57 170.59,131.67 168.42,131.67 v2(168.41,131.68)
  BOTTOM w0.102: UV1.P8 168.28,131.55 v2(168.41,131.68) ; RV78.2 158.32,119.7 158.62,119.41 159.1,119.41 161.03,117.47 169.46,117.47 169.99,118.01 174.87,118.01 v1(177.5,120.64) 178.43,120.64 180.52,118.54 180.52,117.41 183.19,114.74 186.51,114.74 187.34,115.57 189.79,115.57 190.18,115.19 193.3,115.19 194.47,114.02 195.89,114.02 v2(196.12,113.79)
GPU_VID3: length 28.6
  IN2 w0.127: v2(154.95,124.79) 158.55,124.79 161.25,122.1 163.3,122.1 164.36,123.15 167,123.15 169.04,125.2 v2(169.04,125.55)
  BOTTOM w0.102: RV77.2 153.19,121.96 153.83,122.59 153.83,123.67 v1(154.22,124.07) v2(154.95,124.79) ; UV1.N1 171.32,128.84 170.69,129.46 169.58,129.46 169.02,128.91 169.02,128.27 168.81,128.07 168.81,127.53 168.61,127.33 168.61,126.77 168.36,126.52 168.36,126.03 168.84,125.55 v2(169.04,125.55)
GT1N: length 121
  TOP w0.254: PR670.1 113.02,135.71 v1(113.02,136.52) 113.02,136.64 113.13,136.75 v2(113.54,136.75)
  IN1 w0.254: v2(68.76,49.09) 68.76,49.02 68.33,48.59 66.4,48.59 63.87,51.11 63.87,70.33 69.08,75.53 69.08,78.96 86.86,96.74 86.86,99.66 91.69,104.49 91.69,106.32 103.34,117.97 103.34,119.01 106.13,121.79 106.13,128.77 108.42,131.06 113.21,131.06 113.47,131.32 113.47,131.89 112.83,132.52 112.83,136.45 113.13,136.75 v2(113.54,136.75)
  BOTTOM w0.254: v2(113.54,136.75) 113.21,137.08 PR673.1 ; PL605.2 68.51,49.59 68.76,49.34 v2(68.76,49.09)
GT1P: length 119.7
  IN1 w0.254: v2(113.61,136.16) 113.24,136.16 113.21,136.14 113.21,132.78 113.85,132.14 113.85,131.06 113.47,130.68 108.58,130.68 106.51,128.61 106.51,121.64 103.72,118.85 103.72,117.82 92.07,106.17 92.07,104.33 87.24,99.5 87.24,96.58 69.46,78.8 69.46,75.37 64.26,70.17 64.26,51.33 66.57,49.02 68,49.02 v2(68.07,49.09)
  BOTTOM w0.102: v1(112.9,134.65) PR674.2
  BOTTOM w0.254: PR675.1 111.96,136.83 PR674.2 113.33,135.89 v2(113.61,136.16) ; v2(68.07,49.09) 68.07,49.02 68.51,48.58 PL605.3
GT2N: length 113
  TOP w0.254: v2(112.2,131.57) 111.94,131.83 PR666.1 v1(110.69,132.45) 109.47,133.67 v2(109.47,134.3)
  IN1 w0.254: v2(57.78,56.16) 58.29,55.65 62.25,55.65 63.43,56.83 63.43,70.42 68.64,75.63 68.64,79.12 86.48,96.96 86.48,99.95 91.24,104.71 91.24,106.42 102.96,118.13 102.96,119.17 105.72,121.93 105.72,129.2 108.1,131.57 v2(112.2,131.57)
  BOTTOM w0.254: PL604.2 58.22,56.67 57.78,56.22 v2(57.78,56.16) ; PR677.2 110.17,135 v2(109.47,134.3)
GT2P: length 108.6
  TOP w0.102: v2(112.84,131.58) v1(112.84,131.07)
  TOP w0.254: PR668.1 113.26,132.51 PR667.2 112.84,132.09 v2(112.84,131.58)
  IN1 w0.254: v2(112.84,131.58) 112.78,131.64 112.78,131.88 112.59,132.07 108.06,132.07 105.34,129.36 105.34,122.09 102.58,119.32 102.58,118.29 90.86,106.58 90.86,104.87 86.1,100.11 86.1,97.12 68.26,79.28 68.26,75.78 63.05,70.58 63.05,57.09 62.12,56.16 v2(58.48,56.16)
  BOTTOM w0.254: PL604.3 58.22,55.84 58.48,56.1 v2(58.48,56.16)
GT_SNUB1:
  vias: v1(70.85,46.65)
GT_SNUB2: length 1.8
  TOP w0.102: v1(59.49,54.58) PR669.2 59.49,52.83
GT_SW1:
  vias: v1(66.81,44.92) v2(66.45,44.48) v2(67.09,44.48)
GT_SW2: length 0.7
  TOP w0.102: v2(55.94,53.53) v1(55.2,53.53)
  vias: v2(55.94,52.9)
H_CATERR#: length 7.3
  BOTTOM w0.076: UC1.D63 102.94,95.06 103.02,95.33 103.02,95.44 103.15,95.9 103.16,95.92 103.16,96.17 103.12,96.26 103.12,96.45 103.15,96.51 103.16,96.54 103.16,96.91 102.98,97.09 102.98,98.8 102.55,99.24 102.55,100.46
  BOTTOM w0.102: RC79.2 102.55,101.5 v1(102.55,100.63) 102.55,100.46
H_CPU_SVIDALRT#: length 13.1
  BOTTOM w0.076: UC1.B63 102.49,96.03 102.4,96.12 102.4,96.2 102.52,96.32 102.52,96.48 102.4,96.59 102.4,98.26 101.82,98.84 101.82,99.26 101.75,99.33 101.59,99.33 101.52,99.26 101.52,98.93 101.44,98.85 101.23,98.85 101.16,98.92 101.16,99.9 101.08,99.97 100.93,99.97 v1(100.92,99.96) 100.85,99.9 100.85,99.16 100.78,99.09 100.62,99.09 100.55,99.16 100.55,100.2 100.47,100.28 100.32,100.28 100.24,100.2 100.24,99.24 100.17,99.16 99.95,99.16 99.87,99.24 99.87,99.87 99.77,99.97 99.19,99.97 99.11,100.05 99.11,100.22 99.2,100.31 99.85,100.31 99.93,100.38
  BOTTOM w0.102: RC153.1 99.93,100.38
H_CPUPWRGD: length 11.9
  BOTTOM w0.102: UC1.A68 99.53,96.68 98.91,97.31 95.09,97.31 94.16,98.23 CC1101.1 93.61,96.85 93.03,96.28 90.05,96.28 T9.1
H_DRAMRST#: length 113.9
  TOP w0.102: RD31.2 RD35.2 CD69.1 116.05,16.84 117.15,17.94 v2(117.47,17.94)
  IN2 w0.089: v2(130.74,77.47) 130.43,77.16 130.43,76.7 131.05,76.08 131.76,76.08
  IN2 w0.127: v2(117.47,17.94) 118.29,17.11 152.27,17.11 155.36,20.2 155.36,21.75 156.56,22.94 156.56,34.79 156.01,35.33 156.01,45.17 153.05,48.13 152.47,48.13 151.69,48.91 151.69,49.78 138.87,62.61 138.87,68.97 131.76,76.08
  BOTTOM w0.089: v2(130.74,77.47) 131.09,77.82 UC1.AT13
H_PROCHOT#: length 321.6
  TOP w0.102: v2(79.08,155.96) 79.18,155.96 80.89,154.24 84.51,154.24 87.12,151.64 87.12,151.32 v2(87.81,150.62) ; PQ721.1 70.16,159.64 v2(69.91,159.38) ; PQ2.6 122.91,170.19 124.07,169.04 v2(124.07,167.89)
  TOP w0.254: v2(154.23,170.62) 154.04,170.81 v1(152.84,170.81) 150.55,170.81 149.4,169.66 PQ3.1
  IN1 w0.127: v2(108.2,98.74) 106.29,96.84 104.51,96.84 100.39,100.96 100.39,102.24 99.12,103.5 97.34,103.5 96.24,102.4 v2(96.19,102.4) ; v2(101.53,121.86) 101.53,123.7 101.67,123.84 101.67,135.37 v2(99.56,137.48) ; v2(161.98,62.67) 162.17,62.67 163.86,64.36 163.86,66.33 166.13,68.61 171.02,68.61 171.63,69.21 175,69.21 176.52,70.74 180.01,70.74 180.23,70.96 180.65,70.96 181.64,71.95 181.64,72.97 181.24,73.38 181.24,73.83 v2(181.6,74.19) ; v2(79.08,155.96) 75.43,155.96 72,159.38 v2(69.91,159.38) ; v2(103.5,157.35) 103.56,157.29 103.56,153.53 105.59,151.5 105.59,150.59 v2(108.77,147.41)
  IN2 w0.127: v2(161.98,62.67) 159.02,65.63 149.96,65.63 148.92,66.67 143.66,66.67 141.2,69.13 141.2,70.75 140.67,71.28 138.7,71.28 133.28,76.7 133.28,76.8 132.15,77.93 132.15,80.06 131.76,80.45 131.44,80.45 131.25,80.64 131.25,80.84 130.83,81.25 129.67,81.25 129.34,80.92 129.34,78.46 129.11,78.23 128.64,78.23 128.45,78.42 128.45,80.23 128.33,80.36 127.79,80.36 127.72,80.43 125.43,80.43 124.83,81.03 124.83,84.54 123.64,85.74 123.64,89.21 124.27,89.84 124.27,91.45 123.83,91.9 111.87,91.9 111.12,92.65 111.12,94.23 108.71,96.65 108.01,96.65 107.63,97.03 107.63,98.17 v2(108.2,98.74) ; v2(103.5,157.35) 103.82,157.67 103.82,159.37 101.96,161.23 101.4,161.23 101.11,161.52 101.11,161.89 101.97,162.75 105.23,162.75 105.61,163.13 115.08,163.13 116.83,164.88 117.61,164.88 119.13,166.39 120.94,166.39 121.64,167.1 123.27,167.1 v2(124.07,167.89) 125.72,167.89 130.93,173.1 149.54,173.1 150.93,171.7 153.16,171.7 v2(154.23,170.62) ; v2(99.56,137.48) 98.67,137.48 95.43,140.72 95.43,143.89 93.91,145.41 93.02,145.41 91.75,146.69 91.75,147.7 88.83,150.62 v2(87.81,150.62)
  BOTTOM w0.102: CE86.1 183.57,74.82 UE6.4 182.23,74.82 v2(181.6,74.19) ; v2(101.53,121.86) 99.51,119.84 99.51,109.23 97.15,106.87 97.15,104.25 RC83.2 96.2,102.41 v2(96.19,102.4) 96.18,102.4 RC84.1 ; v2(99.56,137.48) 101.88,137.48 108.77,144.36 v2(108.77,147.41) 109.71,147.41 PC605.2 111.45,145.67 112.69,145.67 PR678.1 ; PR777.1 104.22,157.16 103.73,157.16 103.54,157.35 v2(103.5,157.35)
H_PROCHOT#_R: length 9.9
  BOTTOM w0.076: 96.07,99.49 96.75,98.81 99.21,98.81 99.65,98.37 100.26,98.37 100.64,97.99 101.06,97.99 101.53,97.52 101.53,97.03 101.33,96.84 101.33,96.58 101.39,96.46 101.39,96.31 101.33,96.12 101.33,95.95 101.42,95.69 UC1.C65
  BOTTOM w0.102: 96.07,99.49 96.04,99.52 v1(96.04,99.82) 96.04,100.59 RC84.2
H_PROCHOT_EC: length 6.2
  TOP w0.102: v2(178.94,74.61) 178.94,74.55 178.36,73.97 UE1.83
  BOTTOM w0.102: UE6.2 179.97,74.17 RE380.2 179.58,73.84 179.34,74.08 179.34,74.08 179.1,74.32 179.1,74.32 178.94,74.49 v2(178.94,74.61) 179.03,74.7 179.03,75.65 179.56,76.19 v1(179.85,76.19)
H_THERMTRIP#: length 6.8
  BOTTOM w0.076: 101.78,100.46 101.78,99.77 102.29,99.26 102.29,99.02 T4946.1 102.77,98.54 102.77,97.06 102.99,96.84 102.99,96.58 102.94,96.46 102.94,96.31 102.99,96.12 102.99,95.95 102.91,95.69 UC1.C63
  BOTTOM w0.102: 101.78,100.46 101.78,100.71 101.77,100.73 RC80.2
H_VCCST_PWRGD: length 112.7
  TOP w0.102: UC16.4 166.25,69.33 168.04,67.54 168.04,64.41 v1(165.54,61.92) v2(164.2,60.58)
  IN1 w0.127: v2(108.39,98.17) 108.26,98.17 106.55,96.46 103.5,96.46 99.5,100.46 99.5,102.49 98.93,103.06 97.66,103.06 96.96,102.36 v2(96.83,102.36)
  IN2 w0.127: v2(164.2,60.58) 162.87,61.91 162.87,64.16 162.05,64.98 160.96,66.07 150.22,66.07 149.18,67.11 143.84,67.11 141.64,69.31 141.64,71.08 140.47,72.25 138.04,72.25 133.5,76.79 133.5,76.89 132.37,78.02 132.37,80.15 132.04,80.48 132.04,81.08 131.65,81.47 129.59,81.47 129.12,81 128.41,81 128.21,81.2 127.25,81.2 126.03,82.42 125.72,82.42 125.22,82.93 125.22,84.47 123.86,85.83 123.86,89.12 124.49,89.75 124.49,91.57 123.93,92.14 112.58,92.14 112.01,92.71 112.01,94.49 111.77,94.73 110.94,94.73 108.71,96.96 108.71,97.85 v2(108.39,98.17)
  BOTTOM w0.102: RC78.1 97.07,102.13 v2(96.83,102.36) 97.07,102.6 97.07,103.06 RC71.1
HDA_BIT_CLK: length 40.3
  BOTTOM w0.076: UC1.AY22 126.3,75.2 126.2,75.09 126.1,74.98 126.03,74.77 126.03,74.65 126.09,74.42 126.09,74.28 126.04,74.16 126.04,73.69 126.37,73.36 126.37,72.51 126.69,72.19 126.69,71.51 126.7,71.5
  BOTTOM w0.102: RC93.2 143.81,50.29 v1(131.29,62.81) 126.7,67.4 126.7,71.5
HDA_CODEC_BITCLK: length 50.6
  TOP w0.102: v2(153.09,49.63) 153.07,49.64 CC27.1
  IN2 w0.127: v2(153.09,49.63) 153.18,49.63 159.19,43.61 159.19,36.98 162.47,33.7 162.47,29.02 162.15,28.7 v2(162.15,27.62)
  BOTTOM w0.102: v2(162.15,27.62) 162.15,27.6 162.25,27.5 165.03,27.5 167.57,24.96 167.57,19.59 168.55,18.61 171.51,18.61 171.82,18.29 v1(173.12,18.29) 174.69,18.29 175.16,17.81 175.16,17.75 EC2709.1 175.99,16.74 176.91,16.74 R2720.1 ; v2(153.09,49.63) 152.47,50.25 RC93.1
HDA_CODEC_RST#: length 50.5
  IN2 w0.127: v2(163.25,28.51) 163.25,29.08 163.18,29.16 163.18,33.71 159.7,37.19 159.7,44.07 v2(155.82,47.94)
  BOTTOM w0.102: RC95.1 152.47,47.29 153.04,46.72 154.86,46.72 155.82,47.69 v2(155.82,47.94) ; v2(163.25,28.51) 165.16,28.51 168.33,25.34 168.33,19.91 168.87,19.37 173.79,19.37 174.75,20.32 v1(176.23,20.32) 176.97,20.32 R6515.1
HDA_CODEC_RST#_R: length 3.2
  BOTTOM w0.102: HDA27.11 180.19,18.09 179.89,18.39 179.89,18.73 178.68,19.94 R6515.2
HDA_CODEC_SDIN0: length 3.5
  BOTTOM w0.102: HDA27.8 179.36,16.89 v1(179.36,16.89) 178.96,17.29 178.96,18.1 R2718.2
HDA_CODEC_SDOUT: length 54.9
  IN2 w0.127: v2(153.09,52.07) 153.09,51.99 152.58,51.49 152.58,49.54 153.1,49.02 153.42,49.02 158.93,43.51 158.93,36.87 162.13,33.68 162.13,29.49 161.66,29.02 v2(161.66,28.51)
  BOTTOM w0.102: v2(153.09,52.07) RC94.1 ; R2719.1 EC2708.1 176.01,15.75 176.01,15.81 175.56,16.26 175.02,16.26 174.83,16.07 v1(174.44,16.07) 174.35,16.07 172.44,17.97 171.76,17.97 171.38,18.35 168.46,18.35 167.32,19.49 167.32,24.83 164.97,27.18 161.22,27.18 160.78,27.62 160.78,28.13 161.16,28.51 v2(161.66,28.51)
HDA_CODEC_SYNC: length 56.8
  IN2 w0.127: v2(153.63,51.75) 153.54,51.67 153.54,49.62 159.44,43.72 159.44,37.09 162.81,33.72 162.81,28.77 162.62,28.57 v2(162.62,28.51)
  BOTTOM w0.102: RC92.1 153.35,53.85 153.6,53.59 153.6,51.97 153.63,51.94 v2(153.63,51.75) ; v2(162.62,28.51) 163.12,28 165.28,28 168.08,25.21 168.08,19.8 168.76,19.11 173.92,19.11 174.9,20.09 175.99,20.09 176.72,19.37 178.49,19.37 179.32,18.54 v1(179.32,18.41) 179.32,18.28 179.91,17.69 HDA27.10
HDA_RST#: length 41.8
  BOTTOM w0.076: UC1.AW22 126.13,75.73 125.91,75.03 125.91,74.95 125.85,74.79 125.85,74.65 125.92,74.43 125.92,74.31 125.89,74.23 125.87,74.2 125.87,73.61 126.21,73.27 126.21,72.44 126.52,72.12 126.52,66.89 126.8,66.61
  BOTTOM w0.102: 126.8,66.61 v1(127.41,66) 143.6,49.81 151.15,49.81 RC95.2
HDA_SDIN0: length 90.4
  IN2 w0.127: v2(150.23,54.03) 152.33,51.93 152.33,49.44 153,48.77 153.31,48.77 158.68,43.4 158.68,36.77 161.25,34.2 161.25,27.79 v2(161.41,27.62)
  BOTTOM w0.076: UC1.BA21 126.87,72.71 127.37,72.21
  BOTTOM w0.102: v2(161.41,27.62) 161.85,28.07 162.62,28.07 162.93,27.75 165.16,27.75 167.82,25.08 167.82,19.69 168.66,18.86 171.76,18.86 171.95,18.67 175.38,18.67 175.57,18.86 176.65,18.86 176.71,18.8 R2718.1 ; 127.37,72.21 127.37,68.05 141.4,54.03 v1(141.74,54.03) v2(150.23,54.03)
HDA_SDOUT: length 39.8
  BOTTOM w0.076: UC1.BB22 126.54,73.82 126.54,72.57 126.89,72.22 126.89,68.71
  BOTTOM w0.102: 126.89,68.71 126.89,67.89 v1(142.83,51.95) 143.6,51.18 RC187.2 RC94.2 RC223.2
HDA_SYNC: length 37.5
  BOTTOM w0.076: UC1.BA22 126.3,74.5 126.71,74.1 126.71,72.64 127.12,72.23 127.12,68.71
  BOTTOM w0.102: RC92.2 151.33,53.62 v1(143.24,53.62) 141.48,53.62 127.12,67.98 127.12,68.71
HDD_DEVSLP: length 109.2
  IN2 w0.127: v2(190.62,39.88) 191.33,40.58 191.33,53.08 189.95,54.46 189.95,58.03 190.56,58.64 190.56,60.78 189.2,62.14 189.2,63.32 187.68,64.84 187.68,68.38 186.94,69.12 186.94,70.08 186.03,70.99 186.03,72.02 184.93,73.11 184.93,74.02 183.48,75.47 183.48,77.81 182.65,78.65 182.65,81.46 180.27,83.84 180.27,86.3 178.81,87.76 178.81,90.49 177.86,91.44 171.44,91.44 170.74,92.14 166.24,92.14 163.32,95.06 162.43,95.06 159.19,98.3 154.79,98.3 153.54,97.05 v2(153.26,97.05)
  BOTTOM w0.102: UC1.J1 139.66,91.85 145.22,97.41 v1(151.1,97.41) 152.9,97.41 v2(153.26,97.05) ; R5605.1 187.56,36.76 188.12,36.76 190.62,39.26 v2(190.62,39.88)
HDD_DEVSLP_R: length 9.4
  BOTTOM w0.102: HDD1.5 190.8,31.63 190.62,31.81 190.62,32.19 187.51,35.31 185.86,35.31 185.71,35.46 R5605.2 185.71,35.92 186.54,36.76 186.75,36.76 v1(186.8,36.81)
HDMI_CLK: length 98.6
  IN2 w0.076: v2(106.09,92.91) 105.85,93.15 105.71,93.15 105.54,93.32 105.54,94.34 104.64,95.24 102.85,95.24 101.87,96.22 98.26,96.22 97.9,95.86 97.52,95.86 97.47,95.82 97.45,95.82
  IN2 w0.127: v2(44.06,76.07) 44.19,76.2 46.58,76.2 48.36,77.98 59.75,77.98 64.2,73.52 69.83,73.52 77.56,81.25 77.56,82.41 90.97,95.82 97.45,95.82
  BOTTOM w0.089: v2(106.09,92.91) 106.29,92.91 UC1.G56
  BOTTOM w0.091: v2(44.06,76.07) 43.86,76.27 43.16,76.27 42.03,77.41 38.79,77.41 36.7,75.31 29.52,75.31 27.48,77.35 25.53,77.35 C5403.1
HDMI_CLK#: length 98.6
  IN2 w0.076: v2(106.09,93.55) 105.85,93.31 105.78,93.31 105.7,93.39 105.7,94.41 104.71,95.4 102.92,95.4 101.94,96.38 98.19,96.38 97.83,96.03 97.52,96.03 97.47,96.07 97.45,96.07
  IN2 w0.127: v2(44.06,76.66) 44.26,76.46 46.48,76.46 48.25,78.23 59.85,78.23 64.31,73.78 69.73,73.78 77.3,81.36 77.3,82.52 90.86,96.07 97.45,96.07
  BOTTOM w0.089: v2(106.09,93.55) 106.3,93.55 UC1.F56
  BOTTOM w0.091: v2(44.06,76.66) 43.86,76.45 43.24,76.45 42.1,77.59 38.72,77.59 36.62,75.49 29.6,75.49 27.55,77.53 25.52,77.53 C5402.1
HDMI_CLK#_R: length 5
  TOP w0.091: v2(22.93,77.84) 22.93,77.72 23.12,77.53 23.39,77.53 23.69,77.23 RN5403.5
  BOTTOM w0.091: C5402.2 23.9,77.52 23.25,77.52 v2(22.93,77.84) 22.62,77.52 22.04,77.52 21.92,77.64 21.51,77.64 21.34,77.82 R5401.1
HDMI_CLK#_R_C: length 18.1
  BOTTOM w0.091: R5401.2 20.42,77.81 20.26,77.64 19.98,77.64 19.81,77.47 19.36,77.47 R5414.1 18.57,77.52 17.76,77.52 v4(17.59,77.35) 16.95,76.71 16.95,75.95 12.25,71.25 12.25,65.98 12.06,65.79 11.88,65.79 JHDMI.12
HDMI_CLK_R: length 5.2
  TOP w0.091: v2(22.93,77.03) 22.93,77.2 23.08,77.35 23.26,77.35 23.88,76.73 RN5403.6
  BOTTOM w0.091: R5402.1 21.34,76.97 21.51,77.14 21.89,77.14 22.09,77.34 22.62,77.34 v2(22.93,77.03) 23.24,77.34 23.91,77.34 C5403.2
HDMI_CLK_R_C: length 17.9
  BOTTOM w0.091: R5402.2 20.42,76.98 20.26,77.14 19.98,77.14 19.83,77.29 19.25,77.29 R5414.2 18.57,77.34 17.89,77.34 17.53,76.99 17.48,76.99 17.13,76.63 17.13,75.87 12.43,71.17 12.43,65.9 12.13,65.61 11.84,65.61 JHDMI.10
HDMI_CRT_DET: length 311.2
  TOP w0.102: v2(183.83,37.91) 184.47,37.91 186.06,39.51 186.06,45.71 v1(180.65,51.12) 180.65,55.53 175.75,60.43 175.75,62.37 173.67,64.44 172.42,64.44 170.38,66.49 170.38,70.32 164.11,76.58 163.54,76.58 158.44,81.68 158.44,81.72 158.08,82.09 158.08,83.85 157.66,84.26 157.66,86.55 155.82,88.39 154.23,88.39 153.03,89.6 RC312.2 149.17,90.49 RC386.2 RC385.2 ; R5517.2 34.22,69 35.36,70.15 35.36,73.02 31.58,76.81 31.58,77.05 31.49,77.13 R5419.1 33.66,77.52 34.37,78.23 36.25,78.23 36.67,77.82 40.22,77.82 41.05,78.64 v2(43.97,78.64)
  IN1 w0.127: v2(162.81,25.46) 165.03,27.69 165.03,31.94 169.41,36.32 177.35,36.32 178.94,37.91 v2(183.83,37.91) ; v2(51.24,51.5) 51.24,51.56 50.48,52.32 50.48,59.2 50.35,59.33 50.35,65.68 48.27,67.75 43.62,67.75 42.47,68.9 42.47,76.64 43.97,78.14 v2(43.97,78.64)
  IN2 w0.127: v2(51.24,51.5) 50.79,51.05 50.79,49.85 53.71,46.93 53.71,40.62 56.06,38.27 56.06,31.73 60.87,26.92 76.64,26.92 81.46,22.1 81.46,18.25 85.36,14.35 99.94,14.35 101.26,13.04 158.68,13.04 161.98,16.34 161.98,20.64 162.81,21.46 v2(162.81,25.46)
HDMI_CRT_N0: length 83.2
  TOP w0.091: v2(40.73,73.7) 40.56,73.53 40.14,73.53 C5526.1
  IN2 w0.076: v2(107,94.18) 106.47,93.65 106.47,92.73 106.28,92.55 104.03,92.55 103.63,92.94 103.02,92.94 102.61,92.53 102.14,92.53 101.91,92.76 101.91,94.44 101.54,94.81 98.84,94.81 98.11,94.08 97.21,94.08 97.17,94.13 97.15,94.13
  IN2 w0.127: 97.15,94.13 92.26,94.13 90.02,91.89 88.71,91.89 78.72,81.9 78.72,80.74 70.37,72.39 53.25,72.39 52.62,73.03 44.19,73.03 43.68,73.54 40.89,73.54 v2(40.73,73.7)
  BOTTOM w0.089: v2(107,94.18) 107.22,93.96 UC1.E55
  BOTTOM w0.091: v2(40.73,73.7) 40.55,73.52 40.15,73.52 C5526.1
HDMI_CRT_N1: length 80.5
  TOP w0.091: C5525.1 40.08,75.49 40.53,75.49 v2(40.71,75.67)
  IN2 w0.076: 97.32,95.29 97.34,95.29 97.38,95.25 97.9,95.25 98.56,95.91 101.53,95.91 102.62,94.82 104.5,94.82 104.8,94.51 104.8,93.99 104.85,93.94 104.92,93.94 v2(105.17,94.18)
  IN2 w0.127: 97.32,95.29 96.44,95.29 96.11,94.96 92,94.96 89.71,92.67 88.47,92.67 77.99,82.19 77.99,81.05 70.04,73.09 53.87,73.09 53.44,73.53 53.44,73.99 52.9,74.53 51.33,74.53 50.73,73.93 44.6,73.93 43.03,75.5 40.87,75.5 v2(40.71,75.67)
  BOTTOM w0.089: v2(105.17,94.18) 105.4,93.96 UC1.E58
  BOTTOM w0.091: v2(40.71,75.67) 40.53,75.49 40.08,75.49 C5525.1
HDMI_CRT_P0: length 83.3
  TOP w0.091: v2(40.73,73.11) 40.5,73.34 40.2,73.34 C5529.1
  IN2 w0.076: v2(107,93.55) 106.86,93.69 106.74,93.69 106.63,93.58 106.63,92.66 106.35,92.38 103.96,92.38 103.57,92.77 103.09,92.77 102.68,92.37 102.07,92.37 101.74,92.69 101.74,94.37 101.47,94.64 98.91,94.64 98.18,93.91 97.21,93.91 97.17,93.87 97.15,93.87
  IN2 w0.127: v2(40.73,73.11) 40.89,73.28 43.57,73.28 44.08,72.77 52.51,72.77 53.15,72.14 70.48,72.14 78.98,80.64 78.98,81.8 88.81,91.63 90.13,91.63 92.36,93.87 97.15,93.87
  BOTTOM w0.089: v2(107,93.55) 107.24,93.31 UC1.F55
  BOTTOM w0.091: v2(40.73,73.11) 40.5,73.34 40.2,73.34 C5529.1
HDMI_CRT_P1: length 80.6
  TOP w0.091: C5530.1 40.14,75.31 40.48,75.31 v2(40.71,75.08)
  IN2 w0.076: 97.32,95.04 97.34,95.04 97.38,95.08 97.97,95.08 98.63,95.74 101.46,95.74 102.55,94.65 104.43,94.65 104.64,94.45 104.64,93.92 104.78,93.77 104.95,93.77 v2(105.17,93.55)
  IN2 w0.127: v2(40.71,75.08) 40.87,75.25 42.92,75.25 44.5,73.67 50.84,73.67 51.44,74.27 52.79,74.27 53.18,73.88 53.18,73.42 53.77,72.83 70.14,72.83 78.25,80.94 78.25,82.08 88.58,92.41 89.81,92.41 92.11,94.71 96.22,94.71 96.55,95.04 97.32,95.04
  BOTTOM w0.089: v2(105.17,93.55) 105.41,93.31 UC1.F58
  BOTTOM w0.091: C5530.1 40.14,75.31 40.48,75.31 v2(40.71,75.08)
HDMI_DATA0: length 101.1
  IN2 w0.076: v2(107.91,92.91) 107.68,93.15 107.61,93.15 107.53,93.07 107.53,92.47 106.88,91.82 101.91,91.82 101.69,91.6 99.33,91.6 99.29,91.56 99.27,91.56
  IN2 w0.127: v2(42.98,70.35) 43.12,70.48 52.55,70.48 53.51,71.44 70.86,71.44 79.67,80.25 79.67,81.47 89.05,90.85 90.54,90.85 91.25,91.56 99.27,91.56
  BOTTOM w0.089: UC1.G53 108.17,92.66 v2(107.91,92.91)
  BOTTOM w0.091: v2(42.98,70.35) 42.79,70.54 42.79,70.55 42.35,70.55 41.53,71.36 41.53,76.19 40.95,76.77 38.98,76.77 36.89,74.68 28.06,74.68 26.94,75.8 26.45,75.8 26.01,75.36 25.5,75.36 C5405.1
HDMI_DATA0#: length 101.1
  IN2 w0.076: 99.27,91.81 99.29,91.81 99.33,91.77 101.62,91.77 101.84,91.99 106.82,91.99 107.37,92.54 107.37,93.14 107.54,93.31 107.68,93.31 v2(107.91,93.55)
  IN2 w0.127: v2(42.98,70.93) 43.17,70.74 52.45,70.74 53.4,71.69 70.75,71.69 79.42,80.36 79.42,81.58 88.94,91.11 90.44,91.11 91.14,91.81 99.27,91.81
  BOTTOM w0.089: v2(107.91,93.55) 108.15,93.31 UC1.F53
  BOTTOM w0.091: C5404.1 25.55,75.54 25.93,75.54 26.41,76.01 v4(26.7,76.01) 26.98,76.01 28.14,74.86 36.81,74.86 38.91,76.95 41.02,76.95 41.71,76.26 41.71,71.44 42.42,70.73 42.78,70.73 v2(42.98,70.93)
HDMI_DATA0#_R: length 4.8
  TOP w0.091: RN5403.7 23.97,76.23 23.36,75.63 23.1,75.63 v2(22.92,75.81)
  BOTTOM w0.091: R5403.1 21.48,75.85 21.64,75.69 22.1,75.69 22.24,75.55 22.67,75.55 v2(22.92,75.81) 23.16,75.56 23.91,75.56 C5404.2
HDMI_DATA0#_R_C: length 19.5
  TOP w0.091: JHDMI.9 10.29,64.33 10.47,64.33 10.66,64.52 10.66,70.17 16.06,75.56 16.09,75.56 16.1,75.55 17.38,75.55 v2(17.7,75.87)
  BOTTOM w0.091: v2(17.7,75.87) 18.01,75.55 18.57,75.55 R5416.1 19.3,75.56 20.01,75.56 20.13,75.69 20.39,75.69 20.56,75.86 R5403.2
HDMI_DATA0_R: length 4.9
  TOP w0.091: v2(22.92,75.08) 23.29,75.45 23.44,75.45 23.72,75.73 RN5403.8
  BOTTOM w0.091: R5404.1 21.48,75.03 21.64,75.19 22.03,75.19 22.22,75.37 22.62,75.37 v2(22.92,75.08) 23.22,75.38 23.9,75.38 C5405.2
HDMI_DATA0_R_C: length 19.5
  TOP w0.091: JHDMI.7 10.32,64.15 10.55,64.15 10.84,64.44 10.84,70.09 16.12,75.37 17.39,75.37 v2(17.7,75.07)
  BOTTOM w0.091: R5404.2 20.56,75.01 20.39,75.19 20.13,75.19 19.94,75.38 19.31,75.38 R5416.2 18.57,75.37 18.01,75.37 v2(17.7,75.07)
HDMI_DATA1: length 14.8
  BOTTOM w0.091: C5406.1 25.53,73.42 26.22,73.42 26.25,73.38 26.89,73.38 27.55,74.04 v4(36.73,74.04) 37.08,74.04 38.31,75.28 38.5,75.28 RE40.1
HDMI_DATA1#: length 14.7
  BOTTOM w0.091: RE39.1 38.48,75.46 38.24,75.46 37.04,74.26 36.44,74.26 36.41,74.22 27.48,74.22 26.85,73.6 v4(26.55,73.6) 25.52,73.6 C5409.1
HDMI_DATA1#_R: length 4.8
  TOP w0.091: v2(22.93,73.92) 23.26,73.6 23.57,73.6 23.74,73.42 RN5402.5
  BOTTOM w0.091: R5407.1 21.46,73.96 21.64,73.78 22.1,73.78 22.29,73.6 22.61,73.6 v2(22.93,73.92) 23.27,73.59 23.9,73.59 C5409.2
HDMI_DATA1#_R_C: length 18.4
  BOTTOM w0.091: R5407.2 20.55,73.95 20.39,73.78 20.13,73.78 19.96,73.61 19.29,73.61 R5417.1 18.57,73.59 17.85,73.59 17.81,73.62 17.23,73.62 17.19,73.59 15.79,73.59 12.89,70.69 12.89,63.51 12.19,62.8 11.87,62.8 JHDMI.6
HDMI_DATA1_R: length 4.9
  TOP w0.091: v2(22.93,73.11) 23.23,73.42 23.45,73.42 23.94,72.92 RN5402.6
  BOTTOM w0.091: R5408.1 21.46,73.11 21.64,73.28 22.16,73.28 22.28,73.41 22.64,73.41 v2(22.93,73.11) 23.22,73.41 23.91,73.41 C5406.2
HDMI_DATA1_R_C: length 18.4
  BOTTOM w0.091: JHDMI.4 11.85,62.62 12.26,62.62 13.07,63.43 13.07,70.61 15.87,73.41 v4(17.52,73.41) 18.57,73.41 R5417.2 19.29,73.39 20.02,73.39 20.13,73.28 20.39,73.28 20.55,73.12 R5408.2
HDMI_DATA2: length 15
  BOTTOM w0.091: C5408.1 25.33,71.5 26.65,71.5 26.69,71.47 27.38,71.47 29.26,73.34 v4(32.84,73.34) 38.4,73.34 RE42.1
HDMI_DATA2#: length 15
  BOTTOM w0.091: C5407.1 25.34,71.68 v4(26.98,71.68) 27.34,71.68 29.18,73.52 32.51,73.52 32.54,73.56 33.13,73.56 33.16,73.52 38.45,73.52 RE41.1
HDMI_DATA2#_R: length 6.9
  TOP w0.091: RN5402.7 23.78,72.42 23.33,71.98 v2(23.33,71.7)
  BOTTOM w0.091: R5405.1 20.46,68.9 20.63,69.08 20.63,69.6 20.77,69.73 20.77,70.35 21.23,70.81 21.28,70.81 21.95,71.49 v4(22.27,71.49) 23.13,71.49 v2(23.33,71.7) 23.75,71.7 24.07,72.02 C5407.2
HDMI_DATA2#_R_C: length 19.1
  BOTTOM w0.091: R5405.2 20.47,67.99 20.63,67.83 20.63,67.33 20.76,67.21 20.76,66.76 R5415.1 20.83,65.94 20.83,65.73 20.04,64.94 19.99,64.94 19.57,64.52 19.57,64.47 19.17,64.07 v4(19.17,62.28) 19.17,61.91 16.09,58.83 12.92,58.83 10.5,61.25 10.18,61.25 9.9,61.53 JHDMI.3
HDMI_DATA2_R: length 6.7
  TOP w0.091: RN5402.8 23.91,71.92 23.74,71.75 23.74,71.4 v2(23.44,71.11)
  BOTTOM w0.091: R5406.1 21.31,68.9 21.13,69.08 21.13,69.54 20.95,69.73 20.95,70.23 v4(21.17,70.45) 21.99,71.28 22.56,71.28 22.6,71.31 23.17,71.31 23.37,71.11 v2(23.44,71.11) 23.44,71.22 23.68,71.46 23.76,71.46 C5408.2
HDMI_DATA2_R_C: length 19.2
  BOTTOM w0.091: R5406.2 21.29,67.99 21.13,67.83 21.13,67.37 20.94,67.17 20.94,66.75 R5415.2 21.01,66.1 21.01,65.66 v4(19.93,64.58) 19.35,64 19.35,62.61 19.39,62.58 19.39,61.87 16.16,58.65 12.84,58.65 10.43,61.07 10.25,61.07 JHDMI.1
HDMI_HPD_B: length 11.3
  TOP w0.102: Q5401.2 v2(28.07,78.03)
  BOTTOM w0.102: v2(28.07,78.03) 26.95,79.15 v1(25.51,79.15) R5411.2
HDMI_HPD_E: length 4.2
  TOP w0.102: Q5401.3 30.46,79.96 31.06,79.36 R5412.1 R5419.2 v1(32.75,78.44)
HDMI_PLL_GND:
  vias: v1(25.41,74.57)
HOST_DEBUG_TX: length 95.9
  TOP w0.102: v2(169.31,53.21) R5812.1 R5806.1 ; UE1.81 178.39,74.77 178.75,75.12 180.52,75.12 181.26,75.86 181.32,75.86 183.3,75.86 184.53,77.09 185.67,77.09 186.62,78.04 187,78.04 187.28,77.76 v2(187.28,77.09) 188.52,77.09 190.75,79.31 190.75,80.26 190.24,80.77 v2(189.99,80.77)
  IN1 w0.127: v2(169.31,53.21) 168.99,52.9 v2(166.81,52.9)
  IN2 w0.127: v2(187.28,77.09) 187.57,77.09 188.84,75.82 188.84,73.13 188.33,72.62 188.33,70.65 189.07,69.91 189.07,68.5 190.21,67.36 190.21,65.15 191.28,64.08 191.28,63.08 192.11,62.26 192.11,58.43 v2(192.95,57.58)
  BOTTOM w0.102: v2(166.81,52.9) 166.81,59.82 169.63,62.64 169.63,63.21 169.98,63.56 169.98,64.96 170.52,65.49 174.97,65.49 183.33,57.14 189.87,57.14 190.3,56.71 192.08,56.71 v2(192.95,57.58) ; v2(189.99,80.77) 189.99,81.6 189.24,82.35 RE73.2 190.57,83.82 v1(191.7,83.82) 192.4,84.52 192.4,84.71 193.54,85.85 193.54,86.3 193.23,86.61 JDEG1.8
HPD_HDMI_CON: length 14.7
  BOTTOM w0.102: JHDMI.19 16.28,76.1 16.28,78.33 R5410.1 17.96,79.14 R5411.1 17.97,79.87 v1(18.47,80.37)
I2C_SCL_TP: length 278.2
  TOP w0.102: v2(174.09,54.93) 168.59,54.93 167.09,53.43 164.53,53.43 159.49,48.39 157.79,48.39 157.26,47.85 157.26,43.97 158.63,42.59 158.63,36.96 159.89,35.71 159.89,27.96 v2(159.08,27.15) ; v2(49.16,74.82) 49.16,74.31 v1(48.92,74.07) 48.58,73.74 RZ21.2 47.61,73.53 45.71,73.53 45.44,73.26 Q6501.1
  IN1 w0.127: v2(52.06,52.32) 52.32,52.32 53.02,53.02 53.02,59.5 52.76,59.75 52.76,65.99 51.24,67.52 51.24,72.05 49.16,74.13 v2(49.16,74.82)
  IN2 w0.127: v2(52.06,52.32) 52.06,52.13 52.91,51.29 52.91,49.9 55.24,47.57 55.24,41.4 57.46,39.18 57.46,32.58 61.33,28.7 77.27,28.7 82.86,23.11 82.86,19.05 84.81,17.1 111.45,17.1 112.07,16.48 152.54,16.48 155.56,19.5 156.51,19.5 159.08,22.07 v2(159.08,27.15) ; v2(174.09,54.93) 174.24,54.93 174.6,55.29 174.6,55.88 174.43,56.05 174.43,59.82 173.92,60.32 173.92,66.29 174.81,67.18 174.81,68.33 172.12,71.01 171.62,71.01 169.98,72.65 169.98,79.63 165.61,84.01 162.36,84.01 160.97,85.41 160.2,85.41 159.38,86.23 156.08,86.23 155.48,85.64 152.13,85.64 151.96,85.47 149.92,85.47 149.15,86.23 142.38,86.23 141.81,86.8 140.22,86.8 139.9,87.12 137.62,87.12 136.91,87.83 136.27,87.83 v2(136.04,88.06)
  BOTTOM w0.089: UC1.U6 v2(136.04,88.06)
I2C_SCL_TP_Q: length 20.7
  TOP w0.102: R6506.2 61.22,74.42 v2(61.4,74.42) 61.59,74.61 TPAD1.3 ; Q6501.6 v2(45.44,75.44) 45.44,75.69 v1(45.83,76.07)
  IN2 w0.127: v2(61.4,74.42) 61.4,74.61 59.82,76.19 47.8,76.19 47.05,75.44 v2(45.44,75.44)
I2C_SDA_TP: length 278.5
  TOP w0.102: v2(159.06,27.81) 159.4,28.16 159.4,35.51 158.15,36.76 158.15,39 156.77,40.38 v1(156.77,43.45) 156.77,48.2 157.45,48.87 159.29,48.87 164.33,53.91 166.89,53.91 168.54,55.56 v2(174.09,55.56) ; v2(48.52,74.82) 48.3,74.6 RZ20.2 47.25,74.04 46.86,74.04 46.74,74.15 Q6501.4
  IN1 w0.127: v2(52.06,51.5) 52.06,51.56 51.62,52.01 51.62,52.64 51.87,52.9 52.22,52.9 52.51,53.19 52.51,59.29 52.25,59.54 52.25,66.14 50.98,67.41 50.98,71.95 48.57,74.36 48.57,74.77 v2(48.52,74.82)
  IN2 w0.127: v2(159.06,27.81) 159.63,27.24 159.63,21.91 156.72,18.99 155.77,18.99 152.75,15.97 111.86,15.97 111.24,16.59 84.92,16.59 82.61,18.9 82.61,22.99 77.15,28.45 61.21,28.45 57.21,32.45 57.21,39.01 54.98,41.23 54.98,47.35 52.54,49.79 52.54,51.02 v2(52.06,51.5) ; v2(135.4,88.09) 135.89,87.61 136.78,87.61 137.77,86.61 139.69,86.61 140.02,86.28 140.66,86.28 141.6,85.34 142.74,85.34 143.38,85.98 149.03,85.98 149.87,85.14 153.24,85.14 153.61,84.77 155.07,84.77 156.28,85.98 159.25,85.98 160.08,85.15 160.84,85.15 162.24,83.76 165.48,83.76 169.73,79.51 169.73,72.52 171.89,70.36 172.33,70.36 174.55,68.14 174.55,67.31 173.67,66.42 173.67,60.13 174.09,59.71 v2(174.09,55.56)
  BOTTOM w0.089: UC1.U7 v2(135.4,88.09)
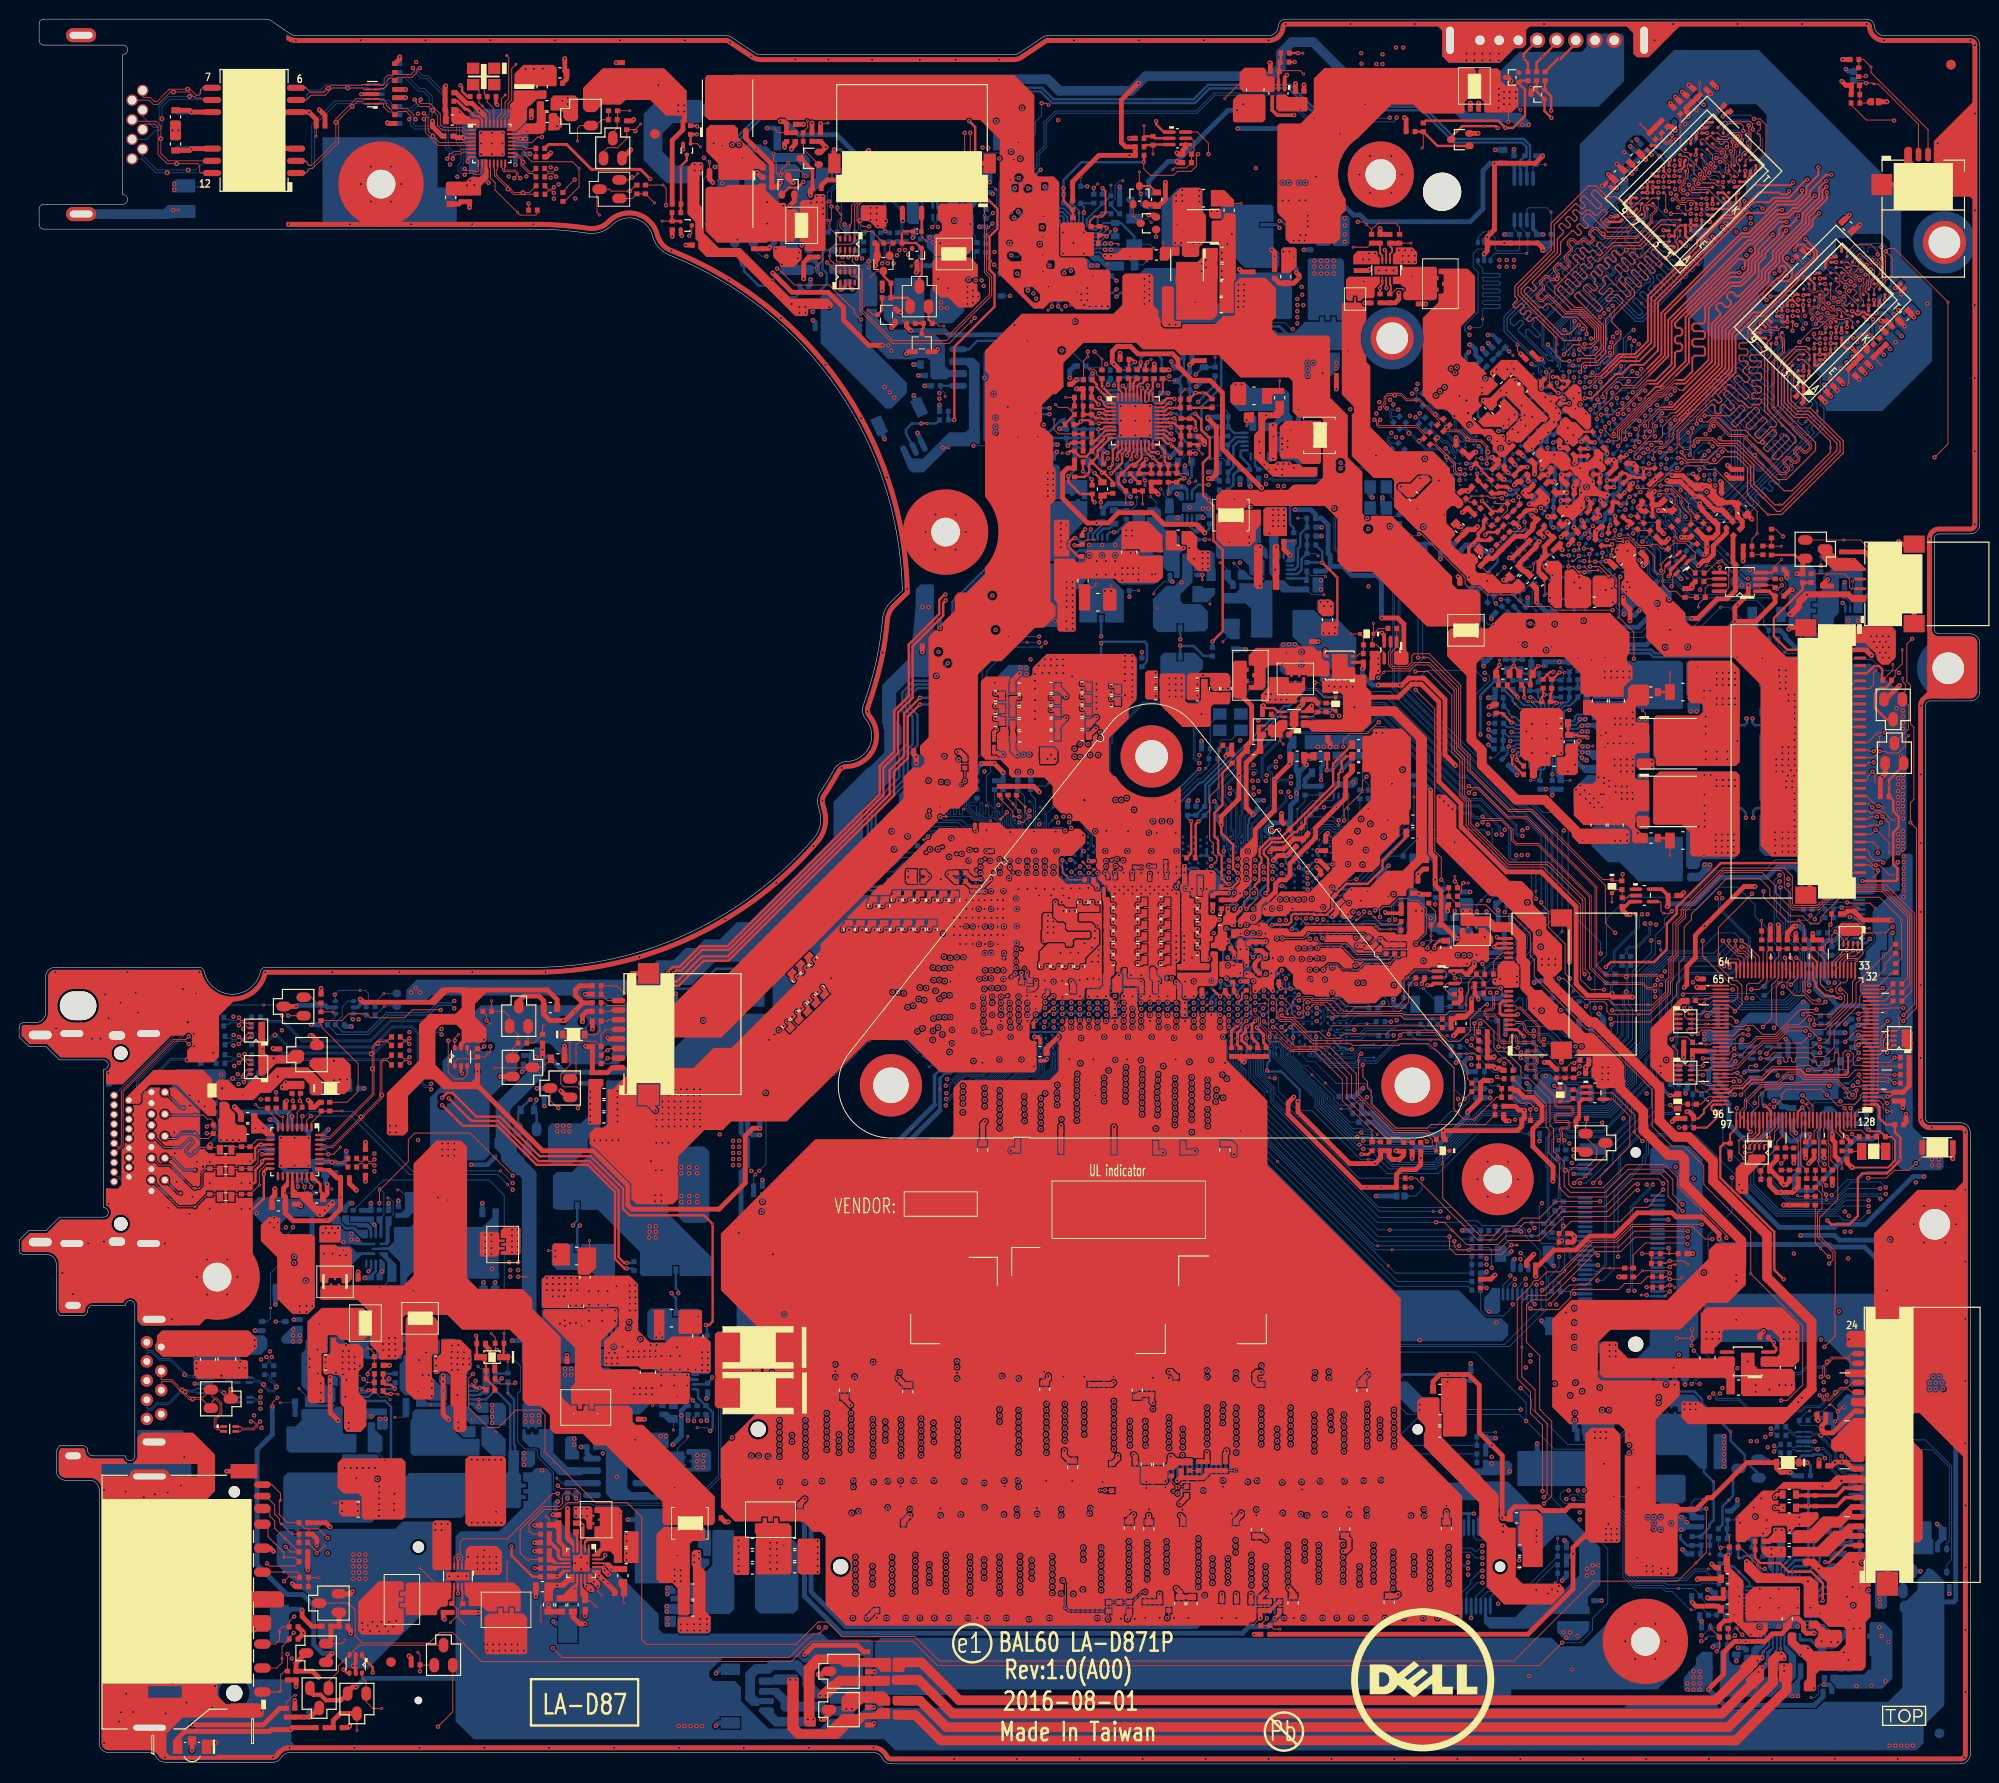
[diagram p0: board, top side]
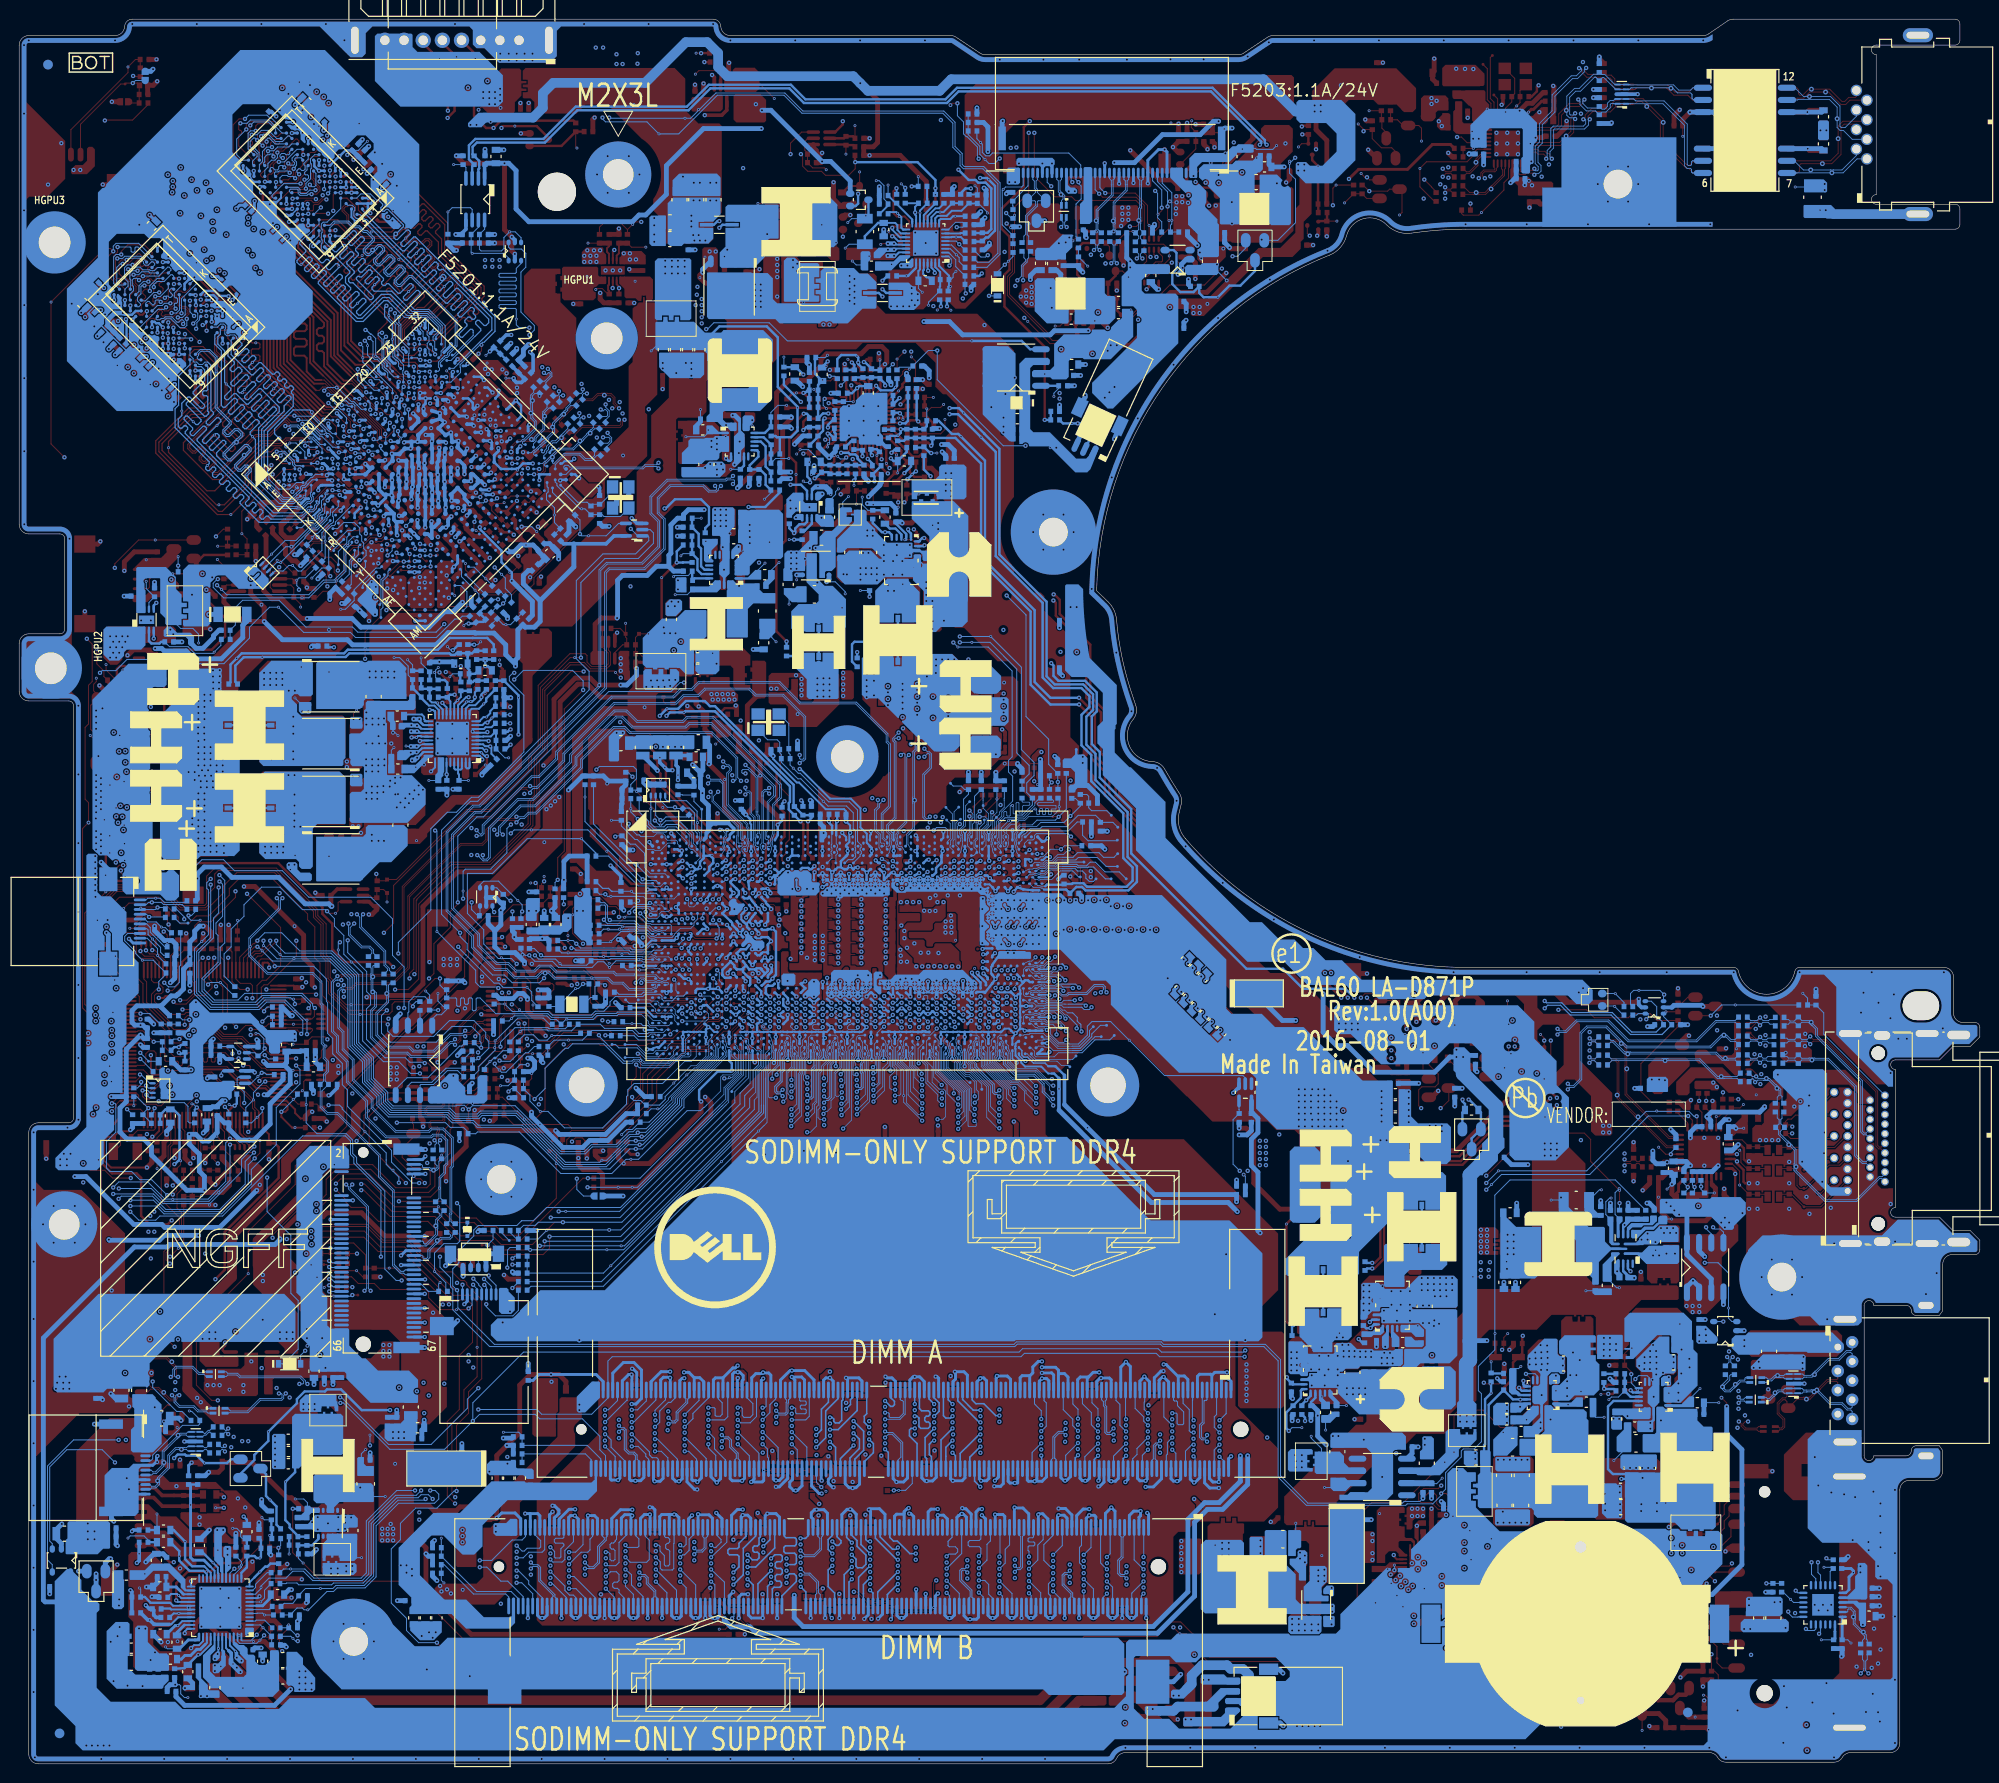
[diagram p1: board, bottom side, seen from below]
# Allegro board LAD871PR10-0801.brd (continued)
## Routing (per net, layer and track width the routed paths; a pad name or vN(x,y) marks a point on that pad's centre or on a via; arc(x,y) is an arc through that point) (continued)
I2C_SDA_TP_Q: length 26.9
  TOP w0.102: R6508.2 60.82,73.02 v2(61.4,73.6) 61.41,73.61 TPAD1.2 ; Q6501.3 46.74,71.9 46.28,71.44 v1(45.45,71.44) 44.76,72.12 v2(44.76,75.44)
  IN2 w0.127: v2(44.76,75.44) 45.21,74.99 47.05,74.99 47.99,75.93 59.06,75.93 v2(61.4,73.6)
I_ADP: length 245.2
  TOP w0.102: RE399.2 184.26,63.04 v2(183.83,62.61)
  IN1 w0.127: v2(185.15,53.21) 185.34,53.4 192.12,53.4 194.61,55.89 194.61,57.45 196.05,58.9 196.05,61.26 196.72,61.93 196.72,65.46 194.86,67.31 194.52,67.31 193.95,67.88 193.95,68.09 193.95,75.07 194.46,75.57 194.46,76.71 194.77,77.03 195.26,77.03 195.38,77.15 195.38,78.97 196.02,79.61 196.02,84.79 191.81,89 190.71,89 190.39,88.68 188.68,88.68 187.95,89.41 185.84,89.41 185.08,88.65 182.68,88.65 181.86,87.82 174.77,87.82 174.12,88.46 172.3,88.46 170.66,90.11 166.3,90.11 159.94,96.47 159.94,97.49 156.97,100.46 154.95,100.46 149.54,105.87 149.54,119.19 148.16,120.57 148.16,124.63 148.71,125.18 148.71,126.1 147.71,127.1 147.71,141.44 146.87,142.28 146.87,145.5 148.52,147.15 148.52,158.18 145.73,160.97 145.73,172.4 141.6,176.53 v2(141.6,177.29)
  IN2 w0.127: v2(185.15,53.21) 184.65,53.71 184.65,61.4 183.83,62.23 v2(183.83,62.61) ; v2(141.6,177.29) 141.13,176.82 131.88,176.82 131.65,176.59 115.06,176.59 113.53,175.07 105.81,175.07 102.67,171.94 102.67,167.97 104.3,166.35 v2(104.3,165.4)
  BOTTOM w0.254: v2(104.3,165.4) 103.57,165.4 v1(103.39,165.22) 102.75,164.58 102.75,159.91 103.46,159.2 103.7,159.2 PC748.1 104.12,158.78 PR774.1
I_ADP_R: length 3.8
  TOP w0.102: UE1.110 184.35,65.84 184.26,65.75 RE399.1 CE87.1
I_BATT: length 240
  TOP w0.102: v2(188.81,52.9) v1(187.94,53.76) 187.38,54.33 RE400.2
  IN1 w0.127: v2(188.81,52.9) 189.07,53.15 192.22,53.15 194.95,55.87 194.95,57.41 196.3,58.77 196.3,61.16 196.97,61.83 196.97,65.56 194.97,67.56 194.62,67.56 194.2,67.98 194.2,74.96 194.73,75.48 195.24,75.48 195.64,75.88 195.64,78.86 196.28,79.5 196.28,84.89 190.9,90.27 186.34,90.27 184.97,88.9 182.49,88.9 181.67,88.07 174.87,88.07 173.81,89.13 172.99,89.13 171.76,90.36 166.43,90.36 160.19,96.6 160.19,97.59 157.07,100.71 155.06,100.71 149.8,105.97 149.8,119.3 148.42,120.68 148.42,124.53 148.96,125.07 148.96,126.2 148.27,126.9 148.27,132.68 148.56,132.97 148.56,133.97 148.06,134.46 148.06,141.45 147.12,142.39 147.12,145.39 148.77,147.05 148.77,158.28 145.98,161.08 145.98,172.59 142.23,176.34 v2(142.23,177.29)
  IN2 w0.127: v2(106.56,166.27) 104.74,166.27 102.99,168.01 102.99,171.89 105.85,174.75 113.59,174.75 115.12,176.28 131.69,176.28 131.99,176.57 141.51,176.57 v2(142.23,177.29)
  BOTTOM w0.254: v2(106.56,166.27) 105.49,165.2 104.78,165.2 104.5,164.92 103.73,164.92 103.13,164.32 103.13,160.07 103.51,159.69 PC749.2 104.1,159.66 PR775.1
I_BATT_R_C: length 2.8
  TOP w0.102: CE88.1 185.59,59.19 v1(185.5,59.28) ; CE88.1 RE400.1 ; CE88.1 RE443.1
I_SYS: length 170
  TOP w0.102: PR682.1 111.04,146.32 v1(111.47,146.75) 111.49,146.76 v2(111.49,147.29)
  IN1 w0.127: v2(106.74,160.27) 107.05,159.96 107.05,155.36 109.59,152.82 109.59,149.19 v2(111.49,147.29) 113.01,148.82 123.12,148.82 123.59,148.82 125.24,147.16 125.24,143.28 126.96,141.57 126.96,139.74 127.6,139.09 132.79,139.09 134.26,137.62 134.26,127.55 135.44,126.36 136.54,126.36 140.94,121.97 140.94,117.12 142.48,115.58 142.48,110.82 143.02,110.28 143.02,101.37 147.9,96.48 151.76,96.48 152.48,96.48 153.66,95.3 157.61,95.3 162.5,90.41 162.5,89.46 164.36,87.6 166.88,87.6 168.17,86.31 171.22,86.31 171.35,86.18 173.17,86.18 174.2,85.15 178.68,85.15 179.32,84.52 182.94,84.52 184.02,83.44 189.92,83.44 192.06,81.31 192.06,79.29 190.93,78.16 190.93,75.01 190.34,74.42 190.34,72.32 190,71.98 v2(190,69.11)
  BOTTOM w0.102: v2(106.74,160.27) 106.12,160.27 PR727.1 106.11,160.78 106.86,160.78 107.62,160.02 PU703.8 ; RE442.1 186.8,66.85 186.94,66.99 186.94,68.58 187.32,68.96 189.85,68.96 v2(190,69.11)
ICSP_CLK: length 33.9
  TOP w0.102: v2(188.85,70.72) 188.73,70.84 184.12,70.84 183.67,70.38 182.26,70.38 181.48,69.6 181.48,68.64 180.75,67.91 UE1.101
  IN2 w0.127: v2(188.85,70.72) 188.59,70.99 188.59,72.52 189.1,73.03 189.1,75.92 186.83,78.19 186.83,80.05 187.19,80.41 187.19,82.99 187.93,83.73 187.93,86.77 187.78,86.91 187.78,88.36 187.54,88.61 187.01,88.61 v2(186.88,88.48)
  BOTTOM w0.102: RE420.1 186.14,88.93 186.58,88.48 v2(186.88,88.48) 186.88,88.24 186.62,87.99 v1(185.67,87.99)
ICSP_CLR: length 25.9
  TOP w0.102: v2(186.81,76.01) 185.97,75.17 181.98,75.17 181.47,74.66 181.37,74.66 179.26,72.56 178.88,72.56 178.7,72.37 UE1.87
  IN2 w0.127: v2(187.33,88.1) 187.23,88 187.23,87.11 187.55,86.79 187.55,84.18 186.11,82.74 186.11,80.58 185.69,80.16 185.69,77.73 186.81,76.61 v2(186.81,76.01)
  BOTTOM w0.102: v2(187.33,88.1) 187.33,88.34 188.16,89.17 RE421.1
ICSP_DAT: length 57
  TOP w0.102: UE1.102 181.15,65.78 180.84,65.47 179.89,65.47 v1(179.43,65.01) 179.43,63.7 v2(179.98,63.15)
  IN2 w0.127: v2(189.41,81.47) 189.54,81.34 189.54,76.56 189.86,76.24 189.86,70.59 190.34,70.1 190.34,69.4 190.91,68.83 191.34,68.83 193.07,67.11 193.43,67.11 194.27,66.28 194.46,66.28 195.95,64.78 195.95,62.76 194.5,61.31 194.14,61.31 192.95,60.12 v2(192.95,58.79)
  BOTTOM w0.102: RE423.1 187.7,86.64 187.7,83.31 187.84,83.17 187.84,81.52 188.32,81.04 188.96,81.04 188.97,81.05 188.99,81.05 v2(189.41,81.47) ; v2(192.95,58.79) 190.54,58.79 189.34,57.59 183.52,57.59 180.65,60.46 180.65,62.48 v2(179.98,63.15)
ILMT_+1.5VGPU: length 5.2
  BOTTOM w0.254: PR1406.2 126.11,133.83 PR1407.1 126.68,135.3 126.68,137.41 127.17,137.91 PU1400.13
ILMT_+1VALW: length 7.3
  BOTTOM w0.102: PR304.2 v1(133.39,129.92)
  BOTTOM w0.254: PU300.13 133.05,124.55 133.41,124.9 133.41,126.75 133.66,127 133.66,128.29 PR305.1 134.36,129.9 PR304.2
IMON_IA: length 2.9
  TOP w0.203: PU602.14 115.85,136.96 115.83,136.94 115.83,136.91 115.58,136.65 v2(115.58,136.49)
  BOTTOM w0.254: v2(115.58,136.49) 115.69,136.6 PC625.2 115.06,137.11 PR629.2
IMON_VGA: length 3.7
  BOTTOM w0.203: PU1100.10 156.54,108.74 156.11,109.18 v1(155.8,109.18) 155.4,109.58 155.4,109.8 154.9,110.31 PC1117.2 154.87,111.14 PR1117.2
IMON_VSA: length 5
  TOP w0.203: PU602.23 119.68,139.08 120.01,138.75 v2(120.2,138.75)
  BOTTOM w0.102: v1(120.21,137.35) 120.21,137.59 120,137.81 120,138.27 120.2,138.47 v2(120.2,138.75)
  BOTTOM w0.254: v2(120.2,138.75) 120.02,138.75 PR651.1 119.37,138.4 119.37,138.75 119.5,138.87 PC643.1
IMVP_VR_ON: length 165.9
  TOP w0.102: v2(112.19,147.29) v1(112.96,146.52) PR658.1 ; RC345.2 161.91,73.09 v2(162.24,73.09) 162.55,73.41 CC10.1
  TOP w0.254: PR655.1 110.9,128.45 v2(111.21,128.76)
  IN1 w0.127: v2(170.27,85.89) 170.11,86.06 168.07,86.06 166.78,87.35 164.25,87.35 162.25,89.35 162.25,90.28 158.4,94.13 154.47,94.13 152.37,96.23 151.86,96.23 147.8,96.23 142.76,101.27 142.76,110.18 142.22,110.72 142.22,115.48 140.68,117.01 140.68,121.86 136.44,126.11 135.31,126.11 133.98,127.44 133.98,133.62 133.44,134.15 133.44,138.07 132.68,138.84 127.31,138.84 126.7,139.45 126.7,141.46 124.99,143.18 124.99,147.06 123.48,148.56 123.27,148.56 113.46,148.56 v2(112.19,147.29)
  IN2 w0.127: v2(111.21,128.76) 111.21,128.6 111.61,128.2 113.08,128.2 114.99,130.11 117.92,130.11 119.65,131.84 119.65,134.36 121.12,135.83 122.55,135.83 123.32,136.6 123.32,137.08 122.79,137.6 122.29,137.6 121.21,138.68 121.21,144.81 120.21,145.82 119.4,145.82 119.13,145.56 115.74,145.56 114,147.29 v2(112.19,147.29)
  BOTTOM w0.102: v2(170.27,85.89) 170.27,84.62 168.3,82.64 168.3,80.54 167.89,80.13 167.89,79.17 168.31,78.75 168.31,75.56 166.39,73.64 164.26,73.64 163.79,73.18 162.32,73.18 v2(162.24,73.09)
INT_TP#: length 10.1
  TOP w0.102: Q6204.3 58.1,72.06 v1(58.1,74.17) 58.1,75.01 58.46,75.37 60.14,75.37 R6203.1 60.71,76.07 61.25,76.61 TPAD1.5
INTRUDER#: length 22.2
  TOP w0.076: v2(128.95,78.63) 128.95,78.27 129.49,77.72 129.49,77.27 130.53,76.23 130.59,76.23 v1(131.1,75.72) 131.4,75.72 132.62,74.49
  TOP w0.102: 132.62,74.49 135.61,74.49 138.52,71.58 138.52,69.37 142.91,64.97 RC69.1
  BOTTOM w0.089: UC1.AP16 128.96,78.75 v2(128.95,78.63)
IR_CAM_DETECT#: length 157.3
  IN1 w0.127: v2(133.34,151.51) 134.11,150.75 134.11,150.05 136.2,147.95 136.2,140.27 135.38,139.45 135.38,127.95 135.88,127.44 138.11,127.44 142.61,122.94 142.61,117.22 143.69,116.14 143.69,111.51 144.25,110.95 144.25,104.6 144.77,104.08 144.77,100.88 148.32,97.33 152.46,97.33 152.85,97.73 153.01,97.73 v2(153.25,97.97)
  IN2 w0.127: v2(139.19,88.86) 139.67,89.33 140.41,89.33 141.1,90.03 145.43,90.03 145.64,89.81 147.56,89.81 v2(147.73,89.65) 147.85,89.77 152.25,89.77 152.96,90.49 157.98,90.49 v2(158.24,90.23) ; v2(133.34,151.51) 133.09,151.51 132.15,150.57 122.01,150.57 120.92,149.48 119.82,149.48 118.87,150.43 110.8,150.43 110.36,150.88 107.37,150.88 106.55,151.7 106.55,157.01 107.05,157.51 107.05,158.66 106.67,159.05 106.19,159.05 105.66,158.52 105.66,158.17 103.88,156.4 103.04,156.4 102.36,157.08 102.36,157.86 101.78,158.43 101.34,158.43 99.75,160.02 99.75,161.67 v2(96.88,164.54)
  BOTTOM w0.076: v2(139.19,88.86) 139.19,88.46 138.87,88.14 138.03,88.14 137.78,88.38 137.78,88.65 137.53,88.9 136.81,88.9 UC1.P4
  BOTTOM w0.102: v2(147.73,89.65) 147.76,89.68 RC293.2 ; v2(96.88,164.54) 97.3,164.96 LCD1.34 ; v2(158.24,90.23) v1(158.24,91.03) 158.24,93.09 158.01,93.32 155.36,93.32 153.67,95.01 153.67,97.55 v2(153.25,97.97)
ISEN1_GT: length 8.5
  TOP w0.203: 113.18,138.2 113.18,138.37 113.49,138.68 PU602.9
  TOP w0.254: v2(109.4,136.72) 109.61,136.92 PR615.2 110.66,136.36 111.34,136.36 PC635.2 112.35,137.37 112.35,137.38 113.18,138.2
  BOTTOM w0.102: v2(109.4,136.72) v1(108.81,136.72)
  BOTTOM w0.254: v2(109.4,136.72) 109.52,136.72 PR677.1 110.24,137.29 PR675.2
ISEN1_VGA: length 5
  TOP w0.254: v2(157.01,111.25) 157.01,112.26 PR1124.1
  BOTTOM w0.203: PC1120.2 157.01,111.75 v2(157.01,111.25) 157.01,111.07 157.28,110.79 v1(157.44,110.79) 157.8,110.79 158.36,110.24 PU1100.13
ISEN2_GT: length 9.7
  TOP w0.203: PU602.10 113.83,138.28
  TOP w0.254: PC638.2 113.02,134.67 PR670.2 114.1,133.72 PR668.2 ; PC638.2 111.63,135.5 111.63,134.71 v1(111.4,134.48) 111.14,134.23 PR634.2 ; PC638.2 112.52,136.39 112.52,136.97 113.83,138.28
ISEN2_VGA: length 5.6
  TOP w0.254: v2(156.33,111.25) v1(155.94,111.65) 155.25,112.34 PR1104.1
  BOTTOM w0.203: PC1119.2 156.33,111.54 156.33,111.25 v2(156.33,111.25) 156.38,111.21 156.38,111 156.97,110.41 157.61,110.41 157.96,110.07 PU1100.12
ISOLATE#: length 3.5
  TOP w0.102: R3015.1 R6518.2 v1(52.85,168.5) 52.58,168.76 51.97,168.76 51.93,168.8 LOM30.20
ISUMN_GT: length 156.7
  TOP w0.254: PC635.1 110.99,137.8 PR638.1 110.12,137.82 PR632.1 109.73,137.8 v2(109.4,137.48) ; v2(66.62,79.91) 67.87,81.15 68.81,81.15 71.41,83.76 74,83.76 91.28,101.03 91.28,103.48 92.7,104.9 92.7,109.22 v2(93.97,110.49) ; PC638.1 v2(110.99,134.81) ; v2(63.39,51.66) 63.16,51.66 62.16,52.67 62.16,59.66 59.33,62.48 53.97,62.48 49.9,66.55 46.28,66.55 v1(45.36,67.47) v2(44.13,68.71) ; PR666.2 111.94,133.92 v2(111.88,133.98)
  IN1 w0.254: v2(44.13,68.71) 44.89,68.71 45.84,69.66 45.84,71.63 45.67,71.8 45.67,73.55 46.79,74.68 46.79,75.82 47.05,76.07 51.68,76.07 53.84,78.23 61.08,78.23 61.59,77.72 64.44,77.72 v2(66.62,79.91)
  IN2 w0.254: v2(109.4,137.48) 110.99,135.89 v2(110.99,134.81)
  BOTTOM w0.254: v2(63.39,51.66) 63.94,51.66 PH602.2 ; PC641.1 PR633.2 PC626.2 PC624.2 112.24,138 PR673.2 ; PC641.1 109.28,137.6 v2(109.4,137.48) ; PC641.1 106.87,138.29 104.2,135.62 104.2,125.36 99.03,120.19 99.03,112.56 96.96,110.49 v2(93.97,110.49) ; v2(111.88,133.98) 111.05,134.81 v2(110.99,134.81)
ISUMN_IA: length 40.5
  TOP w0.102: PR640.2 v1(119.88,132.37)
  TOP w0.254: PR640.2 PR644.2 121.08,133.98 121.47,133.98 v2(121.57,134.09)
  IN2 w0.254: v2(112.88,116.9) 113.01,117.03 116.58,117.03 117.4,117.86 117.4,121.7 118.06,122.35 118.06,126.3 120.02,128.26 120.02,129.91 121.45,131.34 121.45,131.84 122.61,133.01 122.61,133.79 122.27,134.14 121.62,134.14 v2(121.57,134.09)
  BOTTOM w0.254: PR656.2 PC646.2 PC642.2 120.15,134.72 PC645.1 120.87,134.72 121.5,134.09 v2(121.57,134.09) ; PH605.2 117.66,114.96 117.66,116.78 117.4,117.03 113.01,117.03 v2(112.88,116.9) PL603.2
ISUMN_VSA: length 44.1
  TOP w0.254: PR636.2 122.72,142.99 v2(122.73,142.99) v1(123.46,142.99) 123.81,142.99 PR641.2
  IN2 w0.254: v2(121.13,116.63) 121.01,116.76 119.2,116.76 118.42,117.54 118.42,121.08 119.01,121.67 119.01,125.93 121.42,128.34 121.42,129.65 122.61,130.84 122.61,131.95 123.18,132.52 123.18,135.09 124.78,136.69 124.78,139.31 124.2,139.89 123.69,139.89 123.37,140.21 123.37,141.46 123.63,141.71 123.63,142.56 123.19,142.99 v2(122.73,142.99)
  BOTTOM w0.254: PH604.2 123.59,115.54 122.55,116.59 121.18,116.59 v2(121.13,116.63) PL601.2 ; PC637.2 122.27,143.28 122.56,142.99 v2(122.73,142.99) ; PC637.2 122.12,144.18 PC644.1 ; PC637.2 PR643.1 PC633.2
ISUMP_GT: length 15.7
  TOP w0.203: PU602.7 113.27,139.48 112.99,139.2 v2(112.58,139.2)
  TOP w0.254: v2(112.2,134.62) 113.02,133.79 PR667.1
  IN2 w0.254: v2(112.58,139.2) 112.58,135 v2(112.2,134.62)
  BOTTOM w0.102: v1(109.86,141.33) PR628.1
  BOTTOM w0.254: PR628.1 109.86,139.51 PR633.1 PC626.1 PC624.1 112.58,139.2 v2(112.58,139.2) 112.58,138.82 112.89,138.51 113.67,138.51 PR637.1 ; PR674.1 111.5,135.32 v2(112.2,134.62)
ISUMP_IA: length 12
  TOP w0.203: 118.12,136.81 117.85,137.08 PU602.19
  TOP w0.254: v2(118.8,136.74) 118.73,136.81 118.12,136.81
  BOTTOM w0.102: v1(123.08,137.07) 122.19,137.07 PR661.2
  BOTTOM w0.254: PR661.2 120.58,135.46 PC642.1 PC646.1 PR656.1 PR657.1 PR653.1 117.07,136.12 117.07,136.32 117.32,136.57 117.86,136.57 118.03,136.74 v2(118.8,136.74)
ISUMP_VSA: length 10.7
  TOP w0.203: PU602.27 119.72,140.68 119.88,140.84 v2(120.14,140.84)
  BOTTOM w0.102: v1(120.22,146.91) 120.45,146.69 PR654.1
  BOTTOM w0.254: v2(120.14,140.84) 120.69,140.84 PR642.1 121.2,140.34 PC633.1 PR643.2 PC637.1 121.2,143.81 PR624.2 120.78,144.25 121.52,144.98 121.52,146.61 PR654.1
JACK_PLUG: length 14.6
  TOP w0.254: v2(188.42,21.04) 188.85,21.04 AFTP6307.1 190.59,22.77 CN6301.2
  IN1 w0.254: v2(181.13,25.79) 184.08,25.79 188.42,21.44 v2(188.42,21.04)
  BOTTOM w0.254: v2(181.13,25.79) 180.8,25.46 R2923.1
JDREF: length 2.9
  BOTTOM w0.102: HDA27.15 182.17,19.69 181.36,20.49 v1(181.36,20.73) 181.36,21.09 R2707.1
JTAG_CLK: length 5.3
  TOP w0.102: v2(190.99,88.33) 191.43,88.33 192.61,87.15 v1(193.01,87.15)
  BOTTOM w0.102: JDEG1.4 191.27,88.61 v2(190.99,88.33) 189.35,88.33 RE422.2
JTAG_TCK: length 9.2
  BOTTOM w0.102: 178.9,124.79 176.74,126.95 v3(176.16,126.95) 176,126.95 174.04,128.91 173.56,128.91 172.65,129.82 172.65,129.99 172.49,130.15 172.49,130.43 UV1.L3
JTAG_TDI: length 8.5
  TOP w0.102: v2(190.71,89.85) 190.79,89.78 193.1,89.78 v1(193.64,89.23)
  BOTTOM w0.102: JDEG1.2 191.31,89.61 191.06,89.85 v2(190.71,89.85) 189.71,89.85 189.48,89.62 187.55,89.62 RE420.2
JTAG_TDI_GPU: length 10
  BOTTOM w0.102: RP34.6 177.68,125.3 v1(177.27,125.3) 174.72,127.84 174.72,127.94 173.96,128.7 173.47,128.7 172.44,129.73 172.44,129.9 172.09,130.25 172.09,130.44 172.08,130.46 172.08,130.84 UV1.L5
JTAG_TDO: length 3.9
  BOTTOM w0.102: RE423.2 188.76,86.68 189.3,87.22 189.65,87.22 v1(189.71,87.27) 190.24,87.81 191.14,87.81 191.45,88.11 JDEG1.5
JTAG_TDO_GPU: length 4.6
  BOTTOM w0.102: T86.1 175.07,128.93 174.69,129.31 173.72,129.31 173.26,129.78 173.26,130.09 173.08,130.27 172.86,130.27 172.69,130.44 172.69,130.66 172.67,130.68 UV1.K4
JTAG_TMS: length 4.6
  TOP w0.102: v2(190.11,89.32) 190.16,89.37 191.76,89.37 v1(191.87,89.26)
  BOTTOM w0.102: JDEG1.3 190.32,89.11 v2(190.11,89.32) 189.45,89.32 RE421.2
JTAG_TMS_GPU: length 8.4
  BOTTOM w0.102: UV1.L1 172.95,129.8 173.64,129.11 174.16,129.11 175.69,127.58 176.81,127.58 v1(178.22,126.18) RP34.8
JTAG_TRSTB: length 12.7
  BOTTOM w0.102: RP34.5 177.86,124.41 177.01,124.41 176.42,124.99 v1(176.03,124.99) 175.44,124.41 175.11,124.41 172.97,126.56 172.97,128.41 172.02,129.35 171.95,129.35 171.76,129.54 171.76,129.61 171.76,129.61 171.76,130.04 171.84,130.12 171.84,130.54 171.25,131.13 UV1.L6
KB_BL_CTRL#:
  vias: v1(191.29,125.58)
KB_DET#: length 149.8
  TOP w0.102: v2(150.77,69.33) 151.55,70.1 RC288.1 ; KB1.30 191.31,92.95 191.19,92.84 191.19,91.91 191.42,91.68 194.78,91.68 v1(195.51,90.95) 195.54,90.92 195.54,90.9 197.71,88.73 197.71,79.22 v2(196.59,78.1)
  IN1 w0.127: v2(164.9,39.24) 168.61,39.24 180.33,50.97 193.01,50.97 196.24,54.19 196.24,57.18 197.35,58.29 197.35,60.13 v2(197.86,60.64)
  IN2 w0.127: v2(150.77,69.33) 151.9,68.21 156.1,68.21 156.61,67.7 160.55,67.7 163.89,64.36 163.89,62.31 165.43,60.77 165.43,56.88 166.36,55.94 166.36,47.33 164.08,45.04 164.08,40.07 v2(164.9,39.24) ; v2(197.86,60.64) 198.3,61.08 198.3,62.8 197.73,63.37 197.73,65.52 195.87,67.38 195.87,69.98 196.82,70.93 196.82,76.58 197.1,76.86 197.1,77.6 v2(196.59,78.1)
  BOTTOM w0.076: 140.9,73.06 140.6,73.06 140.35,73.3 139.99,73.3 139.56,72.87 136.69,72.87 136.11,73.44 135.88,73.44 135.42,73.9 135.11,73.9 134.96,74.06 UC1.BB7
  BOTTOM w0.102: 140.9,73.06 141.54,73.06 143.57,75.1 146.81,75.1 147.28,74.63 147.59,74.63 149.68,72.54 149.68,70.43 150.77,69.34 v2(150.77,69.33)
KB_LED_BL_DET: length 103
  TOP w0.254: R6206.1 R6207.1 186.07,122.51 183.06,119.51 183.06,117.6 184.46,116.2 188.4,116.2 189.41,115.19 189.41,94.23 189.13,93.95 177.52,93.95 172.91,89.34 172.91,88.65 171.89,87.63 171.89,84.96 170.55,83.63 v1(169.91,83.63) 166.05,83.63 v2(165.53,83.11)
  IN1 w0.254: v2(134.68,86.04) 134.68,86.09 135.18,86.6 139.21,86.6 139.36,86.74 139.82,86.74 140.2,86.36 141.49,86.36 141.72,86.59 143.73,86.59 144.67,87.53 146.87,87.53 147.03,87.69 147.5,87.69 148.27,88.46 148.27,89.09 148.65,89.47 153.28,89.47 153.73,89.03 153.73,88.71 154.11,88.33 157.73,88.33 163,83.06 165.47,83.06 v2(165.53,83.11)
  BOTTOM w0.254: UC1.W8 134.43,86.28 v2(134.68,86.04)
KB_LED_DET_C: length 6.2
  TOP w0.102: R6206.2 v1(188.52,124.12) 190.41,124.12 190.96,123.57 190.96,122.71 191.1,122.57 KB_BL1.2
KB_LED_PWM: length 63.6
  TOP w0.102: v2(194.57,124.74) 194.57,125.17 192.09,127.65 v1(190.35,127.65) Q6202.2
  TOP w0.203: v2(189.99,79.88) 189.48,79.88 189.29,80.07 188.45,80.07 187.45,81.08 187.45,81.49 187.15,81.79 UE1.44
  IN2 w0.254: v2(194.57,124.74) 195.64,123.67 195.64,114.93 195.13,114.43 195.13,110.93 192.4,108.2 192.4,98.36 190.68,96.65 190.68,91.22 191.47,90.44 191.47,87.34 190.19,86.05 190.19,84.26 191.13,83.31 191.13,81.28 190.68,80.84 190.68,80.58 v2(189.99,79.88)
KBC_PWRBTN#_C: length 15.6
  TOP w0.102: G6101.2 193,173.23 R6102.2 EC6101.1 192.03,175.04 ED6101.1 192.23,175.3 v2(192.69,175.3) 193.41,175.3 AFTP6101.1 193.95,175.21 198.15,171.01 PWR1.2
  BOTTOM w0.102: G6102.2 192.43,175.57 v2(192.69,175.3)
KSI0: length 54.7
  TOP w0.102: UE1.98 179.55,68.05 179.98,68.48 179.98,69.12 181.7,70.84 183.48,70.84 184.56,71.92 185.58,71.92 186.14,71.36 189.69,71.36 v2(191.27,69.79) ; KB1.22 193,99.35 193.16,99.19 194.04,99.19 194.42,98.81 v2(194.42,98.81) 195.1,98.12 v1(195.1,96.8)
  IN2 w0.127: v2(191.27,69.79) 192.2,69.79 193.69,71.28 193.69,81.07 193.96,81.34 194.46,81.34 195.38,82.26 195.38,85.68 194.62,86.45 194.62,91.89 193.29,93.22 193.29,93.97 193.55,94.23 194.09,94.23 194.81,94.96 194.81,98.41 v2(194.42,98.81)
  BOTTOM w0.102: v2(191.27,69.79) 190.96,69.48 RPE2.4
KSI1: length 51.6
  TOP w0.102: KB1.24 192.94,97.75 193.1,97.91 v1(193.59,97.91) 193.98,97.91 v2(194.24,98.17) ; UE1.99 179.95,68.13 180.21,68.39 180.21,69.02 181.79,70.61 183.57,70.61 184.03,71.07 185.92,71.07 185.98,71.13 189.6,71.13 190.72,70.02 190.72,69.56 190.94,69.34 191.4,69.34 191.6,69.54 191.6,69.54 191.68,69.62 v2(191.68,70.23)
  IN2 w0.127: v2(194.24,98.17) 194.56,97.85 194.56,95.06 193.98,94.49 193.4,94.49 193.03,94.12 193.03,93.12 194.37,91.78 194.37,86.34 195.13,85.58 195.13,82.37 194.36,81.6 193.86,81.6 193.37,81.11 193.37,71.33 192.27,70.23 v2(191.68,70.23)
  BOTTOM w0.102: RPE2.3 190.88,69.98 191.13,70.23 v2(191.68,70.23)
KSI2: length 33.8
  TOP w0.102: KB1.26 193.39,96.15 v1(193.56,95.98) 193.91,95.63 v2(193.91,95.02) ; v2(191.32,70.74) 191.41,70.65 192.06,70.65 192.18,70.77 UE1.6
  IN2 w0.127: v2(193.91,95.02) 193.42,95.02 192.78,94.38 192.78,93.01 194.11,91.68 194.11,86.23 194.87,85.47 194.87,82.47 194.25,81.85 193.75,81.85 193.11,81.21 193.11,71.43 192.36,70.68 191.38,70.68 v2(191.32,70.74)
  BOTTOM w0.102: RPE2.2 191.06,70.48 v2(191.32,70.74)
KSI3: length 36.9
  TOP w0.102: v2(191.94,71.89) 191.94,71.63 192.4,71.17 UE1.7 194.91,71.17 v1(194.93,71.16) ; v2(193.8,98.78) 193.12,98.78 192.89,98.55 KB1.23
  IN2 w0.127: v2(191.94,71.89) 192.86,72.81 192.86,81.32 193.65,82.11 194.15,82.11 194.62,82.58 194.62,85.37 193.86,86.13 193.86,91.57 192.53,92.9 192.53,94.86 194.11,96.44 194.11,97.66 193.8,97.98 v2(193.8,98.78)
  BOTTOM w0.102: v2(191.94,71.89) 191.84,71.89 190.93,70.98 RPE2.1
KSI4: length 63.9
  TOP w0.102: UE1.104 181.95,65.7 181.11,64.86 180.94,64.86 180.54,64.46 RPE3.4 180.41,64.2 180.2,64.2 v2(180.02,64.39) ; v2(194.47,94.01) 194.26,94.21 v1(193.54,94.21) 193.02,94.74 193.02,95.02 192.69,95.35 KB1.27
  IN2 w0.127: v2(194.47,94.01) 194.81,93.66 194.81,92.77 195.41,92.18 195.41,89.47 196.14,88.73 196.14,81.22 194.46,79.53 194.46,67.89 194.79,67.55 194.98,67.55 197.22,65.31 197.22,61.92 v2(194.74,59.44)
  BOTTOM w0.102: v2(180.02,64.39) 181.35,63.06 181.35,61.75 184.66,58.43 189.54,58.43 190.54,59.44 v2(194.74,59.44)
KSI5: length 74.4
  TOP w0.102: v1(195.1,95.01) 195.1,96.06 193.76,97.41 v2(193.67,97.41) 193.21,96.95 KB1.25 ; UE1.105 182.35,65.77 181.04,64.46 RPE3.3 181.04,64.01 180.78,63.75 v2(180.05,63.75)
  IN2 w0.127: v2(194.18,58.93) 193.73,59.37 193.73,60.18 194.35,60.8 194.72,60.8 196.46,62.55 196.46,64.99 194.67,66.78 194.48,66.78 193.65,67.62 193.28,67.62 191.55,69.34 191.12,69.34 190.85,69.61 190.85,71.39 192.61,73.15 192.61,81.42 193.54,82.36 194.04,82.36 194.37,82.68 194.37,85.26 193.6,86.02 193.6,91.47 192.27,92.8 192.27,95.03 193.67,96.43 v2(193.67,97.41)
  BOTTOM w0.102: v2(194.18,58.93) 193.9,59.21 190.63,59.21 189.25,57.82 183.62,57.82 180.97,60.47 180.97,62.84 v2(180.05,63.75)
KSI6: length 63.7
  TOP w0.102: KB1.28 192.59,94.55 193.41,93.73 v2(193.71,93.73) 194.1,93.73 195.14,92.68 v1(195.54,92.68) ; RPE3.2 181.54,64.58 182.17,65.21 v2(182.56,65.21) 182.64,65.3 182.64,65.81 183.15,66.31 UE1.107
  IN2 w0.127: v2(193.71,93.73) 194.11,93.73 194.56,93.28 194.56,92.67 195.15,92.07 195.15,89.36 195.89,88.63 195.89,81.32 194.2,79.63 194.2,67.78 194.69,67.29 194.88,67.29 196.97,65.2 196.97,62.34 v2(194.74,60.11)
  BOTTOM w0.102: v2(194.74,60.11) 194.16,60.69 191.13,60.69 189.34,58.9 184.84,58.9 183,60.74 183,64.77 v2(182.56,65.21)
KSI7: length 60.5
  TOP w0.102: KB1.29 193.07,93.75 193.5,93.32 193.8,93.32 v2(193.94,93.17) 193.94,92.93 v1(193.5,92.49) ; UE1.108 183.55,66.33 183.13,65.91 183.13,65.15 v2(182.56,64.58) 182.14,64.58 182.04,64.48 RPE3.1
  IN2 w0.127: v2(194.15,60.01) 194.15,60.11 194.59,60.55 194.82,60.55 196.72,62.44 196.72,65.09 194.77,67.04 194.58,67.04 193.95,67.67 193.95,79.74 195.64,81.43 195.64,85.79 194.87,86.55 194.87,91.99 193.94,92.93 v2(193.94,93.17)
  BOTTOM w0.102: v2(194.15,60.01) 190.77,60.01 189.44,58.67 184.75,58.67 182.56,60.86 v2(182.56,64.58)
KSO0: length 49.2
  TOP w0.102: v2(194.68,107.57) 194.66,107.59 193.92,107.59 192.88,106.55 KB1.13 ; UE1.2 194.03,69.17 194.43,68.77 194.43,68.5 v2(194.87,68.06) v1(195.38,68.06) ; v2(194.87,74.19) 194.87,74.42 195.4,74.94 RPE4.8
  IN2 w0.127: v2(194.68,107.57) 194.68,107.38 197.48,104.58 197.48,80.45 196.14,79.12 196.14,75.46 v2(194.87,74.19) 194.87,70.55 195.36,70.07 195.36,68.54 v2(194.87,68.06)
KSO1: length 43
  TOP w0.102: KB1.15 193.46,104.95 v2(194.11,105.6) 194.74,105.6 194.9,105.44 196.04,105.44 196.81,106.2 196.81,106.93 v1(197.14,107.26) ; UE1.14 194.08,73.97 194.9,74.79 v2(194.9,75.07) 195.28,75.44 RPE4.7
  IN2 w0.127: v2(194.9,75.07) 195.89,76.06 195.89,79.25 197.16,80.52 197.16,103.44 195,105.6 v2(194.11,105.6)
KSO2: length 38.8
  TOP w0.102: UE1.15 194.06,74.37 194.49,74.8 194.49,75.55 v2(194.87,75.93) 194.88,75.94 RPE4.6 ; v1(194.06,107.26) 194.06,106.2 v2(193.48,105.62) 193.06,105.62 192.93,105.75 KB1.14
  IN2 w0.127: v2(194.87,75.93) 194.9,75.93 195.64,76.67 195.64,79.37 196.91,80.64 196.91,89.09 196.17,89.83 196.17,92.49 195.57,93.09 195.57,103.46 193.48,105.56 v2(193.48,105.62)
KSO3: length 37.4
  TOP w0.102: UE1.16 194.08,74.77 194.24,74.93 194.24,75.87 194.88,76.52 v2(194.89,76.52) 194.97,76.44 RPE4.5 195.88,76.44 196.12,76.68 196.12,77.74 v1(196.16,77.77) ; v2(193.48,104.45) 192.96,104.45 192.66,104.15 KB1.16
  IN2 w0.127: v2(193.48,104.45) 194.22,104.45 195.32,103.36 195.32,92.99 195.92,92.39 195.92,89.7 196.65,88.96 196.65,80.84 195.38,79.57 195.38,77.01 v2(194.89,76.52)
KSO4: length 23.6
  TOP w0.102: UE1.37 189.95,83.65 190.53,84.24 191.48,84.24 191.9,84.65 v2(191.9,84.77) 191.9,85 191.81,85.08 RPE5.8 ; v1(194.44,99.7) 194.21,99.92 v2(193.99,99.92) 193.76,99.92 192.72,100.96 192.72,100.96 192.7,100.95 KB1.20
  IN2 w0.127: v2(193.99,99.92) 193.99,99.84 193.35,99.2 193.35,97.98 191.7,96.33 191.7,91.38 192.3,90.78 192.3,85.17 v2(191.9,84.77)
KSO5: length 24.4
  TOP w0.102: RPE5.7 191.31,84.86 v2(191.32,84.85) 190.94,84.47 190.38,84.47 189.55,83.63 UE1.38 ; KB1.21 192.92,100.15 v2(193.31,99.76) 193.66,99.42 194.14,99.42 194.34,99.21 194.59,99.21 195.34,98.46 v1(195.66,98.46)
  IN2 w0.127: v2(193.31,99.76) 193.03,99.47 193.03,98.04 191.38,96.39 191.38,91.33 192.04,90.67 192.04,85.57 v2(191.32,84.85)
KSO6: length 26.9
  TOP w0.102: KB1.18 192.73,102.55 192.81,102.64 192.81,102.94 v2(193.35,103.48) 193.6,103.23 v1(193.6,102.45) ; UE1.39 189.15,83.62 190.4,84.87 v2(190.67,84.87) 190.67,85.06 190.81,85.21 RPE5.6
  IN2 w0.127: v2(193.35,103.48) 192.72,102.84 192.72,98.11 191.13,96.52 191.13,91.23 191.79,90.57 191.79,87.08 190.67,85.96 v2(190.67,84.87)
KSO7: length 34.8
  TOP w0.102: v2(188.44,79.48) 188.2,79.24 187.13,79.24 186.24,80.14 185.22,80.14 184.43,80.93 184.43,81.53 184.75,81.85 UE1.50 ; KB1.19 191.06,101.75 v2(190.59,101.28) ; v1(189.11,85.65) 189.11,86.45 v2(189.47,86.81) 190.32,85.96 RPE5.5
  IN2 w0.127: v2(190.59,101.28) 190.59,98.21 189.48,97.09 189.48,94.05 188.8,93.37 188.8,88.51 189.47,87.84 v2(189.47,86.81) 189.11,86.45 189.11,83.47 188.3,82.66 188.3,79.63 v2(188.44,79.48)
KSO8: length 92.2
  TOP w0.102: KB1.17 190.83,103.35 v2(190.7,103.48) ; v2(187.76,79.65) 187.05,79.65 186.11,80.59 186.11,81.54 186.35,81.77 UE1.46 ; v1(172.55,74.86) 173.02,74.4 173.02,73.71 173.89,72.84 RPE7.8 175.66,72.84 v2(175.66,72.83)
  IN2 w0.127: v2(190.7,103.48) 190.18,102.95 190.18,98.17 189.22,97.22 189.22,94.15 188.55,93.48 188.55,87.29 188.85,86.98 188.85,83.58 187.95,82.68 187.95,80.1 187.76,79.9 v2(187.76,79.65) 188.02,79.39 188.02,77.72 189.6,76.13 189.6,70.91 189.54,70.84 189.54,68.39 190.46,67.47 192.35,67.47 192.96,66.86 193.33,66.86 194.16,66.02 194.35,66.02 195.7,64.67 195.7,62.87 194.4,61.57 194.04,61.57 192.54,60.06 192.54,58.6 v2(192.95,58.18)
  BOTTOM w0.102: v2(175.66,72.83) 175.25,72.43 175.25,70.92 177.73,68.45 177.73,64.58 180.33,61.98 180.33,60.46 183.43,57.37 189.44,57.37 190.25,58.18 v2(192.95,58.18)
KSO9: length 51.4
  TOP w0.102: KB1.7 191.29,111.35 v2(190.81,110.87) ; UE1.68 176.52,79.97 176.31,79.76 v1(175.93,79.76) 175.02,79.76 RE389.1 175.27,79.25 v2(175.78,79.25)
  IN2 w0.127: v2(183.74,91.41) 184.08,91.75 184.08,92.5 185.31,93.73 186.64,93.73 187.7,94.79 187.7,97.91 188.65,98.87 188.65,108.71 v2(190.81,110.87)
  BOTTOM w0.102: v2(183.74,91.41) 183.74,88.75 184.27,88.21 184.27,86.16 185.81,84.62 185.81,80.56 184.43,79.18 179.76,79.18 179.04,79.9 176.23,79.9 175.78,79.46 v2(175.78,79.25)
KSO10: length 56.2
  TOP w0.102: v2(190.37,111.99) 190.6,111.99 191.56,112.95 KB1.5 ; v2(174.36,78.8) 174.11,78.55 174.11,78.3 174.21,78.19 RPE6.8 175.51,78.19 v1(175.77,78.46) 176.55,78.46 176.64,78.37 UE1.72
  IN2 w0.127: v2(183.65,92.03) 183.24,92.44 183.24,93.05 184.42,94.23 186.43,94.23 187.19,95 187.19,98.13 188.14,99.08 188.14,109.81 190.32,111.99 v2(190.37,111.99)
  BOTTOM w0.102: v2(183.65,92.03) 183.61,92.03 183.33,91.74 183.33,88.38 184.02,87.69 184.02,86.61 183.8,86.4 183.8,83.59 185.48,81.92 185.48,80.59 184.33,79.44 179.89,79.44 179.2,80.13 175.12,80.13 174.16,79.18 174.16,79.03 v2(174.36,78.8)
KSO11: length 58.6
  TOP w0.102: v1(193.72,114.1) 193.47,113.84 193.47,112.56 193.06,112.15 KB1.6 191.46,112.15 190.66,111.36 190.33,111.36 v2(190.3,111.38) ; v2(173.7,78.84) 173.75,78.78 173.75,77.96 174.01,77.69 RPE6.7 174.92,77.69 175.05,77.57 UE1.74
  IN2 w0.127: v2(190.3,111.38) 188.4,109.47 188.4,98.97 187.45,98.02 187.45,94.89 186.53,93.98 184.94,93.98 v2(183.66,92.7)
  BOTTOM w0.102: v2(173.7,78.84) 173.93,79.04 173.94,79.28 175.02,80.36 181.02,80.36 181.71,79.67 184.18,79.67 185.25,80.73 185.25,81.82 183.57,83.5 183.57,85.15 183.1,85.62 183.1,92.14 v2(183.66,92.7)
KSO12: length 46.5
  TOP w0.102: v2(190.58,107.16) 190.77,107.35 KB1.12 ; v2(187.51,78.68) 185.79,78.68 183.2,76.09 181.98,76.09 181.98,76.09 181.84,76.09 180.91,77.02 180.12,77.02 180.02,76.92 178.79,76.92 178.54,77.17 UE1.75 176.62,77.17 176.6,77.14 v1(175.94,77.14) 174.85,77.14 174.79,77.19 RPE6.6
  IN2 w0.127: v2(190.58,107.16) 189.92,106.5 189.92,98.3 188.97,97.35 188.97,94.26 188.29,93.58 188.29,87.18 188.6,86.88 188.6,83.68 187.7,82.78 187.7,80.2 187.34,79.84 187.34,78.85 v2(187.51,78.68)
KSO13: length 53.4
  TOP w0.102: v2(190.81,109.54) 191.02,109.75 KB1.9 ; UE1.76 175.07,76.77 175,76.69 RPE6.5 174.03,76.69 173.96,76.62 173.96,76.48 174.33,76.1 v2(174.52,76.1)
  IN2 w0.127: v2(190.81,109.54) 189.16,107.89 189.16,98.66 188.21,97.7 188.21,94.57 186.85,93.22 186.09,93.22 v2(184.57,91.7)
  BOTTOM w0.102: v2(184.57,91.7) 184.57,86.18 186.04,84.72 186.04,80.39 184.55,78.91 179.66,78.91 178.89,79.67 176.79,79.67 174.68,77.57 v1(174.52,77.57) v2(174.52,76.1)
KSO14: length 58.3
  TOP w0.102: KB1.8 191.13,110.55 v2(190.81,110.24) ; UE1.77 176.64,76.37 176.47,76.54 175.53,76.54 v2(175.13,76.14) ; v2(175.66,71.84) RPE7.6
  IN2 w0.127: v2(190.81,110.24) 188.91,108.33 188.91,98.76 187.95,97.81 187.95,94.68 186.75,93.47 185.75,93.47 v2(184.57,92.3) ; v2(175.13,76.14) 175.13,72.37 v2(175.66,71.84)
  BOTTOM w0.102: v2(184.57,92.3) 184.58,92.3 184.98,91.9 184.98,91.32 184.81,91.15 184.81,86.47 v1(185.5,85.78) 186.26,85.01 186.26,80.3 184.64,78.68 179.51,78.68 178.74,79.45 176.88,79.45 174.96,77.52 174.96,76.31 v2(175.13,76.14)
KSO15: length 50
  TOP w0.102: v2(186.37,76.45) 184.54,76.45 183.49,75.4 181.88,75.4 181.37,74.89 181.28,74.89 179.26,72.87 178.77,72.87 178.66,72.77 UE1.86 176.71,72.77 176.28,72.34 v1(175.98,72.34) RPE7.7 ; v2(190.81,108.84) 190.92,108.95 KB1.10
  IN2 w0.127: v2(190.81,108.84) 189.41,107.44 189.41,98.55 188.46,97.6 188.46,94.47 187.24,93.25 187.24,90.72 186.44,89.93 186.44,85.04 185.86,84.45 185.86,80.69 185.44,80.27 185.44,77.38 v2(186.37,76.45)
KSO16: length 56.9
  TOP w0.102: RPE7.5 174.69,71.34 174.86,71.17 174.86,70.36 v1(175.01,70.21) 175.14,70.08 176,70.08 176.29,70.37 UE1.92 178.38,70.37 178.75,70.74 179.68,70.74 180.57,71.63 181.79,71.63 182.87,72.71 185.48,72.71 185.6,72.83 186.81,72.83 187.32,72.33 v2(189.03,72.33) ; v2(190.75,108.04) 190.86,108.15 KB1.11
  IN2 w0.127: v2(189.03,72.33) 189.03,72.34 189.35,72.64 189.35,76.03 187.08,78.3 187.08,79.94 187.45,80.31 187.45,82.89 188.34,83.79 188.34,86.77 188.04,87.07 188.04,93.69 188.72,94.36 188.72,97.45 189.67,98.4 189.67,106.96 v2(190.75,108.04)
L_BKLT_CTRL: length 130
  TOP w0.102: v2(67.49,162.56) 67.49,164.34 v1(67.16,164.67) R5206.1
  IN1 w0.127: v2(100.7,103.5) 101.35,103.5 103.95,100.9 105.21,100.9 106.29,99.82 109.91,99.82 111.82,97.92 112.39,97.92 112.96,97.35 112.96,96.39 113.85,95.5 113.85,92.67 114.04,92.48 114.55,92.48 114.8,92.74 114.8,93.15 115.75,94.11 122.22,94.11 122.78,93.55 122.78,92.96 124.36,91.37 124.36,89.73 124.07,89.43 124.07,87.77 125.1,86.74 126.23,86.74 126.49,86.99 126.49,87.19 126.29,87.38 126.29,87.82 127.18,88.71 129.22,88.71 129.85,88.07 130.8,88.07 131.54,88.81 v2(131.54,89.25)
  IN2 w0.127: v2(67.49,162.56) 73.15,156.91 74.99,156.91 91.12,140.78 91.12,138.37 99.49,130 99.49,125.59 95.78,121.89 95.78,120.05 94.99,119.25 94.99,112.46 96.07,111.38 96.07,108.92 99.37,105.62 99.37,104.65 100.51,103.5 v2(100.7,103.5)
  BOTTOM w0.089: v2(131.54,89.25) 131.56,89.27 131.92,89.27 UC1.R11
L_BKLT_EN_EC: length 72.1
  TOP w0.102: v2(175.66,71.09) 175.98,70.77 UE1.91
  IN1 w0.127: v2(175.66,71.09) 172.92,71.09 171.74,69.91 v2(169.79,69.91)
  IN2 w0.127: v2(169.79,69.91) 168.34,71.36 168.34,78.91 167.59,79.67 167.59,80.44 165.92,82.11 164.4,82.11 163.57,82.93 161.41,82.93 160.9,83.44 160.9,84.07 160.52,84.45 159.76,84.45 159,85.22 v2(158.74,85.22) 156.53,85.22 155.22,83.91 149.95,83.91 149.31,84.54 146.7,84.54 146.15,85.09 141.13,85.09 140.45,85.77 138.01,85.77 136.62,87.17 133.42,87.17 132.92,87.67 132.47,87.67 132.2,87.95 132.2,87.95 v2(132.16,87.99)
  BOTTOM w0.102: v2(158.74,85.22) 158.74,85.16 157.96,84.37 157.94,84.37 155,81.43 154.5,81.43 154.15,81.08 154.15,81.07 154.07,80.99 v1(151.56,80.99) 151.08,80.5 151.08,79.62 RC390.2 ; UC1.R12 132.16,88.38 v2(132.16,87.99)
LAN_EN: length 235.4
  TOP w0.102: v1(64.85,171.04) 64.29,170.48 v2(64.29,170.28) 64.12,170.45 R3023.1 63.39,169.51 62.43,168.56 61.36,168.56 60.96,168.17 Q3001.2 ; v2(194.87,68.9) 194.2,69.57 UE1.3
  IN1 w0.127: v2(64.29,170.28) 64.29,167.13 65.02,166.41 69.19,166.41 76.15,159.45 82.86,159.45 83.94,158.37 92.55,158.37 94.54,156.38 94.54,151.9 97.64,148.81 105.54,148.81 107.98,146.37 112.57,146.37 114.01,147.8 123.16,147.8 124.22,146.74 124.22,142.86 125.94,141.15 125.94,139.13 128.9,136.17 128.9,135.21 129.14,134.97 129.14,132.93 130,132.08 131.3,132.08 132.39,130.99 132.39,130.38 133.09,129.68 133.09,127.13 135.63,124.59 136.76,124.59 139.92,121.42 139.92,116.53 140.86,115.59 140.86,113.62 141.12,113.36 141.12,107.4 142.51,106.01 142.51,101.16 147.69,95.98 151.97,95.98 152.26,95.98 154.37,93.87 158.28,93.87 161.99,90.16 161.99,89.25 164.15,87.09 166.67,87.09 168.49,85.28 173.36,85.28 173.99,84.65 178.43,84.65 179.32,83.76 181.98,83.76 182.56,83.18 189.79,83.18 191.71,81.27 191.71,79.3 190.09,77.68 190.09,72.43 189.57,71.91 189.57,67.38 188.5,66.31 188.5,64.5 189.03,63.96 189.03,61.34 189.58,60.79 189.58,59.78 v2(189.11,59.31)
  BOTTOM w0.102: v2(189.11,59.31) 190.72,60.92 191.96,60.92 192.82,61.79 195.09,61.79 195.45,62.14 195.45,64.9 194.47,65.87 194.47,68.8 194.57,68.9 v2(194.87,68.9)
LAN_ENABLE_R_C: length 4.4
  TOP w0.102: Q3001.1 61.93,170.15 62.38,170.6 R3022.1 62.43,171.53 R3021.2 v1(63.71,172.42)
LAN_MDI0N: length 28
  TOP w0.089: v2(41.25,173.59) 41.42,173.42 41.42,173.21 41.76,172.87 42.73,172.87 v4(43.14,172.46) 43.64,171.96 43.64,170.88 44.13,170.39 46.14,170.39 46.5,170.03 46.79,170.03 46.82,170 LOM30.2
  BOTTOM w0.089: v2(41.25,173.59) 41.42,173.43 41.42,173.18 40.93,172.7 39.87,172.7 EC3102.2 39.42,172.58 39.13,172.58 38.86,172.86 38.86,173.2 38.58,173.48 38.33,173.48 38.22,173.48 38.05,173.65 EU3101.8 EU3101.2 36.1,173.65 35.9,173.45 32.94,173.45 30.52,171.03 30.52,166.82 30.41,166.71 30.17,166.71 30.07,166.8 30.07,167.11 29.98,167.2 XF3101.5
LAN_MDI0P: length 27.9
  TOP w0.089: v2(41.89,173.59) 41.74,173.44 41.74,173.31 41.88,173.16 42.86,173.16 43.35,172.67 43.94,172.08 43.94,171.01 44.25,170.69 46.26,170.69 46.62,170.33 46.75,170.33 46.82,170.4 LOM30.1
  BOTTOM w0.089: XF3101.6 29.98,165.93 30.07,166.01 30.07,166.3 30.18,166.41 30.54,166.41 30.82,166.69 30.82,170.91 33.06,173.15 36.42,173.15 36.43,173.15 EU3101.1 EU3101.9 38.2,173.15 38.24,173.18 38.46,173.18 38.56,173.08 38.56,172.73 39.01,172.28 39.42,172.28 EC3101.2 40.1,172.4 41.05,172.4 41.71,173.06 41.71,173.42 v2(41.89,173.59)
LAN_MDI1N: length 26
  TOP w0.089: LOM30.5 46.82,168.8 46.82,168.8 43.72,168.8 42.37,170.16 42.37,171.41 v2(42.22,171.56)
  BOTTOM w0.089: v2(42.22,171.56) 42.34,171.68 42.82,171.68 43.09,171.95 43.09,173.95 42.28,174.75 41.78,174.75 40.31,176.22 39.92,176.22 39.73,176.42 EC3104.2 39.47,176.19 39.36,176.19 39.36,176.19 39.11,176.19 38.07,175.15 EU3101.6 EU3101.5 36.55,175.15 36.51,175.11 31.95,175.11 31.41,174.57 30.17,174.57 29.93,174.82 XF3101.1
LAN_MDI1P: length 26
  TOP w0.089: LOM30.4 46.8,169.2 46.69,169.1 43.85,169.1 v4(43.16,169.79) 42.67,170.28 42.67,171.7 v2(42.22,172.15)
  BOTTOM w0.089: XF3101.2 29.85,173.55 30.03,173.72 30.03,174.13 30.18,174.28 31.54,174.28 32.07,174.82 36.38,174.82 36.55,174.65 EU3101.4 EU3101.7 37.99,174.65 39.24,175.9 39.36,175.9 EC3103.2 40.07,175.93 40.18,175.93 41.66,174.45 42.16,174.45 42.79,173.82 42.79,172.07 42.69,171.98 42.39,171.98 v2(42.22,172.15)
LAN_MDI2N: length 28.8
  TOP w0.089: v2(45.24,167.41) 45.12,167.53 45.12,167.56 45.22,167.65 45.26,167.65 45.5,167.89 46.09,167.89 46.31,168.11 46.71,168.11 46.81,168 LOM30.7 ; XF3102.2 29.81,167.2 30.32,166.69 30.47,166.69 33.03,169.25 v4(33.03,171.21) 33.03,171.57 35.13,173.67 35.85,173.67 35.87,173.65 EU3102.8 EU3102.2 37.51,173.65 37.63,173.53 38.02,173.53 38.31,173.23 38.31,172.94 38.66,172.59 38.92,172.59 EC3106.2 39.42,172.64 40.5,172.64 41.17,171.97 41.17,171.72 v2(41.37,171.52)
  BOTTOM w0.089: v2(41.37,171.52) 41.18,171.52 41.12,171.47 41.12,171.05 41.36,170.82 44.5,170.82 44.76,170.56 44.76,168.66 45.14,168.27 45.14,167.51 v2(45.24,167.41)
LAN_MDI2P: length 28.9
  TOP w0.089: XF3102.1 29.89,165.93 30.35,166.39 30.6,166.39 33.33,169.12 33.33,171.45 v4(34.75,172.87) 35.26,173.38 35.72,173.38 35.95,173.15 EU3102.9 EU3102.1 37.51,173.15 37.59,173.23 37.9,173.23 38.02,173.11 38.02,172.82 38.54,172.3 38.9,172.3 EC3105.2 39.53,172.34 40.38,172.34 40.87,171.84 40.87,171.71 v2(40.69,171.53) ; v2(44.65,167.41) 44.82,167.58 44.82,167.83 44.95,167.95 45.14,167.95 45.38,168.19 45.97,168.19 46.18,168.4 LOM30.6
  BOTTOM w0.089: v2(40.69,171.53) 40.82,171.4 40.82,170.93 41.23,170.52 44.38,170.52 44.46,170.43 44.46,168.53 44.84,168.15 44.84,167.6 v2(44.65,167.41)
LAN_MDI3N: length 31.4
  TOP w0.089: LOM30.10 48.31,166.33 48.25,166.27 48.25,166.03 47.99,165.76 47.45,165.76 47.3,165.91 46.64,165.91 v2(46.48,165.74) ; v2(41.07,176.88) 41.19,176.77 41.19,176.51 40.89,176.21 39.4,176.21 EC3108.2 38.91,176.13 38.46,176.13 38.08,175.76 38.08,175.23 37.9,175.05 37.67,175.05 37.57,175.15 EU3102.5 EU3102.6 35.82,175.15 35.76,175.09 32.55,175.09 v4(32.23,174.77) 31.83,174.37 30.35,174.37 29.9,174.82 XF3102.6
  BOTTOM w0.089: v2(46.48,165.74) 46.36,165.86 46.04,165.86 45.78,166.12 45.78,166.72 46.09,167.03 46.09,168.6 45.65,169.04 45.65,170.97 44.33,172.29 44.33,173.94 42.5,175.77 41.97,175.77 41.27,176.47 41.27,176.69 v2(41.07,176.88)
LAN_MDI3P: length 31.4
  TOP w0.089: v2(46.48,166.37) 46.64,166.2 47.42,166.2 47.57,166.06 47.87,166.06 47.96,166.15 47.96,166.27 47.91,166.33 LOM30.9 ; v2(41.81,176.86) 41.62,176.86 41.48,176.72 41.48,176.39 41.01,175.91 39.55,175.91 EC3107.2 38.92,175.83 38.58,175.83 38.38,175.63 38.38,175.11 38.02,174.75 37.67,174.75 37.56,174.65 EU3102.4 EU3102.7 35.98,174.65 35.83,174.79 v4(34.26,174.79) 32.67,174.79 31.93,174.05 30.47,174.05 29.97,173.55 XF3102.5
  BOTTOM w0.089: v2(46.48,166.37) 46.48,166.31 46.33,166.16 46.16,166.16 46.07,166.25 46.07,166.59 46.39,166.91 46.39,168.72 45.95,169.16 45.95,171.09 44.63,172.41 44.63,174.06 42.62,176.07 42.09,176.07 41.57,176.59 41.57,176.76 41.66,176.86 v2(41.81,176.86)
LAN_TXN_C_PCH_RXN6: length 3.9
  TOP w0.091: 52.44,167.51 52.57,167.39 v4(52.57,167.04) 52.57,166.75 53.28,166.05 53.56,166.05 C3016.1
  TOP w0.102: LOM30.18 51.76,168 51.9,167.87 52.09,167.87 52.44,167.51
LAN_TXP_C_PCH_RXP6: length 3.8
  TOP w0.091: 52.17,167.51 52.33,167.36 52.33,167.36 52.36,167.34 52.36,166.71 53.2,165.87 53.56,165.87 C3014.1
  TOP w0.102: LOM30.17 51.77,167.6 51.85,167.68 52.01,167.68 52.17,167.51
LAN_WAKE#: length 35.4
  TOP w0.102: RC70.2 RC391.2 154.14,69.53 v1(151.83,67.23) 150.73,67.23 149.69,68.27 149.69,72.62 147.82,74.48 147.69,74.48 147.07,75.11 144.09,75.11 143.92,74.93 139.11,74.93 138.93,75.11 134.95,75.11 132.63,77.43 131.55,77.43 131.16,77.83 131.16,79.63 v2(130.77,80.01)
  BOTTOM w0.089: v2(130.77,80.01) UC1.AM15
LANGND: length 9.4
  TOP w0.102: v2(16.07,162.05) v1(16.67,162.05)
  BOTTOM w1.016: RJ45.10 15.27,161.64
LANXIN: length 6.6
  TOP w0.102: LOM30.28 49.51,172.26 v1(49.48,172.29) 49.48,172.69 48.83,173.33 C3001.1 48.53,174.2 48.53,175.8 X3001.1
LANXOUT: length 4.8
  TOP w0.102: LOM30.29 49.11,172.13 v1(48.31,172.92) 47.97,173.26 C3011.1 47.97,174.53 X3001.3
LCD_BRIGHTNESS: length 10.8
  TOP w0.102: v2(91.24,163.83) 88.12,163.83 86.84,162.55 86.84,160.72 86.67,160.55 v1(86.67,160.45) RN5201.2
  BOTTOM w0.102: LCD1.23 91.8,164.39 v2(91.24,163.83)
LCD_TST: length 294.6
  TOP w0.102: v2(196.56,78.84) 195.09,78.84 195.02,78.77 UE1.26 ; D5202.3 63.66,165.21 v2(63.94,165.48) 64.15,165.48 v1(64.55,165.87) ; v2(88.68,160.35) 87.99,160.35 87.41,160.93 87.41,162.43 88.04,163.07 94.37,163.07 94.75,163.45 96.5,163.45 98.64,165.59 v2(98.64,170.12) ; RN5201.6 86.17,157.43 v2(85.9,157.17) ; v2(188.83,52.17) 189.22,52.56 189.22,53.34 187.61,54.95 187.61,57.51 188.08,57.98 188.08,59.42 R6523.1
  IN1 w0.127: v2(63.94,165.48) 64.53,164.88 70.12,164.88 75.81,159.19 82.73,159.19 84.76,157.17 v2(85.9,157.17) ; v2(188.83,52.17) 191.99,52.17 195.61,55.78 195.61,57.32 196.81,58.52 196.81,60.95 198.28,62.42 198.28,62.95 197.48,63.75 197.48,65.77 195.6,67.65 195.6,69.61 194.72,70.49 194.72,73.16 195.19,73.63 195.19,73.91 196.14,74.87 196.14,78.42 v2(196.56,78.84) 196.78,79.06 196.78,87.26 193.84,90.21 192.21,90.21 191.38,91.03 186.03,91.03 184.66,89.66 182.05,89.66 181.22,88.84 175.19,88.84 174.13,89.89 173.3,89.89 172.07,91.12 166.81,91.12 161.66,96.27 161.66,97.47 161.28,97.85 161.01,97.85 157.39,101.47 155.37,101.47 150.56,106.29 150.56,119.62 149.18,120.99 149.18,124.21 149.73,124.76 149.73,126.52 149.04,127.2 149.04,132.48 149.24,132.69 149.24,134.41 149.08,134.57 149.08,135.93 149.54,136.39 149.54,137.88 149.25,138.17 149.25,142.34 149.54,142.62 149.54,144.4 148.88,145.06 148.88,145.95 149.54,146.6 149.54,160.91 151.31,162.69 151.31,168.42 144.39,175.34 v2(144.39,179.01)
  IN2 w0.127: v2(88.68,160.35) 88.68,159.94 v2(85.9,157.17) ; v2(144.39,179.01) 142.87,180.53 133.24,180.53 131.63,178.93 112.24,178.93 110.17,176.85 105.36,176.85 98.64,170.13 v2(98.64,170.12)
LCD_TST_C: length 7.7
  TOP w0.102: v2(85.35,162.31) 85.35,162 v1(85.73,161.62) 85.78,161.57 85.78,160.93 85.63,160.78 85.63,160.3 86.17,159.76 RN5201.3
  BOTTOM w0.102: v2(85.35,162.31) 85.35,164.16 86.3,165.11 LCD1.12
LCD_VCC_TEST_EN: length 6.4
  TOP w0.102: RE443.2 186.49,61.9 R6524.1 185.86,62.53 185.86,65.47 185.95,65.56 UE1.114
LCDVDD: length 2.2
  BOTTOM w0.102: v3(78.57,154.71) 79.72,155.87 R5211.2
LCDVDD_EN: length 17.1
  BOTTOM w0.254: U5201.4 84.1,157.88 83.81,157.59 83.81,155.9 84.25,155.47 84.25,154.34 83.41,153.5 82.04,153.5 R5202.2 81.44,153.42 80.99,152.97 v1(79.5,152.97) 78.29,154.18 77.15,154.18 75.62,155.7 D5201.1
LCDVDD_LCD:
  vias: v2(81.37,157.63) v3(78.92,158.04) v3(79.58,156.39) v3(81.24,157.02)
LDO1_CAP: length 4
  BOTTOM w0.203: HDA27.27 187.41,17.69
  BOTTOM w0.305: R2711.2 189.23,18.5 C2702.2 188.16,18.45 187.41,17.69
LDO2_CAP: length 4.4
  BOTTOM w0.203: HDA27.39 184.97,12.63 185.12,12.47
  BOTTOM w0.305: C2712.2 187.64,10.92 187.25,11.3 186.66,11.3 186.02,11.94 185.65,11.94 185.12,12.47
LDO3_CAP: length 2.9
  BOTTOM w0.203: HDA27.7 179.79,16.49
  BOTTOM w0.305: C2718.1 178.3,17.34 179.15,16.49 179.79,16.49
LDO_+1.5VGPU: length 0.6
  TOP w0.102: v2(128.07,140.14) v1(128.07,139.56)
LDO_+1VALW: length 2
  BOTTOM w0.102: PC306.1 134.84,121.94 v1(136.11,121.94)
LDO_EN: length 3.6
  TOP w0.102: U5502.21 29,60.29 v2(29.08,60.21)
  BOTTOM w0.102: R5512.2 29.1,60.22 v2(29.08,60.21) 29.08,59.91 R5502.1 v1(27.69,59.54)
LED0: length 3.3
  TOP w0.102: TP3003.1 50.31,173.67 50.31,172.14 49.91,171.74 LOM30.27
LED1: length 7.5
  TOP w0.102: LOM30.26 50.31,171.68 50.69,172.06 50.69,173.31 51.07,173.69 51.07,177.97 TP3002.1
LED2: length 6.6
  TOP w0.102: LOM30.25 50.71,171.64 51,171.94 51,173.19 51.39,173.57 51.39,176.81 TP3001.1
LG1_VGA: length 1.1
  TOP w0.102: v2(169.67,108.97) 169.67,109.58 v1(169.35,109.89)
  vias: v2(163.04,107.69) v2(163.64,107.69) v2(169.03,108.97) v2(170.36,104.53) v2(170.36,103.96)
LG2_VGA: length 0.5
  BOTTOM w0.102: v1(164.19,106.16) 164.14,106.11 v2(163.68,106.11)
  vias: v2(163.08,106.11) v2(169.11,103) v2(169.14,97.77) v2(169.74,103) v2(169.75,97.77)
LG_1.2V: length 9.9
  TOP w0.102: v2(60.38,18.54) 60.38,17.98 v1(60.81,17.55)
  IN2 w0.762: 60.57,17.72 61.02,17.27 61.02,15.88 62.67,14.22 66.54,14.22 ; 66.99,14.54 66.67,14.22
  vias: v2(59.94,18.99) v2(67.63,15.18) v2(67.63,14.54)
LGATE_CHG: length 9.7
  TOP w0.102: v2(113.91,158.56) 114.57,158.56 v1(114.66,158.47)
  IN1 w1.016: 123.12,161.92 119.69,161.92 118.04,160.27 116.01,160.27 115.25,159.51
  vias: v2(113.28,158.56) v2(124.39,161.95) v2(124.97,161.95)
LID_CL_SIO#: length 4.5
  TOP w0.102: RE25.2 RE26.2 CE8.1 187.2,85.01 188.35,83.87 UE1.41
LID_CLOSE#: length 266.1
  TOP w0.102: R6109.1 192.59,175.98 v2(192.67,176.05) ; RE26.1 186.24,87.4 185.81,87.83 184.53,87.83 181.98,90.37 v2(181.98,91.01) ; v3(107.39,173.01) 107.2,173.2 v2(106.67,173.2)
  IN1 w0.127: v2(104.45,167.41) 104.84,167.02 104.84,159.46 102.99,157.61 102.99,153.49 v2(103.37,153.11) ; v2(181.98,91.01) 181.74,91.01 180.59,89.85 175.61,89.85 173.32,92.14 167.32,92.14 162.81,96.65 162.81,97.92 161.79,98.93 161.41,98.93 157.76,102.58 155.7,102.58 151.57,106.71 151.57,120.04 150.83,120.78 150.83,126.82 150.03,127.62 150.03,132.18 151.28,133.43 151.28,134.72 150.49,135.51 150.49,135.9 151.12,136.54 151.12,139.04 150.87,139.3 150.87,141.06 152.08,142.26 152.08,150.3 150.55,151.83 150.55,160.38 161.52,171.35 167.08,171.35 171.51,175.77 180.97,175.77 181.25,176.05 v2(192.67,176.05)
  IN2 w0.127: v2(106.67,173.2) 107.79,174.32 120.02,174.32 121.43,175.73 145.18,175.73 146.42,176.97 170.68,176.97 173.22,179.51 186.24,179.51 189.71,176.05 v2(192.67,176.05)
  BOTTOM w0.102: v2(104.45,167.41) 104.58,167.54 104.58,168.64 105.66,169.72 105.74,169.72 106.03,170 106.03,171.25 106.67,171.89 v2(106.67,173.2) ; D5203.1 v2(103.37,153.11)
LID_CLOSE#_C: length 14.1
  TOP w0.102: PWR1.3 199.15,170.45 193.2,176.4 v1(193.2,176.99) 192.42,177.77 EC6105.1 191.92,176.9 R6109.2
LINE1-L_C: length 3.5
  BOTTOM w0.102: v1(193.2,23.55) 192.97,23.77 191.52,23.77 191.12,23.37 R2922.1
  BOTTOM w0.254: R2922.1 C2907.2
LINE1-L_R: length 2.6
  BOTTOM w0.102: v1(190.18,26.06) C2908.2
  BOTTOM w0.254: C2908.2 R2921.1
LINE1_L: length 6.2
  BOTTOM w0.203: 186.79,20.14 186.9,20.25 ; HDA27.22 184.97,19.78 185.32,20.14
  BOTTOM w0.254: C2907.1 187.85,22.18 v1(187.85,21.65) 187.85,21.2 186.9,20.25 ; 185.32,20.14 186.79,20.14
LINE1_R: length 7.7
  BOTTOM w0.203: 185.24,20.6 184.57,19.93 HDA27.21
  BOTTOM w0.254: 185.24,20.6 186.51,20.6 187.24,21.34 v1(187.24,23.19) 188.43,24.38 C2908.1
LINE1_VREFO_L: length 3.2
  BOTTOM w0.203: HDA27.31 188.69,16.09 188.8,16.2
  BOTTOM w0.254: 188.8,16.2 189.64,16.2 R2912.1
LINE1_VREFO_R: length 6.6
  BOTTOM w0.102: v1(192,18.34) 191.88,18.21 R2913.1
  BOTTOM w0.203: HDA27.30 188.49,16.49 188.8,16.79
  BOTTOM w0.254: 188.8,16.79 190.83,16.79 191.44,17.4 R2913.1
LOM_TCT: length 18.4
  TOP w0.102: C3106.1 v1(30.99,169.76)
  TOP w0.508: C3106.1 30.99,171.52 v2(30.24,172.26) 30.23,172.28 XF3102.4 27.81,172.28 27.3,171.77 27.3,168.97 27.81,168.47 XF3102.3
  BOTTOM w0.508: XF3102.3 27.68,168.47 27.3,168.85 27.3,171.77 27.81,172.28 XF3102.4 30.23,172.28 v2(30.24,172.26)
LP#_+VCCEOPIO: length 3.5
  BOTTOM w0.102: PR1201.1 38.05,57.3 38.05,59.57 v1(37.62,59.99)
LPC_LAD0: length 99.8
  TOP w0.102: v2(179.7,85.22) 179.99,85.22 181.15,84.06 UE1.59
  IN2 w0.127: v2(140.22,64.13) 140.56,63.8 140.56,62.09 144.03,58.61 148.18,58.61 152.16,54.64 153.47,54.64 155.34,52.76 155.34,51.94 155.57,51.71 v2(155.57,50.93)
  BOTTOM w0.076: UC1.AY13 131.15,75.18 130.94,74.98 130.87,74.77 130.87,74.58 130.71,74.2 130.71,73.8 135.19,69.32
  BOTTOM w0.102: v2(179.7,85.22) 179.62,85.22 v1(179.2,84.8) 178.13,83.73 172.16,83.73 170.8,82.37 170.27,81.84 170.27,74.75 168.73,73.22 168.73,71.06 167.24,69.57 167.24,68.69 166.02,67.48 159.99,67.48 159.38,66.86 157.24,66.86 156.76,66.39 152.17,66.39 147.83,62.05 142.92,62.05 140.84,64.13 v2(140.22,64.13) 139.54,64.13 135.19,68.48 135.19,69.32 ; v2(155.57,50.93) 155.57,50.68 154.8,49.91 DB1.8
LPC_LAD1: length 100.6
  TOP w0.102: UE1.60 180.75,84.04 180.02,84.77 179.51,84.77 179.06,85.22 v1(179.06,85.34) v2(179.06,85.85)
  IN2 w0.127: v2(139.81,64.57) 140.52,64.57 140.81,64.28 140.81,62.19 144.14,58.86 148.29,58.86 152.26,54.89 153.57,54.89 155.59,52.87 155.59,52.04 156.05,51.59 v2(156.05,50.57)
  BOTTOM w0.076: 134.23,70.53 130.88,73.89 130.88,74.16 130.93,74.28 131.15,74.49 UC1.BA13
  BOTTOM w0.102: 134.23,70.53 134.25,70.53 135.42,69.36 135.42,68.65 139.5,64.57 v2(139.81,64.57) 140.99,64.57 143.28,62.28 147.74,62.28 152.07,66.62 156.67,66.62 157.15,67.09 159.28,67.09 159.89,67.7 165.93,67.7 167.01,68.79 167.01,69.66 168.5,71.15 168.5,73.31 170.04,74.85 170.04,81.93 170.57,82.47 172.06,83.96 177.64,83.96 179.06,85.38 v2(179.06,85.85) ; DB1.7 155.3,49.8 156.05,50.55 v2(156.05,50.57)
LPC_LAD2: length 100.7
  TOP w0.102: v2(178.36,85.85) 178.36,85.53 179.38,84.52 179.89,84.52 180.35,84.06 UE1.61
  IN2 w0.127: v2(140.22,64.99) 140.52,64.99 141.06,64.45 141.06,62.3 144.25,59.12 148.39,59.12 152.37,55.14 155.46,55.14 157.1,53.5 157.1,51.38 156.52,50.8 156.52,50.45 v2(156.02,49.95)
  BOTTOM w0.076: UC1.BB13 131.15,73.89 135.65,69.38 135.65,69.21
  BOTTOM w0.102: v2(178.36,85.85) 178.36,85.46 v1(177.33,84.43) 177.09,84.19 171.97,84.19 170.34,82.56 169.81,82.03 169.81,74.94 168.27,73.41 168.27,71.25 166.78,69.76 166.78,68.88 165.83,67.93 159.8,67.93 159.19,67.32 156.56,67.32 156.26,67.63 152.76,67.63 147.64,62.51 143.38,62.51 140.9,64.99 v2(140.22,64.99) 139.4,64.99 135.65,68.74 135.65,69.21 ; DB1.6 155.8,49.72 156.02,49.94 v2(156.02,49.95)
LPC_LAD3: length 102.4
  TOP w0.102: UE1.62 179.95,83.95 179.65,84.25 179.27,84.25 177.73,85.79 v2(177.73,85.85)
  IN2 w0.127: v2(157.17,50.6) 157.36,50.79 157.36,53.6 154.83,56.13 151.74,56.13 148.5,59.37 144.35,59.37 141.32,62.4 141.32,64.61 140.51,65.42 v2(139.6,65.42)
  BOTTOM w0.076: UC1.AY12 131.41,75.38 131.41,74.76 131.58,74.6 131.58,73.69 135.88,69.39
  BOTTOM w0.102: 135.88,69.39 135.88,68.85 139.31,65.42 v2(139.6,65.42) 140.79,65.42 143.26,62.96 v1(143.76,62.96) 143.98,62.74 147.55,62.74 152.67,67.86 156.35,67.86 156.66,67.55 159.09,67.55 159.7,68.16 165.74,68.16 166.55,68.98 166.55,69.85 168.04,71.34 168.04,73.5 169.58,75.04 169.58,82.12 170.11,82.66 172.01,84.56 176.82,84.56 177.73,85.47 v2(177.73,85.85) ; DB1.5 156.3,49.63 156.61,49.94 156.61,50.04 v2(157.17,50.6)
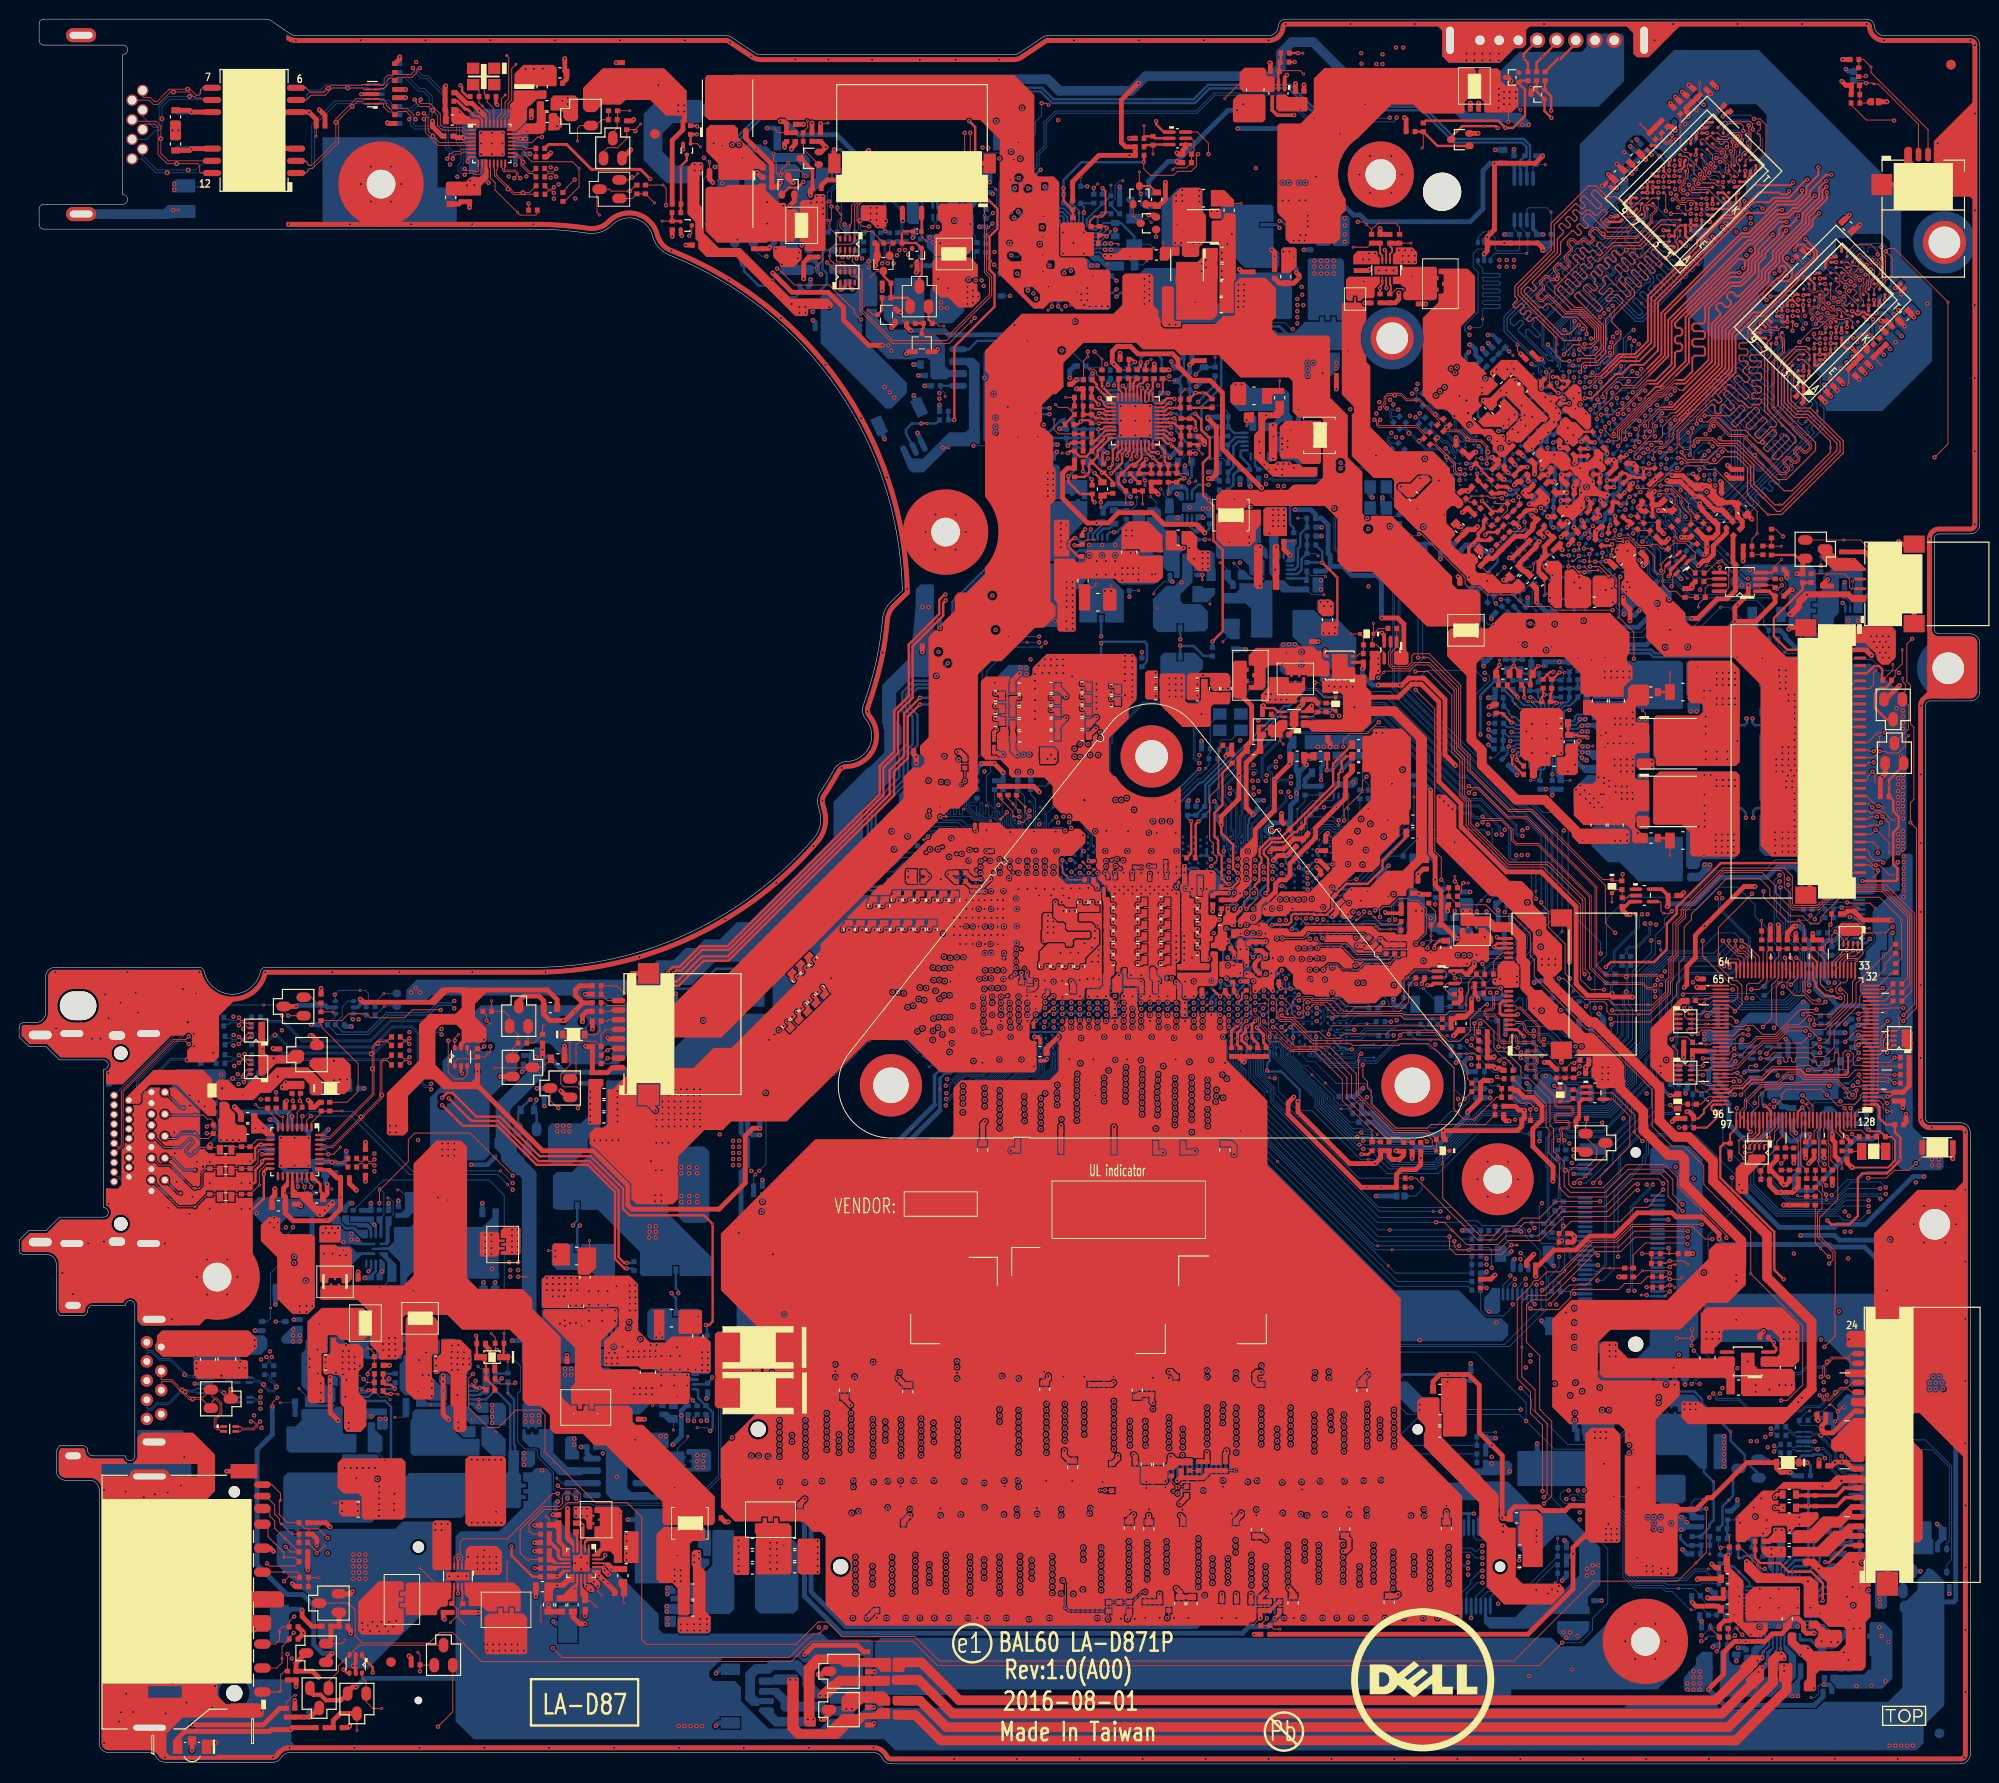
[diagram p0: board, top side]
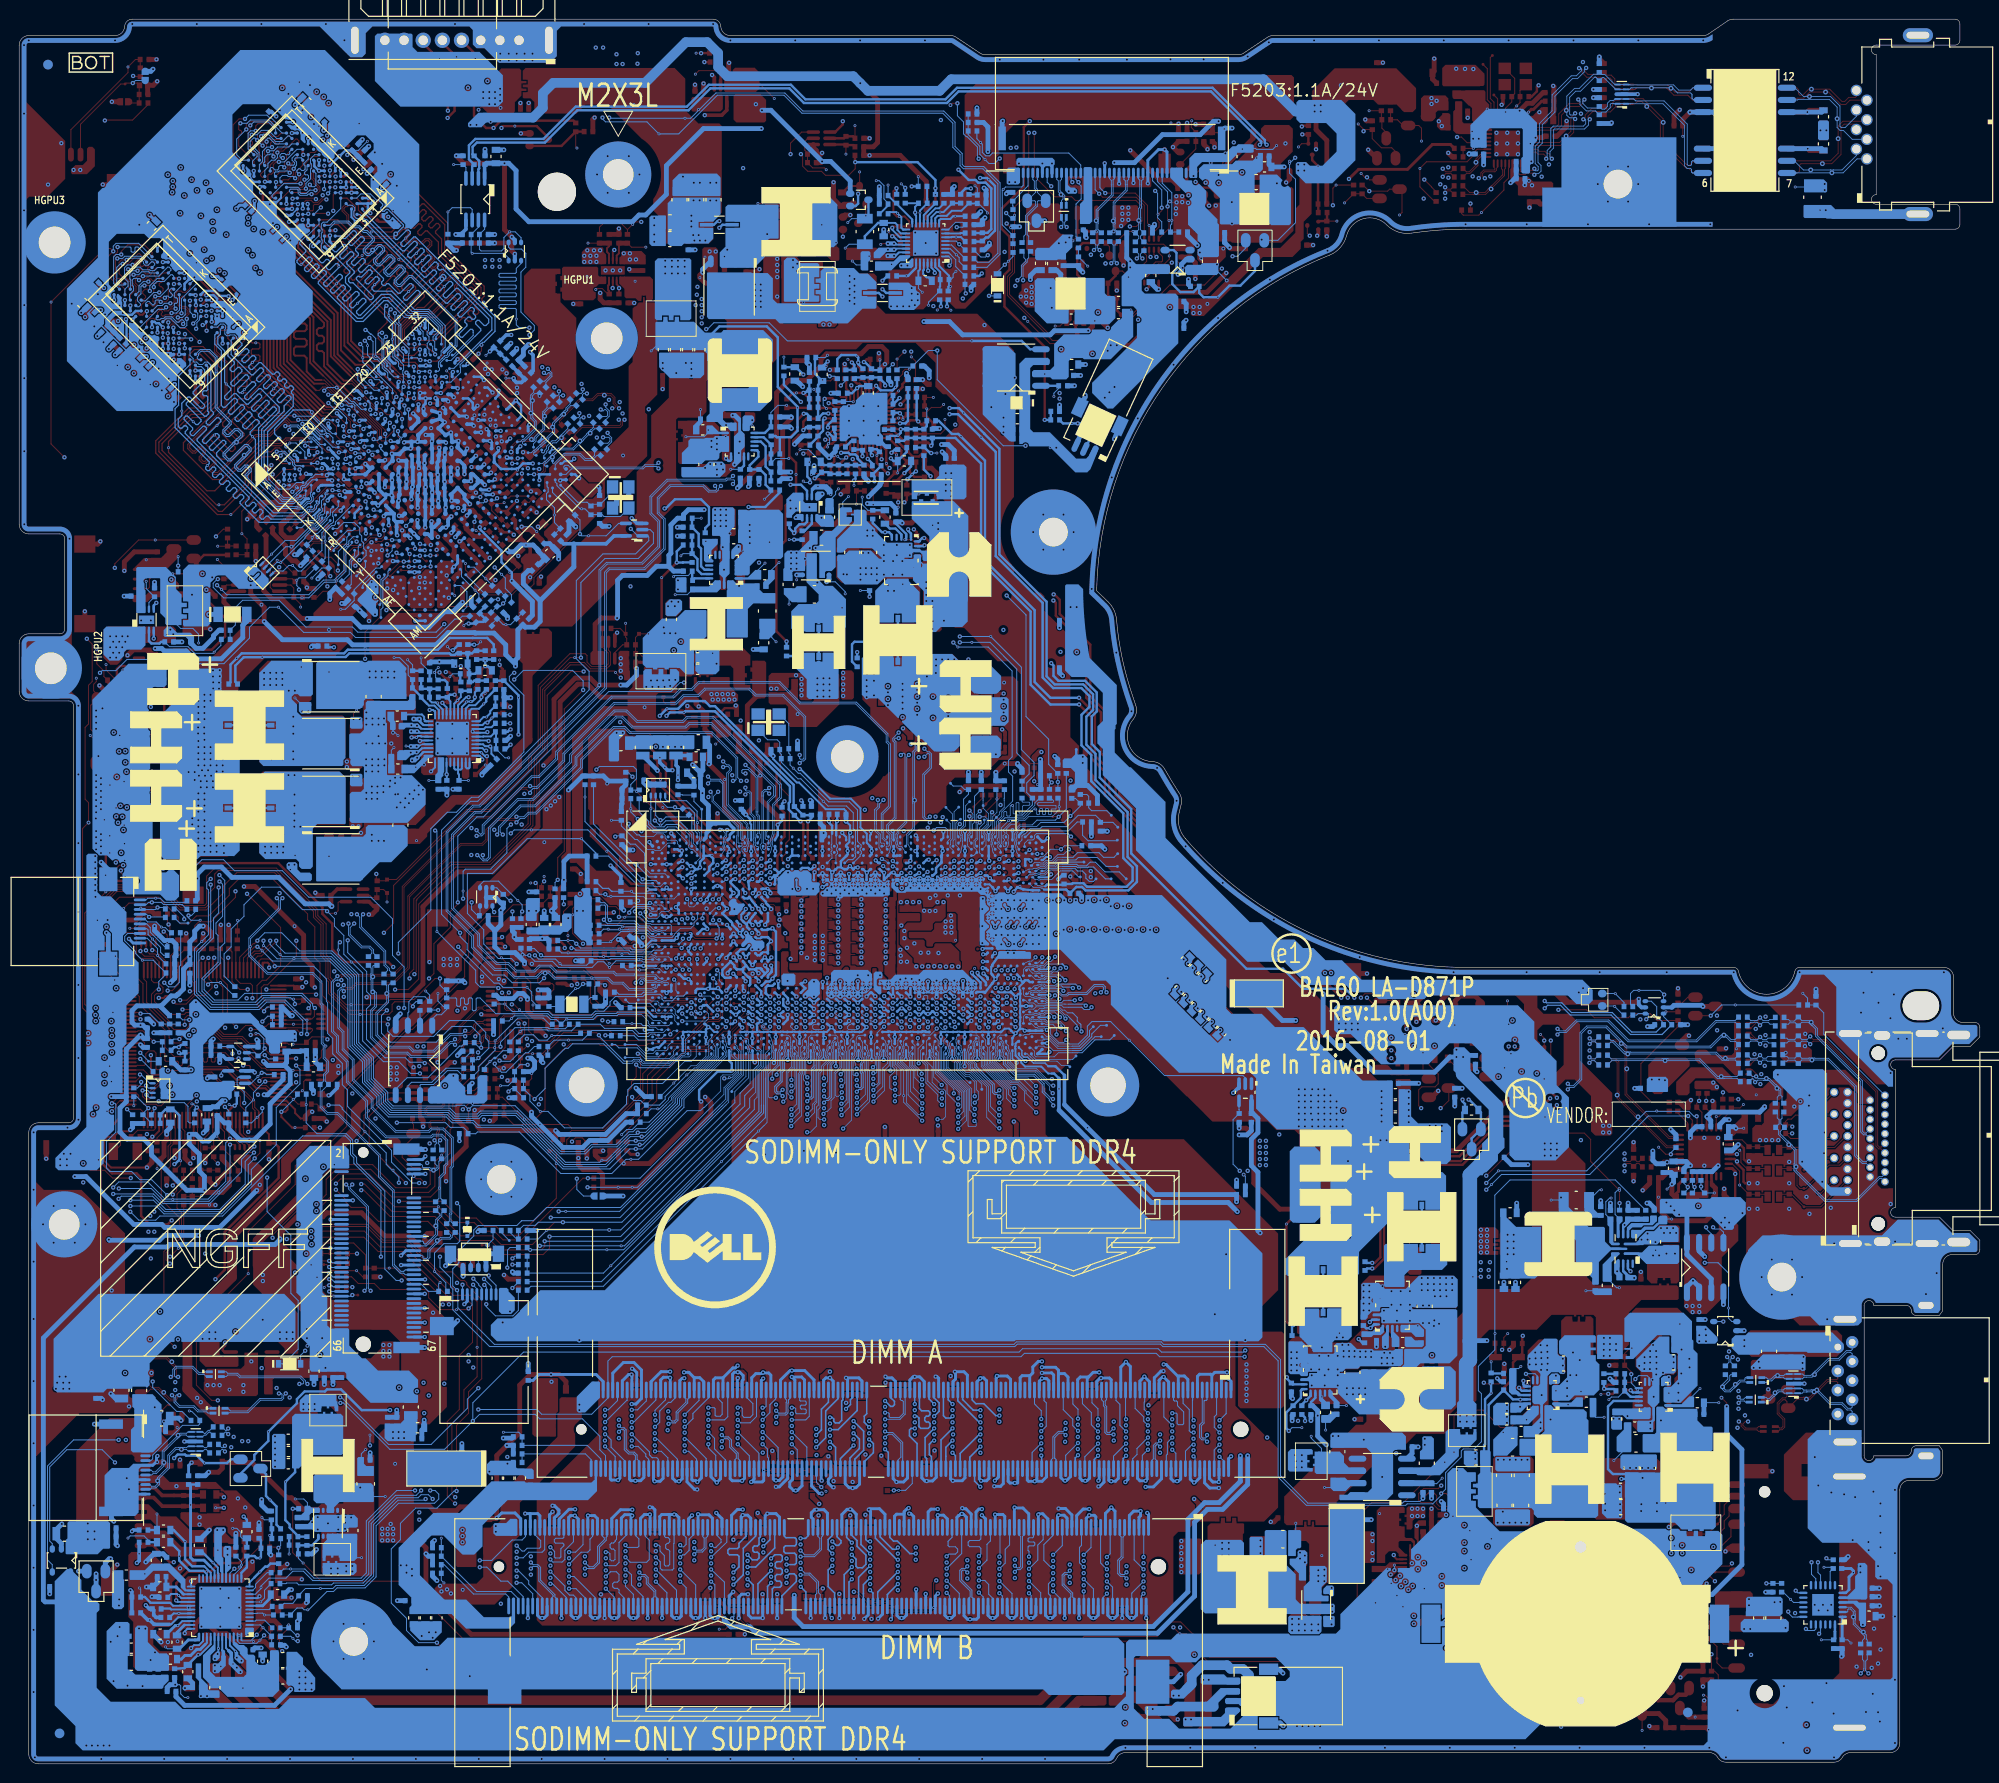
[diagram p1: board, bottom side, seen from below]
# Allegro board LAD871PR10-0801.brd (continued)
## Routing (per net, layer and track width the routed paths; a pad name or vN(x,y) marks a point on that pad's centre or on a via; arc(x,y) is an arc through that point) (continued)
LPC_LFRAME#: length 102.8
  TOP w0.102: v2(179.7,85.85) 179.7,85.85 180.01,85.54 180.14,85.54 v1(180.44,85.23) 181.55,84.13 UE1.58
  IN2 w0.127: v2(157.19,49.97) 157.61,50.39 157.61,53.71 154.93,56.39 151.84,56.39 148.6,59.63 144.46,59.63 141.57,62.51 141.57,64.81 140.71,65.68 140.18,65.68 v2(140.01,65.84)
  BOTTOM w0.076: UC1.BA12 131.74,75 131.74,73.76 133.6,71.91 133.61,71.91 136.11,69.41
  BOTTOM w0.102: DB1.4 156.8,49.55 157.19,49.95 v2(157.19,49.97) ; 136.11,69.41 136.11,68.95 139.19,65.86 139.99,65.86 v2(140.01,65.84) 140.2,65.65 140.89,65.65 142.18,64.35 144.76,64.35 145.48,63.63 147.93,63.63 147.93,63.63 148.12,63.63 152.58,68.09 156.44,68.09 156.75,67.78 159,67.78 159.61,68.39 165.64,68.39 166.32,69.07 166.32,69.94 167.82,71.44 167.82,73.6 169.35,75.13 169.35,82.22 169.88,82.75 171.92,84.79 175.27,84.79 177.16,86.68 178.94,86.68 179.7,85.92 v2(179.7,85.85)
LPSS_UART2_CTS#: length 12.3
  BOTTOM w0.076: 140.45,84.45 138.57,84.45 138.49,84.37 138.18,84.27 138.08,84.16 136.79,84.16 UC1.AD4
  BOTTOM w0.102: 140.45,84.45 140.9,84.45 141.03,84.58 v1(147.28,84.58) 147.96,84.58 RC382.1
LX1_VGA: length 11.4
  IN2 w1.016: 164.59,108.65 164.78,108.65 166.36,110.24 167.63,110.24 169.17,111.77 174.67,111.77
  vias: v1(175.11,114.4) v2(163.04,108.27) v2(163.63,108.33) v2(175.79,111.93) v2(175.95,109.22) v2(175.95,108.2) v2(175.95,107.44) v2(175.96,105.6) v2(175.95,104.77) v2(176.42,111.93) v2(177.09,113.79) v2(177.09,113.16) v2(177.09,112.52) v2(177.09,111.12) v2(177.09,110.49) v2(177.09,104.77) v2(177.11,105.56) v2(177.73,113.79) v2(177.73,113.16) v2(177.73,112.52) v2(177.73,111.12) v2(177.73,110.49) v2(178.21,105.59) v2(178.23,104.77) v2(178.36,113.79) v2(178.36,113.16) v2(178.36,112.52) v2(178.36,111.12) v2(178.36,110.49) v2(179,113.79) v2(179,113.16) v2(179,112.52) v2(179,111.12) v2(179,110.49) v2(179.25,106.68)
LX2_VGA: length 12
  IN1 w0.762: 175.05,103.05 175.04,103.06 171.62,103.06 170.61,102.04 168.81,102.04 168.12,102.74 166.76,102.74 164.81,104.69 164.73,104.69 164.73,104.78 164.68,104.83
  vias: v1(175.76,94.74) v2(163.08,105.52) v2(163.7,105.47) v2(175.22,97.74) v2(175.82,103.12) v2(175.82,101.09) v2(175.82,99.95) v2(175.84,99.11) v2(175.84,98.39) v2(175.84,97.75) v2(176.46,103.12) v2(176.99,96.93) v2(176.99,96.29) v2(176.99,95.66) v2(177.09,102.62) v2(177.09,101.98) v2(177.02,95.05) v2(177.63,96.93) v2(177.63,96.29) v2(177.63,95.66) v2(177.63,95.02) v2(177.73,102.62) v2(177.73,101.98) v2(178.26,96.93) v2(178.26,96.29) v2(178.26,95.66) v2(178.26,95.02) v2(178.36,102.62) v2(178.36,101.98) v2(178.9,96.93) v2(178.9,96.29) v2(178.9,95.66) v2(178.9,95.02) v2(179,102.62) v2(179,101.98)
LX_1.2V: length 5.6
  IN2 w0.762: 61.68,18.51 64,16.19 66.35,16.19
  vias: v1(61.41,18.82) v2(60.51,19.62) v2(60.95,19.18) v2(67.56,16.45) v2(67.56,15.88)
LX_1.8VALW: length 2
  BOTTOM w0.102: PR506.1 v1(166.36,27.88)
LX_3V: length 4.9
  TOP w0.508: v2(32.44,40.32) v2(32.44,39.69) v1(32.44,38.66) 32.44,36.64 v2(33.27,35.81)
LX_5V: length 4.8
  TOP w0.508: v2(44.79,35.92) 44.57,36.13 44.54,36.13 44.23,36.45 v1(44.23,38.91) v2(44.23,39.85) v2(44.23,40.49)
LX_+1.5VGPU: length 1
  BOTTOM w0.254: v2(130.8,136.14) 130.56,135.9 130.37,135.9 130.28,135.99 PU1400.6
  vias: v1(130.84,138.46) v2(126.9,143.87) v2(127.54,143.87) v2(130.8,139.64)
LX_+1VALW:
  vias: v1(129.04,126.48) v2(129.5,126.92) v2(129.44,122.86)
MAA_0: length 64.6
  TOP w0.102: v2(165.45,139.45) 165.45,139.08 166.2,138.33 166.52,138.33 166.74,138.55 166.74,139.21 170.01,142.48 170.11,142.48 170.89,143.25 171.28,143.25 172.81,144.78 172.83,144.78 ; UV20.N3 191.62,152.67 191.36,152.93 191.36,153.08 191.67,153.38 191.67,153.56 191.42,153.81 191.11,153.81 v2(190.92,153.62) ; v2(177.04,167.49) 177.62,167.49 178.36,166.76 UV18.N3
  TOP w0.201: 172.83,144.78 174.2,146.15 174.2,150.75 178.54,155.09 179.63,155.09 180.4,155.85 180.4,156.9 181.11,157.61 181.11,158.3 183.64,160.83 v2(184.36,160.83)
  IN1 w0.127: v2(190.92,153.62) 191.12,153.82 191.12,154 190.68,154.43 190.68,154.63 188.37,156.94 188.37,158.07 185.74,160.7 184.5,160.7 v2(184.36,160.83) 183.25,161.94 183.25,162.39 180.93,164.71 180.93,165.65 180.77,165.81 180.38,165.81 180.32,165.75 179.92,165.75 178.42,167.25 177.86,167.25 177.63,167.48 177.63,167.49 177.62,167.49 v2(177.04,167.49)
  BOTTOM w0.102: v2(177.04,167.49) 177.21,167.49 177.34,167.63 177.34,167.79 177.17,167.96 176.84,167.96 176.71,167.83 176.42,167.83 176.32,167.93 176.32,168.17 UV17.N3 ; 165.45,138.59 v2(165.45,139.45) ; v2(190.92,153.62) 190.92,154.16 190.14,154.93 UV19.N3
MAA_1: length 63.1
  TOP w0.102: UV20.P7 190.18,155.55 190.32,155.55 190.47,155.41 190.47,155.25 190.27,155.05 190.27,154.91 190.51,154.67 190.61,154.67 190.81,154.88 190.97,154.88 191.07,154.78 v2(191.07,154.6) ; v2(164.36,141.67) 164.57,141.88 165.05,141.88 165.62,142.45 165.62,143.12 166.65,144.14 166.93,144.14 167.32,143.76 168.56,143.76 169.96,145.16 ; v2(178.02,167.65) 178.02,168.2 177.79,168.44 177.18,168.44 UV18.P7
  TOP w0.201: 169.96,145.16 171.68,146.88 171.68,151.18 179.78,159.27 180.58,159.27 183.39,162.08 v2(183.92,162.08)
  IN1 w0.127: v2(178.02,167.65) 178.16,167.51 179.12,167.51 179.25,167.39 179.25,167.2 179.37,167.07 179.63,167.07 179.76,167.2 179.76,167.39 179.88,167.51 180.38,167.51 180.55,167.35 180.55,167.17 180.19,166.82 180.19,166.64 180.37,166.46 180.55,166.46 180.91,166.81 181.09,166.81 181.58,166.32 181.58,164.53 183.73,162.38 183.73,162.27 v2(183.92,162.08) 184.15,162.08 185.21,161.03 185.88,161.03 188.6,158.31 188.6,157.03 191.04,154.6 v2(191.07,154.6)
  BOTTOM w0.102: v2(191.07,154.6) 191.61,154.6 192.05,154.16 192.05,153.58 UV19.P7 ; UV1.J20 164.32,141.63 v2(164.36,141.67) ; UV17.P7 179.04,166.81 179.04,166.97 178.94,167.07 178.94,167.58 178.68,167.83 178.44,167.83 178.36,167.9 178.12,167.9 178.02,167.8 v2(178.02,167.65)
MAA_2: length 68.9
  TOP w0.102: v2(192.62,155.32) 192.87,155.32 193.03,155.15 193.03,154.92 192.7,154.59 192.7,154.45 192.36,154.11 192.36,153.27 UV20.P3 ; v2(178.74,169.19) 178.74,168.63 178.97,168.41 178.97,167.89 178.81,167.74 178.81,166.81 UV18.P3
  TOP w0.201: v2(186,164.11) 186,163.75 185.23,162.98 183.29,162.98 182.08,161.77 180.29,161.77 170.98,152.46 170.98,147.43 169.48,145.92 168.14,145.92 167.19,144.97 166.62,144.97 164.09,142.44 v2(163.36,142.44)
  IN1 w0.127: v2(178.74,169.19) 179.3,169.19 179.57,168.92 181.08,168.92 181.89,168.11 182.07,168.11 182.37,168.4 182.62,168.4 182.83,168.19 182.83,168.01 182.54,167.71 182.54,167.53 182.72,167.35 182.9,167.35 183.19,167.65 183.37,167.65 185.82,165.21 185.82,164.92 186.16,164.58 186.16,164.27 v2(186,164.11) 191.45,158.67 191.45,157.04 192.62,155.87 v2(192.62,155.32)
  BOTTOM w0.102: UV1.H23 163.33,142.47 v2(163.36,142.44) ; UV19.P3 190.93,155.5 191.05,155.63 191.77,155.63 192.08,155.32 v2(192.62,155.32) ; UV17.P3 177.85,168.96 178.45,169.57 178.6,169.57 178.78,169.38 178.78,169.24 v2(178.74,169.19)
MAA_3: length 71.2
  TOP w0.102: v2(178.59,168.21) 178.6,168.2 178.6,168.06 178.6,166.56 179.08,166.08 179.37,165.8 179.37,165.66 179.17,165.46 179.03,165.46 UV18.N2 ; UV20.N2 192.39,152.64 192.06,152.96 192.06,154.1 192.43,154.47 192.43,154.91 192.18,155.16 v2(191.64,155.16) ; 165.16,144.84 165.04,144.73 164.59,144.73 164,144.13 v2(163.86,144.13)
  TOP w0.201: 178.81,161.22 181.48,163.89 183.62,163.89 183.81,163.7 184.46,163.7 184.66,163.9 v2(184.66,164.03) ; 165.16,144.84 167.04,146.72 168.75,146.72 170.27,148.24 170.27,152.94 175.44,158.11 175.44,158.37
  TOP w0.203: 178.81,161.22 177.82,161.22 175.44,158.84 175.44,158.37
  IN1 w0.127: v2(191.64,155.16) 191.13,155.67 191.13,156.29 189.5,157.92 189.5,158.34 186.73,161.11 186.73,161.81 184.66,163.89 v2(184.66,164.03) 184.69,164.06 184.69,164.24 184.56,164.36 184.38,164.36 184.1,164.08 184.1,163.87 184.48,163.49 184.48,163.31 184.26,163.09 184.08,163.09 183.1,164.07 183.1,164.25 183.3,164.45 183.3,164.63 183.12,164.81 182.94,164.81 182.74,164.61 182.56,164.61 182.38,164.79 182.38,164.97 182.53,165.12 182.53,165.3 182.3,165.52 182.3,166.24 180.48,168.06 178.74,168.06 v2(178.59,168.21)
  BOTTOM w0.102: UV1.G23 163.9,144.09 v2(163.86,144.13) ; v2(178.59,168.21) 178.56,168.24 177.98,168.24 177.59,168.64 176.42,168.64 176.1,168.96 UV17.N2 ; UV19.N2 188.72,155.78 188.72,155.92 188.91,156.11 189.05,156.11 189.99,155.18 191.62,155.18 v2(191.64,155.16)
MAA_4: length 73.3
  TOP w0.102: UV20.P8 190.2,156.07 190.78,155.49 190.78,155.4 191.09,155.08 191.18,155.08 191.48,154.78 192.02,154.78 v2(192.05,154.75) ; 165.22,145.35 164.8,144.93 164.51,144.93 164.31,144.72 163.51,144.72 v2(163.42,144.63) ; v2(178.17,168.63) 178.32,168.77 178.32,169.05 178.16,169.2 177.91,169.2 177.8,169.1 177.8,169.02 177.7,168.92 177.5,168.92 177.4,169.02 177.4,169.1 177.3,169.2 177.09,169.2 176.5,169.79 176.36,169.79 UV18.P8
  TOP w0.201: v2(185.05,164.91) 184.8,164.65 182.3,164.65 ; 179.55,162.48 178.6,161.52 177.69,161.52 175.06,158.89 175.06,158.31 169.92,153.16 169.92,148.4 168.54,147.02 166.89,147.02 165.22,145.35
  TOP w0.203: 182.3,164.65 181.02,164.65 179.55,163.18 179.55,162.48
  IN1 w0.127: v2(178.17,168.63) 178.75,168.63 178.99,168.38 180.69,168.38 182.64,166.43 182.94,166.43 183.2,166.69 183.4,166.69 183.58,166.51 183.58,166.33 182.89,165.64 182.89,165.4 183.07,165.22 183.25,165.22 183.97,165.94 184.15,165.94 184.32,165.77 184.32,165.53 183.63,164.84 183.63,164.66 183.82,164.47 184.02,164.47 184.67,165.12 184.85,165.12 v2(185.05,164.91) 185.16,164.81 185.16,163.9 187.06,161.99 187.06,161.24 189.73,158.58 189.73,158.11 191.78,156.06 191.78,155.57 192.05,155.31 v2(192.05,154.75)
  BOTTOM w0.102: v2(178.17,168.63) 178.71,168.63 179.17,168.17 179.17,167.13 179.49,166.81 UV17.P8 ; v2(192.05,154.75) 192.24,154.94 192.59,154.94 192.75,154.77 192.75,154.24 192.63,154.11 192.63,153.67 193.03,153.26 193.03,152.75 UV19.P8 ; v2(163.42,144.63) 163.33,144.55 UV1.G24
MAA_5: length 76.1
  TOP w0.102: UV20.P2 192.95,153.2 192.59,153.56 192.59,153.92 192.91,154.24 192.91,154.5 193.56,155.16 193.56,155.69 193.37,155.88 v2(193.18,155.88) ; 165.51,144.75 165.28,144.52 164.79,144.52 164.41,144.13 164.4,144.13 163.83,143.56 v2(163.32,143.56) ; UV18.P2 179.49,166.66 179.12,167.04 179.12,167.48 179.48,167.85 179.48,168.28 179.54,168.33 179.54,168.95 179.33,169.16 179.33,169.74 v2(179.31,169.76)
  TOP w0.201: v2(186.57,165.23) 186.43,165.23 185.55,164.34 185.55,164.27 184.61,163.34 183.02,163.34 182.56,162.88 180.89,162.88 179.16,161.15 179.16,161.14 170.63,152.61 170.63,147.91 169.02,146.3 167.06,146.3 166.7,145.95 166.7,145.94 165.51,144.75
  IN1 w0.127: v2(193.18,155.88) 193.18,156.44 192.11,157.52 192.11,159.32 190.19,161.23 190.19,161.84 188.54,163.49 188.3,163.49 v2(186.57,165.23) 186.57,165.39 182.68,169.28 182.23,169.28 182.12,169.38 180.63,169.38 180.49,169.52 180.12,169.52 179.27,170.37 178.3,170.37 178.17,170.24 178.17,169.88 178.3,169.76 v2(179.31,169.76)
  BOTTOM w0.102: v2(193.18,155.88) 193.11,155.96 192.53,155.96 192.37,156.11 191.92,156.11 191.64,155.83 190.94,155.83 190.85,155.74 190.43,155.74 190.11,156.07 UV19.P2 ; v2(163.32,143.56) 163.31,143.54 UV1.H24 ; UV17.P2 176.36,169.79 176.5,169.79 177.09,169.2 177.8,169.2 178.58,169.98 179.09,169.98 v2(179.31,169.76)
MAA_6: length 72.4
  TOP w0.102: v2(179.72,169.34) 179.69,169.38 179.69,169.94 179.49,170.14 178.51,170.14 178.11,169.74 177.57,169.74 177.21,170.09 UV18.R8 ; UV20.R8 190.8,156.63 191.22,156.21 191.36,156.21 191.43,156.28 191.57,156.28 191.66,156.19 191.8,156.19 191.95,156.33 191.95,156.48 191.74,156.68 191.74,156.83 191.92,157 192.06,157 v2(192.72,156.34) ; 169.86,144.27 168.78,143.19 168.78,142.91 167.25,141.38 166.84,141.38 166.18,140.72 v2(165.03,140.72)
  TOP w0.201: 169.86,144.27 170.68,144.27 172.39,145.98 172.39,150.44 180.52,158.57 180.87,158.57 183.58,161.28 184.26,161.28 184.27,161.29 184.58,161.29 185.21,161.92 185.67,161.92 v2(187.32,163.58)
  IN1 w0.127: v2(192.72,156.34) 191.78,157.29 191.78,159.18 189.35,161.6 189.35,161.78 189.47,161.91 189.47,162.09 189.29,162.27 189.11,162.27 188.99,162.14 188.81,162.14 188.63,162.32 188.63,162.5 188.75,162.62 188.75,162.8 188.57,162.98 188.39,162.98 188.27,162.86 188.09,162.86 187.38,163.58 v2(187.32,163.58) 187.12,163.78 187.12,164.09 186.15,165.06 186.15,165.34 182.64,168.85 182.24,168.85 181.93,169.15 180.53,169.15 180.39,169.29 179.78,169.29 v2(179.72,169.34)
  BOTTOM w0.102: UV19.R8 193.52,153.8 193.19,154.13 193.19,154.6 193.56,154.97 193.56,156.04 193.26,156.34 v2(192.72,156.34) ; v2(165.03,140.72) 165.09,140.65 165.09,140.09 UV1.J19 ; UV17.R8 180.21,166.85 180.21,167.16 179.73,167.64 179.73,167.97 180.45,168.69 180.45,169.22 180.1,169.58 179.95,169.58 v2(179.72,169.34)
MAA_7: length 80.5
  TOP w0.102: UV20.R2 193.52,153.81 194.7,154.99 194.7,157.26 194.28,157.67 v2(194.28,158.21) ; v2(181.47,171.11) 181.65,170.93 181.65,170.48 181.55,170.38 181.45,170.38 181.35,170.27 181.35,170.07 181.45,169.97 181.55,169.97 181.65,169.87 181.65,168.75 180.06,167.16 UV18.R2 ; 170.01,144.78 168.74,143.51 167.22,143.51 164.61,140.89 v2(164.61,140.27)
  TOP w0.201: 170.01,144.78 172.04,146.81 172.04,150.58 180.37,158.92 180.73,158.92 183.43,161.63 184.11,161.63 184.12,161.64 184.43,161.64 185.07,162.28 185.53,162.28 186.81,163.56 186.81,164.03 188.53,165.75 v2(189.05,165.75)
  IN1 w0.127: v2(181.47,171.11) 183.68,171.11 188.92,165.87 v2(189.05,165.75) 194.28,160.51 v2(194.28,158.21)
  BOTTOM w0.102: UV19.R2 190.37,156.87 190.82,156.87 192.16,158.21 192.37,158.21 192.47,158.11 192.47,157.77 192.57,157.67 192.77,157.67 192.87,157.77 192.87,158.11 192.98,158.21 v2(194.28,158.21) ; UV17.R2 177.12,170.09 178.48,171.45 180.43,171.45 180.77,171.11 v2(181.47,171.11) ; v2(164.61,140.27) UV1.K19
MAA_8: length 75.7
  TOP w0.102: 171.51,141.5 171.21,141.5 169.65,139.94 169.46,139.94 169.01,139.49 169.01,139.07 168.9,138.96 168.9,138.34 168.54,137.97 v2(168.54,137.38) ; UV20.T8 190.69,157.65 191.48,158.43 193.22,158.43 193.9,157.76 v2(193.9,157.43) ; UV18.T8 177.84,171.27 180.64,171.27 180.85,171.06 v2(180.85,170.48)
  TOP w0.201: 171.51,141.5 172.47,141.5 172.72,141.75 172.72,141.8 176.95,146.03 176.95,150.08 181.81,154.94 181.81,155.77 182.95,156.91 182.95,157.77 186.05,160.87 186.05,161.66 187.78,163.39 187.78,164.39 188.48,165.09 v2(188.52,165.09)
  IN1 w0.127: v2(193.9,157.43) 193.56,157.77 193.56,160.05 v2(188.52,165.09) 188.52,165.09 183.24,170.37 180.96,170.37 v2(180.85,170.48)
  BOTTOM w0.102: UV1.J14 168.46,137.46 v2(168.54,137.38) ; UV17.T8 181.29,167.26 181.86,167.83 181.86,169.47 v2(180.85,170.48) ; UV19.T8 194.69,154.41 194.69,157.17 194.44,157.43 v2(193.9,157.43)
MAA_9: length 74.6
  TOP w0.102: UV20.R3 193.16,154.01 193.16,154.47 194.13,155.44 194.13,156.61 193.87,156.86 v2(193.33,156.86) ; 172.83,140.91 172.33,140.91 171.91,140.48 171.18,140.48 170.37,139.68 170.37,139.36 170.52,139.21 170.52,138.84 169.95,138.27 169.95,138.24 168.63,136.92 v2(168.1,136.92) ; UV18.R3 179.63,167.26 179.73,167.37 179.73,167.97 179.92,168.15 180.09,168.15 180.46,168.53 180.46,168.73 180.36,168.84 180.31,168.84 180.21,168.94 180.21,169.14 180.31,169.24 180.36,169.24 180.46,169.34 180.46,169.73 v2(180.29,169.91)
  TOP w0.201: v2(188.59,163.91) 188.59,163.2 186.75,161.36 186.75,160.58 183.65,157.48 183.65,156.62 182.52,155.48 182.52,154.65 177.65,149.78 177.65,145.73 172.83,140.91
  IN1 w0.127: v2(193.33,156.86) 193.27,156.86 192.9,157.23 192.9,157.71 192.77,157.84 192.46,157.84 192.33,157.96 192.33,158.22 192.46,158.34 192.77,158.34 192.9,158.47 192.9,158.99 192.45,159.44 192.45,159.62 192.66,159.84 192.66,160.02 192.48,160.19 192.3,160.19 192.09,159.98 191.91,159.98 190.52,161.37 190.52,161.98 v2(188.59,163.91) 188.51,163.91 182.71,169.71 180.73,169.71 180.53,169.91 v2(180.29,169.91)
  BOTTOM w0.102: v2(180.29,169.91) 179.75,169.91 179.29,170.37 178.53,170.37 177.69,169.53 UV17.R3 ; v2(193.33,156.86) 193.16,157.04 191.95,157.04 191.58,156.67 191.58,156.5 191.39,156.31 191.09,156.31 190.74,156.67 190.59,156.67 190.41,156.49 190.41,156.34 UV19.R3 ; UV1.K14 167.17,136.92 v2(168.1,136.92)
MAA_10: length 66.8
  TOP w0.102: v2(169.05,136.27) 168.81,136.03 168.66,136.03 168.45,136.25 168.45,136.39 170,137.94 170.89,137.94 171.44,138.49 171.44,139.46 172.57,140.59 173.01,140.59 ; UV18.L7 174.96,166.73 175.74,165.96 175.74,165.4 v2(175.76,165.38) ; UV20.L7 188.61,153.8 188.72,153.7 188.72,153.33 188.61,153.23 188.49,153.23 188.39,153.12 188.39,152.48 188.53,152.34 v2(188.78,152.34)
  TOP w0.201: v2(183.65,155.74) 183.65,156.05 183.85,156.25 184.11,156.25 184.33,156.03 184.33,155.74 183.59,155 183.44,155 178.01,149.57 178.01,145.59 173.01,140.59
  IN1 w0.127: v2(175.76,165.38) 176.24,165.38 179.39,162.24 180.34,162.24 181.29,161.3 181.29,157.9 183.44,155.74 v2(183.65,155.74) 183.82,155.91 183.82,156.09 181.73,158.18 181.73,158.42 181.92,158.61 182.1,158.61 185.13,155.57 186.29,155.57 188.72,153.15 188.72,152.4 v2(188.78,152.34)
  BOTTOM w0.102: UV19.L7 190.12,152.11 189.63,152.11 189.4,152.33 188.78,152.33 v2(188.78,152.34) ; v2(169.05,136.27) 169.13,136.35 169.36,136.35 169.54,136.17 169.54,135.89 UV1.J11 ; UV17.L7 177.35,165.12 177.35,165.42 177.09,165.68 176.59,165.68 176.48,165.57 175.94,165.57 v2(175.76,165.38)
MAA_11: length 70
  TOP w0.102: v2(192.2,155.73) 192.01,155.93 191.86,155.93 191.33,155.4 191.12,155.4 190.97,155.54 190.97,155.68 191.14,155.85 191.14,156 190.99,156.15 190.77,156.15 UV20.R7 ; v2(179.15,168.78) 179.12,168.81 179.12,169.35 178.9,169.57 178.39,169.57 178.24,169.42 177.34,169.42 UV18.R7 ; 173.22,140.09 172.12,139 172.12,138.09 171.41,137.38 170.71,137.38 170.04,136.71 v2(169.48,136.71)
  TOP w0.201: 173.22,140.09 173.22,140.3 178.36,145.44 178.36,149.36 183.65,154.65 184.55,154.65 184.97,155.07 184.97,155.88 184,156.85 184,157.33 187.11,160.43 187.11,161.07 v2(187.76,161.73)
  IN1 w0.127: v2(192.2,155.73) 192.2,155.96 190.68,157.48 190.68,157.73 191.19,158.24 191.19,158.45 190.98,158.67 190.79,158.67 190.66,158.53 190.48,158.53 190.28,158.73 190.28,158.91 190.41,159.05 190.41,159.23 190.18,159.47 190,159.47 189.75,159.21 189.57,159.21 189.39,159.39 189.39,159.57 189.64,159.82 189.64,160 189.46,160.18 189.28,160.18 189.03,159.93 188.85,159.93 188.67,160.11 188.67,160.29 188.92,160.54 188.92,160.72 188.74,160.9 188.56,160.9 188.31,160.65 188.13,160.65 187.95,160.83 187.95,161.01 188.2,161.26 188.2,161.44 187.92,161.73 v2(187.76,161.73) 187.76,161.76 185.49,164.03 185.49,165.07 183.53,167.02 182.52,167.02 180.91,168.63 179.31,168.63 v2(179.15,168.78)
  BOTTOM w0.102: UV1.J13 168.66,136.71 v2(169.48,136.71) ; UV17.R7 179.53,167.3 179.53,168.05 179.95,168.47 179.95,168.61 179.55,169 179.38,169 v2(179.15,168.78) ; v2(192.2,155.73) 192.74,155.73 193,155.47 193,154.88 192.95,154.83 UV19.R7
MAA_12: length 67
  TOP w0.102: v2(176.89,166.52) 176.86,166.55 176.86,167.09 176.66,167.28 176.66,167.83 UV18.N7 ; v2(189.94,153.47) 189.73,153.47 189.54,153.66 189.54,153.89 189.71,154.06 189.81,154.06 189.94,154.19 189.94,154.38 189.81,154.51 189.69,154.51 189.56,154.64 UV20.N7 ; v2(170.49,136.1) 170.49,136.63 171.03,137.17 171.49,137.17 172.57,138.25 v1(172.57,138.67) 172.57,139.09 173.52,140.03
  TOP w0.201: v2(185.24,157.92) 185.24,158.07 185.65,158.47 186.14,158.47 186.63,157.97 186.93,157.97 187.27,157.63 187.27,157.09 186.18,156 186.09,156 185.33,155.24 185.33,154.92 181.79,151.38 180.9,151.38 178.71,149.19 178.71,145.3 173.52,140.1 173.52,140.03
  IN1 w0.127: v2(176.89,166.52) 177.35,166.05 178.43,166.05 180.4,164.09 180.4,163.12 183.57,159.95 183.57,159.53 183.93,159.17 183.99,159.17 v2(185.24,157.92) 185.24,157.74 186.25,156.73 186.43,156.73 186.62,156.93 186.62,157.11 185.89,157.84 185.89,158.02 185.2,158.71 185.2,158.89 185.43,159.13 185.61,159.13 186.77,157.96 186.9,157.96 187.19,157.67 187.19,156.91 189.73,154.38 189.73,153.68 v2(189.94,153.47)
  BOTTOM w0.102: v2(189.94,153.47) 190.51,153.47 191.38,152.59 191.74,152.59 UV19.N7 ; UV17.N7 178.36,166.4 178.26,166.5 178.11,166.5 177.86,166.24 177.6,166.24 177.48,166.37 177.48,166.56 177.34,166.7 177.08,166.7 v2(176.89,166.52) ; v2(170.49,136.1) 170.26,136.33 UV1.H11
MAA_13: length 75
  TOP w0.102: v2(194.31,157.01) 194.49,156.83 194.49,155.08 194.36,154.94 194.05,154.94 193.91,154.8 193.91,154.5 193.79,154.37 UV20.T3 ; UV18.T3 180.67,168.44 180.67,170.1 180.46,170.31 180.46,170.87 v2(180.44,170.89) ; 169.85,145.54 168.9,144.6 166.81,144.6 165.2,142.99 v2(165.2,142.57)
  TOP w0.201: v2(187.7,166.5) 187.7,165.72 186.46,164.48 186.46,163.71 185.38,162.63 183.44,162.63 180.43,159.63 179.63,159.63 171.33,151.33 171.33,147.03 169.85,145.54
  IN1 w0.127: v2(180.44,170.89) 180.24,170.69 180.02,170.69 179.44,171.26 179.44,171.56 179.78,171.89 180.08,171.89 181.26,170.71 183.48,170.71 v2(187.7,166.5) 188.78,165.42 188.78,165.42 193.89,160.31 193.89,158.02 194.31,157.6 v2(194.31,157.01)
  BOTTOM w0.102: v2(180.44,170.89) 180.08,171.25 178.56,171.25 177.79,170.48 UV17.T3 ; UV19.T3 191.87,157.24 193.53,157.24 193.76,157.01 v2(194.31,157.01) ; v2(165.2,142.57) 165.45,142.32 165.45,141.99
MAA_14: length 71.3
  TOP w0.102: v2(169.57,138.4) 169.57,138.97 170,139.4 170,140.01 171.22,141.22 171.22,141.22 171.24,141.25 172.66,141.25 ; UV20.T7 191.26,156.78 191.98,157.51 192.13,157.51 193.19,156.45 v2(193.75,156.45) ; v2(179.87,170.32) 179.87,170.83 179.63,171.07 178.24,171.07 177.79,170.62 UV18.T7
  TOP w0.201: v2(188.52,164.49) 188.13,164.1 188.13,163.24 186.4,161.51 186.4,160.73 183.3,157.62 183.3,156.76 182.16,155.63 182.16,154.79 177.3,149.93 177.3,145.88 172.66,141.25
  IN1 w0.127: v2(179.87,170.32) 180.45,170.32 180.73,170.04 182.98,170.04 v2(188.52,164.49) 188.65,164.49 191.46,161.68 191.46,161.43 191.28,161.25 191.28,161.07 191.53,160.82 191.71,160.82 191.93,161.04 192.11,161.04 193.23,159.91 193.23,157.54 193.75,157.02 v2(193.75,156.45)
  BOTTOM w0.102: v2(193.75,156.45) 194,156.45 194.37,156.08 194.37,154.47 194.14,154.24 193.65,154.24 UV19.T7 ; UV17.T7 180.67,168.44 180.67,170.07 180.41,170.32 v2(179.87,170.32) ; UV1.G14 168.95,138.49 169.47,138.49 v2(169.57,138.4)
MAA_15: length 67.2
  TOP w0.102: UV20.M7 188.99,153.12 188.97,153.1 188.97,152.75 189.23,152.49 v2(189.79,152.49) ; v2(165.79,137.99) 166.74,137.99 166.95,138.19 166.95,139.12 170.07,142.24 170.17,142.24 170.93,143 171.39,143 172.72,144.33 173.03,144.33 ; v2(176.33,165.95) 176.31,165.97 176.31,166.56 176.1,166.77 176.1,166.92 175.53,167.49 UV18.M7
  TOP w0.201: 173.03,144.33 173.66,144.33 174.55,145.22 174.55,146.62 174.81,146.88 175.76,146.88 175.89,147 175.89,147.62 175.69,147.82 174.76,147.82 174.55,148.02 174.55,148.43 174.76,148.63 175.69,148.63 175.89,148.83 175.89,149.23 175.69,149.43 174.76,149.43 174.55,149.63 174.55,150.03 174.76,150.23 175.69,150.23 175.89,150.43 175.89,151.94 178.45,154.5 179.54,154.5 180.75,155.7 180.75,156.75 181.46,157.46 181.46,158.01 v2(182.95,159.5)
  IN1 w0.127: v2(189.79,152.49) 189.79,153.03 189.35,153.47 189.35,154.37 187.59,156.13 186.8,156.13 186.47,156.46 186.05,156.46 183.01,159.5 v2(182.95,159.5) 182.64,159.19 182.05,159.19 181.62,159.63 181.62,161.44 180.44,162.61 179.57,162.61 176.33,165.86 v2(176.33,165.95)
  BOTTOM w0.102: v2(189.79,152.49) 189.97,152.67 190.26,152.67 190.37,152.57 190.37,152.34 190.53,152.17 190.63,152.17 191,152.54 191.15,152.54 191.35,152.34 191.35,152.2 UV19.M7 ; UV17.M7 177.82,165.57 177.92,165.67 177.92,165.94 177.82,166.04 177.52,166.04 177.42,166.13 176.51,166.13 v2(176.33,165.95)
  BOTTOM w0.203: v2(165.79,137.99) 165.69,137.89 UV1.L17
MAA_BA_0: length 66.8
  TOP w0.102: v2(177.46,167.08) 177.75,167.08 178.04,166.79 178.04,166 178.22,165.81 178.5,165.81 178.6,165.71 178.6,165.24 UV18.M2 ; v2(167.58,138.17) 167.58,139.13 170.28,141.84 170.34,141.84 171.1,142.6 171.56,142.6 172.57,143.6 172.88,143.6 173.23,143.26 173.59,143.26 ; v2(190.51,154.03) 190.51,153.47 191.82,152.15 UV20.M2
  TOP w0.201: 173.59,143.26 176.59,146.27 176.59,150.22 177.46,151.09 177.46,151.37 177.03,151.8 177.03,152.09 177.32,152.37 177.6,152.37 178.03,151.94 178.31,151.94 178.6,152.23 178.6,152.51 178.17,152.94 178.17,153.22 178.45,153.5 178.74,153.5 179.17,153.08 179.45,153.08 181.46,155.08 181.46,156.46 182.17,157.17 182.17,157.57 183.98,159.39 183.98,159.58 v2(184.32,159.92)
  IN1 w0.127: v2(177.46,167.08) 177.6,166.94 178.23,166.94 182.75,162.43 182.75,161.86 184.23,160.37 184.23,160.01 v2(184.32,159.92) 184.41,159.83 184.78,159.83 184.91,159.96 184.91,160.27 185,160.37 185.41,160.37 185.54,160.24 185.54,159.96 185.67,159.83 186.14,159.83 188.14,157.83 188.14,156.66 190.45,154.36 190.45,154.09 v2(190.51,154.03)
  BOTTOM w0.102: v2(190.51,154.03) 190.51,154.28 190.18,154.61 189.42,154.61 188.72,155.31 188.58,155.31 188.43,155.16 UV19.M2 ; v2(177.46,167.08) 176.88,167.08 176.62,167.34 175.56,168.4 UV17.M2 ; UV1.J16 167.13,138.05 167.45,138.05 v2(167.58,138.17)
MAA_BA_1: length 71.3
  TOP w0.102: UV18.N8 175.36,169.13 175.36,169.27 175.56,169.47 175.7,169.47 176.64,168.52 176.72,168.52 177.03,168.21 177.46,168.21 v2(177.61,168.06) ; v2(191.48,154.18) 190.93,154.18 190.7,154.41 190.26,154.41 189.95,154.72 189.95,155.13 189.58,155.5 UV20.N8 ; v2(166.82,137.45) 166.82,137.49 167.2,137.87 167.2,139.09 170.15,142.04 170.25,142.04 171.01,142.8 171.47,142.8 172.63,143.95 172.84,143.95
  TOP w0.201: v2(185.59,161.46) 185.38,161.25 185.38,161.07 184.69,160.38 183.93,160.38 183.63,160.08 183.63,159.54 181.81,157.72 181.81,157.32 181.1,156.61 181.1,155.56 179.69,154.14 178.59,154.14 176.24,151.79 176.24,146.41 173.78,143.95 172.84,143.95
  IN1 w0.127: v2(191.48,154.18) 191.48,154.74 190.81,155.41 190.81,156.15 189.27,157.68 189.27,158.1 186.4,160.97 186.4,161.67 185.78,162.3 185.6,162.3 185.44,162.14 185.44,161.96 185.67,161.73 185.67,161.53 v2(185.59,161.46) 185.58,161.45 185.26,161.45 181.86,164.85 181.86,166.36 180.4,167.82 178.42,167.82 178.18,168.06 v2(177.61,168.06)
  BOTTOM w0.102: v2(191.48,154.18) 191.74,154.18 191.85,154.08 191.85,153.32 192.21,152.96 192.21,152.6 191.89,152.29 191.89,152.14 192.06,151.97 192.25,151.97 UV19.N8 ; v2(177.61,168.06) 177.61,167.52 177.86,167.27 178.23,167.27 178.6,166.9 178.6,166.53 178.92,166.2 UV17.N8
  BOTTOM w0.13: UV1.L15 166.82,137.13 v2(166.82,137.45)
MAA_BA_2: length 67.9
  TOP w0.102: UV20.M3 191.04,152.32 190.93,152.32 190.66,152.05 190.49,152.05 190.37,152.17 190.37,152.34 190.6,152.56 190.6,152.81 v2(190.35,153.05) ; v2(171.19,136.79) 171.21,136.81 172.44,136.81 172.97,137.34 172.97,139.05 176.65,142.74 ; UV18.M3 177.34,166.02 176.85,166.02 176.51,166.36 176.51,166.9 v2(176.48,166.93)
  TOP w0.201: 176.65,142.74 179.07,145.15 179.07,148.91 181.16,151 181.92,151 185.64,154.72 185.64,155.03 187.57,156.96 187.57,157.79 v2(186.34,159.02)
  IN1 w0.127: v2(176.48,166.93) 177.05,166.93 177.29,166.69 178.12,166.69 180.84,163.97 180.84,163.87 182.37,162.34 182.37,161.62 183.9,160.09 183.9,159.67 184.07,159.5 185.86,159.5 v2(186.34,159.02) 187.83,157.54 187.83,156.6 190.11,154.32 190.11,153.87 190.52,153.46 190.88,153.1 192.61,153.1 192.74,152.98 192.74,152.65 192.61,152.53 191.83,152.53 191.7,152.4 191.7,152.04 191.58,151.91 191.32,151.91 191.2,152.04 191.2,152.4 191.07,152.53 190.48,152.53 190.35,152.65 v2(190.35,153.05)
  BOTTOM w0.102: UV17.M3 175.73,167.83 176.08,167.48 176.08,167.26 175.81,166.99 175.81,166.85 175.92,166.74 176.29,166.74 v2(176.48,166.93) ; UV19.M3 188.99,153.87 189.81,153.05 v2(190.35,153.05) ; v2(171.19,136.79) 170.65,136.79 UV1.G11
MCT: length 6
  IN1 w1.016: 16.95,169.54 16.95,165.35
  BOTTOM w0.102: 17.46,164.47 v1(19.26,164.47)
  vias: v2(16.01,170.37) v2(16.19,164.78) v2(16.19,164.15) v2(16.63,170.37)
MCT0: length 3.9
  TOP w0.508: XF3102.9 v1(17.99,172.28) 17.8,172.47 R3104.2
MCT1: length 3.9
  TOP w0.508: R3101.2 17.77,168.27 v1(17.96,168.47) XF3102.10
MCT2: length 3.9
  BOTTOM w0.508: R3103.2 16.5,172.28 v1(17.99,172.28) XF3101.10
MCT3: length 3.9
  BOTTOM w0.508: XF3101.9 v1(17.96,168.47) 16.5,168.47 R3102.2
MDO0+: length 9
  BOTTOM w0.089: XF3101.7 19.11,165.93 19.09,165.95 v4(15.44,165.95) 14.26,165.95 13.37,166.83 12.81,167.4 RJ45.1
MDO0-: length 8.9
  BOTTOM w0.089: XF3101.8 19.36,167.2 18.41,166.24 v4(17.65,166.24) 15.56,166.24 14.38,166.24 12.88,167.75 RJ45.2
MDO1+: length 11.3
  BOTTOM w0.089: XF3101.11 19.01,173.55 18.95,173.6 15.7,173.6 14.89,172.8 v4(14.89,171.59) 14.89,170.68 14.58,170.37 14.24,170.37 13.31,169.44 RJ45.3
MDO1-: length 11.4
  BOTTOM w0.089: RJ45.6 12.88,171.83 14.05,170.66 14.46,170.66 14.59,170.8 14.59,172.92 15.57,173.9 v4(17.77,173.9) 18.38,173.9 19.3,174.82 XF3101.12
MDO2+: length 11.8
  TOP w0.089: XF3102.12 19.01,165.93 18.83,166.1 18.83,166.73 18.66,166.9 v4(16.43,166.9) 15.44,166.9 14.48,167.86 14.48,170.7 14.16,171.03 13.07,171.03 12.88,170.84 RJ45.4
MDO2-: length 11.8
  TOP w0.089: RJ45.5 11.94,171.32 14.28,171.32 14.78,170.82 v4(14.78,169.51) 14.78,167.98 15.57,167.2 XF3102.11
MDO3+: length 9.4
  TOP w0.089: XF3102.8 19.23,173.55 19.04,173.74 18.37,173.74 17.73,174.37 v4(16.1,174.37) 15.78,174.37 14.49,173.08 13.99,173.08 13.54,173.52 RJ45.7
MDO3-: length 9.5
  TOP w0.089: RJ45.8 12.88,173.93 12.99,173.82 13.67,173.82 14.11,173.37 14.36,173.37 15.57,174.58 15.66,174.67 v4(17.57,174.67) 17.86,174.67 18.49,174.03 18.77,174.03 18.92,174.18 18.92,174.62 19.11,174.82 XF3102.7
ME_FWP_EC: length 70.6
  TOP w0.102: UE1.80 176.57,75.17 176.46,75.06 v1(175.96,75.06) 174.77,75.06 RE357.1 174.01,75.82 172.65,75.82 v2(172.4,75.56)
  IN1 w0.127: v2(153.08,52.71) 153.26,52.71 155.1,50.87 155.1,42.07 156.27,40.91 168.07,40.91 170.74,43.58 170.74,57.09 v2(174.69,61.03)
  IN2 w0.127: v2(174.69,61.03) 174.69,66.29 175.76,67.36 175.76,68.66 172.52,71.89 172.52,75.25 172.4,75.37 v2(172.4,75.56)
  BOTTOM w0.102: v2(153.08,52.71) 152.83,52.96 RC223.1
ME_SUS_PWR_ACK: length 149.1
  TOP w0.102: v2(131.68,78.66) 131.35,78.34 131.35,77.91 131.63,77.62 132.77,77.62 134.96,75.43 143.73,75.43 143.89,75.59 148.11,75.59 151.09,72.62 v1(151.09,72.01) 151.09,71.46 RC74.2 ; v2(189.06,80.64) 188.59,80.64 187.95,81.29 UE1.42
  IN1 w0.127: v2(189.06,80.64) 189.06,79.21 188.31,78.46 188.31,73.99 187.29,72.98 187.29,70.93 187.1,70.74 187.1,68.13 184.94,65.97 182.17,65.97 181.67,65.47 181.67,63.37 177.6,59.31 173.62,59.31 171,56.69 171,43.47 168.18,40.65 156.16,40.65 154.85,41.97 154.85,48.82 151.9,51.77 151.9,56.58 149.32,59.16 149.32,68.44 148.94,68.81 148.94,72.01 148.17,72.78 148.17,75.67 147.4,76.44 142.09,76.44 141.47,77.06 138.84,77.06 138.56,76.77 133.66,76.77 131.77,78.66 v2(131.68,78.66)
  BOTTOM w0.089: UC1.AR13 v2(131.68,78.66)
MEC_XTAL1: length 2.1
  TOP w0.102: RE366.2 C5225.1 191.12,63.88 Y1.1
MEC_XTAL1_R: length 2.6
  TOP w0.102: RE366.1 190.18,65.28 189.55,65.91 UE1.123
MEC_XTAL2: length 6.7
  TOP w0.102: Y1.2 194.62,63.88 193.99,64.52 193.99,65.2 C5226.1 R6520.2 192.19,66.09 190.51,66.09 190.35,66.25 UE1.125
MEM_CALRP0: length 3.4
  TOP w0.102: v1(159.95,145.29) 159.63,144.97 159.63,143.83 RV39.2
  TOP w0.254: v2(160.56,142.98) 160.48,142.98 RV39.2
  BOTTOM w0.3: UV1.K25 v2(160.56,142.98)
MIC2_VREFO: length 13.3
  TOP w0.254: RE36.1 RE35.1 181.1,21.47 181.63,20.94 183.68,20.94 184.59,20.03 v1(185.02,20.03) 186.97,20.03 188.16,18.84 v2(188.16,17.05)
  BOTTOM w0.203: v2(188.16,17.05) 188,16.89 HDA27.29
MIC_CAP: length 3.7
  BOTTOM w0.203: HDA27.19 183.77,19.86 183.83,19.92 183.83,20.47 v1(184.32,20.97) 184.52,21.16
  BOTTOM w0.254: C2713.1 185.42,22.06 184.52,21.16
MODEL_ID: length 7.1
  TOP w0.102: UE1.109 183.95,65.48 v1(183.93,65.46) 183.37,64.9 C2403.1 183.36,64.24 182.49,63.37 182.49,62.8 181.7,62.01 R2407.2 R2446.2
MONO_PC_BEEP_R: length 4.9
  TOP w0.102: R6516.1 179.51,22.61 v1(181.59,20.52) 181.77,20.35 v2(182.1,20.35)
  BOTTOM w0.102: v2(182.1,20.35) 182.57,19.88 HDA27.16
MSCLK: length 4.1
  BOTTOM w0.102: RE72.2 189.35,85.22 190.87,86.74 190.87,87.22 191.26,87.61 JDEG1.6
MSDATA: length 4.6
  BOTTOM w0.102: JDEG1.7 191.24,87.11 191.1,86.97 191.1,86.5 v1(190.63,86.03) 190.54,85.94 190.54,85.9 189.79,85.15 189.79,84.65 189.48,84.33 RE75.2
NCT7718_DXN: length 235.8
  TOP w0.254: v2(68.32,82.49) 68.57,82.74 69.08,82.74 71.24,84.9 74.06,84.9 90.16,101 90.16,103.89 91.69,105.41 91.69,109.66 93.21,111.19 93.21,116.57 96.4,119.76 96.4,121.08 v2(96.65,121.34)
  IN1 w0.254: v2(96.65,121.34) 97.22,121.34 101.17,125.29 101.17,134.79 97.02,138.94 97.02,142.44 96.58,142.88 96.11,142.88 v2(96.01,142.98) ; v2(53.97,69.28) 54.1,69.15 57.94,69.15 61.18,72.39 63.94,72.39 67.81,76.26 67.81,81.12 68.19,81.5 68.19,82.36 v2(68.32,82.49)
  IN2 w0.254: v2(96.01,142.98) 96.11,142.88 96.39,142.88 96.64,143.13 96.64,143.95 91.69,148.91 91.69,150.15 84.38,157.45 84.38,159.32 80.07,163.64 79.16,163.64 78.26,164.54 78.26,165.71 77.27,166.7 75.96,166.7 74.54,168.12 74.54,168.74 v2(74.4,168.87)
  BOTTOM w0.254: v2(74.4,168.87) 74.59,169.06 74.59,169.36 80.05,174.82 106.7,174.82 107.91,173.61 122.52,173.61 124.04,175.13 132.6,175.13 134.88,172.85 146.49,172.85 149.85,169.48 156.96,169.48 157.63,168.81 157.63,167.36 157.09,166.82 C2607.2 157.29,166.6 THM26.3 ; v2(53.97,69.28) 53.97,69.09 53.71,68.83 C2606.2 53.98,67.93 Q2603.3
NCT7718_DXP: length 237.9
  TOP w0.254: v2(96.63,121.97) 96.55,121.97 95.99,121.41 95.99,119.93 92.8,116.74 92.8,111.36 91.28,109.83 91.28,105.58 89.78,104.08 89.78,101.16 73.9,85.28 71.05,85.28 68.89,83.12 68.19,83.12 67.68,82.61 v2(67.68,82.49)
  IN1 w0.254: v2(67.68,82.49) 67.81,82.36 67.81,81.66 67.43,81.28 67.43,76.42 63.78,72.77 61.02,72.77 57.79,69.53 54.49,69.53 54.26,69.76 53.77,69.76 53.33,69.33 v2(53.33,69.28) ; v2(96.01,142.39) 96.11,142.49 96.43,142.49 96.64,142.28 96.64,138.78 100.7,134.72 100.7,125.36 97.31,121.97 v2(96.63,121.97)
  IN2 w0.254: v2(75.11,168.87) 74.92,168.68 74.92,168.28 76.12,167.08 77.43,167.08 78.64,165.87 78.64,164.69 79.32,164.02 80.22,164.02 84.77,159.48 84.77,157.61 92.07,150.3 92.07,149.07 97.02,144.11 97.02,142.97 96.54,142.49 96.11,142.49 v2(96.01,142.39)
  BOTTOM w0.254: v2(53.33,69.28) 53.27,69.28 52.32,68.33 C2606.1 52.05,67.93 Q2603.2 53.02,65.23 Q2603.1 ; THM26.2 156.64,166.31 156.56,166.4 156.56,167.16 156.58,167.19 156.58,167.21 C2607.1 157.24,167.87 157.24,168.66 156.8,169.1 149.7,169.1 146.33,172.47 134.73,172.47 132.44,174.75 124.2,174.75 122.68,173.23 107.75,173.23 106.55,174.43 80.21,174.43 74.97,169.2 74.97,169.01 v2(75.11,168.87)
NRB_BIT: length 15.4
  TOP w0.102: v2(134.45,78.85) 134.72,78.85 135.12,79.25 136.05,79.25 137.29,78.01 144.16,78.01 144.48,77.68 v1(147.41,77.68) RC186.2
  BOTTOM w0.102: UC1.AR7 134.89,78.47 134.51,78.85 v2(134.45,78.85)
NTC_IA: length 2.5
  TOP w0.203: PU602.15 116.25,136.85 116.07,136.66 116.07,136.16 v2(116.02,136.11)
  BOTTOM w0.254: PR635.2 115.54,135.62 v2(116.02,136.11)
OCP_L: length 38.7
  TOP w0.102: v2(168.46,115.25) v1(168.46,116.37) 168.46,118.05 166.93,119.57 166.93,123.72 v2(167.04,123.82) ; v2(169.35,127.48) 170.14,128.27 RV91.1 168.97,128.63 RV90.2
  IN1 w0.127: v2(168.46,115.25) 165.29,115.25 161.92,111.89 160.33,111.89 158.49,110.05 156.33,110.05 155.14,108.86 155.14,106.38 v2(155.41,106.11)
  IN2 w0.127: v2(167.04,123.82) 168.62,125.41 168.62,125.73 169.03,126.13 169.03,127.17 v2(169.35,127.48)
  BOTTOM w0.203: PR1112.2 155.28,105.35 155.28,105.98 v2(155.41,106.11) 155.44,106.14 155.96,106.14 156.16,106.34 PU1100.4
ODD_PWR_5V:
  vias: v2(153.98,81.66) v2(154.51,81.85) v2(156.27,82.11) v2(156.27,81.53) v2(165.92,43.69) v2(165.92,43.05) v2(165.92,42.48) v2(166.55,43.69) v2(166.55,43.05) v2(166.55,42.48) v3(172.6,41.3)
ODTA0: length 54
  TOP w0.102: v2(174.64,164.29) 174.73,164.19 176.23,164.19 177.66,162.76 177.81,162.76 178,162.96 178,163.1 UV18.K1 ; v2(165.03,139) 165.03,138.43 v1(164.78,138.18)
  IN1 w0.264: v2(165.03,139) 165.22,138.81 165.79,138.81 166.24,139.26 167.58,139.26 172.09,143.76 172.84,143.76 174.05,142.55 174.42,142.55 174.91,143.04 174.91,143.41 173.87,144.45 173.87,144.92 174.24,145.29 174.61,145.29 175.7,144.21 176.08,144.21 177.35,145.48 177.35,148.88 178.56,150.08 178.56,156.13 179.78,157.35 v2(180.21,157.35)
  IN2 w0.102: v2(180.21,157.35) 180.21,157.99 178.49,159.7 178.49,160.97 177.16,162.31 177.16,162.81 175.74,164.23 174.69,164.23 v2(174.64,164.29)
  BOTTOM w0.102: v2(174.64,164.29) 174.64,164.83 174.16,165.31 174.16,166.32 174.08,166.41 174.08,166.88 174.16,166.96 174.16,167.4 173.73,167.83 UV17.K1 ; v2(165.03,139) 164.97,138.94 164.97,138.56 164.78,138.37 164.55,138.37 UV1.L18
ODTA1: length 51.4
  TOP w0.102: UV20.K1 191.26,150.37 190.86,150.76 190.51,150.76 190.39,150.65 189.77,150.65 189.69,150.73 189.44,150.73 189.24,150.93 188.47,150.93 188.1,151.3 v2(187.61,151.3) ; 169.91,142.8 169.67,142.56 169.67,142.42 166.36,139.11 v2(166.36,138.71)
  TOP w0.201: v2(179.44,155.54) 178.49,155.54 173.85,150.9 173.85,146.3 171.19,143.64 170.74,143.64 169.91,142.8
  IN1 w0.102: v2(187.61,151.3) 187.61,152.87 186.5,153.99 184.68,153.99 183.82,153.13 183.18,153.13 182.83,153.48 182.55,153.48 180.65,151.57 180.46,151.57 180.21,151.82 180.21,151.96 181.73,153.48 181.73,153.63 181.53,153.83 181.39,153.83 180.79,153.23 180.65,153.23 180.52,153.35 180.52,153.54 181.03,154.04 181.03,154.2 179.69,155.54 v2(179.44,155.54)
  BOTTOM w0.102: v2(166.36,138.71) 166.3,138.65 UV1.K16 ; v2(187.61,151.3) 187.61,152.14 187.62,152.15 187.62,152.81 186.08,154.35 186.08,154.49 186.24,154.66 186.44,154.66 UV19.K1
ONE_DIMM#: length 7.2
  BOTTOM w0.102: 142.66,91.01 RC268.1 v1(140.67,91.01) 140.47,90.8 139.25,90.8 139.25,90.8 138.68,90.8 138.68,90.8 138.1,90.8 UC1.M2
  BOTTOM w0.127: RC267.2 143.68,91.31 143.06,91.31 142.75,91.01 142.66,91.01
PANEL_BKEN_EC: length 284.9
  TOP w0.102: v2(101.53,160.66) v1(101.11,160.24) 100.93,160.06 100.93,155.64 101.45,155.12 101.45,153.15 96.76,148.46 91.14,148.46 87.94,151.66 87.94,155.7 86.92,156.72 86.92,157.33 87.17,157.57 RN5201.8 ; v2(186.05,69.73) 187.15,68.63 UE1.117
  IN1 w0.127: v2(101.53,160.66) 102.55,161.67 102.55,166.55 101.1,168 v2(101.1,168.54) ; v2(190.81,52.7) 192.14,52.7 195.32,55.88 195.32,57.4 196.56,58.64 196.56,61.05 197.22,61.72 197.22,65.67 195.34,67.55 195.34,68.26 195.13,68.48 194.58,68.48 194.46,68.61 194.46,74.37 194.7,74.61 195.53,74.61 195.89,74.97 195.89,78.76 196.53,79.4 196.53,85 191,90.53 186.24,90.53 184.87,89.15 182.37,89.15 181.54,88.33 174.98,88.33 173.92,89.38 173.09,89.38 171.86,90.61 166.55,90.61 160.45,96.72 160.45,97.7 157.18,100.96 155.16,100.96 150.05,106.08 150.05,119.4 148.67,120.78 148.67,124.42 149.22,124.97 149.22,126.31 148.53,126.99 148.53,132.62 148.78,132.87 148.78,134.08 148.57,134.29 148.57,136.66 148.32,136.92 148.32,141.55 147.38,142.49 147.38,145.29 149.03,146.94 149.03,161.12 150.81,162.9 150.81,168.21 142.87,176.15 142.87,177.67 v2(142.23,178.31)
  IN2 w0.127: v2(101.1,168.54) 101.1,171.1 105.95,175.96 110.61,175.96 112.77,178.12 123.37,178.12 123.58,177.92 141.84,177.92 v2(142.23,178.31) ; v2(186.05,69.73) 186.68,69.1 186.68,69.02 187.42,68.28 187.42,64.74 188.94,63.21 188.94,62.03 190.3,60.67 190.3,58.74 189.69,58.13 189.69,54.35 190.81,53.23 v2(190.81,52.7)
PANEL_SIZE_ID: length 321.2
  IN1 w0.127: v2(140.04,177.32) 145.09,172.28 145.09,160.59 148.01,157.67 148.01,147.64 146.3,145.92 146.3,142.05 147.2,141.15 147.2,120.82 149.03,118.98 149.03,105.63 154.72,99.95 156.76,99.95 159.43,97.28 159.43,96.21 166.05,89.6 170.45,89.6 172.09,87.96 173.91,87.96 174.55,87.31 180.97,87.31 181.67,86.61 183.32,86.61 184.84,88.14 185.29,88.14 186.05,88.9 187.74,88.9 188.47,88.17 190.26,88.17 190.88,87.54 192.55,87.54 195.51,84.58 195.51,79.82 194.27,78.57 194.27,77.24 193.95,76.92 193.95,75.78 193.44,75.28 193.44,69.02 192.87,68.45 192.87,67.94 194.01,66.8 194.64,66.8 196.21,65.23 196.21,62.14 195.54,61.47 195.54,59.18 193.99,57.63 193.99,56.14 191.76,53.91 182.07,53.91 180.85,52.69 175.86,52.69 174.45,51.28 174.45,46.2 168.39,40.14 162.76,40.14 v2(162.36,39.75)
  IN2 w0.076: v2(130.77,78.71) 130.77,78.27 131.58,77.46 131.98,77.46 132.13,77.31 132.13,76.47 132.32,76.27 133.2,76.27 138.99,70.48 138.99,70.44 139.25,70.19
  IN2 w0.127: v2(102.25,167.44) 102.42,167.6 102.42,172.04 105.76,175.39 113.02,175.39 114.55,176.91 131.61,176.91 131.77,177.08 139.8,177.08 v2(140.04,177.32) ; v2(162.36,39.75) 162.69,40.08 162.69,56.44 161.98,57.15 152.81,57.15 148.2,61.76 144.67,61.76 142.76,63.67 142.76,65.05 139.76,68.05 139.76,69.68 139.25,70.19
  BOTTOM w0.076: UC1.AP13 131.19,79.12 v2(130.77,78.71)
  BOTTOM w0.102: v2(102.25,167.44) 102.78,166.92 103.37,166.92 v1(103.78,167.32) 104.32,167.87 104.32,168.71 105.54,169.93 R5210.2 R5208.2 R5209.1
PANEL_SIZE_ID_CONN: length 14.3
  BOTTOM w0.102: R5210.1 104.63,169.49 v1(104.25,169.11) 104.07,168.94 104.07,168.07 103.71,167.72 103.3,167.72 103,168.01 95.05,168.01 93.8,166.76 LCD1.27
PBAT_CHG_SMBCLK: length 231.7
  TOP w0.102: RE425.1 195.66,71.88 v2(195.65,71.87) 194.7,71.87 194.6,71.97 UE1.9
  TOP w0.254: PR18.2 159.19,174.68 PD2.3 159.82,173.92 v2(159.82,172.42)
  IN1 w0.127: v2(159.82,172.42) 159.44,172.04 159.44,169.98 150.04,160.59 150.04,146.81 151.06,145.8 151.06,142.05 150.36,141.35 150.36,139.09 150.62,138.83 150.62,136.75 149.59,135.72 149.59,134.78 149.76,134.61 149.76,132.56 149.55,132.35 149.55,127.42 150.23,126.73 150.23,124.54 149.69,124 149.69,121.2 151.07,119.83 151.07,106.5 155.52,102.04 157.54,102.04 161.16,98.42 161.47,98.42 162.24,97.66 162.24,96.46 167.06,91.63 172.29,91.63 173.52,90.4 174.34,90.4 175.4,89.34 180.9,89.34 181.79,90.23 184.51,90.23 185.82,91.54 191.59,91.54 192.42,90.72 194.05,90.72 197.29,87.47 197.29,77.2 196.65,76.56 196.65,72.87 v2(195.65,71.87)
  IN2 w0.127: v2(159.82,172.42) 160.33,171.92 160.33,171.45 158.62,169.74 153.6,169.74 152.71,170.62 149.98,170.62 148.33,172.28 144.27,172.28 v2(143.69,171.7)
  BOTTOM w0.102: PR770.1 104.57,156.62 103.38,156.62 102.44,157.55 102.44,164.8 104.01,166.37 106.04,166.37 106.39,166.72 106.39,167.86 107.14,168.61 107.14,171.12 108.18,172.16 122.88,172.16 124.76,174.04 131.71,174.04 135.74,170 v1(137.8,170) 139.06,171.26 143.38,171.26 143.69,171.58 v2(143.69,171.7)
PBAT_CHG_SMBDAT: length 231.5
  TOP w0.102: UE1.8 195.02,71.57 195.6,70.99 v2(195.65,70.99) RE424.1
  TOP w0.254: PR20.2 158.3,174.44 PD2.2 159.13,172.4 v2(159.85,171.67)
  IN1 w0.127: v2(195.65,70.99) 196.91,72.25 196.91,76.45 197.55,77.09 197.55,87.58 194.16,90.97 192.82,90.97 191.99,91.8 185.71,91.8 184.4,90.49 181.6,90.49 180.71,89.6 175.5,89.6 173.22,91.88 167.19,91.88 162.52,96.55 162.52,97.76 161.6,98.68 161.28,98.68 157.66,102.3 155.63,102.3 151.32,106.6 151.32,119.93 150.58,120.67 150.58,126.75 149.8,127.52 149.8,132.28 150.7,133.17 150.7,134.03 149.85,134.87 149.85,135.63 150.87,136.64 150.87,138.94 150.62,139.19 150.62,141.16 151.76,142.3 151.76,150.18 150.3,151.64 150.3,160.49 159.85,170.04 v2(159.85,171.67)
  IN2 w0.127: v2(143,171.7) 143.95,172.66 148.9,172.66 150.33,171.23 152.68,171.23 153.79,170.12 158.3,170.12 v2(159.85,171.67)
  BOTTOM w0.102: v2(143,171.7) 142.93,171.64 v1(135.08,171.64) 134.49,171.64 131.86,174.27 124.67,174.27 122.79,172.39 108.09,172.39 106.91,171.21 106.91,168.7 106.17,167.95 106.17,166.81 105.95,166.6 103.92,166.6 102.22,164.9 102.22,157.45 103.59,156.08 PR769.1
PBAT_PRES#: length 274.4
  TOP w0.102: v2(117.33,167.06) 117.33,166.37 118.01,165.68 120.43,165.68 120.85,166.1 122.28,166.1 122.82,166.64 122.82,167.72 v2(122.99,167.89)
  TOP w0.203: CE76.1 178.49,65.66 179.15,66.31 UE1.97
  TOP w0.254: v2(117.33,167.06) 117.35,167.08 PR16.1 ; v2(108.96,164.34) v1(108.96,163.65) 108.96,163.06 PR756.1 PC753.2 ; CE76.1 177.87,64.72 177.48,64.33 177.48,61.11 183.1,55.48 183.1,51.52 v2(184.08,50.55) ; PR15.2 156.63,175.56 PD3.2 156.46,175.26 157.09,174.62 157.09,171.88 155.84,170.62 v2(155.06,170.62) 154.3,171.39 146.73,171.39 PC14.1
  IN1 w0.127: v2(184.08,50.55) 193.03,50.55 196.51,54.02 196.51,57.07 197.61,58.17 197.61,59.69 198.28,60.37 198.28,61.7 198.79,62.21 198.79,63.2 197.99,64.01 197.99,66.01 196.69,67.31 196.66,67.31 196.11,67.86 196.11,69.82 195.23,70.7 195.23,72.94 195.5,73.22 196.08,73.22 196.4,73.53 196.4,76.66 197.04,77.3 197.04,87.37 193.95,90.46 192.31,90.46 191.49,91.29 185.92,91.29 184.55,89.92 181.92,89.92 181.1,89.09 175.29,89.09 174.24,90.15 173.41,90.15 172.18,91.38 166.93,91.38 161.95,96.36 161.95,97.57 161.41,98.11 161.11,98.11 157.49,101.73 155.48,101.73 150.81,106.39 150.81,119.72 149.43,121.1 149.43,124.1 149.98,124.65 149.98,126.62 149.29,127.31 149.29,132.42 149.5,132.62 149.5,134.5 149.33,134.67 149.33,135.83 150.36,136.85 150.36,138.73 150.11,138.98 150.11,141.6 150.68,142.18 150.68,145.8 149.79,146.69 149.79,160.7 155.12,166.03 155.12,170.56 v2(155.06,170.62)
  IN2 w0.127: v2(155.06,170.62) 155.06,171.45 154.23,172.28 151,172.28 149.47,173.8 130.8,173.8 130.42,174.18 126.23,174.18 122.99,170.94 v2(122.99,167.89)
  BOTTOM w0.254: v2(117.33,167.06) 110.82,167.06 108.96,165.19 v2(108.96,164.34) PR764.1
PCC_GPIO_6: length 2.4
  TOP w0.102: RV90.1 168.85,130.04 CVT90.2 168.74,130.17 v2(168.13,130.17)
  BOTTOM w0.102: UV1.T8 168.06,130.11 v2(168.13,130.17)
PCH_BATLOW#: length 25.3
  TOP w0.102: v2(130.83,76.84) 131.06,76.84 v1(132.81,75.09) 133.06,74.85 136.62,74.85 139.49,71.97 139.49,69.76 143.42,65.84 146.65,65.84 147.42,65.07 147.42,64.49 147.32,64.39 146.64,64.39 RC72.1
  BOTTOM w0.089: UC1.AU13 131.16,77.17 v2(130.83,76.84)
PCH_DPB_AUXN: length 106.5
  TOP w0.091: C5528.1 35.55,62.8 35.76,62.8 RC181.2 36.47,62.83 36.85,62.83 v2(37.06,63.04)
  IN2 w0.076: v2(109.78,93.03) 109.88,92.93 110.16,92.93 110.3,93.07 110.3,93.46 110.03,93.73 110.03,94.49 109.85,94.68 107.44,94.68 106.36,95.76 103.2,95.76 102.18,96.77 99.55,96.77 99.11,97.21 98.59,97.21 98.55,97.17 98.53,97.17
  IN2 w0.127: 98.53,97.17 92.41,97.17 91.83,96.59 90.53,96.59 76.79,82.85 76.79,81.62 69.45,74.29 64.52,74.29 60,78.8 47.98,78.8 46.39,77.21 40.31,77.21 39.62,76.52 39.62,69.15 35.62,65.15 35.62,63.25 36.2,62.66 36.67,62.66 37.05,63.04 v2(37.06,63.04)
  BOTTOM w0.102: UC1.G50 110.2,92.69 109.81,93.03 v2(109.78,93.03)
PCH_DPB_AUXP: length 106.5
  TOP w0.091: v2(37.06,62.41) 36.86,62.61 36.43,62.61 RC182.2 35.81,62.62 35.57,62.62 C5527.1
  IN2 w0.076: 98.53,97.42 98.55,97.42 98.59,97.38 99.18,97.38 99.62,96.94 102.25,96.94 103.27,95.92 106.42,95.92 107.5,94.84 109.92,94.84 110.2,94.56 110.2,93.8 110.4,93.6 v2(110.67,93.6)
  IN2 w0.127: v2(37.06,62.41) 36.09,62.41 35.36,63.14 35.36,65.26 39.36,69.26 39.36,76.62 40.21,77.47 46.29,77.47 47.87,79.06 60.11,79.06 64.62,74.54 69.35,74.54 76.53,81.73 76.53,82.95 90.42,96.84 91.72,96.84 92.3,97.42 98.53,97.42
  BOTTOM w0.102: UC1.F50 v2(110.67,93.6)
PCH_DPC_AUXN_U: length 3.3
  TOP w0.091: C5528.2 33.93,62.79 33.21,62.79 33.04,62.96 32.33,62.96 32.29,62.93 31.87,62.93 31.71,63.09 U5502.27
PCH_DPC_AUXP_U: length 3.3
  TOP w0.091: U5502.26 31.72,62.59 31.88,62.75 v4(32.62,62.75) 33,62.75 33.14,62.61 33.94,62.61 C5527.2
PCH_DPC_N0_U: length 13.7
  TOP w0.091: U5502.30 31.89,64.59 32.03,64.44 32.62,64.44 v4(35.66,67.48) 37.62,69.45 37.62,70.04 37.66,70.08 37.66,73.23 37.95,73.52 38.45,73.52 C5526.2
PCH_DPC_N1_U: length 14.9
  TOP w0.091: U5502.32 31.89,65.59 32.07,65.4 32.38,65.4 36.83,69.86 v4(36.83,72.49) 36.83,74.81 37.05,75.03 37.05,75.08 37.47,75.5 38.53,75.5 C5525.2
PCH_DPC_P0_U: length 13.8
  TOP w0.091: U5502.29 31.89,64.09 32.07,64.26 32.7,64.26 35.56,67.12 35.6,67.12 36.02,67.54 36.02,67.59 37.84,69.41 v4(37.84,69.75) 37.84,73.15 38.03,73.34 38.4,73.34 C5529.2
PCH_DPC_P1_U: length 14.9
  TOP w0.091: C5530.2 38.45,75.32 37.6,75.32 v4(37.41,75.13) 37.01,74.74 37.01,72.82 37.05,72.79 37.05,72.2 37.01,72.16 37.01,69.79 32.45,65.22 32.03,65.22 31.89,65.09 U5502.31
PCH_DPWROK: length 34.5
  BOTTOM w0.102: RC216.2 150.41,54.74 149.46,55.69 v3(143,55.69) 141.79,55.69 128.86,68.62 128.86,69.69 127.98,70.57 127.98,72.36 127.42,72.91 127.42,73.55 127.5,73.62 UC1.BB20
PCH_HDMI_CLK: length 124.6
  IN2 w0.076: v2(131.55,90.16) 131.15,89.76 125.62,89.76 125.34,90.04 125.34,94.14 123.66,95.82 114.29,95.82
  IN2 w0.127: 114.29,95.82 112.96,97.15 112.96,97.54 110.93,99.57 106.86,99.57 104.96,97.66 104.07,97.66 103.45,98.28 97.95,98.28 96.66,99.57 92,99.57 68.32,75.88 64.57,75.88 60.64,79.82 46.29,79.82 45.84,79.37 45.59,79.37 v2(45.4,79.57)
  BOTTOM w0.089: UC1.L13 131.18,90.64 v2(131.55,90.16)
  BOTTOM w0.102: RC175.1 33,77.27 33.71,77.98 33.71,78.98 34.28,79.55 Q5402.4
  BOTTOM w0.127: v2(45.4,79.57) 45.21,79.37 43.62,79.37 42.6,78.36 38.35,78.36 36.32,76.33 33.76,76.33 RC175.1
PCH_HDMI_DATA: length 124.3
  IN2 w0.076: 114.1,95.63 123.61,95.63 125.18,94.06 125.18,89.95 125.53,89.6 131.25,89.6 131.44,89.79 131.83,89.79 132.19,90.15 v2(132.19,90.16)
  IN2 w0.127: 114.1,95.63 112.71,97.03 112.71,97.41 110.8,99.31 106.99,99.31 105.09,97.41 103.94,97.41 103.33,98.02 97.84,98.02 96.55,99.31 92.13,99.31 68.45,75.63 64.45,75.63 60.51,79.57 46.4,79.57 45.89,79.06 45.65,79.06 v2(45.4,78.8)
  BOTTOM w0.089: UC1.L12 131.82,90.64 v2(132.19,90.16)
  BOTTOM w0.102: RC178.1 32.14,77.09 33,77.95 Q5402.1
  BOTTOM w0.127: RC178.1 33.15,76.07 36.44,76.07 38.47,78.1 42.73,78.1 43.75,79.12 45.08,79.12 v2(45.4,78.8)
PCH_JTAG_TCK1: length 8.3
  BOTTOM w0.076: UC1.B56 106.32,96.27 106.32,96.51 106.29,96.58 106.29,96.84 106.3,96.85 106.43,96.98 106.43,97.35
  BOTTOM w0.102: 106.43,97.35 106.43,97.47 106.02,97.88 106.02,98.27 106.02,100.61 105.51,101.12 RC348.1 105.9,101.61 106.27,101.98 107.1,101.98 T43.1
PCH_PCIE_WAKE#: length 32.4
  TOP w0.102: v2(154.19,71.65) 154.39,71.45 RC395.2
  IN1 w0.127: v2(147.74,75.04) 147.33,75.45 138.9,75.45 137.86,76.49 134.86,76.49 130.99,72.62 v2(130.99,71.49)
  IN2 w0.127: v2(154.19,71.65) 154.1,71.74 151.98,71.74 149.84,73.89 148.88,73.89 v2(147.74,75.04)
  BOTTOM w0.076: UC1.BB15 129.92,73.83 129.65,73.57 129.65,72.12 130.2,71.57 v1(130.46,71.57) 130.47,71.57 130.6,71.44 130.94,71.44 v2(130.99,71.49)
PCH_PLTRST#: length 20.6
  TOP w0.076: v2(133.52,79.62) 133.91,80.01 134.87,80.01 135.07,79.81 137.61,79.81 138.42,78.99 139.12,78.99
  TOP w0.102: 139.12,78.99 143.76,78.99 144.48,79.72 144.48,81.64 v1(144.81,81.97) 145.63,82.79 147.06,82.79 147.16,82.69 UC7.1 148.7,82.69 148.9,82.49 148.9,82.11 148.83,82.04 UC7.2
  BOTTOM w0.102: UC1.AN10 v2(133.52,79.62)
PCH_PLTRST#_EC: length 300.7
  TOP w0.102: RC65.1 149.27,80.28 148.77,80.77 148.77,81.22 148.95,81.39 UC7.4 150.35,81.39 150.45,81.49 150.45,81.85 150.35,81.95 v2(149.79,81.95) ; v2(180.71,80.77) 181.52,80.77 182.35,81.59 UE1.56 182.35,84.68 CE72.1 ; v2(57.96,165.24) 57.21,164.49 57.21,164.47 56.72,163.98 R3016.1 ; v2(157.66,47.5) 157.79,47.37 v1(158.92,47.37) 160.58,47.37 161.83,48.62 161.83,49.19 162.07,49.43 162.11,49.47 166.87,49.47 167.51,50.1 169.17,50.1 169.87,50.8 R5807.1
  IN1 w0.127: v2(138.87,141.29) 138.87,141.6 137.98,142.49 137.98,157.32 138.99,158.34 138.99,161.67 134.23,166.43 v2(129.03,166.43) ; v2(149.79,81.95) 149.79,79.27 150.62,78.44 150.62,75.19 151,74.81 151,70.89 152.08,69.81 152.08,67.43 151.42,66.77 151.42,59.4 154.07,56.74 154.83,56.74 157.61,53.96 157.61,49.79 157.3,49.48 157.3,47.86 v2(157.66,47.5) ; v2(57.96,165.24) 57.96,168.52 63.37,173.93 80.96,173.93 82.29,172.59 82.29,170.54 83.28,169.54 84.69,169.54 87.93,166.31 101.09,166.31 102.04,165.35 102.04,162.2 v2(101.58,161.75) ; v2(158.55,86.68) 158.57,86.68 161.22,84.03 161.22,82.87 160.84,82.49 160.39,82.49 160.08,82.17 160.08,81.47 162.11,79.44 166.87,79.44 167.25,79.06 172.6,79.06 173.36,79.82 174.55,79.82 175.25,80.52 176.46,80.52 177.41,79.57 179.19,79.57 180.4,80.77 v2(180.71,80.77)
  IN2 w0.127: v2(101.58,161.75) 102.15,162.32 114.99,162.32 117.12,164.45 117.79,164.45 119.25,165.91 121.12,165.91 121.8,166.59 128.87,166.59 v2(129.03,166.43) ; v2(138.87,141.29) 139.19,140.97 139.19,137.44 140.15,136.48 140.15,129.4 v2(140.74,128.81)
  BOTTOM w0.102: DB1.3 157.3,47.86 v2(157.66,47.5) ; R5212.2 101.03,161.19 v2(101.58,161.75) ; v2(140.74,128.81) 140.01,128.08 UV2.1 138.99,128.08 138.87,127.95 138.87,127.57 140.24,126.2 143.64,126.2 146.43,123.41 146.43,115.27 145.09,113.93 145.09,112.01 156.72,100.39 157.47,100.39 160.48,97.38 160.48,88.61 v2(158.55,86.68) 158.55,86.3 157.81,85.56 157.81,84.92 155.16,82.27 153.92,82.27 153.11,81.47 150.27,81.47 v2(149.79,81.95)
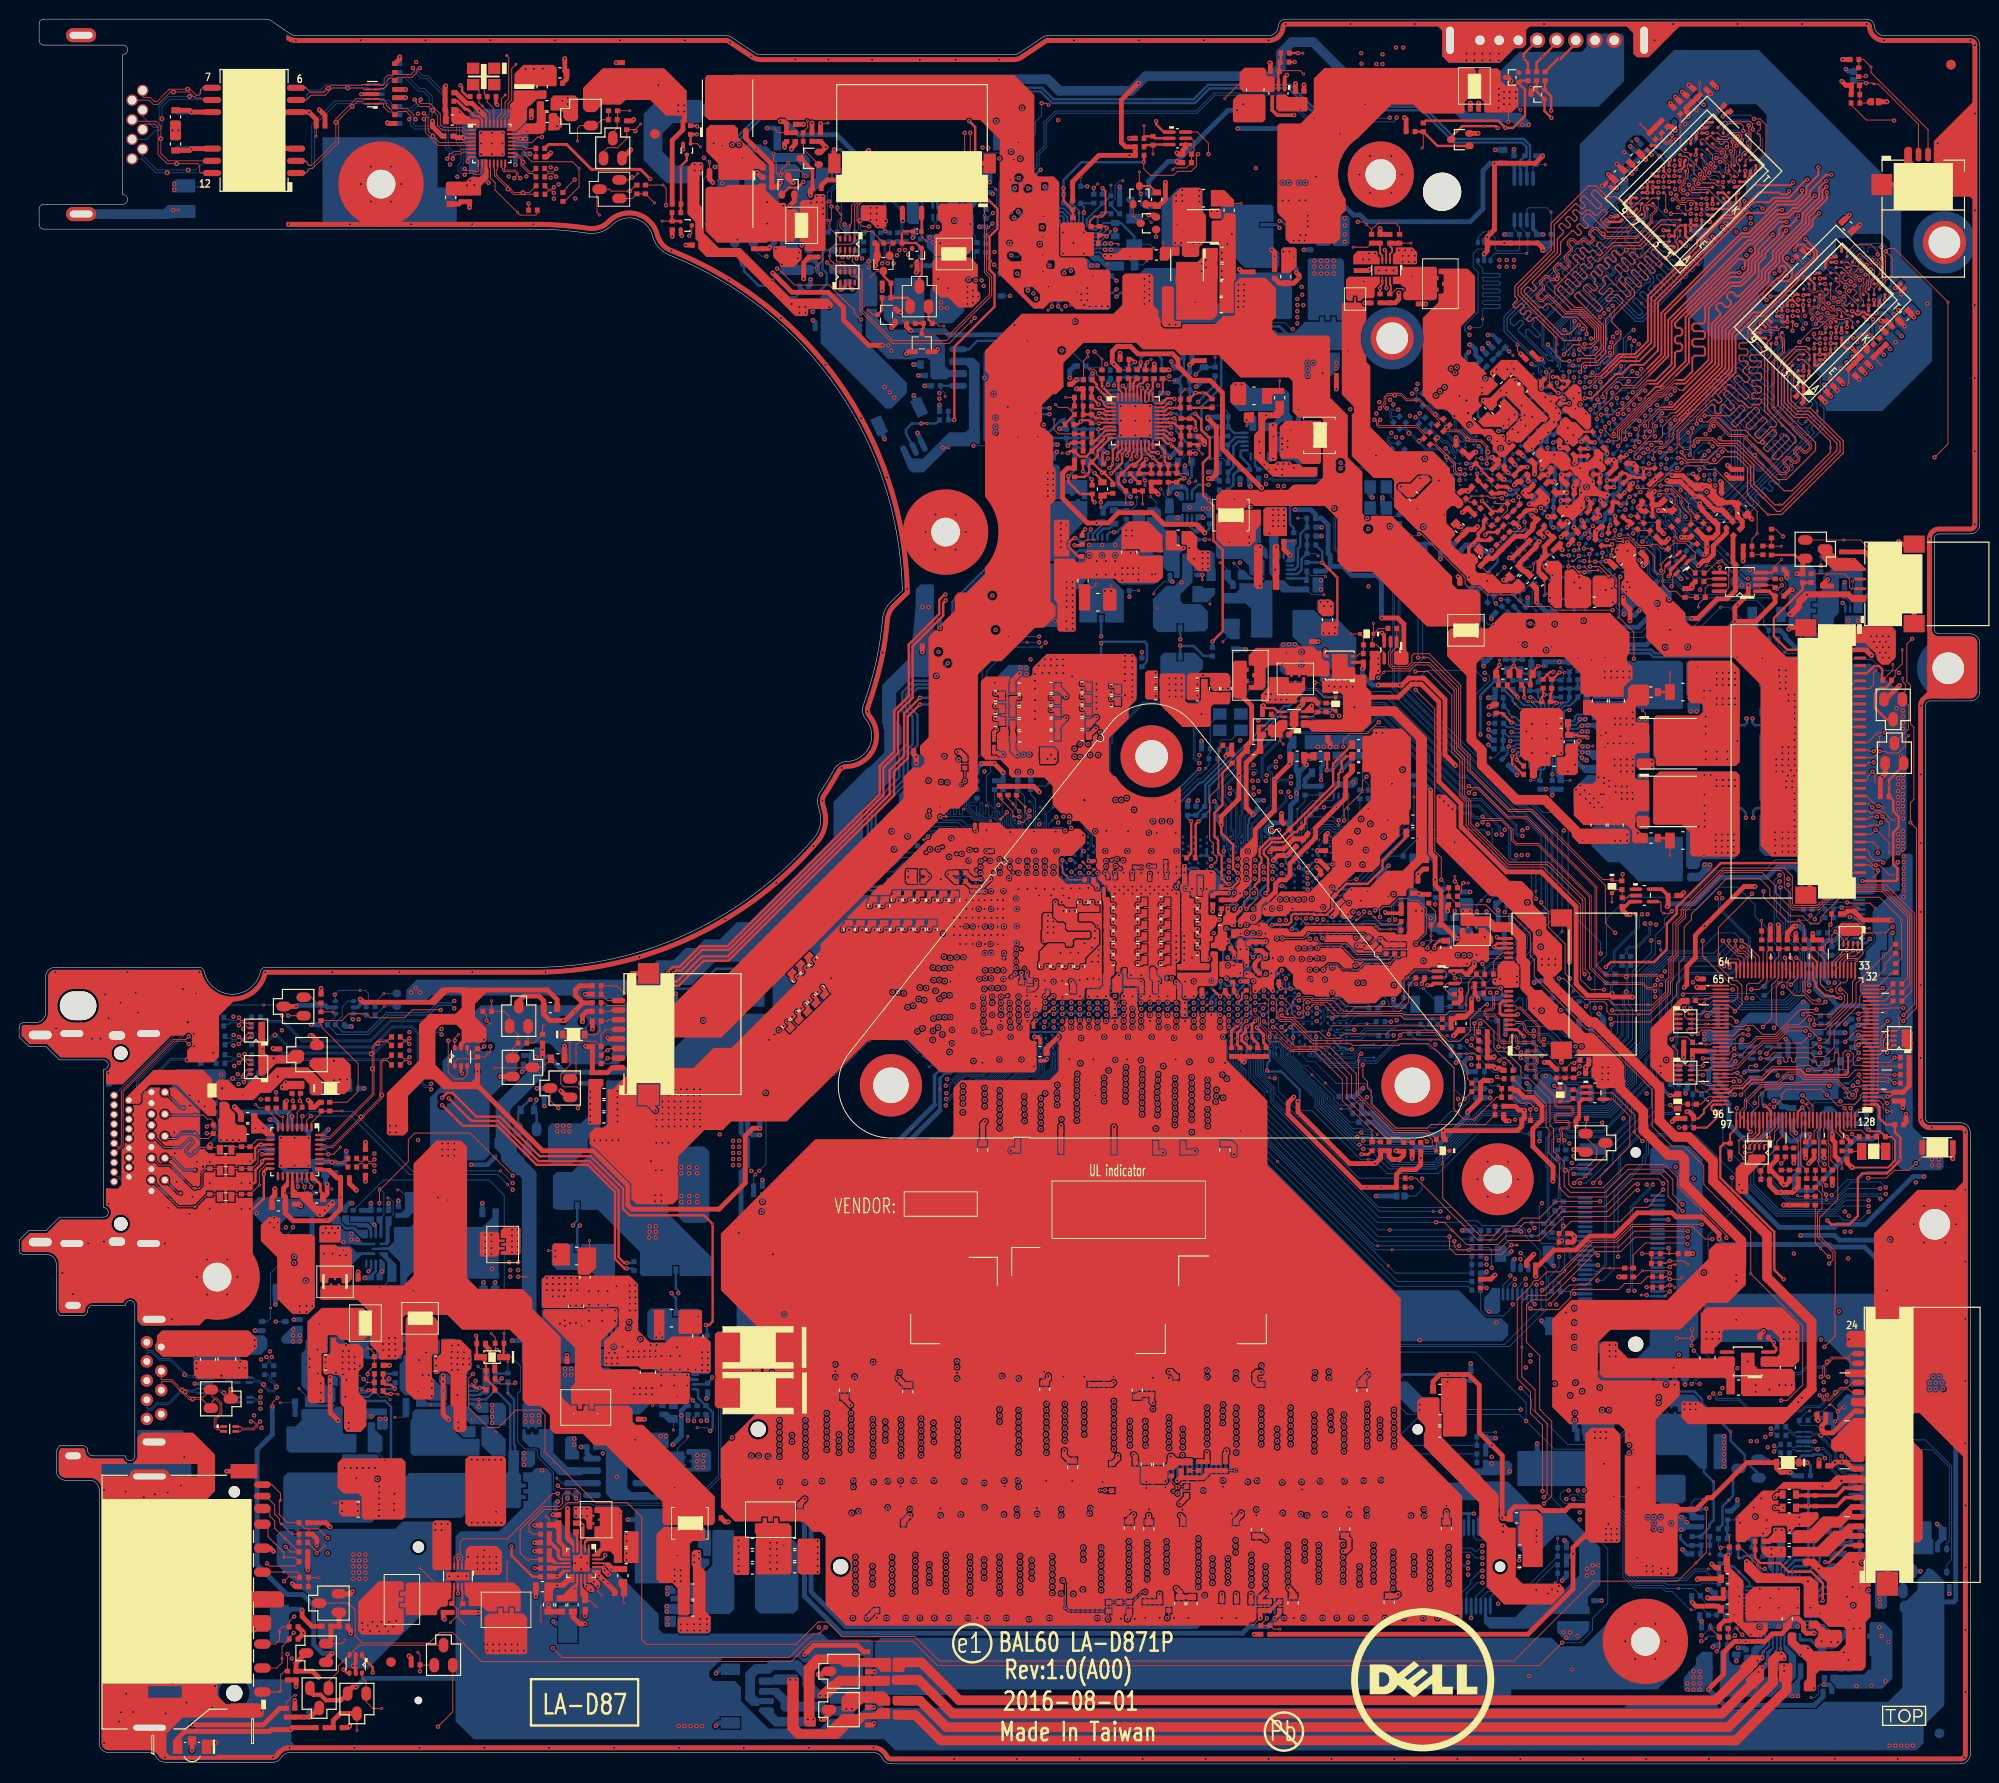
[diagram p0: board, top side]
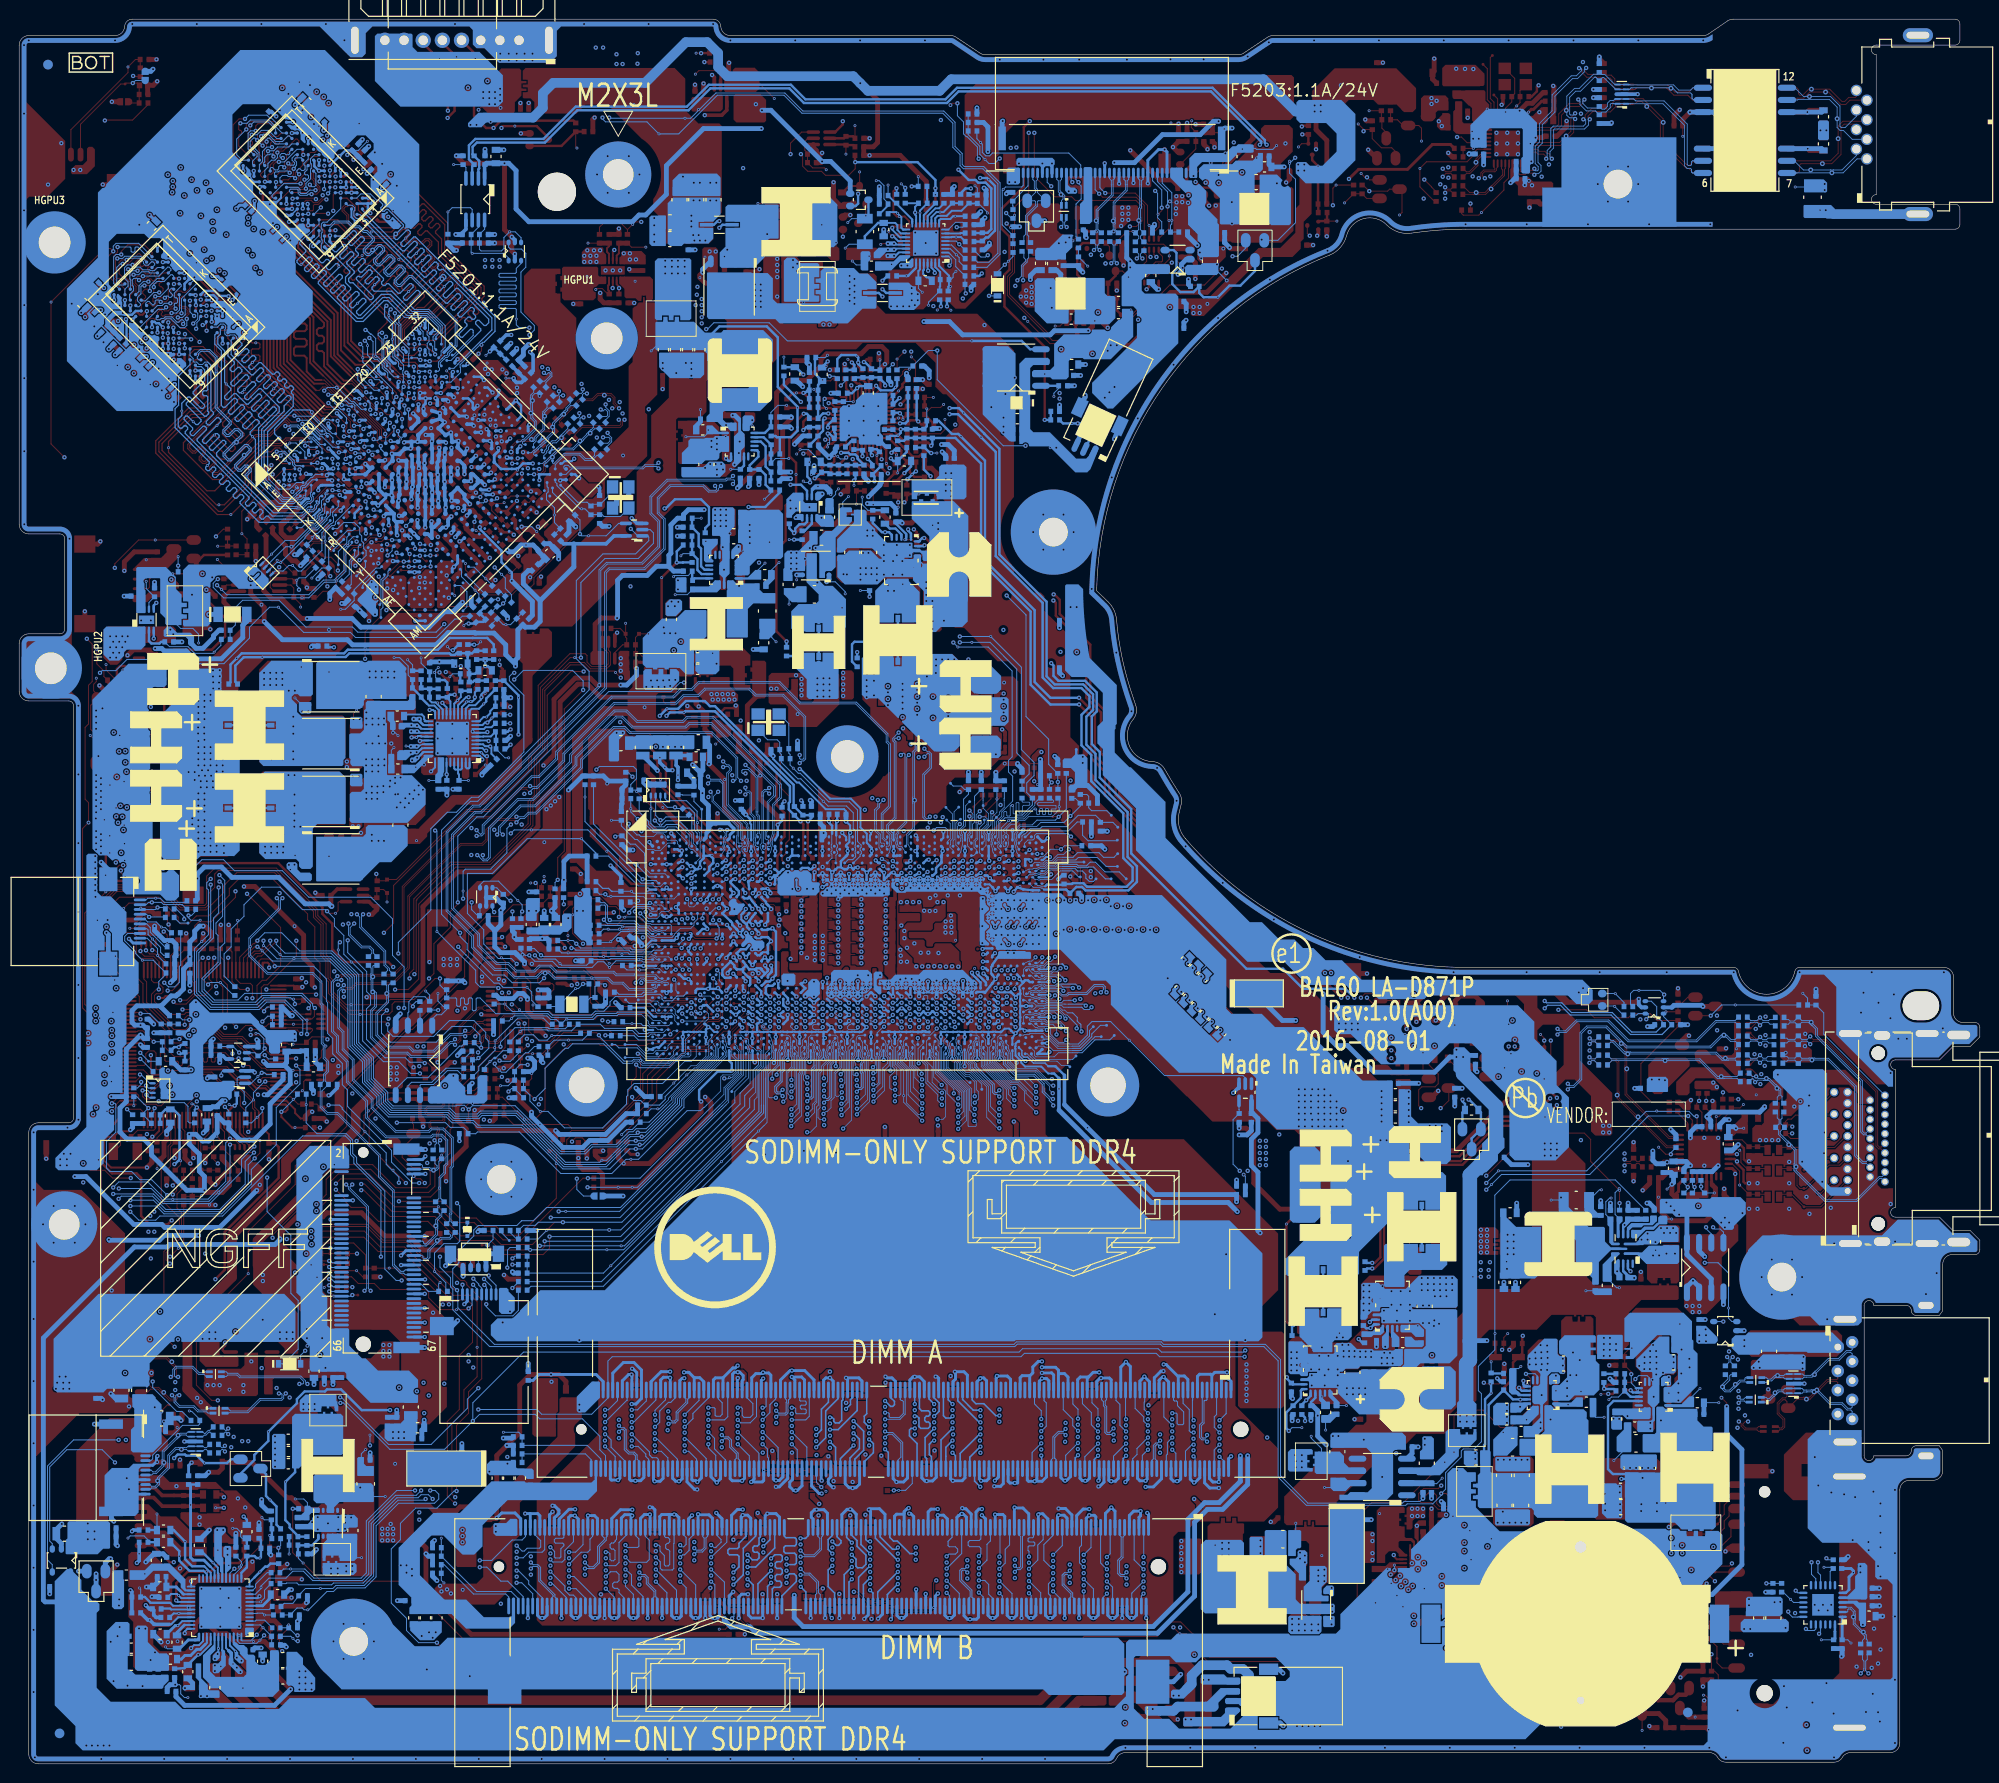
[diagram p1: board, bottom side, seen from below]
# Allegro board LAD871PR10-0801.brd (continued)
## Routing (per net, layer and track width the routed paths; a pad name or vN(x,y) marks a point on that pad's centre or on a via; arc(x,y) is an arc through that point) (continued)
PCH_POPIRCOMP: length 3
  TOP w0.305: RC89.1 130.1,74.93 129.81,75.22 v1(129.81,75.68) 129.81,76.08 v2(129.11,76.78)
  BOTTOM w0.254: v2(129.11,76.78) 129.4,77.08 UC1.AU16
PCH_RSMRST#: length 5.4
  TOP w0.102: UE1.88 178.8,71.97 178.9,72.07 v2(179.25,72.07)
  BOTTOM w0.102: RE355.1 178.75,71.88 178.94,72.07 v2(179.25,72.07) 179.27,72.07 v1(179.64,71.7) 179.64,71.68 180.34,70.98 UZ6.1
PCH_RSMRST#_Q: length 83.5
  TOP w0.102: v2(168.86,60.47) 168.51,60.47 165.63,57.59 161,57.59 158.47,55.07 155.17,55.07 154.27,54.17 151,54.17 v1(149.51,55.65) 148.67,56.49 v2(147.82,56.49)
  IN1 w0.127: v2(183.47,71.79) 181.62,69.94 180.65,69.94 180.05,69.34 176.95,69.34 168.86,61.26 v2(168.86,60.47)
  BOTTOM w0.076: UC1.AY17 128.72,75.13 128.46,74.86 128.46,74.67 128.35,74.56 128.35,74.33 128.31,74.23 128.29,74.2 128.29,70.99 128.53,70.75
  BOTTOM w0.102: v2(183.47,71.79) 183.47,72.11 183.3,72.28 UZ6.4 ; RC158.1 153.33,55.42 152.65,54.74 RC216.1 RC75.2 151.93,56.17 150.71,56.17 150.39,56.49 v2(147.82,56.49) 141.67,56.49 129.34,68.82 129.34,69.94 128.53,70.75
PCH_RTCRST#: length 57.5
  TOP w0.076: 137.38,73.41 136.12,74.67 132.79,74.67 131.04,76.42 130.66,76.42 130.34,76.73 130.34,79.58 v2(129.86,80.07)
  TOP w0.102: v2(146.87,64.9) 146.87,64.94 146.52,65.29 145.81,65.29 CC25.1 RC57.1 143.89,65.35 143.22,65.35 139,69.57 139,71.78 137.38,73.41 ; Q1901.1 165.5,63.4 v3(163.4,61.3) 163.12,61.02 162.68,61.02 v2(162.24,60.58)
  IN1 w0.127: v2(146.87,64.9) 146.87,61.54 v2(146.37,61.04)
  IN2 w0.127: v2(162.24,60.58) 161.19,60.58 157.08,64.69 147.08,64.69 v2(146.87,64.9)
  BOTTOM w0.089: UC1.AM16 129.5,80.42 v2(129.86,80.07)
  BOTTOM w0.102: v2(146.37,61.04) 146.37,59.92 145.68,59.22 CMOS1.1
PCH_RTCX1: length 21.4
  IN1 w0.076: 135.27,79.89 134.58,80.58 133.61,80.58 132.79,81.4 129.92,81.4 129.44,80.91 129.44,80.5 v2(128.95,80.01)
  IN1 w0.127: 135.27,79.89 135.91,79.25 140.52,79.25 142.49,81.22 v2(143.43,81.22)
  BOTTOM w0.089: v2(128.95,80.01) UC1.AM18
  BOTTOM w0.102: v2(143.43,81.22) 143.55,81.34 RC54.2 144.48,81.06 CC23.1 144.93,79.93 YC2.1
PCH_RTCX2: length 26.2
  IN1 w0.076: 135.35,80.41 134.8,80.96 133.72,80.96 133.12,81.56 129.31,81.56 128.48,80.74 128.48,80.44 128.01,79.97 v2(128.02,79.97)
  IN1 w0.127: 135.35,80.41 135.97,79.79 140.3,79.79 142.36,81.85 143.82,81.85 144.33,81.34 v2(145.73,81.34)
  BOTTOM w0.102: v2(128.02,79.97) 128,79.97 128,79.96 127.93,80.02 127.93,80.02 127.57,80.38 UC1.AM20 ; CC26.1 148.37,78.99 YC2.2 v1(146.5,80.86) 146.21,80.86 v2(145.73,81.34) RC54.1
PCH_SMB_ALERT#: length 12
  TOP w0.102: RC23.1 144.07,87.06 v1(141.92,87.06) 141.38,87.59 134.22,87.59 133.63,88.18 v2(133.27,88.18)
  BOTTOM w0.076: UC1.R10 133.27,88.57 v2(133.27,88.18)
PCH_SMBCLK: length 278.8
  TOP w0.102: v2(30.43,67.57) 30,67.14 U5502.2
  IN2 w0.127: v2(51.49,59.88) 54.48,59.88 55.37,60.77 62.73,60.77 63.56,59.94 72.49,59.94 73.21,59.23 73.21,54.29 73.78,53.72 73.78,43.86 75.18,42.46 v2(76.7,42.46) ; v2(156.65,39.18) v2(156.65,36.96) 156.65,35.6 157.19,35.05 157.19,21.63 156.78,21.22 v2(156.5,21.22) ; v2(171.06,38.23) 171.25,38.42 175,38.42 176.02,37.4 177.29,37.4 178.56,38.67 178.56,39.75 177.98,40.32 177.98,47.31 176.52,48.77 176.52,51.94 175.82,52.64 175.82,55.5 176.02,55.69 176.02,65.85 176.52,66.36 176.52,69.33 174.07,71.78 174.07,75.86 172.33,77.6 172.33,80.58 173.02,81.27 173.02,82.98 172.28,83.72 168.24,83.72 165.98,85.98 163,85.98 161.89,87.09 161.13,87.09 159.82,88.39 158.04,88.39 156.46,89.98 153.32,89.98 v2(153.28,90.02)
  BOTTOM w0.102: v2(153.28,90.02) 153.37,90.02 RN20.2 154.73,91.37 QC2.1 ; v2(30.43,67.57) 34.6,67.57 40.7,61.47 49.9,61.47 v1(50.96,60.41) v2(51.49,59.88) ; v2(76.7,42.46) 85.57,42.46 85.92,42.81 99.68,42.81 100.03,42.46 142.68,42.46 143.12,42.01 JDIMM1.253 143.12,38.16 144.82,36.47 150.04,36.47 150.53,36.96 v2(156.65,36.96) ; v2(156.65,39.18) 157.79,38.04 157.79,37.08 161.56,33.31 166.02,33.31 170.93,38.23 v2(171.06,38.23) ; v2(156.5,21.22) 155.24,21.22 153.11,23.35 152.08,23.35 151.72,23.7 JDIMM2.253
PCH_SMBDATA: length 291
  TOP w0.102: U5502.3 29.5,67.49 v2(29.55,67.54)
  IN2 w0.127: v2(157.22,35.75) 157.7,35.27 157.7,21.42 156.79,20.51 v2(156.5,20.51) ; v2(171.04,37.64) 171.11,37.64 171.63,38.16 174.87,38.16 175.89,37.15 177.43,37.15 178.81,38.52 178.81,39.88 178.28,40.41 178.28,47.4 176.78,48.89 176.78,52.06 176.12,52.72 176.12,55.42 176.27,55.57 176.27,65.71 176.78,66.22 176.78,69.8 176.23,70.35 176.23,76.37 175.95,76.64 173.98,76.64 172.6,78.03 172.6,80.48 173.28,81.16 173.28,83.08 172.38,83.97 168.37,83.97 166.11,86.23 163.12,86.23 161.98,87.38 161.22,87.38 159.95,88.65 159.06,88.65 157.85,89.85 v2(157.35,89.85) ; v2(76.64,43.12) 76.49,42.97 75.39,42.97 74.29,44.07 74.29,53.93 73.72,54.5 73.72,59.44 72.7,60.45 63.77,60.45 62.94,61.28 54.98,61.28 54.29,60.58 v2(51.49,60.58)
  BOTTOM w0.102: v2(51.49,60.58) v1(50.22,61.85) 41.01,61.85 34.81,68.05 30.34,68.05 29.83,67.54 v2(29.55,67.54) ; v2(156.5,20.51) 155.76,20.51 154.3,19.05 153.57,19.05 151.97,17.45 JDIMM2.254 ; v2(157.22,35.75) 160.17,32.8 165.88,32.8 170.72,37.64 v2(171.04,37.64) ; v2(157.22,35.75) 157.22,37.66 151.93,42.94 100.23,42.94 99.88,43.29 85.72,43.29 85.37,42.94 76.81,42.94 v2(76.64,43.12) ; v2(157.22,35.75) 156.52,36.45 150.71,36.45 150.24,35.98 145.79,35.98 143.97,34.16 143.97,32.75 143.37,32.16 JDIMM1.254 ; QC2.4 156.47,88.52 RN19.2 156.71,88.46 157.35,89.09 v2(157.35,89.85)
PCH_SPI_CLK_0_R: length 96.3
  TOP w0.102: v2(166.1,77.12) 166.35,77.38 170.15,77.38 172.89,80.12 172.89,81.31 173.17,81.58 173.17,83.52 173.7,84.06 173.7,87.28 174.46,88.04 174.46,88.65 178.14,92.33 181.6,92.33 182.63,91.3 182.63,90.59 184.78,88.44 186.07,88.44 186.89,87.61 187.66,87.61 187.96,87.91 187.96,88.31 190.04,90.39 194.09,90.39 196.39,88.09 v1(196.39,87.99) 196.39,84.08 RE413.1
  IN1 w0.127: v2(150.12,69.35) 149.85,69.62 149.85,72 148.81,73.04 148.81,75.93 147.64,77.1 143.43,77.1 v2(143.12,77.41) ; v2(156.07,67.19) 156.07,68.81 156.8,69.54 156.8,73.46 v2(156.64,73.62)
  IN2 w0.127: v2(156.07,67.19) 155.68,67.58 154.12,67.58 153.96,67.41 150.7,67.41 149.86,68.25 149.86,69.09 v2(150.12,69.35)
  BOTTOM w0.102: RC332.2 157.26,72.56 RC29.2 156.82,73.43 v2(156.64,73.62) 156.57,73.62 155.55,74.63 155.55,75.36 155.87,75.68 155.87,76.29 157.11,77.52 159.66,77.52 161.31,75.88 165.55,75.88 166.1,76.42 v2(166.1,77.12) ; v2(143.12,77.41) RC319.2
PCH_SPI_CLK_0_R3: length 7.6
  BOTTOM w0.102: RC332.1 160.03,72.56 161.5,71.08 163.62,71.08 164,70.71 UC5.6
PCH_SPI_CLK_R1: length 4.4
  BOTTOM w0.076: 138.93,77 138.76,76.83 138.16,76.83 137.9,76.57 UC1.AV2
  BOTTOM w0.102: 138.93,77 139.48,77 139.68,77.2 v1(140.62,77.2) 141.38,77.2 RC319.1
PCH_SPI_CS#0_R1: length 94.4
  TOP w0.102: RE410.2 197.45,80.61 197.45,88.53 194.54,91.45 189.51,91.45 187.58,89.52 185.21,89.52 184.99,89.74 184.99,92.58 184.15,93.43 177.73,93.43 173.39,89.09 173.39,88.48 172.52,87.61 172.52,84.38 172.1,83.96 172.1,82.03 171.77,81.69 171.77,80.5 170.44,79.18 v1(169.92,79.18) 166.37,79.18 165.83,79.71 163.36,79.71 161.16,81.91 v2(160.65,81.91)
  BOTTOM w0.076: UC1.AU3 137.37,77.26 137.63,77.53 138.41,77.53 139.28,78.4
  BOTTOM w0.102: v2(160.65,81.91) 160.65,81.22 160.18,80.75 RC339.2 RC37.1 159.01,79.88 158.91,79.78 158.91,79.11 158.81,79.01 158.6,79.01 158.5,79.11 158.5,79.78 158.4,79.88 158.2,79.88 158.09,79.78 158.09,79.32 157.99,79.22 157.79,79.22 157.69,79.32 157.69,79.78 157.59,79.88 157.38,79.88 157.28,79.78 157.28,78.65 157.18,78.55 156.98,78.55 156.88,78.65 156.88,79.78 156.77,79.88 156.46,79.88 154.82,78.24 149.39,78.24 149.01,77.86 144.77,77.86 144.36,78.27 142.26,78.27 142.14,78.4 139.28,78.4
PCH_SPI_CS#0_R2: length 4.8
  BOTTOM w0.102: v1(160.86,80.34) 160.86,79.55 160.28,78.97 RC37.2 159.95,78.68 160.5,78.13 161,78.13 161.46,77.68 UC5.1
PCH_SPI_D0_0_R: length 81.8
  TOP w0.102: RE414.1 197.23,81.27 197.23,88.44 194.44,91.22 189.61,91.22 187.67,89.29 185.12,89.29 184.76,89.64 184.76,90.79 184.15,91.41 184.15,92.81 183.78,93.18 177.8,93.18 173.62,89 173.62,88.39 172.84,87.61 172.84,84.38 172.33,83.86 172.33,81.93 172.06,81.66 172.06,80.46 170.18,78.59 v2(166.19,78.59) ; v2(156.36,74.69) v1(154.95,74.69) 154.44,74.69 v2(154.34,74.79)
  BOTTOM w0.102: RC318.2 147.15,77.1 147.58,76.68 149.27,76.68 149.38,76.79 152.82,76.79 154.34,75.27 v2(154.34,74.79) ; RC333.2 156.54,74.69 156.36,74.69 v2(156.36,74.69) 156.36,75.21 156.48,75.34 156.48,76.03 157.37,76.91 159.41,76.91 161.05,75.27 165.8,75.27 166.75,76.21 166.75,78.04 v2(166.19,78.59)
PCH_SPI_D0_0_R3: length 9.9
  BOTTOM w0.102: RC333.1 158.35,74.86 158.61,74.86 161.91,71.56 164.08,71.56 165.27,70.38 UC5.5
PCH_SPI_D0_R1: length 17.9
  BOTTOM w0.076: UC1.AV3 137.05,76.57 137.35,76.28 138.86,76.28 138.96,76.18
  BOTTOM w0.102: 138.96,76.18 139.88,76.18 140.41,76.71 143.48,76.71 143.91,77.14 RC318.1 146.93,76.45 149.37,76.45 149.48,76.56 152.09,76.56 v1(152.28,76.37) RC355.2
PCH_SPI_D1_0_R: length 84
  TOP w0.102: v2(163.47,79) 163.96,79.49 165.36,79.49 165.64,79.21 165.64,78.49 165.96,78.17 v1(168.97,78.17) 170.09,78.17 172.28,80.37 172.28,81.56 172.56,81.84 172.56,83.77 173.07,84.28 173.07,87.51 173.85,88.29 173.85,88.9 177.9,92.95 181.84,92.95 183.24,91.55 183.24,90.84 185.02,89.06 187.76,89.06 189.7,91 194.35,91 197,88.35 197,81.93 RE416.1
  IN2 w0.127: v2(143.4,75.99) 143.83,75.55 144.58,75.55 145.01,75.99 147.51,75.99 149.1,74.4 151.43,74.4 152.71,73.12 154.04,73.12 154.94,72.22 159.16,72.22 160.63,73.69 160.63,75.93 163.47,78.77 v2(163.47,79)
  BOTTOM w0.102: RC317.2 142.79,75.99 v2(143.4,75.99) ; RC329.1 163.14,79.5 163.47,79.17 v2(163.47,79)
PCH_SPI_D1_0_R3: length 1.6
  BOTTOM w0.102: RC329.2 162.73,78.57 UC5.2
PCH_SPI_D1_R1: length 5
  BOTTOM w0.089: UC1.AW3 137.51,75.68 138.04,75.68 138.23,75.5 139.95,75.5
  BOTTOM w0.102: RC317.1 140.39,75.95 139.95,75.5
PCH_SPI_D2_0_R: length 18.3
  IN2 w0.127: v2(160.84,78.61) 160.84,76.96 159.82,75.95 159.82,73.24 159.06,72.47 155.49,72.47 v2(154.93,73.02)
  BOTTOM w0.102: RC330.1 v2(160.84,78.61) ; v2(154.93,73.02) 154.93,72.83 v1(154.47,72.37) 154.23,72.14 153.76,72.14 151.73,74.17 151.44,74.17 150.79,74.82 RC327.2
PCH_SPI_D2_0_R3: length 6.4
  BOTTOM w0.102: UC5.3 164,78.33 163.9,78.43 163.9,79.49 163.38,80.01 162.21,80.01 RC330.2 161.73,80.19 v1(162.14,80.6)
PCH_SPI_D2_R1: length 13.6
  BOTTOM w0.076: UC1.AW2 138.16,76.01 138.26,76.11 138.65,76.11 138.9,75.86
  BOTTOM w0.102: RC30.2 RC327.1 148.73,75.48 v1(147.24,75.48) 145.78,75.48 RC354.2 144.79,76.48 140.56,76.48 139.95,75.86 138.9,75.86
PCH_SPI_D3_0_R: length 11.9
  BOTTOM w0.102: RC331.2 156.6,72.32 156.6,72.72 154.9,74.43 v1(154.9,75.4) 152.52,77.78 149.87,77.78 149.22,77.14 RC320.2
PCH_SPI_D3_0_R3: length 6.5
  BOTTOM w0.102: UC5.7 162.73,70.77 162.64,70.85 161.33,70.85 159.88,72.3 158.8,72.3 RC331.1
PCH_SPI_D3_R1: length 19.4
  BOTTOM w0.076: UC1.AU4 136.78,77 138.67,77 138.91,77.24 138.91,77.45 139.63,78.17
  BOTTOM w0.102: RC31.2 153.43,77.48 v1(153.17,77.74) 152.91,78.01 149.49,78.01 149.11,77.63 148.5,77.63 RC320.1 147.52,77.63 144.67,77.63 144.26,78.04 142.17,78.04 142.04,78.17 139.63,78.17
PCI_CLK_LPC1: length 26.6
  BOTTOM w0.076: 136.81,71.58 135.15,73.24 134.45,73.24 133.92,73.78 133.92,74.84 133.57,75.19 UC1.AY9
  BOTTOM w0.102: 136.81,71.58 137.42,70.96 140.39,70.96 141.05,70.3 141.05,69.74 141.19,69.6 141.19,68.82 143.68,66.33 147.66,66.33 149.37,68.05 v1(150.18,68.05) 151.27,69.13 151.27,69.75 RC18.1 151.94,71.3 RC22.1
PCIE_CALR_RX: length 1.4
  TOP w0.508: v2(156.04,135.53) 155.63,135.94 RV3.1
  BOTTOM w0.381: UV1.AA22 156.37,135.2 v2(156.04,135.53)
PCIE_CALR_TX: length 1.4
  TOP w0.508: RV1.1 156.55,136.78 v2(156.9,136.42)
  BOTTOM w0.381: v2(156.9,136.42) 156.9,136.42 157.39,135.93 UV1.Y22
PCIE_PRX_LANTX_N6: length 139.5
  TOP w0.091: C3016.2 55.18,166.05 55.7,166.05 v2(56.03,166.37)
  IN2 w0.076: 132.21,97.79 132.21,97.58 132.19,97.55 132.19,97.14 131.69,96.65 129.85,96.65 129.03,95.82 129.03,95 128.56,94.53 128.56,93.27 128.39,93.1 128.18,93.1 v2(128.02,92.94)
  IN2 w0.127: v2(56.03,166.37) 56.2,166.21 57.21,166.21 58.77,167.77 68.06,167.77 71.94,163.89 76.76,163.89 79.3,161.36 81.33,161.36 83.75,158.94 83.75,156.36 85.13,154.98 85.47,154.98 86.42,154.03 86.42,150.92 94.93,142.41 94.93,139.94 101.81,133.06 101.81,124.03 99.13,121.36 99.13,110.03 103.56,105.6 103.56,105.16 103.89,104.83 106.06,104.83 106.5,104.38 113.88,104.38 116.34,101.92 119.42,101.92 119.86,102.36 123.84,102.36 124.23,102.75 126.6,102.75 127.25,102.11 127.25,100.84 127.82,100.27 128.52,100.27 129.85,98.93 131.11,98.93 132.21,97.83 132.21,97.79
  BOTTOM w0.102: UC1.G18 v2(128.02,92.94)
PCIE_PRX_LANTX_P6: length 139.5
  TOP w0.091: v2(56.03,165.54) 55.7,165.87 55.18,165.87 C3014.2
  IN2 w0.076: v2(128.02,93.55) 128.02,93.43 128.18,93.27 128.32,93.27 128.39,93.34 128.39,94.6 128.86,95.07 128.86,95.89 129.78,96.81 131.62,96.81 132.02,97.21 132.02,97.65
  IN2 w0.127: 132.02,97.65 131,98.68 129.74,98.68 128.41,100.01 127.71,100.01 126.99,100.73 126.99,102 126.49,102.5 124.34,102.5 123.95,102.11 119.97,102.11 119.53,101.67 116.23,101.67 113.78,104.12 106.4,104.12 105.95,104.57 103.78,104.57 103.31,105.05 103.31,105.49 98.87,109.93 98.87,121.46 101.55,124.14 101.55,132.95 94.67,139.83 94.67,142.31 86.16,150.81 86.16,153.92 85.37,154.72 85.03,154.72 83.49,156.26 83.49,158.83 81.23,161.1 79.19,161.1 76.66,163.64 71.83,163.64 67.95,167.52 58.87,167.52 57.31,165.96 55.92,165.96 55.83,165.87 55.83,165.74 v2(56.03,165.54)
  BOTTOM w0.102: UC1.F18 v2(128.02,93.55)
PCIE_PRX_WLANTX_N5: length 109.3
  TOP w0.091: v2(170.68,80.58) 170.47,80.79 169.83,80.79 169.35,81.28 165.56,81.28 163.82,83.01 163.82,90.42 158.43,95.82 156.19,95.82 155.68,96.33 155.68,97.35 154.63,98.4 152.87,98.4 v2(152.67,98.2)
  IN2 w0.076: v2(128.92,93.63) 128.92,93.71 129.55,94.34 129.55,95.53 130.1,96.08 131.95,96.08 133.41,97.54 133.41,97.55
  IN2 w0.127: 133.41,97.55 133.41,98.38 130.09,101.7 129.92,101.87 129.92,102.36 v2(130.08,102.52)
  BOTTOM w0.091: v2(170.68,80.58) 170.68,80.74 170.74,80.81 170.91,80.81 171.13,80.59 171.13,76.84 170.67,76.38 170.67,74.54 169.61,73.48 169.61,71.37 167.64,69.4 167.64,68.46 165.24,66.06 161.84,66.06 161.58,66.31 160.27,66.31 159.26,65.31 159.26,62.29 159.42,62.14 159.42,57.38 159.49,57.3 159.49,56.55 159.28,56.34 R5808.2 ; v2(130.08,102.52) 129.89,102.52 129.77,102.65 129.77,104.88 132.35,107.46 140.86,107.46 141.41,108.02 142.48,108.02 145.79,104.71 145.79,103.88 150.6,99.07 151.37,99.07 151.83,98.6 152.27,98.6 v2(152.67,98.2)
  BOTTOM w0.102: UC1.F16 v2(128.92,93.63)
PCIE_PRX_WLANTX_N5_R: length 6.1
  BOTTOM w0.091: 162.49,52.52 161.99,52.52 161.7,52.81 161.7,53.56 161.04,54.22 160.99,54.22 160.48,54.73 159.58,54.73 159.38,54.93 159.38,55.11 R5808.1
  BOTTOM w0.102: 162.49,52.52 WLAN1.35
PCIE_PRX_WLANTX_P5: length 109.2
  TOP w0.091: v2(170.68,81.22) 170.44,80.98 169.91,80.98 169.42,81.46 165.63,81.46 164,83.09 164,90.5 158.5,96 156.26,96 155.86,96.41 155.86,97.43 154.71,98.58 152.87,98.58 v2(152.67,98.78)
  IN2 w0.076: 133.15,97.55 133.15,97.51 131.88,96.24 130.04,96.24 129.39,95.59 129.39,94.41 129.24,94.26 v2(128.96,94.26)
  IN2 w0.127: 133.15,97.55 133.15,98.27 129.91,101.52 129.66,101.76 129.66,102.63 129.59,102.7 129.42,102.7 v2(129.24,102.52)
  BOTTOM w0.091: v2(129.24,102.52) 129.59,102.87 129.59,104.96 132.27,107.64 140.78,107.64 141.34,108.2 142.56,108.2 145.97,104.79 145.97,103.96 150.68,99.25 151.44,99.25 151.91,98.78 v2(152.67,98.78) ; v2(170.68,81.22) 170.91,80.99 170.98,80.99 171.31,80.66 171.31,76.76 170.85,76.31 170.85,74.46 169.79,73.41 169.79,71.3 167.82,69.32 167.82,68.38 165.31,65.87 161.76,65.87 161.51,66.13 160.34,66.13 159.45,65.23 159.45,62.36 159.6,62.21 159.6,57.46 159.67,57.38 159.67,56.61 R5811.2
  BOTTOM w0.102: UC1.E16 v2(128.96,94.26)
PCIE_PRX_WLANTX_P5_R: length 6.1
  BOTTOM w0.091: R5811.1 159.81,55.42 159.56,55.17 159.56,55 159.65,54.91 160.6,54.91 v4(160.93,54.58) 161.91,53.6 161.91,52.85 162.07,52.7 162.32,52.7 162.42,52.81 162.42,52.91 162.53,53.02 WLAN1.33
PCIE_PTX_LANRX_N6: length 129.6
  TOP w0.091: v2(55.78,164.44) 55.58,164.24 55.2,164.24 C6206.2
  IN2 w0.127: v2(126.3,101.78) 126.14,101.62 120.11,101.62 119.71,101.22 116.05,101.22 113.58,103.69 106.22,103.69 105.77,104.14 103.56,104.14 103.07,104.63 102.59,104.63 102.23,104.99 102.23,105.96 98.42,109.77 98.42,121.73 101.04,124.35 101.04,130.63 92.96,138.72 92.96,142.16 85.34,149.78 85.34,153.02 83.05,155.3 83.05,158.48 80.94,160.59 78.6,160.59 76.13,163.07 71.54,163.07 68.36,166.25 61.74,166.25 60.91,165.42 58.85,165.42 57.47,164.05 57,164.05 56.77,164.28 55.95,164.28 v2(55.78,164.44)
  BOTTOM w0.076: 127.07,100.96 127.07,100.95 127.06,100.94 127.06,96.05 127.24,95.87 127.24,95.57 UC1.D20
  BOTTOM w0.091: 127.07,100.96 127.07,101.35 126.79,101.63 126.46,101.63 v2(126.3,101.78)
PCIE_PTX_LANRX_N6_C: length 6.5
  TOP w0.091: 49.79,165.73 49.85,165.67 49.85,165.66 50.89,164.62 50.94,164.62 51.36,164.21 51.36,164.16 51.63,163.88 v4(52.55,163.88) 53.22,163.88 C6206.1
  TOP w0.102: 49.79,165.73 49.78,165.75 49.78,166.24 49.91,166.37 LOM30.14
PCIE_PTX_LANRX_P6: length 129.6
  TOP w0.091: v2(55.78,163.86) 55.58,164.06 55.2,164.06 C6205.2
  IN2 w0.127: v2(126.3,101.2) 126.14,101.36 120.22,101.36 119.82,100.96 115.94,100.96 113.47,103.44 106.11,103.44 105.66,103.88 103.45,103.88 102.96,104.37 102.49,104.37 101.98,104.88 101.98,105.85 98.16,109.66 98.16,121.83 100.78,124.46 100.78,130.53 92.7,138.61 92.7,142.05 85.08,149.67 85.08,152.91 82.79,155.2 82.79,158.37 80.83,160.34 78.5,160.34 76.02,162.81 71.43,162.81 68.26,165.99 61.84,165.99 61.02,165.16 58.95,165.16 57.58,163.79 56.89,163.79 56.66,164.02 55.95,164.02 v2(55.78,163.86)
  BOTTOM w0.076: UC1.C20 127,95.65 127,95.49 126.88,95.37 126.79,95.37 126.65,95.51 126.65,95.91 126.72,95.98 126.83,95.98 126.89,96.05 126.89,100.94 126.89,100.95 126.89,100.96
  BOTTOM w0.091: 126.89,100.96 126.89,101.28 126.71,101.45 126.56,101.45 126.48,101.38 v2(126.3,101.2)
PCIE_PTX_LANRX_P6_C: length 6.5
  TOP w0.091: C6205.1 52.87,163.7 52.84,163.67 52.25,163.67 52.22,163.7 51.55,163.7 v4(51,164.26) 49.68,165.58 49.62,165.64
  TOP w0.102: LOM30.13 49.51,166.39 49.59,166.3 49.59,165.67 49.62,165.64
PCIE_PTX_WLANRX_N5: length 5.8
  BOTTOM w0.091: CV310.2 160.46,57.47 160.46,57.12 160.91,56.67 160.91,56.44 160.88,56.4 160.88,55.81 160.91,55.78 160.91,55.17 162.06,54.02 162.16,54.02
  BOTTOM w0.102: WLAN1.29 162.16,54.02
PCIE_PTX_WLANRX_N5_C: length 121
  TOP w0.091: v2(170.94,81.75) 170.94,82.09 170.86,82.17 165.49,82.17 164.41,83.25 164.41,91.43 157.19,98.65 155.2,98.65 152.19,101.66 151.64,101.66 v2(151.25,101.27)
  IN2 w0.127: v2(128.79,101.82) 128.55,101.58 128.23,101.58 128.14,101.68 128.14,102.56 127.19,103.51 125.64,103.51 124.22,104.93 123.41,104.93 v2(123.12,105.22)
  BOTTOM w0.076: UC1.C19 127.41,95.48 127.41,95.6 127.5,95.69 127.63,95.69 127.72,95.79 127.77,95.95 127.77,96.12 127.72,96.31 127.72,96.46 127.77,96.58 127.77,98.76 128.14,99.12 128.14,101.25 128.35,101.47 128.7,101.47 128.79,101.56 v2(128.79,101.82)
  BOTTOM w0.091: CV310.1 160.57,58.98 160.57,61.1 160.07,61.6 160.07,62.3 159.84,62.53 159.84,65.07 160.44,65.67 161.41,65.67 161.6,65.48 166.25,65.48 168.22,67.45 168.22,69.16 170.24,71.18 170.24,73.28 171.25,74.29 171.25,75.91 171.78,76.44 171.78,81.48 171.51,81.75 171.35,81.75 v2(170.94,81.75) ; v2(151.25,101.27) 151.25,101.41 150.92,101.74 150.48,101.74 147.64,104.57 147.64,105.31 142.42,110.53 136,110.53 135.2,111.32 133.65,111.32 132.96,112.01 128.39,112.01 127.76,111.38 124.9,111.38 122.68,109.16 122.68,104.89 122.78,104.78 123.05,104.78 123.12,104.85 v2(123.12,105.22)
PCIE_PTX_WLANRX_P5: length 5.8
  BOTTOM w0.091: 162.16,54.22 162.11,54.22 161.09,55.24 v4(161.09,56.11) 161.09,56.74 160.64,57.2 160.64,57.35 161,57.71 CV311.2
  BOTTOM w0.102: WLAN1.27 162.46,54.52 162.36,54.42 162.36,54.33 162.26,54.22 162.16,54.22
PCIE_PTX_WLANRX_P5_C: length 121
  TOP w0.091: v2(171.35,82.16) 171.13,82.16 170.93,82.35 165.56,82.35 164.59,83.32 164.59,91.5 157.26,98.83 155.28,98.83 152.26,101.84 151.39,101.84 v2(151.25,101.98)
  IN2 w0.127: v2(123.12,104.38) 123.41,104.67 124.11,104.67 125.53,103.25 127.08,103.25 127.88,102.45 127.88,101.57 128.13,101.33 128.57,101.33 v2(128.79,101.11)
  BOTTOM w0.076: UC1.D19 127.72,95.06 127.88,95.61 127.88,95.72 127.94,95.92 127.94,96.17 127.9,96.26 127.9,96.45 127.94,96.55 127.94,98.69 128.3,99.05 128.3,101.18 128.42,101.3 128.59,101.3 v2(128.79,101.11)
  BOTTOM w0.091: v2(151.25,101.98) 151.19,101.92 150.55,101.92 147.82,104.65 147.82,105.38 142.5,110.71 136.07,110.71 135.28,111.5 133.73,111.5 133.04,112.19 128.32,112.19 127.68,111.56 124.82,111.56 122.5,109.23 122.5,104.81 122.71,104.6 122.9,104.6 v2(123.12,104.38) ; CV311.1 160.75,58.98 160.75,61.17 160.25,61.68 160.25,62.38 160.02,62.6 160.02,64.99 160.52,65.49 161.33,65.49 161.52,65.3 166.32,65.3 168.4,67.37 168.4,69.09 170.42,71.11 170.42,73.2 171.43,74.22 171.43,75.84 171.96,76.36 171.96,81.55 v2(171.35,82.16)
PCIE_RCOMPN: length 1.4
  TOP w0.508: RC45.1 135.8,93.1 v2(135.37,93.53)
  BOTTOM w0.254: UC1.F5 135.38,93.53 v2(135.37,93.53)
PCIE_RCOMPP: length 1.9
  TOP w0.508: v2(135.36,94.18) 135.7,94.18 RC45.2
  BOTTOM w0.254: UC1.E5 v2(135.36,94.18)
PCIE_WAKE#: length 287.8
  TOP w0.102: v2(173.54,57.66) 172.01,59.18 172.01,60.77 171.25,61.53 168.08,61.53 165.67,59.12 161.63,59.12 v1(160.7,60.05) 160.7,62.58 159.59,63.69 159.59,66.14 159.3,66.43 159.3,68.84 157.93,70.22 157.07,70.22 RC395.1 ; v2(54.54,169.67) 54.07,169.67 53.49,169.09 52,169.09 51.89,169.2 LOM30.21 ; v2(183.09,68.52) 183.89,69.32 183.89,69.85 184.4,70.36 188.02,70.36 v2(188.59,69.79) 189.73,68.64 190.11,68.64 190.26,68.8 191.54,68.8 192.08,69.34 192.08,69.72 192.33,69.97 UE1.4
  IN1 w0.127: v2(54.54,169.67) 54.54,163.39 55.49,162.43 59.66,162.43 60.81,163.58 70.12,163.58 76.88,156.82 80.35,156.82 80.73,156.44 80.73,154.71 82.45,152.98 87.42,152.98 89.19,154.75 90.6,154.75 97.19,148.16 105.11,148.16 107.49,145.78 112.75,145.78 112.99,145.54 115.1,145.54 116.39,146.84 122.53,146.84 123.72,145.65 123.72,142.65 125.43,140.93 125.43,138.92 128.05,136.3 128.05,132.99 128.86,132.18 129.18,132.18 130.13,131.23 130.13,128.82 130.52,128.42 131.96,128.42 132.58,127.8 132.58,126.75 134.93,124.4 134.93,123.44 135.46,122.91 137.57,122.91 139.41,121.07 139.41,114.34 140.61,113.15 140.61,107.19 142,105.8 142,100.59 147.38,95.21 151.86,95.21 153.76,93.32 158.08,93.32 161.23,90.17 161.23,88.93 163.61,86.55 165.6,86.55 167.38,84.77 173.15,84.77 173.78,84.14 178.07,84.14 178.96,83.25 181.67,83.25 182.24,82.68 189.54,82.68 190.95,81.27 190.95,79.45 189.32,77.83 189.32,73.26 188.31,72.24 188.31,70.07 v2(188.59,69.79) 188.59,67.48 187.74,66.63 187.74,64.18 187.9,64.02 187.9,62.11 187.6,61.81 187.6,58.07 185.85,56.32 177.62,56.32 176.29,57.66 v2(173.54,57.66)
  BOTTOM w0.102: RE354.2 182.68,68.11 v2(183.09,68.52)
PD#: length 5.3
  TOP w0.102: v2(179,13.4) 178.81,13.21 R2708.2 R6512.2
  BOTTOM w0.102: v2(179,13.4) 179,13.33 v1(179.43,12.9) 179.76,12.57 181.54,12.57 181.77,12.8 HDA27.47
PECI_EC: length 98.3
  TOP w0.102: v2(172.27,68.71) 172.63,68.35 DE8.1 173.49,68.81 RE353.2
  IN2 w0.127: v2(109.14,97.35) 109.34,97.15 109.34,96.77 110.48,95.63 111.44,95.63 112.32,94.74 112.32,93.92 112.9,93.34 112.9,92.71 113.18,92.42 124.04,92.42 124.71,91.76 124.71,89.66 124.07,89.03 124.07,85.92 125.6,84.39 125.6,82.99 125.85,82.74 126.23,82.74 126.93,82.04 127.74,82.04 128.57,81.22 129.03,81.22 129.5,81.69 131.74,81.69 132.25,81.17 132.25,80.57 132.58,80.24 132.58,78.11 133.71,76.98 133.71,76.88 137.15,73.44 140.52,73.44 142.07,71.89 142.07,69.49 144.02,67.54 149.36,67.54 150.4,66.5 161.14,66.5 163.32,64.33 163.32,62.23 v2(164.94,60.61)
  BOTTOM w0.076: UC1.A54 107.68,97.4
  BOTTOM w0.102: v2(164.94,60.61) 164.94,61.2 166.26,62.52 166.26,62.99 166.26,63.71 v1(168.47,65.93) 170.85,68.3 170.85,68.43 171.13,68.71 v2(172.27,68.71) ; v2(109.14,97.35) 108.83,97.66 107.94,97.66 107.68,97.4
PECI_MEC1404: length 2.8
  TOP w0.102: RE353.1 175.46,68.81 v1(175.96,69.31) 176.22,69.57 UE1.94
PEG_CLKREQ#: length 124.9
  TOP w0.102: RC189.2 151.9,74.55 v2(151.49,74.96)
  IN2 w0.076: v2(135.38,77.47) 135.46,77.38 139.04,77.38 139.25,77.18
  IN2 w0.127: 139.25,77.18 139.93,76.5 147.76,76.5 149.3,74.96 v2(151.49,74.96) 152.22,74.96 152.56,75.3 154.43,75.3 154.83,74.9 155.92,74.9 156.34,75.33 158.09,75.33 158.89,76.12 158.89,76.81 160,77.93 160,78.72 160.8,79.51 163.87,79.51 164.38,79 v2(164.38,78.83) ; v2(175.36,122.46) 175.36,122.26 176.1,121.51 191.27,121.51 192.53,120.26 192.53,113.73 191.83,113.03 191.83,98.62 189.99,96.77 189.99,93.84 v2(189.51,93.37)
  BOTTOM w0.076: UC1.AR10 132.89,78.47 132.64,78.23 132.64,77.72 132.9,77.47 v2(135.38,77.47)
  BOTTOM w0.102: v2(189.51,93.37) 189.51,93.37 189.2,93.69 186.1,93.69 185.49,94.3 183.23,94.3 182.08,93.15 177.1,93.15 174.33,90.39 167.85,90.39 165.6,88.14 165.6,84.33 164.39,83.12 164.39,78.84 v2(164.38,78.83) ; RV153.1 174.68,123.7 175.35,123.7 v1(175.59,123.46) 175.59,122.89 175.36,122.66 v2(175.36,122.46)
PEG_CLKREQ#_G: length 7.4
  BOTTOM w0.102: RV153.2 172.62,125.76 v1(172.62,127.53) 172.62,128.46 171.94,129.15 171.7,129.15 171.56,129.29 171.56,129.53 169.85,131.24 UV1.N7
PEG_GTX_C_HRX_N0: length 65.3
  IN2 w0.076: v2(130.76,93.04) 130.63,93.04 130.53,92.94 130.53,92.78 130.63,92.68 131.06,92.68 131.17,92.79 131.17,94.04 131.48,94.35 132.25,94.35 134.59,96.69 135.37,96.69 135.97,97.29 135.97,97.37 135.94,97.4 135.94,97.42
  IN2 w0.127: 135.94,97.42 135.94,98.99 137.06,100.11 141.81,100.11 149.65,107.96 149.65,123.22 148.9,123.97 148.9,125.94 147.82,127.02 147.82,131.91 147.45,132.28 147.45,135.93 144.19,139.19 143.9,139.19 143.63,138.93 143.63,138.81 143.8,138.64 143.8,138.52 v2(143.63,138.36)
  BOTTOM w0.091: CV2.1 143.14,137.74 142.92,137.96 142.92,138.24 143.03,138.36 v2(143.63,138.36)
  BOTTOM w0.102: UC1.G13 131.15,92.66 v2(130.76,93.04)
PEG_GTX_C_HRX_N1: length 67.4
  IN2 w0.076: 136.84,97.39 136.84,97.37 136.84,97.37 136.89,97.32 136.89,96.55 136.67,96.33 134.96,96.33 132.49,93.86 132.49,93.56 132.2,93.27 131.62,93.27 131.51,93.37 131.51,93.69 131.58,93.75 v2(131.71,93.75)
  IN2 w0.127: 136.84,97.39 136.84,98.62 137.44,99.22 142.18,99.22 150.55,107.59 150.55,125.56 148.71,127.4 148.71,135.96 144.42,140.25 144.42,141.32 144.05,141.69 143.84,141.69 143.72,141.57 143.72,141.42 v2(143.88,141.26)
  BOTTOM w0.091: CV4.1 143.26,140.53 143.18,140.62 143.18,141.05 143.36,141.24 143.49,141.24 143.61,141.12 143.74,141.12 v2(143.88,141.26)
  BOTTOM w0.102: UC1.F11 v2(131.71,93.75)
PEG_GTX_C_HRX_N2: length 69.3
  TOP w0.091: v2(141.4,140.19) 141.6,139.99 141.6,139.64 141.84,139.39 145.81,139.39 146.55,138.65 CV6.1
  IN2 w0.076: v2(128.9,93.06) 128.8,92.96 128.8,92.79 128.9,92.69 129.19,92.69 129.3,92.8 129.3,93.81 129.91,94.41 129.91,95.33 130.25,95.67 132.07,95.67 134.15,97.75 134.15,97.78
  IN2 w0.127: 134.15,97.78 134.15,100.17 135.87,101.9 140.31,101.9 147.57,109.16 147.57,122.46 145.37,124.66 145.37,130.64 145.47,130.75 145.47,134.51 143.83,136.15 143.62,136.15 141.53,138.23 141.53,140.06 v2(141.4,140.19)
  BOTTOM w0.102: UC1.G16 v2(128.9,93.06)
PEG_GTX_C_HRX_N3: length 72.8
  TOP w0.091: CV8.1 148.19,140.28 146.11,142.36 144.78,142.36 144.21,142.93 143.83,142.93 143.8,142.96 143.21,142.96 143.17,142.93 142.79,142.93 142.4,142.53 142.4,141.94 142.17,141.72 142.17,141.59 v2(141.97,141.38)
  IN2 w0.076: v2(129.84,93.58) 129.84,93.43 129.93,93.34 130.16,93.34 130.24,93.42 130.24,94.4 130.66,94.82 131.98,94.82 134.18,97.02 135.02,97.02 135.09,97.08 135.09,97.32 135.04,97.37 135.04,97.39
  IN2 w0.127: v2(141.97,141.38) 142.1,141.38 142.33,141.16 142.33,140.81 142.74,140.4 142.74,139.74 142.42,139.43 142.42,138.6 143.96,137.07 144.42,137.07 146.53,134.96 146.53,130.97 146.91,130.6 146.91,124.39 148.59,122.7 148.59,108.92 148.46,108.79 140.68,101 136.24,101 135.04,99.8 135.04,97.39
  BOTTOM w0.102: UC1.F15 v2(129.84,93.58)
PEG_GTX_C_HRX_P0: length 65.3
  IN2 w0.076: 136.2,97.42 136.2,97.4 136.14,97.33 136.14,97.22 135.44,96.52 134.66,96.52 132.32,94.18 131.55,94.18 131.34,93.98 131.34,92.72 131.13,92.51 130.97,92.51 v2(130.76,92.3)
  IN2 w0.127: v2(143.16,138.82) 143.79,139.45 144.3,139.45 147.71,136.04 147.71,132.38 148.07,132.02 148.07,127.13 149.15,126.05 149.15,124.08 149.91,123.32 149.91,107.85 141.91,99.86 137.17,99.86 136.2,98.89 136.2,97.42
  BOTTOM w0.091: CV1.1 143.24,137.37 142.74,137.88 142.74,138.32 143.16,138.74 v2(143.16,138.82)
  BOTTOM w0.102: UC1.H13 131.05,92.01 v2(130.76,92.3)
PEG_GTX_C_HRX_P1: length 67.4
  IN2 w0.076: v2(131.71,92.88) 131.94,93.11 132.27,93.11 132.65,93.49 132.65,93.79 135.03,96.16 136.73,96.16 137.05,96.48 137.05,97.35 137.09,97.39
  IN2 w0.127: 137.09,97.39 137.09,98.51 137.55,98.96 142.28,98.96 150.81,107.49 150.81,125.66 148.96,127.51 148.96,136.06 144.67,140.36 144.67,141.43 144.16,141.94 143.74,141.94 143.58,141.79 v2(143.37,141.79)
  BOTTOM w0.091: CV3.1 143.37,140.17 143,140.54 143,141.13 143.37,141.5 v2(143.37,141.79)
  BOTTOM w0.102: v2(131.71,92.88) 132.07,92.88 132.15,92.8 UC1.G11
PEG_GTX_C_HRX_P2: length 69.3
  TOP w0.091: v2(141.99,140.19) 141.78,139.98 141.78,139.71 141.92,139.57 145.88,139.57 146.7,138.75 147.05,138.75 CV5.1
  IN2 w0.076: v2(128.89,92.31) 129.1,92.53 129.26,92.53 129.47,92.73 129.47,93.74 130.08,94.34 130.08,95.26 130.31,95.5 132.14,95.5 134.4,97.77
  IN2 w0.127: 134.4,97.77 134.4,100.06 135.98,101.64 140.41,101.64 147.83,109.05 147.83,122.57 145.62,124.77 145.62,130.54 145.73,130.64 145.73,134.62 143.94,136.4 143.72,136.4 141.79,138.34 141.79,139.99 v2(141.99,140.19)
  BOTTOM w0.102: UC1.H16 129.1,92.31 v2(128.89,92.31)
PEG_GTX_C_HRX_P3: length 72.8
  TOP w0.091: CV7.1 148.19,139.89 148.19,140.02 146.03,142.18 144.71,142.18 144.14,142.75 v4(143.5,142.75) 142.87,142.75 142.58,142.46 142.58,141.87 142.35,141.64 142.35,141.5 142.47,141.38 v2(142.68,141.38)
  IN2 w0.076: v2(129.84,92.98) 129.84,92.98 130.03,93.17 130.22,93.17 130.41,93.35 130.41,94.33 130.73,94.65 132.05,94.65 134.25,96.85 135.09,96.85 135.25,97.01 135.25,97.35 135.29,97.39
  IN2 w0.127: v2(142.68,141.38) 142.58,141.28 142.58,140.92 143,140.51 143,139.64 142.68,139.32 142.68,138.71 144.06,137.32 144.53,137.32 146.79,135.06 146.79,131.08 147.16,130.71 147.16,124.49 148.85,122.81 148.85,108.81 148.72,108.69 140.78,100.75 136.35,100.75 135.29,99.69 135.29,97.39
  BOTTOM w0.102: UC1.G15 v2(129.84,92.98)
PEG_GTX_HRX_N0: length 6
  BOTTOM w0.091: CV2.2 144.53,136.47 144.86,136.13 145.46,136.13 146.02,136.69 147.69,136.69 148.74,135.65 148.85,135.65 148.91,135.71 UV1.AG31
PEG_GTX_HRX_N1: length 7.8
  BOTTOM w0.091: CV4.2 144.65,139.37 144.87,139.15 144.92,139.15 145.34,138.73 145.34,138.68 v4(146.05,137.98) 146.8,137.22 148.28,137.22 149.63,135.87 149.71,135.87 149.95,135.62 UV1.AF28
PEG_GTX_HRX_N2: length 6
  TOP w0.091: CV6.2 147.6,137.6 v4(148.92,136.29) 149.66,135.54 149.66,134.81 150.05,134.42 150.45,134.42 150.53,134.49 v2(150.83,134.49)
  BOTTOM w0.102: v2(150.83,134.49) UV1.AF26
PEG_GTX_HRX_N3: length 7.6
  TOP w0.091: CV8.2 149.22,139.17 149.28,139.12 150.38,139.12 151,138.5 151.05,138.5 151.46,138.09 152.55,138.09 153.23,137.4 v4(153.23,136.83) 153.23,136.07 153.12,135.95 v2(153.12,135.62)
  BOTTOM w0.102: UV1.AD26 153.11,135.62 v2(153.12,135.62)
PEG_GTX_HRX_P0: length 6
  BOTTOM w0.091: UV1.AH30 148.63,135.5 147.62,136.51 146.09,136.51 145.54,135.95 144.79,135.95 144.29,136.46 CV1.2
PEG_GTX_HRX_P1: length 7.8
  BOTTOM w0.091: UV1.AG29 149.68,135.34 149.78,135.44 149.78,135.54 149.64,135.69 149.56,135.69 148.2,137.04 146.72,137.04 146.15,137.62 146.1,137.62 145.69,138.03 145.69,138.08 v4(144.98,138.79) 144.52,139.25 CV3.2
PEG_GTX_HRX_P2: length 6
  TOP w0.091: CV5.2 147.83,137.63 148.81,136.65 148.86,136.65 149.28,136.23 149.28,136.18 149.84,135.62 149.84,134.89 150.13,134.6 150.38,134.6 150.5,134.72 150.5,134.85 v2(150.3,135.05)
  BOTTOM w0.102: UV1.AF27 150.3,135.06 v2(150.3,135.05)
PEG_GTX_HRX_P3: length 7.6
  TOP w0.091: v2(152.53,136.17) 152.72,135.98 152.89,135.98 153.05,136.14 153.05,136.48 153.01,136.52 153.01,137.13 153.05,137.17 153.05,137.33 152.47,137.91 151.34,137.91 v4(151.11,138.14) 150.3,138.94 149.2,138.94 149.15,139 CV7.2
  BOTTOM w0.102: v2(152.53,136.17) 152.51,136.19 UV1.AD27
PEG_HTX_C_GRX_N0: length 69
  IN2 w0.127: v2(132.68,102.97) 132.83,102.81 134.96,102.81 135.43,103.29 136.1,103.29 136.33,103.06 138.89,103.06 140.22,104.39 140.79,104.39 141.63,105.24 142.39,105.24 146.68,109.53 146.68,122.09 144.45,124.32 144.45,131.04 144.58,131.17 144.58,134.14 143.46,135.25 143.25,135.25 140.64,137.86 140.64,141.73 141.86,142.95 144.42,142.95 145.66,141.7 145.66,141.31 v2(146.11,140.87)
  BOTTOM w0.076: UC1.A17 128.86,96.55 128.95,96.45 129.06,96.45 129.13,96.52 129.13,98.04 131.02,99.93 131.02,102.32 131.06,102.36
  BOTTOM w0.091: 131.06,102.36 131.4,102.7 132.41,102.7 v2(132.68,102.97) ; v2(146.11,140.87) 146.11,140.52 146.22,140.4 CV306.2
PEG_HTX_C_GRX_N1: length 69.1
  IN2 w0.127: v2(145.75,143.36) 145.73,143.36 145.23,143.87 141.51,143.87 139.75,142.1 139.75,137.49 142.88,134.36 143.09,134.36 143.44,134.02 143.44,124.07 145.79,121.72 145.79,116.89 144.9,116 144.9,109.16 142.43,106.68 141.82,106.68 140.42,105.29 139.85,105.29 138.87,104.31 135.19,104.31 134.67,103.78 133.71,103.78 133.63,103.87 132.32,103.87 131.63,103.18 v2(131.63,101.38)
  BOTTOM w0.076: v2(131.63,101.38) 132.1,100.91 132.1,100.45 129.48,97.83 129.48,96.78 129.55,96.71 129.55,96.08 129.5,96.03 129.2,96.03 129.13,95.96 129.13,95.78 129.2,95.71 UC1.C16
  BOTTOM w0.091: v2(145.75,143.36) 145.75,143.08 145.78,143.05 145.89,142.94 CV305.2
PEG_HTX_C_GRX_N2: length 74.9
  IN2 w0.127: v2(148.24,143.15) 148.15,143.15 147.38,143.92 147.38,144.14 146.75,144.77 141.08,144.77 138.17,141.86 138.17,137.47 139.39,136.25 139.39,126.67 144.83,121.22 144.83,117.28 144.01,116.46 144.01,109.53 142.69,108.21 141.3,108.21 138.29,105.2 132.38,105.2 131.73,104.55 v2(131.11,104.55)
  BOTTOM w0.076: UC1.C17 128.86,95.19 128.8,95.14 128.65,95.14 128.56,95.23 128.56,95.61 128.5,95.67 128.42,95.96 128.42,96.14 128.45,96.26 128.45,96.46 128.42,96.53 128.42,97.6 128.53,97.71 128.53,98.04 130.57,100.08 130.57,103.27 130.23,103.61 130.23,103.75 130.22,103.75 130.22,103.9 130.26,103.93 130.26,103.95 130.27,103.95
  BOTTOM w0.091: CV309.2 148.38,142.69 148.24,142.83 v2(148.24,143.15) ; 130.27,103.95 130.51,104.19 130.75,104.19 v2(131.11,104.55)
PEG_HTX_C_GRX_N3: length 77.9
  IN2 w0.127: v2(149.8,145.08) 149.32,144.6 148.45,144.6 147.63,145.41 140.53,145.41 137.41,142.29 137.41,137.3 138.75,135.96 138.75,125.89 144.14,120.5 144.14,117.75 143.25,116.86 143.25,111.06 138.94,106.74 135.06,106.74 134.17,105.85 131.44,105.85 130.42,104.84 130.42,104.27 129.68,103.52 129,103.52 v2(128.78,103.3)
  BOTTOM w0.076: 127.67,99.3 127.67,99.28 127.66,99.27 127.66,98.98 127.48,98.79 127.48,97.04 127.51,97.01 127.54,97.01 127.6,96.94 127.6,96.78 UC1.A19
  BOTTOM w0.091: v2(128.78,103.3) 129.07,103.3 129.15,103.38 129.15,103.61 129.06,103.7 128.48,103.7 127.67,102.89 127.67,99.3 ; CV304.2 149.71,144.21 149.15,144.77 149.15,145 149.25,145.1 149.35,145.1 149.52,144.93 149.65,144.93 v2(149.8,145.08)
PEG_HTX_C_GRX_P0: length 69
  IN2 w0.127: v2(145.68,140.44) 145.68,140.94 145.41,141.2 145.41,141.59 144.31,142.69 141.96,142.69 140.9,141.63 140.9,137.97 143.35,135.51 143.57,135.51 144.84,134.25 144.84,131.06 144.71,130.94 144.71,124.42 146.94,122.2 146.94,109.42 142.49,104.98 141.74,104.98 140.9,104.14 140.33,104.14 138.99,102.81 136.22,102.81 135.99,103.04 135.54,103.04 135.06,102.56 132.98,102.56 v2(132.68,102.26)
  BOTTOM w0.076: 131.19,102.23 131.18,102.22 131.18,99.86 129.29,97.97 129.29,96.45 129.13,96.29 128.95,96.29 128.86,96.19 UC1.B17
  BOTTOM w0.091: v2(145.68,140.44) 145.93,140.44 146.04,140.33 CV312.2 ; 131.19,102.23 131.48,102.52 132.42,102.52 v2(132.68,102.26)
PEG_HTX_C_GRX_P1: length 69.1
  IN2 w0.127: v2(145.32,142.93) 145.12,143.12 145.12,143.24 145.25,143.37 145.25,143.48 145.12,143.61 141.62,143.61 140.01,142 140.01,137.6 142.98,134.62 143.2,134.62 143.69,134.13 143.69,124.18 146.05,121.83 146.05,116.78 145.16,115.89 145.16,109.05 142.53,106.43 141.92,106.43 140.53,105.03 139.96,105.03 138.98,104.05 135.3,104.05 134.77,103.53 133.6,103.53 133.52,103.61 132.42,103.61 131.89,103.08 131.89,101.81 131.97,101.73 132.32,101.73 132.42,101.63 v2(132.42,101.38)
  BOTTOM w0.076: UC1.D16 129.72,95.59 129.72,96.78 129.65,96.85 129.65,97.76 132.27,100.38 132.27,101.23 v2(132.42,101.38)
  BOTTOM w0.091: CV308.2 145.78,142.8 145.65,142.93 v2(145.32,142.93)
PEG_HTX_C_GRX_P2: length 74.9
  IN2 w0.127: v2(147.81,142.72) 147.81,143.13 147.12,143.82 147.12,144.04 146.65,144.52 141.18,144.52 138.42,141.75 138.42,137.58 139.64,136.36 139.64,126.78 145.09,121.33 145.09,117.09 144.27,116.27 144.27,109.42 142.8,107.95 141.41,107.95 138.4,104.94 132.49,104.94 131.84,104.29 131.45,104.29 131.12,103.97 v2(131.11,103.97)
  BOTTOM w0.076: UC1.D17 128.86,94.9 129.15,95.19 129.15,95.5 128.98,95.68 128.73,95.68 128.65,95.76 128.58,95.98 128.58,96.12 128.62,96.24 128.62,96.5 128.58,96.57 128.58,97.53 128.69,97.64 128.69,97.97 130.74,100.01 130.74,103.34 130.4,103.68 130.4,103.83
  BOTTOM w0.091: CV307.2 148.2,142.62 148.09,142.72 v2(147.81,142.72) ; 130.4,103.83 130.58,104.01 131.06,104.01 v2(131.11,103.97)
PEG_HTX_C_GRX_P3: length 77.9
  IN2 w0.127: v2(149.39,145.49) 149.37,145.48 149.37,145.01 149.21,144.85 148.56,144.85 147.74,145.67 140.42,145.67 137.15,142.4 137.15,137.19 138.5,135.85 138.5,125.78 143.88,120.4 143.88,117.86 143,116.97 143,111.16 138.83,107 134.95,107 134.06,106.11 131.33,106.11 130.17,104.95 130.17,104.37 129.57,103.78 129.18,103.78 v2(128.78,104.18)
  BOTTOM w0.076: UC1.B19 127.24,96.57 127.24,96.97 127.31,97.04 127.31,98.86 127.5,99.04 127.5,99.27 127.49,99.28 127.49,99.3
  BOTTOM w0.091: v2(149.39,145.49) 149.12,145.22 148.97,145.08 148.97,144.7 149.59,144.08 CV313.2 ; 127.49,99.3 127.49,102.97 128.4,103.88 128.48,103.88 v2(128.78,104.18)
PEG_HTX_GRX_N0: length 4.8
  BOTTOM w0.091: UV1.AE31 150.04,136.8 149.98,136.74 149.83,136.74 149.73,136.84 149.73,137 149.55,137.17 149.55,137.4 148.95,138 148.6,138 148.32,138.28 148.32,138.3 147.99,138.63 147.96,138.63 147.32,139.28 CV306.1
PEG_HTX_GRX_N1: length 7.7
  BOTTOM w0.091: UV1.AD28 151.11,136.76 150.85,137.02 150.76,137.02 150.56,137.22 150.22,137.56 150.18,137.56 149.77,137.97 149.71,137.97 149.48,138.19 149.48,138.36 148.9,138.94 v4(148.9,139.42) 148.9,139.85 148.1,140.66 148.1,140.7 147.68,141.12 147.63,141.12 147.51,141.25 147.51,141.41 147.07,141.85 CV305.1
PEG_HTX_GRX_N2: length 5.2
  BOTTOM w0.091: UV1.AC31 151.17,138.04 151.06,137.93 150.9,137.93 150.81,138.02 150.81,138.35 149.91,139.25 149.91,140.23 149.95,140.27 149.95,140.86 149.91,140.9 149.91,141.03 149.48,141.46 CV309.1
PEG_HTX_GRX_N3: length 7
  BOTTOM w0.091: UV1.AB28 152.28,137.89 152.16,138 152.01,138.15 151.89,138.15 150.8,139.25 150.8,139.97 151.18,140.35 v4(151.18,140.88) 151.18,141.84 151.22,141.89 151.22,142.48 151.18,142.53 151.18,142.76 150.88,143.06 CV304.1
PEG_HTX_GRX_P0: length 4.8
  BOTTOM w0.091: UV1.AF30 149.83,136.26 149.83,136.44 149.51,136.75 149.51,136.91 149.33,137.08 149.33,137.31 148.86,137.78 148.51,137.78 v4(147.97,138.32) 147.17,139.12 CV312.1
PEG_HTX_GRX_P1: length 7.7
  BOTTOM w0.091: UV1.AE29 150.76,136.47 150.87,136.58 150.87,136.74 150.78,136.83 150.7,136.83 150.38,137.14 150.14,137.38 150.1,137.38 149.7,137.79 149.63,137.79 149.3,138.11 149.3,138.28 148.69,138.9 148.69,139.81 v4(147.74,140.76) 147.33,141.17 147.33,141.34 147,141.66 CV308.1
PEG_HTX_GRX_P2: length 5.2
  BOTTOM w0.091: UV1.AD30 150.89,137.69 150.63,137.95 150.63,138.28 149.73,139.18 v4(149.73,140.56) 149.73,140.96 149.27,141.41 CV307.1
PEG_HTX_GRX_P3: length 7
  BOTTOM w0.091: UV1.AC29 151.92,137.6 152.03,137.72 152.03,137.87 151.94,137.97 151.82,137.97 150.62,139.17 150.62,140.05 150.96,140.39 150.96,141.18 151,141.21 v4(151,142.19) 151,142.68 150.75,142.93 CV313.1
PHASE_CHG: length 4.7
  IN1 w1.016: 119.56,158.11 114.86,158.11
  vias: v1(120.82,160.52) v2(113.28,157.92) v2(113.91,157.92) v2(120.58,158.62) v2(120.71,163.58) v2(120.71,163) v2(121.21,158.62) v2(121.34,164.15) v2(121.34,163.59) v2(121.34,163) v2(122.48,158.62) v2(123.12,164.08) v2(123.12,163.51) v2(123.12,162.94) v2(123.12,158.62)
PIRQA#: length 9.6
  BOTTOM w0.076: 137.37,68.71 136.82,69.25 136.82,69.42 132.34,73.9 UC1.BB11
  BOTTOM w0.102: 137.37,68.71 137.76,68.31 v1(137.93,68.31) 138.63,68.31 RC245.2
PLL_ANALOG_IN: length 2.2
  BOTTOM w0.102: UV1.AA1 168.71,122.89 T221.1
PLL_ANALOG_OUT: length 6.8
  BOTTOM w0.102: UV1.AA3 166.89,124.71 167.34,124.71 169.6,122.45 RV83.1 169.6,121.34 170.52,120.42 v1(171,120.42)
PLT_RST#_LAN: length 12.2
  TOP w0.102: LOM30.19 52.44,168.4 52.83,168.02 52.83,167.77 53.49,167.1 57.72,167.1 v1(58.41,166.41) 58.41,164.49 56.89,162.97 R3016.2
PLT_RST_NGFF#: length 3.7
  TOP w0.102: v1(173.48,50.75) 173.27,50.55 v2(172.21,50.55) 171.95,50.8 R5807.2
  BOTTOM w0.102: WLAN1.44 171.68,50.27 171.95,50.55 v2(172.21,50.55)
PLT_RST_VGA#: length 105
  TOP w0.102: v2(185.4,84.07) 185.48,84.07 185.95,83.61 UE1.47 ; v2(166.24,120.33) 160.08,120.33 159.7,120.71 157.09,120.71 155.89,121.92 153.16,121.92 152.33,122.75 151.16,122.75 150.84,123.06 150.84,123.72 146.3,128.27 v2(146.04,128.27)
  IN2 w0.127: v2(166.24,120.33) 166.24,120.15 167.75,118.64 172.07,118.64 173.75,120.33 187.89,120.33 189.92,118.3 190.75,118.3 191.83,117.22 191.83,113.86 190.49,112.52 189.35,112.52 187.89,111.06 187.89,99.18 186.94,98.23 186.94,95.1 186.32,94.49 184.23,94.49 182.81,93.07 182.81,91.19 184.59,89.41 184.59,86.04 185.4,85.23 v2(185.4,84.07)
  BOTTOM w0.102: UV1.AL27 148.91,132.61 RV4.1 146.04,129.74 v2(146.04,128.27) 145.86,128.09 v1(145.15,128.09) 143.31,128.09 142.02,129.38 UV2.4
PM_LAN_ENABLE_R: length 5.9
  TOP w0.102: v1(58.25,169.25) 58.25,170.6 58.53,170.88 Q3004.2 60.16,170.88 60.76,171.48 R3022.2 61.47,172.41 C3015.2
PM_ZVM#: length 98.4
  TOP w0.102: v2(37.59,58.48) v1(37.59,59.82) 40.6,62.83 40.6,65.12 41.27,65.79 47.05,65.79 v2(51.49,61.34)
  IN1 w0.127: v2(106.05,78.15) 105.62,78.58 105.62,78.95 105.63,78.96 105.63,80.76 105.28,81.1 104.2,81.1 103.22,82.09 103.22,83.1 102.97,83.35 97.68,83.35 97.53,83.5 85.63,83.5 77.4,75.28 77.4,69.23 77.84,68.78 77.84,63.31 v2(76.38,61.85)
  IN2 w0.127: v2(76.38,61.85) 75.49,60.96 63.98,60.96 63.15,61.79 54.6,61.79 54.16,61.34 v2(51.49,61.34)
  BOTTOM w0.102: v2(106.05,78.15) 106.22,78.15 UC1.AR56 ; PR1201.2 v2(37.59,58.48)
PME#: length 1.2
  TOP w0.076: T115.1 132.05,76.48 v2(131.69,76.84)
  BOTTOM w0.089: UC1.AU11 132.02,77.17 v2(131.69,76.84)
POK: length 421.6
  TOP w0.102: v2(35.93,40.13) 36.28,39.79 PR113.2 PR107.2 ; RC220.1 CC266.1 161.91,56.58 167.06,56.58 168.52,58.04 169.92,58.04 170.55,58.67 170.55,58.93 v2(171.51,59.88) ; v2(145.66,113.93) 146.98,113.93 149.46,111.46 149.46,105.55 150.3,104.71 150.3,100.9 150.96,100.24 150.96,97.85 155.28,93.54 159,93.54 162.87,89.66 162.87,81.85 163.97,80.76 v2(165.33,80.76) ; v2(176,26.61) 176.02,26.59 176.02,22.03 173.03,19.05 164.25,19.05 155.92,10.72 96,10.72 93.45,13.27 85.85,13.27 84.32,14.8 83.37,14.8 81.04,12.47 65.44,12.47 64.95,12.96 64.95,25.73 63.44,27.24 60.13,27.24 v1(54.86,32.51) 54.86,36.39 54.35,36.89 51.83,36.89 50,35.07 48.96,35.07 46.9,37.13 46.9,40.21 v2(47.35,40.67)
  TOP w0.254: PR13.1 v2(133.07,177.5)
  IN1 w0.127: v2(181.07,68.92) 180.03,67.88 177.98,67.88 177.41,67.31 176.35,67.31 171,61.96 171,60.19 171.31,59.88 v2(171.51,59.88) ; v2(133.07,177.5) 133.77,177.5 134.87,176.4 134.87,166.56 140.2,161.23 140.2,158.75 138.61,157.16 138.61,143.32 139.95,141.99 139.95,135.38 137.79,133.22 137.79,131.51 v2(137.22,130.94) 144.37,123.79 144.37,118 145.52,116.85 145.52,114.07 145.64,113.95 145.64,113.95 v2(145.66,113.93) ; v2(35.93,40.13) 35.93,40.89 36.25,41.21 36.25,44.22 37.76,45.72 45.78,45.72 47.94,43.56 47.94,41.25 v2(47.35,40.67)
  IN2 w0.127: v2(181.07,68.92) 181.07,61.13 181.48,60.73 181.48,43.56 181.92,43.12 181.92,41.32 180.59,39.99 180.59,38.12 176.37,33.91 176.37,26.97 v2(176,26.61) ; v2(171.51,59.88) 171.34,59.88 171.05,60.17 171.05,61.08 170.56,61.57 170.56,67.1 167.15,70.51 167.15,78.42 166.39,79.18 166.39,79.7 v2(165.33,80.76)
  BOTTOM w0.102: v2(47.35,40.67) 47.33,40.69 46.41,40.69 46.16,40.44 PU102.9 ; PU100.9 34.48,40.25 34.72,40.49 35.58,40.49 v2(35.93,40.13) ; UZ6.2 181.67,71.63 181.81,71.48 181.81,70.83 181.07,70.08 v2(181.07,68.92)
  BOTTOM w0.254: PR501.1 v2(176,26.61) ; v2(137.22,130.94) 137.09,130.94 136.14,131.89 133.41,131.89 132.58,131.06 132.58,129.29 132.98,128.89 PR301.1
POL1_SDA: length 10.1
  TOP w0.102: v2(29.76,60.16) 29.76,60.34 29.5,60.6 U5502.22
  IN2 w0.127: v2(27.83,55.96) 27.83,58.23 v2(29.76,60.16)
  BOTTOM w0.102: v2(27.83,55.96) 27.64,55.78 27.07,55.78 26.75,55.46 U5504.5 ; R5508.2 29.99,60.39 v2(29.76,60.16) 29.76,59.77 R5509.1
POL2_SCL: length 9.8
  TOP w0.102: v2(30.47,60.15) 30.47,60.37 30,60.84 U5502.23
  IN2 w0.127: v2(28.56,55.97) 28.56,58.24 30.32,60 30.32,60 v2(30.47,60.15)
  BOTTOM w0.102: U5504.6 28.02,55.28 28.56,55.82 v2(28.56,55.97) ; R5516.2 30.88,60.56 v2(30.47,60.15) 30.47,59.95 R5515.1
POWER_SW#_MB: length 146.8
  TOP w0.102: SW1.2 198.52,63.29 v2(197.86,62.63) 197.14,61.9 195.61,61.9 194.81,61.1 v2(192.91,61.1) ; v2(197.49,117.35) 196.93,116.79 196.93,112.88 197.31,112.5 197.31,108.46 197.67,108.1 197.67,100.61 197.31,100.25 v3(197.31,98.17) 197.94,97.55 197.94,78.84 v2(196.56,77.47) ; v2(195.61,171.4) 195.56,171.45 192.72,171.45 191.12,173.05 R6102.1
  IN1 w0.127: v2(192.91,61.1) 193.81,61.1 195.45,62.74 195.45,64.92 194.32,66.04 193.67,66.04 192.11,67.6 192.11,69.13 192.14,69.16 192.14,70.8 v2(191.83,71.12)
  IN2 w0.127: v2(197.49,117.35) 198.25,118.11 198.25,128.88 203.22,133.84 203.22,151.42 197.8,156.84 197.8,161.46 200.36,164.02 200.36,166.65 v2(195.61,171.4) ; v2(197.86,62.63) 197.48,63.01 197.48,65.41 195.62,67.27 195.62,70.08 196.56,71.03 v2(196.56,77.47)
  BOTTOM w0.102: RE428.2 192.2,70.5 191.83,70.87 v2(191.83,71.12)
POWER_SW_IN#: length 6.4
  TOP w0.102: UE1.127 191.15,68.29 191.06,68.37 v2(191.06,68.39)
  BOTTOM w0.102: 191.08,68.39 191.64,67.84 CE12.1 190.76,66.83 RE31.2 ; 191.08,68.39 192.28,69.58 RE428.1 v1(192.59,68.64) ; 191.08,68.39 v2(191.06,68.39)
PROG: length 3.2
  BOTTOM w0.203: PU703.9 108.58,160.68 108.57,160.69 108.57,160.98 108.43,161.13 107.41,161.13 107.11,161.42 v1(106.89,161.42) PR753.2
PROH: length 48.1
  TOP w0.102: PQ720.2 70.75,168.98 v1(71.09,168.64)
  TOP w0.254: v2(70.68,169.95) PR781.2 70.05,169.95 PQ720.2
  IN2 w0.127: v2(106.47,158.5) 106.47,158.24 104.1,155.87 102.83,155.87 101.88,156.82 100.79,156.82 95.97,161.65 92.18,161.65 88.14,165.68 80.52,165.68 79.64,166.57 78.75,166.57 75.61,169.71 70.92,169.71 v2(70.68,169.95)
  BOTTOM w0.102: PR777.2 v2(106.47,158.5) 106.8,158.82 PU703.5
PS_0: length 4
  TOP w0.102: RV8.2 155.26,130.06 RV9.1 CV29.1 156.52,132.05 v2(156.44,132.13) 156.44,132.26 v1(156.15,132.55)
  BOTTOM w0.102: UV1.AC19 157.21,132.13 v2(156.44,132.13)
PS_1: length 6
  TOP w0.102: v2(155.86,131.77) 155.57,131.77 CV28.1 ; v1(153.96,131.55) 154.06,131.44 CV28.1 ; CV28.1 155.25,130.71 154.34,129.79 RV12.1 154.23,129.77 RV11.2
  BOTTOM w0.102: UV1.AD19 156.11,131.52 v2(155.86,131.77)
PS_2: length 5
  TOP w0.102: RV28.2 154.12,127.14 RV13.1 CV11.1 156.77,128.52 v1(156.88,128.63) 157.11,128.85 157.11,129.49 v2(157.05,129.54)
  BOTTOM w0.102: v2(157.05,129.54) 156.97,129.62 UV1.AE17
PS_3: length 6.6
  TOP w0.102: v2(154.69,132) 154.67,132.03 153.46,132.03 153.26,132.23 v1(152.61,132.23) 151.58,132.23 151.31,131.96 RV15.2 151.34,131.57 RV16.1 CV15.1
  BOTTOM w0.102: UV1.AE20 154.89,131.81 v2(154.69,132)
PS_ID: length 220.5
  TOP w0.102: UE1.36 190.35,83.7 190.66,84.01 191.89,84.01 192.33,84.45 192.33,86.3 192.72,86.68 194.75,86.68 195.38,87.31 v2(195.45,87.31) ; v2(99.22,170.12) 99.22,163.85 100.7,162.37 v1(100.7,161.52) 100.7,155.54 101.23,155.02 101.23,153.25 97.11,149.13 PD5.1
  TOP w0.254: PR3.1 PR4.2 94.34,149.78 94.16,149.61 PD5.1
  IN1 w0.127: v2(143.63,179.01) 143.63,175.75 151.06,168.32 151.06,162.79 149.28,161.02 149.28,146.71 148.58,146.01 148.58,144.99 149.28,144.29 149.28,142.73 148.97,142.42 148.97,138.09 149.29,137.77 149.29,136.5 148.83,136.04 148.83,134.39 149.01,134.2 149.01,132.78 148.79,132.55 148.79,127.1 149.47,126.41 149.47,124.86 148.93,124.31 148.93,120.89 150.3,119.51 150.3,106.18 155.27,101.22 157.28,101.22 160.72,97.78 160.72,96.83 166.68,90.87 171.97,90.87 173.2,89.64 174.03,89.64 175.08,88.58 181.35,88.58 182.17,89.41 184.76,89.41 186.13,90.78 191.28,90.78 192.1,89.95 192.11,89.95 194.81,87.25 195.38,87.25 v2(195.45,87.31)
  IN2 w0.127: v2(143.63,179.01) 142.42,180.21 133.28,180.21 131.74,178.67 112.44,178.67 110.36,176.59 105.7,176.59 v2(99.22,170.12)
PSID: length 3.1
  TOP w0.102: v1(94.62,158.85) 94.12,159.34 PL2.2
  TOP w0.254: PJPDC1.3 94.15,159.85 PL2.2
PSID-1: length 4.8
  TOP w0.102: PQ5.2 90.81,158.26 PR6.1 PR9.2 88.98,159.83 v1(88.35,159.83)
PSID-2: length 7.5
  TOP w0.102: v1(88.82,155.07) 89.45,155.7 PQ5.1
  TOP w0.254: PQ6.2 92.94,152.65 92.69,152.91 PR11.1 90.95,152.92 PR8.2 90.16,155.22 PQ5.1
PSID-3: length 3.2
  TOP w0.102: v1(96.47,149.96) 95.97,149.96 95.69,150.24 PR4.1
  TOP w0.254: PQ6.3 94.88,150.62 PR4.1
PTP_DIS#: length 231.7
  TOP w0.102: v2(58.29,68.39) 58.54,68.64 58.54,70.29 58.22,70.61 56.83,70.61 56.51,70.93 56.51,71.95 57.46,72.9 57.46,75.31 57.45,75.31 D3801.1
  IN1 w0.127: v2(179.25,41.27) 177.95,41.27 175.6,38.93 170.45,38.93 166.95,35.43 164.01,35.43 163.7,35.12 163.7,28.26 159.89,24.45 159.89,21.67 155.43,17.22 154.16,17.22 153.19,16.26 84.89,16.26 81.84,19.3 81.84,24.13 80.51,25.46 75.3,25.46 74.03,26.73 74.03,32.13 72.64,33.53 69.32,33.53 67.97,34.88 66.05,34.88 65.53,34.35 60.15,34.35 59.2,35.31 57.21,35.31 53.52,38.99 53.52,66.25 56.08,68.81 57.87,68.81 v2(58.29,68.39)
  IN2 w0.127: v2(179.19,68.39) 179.19,66.06 178.07,64.94 178.07,60.17 178.53,59.72 178.53,48.31 178.78,48.05 178.78,41.74 v2(179.25,41.27)
  BOTTOM w0.102: v2(179.19,68.39) 179.19,67.97 v1(179.72,67.43) 180.3,66.85 RE434.1
PTP_DIS#_R: length 5.6
  TOP w0.102: UE1.90 178.87,71.17 v2(178.87,71.16)
  BOTTOM w0.102: RE434.2 180.9,68.45 v1(180.11,69.25) 180.11,70.01 178.96,71.16 v2(178.87,71.16)
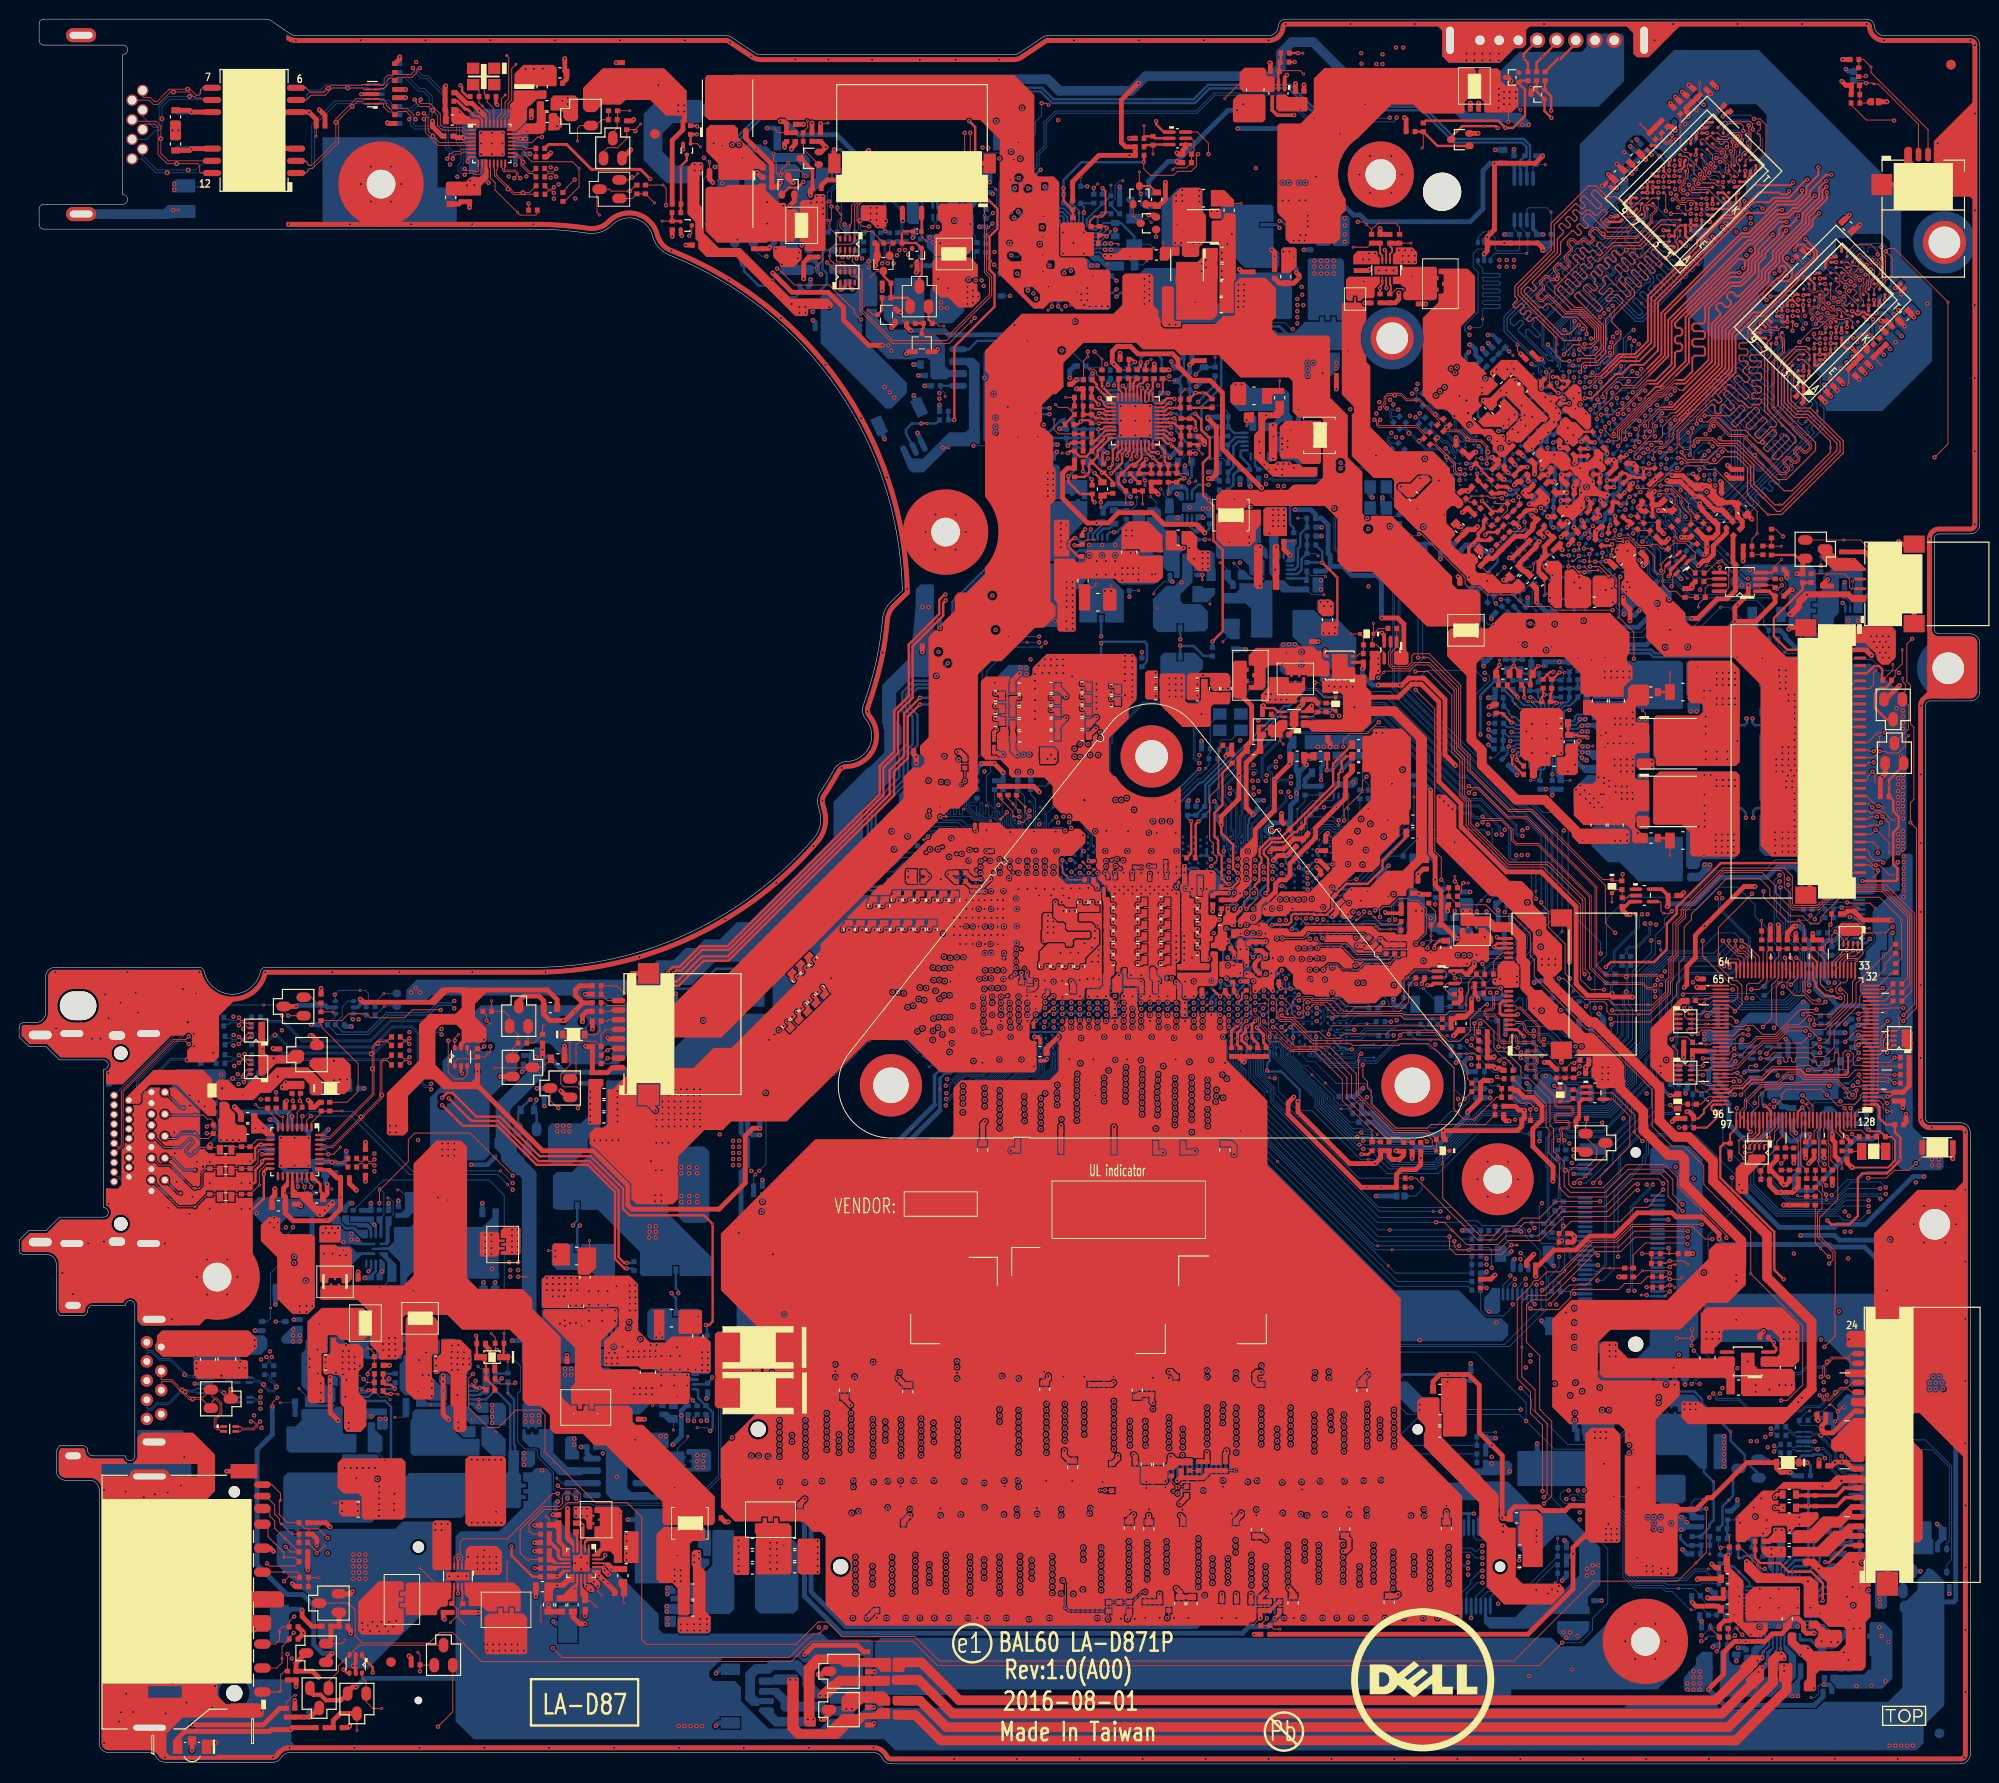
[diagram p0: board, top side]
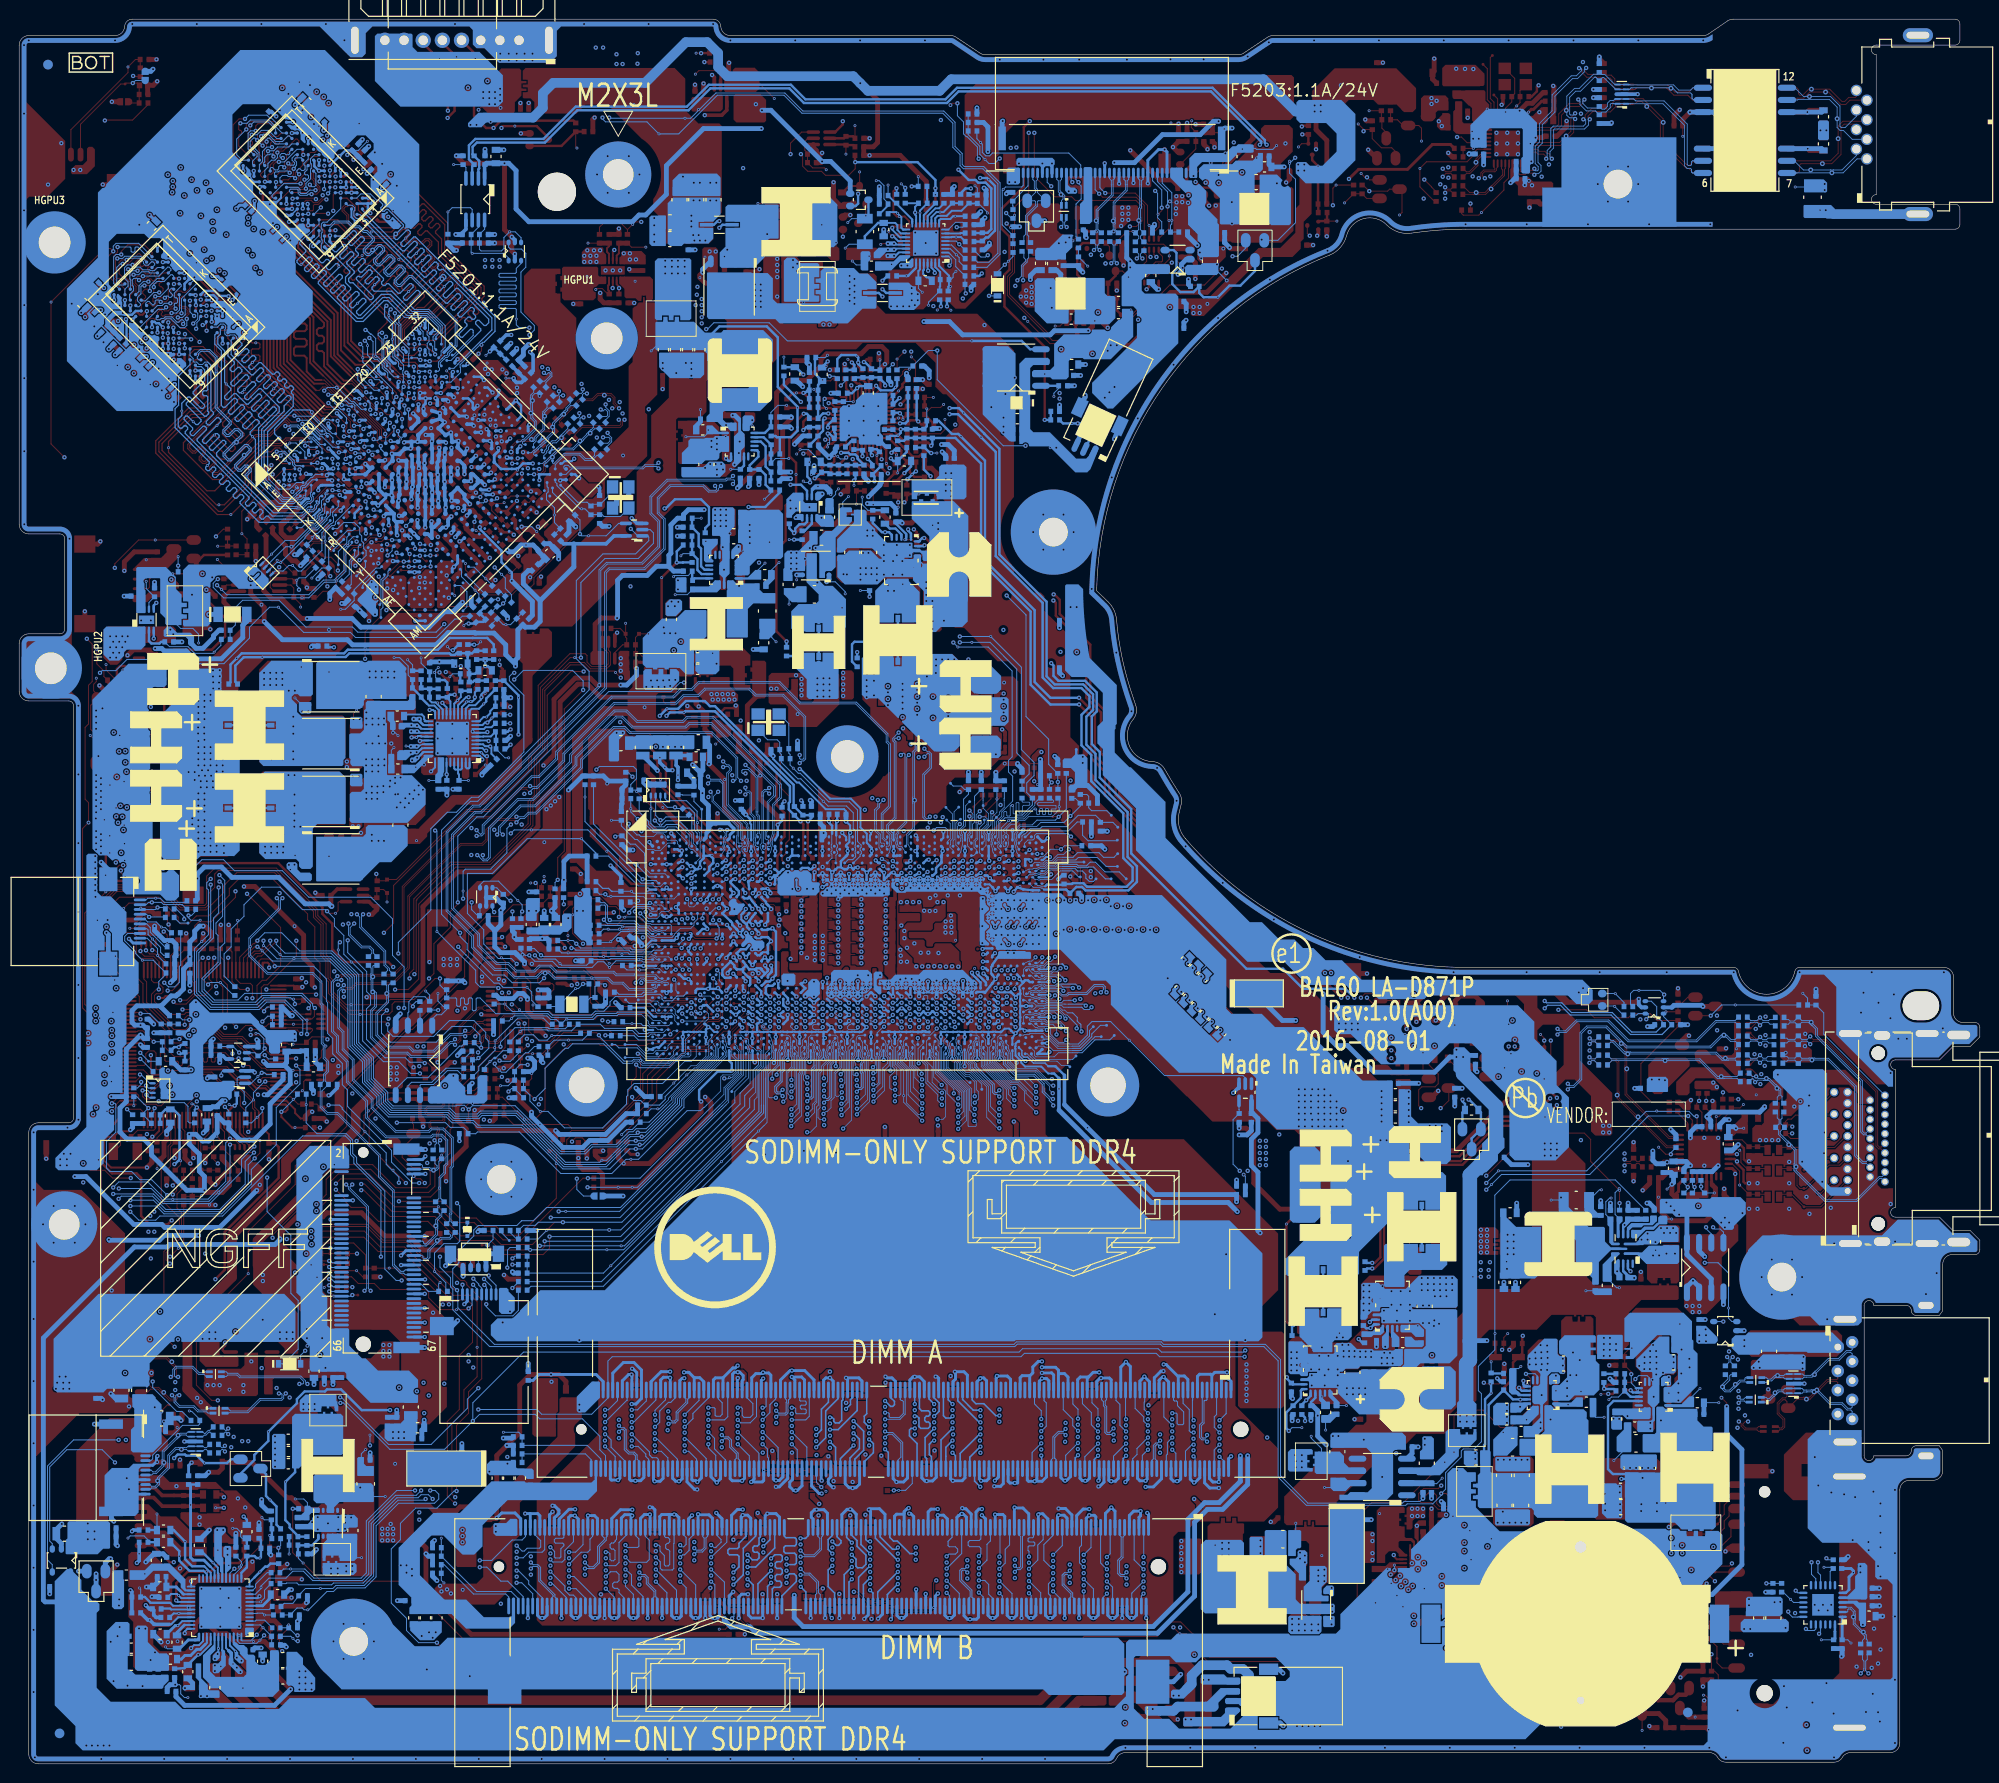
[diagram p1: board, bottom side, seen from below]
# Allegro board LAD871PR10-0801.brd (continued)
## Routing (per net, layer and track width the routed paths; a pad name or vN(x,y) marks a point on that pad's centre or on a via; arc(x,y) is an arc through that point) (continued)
PWM1_GT: length 132.1
  TOP w0.203: 114.76,136.84 115.05,137.13 PU602.12
  TOP w0.254: v2(114.58,136.07) 114.58,136.68 114.74,136.84 114.76,136.84
  IN1 w0.203: v2(114.58,136.07) 114.58,135.42 114.8,135.19 114.8,133.03 114.99,132.84 114.99,125.39 113.85,124.24 113.85,123.66 113.67,123.49 110.7,123.49 110.23,123.95 109.33,123.95 108.82,123.44 108.82,120.63 105.96,117.77 105.96,116.88 95.14,106.06 95.14,103.49 89.94,98.29 89.94,95.76 72.58,78.41 72.58,62.14 73.84,60.88 73.84,36.53 72.61,35.3 72.61,35.24 v2(72.09,34.72)
  BOTTOM w0.102: v2(72.09,34.72) 71.75,35.06 v1(70.73,35.06)
  BOTTOM w0.254: PU605.13 70.68,39.08 70.83,38.93 70.83,38.17 PR680.1 72.35,36.65 72.35,34.98 v2(72.09,34.72)
PWM2_GT: length 149.5
  TOP w0.203: PU602.13 115.45,137.01 115.04,136.6 115.04,136.53
  TOP w0.254: 115.04,136.53 115.07,136.51 v1(115.07,136.47) 115.07,135.69 113.98,134.59 v2(113.93,134.59)
  IN1 w0.203: v2(113.93,134.59) 113.93,132.64 114.23,132.33 114.23,130.91 113.63,130.3 111.4,130.3 110.33,129.23 110.33,128.53 110.67,128.18 110.67,125.34 110.18,124.84 109.28,124.84 108.16,123.72 108.16,120.98 105.3,118.12 105.3,117.15 94.48,106.34 94.48,103.77 89.23,98.51 89.23,95.98 71.92,78.68 71.92,61.87 73.18,60.6 73.18,38.72 71.13,36.67 v2(71.13,35.77)
  IN2 w0.254: v2(63.56,45.46) 60.48,45.46 58.98,43.97 58.98,38.96 62.86,35.09 70.45,35.09 v2(71.13,35.77)
  BOTTOM w0.254: PU604.13 63.2,45.83 v2(63.56,45.46) 63.6,45.43 64.03,45.43 PR681.1
PWM_IA: length 23.3
  TOP w0.203: PU602.22 119.45,138.68 119.59,138.54
  TOP w0.254: v2(120.45,138.11) 120.02,138.11 119.59,138.54 ; v2(110.14,127.85) 109.99,127.85 109.54,127.4 v1(109.54,127.23) 109.54,126.89 110.5,125.93 PR662.1
  IN2 w0.127: v2(110.14,127.85) 110.28,128 110.28,128.43 111.04,129.19 112.02,129.19 112.25,128.95 112.93,128.95 114.73,130.75 117.66,130.75 118.23,131.32 118.23,133.84 120.51,136.11 120.51,138.06 v2(120.45,138.11)
  BOTTOM w0.254: v2(110.14,127.85) 110.34,127.85 110.69,127.5 PU603.13
PWM_VSA: length 17.6
  TOP w0.203: PU602.30 119.17,141.88 119.34,142.05
  TOP w0.254: 119.34,142.05 119.72,142.43 120.45,142.43 v2(120.52,142.37)
  IN1 w0.254: v2(124.07,133.41) 123.69,133.41 123.37,133.73 123.37,135.13 121.47,137.03 121.47,138.81 120.43,139.85 120.32,139.85 119.63,140.54 119.63,141.1 119.88,141.35 120.45,141.35 120.68,141.58 120.68,142.2 v2(120.52,142.37)
  BOTTOM w0.102: v1(120.33,141.35) 120.67,141.69 120.67,142.21 v2(120.52,142.37)
  BOTTOM w0.254: PU606.3 122.35,132.78 122.99,133.41 v2(124.07,133.41)
PWRGD_VGA: length 12
  TOP w0.254: PR1119.2 154.71,109.59 v1(155.23,109.07) v2(155.7,108.6)
  IN1 w0.254: v2(155.7,108.6) 156.76,109.66 161.16,109.66 161.41,109.92 v2(161.73,109.92)
  BOTTOM w0.203: PR1122.1 155.68,108.6 v2(155.7,108.6) 155.96,108.6 156.22,108.34 PU1100.9 ; PU1100.20 161.16,109.72 161.36,109.92 v2(161.73,109.92)
PX_EN: length 1.2
  TOP w0.102: v2(158.76,130.99) 159.06,130.68 T218.1
  BOTTOM w0.102: v2(158.76,130.99) 158.87,131.1 UV1.AB16
QSA#_0: length 36.1
  BOTTOM w0.102: 168.95,160.04 168.96,160.05 168.96,160.06 169,160.1 169,160.11 169.11,160.22 169.74,160.22 170.24,160.72 171.62,160.72 172.14,160.2 UV17.B7 ; 161.11,152.51 161.1,152.5 161.09,152.5 159.06,150.47 159.06,147.95 159.87,147.14 159.87,146.97 159.97,146.87 160.15,146.87 160.2,146.81 160.2,146.81 160.38,146.63 160.44,146.58 160.44,146.58 160.81,146.2 160.81,145.68 160.69,145.56 160.69,145.38 160.83,145.24 UV1.H27
  BOTTOM w0.112: 161.11,152.51 163.64,155.04 163.8,155.04 164.75,154.09 165.07,154.09 165.43,154.44 165.43,154.77 164.48,155.72 164.48,155.88 164.72,156.11 164.87,156.11 165.82,155.16 166.15,155.16 166.5,155.52 166.5,155.84 165.55,156.79 165.55,156.95 165.79,157.19 165.95,157.19 166.9,156.24 167.22,156.24 167.58,156.59 167.58,156.92 166.63,157.87 166.63,158.03 166.87,158.26 167.02,158.26 167.24,158.05 167.24,158 167.72,157.52 167.76,157.52 167.97,157.31 168.3,157.31 168.65,157.67 168.65,157.99 167.7,158.94 167.7,159.1 168.32,159.72 168.63,159.72 168.95,160.04
QSA#_1: length 35.3
  TOP w0.102: UV18.B7 169.77,162.28 169.77,162.42 169.96,162.61 170.11,162.61 170.3,162.41 170.49,162.41 170.67,162.24 170.67,162.04 170.17,161.54 170.17,160.81 169.2,159.83 169.19,159.83 169.17,159.82
  TOP w0.112: 169.17,159.82 168.68,159.32 165.52,159.32 v4(165.27,159.57) 164.62,160.22 164.18,160.22 163.75,159.8 163.75,159.47 164.11,159.12 164.11,158.96 163.87,158.72 163.71,158.72 163.36,159.08 163.03,159.08 162.69,158.73 162.53,158.73 162.19,159.07 161.8,159.07 161.51,158.77 161.51,158.39 161.85,158.05 161.85,157.89 161.2,157.24 161.2,156.92 161.62,156.5 161.62,156.34 161.38,156.1 161.22,156.1 160.8,156.52 160.48,156.52 160.07,156.11 160.07,155.75 160.46,155.35 160.46,155.24 160.11,154.89 159.88,154.89 159.52,155.24 159.2,155.24 158.65,154.69 158.65,154.37 158.92,154.09 158.92,153.85 158.27,153.2 158.27,152.87 158.62,152.52 158.95,152.52 159.42,152.99 159.58,152.99 161.33,151.25 162.72,151.25 164.35,149.62 164.35,148.67 164.24,148.56 164.08,148.56 v2(163.98,148.66)
  BOTTOM w0.102: UV1.A27 163.98,148.15 v2(163.98,148.66)
QSA#_2: length 33.3
  TOP w0.102: UV18.G3 174.62,163.08 174.09,163.08 173.84,162.83 173.43,162.83 172.89,163.37 v2(172.89,163.61)
  IN1 w0.102: 168.77,160.21 168.8,160.21 168.8,160.22 169.67,160.22 170.36,160.91 170.36,161.09 171.77,162.5 172.7,162.5 173.09,162.89 173.09,163.19 172.89,163.39 v2(172.89,163.61) ; 166.61,150.44 166.61,150.31 167.38,149.54 167.38,148.65 167.13,148.4 166.73,148.4 v2(166.28,148.85)
  IN1 w0.109: 166.61,150.44 166.61,151.09 166.84,151.33 166.84,152.67 165.65,153.86 165.65,156.71 165.76,156.82 166.17,156.82 166.39,157.04 166.39,157.54 166.17,157.76 165.48,157.76 165.38,157.87 165.38,158.26 165.48,158.37 166.17,158.37 166.39,158.59 166.39,159.16 166.17,159.38 165.48,159.38 165.38,159.49 165.38,160.05 165.54,160.21 168.77,160.21
  BOTTOM w0.102: v2(166.28,148.85) 166.51,148.62 166.51,146.65 165.86,146 165.86,145.5 165.6,145.24
QSA#_3: length 34
  IN2 w0.102: 167.51,147.02 167.51,146.86 167.51,146.85 167.51,145.15 168.78,143.88 168.78,142.88 168.63,142.72 168.42,142.72 168.29,142.86 168.29,143 v2(168.34,143.06) ; 169.53,159.46 169.54,159.48 169.55,159.48 170.38,160.31 170.38,162.36 171.75,163.74 171.75,164.08 171.98,164.3 172.32,164.3 172.34,164.27 172.71,164.27 v2(172.74,164.24)
  IN2 w0.109: 169.53,159.46 165.02,154.96 165.02,154.07 165.44,153.64 165.44,153.49 164.28,152.33 164.28,152.01 164.63,151.66 164.95,151.66 166.11,152.82 166.27,152.82 166.73,152.36 166.73,151.32 166.62,151.21 165.95,151.21 165.73,150.98 165.73,150.49 165.95,150.26 166.62,150.26 166.73,150.15 166.73,149.77 167.32,149.18 167.32,147.77 167.51,147.58 167.51,147.02
  BOTTOM w0.102: UV17.G3 172.7,164.28 v2(172.74,164.24) ; UV1.C19 168.26,142.98 v2(168.34,143.06)
QSA#_4: length 34
  TOP w0.102: UV20.G3 188.22,149.07 188.08,149.07 v2(187.92,149.24)
  IN2 w0.102: 181.83,147.11 181.85,147.13 181.86,147.13 182.49,147.76 183.89,147.76 185.24,149.11 186.33,149.11 187.02,149.8 187.45,149.8 187.64,149.61 187.64,149.42 187.81,149.24 v2(187.92,149.24) ; v2(170.19,141.2) 170.2,141.18 170.2,140.76 170.31,140.66 170.45,140.66 170.83,141.04 170.83,141.12 171.15,141.44 171.64,141.44 172.1,140.97 174.8,140.97
  IN2 w0.109: 181.83,147.11 179.94,145.22 179.94,144.9 180.39,144.45 180.39,144.29 180.16,144.06 180.01,144.06 178.67,145.4 178.35,145.4 178,145.05 178,144.73 179.31,143.43 179.31,143.27 179.07,143.04 178.92,143.04 177.61,144.35 177.3,144.35 176.95,144 176.95,143.68 178.35,142.28 178.35,142.12 178.12,141.89 177.96,141.89 177.14,142.71 176.71,142.71 176.55,142.71 175.97,142.14 175.97,142.14 174.8,140.97
  BOTTOM w0.102: v2(170.19,141.2) 170.12,141.13 UV1.C15
QSA#_5: length 36.8
  TOP w0.112: v2(176.36,139.12) 176.36,139.48 176.39,139.5 176.39,139.89 176.66,140.15 176.99,140.15 178.5,138.64 179.9,138.64 183.86,134.68 184.17,134.68 184.5,135 184.5,135.16 184.02,135.63 184.02,135.96 184.38,136.31 184.7,136.31 185.17,135.84 185.33,135.84 185.57,136.08 185.57,136.24 185.13,136.68 185.13,137 185.48,137.36 185.81,137.36 186.25,136.91 186.41,136.91 186.76,137.27 186.76,137.53 182.87,141.42 182.87,146.24 183.95,147.32 183.95,147.97 183.95,148.47 183.6,148.82 183.45,148.82 UV20.B7
  BOTTOM w0.102: UV1.E9 172.95,137.19 173.39,137.63 173.96,138.19 174.27,138.19 175.52,139.45 176.19,139.45 176.36,139.27 v2(176.36,139.12)
QSA#_6: length 32.6
  IN1 w0.102: v2(186.39,150.22) 186.45,150.01 186.61,149.92 186.67,149.72 186.67,149.27 186.08,148.69 185.45,148.69 185.22,148.46 185.22,144.29 185.29,144.22 ; v2(177.27,136.45) 177.28,136.45 177.73,136 178.51,136 178.51,136 178.53,136
  IN1 w0.109: 185.29,144.22 185.46,144.05 185.46,142.12 185.56,142.01 186.32,142.01 186.55,141.79 186.55,141.3 186.32,141.07 185.56,141.07 185.46,140.96 185.46,140.63 185.56,140.52 186.26,140.52 186.48,140.3 186.48,139.81 186.26,139.58 185.56,139.58 185.46,139.47 185.46,139.15 185.56,139.04 186.32,139.04 186.55,138.81 186.55,138.32 186.32,138.09 185.56,138.09 185.46,137.98 185.46,137.06 184.39,136 178.53,136
  BOTTOM w0.102: UV19.G3 185.92,151.3 185.92,150.69 v2(186.39,150.22) ; v2(177.27,136.45) 177.27,136.54 177.09,136.72 176.92,136.72 176.04,135.84 176.04,135.51 175.78,135.24 UV1.C5
QSA#_7: length 36.4
  BOTTOM w0.102: UV19.B7 185.81,146.45 185.97,146.61 185.97,146.75 185.84,146.88 185.84,147.07 185.58,147.33 184.74,147.33 184.1,146.68 184.1,145.12 184.1,145.11 184.1,145.09 ; 177.47,130.94 175.62,130.94 175.57,130.89 174.99,130.89 174.43,131.44 174.17,131.44 173.87,131.74 173.87,132.15 173.97,132.26 173.97,132.4 173.86,132.51 UV1.H4
  BOTTOM w0.112: 184.1,145.09 184.1,141.4 182.64,139.94 182.64,139.78 183.3,139.12 183.3,138.79 182.95,138.44 182.62,138.44 182,139.05 181.75,139.05 181.43,138.73 181.43,138.57 181.79,138.21 181.84,138.21 182.25,137.8 182.25,137.75 183.28,136.72 183.28,136.39 182.78,135.9 182.46,135.9 180.95,137.41 180.79,137.41 180.55,137.17 180.55,137.01 v4(181.07,136.49) 182.06,135.5 182.06,135.18 181.71,134.82 181.38,134.82 180.95,135.26 180.79,135.26 180.55,135.02 180.55,134.86 180.99,134.43 180.99,134.1 177.82,130.94 177.47,130.94
QSA_0: length 35.8
  BOTTOM w0.102: 160.97,152.65 160.96,152.64 160.96,152.63 158.87,150.55 158.87,147.87 159.68,147.06 159.68,146.89 159.89,146.68 160.07,146.68 160.24,146.5 160.62,146.12 160.62,145.92 UV1.H28 ; UV17.C7 172.69,160.46 172.14,160.46 171.7,160.91 170.17,160.91 169.66,160.41 169.03,160.41 168.82,160.2 168.82,160.2 168.8,160.18
  BOTTOM w0.112: 160.97,152.65 163.56,155.24 163.88,155.24 164.83,154.29 164.99,154.29 165.23,154.53 165.23,154.68 164.28,155.63 164.28,155.96 164.63,156.31 164.96,156.31 165.91,155.36 166.06,155.36 166.3,155.6 166.3,155.76 165.35,156.71 165.35,157.03 165.71,157.39 166.03,157.39 166.98,156.44 167.14,156.44 167.38,156.68 167.38,156.83 166.43,157.78 166.43,158.11 166.78,158.46 167.11,158.46 v4(167.68,157.89) 168.06,157.51 168.21,157.51 168.45,157.75 168.45,157.91 167.5,158.86 167.5,159.18 168.24,159.92 168.54,159.92 168.8,160.18
QSA_1: length 35.7
  TOP w0.102: 169.31,159.67 169.33,159.69 169.33,159.7 170.36,160.73 170.36,161.47 170.86,161.96 170.86,162.32 UV18.C7
  TOP w0.112: v2(163.31,148.08) 164.07,148.08 164.55,148.57 164.55,149.7 162.81,151.45 161.41,151.45 159.66,153.19 159.34,153.19 158.87,152.72 158.71,152.72 158.47,152.96 158.47,153.12 159.12,153.77 159.12,154.18 158.85,154.45 158.85,154.61 159.28,155.04 159.44,155.04 159.79,154.69 160.24,154.69 v4(160.45,154.89) 160.67,155.11 160.67,155.43 160.27,155.83 160.27,156.03 160.56,156.32 160.72,156.32 161.14,155.9 161.46,155.9 161.82,156.26 161.82,156.58 161.4,157 161.4,157.16 162.05,157.81 162.05,158.13 161.71,158.48 161.71,158.69 161.88,158.87 162.11,158.87 162.45,158.53 162.77,158.53 163.12,158.87 163.27,158.87 163.63,158.52 163.95,158.52 164.31,158.88 164.31,159.2 163.95,159.55 163.95,159.71 164.26,160.02 164.54,160.02 164.9,159.66 164.9,159.61 165.39,159.12 168.76,159.12 169.31,159.67
  BOTTOM w0.102: v2(163.31,148.08) 163.33,148.05 UV1.C27
QSA_2: length 33.1
  TOP w0.102: UV18.F3 174.36,162.17 174.17,161.98 173.96,161.98 173.86,162.08 173.86,162.54 173.75,162.64 173.35,162.64 172.82,163.17 v2(172.5,163.17)
  IN1 w0.102: 166.41,150.44 166.41,150.42 166.41,150.42 166.41,150.36 166.42,150.36 166.42,150.24 167.19,149.46 167.19,148.73 167.05,148.59 166.81,148.59 166.67,148.73 166.67,149.23 v2(166.7,149.26) ; 168.77,160.41 168.8,160.41 168.8,160.41 169.59,160.41 170.17,160.99 170.17,161.17 171.69,162.69 172.62,162.69 172.9,162.97 172.9,163.11 172.77,163.24 172.58,163.24 v2(172.5,163.17)
  IN1 w0.109: 168.77,160.41 165.46,160.41 165.18,160.13 165.18,159.41 165.4,159.19 166.08,159.19 166.19,159.08 166.19,158.68 166.08,158.57 165.4,158.57 165.18,158.34 165.18,157.79 165.4,157.56 166.08,157.56 166.19,157.45 166.19,157.13 166.08,157.02 165.68,157.02 165.46,156.79 165.46,153.77 166.65,152.58 166.65,151.41 166.41,151.18 166.41,150.44
  BOTTOM w0.102: UV1.A23 166.16,146.04 166.7,146.57 166.7,148.61 167.1,149.01 167.1,149.16 167,149.26 v2(166.7,149.26)
QSA_3: length 34.3
  IN2 w0.102: v2(172.33,163.8) 172.37,163.84 172.37,163.99 172.25,164.11 172.05,164.11 171.95,164 171.95,163.66 170.57,162.28 170.57,160.23 169.68,159.34 169.68,159.34 169.67,159.32 ; v2(167.78,142.5) 167.78,142.66 167.88,142.76 168.11,142.76 168.34,142.53 168.7,142.53 168.97,142.8 168.97,143.96 167.7,145.23 167.7,146.94
  IN2 w0.109: 169.67,159.32 165.22,154.88 165.22,154.15 165.64,153.73 165.64,153.41 164.48,152.24 164.48,152.09 164.71,151.86 164.86,151.86 166.03,153.02 166.35,153.02 166.93,152.44 166.93,151.23 166.7,151.01 166.04,151.01 165.93,150.9 165.93,150.57 166.04,150.46 166.7,150.46 166.93,150.24 166.93,149.85 167.51,149.27 167.51,147.85 167.7,147.66 167.7,146.94 167.7,146.94
  BOTTOM w0.102: v2(167.78,142.5) 167.7,142.41 UV1.E19 ; UV17.F3 172.14,163.99 v2(172.33,163.8)
QSA_4: length 34.3
  TOP w0.102: UV20.F3 187.66,148.51 187.48,148.51 187.21,148.79 187.21,148.97 187.25,149.02 v2(187.25,149.13)
  IN2 w0.102: 181.97,146.97 181.99,146.99 181.99,147 182.28,147.28 182.57,147.57 183.97,147.57 185.32,148.92 186.41,148.92 187.1,149.61 187.37,149.61 187.45,149.53 187.45,149.39 v2(187.25,149.13) ; v2(169.65,140.62) 170.07,140.62 170.23,140.47 170.53,140.47 171.02,140.96 171.02,141.04 171.23,141.25 171.56,141.25 172.02,140.78 174.71,140.78 174.72,140.78 174.88,140.78 174.92,140.82 174.92,140.82 174.94,140.83
  IN2 w0.109: 174.94,140.83 176.05,141.94 176.05,141.94 176.63,142.51 177.06,142.51 177.88,141.69 178.2,141.69 178.55,142.04 178.55,142.36 177.14,143.76 177.14,143.91 177.38,144.15 177.53,144.15 178.84,142.84 179.16,142.84 179.5,143.19 179.5,143.51 178.2,144.81 178.2,144.97 178.43,145.2 178.59,145.2 179.92,143.86 180.24,143.86 180.59,144.21 180.59,144.53 180.14,144.98 180.14,145.14 181.97,146.97
  BOTTOM w0.102: v2(169.65,140.62) 169.56,140.53 UV1.E15
QSA_5: length 36.7
  TOP w0.112: UV20.C7 183.76,149.14 183.76,148.95 184.15,148.55 184.15,147.89 184.15,147.24 183.07,146.15 183.07,141.51 186.96,137.61 186.96,137.19 186.49,136.71 186.17,136.71 185.72,137.16 185.57,137.16 185.33,136.92 185.33,136.76 185.77,136.32 185.77,135.99 185.42,135.64 185.09,135.64 184.62,136.11 184.46,136.11 184.22,135.88 184.22,135.72 184.7,135.24 184.7,134.92 184.25,134.48 183.78,134.48 179.81,138.44 178.41,138.44 176.9,139.95 176.74,139.95 176.59,139.8 176.59,139.64 176.7,139.53 v2(176.78,139.53)
  BOTTOM w0.102: v2(176.78,139.53) 176.37,139.53 176.27,139.64 175.45,139.64 174.19,138.38 173.88,138.38 173.59,138.09 173.31,137.82 173.31,137.82 173.1,137.6 UV1.D10
QSA_6: length 33.1
  IN1 w0.102: 178.53,136.2 177.8,136.2 177.65,136.35 177.65,136.49 177.68,136.52 v2(177.68,136.86) ; 185.15,144.08 185.14,144.09 185.14,144.1 185.1,144.14 185.1,144.14 185.03,144.21 185.03,148.54 185.37,148.88 186,148.88 186.48,149.35 186.48,149.69 186.45,149.79 186.2,149.79 v2(186.09,149.68)
  IN1 w0.109: 178.53,136.2 184.31,136.2 185.26,137.14 185.26,138.07 185.48,138.29 186.24,138.29 186.35,138.4 186.35,138.73 186.24,138.84 185.48,138.84 185.26,139.06 185.26,139.56 185.48,139.78 186.18,139.78 186.28,139.89 186.28,140.22 186.18,140.33 185.48,140.33 185.26,140.55 185.26,141.04 185.48,141.27 186.24,141.27 186.35,141.38 186.35,141.71 186.24,141.82 185.48,141.82 185.26,142.04 185.26,143.97 185.15,144.08
  BOTTOM w0.102: UV1.D6 175.02,135.39 175.13,135.35 175.23,135.4 175.24,135.4 175.66,135.4 175.85,135.58 175.85,135.91 176.84,136.91 177.17,136.91 177.22,136.86 v2(177.68,136.86) ; UV19.F3 185.73,150.84 185.73,150.61 186.01,150.33 186.01,149.76 v2(186.09,149.68)
QSA_7: length 36.4
  BOTTOM w0.102: UV1.G5 174.08,132.63 174.16,132.55 174.16,132.18 174.06,132.07 174.06,131.82 174.25,131.64 174.51,131.64 175.07,131.08 175.49,131.08 175.54,131.13 177.38,131.13 177.39,131.13 177.44,131.13 177.45,131.14 177.47,131.14 ; 183.9,145.09 183.9,145.11 183.9,145.12 183.9,146.76 184.66,147.52 185.66,147.52 UV19.C7
  BOTTOM w0.112: 183.9,145.09 183.9,141.49 182.43,140.02 182.43,139.7 183.1,139.03 183.1,138.88 182.86,138.64 182.7,138.64 182.09,139.26 181.67,139.26 181.23,138.81 181.23,138.49 v4(181.88,137.84) 183.08,136.64 183.08,136.48 182.7,136.1 182.54,136.1 181.03,137.61 180.71,137.61 180.35,137.25 180.35,136.93 180.7,136.58 180.7,136.53 181.11,136.12 181.16,136.12 181.86,135.42 181.86,135.26 181.63,135.02 181.47,135.02 181.03,135.46 180.71,135.46 180.35,135.1 180.35,134.78 180.79,134.34 180.79,134.19 177.74,131.14 177.47,131.14
RASA0#: length 43.9
  TOP w0.102: UV18.J3 176.07,163.89 174.48,163.89 174.21,164.17 174.21,164.66 174.23,164.68 v2(174.23,164.71)
  IN1 w0.102: 170.11,145.86 168.2,145.86 167.62,145.28 166.63,145.28 164.98,143.63 v2(164.44,143.63)
  IN1 w0.264: v2(179.13,159.77) 179.13,159.27 176.63,156.77 176.63,150.66 175.44,149.48 175.06,149.48 174.63,149.9 174.26,149.9 173.89,149.53 173.89,149.16 174.32,148.73 174.32,148.35 173.95,147.98 173.57,147.98 173.14,148.41 172.77,148.41 172.39,148.04 172.39,147.66 172.76,147.3 172.76,146.79 171.82,145.86 170.11,145.86
  IN2 w0.102: v2(174.23,164.71) 174.77,164.71 175.04,164.44 175.92,164.44 177.48,162.88 177.48,162.42 179.51,160.39 179.51,160.08 180.01,159.58 180.01,159.44 179.83,159.26 179.63,159.26 v2(179.13,159.77)
  BOTTOM w0.102: UV17.J3 173.59,165.89 173.59,164.65 173.74,164.5 174.02,164.5 v2(174.23,164.71) ; UV1.G22 164.61,143.4 164.44,143.57 v2(164.44,143.63)
RASA1#: length 47.9
  TOP w0.102: v2(188,150.86) 187.87,150.73 187.87,150.48 187.97,150.38 188.49,150.38 188.84,150.73 189.15,150.73 189.47,150.41 UV20.J3 ; 170.11,143.94 169.82,143.94 169.09,143.22 169.09,142.94 167.33,141.17 167.18,141.17 v2(166.78,140.78)
  TOP w0.201: v2(179.89,156.02) 180.04,156.17 180.04,156.72 179.79,156.97 179.42,156.97 172.74,150.29 172.74,149.96 172.94,149.75 173.3,149.75 173.5,149.55 173.5,149.15 173.3,148.95 172.94,148.95 172.74,148.75 172.74,148.35 172.94,148.15 173.3,148.15 173.5,147.95 173.5,147.55 173.3,147.35 172.94,147.35 172.74,147.15 172.74,145.76 170.92,143.94 170.11,143.94
  IN1 w0.102: v2(179.89,156.02) 180.35,155.56 180.5,155.56 180.99,156.05 181.13,156.05 181.28,155.9 181.28,155.76 180.78,155.27 180.78,155.12 180.93,154.98 181.07,154.98 181.56,155.47 181.71,155.47 181.85,155.33 181.85,155.18 181.36,154.69 181.36,154.55 181.53,154.38 181.68,154.38 182.17,154.88 182.32,154.88 182.5,154.7 182.5,154.5 182.06,154.06 182.06,153.92 182.19,153.79 182.91,153.79 183.29,153.41 183.82,153.41 184.6,154.19 186.58,154.19 187.83,152.95 187.83,151.63 188,151.46 v2(188,150.86)
  BOTTOM w0.102: v2(188,150.86) 187.51,150.86 187.23,151.14 187.23,152.61 UV19.J3 ; UV1.G17 167.11,140.29 166.78,140.61 v2(166.78,140.78)
REGOUT:
  vias: v1(51.39,172.59)
RESET_OUT#: length 91.2
  TOP w0.102: UE1.73 178.63,77.97 v2(179.17,77.42) ; v2(149.73,54.51) 149.73,53.96 150.09,53.6 v3(151.24,53.6) 154.38,53.6 155.37,54.58 158.67,54.58 161.17,57.09 165.84,57.09 168.59,59.84 v2(168.86,59.84)
  IN1 w0.127: v2(179.17,77.42) 182.29,77.42 182.49,77.22 182.49,76.01 184.04,74.46 184.04,71.63 182,69.6 181.84,69.43 180.86,69.43 180.26,68.83 179.57,68.83 179.57,68.83 177.16,68.83 169.37,61.05 169.37,60.21 169,59.84 v2(168.86,59.84)
  BOTTOM w0.076: UC1.BA20 127.39,74.71 127.07,74.38 127.07,72.77 127.56,72.27 127.56,69.52 127.86,69.23
  BOTTOM w0.102: RE367.1 CE82.1 178.62,77.98 v2(179.17,77.42) ; 127.86,69.23 127.86,68.25 141.6,54.51 v2(149.73,54.51)
RING2:
  vias: v1(182.68,20.7) v2(182.81,22.42) v2(182.81,21.81)
RREF: length 3.5
  BOTTOM w0.102: v1(13.44,12.6) 13.78,12.93 R3203.1
  BOTTOM w0.254: 14.37,14.82 14.37,15.28 U3201.1
  BOTTOM w0.305: 14.37,14.82 R3203.1
RRX: length 3.4
  TOP w0.102: U5502.28 32.23,63.59 v2(32.24,63.58) 32.77,63.58 v1(33.51,64.31)
  BOTTOM w0.102: v2(32.24,63.58) 32.24,63.74 R5505.1
RSET: length 4.2
  TOP w0.203: LOM30.31 48.31,171.47 47.93,171.84 47.52,171.84 47.47,171.89
  TOP w0.305: 47.47,171.89 v1(47.08,172.28) 46.79,172.57 46.55,172.57 45.7,173.42 R3032.2
RTC_DET#: length 275.8
  TOP w0.102: RC384.1 143.89,87.57 142.11,87.57 v1(141.38,88.3) v2(140.9,88.77) ; v2(160.97,12.64) 158.57,10.24 95.8,10.24 93.25,12.79 82.67,12.79 80.55,10.67 48.25,10.67 45.21,13.72 43.9,13.72 42.78,12.6 35.79,12.6 35.06,13.33 35.06,16.05 34.35,16.76 Q2505.1 ; v2(158.92,28.45) 158.92,35.31 157.67,36.56 157.67,38.8 156.29,40.18 156.29,48.41 157.85,49.97 157.85,50.16 158.11,50.42 158.49,50.42 159.38,51.31 160.72,51.31 164.04,54.62 166.59,54.62 168.24,56.27 175.51,56.27 v2(175.53,56.26)
  IN2 w0.127: v2(175.53,56.26) 175.51,56.28 175.51,66.39 176.27,67.15 176.27,68.87 173.2,71.94 173.2,76.01 171.89,77.32 171.89,80.84 172.64,81.59 172.64,82.73 172.04,83.34 167.93,83.34 165.79,85.47 162.81,85.47 161.7,86.58 160.87,86.58 159.57,87.88 158.05,87.88 156.41,89.52 148.9,89.52 148.6,89.22 146.74,89.22 146.4,89.56 145.54,89.56 145.35,89.75 141.29,89.75 140.9,89.36 v2(140.9,88.77)
  BOTTOM w0.102: UC1.P1 138.68,89.41 138.9,89.41 138.9,89.41 140.42,89.41 140.9,88.92 v2(140.9,88.77) ; v2(160.97,12.64) 162.87,12.64 164.14,13.91 164.14,15.18 165.73,16.76 165.73,22.42 164.78,23.37 164.78,25.08 163.19,26.67 160.97,26.67 159.19,28.45 v2(158.92,28.45)
RTC_PWR: length 6.5
  TOP w0.102: v1(34.02,12.9) 33.64,12.52 D2501.3
  TOP w0.508: Q2505.2 33.38,15.77 R2504.1 R2502.1 32.52,13.02 D2501.3
RTCRST_ON: length 76.6
  TOP w0.102: R1902.1 163.52,66.81 163.42,66.71 Q1901.2 163.42,65.37 164.59,64.2 164.59,63.25 163.51,62.17 162.05,62.17 161.66,61.79 161.66,60.45 162.03,60.09 165.27,60.09 167.68,62.5 v1(171.67,62.5) 172.55,61.62 173.01,61.16 173.01,60.25 178.11,55.15 v2(178.11,54.86) ; UE1.31 194.3,80.77 v2(194.43,80.9)
  IN1 w0.127: v2(194.43,80.9) 194.43,79.81 193.5,78.89 193.5,77.55 193.35,77.4 193.35,75.95 192.91,75.5 192.91,69.56 192.37,69.02 192.37,67.72 193.8,66.29 194.43,66.29 195.7,65.02 195.7,62.48 192.46,59.25 192.46,55.37 191.51,54.42 178.56,54.42 v2(178.11,54.86)
RUNPWROK: length 5.3
  TOP w0.102: v2(184.84,81.28) 185.55,81.98 UE1.48
  BOTTOM w0.102: RE438.1 182.18,80.14 183.53,81.5 v1(183.56,81.5) 184.63,81.5 v2(184.84,81.28)
SA_SNUB: length 0.8
  BOTTOM w0.102: 124.22,121.72 v1(124.22,120.95)
SA_SW: length 6.9
  IN1 w0.508: v2(121.28,123.22) 120.84,123.65 v2(120.84,129.97)
  vias: v1(118.7,120.57)
SATA3_PRX_HDDTX_N0: length 117.5
  IN2 w0.076: 135.33,95.69 135.29,95.69 133.58,93.98 133.47,93.98 133,93.51 133,93.07 131.98,92.05 131.55,92.05 131.23,91.74 127.75,91.74 127.49,92.01 127.49,93.81 127.38,93.92 127.19,93.92 127.11,93.84 v2(127.11,93.67)
  IN2 w0.127: v2(182.74,34.39) 182.59,34.54 182.29,34.54 182.05,34.79 182.05,35.54 185.76,39.25 185.76,41.29 186.42,41.94 186.42,49.94 183.41,52.95 183.41,61.53 183.06,61.87 183.06,63.74 183.51,64.18 183.51,69.66 182.73,70.44 182.73,74.27 181.25,75.75 181.25,80.87 178.04,84.07 175.08,84.07 169.3,89.85 164.8,89.85 162.32,92.33 161.62,92.33 158.62,95.33 151.12,95.33 151.04,95.42 143.78,95.42 143.31,95.88 140.46,95.88 139.94,95.37 136.54,95.37 136.22,95.69 135.33,95.69
  BOTTOM w0.089: UC1.F20 127.57,93.37 127.27,93.67 v2(127.11,93.67)
  BOTTOM w0.091: v2(182.74,34.39) 182.95,34.6 183.05,34.6 C5616.1
SATA3_PRX_HDDTX_P0: length 117.5
  IN2 w0.076: 135.33,95.95 135.31,95.95 133.51,94.15 133.4,94.15 132.83,93.57 132.83,93.14 131.92,92.22 131.48,92.22 131.16,91.91 127.82,91.91 127.65,92.08 127.65,93.88 v2(127.12,94.42)
  IN2 w0.127: v2(182.74,34.97) 182.57,34.8 182.4,34.8 182.3,34.89 182.3,35.43 186.02,39.15 186.02,41.18 186.67,41.84 186.67,50.05 183.66,53.06 183.66,61.63 183.32,61.98 183.32,63.63 183.76,64.08 183.76,69.77 182.98,70.55 182.98,74.38 181.5,75.86 181.5,80.97 178.15,84.33 175.19,84.33 169.41,90.11 164.9,90.11 162.42,92.59 161.73,92.59 158.72,95.59 151.23,95.59 151.15,95.67 143.89,95.67 143.42,96.14 140.35,96.14 139.84,95.63 136.65,95.63 136.33,95.95 135.33,95.95
  BOTTOM w0.089: v2(127.12,94.42) 127.57,93.96 UC1.E20
  BOTTOM w0.091: v2(182.74,34.97) 182.92,34.78 183.02,34.78 C5615.1
SATA3_PTX_HDDRX_N0: length 132.5
  IN2 w0.127: v2(154.1,96.92) 154.1,96.91 154.43,96.58 154.43,96.31 154.72,96.02 159.13,96.02 162,93.15 162.64,93.15 165.24,90.55 169.62,90.55 175.02,85.15 177.99,85.15 181.95,81.19 181.95,77.51 182.34,77.11 182.34,75.63 184.24,73.73 184.24,72.82 185.34,71.73 185.34,66.7 185.79,66.25 185.79,63.94 185.6,63.75 185.6,62.17 186.45,61.32 186.45,50.88 187.11,50.23 187.11,41.34 186.45,40.68 186.45,37.72 183.83,35.1 183.83,33.07 183.6,32.84 183.42,32.84 183.09,33.16 v2(183.09,33.16)
  BOTTOM w0.076: UC1.B21 126.38,96.32 126.44,96.38 126.6,96.38 126.72,96.5 126.72,97.26 126.51,97.48 126.51,100.35 125.84,101.02
  BOTTOM w0.091: 125.84,101.02 125.84,101.89 132.37,108.42 134.6,108.42 134.98,108.04 140.62,108.04 141.67,109.09 142.22,109.09 146.37,104.95 146.37,104.13 150.68,99.82 152.2,99.82 154.37,97.65 154.37,97.19 v2(154.1,96.92) ; v2(183.09,33.16) 183.27,32.98 183.42,32.98 C5603.2
SATA3_PTX_HDDRX_P0: length 132.5
  IN2 w0.127: v2(183.09,32.58) 183.7,32.58 184.08,32.96 184.08,34.99 186.71,37.62 186.71,40.58 187.36,41.23 187.36,50.33 186.71,50.98 186.71,61.42 185.86,62.27 185.86,63.65 186.05,63.84 186.05,66.36 185.6,66.81 185.6,71.84 184.5,72.93 184.5,73.84 182.6,75.74 182.6,77.22 182.21,77.61 182.21,81.29 178.09,85.41 175.13,85.41 169.73,90.8 165.35,90.8 162.74,93.41 162.11,93.41 159.24,96.28 154.83,96.28 154.68,96.42 v2(154.68,96.92)
  BOTTOM w0.076: UC1.A21 126.48,96.68 126.56,96.76 126.56,97.19 126.34,97.41 126.34,100.28 125.78,100.84 125.77,100.84 125.67,100.95 125.67,101 125.66,101.01 125.66,101.02
  BOTTOM w0.091: C5602.2 183.38,32.8 183.31,32.8 v2(183.09,32.58) ; 125.66,101.02 125.66,101.96 132.3,108.6 134.68,108.6 135.06,108.22 140.54,108.22 141.6,109.27 142.3,109.27 146.55,105.03 146.55,104.21 150.75,100 152.28,100 154.55,97.73 154.55,97.05 v2(154.68,96.92)
SATA_LED#: length 299.2
  TOP w0.102: Q6105.3 45.24,5.43 v2(43.68,3.87) ; R2405.1 195.74,85.48 v1(194.5,84.24) 191.64,81.38 191.64,79.43 188.91,76.7 188.91,75.73 188.36,75.18 187.57,75.18 187.06,74.68 182.9,74.68 v2(182.29,74.07)
  IN1 w0.127: v2(180.65,33.66) 180.65,30.61 178.17,28.13 178.17,24.7 175.96,22.49 175.96,20.55 177.29,19.23 177.29,17.3 174.3,14.31 174.3,9.91 166.9,2.5 45.05,2.5 v2(43.68,3.87)
  IN2 w0.127: v2(140.16,93.79) 140.72,93.22 143.31,93.22 144.14,94.04 150.42,94.04 152.5,91.97 158.79,91.97 160.46,90.3 161.35,90.3 163.95,87.69 166.98,87.69 169.73,84.95 172.92,84.95 174.6,83.27 176.86,83.27 179.38,80.75 179.38,79.86 180.82,78.43 180.82,75.57 182.29,74.1 v2(182.29,74.07) 182.29,69.16 182.57,68.88 182.57,66.34 182.97,65.94 182.97,64.26 182.63,63.92 182.63,61.69 182.97,61.35 182.97,52.77 185.98,49.76 185.98,42.99 183.19,40.2 183.19,37.81 180.65,35.27 v2(180.65,33.66)
  BOTTOM w0.102: RC248.1 144.63,98.03 140.39,93.79 v2(140.16,93.79) 138.88,92.51 UC1.H1
SATA_LED_EN: length 226.1
  TOP w0.102: R6110.2 41.81,11.41 v1(41.59,11.63) ; R6110.2 41.84,10.29 Q6105.2 ; R6110.2 v2(41.81,9.65) ; R2405.2 194.64,83.44 194.64,82.88 193.48,81.72 192.56,81.72 192.08,81.25 192.08,80.64 192.36,80.37 ; v2(181.66,73.58) 182.45,73.58 183.04,74.17 186.87,74.17 187.28,73.76 188.36,73.76 189.35,74.75 189.35,76.56 192.02,79.23 192.02,80.03 192.36,80.37 ; UE1.30 192.36,80.37
  IN2 w0.127: v2(181.66,73.58) 181.86,73.37 181.86,69.86 181.58,69.57 181.58,61.34 181.98,60.94 181.98,46.04 182.49,45.53 182.49,41.08 182.09,40.68 182.09,38.1 179.06,35.08 179.06,31.28 176.84,29.06 176.84,25.7 176.45,25.3 176.45,24.37 172.84,20.76 172.84,10.79 170.87,8.83 157.81,8.83 157.71,8.72 157.36,8.72 157.26,8.83 82.54,8.83 82.1,9.27 78.43,9.27 78.11,8.95 54.51,8.95 53.87,9.59 41.87,9.59 v2(41.81,9.65)
SATA_ODD_DA#: length 38.1
  TOP w0.102: v2(152.65,83.44) 152.65,83.31 152.89,83.07 R5602.2
  BOTTOM w0.076: UC1.J3 137.32,91.85 137.66,91.5 138.3,91.5 138.36,91.57 139.95,91.57 140.39,92.01
  BOTTOM w0.102: 146.87,96.49 151.55,96.49 155.17,92.87 157.79,92.87 157.79,92.87 157.79,88.71 156.08,87 156.08,85.51 154.57,84 153.21,84 v2(152.65,83.44) ; 140.39,92.01 143.06,94.68 RC356.2
  BOTTOM w0.127: RC356.2 144.38,94.98 v1(145.89,96.49) 146.87,96.49
SATA_ODD_DA#_C: length 3.3
  TOP w0.102: R5602.1 153.8,83.64 v1(154.23,84.07) 154.74,84.58 ODD1.17
SATA_ODD_PRSNT#: length 52.2
  TOP w0.102: R5604.1 152.79,80.54 153.16,80.91 v2(154.56,80.91) 154.7,80.77 154.7,80.24 154.86,80.08 ODD1.8
  IN2 w0.127: v2(161.16,97.35) 160.78,97.35 159.38,98.74 154.63,98.74 153.42,97.54 151.57,97.54 151.33,97.29 144.6,97.29 144.01,96.71 v2(142.36,96.71)
  BOTTOM w0.076: UC1.H3 137.17,92.84 138.68,92.84 139.31,93.47 139.31,94.74
  BOTTOM w0.102: 139.31,94.74 139.31,94.97 140.27,95.92 140.8,95.92 RC246.1 142.28,96.79 v2(142.36,96.71) ; v2(154.56,80.91) 154.56,80.91 154.67,81.03 156.46,81.03 156.92,81.49 156.92,82.76 v1(160.97,86.8) 160.97,97.22 161.09,97.35 v2(161.16,97.35)
SATA_ODD_PWRGT: length 92.7
  TOP w0.102: v2(145.73,85.53) 146.81,86.61 v1(146.81,88.56) 146.81,89.22 145.95,90.07 145.14,90.07 144.98,90.23 143.87,90.23 143.05,89.41 142.3,89.41 141.92,89.03 141.92,88.39 v2(141.98,88.33)
  TOP w0.254: R5607.2 183.01,43.94 v2(183.06,43.94) 183.06,43.63 183.31,43.38 183.31,43.13 183.13,42.95 U5601.4
  IN1 w0.127: v2(163,74.83) 161.79,76.03 161.79,79.15 159.18,81.76 159.18,82.1 156.04,85.23 155.12,85.23 154.69,85.66 152.7,85.66 152.05,86.31 150.98,86.31 150.34,86.94 149.99,86.94 149.13,86.94 148.16,85.98 146.17,85.98 v2(145.73,85.53) ; v2(183.06,43.94) 183.03,43.9 176.29,43.9 175,42.61 173.22,42.61 v2(173.16,42.67)
  IN2 w0.127: v2(163,74.83) 161.78,73.61 161.78,71.6 167.33,66.05 167.33,63.26 167.98,62.61 167.98,59.27 171.06,56.19 171.06,46.46 172.39,45.13 172.39,43.38 173.09,42.67 v2(173.16,42.67)
  BOTTOM w0.076: v2(141.98,88.33) 139.82,88.33 139.12,87.63 138.68,87.63 138.59,87.54 136.62,87.54 136.51,87.43 UC1.W4
SATA_PRX_ODDTX_N1: length 57.8
  IN2 w0.076: 135.04,94.59 135.01,94.61 134.91,94.61 134.08,93.78 134.08,93.28 133.23,92.43 133.23,92.08 132.17,91.02 130.86,91.02 130.68,91.19 127.33,91.19 126.58,91.95 126.58,93.13 126.53,93.19 126.4,93.19 v2(126.2,92.99)
  IN2 w0.127: v2(170.2,87.64) 170.2,86.72 169.9,86.42 168.94,86.42 167.22,88.14 164.22,88.14 161.62,90.74 160.92,90.74 159.16,92.51 152.68,92.51 150.6,94.59 135.04,94.59
  BOTTOM w0.089: UC1.G21 126.33,92.99 v2(126.2,92.99)
  BOTTOM w0.091: v2(170.2,87.64) 170.2,86.45 168.85,85.1 168.02,85.1 167.76,84.83 167.76,84.55 C5607.2
SATA_PRX_ODDTX_P1: length 57.8
  IN2 w0.076: 135.04,94.85 135.02,94.85 134.95,94.78 134.84,94.78 133.91,93.85 133.91,93.34 133.07,92.5 133.07,92.15 132.1,91.19 130.93,91.19 130.75,91.36 127.4,91.36 126.74,92.02 126.74,93.2 126.59,93.35 126.28,93.35 126.2,93.43 v2(126.2,93.58)
  IN2 w0.127: v2(169.6,87.64) 169.94,87.3 169.94,86.82 169.8,86.68 169.04,86.68 167.33,88.39 164.33,88.39 161.73,91 161.03,91 159.26,92.76 152.79,92.76 150.7,94.85 135.04,94.85
  BOTTOM w0.089: UC1.F21 126.47,93.31 v2(126.2,93.58)
  BOTTOM w0.091: C5608.2 167.58,84.55 167.58,84.91 167.95,85.28 168.78,85.28 170.02,86.52 170.02,87.23 v2(169.6,87.64)
SATA_PTX_ODDRX_N1: length 75.1
  IN2 w0.127: v2(156.18,94.78) 156.26,94.69 156.26,94.26 156.53,93.99 158.81,93.99 161.3,91.5 162.13,91.5 164.47,89.16 168.67,89.16 168.81,89.01 168.81,88.75 v2(168.67,88.61)
  BOTTOM w0.076: UC1.D21 126.17,95.05 126.09,95.34 126.09,95.44 125.95,95.92 125.95,96.17 125.98,96.26 125.98,96.45 125.8,96.98 125.8,100 125.34,100.46 125.33,100.46 125.32,100.47
  BOTTOM w0.091: 125.32,100.47 125.09,100.7 125.04,100.75 125.04,102.18 132.1,109.25 134.9,109.25 135.35,108.8 140.03,108.8 141.14,109.91 142.48,109.91 147.12,105.26 147.12,104.52 150.96,100.69 152.55,100.69 155.58,97.65 155.58,94.57 155.8,94.36 156.07,94.36 156.18,94.46 v2(156.18,94.78) ; v2(168.67,88.61) 168.84,88.44 168.84,87.31 166.31,84.78 166.31,83.36 165.92,82.97 165.92,82.76 C5611.2
SATA_PTX_ODDRX_P1: length 75
  IN2 w0.127: v2(169.31,88.61) 169.07,88.85 169.07,89.12 168.77,89.42 164.58,89.42 162.24,91.76 161.41,91.76 158.92,94.25 156.64,94.25 156.52,94.36 156.52,94.54 v2(156.76,94.78)
  BOTTOM w0.076: 125.45,100.6 125.46,100.59 125.46,100.57 125.96,100.07 125.96,97 126.15,96.48 126.15,96.23 126.11,96.12 126.11,95.94 126.2,95.68 126.23,95.66 126.3,95.66 126.34,95.71 126.45,95.71 126.49,95.67 126.49,95.49 UC1.C21
  BOTTOM w0.091: v2(156.76,94.78) 156.7,94.78 156.55,94.62 156.55,94.58 156.15,94.18 155.72,94.18 155.4,94.5 155.4,97.57 152.47,100.51 150.88,100.51 146.94,104.45 146.94,105.19 142.4,109.73 141.22,109.73 140.11,108.62 135.28,108.62 134.82,109.07 132.18,109.07 125.22,102.11 125.22,100.83 125.45,100.6 ; C5612.2 166.1,82.76 166.1,82.9 166.49,83.28 166.49,84.71 169.02,87.24 169.02,88.32 v2(169.31,88.61)
SATA_RXN0_R: length 10.1
  BOTTOM w0.091: 190.94,30.13 190.72,30.13 190.58,30.27 190.26,30.27 189.44,31.08 v4(189.44,31.42) 189.44,32.55 188.08,33.91 188.03,33.91 187.64,34.3 187.14,34.3 186.96,34.12 EU5602.7 EU5602.4 185.4,34.12 185.24,34.28 185.07,34.28 184.75,34.6 184.65,34.6 C5616.2
  BOTTOM w0.102: HDD1.8 190.94,30.13
SATA_RXN2_R: length 24.5
  TOP w0.091: ODD1.5 156.04,78.58 156.2,78.74 156.58,78.74 157.02,78.3 158.47,76.86 158.47,75.46 158.72,75.21 158.87,75.21 v2(159.08,74.99)
  BOTTOM w0.091: v2(159.08,74.99) 159.23,75.15 159.51,75.15 160.99,73.67 163.72,73.67 164.09,74.04 166.22,74.04 167.91,75.73 167.91,78.58 167.47,79.02 167.47,80.3 v4(167.67,80.51) 167.83,80.67 167.83,81.76 167.87,81.8 167.87,82.39 167.83,82.42 167.83,83 C5607.1
SATA_RXP0_R: length 10.1
  BOTTOM w0.091: C5615.2 184.67,34.78 184.82,34.78 185.14,34.46 185.24,34.46 185.4,34.62 EU5602.5 EU5602.6 186.95,34.62 187.09,34.48 187.76,34.48 v4(187.97,34.27) 189.62,32.62 189.62,31.75 189.66,31.71 189.66,31.12 190.33,30.45 190.59,30.45 190.77,30.63 190.94,30.63
  BOTTOM w0.102: HDD1.7 190.94,30.63
SATA_RXP2_R: length 24.5
  TOP w0.091: v2(159.08,75.58) 158.89,75.39 158.79,75.39 158.65,75.53 158.65,76.93 156.66,78.92 156.2,78.92 156.04,79.08 ODD1.6
  BOTTOM w0.091: C5608.1 167.57,83.28 167.65,83.2 v4(167.65,82.09) 167.65,80.79 167.29,80.43 167.29,78.95 167.73,78.51 167.73,75.81 166.15,74.22 164.02,74.22 163.64,73.85 161.07,73.85 159.59,75.33 159.33,75.33 v2(159.08,75.58)
SATA_TXN0_R: length 9.8
  BOTTOM w0.091: 190.94,29.13 190.92,29.13 190.75,28.96 190.37,28.96 190.11,29.21 v4(190.11,29.51) 190.11,29.87 190.09,29.87 189.05,30.92 189.05,32.18 188.25,32.97 187.95,32.97 187.92,33.01 187.33,33.01 187.29,32.97 187.08,32.97 186.93,33.12 EU5602.8 EU5602.2 185.36,33.12 185.22,32.98 185.01,32.98 C5603.1
  BOTTOM w0.102: HDD1.10 190.94,29.13
SATA_TXN2_R: length 20.4
  TOP w0.091: v2(158.02,76.47) 157.81,76.26 157.56,76.26 157.13,76.69 157.13,77.06 156.77,77.42 156.55,77.42 156.54,77.43 156.52,77.43
  TOP w0.102: ODD1.3 156.01,77.58 156.17,77.43 156.52,77.43
  BOTTOM w0.091: C5611.1 165.77,81.46 166.02,81.21 166.02,80.67 165.99,80.63 165.99,80.05 166.02,80.01 166.02,79.4 167.15,78.27 167.15,76.05 165.95,74.84 163.81,74.84 163.39,74.43 161.32,74.43 159.58,76.17 158.32,76.17 v2(158.02,76.47)
SATA_TXP0_R: length 9.8
  BOTTOM w0.091: 190.94,28.63 190.88,28.63 190.74,28.78 190.29,28.78 189.9,29.17 189.9,29.81 188.87,30.84 188.87,32.11 188.18,32.79 v4(187.62,32.79) 187.11,32.79 186.93,32.62 EU5602.9 EU5602.1 185.37,32.62 185.19,32.8 185.05,32.8 C5602.1
  BOTTOM w0.102: HDD1.11 190.94,28.63
SATA_TXP2_R: length 20.3
  TOP w0.091: 156.52,77.24 156.54,77.24 156.55,77.24 156.7,77.24 156.95,76.98 156.95,76.61 157.48,76.08 157.82,76.08 v2(158.02,75.89)
  TOP w0.102: 156.52,77.24 156.17,77.24 156.01,77.08 ODD1.2
  BOTTOM w0.091: C5612.1 166.2,81.17 v4(166.2,80.34) 166.2,79.47 167.33,78.34 167.33,75.97 166.02,74.66 163.88,74.66 163.46,74.25 161.25,74.25 159.5,75.99 158.12,75.99 v2(158.02,75.89)
SD_CD#: length 17.3
  TOP w0.102: v1(31.86,22.73) 31.1,21.97 v2(31.04,21.97) 31.04,22.14 R3301.1
  IN2 w0.127: v2(19.21,18.06) 19.21,18.08 21.16,20.04 25.84,20.04 26.47,20.68 26.47,21.21 26.99,21.73 30.8,21.73 v2(31.04,21.97)
  BOTTOM w0.102: v2(19.21,18.06) 18.98,17.83 U3201.13
SD_CD_R#: length 7.1
  TOP w0.102: R3301.2 EC3305.1 28.41,23.97 AFTP3304.1 27.17,25.21 27.17,25.53 26.66,26.03 26.66,26.99 25.73,27.92 CARD1.10
SD_CLK: length 17.3
  TOP w0.102: CARD1.5 25.38,20 AFTP3303.1 29.01,20 29.25,19.76 R6522.1 28.89,19.43 28.82,19.49 28.08,19.49 v2(27.64,19.05)
  IN2 w0.127: v2(22.27,18.82) 23.33,17.77 24.09,17.77 24.22,17.9 24.22,19.11 24.34,19.24 24.75,19.24 24.88,19.11 24.88,17.89 25,17.77 25.41,17.77 25.54,17.9 25.54,18.92 25.67,19.05 v2(27.64,19.05)
  BOTTOM w0.102: v2(22.27,18.82) EC3201.1 R3201.2
SD_CLK_5170: length 2.7
  BOTTOM w0.102: U3201.15 19.43,16.83 v1(19.75,17.15) 20.5,17.91 R3201.1
SD_CLK_CONN: length 2.1
  TOP w0.102: EC9758.1 R6522.2 v1(31.29,19.43)
SD_CMD: length 20.4
  TOP w0.102: v2(28.7,15.37) 28.17,14.85 EC3304.1 27.45,14.29 27.16,14 AFTP3302.1 27.16,12.9 26.75,12.49 CARD1.2
  IN2 w0.127: v2(28.7,15.37) 28.19,15.88 26.88,15.88 26.78,15.98 26.78,16.92 26.66,17.04 26.31,17.04 26.17,16.9 26.17,15.98 26.07,15.88 25.65,15.88 25.55,15.98 25.55,16.92 25.43,17.04 25.07,17.04 24.94,16.9 24.94,15.98 24.84,15.88 v2(19.99,15.88)
  BOTTOM w0.102: U3201.18 18.95,15.33 18.98,15.3 19.55,15.3 19.99,15.74 v2(19.99,15.88)
SD_D0: length 21.8
  TOP w0.102: v2(25.86,20.9) 26.14,20.62 28.73,20.62 EC3306.1 28.73,21.54 AFTP3306.1 27.62,22.03 27.22,22.43 27.22,22.44 26.49,23.18 26.47,23.18 25.96,23.69 25.96,24.57 25.54,24.99 CARD1.7
  IN2 w0.127: v2(17.56,21.02) 17.56,21.25 18.34,22.03 24.06,22.03 25.2,20.89 25.85,20.89 v2(25.86,20.9)
  BOTTOM w0.102: v2(17.56,21.02) 17.56,19.76 17.11,19.32 U3201.11
SD_D1: length 22.5
  TOP w0.102: v2(27.8,22.62) 28.33,22.1 EC3301.1 27.79,23.5 AFTP3307.1 26.66,24.57 26.66,25.34 26.16,25.84 26.16,26.42 25.95,26.62 CARD1.8
  IN2 w0.127: v2(16.88,21.02) 16.88,21.53 17.98,22.62 v2(27.8,22.62)
  BOTTOM w0.102: v2(16.88,21.02) 16.88,19.95 16.61,19.68 U3201.10
SD_D2: length 20.3
  TOP w0.102: v2(28,11.43) EC3302.1 27.67,9.66 27.29,9.28 27.29,7.65 AFTP3308.1 27.13,7.49 CARD1.9
  IN2 w0.127: v2(28,11.43) 28,12.16 27.79,12.37 17.07,12.37 16.77,12.67 v2(16.77,13.56)
  BOTTOM w0.102: U3201.21 16.61,13.72 v2(16.77,13.56)
SD_D3: length 20.3
  TOP w0.102: CARD1.1 26.88,9.99 27.43,10.54 AFTP3309.1 27.43,12.23 28.17,12.98 EC3303.1 28.17,13.2 v2(28.63,13.65)
  IN2 w0.127: v2(28.63,13.65) 28.91,13.65 29.16,13.9 29.16,14.38 28.87,14.67 18.3,14.67 18.14,14.51 v2(18.14,14.07)
  BOTTOM w0.102: v2(18.14,14.07) 17.98,13.91 17.27,13.91 17.11,14.06 U3201.20
SD_RCOMP: length 9.5
  TOP w0.102: RC96.1 142.88,83.88 v1(139.91,83.88) 139.38,83.88 137.98,85.28 135.63,85.28 v2(135.44,85.09)
  BOTTOM w0.102: UC1.AB7 135.44,85.15 v2(135.44,85.09)
SD_WP: length 28.8
  TOP w0.102: CARD1.11 26.36,29.12 27.26,28.22 AFTP3305.1 27.13,27.35 27.13,26.01 28,25.15 EC3307.1 29.83,24.51 31.24,24.51 v2(32.19,23.56)
  IN2 w0.127: v2(16.01,21.44) 16.01,21.54 18.34,23.88 31.87,23.88 v2(32.19,23.56)
  BOTTOM w0.102: R3202.1 15.86,21.29 v2(16.01,21.44)
SD_WP_5170: length 2.9
  BOTTOM w0.102: v1(16.26,20.5) 15.42,20.5 R3202.2 15.61,20.05 U3201.8
SDREFG: length 4.3
  BOTTOM w0.254: U3201.6 13.97,17.83 13.65,18.16
  BOTTOM w0.305: 13.65,18.16 13.65,19.48 v1(13.19,19.94) 13.19,20.12 13.44,20.37 C3206.1
SERIRQ: length 76.3
  TOP w0.102: v2(157.65,68.25) 157.68,68.22 RC21.2 ; UE1.55 v2(182.75,84.07)
  IN1 w0.127: v2(182.75,84.07) 182.68,84.01 179.42,84.01 178.53,84.9 174.09,84.9 173.3,85.69 v2(171.09,85.69)
  BOTTOM w0.076: UC1.AY11 132.02,74.9 131.91,74.79 131.91,73.83 133.65,72.09 133.69,72.09 136.34,69.43 136.34,69.04 136.67,68.71
  BOTTOM w0.102: 136.67,68.71 139.13,66.25 140.18,66.25 140.5,65.93 140.93,65.93 142.28,64.58 144.85,64.58 145.58,63.86 148.02,63.86 152.81,68.64 157.25,68.64 v2(157.65,68.25) 158.09,68.69 158.89,68.69 158.96,68.62 165.55,68.62 166.1,69.17 166.1,70.04 167.59,71.53 167.59,73.69 169.12,75.23 169.12,82.31 169.66,82.85 171.26,84.45 v1(171.26,84.89) 171.26,85.52 v2(171.09,85.69)
SIO_EXT_SCI#: length 60.8
  TOP w0.102: UE1.66 v2(178.76,80.77)
  IN2 w0.127: v2(139.5,92.27) 140.2,92.96 143.44,92.96 144.27,93.79 150.3,93.79 152.4,91.69 158.62,91.69 160.27,90.04 161.22,90.04 163.89,87.38 166.86,87.38 169.54,84.69 172.79,84.69 174.52,82.96 176.72,82.96 178.76,80.93 v2(178.76,80.77)
  BOTTOM w0.102: RC237.1 v1(145.52,100.84) 145.52,98.28 v2(139.5,92.27) 139.18,92.27 139.04,92.13 138.09,92.13 UC1.J2
SIO_EXT_SMI#: length 74.8
  TOP w0.102: UE1.10 191.57,72.37 190.79,71.59 186.24,71.59 185.68,72.15 184.46,72.15 183.38,71.07 180.92,71.07 v2(179.63,69.79)
  IN2 w0.127: v2(179.63,69.79) 177.62,71.8 177.62,78.66 176.08,80.2 175.11,80.2 173.92,81.39 173.92,83.07 172.59,84.4 169.39,84.4 166.67,87.12 163.76,87.12 161.09,89.79 160.16,89.79 158.91,91.04 152.66,91.04 151.95,90.32 147.38,90.32 147.38,90.32 145.85,90.32 145.48,90.7 v2(143.4,90.7)
  BOTTOM w0.076: UC1.L6 136.23,90.21 139.17,90.21 139.43,90.48 139.8,90.48
  BOTTOM w0.102: 139.8,90.48 v1(142.82,90.48) 143.17,90.48 v2(143.4,90.7) 144,90.7 RC239.2
SIO_EXT_WAKE#: length 75.7
  TOP w0.102: UE1.116 186.75,68.36 v2(186.02,69.09)
  IN1 w0.127: v2(172.81,62.26) 176.84,66.29 177.83,66.29 178.27,66.73 184.51,66.73 185.58,67.8 185.58,68.65 v2(186.02,69.09)
  IN2 w0.127: v2(151.33,84.33) 155.14,84.33 156.47,85.66 158.93,85.66 159.89,84.71 160.65,84.71 161.16,84.2 161.16,83.57 161.54,83.18 163.7,83.18 164.52,82.36 166.02,82.36 167.84,80.54 167.84,79.78 168.6,79.02 168.6,71.7 170.3,70 170.3,69.05 171.75,67.6 171.75,63.32 v2(172.81,62.26)
  BOTTOM w0.076: 139.58,83.76 139.45,83.62 137.43,83.62 UC1.AD3
  BOTTOM w0.102: 139.58,83.76 142.29,83.76 v1(142.97,83.07) 143.56,83.65 144.19,83.65 144.78,83.07 148.28,83.07 148.91,83.7 150.75,83.7 151.33,84.28 v2(151.33,84.33) 151.76,84.33 152.2,84.77 RC387.1
SIO_PWRBTN#: length 89.6
  TOP w0.102: UE1.52 183.95,81.65 183.31,81.02 183.31,77.02 v2(183.06,76.78) ; RC1102.2 v2(145.22,61.09) 145.73,61.09 152.16,54.65 154.07,54.65 154.97,55.55 156.17,55.55 157.07,56.45 159.17,56.45 v1(160.82,58.1) 165.4,58.1 168.3,61 171.02,61 v2(171.51,60.52)
  IN1 w0.127: v2(183.06,76.78) 183.06,76.16 185.41,73.81 185.41,70.14 184.65,69.38 184.65,67.59 184.3,67.24 178.06,67.24 177.62,66.8 176.56,66.8 171.51,61.75 v2(171.51,60.52)
  BOTTOM w0.076: 132.15,68.71 132.15,68.71 131.02,69.83 131.02,70.51 129.49,72.05 129.49,74.27 UC1.BA15
  BOTTOM w0.102: 132.15,68.71 139.77,61.09 v2(145.22,61.09)
SIO_RCIN#: length 79
  TOP w0.102: v2(181.92,76.86) 182.83,77.76 182.83,81.23 183.55,81.95 UE1.53
  IN1 w0.127: v2(181.92,76.86) 181.92,75.8 182.94,74.79 182.94,72.52 180.87,70.45 180.44,70.45 180.22,70.23 176.73,70.23 175.15,68.64 173.35,68.64 172.81,68.1 166.37,68.1 v2(165.15,66.87)
  BOTTOM w0.076: UC1.AW13 130.9,75.76 130.9,75.52 130.75,75.03 130.75,74.95 130.7,74.79 130.63,74.72 130.4,74.72 130.2,74.52 130.2,73.83 129.82,73.44 129.82,72.19 130.14,71.86 131.14,71.86 131.36,71.64 131.36,70.18 132.83,68.71
  BOTTOM w0.102: 132.83,68.71 133.07,68.46 133.13,68.46 133.46,68.13 134.86,68.13 139.94,63.05 v1(140.73,63.05) 141.24,63.05 142.72,61.57 148.03,61.57 152.37,65.9 156.74,65.9 156.92,65.72 RC13.2 157.71,65.9 158.2,66.38 159.58,66.38 160.07,66.87 v2(165.15,66.87)
SIO_SLP_A#: length 1.7
  TOP w0.076: T4937.1 129.01,79.31 v2(128.95,79.38)
  BOTTOM w0.089: v2(128.95,79.38) UC1.AN16
SIO_SLP_LAN#: length 47.1
  TOP w0.102: v2(149.22,54.99) 149.22,53.78 149.89,53.11 154.65,53.11 155.64,54.1 v2(155.7,54.1) T4938.1
  BOTTOM w0.076: UC1.AW15 129.2,76.01 128.86,75.67 128.61,75.67 128.46,75.51 128.46,75.09 128.29,74.93 128.29,74.92 128.09,74.72 127.96,74.72 127.61,74.37 127.31,74.37 127.23,74.29 127.23,72.85 127.73,72.36 127.73,70.03 128.34,69.42
  BOTTOM w0.102: 128.34,69.42 128.34,68.45 141.8,54.99 v2(149.22,54.99) ; v2(155.7,54.1) 155.11,54.69 RC68.1
SIO_SLP_S0#: length 87.7
  TOP w0.102: UC15.2 143.06,116.15 142.87,115.96 142.87,114.62 143,114.48 143.28,114.21 144.93,114.21 145.05,114.33 145.59,114.87 147.12,114.87 149.94,112.05 149.94,105.83 150.81,104.97 150.81,101.04 151.45,100.39 151.45,98.06 155.47,94.04 159.55,94.04 163.38,90.21 163.38,82.88 163.82,82.44 v2(163.82,81.91) ; v2(131.73,78.07) 131.95,77.85 132.9,77.85 134.38,76.37 135.66,76.37 136.36,75.67 137.74,75.67 138.2,76.13 142.63,76.13 143.02,76.52 147.96,76.52 149.13,75.36 150.3,75.36 151.39,76.44 151.39,77.67 v1(152.36,78.64) 152.93,79.21 v2(153.15,79.21)
  IN2 w0.127: v2(163.82,81.91) 162.93,81.91 162.49,82.36 158.34,82.36 156.44,80.45 155.72,80.45 154.48,79.21 v2(153.15,79.21)
  BOTTOM w0.089: UC1.AT11 v2(131.73,78.07)
SIO_SLP_S3#: length 390.7
  TOP w0.102: v2(160.14,70.74) 160.39,70.49 DZ5.1 ; UE1.70 178.32,79.17 v2(179,78.49) 179.73,79.22 179.73,81.18 179.19,81.72 178.77,81.72 177.27,83.23 177.27,87.24 v2(180.78,90.74) ; 46.01,21.87 46.01,23.16 46.31,23.47 v1(50.96,23.47) 55.68,28.19 v2(56.19,28.19) ; 46.01,21.87 46.26,21.62 46.26,21.29 46.18,21.2 UZ2.3 ; 46.01,21.87 45.7,21.87 45.38,21.55 UZ2.5 ; v2(167.29,92.81) 167.29,92.19 RC1103.1 166.3,92.1 DZ1702.1 165.2,92.23 157.87,99.56 155.5,99.56 151.38,103.68 151.38,105.22 150.4,106.2 150.4,112.48 147.1,115.79 145.5,115.79 145.31,115.6 145.31,114.91 144.95,114.55 144.84,114.44 143.37,114.44 143.1,114.71 143.1,115.86 143.71,116.47 UC15.1 143.71,118.42 RZ75.1
  IN1 w0.127: v2(179,78.49) 176.84,78.49 176.64,78.69 175.4,78.69 174.75,78.05 169.05,78.05 167.49,76.49 165.34,76.49 162.51,73.66 162.11,73.66 160.14,71.69 v2(160.14,70.74) 160.08,70.8 159.31,70.8 158.74,71.37 158.74,71.9 159.82,72.98 159.82,76.26 157.09,78.99 157.09,82.13 155.53,83.69 153.35,83.69 152.83,84.21 152.1,84.21 151.45,84.86 150,84.86 147.68,82.54 147.68,81.28 146.91,80.52 144.84,80.52 142.3,77.97 138.6,77.97 137.68,77.05 133.95,77.05 132.58,78.42 132.58,79.82 132.01,80.39 131.61,80.39 130.92,81.09 130.49,81.09 130.3,80.9 130.3,79.06 130.05,78.81 v2(129.77,78.81) ; v2(167.29,92.81) 167.71,92.39 173.43,92.39 174.53,91.29 180.23,91.29 v2(180.78,90.74)
  IN2 w0.076: v2(129.77,78.81) 129.92,78.81 131.25,77.48 131.25,76.64 131.62,76.27 131.83,76.27 132.77,75.34 133.4,75.34 138.05,70.69
  IN2 w0.127: v2(160.65,52.9) 160.65,54.17 157.92,56.9 152.7,56.9 148.09,61.51 144.5,61.51 142.51,63.5 142.51,64.94 139.5,67.95 139.5,69.23 138.05,70.69
  BOTTOM w0.089: UC1.AP15 v2(129.77,78.81)
  BOTTOM w0.102: v2(160.65,52.9) 160.65,51.8 159.54,50.7 159.54,49.74 159.31,49.5 159.31,47.36 155.47,43.52 100.67,43.52 100.42,43.78 85.5,43.78 85.24,43.52 74.7,43.52 73.21,42.04 73.21,29.91 70.26,26.96 59.9,26.96 59.75,27.11 57.08,27.11 56.19,28 v2(56.19,28.19) 55.73,28.65 55.73,30.37 54.1,32 54.1,32.64 53.89,32.84 52.75,32.84 52,33.59 52,38.61 52.32,38.93 52.32,41.47 50.6,43.18 50.6,59.31 49.02,60.9 38.02,60.9 PR1204.2 ; CE74.1 178.68,78.93 179,78.61 v2(179,78.49)
SIO_SLP_S4#: length 297.3
  TOP w0.102: v2(173.57,80.24) 173.7,80.37 UE1.67 ; v2(176.63,54.74) 175.89,54.74 174.58,56.05 168.34,56.05 166.69,54.39 164.13,54.39 160.82,51.08 160.74,51.08 159.06,49.4 v2(158.87,49.4) ; v2(161.79,81.91) 161.28,82.42 161.28,85.53 159.57,87.25 159.57,88.9 158.79,89.68 v2(158.79,89.85) ; RZ1701.1 137.16,110.64 137.34,110.82 DZ1703.1 136.1,111.26 135.18,112.17 v2(135.18,112.78) ; PR201.1 v1(53.08,21.3) 52.93,21.3 52.25,21.97 52.25,24.38 54.73,26.86 56.38,26.86 56.67,27.15 56.67,27.97 56.95,28.26 57.52,28.26 v2(58.1,27.69)
  IN1 w0.127: v2(161.79,81.91) 161.85,81.91 163.82,79.95 167.43,79.95 167.9,80.42 168.52,80.42 169.62,79.32 171.89,79.32 172.84,80.26 173.55,80.26 v2(173.57,80.24)
  IN2 w0.127: v2(173.57,80.24) 173.05,79.71 173.05,78.34 174.24,77.15 176.16,77.15 176.73,76.58 176.73,70.56 178.12,69.17 178.12,66.85 177.03,65.76 177.03,55.61 176.63,55.21 v2(176.63,54.74)
  BOTTOM w0.076: 131.14,68.71 130.69,69.16 130.69,70.38 129.16,71.91 129.16,74.89 UC1.BA16
  BOTTOM w0.102: v2(158.79,89.85) 158.79,96.76 156.78,98.76 156.12,98.76 143.05,111.84 136.54,111.84 135.6,112.78 v2(135.18,112.78) ; v2(58.1,27.69) 58.41,27.37 60.06,27.37 60.24,27.19 70.11,27.19 72.95,30.04 72.95,42.16 74.54,43.75 85.15,43.75 85.4,44.01 100.51,44.01 100.77,43.75 154.97,43.75 158.78,47.57 158.78,49.32 v2(158.87,49.4) 159.31,49.85 159.31,51.63 158.68,52.26 158.68,53.51 157.13,55.06 157.13,55.68 156.66,56.15 152.63,56.15 152.14,56.64 152.13,56.64 152.12,56.65 150.91,56.65 149.53,58.03 141.82,58.03 131.28,68.56 131.14,68.71
  BOTTOM w0.508: PR803.1 v2(58.1,27.69)
SIO_SLP_S5#: length 277
  TOP w0.102: PQ711.2 v2(118.61,159.28)
  IN1 w0.127: v2(133.85,153.23) 133.91,153.23 135.06,152.08 135.06,150.56 136.96,148.65 136.96,142.75 138.04,141.67 138.04,137.04 136.52,135.52 136.52,130.62 143.6,123.53 143.6,117.69 144.76,116.53 144.76,112.03 145.63,111.15 145.63,101.63 148.65,98.62 150.74,98.62 151.89,99.76 153.28,99.76 153.76,99.28 156.71,99.28 158.89,97.1 158.89,95.99 165.79,89.09 170.24,89.09 171.88,87.45 173.7,87.45 174.34,86.8 180.52,86.8 181.22,86.11 187.38,86.11 188.02,85.47 193.75,85.47 195.26,83.96 195.26,79.93 194.01,78.68 194.01,77.34 193.69,77.02 193.69,75.89 193.19,75.38 193.19,69.12 192.62,68.56 192.62,67.84 193.91,66.55 194.54,66.55 195.95,65.13 195.95,62.25 195.26,61.55 195.26,59.31 193.64,57.69 193.64,56.17 191.64,54.17 181.96,54.17 180.75,52.95 175.75,52.95 174.19,51.39 174.19,46.31 168.28,40.4 160.95,40.4 v2(160.2,39.65)
  IN2 w0.127: v2(133.85,153.23) 133.32,153.75 133.32,154.69 133.66,155.02 133.66,157.26 132.35,158.57 130.03,158.57 129.2,159.4 129.2,163.23 126.92,165.51 121.43,165.51 119.6,163.69 119.6,160.27 v2(118.61,159.28) ; v2(148.27,57.62) 148.27,57.09 148.58,56.77 148.58,56.28 150.26,54.61 150.75,54.61 151.74,53.62 153.05,53.62 154.32,52.34 154.32,51.52 154.55,51.29 154.55,49.78 155.76,48.58 158.34,48.58 160.2,46.72 v2(160.2,39.65)
  BOTTOM w0.076: 130.82,68.71 130.52,69 130.52,70.31 128.99,71.84 128.99,75.38 UC1.AY16
  BOTTOM w0.102: 130.82,68.71 141.9,57.62 v1(147.53,57.62) v2(148.27,57.62)
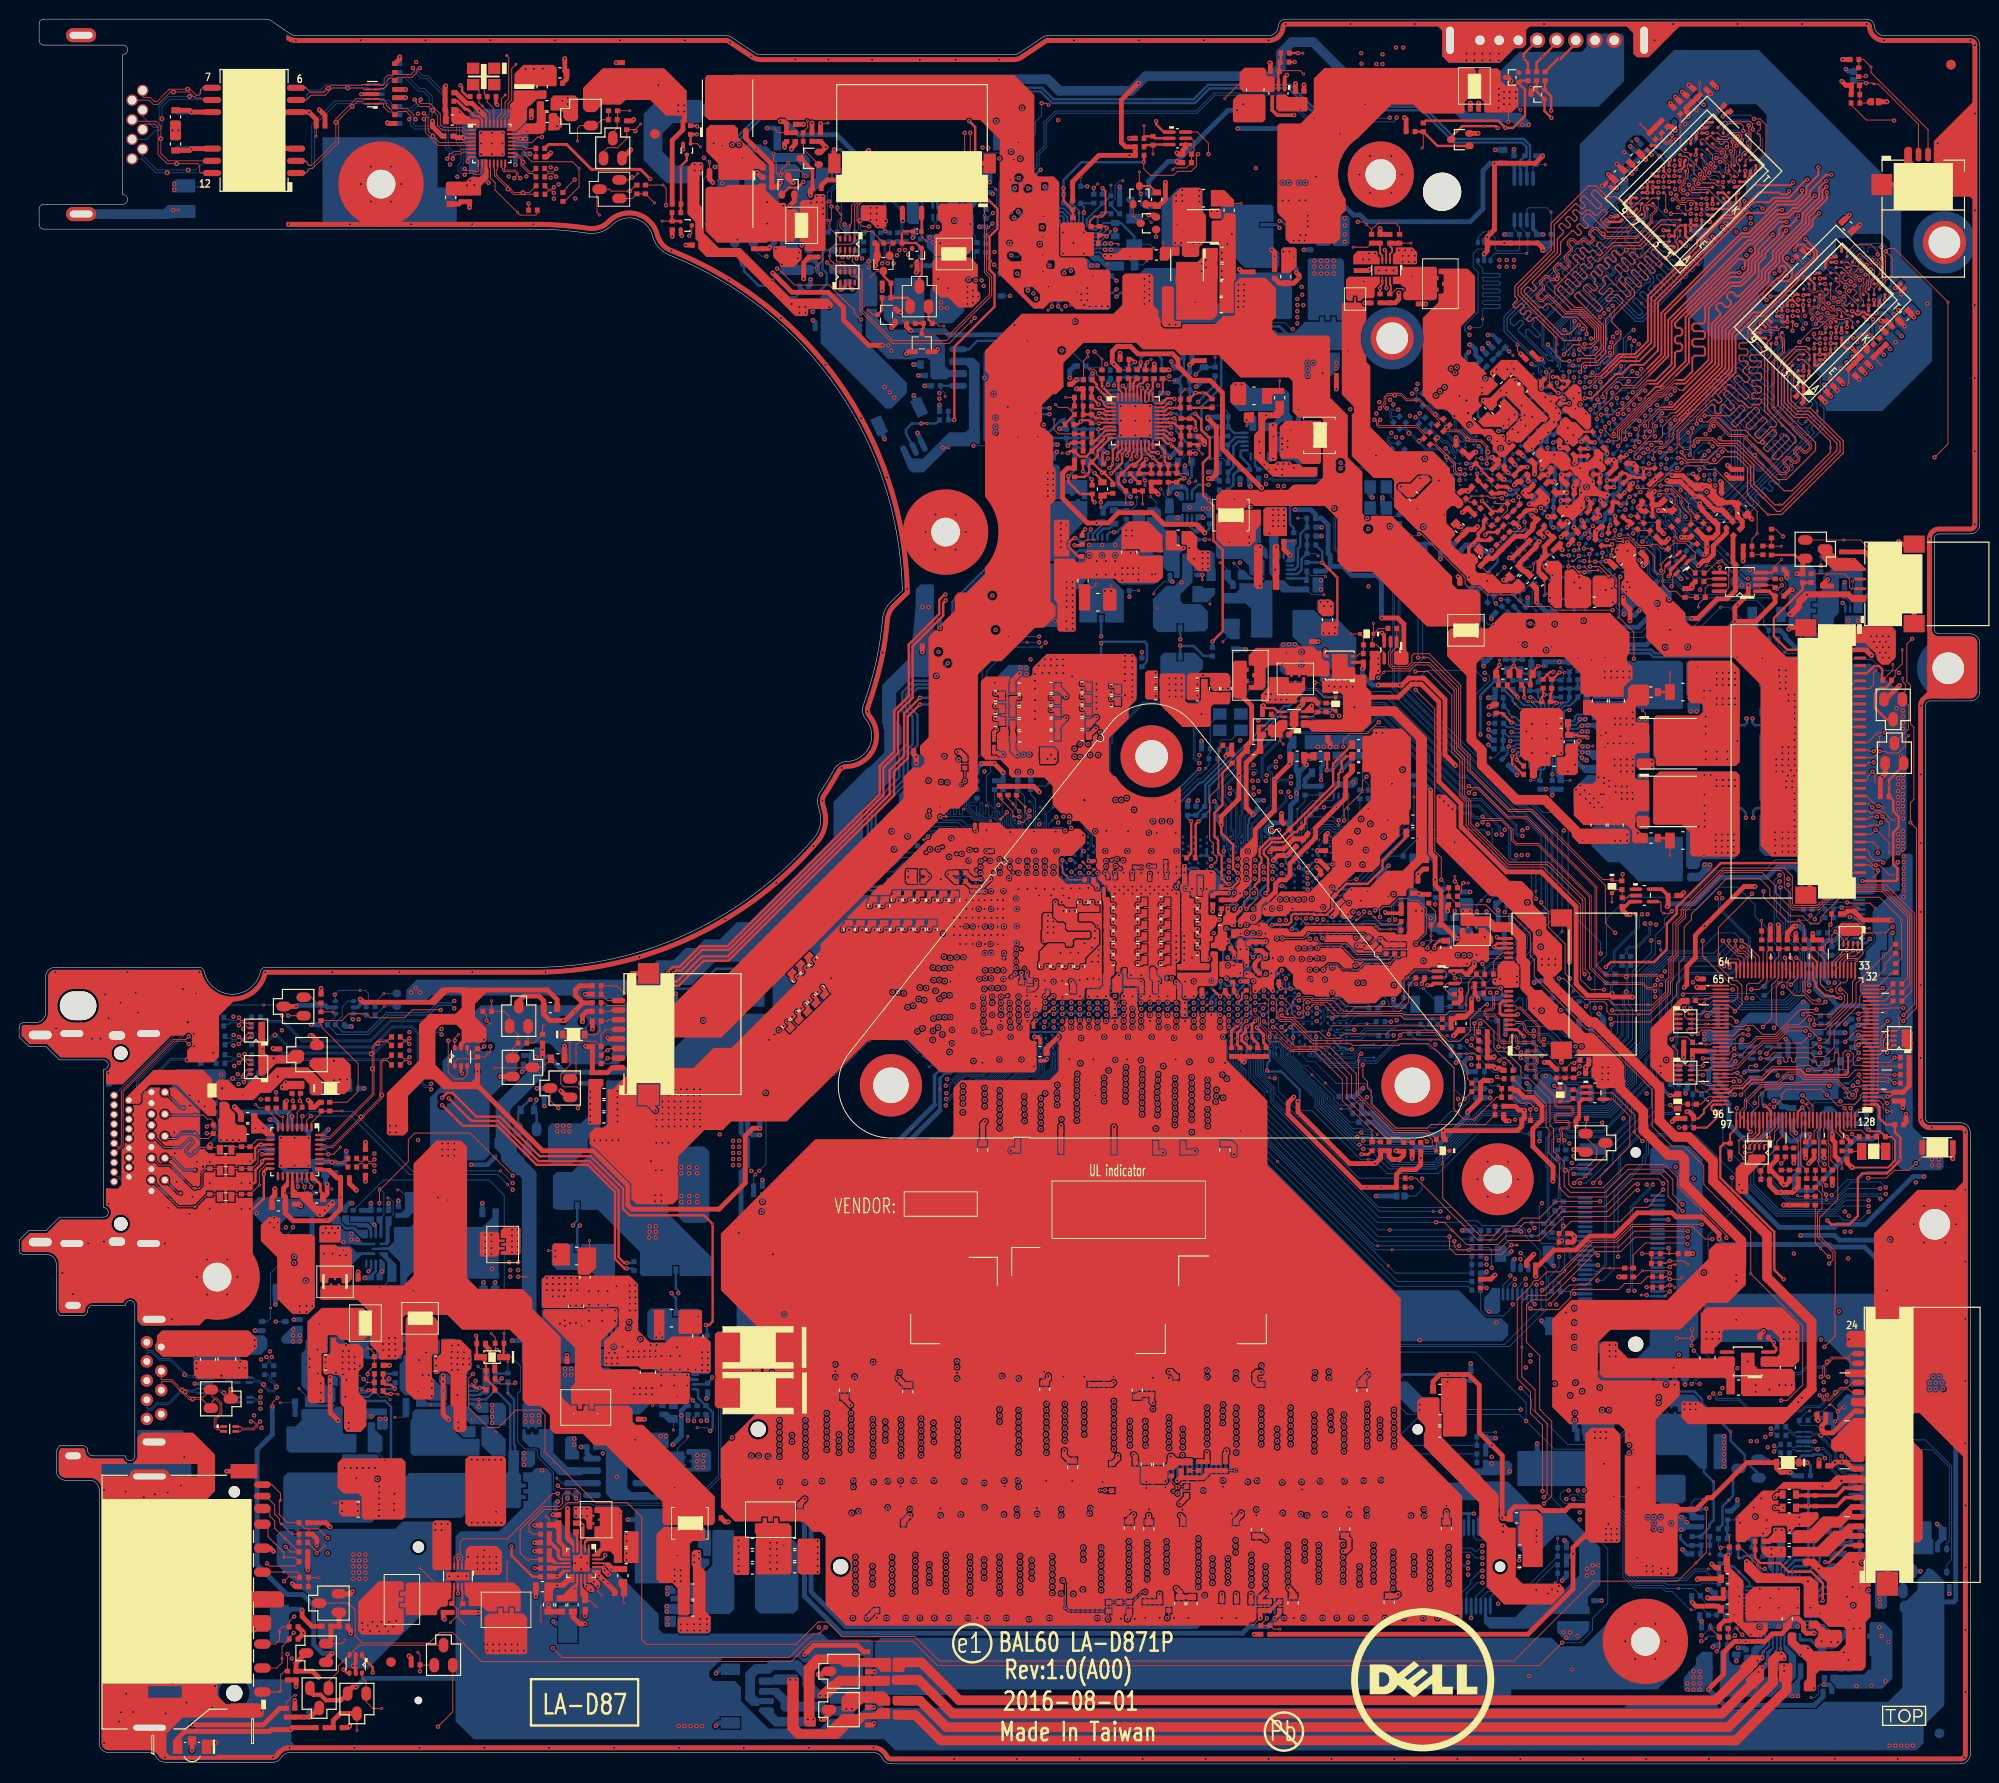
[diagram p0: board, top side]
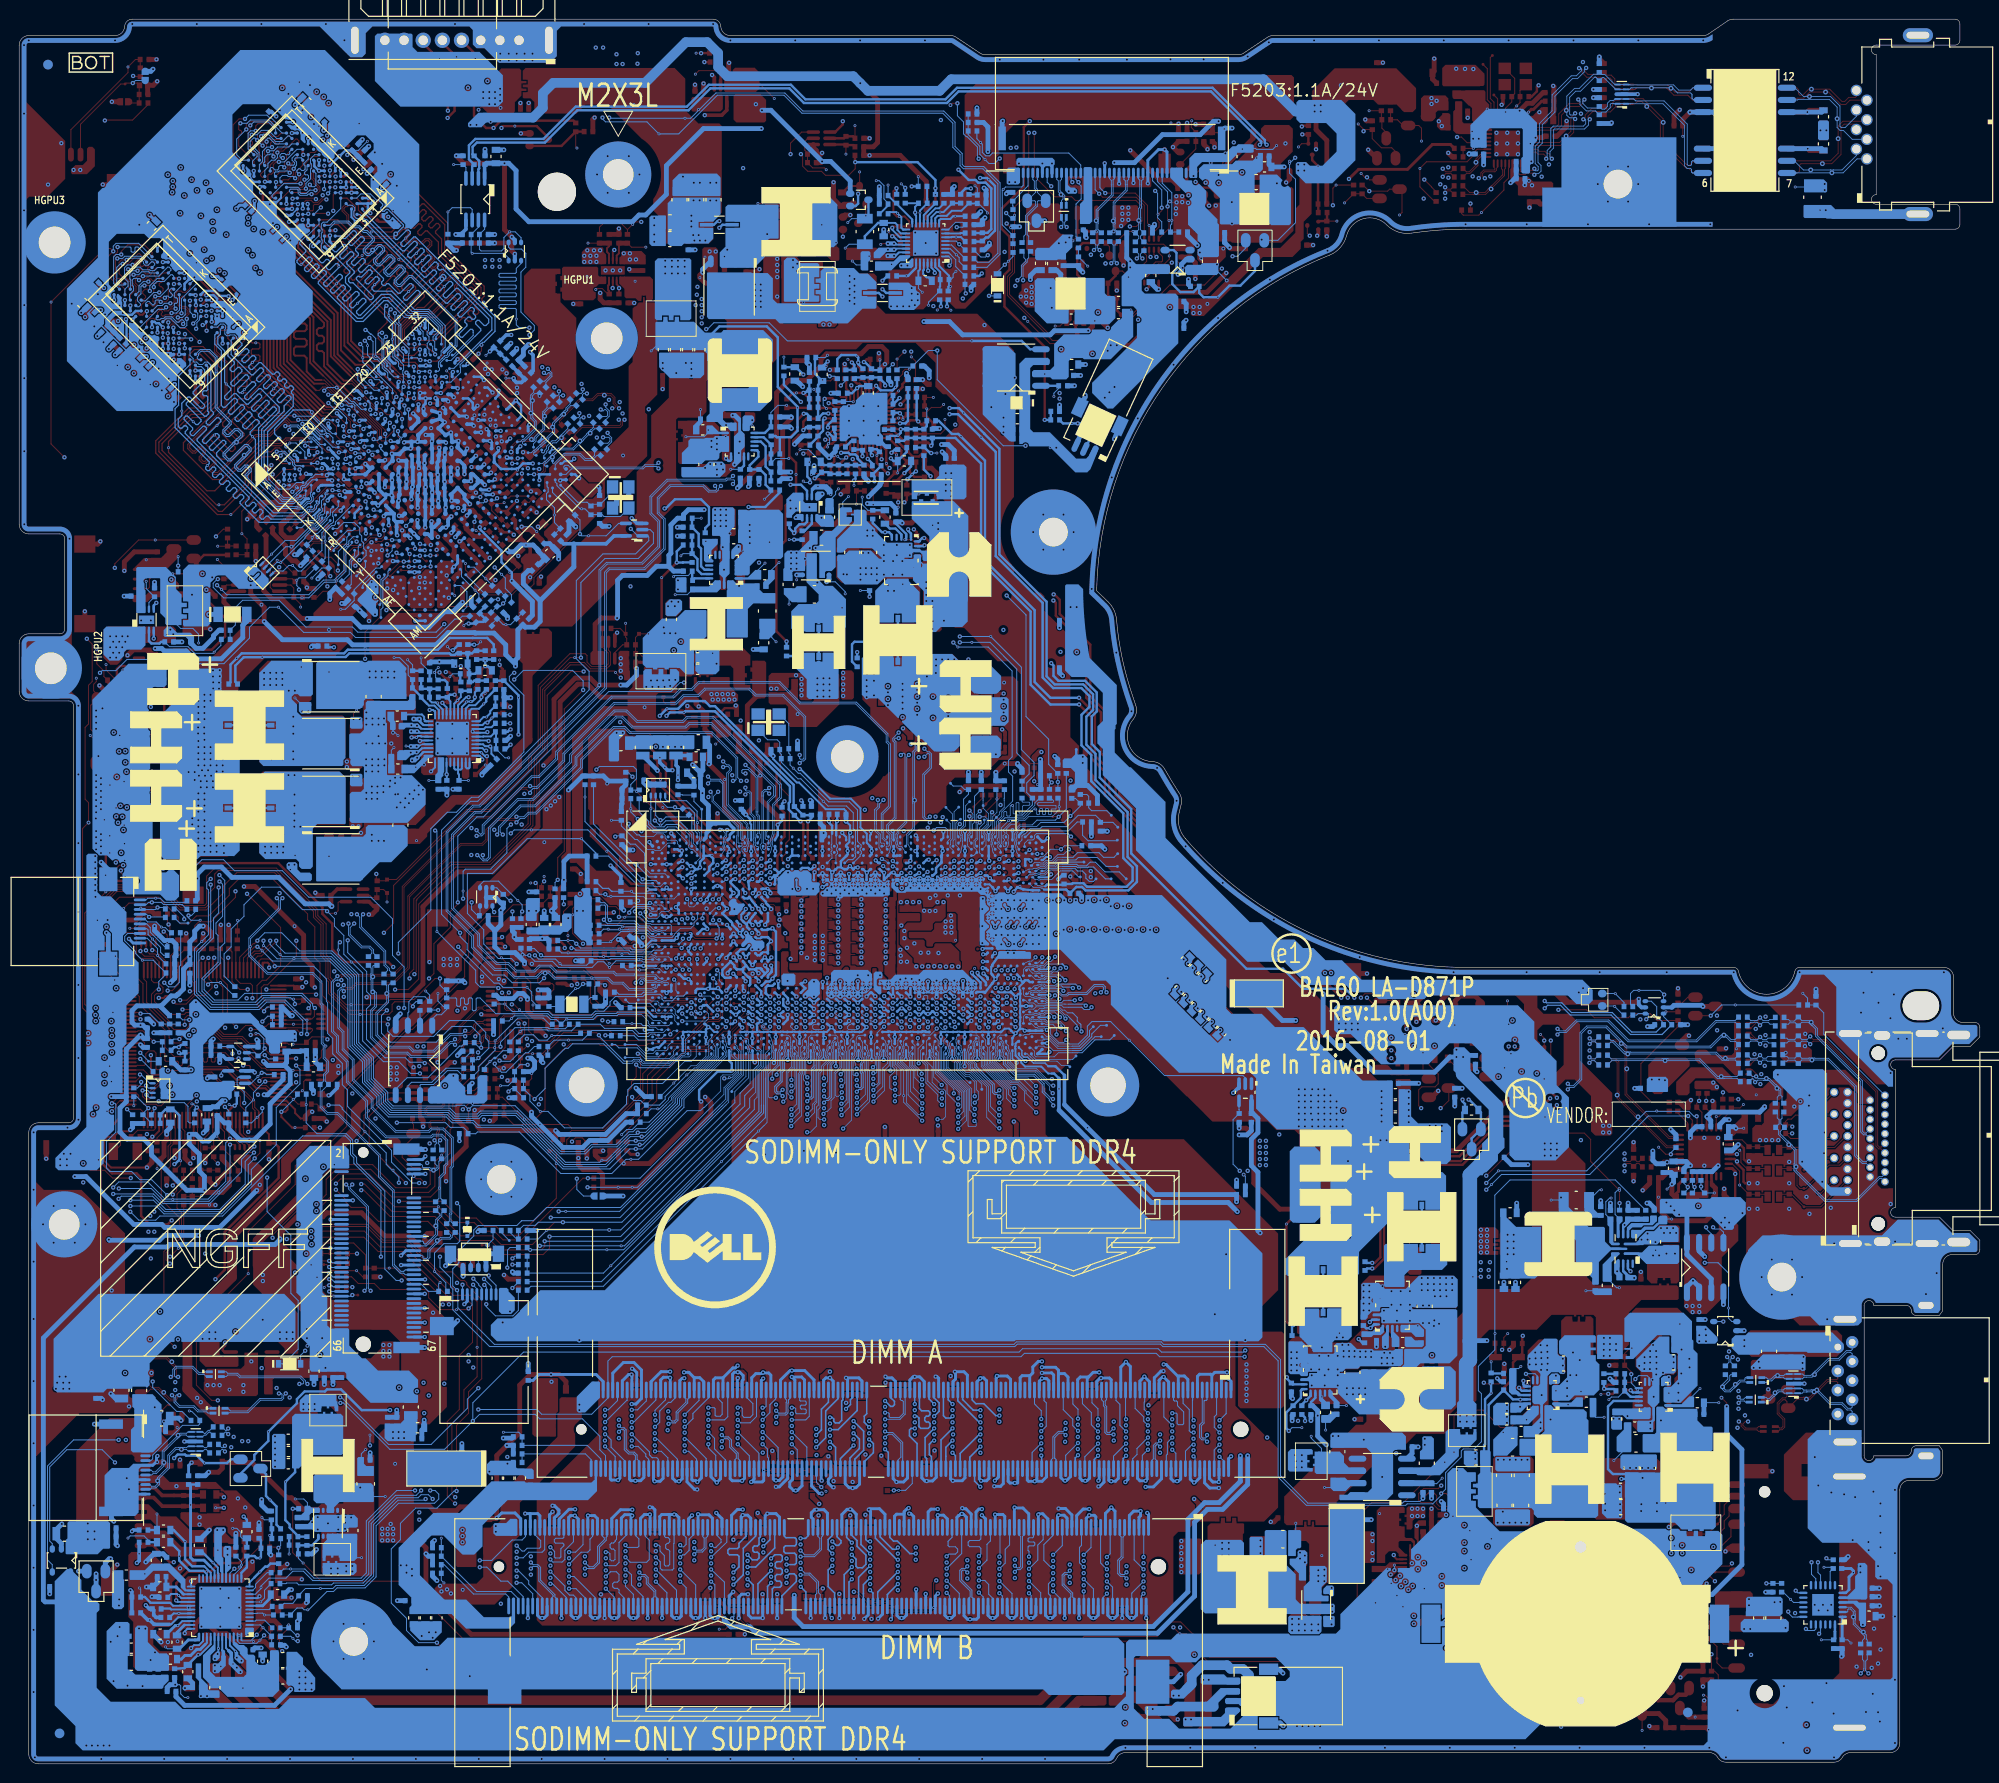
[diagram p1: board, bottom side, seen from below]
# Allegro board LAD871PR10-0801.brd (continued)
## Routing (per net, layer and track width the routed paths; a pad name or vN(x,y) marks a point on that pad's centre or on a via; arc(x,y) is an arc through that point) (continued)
SIO_SLP_SUS#: length 8.1
  TOP w0.203: RC1107.1 v1(175.77,66.36) 176.08,66.36 177.2,67.48 v2(177.2,68.01) 176.78,68.01 176.56,68.23 176.56,68.55 176.78,68.77 UE1.96
  BOTTOM w0.102: v2(177.2,68.01) 175.52,69.68 RC76.2
SIO_SLP_SUS#_R: length 77.6
  IN2 w0.076: 139.25,70.55 138.95,70.85 138.86,70.85 133.27,76.44 132.39,76.44 132.29,76.54 132.29,77.38 132.05,77.62 131.65,77.62 131.31,77.97 131.31,78.83 v2(130.77,79.36)
  IN2 w0.127: 139.25,70.55 140.13,69.67 140.13,68.38 143.06,65.45 143.06,63.79 144.83,62.01 148.3,62.01 152.91,57.4 162.24,57.4 163.89,55.75 163.89,51.18 v2(164.65,50.42)
  BOTTOM w0.076: v2(130.77,79.36) 130.37,79.77 UC1.AN15
  BOTTOM w0.102: v2(164.65,50.42) 165.22,50.42 166.4,51.6 166.4,59.73 169.34,62.68 169.34,63.25 169.75,63.66 169.75,65.06 170.42,65.72 173.48,65.72 174.61,66.85 v1(174.61,68.76) RC76.1
SIO_SLP_WLAN#: length 4.6
  BOTTOM w0.076: T4945.1 130.21,70.21 128.72,71.7 UC1.BB17
SLEEVE:
  vias: v1(183.83,22.29) v2(183.26,24.39) v2(183.89,24.38)
SM_RCOMP0: length 4.8
  TOP w0.102: v2(128.03,78.11) 127.56,77.64 127.56,77.34 127.15,76.93
  TOP w0.305: 127.15,76.93 126.93,76.93 v1(126.88,76.87) 126.49,76.48 RC5.1
  BOTTOM w0.254: UC1.AR18 128.46,78.45 v2(128.03,78.11)
SM_RCOMP1: length 3.8
  TOP w0.102: v2(128.03,77.47) 127.44,76.88 127.44,76.56
  TOP w0.305: 127.44,76.56 127.12,76.24 v1(127.12,75.6) 127.12,74.94 RC6.1
  BOTTOM w0.254: v2(128.03,77.47) 128.46,77.8 UC1.AT18
SM_RCOMP2: length 3.3
  TOP w0.305: RC7.1 127.55,75.47 127.55,75.93 127.94,76.33 127.94,76.77 128.08,76.9 v2(128.08,76.89)
  BOTTOM w0.254: UC1.AU18 128.46,77.16 128.43,77.16 128.08,76.9 v2(128.08,76.89)
SMBCLK: length 25.3
  IN2 w0.089: 137.47,88.8 137.31,88.95 136.63,88.95 136.28,88.6 134.71,88.6 134.62,88.51 134.62,88.38 v2(134.83,88.18)
  IN2 w0.127: 137.47,88.8 138.64,87.63 140.12,87.63 140.43,87.31 141.6,87.31 142.83,88.54 144.3,88.54 145.09,87.76 151.95,87.76 v2(153.09,88.9) 153.54,88.46 154.55,88.46 154.93,88.84 v2(155,88.84)
  BOTTOM w0.089: UC1.R7 v2(134.83,88.18)
  BOTTOM w0.102: QC2.6 155.17,89.08 155,88.9 v2(155,88.84) ; v2(153.09,88.9) RC12.1
SMBDATA: length 27.8
  IN2 w0.089: v2(134.24,88.18) 134.45,88.38 134.45,88.58 134.64,88.78 136.2,88.78 136.55,89.13 137.5,89.13 137.65,88.98
  IN2 w0.127: v2(152.08,88.9) 151.66,88.48 148.68,88.48 148.46,88.71 147.12,88.71 146.9,88.48 145.32,88.48 144.56,89.24 142.27,89.24 141.17,88.14 138.49,88.14 137.65,88.98
  BOTTOM w0.089: UC1.R8 v2(134.24,88.18)
  BOTTOM w0.102: RC14.1 152.2,88.77 v2(152.08,88.9) 152.08,89.6 v1(152.53,90.05) 154.54,92.06 156.09,92.06 156.47,91.68 QC2.3
SML0_SMBCLK: length 12.7
  BOTTOM w0.076: UC1.R9 133.78,88.12 134.14,87.76 134.14,87.47 134.47,87.15 135.57,87.15 136.17,86.54 136.17,86.46 136.44,86.2 138.14,86.2 138.32,86.11 138.74,86.11 139.25,86.62 140.14,86.62 140.38,86.85
  BOTTOM w0.102: 140.38,86.85 140.89,86.85 140.94,86.8 141.77,86.8 v1(142.82,85.75) 142.89,85.69 RC19.1
SML0_SMBDATA: length 6.9
  BOTTOM w0.076: 140.33,87.06 140.21,86.94 140.21,86.92 140.07,86.78 139.18,86.78 138.97,86.57 138.91,86.57 138.62,86.28 138.36,86.28 138.11,86.4 138.11,86.4 138.1,86.4 137.96,86.54 UC1.W2
  BOTTOM w0.102: RC20.1 144.05,86.6 143.59,87.06 v1(143.1,87.06) 143.03,86.99 141.01,86.99 140.95,87.06 140.33,87.06
SML1CLK: length 276.1
  TOP w0.102: QV1.6 172.52,123.82 172.52,122.94 v2(172.4,122.81) ; RE427.1 v2(195.65,73.66) 195.16,73.17 UE1.12
  IN1 w0.127: v2(139.63,97.28) 138.23,97.28 137.39,96.44 137.39,95.91 137.52,95.78 138.44,95.78 138.57,95.65 138.57,95.4 138.44,95.27 137.52,95.27 137.39,95.14 137.39,94.89 137.52,94.76 138.44,94.76 138.57,94.64 138.57,94.38 138.44,94.26 137.52,94.26 137.39,94.13 137.39,93.87 137.52,93.75 138.12,93.75 138.25,93.62 138.25,93.37 138.12,93.24 137.52,93.24 137.39,93.11 137.39,92.86 137.52,92.73 138.88,92.73 139.01,92.6 139.01,92.35 138.88,92.22 137.52,92.22 137.39,92.1 137.39,91.84 137.52,91.72 138.38,91.72 138.5,91.59 138.5,91.33 138.38,91.21 137.52,91.21 137.39,91.08 137.39,90.72 137.52,90.59 138.48,90.59 138.61,90.47 138.61,90.21 138.48,90.09 137.52,90.09 137.39,89.96 137.39,89.7 137.52,89.58 138.04,89.58 138.17,89.45 138.17,89.2 138.04,89.07 137.52,89.07 137.39,88.94 137.39,88.47 138.17,87.69 140.22,87.69 140.6,87.31 141.09,87.31 141.32,87.54 143.1,87.54 143.55,87.99 v2(143.55,88.04) ; v2(175.76,51.24) 176.27,51.75 193.35,51.75 195.87,54.27 195.87,57.19 197.06,58.39 197.06,60.84 198.54,62.32 198.54,63.1 197.73,63.9 197.73,65.88 195.85,67.76 195.85,69.72 194.98,70.6 194.98,73.05 195.59,73.66 v2(195.65,73.66)
  IN2 w0.127: 152.29,111.19 151.69,110.6 151.69,107.19 148.49,103.98 148.49,103.92 146.23,101.66 146.23,100.77 143.57,98.11 142.04,98.11 141.21,97.28 v2(139.63,97.28) ; 152.29,111.19 151.76,111.72 151.76,125.32 149.47,127.61 149.47,142.7 150.93,144.16 150.93,146.24 150.3,146.88 150.3,148.78 v2(151.31,149.8) ; 152.29,111.19 152.29,111.27 153.98,112.97 153.98,114.77 154.23,115.02 154.23,119.64 153.54,120.33 153.54,121.41 154.04,121.91 155.07,121.91 155.95,121.03 155.95,120.01 156.58,119.39 161.67,119.39 162.26,118.8 164.11,118.8 166.06,120.75 168.32,120.75 169.51,121.95 171.54,121.95 v2(172.4,122.81) ; v2(175.76,51.24) 175.11,51.9 175.11,66.35 176.02,67.26 176.02,68.76 172.94,71.83 172.94,75.91 171.33,77.52 171.33,80.64 172.39,81.7 172.39,82.62 171.92,83.08 167.82,83.08 165.81,85.09 162.36,85.09 161.41,86.04 160.65,86.04 159.32,87.38 155.24,87.38 155.12,87.25 144.34,87.25 v2(143.55,88.04)
  BOTTOM w0.076: UC1.W3 137.36,86.74 137.52,86.74 137.74,86.82 137.87,86.82 137.87,86.82 138.1,86.75 138.23,86.75 138.36,86.81 138.52,86.81 138.91,87.21
  BOTTOM w0.102: 138.91,87.21 139.89,87.21 140.31,87.63 143.19,87.63 143.55,87.99 v2(143.55,88.04) 143.37,88.21 143.37,89.46 143.49,89.57 143.84,89.57 RC15.1 ; Q2601.3 152.19,156.48 152.69,155.98 152.69,155.56 152.79,155.46 154.39,155.46 154.49,155.35 154.49,155.15 154.39,155.05 152.79,155.05 152.69,154.95 152.69,154.74 152.79,154.64 154.39,154.64 154.49,154.54 154.49,154.34 154.39,154.24 152.79,154.24 152.69,154.13 152.69,153.93 152.79,153.83 154.39,153.83 154.49,153.73 154.49,153.52 154.39,153.42 152.79,153.42 152.69,153.32 152.69,153.12 152.79,153.02 154.39,153.02 154.49,152.92 154.49,152.71 154.39,152.61 152.79,152.61 152.69,152.51 152.69,152.31 152.79,152.2 154.39,152.2 154.49,152.1 154.49,151.9 154.39,151.8 152.79,151.8 152.69,151.7 v1(152.69,150.69) 152.69,150.09 152.39,149.8 v2(151.31,149.8)
SML1DATA: length 289.4
  TOP w0.102: v2(171.31,124.46) 171.31,125.15 172.01,125.86 172.72,125.86 QV1.3 ; v2(181.18,72.83) 180.54,72.83 180.45,72.74 180.45,72.43 180.55,72.33 181.81,72.33 183.17,73.69 184,73.69 184.1,73.58 184.1,73.29 184.2,73.19 184.41,73.19 184.51,73.29 184.51,73.56 184.63,73.69 184.81,73.69 184.91,73.58 184.91,73.29 185.01,73.19 185.22,73.19 185.32,73.29 185.32,73.56 185.45,73.69 186.66,73.69 187.06,73.28 187.43,73.28 187.53,73.18 187.53,72.91 187.63,72.81 187.84,72.81 187.94,72.91 187.94,73.18 188.04,73.28 188.24,73.28 188.34,73.18 188.34,72.91 188.45,72.81 188.65,72.81 188.75,72.91 188.75,73.18 188.85,73.28 189.25,73.28 189.35,73.38 189.35,74.07 189.45,74.17 189.73,74.17 189.83,74.07 189.83,72.5 189.93,72.4 190.18,72.4 190.28,72.5 190.28,74.14 190.49,74.36 191.03,74.36 191.34,74.05 191.34,73 191.49,72.85 192.25,72.85 192.34,72.77 UE1.11 v1(195.12,72.77) 196.26,72.77 RE426.1
  IN1 w0.127: v2(181.18,72.83) 180.78,72.83 180.65,72.96 180.65,74.98 180.52,75.11 180.21,75.11 180.08,74.98 180.08,72.66 179.98,72.56 179.7,72.56 179.57,72.68 179.57,74.98 179.44,75.11 179.06,75.11 178.94,75.23 178.94,75.63 178.81,75.76 178.43,75.76 178.27,75.6 178.27,74.04 178.14,73.91 177.89,73.91 177.76,74.04 177.76,75.63 177.63,75.76 177.38,75.76 177.25,75.63 177.25,72.86 177.13,72.73 176.87,72.73 176.75,72.86 176.75,76.14 176.62,76.27 176.36,76.27 176.24,76.14 176.24,74.16 176.11,74.03 175.86,74.03 175.73,74.16 175.73,74.87 175.6,74.99 175.35,74.99 175.22,74.87 175.22,74.16 175.09,74.03 174.84,74.03 174.71,74.16 174.71,74.87 174.59,74.99 174.33,74.99 174.21,74.87 174.21,74.22 174.08,74.09 173.82,74.09 173.7,74.22 173.7,74.87 173.57,74.99 173.22,74.99 173.03,74.8 173.03,73.6 172.84,73.41 v2(171.82,73.41)
  IN2 w0.127: v2(171.82,73.41) 170.95,73.41 170.82,73.53 170.82,73.89 170.95,74.02 171.89,74.02 172.01,74.14 172.01,74.4 171.89,74.53 170.95,74.53 170.82,74.65 170.82,74.91 170.95,75.03 171.58,75.03 171.7,75.16 171.7,75.41 171.58,75.54 170.95,75.54 170.82,75.67 170.82,75.92 170.95,76.05 171.58,76.05 171.7,76.18 171.7,76.43 171.58,76.56 170.95,76.56 170.82,76.68 170.82,79.16 165.46,84.52 v2(164.99,84.52) 164.97,84.52 164.71,84.77 162.3,84.77 161.28,85.79 160.52,85.79 159.19,87.12 155.71,87.12 155.33,86.74 152.11,86.74 151.98,86.61 151.98,86.28 151.86,86.16 151.6,86.16 151.48,86.28 151.48,86.61 151.35,86.74 151.09,86.74 150.97,86.61 150.97,86.28 150.84,86.16 150.59,86.16 150.46,86.28 150.46,86.61 150.33,86.74 142.59,86.74 142.36,86.97 142.36,87.36 142.93,87.93 v2(142.93,88.01) ; v2(151.31,149.03) 151.31,148.91 150.55,148.15 150.55,147.07 151.25,146.37 151.25,143.93 150.63,143.31 150.63,137.15 149.84,136.36 149.84,127.97 152.27,125.54 152.27,114.24 152.71,113.79 v2(152.9,113.79) 153.6,113.79 153.73,113.92 153.73,114.49 153.62,114.6 153.26,114.6 153.1,114.76 153.1,115 153.22,115.13 153.85,115.13 153.98,115.25 153.98,115.63 153.85,115.76 153,115.76 152.87,115.89 152.87,116.24 152.96,116.33 153.85,116.33 153.98,116.46 153.98,116.76 153.85,116.89 152.9,116.89 152.77,117.01 152.77,117.27 152.9,117.39 153.85,117.39 153.98,117.52 153.98,117.78 153.85,117.9 152.9,117.9 152.77,118.03 152.77,118.28 152.9,118.41 153.85,118.41 153.98,118.54 153.98,118.87 153.85,119 152.9,119 152.77,119.13 152.77,121.98 152.96,122.17 154.27,122.17 154.4,122.3 154.4,122.94 154.53,123.06 154.78,123.06 154.91,122.94 154.91,122.3 155.03,122.17 155.44,122.17 155.57,122.3 155.57,123.48 155.7,123.61 156.01,123.61 156.14,123.48 156.14,122.67 156.27,122.54 156.63,122.54 156.76,122.67 156.76,123.53 156.89,123.66 157.14,123.66 157.27,123.53 157.27,122.67 157.39,122.54 157.65,122.54 157.78,122.67 157.78,123.53 157.9,123.66 158.16,123.66 158.28,123.53 158.28,122.67 158.41,122.54 159.44,122.54 159.57,122.42 159.57,122.16 159.44,122.03 156.46,122.03 156.33,121.91 156.33,120 156.58,119.75 157.27,119.75 157.4,119.87 157.4,121.13 157.52,121.26 157.78,121.26 157.91,121.13 157.91,119.81 158.03,119.69 158.74,119.69 158.93,119.88 158.93,121.34 159.06,121.47 159.31,121.47 159.44,121.34 159.44,119.81 159.56,119.68 160.07,119.68 160.2,119.81 160.2,121.09 160.33,121.22 160.58,121.22 160.71,121.09 160.71,119.83 160.84,119.7 161.09,119.7 161.22,119.83 161.22,121.09 161.34,121.22 161.6,121.22 161.72,121.09 161.72,119.79 161.85,119.66 162.11,119.66 162.23,119.79 162.23,121.09 162.36,121.22 162.61,121.22 162.74,121.09 162.74,119.79 162.87,119.66 163.12,119.66 163.25,119.79 163.25,121.09 163.38,121.22 163.63,121.22 163.76,121.09 163.76,119.48 163.88,119.36 164.2,119.36 164.33,119.48 164.33,120.97 164.4,121.04 168.13,121.04 168.86,121.77 168.86,121.95 168.42,122.39 168.42,122.57 168.6,122.75 168.78,122.75 169.25,122.28 169.43,122.28 169.61,122.46 169.61,122.64 168.51,123.74 168.51,123.92 168.69,124.1 168.87,124.1 170.65,122.32 170.83,122.32 171.01,122.5 171.01,122.68 169.59,124.1 169.59,124.32 169.77,124.5 169.95,124.5 171.36,123.09 171.54,123.09 171.77,123.32 171.77,123.5 171.31,123.96 v2(171.31,124.46)
  BOTTOM w0.076: UC1.V3 137.11,86.94 137.57,86.94 137.71,86.98 137.9,86.98 137.92,86.98 138.12,86.92 138.2,86.92 138.33,86.98 138.35,86.98 138.77,87.4
  BOTTOM w0.102: 138.77,87.4 139.81,87.4 140.34,87.92 142.84,87.92 v2(142.93,88.01) 143.18,88.26 143.18,89.54 143.46,89.81 143.85,89.81 RC17.1 ; v2(151.31,149.03) 150.81,149.54 150.81,150.03 152.2,151.42 152.2,155.59 151.69,156.1 151.69,157.54 152.14,157.99 153.28,157.99 153.49,158.19 Q2601.6 ; v2(164.99,84.52) 164.99,85.68 161.6,89.07 161.6,97.54 159.89,99.25 158.93,99.25 157.37,100.81 156.62,100.81 151.9,105.53 151.9,111.46 153.41,112.97 153.41,113.41 153.03,113.79 v2(152.9,113.79)
SNUB_+1.5VGPU: length 1.1
  TOP w0.102: PC1408.1 v1(131.5,144.25)
SNUB_+1VALW: length 1.1
  BOTTOM w0.102: 126.04,117.96 126.04,117.49 v1(125.58,117.03)
SOC_XDP_TDI: length 7.5
  TOP w0.102: v2(104.33,99.36) 103.69,100 T45.1 103.16,100.66 RC351.1
  BOTTOM w0.076: UC1.D60 104.64,95.3 104.93,95.59 104.93,96.3 104.71,96.52 104.71,98.15 104.71,98.15 104.71,98.98 104.33,99.36 v2(104.33,99.36)
  BOTTOM w0.102: UC1.D60 104.97,94.73 UC1.D59
SOC_XDP_TDO: length 10.4
  TOP w0.102: RC349.1 102.27,100.73 103.67,99.33 103.67,98.87 T41.1 103.77,98.78 v2(104.34,98.78)
  IN1 w0.127: v2(106.42,98.02) 105.11,98.02 104.35,98.78 v2(104.34,98.78)
  BOTTOM w0.076: v2(104.34,98.78) 103.77,98.78 103.57,98.58 103.57,98.01 104.16,97.41 104.16,96.77 UC1.A61 ; v2(106.42,98.02) 106.66,97.78 106.66,96.78 UC1.A56
SOC_XDP_TMS: length 10.6
  TOP w0.102: RC350.1 104.05,100.73 T44.1 104.96,99.28 v2(105.41,98.82) 104.78,98.19 v2(104.34,98.19)
  BOTTOM w0.076: v2(104.34,98.19) 104.55,97.98 104.55,96.45 104.77,96.23 104.77,95.84 UC1.C60 ; v2(105.41,98.82) 105.42,98.82 105.42,97.12 105.64,96.91 105.64,96.55 105.6,96.45 105.6,96.26 105.64,96.17 105.64,95.92 105.62,95.88 105.58,95.72 105.24,95.38 UC1.C59
SOC_XDP_TRST#: length 12
  TOP w0.102: T46.1 103.05,99.2 v2(103.05,99.25)
  IN1 w0.127: v2(105.41,99.43) 105.02,99.82 103.62,99.82 v2(103.05,99.25)
  BOTTOM w0.076: UC1.B59 105.41,96.24 105.41,96.46 105.47,96.58 105.47,96.84 105.26,97.05 105.26,98.46 105.04,98.67 105.04,99.06 v2(105.41,99.43) ; v2(103.05,99.25) 103.17,99.14 103.17,97.94 103.82,97.29 103.82,97.08 103.65,96.91 103.65,96.54 103.66,96.51 103.68,96.45 103.68,95.84 103.69,95.83 103.69,95.77 UC1.C61
SPKR: length 96.3
  TOP w0.076: 139.12,76.97 137.02,76.97 136.62,76.57 v2(136.62,76.09)
  TOP w0.102: 139.12,76.97 148.3,76.97 RC183.2
  IN1 w0.127: v2(165.86,36.89) 165.86,37.15 165.22,37.78 157.35,37.78 154.59,40.54 154.59,48.72 151.64,51.67 151.64,56.47 149.07,59.05 149.07,68.33 148.69,68.71 148.69,71.91 147.92,72.67 147.92,73.66 146.64,74.94 138.63,74.94 137.49,76.09 v2(136.62,76.09)
  BOTTOM w0.076: v2(136.62,76.09) 136.62,76.15 136.31,76.46 UC1.AW5
  BOTTOM w0.254: v2(165.86,36.89) 168.81,36.89 170.97,39.05 172.44,39.05 172.65,38.84 174.77,38.84 175.57,38.04 175.57,37.61 v1(178.56,34.63) 178.56,33.68 180.02,32.22 180.02,31.69 181.46,30.24 D2701.3
SRTCRST#: length 23.7
  TOP w0.076: 132.53,74.3 131.52,75.31 130.46,75.31 130.1,75.67 130.1,76.35 129.33,77.13 129.33,77.61 129.05,77.9 128.85,77.9 v1(128.53,78.22) 128.53,78.92 v2(128.05,79.4)
  TOP w0.102: 132.53,74.3 135.12,74.3 138.04,71.38 138.04,69.17 141.14,66.07 CC24.1 RC56.1
  BOTTOM w0.102: v2(128.05,79.4) 128.42,79.77 UC1.AN18
SUS_STAT#/LPCPD#: length 14.1
  BOTTOM w0.076: 137.03,68.72 136.5,69.25 136.5,69.5 133.74,72.26 133.71,72.26 132.07,73.9 132.07,74.4 132.34,74.66 UC1.BA11
  BOTTOM w0.102: 137.03,68.72 138.82,66.93 RC369.1 139.82,66.93 140.6,66.15 141.17,66.15 v1(141.7,65.63)
SUSCLK: length 95.2
  TOP w0.102: v2(159.71,47.93) 161.73,49.95 163.51,49.95 165.26,51.7 v1(165.94,51.7) RC48.1 R5805.1 168.4,53.06 169.66,54.32 173.93,54.32 v2(174.05,54.2) ; R6520.1 191.5,65.4 v2(191.22,65.68)
  IN1 w0.127: v2(191.22,65.68) 191.22,65.12 190.75,64.64 190.75,58.99 191.95,57.78 191.95,55.63 191.26,54.93 189.79,54.93 188.97,55.75 175.6,55.75 v2(174.05,54.2)
  IN2 w0.127: v2(159.71,47.93) 158.55,49.09 155.97,49.09 155.06,49.99 155.06,51.5 154.83,51.73 154.83,52.55 153.26,54.13 151.95,54.13 150.96,55.12 150.47,55.12 149.09,56.49 v2(149.09,56.97)
  BOTTOM w0.076: UC1.BA17 128.51,74.5 128.51,74.28 128.46,74.16 128.46,71.54 129.89,70.11 129.89,69.22
  BOTTOM w0.102: v2(149.09,56.97) 141.87,56.97 129.89,68.95 129.89,69.22
SUSCLK_R: length 5.6
  TOP w0.102: v2(172.21,51.18) 171.95,51.43 v1(169.35,51.43) 168.7,50.79 R5805.2
  BOTTOM w0.102: WLAN1.42 171.79,50.77 v2(172.21,51.18)
SVI2_SVC: length 20.4
  IN2 w0.127: v2(157.66,118.93) 156.39,117.66 156.39,113.01 155.2,111.81 155.2,109.78 156.27,108.71 156.27,106.11 v2(155.83,105.68)
  BOTTOM w0.102: v2(157.66,118.93) 157.96,118.93 v1(158.16,118.73)
  BOTTOM w0.203: PU1100.3 156.22,105.94 155.96,105.68 v2(155.83,105.68)
  BOTTOM w0.254: RV157.2 156.51,120.14 RV89.2 155.88,119.37 RV84.1 156.11,119.11 156.83,119.11 RV78.1 157.02,118.93 v2(157.66,118.93)
SVI2_SVC_R: length 4
  BOTTOM w0.102: RV157.1 156.59,122.01 v1(156.99,122.42) 158.4,123.82 158.4,124.47 UV1.AJ11
SVI2_SVD: length 20.5
  IN2 w0.127: v2(154.06,121.03) 154.87,120.22 154.87,113.21 153.93,112.27 153.93,108.32 v2(155.57,106.68)
  BOTTOM w0.102: RV87.1 RV88.2 154.37,120.72 v2(154.06,121.03) 153.8,121.29 153.8,121.74 RV77.1 154.29,122.23 RV155.2
  BOTTOM w0.203: PU1100.5 155.63,106.74 v2(155.57,106.68)
SVI2_SVD_R: length 3.3
  BOTTOM w0.102: RV155.1 155.19,122.93 v1(155.86,123.6) 157.08,124.82 157.62,124.82 UV1.AK12
SVI2_SVT: length 17.1
  IN2 w0.127: v2(155.7,107.61) 154.56,108.76 154.56,112.07 155.5,113.01 155.5,120.55 v2(154.59,121.46)
  BOTTOM w0.102: v2(154.59,121.46) 155.19,121.46 RV156.2
  BOTTOM w0.203: v2(155.7,107.61) 155.78,107.54 PU1100.7
SVI2_SVT_R: length 2.9
  BOTTOM w0.102: RV156.1 155.96,122.02 UV1.AL11
SW_VCCEOPIO: length 2.6
  BOTTOM w0.102: PR1208.1 v1(44.72,58.8)
  BOTTOM w0.254: 38.92,53.71 PU1200.8
SYS_PWROK: length 70
  TOP w0.102: UE1.89 179.14,71.57 v2(179.48,71.22)
  IN1 w0.127: v2(174.62,81.51) 174.17,81.96 173.76,81.96 171.37,79.57 169.72,79.57 165.73,83.57 163.3,83.57 157.52,89.34 156.99,89.34 155.19,91.15 153,91.15 151.19,92.96 146.84,92.96 145.95,92.07 145.15,92.07 141.28,95.95 141.28,97.73 v2(140.96,98.04)
  IN2 w0.127: v2(179.48,71.22) 180.05,71.22 180.52,71.69 180.52,73.98 179.22,75.28 179.22,76.36 179.6,76.74 179.6,79.28 176.46,82.42 174.89,82.42 174.62,82.15 v2(174.62,81.51)
  BOTTOM w0.076: UC1.B6 135.88,95.98 135.88,96.2 136.01,96.33 136.93,96.33 137.15,96.56 137.15,96.84 137.32,97 138.07,97 138.36,96.71 139.25,96.71
  BOTTOM w0.102: v2(140.96,98.04) 140.96,97.75 140.11,96.89 139.87,96.89 139.69,96.71 139.25,96.71
SYS_RESET#: length 8.5
  BOTTOM w0.076: 139.25,95.59 139.03,95.37 138.34,95.37 138.21,95.25 137.66,95.25 136.88,96.03 UC1.B5
  BOTTOM w0.102: v1(142.77,98.41) RC291.2 141.73,97.83 140.31,96.41 140.07,96.41 139.25,95.59
T_CRIT#: length 2.5
  BOTTOM w0.102: THM26.4 157.94,166.51 R2604.2 v1(159.23,166.8)
TEST_PG: length 1.4
  TOP w0.381: v2(167.47,132.59) 167.1,132.22 RV2.2
  BOTTOM w0.381: v2(167.47,132.59) 167.52,132.64 167.52,132.68 167.77,132.94 UV1.N10
TESTEN: length 6.6
  TOP w0.102: RV154.2 RV17.2 174.42,130.19 173.4,131.2 v1(173.4,131.6) 173.4,131.96 172.39,132.97 171.99,132.97 v2(171.86,132.84)
  BOTTOM w0.102: UV1.K7 171.82,132.8 v2(171.86,132.84)
THM_SML1_CLK: length 9.9
  BOTTOM w0.102: Q2601.4 152.19,159.18 152.8,159.79 v1(153.39,159.79) 153.98,159.19 153.98,158.05 154.23,157.8 156.36,157.8 156.53,157.98 RE432.2 C2608.1 155.99,160.06 THM26.8
THM_SML1_DATA: length 8.1
  BOTTOM w0.102: THM26.7 156.64,160.27 C2609.1 RE32.2 157.4,157.66 v1(157.28,157.54) 153.98,157.54 153.49,157.05 Q2601.1
TOUCH_SCREEN_PD#: length 99.8
  IN1 w0.127: v2(133.34,150.88) 133.85,150.37 133.85,149.92 135.95,147.83 135.95,140.53 135.08,139.66 135.08,127.86 135.82,127.13 137.98,127.13 141.73,123.38 141.73,117.6 143.44,115.89 143.44,111.32 143.95,110.81 143.95,104.08 v2(144.33,103.7)
  IN2 w0.127: v2(133.34,150.88) 133.03,150.88 132.47,150.32 122.11,150.32 120.96,149.16 119.63,149.16 118.93,149.86 108.01,149.86 101.72,156.15 v2(101.72,156.36)
  BOTTOM w0.102: v2(144.33,103.7) 144,104.03 140.47,104.03 140.16,103.72 140.16,102.73 140.74,102.15 RC277.2 139.88,101.56 RC394.1 ; D5203.2 102.48,155.6 v2(101.72,156.36) v1(101.35,156.73) 100.86,157.22 R5205.2
TOUCH_SCREEN_PD#_R: length 7.8
  BOTTOM w0.076: UC1.A7 135.67,97.41
  BOTTOM w0.102: 135.67,97.41 135.98,97.73 136.9,97.73 137.15,97.47 138.37,97.47 138.88,97.98 138.88,98.31 139.87,99.3 RC394.2
TOUCHPAD_INTR#: length 268.7
  TOP w0.102: v2(186.81,77.6) 186.81,76.96 187.19,76.58 188.4,76.58 191.26,79.44 191.26,81.57 191.55,81.86 UE1.33 ; v2(164.94,58.67) 160.36,58.67 158.62,56.93 156.87,56.93 155.97,56.03 154.77,56.03 153.87,55.13 152.38,55.13 148.52,58.99 v1(148.52,62.6) 148.52,63.69 148.77,63.94 DZ3.1 ; Q6204.1 55.4,69.18 56.19,68.39 v2(56.25,68.39)
  IN1 w0.127: v2(186.81,77.6) 185.92,76.71 185.92,70.87 186.59,70.19 186.59,68.34 184.73,66.48 179.31,66.48 170.94,58.1 165.51,58.1 v2(164.94,58.67) ; v2(162.3,36.58) 160.99,35.27 160.99,26.07 159.63,24.71 159.63,21.78 155.33,17.48 154.05,17.48 153.09,16.51 85.08,16.51 82.16,19.43 82.16,24.19 80.57,25.78 75.44,25.78 74.35,26.87 74.35,32.26 72.83,33.78 69.45,33.78 68.1,35.13 65.86,35.13 65.4,34.67 60.19,34.67 59.3,35.56 57.4,35.56 53.84,39.12 53.84,65.98 v2(56.25,68.39)
  IN2 w0.127: v2(164.94,58.67) 164.94,56.86 166.07,55.73 166.07,47.4 163.82,45.15 163.82,38.1 v2(162.3,36.58)
  BOTTOM w0.102: RE440.1 187.5,77.6 v2(186.81,77.6)
TOUCHPAD_INTR#_D: length 20.6
  TOP w0.102: v2(140.01,74.07) 139.72,73.78 v1(139.72,73.36) 139.72,69.86 143.51,66.07 146.9,66.07 RC272.2 147.86,63.98 DZ3.2
  BOTTOM w0.076: v2(140.01,74.07) 139.78,74.07 139.28,73.57 136.69,73.57 136.29,73.97 136.29,74.32 UC1.BA5
TP_LOCK#: length 4.7
  TOP w0.102: TPAD1.6 61.49,77.61 61.35,77.47 R6505.2 60.57,77.33 60.57,76.42 60.23,76.07 v1(59.98,76.07) D3801.2
TP_ON#_GATE: length 8.1
  TOP w0.102: Q2405.2 51.47,74.6 C6204.2 52.05,76.05 Q6203.2 51.16,77.93 50.6,78.49 R6519.2 v1(49.28,79.58)
TP_PW_EN#: length 279.8
  TOP w0.102: v1(49.16,77.14) v2(48.76,77.53) 48.76,78.09 R6519.1 ; UE1.49 185.15,83.72 v2(184.8,84.06)
  IN1 w0.127: v2(162.81,26.23) 164.65,28.07 164.65,32.13 169.51,36.99 171.48,36.99 172.9,38.42 175.81,38.42 177.55,40.16 185.64,40.16 187.25,41.78 192.48,41.78 v2(193.5,40.77) ; v2(48.76,77.53) 44.13,77.53 43.43,76.83 43.43,68.77 43.94,68.26 48.57,68.26 50.92,65.91 50.92,59.56 50.98,59.5 50.98,52.7 51.11,52.58 v2(51.11,52.32)
  IN2 w0.127: v2(184.8,84.06) 184.8,82.21 185.41,81.6 185.41,80.6 185.18,80.37 185.18,77.04 187.06,75.17 188.14,75.17 188.33,74.98 188.33,73.34 187.83,72.83 187.83,69.49 188.56,68.75 188.56,68.03 189.71,66.89 189.71,64.94 190.75,63.9 190.75,62.08 191.6,61.22 191.6,57.72 193.66,55.65 193.66,40.93 v2(193.5,40.77) ; v2(51.11,52.32) 51.11,52.2 50.29,51.37 50.29,49.91 53.33,46.86 53.33,40.28 55.56,38.06 55.56,31.52 60.66,26.42 76.43,26.42 80.96,21.89 80.96,18.04 85.15,13.84 99.73,13.84 101.05,12.53 158.89,12.53 162.49,16.13 162.49,20.38 163.32,21.21 163.32,25.72 v2(162.81,26.23)
TP_RESET: length 4.5
  BOTTOM w0.102: LCD1.38 99.3,164.59 C5214.1 100.89,162.5 100.86,162.47 R5212.1
TP_RS: length 9.7
  BOTTOM w0.102: R5205.1 100.86,159.39 C5208.1 101.99,160.52 101.99,164.12 v1(101.89,164.22) 101.64,164.47 99.97,164.47 99.8,164.63 LCD1.39
TP_VDD: length 24.6
  TOP w0.508: 58.81,79.37 v1(57.96,78.52) 56.97,77.53 v2(56.76,77.53) 55.37,77.53 54.73,78.17 R6212.2 54.73,79.57 54.22,80.07 52.63,80.07 52.13,79.57 Q6203.1 ; 58.81,79.37 RZ18.1 ; 58.81,79.37 58.05,80.14 58.05,80.72 58.48,81.15 RZ19.1 ; v2(56.51,70.19) 57.18,69.52 Q6204.2 ; R6211.2 v2(56.89,74.88) ; R6505.1 v2(59.8,76.64) ; TPAD1.1 61.87,72.61 61.35,72.09 C6201.1 R6209.1 59.8,72.14 R6508.1 R6506.1 R6203.2 59.16,74.8 v2(59.09,74.88)
TPAN_VDD: length 0.6
  TOP w0.102: v2(96.17,151.87) v3(96.82,151.87)
  vias: v2(96.17,152.43) v2(100.64,164.97) v2(101.25,164.97)
TPAN_VDD_F:
  vias: v1(92.34,150.5)
UART_2_CRXD_DTXD: length 50.5
  IN1 w0.127: v2(156.63,52.64) 157.07,53.08 157.07,54.15 154.72,56.49 153.96,56.49 151.16,59.29 151.16,66.88 151.82,67.53 151.82,69.7 150.74,70.78 150.74,74.65 150.36,75.03 150.36,78.33 149.37,79.33 149.37,82.53 150.74,83.9 v2(150.74,84.33)
  BOTTOM w0.076: 140.39,83.99 139.56,83.99 139.47,83.89 UC1.AD1
  BOTTOM w0.102: v2(150.74,84.33) 150.74,84.33 150.35,83.93 148.59,83.93 v1(148.13,83.46) 147.96,83.3 145.35,83.3 RC62.1 144.76,83.88 142.93,83.88 142.83,83.99 140.39,83.99 ; v2(156.63,52.64) 156.65,52.62 JWDB1.2
UART_2_CTXD_DRXD: length 51.5
  IN1 w0.127: v2(156.65,53.28) 156.81,53.44 156.81,54.04 154.62,56.24 153.86,56.24 150.91,59.18 150.91,66.98 151.57,67.64 151.57,69.6 150.49,70.68 150.49,74.51 150.11,74.89 150.11,78.23 149.12,79.22 149.12,83.35 v2(150.11,84.34)
  BOTTOM w0.076: 140.39,84.21 139.55,84.21 139.5,84.16 138.37,84.16 138.27,84.12 138.04,83.89 UC1.AD2
  BOTTOM w0.102: JWDB1.3 157.45,52.47 v2(156.65,53.28) ; RC63.1 150.82,85.05 v2(150.11,84.34) 149.98,84.21 v1(143.58,84.21) 140.39,84.21
UG1_VGA: length 11
  IN1 w1.016: 173.41,110.24 172.78,110.24 172.14,110.87 165.66,110.87 164.52,109.73
  BOTTOM w0.102: v1(175.78,111.17) 175.04,110.44 PQ1104.4
  vias: v2(162.81,108.97) v2(163.38,108.97) v2(174.38,109.77) v2(175.02,109.77)
UG2_VGA: length 16.5
  IN1 w1.016: 163.87,103.64 163.87,102.44 166.62,99.69 171.3,99.69 175.44,95.56 175.44,94.72
  vias: v1(176.26,93.27) v2(163.03,104.93) v2(163.55,104.67) v2(175.82,93.79) v2(176.41,93.76)
UG_1.2V: length 5.2
  IN2 w0.762: 66.73,18.03 63.94,18.03 62.64,19.34
  BOTTOM w0.102: v2(61.08,20.19) v1(61.08,20.73)
  vias: v2(61.46,19.75) v2(67.62,18.35) v2(67.62,17.72)
UGATE_CHG:
  vias: v1(115.88,157.25) v2(113.28,157.29) v2(113.91,157.29)
USB2_ID: length 4.9
  BOTTOM w0.076: 139.01,83 138.32,83 138.21,82.95 137.78,82.95 137.39,82.57 UC1.AG3
  BOTTOM w0.102: 139.01,83 139.21,82.8 v1(139.82,82.8) 141.15,82.8 RC366.1
USB2_VBUSSENSE: length 10.2
  TOP w0.076: v2(136.06,82.83) 136.06,82.91 136.58,83.44 137.53,83.44 138.17,82.8 139.12,82.8
  TOP w0.102: RC393.1 143.96,84.07 143.57,84.07 v1(143,83.5) 140.39,83.5 139.69,82.8 139.12,82.8
  BOTTOM w0.089: UC1.AG4 136.51,82.57 136.25,82.83 v2(136.06,82.83)
USB3_PRX_CTX_N0: length 167.3
  IN2 w0.076: 125.5,94.41 125.52,94.41 125.6,94.34 125.6,90.55 125.91,90.23 130.87,90.23 131.18,90.54 133.21,90.54 134.04,91.38 134.04,91.87 134.14,91.97 134.25,91.97 v2(134.43,91.79)
  IN2 w0.127: 125.5,94.41 123.59,96.33 115.07,96.33 111.4,100 105.37,100 104.9,100.47 99.7,100.47 97.91,102.25 97.91,102.76 97.22,103.45 94.85,103.45 69.83,78.42 63.94,78.42 61.65,80.71 44.95,80.71 42.73,78.48 39.93,78.48 38.79,77.34 38.79,69.41 33.67,64.29 33.67,58.38 31.2,55.91 31.2,49.64 30.2,48.64 28.99,48.64 27.55,47.2 27.55,44.18 28.51,43.22 28.51,38.88 27.6,37.98 25.52,37.98 25.33,37.78 25.3,37.78 v2(25.16,37.65)
  BOTTOM w0.091: TR3403.2 24.44,37.72 24.57,37.85 24.97,37.85 v2(25.16,37.65)
  BOTTOM w0.102: UC1.H8 134.21,92.01 v2(134.43,91.79)
USB3_PRX_CTX_N0_C: length 11.7
  BOTTOM w0.091: TR3403.1 22.3,37.72 22.15,37.87 21.95,37.87 21.91,37.9 21.91,37.9 21.47,38.34 21.42,38.34 20.95,38.81 20.54,38.81 20.39,38.65 U3402.9 U3402.1 18.54,38.65 18.41,38.79 18.07,38.79 18.07,38.79 18.01,38.79 18.01,38.8 v4(17.29,38.8) 16.95,38.8 15.63,37.48 14.42,37.48 13.85,36.9 13.46,36.9 13.32,36.76 USB1.5
USB3_PRX_CTX_P0: length 167.3
  IN2 w0.076: 125.7,94.58 125.76,94.52 125.76,90.62 125.98,90.4 130.8,90.4 131.11,90.71 133.14,90.71 133.88,91.45 133.88,91.94 134.07,92.14 134.16,92.14 v2(134.41,92.38)
  IN2 w0.127: v2(25.16,38.23) 27.49,38.23 28.25,38.99 28.25,43.12 27.3,44.07 27.3,47.31 28.89,48.89 30.09,48.89 30.94,49.74 30.94,56.01 33.42,58.49 33.42,64.39 38.54,69.51 38.54,77.45 39.83,78.74 42.62,78.74 44.84,80.97 61.76,80.97 64.04,78.68 69.72,78.68 94.75,103.71 97.33,103.71 98.17,102.87 98.17,102.36 99.8,100.72 105.01,100.72 105.48,100.26 111.51,100.26 115.18,96.59 123.69,96.59 125.7,94.58
  BOTTOM w0.091: v2(25.16,38.23) 24.96,38.03 24.64,38.03 24.44,38.22 TR3403.3
  BOTTOM w0.102: v2(134.41,92.38) 134.12,92.66 UC1.G8
USB3_PRX_CTX_P0_C: length 11.7
  BOTTOM w0.091: 20.25,39.15 20.34,39.15 20.5,38.99 21.08,38.99 v4(21.36,38.7) 21.98,38.08 22.15,38.08 22.3,38.22 TR3403.4 ; 18.09,38.98 17.62,38.98 17.59,39.01 16.91,39.01 15.55,37.66 14.34,37.66 13.77,37.08 13.44,37.08 13.32,37.21 USB1.6
  BOTTOM w0.102: 18.09,38.98 18.37,38.98 18.54,39.15 U3402.2 U3402.8 20.25,39.15
USB3_PTX_CRX_N0: length 157.4
  IN2 w0.127: v2(26.37,42.43) 26.2,42.27 26.2,41.87 26.32,41.76 26.79,41.76 27.02,41.99 27.02,42.92 25.9,44.04 25.9,48.24 30.22,52.56 30.22,57.19 32.66,59.63 32.66,65.52 37.2,70.06 37.2,77.66 39.3,79.76 42.31,79.76 44.21,81.66 65.82,81.66 67.98,79.5 69.45,79.5 91.55,101.6 91.58,101.6 94.37,104.4 97.7,104.4 100.69,101.41 105.3,101.41 105.76,100.94 110.79,100.94 110.9,101.05 111.69,101.05 111.79,101.05 113.98,98.87 117.14,98.87 118.2,97.8 124.29,97.8 124.75,97.35 128.28,97.35 129.1,98.16 130.89,98.16 131.18,97.88 131.18,97.67 131.44,97.41 v2(131.44,97.41)
  BOTTOM w0.076: 131.07,97.4 131.07,97.25 130.9,97.08 130.9,96.81 130.99,96.71 arc(130.99,96.71) 130.99,96.71 arc(131.07,96.59) 131.1,96.46 131.1,96.25 131.09,96.22 131.06,96.11 131.06,95.95 131.12,95.78 131.12,95.65 131.09,95.53 131.09,95.43 131.21,95.32 131.27,95.32 UC1.C13
  BOTTOM w0.091: C3403.1 26.17,41.89 26.17,42.23 v2(26.37,42.43) ; v2(131.44,97.41) 131.32,97.53 131.2,97.53 131.07,97.4
USB3_PTX_CRX_N0_C: length 11.7
  BOTTOM w0.091: 18.09,40.33 17.51,40.33 v4(17.25,40.6) 15.74,42.11 14.66,42.11 13.84,42.93 13.58,42.93 13.48,42.93 13.32,42.76 USB1.8 ; TR3402.1 22.28,39.78 22.12,39.94 21.71,39.94 21.36,40.29 20.81,40.29 20.77,40.32 20.5,40.32 20.34,40.15 20.25,40.15
  BOTTOM w0.102: 18.09,40.33 18.34,40.33 18.51,40.15 U3402.4 U3402.7 20.25,40.15
USB3_PTX_CRX_N0_R: length 5.3
  BOTTOM w0.091: C3403.2 26.29,40.34 26.29,40.13 26.85,39.57 v4(26.85,39.32) 26.85,39.07 26.59,38.8 26.03,38.8 25.61,39.21 25.56,39.21 25.15,39.63 25.15,39.66 24.98,39.84 24.4,39.84 24.34,39.78 TR3402.2
USB3_PTX_CRX_P0: length 157.3
  IN2 w0.127: v2(130.68,97.4) 130.92,97.64 130.92,97.77 130.79,97.9 129.2,97.9 128.39,97.09 124.64,97.09 124.19,97.55 118.1,97.55 117.03,98.61 113.87,98.61 111.69,100.8 111.58,100.8 111.01,100.8 110.9,100.69 105.66,100.69 105.19,101.16 100.58,101.16 97.6,104.14 94.48,104.14 91.69,101.35 91.66,101.35 69.56,79.25 67.88,79.25 65.72,81.4 44.32,81.4 42.41,79.5 39.41,79.5 37.46,77.55 37.46,69.96 32.91,65.41 32.91,59.53 30.47,57.09 30.47,52.45 26.16,48.13 26.16,44.15 27.28,43.03 27.28,41.89 26.89,41.5 26.21,41.5 25.95,41.77 25.95,42.27 v2(25.78,42.43)
  BOTTOM w0.076: v2(130.68,97.4) 130.73,97.35 130.73,96.74 130.87,96.6 arc(130.92,96.53) 130.93,96.46 130.93,96.27 130.93,96.26 130.9,96.14 130.9,95.92 130.95,95.76 130.95,95.67 130.92,95.55 130.92,95.37 130.97,95.32 UC1.D13
  BOTTOM w0.091: C3404.1 25.98,41.89 25.98,42.23 v2(25.78,42.43)
USB3_PTX_CRX_P0_C: length 11.6
  BOTTOM w0.091: USB1.9 13.32,43.21 13.42,43.11 13.5,43.11 13.58,43.11 13.91,43.11 14.73,42.29 15.81,42.29 17.14,40.95 17.19,40.95 17.63,40.52 18.34,40.52 18.48,40.65 U3402.5 U3402.6 20.3,40.65 20.45,40.5 v4(21.1,40.5) 21.4,40.5 21.78,40.12 22.11,40.12 22.27,40.28 TR3402.4
USB3_PTX_CRX_P0_R: length 5.5
  BOTTOM w0.091: C3404.2 25.99,40.59 26.09,40.49 26.09,40.03 26.64,39.48 26.64,39.11 26.51,38.98 26.1,38.98 v4(25.51,39.57) 25.06,40.02 24.55,40.02 24.5,40.06 24.5,40.22 24.44,40.28 TR3402.3
USB20_VCCA:
  vias: v2(196.69,24.24) v2(196.69,23.42) v2(197.39,25.07) v2(197.39,24.24) v2(197.39,23.42)
USB30_VCCC:
  vias: v2(24.57,44.2) v2(24.57,43.56)
USB_CAMERA_EDP: length 3.7
  BOTTOM w0.091: TR5209.4 95.81,163.05 95.65,163.21 95.65,163.47 v4(95.86,163.68) 96.14,163.96 96.14,165.11 96.3,165.27 LCD1.32
USB_CAMERA_EDP#: length 3.7
  BOTTOM w0.091: TR5209.1 95.31,163.05 95.47,163.21 95.47,163.59 95.96,164.08 95.96,165.11 95.8,165.27 LCD1.31
USB_EN#: length 286.7
  TOP w0.102: v2(84.13,14.24) v1(83.46,13.56) 82.81,13.56 80.33,11.09 56.66,11.09 v2(55.68,12.06) ; v2(191.92,73.52) 191.96,73.57 UE1.13
  IN1 w0.127: v2(26.76,46.13) 26.83,46.06 26.83,42.06 25.71,40.94 25.71,25.94 26.89,24.76 29.92,24.76 32.19,22.5 v2(32.19,21.97) ; v2(194.17,33.79) 193.6,34.35 187.13,34.35 184.71,36.77 178.43,36.77 177.54,35.88 169.35,35.88 165.41,31.94 165.41,27.05 161.66,23.3 161.66,21.27 154.67,14.28 84.17,14.28 v2(84.13,14.24)
  IN2 w0.127: v2(191.92,73.52) 191.92,72.82 190.6,71.5 190.6,69.51 191.02,69.09 191.45,69.09 193.17,67.36 193.54,67.36 194.37,66.53 194.56,66.53 196.21,64.88 196.21,62.66 194.61,61.06 194.25,61.06 193.48,60.29 193.48,56.9 194.17,56.2 v2(194.17,33.79) ; v2(32.19,21.97) 32.19,12.79 33.62,11.36 39.79,11.36 40.32,10.83 44.1,10.83 44.24,10.97 54.59,10.97 v2(55.68,12.06)
  BOTTOM w0.102: v2(191.92,73.52) 191.89,73.52 190.57,72.2 RE388.1 ; U3505.4 201.1,20.77 201.59,21.27 201.59,31.06 198.87,33.79 v2(194.17,33.79) ; U3504.4 v2(26.76,46.13)
USB_OC#0_1: length 179.2
  IN1 w0.127: v2(28.7,52.26) 29.9,53.47 29.9,54.74 34.47,59.31 35.26,59.31 41.17,65.22 41.17,65.24 41.33,65.4 41.33,78.17 44.25,81.09 65.33,81.09 67.37,83.12 71.56,83.12 85.46,97.03 85.46,100.08 90.35,104.97 90.35,108.36 94.54,112.54 96.15,112.54 v2(101.87,118.27) ; v2(136.13,99.77) 132.2,99.77 130.59,101.38 130.59,107.5 v2(129.28,108.81)
  IN2 w0.127: v2(101.87,118.27) 101.87,115.87 103.78,113.95 103.78,113 105.02,111.76 105.02,109.26 105.74,108.55 112.48,108.55 113.21,109.28 122.42,109.28 123.63,110.49 128.11,110.49 129.28,109.32 v2(129.28,108.81)
  BOTTOM w0.102: v2(28.7,52.26) 27.3,52.26 26.22,51.18 v1(26.22,47.54) 26.22,46.48 25.87,46.13 U3504.3 ; UC1.A9 133.81,97.05 134.11,97.35 134.11,99.19 134.6,99.68 135.27,99.68 R3501.2 135.99,99.64 v2(136.13,99.77) 136.93,99.77 137.65,100.49 RPC3.3
USB_OC#2_3: length 140.5
  TOP w0.102: v2(137.64,98.42) v1(137.64,97.92)
  IN2 w0.127: v2(137.64,98.42) 137.64,97.36 138.43,96.57 141.4,96.57 142.07,97.25 143.85,97.25 144.33,97.73 150.11,97.73 151.69,99.31 159.82,99.31 161.98,97.15 161.98,96.96 166.55,92.39 170.94,92.39 171.57,91.76 177.98,91.76 179.13,90.61 179.13,88.01 180.52,86.61 180.52,83.95 182.9,81.57 182.9,78.75 183.74,77.92 183.74,75.57 185.19,74.12 185.19,73.22 186.28,72.12 186.28,71.09 187.19,70.19 187.19,69.23 187.93,68.49 187.93,64.95 189.45,63.43 189.45,62.24 190.96,60.73 190.96,57.82 192.65,56.13 192.65,33.91 194.56,32 v2(194.56,31.43)
  BOTTOM w0.076: UC1.C9 133.92,95.49 133.92,95.72 134.21,96.01 134.21,97.09 134.37,97.25 134.37,97.41
  BOTTOM w0.102: v2(194.56,31.43) 195.89,32.77 199.57,32.77 201.37,30.97 201.37,23.24 201.1,22.97 U3505.3 ; RPC3.2 138.15,98.93 v2(137.64,98.42) 137.41,98.42 137.06,98.77 134.89,98.77 R3501.1 134.37,98.69 134.37,97.41
USB_OC#4_5: length 10.3
  BOTTOM w0.076: UC1.D9 133.81,94.95 134.24,95.38 134.47,95.38 134.7,95.61 134.7,95.81 134.65,95.86 134.65,96.89 135.17,97.41
  BOTTOM w0.102: 135.17,97.41 135.74,97.98 137.03,97.98 137.28,97.73 138.3,97.73 138.65,98.08 v1(138.65,99.62) RPC3.1
USB_OC#6_7: length 7.8
  BOTTOM w0.076: 133.83,97.41 133.83,97.38 133.55,97.11 133.55,96.55 133.57,96.5 133.57,96.37 133.81,96.13 UC1.B9
  BOTTOM w0.102: RPC3.4 137.15,100.65 136.96,100.46 134.93,100.46 133.83,99.35 133.83,98.22 v1(133.78,98.17) 133.83,98.12 133.83,97.41
USB_PN1: length 267.4
  TOP w0.091: v2(24.18,35.7) 24.46,35.7 24.72,35.44 24.72,35.31 24.42,35.02 23.25,35.02 23.09,35.18 TR3404.2
  IN2 w0.076: v2(134.09,85.05) 133.9,84.86 133.9,84.7 133.42,84.21 133.42,80.72 133.1,80.4 133.1,78.1 133.63,77.57 133.88,77.57 135.02,76.43 135.66,76.43 136.91,75.18 139.17,75.18 139.22,75.22 139.24,75.22
  IN2 w0.127: v2(24.18,35.7) 24.38,35.5 24.38,34.58 23.99,34.19 23.99,27.51 26.04,25.46 32.46,25.46 33.9,24.02 33.9,13.33 34.3,12.94 39.71,12.94 39.92,12.94 41.01,14.03 58.61,14.03 61.21,11.43 80.48,11.43 81,11.95 83.06,11.95 83.58,11.43 161.09,11.43 167.64,17.97 167.64,25.21 166.62,26.23 166.62,40.05 165.16,41.51 165.16,44.47 167.15,46.46 167.15,49.72 167.55,50.12 167.55,56.68 166.12,58.11 166.12,61.14 164.91,62.35 164.91,64.32 163.09,66.14 163.09,66.75 163.06,66.77 160.87,68.96 152.12,68.96 146.85,74.23 141.77,74.23 140.78,75.22 139.24,75.22
  BOTTOM w0.102: UC1.AB9 v2(134.09,85.05)
USB_PN1_C: length 12.8
  TOP w0.091: USB1.2 14.82,40.17 14.93,40.07 15.93,40.07 v4(17.01,38.99) 17.75,38.25 18.39,38.25 18.42,38.22 19.18,38.22 EU3403.2 20.12,38.9 20.12,38.33 20.29,38.16 20.61,38.16 21.14,37.63 21.14,36.51 20.54,35.91 20.54,35.19 20.7,35.02 20.88,35.02 21.03,35.18 TR3404.1
USB_PN2: length 85.4
  IN2 w0.076: 139.03,75.98 139.01,75.98 138.96,75.94 138.45,75.94 137.44,76.94 135.19,76.94 134.04,78.08 134.04,79.31 134.05,79.32 134.05,82.82 134.51,83.27 135.56,83.27 135.78,83.5 135.78,83.9 135.88,84 v2(136.01,84)
  IN2 w0.127: 139.03,75.98 141.03,75.98 142.1,74.92 147.13,74.92 151.24,70.81 153.79,70.81 154.93,69.67 161.96,69.67 164.36,67.28 164.36,66.67 166.36,64.66 166.36,62.8 167.12,62.05 167.12,58.24 168.4,56.96 168.4,51.12 169.29,50.23 169.29,47.62 171.96,44.95 171.96,41.78 173.03,40.71 174.46,40.71 175.12,40.04 175.12,39.82 v2(175.32,39.62)
  BOTTOM w0.091: v2(175.32,39.62) 174.96,39.62 174.87,39.71 174.87,39.89 175.25,40.27 181.55,40.27 181.83,40.55 182.79,40.55 182.95,40.39 TR3405.3
  BOTTOM w0.102: UC1.AD6 v2(136.01,84)
USB_PN2_C: length 10.7
  TOP w0.091: CN6301.22 191.1,42.77 191,42.67 191,42.51 190.91,42.42 189.11,42.42 v4(188.63,41.94) 188.15,41.46 188.15,40.53 v2(187.97,40.35)
  BOTTOM w0.091: v2(187.97,40.35) 188.25,40.35 188.35,40.44 188.35,41.07 188.13,41.29 186.5,41.29 185.84,40.62 185.26,40.62 185.04,40.39 TR3405.4
USB_PN3: length 88.2
  IN2 w0.127: v2(177.45,38.63) 177.27,38.81 177.27,42.48 175.57,44.17 175.57,46.23 173.58,48.22 173.58,56.2 172.65,57.13 172.65,60.45 171.32,61.78 171.32,67.42 167.91,70.83 167.91,78.73 167.15,79.49 167.15,80.17 165.85,81.47 159.11,81.47 158.6,80.96 157.79,80.96 156.71,79.88 155.84,79.88 154.74,78.78 152.95,78.78 152.41,79.31 151.18,79.31 148.48,82.02 141.74,82.02 140.63,80.91 140.15,80.91 139.99,81.07 139.99,81.22 v2(140.24,81.46)
  BOTTOM w0.076: v2(140.24,81.46) 139.73,81.97 139.37,81.97 139.08,81.67 138.32,81.67 138.21,81.63 138.09,81.63 137.87,81.69 137.73,81.69 137.51,81.61 137.44,81.61 137.3,81.67 137.07,81.67 UC1.AH3
  BOTTOM w0.091: v2(177.45,38.63) 177.22,38.63 177.13,38.54 177.13,38.2 177.23,38.1 179.44,38.1 180.74,36.8 182.5,36.8 182.78,37.08 TR3406.2
USB_PN3_C: length 10.4
  TOP w0.091: v2(187.85,38.45) 188.06,38.24 188.06,38.09 188.28,37.86 188.84,37.86 189.36,38.38 189.42,38.38 189.83,38.8 189.83,38.85 190.07,39.08 190.83,39.08 191.14,38.77 CN6301.18
  BOTTOM w0.091: TR3406.1 184.78,37.08 184.97,36.89 185.86,36.89 186.3,37.34 187.78,37.34 188.21,37.77 188.21,38.39 188.09,38.51 187.91,38.51 v2(187.85,38.45)
USB_PN5: length 145.1
  IN2 w0.127: v2(95.27,160.29) 95.35,160.2 95.35,159.53 97.21,157.67 98.45,157.67 101.66,154.47 101.66,153.69 103.32,152.02 104.4,152.02 107.91,148.52 118.05,148.52 118.93,147.63 122.24,147.63 125.47,144.4 125.47,141.94 126.42,140.99 126.42,134.38 126.73,134.07 127.65,134.07 128.09,133.63 129.94,133.63 v2(130.08,133.49)
  BOTTOM w0.076: 140.31,80.87 140.31,80.86 138.63,80.86 138.28,81.01 138.18,81.01 138.13,81.06 138.13,81.22 138.2,81.29 138.41,81.29 UC1.AJ1
  BOTTOM w0.091: 140.31,80.87 140.89,80.87 141.54,81.52 142.6,81.52 143.11,82.03 148.64,82.03 149.29,82.69 150.03,82.69 150.59,82.13 152.84,82.13 153.64,82.93 154.89,82.93 157.16,85.2 157.16,86.36 159.83,89.03 159.83,97.15 157.17,99.8 156.48,99.8 143.87,112.41 143.87,124.46 143.2,125.13 139.52,125.13 137.74,126.91 137.74,129.62 138.56,130.44 138.56,132.13 136.89,133.8 130.8,133.8 130.68,133.92 129.98,133.92 129.91,133.85 129.91,133.66 v2(130.08,133.49) ; v2(95.27,160.29) 95.47,160.49 95.47,160.81 95.31,160.97 TR5209.2
USB_PN6: length 267
  IN2 w0.076: v2(135.32,82.83) 135.15,82.65 135.15,82.28 135.38,82.05 135.38,81.66 135.91,81.13 137.65,81.13 138.61,80.17 139.25,80.17
  IN2 w0.127: v2(168.52,49.34) 168.35,49.17 168.35,46.2 167.38,45.23 167.38,42.8 167.32,42.74 167.32,26.61 168.46,25.46 168.46,17.4 161.08,10.02 44.22,10.02 44.1,10.14 40.03,10.14 39.51,10.67 33.44,10.67 32.93,10.16 22.6,10.16 21.39,8.95 14.99,8.95 13.35,10.6 12.48,10.6 12.14,10.25 12.14,9.73 v2(12.43,9.44) ; v2(170.43,60.42) 170.24,60.61 170.24,61.22 170.05,61.41 170.05,66.89 166.62,70.32 166.62,72.96 165.54,74.04 165.54,78.25 165.76,78.47 165.76,79.51 164.5,80.77 159.51,80.77 159.02,80.27 158.31,80.27 157.09,79.06 156.14,79.06 155.12,78.04 152.71,78.04 152.34,78.41 151.1,78.41 148.76,80.75 141.71,80.75 140.9,79.94 139.54,79.94 139.31,80.17 139.25,80.17
  BOTTOM w0.089: v2(135.32,82.83) 135.74,83.24 UC1.AF6
  BOTTOM w0.091: v2(168.52,49.34) 168.29,49.57 168.29,49.7 168.29,58.06 170.21,59.97 170.21,60.19 v2(170.43,60.42) ; v2(12.43,9.44) 12.11,9.75 12.11,9.95 12.09,9.98 12.09,10.71 12.24,10.87 12.24,11.38 12.44,11.57 R3204.1
USB_PN6_R: length 5.5
  BOTTOM w0.091: U3201.2 13.83,15.83 13.77,15.89 13.77,16.09 13.71,16.15 13.5,16.15 13.2,15.85 v4(13.2,15.32) 13.2,14.55 12.51,13.85 12.51,13.8 12.03,13.32 12.03,13.1 12.24,12.88 12.24,12.63 12.38,12.49 R3204.2
USB_PN7: length 138.9
  IN2 w0.127: v2(131.95,133.29) 131.86,133.2 131.86,132.78 131.41,132.33 127.49,132.33 125.72,134.1 125.72,140.71 124.78,141.65 124.78,143.96 121.84,146.91 118.47,146.91 117.55,147.83 107.62,147.83 104.21,151.23 102.55,151.23 99.81,153.97 v2(99.81,154.74)
  BOTTOM w0.076: 140.39,82.19 139.15,82.19 139.08,82.13 138.21,82.13 138.11,82.04 138.11,81.93 UC1.AH1
  BOTTOM w0.091: v2(131.95,133.29) 131.79,133.13 131.79,132.93 131.89,132.83 132.57,132.83 133.14,133.4 136.66,133.4 137.98,132.08 137.98,130.43 137.34,129.79 137.34,126.75 139.35,124.74 143.04,124.74 143.48,124.3 143.48,112.25 156.38,99.35 157.03,99.35 159.43,96.94 159.43,89.2 156.7,86.48 156.7,85.3 154.78,83.39 153.54,83.39 152.74,82.59 150.77,82.59 150.23,83.12 149.15,83.12 148.52,82.49 142.57,82.49 142.28,82.19 140.39,82.19 ; v2(99.81,154.74) 99.81,156.22 99.39,156.64 99.39,156.93 99.23,157.09 99.23,157.59 99.06,157.76 R5203.2
USB_PN7_TPNL: length 9.2
  BOTTOM w0.091: LCD1.36 98.3,165.24 98.46,165.08 98.46,164.37 98.33,164.24 98.33,163.9 DA6.2 98.24,163.03 98.33,162.94 98.33,162.46 99.39,161.4 99.39,159.5 99.23,159.34 99.23,158.84 99.06,158.67 R5203.1
USB_PN8: length 75.3
  TOP w0.091: v2(160.63,65.04) 160.84,65.24 160.84,65.79 160.71,65.92 160.71,66.22 160.9,66.42 161.52,66.42 161.61,66.51 161.61,66.8 161.52,66.89 160.34,66.89 160.15,67.09 160.15,67.62 160.34,67.82 161.9,67.82 162.02,67.94 162.02,68.25 161.88,68.4 160.45,68.4 160.15,68.7 160.15,69.55 158.18,71.52 158.18,72.17 158.09,72.26 157.36,72.26 157.16,72.46 157.16,72.88 157.26,72.98 157.36,73.08 158.2,73.08 158.29,73.17 158.29,73.53 158.2,73.63 157.29,73.63 157.09,73.82 157.09,74.25 157.29,74.44 158.09,74.44 158.18,74.53 158.18,74.84 157.89,75.13 156.32,75.13 156.12,75.33 156.12,75.74 156.03,75.83 155.76,75.83 155.67,75.74 155.67,75.33 155.47,75.13 154.64,75.13 154.28,75.49 154.28,77.54 153.9,77.92 153.03,77.92 152.84,78.12 152.84,78.54 153.03,78.74 153.62,78.74 153.73,78.85 153.73,80.17 153.46,80.43 v2(153.46,80.44)
  IN2 w0.076: 139.16,83.72 139.11,83.77 136.98,83.77 136.25,84.51 134.36,84.51 134.2,84.35 134.2,83.92 134.36,83.76 134.47,83.76 v2(134.66,83.94)
  IN2 w0.127: 139.16,83.72 139.53,83.72 140.32,82.93 141.02,82.93 141.29,83.21 141.29,84.26 141.42,84.39 141.8,84.39 141.93,84.26 141.93,83.21 142.21,82.93 142.8,82.93 143.08,83.21 143.08,84.26 143.2,84.39 143.58,84.39 143.71,84.26 143.71,84.07 143.96,83.82 144.58,83.82 144.86,84.1 144.86,84.26 144.99,84.39 145.37,84.39 145.49,84.26 145.49,83.21 145.77,82.93 146.92,82.93 147.2,83.21 147.2,83.73 147.32,83.86 147.71,83.86 147.83,83.73 147.83,83.21 148.11,82.93 150.24,82.93 150.41,82.76 151.48,82.76 151.6,82.65 151.6,81.05 151.87,80.77 152.47,80.77 152.74,81.05 152.74,82.52 153.44,83.22 155.51,83.22 156.22,83.92 156.42,83.92 156.7,83.64 156.7,83.49 155.73,82.53 153.89,82.53 153.31,81.94 153.31,81.37 153.79,80.88 153.79,80.62 153.62,80.44 v2(153.46,80.44)
  BOTTOM w0.091: R5801.2 160.51,64.03 160.67,64.19 160.67,64.54 160.84,64.7 160.84,64.83 v2(160.63,65.04)
  BOTTOM w0.102: UC1.AF8 v2(134.66,83.94)
USB_PN8_R: length 3.9
  BOTTOM w0.091: R5801.1 160.5,63.11 160.77,62.84 160.77,62.12 160.98,61.91 v4(161.32,61.91) 161.7,61.91 161.8,62.02 WLAN1.5
USB_PP1: length 267.4
  TOP w0.091: v2(25.14,35.7) 24.9,35.46 24.9,35.24 24.5,34.84 23.25,34.84 23.09,34.68 TR3404.3
  IN2 w0.076: v2(133.45,85.05) 133.6,85.05 133.74,84.91 133.74,84.77 133.25,84.28 133.25,80.79 132.93,80.47 132.93,78.03 133.56,77.4 133.81,77.4 134.95,76.26 135.59,76.26 136.84,75.01 139.17,75.01 139.22,74.97 139.24,74.97
  IN2 w0.127: 139.24,74.97 140.67,74.97 141.66,73.98 146.74,73.98 152.01,68.7 160.77,68.7 162.83,66.64 162.83,66.03 164.65,64.21 164.65,62.25 165.87,61.03 165.87,58 167.29,56.58 167.29,50.23 166.89,49.83 166.89,46.56 164.9,44.57 164.9,41.4 166.36,39.94 166.36,26.12 167.38,25.1 167.38,18.08 160.98,11.68 83.69,11.68 83.17,12.2 80.89,12.2 80.37,11.68 61.32,11.68 58.71,14.29 40.91,14.29 39.81,13.2 34.4,13.2 34.16,13.44 34.16,24.13 32.57,25.72 26.15,25.72 24.25,27.61 24.25,34.09 24.64,34.47 24.64,35.87 24.77,36 25.01,36 25.14,35.87 v2(25.14,35.7)
  BOTTOM w0.102: UC1.AB10 v2(133.45,85.05)
USB_PP1_C: length 12.9
  TOP w0.091: TR3404.4 21.03,34.68 20.87,34.84 20.63,34.84 20.36,35.12 20.36,35.98 20.96,36.59 20.96,37.56 20.54,37.97 20.32,37.97 20.12,37.78 20.12,37.23 EU3403.3 19.06,38.04 v4(18.09,38.04) 17.71,38.04 17.12,38.63 17.07,38.63 16.65,39.04 16.65,39.09 15.86,39.89 14.94,39.89 14.82,39.77 USB1.3
USB_PP2: length 85.4
  IN2 w0.076: v2(135.41,84) 135.48,84 135.62,83.87 135.62,83.57 135.49,83.44 134.44,83.44 133.89,82.89 133.89,79.39 133.88,79.38 133.88,78.02 135.12,76.77 137.38,76.77 138.38,75.77 138.96,75.77 139,75.73 139.03,75.73
  IN2 w0.127: 139.03,75.73 140.93,75.73 141.99,74.67 147.03,74.67 151.14,70.56 153.69,70.56 154.83,69.42 161.85,69.42 164.1,67.17 164.1,66.56 166.11,64.56 166.11,62.7 166.86,61.94 166.86,58.13 168.14,56.85 168.14,51.01 169.03,50.12 169.03,47.52 171.7,44.85 171.7,41.67 172.92,40.45 174.35,40.45 174.86,39.94 174.86,39.81 174.68,39.62 v2(174.48,39.62)
  BOTTOM w0.091: v2(174.48,39.62) 174.69,39.84 174.69,39.97 175.18,40.45 181.48,40.45 181.76,40.73 182.79,40.73 182.95,40.89 TR3405.2
  BOTTOM w0.102: UC1.AD7 v2(135.41,84)
USB_PP2_C: length 10.7
  TOP w0.091: CN6301.21 191.15,41.77 190.98,41.94 190.98,42.14 190.88,42.24 189.19,42.24 188.99,42.04 188.99,41.99 188.57,41.57 188.52,41.57 188.33,41.39 188.33,40.53 188.51,40.35 v2(188.74,40.35)
  BOTTOM w0.091: TR3405.1 185.15,40.89 185.25,40.8 185.76,40.8 186.43,41.47 188.21,41.47 188.53,41.15 188.53,40.56 v2(188.74,40.35)
USB_PP3: length 88.2
  IN2 w0.127: v2(139.65,81.46) 139.74,81.37 139.74,80.97 140.05,80.66 140.74,80.66 141.85,81.76 148.37,81.76 151.08,79.05 152.31,79.05 152.84,78.52 154.84,78.52 155.95,79.63 156.82,79.63 157.9,80.71 158.7,80.71 159.21,81.22 165.75,81.22 166.9,80.06 166.9,79.39 167.66,78.63 167.66,70.72 171.06,67.31 171.06,61.67 172.39,60.35 172.39,57.03 173.33,56.09 173.33,48.11 175.31,46.12 175.31,44.07 177.01,42.37 177.01,38.91 v2(176.74,38.63)
  BOTTOM w0.076: UC1.AJ3 136.89,81.24 136.83,81.3 136.83,81.44 136.9,81.51 137.27,81.51 137.4,81.44 137.53,81.44 137.76,81.52 137.85,81.52 138.07,81.46 138.24,81.46 138.36,81.51 139.15,81.51 139.43,81.79 139.63,81.79 139.73,81.69 139.73,81.53 v2(139.65,81.46)
  BOTTOM w0.091: v2(176.74,38.63) 176.95,38.42 176.95,38.12 177.15,37.92 179.37,37.92 180.67,36.62 182.65,36.62 182.69,36.58 TR3406.3
USB_PP3_C: length 10.4
  TOP w0.091: v2(188.61,38.45) 188.34,38.45 188.24,38.35 188.24,38.16 188.36,38.04 188.77,38.04 v4(189.47,38.74) 189.99,39.26 190.74,39.26 191.25,39.77 CN6301.19
  BOTTOM w0.091: TR3406.4 184.85,36.58 184.98,36.71 185.93,36.71 186.38,37.16 187.85,37.16 188.39,37.69 188.39,38.23 v2(188.61,38.45)
USB_PP5: length 145
  IN2 w0.127: v2(95.85,160.29) 95.61,160.05 95.61,159.63 97.32,157.93 98.56,157.93 101.91,154.57 101.91,153.79 103.42,152.28 104.5,152.28 108.01,148.77 118.16,148.77 119.04,147.89 122.34,147.89 125.73,144.51 125.73,142.04 126.68,141.09 126.68,134.49 126.84,134.33 127.76,134.33 128.19,133.89 129.95,133.89 130.08,134.02 v2(130.08,134.33)
  BOTTOM w0.076: 140.31,80.69 140.3,80.69 140.3,80.69 138.6,80.69 138.24,80.84 138.11,80.84 137.96,80.99 137.96,81.09 UC1.AJ2
  BOTTOM w0.091: v2(95.85,160.29) 95.65,160.49 95.65,160.81 95.81,160.97 TR5209.3 ; 140.31,80.69 140.96,80.69 141.62,81.34 142.68,81.34 143.19,81.85 148.71,81.85 149.33,82.47 v4(149.68,82.47) 149.99,82.47 150.52,81.95 152.92,81.95 153.72,82.75 154.96,82.75 157.34,85.12 157.34,86.28 160.01,88.95 160.01,97.22 157.24,99.99 156.55,99.99 144.05,112.48 144.05,124.54 143.28,125.31 139.59,125.31 137.92,126.99 137.92,129.54 138.74,130.36 138.74,132.21 136.96,133.98 130.87,133.98 130.76,134.1 130.31,134.1 v2(130.08,134.33)
USB_PP6: length 267
  IN2 w0.076: 139.16,79.95 139.12,80 138.54,80 137.58,80.96 135.84,80.96 135.21,81.59 135.21,81.98 134.98,82.21 134.98,82.64 134.79,82.82 v2(134.64,82.82)
  IN2 w0.127: 139.16,79.95 139.43,79.69 141.01,79.69 141.82,80.5 148.66,80.5 151,78.16 152.23,78.16 152.6,77.78 155.23,77.78 156.25,78.8 157.2,78.8 158.42,80.02 159.12,80.02 159.62,80.52 164.4,80.52 165.51,79.4 165.51,78.58 165.28,78.35 165.28,73.93 166.36,72.86 166.36,70.21 169.79,66.78 169.79,61.31 169.99,61.11 169.99,60.61 v2(169.8,60.42) ; v2(167.89,49.34) 168.09,49.13 168.09,46.31 167.12,45.34 167.12,42.91 167.06,42.84 167.06,26.5 168.2,25.35 168.2,17.51 160.97,10.28 44.33,10.28 44.2,10.4 40.14,10.4 39.61,10.92 33.33,10.92 32.83,10.42 22.49,10.42 21.29,9.21 15.09,9.21 13.45,10.85 12.38,10.85 11.88,10.36 11.88,9.7 v2(11.62,9.44)
  BOTTOM w0.089: v2(134.64,82.82) 134.64,82.93 UC1.AF7
  BOTTOM w0.091: v2(11.62,9.44) 11.93,9.75 11.93,9.88 11.9,9.91 11.9,10.71 11.74,10.88 11.74,11.38 R3205.1 ; v2(167.89,49.34) 168.11,49.57 168.11,49.63 168.11,58.13 170.03,60.04 170.03,60.19 v2(169.8,60.42)
USB_PP6_R: length 5.6
  BOTTOM w0.091: R3205.2 11.61,12.49 11.74,12.63 11.74,12.92 11.85,13.02 11.85,13.02 11.85,13.45 v4(12.14,13.74) 13.02,14.62 13.02,14.99 12.98,15.02 12.98,15.61 13.02,15.65 13.02,15.93 13.43,16.33 U3201.3
USB_PP7: length 138.8
  IN2 w0.127: v2(100.41,154.73) 100.07,154.39 100.07,154.08 102.66,151.49 104.32,151.49 107.72,148.08 117.66,148.08 118.58,147.16 121.95,147.16 125.04,144.07 125.04,141.76 125.98,140.82 125.98,134.21 127.6,132.59 131.3,132.59 131.6,132.89 131.6,133.02 v2(131.34,133.29)
  BOTTOM w0.076: UC1.AH2 137.71,81.9 138.11,82.3 139.02,82.3 139.08,82.36 140.31,82.36 140.32,82.37 140.37,82.37 140.38,82.37 140.39,82.37
  BOTTOM w0.091: 140.39,82.37 142.21,82.37 142.5,82.67 148.44,82.67 149.08,83.3 150.31,83.3 150.84,82.77 152.67,82.77 153.46,83.57 154.71,83.57 156.52,85.38 156.52,86.55 159.25,89.28 159.25,96.87 156.95,99.17 156.3,99.17 143.3,112.17 143.3,124.22 142.96,124.56 139.28,124.56 137.16,126.67 137.16,129.87 137.8,130.5 137.8,132.01 136.58,133.22 133.22,133.22 132.64,132.65 131.82,132.65 131.61,132.86 131.61,133.01 v2(131.34,133.29) ; v2(100.41,154.73) 99.99,155.14 99.99,156.29 99.57,156.72 99.57,156.93 99.73,157.09 99.73,157.59 99.9,157.76 R5204.2
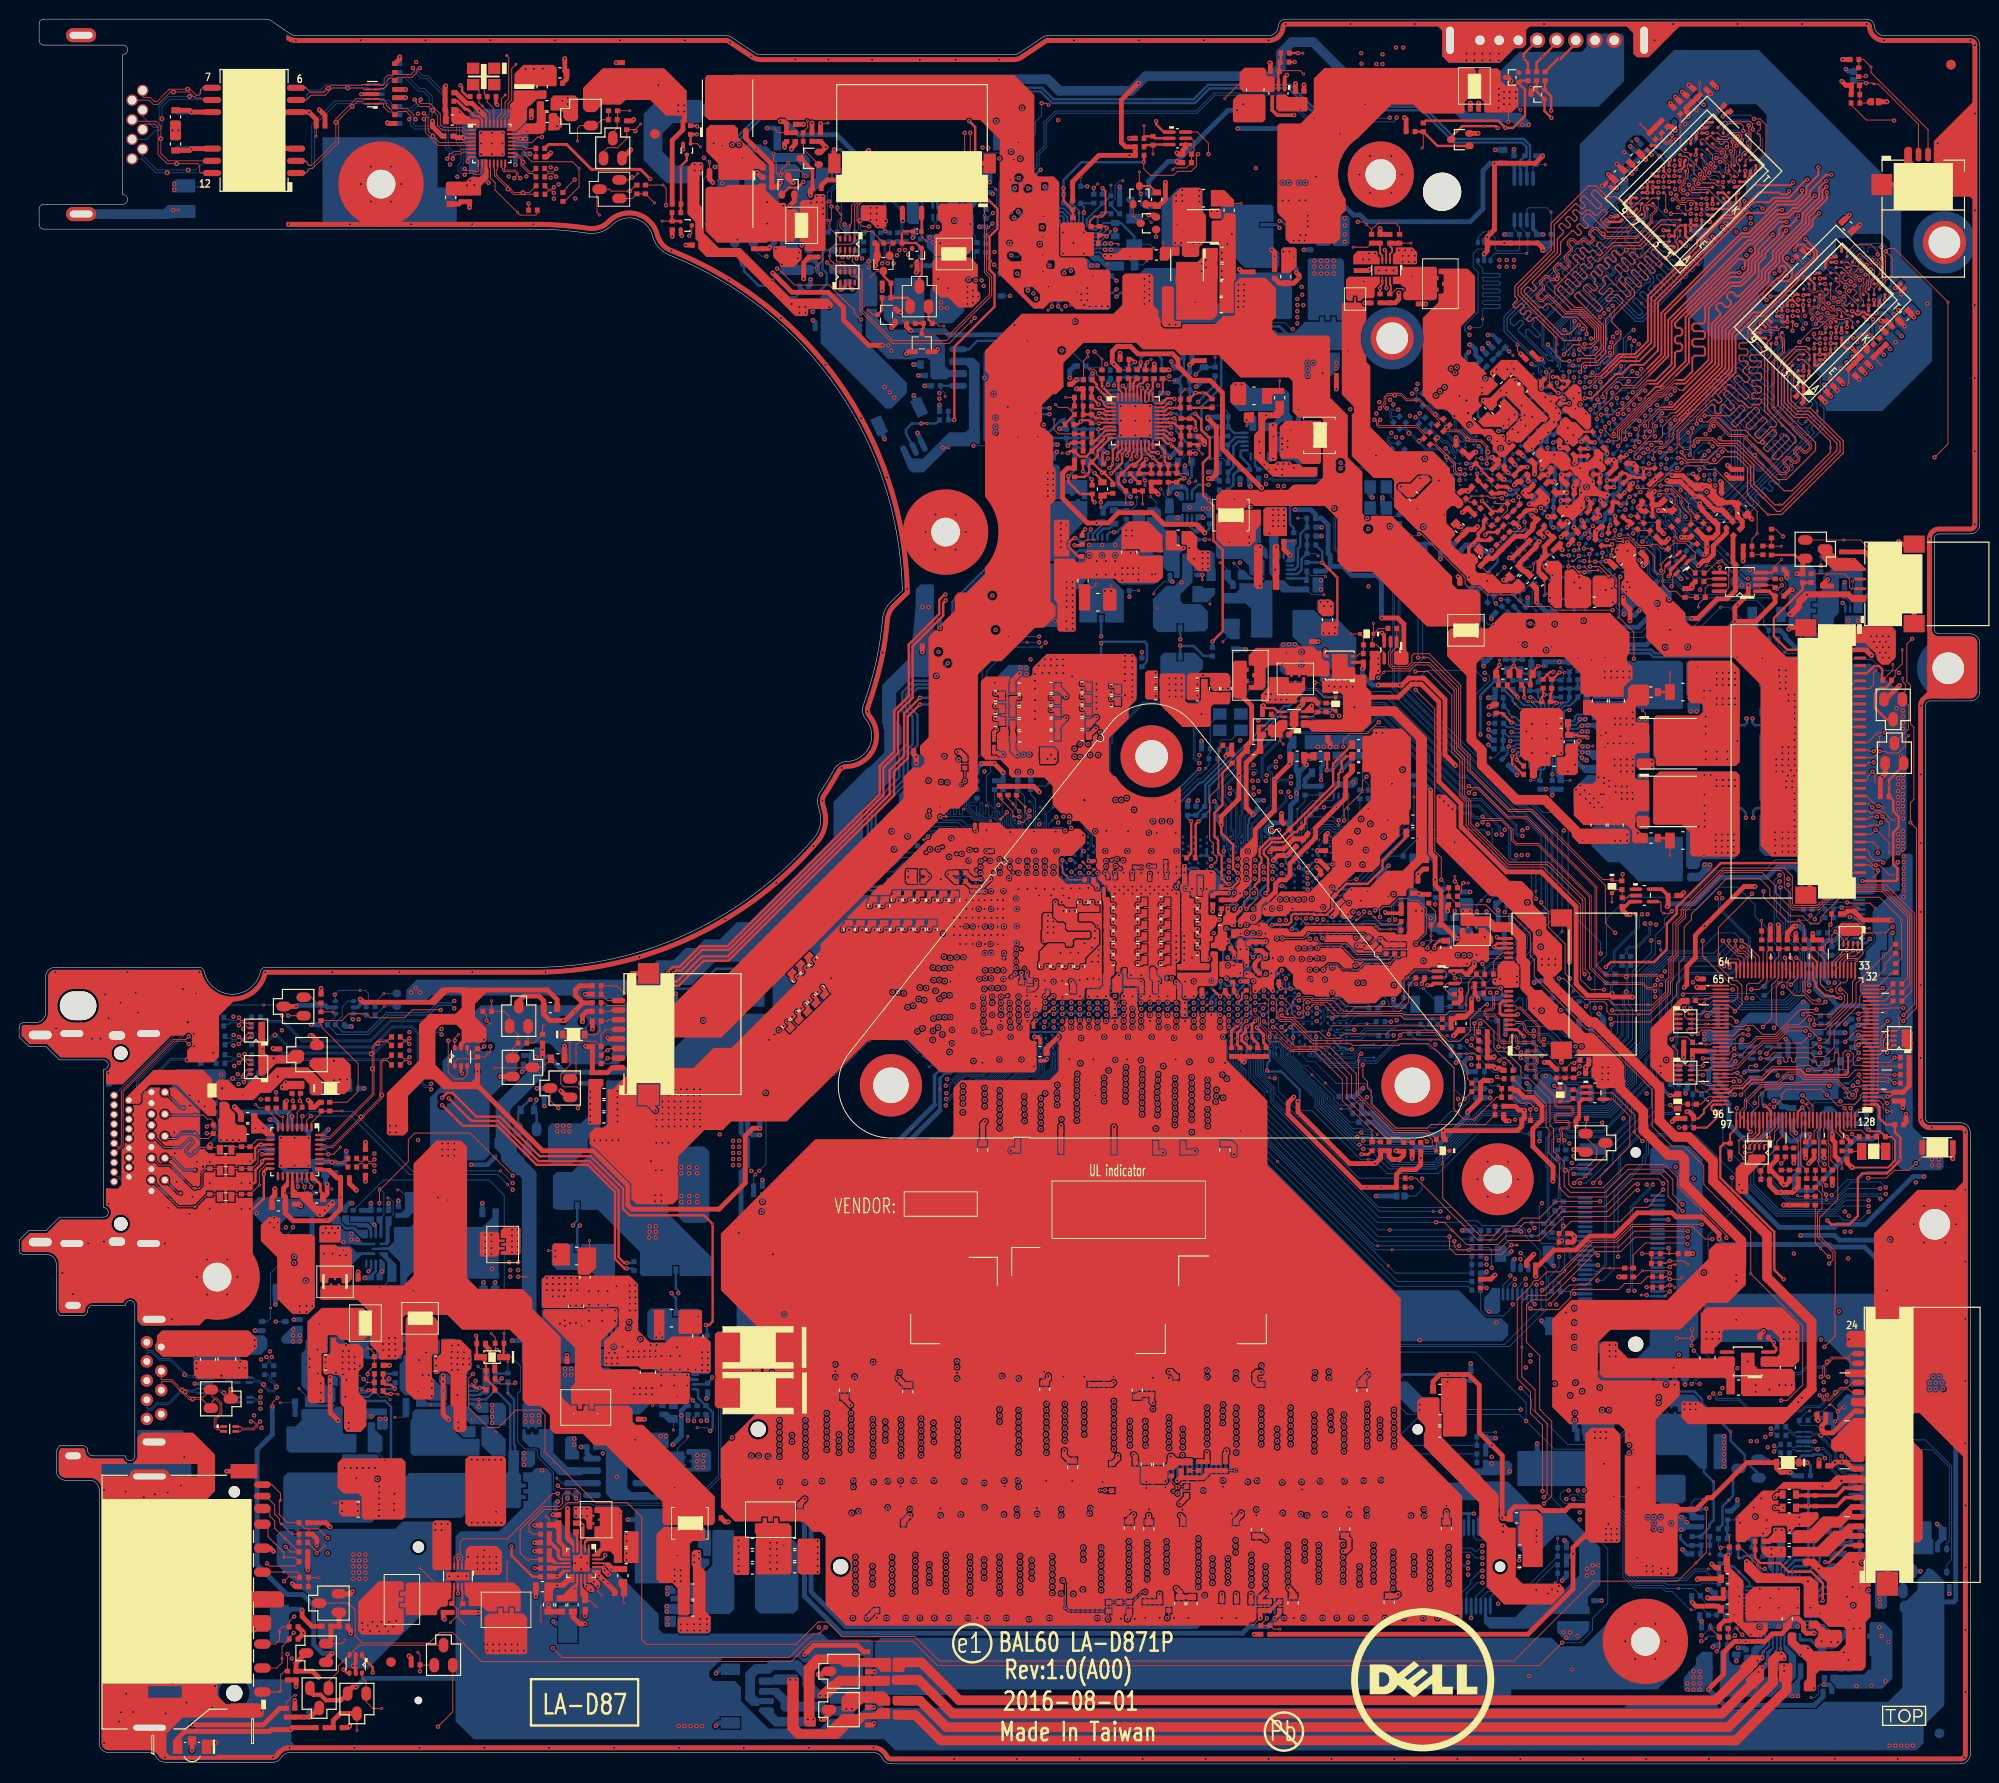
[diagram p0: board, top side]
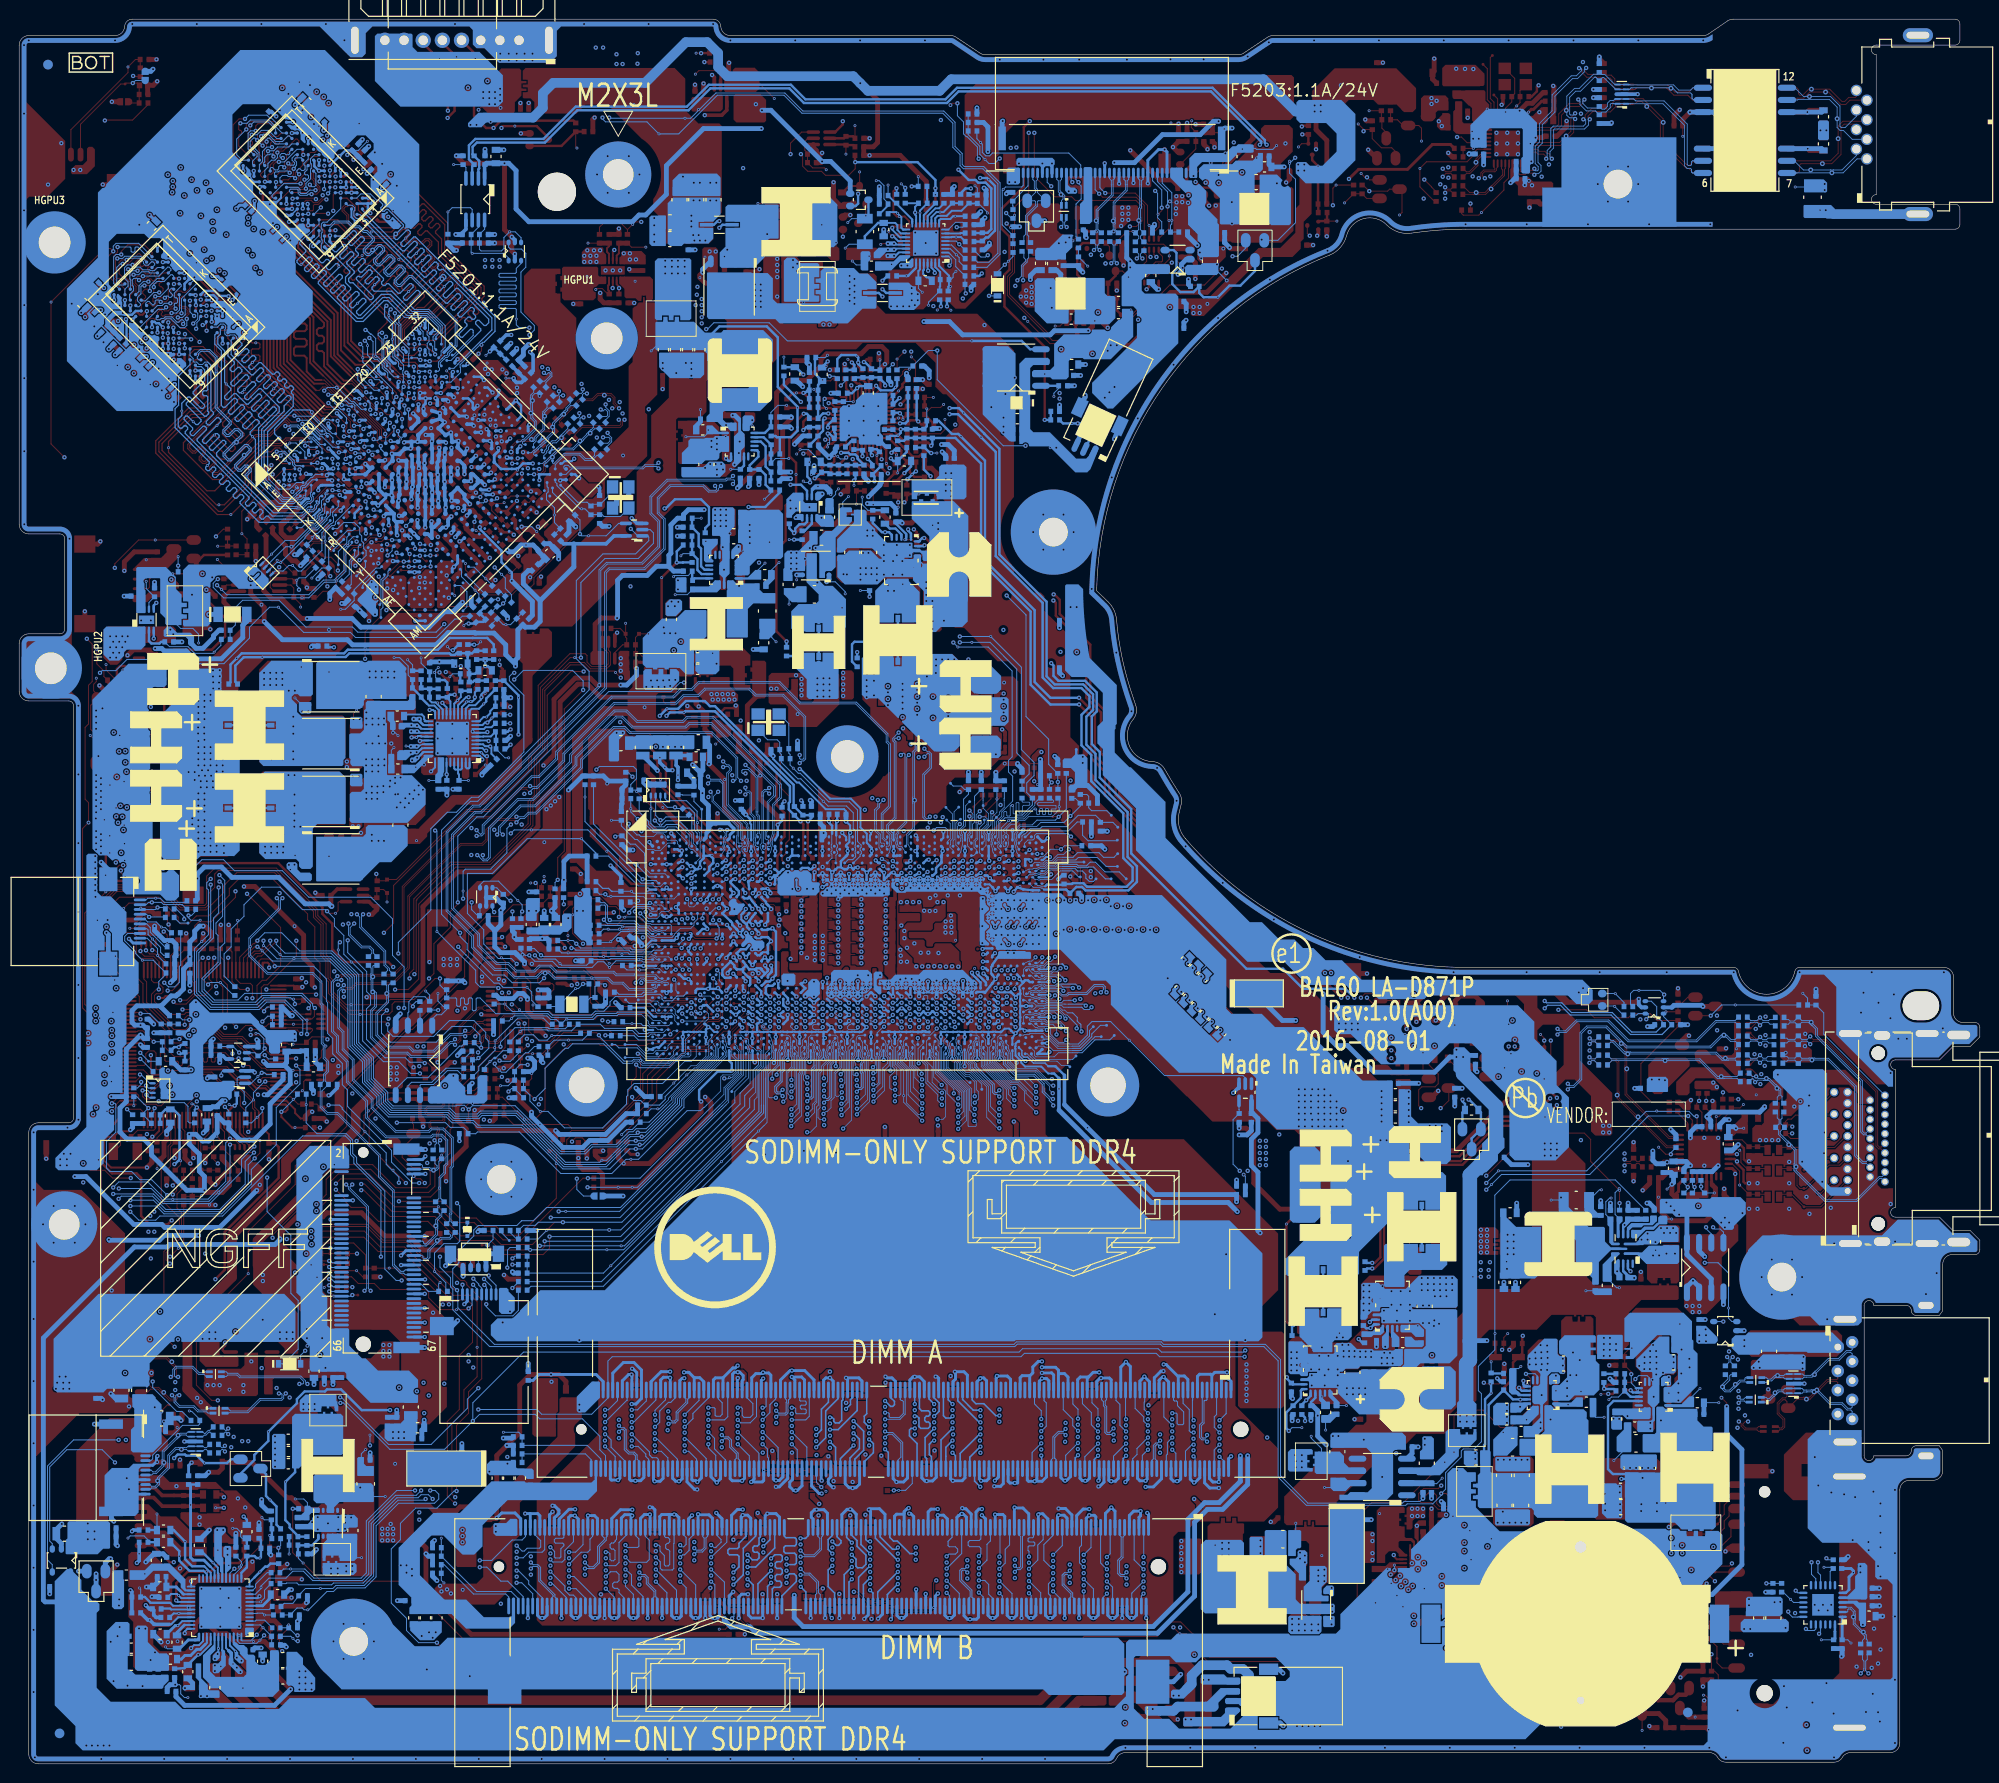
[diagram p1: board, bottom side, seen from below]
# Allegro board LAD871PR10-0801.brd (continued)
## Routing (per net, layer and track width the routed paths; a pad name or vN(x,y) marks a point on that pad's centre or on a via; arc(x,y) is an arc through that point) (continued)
USB_PP7_TPNL: length 9.2
  BOTTOM w0.091: LCD1.37 98.8,165.24 98.64,165.08 98.64,164.3 98.51,164.17 98.51,163.9 DA6.3 98.6,163.03 98.51,162.94 98.51,162.53 99.57,161.47 99.57,159.5 99.73,159.34 99.73,158.84 99.9,158.67 R5204.1
USB_PP8: length 75.2
  TOP w0.091: v2(154.17,80.43) 153.91,80.17 153.91,78.93 153.91,78.92 153.91,78.78 153.91,78.78 153.69,78.56 153.11,78.56 153.02,78.47 153.02,78.19 153.11,78.1 153.97,78.1 154.46,77.62 154.46,75.57 154.71,75.31 155.4,75.31 155.49,75.4 155.49,75.81 155.68,76.01 156.11,76.01 156.3,75.81 156.3,75.4 156.4,75.31 157.97,75.31 158.36,74.92 158.36,74.46 158.17,74.26 157.36,74.26 157.27,74.17 157.27,73.9 157.36,73.81 158.27,73.81 158.47,73.61 158.47,73.09 158.27,72.9 157.43,72.9 157.34,72.81 157.34,72.53 157.43,72.44 158.17,72.44 158.36,72.24 158.36,71.59 160.33,69.62 160.33,68.77 160.52,68.58 161.95,68.58 162.2,68.33 162.2,67.87 161.97,67.64 160.42,67.64 160.33,67.55 160.33,67.17 160.42,67.07 161.59,67.07 161.79,66.88 161.79,66.44 161.59,66.24 160.98,66.24 160.89,66.15 160.89,65.99 161.02,65.86 161.02,65.24 v2(161.22,65.04)
  IN2 w0.076: 139.16,83.98 139.11,83.93 137.05,83.93 136.32,84.67 134.29,84.67 134.03,84.42 134.03,84.16 v2(133.82,83.94)
  IN2 w0.127: v2(154.17,80.43) 154.05,80.55 154.05,80.98 153.56,81.47 153.56,81.83 154,82.27 155.84,82.27 156.95,83.39 156.95,83.75 156.53,84.18 156.11,84.18 155.41,83.48 153.33,83.48 152.49,82.63 152.49,81.16 152.36,81.03 151.98,81.03 151.85,81.16 151.85,82.76 151.59,83.02 150.52,83.02 150.35,83.19 148.22,83.19 148.09,83.31 148.09,83.83 147.81,84.11 147.22,84.11 146.94,83.83 146.94,83.31 146.81,83.19 145.88,83.19 145.75,83.31 145.75,84.37 145.47,84.65 144.88,84.65 144.6,84.37 144.6,84.2 144.47,84.07 144.07,84.07 143.97,84.18 143.97,84.37 143.69,84.65 143.1,84.65 142.82,84.37 142.82,83.31 142.69,83.19 142.31,83.19 142.19,83.31 142.19,84.37 141.91,84.65 141.31,84.65 141.04,84.37 141.04,83.31 140.91,83.19 140.43,83.19 139.63,83.98 139.16,83.98
  BOTTOM w0.091: R5802.2 161.34,64.03 161.17,64.19 161.17,64.56 161.02,64.71 161.02,64.84 v2(161.22,65.04)
  BOTTOM w0.102: v2(133.82,83.94) 133.86,83.9 133.86,83.44 UC1.AF9
USB_PP8_R: length 3.8
  BOTTOM w0.091: WLAN1.3 162.57,62.52 162.49,62.43 162.49,62.28 162.41,62.2 161.73,62.2 161.65,62.13 161.02,62.13 160.95,62.2 160.95,62.38 161.17,62.6 161.17,62.94 161.35,63.11 R5802.1
USBCOMP: length 8.8
  TOP w0.102: v2(135.3,86.07) 135.84,85.53 138.42,85.53 139.54,84.42 v1(141.66,84.42) 141.7,84.45 142.56,84.45 RC44.1
  BOTTOM w0.089: v2(135.3,86.07) 135.3,85.88 135.68,85.5 UC1.AB6
VCI_IN1: length 2.2
  TOP w0.102: v2(190.43,68.39) 190.75,68.07 UE1.126
  BOTTOM w0.102: RE437.1 190.5,67.95 190.5,68.32 v2(190.43,68.39)
VCIN0_PH: length 100.2
  TOP w0.254: v2(122.25,98.3) 122.28,98.28 122.28,94.98 R2610.1
  IN1 w0.254: v2(184.02,81.09) 182.24,81.09 181.16,82.17 179.51,82.17 179.13,81.79 177.22,81.79 175.93,83.08 173.52,83.08 172.83,83.77 166.98,83.77 165.33,85.43 163.21,85.43 160.15,88.48 160.15,89.72 157.73,92.14 153.38,92.14 151.38,94.14 146.93,94.14 140.07,100.99 140.07,105.36 137.72,107.72 v2(137.72,109.3)
  IN2 w0.254: v2(187.89,74.75) 187.03,74.75 184.87,76.91 184.87,80.24 v2(184.02,81.09)
  BOTTOM w0.254: v2(122.25,98.3) 121.9,98.66 R2608.2 R2609.2 122.79,98.96 C2612.1 123.75,99.93 123.75,102.12 131.95,110.32 132.49,110.32 133.02,110.85 135,110.85 135.8,110.05 v1(136.97,110.05) v2(137.72,109.3) ; C2613.1 187.7,74.94 v2(187.89,74.75) 188.37,74.75 RE394.2
VCREF0: length 7.3
  TOP w0.102: v1(194.77,78.37) UE1.25 192.01,78.37 v2(191.89,78.25)
  BOTTOM w0.102: RE396.2 RE397.1 CE91.1 189.83,77.17 190.92,78.25 v2(191.89,78.25)
VD_IN1_C: length 97.9
  TOP w0.254: R2610.2 122.74,94.53 122.74,98 v2(123.04,98.3)
  IN1 w0.254: v2(137.02,109.3) 137.02,107.88 139.69,105.2 139.69,100.83 146.77,93.75 151.23,93.75 153.22,91.76 157.57,91.76 159.77,89.56 159.77,88.32 163.05,85.05 165.15,85.05 166.8,83.39 172.67,83.39 173.37,82.7 175.74,82.7 177.09,81.34 179.38,81.34 179.83,81.79 180.97,81.79 182.37,80.39 v2(183.95,80.39)
  IN2 w0.254: v2(187.89,74.17) 187.07,74.17 184.49,76.75 184.49,79.86 v2(183.95,80.39)
  BOTTOM w0.254: R2611.1 C2613.2 187.75,74.03 v2(187.89,74.17) ; v2(123.04,98.3) C2612.2 123.67,98.95 124.26,99.53 124.26,100.2 124.14,100.33 124.14,101.96 131.96,109.78 135.07,109.78 v1(135.18,109.66) 136.66,109.66 v2(137.02,109.3)
VGA_DMINUS: length 22
  TOP w0.102: UV11.3 183.19,123.6 CV9.2 183.22,123.57 v2(183.83,123.57)
  BOTTOM w0.102: v2(183.83,123.57) 183.88,123.57 184.31,123.14 184.31,122.71 183.22,121.62 v1(175.04,121.62) 174.33,121.62 172.71,123.24 171.59,123.24 170.47,124.37 170.47,126.66 169.84,127.29 UV1.T2
VGA_DPLUS: length 21.5
  TOP w0.102: UV11.2 182.92,122.95 CV9.1 183.65,122.68 v2(183.9,122.94)
  BOTTOM w0.102: v2(183.9,122.94) v1(183.44,122.48) 182.91,121.95 174.33,121.95 172.8,123.47 171.69,123.47 170.67,124.49 170.67,126.74 170.16,127.25 170.16,127.53 169.71,127.99 UV1.T4
VGA_SMB_CK3: length 13
  TOP w0.102: v2(166.96,128.17) 167.9,128.17 168.99,127.08 v1(170.26,127.08) 170.39,127.2 170.87,127.2 171.34,126.73 RV6.2 172.61,127.32 173.85,127.32 174.86,126.31 174.86,125.76 174.71,125.6 174.3,125.6 QV1.1 173.92,125.22 173.92,125.15 RV164.2
  BOTTOM w0.102: v2(166.96,128.17) 167.15,128.36 UV1.U7
VGA_SMB_CK3_R: length 6.7
  TOP w0.102: UV11.8 177.96,122.3 178.36,122.7 178.36,124.8 v1(177.63,125.53) 177.3,125.53 175.98,124.21 RV164.1
VGA_SMB_DA3: length 15.3
  TOP w0.102: RV165.2 RV5.2 173.49,121.67 172.86,122.3 172.14,122.3 171.47,122.98 v1(171.47,123.37) 171.47,124.08 ; v2(166.48,128.65) 166.48,128.07 166.76,127.79 167.21,127.79 167.29,127.86 167.9,127.86 168.89,126.87 169.68,126.87 170.62,125.93 170.62,124.4 170.94,124.08 171.47,124.08 ; 171.47,124.08 171.69,124.3 171.69,124.83 QV1.4
  BOTTOM w0.102: UV1.U8 166.59,128.76 v2(166.48,128.65)
VGA_SMB_DA3_R: length 3.9
  TOP w0.102: UV11.7 176.21,122.95 176.21,122.94 175.9,122.63 RV165.1 175.19,120.95 v1(175.19,120.65)
VIDALERT_N: length 63.2
  IN2 w0.127: v2(120,144.73) 119.34,144.73 119.25,144.82 112.47,144.82 112.26,144.61 111.21,144.61 110.8,145.02 108.27,145.02 105.37,142.12 105.37,117.83 106.22,116.97 v2(106.41,116.97)
  BOTTOM w0.102: v2(106.41,116.97) v1(105.16,116.97) 103.27,116.97 100.48,114.18 100.48,105.44 99.18,104.14 99.18,103.25 RC152.2 RC153.2 ; v2(120,144.73) 119.45,144.73 PR607.1
VIDSCLK: length 64.2
  IN2 w0.127: v2(107.09,116.95) v1(106.62,116.48) 105.92,116.48 104.94,117.47 104.94,142.38 108.01,145.45 110.71,145.45 110.87,145.61 113.03,145.61 v2(113.41,145.98)
  BOTTOM w0.076: UC1.A63 102.6,96.79 102.6,98.3 102.04,98.85 102.04,99.27 100.9,100.41 100.9,100.46
  BOTTOM w0.102: v2(113.41,145.98) 113.84,145.55 PR606.1 ; 100.9,100.46 100.9,103.02 101.34,103.45 101.34,104.65 100.96,105.03 100.96,113.98 103.46,116.48 v1(106.62,116.48) v2(107.09,116.95)
VIDSOUT: length 70.3
  IN2 w0.127: v2(106.42,117.58) 105.8,118.2 105.8,141.63 108.02,143.85 110.59,143.85 110.87,144.12 112.39,144.12 112.66,144.38 118.21,144.38 v2(118.83,143.76)
  BOTTOM w0.076: 102.04,98.34 102.24,98.14 102.24,96.05 102.46,95.83 102.46,95.59 102.16,95.3 UC1.D64
  BOTTOM w0.102: 102.04,98.34 101.7,98.67 100.72,98.67 100.43,98.96 99.9,98.96 98.85,100.01 RC157.2 99.43,101.31 99.43,102.31 98.67,103.07 98.67,104.46 99.99,105.78 99.99,114.38 v1(103.19,117.58) v2(106.42,117.58) ; PR609.1 118.31,144.28 v2(118.83,143.76)
VL: length 0.8
  TOP w0.102: v2(47.96,37.24) 47.96,37.96 v3(47.94,37.99)
VR_ALERT#: length 2.1
  TOP w0.203: 116.25,143.39 PU602.36
  TOP w0.254: PR625.2 116.64,144.45 116.25,144.06 116.25,143.39
VR_CAP: length 5.4
  TOP w0.102: UE1.18 191.83,75.57 191.48,75.22 191.48,74.59 v2(191.92,74.16)
  BOTTOM w0.102: C5224.1 T4931.1 191.06,73.31 191.91,74.16 v2(191.92,74.16)
VR_SCLK: length 2
  TOP w0.203: PU602.37 115.85,143.23
  TOP w0.254: 115.85,143.23 115.9,143.27 115.9,144.33 PR618.2
VR_SDA: length 2.4
  TOP w0.203: PU602.35 116.65,143.75 116.87,143.97 117.15,143.97 117.25,144.07
  TOP w0.254: PR626.2 117.53,144.35 117.25,144.07
VRALERT#: length 20.8
  TOP w0.102: RC73.1 145.71,81.94 144.97,81.19 144.97,79.43 144.02,78.49 138.17,78.49 137.03,79.63 134.88,79.63 134.69,79.81 134.25,79.81 133.96,79.53 v1(133.96,78.5) 133.96,77.96 133.79,77.79 133.28,77.79 132.77,78.3 132.77,78.99 131.78,79.99 v2(131.66,79.99)
  BOTTOM w0.089: UC1.AM11 132.1,80.42 v2(131.66,79.99)
VRAM_ID1: length 23.4
  TOP w0.076: 137.66,78.26 139.12,78.26
  TOP w0.102: 137.66,78.26 136.48,79.44 134.45,79.44 134.44,79.43 v2(134.42,79.43) ; 139.12,78.26 144.33,78.26 144.45,78.14 148.86,78.14 149.23,78.51 150.83,78.51 150.95,78.63 v1(150.95,79.15) 150.95,80.1 151.19,80.34 151.19,81.52 RC378.2 152.1,82.36 152.79,81.68 RC380.1
  BOTTOM w0.102: UC1.AP8 134.29,79.43 v2(134.42,79.43)
VRAM_ID2: length 23.1
  TOP w0.102: v2(144.07,76) 144.32,76.26 147.77,76.26 149.96,74.07 v1(150.98,74.07) 151.85,74.07 RC379.2 RC381.1
  BOTTOM w0.076: UC1.AW7 134.71,75.88 135.05,75.55 135.05,74.2 135.18,74.07 135.49,74.07 135.95,73.61 136.18,73.61 136.75,73.03 139.45,73.03 139.9,73.48 140.43,73.48
  BOTTOM w0.102: 140.43,73.48 140.62,73.29 141.44,73.29 144.07,75.91 v2(144.07,76)
VSA_SEN+: length 62.9
  TOP w0.254: v2(127.12,92.28) 127.12,91.96 v1(126.45,91.3) 125.57,91.3 RC168.2 ; PR649.2 PC640.2 122.42,140.31 122.74,139.99 v2(122.74,139.11)
  IN1 w0.254: v2(122.74,139.11) 122.74,137.87 125.24,135.37 125.24,131.51 125.87,130.88 125.87,114 124.01,112.14 124.01,107.3 124.96,106.34 124.96,103.82 123.82,102.68 123.29,102.68 121.39,100.77 121.39,100.03 121.82,99.59 125.76,99.59 126.66,98.7 126.66,92.73 127.11,92.28 v2(127.12,92.28)
  BOTTOM w0.254: UC1.H20 127.39,92.01 v2(127.12,92.28) ; PC650.1 PC652.1 122.43,139.42 v2(122.74,139.11)
VSA_SEN-: length 77.9
  TOP w0.203: PU602.26 119.86,140.28 119.91,140.33 v2(120.52,140.33)
  TOP w0.254: RC166.1 125.53,103.37 125.53,100.01 124.71,99.19 124.71,96.71 125.09,96.33 125.09,95.06 125.45,94.7 v1(125.45,92.43) 125.45,92.35 126.05,91.75 v2(126.23,91.75)
  IN1 w0.254: v2(126.23,91.75) 126.06,91.75 125.74,92.07 125.74,94.43 126.17,94.86 126.17,98.37 125.33,99.21 121.64,99.21 120.96,99.89 120.96,100.96 123.12,103.12 123.5,103.12 124.45,104.08 124.45,106.28 123.63,107.1 123.63,112.39 125.42,114.19 125.42,130.78 124.86,131.35 124.86,135.21 122.23,137.85 122.23,138.63 v2(120.52,140.33)
  BOTTOM w0.254: v2(120.52,140.33) 120.68,140.17 120.68,139.04 PC650.2 121.22,138.4 122.05,137.57 PC649.1 ; v2(126.23,91.75) 126.23,91.75 126.4,91.75 UC1.H21
VSUM+_VGA: length 12.4
  TOP w0.102: v2(155.93,114.5) v1(155.93,115.05)
  TOP w0.254: PR1126.1 156.5,113.92 v2(155.93,114.5) 155.49,114.05 PR1108.1
  IN1 w0.254: v2(155.93,114.5) 157.65,112.78 157.65,111.27 v2(157.66,111.25)
  BOTTOM w0.203: PU1100.14 158.76,110.41 157.92,111.25 v2(157.66,111.25)
  BOTTOM w0.254: PR1132.1 v2(155.93,114.5) 155.68,114.5 PC1230.1 ; PR1132.1 PC1232.1 ; PR1132.1 PR1131.1
VSUM-_VGA: length 34.9
  BOTTOM w0.254: PC1119.1 PC1120.1 157.07,112.98 157.22,112.83 PR1136.1 157.58,113.66 PR1137.1 ; PR1137.1 156.99,113.69 PC1230.2 ; PR1137.1 157.59,113.72 157.59,114.09 157.77,114.27 PC1231.1 157.77,115.41 157.75,115.43 PR1110.1 ; PR1132.2 PC1232.2 157.04,116.1 157.31,115.83 PR1110.1 ; PR1110.1 PR1128.1 158.93,115.83 159.1,115.66 159.5,115.66 159.66,115.82 170.11,115.82 170.49,115.44 179.18,115.44 v1(179.2,115.42) 181.12,115.42 182,114.54 182,112.85 PH1102.2
WAKEB: length 6.4
  BOTTOM w0.102: UV1.AJ27 149.47,133.21 149.36,133.1 149.36,132.66 149.54,132.49 149.54,131.85 148.7,131.01 v1(148.7,130.25) 148.7,129.46 RV163.1 RV162.2
WEA0#: length 43.2
  TOP w0.102: UV18.L3 177.02,165.21 176.47,165.21 175.94,165.74 175.94,166.33 v2(175.91,166.36)
  IN1 w0.102: v2(162.82,144.1) 162.82,144.58 163.51,145.26
  IN1 w0.264: 163.51,145.26 163.57,145.26 164.55,146.24 169.94,146.24 174.45,150.75 174.82,150.75 175.19,150.39 175.56,150.39 175.93,150.76 175.93,151.13 175.57,151.5 175.57,151.87 176.16,152.47 176.16,156.96 178.49,159.29 178.49,160.5 179.75,161.77 180.13,161.77 v2(180.64,161.25)
  IN2 w0.102: 180.11,162.27 178.17,164.21 178.17,165.16 177.67,165.67 177.16,165.67 176.47,166.36 v2(175.91,166.36)
  IN2 w0.264: v2(180.64,161.25) 180.65,161.25 180.65,161.73 180.11,162.27
  BOTTOM w0.102: UV1.G25 162.77,144.15 v2(162.82,144.1) ; UV17.L3 174.96,167.35 175.12,167.5 175.12,167.5 175.13,167.51 175.69,167.51 175.79,167.41 175.79,167.26 175.61,167.08 175.61,166.75 175.71,166.64 175.71,166.56 v2(175.91,166.36)
WEA1#: length 43.3
  TOP w0.102: UV20.L3 190.17,152.06 190.17,152.68 189.94,152.91 v2(189.35,152.91)
  IN2 w0.102: v2(189.35,152.91) 187.45,152.91 186.18,154.18 184.52,154.18 ; v2(170.02,135.61) 170.02,136.62 170.74,137.35 170.74,137.81 168.65,139.91 168.65,140.48 171.76,143.6
  IN2 w0.264: 184.52,154.18 181.95,151.61 180.4,151.61 177.89,154.12 177.05,154.12 172.75,149.82 172.75,146.51 171.76,145.52 171.76,143.6
  BOTTOM w0.102: v2(189.35,152.91) 189.17,153.09 189.02,153.09 188.88,152.95 188.74,152.95 188.57,153.12 188.57,153.27 188.87,153.57 188.87,153.71 188.67,153.91 188.53,153.91 UV19.L3 ; v2(170.02,135.61) 170.03,135.62 UV1.H10
WHITE_LED_BAT: length 3.8
  TOP w0.508: Q6102.1 30.36,4.88 v1(29.7,4.88) EC6103.1 R6107.2
WLAN_DISABLE#1: length 10.8
  TOP w0.102: v2(172.21,49.27) v1(171.72,48.78)
  IN2 w0.127: v2(174.71,43.08) 173.87,43.93 173.87,45.69 172.21,47.35 v2(172.21,49.27)
  BOTTOM w0.102: WLAN1.48 v2(172.21,49.27) ; v2(174.71,43.08) 175.18,42.61 D5503.2
WLAN_RADIO_DIS#: length 110.3
  IN1 w0.127: v2(140.01,98.54) 141.53,98.54 142.1,97.97 142.1,97.98 146.64,93.44 151.09,93.44 153.12,91.41 156.48,91.41 157.85,90.04 157.85,89.79 163.57,84.07 165.6,84.07 166.6,83.08 172.54,83.08 173.23,82.38 175.42,82.38 177.73,80.07 178.94,80.07 180.11,81.25 181,81.25 183.44,78.8 186.56,78.8 187.83,77.53 187.83,76.39 187.04,75.6 187.04,71.03 186.85,70.84 186.85,68.24 184.84,66.23 182.06,66.23 181.41,65.57 181.41,63.88 v2(178.68,61.15)
  BOTTOM w0.076: UC1.B7 134.94,96.23 136.12,97.41
  BOTTOM w0.102: D5503.1 176.97,41.72 175.44,43.24 175.44,48.32 176.21,49.09 176.21,55.12 178.68,57.59 v2(178.68,61.15) ; 140.01,98.55 140.74,99.28 v1(140.74,99.62) RE439.1 ; 140.01,98.55 139.77,98.55 138.4,97.18 137.07,97.18 136.77,97.47 136.18,97.47 136.12,97.41 ; 140.01,98.55 v2(140.01,98.54)
XCLK_BIASREF: length 17.2
  TOP w0.076: v1(127.02,89.61) 125.83,89.61 RC52.1
  TOP w0.254: RC52.1 125.41,88.74 v2(125.28,88.6)
  IN1 w0.254: v2(125.28,88.6) 125.03,88.85 125.03,89.07 124.64,89.46 124.64,91.49 123.06,93.08 123.06,93.66 122.23,94.49 115.44,94.49 v2(115.19,94.23)
  BOTTOM w0.254: UC1.E42 114.92,93.96 v2(115.19,94.23)
XDP_HOOK0: length 1.4
  BOTTOM w0.102: RC158.2 154.25,55.41 T49.1
XDP_ITP_PMODE: length 9.4
  BOTTOM w0.076: UC1.E8 133.98,94.01 133.51,94.47 133.51,96.16 133.41,96.26 133.41,96.46 133.38,96.51 133.38,97.24 133.34,97.28 133.34,97.41
  BOTTOM w0.102: RC353.2 135.37,101.08 135.33,101.04 RC115.1 134.15,100.38 T47.1 133.34,97.41
XDP_OBS0_R: length 4.3
  BOTTOM w0.076: T4942.1 107.01,99.3 107.01,96.38 107.12,96.28 UC1.C55
XDP_OBS1_R: length 5.2
  BOTTOM w0.076: UC1.D55 107.12,95.28 107.45,95.61 107.45,95.83 107.37,95.91 107.37,96.28 107.18,96.47 107.18,99.07 107.78,99.67
  BOTTOM w0.102: T4941.1 107.78,99.67
XDP_OBS2_R: length 2.7
  BOTTOM w0.076: UC1.B54 107.68,96.22 107.42,96.49 107.42,98.06 T10.1
XDP_OBS3_R: length 3.5
  BOTTOM w0.076: UC1.C56 106.56,95.56 106.83,95.83 106.83,98.13 106.44,98.51 T11.1
XDP_PRDY#: length 6.1
  BOTTOM w0.076: UC1.D56 106.34,95.06 106.26,95.33 106.26,95.44 106.12,95.92 106.12,96.17 106.13,96.19 106.15,96.2 106.15,96.23 106.16,96.26 106.16,96.47 106.12,96.54 106.12,96.91 106.25,97.03 106.25,97.4 105.83,97.82 105.83,99.91 T51.1
XDP_PREQ#: length 4.1
  BOTTOM w0.076: T50.1 103.86,98.13 104.37,97.63 104.37,95.85 104.35,95.83 104.35,95.59 104.37,95.57 104.37,95.2 104.35,95.18 104.35,95 UC1.D61
XDP_PRSENT_CPU: length 4.8
  BOTTOM w0.102: T52.1 91.09,99.42 92.67,99.42 92.97,99.72 RC43.1 92.97,100.91 93.16,101.1 RC1104.1
XDP_PRSENT_PCH: length 5
  TOP w0.102: v2(154.43,73.35) 154.71,73.63 155.07,73.63 v1(155.44,73.26) 155.84,72.86 RC347.1
  BOTTOM w0.102: v2(154.43,73.35) 154.36,73.27 153.31,73.27 152.47,74.11 RC1105.1
XDP_SPI_IO2: length 7.4
  BOTTOM w0.102: RC1105.2 152.47,75.44 151.87,76.04 150.89,76.04 150.33,75.48 149.46,75.48 v1(148.98,75.97) 146.21,75.97 RC354.1
XDP_SPI_SI: length 3.6
  BOTTOM w0.102: RC9.2 156.01,72.63 155.02,73.62 T48.1 154.84,73.62 154.08,74.38 RC355.1
XTAL24_IN: length 20.9
  BOTTOM w0.102: YC1.3 124.26,108.5 CC21.1 124.26,105.42 124.12,105.28 RC46.2 124.12,104.18 v1(123.79,103.85) 123.27,103.32 123.07,103.32 120.09,100.34 117.93,100.34 117.09,99.49 117.09,96.2 116.71,95.83 116.71,95.59 116.82,95.48 116.82,95.3 116.69,95.17 116.69,94.94 116.82,94.82 116.82,94.66 UC1.E37
XTAL24_OUT: length 20.8
  BOTTOM w0.102: YC1.1 126.47,106.81 125.47,106.81 125.2,106.54 CC22.1 125.2,105.45 125.04,105.28 RC46.1 125.04,104.47 123.3,102.74 123,102.74 v1(120.66,100.4) 120.16,99.9 118.23,99.9 117.53,99.2 117.53,97.53 117.3,97.3 117.3,95.87 117.34,95.84 117.34,95.58 117.29,95.54 117.29,95.26 117.34,95.21 117.34,94.93 117.29,94.89 117.29,94.61 117.59,94.31 118.06,94.31 118.41,93.96 UC1.E35
XTALIN: length 7.5
  BOTTOM w0.102: YV1.1 143.12,132.7 143.12,132.17 143.92,131.37 CV17.1 144.72,131.37 RV20.1 145.29,131.58 146.28,131.58 UV1.AM28
XTALOUT: length 9.9
  BOTTOM w0.102: YV1.3 141.82,130.1 143.54,130.1 143.74,130.3 CV18.1 144.88,130.3 RV20.2 145.52,130.9 v1(145.87,130.9) 146.03,130.9 148.44,133.31 148.44,133.51 148.63,133.7 UV1.AK28
N16741477: length 1.4
  TOP w0.102: v2(163.81,126.19) 163.81,125.4 T212.1
  BOTTOM w0.102: UV1.AB8 164.04,126.72 164.04,126.42 v2(163.81,126.19)
N16741489: length 2.9
  TOP w0.102: T208.1 164.84,124.88 v2(163.9,124.88)
  BOTTOM w0.102: UV1.AD7 v2(163.9,124.88)
N16741505: length 5.4
  BOTTOM w0.102: UV1.AB4 166.07,124.4 166.07,123.93 166.6,123.39 166.6,120.6 166.81,120.4 T214.1
N16741517: length 1.3
  TOP w0.102: T206.1 160.97,126.03 v2(161.65,126.03)
  BOTTOM w0.102: UV1.AD9 161.65,126.01 v2(161.65,126.03)
N16741525: length 2.6
  TOP w0.102: v2(165.65,127.65) 165.69,127.69 166.53,127.69 166.73,127.48 T216.1
  BOTTOM w0.102: v2(165.65,127.65) 164.97,127.65 UV1.Y8
N16741803: length 1.5
  TOP w0.508: RV29.2 154.77,133.98 v2(154.92,133.98)
  BOTTOM w0.254: v2(154.92,133.98) 155.12,133.79 UV1.AC22
N16741825: length 1.5
  TOP w0.508: v2(155.33,134.67) 154.94,135.06 RV59.2
  BOTTOM w0.305: UV1.AB22 155.5,134.49 v2(155.33,134.67)
N16751828: length 1.5
  TOP w0.102: T209.1 162.19,125.45 v2(162.74,126.01)
  BOTTOM w0.102: UV1.AC8 v2(162.74,126.01)
N16751830: length 2.7
  TOP w0.102: v2(162.73,124.84) 163.33,124.84 163.7,124.47 164.68,124.47 T205.1
  BOTTOM w0.102: UV1.AE8 162.24,124.84 v2(162.73,124.84)
N16751834: length 1.9
  TOP w0.102: v2(161.63,124.89) 162.11,124.89 162.69,124.31 T203.1
  BOTTOM w0.102: v2(161.63,124.89) 161.64,124.9 UV1.AE9
N16751836: length 1.6
  TOP w0.102: v2(168.02,132.14) 167.7,131.82 T201.1
  BOTTOM w0.102: UV1.N9 168.24,132.37 v2(168.02,132.14)
N16751838: length 3.3
  BOTTOM w0.102: UV1.AB2 166.44,123.86 166.81,123.49 166.81,121.03 T215.1
N16751842: length 1.6
  TOP w0.102: T211.1 164.01,126.75 v2(163.25,126.75)
  BOTTOM w0.102: v2(163.25,126.75) 163.25,127.06 UV1.AB9
N16751844: length 1.1
  TOP w0.102: T207.1 162.73,126.73 v2(162.73,127.25)
  BOTTOM w0.102: UV1.AC10 162.63,127.14 v2(162.73,127.25)
N16751848: length 1.3
  TOP w0.102: v2(169.14,132.65) 169.01,132.65 T202.1
  BOTTOM w0.102: UV1.L9 169.41,132.99 169.14,132.72 v2(169.14,132.65)
N16751852: length 1.2
  TOP w0.102: T213.1 165.18,125.83 v2(165.18,126.32)
  BOTTOM w0.102: UV1.AB7 165.01,126.15 v2(165.18,126.32)
N16751854: length 4.2
  TOP w0.102: T210.1 166.6,123.59 164.8,125.39 v2(164.42,125.39)
  BOTTOM w0.102: v2(164.42,125.39) 163.95,125.39 UV1.AC7
N16751856: length 1.7
  TOP w0.102: v2(164.19,129.11) 163.89,128.8 T204.1
  BOTTOM w0.102: UV1.Y11 v2(164.19,129.11)
N16751858: length 2
  TOP w0.102: v2(166.12,126.03) 166.12,126.62 T217.1
  BOTTOM w0.102: 165.45,127 165.64,126.81 165.64,126.52 v2(166.12,126.03)
N16813004: length 4.4
  BOTTOM w0.102: RV84.2 155.23,118.88 RV87.2 154.06,118.82 v1(153.78,118.82) 153.28,118.82 RV72.1 RV71.2
N17237617:
  vias: v1(122.7,152.44) v2(123.37,156.46) v2(123.37,155.7) v2(123.82,156.84) v2(123.82,156.08)
N17242539: length 3
  TOP w0.102: RV58.1 183.19,124.93 v1(183.88,125.62)
  TOP w0.254: RV58.1 182.85,124.25 UV11.4
N17268429: length 6.3
  TOP w0.254: PR790.1 69.02,162.66 PR791.2 v1(69.04,166.65) 69.65,167.26 PQ720.1
N17415515:
  vias: v3(99.24,160.62)
N17421985: length 5
  TOP w0.254: v2(116.42,146.21) 116.13,146.49 PC695.2 115.76,146.48 PR618.1
  BOTTOM w0.102: v1(114.75,146.44) PR606.2
  BOTTOM w0.254: PR606.2 115.48,145.36 PR601.2 115.63,145.52 116.32,146.21 v2(116.42,146.21)
N17847259: length 3.7
  BOTTOM w0.102: 159.09,122.9 158.48,122.9 157.84,122.26 157.84,120.68 T4935.1
N17877344: length 1.6
  BOTTOM w0.102: T223.1 171.74,126.66 UV1.R1
N17877347: length 3.7
  BOTTOM w0.102: UV1.R3 170.12,128.18 170.36,127.94 170.36,127.34 171.25,126.45 T224.1
N18941428: length 0.9
  TOP w0.254: PC640.1 122.12,139.38 PR646.2
N18941436: length 2
  TOP w0.102: PC601.1 122.99,137.06 v1(123.44,136.61)
  TOP w0.254: PR652.2 122.92,137.63 PC601.1
N18941447: length 4.5
  TOP w0.102: PR636.1 121.14,142.85 v1(121.65,143.36)
  TOP w0.203: 120.01,141.41 119.88,141.41 119.55,141.08 PU602.28
  TOP w0.254: PR636.1 PC632.1 121.12,141.41 120.01,141.41
N18941448: length 2.4
  TOP w0.254: PR641.1 v1(123.36,141.44) PC632.2
N18941457: length 27.5
  TOP w0.254: v2(124.49,117.07) 125.56,118.14 125.56,126.62 124.59,127.58 124.59,131.24 123.5,132.33 v1(123.5,134.48) 123.5,135.69 124.2,136.39 124.2,138.3 123.32,139.18 123.32,140.19 v2(122.7,140.81)
  BOTTOM w0.254: PH604.1 v2(124.49,117.07) ; v2(122.7,140.81) 122.37,140.81 122.12,140.56 PR642.2
N18941471: length 5.9
  TOP w0.254: PR625.1 117.01,145.75 v2(117.01,146.17)
  BOTTOM w0.254: PR607.2 119.2,146.52 118.78,146.94 117.27,146.94 v1(117.15,146.82) 117.01,146.69 v2(117.01,146.17) 117.01,146.01 PR604.2
N18941481: length 3.2
  TOP w0.102: v1(118.09,146.49) 118.01,146.49 v2(117.68,146.16)
  TOP w0.254: PR626.1 117.53,146.02 v2(117.68,146.16)
  BOTTOM w0.254: PR609.2 PR605.2 117.42,145.9 v2(117.68,146.16)
N18941485: length 4.8
  TOP w0.102: v1(111.69,145.46) 111.69,145.45 112.13,145.45 112.38,145.2 112.38,144.96 112.86,144.47 PR658.2
  TOP w0.254: PU602.40 114.08,142.56 112.96,143.67 PR658.2
N18941487: length 2.1
  TOP w0.203: PU602.39 115.05,143.02 114.69,143.38
  TOP w0.254: PR612.2 114.69,144.42 114.69,143.38
N18941496: length 4.6
  TOP w0.203: PU602.38 115.45,143.42 115.44,143.43 115.44,143.43 v2(115.15,143.73)
  BOTTOM w0.254: v2(115.15,143.73) 114.68,143.26 113.45,143.26 v1(113.13,143.58) 112.97,143.73 PR678.2
N18941497: length 3.5
  TOP w0.203: v2(117.13,143.49) 117.05,143.42 PU602.34
  BOTTOM w0.254: PC603.1 116.92,143.7 v2(117.13,143.49) 117.66,142.96 PR602.1
N18941498: length 10.6
  TOP w0.203: PU602.33 117.45,143.11 117.74,143.39 v2(117.74,143.77)
  IN1 w0.254: v2(117.74,143.77) 118.23,143.28 119.28,143.28 120.12,144.12 121.38,144.12 122.17,144.91 v2(122.74,144.91)
  BOTTOM w0.102: PR603.1 v1(124.77,146.72)
  BOTTOM w0.254: v2(122.74,144.91) 123.5,145.67 PC604.1 124.76,145.67 PR603.1
N18941511: length 2.2
  TOP w0.203: PU602.32 117.85,143.03 118.27,143.45
  TOP w0.254: 118.27,143.45 118.27,144.32 PR608.1
N18941513: length 4.2
  TOP w0.102: v1(120.73,144.35) 120.63,144.25 119.9,144.25 119.68,144.47 PR611.1
  TOP w0.203: PR611.1 119.31,143.06 118.8,142.56 PU602.31
N18941562: length 4
  TOP w0.254: PR640.1 119.87,134.6 PC630.1 119.51,135.82 v1(119.51,136.47) 119.51,136.92 118.82,137.61 PU602.20
N18941580: length 20.3
  IN1 w0.254: v2(117.13,115.95) 117.13,121.16 117.97,122.01 117.97,133.34 v2(117.46,133.86)
  BOTTOM w0.102: v2(117.46,133.86) v1(117.46,133.35)
  BOTTOM w0.254: PH605.1 v2(117.13,115.95) ; PR657.2 117.3,134.01 v2(117.46,133.86)
N18941616: length 1.3
  TOP w0.254: PC639.2 116.77,133.65 115.96,134.47 PR645.1
N18941625: length 2.2
  TOP w0.102: PC647.2 v1(117.2,131.39)
  TOP w0.254: PR650.2 PC647.2
N18941629: length 1.1
  BOTTOM w0.254: PR639.1 117.7,138 PC629.2
N18941656: length 4.3
  TOP w0.102: v1(107.97,140.22) 107.97,139.17 108.42,138.72 PR632.2
  TOP w0.254: PC627.1 110.12,138.71 PR632.2
N18941661: length 142
  TOP w0.254: v2(44.82,69.41) 47.17,67.06 49.97,67.06 54.16,62.86 59.49,62.86 62.54,59.82 62.54,52.83 63.13,52.25 v2(63.39,52.25) ; v2(93.97,111.19) 92.32,109.54 92.32,105.16 90.82,103.65 90.82,101.11 73.92,84.21 71.23,84.21 68.62,81.6 67.63,81.6 v2(65.94,79.91)
  IN1 w0.254: v2(65.94,79.91) 64.25,78.22 61.79,78.22 61.29,78.73 53.64,78.73 51.43,76.52 46.79,76.52 46.35,76.07 46.35,74.8 45.27,73.72 45.27,71.63 45.33,71.56 45.33,69.91 v2(44.82,69.41)
  BOTTOM w0.254: PH602.1 64.01,52.25 v2(63.39,52.25) ; PR628.2 108.62,140.08 107.24,138.7 106.57,138.7 v1(106.29,138.42) 103.79,135.93 103.79,125.51 98.61,120.33 98.61,112.84 96.96,111.19 v2(93.97,111.19)
N18941667: length 3.5
  TOP w0.203: v1(112.86,138.59) 113.35,139.08 PU602.8
  TOP w0.254: PC627.2 PR638.2 112.09,137.82 v1(112.86,138.59)
N18941711: length 1.8
  TOP w0.102: PC621.2 109.18,142.52 v1(109.18,142.52)
  TOP w0.254: PR623.1 PC621.2
N18941712: length 4.1
  TOP w0.203: PU602.5 113.06,140.28
  TOP w0.254: 113.06,140.28 112.97,140.37 v1(112.81,140.37) 112.26,140.37 PR622.2 111.87,140.74 PR621.2 PR623.2
N18941722: length 3.8
  TOP w0.203: v2(112.67,140.86) 113.11,140.86 113.29,140.68 PU602.4
  BOTTOM w0.102: v2(112.67,140.86) 112.35,140.54 v1(112.35,140.22)
  BOTTOM w0.254: v2(112.67,140.86) 112.73,140.93 PC616.2 PR617.2
N18941723: length 0.9
  BOTTOM w0.254: PR617.1 PC614.2
N18941731: length 2.3
  TOP w0.203: PR610.2 112.18,141.32 113.16,141.32 113.39,141.08 PU602.3
N18941735: length 3.6
  TOP w0.203: PU602.2 113.47,141.48 113.15,141.8 113.15,142.01 v2(112.71,142.45)
  BOTTOM w0.254: PR613.2 PC613.2 113.33,141.83 v2(112.71,142.45)
N18941759: length 3.9
  TOP w0.102: PR621.1 110.09,140.77 109.38,141.48 108.41,141.48 v1(108.11,141.78)
  TOP w0.254: PR621.1 109.12,139.77 PC617.2
N18941760: length 1.9
  BOTTOM w0.102: v1(117.53,142.06) 117.55,142.08 PC631.1
  BOTTOM w0.254: PC631.1 PR630.2
N18941767: length 2.1
  TOP w0.102: PR644.1 121.78,134.59 v1(121.9,134.47)
  TOP w0.254: PR644.1 120.78,134.6 PC630.2
N18941770:
  vias: v1(121.21,133.24)
N18941771: length 1.6
  BOTTOM w0.102: PC611.1 119.37,132.4 119.37,132.69 v1(119.08,132.98)
N18941791: length 168.5
  TOP w0.254: PR631.2 111.88,143.39 PR610.1 111.88,142.51 v2(112.6,141.79) ; v2(44.13,69.47) 44.63,69.98 45.21,69.98 47.68,67.5 50.16,67.5 54.29,63.37 59.62,63.37 62.99,60.01 62.99,57.91 63.68,57.21 71.43,57.21 v1(72.35,56.3) 72.35,46.13 71.99,45.77 v2(71.63,45.77)
  IN1 w0.254: v2(65.26,79.91) 64.06,78.71 62,78.71 61.49,79.22 53.43,79.22 51.17,76.96 46.6,76.96 45.97,76.33 45.97,75.06 44.82,73.91 44.82,70.17 v2(44.13,69.47) ; v2(96.88,114.8) 104.61,122.53 104.61,134.64 108.07,138.1 111.26,138.1 112.01,138.86 112.01,141.2 v2(112.6,141.79)
  BOTTOM w0.254: v2(65.26,79.91) 66.18,80.84 70.61,80.84 72.7,82.93 76.51,82.93 88.53,94.95 88.53,99.59 91.81,102.87 91.81,105.54 92.64,106.36 92.64,109.25 92.13,109.76 92.13,111.75 93.35,112.97 96.13,112.97 96.64,113.47 96.64,114.56 v2(96.88,114.8) ; PH601.2 71.76,45.64 v2(71.63,45.77)
N18941811: length 17.1
  IN1 w0.254: v2(115.32,133.78) 115.32,133.53 117.28,131.57 117.28,123.18 v2(115.83,121.73)
  BOTTOM w0.102: PH603.2 v1(116.8,122.38)
  BOTTOM w0.254: v2(115.83,121.73) PH603.2 ; PR635.1 114.62,135.37 PR647.2 115.32,134.26 v2(115.32,133.78)
N18941826: length 8
  TOP w0.102: v2(123.44,124) v1(123.44,123.5)
  IN2 w0.508: v2(123.44,124) 123.02,124 122.69,124.33 122.69,129.16 v2(123.51,129.98)
  BOTTOM w0.508: PQ601.8 v2(123.44,124)
N18941830: length 12.9
  IN1 w0.508: v2(120.31,123.29) 120.14,123.46 120.14,130.33 120.77,130.96 v2(120.77,132.46)
  BOTTOM w0.102: v2(120.31,123.29) 119.41,123.29 118.37,122.25 v1(118.37,122.03)
  BOTTOM w0.508: PQ601.1 120.06,123.54 v2(120.31,123.29)
N18941848: length 1.9
  BOTTOM w0.254: PR679.1 122.6,128.6 121.85,129.35 PU606.7
N18941869: length 39
  TOP w0.102: v2(120.2,146.28) 120.2,145.92 v1(120.36,145.76)
  IN2 w0.254: v2(120.2,146.28) 120.53,146.28 122.67,144.14 123.06,144.14 124.07,143.13 124.07,141.1 125.16,140.01 125.16,136.53 123.56,134.93 123.56,132.37 122.99,131.8 122.99,130.68 121.8,129.49 121.8,128.18 119.39,125.77 119.39,121.51 118.8,120.92 118.8,117.7 119.36,117.14 120.99,117.14 v2(121.13,117.28)
  BOTTOM w0.254: v2(120.2,146.28) 120.78,145.69 PR624.1 ; PL601.3 v2(121.13,117.28)
N18944084: length 27.1
  IN2 w0.254: v2(122.04,133.65) 122.04,132.97 121.07,132 121.07,131.5 119.64,130.07 119.64,128.42 117.68,126.46 117.68,122.51 117.02,121.86 117.02,118.01 116.42,117.41 113.07,117.41 v2(112.88,117.6)
  BOTTOM w0.102: v1(122.75,133.79) 122.61,133.65 v2(122.04,133.65)
  BOTTOM w0.254: v2(122.04,133.65) 122.04,133.97 122.32,134.25 PR661.1 ; v2(112.88,117.6) PL603.3
N18944130: length 1
  BOTTOM w0.102: PC671.2 v1(66.08,37.36)
N18944132: length 1.3
  BOTTOM w0.102: v1(68.26,34.81) PR672.1 68.26,36.07
N18944141: length 3.2
  BOTTOM w0.254: PU603.5 113.51,128.17 113.8,128.46 v2(114.22,128.46) 114.54,128.46 115.5,129.42 PC655.2
N18944142: length 2.5
  BOTTOM w0.254: PU603.3 112.51,128.23 113.12,128.84 113.72,128.84 PR660.2
N18944143: length 3.4
  BOTTOM w0.102: v1(116.59,132.12) 116.59,131.33 116.01,130.75 PC655.1
  BOTTOM w0.254: PR660.1 PC655.1
N18944153: length 18.4
  TOP w0.102: PR659.1 v1(122.1,135.76)
  TOP w0.254: PR659.1 122.66,136.73 v2(122.74,136.65)
  IN2 w0.254: v2(122.74,136.65) 122.33,136.25 121.09,136.25 119.33,134.49 119.33,131.97 117.79,130.43 114.86,130.43 113.07,128.63 111.93,128.63 v2(111.81,128.76)
  BOTTOM w0.254: PU603.1 111.51,128.32 111.81,128.61 v2(111.81,128.76)
N18944154:
  vias: v1(58.64,45.68)
N18944256: length 1.7
  BOTTOM w0.254: PR671.1 70.73,37.47 v2(70.28,37.92) 69.82,38.38 PU605.1
N18987516: length 20.9
  TOP w0.102: v1(39.53,38.53) 39.48,38.58 v2(38.77,38.58)
  TOP w0.254: PR120.2 49.61,39.27 PR114.2 48.72,41 PC128.1 48.7,41.85 PD102.2 47.74,42.81 PR122.1 47.74,44.58 v2(47.68,44.64) ; v2(38.77,38.58) 38.28,38.58 PR121.2
  IN2 w0.254: v2(47.68,44.64) 47.58,44.74 43.02,44.74 39.17,40.89 39.17,39.88 38.66,39.37 38.66,38.68 v2(38.77,38.58)
N19901660: length 2
  TOP w0.102: v1(181.78,87.97) CE78.1 181.79,86.86 R2455.1
N20173493: length 5.6
  TOP w0.102: UE1.120 188.35,66.36 188.27,66.29 RE356.1 188.27,64.83 188.78,64.33 188.78,62.31 RE358.1
N20440449: length 3.3
  TOP w0.102: RE348.1 CE71.1 183.57,84.2 183.15,83.77 UE1.54
N23700319: length 8.7
  TOP w0.102: v1(92.16,159.79) 92.09,159.73
  TOP w0.254: 92.09,159.73 PR6.2 93.59,158.62 PD4.2 94.16,158.05 94.16,155.32 93.91,155.07 PQ6.1 ; v1(92.16,159.79) 92.2,159.83 PL2.1
N28424999: length 6.9
  BOTTOM w0.076: UC1.AW71 97.71,75.7 97.02,75.7 96.18,74.85 94.67,74.85
  BOTTOM w0.102: 94.67,74.85 93.94,74.85 92.88,75.92 92.88,76.49 T113.1
N28425002: length 9
  BOTTOM w0.076: 94.67,74.63 96.21,74.63 97.11,75.53 97.57,75.53 97.58,75.53 97.71,75.53 97.75,75.49 98.31,75.49 UC1.AW70
  BOTTOM w0.102: 94.67,74.63 93.85,74.63 92.65,75.82 92.65,76.12 91.75,77.03 T114.1
N28483977: length 6.2
  TOP w0.102: PR2.1 131.52,176.6 133.64,176.6 v1(134,176.24)
  TOP w0.254: PQ1.2 131.37,176.45 PR2.1 131.45,177.41 PR13.2 131.62,177.57 PR12.2
N28483985: length 4.1
  TOP w0.102: PR5.2 128.03,175.96 v1(125.77,173.7)
N28484391: length 3.7
  TOP w0.102: PC16.1 v1(118.29,167.89)
  TOP w0.254: PQ2.3 118.36,168.9 PC16.1 117.53,168.83 PR28.2
N28484395: length 4.1
  TOP w0.102: v1(117.35,170.87) PR29.1
  TOP w0.254: PQ2.2 118.5,169.54 PC16.2 117.56,169.75 PR29.1
N28484412: length 5.6
  TOP w0.102: PQ2.5 122.26,169.54 122.59,169.21 122.59,168.3 122.31,168.02 PR33.2 PR31.1 121.76,166.46 120.54,166.46 v1(120.35,166.27)
N28484439: length 8.1
  TOP w0.102: v1(146.36,168.53) 146.49,168.66 PC14.2
  TOP w0.254: PQ3.2 151.3,168.75 147.97,168.75 PC14.2 146.48,170.24 PR32.1
N28484451:
  vias: v1(133.69,172.54)
N28810503: length 4.4
  TOP w0.102: CZ45.1 46.28,16.64 45.83,16.18 45.83,15.24 v1(46.44,14.63)
  TOP w0.203: CZ45.1 46.23,16.76 46.23,17.98 46.18,18.04 UZ2.12
N28810563: length 4.3
  TOP w0.102: v1(44.99,14.73) 45.6,15.34 45.6,16.26 CZ23.1
  TOP w0.203: CZ23.1 45.32,16.89 45.32,17.98 45.38,18.04 UZ2.10
N28842863: length 4.5
  BOTTOM w0.102: CC204.1 142.2,80.48 141.98,80.26 139.63,80.26 139.41,80.48 138.24,80.48 UC1.AL1
N28843886: length 7.1
  BOTTOM w0.076: CC214.1 v1(136.26,71.01) 134.46,72.81 133.9,72.81 132.9,73.8 UC1.BB10
N28856399: length 7.7
  BOTTOM w0.076: 94.67,74.4 96.68,74.4 97.03,74.74 97.54,74.74 97.66,74.86 98.21,74.86 98.39,74.68 UC1.BA70
  BOTTOM w0.102: T16.1 92.31,75.84 93.75,74.4 94.67,74.4
N28856402: length 10.4
  BOTTOM w0.076: 94.67,74.17 96.13,74.17 96.56,73.74 98.48,73.74 98.63,73.89 98.63,74.34 98.97,74.68 UC1.BA68
  BOTTOM w0.102: T17.1 90.76,75.51 92.31,75.51 93.66,74.17 94.67,74.17
N28857231: length 5.2
  BOTTOM w0.076: UC1.BB68 99.38,74.06 99.05,73.73 99.03,73.73 98.59,73.29 96.27,73.29 95.81,72.83 95.24,72.83
  BOTTOM w0.102: T12.1 95.07,72.83 95.24,72.83
N28857234: length 5.1
  BOTTOM w0.076: 94.67,73.47 98.49,73.47 98.95,73.93 UC1.BB69
  BOTTOM w0.102: 94.67,73.47 94.65,73.47 T13.1
N28857237: length 2.2
  TOP w0.076: T14.1 131.38,82.42 v2(131.73,82.77)
  BOTTOM w0.089: UC1.AK13 131.51,81.69 131.51,82.56 v2(131.73,82.77)
N28857240: length 2.1
  TOP w0.076: T15.1 132.14,81.91 v2(132.16,81.93)
  BOTTOM w0.089: v2(132.16,81.93) 131.83,81.6 UC1.AK12
N28861827: length 7.5
  BOTTOM w0.076: UC1.C64 102.16,95.89 102.07,95.98 102.07,97.63 v1(101.33,98.37) 101.28,98.37 101.17,98.48 100.66,98.48 100.39,98.75 99.8,98.75 98.59,99.96 98.59,100.22 98.35,100.46
  BOTTOM w0.102: RC120.1 98.09,100.72 98.35,100.46
N29708559: length 6
  BOTTOM w0.076: 140.13,75.03 139.2,74.09 138.41,74.09 138.13,74.38 137.03,74.38 136.87,74.54 136.87,74.89 UC1.AY4
  BOTTOM w0.102: T126.1 140.13,75.03
N29708561: length 6
  BOTTOM w0.076: 140.06,74.68 139.12,73.74 137.87,73.74 137.55,74.06 UC1.BB3
  BOTTOM w0.102: T127.1 142.33,75.03 141.98,74.68 140.06,74.68
N29708599: length 7
  BOTTOM w0.076: 138.39,78.97 138.15,78.72 138.15,78.46 137.99,78.3 136.44,78.3 136.15,78.01 136.15,77.52 UC1.AU5
  BOTTOM w0.102: T128.1 140.91,79.32 138.75,79.32 138.39,78.97
N29708601: length 5.4
  BOTTOM w0.076: UC1.AT5 135.8,77.93 136.11,78.24 136.11,78.64 136.39,78.92 137.63,78.92 137.81,79.11 137.81,79.38 137.98,79.56 138.61,79.56 138.73,79.68 T129.1
N29708639: length 5.9
  BOTTOM w0.076: 140.52,73.66 140.44,73.66 139.8,73.66 139.34,73.2 136.82,73.2 135.96,74.06 UC1.BB5
  BOTTOM w0.102: T130.1 140.52,73.66
N32287358: length 1.5
  TOP w0.203: U15.10 142.21,154.32 141.98,154.09 141.98,153.92 v2(141.97,153.91) 141.98,153.9 C349.2
N32287370: length 3.2
  TOP w0.102: v1(144.39,153.77) 144.29,153.87 143.72,153.87 143.15,153.3 C343.2
  TOP w0.203: C343.2 143,153.61 143.11,153.72 143.11,154.19 143.01,154.29 U15.12
N32646580: length 4.1
  TOP w0.254: PBATT1.4 156.97,178.34 v1(156.97,177.85) 157.41,177.41 PR15.1
N32798407: length 4.9
  TOP w0.102: v1(54.78,77.05) 54.6,76.87 R6215.2 53.7,75.18 C6204.1 53.09,75.31 Q6203.3
N32842463: length 11.9
  TOP w0.102: v2(131.79,86.09) 134.02,86.09 v1(134.55,86.61) 140.33,86.61 RC361.2
  BOTTOM w0.102: UC1.U11 132.45,87.61 131.87,87.61 UC1.U12 131.65,87.45 131.65,87.35 131.53,87.22 131.53,86.35 v2(131.79,86.09)
N33124395:
  vias: v1(57.96,18.28)
N33188643: length 3.1
  BOTTOM w0.102: R2717.1 178.97,25.45 v1(179.23,25.7)
  BOTTOM w0.254: R2717.1 178.24,24.56 RE33.2 C2720.1
N33688158: length 3
  TOP w0.203: v2(186.02,68.45) 185.81,68.25 185.81,68.25 185.62,68.05 185.62,68.05 185.55,67.98 UE1.113
  BOTTOM w0.102: v1(186.53,68.83) 186.4,68.83 v2(186.02,68.45)
  BOTTOM w0.203: RE442.2 186.24,68.23 v2(186.02,68.45)
N34661441: length 4.2
  BOTTOM w0.102: RE74.2 v1(190.11,84.32) 190.11,85.03 191.2,86.11 JDEG1.9
N34661558: length 1.7
  BOTTOM w0.102: T4932.1 187.8,87.69 RE422.1
N34661623: length 5.2
  BOTTOM w0.102: JDEG1.1 191.32,90.11 191.14,90.28 v1(190.31,90.28) 189.82,90.28 189.39,89.85 187.22,89.85 RE71.2
N36085760: length 3.2
  TOP w0.102: PD6.1 89.08,151.13 v1(88.58,151.64)
  TOP w0.254: PD6.1 90.02,151.6 PR11.2
N36752215: length 1.4
  TOP w0.102: UZ21.6 130.88,109.22 CZ70.1
N37641086: length 4.5
  TOP w0.102: UC17.2 167.96,90.58 167.72,90.34 CC1103.1 167.24,91.15 RC1103.2 166.53,91.19 DZ1702.2 v1(166.17,89.89)
N38038995: length 0.9
  TOP w0.102: CV98.1 RV40.2
N38038996: length 3.8
  TOP w0.102: CV99.1 172.78,128.65 v1(172.78,127.95) 173.21,127.52 174.22,127.52 174.5,127.24 RV41.2
N39091501: length 3.5
  BOTTOM w0.102: v1(191.29,123.34) 191.29,122.58 C6209.2 191.01,121.14 U5602.6
N39189842: length 5
  TOP w0.102: RD7.1 113.32,28.5 v2(113.3,28.52) v1(112.79,28.52)
  BOTTOM w0.102: v2(113.3,28.52) 112.09,28.52 111.37,29.23 JDIMM1.134
N39190967: length 2.2
  TOP w0.102: v2(119.77,15.21) 119.94,15.38 RD8.1
  BOTTOM w0.102: v2(119.77,15.21) 119.97,15.41 JDIMM2.134
N39282118: length 0.9
  BOTTOM w0.102: 169.72,21.5 v1(168.83,21.5)
N39282176: length 1.3
  BOTTOM w0.102: v1(168.41,32.78) 168.85,32.33 PC504.1
N39282188: length 1.8
  BOTTOM w0.102: PR504.2 v1(176.38,21.88)
  BOTTOM w0.254: PR503.1 PR504.2
N39302306: length 1.3
  BOTTOM w0.102: CC8.2 158.17,73.49 RC29.1
N39854666:
  vias: v1(23.32,69.77)
N39880170: length 2.7
  BOTTOM w0.102: v1(38.46,59.01) 38.62,59.01 39.02,58.61 39.02,57.29 PR1202.2
N39880453: length 1.7
  BOTTOM w0.102: PR1208.2 39.69,59.87 v1(39.48,59.87)
N39995456: length 6.3
  TOP w0.102: R6211.1 54.6,72.64 Q2405.1 53.5,72.59 v1(49.59,72.59)
N40185786: length 3.1
  BOTTOM w0.102: PR769.2 106.48,156.69 106.48,157.1 v1(106.77,157.39) 107.41,158.02 PU703.3
N40185790: length 2.7
  BOTTOM w0.102: PR770.2 107.29,158.42 PU703.4
N40185793: length 18.1
  TOP w0.508: PR737.1 83.57,169.23 PR763.1 v2(84.18,168.62) 83.66,168.11 PQ709.3
  IN1 w0.508: v2(84.18,168.62) 83.78,168.22 83.09,168.22 81.07,170.24 81.07,171.26 80.18,172.15 78.31,172.15 76.54,170.37 73.81,170.37 v2(72.45,169.01)
  vias: v1(75.44,167.49)
N40185809: length 3.3
  BOTTOM w0.102: v1(110.34,153.49) 110.74,153.89 PC750.1
  BOTTOM w0.203: PC750.1 110.74,155.7 110.58,155.86 PU703.27
N40185819: length 1.9
  BOTTOM w0.102: v1(104.83,164.59) 104.59,164.35 PC752.2
  BOTTOM w0.203: PR754.1 104.64,163.69 PC752.2
N40185844: length 2.3
  BOTTOM w0.203: PU703.6 107.29,159.22 107.26,159.26 106.82,159.26 v1(106.8,159.24) 106.3,159.24 105.86,158.8 PR774.2
N40185847: length 2.1
  BOTTOM w0.203: PR775.2 106.31,159.66 106.35,159.62 PU703.7
N40185849: length 1.5
  BOTTOM w0.102: v1(117.63,156.74) 117.23,156.34 116.33,156.34
N40185857: length 8.7
  BOTTOM w0.102: PR743.1 117.96,158.5 v1(118.37,158.09)
  BOTTOM w0.203: PC757.2 113.15,160.72 112.93,160.5 112.93,159.99 112.56,159.62 PU703.18
  BOTTOM w0.254: PC757.2 114.94,160.72 116.33,159.33 PR743.1
N40185867: length 3
  BOTTOM w0.203: PR755.2 108.07,162.75 108.58,162.24 108.96,162.24 109.78,161.43 PU703.12
N40185868: length 4.2
  BOTTOM w0.203: PU703.14 110.58,161.39 110.57,161.39 v1(110.57,161.77) 110.57,162 109.82,162.76 PC708.1 109.82,163.24 109.84,163.26 PR776.1
N40185870: length 3.7
  BOTTOM w0.203: PR742.1 112.1,162.77 PC708.2 110.73,162.75 111.08,162.39 v2(111.08,161.8) 111.08,161.58 110.98,161.48 PU703.15
N40185883: length 5.2
  BOTTOM w0.102: PR740.2 109.68,152.46 v1(109.68,152.13)
  BOTTOM w0.203: PR740.2 108.51,154.06 108.46,154.11 PC747.1 108.46,155.6 108.98,156.11 PU703.31
N40185884: length 4.7
  BOTTOM w0.102: PC747.2 107.35,154.81 107.12,155.04 107.12,155.38 v1(106.82,155.68)
  BOTTOM w0.203: PR772.2 107.63,154.06 107.55,154.14 PC747.2 107.55,155.22 108.58,156.25 PU703.32
N40185886: length 2.4
  BOTTOM w0.203: PC750.2 109.7,155.04 109.89,155.04 110.24,155.4 110.24,155.75 110.17,155.83 110.18,155.83 PU703.28
N40185889: length 19.9
  IN1 w1.016: 130.93,156.27 130.38,156.82 126.89,156.82 126.4,156.32 126.4,154.75 125.85,154.2 121.82,154.2 119.75,156.27 114.1,156.27
  vias: v1(133,157.15) v2(111.88,156.27) v2(112.52,156.27) v2(131.88,157.73) v2(132.52,157.73)
N40185891: length 1.3
  TOP w0.102: PR761.2 v1(119.32,158.66)
N40185893: length 2.9
  BOTTOM w0.203: PU703.26 110.98,156.04 111.05,155.96
  BOTTOM w0.254: PR745.1 v1(111.99,155.19) 111.82,155.19 111.05,155.96
N40185897:
  vias: v1(113.53,156.4)
N40185899: length 3.4
  BOTTOM w0.203: PU703.17 112.33,160.02 112.52,160.21 112.52,161.32 v1(112.92,161.72) 113.04,161.85 113.72,161.85 PR757.2
N40185902: length 0.6
  BOTTOM w0.102: PR703.1 111.56,153.42 111.44,153.29 v2(111.44,153.34)
  vias: v1(107.4,154.08) v2(110.8,153.29) v2(110.8,152.65) v2(111.11,152.15) v2(111.44,153.92) v2(111.44,152.65) v2(111.69,152.02) v2(112.32,152.02) v2(112.96,152.02) v2(113.59,152.02)
N40185907: length 4.5
  BOTTOM w0.102: v1(115.13,165.13) 114.84,165.13 114.33,164.62 114.33,163.22 113.9,162.79 PR779.2
  BOTTOM w0.203: PR757.1 114.76,161.67 113.9,162.53 PR779.2
N40185909: length 16.7
  TOP w0.381: PR762.1 82.76,166.22 PQ709.1
  TOP w0.508: v2(79.41,164.9) 78.97,164.47 PC742.1 PR778.2 PC744.1 78.52,166.84 v1(76.94,168.42) 75.81,169.54 PQ718.4 ; v2(82.56,163.6) 82.56,164.12 PR762.1
  IN1 w0.508: v2(79.41,164.9) 79.41,163.86 79.88,163.39 82.34,163.39 v2(82.56,163.6)
N40185955: length 2.2
  TOP w0.508: PC779.1 v1(130.97,157.21) 130.97,157.63 v2(130.68,157.92)
N40185980: length 25
  IN1 w0.254: v2(112.11,164.38) 113.54,165.81 125.27,165.81 130.74,160.34 131.37,160.34 v2(131.5,160.21)
  BOTTOM w0.102: v2(112.11,164.38) v1(112.52,164.79)
  BOTTOM w0.254: PR765.2 131.18,160.53 v2(131.5,160.21) ; PR742.2 v2(112.11,164.38)
N40185983: length 26.4
  IN1 w0.254: v2(111.44,164.53) 113.17,166.27 125.35,166.27 130.9,160.72 131.31,160.72 v2(131.5,160.91)
  BOTTOM w0.102: v1(110.75,165.54) PR776.2
  BOTTOM w0.254: PR776.2 v2(111.44,164.53) ; PR765.3 132.07,160.53 131.69,160.91 v2(131.5,160.91)
N40185999: length 5.4
  TOP w0.102: v1(82.22,171.37) 82.26,171.33 82.26,170.68 81.79,170.21 PR738.1 PR737.2 81.79,168.44 PQ709.2
N40186006: length 12.1
  TOP w0.102: v2(107.75,152.02) v1(107.35,151.61)
  IN2 w0.254: v2(107.75,152.02) 107.88,152.15 107.88,153.64 109.03,154.79 111.79,154.79 112.98,153.61 114.29,153.61 v2(114.48,153.8)
  BOTTOM w0.254: PR703.2 114.1,153.42 v2(114.48,153.8) ; PR772.1 107.75,152.58 v2(107.75,152.02)
N40186007: length 11.5
  TOP w0.102: v2(108.39,152.02) v1(108.77,151.64)
  IN2 w0.254: v2(114.48,153.03) 114.29,153.23 112.82,153.23 111.64,154.41 109.19,154.41 108.26,153.48 108.26,152.15 v2(108.39,152.02)
  BOTTOM w0.254: PR703.3 114.86,153.42 v2(114.48,153.03) ; PR740.1 108.39,152.58 v2(108.39,152.02)
N40186030: length 1.2
  TOP w0.102: PC767.1 v1(127.48,162.75)
N40186037: length 5.2
  TOP w0.508: PC779.2 131.49,154.43 PR773.2 132.96,154.43 v1(133.53,155) 133.53,155.27 v2(133.24,155.56)
  BOTTOM w0.508: PQ717.4 132.4,156.72 133.24,155.88 v2(133.24,155.56)
N40186056: length 4.1
  BOTTOM w0.102: PR743.2 117.7,161.16 v1(118.1,160.76)
  BOTTOM w0.254: PR743.2 115.95,161.54 PD704.1
N40186061: length 2.6
  BOTTOM w0.203: PU703.13 110.18,161.53 108.96,162.75 PR764.2
N40186070: length 2.3
  TOP w0.102: PQ710.2 v1(116.22,161.47) PQ711.1
N40197821: length 3.7
  BOTTOM w0.203: PC1227.2 158.47,111.27 v1(158.83,110.92) 159.16,110.58 PU1100.15
  BOTTOM w0.254: PR1136.2 PC1227.2
N40197830: length 2.1
  BOTTOM w0.102: PR1137.2 159.31,113.69 v1(159.62,113.39)
  BOTTOM w0.254: PR1137.2 158.53,112.89 PC1227.1
N40197832: length 5.1
  TOP w0.254: PC1110.1 161.58,107.46 PR1114.1 162.55,107.31 162.68,107.19 163.48,107.19 v2(163.62,107.05)
  BOTTOM w0.203: v2(163.62,107.05) v1(163.11,107.05) 163.08,107.05 162.93,107.21 162.66,107.21 162.6,107.14 PU1100.25
N40197841: length 4.2
  BOTTOM w0.203: PU1100.11 157.56,109.82 157.33,110.05 156.58,110.05 v1(156.08,110.55) 155.82,110.81
  BOTTOM w0.254: PR1121.2 155.82,111.11 155.82,110.81
N40197842: length 6.3
  TOP w0.102: v1(157.87,110.76) PC1124.1
  TOP w0.254: PC1124.1 158.85,111.26 159.11,111.51 v2(159.12,111.51) 158.98,111.66 PR1138.1
  BOTTOM w0.203: PC1122.1 159.56,110.79 PU1100.16
  BOTTOM w0.254: PR1133.1 160.81,111.24 PC1122.1 159.61,111.51 v2(159.12,111.51)
N40197845: length 4.1
  TOP w0.102: v2(160.4,110.66) v1(160.91,110.66)
  TOP w0.254: v2(160.4,110.66) 160.36,110.66 160.26,110.76 PC1229.1 159.74,111.55 159.87,111.68 PR1139.1
  BOTTOM w0.203: PU1100.17 159.96,110.19 160.4,110.63 v2(160.4,110.66)
N40197867: length 3.4
  TOP w0.102: v1(172.23,113.89) PR1125.2
  TOP w0.254: PR1125.2 PC1121.1
N40197882: length 1.2
  BOTTOM w0.102: PC1118.1 165.55,107.77 v1(165.02,107.25)
N40197886: length 36.1
  TOP w0.102: v2(158.47,114.5) v1(159.04,114.5)
  TOP w0.254: PR1124.2 157.66,113.43 PR1126.2 157.9,113.92 v2(158.47,114.5)
  IN1 w0.254: v2(158.47,114.5) 158.47,113.11 159.38,112.2 161.79,112.2 165.35,115.77 170.83,115.77 171.09,115.51 178.46,115.51 180.33,113.64 180.33,109.16 v2(180.21,109.03)
  BOTTOM w0.254: PL1103.3 180.02,108.33 180.27,108.58 180.27,108.97 v2(180.21,109.03)
N40197888: length 36.6
  IN1 w0.254: v2(159.3,116.15) 159.3,114.63 158.86,114.19 158.86,113.26 159.54,112.59 161.6,112.59 165.16,116.15 170.99,116.15 171.25,115.89 178.62,115.89 180.71,113.79 180.71,109.16 v2(180.84,109.03)
  BOTTOM w0.102: v2(159.3,116.15) 159.5,116.15 v1(159.87,116.52)
  BOTTOM w0.254: v2(180.84,109.03) 180.84,108.58 181.1,108.33 PL1103.2 ; v2(159.3,116.15) 158.7,116.74 PR1128.2
N40197914: length 41.8
  IN2 w0.254: v2(171.71,116.46) 171.54,116.63 158.03,116.63 157.09,115.7 157.09,112.72 155.82,111.45 155.82,110.14 157.09,108.87 157.09,104.77 156.58,104.26 154.44,104.26 152.46,106.25 v2(152.46,107.36)
  BOTTOM w0.254: PR1121.1 PR1120.2 152.46,111.46 v1(152.46,111.19) v2(152.46,107.36) ; v2(171.71,116.46) 172.32,116.46 PH1101.2
N40197922: length 6.2
  BOTTOM w0.203: PR1133.2 161.72,111.23 161.72,110.92 161.5,110.71 161.1,110.71 160.36,109.97 PU1100.18
  BOTTOM w0.254: PR1133.2 161.73,111.26 PR1135.1 ; PR1135.1 PR1129.2 ; PR1135.1 162.52,112.13 PC1123.1 162.62,112.23 PR1134.1
N40197925: length 3.2
  BOTTOM w0.102: PR1129.1 161.1,113.31 161.1,114.07 v1(160.83,114.35)
  BOTTOM w0.254: PC1122.2 159.89,112.78 160.15,113.04 PR1129.1
N40197927: length 2.7
  BOTTOM w0.102: PC1233.1 162.62,114.8 v1(162.62,115.35)
  BOTTOM w0.254: PR1135.2 PC1233.1
N40197929: length 8.6
  BOTTOM w0.102: v1(165.44,115.38) 164.85,115.38 163.96,114.49 163.96,113.55 PC1228.2
  BOTTOM w0.203: PU1100.19 160.76,109.9 161.24,110.38 161.8,110.38 161.98,110.55
  BOTTOM w0.254: PC1228.2 163.52,113.08 PC1123.2 162.6,111.3 PR1130.1 162.6,111.18 161.98,110.55
N40197932: length 2.2
  BOTTOM w0.102: PC1228.1 163.51,114.63 v1(164.03,115.15)
  BOTTOM w0.254: PC1228.1 PR1134.2
N40197958: length 31.7
  BOTTOM w0.254: PR1131.2 155.04,116.76 155.71,117.43 157.24,117.43 159.63,117.43 160.86,116.2 170.27,116.2 170.65,115.82 181.34,115.82 v1(181.86,115.3) 182.51,114.66 182.51,112.8 PH1102.1
N40197966: length 52.2
  TOP w0.102: v2(154.43,114.62) v1(154.43,115.13)
  TOP w0.254: PR1104.2 154.33,113.43 PR1108.2 154.09,114.18 154.43,114.51 v2(154.43,114.62)
  IN1 w0.254: v2(154.43,114.62) 154.54,114.62 154.83,114.33 154.83,105.34 155.91,104.26 158.14,104.26 164.08,98.33 164.08,97.41 166.55,94.93 168.59,94.93 169.67,93.85 173.35,93.85 174.87,92.33 179.32,92.33 180.35,93.36 180.35,98.48 v2(180.14,98.68)
  BOTTOM w0.254: PL1102.3 179.63,99.69 180.14,99.19 v2(180.14,98.68)
N40197968: length 3
  TOP w0.102: PR1107.2 v1(172.23,94.65)
  TOP w0.254: PR1107.2 171.97,96.56 PC1109.1
N40197981: length 1.1
  BOTTOM w0.102: v1(165.45,106) 165.45,106 165.73,105.72 PC1108.1
N40197987: length 56.4
  IN1 w0.254: v2(180.9,98.68) 180.78,98.55 180.78,93.22 179.51,91.95 174.71,91.95 173.19,93.47 169.47,93.47 168.4,94.55 166.36,94.55 163.63,97.28 163.63,98.23 157.99,103.88 155.75,103.88 154.45,105.18 154.45,112.75 153.92,113.28 153.92,114.81 155.26,116.15 156.5,116.15 v2(157.08,116.72)
  BOTTOM w0.102: v1(156.41,117.02) 156.71,116.72 v2(157.08,116.72)
  BOTTOM w0.254: PR1110.2 157.1,116.74 v2(157.08,116.72) ; PL1102.2 181.22,99.69 180.9,99.38 v2(180.9,98.68)
N40198014: length 1.5
  BOTTOM w0.203: PU1100.39 157.96,103.95 157.84,103.83 157.65,103.83 157.56,103.91 PU1100.40
N40198017: length 5.1
  BOTTOM w0.102: v1(157.68,102.57) PR1140.1
  BOTTOM w0.203: PU1100.36 159.16,103.82 159.04,103.7 158.76,103.7 ; 158.76,103.7 158.76,103.29 158.66,103.19 PR1140.1 ; 158.76,103.7 158.47,103.7 158.36,103.81 PU1100.38 ; 158.76,103.7 PU1100.37
N40198022: length 2.6
  TOP w0.102: v2(156.24,104.74) 156.24,105.38 v1(156.3,105.45)
  TOP w0.254: PR1101.2 156.9,104.08 v2(156.24,104.74)
  BOTTOM w0.203: PU1100.1 156.5,105.14 156.24,104.87 v2(156.24,104.74)
N40198023: length 3.8
  TOP w0.254: PR1111.2 156.84,103.19 156.77,103.25 156.77,103.31 v1(155.92,104.17) 155.75,104.33 v2(155.75,105.1)
  BOTTOM w0.203: PU1100.2 156.39,105.54 155.94,105.1 v2(155.75,105.1)
N40198028: length 1.9
  BOTTOM w0.203: PR1105.2 159.93,103.18 v2(159.95,103.2) 159.96,103.21 PU1100.34
N40198029: length 1
  BOTTOM w0.102: PR1106.2 v1(161.8,102.57)
N40199716: length 2.5
  BOTTOM w0.102: v1(130.32,135.02) PR1401.2
  BOTTOM w0.254: PU1400.9 128.93,135.4 PR1401.2
N40199719: length 5.4
  BOTTOM w0.102: v1(124.48,141.69) 125.38,141.69 126.13,140.95 PR1405.2
  BOTTOM w0.254: PU1400.15 126.75,138.81 PC1405.1 126.12,140.47 PR1405.2
N40311410: length 23.5
  IN2 w0.508: v2(198.35,20.09) 195,16.74 195,11.3 192.65,8.95 188.97,8.95 v2(188.27,8.25)
  BOTTOM w0.102: v1(186.95,6.91) 187.31,6.91 187.7,7.3 187.7,8.13 187.83,8.25 v2(188.27,8.25)
  BOTTOM w0.508: R2705.1 189.11,7.96 188.82,8.25 v2(188.27,8.25) 188.33,8.32 R6511.1 ; Q6205.3 v2(198.35,20.09)
N40553728: length 2.3
  BOTTOM w0.102: v1(93.07,156.21) EC5206.1 R5207.1
N40598435: length 2.8
  BOTTOM w0.102: PR100.2 v1(27.23,37.67)
  BOTTOM w0.508: PR100.2 28.78,36.47 PC102.1
N40598492:
  vias: v1(47.29,35.89)
N40598500: length 1.3
  BOTTOM w0.102: PC114.1 40.09,36.14 v1(39.2,36.14)
N40598503: length 1.3
  BOTTOM w0.254: PC113.2 39.21,40.68 PR108.1
N40598539: length 2.5
  BOTTOM w0.102: v1(50.98,41.94) PR117.1
  BOTTOM w0.254: PC127.2 50.93,40.72 PR117.1
N40598619: length 2.5
  TOP w0.102: v1(50.58,44.88) PR116.2
  TOP w0.254: PD102.1 50.53,43.82 PR116.2
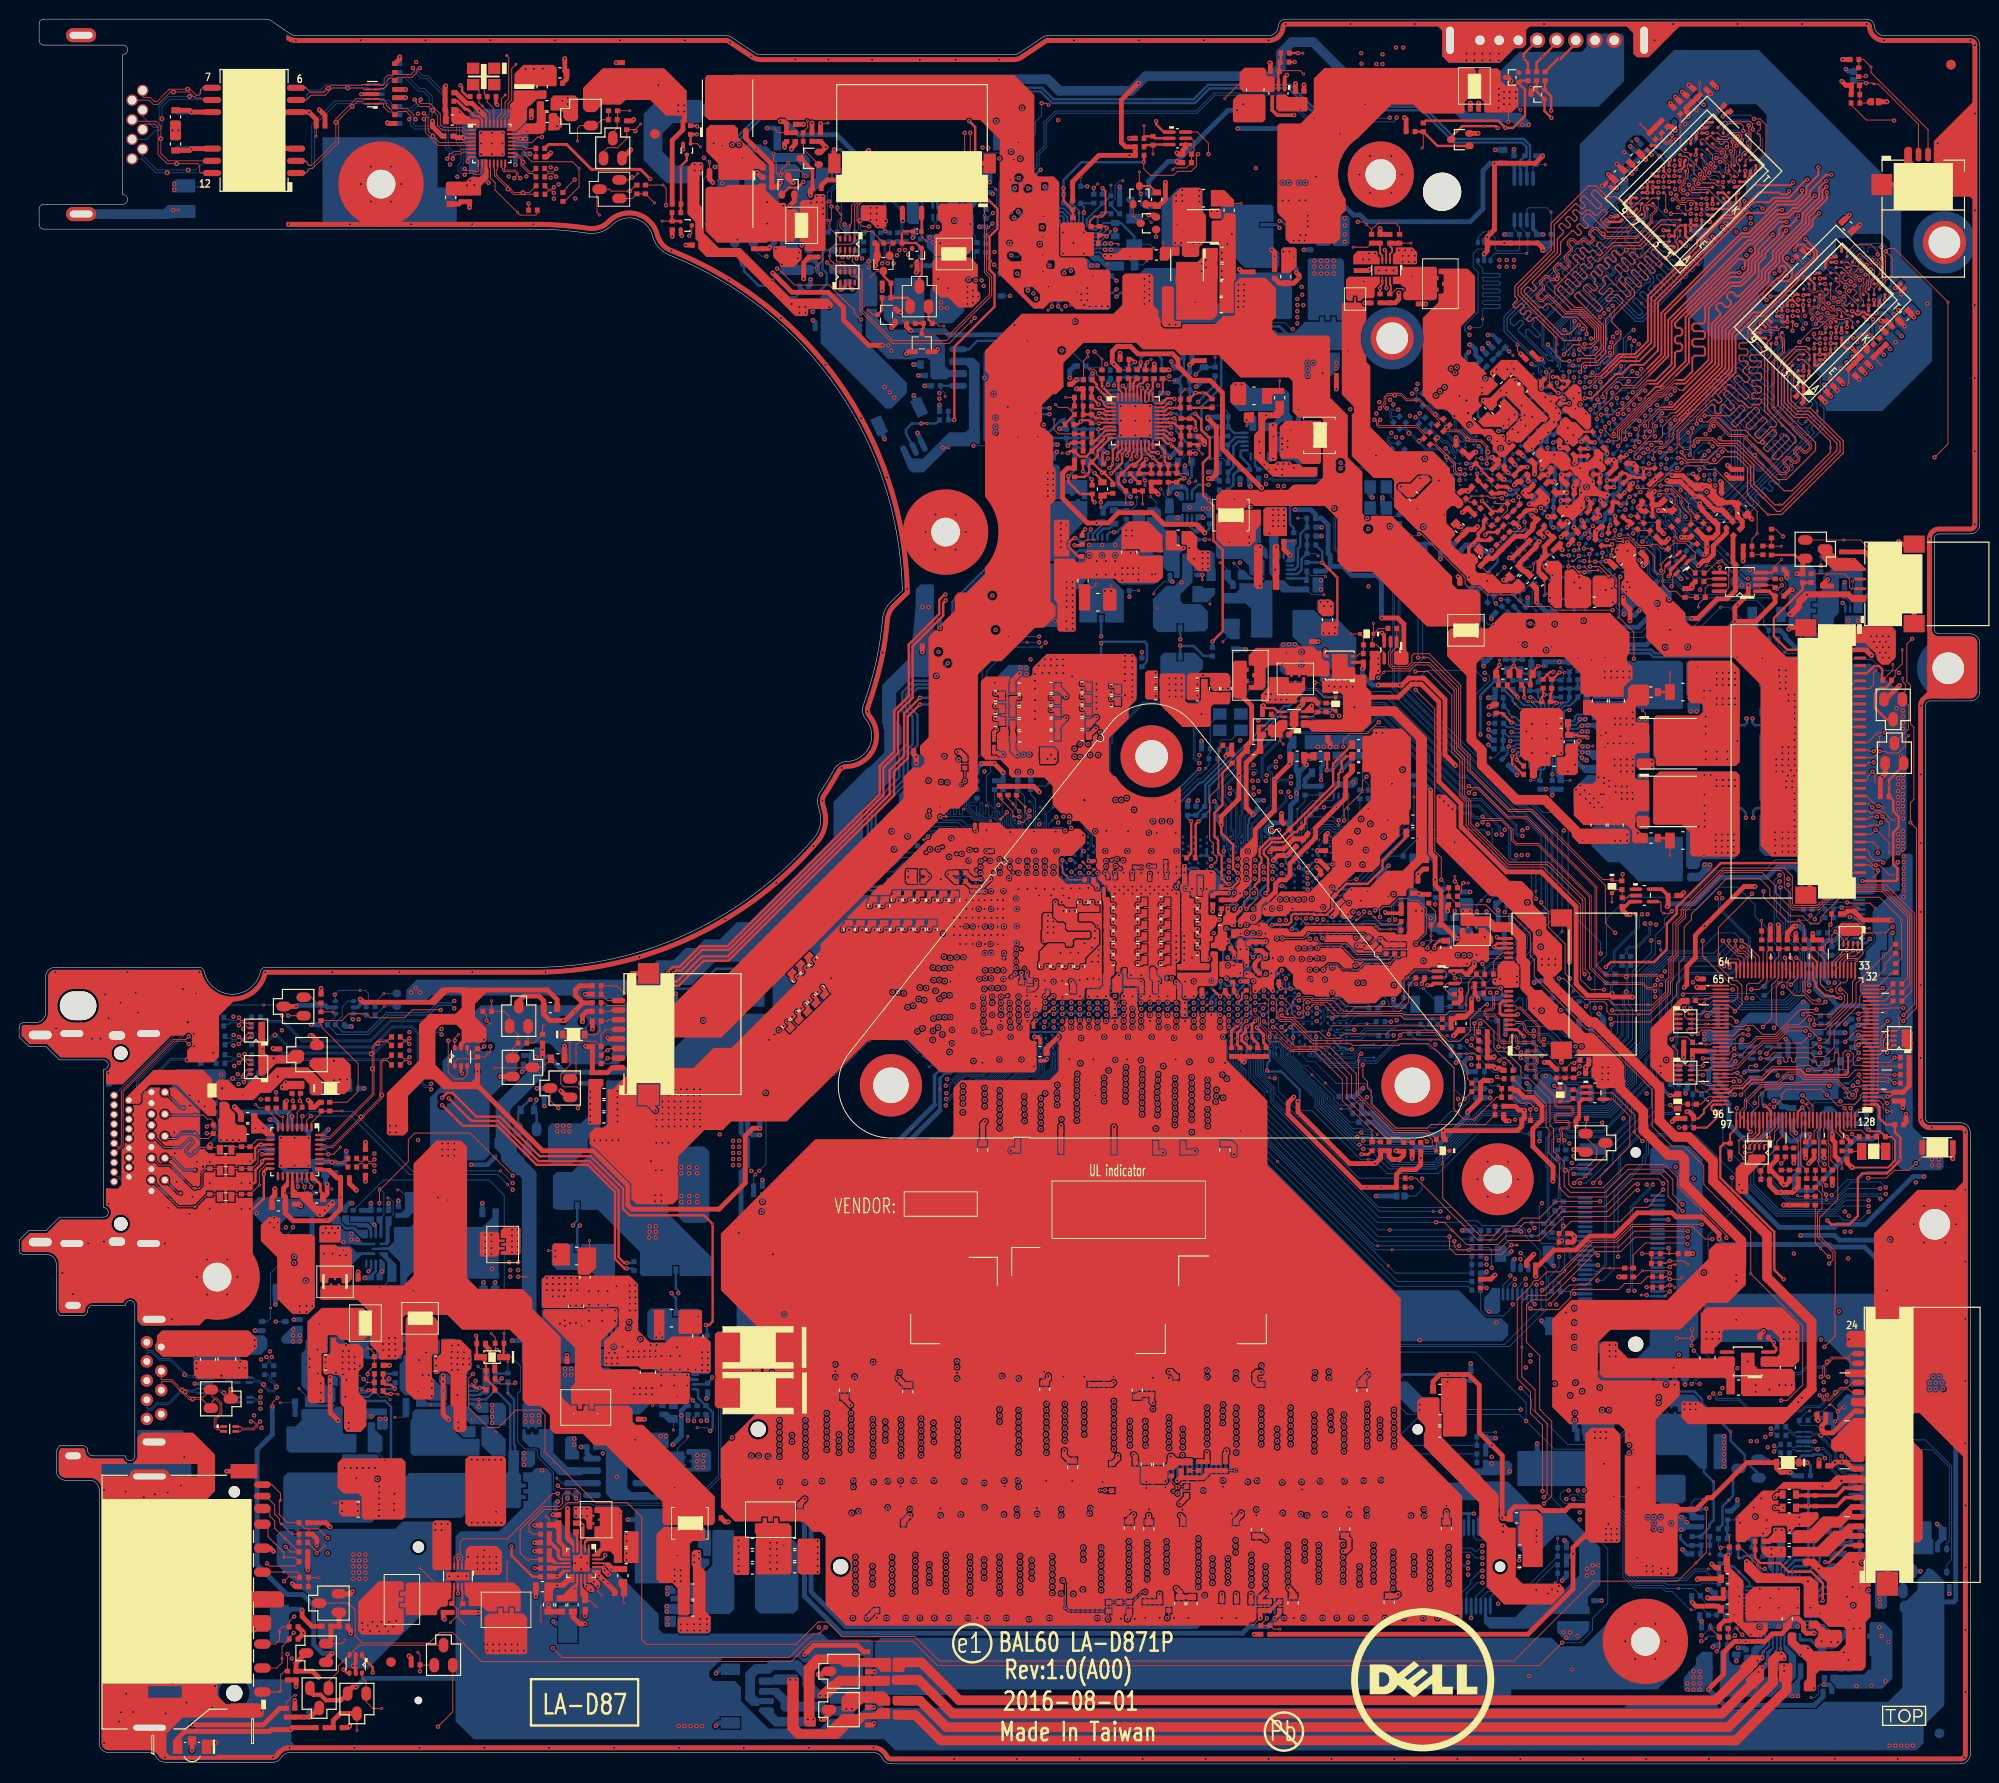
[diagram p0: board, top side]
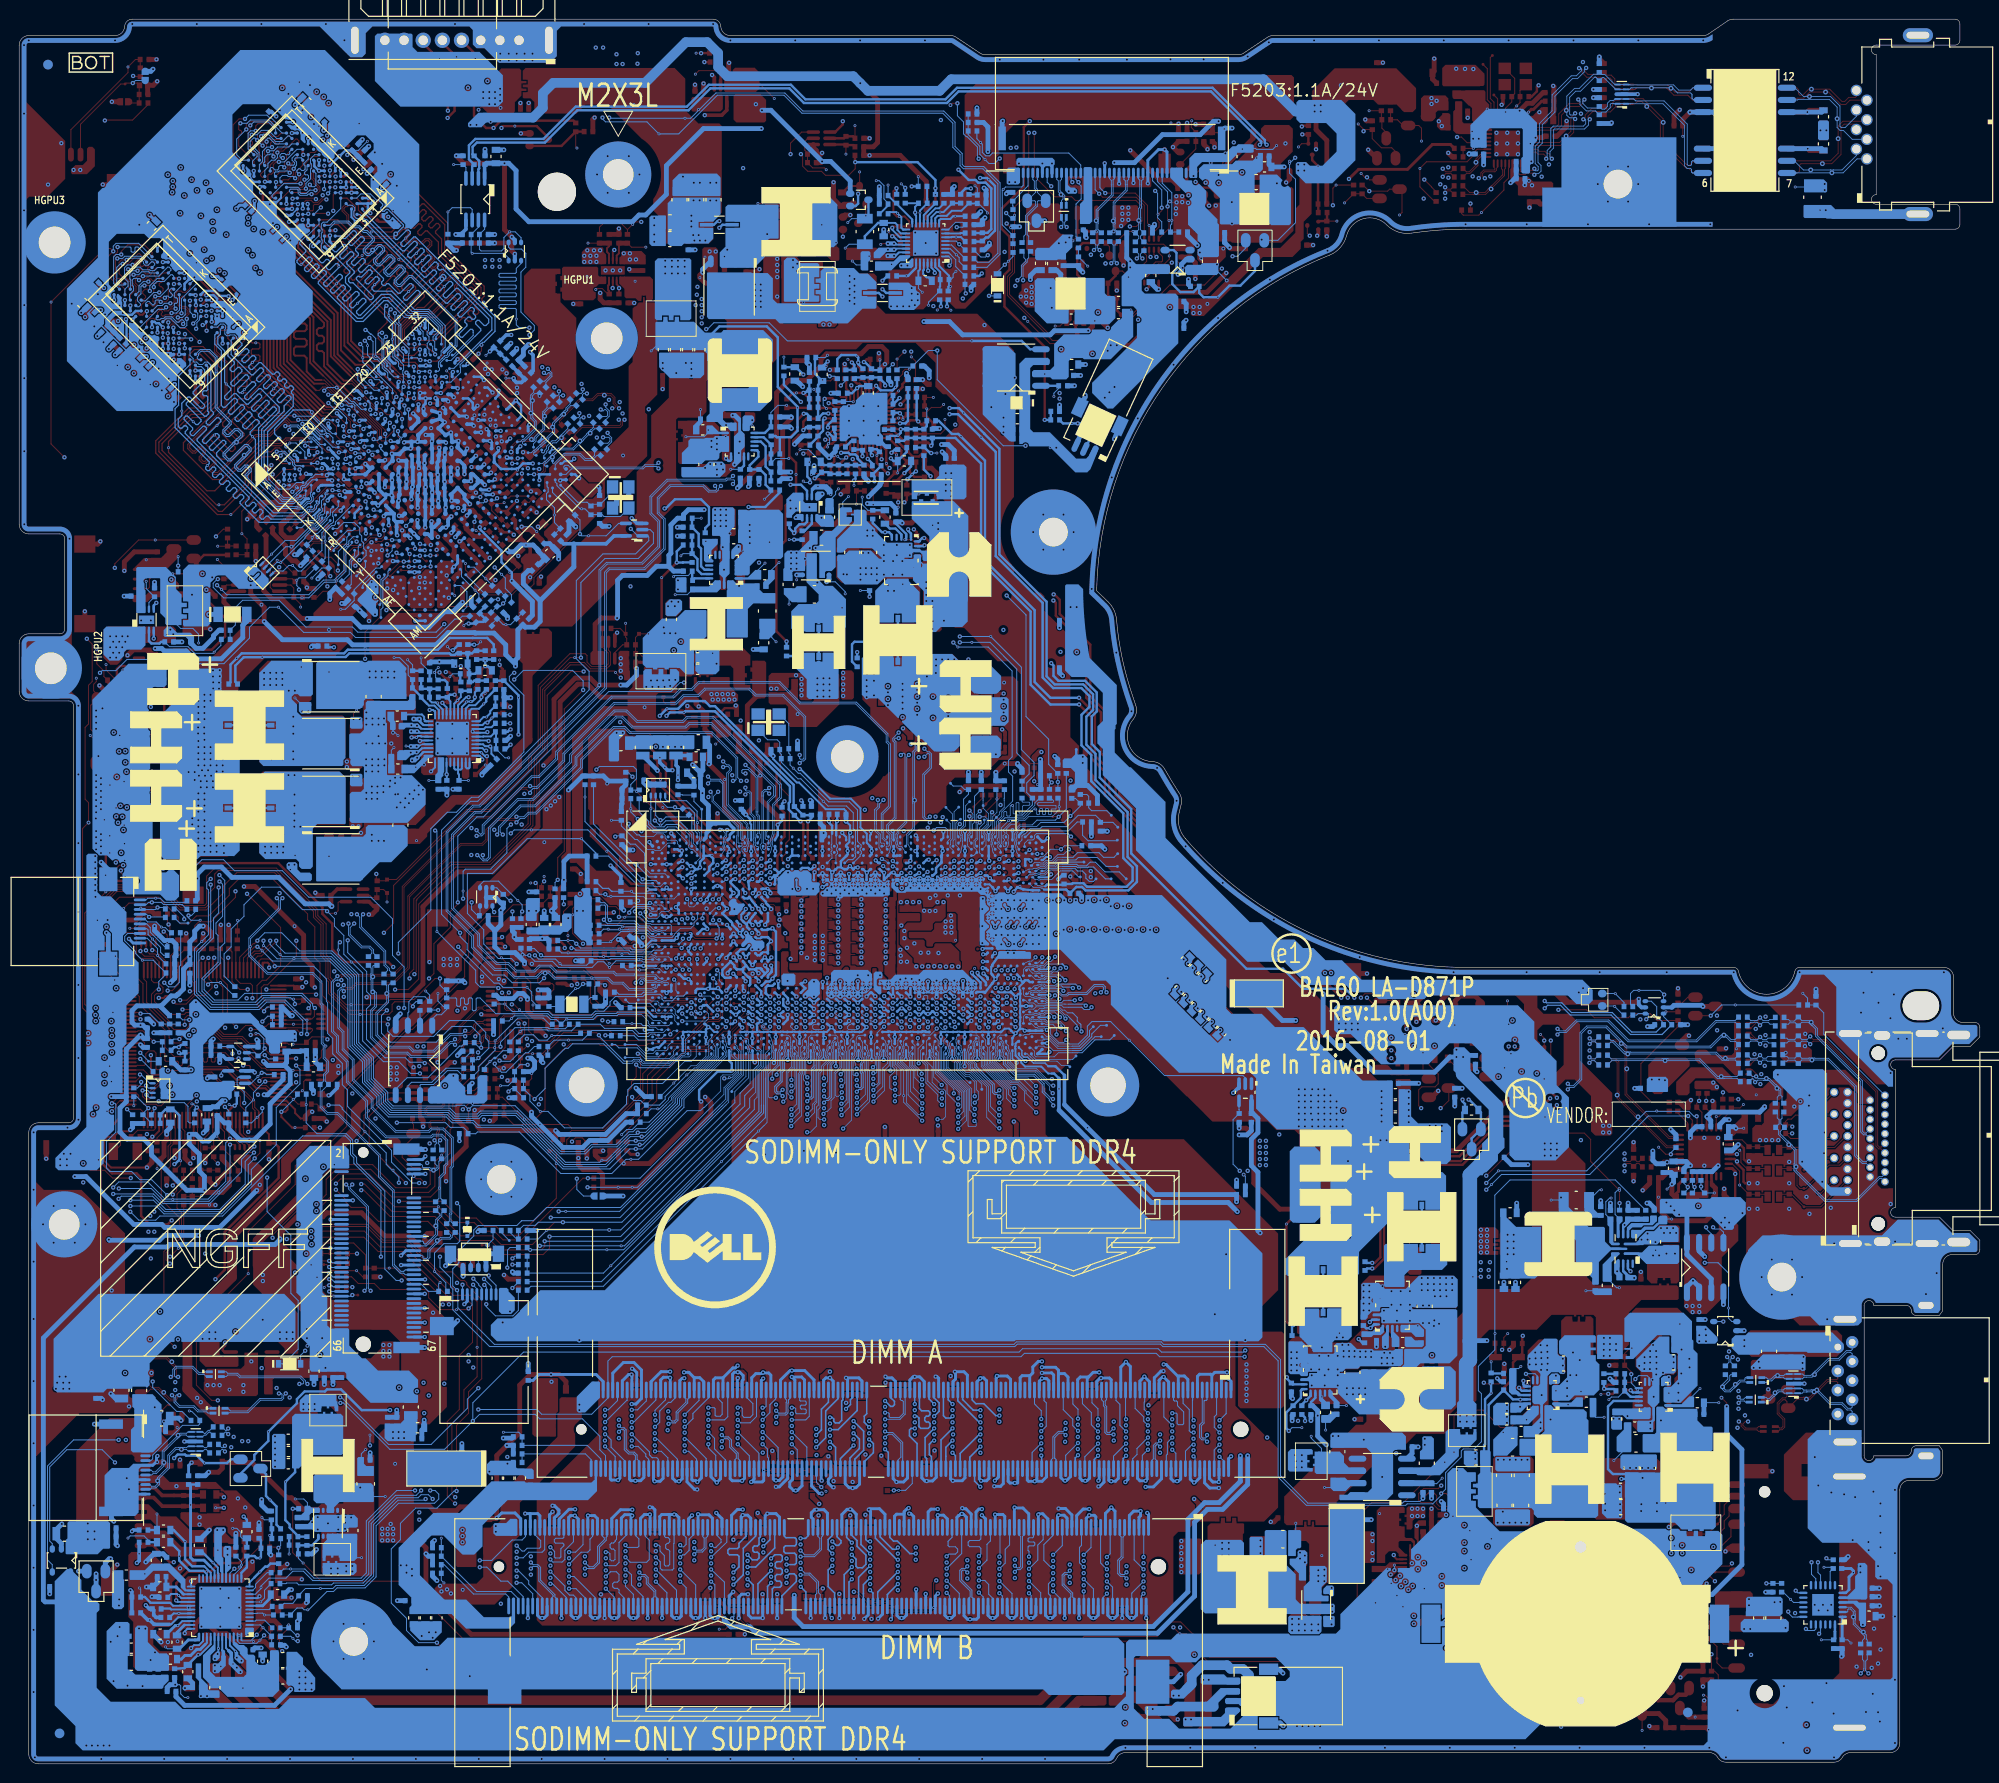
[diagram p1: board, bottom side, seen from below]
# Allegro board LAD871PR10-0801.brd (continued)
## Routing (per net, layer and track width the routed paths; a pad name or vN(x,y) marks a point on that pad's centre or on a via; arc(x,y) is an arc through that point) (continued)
N40605947: length 4.9
  BOTTOM w0.102: v1(136.28,123.83) 136.16,123.94 134.75,123.94 134.33,124.36
  BOTTOM w0.254: PU300.15 134.09,123.65 PC305.1 134.33,123.48 PR303.2
N40702769: length 196.7
  TOP w0.102: R6524.2 187.38,61.9 R6523.2 188.12,60.3 188.12,59.78 v2(188.52,59.37) v1(188.52,58.85)
  IN1 w0.127: v2(77.96,157.24) 80.66,157.24 81.21,156.69 81.21,154.75 82.59,153.37 87.17,153.37 88.98,155.18 90.91,155.18 97.53,148.55 105.43,148.55 107.87,146.11 112.68,146.11 114.11,147.55 123.06,147.55 123.97,146.64 123.97,142.75 125.69,141.04 125.69,139.02 128.64,136.07 128.64,133.71 128.89,133.46 128.89,132.83 130.38,131.33 130.38,128.92 130.63,128.68 132.06,128.68 132.84,127.9 132.84,126.94 135.44,124.33 136.51,124.33 139.67,121.17 139.67,116.43 140.61,115.49 140.61,113.51 140.86,113.26 140.86,107.3 142.25,105.91 142.25,101.05 147.59,95.72 152.07,95.72 154.22,93.58 158.2,93.58 161.74,90.03 161.74,89.14 164.08,86.8 165.73,86.8 167.51,85.02 173.25,85.02 173.88,84.39 178.3,84.39 179.19,83.5 181.86,83.5 182.43,82.93 189.67,82.93 191.46,81.14 191.46,79.41 189.83,77.78 189.83,72.53 189.32,72.02 189.32,67.49 188.25,66.42 188.25,64.39 188.78,63.86 188.78,61.85 188.11,61.18 188.11,59.79 v2(188.52,59.37)
  BOTTOM w0.102: D5201.3 76.59,158.1 77.45,157.24 v2(77.96,157.24)
N41321201: length 2.9
  TOP w0.102: v1(67.07,160.91) PC790.1
  TOP w0.254: PQ721.2 68.96,160.91 PC790.1 68.1,160.93 PR790.2
N41455626: length 1.7
  BOTTOM w0.102: PR203.2 v1(71.37,25.1)
N41674880: length 8.2
  TOP w0.102: v1(72.01,167.16) PQ740.4
  TOP w0.508: v2(76.97,165.99) 77.48,165.48 PR778.1 ; v2(72.37,164.94) 72.01,165.3 PQ740.4
  IN2 w0.508: v2(72.37,164.94) 73.42,165.99 v2(76.97,165.99)
N124752685: length 1
  TOP w0.102: RH211.1 CH101.2
N124753277: length 2.2
  BOTTOM w0.102: v3(76.8,61.46) 76.63,61.28 RH212.1
  BOTTOM w0.508: RH212.1 CH100.2
N427285901: length 3.3
  TOP w0.254: PR682.2 111.96,144.34 112.4,143.9 112.4,143.6 v1(112.8,143.2) 113.98,142.02 PU602.1

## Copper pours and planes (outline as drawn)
1.2V_VTT_PWRGD on TOP (solid shape): 57.49,20.23 57.52,20.19 57.52,20.07 57.46,20 57.02,20 56.25,19.24 55.05,19.24 55.05,19.81 56.25,19.81 56.68,20.23
2.5V_VIN on BOTTOM (solid shape): 52.83,34.35 54.22,34.35 54.22,34.92 55.43,34.92 55.75,34.61 55.75,32.45 57.27,30.92 60.51,30.92 60.7,30.73 60.7,30.42 60.51,30.23 58.79,30.23 58.67,30.1 56.32,30.1 54.35,32.07 54.35,32.77 54.1,33.02 53.27,33.02 52.51,33.78 52.51,34.92 52.83,34.92
3V_SN on BOTTOM (solid shape): 37.14,35.56 37.14,34.86 37.9,34.1 37.9,32.66 37.73,32.49 36.46,32.49 36.35,32.59 36.35,35.59 36.39,35.62 37.08,35.62
3V_VIN on TOP (solid shape): 36.33,47.12 36.33,46.65 35.77,46.65 35.77,46.11 36.33,46.11 36.33,45.86 35.77,45.86 35.77,45.29 36.33,45.29 36.33,44.59 35.93,44.2 33.58,44.2 33.08,44.7 32.25,44.7 32.16,44.61 32.16,42.96 32.06,42.86 31.82,42.86 31.68,42.86 31.55,42.74 31.55,42.6 31.55,40.78 31.55,40.78 31.55,40.54 31.86,40.23 31.86,37.67 31.81,37.62 30.36,37.62 30.08,37.9 30.08,46.1 31.29,47.31 31.31,47.31 31.55,47.56 35.88,47.56
3V_VIN on BOTTOM (solid shape): 37.08,46.48 37.08,44.01 36.51,44.01 36.51,43.37 37.08,43.37 37.08,43.18 36.51,43.18 36.51,42.54 36.95,42.54 36.95,42.21 36.15,42.21 33.66,44.7 32.31,44.7 32.19,44.58 32.19,42.93 32.12,42.86 31.62,42.86 31.49,42.74 31.49,40.07 32.24,39.32 32.87,39.32 33,39.19 33,37.82 32.85,37.67 31.22,37.67 29.44,39.45 29.44,42.8 29.88,43.23 29.88,44.12 30.03,44.27 30.03,46.16 30.92,47.05 36.51,47.05
5V_FB on BOTTOM (solid shape): 49.12,41.16 49.12,38.8 48.83,38.51 48.35,38.51 48.17,38.34 46.96,38.34 46.91,38.39 46.91,38.44 46.9,38.44 46.9,38.54 46.95,38.59 47.88,38.59 48.18,38.88 48.19,38.89 48.41,39.14 48.33,39.46 48.33,41.21 48.39,41.27 49,41.27
5V_HDD_S0 on BOTTOM (solid shape): 192.74,38.51 192.74,37.24 192.55,37.05 192.55,35.2 192.89,34.85 192.89,32.69 192.68,32.48 190.96,32.48 190.96,32.48 190.72,32.48 190.71,32.49 190.58,32.49 189.69,33.38 189.69,37.49 190.3,38.1 190.3,38.23 190.63,38.55 192.7,38.55
5V_HDMI_CRT_S0_R on TOP (solid shape): 29.77,71.12 29.77,70.48 29.65,70.36 28.12,70.36 28,70.23 27.36,70.23 27.23,70.36 27.23,70.74 27.74,71.25 29.65,71.25
5V_HDMI_CRT_S0_R on TOP (solid shape): 20.14,71.4 20.14,69.41 20.5,69.05 20.5,67.56 19.68,67.56 16.41,70.83 13.67,70.83 12.75,69.92 12.75,69.08 12.5,68.83 11.23,68.83 11.11,68.96 11.11,69.47 14.03,72.39 19.16,72.39
5V_HDMI_CRT_S0_R on IN2 (solid shape): 28.06,71.18 28.06,70.87 27.63,70.43 27.6,70.43 27.53,70.36 27.3,70.36 27.22,70.44 24.8,70.44 23.26,68.9 21.27,68.9 20.63,68.26 18.66,68.26 18.47,68.45 18.47,69.28 18.54,69.34 20.25,69.34 21.33,70.42 23.33,70.42 24.47,71.56 27.68,71.56
5V_SN on BOTTOM (solid shape): 50.77,33.83 50.77,32.13 50.67,32.03 50.61,32.03 50.5,32.13 49.32,32.13 48.22,33.23 48.22,35.08 48.32,35.18 49.42,35.18
5V_VIN on TOP (solid shape): 41.14,46.13 41.71,46.13 41.71,46.67 41.94,46.67 41.94,46.13 42.51,46.13 42.51,46.67 43.22,46.67 43.68,46.22 43.68,42.8 43.17,42.8 43.05,42.67 43.05,40.3 43.29,40.06 43.29,38.29 43,38 41.23,38 40.32,38.91 40.32,46.42 40.57,46.67 41.14,46.67
5V_VIN on BOTTOM (solid shape): 43.9,44.12 43.9,42.82 43.74,42.67 43.39,42.67 43.06,42.34 43.06,40.31 43.87,39.5 44.51,39.5 44.66,39.34 44.66,38 44.53,37.87 42.83,37.87 42.27,38.43 40.27,38.43 39.68,39.01 39.68,41.66 40.06,42.04 40.06,42.63 40.61,42.63 40.61,43.13 40.06,43.13 40.06,43.43 40.61,43.43 40.61,43.93 40.06,43.93 40.06,44.58 40.19,44.7 43.31,44.7
+0.6V_DDR_VTT on TOP (solid shape): 59.81,26.67 59.81,24.45 59.37,24.45 59.18,24.64 59.18,25.34 58.92,25.59 57.97,25.59 57.84,25.72 57.84,26.8 57.91,26.86 59.62,26.86
+0.6V_DDR_VTT on BOTTOM (solid shape): outline of 158 points within 144.21,14.1 164.97,31.7
+0.6V_DDR_VTT on IN1 (solid shape): 164.76,20.72 164.76,18.42 164.19,17.85 164.19,17.53 162.22,17.53 162.09,17.66 162.09,19.35 163.7,20.95 164.52,20.95
+0.6V_DDR_VTT on IN1 (solid shape): 59.68,26.92 59.68,25.46 59.43,25.21 57.46,25.21 56.83,24.57 56.44,24.57 56.44,25.59 56.95,26.1 57.71,26.1 57.84,26.23 57.84,26.99 58.1,27.24 59.37,27.24
+0.6VSP on TOP (solid shape): 62.92,26.42 62.92,20.95 62.03,20.95 62.03,21.78 61.65,22.16 60.89,22.16 60.64,21.91 60.64,21.69 60.57,21.63 59.8,21.63 59.73,21.69 59.73,21.83 59.81,21.91 59.94,21.91 60.64,22.61 60.64,23.11 60.51,23.24 59.37,23.24 59.11,22.99 59.11,22.1 59.05,22.03 58.98,22.03 58.92,22.1 58.92,23.24 59.24,23.56 59.87,23.56 60,23.69 60,24.76 60.57,24.76 60.57,26.16 60,26.16 60,26.67 60.16,26.83 62.51,26.83
+0.95VSDGPU on TOP (solid shape): outline of 440 points within 146.42,136.27 156.14,155.96
+0.95VSDGPU on IN1 (solid shape): outline of 774 points within 151.48,119.45 158.55,139.37
+0.95VSDGPU on IN2 (solid shape): outline of 186 points within 151.49,137.51 155.12,143.93
+0.95VSDGPU_OUT on TOP (solid shape): 147.91,156 147.91,152.87 147.69,152.65 146.76,152.65 146.74,152.65 145.57,152.65 144.65,152.65 144.39,152.91 144.39,153.49 144.44,153.49 144.67,153.8 144.38,154.05 144.36,154.05 144.07,154.34 143.39,154.34 143.31,154.41 143.31,155.07 143.38,155.13 144.01,155.13 144.14,155.26 144.14,156.02 144.27,156.15 147.77,156.15
+1.0V_CLK5 on TOP (solid shape): outline of 289 points within 127,90.49 129.2,96.67
+1.0V_MPHYGT on TOP (solid shape): outline of 884 points within 129.72,88.39 145.2,107.98
+1.0V_MPHYGT on BOTTOM (solid shape): 143.04,107.15 143.04,104.67 142.91,104.55 142.09,104.55 141.96,104.67 141.96,106.83 141.33,107.47 141.33,107.66 141.45,107.79 142.41,107.79
+1.0V_MPHYGT on BOTTOM (solid shape): 130.14,90.25 130.19,90.2 130.25,90.17 130.26,90.17 130.54,89.89 130.54,89.56 130.31,89.33 130.31,89 130.51,88.8 130.51,88.65 130.41,88.54 129.65,88.54 129.07,89.12 129.07,89.14 129.03,89.33 128.89,89.46 128.86,89.47 128.86,89.64 128.96,89.74 129.54,89.74 129.72,89.92 129.72,90.12 129.77,90.17 129.84,90.2 129.88,90.25
+1.0V_MPHYGT on IN1 (solid shape): outline of 302 points within 129.58,88.42 135.63,90.93
+1.0V_PRIM on TOP (solid shape): 145.85,157.67 145.85,156.53 145.73,156.4 143.5,156.4 143.31,156.59 143.31,157.42 143.6,157.71 143.6,158.09 143.69,158.18 145.34,158.18
+1.0V_PRIM on TOP (solid shape): 127.77,85.88 127.92,85.73 127.91,85.7 127.9,85.58 127.92,85.47 127.92,85.46 127.92,85.22 128.33,85.22 128.33,84 128.32,84 128.32,83.11 128.25,83.03 127.92,83.03 127.84,83.11 127.84,83.64 127.61,83.86 127.16,83.86 127.06,83.96 127.06,83.99 127.07,84 127.09,84.1 127.08,84.21 127.08,84.84 127.06,84.86 127.06,85.91 127.26,86.11 127.54,86.11
+1.0V_PRIM on TOP (solid shape): 138.58,114.5 138.69,114.39 139.3,114.39 139.37,114.32 139.37,113.72 139.49,113.61 140.57,113.61 140.57,112.31 141.07,111.8 141.07,108.58 140.13,107.64 134.93,107.64 134.49,108.08 133.77,108.08 133.71,108.14 133.71,108.78 133.77,108.84 135.29,108.84 135.38,108.93 137.92,108.93 138.11,109.12 138.11,111.44 137.84,111.7 136.06,111.7 135.93,111.83 135.93,112.97 136.06,113.1 136.82,113.1 136.96,113.24 136.96,115.77 138.58,115.77
+1.0V_PRIM on TOP (solid shape): outline of 171 points within 137.85,88.14 147.12,107.38
+1.0V_PRIM on BOTTOM (solid shape): 130.17,97.35 130.55,96.96 130.55,96.65 130.74,96.46 130.74,96.27 130.68,96.2 130.55,96.2 130.3,96.46 130.3,96.77 129.82,97.25 129.82,97.63 129.91,97.73 130.17,97.73
+1.0V_PRIM on BOTTOM (solid shape): 136.65,113.64 137.35,113.64 137.35,114.19 137.85,114.19 137.85,113.64 138.55,113.64 138.55,114.19 139.21,114.19 139.44,113.96 139.44,112.27 139.19,112.01 136.62,112.01 135.69,112.94 135.69,113.88 136,114.19 136.65,114.19
+1.0V_PRIM on BOTTOM (solid shape): 132.9,99.06 132.9,97.35 133.07,97.18 133.07,96.73 133.22,96.58 133.22,96.25 133.17,96.2 133.03,96.2 132.71,96.52 132.71,96.9 132.33,97.28 132.33,97.66 132.14,97.85 131.76,97.85 131.69,97.92 131.69,98.36 132.2,98.36 132.39,98.55 132.39,99.12 132.84,99.12
+1.0V_PRIM on BOTTOM (solid shape): 128.78,86.86 128.96,86.68 128.96,86.56 128.83,86.44 128.83,86.37 128.82,86.36 128.78,86.22 128.82,86.08 128.83,86.06 128.83,85.93 129.21,85.55 129.21,85.29 129.13,85.21 128.92,85.21 128.56,85.56 128.22,85.57 128.19,85.22 128.33,85.05 128.33,84.91 128.2,84.78 127.81,84.78 127.74,84.8 127.67,84.78 127.18,84.78 126.8,85.17 126.8,85.67 127.05,85.93 127.1,85.88 127.72,85.88 127.77,85.93 127.82,85.93 128.07,86.18 128.07,86.29 128.08,86.32 128.12,86.34 128.32,86.43 128.42,86.64 128.42,86.65 128.71,86.94 128.78,86.94
+1.0V_PRIM on IN1 (solid shape): outline of 112 points within 132.25,102.9 139.4,113.91
+1.0V_PRIM on IN2 (solid shape): outline of 202 points within 125.72,86.42 140.2,91.44
+1.0V_PRIM on IN2 (solid shape): outline of 1086 points within 134.17,112.08 146.42,158.62
+1.0V_PRIM on VCC: 125.15,80.9 125.15,81.94 125.51,82.3 126.78,82.3 127.56,83.08 127.56,83.46 127.8,83.69 131.1,83.69 137.98,90.57 137.98,97.39 137.22,98.15 137.22,101.45 136.07,102.59 136.07,104.82 135.18,105.71 135.18,108.1 136.01,108.92 136.01,113.92 139.02,113.92 140.39,112.54 140.39,107.21 141.79,105.81 141.79,88.62 141.43,88.26 140.41,88.26 138.61,86.47 138.61,82.53 137.62,81.53 129.94,81.53 129.3,80.9
+1.0V_SRAM on TOP (solid shape): 129.6,88.2 129.03,87.63 128.39,87.63 128.2,87.82 127.88,87.82 127.63,87.57 127.63,87.38 127.5,87.25 127.31,87.25 127.18,87.38 127.18,88.14 127.33,88.29 128.38,88.29 128.38,88.24 128.39,88.18 128.41,88.13 128.43,88.09 128.46,88.05 128.5,88.01 128.54,87.98 128.59,87.96 128.64,87.94 128.69,87.93 128.74,87.93 128.79,87.94 128.84,87.96 128.89,87.98 128.93,88.01 128.96,88.05 129,88.09 129.02,88.13 129.03,88.18 129.04,88.24 129.04,88.29 129.03,88.34 129.02,88.39 129,88.43 128.96,88.48 128.93,88.51 128.89,88.54 128.84,88.57 128.79,88.58 128.74,88.59 128.69,88.59 128.64,88.58 128.59,88.57 128.54,88.54 128.5,88.51 128.46,88.48 128.43,88.43 128.41,88.39 128.39,88.34 128.38,88.29 127.33,88.29 127.88,88.84 127.99,88.84 128.03,88.83 128.09,88.83 128.12,88.84 128.68,88.84 128.71,88.83 128.77,88.83 128.81,88.84 128.96,88.84 129.09,88.96 129.6,88.96
+1.0V_SRAM on IN1 (solid shape): outline of 418 points within 125.8,83.82 131.5,88.07
+1.0V_VCCST on TOP (solid shape): 130.09,108.15 129.52,108.15 129.52,107.64 130.09,107.64 130.09,107.13 129.77,106.81 129.77,105.99 129.79,105.97 129.79,105.35 129.15,105.35 129.14,105.36 129.14,108.21 129.33,108.4 130.09,108.4
+1.0V_VCCST_C on TOP (solid shape): 132.31,108.78 132.31,108.02 131.8,107.51 131.8,107.07 130.6,107.07 130.28,107.38 130.28,108.4 130.98,108.4 131.42,108.84 132.25,108.84
+1.0V_VCCSTG on TOP (solid shape): 128.07,111.38 127.82,111.12 126.8,111.12 126.61,111.32 126.61,114.87 126.8,115.06 128.07,115.06
+1.0V_VCCSTG_C on TOP (solid shape): outline of 119 points within 128.26,112.01 136.71,116.56
+1.0VS_VCCIO on TOP (solid shape): 115.04,82.3 115.04,80.59 114.89,80.44 114.05,80.44 114.05,81.9 114.62,82.47 114.86,82.47
+1.0VS_VCCIO on TOP (solid shape): 132.45,112.78 133.85,112.78 133.85,113.35 134.11,113.35 134.17,113.28 134.17,111.96 133.29,111.08 133.29,110.66 133.21,110.58 130.13,110.58 129.95,110.76 129.68,110.76 129.55,110.9 129.55,111.52 130.42,112.39 130.42,113.28 130.49,113.35 132.45,113.35
+1.0VS_VCCIO on TOP (solid shape): outline of 116 points within 120.81,79.81 125.07,84.73
+1.0VS_VCCIO on BOTTOM (solid shape): 115.41,82.44 115.41,81.42 115.41,81.36 115.41,81.3 115.41,80.76 114.9,80.25 114.7,80.25 114.6,80.35 114.6,81.02 114.69,81.1 114.96,81.1 115.07,81.22 115.07,81.76 114.91,81.92 114.57,81.92 114.49,82 114.49,82.5 114.63,82.64 115.21,82.64
+1.0VS_VCCIO on BOTTOM (solid shape): 122.23,81.48 122.23,80.78 122.8,80.21 122.8,79.96 122.67,79.83 122.34,79.83 122.33,79.86 122.15,80.02 121.92,79.97 121.77,79.83 121.5,79.83 121.34,79.97 121.31,79.99 121.02,80.28 121.02,81.42 121.04,81.49 121.05,81.55 121.05,81.57 121.34,81.86 121.85,81.86
+1.0VS_VCCIO on IN1 (solid shape): outline of 2192 points within 111.33,81.42 123.12,91.64
+1.0VS_VCCIO on VCC: 121.45,80.9 121.43,87.5 125.38,87.5 126.04,88.16 126.04,94.5 128.39,96.66 128.39,105.3 129.41,106.32 129.41,112.78 131.86,112.78 133,113.92 135.5,113.92 135.5,109.13 134.68,108.31 134.68,105.5 135.57,104.61 135.57,102.38 136.71,101.24 136.71,97.94 137.47,97.18 137.47,90.78 130.89,84.2 127.59,84.2 127.06,83.67 127.06,83.29 126.57,82.8 125.3,82.8 124.64,82.15 124.64,79.81 124.62,79.79 121.46,79.79 121.45,79.8
+1.0VS_VCCOPC on TOP (solid shape): 93.64,91.78 92.69,91.78 92.5,91.97 92.5,93.12 92.69,93.31 93.64,93.31
+1.0VS_VCCOPC on TOP (solid shape): 52.32,55.79 52.32,53.28 52.13,53.09 50.29,53.09 50.23,53.14 50.23,53.49 50.24,53.5 50.79,53.5 50.79,53.5 50.79,54.03 50.79,54.04 50.24,54.04 50.24,54.04 50.24,54.29 50.24,54.29 50.79,54.29 50.79,54.3 50.79,54.83 50.79,54.84 50.22,54.84 50.22,55.63 50.55,55.96 52.15,55.96
+1.0VS_VCCOPC on TOP (solid shape): 107.76,88.63 107.76,88.3 108.33,87.73 108.94,87.73 109.1,87.57 109.1,87.05 109.37,86.78 111.69,86.78 111.75,86.71 111.75,86.24 111.62,86.11 110.16,86.11 109.91,85.86 109.91,85.36 109.81,85.26 109.29,85.26 109.21,85.34 109.21,85.49 109.21,85.5 109.01,85.71 107.28,85.71 107.28,85.7 107.23,85.7 107.13,85.6 106.88,85.6 106.69,85.79 106.69,86.87 106.77,86.96 106.77,88.57 106.94,88.74 107.66,88.74
+1.0VS_VCCOPC on BOTTOM (solid shape): 104.34,90.39 104.34,85.45 104.27,85.37 103.41,85.37 103.36,85.42 103.36,85.57 103.8,86.01 103.8,86.84 103.41,87.23 103.41,87.45 103.87,87.91 103.87,88.59 103.38,89.08 103.38,89.3 103.7,89.61 103.7,89.72 103.75,89.77 103.75,90 103.76,90.08 103.75,90.16 103.75,90.38 103.86,90.5 104.23,90.5
+1.0VS_VCCOPC on IN1 (solid shape): outline of 3751 points within 73.47,61.91 108.72,94.49
+1.0VS_VCCOPC on IN2 (solid shape): outline of 347 points within 47.62,52.96 75.51,65.53
+1.0VS_VCCOPCP on TOP (solid shape): 50.09,55.31 50.09,54.69 50.1,54.69 50.64,54.69 50.64,54.69 50.64,54.44 50.64,54.44 50.1,54.44 50.09,54.44 50.09,53.89 50.1,53.89 50.64,53.89 50.64,53.89 50.64,53.64 50.64,53.63 50.1,53.63 50.09,53.63 50.09,53.15 49.84,52.9 48.25,52.9 48.06,53.09 48.06,55.37 48.19,55.5 49.9,55.5
+1.0VS_VCCOPCP on BOTTOM (solid shape): 50.03,50.67 49.97,50.61 46.41,50.61 45.78,51.24 45.78,56.01 48.38,56.01 49.4,57.02 49.4,57.91 50.03,57.91
+1.2V_DDR on TOP (solid shape): outline of 24842 points within 73.21,14.41 150.55,80.9
+1.2VP on TOP (solid shape): 57.46,26.73 57.46,23.69 57.91,23.24 57.91,22.1 57.84,22.03 57.78,22.03 57.71,22.1 57.71,22.67 56.95,23.43 56.95,26.73 57.08,26.86 57.33,26.86
+1.2VP on TOP (solid shape): 78,25.15 78.03,25.15 78.03,25.14 78.73,25.14 78.73,25.15 78.75,25.15 78.75,25.66 79.18,25.66 79.18,25.08 80.26,25.08 80.57,24.76 80.57,20 80.32,19.75 76.96,19.75 76.89,19.82 76.89,23.95 76.75,24.08 76.75,25.01 76.83,25.08 77.57,25.08 77.57,25.66 78,25.66
+1.2VP on BOTTOM (solid shape): 81.27,22.86 81.27,16.13 80.83,15.68 77.27,15.68 76.76,16.19 76.76,23.05 77.08,23.37 80.77,23.37
+1.5V_MEM_GFX on TOP (solid shape): 163,143.38 163,142.62 163.05,142.57 163.04,142.54 163.06,142.31 163.22,142.14 163.25,142.13 163.25,142.01 163.18,142.01 163.16,142.03 162.54,141.84 163.09,141.5 163.2,141.51 163.25,141.42 163.25,141.35 164.01,140.59 164.01,139.45 163.76,139.19 163.38,139.19 162.24,140.33 161.98,140.33 161.47,140.84 161.35,140.84 160.97,141.22 160.97,141.35 161.22,141.6 161.47,141.6 161.92,141.63 161.99,142.07 161.98,142.08 161.98,142.11 161.22,142.88 161.22,143 162.11,143.89 162.49,143.89
+1.5V_MEM_GFX on BOTTOM (solid shape): 138.23,156.72 138.23,150.75 138.04,150.56 137.48,150.56 137.48,151.07 136.78,151.07 136.78,150.56 136.28,150.56 136.28,151.07 135.58,151.07 135.58,150.56 134.61,150.56 134.42,150.75 134.42,156.84 134.61,157.04 137.92,157.04
+1.5V_MEM_GFX on BOTTOM (solid shape): 166.38,161.75 166.74,161.75 166.74,161.29 165.54,160.08 164.98,160.08 164.65,160.41 164.65,160.43 165.53,161.31 165.63,161.34 165.7,161.27 166.3,161.1 166.13,161.7 166.06,161.77 166.09,161.87 166.16,161.95 166.19,161.95
+1.5V_MEM_GFX on BOTTOM (solid shape): outline of 3461 points within 162.81,141.1 199.57,178.75
+1.5V_MEM_GFX on IN1 (solid shape): outline of 2110 points within 161.92,130.2 199.51,155.13
+1.5V_MEM_GFX on IN2 (solid shape): 178.69,162.66 178.69,162.13 178.63,162.04 178.52,162.06 178.04,162.54 178.04,163.16 176.46,164.74 176.45,164.79 176.5,164.82 176.53,164.82
+1.5V_MEM_GFX on IN2 (solid shape): 182.1,168.46 182.21,168.48 182.28,168.38 182.28,166.79 181.69,166.2 181.59,166.18 181.52,166.24 180.93,166.37 181.06,165.79 181.13,165.71 181.1,165.62 179.97,164.48 179.86,164.46 179.79,164.53 179.64,164.76 179.38,164.81 179.28,164.84 179.26,164.94 179.27,165.05 179.23,165.17 179.23,165.18 179.23,165.58 179.62,165.97 179.7,166 179.78,165.96 180.33,165.89 180.27,166.45 180.22,166.52 180.25,166.61
+1.5V_MEM_GFX on IN2 (solid shape): outline of 912 points within 184.88,147.35 194.94,158.41
+1.5V_MEM_GFX on IN2 (solid shape): outline of 9643 points within 134.42,132.52 200.02,177.16
+1.5V_MEM_GFX on VCC: 174.46,128.35 171.29,131.51 170.53,131.51 170.11,131.93 170.11,133.2 169.01,134.3 166.6,134.3 165.64,135.25 163.74,135.25 162.41,136.65 161.5,136.65 160.99,136.14 156.9,136.14 156.9,136.76 152.46,141.2 152.46,145.77 149.66,148.57 149.66,159.34 151.1,160.78 157.5,160.78 157.98,160.3 157.98,157.52 154.87,154.41 154.87,151.09 159.82,146.07 159.82,144.48 160.92,143.38 162.64,143.38 163.76,142.26 163.76,139.09 167.08,135.76 169.75,135.76 176.1,129.48 185.39,129.48 192.84,136.93 192.84,142.6 191.32,144.12 191.32,145.44 198.79,152.91 199.47,152.91 199.95,152.42 199.95,148.7 195.76,144.5 195.76,136.25 189.41,129.9 189.41,128.35
+1.5VGPUP on BOTTOM (solid shape): 136.16,150.43 136.18,150.43 136.18,150.41 136.88,150.41 136.88,150.43 136.91,150.43 136.91,150.93 137.36,150.93 137.36,150.43 137.38,150.43 137.38,150.41 138,150.41 138.09,150.41 138.17,150.34 138.17,147.54 138.08,147.45 133.15,147.45 132.77,147.07 132.77,146.3 132.33,145.86 126.36,145.86 125.91,146.3 125.91,148.53 126.93,149.54 131.06,149.54 131.31,149.29 133.03,149.29 134.15,150.41 135.68,150.41 135.68,150.43 135.71,150.43 135.71,150.93 136.16,150.93
+1.8V_PRIM on TOP (solid shape): 141.73,157.67 141.73,157.29 141.92,157.1 141.92,156.46 141.85,156.4 139.19,156.4 139.19,157.35 139.63,157.8 141.6,157.8
+1.8V_PRIM on TOP (solid shape): 187.51,38.86 184.08,35.43 174.11,35.43 173.41,36.13 173.41,37.59 173.6,37.78 175.32,37.78 175.89,37.21 184.4,37.21 186.56,39.37 187.51,39.37
+1.8V_PRIM on TOP (solid shape): outline of 169 points within 147.87,82.11 160.97,101.09
+1.8V_PRIM on BOTTOM (solid shape): 175.29,37.91 175.29,36.84 175.15,36.7 173.03,36.7 173.03,37.27 171.63,37.27 171.63,36.77 171.26,36.77 171.25,36.78 171.25,37.36 171.31,37.41 171.36,37.49 171.36,37.49 171.45,37.59 171.45,38.43 171.56,38.53 174.67,38.53
+1.8V_PRIM on IN1 (solid shape): 197.03,19.11 196.78,18.86 196.21,18.86 196.02,19.05 196.02,20.7 197.03,20.7
+1.8V_PRIM on IN1 (solid shape): 187.25,37.53 187.25,36.64 186.3,36.64 185.35,37.59 185.35,37.91 185.86,38.42 186.37,38.42
+1.8V_PRIM on IN1 (solid shape): outline of 273 points within 139.3,82.98 160.91,88.72
+1.8V_PRIM on IN1 (solid shape): outline of 1500 points within 139.25,99.23 149.83,159.45
+1.8V_PRIM on IN2 (solid shape): outline of 417 points within 124.39,83.87 140.57,86.99
+1.8VALWP on BOTTOM (solid shape): 176.08,36.19 176.08,30.86 176.02,30.8 175.38,30.8 173.98,32.19 170.94,32.19 170.74,32.38 170.74,36.26 171,36.51 175.76,36.51
+1.8VGS on TOP (solid shape): outline of 249 points within 137.98,122.05 157.12,152.99
+1.8VGS_OUT on TOP (solid shape): 141.95,155.07 141.95,154.39 141.77,154.21 141.71,154.16 141.67,154.11 141.41,153.85 141.41,153.03 141.23,152.86 140.24,152.86 139.96,152.58 139.63,152.58 139.63,153.14 139.12,153.14 139.12,152.59 138.61,152.59 138.42,152.78 138.42,154.81 138.74,155.13 141.89,155.13
+1VALWP on TOP (solid shape): 137.61,118.97 137.61,117.81 137.46,117.67 135.95,117.67 135.82,117.79 135.82,118.88 136.05,119.12 136.82,119.12 136.83,119.12 137.45,119.12
+1VALWP on BOTTOM (solid shape): outline of 115 points within 132.84,113.62 139.5,120.33
+2.5V_MEM on TOP (solid shape): 148.19,38.05 148.19,36.7 148.4,36.49 148.4,36.29 148.4,36.29 148.4,34.2 148.4,34.2 148.4,34.09 149.16,33.33 149.16,32.97 148.19,32 147.63,32 146.54,33.09 146.54,34.19 146.55,34.19 146.55,34.42 146.7,34.89 146.55,35.35 146.54,35.37 146.47,35.46 146.38,35.53 145.85,36.06 145.85,37.85 146.23,38.23 148.01,38.23
+2.5V_MEM on TOP (solid shape): outline of 86 points within 152.31,16.61 161.2,25.35
+2.5V_MEM on BOTTOM (solid shape): 146.38,38.29 146.38,36.83 146.19,36.64 145.49,36.64 143.97,38.17 143.97,39.76 144.1,39.88 144.79,39.88
+2.5V_MEM on BOTTOM (solid shape): 153.74,25.11 154.95,25.11 155.07,24.99 155.07,24.03 154.82,23.78 152.72,23.78 152.6,23.91 152.6,25.43 152.72,25.56 153.3,25.56
+2.5V_MEM on BOTTOM (solid shape): 72.19,32.51 72.19,30.67 72,30.48 69.65,30.48 69.59,30.54 69.59,30.86 70.16,30.86 70.16,32.26 69.59,32.26 69.59,32.7 69.72,32.83 71.88,32.83
+2.5V_MEM on IN1 (solid shape): 72.26,31.94 72.26,29.5 71.3,28.55 70.81,28.55 69.75,29.6 69.75,29.96 70.22,30.43 70.22,32.07 70.61,32.45 71.75,32.45
+2.5V_MEM on IN1 (solid shape): 161.53,17.97 161.53,17.1 160.02,15.58 159.08,15.58 158.37,16.3 158.37,16.98 160.16,18.77 160.74,18.77
+2.5VP on BOTTOM (solid shape): 69.4,30.42 69.21,30.23 64.19,30.23 64.06,30.35 64.06,30.73 64.26,30.92 65.84,30.92 66.35,31.43 66.35,32.13 66.8,32.58 69.4,32.58
+3.3V_ALW_DSW on BOTTOM (solid shape): 147.92,88.49 147.92,87.67 148.12,87.46 150.23,87.46 150.45,87.25 151.57,87.25 151.63,87.19 151.63,86.61 151.5,86.49 148.08,86.49 147.8,86.77 147.33,86.77 146.91,87.18 146.91,88.57 147.04,88.7 147.71,88.7
+3.3V_LAN_UZ2 on TOP (solid shape): 45.09,18.85 45.09,18.08 45.09,18.08 45.09,17.32 44.86,17.09 44.73,17.09 44.73,16.57 44.54,16.38 44.04,16.38 43.62,15.96 43.62,15.62 43.49,15.49 40.44,15.49 40.32,15.62 40.32,16.33 39.74,16.33 39.74,16.77 40.25,16.77 40.25,16.79 40.26,16.79 40.26,17.5 40.25,17.5 40.25,17.52 39.74,17.52 39.74,17.97 40.25,17.97 40.25,17.99 40.26,18 40.32,18 40.32,18.73 40.51,18.92 45.01,18.92
+3.3V_SPI on BOTTOM (solid shape): 161.02,70.68 161.6,70.68 161.92,70.36 161.92,69.09 161.69,68.86 156.05,68.86 155.7,69.22 155.7,71.76 155.77,71.83 156.49,71.83 156.74,71.57 156.74,69.87 156.89,69.72 157.89,69.72 158.01,69.83 158.01,70.55 158.22,70.77 159.78,70.77 159.78,70.71 159.79,70.66 159.81,70.61 159.83,70.56 159.86,70.52 159.9,70.48 159.94,70.44 159.99,70.42 160.04,70.4 160.09,70.39 160.14,70.38 160.19,70.39 160.25,70.4 160.3,70.42 160.34,70.44 160.38,70.48 160.42,70.52 160.45,70.56 160.47,70.61 160.49,70.66 160.5,70.71 160.5,70.77 160.49,70.82 160.47,70.87 160.45,70.92 160.42,70.96 160.38,71 160.34,71.03 160.3,71.06 160.25,71.08 160.19,71.09 160.14,71.1 160.09,71.09 160.04,71.08 159.99,71.06 159.94,71.03 159.9,71 159.86,70.96 159.83,70.92 159.81,70.87 159.79,70.82 159.78,70.77 158.22,70.77 158.69,71.23 158.69,71.83 158.87,72.01 159.69,72.01
+3.3V_WLAN on BOTTOM (solid shape): outline of 529 points within 162.93,37.66 175.63,64.45
+3V_DVDD on TOP (solid shape): 178.49,21.84 178.49,20.51 179.89,19.11 179.89,14.81 179.94,14.76 182.3,14.76 182.43,14.63 182.43,13.84 181.79,13.21 180.52,13.21 179.5,14.23 179.48,14.26 179.45,14.3 179.43,14.32 181.24,14.32 181.25,14.26 181.26,14.21 181.28,14.16 181.3,14.12 181.34,14.07 181.38,14.04 181.42,14.01 181.47,13.99 181.52,13.97 181.57,13.96 181.62,13.96 181.68,13.97 181.73,13.99 181.78,14.01 181.82,14.04 181.86,14.07 181.89,14.12 181.92,14.16 181.94,14.21 181.95,14.26 181.96,14.32 181.95,14.37 181.94,14.42 181.92,14.47 181.89,14.52 181.86,14.56 181.82,14.6 181.78,14.63 181.73,14.65 181.68,14.67 181.62,14.67 181.57,14.67 181.52,14.67 181.47,14.65 181.42,14.63 181.38,14.6 181.34,14.56 181.3,14.52 181.28,14.47 181.26,14.42 181.25,14.37 181.24,14.32 179.43,14.32 179.39,14.34 178.94,14.8 178.81,14.8 178.3,15.3 178.3,19.62 177.82,20.1 177.84,20.17 177.87,20.17 177.87,20.73 177.79,20.73 177.79,21.78 177.92,21.91 178.43,21.91
+3VALW on TOP (solid shape): 144.96,115.86 144.96,114.81 144.76,114.61 143.63,114.61 143.42,114.83 143.42,115.88 143.62,116.08 144.73,116.08
+3VALW on TOP (solid shape): 192.14,87.37 192.14,86.54 191.95,86.36 190.17,86.36 189.86,86.67 189.86,87.48 190.07,87.69 191.81,87.69
+3VALW on TOP (solid shape): 45.09,25.13 45.09,20.27 45.01,20.19 43.31,20.19 43.11,20.4 43.11,25.15 43.36,25.4 44.82,25.4
+3VALW on TOP (solid shape): 197.54,76.39 197.54,74.36 197.03,74.36 197.03,74.42 196.72,74.74 196.53,74.74 196.4,74.87 196.4,76.52 196.46,76.58 197.35,76.58
+3VALW on TOP (solid shape): 69.65,174.5 69.65,171.92 67.46,171.92 65.84,173.54 63.26,173.54 62.79,173.07 60.85,173.07 60.06,172.28 59.18,172.28 58.82,172.64 58.82,174.78 60.88,176.85 67.3,176.85
+3VALW on TOP (solid shape): 197.47,168.48 197.47,167.21 197.92,166.75 198.68,166.75 199.13,166.31 199.13,165.93 199,165.8 197.48,165.8 196.65,166.62 196.65,168.4 196.91,168.66 197.29,168.66
+3VALW on TOP (solid shape): 182.17,63.44 182.17,62.93 182.05,62.8 181.86,62.8 180.4,61.34 180.4,59.56 180.27,59.44 179.51,59.44 179.06,59.88 179.06,62.1 179.7,62.74 180.14,62.74 180.4,62.99 180.4,63.44 180.52,63.56 182.05,63.56
+3VALW on TOP (solid shape): 151.63,89.09 151.63,88.71 151.95,88.39 153.41,88.39 154.04,87.76 154.74,87.76 154.74,86.74 153.79,86.74 153.16,87.38 150.49,87.38 150.36,87.5 150.36,89.03 150.55,89.22 151.5,89.22
+3VALW on TOP (solid shape): 71.37,166.88 71.37,166.05 70.99,165.67 70.99,162.62 71.42,162.19 71.42,159.68 72.99,158.11 75.24,158.11 80.51,152.84 84.35,152.84 84.89,152.3 84.89,151.97 84.66,151.74 83,151.74 82.8,151.8 82.59,151.74 82.39,151.74 82.32,151.67 82.32,151.16 82.16,151 80.96,151 74.8,157.16 71.7,157.16 70.85,158.01 70.85,158.74 70.54,159.05 70.54,160.83 69.72,161.66 69.72,166.5 70.29,167.07 71.18,167.07
+3VALW on TOP (solid shape): 174.26,79.83 174.26,79.34 174.16,79.24 173.54,79.24 172.59,78.28 172.59,76.52 171.95,75.88 171.95,75.31 171.96,75.3 171.96,75.05 172.59,74.42 172.59,72.71 172.65,72.64 172.65,71.18 172.59,71.12 171.82,71.12 170.18,72.77 170.18,73.41 171.47,73.41 171.47,73.35 171.48,73.3 171.5,73.25 171.53,73.2 171.56,73.16 171.6,73.13 171.65,73.1 171.69,73.07 171.74,73.06 171.8,73.05 171.85,73.05 171.9,73.06 171.95,73.07 172,73.1 172.05,73.13 172.09,73.16 172.12,73.2 172.15,73.25 172.17,73.3 172.18,73.35 172.18,73.41 172.18,73.46 172.17,73.51 172.15,73.56 172.12,73.61 172.09,73.65 172.05,73.69 172,73.72 171.95,73.74 171.9,73.75 171.85,73.76 171.8,73.76 171.74,73.75 171.69,73.74 171.65,73.72 171.6,73.69 171.56,73.65 171.53,73.61 171.5,73.56 171.48,73.51 171.47,73.46 171.47,73.41 170.18,73.41 170.18,76.68 173.38,79.88 174.21,79.88
+3VALW on TOP (solid shape): outline of 159 points within 157.35,70.48 167.46,80.71
+3VALW on TOP (solid shape): outline of 1060 points within 159.93,19.56 180.14,54.29
+3VALW on BOTTOM (solid shape): 54.54,37.66 54.54,35.12 52.51,35.12 52.51,37.53 52.83,37.85 54.35,37.85
+3VALW on BOTTOM (solid shape): 157.73,171.13 157.73,170.81 157.6,170.69 156.33,170.69 155.82,171.2 155.76,171.2 155.76,172.21 156.65,172.21
+3VALW on BOTTOM (solid shape): 54.92,74.55 54.92,72.33 54.54,71.95 53.14,71.95 53.14,74.1 53.78,74.74 54.73,74.74
+3VALW on BOTTOM (solid shape): 172.9,19.81 172.78,19.69 169.67,19.69 169.35,20 169.35,20.76 169.54,20.95 172.9,20.95
+3VALW on BOTTOM (solid shape): 38.16,52.26 38.16,51.18 37.9,50.93 37.9,50.42 37.27,50.42 37.27,51.05 37.59,51.37 37.59,52.58 37.65,52.64 37.78,52.64
+3VALW on BOTTOM (solid shape): 151.69,90.11 151.69,88.03 151.58,87.91 150.62,87.91 150.55,87.98 150.55,88.65 150.23,88.96 150.23,90.3 151.5,90.3
+3VALW on BOTTOM (solid shape): 51.92,64.69 51.92,63.91 52.72,63.11 52.72,62 52.1,61.38 51.85,61.38 51.84,61.42 51.72,61.62 51.5,61.7 51.48,61.7 50.29,62.89 50.29,63.55 49.59,64.25 49.59,65.23 49.68,65.32 51.3,65.32
+3VALW on BOTTOM (solid shape): 71.3,173.29 71.3,171.51 70.92,171.13 68.19,171.13 67.11,170.05 67.11,168.15 68.57,166.69 69.91,166.69 70.29,167.07 71.18,167.07 71.37,166.88 71.37,165.89 70.33,164.85 67.56,164.85 65.14,167.26 65.14,172.08 66.6,173.55 71.05,173.55
+3VALW on BOTTOM (solid shape): outline of 440 points within 175.58,69.21 189.92,79.76
+3VALW on BOTTOM (solid shape): outline of 843 points within 26.85,9.91 45.08,25.27
+3VALW on IN1 (solid shape): outline of 177 points within 43.11,22.28 54.6,36.58
+3VALW on IN1 (solid shape): outline of 192 points within 164.89,70.85 176.08,76.96
+3VALW on IN2 (solid shape): 199.19,166.62 199.19,165.9 198.96,165.67 197.24,165.67 197.03,165.88 197.03,166.62 197.16,166.75 199.07,166.75
+3VALW on IN2 (solid shape): 158.43,172.53 157.79,171.89 157.79,170.88 157.6,170.69 156.71,170.69 156.58,170.81 156.58,172.28 157.03,172.72 158.43,172.72
+3VALW on IN2 (solid shape): 180.02,60.3 180.02,53.83 179.63,53.45 179.63,50.16 179.44,49.96 178.72,49.96 178.72,53.97 179,54.25 179,59.12 179,59.12 178.89,59.23 178.89,60.55 179.05,60.7 179.62,60.7
+3VALW on VCC: outline of 100 points within 51.36,73 101.02,152.91
+3VALW on VCC: 64.85,11.81 153.39,11.81 159.18,17.73 163.11,21.66 164.65,21.72 169.12,21.72 169.5,21.34 173.69,21.34 174.05,20.98 174.05,18.27 173.28,17.5 173.28,9.76 170.13,6.6 91.19,6.6 89.86,7.94 57.76,7.94 52.23,13.46 48.08,13.46 46.41,11.79 46.41,2.44 36.25,2.44 36.25,10.65 35.36,11.54 35.36,15.85 34.22,17 34.22,22.12 35.98,23.88 49.86,23.88 50.73,23.01 50.73,19.58 51.64,18.67 54.43,18.67 55.58,17.53 59.26,17.53 61.91,14.88 61.91,14.75
+3VALW_PCH on TOP (solid shape): outline of 1776 points within 126.42,79.33 153.79,89.89
+3VALW_PCH on BOTTOM (solid shape): 139.65,102.79 139.65,102.23 139.23,101.82 137.07,101.82 137.01,101.88 137.01,102.39 137.07,102.45 138.72,102.45 139.17,102.9 139.55,102.9
+3VALW_PCH on BOTTOM (solid shape): 145.9,91.22 145.92,91.13 145.87,91.05 145.79,90.49 146.36,90.57 146.43,90.62 146.52,90.59 146.65,90.46 146.65,86.66 145.85,85.87 145.83,85.88 145.47,85.79 145.38,85.43 145.39,85.41 145.34,85.36 144.88,85.36 144.82,85.42 144.82,90.45 144.95,90.58 144.95,91.28 145.01,91.34 145.77,91.34
+3VALW_PCH on IN1 (solid shape): outline of 265 points within 124.82,81.98 131.21,86.82
+3VALWP on TOP (solid shape): 35.54,26.03 35.31,25.81 33.71,25.81 33.36,26.16 33.36,27.41 33.46,27.51 35.54,27.51
+3VALWP on BOTTOM (solid shape): 37.01,25.4 36.76,25.15 31.81,25.15 31.11,24.45 27.81,24.45 27.54,24.71 27.54,26.01 27.55,26.01 27.55,29.91 28.03,30.39 37.01,30.39
+3VGS on BOTTOM (solid shape): outline of 219 points within 178.52,118.62 187.46,125.09
+3VGS on IN2 (solid shape): outline of 284 points within 171.81,122.05 185.22,129.54
+3VGS_OUT on BOTTOM (solid shape): outline of 101 points within 187.05,118.77 192.34,124.83
+3VLP on BOTTOM (solid shape): 35.15,37.07 38.27,37.07 38.35,37 38.35,36.46 38.32,36.39 38.24,36.36 38.19,36.36 38.14,36.35 37.25,36.35 36.84,35.94 34.5,35.94 34.35,36.09 34.35,37.11 34.42,37.19 35.03,37.19
+3VS on TOP (solid shape): 40.13,18.86 40.13,18.1 39.61,18.1 39.61,17.39 40.13,17.39 40.13,16.9 39.61,16.9 39.61,16.19 40.13,16.19 40.13,13.91 39.68,13.46 35.74,13.46 35.36,13.84 35.36,16.89 37.52,19.05 39.93,19.05
+3VS on TOP (solid shape): 28.63,61.68 28.63,60.89 28.72,60.8 28.72,59.97 29.03,59.66 30.43,59.66 30.62,59.47 30.62,58.64 31.07,58.19 31.96,58.19 32.57,58.8 32.82,58.8 32.95,58.67 32.95,58.29 31.68,57.02 31.22,57.02 29.22,59.02 28.39,59.02 28.32,59.09 28.32,60.84 28.37,60.89 28.37,61.68 28.42,61.73 28.58,61.73
+3VS on TOP (solid shape): 167.06,34.35 167.06,23.24 166.87,23.05 163.95,23.05 163.57,23.43 163.12,23.43 163.12,23.88 163.38,24.13 163.38,28.18 163.41,28.19 163.61,28.51 163.41,28.83 163.38,28.85 163.38,34.42 164.01,35.05 166.36,35.05
+3VS on TOP (solid shape): 48.76,80.45 47.55,79.25 47.55,77.91 48.76,76.71 48.76,75.44 48.57,75.25 46.6,75.25 46.28,74.93 46.28,74.55 45.9,74.55 45.9,75.18 46.16,75.44 46.16,76.52 45.59,77.09 44,77.09 43.86,76.95 43.81,76.91 43.76,76.85 43.43,76.52 43.43,72.9 45.21,71.12 47.17,71.12 47.55,71.5 48.06,71.5 48.06,70.87 48.25,70.68 48.25,70.36 44.25,70.36 43.24,71.37 42.28,71.37 40.57,69.66 40.57,65.98 40.13,65.53 38.54,65.53 38.35,65.72 38.35,69.98 41.71,73.34 41.71,77.15 42.79,78.23 45.52,78.23 46.16,78.87 46.16,80.2 45.9,80.45 44.7,80.45 43.43,79.18 42.79,79.18 42.79,79.69 44.06,80.96 48.76,80.96
+3VS on TOP (solid shape): 195.78,118.17 195.78,115.36 195.25,114.84 195.22,114.82 195.18,114.8 195.14,114.76 195.11,114.72 195.1,114.68 195.05,114.63 194.32,114.63 193.8,115.15 193.8,115.7 192.59,116.9 188.32,116.9 188.18,117.04 188.18,117.39 190.16,117.39 190.16,117.34 190.16,117.29 190.18,117.23 190.2,117.19 190.23,117.14 190.27,117.1 190.31,117.07 190.36,117.04 190.41,117.02 190.46,117.01 190.51,117.01 190.56,117.01 190.62,117.02 190.67,117.04 190.71,117.07 190.75,117.1 190.79,117.14 190.82,117.19 190.84,117.23 190.86,117.29 190.87,117.34 190.87,117.39 190.86,117.44 190.84,117.5 190.82,117.54 190.79,117.59 190.75,117.63 190.71,117.66 190.67,117.69 190.62,117.71 190.56,117.72 190.51,117.72 190.46,117.72 190.41,117.71 190.36,117.69 190.31,117.66 190.27,117.63 190.23,117.59 190.2,117.54 190.18,117.5 190.16,117.44 190.16,117.39 188.18,117.39 188.18,118.34 188.47,118.63 195.32,118.63
+3VS on TOP (solid shape): outline of 135 points within 25.2,46.93 30.85,57.02
+3VS on BOTTOM (solid shape): 154.5,49.54 154.5,47.19 154.23,46.93 153.22,46.93 152.84,47.3 152.84,48.63 153.49,49.27 153.49,49.46 153.67,49.64 154.4,49.64
+3VS on BOTTOM (solid shape): 164.39,35.88 164.78,35.5 166.43,35.5 166.43,33.97 166.11,33.66 163.19,33.66 163.19,34.23 163,34.42 163,36.77 164.39,36.77
+3VS on BOTTOM (solid shape): 189.48,118.24 189.48,117.67 189.35,117.54 187.19,117.54 186.94,117.28 186.94,116.78 186.75,116.59 186.3,116.59 186.3,117.6 186.68,117.98 188.08,117.98 188.72,118.62 189.1,118.62
+3VS on BOTTOM (solid shape): 195.76,118.31 195.76,115.7 195.13,115.06 194.11,115.06 193.6,115.57 193.6,115.95 193.35,116.2 191.83,116.2 191.37,116.66 191.37,118.58 191.41,118.62 195.46,118.62
+3VS on BOTTOM (solid shape): 13.79,16.97 14.68,16.97 14.76,16.9 14.76,16.77 14.69,16.7 13.19,16.7 12.63,16.14 12.63,14.99 12.5,14.86 12.5,14.41 12.38,14.29 11.99,14.29 11.87,14.41 11.87,16.76 11.93,16.83 12.62,16.83 12.81,17.02 13.75,17.02
+3VS on BOTTOM (solid shape): 28.14,58.93 33.26,58.93 33.39,58.8 33.39,57.45 33.34,57.4 32.07,57.4 31.73,57.05 28.03,57.05 26.66,55.69 25.84,55.69 25.65,55.88 25.65,56.1 24.69,57.05 24.69,57.05 24.41,57.33 24.41,57.76 24.42,57.79 24.43,57.84 24.44,57.89 24.43,57.94 24.42,57.99 24.41,58.03 24.41,58.22 29.01,58.22 29.01,58.17 29.02,58.12 29.03,58.07 29.06,58.02 29.09,57.97 29.12,57.93 29.16,57.9 29.21,57.87 29.26,57.86 29.31,57.84 29.36,57.84 29.42,57.84 29.47,57.86 29.52,57.87 29.57,57.9 29.61,57.93 29.64,57.97 29.67,58.02 29.7,58.07 29.71,58.12 29.72,58.17 29.72,58.22 29.71,58.28 29.7,58.33 29.67,58.37 29.64,58.42 29.61,58.46 29.57,58.49 29.52,58.52 29.47,58.54 29.42,58.55 29.36,58.55 29.31,58.55 29.26,58.54 29.21,58.52 29.16,58.49 29.12,58.46 29.09,58.42 29.06,58.37 29.03,58.33 29.02,58.28 29.01,58.22 24.41,58.22 24.41,58.55 24.97,59.11 27.97,59.11
+3VS on BOTTOM (solid shape): outline of 107 points within 83.62,141.35 92.61,156.97
+3VS on BOTTOM (solid shape): outline of 867 points within 192.08,61.91 200.78,94.93
+3VS on IN1 (solid shape): 48.89,75.69 48.89,75.2 48.83,75.11 48.73,75.11 48.22,75.01 48.35,74.51 48.38,74.49 48.38,74.28 48.89,73.77 48.89,72.14 48.38,71.63 46.09,71.63 46.09,71.73 45.92,71.91 45.92,72.98 46.28,73.34 46.28,73.81 47.05,74.57 47.05,75.71 47.15,75.82 48.76,75.82
+3VS on IN1 (solid shape): 39.62,67.75 39.62,65.53 38.86,64.77 36.51,64.77 35.55,63.82 35.55,60.77 31.62,56.83 31.24,56.83 31.04,57.02 31.04,58.74 33.58,61.28 33.58,63.92 33.76,63.92 33.76,63.87 33.77,63.82 33.79,63.77 33.82,63.72 33.85,63.68 33.89,63.64 33.94,63.61 33.98,63.59 34.03,63.58 34.09,63.57 34.14,63.57 34.19,63.58 34.24,63.59 34.29,63.61 34.34,63.64 34.38,63.68 34.41,63.72 34.44,63.77 34.46,63.82 34.47,63.87 34.47,63.92 34.47,63.98 34.46,64.03 34.44,64.08 34.41,64.12 34.38,64.17 34.34,64.2 34.29,64.23 34.24,64.26 34.19,64.27 34.14,64.28 34.09,64.28 34.03,64.27 33.98,64.26 33.94,64.23 33.89,64.2 33.85,64.17 33.82,64.12 33.79,64.08 33.77,64.03 33.76,63.98 33.76,63.92 33.58,63.92 33.58,66.42 35.24,68.07 39.3,68.07
+3VS on IN1 (solid shape): 83.6,157.44 83.6,156.77 84.68,155.69 86.79,155.69 87.69,156.59 88.07,156.59 88.45,156.97 88.77,156.97 88.89,156.84 88.89,155.77 87.31,154.18 83.72,154.18 82.84,155.06 82.78,155.12 82.55,155.35 83.29,155.35 83.3,155.29 83.31,155.24 83.33,155.19 83.35,155.15 83.39,155.1 83.43,155.07 83.47,155.04 83.52,155.01 83.57,155 83.62,154.99 83.67,154.99 83.73,155 83.78,155.01 83.83,155.04 83.87,155.07 83.91,155.1 83.94,155.15 83.97,155.19 83.99,155.24 84,155.29 84.01,155.35 84,155.4 83.99,155.45 83.97,155.5 83.94,155.55 83.91,155.59 83.87,155.63 83.83,155.66 83.78,155.68 83.73,155.69 83.67,155.7 83.62,155.7 83.57,155.69 83.52,155.68 83.47,155.66 83.43,155.63 83.39,155.59 83.35,155.55 83.33,155.5 83.31,155.45 83.3,155.4 83.29,155.35 82.55,155.35 81.78,156.11 81.78,157.94 81.65,158.07 81.36,158.07 81.33,158.1 81.33,158.11 81.22,158.21 81.22,158.49 81.38,158.65 82.39,158.65
+3VS on IN1 (solid shape): outline of 855 points within 34.47,4.51 168.78,25.27
+3VS on IN1 (solid shape): outline of 1487 points within 190.68,90.04 197.41,117.86
+3VS on IN2 (solid shape): outline of 1832 points within 29.01,13.49 55.68,49.4
+3VS on VCC: 67.45,74.74 65.23,74.74 61.55,70.99 58.63,70.99 57.23,69.6 55.66,69.6 55.03,70.23 47.03,70.23 45.4,71.86 45.4,73.68 46.28,74.57 46.28,81.8 50.86,81.8 50.86,73.05 51.41,72.49 55.38,72.49 55.81,72.92 55.81,77.49 56.42,78.1 62.01,78.1 62.65,78.74 68.36,78.74 71.79,82.17 74.08,82.17 87.94,96.03 87.94,99.21 93.15,104.42 93.15,111.4 94.67,112.92 94.67,118.13 94.73,118.19 96.51,120.09 101.53,125.12 101.53,130.41 92.77,139.04 92.77,140.19 89.85,143.11 89.85,143.66 90.08,143.89 92.03,143.89 92.39,143.53 92.39,142.9 103.56,131.78 103.56,123.43 98.35,118.47 98.35,113.77 95.24,110.59 95.31,103.61 89.97,98.28 89.97,91.82 86.12,91.82 74.63,80.26 73.04,80.26
+3VS on VCC: 177.73,1.27 177.73,9.76 176.82,10.67 173.79,10.67 173.79,17.29 174.55,18.06 174.55,21.19 173.9,21.84 169.71,21.84 169.33,22.22 164.9,22.22 164.9,25.68 165.9,26.67 175.93,26.67 176.59,27.33 176.59,34.06 180.65,38.12 180.65,39.9 181.16,40.41 181.16,44.6 182.15,45.59 186.01,45.59 186.62,44.98 186.62,37.87 187.47,37.02 188.93,37.02 189.82,36.19 194.03,36.19 194.56,36.72 194.56,41.89 193.99,42.46 193.99,61.62 194.09,61.72 195.74,61.72 196.14,62.12 196.14,66.06 196.38,66.29 197.97,66.29 198.59,65.78 199.38,65.59 202.28,65.59 202.28,63.22 202.27,63.22 202.27,1.27 ; 1 cut-out
+5V_AVDD on BOTTOM (solid shape): 191.45,20.19 192.97,20.19 193.03,20.13 193.03,19.24 192.97,19.18 191.51,19.18 190.56,20.13 189.05,20.13 187.7,18.78 187.7,18.41 187.25,17.97 186.24,17.97 186.18,18.03 186.18,18.15 186.21,18.19 187.08,18.19 187.2,18.31 187.2,19.25 188.84,20.89 190.75,20.89
+5V_KB_BL on TOP (solid shape): 191.32,121.92 192.59,121.92 192.72,121.79 192.72,121.28 192.59,121.16 191.19,121.16 190.68,121.67 186.68,121.67 185.98,120.97 185.98,120.52 185.03,119.57 184.71,119.57 184.46,119.82 184.46,120.01 185.35,120.9 185.35,121.37 186.28,122.3 190.94,122.3
+5V_PVDD on BOTTOM (solid shape): 182.27,13.64 182.27,12.42 181.54,11.68 181.54,11.48 180.85,10.79 180.85,9.35 181.13,9.07 184.05,9.07 184.64,9.65 184.64,10.52 184.59,10.57 184.59,11.33 184.06,11.85 184.06,13.66 184.1,13.7 184.23,13.7 184.27,13.65 184.27,12.42 185.38,11.32 185.38,9.02 184.72,8.36 184.72,7.94 184.65,7.87 183.7,7.87 182.81,6.98 178.1,6.98 177.42,7.66 177.42,8.41 177.43,8.41 177.43,9.81 177.42,9.81 177.42,10.13 177.43,10.13 177.43,11.52 177.43,11.52 177.43,11.59 177.46,11.67 177.47,11.75 177.5,11.82 177.57,11.85 178.28,11.85 178.39,11.74 178.39,10.79 178.89,10.29 179.52,10.29 179.93,10.69 179.93,11.22 180.09,11.39 180.64,11.39 180.71,11.46 180.71,12 181.11,12.39 181.61,12.39 181.62,12.4 181.87,12.65 181.94,12.65 182.07,12.78 182.07,13.64 182.12,13.7 182.22,13.7
+5V_RUN_UZ2 on TOP (solid shape): 49.45,18.91 51.63,18.91 52.32,18.22 52.32,15.88 51.74,15.88 51.74,16.39 51.04,16.39 51.02,16.39 51.02,15.88 50.57,15.88 50.57,16.39 50.54,16.39 49.84,16.39 49.84,16.39 49.84,15.88 48.82,15.88 48.25,16.45 46.92,16.45 46.92,17.21 46.48,17.65 46.48,18.86 46.54,18.92 49.43,18.92
+5VALW on TOP (solid shape): 135.08,110.5 135.08,109.74 134.94,109.6 133.85,109.6 133.85,109.85 133.98,109.85 134.73,110.6 134.98,110.6
+5VALW on TOP (solid shape): 50.37,22.17 50.37,19.96 50.09,19.69 47.66,19.69 47.15,20.19 46.54,20.19 46.49,20.24 46.49,21.21 46.59,21.31 46.59,22.38 46.95,22.73 49.82,22.73
+5VALW on TOP (solid shape): 162.62,106.26 162.62,103.38 162.36,103.12 160.71,103.12 160.45,103.39 160.45,105.01 160.47,105.03 161,105.03 161,105.03 161.16,105.03 161.33,105.2 161.33,106.22 161.5,106.4 162.48,106.4
+5VALW on BOTTOM (solid shape): 29.58,44.01 29.39,43.81 27.62,43.81 27.36,44.07 27.36,44.48 28.57,45.69 29.58,45.69
+5VALW on BOTTOM (solid shape): 61.96,45.67 61.96,44.97 62.38,44.56 62.38,43.42 62.22,43.27 61.82,43.27 61.65,43.44 61.65,45.72 61.72,45.78 61.84,45.78
+5VALW on BOTTOM (solid shape): outline of 1610 points within 45.52,1.4 200.84,30.86
+5VALW on IN1 (solid shape): outline of 374 points within 26.22,16.99 50.09,45.66
+5VALW on IN2 (solid shape): outline of 381 points within 68.26,1.4 198.18,7.37
+5VALWP on BOTTOM (solid shape): 52.13,32.64 52.13,30.35 52.38,30.1 52.38,29.21 52.89,29.21 52.89,28.83 52.38,28.83 52.38,28 52.89,28 52.89,27.62 52.38,27.62 52.38,26.86 52.19,26.67 46.79,26.67 46.54,26.42 46.54,26.03 46.16,25.65 40.06,25.65 39.81,25.91 39.81,29.46 40.67,30.33 50.88,30.33 51.03,30.48 51.03,32.56 51.17,32.7 52.06,32.7
+5VS on TOP (solid shape): 34.6,72.9 34.6,70.48 33.97,69.85 33.2,69.85 30.28,72.77 30.28,73.28 30.66,73.66 33.84,73.66
+5VS on TOP (solid shape): 50.44,15.74 51.14,15.74 51.14,16.26 51.61,16.26 51.61,15.68 52.57,15.68 53.02,15.24 53.02,11.62 52.83,11.43 48.76,11.43 48.54,11.65 48.54,15.27 48.95,15.68 49.96,15.68 49.96,16.26 50.44,16.26
+5VS on TOP (solid shape): 185.73,45.79 185.73,42.04 185.1,41.4 181.79,41.4 181.67,41.53 181.67,42.35 181.79,42.48 183.38,42.48 183.64,42.74 183.64,44.45 182.81,45.28 182.31,45.28 182.03,45.46 181.71,45.35 181.64,45.28 177.92,45.28 177.67,45.02 177.67,44.13 176.84,43.31 176.84,42.86 176.78,42.8 175.44,42.8 175.44,46.99 176.08,47.62 183.9,47.62
+5VS on BOTTOM (solid shape): 34.75,71.4 34.75,70.13 34.69,70.07 32.59,70.07 32.53,70.13 32.53,71.4 32.78,71.66 34.49,71.66
+5VS on BOTTOM (solid shape): 194.87,19.94 194.87,16.38 194.62,16.13 193.86,16.13 193.6,16.38 193.6,19.24 193.67,19.24 193.67,20.13 193.73,20.19 194.62,20.19
+5VS on BOTTOM (solid shape): 176.69,11.58 176.67,11.52 176.67,10.13 176.73,10.13 176.73,9.81 176.67,9.81 176.67,8.35 176.42,8.1 176.39,8.12 175.96,8.04 175.88,7.61 175.9,7.58 175.81,7.49 173.92,7.49 173.67,7.75 173.67,8.99 173.68,9.01 173.9,9.25 174.1,9.51 174.94,10.35 174.94,11.05 175.57,11.68 176.59,11.68
+5VS on BOTTOM (solid shape): outline of 152 points within 88.32,144.4 98.88,151.76
+5VS on BOTTOM (solid shape): outline of 231 points within 40.38,79.25 95.43,123.02
+5VS on BOTTOM (solid shape): outline of 288 points within 175.73,38.73 200.97,49.02
+5VS on IN1 (solid shape): outline of 343 points within 174.01,1.46 202.24,41.02
+5VS on IN1 (solid shape): outline of 511 points within 88.45,119.91 99.94,148.46
+5VS on IN1 (solid shape): outline of 2087 points within 20.12,11.43 52.89,81.47
+5VS on VCC: 92.08,1.27 91.13,1.27 90.31,2.12 89.17,2.44 46.92,2.44 46.92,11.58 48.3,12.95 52.02,12.95 57.56,7.42 89.66,7.42 90.98,6.1 170.34,6.1 173.79,9.55 173.79,10.16 176.61,10.16 177.22,9.55 177.22,1.27
+17.4V_BATT+ on TOP (solid shape): outline of 224 points within 131.25,158.55 152.02,176.89
+17.4V_BATT+ on BOTTOM (solid shape): 136.9,162.78 136.9,158.56 136.65,158.31 135.44,158.31 135.18,158.56 132.64,158.56 132.14,159.07 132.14,160.21 133.66,160.21 133.66,160.85 132.14,160.85 131.37,161.61 131.37,163.3 131.45,163.37 136.3,163.37
+17.4V_BATT++ on TOP (solid shape): 154.57,176.52 154.57,175.56 155.06,175.07 156.08,175.07 156.39,174.75 156.39,172.91 155.7,172.21 152.96,172.21 152.84,172.34 152.84,173.3 152.15,173.99 152.15,173.99 152.15,174.46 152.15,174.48 151.62,174.48 151.62,174.48 151.62,174.73 152.15,174.73 152.15,174.75 152.15,175.26 152.15,175.28 151.62,175.28 151.62,175.52 151.63,175.53 152.18,175.53 152.18,176.66 152.36,176.83 154.25,176.83
+17.4V_BATT++ on BOTTOM (solid shape): outline of 102 points within 154.08,172.85 167.44,180.47
+17.4V_BATT++ on IN1 (solid shape): outline of 104 points within 154.1,172.85 167.44,180.47
+19V_ADPIN on TOP (solid shape): 90.48,162.43 90.48,160.4 90.23,160.15 89.46,160.15 88.7,160.91 88.07,160.91 87.81,161.16 87.81,162.43 87.94,162.56 90.35,162.56
+19V_ADPIN on TOP (solid shape): 84.12,163.59 84.12,163.08 84.13,163.07 84.13,157.99 83.91,157.77 82.16,157.77 81.9,158.04 81.9,158.13 81.91,158.62 81.43,158.67 81.43,159.78 81.97,159.78 81.97,160.34 81.43,160.34 81.43,160.59 81.98,160.59 81.98,161.14 81.43,161.14 81.43,161.52 81.42,161.52 81.42,162.81 81.72,163.11 82.71,163.11 82.96,163.36 82.96,163.63 83.06,163.73 83.98,163.73
+19V_ADPIN on IN1 (solid shape): outline of 142 points within 82.35,159.77 90.23,163.88
+19V_VIN on TOP (solid shape): 130.03,173.96 130.03,171.5 129.72,171.2 126.8,171.2 126.63,171.37 126.63,173.56 127.21,174.14 129.85,174.14
+19V_VIN on TOP (solid shape): 77.91,164.72 77.91,164.12 79.2,162.83 79.86,162.83 80.03,162.66 80.03,162.36 80.25,162.14 81.07,162.14 81.28,161.93 81.28,160.99 81.83,160.99 81.83,160.74 81.27,160.74 81.27,160.18 81.83,160.18 81.83,159.94 81.28,159.94 81.28,159.29 80.76,158.78 78.14,158.78 78.02,158.65 72.85,158.65 71.6,159.9 71.6,164.26 71.81,164.47 73.66,164.47 73.88,164.7 77.13,164.7 77.27,164.85 77.78,164.85
+19VB on TOP (solid shape): 46.73,64.39 46.73,50.67 47.87,49.53 52.51,49.53 53.52,48.51 53.52,47.5 56.51,44.51 56.51,38.35 57.46,37.39 57.47,37.38 58.14,37.38 58.14,37.37 58.16,37.37 58.16,36.84 58.86,36.84 58.86,37.37 59.36,37.37 59.36,36.84 60.06,36.84 60.06,37.37 63.59,37.37 64,36.96 64,35.69 64.32,35.37 65.08,35.37 72.57,27.88 72.57,25.15 72.32,24.89 70.62,24.89 70.62,25.41 70.12,25.41 70.12,24.89 69.82,24.89 69.82,25.41 69.32,25.41 69.32,24.89 67.37,24.89 67.11,25.15 67.11,27.3 61.21,33.21 60,33.21 58.79,34.42 55.87,34.42 55.37,34.92 55.37,36.39 54.41,37.34 53.08,37.34 52.51,37.91 52.51,43.94 51.17,45.28 46.22,45.28 44.67,46.82 40.32,46.82 40.06,46.57 40.06,42.82 39.4,42.16 37.65,42.16 37.52,42.29 37.52,42.8 36.61,43.71 36.61,47.08 35.3,48.39 31.55,48.39 31.43,48.51 31.43,49.72 31.62,49.91 40.13,49.91 41.14,50.93 41.14,62.61 43.55,65.02 46.09,65.02
+19VB on TOP (solid shape): outline of 1748 points within 64.06,75.76 152.46,155.45
+19VB on BOTTOM (solid shape): 39.93,44.65 39.93,42.24 39.91,42.21 37.27,42.21 37.24,42.24 37.24,44.65 37.34,44.75 39.83,44.75
+19VB on BOTTOM (solid shape): 108.58,135.25 108.58,134.37 109.02,133.92 111.44,133.92 111.44,131.95 111.37,131.89 110.86,131.89 110.86,132.46 108.83,132.46 108.83,131.89 105.97,131.89 105.72,132.14 105.72,135.25 105.97,135.51 108.32,135.51
+19VB on BOTTOM (solid shape): 75.14,165.68 75.14,161.7 73.92,160.48 72.05,160.48 71.86,160.67 71.86,164.3 72.14,164.58 72.21,164.61 72.28,164.58 72.79,164.58 72.79,165.08 72.76,165.16 72.79,165.23 73.32,165.76 75.05,165.76
+19VB on BOTTOM (solid shape): 120.95,155.68 120.95,154.95 120.95,154.93 121.46,154.93 121.46,154.48 120.95,154.48 120.95,154.45 120.95,153.75 120.95,153.73 121.46,153.73 121.46,153.28 120.95,153.28 120.95,153.25 120.95,152.45 121.06,152.34 125.47,152.34 125.91,152.78 125.91,154.94 126.46,155.49 128.1,155.49 128.17,155.56 132.75,155.56 132.8,155.51 132.8,150.91 132.57,150.69 125.66,150.69 125.22,150.24 120.98,150.24 120.96,150.27 120.71,150.46 120.4,150.37 120.33,150.34 120.26,150.37 119.95,150.46 119.69,150.27 119.67,150.24 118.1,150.24 116.58,151.76 115.25,151.76 115.12,151.89 115.12,153.03 116.64,153.03 116.64,153.1 116.64,153.73 116.64,153.8 115.12,153.8 115.12,154.56 116.01,155.45 116.9,155.45 117.47,156.02 120.61,156.02
+19VB on BOTTOM (solid shape): outline of 779 points within 42.87,62.93 67.37,79.12
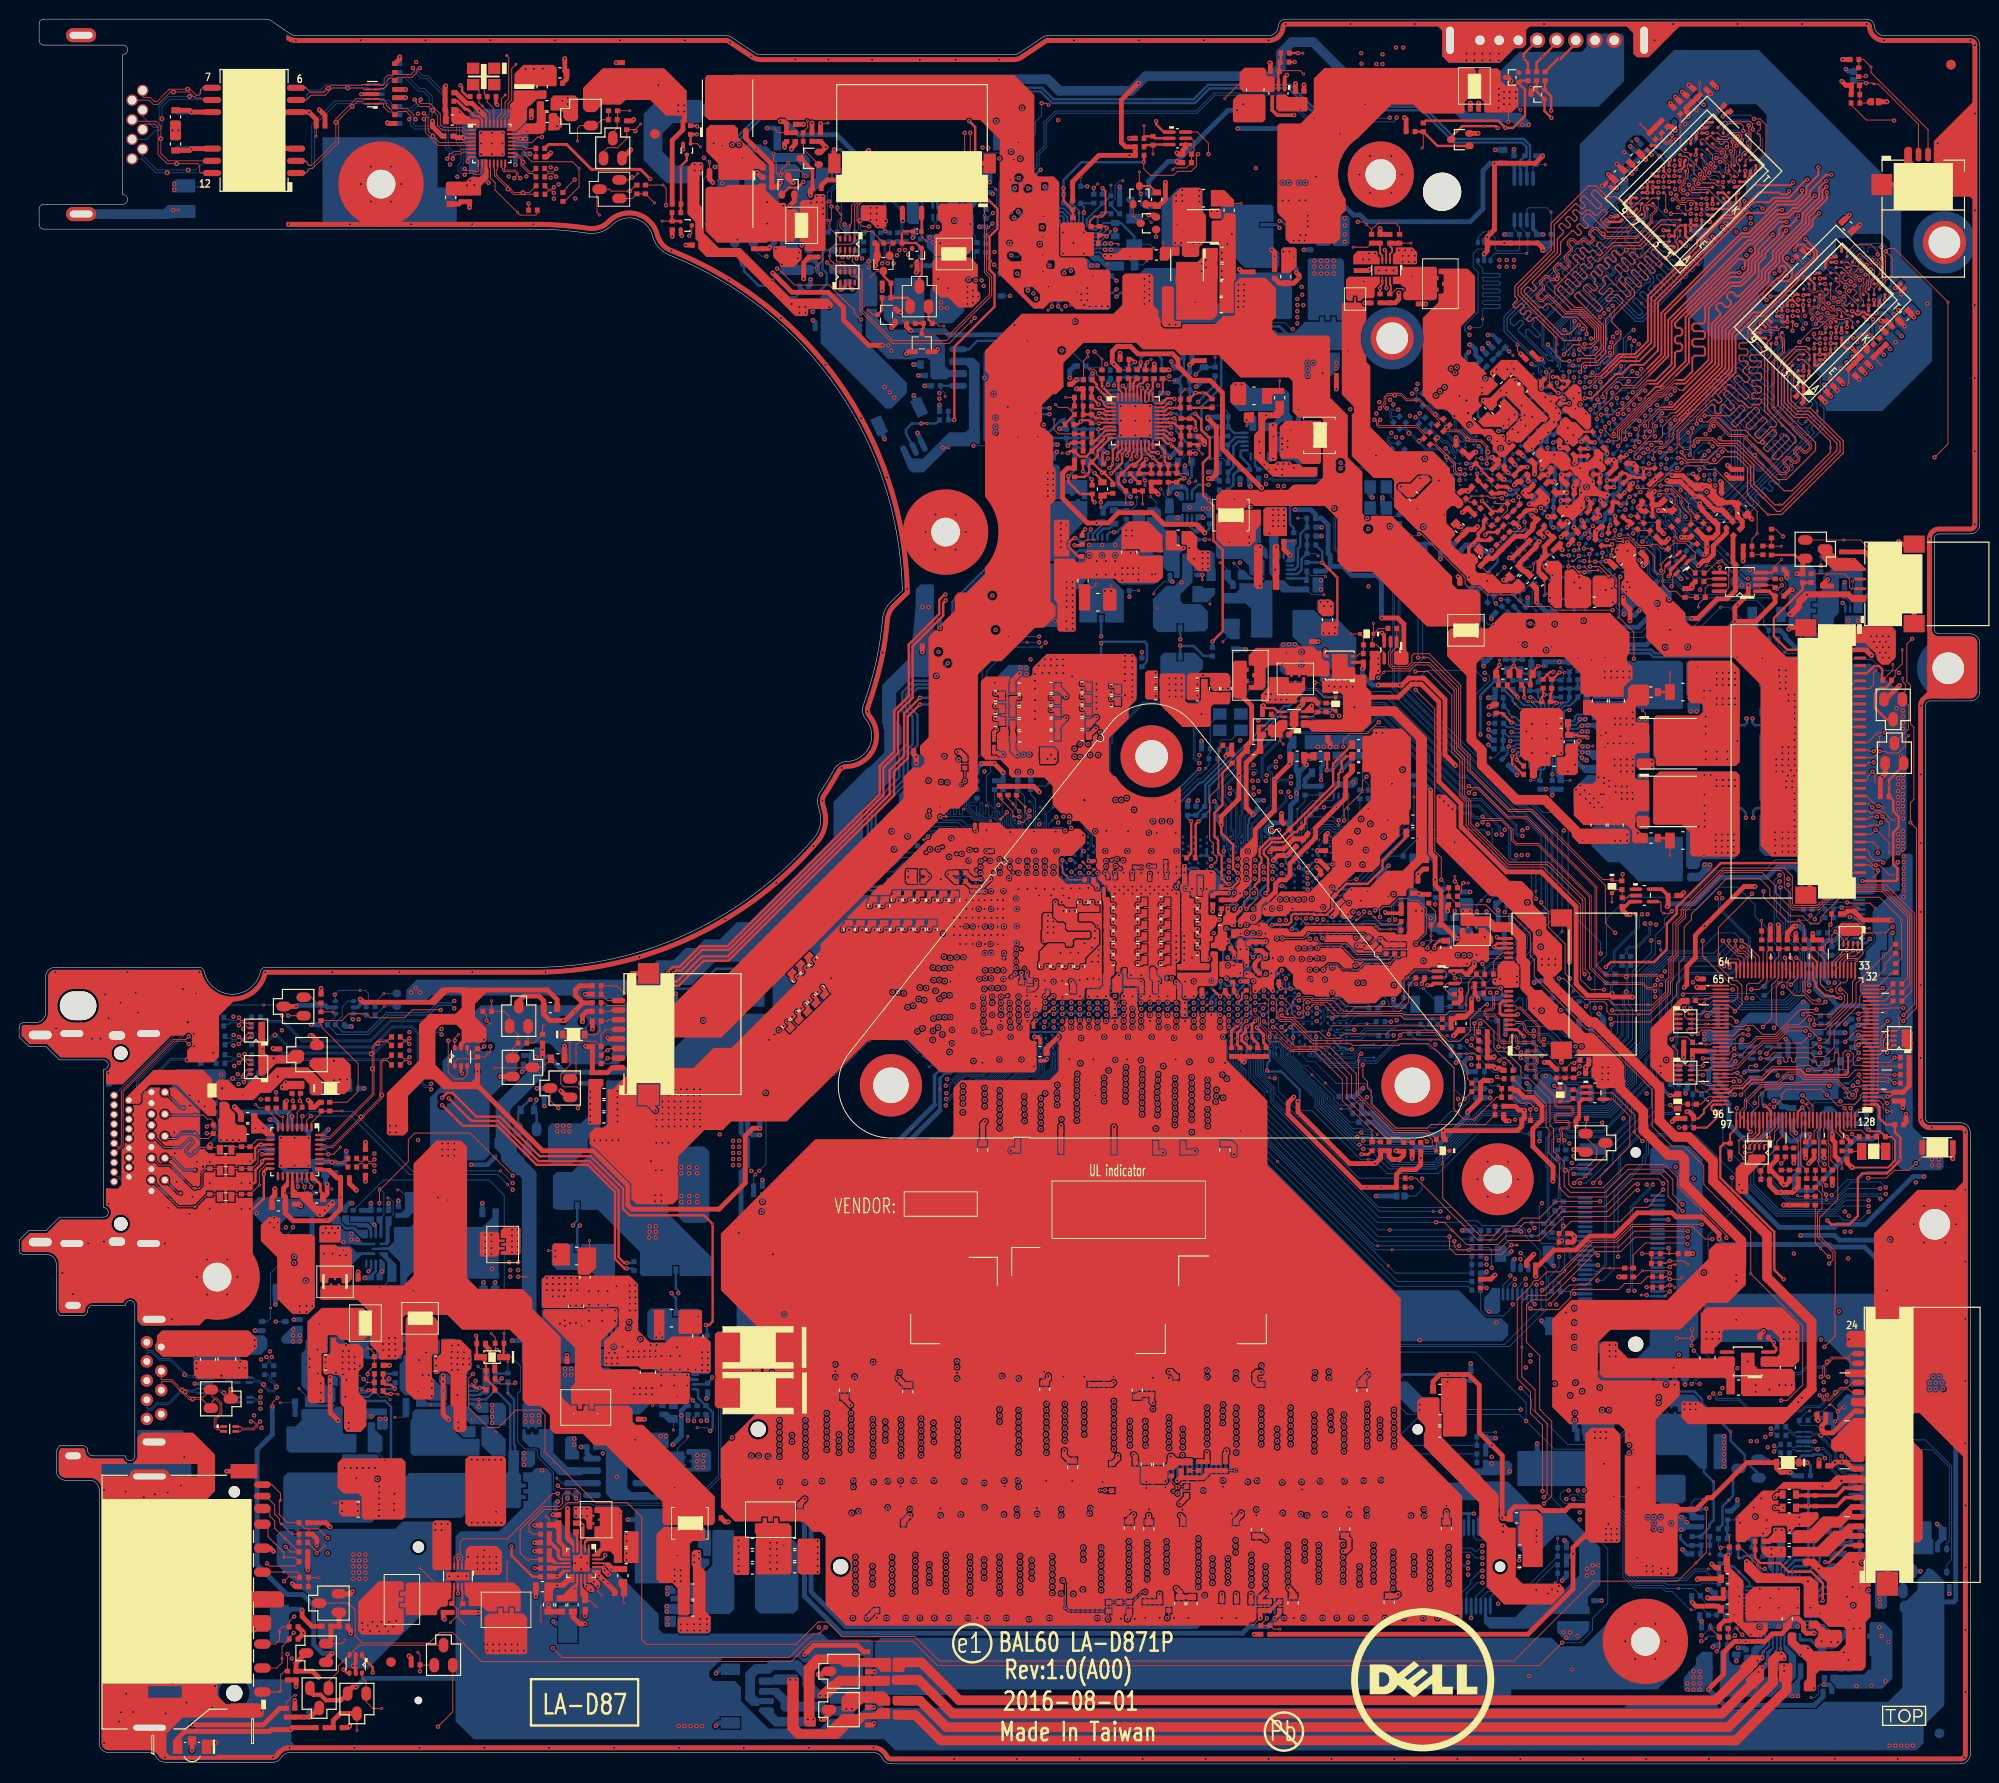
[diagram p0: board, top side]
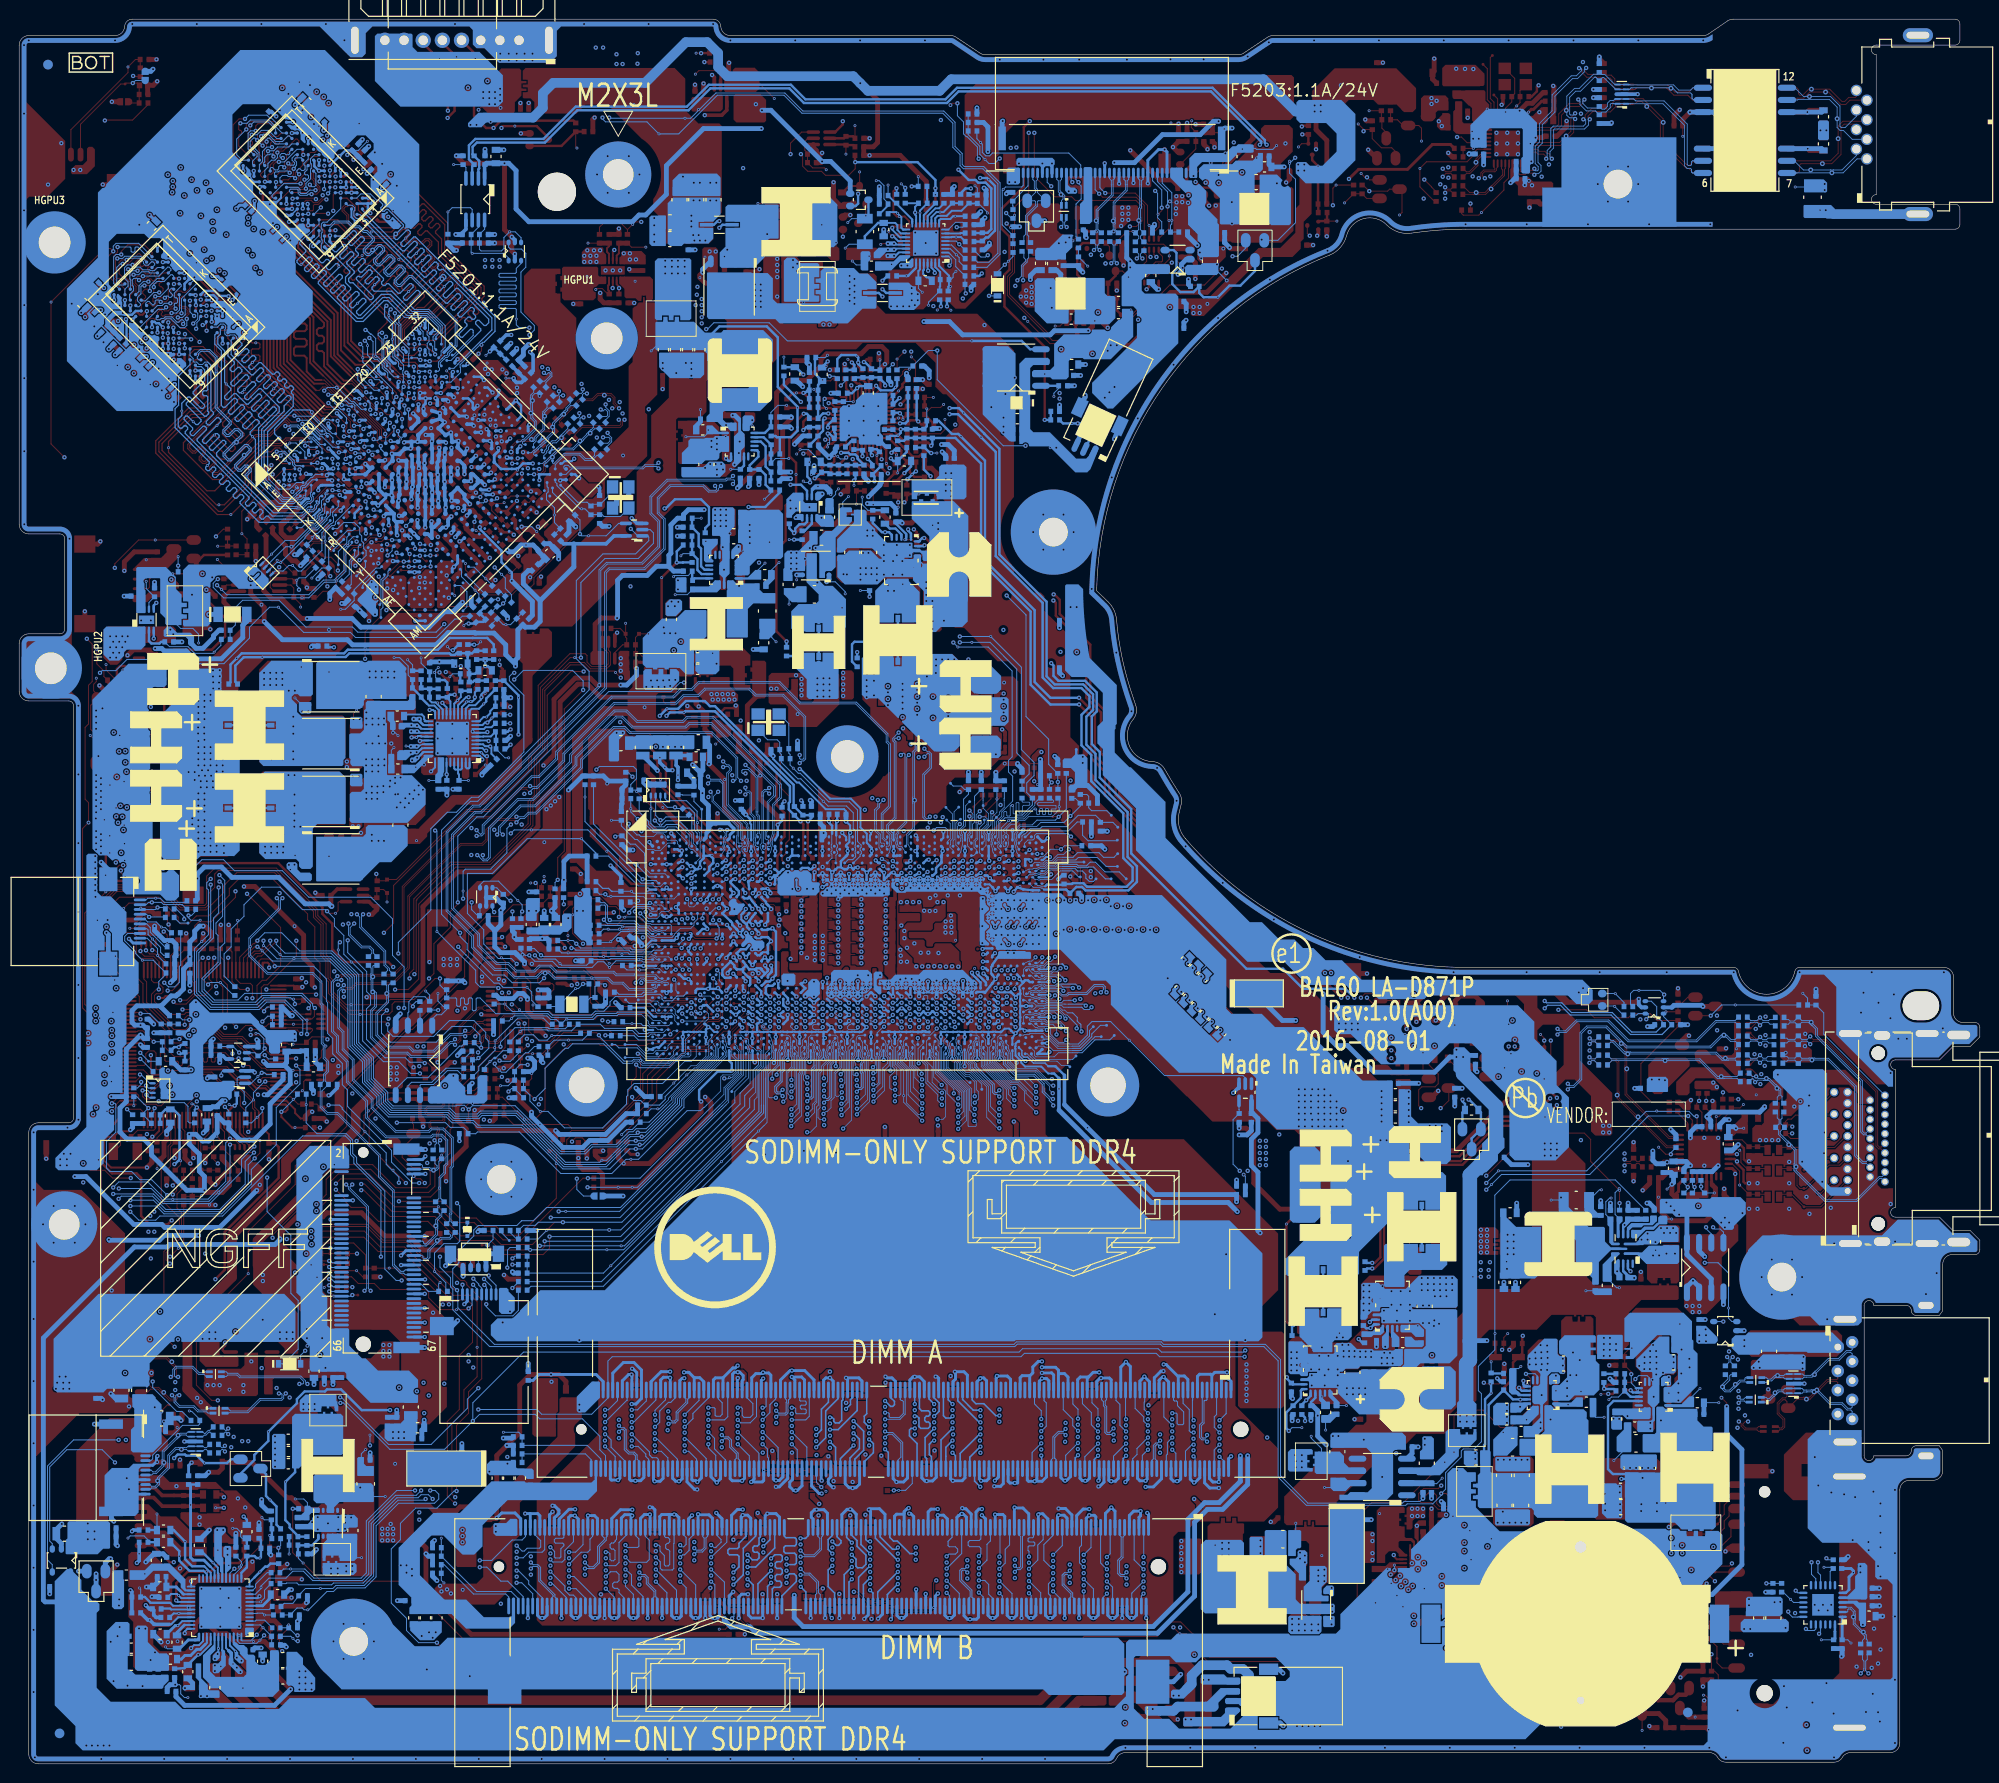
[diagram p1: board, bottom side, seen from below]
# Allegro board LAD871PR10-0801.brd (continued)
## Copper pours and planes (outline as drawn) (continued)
+19VB_1.2V on TOP (solid shape): 69.7,24.76 69.72,24.76 69.72,24.75 70.22,24.75 70.22,24.76 70.24,24.76 70.24,25.27 70.49,25.27 70.49,24.7 71.37,24.7 71.56,24.51 71.56,23.3 71.49,23.24 70.29,23.24 69.97,22.92 69.97,15.68 69.78,15.49 68.83,15.49 68.7,15.62 68.7,18.29 68.13,18.86 66.86,18.86 66.48,19.24 66.48,23.94 67.24,24.7 69.46,24.7 69.46,25.27 69.7,25.27
+19VB_1.2V on BOTTOM (solid shape): 69.91,19.11 70.54,18.48 70.54,16.95 67.97,16.95 67.96,16.97 67.96,17.52 67.96,17.53 68.54,17.53 68.67,17.66 68.67,18.45 68.13,18.99 68.13,20.45 68.32,20.64 69.91,20.64
+19VB_+1.5VGPU on TOP (solid shape): 135.82,139.26 135.31,139.26 135.31,137.86 135.82,137.86 135.82,135.76 135.63,135.57 133.91,135.57 133.34,136.14 131.76,136.14 131.5,136.4 131.5,139.45 132.14,140.08 135.82,140.08
+19VB_+1.5VGPU on BOTTOM (solid shape): 132.14,138.3 132.95,138.3 133.02,138.24 133.16,138.24 134.49,138.24 134.73,137.99 134.73,137.41 135.42,136.73 135.42,135.57 133.34,135.57 132.96,135.95 131.76,135.95 131.5,136.21 131.5,136.65 131.31,136.84 130.55,136.84 130.49,136.91 130.49,138.43 130.55,138.49 131.95,138.49
+19VB_+1VALW on TOP (solid shape): 128.23,130.81 128.45,130.73 128.68,130.81 129.53,130.81 129.53,129.22 129.03,128.71 129.03,127.6 128.41,126.98 125.65,126.98 124.88,127.75 124.88,130.22 125.09,130.43 125.72,130.43 125.72,129.86 127.12,129.86 127.12,130.43 127.5,130.43 127.88,130.81
+19VB_+1VALW on BOTTOM (solid shape): 128.23,130.81 128.45,130.73 128.68,130.81 129.47,130.81 129.53,130.75 129.53,127.33 129.27,127.33 129.06,127.13 129.06,126.33 129.91,125.48 129.91,124.02 129.85,123.95 128.52,123.95 128.33,124.14 128.33,124.9 127.56,125.68 125.08,125.68 124.85,125.91 124.85,130.38 125.28,130.81
+19VB_GPU on TOP (solid shape): 168.01,97.28 168.01,96.14 167.82,95.95 162.74,95.95 161.98,96.71 161.98,97.54 167.76,97.54
+19VB_GPU on TOP (solid shape): outline of 279 points within 148.96,111.32 168.33,120.05
+19VB_GPU on BOTTOM (solid shape): 168.39,97.67 168.39,96.99 168.68,96.7 173.56,96.7 173.57,96.69 173.57,92.11 173.5,92.04 168.95,92.04 166.94,94.04 165.73,94.04 164.01,95.76 164.01,97.54 164.39,97.92 168.14,97.92
+19VB_GPU on BOTTOM (solid shape): 168.16,115.06 168.46,114.9 168.76,115.06 173.28,115.06 173.56,114.78 173.56,110.05 173.53,110.01 169,110.01 168.59,110.43 168.59,110.87 168.4,111.06 164.18,111.06 164.14,111.1 164.14,112.51 164.14,113.72 164.24,113.93 164.14,114.15 164.14,114.3 164.9,115.06
+VCC_CORE on TOP (solid shape): outline of 3170 points within 100.32,79.45 121.2,115.76
+VCC_CORE on BOTTOM (solid shape): outline of 557 points within 113.72,90.45 120.96,93.17
+VCC_CORE on BOTTOM (solid shape): outline of 601 points within 101.33,105.59 116.64,115.76
+VCC_CORE on BOTTOM (solid shape): outline of 594 points within 115.56,79.83 120.32,82.8
+VCC_CORE on IN1 (solid shape): outline of 1271 points within 101.53,96.9 121.53,115.82
+VCC_CORE on IN2 (solid shape): 116.69,93.8 116.78,93.75 116.78,93.65 117.07,93.17 117.36,93.65 117.36,93.75 117.45,93.8 117.56,93.8 117.56,93.74 117.56,93.74 117.85,93.31 118.2,93.69 118.23,93.77 118.31,93.8 120.83,93.8 121.07,93.56 121.07,92.61 120.06,92.61 119.97,92.67 119.98,92.78 119.71,93.3 119.45,92.78 119.46,92.67 119.37,92.61 118.39,92.61 118.31,92.65 118.29,92.74 117.97,93.15 117.65,92.74 117.63,92.65 117.55,92.61 116.49,92.61 116.4,92.66 116.4,92.77 116.12,93.27 115.84,92.77 115.84,92.66 115.75,92.61 114.73,92.61 114.63,92.68 114.66,92.79 114.66,93.42 114.67,93.43 115.04,93.8
+VCC_CORE on IN2 (solid shape): outline of 1003 points within 113.83,79.83 121.07,91.71
+VCC_CORE on VCC: 116.75,74.29 114.99,76.05 114.99,81.51 113.47,83.04 113.47,91.8 113.09,92.18 113.09,94.09 111.82,95.36 111.82,97.9 108.64,101.07 108.64,102.09 107.86,102.87 102.52,102.87 101.28,104.12 101.28,111.4 103.03,113.16 103.41,113.16 106.46,116.2 115.9,116.2 116.77,115.34 116.77,110.64 120.58,106.83 120.58,99.46 120.9,99.15 120.9,93.98 120.96,74.29
+VCC_GT on TOP (solid shape): outline of 6875 points within 59.51,58.36 112.96,98.17
+VCC_GT on BOTTOM (solid shape): outline of 937 points within 104.58,79.91 114.86,82.81
+VCC_GT on BOTTOM (solid shape): outline of 2826 points within 55.68,50.89 113.57,92.66
+VCC_GT on IN2 (solid shape): outline of 3082 points within 66.22,66.23 113.58,91.64
+VCC_GT on VCC: 60.64,70.48 61.76,70.48 65.44,74.23 67.66,74.23 73.25,79.76 74.84,79.76 86.33,91.31 103.54,91.31 104.05,91.82 112.73,91.82 112.96,91.59 112.96,82.83 114.48,81.3 114.48,78.74 106.89,78.74 106.12,77.98 99.6,77.98 98.23,79.35 98.23,81.77 97.19,82.8 94.71,82.8 94.46,83.06 85.55,83.06 77.72,75.23 77.72,70.15 72.94,65.37 72.94,55.35 72.1,54.5 63.38,54.5 62.57,55.31 62.57,60.4 61.42,61.55 57.12,61.55 56.76,61.92 56.76,64.74 60.64,68.62
+VCC_SA on TOP (solid shape): 121.66,113.54 121.66,110.87 121.91,110.62 122.99,110.62 123.31,110.93 123.31,113.16 124.01,113.16 124.01,112.08 124.33,111.76 126.36,111.76 126.36,110.68 126.17,110.49 124.58,110.49 124.33,110.24 124.33,108.33 124.14,108.14 121.34,108.14 118.99,110.49 118.99,113.6 119.12,113.73 121.47,113.73
+VCC_SA on TOP (solid shape): outline of 140 points within 121.52,83.64 125.45,93.22
+VCC_SA on BOTTOM (solid shape): 125.02,82.22 125.02,81.68 125.02,81.64 125.02,81.59 125.02,81.29 124.9,81.17 123.75,81.17 123.56,81.36 123.56,82.25 123.75,82.44 124.81,82.44
+VCC_SA on BOTTOM (solid shape): 120.71,114.93 121.53,114.93 121.53,115.89 122.68,115.89 123.5,115.06 123.5,114.24 122.39,113.13 122.39,111.28 122.17,111.06 119.18,111.06 119.06,111.19 119.06,115.51 119.44,115.89 120.71,115.89
+VCC_SA on BOTTOM (solid shape): outline of 122 points within 121.04,90.56 125.45,93.22
+VCC_SA on IN2 (solid shape): 124.18,93.18 124.37,93.18 124.5,93.05 124.5,92.48 124.44,92.39 124.33,92.41 124.12,92.61 121.83,92.61 121.83,92.79 121.84,92.81 121.89,92.93 121.89,93.07 121.88,93.1 122.09,93.31 124.06,93.31
+VCC_SA on IN2 (solid shape): outline of 423 points within 121.83,81.1 124.64,91.71
+VCC_SA on VCC: 121.43,87.76 121.41,93.98 121.41,99.36 121.09,99.67 121.09,107.04 117.28,110.85 117.28,114.05 125.55,114.05 126.82,112.78 128.9,112.78 128.9,106.53 127.88,105.52 127.88,96.89 125.53,94.73 125.53,88.14 125.15,87.76
+VDD_CT on IN2 (solid shape): outline of 221 points within 151.82,128.52 156.65,134.24
+VDDR3 on TOP (solid shape): 159.7,132.08 159.7,131.57 159.31,131.19 159.05,131.19 158.76,131.34 158.46,131.19 157.41,131.19 157.28,131.32 157.28,131.44 157.41,131.57 157.92,131.57 158.43,132.08 158.43,132.33 158.17,132.59 158.17,132.71 158.55,133.1 158.68,133.1
GND on TOP (solid shape): 56.64,171.45 56.64,170.75 56.25,170.37 55.24,170.37 55.24,172.02 55.37,172.15 55.94,172.15
GND on TOP (solid shape): 26.28,15.24 26.28,14.1 25.96,13.78 20.25,13.78 19.93,14.1 19.93,14.67 20.76,15.49 26.03,15.49
GND on TOP (solid shape): 76.14,23.68 76.14,19.82 76,19.69 74.73,19.69 74.48,19.94 74.48,23.62 74.61,23.75 76.07,23.75
GND on TOP (solid shape): 83.56,23.37 83.56,19.88 83.43,19.75 81.46,19.75 81.21,20 81.21,23.37 81.34,23.5 83.43,23.5
GND on TOP (solid shape): 131.46,127.1 131.46,122.54 131.35,122.43 130.87,122.43 130.77,122.53 130.77,127.03 130.97,127.24 131.33,127.24
GND on TOP (solid shape): 118.8,113.92 118.8,111.12 118.67,111 117.66,111 117.47,111.19 117.47,113.79 117.72,114.05 118.67,114.05
GND on TOP (solid shape): 50.79,31.81 50.79,25.08 50.48,24.76 46.87,24.76 46.54,25.1 46.54,30.8 46.55,30.8 46.55,31.76 46.89,32.11 50.5,32.11
GND on TOP (solid shape): 60.95,71.37 60.95,70.74 60.7,70.48 60.7,66.74 60.64,66.67 59.49,66.67 59.37,66.8 59.37,71.31 59.49,71.44 60.89,71.44
GND on TOP (solid shape): 64.64,24.13 64.64,21.02 64.57,20.95 63.24,20.95 63.11,21.08 63.11,24.07 63.3,24.26 64.51,24.26
GND on TOP (solid shape): 132.26,130.94 132.26,128.14 132.18,128.06 129.95,128.06 129.79,128.22 129.79,130.81 130.04,131.06 132.14,131.06
GND on TOP (solid shape): 137.16,121.09 137.16,119.89 136.95,119.68 135.96,119.68 135.52,120.13 135.52,121.24 135.7,121.43 136.81,121.43
GND on TOP (solid shape): 147.25,134.05 147.25,133.87 145.46,132.08 144.77,132.08 143.82,133.03 143.82,133.35 144.01,133.54 145.15,133.54 145.98,134.37 146.93,134.37
GND on TOP (solid shape): 23.89,41.94 23.89,40.29 23.76,40.16 18.62,40.16 18.24,40.54 18.24,42 18.37,42.13 23.7,42.13
GND on TOP (solid shape): 123.5,92.4 123.5,91.19 123.37,91.06 123.37,90.55 122.99,90.55 122.94,90.6 122.94,92.2 122.93,92.21 122.93,92.58 123.31,92.58
GND on TOP (solid shape): 151.01,40.04 151.01,34.38 150.77,34.14 148.6,34.14 148.56,34.18 148.56,36.53 148.33,36.75 148.33,40.17 148.39,40.23 150.82,40.23
GND on TOP (solid shape): 59.11,19.75 59.11,18.92 59.3,18.73 59.56,18.73 60,18.29 60,17.97 59.94,17.91 59.49,17.91 58.92,18.48 58.92,19.75 58.98,19.81 59.05,19.81
GND on TOP (solid shape): 108.24,105.72 108.24,105.71 108.32,105.63 108.32,104.56 108.03,104.26 106.58,104.26 106.53,104.32 106.53,104.85 106.48,104.89 106.48,105.98 106.52,106.01 107.95,106.01
GND on TOP (solid shape): 120.46,153.98 120.46,150.62 120.59,150.49 121.2,150.49 121.21,150.48 121.21,149.9 121.15,149.84 119.49,149.84 119.22,150.11 119.22,153.99 119.35,154.11 120.33,154.11
GND on TOP (solid shape): 160.97,125.09 160.97,120.65 160.84,120.52 160.2,120.52 159.51,121.22 159.51,123.06 159.76,123.32 159.76,123.89 158.93,124.71 158.93,124.97 159.44,125.48 160.58,125.48
GND on TOP (solid shape): 181.03,41.59 181.41,41.21 184.91,41.21 185.22,40.89 185.22,39.88 185.29,39.81 185.29,38.98 184.66,38.35 179.83,38.35 179.63,38.54 179.63,42.86 181.03,42.86
GND on TOP (solid shape): 185.79,18.43 185.79,17.22 185.79,15.52 184.9,15.52 184.3,14.92 183.83,14.92 183.81,14.91 180.24,14.91 180.08,15.07 180.08,17.59 180.97,18.48 185.75,18.48
GND on TOP (solid shape): 33.56,56.13 33.56,54.65 33.51,54.55 33.48,54.44 33.48,54.42 33.42,54.36 31.35,54.36 31.3,54.4 31.3,56 31.47,56.17 33.52,56.17
GND on TOP (solid shape): 111.18,160.53 111.18,160.02 111.44,159.77 112.05,159.77 112.12,159.69 112.12,157.41 111.96,157.25 108.74,157.25 108.61,157.37 108.61,160.56 108.84,160.78 110.93,160.78
GND on TOP (solid shape): 118.62,82.88 118.62,82.32 119.11,81.84 119.11,81.47 119.06,81.42 118.86,81.42 118.8,81.36 118.8,80.42 118.75,80.37 118.37,80.37 118.29,80.44 118.29,81.64 117.98,81.94 117.98,83 118.12,83.14 118.36,83.14
GND on TOP (solid shape): 122.9,127.99 122.9,126.77 123.13,126.54 124.11,126.54 124.26,126.39 124.26,124.51 124.14,124.38 123.04,124.38 121.83,125.6 121.83,127 121.65,127.18 121.33,127.18 121.26,127.25 121.26,128.59 122.31,128.59
GND on TOP (solid shape): 142.03,115.92 142.03,113.77 141.91,113.65 141.63,113.65 141.43,113.45 141.43,113.06 141.41,113.04 140.95,113.04 140.83,113.15 140.83,114 140.95,114.11 140.95,116.02 141.02,116.09 141.86,116.09
GND on TOP (solid shape): 188.52,13.97 189.99,13.97 190.18,13.78 190.18,12.7 189.6,12.13 187.51,12.13 187.32,12.32 187.32,12.95 187.7,13.33 187.7,13.78 187.38,14.1 186.75,14.1 186.68,14.16 186.68,14.8 186.81,14.92 187.57,14.92
GND on TOP (solid shape): 158.96,25.75 158.96,20.64 158.84,20.52 156.92,20.52 156.84,20.6 156.84,20.6 156.84,21.13 156.85,21.22 156.84,21.31 156.84,22.54 156.39,22.99 156.39,24.75 156.54,24.9 156.54,26.28 156.65,26.39 158.32,26.39
GND on TOP (solid shape): 121.26,81.32 121.26,79.86 121.49,79.63 121.72,79.63 121.87,79.48 121.87,78 121.74,77.88 121.31,77.88 121.16,78.03 121.16,79.5 120.96,79.71 120.83,79.71 120.83,81.23 120.73,81.33 120.6,81.33 120.5,81.43 120.5,81.69 120.6,81.79 120.79,81.79
GND on TOP (solid shape): 21.96,68.77 21.96,68.39 22.54,67.82 22.54,66.87 22.79,66.61 23.42,66.61 23.74,66.29 23.74,64.92 23.66,64.84 20.88,64.84 20.77,64.95 20.77,67.18 20.76,67.18 20.76,67.25 20.88,67.37 20.88,68.96 20.95,69.02 21.71,69.02
GND on TOP (solid shape): 71.11,22.22 71.11,20.59 71.62,20.08 71.62,15.88 72.13,15.37 72.13,13.91 71.88,13.65 68.89,13.65 68.7,13.84 68.7,15.11 68.89,15.3 70.03,15.3 70.29,15.56 70.29,20.6 70.16,20.73 70.16,22.05 70.42,22.31 71.03,22.31
GND on TOP (solid shape): 126.36,113.47 126.36,112.01 126.23,111.89 124.64,111.89 124.26,112.27 124.26,113.22 124.18,113.31 123.21,113.31 123.16,113.26 123.16,111.1 122.99,110.93 121.91,110.93 121.85,111 121.85,113.54 122.1,113.79 126.04,113.79
GND on TOP (solid shape): 58.98,24.96 58.98,23.56 58.73,23.3 58.73,21.97 58.92,21.78 59.49,21.78 59.49,20.07 57.78,20.07 57.78,21.78 58.35,21.78 58.54,21.97 58.54,24.7 58.41,24.83 57.78,24.83 57.78,25.4 58.54,25.4
GND on TOP (solid shape): 47.17,43.12 47.17,41.25 46.67,40.74 46.67,34.85 46.41,34.59 45.62,34.59 45.29,34.92 45.29,37.13 44.99,37.44 44.99,40.56 44.6,40.96 43.94,40.96 43.62,40.64 43.43,40.64 43.24,40.83 43.24,42.42 43.36,42.54 43.74,42.54 44.03,42.83 44.03,44.23 44.06,44.26 46.03,44.26
GND on TOP (solid shape): 126.93,161.54 126.93,154.81 126.72,154.6 126.72,154.52 126.71,154.51 126.71,151.37 126.65,151.31 125.27,151.31 125.22,151.36 125.22,158.24 125.02,158.43 124.52,158.43 124.39,158.56 124.39,160.85 124.52,160.97 125.41,160.97 125.66,161.23 125.66,161.61 125.79,161.73 126.74,161.73
GND on TOP (solid shape): 161.98,139.95 162.36,139.95 163.25,139.06 163.25,138.81 162.62,138.18 162.62,137.79 162.24,137.41 161.98,137.41 161.73,137.67 161.58,137.67 161.52,137.72 161.47,137.67 161.2,137.95 161.25,138 160.68,138.58 160.62,138.52 160.38,138.77 160.38,139.33 160.71,139.66 160.71,139.95 161.22,140.46 161.47,140.46
GND on TOP (solid shape): 115.55,82.94 115.55,81.94 115.67,81.81 117.2,81.81 117.32,81.69 117.32,80.35 117.13,80.35 117.06,80.36 116.99,80.35 116.88,80.35 116.82,80.42 116.82,80.99 116.69,81.12 115.36,81.12 115.22,81.26 115.22,82.4 115.1,82.51 115.1,82.95 115.14,82.98 115.5,82.98
GND on TOP (solid shape): 161.08,109.73 161.08,105.29 160.94,105.16 160.01,105.16 159.76,104.9 159.76,104.14 159.7,104.08 158.75,104.08 158.36,103.7 158.36,102.93 158.17,102.74 157.79,102.74 157.6,102.93 157.6,104.39 157.35,104.65 157.08,104.65 156.57,105.16 156.57,105.35 156.57,105.36 156.59,105.45 156.57,105.54 156.57,105.55 156.57,109.73 156.95,110.11 160.69,110.11
GND on TOP (solid shape): 131.95,140.84 131.44,140.33 130.23,140.33 129.98,140.08 129.98,136.02 130.42,135.57 130.99,135.57 131.25,135.83 132.58,135.83 132.84,135.57 133.6,135.57 133.91,135.25 135.38,135.25 135.44,135.19 135.44,134.43 135.25,134.24 130.8,134.24 128.83,136.21 128.83,138.62 129.28,139.06 129.28,140.91 129.34,140.97 130.8,140.97 131.06,141.22 131.06,142.11 131.12,142.18 131.95,142.18
GND on TOP (solid shape): 193.52,115.71 193.52,115.48 193.37,115.32 193.14,115.32 192.52,115.94 191.37,115.94 191.03,115.6 191.03,114.07 190.93,113.98 190,113.98 189.89,114.08 189.89,115.73 190.18,116.01 190.59,116.04 190.72,116.43 192.81,116.43
GND on TOP (solid shape): 120.77,31.88 121.21,31.88 121.22,31.87 121.36,31.84 121.51,31.87 121.52,31.88 122.36,31.88 122.42,31.81 122.42,31.24 122.29,31.11 120.96,31.11 120.82,30.98 120.81,30.98 120.81,30.96 120.48,30.64 119.9,30.64 119.79,30.53 119.79,29.64 119.82,29.64 119.82,29.34 119.69,29.21 117.15,29.21 117.02,29.34 117.02,30.99 117.09,31.05 119.44,31.05 119.82,31.43 119.82,32.13 120.01,32.32 120.33,32.32
GND on TOP (solid shape): 33.01,44.13 33.27,43.88 33.27,43.81 35.39,43.81 35.92,43.28 35.92,41.43 35.41,40.92 35.41,38.68 36.23,37.87 36.23,35.23 35.62,34.62 34.22,34.62 33.89,34.95 33.89,37.16 33.58,37.47 33.58,40.39 33.38,40.59 32.71,40.59 32.43,40.7 32.16,40.58 31.93,40.58 31.68,40.83 31.68,42.54 31.87,42.74 32.31,42.74 32.51,42.93 32.51,44.45 33.01,44.45
GND on TOP (solid shape): 113.77,83.89 113.92,83.74 114.22,83.74 114.28,83.68 114.28,82.39 113.87,81.98 113.87,81.22 113.77,81.12 113.77,80.1 114.28,79.59 114.4,79.59 114.53,79.46 114.53,79.28 114.43,79.04 114.53,78.81 114.53,78 114.4,77.88 113.9,77.88 113.77,78 113.77,79.53 113.51,79.78 111.42,79.78 111.36,79.85 111.36,80.67 111.48,80.8 112.76,80.8 113.09,81.13 113.09,82.47 113.13,82.51 113.13,90.4 113.77,90.4
GND on TOP (solid shape): 157.03,143.51 157.03,142.88 159.44,140.46 159.44,140.33 159.06,139.95 158.81,139.95 156.65,137.79 156.14,137.79 156.01,137.92 155.83,137.92 155.77,137.98 155.7,137.92 155.63,137.92 155.5,137.79 155.27,137.79 155.12,137.94 155.12,138.25 155.18,138.43 155.12,138.61 155.12,138.81 156.65,140.33 156.65,141.1 155.12,142.62 154.68,142.62 154.17,142.11 154.17,141.67 153.66,141.16 153.41,141.16 152.52,142.05 152.52,142.37 152.65,142.49 153.47,142.49 155.5,144.53 156.01,144.53
GND on TOP (solid shape): 126.34,89.36 126.34,88.88 126.44,88.77 126.87,88.77 127.18,89.08 127.18,89.28 127.31,89.41 127.54,89.41 127.64,89.31 127.64,89 126.95,88.32 126.95,87.4 126.82,87.27 126.49,87.27 126.24,87.53 125.76,87.53 125.6,87.38 125.6,86.92 125.73,86.79 126.01,86.79 126.01,86.23 126.16,86.08 126.19,86.08 126.34,85.93 126.34,85.7 126.07,85.43 126.06,85.43 126.06,85.42 125.91,85.27 125.91,84.94 125.76,84.79 125.25,84.79 124.97,85.07 124.39,85.07 124.33,85.12 124.33,85.65 124.54,85.65 124.72,85.83 124.72,86.26 124.77,86.31 124.82,86.31 125.05,86.54 125.05,87.51 125.21,87.67 125.41,87.67 125.61,87.88 125.61,88.37 125.83,88.6 125.83,89.38 125.9,89.45 126.25,89.45
GND on TOP (solid shape): 170.06,112.44 170.06,110.56 169.86,110.36 168.78,110.36 168.65,110.24 168.65,109.41 168.65,108.75 168.79,108.61 169.87,108.61 170.07,108.4 170.07,105.55 169.96,105.44 168.85,105.44 168.56,105.16 168.56,104.33 168.58,104.32 168.58,102.88 168.73,102.73 168.73,102.73 168.84,102.63 169.91,102.63 170.06,102.48 170.06,99.46 169.95,99.35 168.93,99.35 168.6,99.01 168.6,97.73 169.25,97.08 169.84,97.08 169.91,97.01 169.91,96.11 169.82,96.02 168.47,96.02 168.27,96.23 168.27,97.36 167.71,97.92 163.19,97.92 162.17,98.93 162.17,101.66 162.74,102.23 164.18,102.23 164.52,102.57 164.52,108.84 163.97,109.39 163.29,109.39 163.15,109.54 163.15,110.91 163.19,110.96 163.95,110.96 164.3,110.62 167.26,110.62 167.83,111.19 167.83,112.2 168.2,112.57 169.93,112.57
GND on TOP (solid shape): 40.32,31.5 40.32,25.78 40.01,25.48 36,25.48 35.74,25.73 35.74,27.81 35.36,28.19 33.84,28.19 33.2,28.83 33.2,29.74 37.04,29.74 37.04,29.69 37.05,29.64 37.06,29.59 37.09,29.54 37.12,29.5 37.15,29.46 37.19,29.42 37.24,29.4 37.29,29.38 37.34,29.37 37.39,29.36 37.45,29.37 37.5,29.38 37.55,29.4 37.6,29.42 37.64,29.46 37.67,29.5 37.7,29.54 37.73,29.59 37.74,29.64 37.75,29.69 37.75,29.74 37.74,29.8 37.73,29.85 37.7,29.9 37.67,29.94 37.64,29.98 37.6,30.01 37.55,30.04 37.5,30.06 37.45,30.07 37.39,30.07 37.34,30.07 37.29,30.06 37.24,30.04 37.19,30.01 37.15,29.98 37.12,29.94 37.09,29.9 37.06,29.85 37.05,29.8 37.04,29.74 33.2,29.74 33.2,31.37 33.71,31.88 39.93,31.88
GND on TOP (solid shape): 165.59,123.88 165.59,123.86 165.77,123.63 166.05,123.73 166.12,123.77 166.2,123.74 166.43,123.52 166.43,123.02 166.37,122.75 166.59,122.58 166.65,122.55 166.68,122.48 166.68,121.16 166.21,120.69 166.14,120.67 166.07,120.65 164.52,120.65 164.14,121.03 164.14,123.7 164.39,123.95 165.51,123.95
GND on TOP (solid shape): 126.93,83.51 127.63,83.51 127.69,83.45 127.69,82.18 127.56,82.05 126.24,82.05 126.23,82.08 126.2,82.12 126.16,82.15 126.12,82.18 126.07,82.2 126.02,82.22 125.97,82.23 125.92,82.23 125.87,82.22 125.83,82.2 125.78,82.18 125.74,82.15 125.7,82.12 125.67,82.08 125.66,82.05 125.33,82.05 125.21,82.17 125.21,83.29 125.77,83.29 125.77,83.23 125.78,83.18 125.8,83.13 125.82,83.09 125.85,83.05 125.89,83.01 125.93,82.98 125.98,82.95 126.03,82.94 126.08,82.93 126.13,82.93 126.18,82.94 126.23,82.95 126.28,82.98 126.32,83.01 126.35,83.05 126.39,83.09 126.41,83.13 126.42,83.18 126.43,83.23 126.43,83.29 126.42,83.34 126.41,83.39 126.39,83.43 126.35,83.48 126.32,83.51 126.28,83.54 126.23,83.57 126.18,83.58 126.13,83.59 126.08,83.59 126.03,83.58 125.98,83.57 125.93,83.54 125.89,83.51 125.85,83.48 125.82,83.43 125.8,83.39 125.78,83.34 125.77,83.29 125.21,83.29 125.21,83.64 125.28,83.71 126.74,83.71
GND on TOP (solid shape): 121.82,93.78 121.82,92.66 121.87,92.61 121.87,91.67 121.79,91.59 121.52,91.59 121.39,91.47 121.39,91.11 121.59,90.91 122.07,90.91 122.1,90.88 122.1,90.38 122.2,90.27 122.5,90.27 122.53,90.25 122.53,89.8 122.54,89.8 122.61,89.72 123,89.72 123,89.72 123.05,89.72 123.17,89.59 123.17,89.38 123.06,89.27 122.53,89.27 122.53,89.23 122.53,88.65 122.63,88.55 123.04,88.55 123.17,88.42 123.17,88.23 123.03,88.09 122.62,88.09 122.53,88 122.53,87.38 122.63,87.28 123.04,87.28 123.17,87.15 123.17,86.96 123.03,86.82 122.62,86.82 122.53,86.73 122.53,86.14 122.63,86.04 123.04,86.04 123.17,85.9 123.17,85.71 123.03,85.57 122.62,85.57 122.53,85.48 122.53,84.86 122.6,84.79 123.07,84.79 123.17,84.69 123.17,83.61 123.27,83.51 124.16,83.51 124.21,83.46 124.21,82.88 124.08,82.75 121.16,82.75 121.16,82.76 120.89,82.76 120.81,82.85 120.81,83.36 120.87,83.42 121.19,83.42 121.26,83.5 121.26,90.96 121.11,91.11 121.11,91.59 121.31,91.8 121.31,93.75 121.41,93.85 121.74,93.85
GND on TOP (solid shape): outline of 94 points within 72.57,37.08 77.4,45.08
GND on TOP (solid shape): 97.29,157.66 97.29,157.18 97.31,157.15 97.41,157.15 97.72,157.15 97.8,157.15 97.82,157.15 97.82,157.17 97.85,157.2 97.85,157.66 97.87,157.68 98.08,157.68 98.1,157.66 98.1,157.15 98.13,157.12 99.22,157.12 100.01,156.34 100.01,155.19 99.97,155.11 99.88,155.09 99.8,155.09 99.72,155.08 99.62,155.03 99.53,154.96 99.45,154.92 99.36,154.97 98.7,154.83 99.33,154.58 99.42,154.62 99.5,154.57 99.58,154.47 99.68,154.41 99.77,154.39 99.86,154.39 99.94,154.36 99.97,154.28 99.97,153.67 100.26,153.38 100.26,152.72 99.43,151.89 97.97,151.89 96.93,152.93 96.11,152.93 95.28,153.76 95.28,156.76 95.65,157.12 96.98,157.12 97.01,157.15 97.02,157.16 97.03,157.18 97.03,157.66 97.06,157.68 97.26,157.68
GND on TOP (solid shape): outline of 136 points within 86.44,163.75 95.23,165.58
GND on TOP (solid shape): outline of 121 points within 106.31,82.89 112.7,90.12
GND on TOP (solid shape): outline of 171 points within 107.96,118.08 119.32,126.61
GND on TOP (solid shape): outline of 171 points within 158.21,129.69 165.92,137.35
GND on TOP (solid shape): outline of 205 points within 54.54,40.77 72.14,50.93
GND on TOP (solid shape): outline of 1142 points within 0.25,70.87 92.91,162.01
GND on TOP (solid shape): outline of 1237 points within 0.25,45.72 24.38,70.55
GND on TOP (solid shape): outline of 1316 points within 4.12,0.25 204.3,181.72
GND on BOTTOM (solid shape): 104.03,147.6 104.03,140.74 101.24,137.95 100.6,137.95 100.6,147.1 101.36,147.86 103.77,147.86
GND on BOTTOM (solid shape): 136.07,123.63 136.07,122.3 135.95,122.17 134.93,122.17 134.93,123.7 134.99,123.76 135.95,123.76
GND on BOTTOM (solid shape): 163.76,13.91 162.74,12.89 161.28,12.89 160.46,13.72 160.46,14.8 160.52,14.86 163.76,14.86
GND on BOTTOM (solid shape): 24.95,14.73 24.95,13.97 24.69,13.72 20.12,13.72 19.93,13.91 19.93,14.8 20.25,15.11 24.57,15.11
GND on BOTTOM (solid shape): 37.5,32.08 37.5,30.86 37.32,30.68 33.86,30.68 33.69,30.86 33.69,32.18 33.79,32.28 37.29,32.28
GND on BOTTOM (solid shape): 38.46,36.09 38.46,35 38.31,34.85 37.41,34.85 37.33,34.92 37.33,36.13 37.39,36.19 38.36,36.19
GND on BOTTOM (solid shape): 50.58,26.44 50.58,24.99 50.45,24.86 47.1,24.86 46.92,25.04 46.92,26.44 47.02,26.54 50.48,26.54
GND on BOTTOM (solid shape): 50.78,37.29 50.78,35.46 50.63,35.31 49.2,35.31 49.13,35.37 49.13,37.58 49.21,37.66 50.41,37.66
GND on BOTTOM (solid shape): 105.57,106.81 105.57,105.09 105.38,104.9 102.4,104.9 102.14,105.15 102.14,106.87 102.52,107.25 105.13,107.25
GND on BOTTOM (solid shape): 136.39,165.16 136.39,163.58 136.33,163.51 131.44,163.51 131.37,163.58 131.37,165.48 131.76,165.86 135.69,165.86
GND on BOTTOM (solid shape): 137.12,121.02 137.12,119.86 136.97,119.7 136.04,119.7 135.39,120.36 135.39,121.25 135.59,121.46 136.69,121.46
GND on BOTTOM (solid shape): 72.13,15.3 72.13,13.78 71.88,13.53 68.95,13.53 68.76,13.72 68.76,15.3 68.89,15.43 72,15.43
GND on BOTTOM (solid shape): 76.19,23.56 76.19,19.81 76.07,19.69 74.86,19.69 74.8,19.75 74.8,23.56 74.92,23.69 76.07,23.69
GND on BOTTOM (solid shape): 50.55,31.9 50.55,30.68 50.37,30.51 47.02,30.51 46.89,30.63 46.89,31.9 47,32 47.99,32 47.99,32 50.45,32
GND on BOTTOM (solid shape): 58.16,34.04 58.16,32.83 58.41,32.58 58.41,31.81 58.35,31.75 57.02,31.75 56.95,31.81 56.95,33.91 57.21,34.16 58.03,34.16
GND on BOTTOM (solid shape): 58.41,41.21 58.41,37.47 57.91,36.96 55.15,36.96 54.67,37.44 54.67,40.89 55.24,41.47 58.16,41.47
GND on BOTTOM (solid shape): 72,63.88 72,56.77 71.67,56.44 69.37,56.44 68.76,57.05 68.76,63.75 69.4,64.39 71.49,64.39
GND on BOTTOM (solid shape): 23.89,41.44 23.89,41.24 23.76,41.11 18.68,41.11 18.56,40.99 18.3,40.99 18.18,41.11 18.18,42.51 18.37,42.7 22.63,42.7
GND on BOTTOM (solid shape): 72.13,15.3 72.13,13.78 71.88,13.53 68.95,13.53 68.68,13.8 68.68,15.39 68.71,15.43 68.89,15.43 68.89,15.43 72,15.43
GND on BOTTOM (solid shape): 105.4,114.41 105.4,112.14 104.9,111.63 102.55,111.63 102.1,112.08 102.1,113.47 103.26,114.64 105.18,114.64
GND on BOTTOM (solid shape): 137.79,147.13 137.79,145.67 136.65,144.53 133.47,144.53 133.09,144.91 133.09,147.13 133.15,147.19 137.72,147.19
GND on BOTTOM (solid shape): 138.8,161.29 138.8,158.56 138.55,158.31 137.14,158.31 137.09,158.36 137.09,161.48 138.61,161.48
GND on BOTTOM (solid shape): 178.17,34.23 178.17,30.86 178.05,30.73 176.9,30.73 176.78,30.86 176.78,34.29 176.9,34.42 177.98,34.42
GND on BOTTOM (solid shape): 193.1,30.86 194.87,30.86 195.64,30.1 195.64,25.84 192.46,25.84 192.08,26.23 192.08,30.73 191.83,30.99 190.56,30.99 190.56,31.31 192.65,31.31
GND on BOTTOM (solid shape): 43.65,164.42 45.65,164.42 45.65,160.32 37.93,160.32 37.72,160.32 37.51,160.33 31.65,160.33 31.65,169.65 43.65,169.65
GND on BOTTOM (solid shape): 53.8,32.66 53.83,32.64 53.83,31.29 53.46,30.92 52.51,30.92 52.38,31.05 52.38,32.51 52.52,32.65 52.62,32.65 52.63,32.66
GND on BOTTOM (solid shape): 131.7,135.83 132.58,135.83 133.15,135.25 135.43,135.25 135.47,135.21 135.47,134.31 135.33,134.18 131.44,134.18 130.87,134.75 130.87,135.51 131.18,135.83 131.7,135.83
GND on BOTTOM (solid shape): 38.9,29.25 39.13,29.25 39.43,28.96 39.43,26.14 38.89,25.6 37.45,25.6 37.32,25.73 37.32,28.96 37.47,29.11 37.8,29.11 37.95,29.26 38.89,29.26
GND on BOTTOM (solid shape): 37.33,51.31 36.95,50.93 36.95,50.48 36.89,50.42 35.93,50.42 35.81,50.55 35.81,50.86 35.93,50.99 36.57,50.99 37.08,51.5 37.08,52.51 37.14,52.58 37.33,52.58
GND on BOTTOM (solid shape): 134,116.22 134,114 133.64,113.64 131.89,113.64 131.49,114.04 131.49,116.72 131.78,117.01 133.22,117.01
GND on BOTTOM (solid shape): 155.76,31.24 155.76,30.35 155.5,30.1 151.95,30.1 151.57,29.72 150.93,29.72 150.87,29.78 150.87,30.61 151.06,30.8 152.58,30.8 152.71,30.92 152.71,31.56 152.77,31.62 155.38,31.62
GND on BOTTOM (solid shape): 173.98,25.65 173.98,25.46 174.43,25.02 175.76,25.02 175.76,24.57 175.63,24.45 173.98,24.45 173.73,24.19 170.55,24.19 170.11,24.64 169.35,24.64 169.22,24.76 169.22,25.59 169.6,25.97 173.67,25.97
GND on BOTTOM (solid shape): 102.43,84.65 102.42,84.62 102.42,84.48 102.48,84.36 102.48,84.09 102.35,83.96 99.05,83.96 98.99,84.02 98.99,84.59 99.09,84.7 99.51,84.7 99.59,84.78 102.3,84.78
GND on BOTTOM (solid shape): 124.52,131.89 124.52,129.98 123.93,129.98 123.92,130 123.92,130.2 123.5,130.62 121.34,130.62 121.34,131.51 122.55,131.51 122.74,131.7 122.74,132.52 122.8,132.59 123.82,132.59
GND on BOTTOM (solid shape): 60.21,70.36 60.21,70.35 60.59,70.35 60.64,70.31 60.64,66.4 59.33,65.09 59.33,64.23 57.65,62.55 55.62,62.55 55.17,62.99 55.17,66.42 55.56,66.8 58.6,66.8 59.33,67.53 59.33,70.18 59.5,70.36
GND on BOTTOM (solid shape): 71.18,22.12 71.18,21.62 71.38,21.41 71.94,21.41 72.02,21.34 72.02,20.83 71.05,19.86 71.05,19.18 70.99,19.11 70.35,19.11 70.29,19.18 70.29,20.76 70.16,20.89 70.16,22.02 70.41,22.28 71.02,22.28
GND on BOTTOM (solid shape): 130.33,140.78 130.33,140.51 130.22,140.4 129.99,140.4 129.53,139.94 129.53,138.9 129.98,138.45 129.98,135.84 130.15,135.67 130.15,135.42 130.01,135.27 129.81,135.27 129.22,135.87 129.22,136.99 128.87,137.35 128.87,138.71 129.23,139.08 129.23,140.36 129.77,140.9 130.22,140.9
GND on BOTTOM (solid shape): 33.98,55.56 34.79,55.56 35.55,54.8 35.55,54.67 35.87,54.36 37.08,54.36 37.14,54.29 37.14,54.17 37.08,54.1 35.11,54.1 35.05,54.17 33.65,54.17 33.39,54.42 31.49,54.42 31.43,54.48 31.43,55.88 31.68,56.13 33.4,56.13
GND on BOTTOM (solid shape): 143.45,49.4 150.18,49.4 152.29,47.29 152.29,47.22 152.97,46.54 153.04,46.54 153.12,46.46 154.65,46.46 155.35,45.77 155.35,44.71 154.71,44.07 100.7,44.07 100.59,44.18 85.33,44.18 85.21,44.07 75.25,44.07 74.84,44.47 74.84,53.25 78.29,56.69 86.52,56.69 95.22,65.39 127.46,65.39
GND on BOTTOM (solid shape): 186.13,8.97 185.78,8.62 185.78,7.23 185.79,7.22 185.79,6.93 185.75,6.89 183.87,6.89 183.87,6.89 183.68,6.89 183.65,6.92 183.65,7.57 183.75,7.67 184.76,7.67 184.86,7.77 184.86,8.22 185.56,8.92 185.56,10.44 186.13,10.44
GND on BOTTOM (solid shape): 100.51,167.32 100.51,166.81 100.39,166.69 98.1,166.69 97.95,166.54 97.95,165.77 97.95,165.77 97.65,165.77 97.65,166.45 97.46,166.64 97.07,166.64 96.95,166.52 96.95,165.8 96.95,165.8 96.64,165.8 96.64,165.8 96.64,166.69 96.51,166.81 96.51,167.26 96.77,167.51 100.32,167.51
GND on BOTTOM (solid shape): 132.26,130.87 132.26,128.14 132.2,128.08 131.5,128.08 131.38,127.96 131.38,126.7 131.21,126.53 131.21,125.52 131.5,125.22 131.5,124.08 131.12,123.7 131.12,122.62 131.06,122.55 130.93,122.55 130.87,122.62 130.87,123.7 130.42,124.14 130.42,128.52 129.91,129.03 129.91,130.87 130.1,131.06 132.07,131.06
GND on BOTTOM (solid shape): 195.43,13.85 195.43,8.87 194.39,7.83 189.64,7.83 189.49,7.98 189.49,8.12 188.95,8.67 188.95,9.22 189.04,9.31 189.77,9.31 189.77,9.26 190.33,9.26 190.33,9.31 190.66,9.31 190.66,9.26 191.22,9.26 191.22,9.31 192.44,9.31 192.97,9.84 193.22,9.84 193.22,11.24 193.03,11.24 193.03,14.6 193.23,14.8 194.48,14.8
GND on BOTTOM (solid shape): 94.78,104.88 95.5,104.88 95.69,104.68 95.69,103.94 95.61,103.86 94.84,103.86 94.4,103.43 94.4,102.29 94.56,102.14 94.86,102.14 95.07,101.93 95.07,101.35 95.03,101.31 94.42,101.31 94.34,101.39 94.34,101.56 94.11,101.79 93.4,101.79 93.09,102.1 93.1,104.64 93.1,104.91 93.47,105.28 94.37,105.28
GND on BOTTOM (solid shape): 122.1,127.63 123.2,126.54 124.4,126.54 124.72,126.23 124.72,124.74 124.83,124.63 124.83,123.44 124.77,123.38 123.88,123.38 123.88,124.27 123.75,124.4 122.62,124.4 122.55,124.46 122.55,124.59 122.55,124.59 122.55,126.3 122.42,126.43 122.11,126.43 121.83,126.71 121.83,127.02 121.67,127.18 121.28,127.18 121.28,128.59 122.1,128.59
GND on BOTTOM (solid shape): 35.85,42.16 35.85,41.43 35.29,40.87 34.25,40.87 34.17,40.79 34.17,39.45 34.65,38.96 34.65,37.64 34.16,37.15 34.16,36.32 34.16,36.31 34.16,35.94 34.31,35.79 35.64,35.79 35.74,35.69 35.74,34.72 35.62,34.59 34.14,34.59 34.07,34.67 34.07,35.64 33.9,35.8 33.9,37.21 33.43,37.68 33.43,40.23 33.05,40.61 32.95,40.61 32.86,40.7 31.93,40.7 31.68,40.96 31.68,42.61 31.81,42.73 32.18,42.73 32.31,42.74 32.38,42.8 32.38,44.51 32.44,44.58 33.43,44.58
GND on BOTTOM (solid shape): 67.75,34.35 67.75,33.02 67.68,32.96 64,32.96 63.43,32.38 63.43,28.77 63.87,28.32 65.72,28.32 65.97,28.07 66.8,28.07 66.8,27.56 66.73,27.5 61.89,27.5 61.21,28.18 61.21,32.22 61.17,32.61 60.8,32.73 60.76,32.77 59.87,32.77 59.87,34.16 60.25,34.54 67.56,34.54
GND on BOTTOM (solid shape): 140.31,107.15 141.33,107.15 141.33,105.82 138.38,105.82 138.14,106.43 137.89,105.82 134.21,105.82 134.11,105.92 134.11,107.25 134.13,107.28 140.18,107.28
GND on BOTTOM (solid shape): 47.17,42.62 47.17,41.27 46.92,41.02 46.18,41.02 45.85,40.69 45.85,39.65 45.96,39.54 45.98,39.52 46.01,39.49 46.08,39.42 46.51,39.42 46.69,39.24 46.69,37.72 46.49,37.52 45.96,37.52 45.85,37.41 45.85,36.12 46.73,35.24 47.53,35.24 47.62,35.15 47.62,34.1 47.56,34.04 46.36,34.04 45.57,34.82 45.57,37.39 45.57,37.39 45.57,37.47 45.12,37.92 45.12,40.44 44.71,40.84 43.95,40.84 43.77,40.67 43.52,40.67 43.31,40.87 43.31,42.39 43.46,42.54 43.8,42.54 43.85,42.54 44.05,42.75 44.05,44.22 44.18,44.35 45.45,44.35
GND on BOTTOM (solid shape): 117.28,142.19 117.27,142.16 117.33,141.86 117.63,141.8 117.66,141.81 117.79,141.69 118.6,141.69 118.96,141.33 118.96,138.05 118.85,137.94 118.31,137.94 117.82,138.43 117.11,138.43 116.96,138.29 116.96,137.74 116.81,137.59 115.21,137.59 115.08,137.46 114.65,137.46 114.42,137.69 114.42,138.52 114.69,138.79 114.71,138.81 114.71,139.55 114.56,139.7 114.03,139.7 113.96,139.77 113.96,142.96 113.99,143 116.48,143
GND on BOTTOM (solid shape): 163.88,111.46 163.88,111 164.01,110.87 168.2,110.87 168.4,110.68 168.4,110.05 168.59,109.86 168.59,108.85 168.59,107.86 168.97,107.48 170,107.48 170.12,107.35 170.12,104.92 169.98,104.78 169.98,104.26 169.77,104.05 168.67,104.05 168.59,103.97 168.59,102.36 168.59,102.36 168.59,101.69 168.9,101.38 169.84,101.38 170.07,101.15 170.07,98.34 169.88,98.14 164.04,98.14 162.14,100.04 162.14,101.67 163.6,103.12 166.11,103.12 166.17,103.19 166.17,105.34 166.17,108.52 166.3,108.65 166.3,109.85 166.24,109.92 163.38,109.92 163.2,110.1 163.2,111.51 163.26,111.58 163.76,111.58
GND on BOTTOM (solid shape): 21.58,72.2 21.58,71.56 19.08,69.06 18.42,69.27 18.92,68.79 18.92,62.61 15.55,59.25 13.65,59.25 13.39,59.5 13.39,59.94 13.58,60.13 15.55,60.13 15.93,60.52 15.93,72.01 16.38,72.45 21.33,72.45
GND on BOTTOM (solid shape): 59.89,49.54 62.07,49.54 62.7,50.17 64.3,50.17 64.52,49.95 64.52,48.45 64.61,48.36 64.61,46.37 64.57,46.32 64.08,46.32 63.85,46.55 63.85,46.74 63.4,47.19 62.64,47.19 62.57,47.27 62.57,47.51 62.56,47.52 62.56,47.58 62.49,47.65 61.6,47.65 61.59,47.64 59.2,47.64 59.19,47.62 58.88,47.62 58.82,47.57 54.66,47.57 54.47,47.75 54.47,48.35 62.45,48.35 62.45,48.31 62.46,48.26 62.47,48.22 62.49,48.18 62.52,48.15 62.56,48.12 62.6,48.1 62.64,48.08 62.68,48.07 62.7,48.07 63.21,48.07 63.23,48.07 63.28,48.08 63.32,48.1 63.36,48.12 63.39,48.15 63.42,48.18 63.44,48.22 63.46,48.26 63.47,48.31 63.47,48.35 63.46,48.39 63.44,48.44 63.42,48.47 63.39,48.51 63.36,48.54 63.32,48.56 63.28,48.57 63.23,48.58 63.21,48.58 62.7,48.58 62.68,48.58 62.64,48.57 62.6,48.56 62.56,48.54 62.52,48.51 62.49,48.47 62.47,48.44 62.46,48.39 62.45,48.35 54.47,48.35 54.47,50.52 54.87,50.92 58.51,50.92
GND on BOTTOM (solid shape): 118.4,126.13 119.1,126.13 119.2,126.03 119.2,123.79 118.41,123 114.99,123 114.22,123.77 111.31,123.77 111.31,123.44 110.17,122.3 110.17,118.24 109.98,118.05 108.91,118.05 108.39,118.57 106.16,118.57 105.59,119.13 105.59,124.9 105.71,125.03 110.33,125.03 110.33,124.98 110.34,124.94 110.35,124.9 110.38,124.86 110.41,124.82 110.44,124.79 110.48,124.77 110.52,124.76 110.56,124.75 110.59,124.75 111.09,124.75 111.12,124.75 111.16,124.76 111.2,124.77 111.24,124.79 111.27,124.82 111.3,124.86 111.33,124.9 111.34,124.94 111.35,124.98 111.35,125.03 111.34,125.07 111.33,125.11 111.3,125.15 111.27,125.18 111.24,125.21 111.2,125.23 111.16,125.25 111.12,125.26 111.09,125.26 110.59,125.26 110.56,125.26 110.52,125.25 110.48,125.23 110.44,125.21 110.41,125.18 110.38,125.15 110.35,125.11 110.34,125.07 110.33,125.03 105.71,125.03 105.88,125.19 110.23,125.19 110.46,125.41 110.46,126.05 110.54,126.14 111.15,126.14 111.23,126.06 111.23,125.76 111.27,125.72 111.27,125.7 111.28,125.7 111.32,125.67 112.35,125.67 112.37,125.69 114.83,125.69 115.69,126.56 117.98,126.56
GND on BOTTOM (solid shape): 72.02,44.07 72.14,43.94 72.14,40.84 71.94,40.64 71,40.64 70.8,40.44 70.2,40.44 70.1,40.54 70.1,40.83 70.03,40.89 66.48,40.89 66.16,41.21 64.89,41.21 64.64,41.47 60.45,41.47 60.31,41.6 69.98,41.6 69.98,41.56 69.99,41.52 70.01,41.47 70.03,41.44 70.06,41.4 70.09,41.37 70.13,41.35 70.17,41.34 70.22,41.33 70.24,41.33 70.75,41.33 70.77,41.33 70.81,41.34 70.85,41.35 70.89,41.37 70.93,41.4 70.95,41.44 70.98,41.47 70.99,41.52 71,41.56 71,41.6 70.99,41.65 70.98,41.69 70.95,41.73 70.93,41.76 70.89,41.79 70.85,41.81 70.81,41.83 70.77,41.84 70.75,41.84 70.24,41.84 70.22,41.84 70.17,41.83 70.13,41.81 70.09,41.79 70.06,41.76 70.03,41.73 70.01,41.69 69.99,41.65 69.98,41.6 60.31,41.6 60.19,41.72 60.19,43.23 60.24,43.28 60.99,43.28 61.15,43.12 63.25,43.12 63.41,43.28 64.98,43.28 65.61,43.9 67.09,43.9 67.34,43.65 67.34,42.87 67.44,42.77 70.07,42.77 70.1,42.8 70.1,43.43 70.73,44.07 71.92,44.07
GND on BOTTOM (solid shape): 165.58,14.57 172.32,16.33 172.52,9.37 170.9,7.75 97.7,7.75 97.13,7.18 89.51,7.18 89.26,7.44 89.26,9.14 88.96,9.44 88.96,9.72 89.26,10.02 89.26,12.52 89.89,13.15 159.87,13.15 160.71,12.31 160.71,12.27 163.28,12.27
GND on BOTTOM (solid shape): 10.21,55.12 22.66,55.12 24.19,53.59 24.19,48.45 22.41,46.67 17.71,46.67 16.76,45.72 12.7,45.72 12.32,46.1 12.32,47.82 11.7,48.56 10.86,48.07 7.7,48.07 7.13,47.84 6.82,47.1 6.65,47.02 4.35,47.02 4.12,47.35 4.12,52.12 3.76,53.01 2.87,53.37 0.5,53.37 0.33,53.45 0.25,53.62 0.25,54.51 1.11,55.37 2.9,55.37 4.31,56.77 8.57,56.77
GND on BOTTOM (solid shape): outline of 800 points within 187.87,90.03 196.91,114.74
GND on BOTTOM (solid shape): outline of 951 points within 4.12,0.25 204.3,181.72
GND on BOTTOM (solid shape): outline of 1138 points within 0.25,70.62 92.91,162.01
GND on IN1 (solid shape): 50.53,31.92 50.53,25.04 50.4,24.92 47.12,24.92 46.84,25.2 46.84,31.79 47.03,31.98 50.46,31.98
GND on IN1 (solid shape): 47.17,43.12 47.17,41.53 46.28,40.64 44.55,40.64 44.23,40.84 43.91,40.64 43.36,40.64 42.98,41.02 42.98,43.69 43.36,44.07 46.22,44.07
GND on IN1 (solid shape): 35.87,43.05 35.87,41.4 34.85,40.39 32.79,40.39 32.78,40.42 32.44,40.68 32.1,40.42 32.09,40.39 31.93,40.39 31.48,40.84 31.45,40.89 31.43,40.94 31.43,43.02 31.47,43.16 31.46,43.31 31.45,43.34 31.68,43.56 35.36,43.56
GND on IN1 (solid shape): outline of 1017 points within 0.25,0.25 204.3,181.72
GND on IN1 (solid shape): outline of 1118 points within 0.25,71.04 92.91,162.01
GND on IN2 (solid shape): 168.56,101.37 168.56,99.16 168.2,98.81 165.28,98.81 164.86,99.23 164.86,99.82 164.55,100.13 164.55,100.37 164.67,100.49 164.67,101.12 165.11,101.56 168.37,101.56
GND on IN2 (solid shape): 47.17,43.18 47.17,41.53 46.28,40.64 44.55,40.64 44.23,40.84 43.91,40.64 43.36,40.64 42.98,41.02 42.98,43.69 43.36,44.07 46.28,44.07
GND on IN2 (solid shape): 35.87,43.05 35.87,41.4 34.85,40.39 32.79,40.39 32.78,40.42 32.44,40.68 32.1,40.42 32.09,40.39 31.93,40.39 31.48,40.84 31.45,40.89 31.43,40.94 31.43,43.02 31.47,43.16 31.46,43.31 31.45,43.34 31.68,43.56 35.36,43.56
GND on IN2 (solid shape): outline of 1094 points within 0.25,0.25 204.3,181.72
GND on IN2 (solid shape): outline of 1115 points within 0.25,71.04 92.91,162.01
GND on VCC: outline of 276 points within 0.26,0.42 204.29,181.71 ; 1 cut-out
GND on GND: outline of 205 points within 0.25,0.25 204.3,181.72 ; 1 cut-out
GNDA on TOP (solid shape): outline of 140 points within 179.06,23.11 192.65,30.1
GNDA on TOP (solid shape): outline of 189 points within 179.95,7.56 193.16,22.1
GNDA on BOTTOM (solid shape): 192.46,14.16 192.46,9.91 192.24,9.7 189,9.7 188.91,9.78 188.91,11.26 189.17,11.52 189.94,11.52 190.96,12.54 190.97,12.54 191.13,12.7 191.13,14.22 191.32,14.41 192.21,14.41
GNDA on IN1 (solid shape): outline of 594 points within 179.06,7.56 193.16,30.1
GNDA on IN2 (solid shape): outline of 546 points within 179.06,7.56 193.16,29.4
GNDA on VCC: 186.25,7.56 186.18,7.64 186.18,8.49 186.49,8.81 186.49,10.56 184.52,12.52 184.52,13.57 184.67,13.72 185.33,13.72 185.35,13.7 185.35,12.81 185.78,12.38 186.67,12.38 187.3,11.75 189.81,11.75 190.56,12.49 190.56,13.99 190.19,14.35 188.73,14.35 187.78,15.3 186.32,15.3 186.18,15.45 186.18,18.62 185.94,18.86 181.24,18.86 179.95,20.14 179.95,20.91 179.06,21.8 179.06,25.7 181.87,28.51 183.14,28.51 184.03,29.4 188.86,29.4 189.56,30.1 192.38,30.1 192.65,29.83 192.65,25.7 193.16,25.19 193.16,15.32 192.65,14.81 192.65,10.11 192.26,9.72 187.81,9.72 187.45,9.35 187.45,7.7 187.3,7.56
GNDA on GND: 186.25,7.56 186.18,7.64 186.18,8.49 186.49,8.81 186.49,10.56 184.52,12.52 184.52,13.57 184.67,13.72 185.33,13.72 185.35,13.7 185.35,12.81 185.78,12.38 186.67,12.38 187.3,11.75 189.81,11.75 190.56,12.49 190.56,13.99 190.19,14.35 188.73,14.35 187.91,15.18 186.19,15.18 186.18,15.19 186.18,18.62 185.94,18.86 181.24,18.86 179.95,20.14 179.95,20.91 179.06,21.8 179.06,25.7 181.87,28.51 183.14,28.51 184.03,29.4 188.95,29.4 193.16,25.19 193.16,15.32 192.65,14.81 192.65,10.11 192.26,9.72 187.81,9.72 187.45,9.35 187.45,7.7 187.3,7.56
VCCK_12 on TOP (solid shape): 31.78,62.13 32.46,62.13 32.65,61.94 32.65,61.63 32.34,61.63 32.21,61.75 31.09,61.75 30.86,61.98 30.86,62.13 30.94,62.21 31.7,62.21
VCCSA_B+ on TOP (solid shape): 120.75,128.5 120.75,127.23 120.95,127.04 121.57,127.04 121.69,126.93 121.69,126.69 121.56,126.56 119.76,126.56 119.61,126.72 119.61,128.61 119.65,128.65 120.61,128.65
VCCSA_B+ on BOTTOM (solid shape): 119.12,130.75 119.12,129.22 119.75,128.59 120.44,128.59 121.06,127.97 121.06,127.15 121.06,127.15 121.17,127.05 121.57,127.05 121.69,126.93 121.69,126.72 121.54,126.57 121.43,126.57 121.06,126.2 121.06,123.72 121.04,123.7 120.48,123.7 120.48,124.28 120.35,124.41 119.77,124.41 119.36,124.82 119.36,127.9 117.66,129.6 117.66,130.05 118.23,130.05 118.23,130.56 117.66,130.56 117.66,130.94 117.79,131.06 118.8,131.06
VDD10 on TOP (solid shape): 56.08,176.88 56.08,175.1 55.96,174.97 52.15,174.97 52.12,175 51.82,175 51.68,175.13 51.68,176.29 52.61,177.21 55.75,177.21
VDD10 on BOTTOM (solid shape): 53.14,170.93 53.14,168.72 52.99,168.57 52.92,168.57 52.91,168.56 51.51,168.56 51.45,168.62 51.45,170.27 51.13,170.59 47.81,170.59 47.68,170.46 47.68,167.64 47.84,167.47 47.84,166.02 47.68,165.86 47.05,165.86 46.92,165.99 46.92,166.75 46.79,166.88 46.65,166.88 46.56,166.97 46.56,168.79 46.51,168.84 46.51,168.94 46.2,169.25 46.2,171.17 47.65,172.62 51.45,172.62
VDD10 on IN2 (solid shape): 56.46,176.97 56.46,175.25 54.17,172.96 54.17,169.47 53.68,168.98 52.08,168.98 51.85,169.21 51.85,171.68 53.07,171.68 53.08,171.63 53.09,171.58 53.11,171.53 53.14,171.48 53.17,171.44 53.21,171.4 53.25,171.37 53.3,171.35 53.35,171.34 53.4,171.33 53.46,171.33 53.51,171.34 53.56,171.35 53.61,171.37 53.65,171.4 53.69,171.44 53.73,171.48 53.75,171.53 53.77,171.58 53.78,171.63 53.79,171.68 53.78,171.74 53.77,171.79 53.75,171.84 53.73,171.88 53.69,171.93 53.65,171.96 53.61,171.99 53.56,172.02 53.51,172.03 53.46,172.04 53.4,172.04 53.35,172.03 53.3,172.02 53.25,171.99 53.21,171.96 53.17,171.93 53.14,171.88 53.11,171.84 53.09,171.79 53.08,171.74 53.07,171.68 51.85,171.68 51.85,176.42 52.8,177.36 56.08,177.36
VDD_1.2V on TOP (solid shape): 57.91,19.75 57.91,18.99 57.84,18.92 57.46,18.92 56.89,18.35 55.94,18.35 55.68,18.1 55.68,16.95 54.79,16.95 54.79,18.8 54.92,18.92 56.57,18.92 57.46,19.81 57.84,19.81
VDD_DAC_33 on TOP (solid shape): 24.84,67.44 26.65,65.64 26.65,65.54 26.57,65.46 25.71,65.46 25.41,65.75 24.21,65.75 24.21,67.85 24.84,67.85
VDDREG on TOP (solid shape): 54.75,173.38 54.75,172.5 54.79,172.5 54.94,172.34 54.94,170.34 54.62,170.02 54.6,170.02 54.48,170.02 54.37,169.99 54.36,169.98 52.35,169.98 52.25,169.88 50.92,169.88 50.88,169.92 50.88,170.06 50.93,170.11 51.87,170.11 52.87,171.11 53.83,171.11 53.99,171.27 53.99,173.32 54.05,173.39 54.75,173.39
VIN_+VCCEOPIO on TOP (solid shape): 33.27,53.91 34.41,53.91 34.73,53.59 34.73,50.55 34.28,50.1 33.65,50.1 33.65,50.67 32.25,50.67 32.25,50.1 31.62,50.1 31.36,50.36 31.36,54.1 31.43,54.17 33.01,54.17
VIN_+VCCEOPIO on BOTTOM (solid shape): 33.08,54.04 34.54,54.04 35.24,53.34 37.08,53.34 37.14,53.28 37.14,53.15 37.08,53.09 35.74,53.09 34.79,52.13 31.55,52.13 31.36,52.32 31.36,54.04 31.43,54.1 33.01,54.1
3D3V_CAMERA_S0 on BOTTOM (solid shape): 95.43,164.08 95.12,163.77 94.29,163.77 94.16,163.89 94.16,164.15 94.42,164.4 94.86,164.4 95.14,164.68 95.14,166.33 95.18,166.37 95.43,166.37
3D3V_CAMERA_S0 on BOTTOM (solid shape): 97.08,158.11 98.35,158.11 98.56,157.91 98.56,157 98.38,156.82 96.28,156.82 96.2,156.91 95.33,156.91 95.33,157.52 94.67,158.18 94.67,159.26 94.54,159.38 94.67,159.51 95.69,159.51
3D3V_CAMERA_S0 on IN1 (solid shape): 95.37,164.15 95.37,163.89 94.67,163.19 94.67,160.21 95.62,159.26 95.62,158.5 95.5,158.37 94.99,158.37 93.59,159.77 93.59,163.7 94.23,164.34 95.18,164.34
3D3V_CARD_S0 on TOP (solid shape): 27.64,17.62 27.64,16.53 27.39,16.29 23.83,16.29 23.7,16.41 23.7,17.75 23.95,18 27.26,18
3D3V_CARD_S0 on BOTTOM (solid shape): 24.4,17.24 24.4,15.4 20.85,15.4 20.57,15.68 20.57,17.21 20.79,17.43 24.21,17.43
3D3V_CARD_S0 on BOTTOM (solid shape): 12.76,20.83 12.76,19.81 13.01,19.56 13.01,18.29 13.84,17.45 14.71,17.45 14.76,17.4 14.76,17.25 14.71,17.2 13.83,17.2 13.77,17.14 11.87,17.14 11.74,17.27 11.74,20.7 11.99,20.95 12.63,20.95
3D3V_CARD_S0 on IN1 (solid shape): 13.48,19.78 12.33,19.78 12.21,19.91 12.21,20.67 12.33,20.79 13.48,20.79
3D3V_CARD_S0 on IN1 (solid shape): 21.39,17.96 21.39,17.34 21.71,17.02 21.71,16.76 21.55,16.6 20.76,16.6 20.57,16.79 20.57,18.13 21.22,18.13
3D3V_LAN_S5 on TOP (solid shape): 58.31,173.7 58.31,171.6 58.03,171.32 57.14,171.32 56.76,171.7 56.76,172.21 56.54,172.43 55.51,172.43 55.45,172.5 55.45,173.7 55.77,174.02 57.99,174.02
3D3V_LAN_S5 on TOP (solid shape): 46.63,171.89 46.83,171.89 47.14,171.58 47.87,171.58 48.01,171.44 48.01,170.7 47.93,170.62 47.75,170.62 47.42,170.95 46.71,170.95 46.65,171.01 45.33,171.01 45.08,171.26 45.08,172.78 45.75,172.78
3D3V_LAN_S5 on TOP (solid shape): 48.88,167.29 48.88,167.25 48.88,166.61 48.88,166.58 48.89,166.54 48.89,166.43 48.98,166.33 48.98,165.38 48.86,165.25 48.7,165.16 48.61,165 48.19,164.58 48.19,163.64 48.13,163.58 44.63,163.58 44.51,163.7 44.51,164.85 44.7,165.04 46.62,165.04 46.96,165.39 46.97,165.39 47.08,165.5 48.03,165.5 48.5,165.97 48.5,166.49 48.53,166.55 48.54,166.61 48.54,167.25 48.53,167.28 48.6,167.35 48.82,167.35
3D3V_LAN_S5 on IN1 (solid shape): outline of 402 points within 43.49,164.21 57.46,175.11
+BIF_VDDC on TOP (solid shape): 156.39,140.97 156.39,140.4 156.34,140.33 156.31,140.26 156.3,140.25 155.25,139.19 154.81,139.19 154.55,139.45 152.77,139.45 152.2,140.02 153.22,141.03 153.54,140.72 153.92,140.72 154.49,141.29 154.49,141.99 154.87,142.37 155,142.37
+BIF_VDDC on IN2 (solid shape): outline of 428 points within 154.58,136.14 161.09,142.48
+PCIE_VDDC on TOP (solid shape): 158.43,144.27 158.43,143.46 158.64,143.12 159.03,143.16 159.44,142.75 160.29,142.75 160.56,142.62 160.83,142.75 161.09,142.75 161.35,142.49 161.35,142.24 161.26,142.15 161.07,142.15 160.77,142.45 160.68,142.37 160.58,142.37 160.33,142.11 160.33,142.02 160.19,141.88 160.33,141.74 160.33,141.73 160.84,141.22 160.84,140.33 160.46,139.95 160.46,139.57 157.66,136.78 157.41,136.78 156.9,137.29 156.9,137.67 159.06,139.83 159.13,139.83 159.19,139.77 159.26,139.83 159.31,139.83 159.57,140.08 159.57,140.14 159.73,140.31 159.57,140.47 159.57,140.72 157.28,143 157.28,143.51 156.42,144.38 156.41,144.39 156.32,144.57 156.13,144.67 156.12,144.68 156.06,144.73 155.45,144.73 155,144.27 154.85,144.27 154.17,144.96 154.13,144.96 153.8,144.64 153.74,144.64 153.42,144.96 153.42,145.24 154.62,146.43 156.27,146.43
+PCIE_VDDC on IN1 (solid shape): outline of 649 points within 152.96,136.78 161.35,145.67
+SPLL_VDDC on TOP (solid shape): 174.81,133.6 175.06,133.6 175.09,133.57 175.13,133.6 176.11,133.6 176.34,133.52 176.56,133.59 176.58,133.6 176.65,133.6 176.65,133.54 176.64,133.53 176.64,133.15 176.98,132.98 177.06,132.96 177.09,132.88 177.09,132.66 177.05,132.61 177.09,132.56 177.09,132.46 177.48,132.08 177.57,132.08 177.62,132.03 177.67,132.08 177.73,132.08 177.98,131.83 177.98,131.44 177.73,131.19 177.09,131.19 176.12,132.17 176.09,132.26 176.16,132.34 176.28,132.95 175.7,132.7 175.7,132.69 175.65,132.64 175.57,132.71 174.84,132.71 174.05,133.51 174.05,133.6 174.3,133.86 174.55,133.86
+VGA_CORE on TOP (solid shape): 162.5,124.25 162.5,124.24 162.65,124.07 162.88,124.09 162.95,124.1 163.01,124.06 163.12,123.97 163.27,123.92 163.28,123.92 163.38,123.82 163.63,123.82 164.01,123.44 164.01,120.9 163.63,120.52 161.47,120.52 161.22,120.78 161.22,124.33 161.46,124.57 161.49,124.56 161.65,124.54 161.81,124.59 162.16,124.59
+VGA_CORE on TOP (solid shape): outline of 260 points within 166.43,94.61 188.91,127.63
+VGA_CORE on BOTTOM (solid shape): 188.63,113.56 188.63,110.52 189.86,109.28 189.86,94.78 189.44,94.36 185.95,94.36 185.63,94.68 182.17,94.68 182.14,94.65 181.54,95.25 181.54,98.87 181.92,99.25 183.25,99.25 183.32,99.31 183.32,100.08 183.25,100.14 181.92,100.14 181.54,100.52 181.54,107.31 182.11,107.89 183.32,107.89 183.32,108.78 182.11,108.78 181.54,109.35 181.54,110.11 183.44,112.01 183.44,114.05 183.65,114.25 187.94,114.25
+VGA_CORE on BOTTOM (solid shape): 168.33,122.94 168.33,122.43 169.22,121.54 169.22,121.28 167.58,119.64 167.26,119.64 167.12,119.78 167.12,120.37 167.32,120.56 167.32,121.03 167.06,121.28 167.06,121.37 167.09,121.42 167.15,121.41 167.73,121.64 167.21,121.99 167.11,122 167.06,122.08 167.06,122.94 167.57,123.44 167.82,123.44
+VGA_CORE on IN1 (solid shape): outline of 5311 points within 154.87,94.74 189.79,139.95
+VGA_CORE on IN2 (solid shape): 183.27,113.37 183.62,113.08 183.97,113.37 183.98,113.41 186.37,113.41 186.87,112.9 186.87,98.44 186.75,98.31 186.75,95.25 186.18,94.68 184.15,94.68 184.09,94.61 182.17,94.61 181.54,95.25 181.54,112.78 182.17,113.41 183.27,113.41
+VGA_CORE on IN2 (solid shape): outline of 2212 points within 151.57,122.43 168.59,137.54
+VGA_CORE on VCC: 182.92,94.61 182.05,95.48 182.05,112.75 179.11,115.7 163.48,115.7 154.23,124.95 154.23,132.1 156.9,134.77 156.9,135.64 161.2,135.64 161.71,136.14 162.19,136.14 163.52,134.75 165.43,134.75 166.39,133.79 168.8,133.79 169.6,132.99 169.6,131.72 170.32,131 171.08,131 174.25,127.84 189.41,127.84 189.41,95.74 188.29,94.61
ADJ_2.5V on BOTTOM (solid shape): 67.75,28.77 67.43,28.45 66.16,28.45 65.65,28.96 64.13,28.96 64,29.08 64,29.46 64.13,29.59 65.97,29.59 66.22,29.84 67.75,29.84
AUD_SPK_L+ on TOP (solid shape): 93.54,6.1 93.52,6.07 91.31,6.07 91.11,6.27 91.11,6.98 91.22,7.09 93.54,7.09
AUD_SPK_L+ on TOP (solid shape): 184.36,11.35 184.36,10.85 184.26,10.74 183.65,10.74 183.5,10.59 182.94,10.59 182.73,10.79 182.73,11.25 183.19,11.71 184,11.71
AUD_SPK_L+_C on TOP (solid shape): 90.88,6.93 90.88,6.19 90.76,6.06 89.66,6.06 89.37,6.35 88.04,6.35 87.15,5.46 85.97,5.46 85.78,5.65 85.78,6.86 86.48,7.56 90.26,7.56
AUD_SPK_L+_C on BOTTOM (solid shape): 87.12,5.91 87.12,5.27 86.86,5.02 85.4,5.02 85.4,6.03 86.99,6.03
